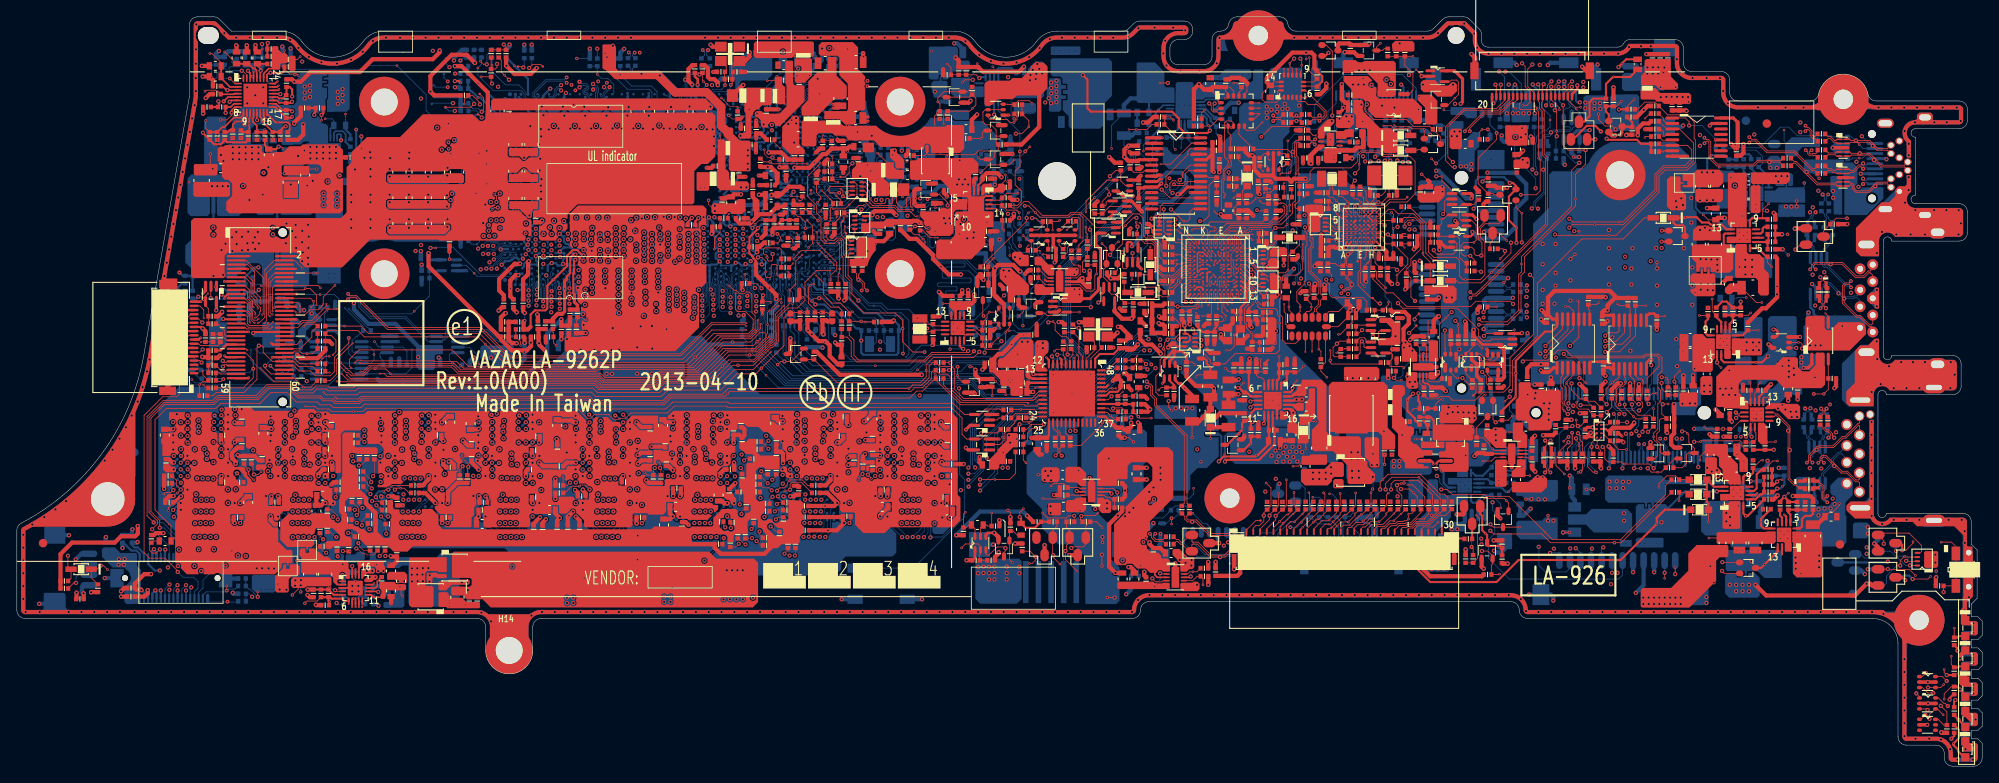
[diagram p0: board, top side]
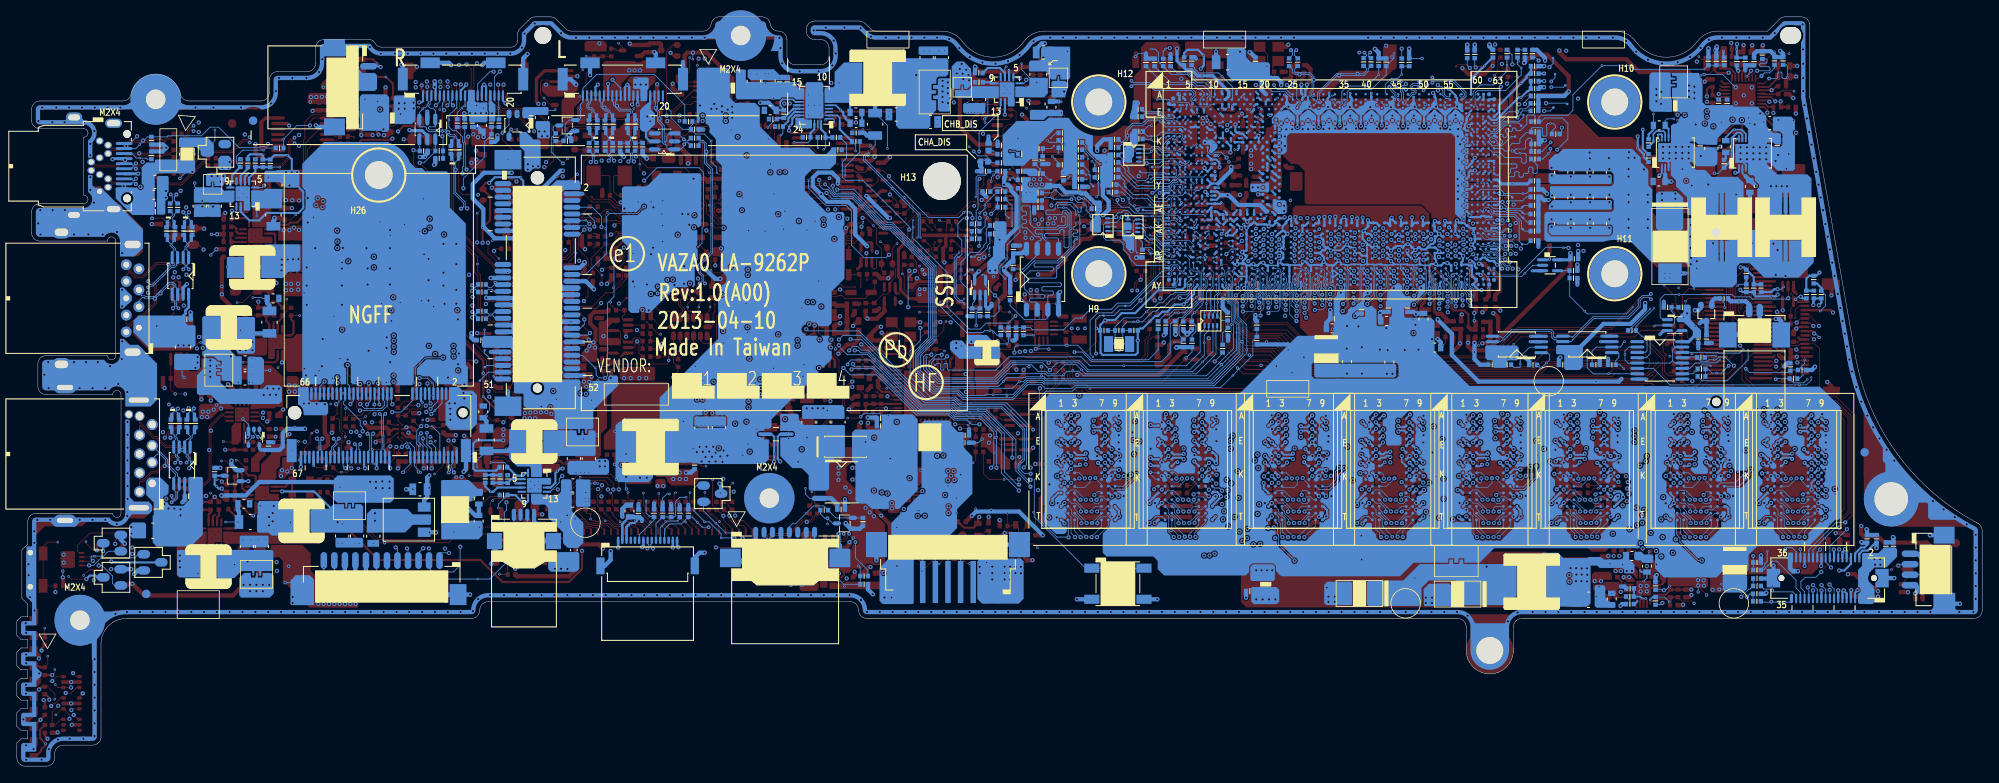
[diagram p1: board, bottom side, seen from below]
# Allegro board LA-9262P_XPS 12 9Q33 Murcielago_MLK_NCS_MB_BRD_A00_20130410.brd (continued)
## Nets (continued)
GND: C265.2 C276.2 C277.2 C278.2 C279.2 C280.1 C281.1 C283.2 C285.2 C293.2 C303.2 C352.2 C355.2 C612.2 C617.2 C655.2 C656.2 C712.2 C713.2 C715.2 C716.2 C719.2 C720.2 C721.2 C722.2 C962.2 C963.2 C965.2 C966.2 C968.2 C969.2 C970.2 C974.2 C976.2 C977.2 C978.2 C979.2 C1059.2 C1078.2 C1098.1 C1099.1 C1100.1 C1101.1 C1102.1 C1109.2 C1110.2 C1116.1 C1117.2 C1118.2 C1122.2 C1123.2 C1124.2 C1125.2 C1134.2 C1135.2 C1136.2 C1137.2 C1138.2 C1139.2 C1140.2 C1142.2 C1143.2 C1145.2 C1146.1 C1148.2 C1149.2 C1152.2 C1153.2 C1158.2 C1159.2 C1160.2 C1161.2 C1162.2 C1163.2 C1172.2 C1173.2 C1174.2 C1175.2 C1176.2 C1177.2 C1178.2 C1179.2 C1180.2 C1181.2 C1182.2 C1183.2 C1184.2 C1185.2 C1186.2 C1187.2 C1188.2 C1189.2 C1190.2 C1191.2 C1192.2 C1193.2 C1194.2 C1195.2 C1196.2 C1197.2 C1199.2 C1200.2 C1202.2 C1203.2 C1204.2 C1205.2 C1209.2 C1212.2 C1213.2 C1214.2 C1215.2 C1219.2 C1225.2 C1227.2 C1228.2 C1230.2 C1231.2 C1237.2 C1240.2 C1241.2 C1242.2 C1243.2 C1246.2 C1248.2 C1254.2 C1256.2 C1257.2 C1259.2 C1260.2 C1261.2 C1262.2 C1278.2 C1279.2 C1280.1 C1281.2 C1282.2 C1283.2 C1284.2 C1285.2 C1286.2 C1287.2 C1288.2 C1289.2 C1292.2 C1294.2 C1295.2 C1296.2 C1297.2 C1298.2 C1299.2 C1300.2 CA1.2 CA2.2 CA3.2 CA4.2 CA5.2 CA6.2 CA7.2 CA9.2 CA11.2 CA12.2 CA14.2 CA15.2 CA16.2 CA17.2 CA21.2 CA22.2 CC160.2 CC161.2 CC162.2 CC163.2 CC164.2 CC165.2 CC233.2 CC234.2 CC238.2 CC239.2 CC240.2 CD1.2 CD2.2 CD3.1 CD4.1 CD5.2 CD14.2 CD15.2 CD16.2 CD17.2 CD18.2 CD19.2 CD20.2 CD21.2 CD22.2 CD23.2 CD24.2 CD25.2 CD26.1 CD27.1 CD28.2 CD37.2 CD38.2 CD39.2 CD40.2 CD41.2 CD42.2 CD43.2 CD44.2 CD45.2 CD46.2 CD47.1 CD48.1 CD49.2 CD58.2 CD59.2 CD60.2 CD61.2 CD62.2 CD63.2 CD64.2 CD65.2 CD66.2 CD67.2 CD68.2 CD69.2 CD70.1 CD71.1 CD72.2 CD81.2 CD82.2 CD83.2 CD84.2 CD85.2 CD86.2 CD87.2 CD88.2 CD90.2 CD93.2 CD94.2 CD95.2 CD96.2 CD97.2 CD98.2 CD101.2 CD102.2 CD103.2 CD104.2 CD105.2 CD106.2 CD107.2 CD110.2 CD111.2 CD112.2 CD113.2 CD114.2 CD115.2 CD116.2 CD117.2 CD118.2 CD119.2 CD120.2 CD121.2 CD122.2 CD123.2 CD124.2 CD125.2 CD126.2 CH1.2 CH2.2 CH3.2 CH4.1 CH5.2 CH6.2 CH23.2 CH24.2 CH39.2 CH40.2 CH41.2 CH47.2 CH82.2 CH83.2 CH84.2 CH85.2 CH95.2 CH1202.2 CH1203.2 CH1204.2 CH1205.2 CH1206.2 CH1207.2 CH1208.2 CH1209.2 CH1210.2 CH1211.2 CH1212.2 CH1213.2 CH1214.2 CH1215.2 CH1216.2 CH1217.2 CH1218.2 CH1220.2 CH1222.2 CH1223.2 CH1224.2 CH1225.2 CH1226.2 CH1227.2 CH1228.2 CH1229.2 CH1230.2 CH1231.2 CH1232.2 CH1233.2 CH1234.2 CH1235.2 CH1236.2 CH1239.2 CH1240.2 CH1241.2 CLRP1.1 CLRP2.2 CLRP3.2 CV1.2 CV2.2 CV13.2 CV14.2 CV15.2 DE1.1 DE2.1 H1.1(TP-1) H3.1(TP-1) H5.1(TP-1) H6.1(TP-1) H8.1(TP-1) H9.1(TP-1) H10.1(TP-1) H11.1(TP-1) H12.1(TP-1) H14.1(TP-1) H26.1(TP-1) JAPS.5 JAPS.7 JAPS.9 JAPS.11 JAPS.19 JAPS.20 JBATT1.1 JBATT1.2 JBATT1.10 JBATT1.11 JBL1.5 JBL1.6 JBT1.2 JBT1.3 JBT1.4 JDCIN1.6 JDCIN1.7 JDEBUG.8 JDEBUG.10 JDEBUG.13 JDEBUG.14 JFAN1.1 JFAN1.5 JFAN1.6 JIOL1.9 JIOL1.10 JIOL1.11 JIOL1.12 JIOL1.13 JIOL1.16 JIOL1.21 JIOL1.22 JIOL1.30 JIOL1.36 JIOL1.37 JIOL1.38 JKB1.30 JKB1.31 JKB1.32 JLVDS1.4 JLVDS1.7 JLVDS1.11 JLVDS1.12 JLVDS1.21 JLVDS1.22 JLVDS1.23 JLVDS1.24 JLVDS2.1 JLVDS2.15 JLVDS2.16 JLVDS2.20 JLVDS2.21 JLVDS2.22 JLVDS2.23 JLVDS2.24 JMDP1.1 JMDP1.7 JMDP1.8 JMDP1.13 JMDP1.14 JMDP1.19 JMDP1.21 JMDP1.22 JMDP1.23 JMDP1.24 JNFC1.1 JNFC1.7 JNFC1.14 JNFC1.16 JNFC1.17 JNGFF1.1 JNGFF1.7 JNGFF1.18 JNGFF1.25 JNGFF1.31 JNGFF1.37 JNGFF1.43 JNGFF1.49 JNGFF1.55 JNGFF1.61 JNGFF1.67 JNGFF1.68 JNGFF1.69 JSATA1.4 JSATA1.9 JSATA1.15 JSATA1.18 JSATA1.21 JSATA1.26 JSATA1.27 JSATA1.29 JSATA1.34 JSATA1.35 JSATA1.37 JSATA1.40 JSATA1.43 JSATA1.50 JSATA1.53 JSATA1.54 JSNRDG.20 JSNRDG.21 JSNRDG.22 JTP1.4 JTP1.9 JTP1.10 JUSB1.4 JUSB1.7 JUSB1.11 JUSB1.12 JUSB1.13 JUSB1.14 JUSB2.4 JUSB2.7 JUSB2.10 JUSB2.11 JUSB2.12 JUSB2.13 JXDP.1 JXDP.2 JXDP.7 JXDP.8 JXDP.13 JXDP.14 JXDP.19 JXDP.20 JXDP.25 JXDP.26 JXDP.31 JXDP.32 JXDP.37 JXDP.38 JXDP.49 JXDP.50 JXDP.59 L44.1 LED1.1 LED2.1 LED3.1 LED4.1 LED5.1 MC94.2 MC102.1 MC103.2 MC118.1 MC284.2 MC654.2 MC1133.2 MC1141.2 MC1151.2 MC1210.2 MC1267.2 MC1268.2 MC1269.2 MC1270.2 MC1271.2 MC1272.2 MC1273.2 MC1274.2 MC1275.2 MC1276.2 MC1277.2 MC1297.2 MD1.3 MD2.3 MD50.2 MD74.7 MD82.7 MD90.2 PC101.2 PC102.2 PC103.2 PC104.2 PC105.2 PC106.2 PC107.2 PC108.2 PC109.2 PC112.2 PC113.2 PC116.2 PC202.2 PC203.2 PC204.2 PC205.2 PC206.2 PC210.1 PC212.2 PC213.2 PC214.2 PC216.2 PC217.2 PC219.2 PC220.1 PC221.2 PC223.2 PC224.2 PC225.2 PC228.2 PC302.2 PC303.2 PC305.2 PC306.2 PC307.2 PC308.2 PC310.2 PC311.2 PC313.2 PC314.2 PC315.2 PC316.2 PC318.2 PC319.2 PC321.2 PC322.2 PC323.2 PC324.2 PC326.2 PC327.2 PC329.2 PC330.2 PC331.2 PC332.2 PC334.2 PC335.2 PC337.2 PC338.2 PC339.2 PC340.2 PC341.2 PC342.2 PC403.2 PC405.2 PC407.2 PC408.2 PC410.2 PC411.2 PC413.2 PC414.2 PC415.2 PC416.2 PC501.2 PC502.2 PC504.2 PC505.2 PC506.2 PC507.2 PC508.2 PC509.2 PC510.2 PC511.2 PC512.2 PC513.2 PC602.2 PC603.2 PC604.2 PC606.2 PC607.2 PC608.2 PC609.2 PC610.2 PC611.2 PC612.2 PC613.2 PC615.2 PC616.2 PC701.2 PC702.2 PC703.2 PC704.2 PC705.2 PC707.1 PC709.2 PC710.2 PC712.2 PC713.2 PC715.1 PC717.1 PC718.2 PC720.1 PC721.2 PC722.2 PC723.2 PC801.2 PC802.2 PC803.2 PC804.2 PC805.2 PC806.2 PC807.2 PC808.2 PC809.2 PC810.2 PC811.2 PC812.2 PC813.2 PC814.2 PC815.2 PC816.2 PC817.2 PC818.2 PC819.2 PC820.2 PC821.2 PC822.2 PC823.2 PC824.2 PC825.2 PC826.2 PC827.2 PC828.2 PC829.2 PC830.2 PD103.1 PD104.1 PL104.1 PQ102.3 PQ103.1 PQ103.4 PQ104.3 PQ105.1 PQ105.4 PQ106.3 PQ202.3 PQ204.3 PQ205.1 PQ205.2 PQ205.3 PQ300.3 PQ602.1 PQ602.2 PQ602.3 PR106.1 PR108.2 PR115.2 PR118.1 PR121.1 PR124.2 PR125.1 PR213.2 PR225.1 PR226.2 PR301.2 PR307.2 PR317.2 PR327.2 PR337.2 PR408.2 PR420.2 PR508.1 PR610.2 PR709.1 PR710.1 PR711.1 PR712.1 PR713.1 PR714.1 PR721.2 PU201.14 PU201.21 PU301.6 PU301.15 PU301.16 PU301.17 PU302.6 PU302.15 PU302.16 PU302.17 PU303.6 PU303.15 PU303.16 PU303.17 PU304.6 PU304.15 PU304.16 PU304.17 PU305.6 PU305.15 PU305.16 PU305.17 PU306.1 PU307.3 PU401.6 PU401.15 PU401.16 PU401.17 PU402.6 PU402.15 PU402.16 PU402.17 PU501.10 PU501.11 PU501.12 PU501.13 PU501.14 PU501.19 PU501.23 PU501.24 PU501.25 PU501.29 PU601.1 PU601.3 PU601.14 PU601.21 PU701.22 PU701.29 PU701.33 PU702.3 PU702.9 PU703.3 PU703.9 Q4.3 Q5.3 Q34.3 Q39.3 Q71.3 Q305.3 Q311.3 Q349.1 Q349.4 Q361.1 Q362.3 R225.1 R537.2 R540.2 R545.2 R607.1 R608.1 R819.1 R924.1 R928.2 R929.1 R941.1 R945.1 R974.2 R1026.2 R1027.2 R1032.1 R1034.1 R1088.2 R1099.1 R1100.1 R1117.2 R1118.2 R1139.2 R1140.2 R1141.2 R1142.2 R1160.2 R1161.2 R1162.2 R1164.2 R1169.2 R1187.2 R1197.2 R1203.2 R1206.1 R1207.2 R1217.1 R1228.2 R1250.2 R1253.2 R1287.2 R1310.2 R1325.1 R1338.2 R1376.2 R1388.2 R1394.2 R1395.1 RA11.1 RA12.1 RA13.1 RC44.1 RC52.2 RC54.2 RC55.2 RC58.2 RC60.2 RC81.2 RC100.2 RC138.2 RC153.2 RC154.2 RC155.2 RC156.2 RC158.1 RC160.2 RC161.2 RD1.2 RD2.2 RD3.1 RD4.1 RD5.2 RD6.2 RD7.2 RD8.2 RD9.1 RD11.2 RD12.2 RD15.2 RD16.2 RD21.2 RD22.2 RD23.2 RD24.2 RD79.2 RD80.2 RD81.2 RD82.2 RD83.2 RD84.2 RD85.2 RD86.2 RH32.2 RH34.1 RH53.1 RH76.2 RH77.2 RH78.2 RH79.2 RH123.1 RH151.1 RH158.1 RH159.1 RH163.2 RH171.2 RH183.1 RH186.1 RH272.2 RH300.1 RH314.1 RH315.1 RH316.1 RH337.2 RH394.2 RH401.2 RH423.2 RH435.2 RH442.2 RH443.2 RP21.7 RP21.8 RP22.8 RV3.2 RV4.2 RV9.2 RV10.2 SW1.2 SW1.4 SW2.3 SW2.4 U34.G2 U34.J8 U34.J9 U34.J10 U34.N13 U48.4 U635.3 U636.A7 U636.B1 U636.E7 U636.F5 U636.H2 U636.H3 U637.7 U637.10 U637.11 U638.8 U638.9 U638.10 U638.11 U638.12 U638.13 U652.1 U652.2 U652.3 U652.4 U652.8 U652.9 U652.11 U652.18 U652.25 U653.5 U653.10 U653.12 U653.13 U653.16 U663.8 U664.11 U664.15 U671.7 U672.3 U673.3 U675.3 U676.3 U677.7 U679.B1 U682.3 U687.3 U688.2 U689.3 U690.3 U691.3 U697.3 U698.3 U699.3 U708.3 U709.3 U710.3 U712.3 U713.3 U714.3 U714.17 U716.11 U716.15 U717.11 U717.15 U718.11 U718.15 U719.11 U719.15 U721.2 U722.5 U722.9 UA1.44 UA1.49 UA2.3 UA3.3 UC1.3 UCPU1.A11 UCPU1.A14 UCPU1.A18 UCPU1.A24 UCPU1.A28 UCPU1.A32 UCPU1.A36 UCPU1.A40 UCPU1.A44 UCPU1.A48 UCPU1.A52 UCPU1.A56 UCPU1.AA1 UCPU1.AA58 UCPU1.AB7 UCPU1.AB10 UCPU1.AB20 UCPU1.AB22 UCPU1.AC61 UCPU1.AD3 UCPU1.AD21 UCPU1.AD63 UCPU1.AE5 UCPU1.AE10 UCPU1.AE58 UCPU1.AF11 UCPU1.AF12 UCPU1.AF14 UCPU1.AF15 UCPU1.AF17 UCPU1.AF18 UCPU1.AG1 UCPU1.AG11 UCPU1.AG21 UCPU1.AG23 UCPU1.AG60 UCPU1.AG61 UCPU1.AG62 UCPU1.AG63 UCPU1.AH16 UCPU1.AH17 UCPU1.AH19 UCPU1.AH20 UCPU1.AH22 UCPU1.AH24 UCPU1.AH28 UCPU1.AH30 UCPU1.AH32 UCPU1.AH34 UCPU1.AH36 UCPU1.AH38 UCPU1.AH40 UCPU1.AH42 UCPU1.AH44 UCPU1.AH46 UCPU1.AH49 UCPU1.AH51 UCPU1.AH53 UCPU1.AH55 UCPU1.AH57 UCPU1.AJ13 UCPU1.AJ14 UCPU1.AJ23 UCPU1.AJ25 UCPU1.AJ27 UCPU1.AJ29 UCPU1.AJ35 UCPU1.AJ39 UCPU1.AJ41 UCPU1.AJ43 UCPU1.AJ45 UCPU1.AJ47 UCPU1.AJ50 UCPU1.AJ52 UCPU1.AJ54 UCPU1.AJ56 UCPU1.AJ58 UCPU1.AJ60 UCPU1.AJ63 UCPU1.AK3 UCPU1.AK23 UCPU1.AK52 UCPU1.AL10 UCPU1.AL13 UCPU1.AL17 UCPU1.AL20 UCPU1.AL22 UCPU1.AL23 UCPU1.AL26 UCPU1.AL29 UCPU1.AL31 UCPU1.AL33 UCPU1.AL36 UCPU1.AL39 UCPU1.AL40 UCPU1.AL45 UCPU1.AL46 UCPU1.AL51 UCPU1.AL52 UCPU1.AL54 UCPU1.AL57 UCPU1.AL60 UCPU1.AL61 UCPU1.AM1 UCPU1.AM17 UCPU1.AM23 UCPU1.AM31 UCPU1.AM52 UCPU1.AN7 UCPU1.AN17 UCPU1.AN23 UCPU1.AN31 UCPU1.AN32 UCPU1.AN35 UCPU1.AN36 UCPU1.AN39 UCPU1.AN40 UCPU1.AN42 UCPU1.AN43 UCPU1.AN45 UCPU1.AN46 UCPU1.AN48 UCPU1.AN49 UCPU1.AN51 UCPU1.AN52 UCPU1.AN60 UCPU1.AN63 UCPU1.AP3 UCPU1.AP10 UCPU1.AP17 UCPU1.AP20 UCPU1.AP22 UCPU1.AP23 UCPU1.AP26 UCPU1.AP29 UCPU1.AP31 UCPU1.AP38 UCPU1.AP39 UCPU1.AP48 UCPU1.AP52 UCPU1.AP54 UCPU1.AP57 UCPU1.AR5 UCPU1.AR11 UCPU1.AR15 UCPU1.AR17 UCPU1.AR23 UCPU1.AR31 UCPU1.AR33 UCPU1.AR39 UCPU1.AR43 UCPU1.AR49 UCPU1.AR52 UCPU1.AT13 UCPU1.AT35 UCPU1.AT37 UCPU1.AT40 UCPU1.AT42 UCPU1.AT43 UCPU1.AT46 UCPU1.AT49 UCPU1.AT61 UCPU1.AT62 UCPU1.AT63 UCPU1.AU1 UCPU1.AU16 UCPU1.AU18 UCPU1.AU20 UCPU1.AU22 UCPU1.AU24 UCPU1.AU26 UCPU1.AU28 UCPU1.AU30 UCPU1.AU33 UCPU1.AU51 UCPU1.AU53 UCPU1.AU55 UCPU1.AU57 UCPU1.AU59 UCPU1.AV8 UCPU1.AV14 UCPU1.AV16 UCPU1.AV20 UCPU1.AV24 UCPU1.AV28 UCPU1.AV33 UCPU1.AV34 UCPU1.AV36 UCPU1.AV39 UCPU1.AV41 UCPU1.AV43 UCPU1.AV46 UCPU1.AV49 UCPU1.AV51 UCPU1.AV55 UCPU1.AV59 UCPU1.AW4 UCPU1.AW16 UCPU1.AW24 UCPU1.AW33 UCPU1.AW35 UCPU1.AW37 UCPU1.AW40 UCPU1.AW42 UCPU1.AW44 UCPU1.AW47 UCPU1.AW50 UCPU1.AW51 UCPU1.AW59 UCPU1.AW60 UCPU1.AY4 UCPU1.AY6 UCPU1.AY11 UCPU1.AY16 UCPU1.AY18 UCPU1.AY22 UCPU1.AY24 UCPU1.AY26 UCPU1.AY30 UCPU1.AY33 UCPU1.AY51 UCPU1.AY53 UCPU1.AY57 UCPU1.AY59 UCPU1.B4 UCPU1.B20 UCPU1.B24 UCPU1.B26 UCPU1.B28 UCPU1.B32 UCPU1.B36 UCPU1.B40 UCPU1.B44 UCPU1.B48 UCPU1.B52 UCPU1.B56 UCPU1.B60 UCPU1.C11 UCPU1.C14 UCPU1.C18 UCPU1.C20 UCPU1.C25 UCPU1.C27 UCPU1.C38 UCPU1.C39 UCPU1.C57 UCPU1.D2 UCPU1.D5 UCPU1.D8 UCPU1.D12 UCPU1.D14 UCPU1.D18 UCPU1.D21 UCPU1.D23 UCPU1.D25 UCPU1.D26 UCPU1.D27 UCPU1.D29 UCPU1.D30 UCPU1.D31 UCPU1.D33 UCPU1.D34 UCPU1.D35 UCPU1.D37 UCPU1.D38 UCPU1.D39 UCPU1.D41 UCPU1.D42 UCPU1.D43 UCPU1.D45 UCPU1.D46 UCPU1.D47 UCPU1.D49 UCPU1.D50 UCPU1.D51 UCPU1.D53 UCPU1.D54 UCPU1.D55 UCPU1.D57 UCPU1.D59 UCPU1.D62 UCPU1.D63 UCPU1.E11 UCPU1.E17 UCPU1.F20 UCPU1.F26 UCPU1.F30 UCPU1.F34 UCPU1.F38 UCPU1.F42 UCPU1.F46 UCPU1.F50 UCPU1.F54 UCPU1.F58 UCPU1.F61 UCPU1.G3 UCPU1.G5 UCPU1.G6 UCPU1.G8 UCPU1.G18 UCPU1.G22 UCPU1.H13 UCPU1.H17 UCPU1.H57 UCPU1.J10 UCPU1.J22 UCPU1.J59 UCPU1.J63 UCPU1.K1 UCPU1.K12 UCPU1.L7 UCPU1.L13 UCPU1.L15 UCPU1.L17 UCPU1.L18 UCPU1.L20 UCPU1.L58 UCPU1.L61 UCPU1.M22 UCPU1.N3 UCPU1.N10 UCPU1.N21 UCPU1.P22 UCPU1.P59 UCPU1.P62 UCPU1.P63 UCPU1.R8 UCPU1.R10 UCPU1.R22 UCPU1.T1 UCPU1.T58 UCPU1.U9 UCPU1.U20 UCPU1.U22 UCPU1.U61 UCPU1.V3 UCPU1.V7 UCPU1.V10 UCPU1.V23 UCPU1.V58 UCPU1.W20 UCPU1.W22 UCPU1.Y10 UCPU1.Y59 UCPU1.Y63 UD1.A9 UD1.B1 UD1.B3 UD1.B9 UD1.D1 UD1.D3 UD1.D8 UD1.E1 UD1.E2 UD1.E7 UD1.E8 UD1.F9 UD1.G1 UD1.G8 UD1.G9 UD1.J2 UD1.J8 UD1.M1 UD1.M9 UD1.P1 UD1.P9 UD1.T1 UD1.T9 UD2.A9 UD2.B1 UD2.B3 UD2.B9 UD2.D1 UD2.D3 UD2.D8 UD2.E1 UD2.E2 UD2.E7 UD2.E8 UD2.F9 UD2.G1 UD2.G8 UD2.G9 UD2.J2 UD2.J8 UD2.M1 UD2.M9 UD2.P1 UD2.P9 UD2.T1 UD2.T9 UD3.3 UD3.4 UD4.A9 UD4.B1 UD4.B3 UD4.B9 UD4.D1 UD4.D3 UD4.D8 UD4.E1 UD4.E2 UD4.E7 UD4.E8 UD4.F9 UD4.G1 UD4.G8 UD4.G9 UD4.J2 UD4.J8 UD4.M1 UD4.M9 UD4.P1 UD4.P9 UD4.T1 UD4.T9 UD5.A9 UD5.B1 UD5.B3 UD5.B9 UD5.D1 UD5.D3 UD5.D8 UD5.E1 UD5.E2 UD5.E7 UD5.E8 UD5.F9 UD5.G1 UD5.G8 UD5.G9 UD5.J2 UD5.J8 UD5.M1 UD5.M9 UD5.P1 UD5.P9 UD5.T1 UD5.T9 UD6.A9 UD6.B1 UD6.B3 UD6.B9 UD6.D1 UD6.D3 UD6.D8 UD6.E1 UD6.E2 UD6.E7 UD6.E8 UD6.F9 UD6.G1 UD6.G8 UD6.G9 UD6.J2 UD6.J8 UD6.M1 UD6.M9 UD6.P1 UD6.P9 UD6.T1 UD6.T9 UD7.A9 UD7.B1 UD7.B3 UD7.B9 UD7.D1 UD7.D3 UD7.D8 UD7.E1 UD7.E2 UD7.E7 UD7.E8 UD7.F9 UD7.G1 UD7.G8 UD7.G9 UD7.J2 UD7.J8 UD7.M1 UD7.M9 UD7.P1 UD7.P9 UD7.T1 UD7.T9 UD8.3 UD8.4 UD9.A9 UD9.B1 UD9.B3 UD9.B9 UD9.D1 UD9.D3 UD9.D8 UD9.E1 UD9.E2 UD9.E7 UD9.E8 UD9.F9 UD9.G1 UD9.G8 UD9.G9 UD9.J2 UD9.J8 UD9.M1 UD9.M9 UD9.P1 UD9.P9 UD9.T1 UD9.T9 UD10.A9 UD10.B1 UD10.B3 UD10.B9 UD10.D1 UD10.D3 UD10.D8 UD10.E1 UD10.E2 UD10.E7 UD10.E8 UD10.F9 UD10.G1 UD10.G8 UD10.G9 UD10.J2 UD10.J8 UD10.M1 UD10.M9 UD10.P1 UD10.P9 UD10.T1 UD10.T9 UH5.3 US1.14 US1.17 US2.1 UV1.8 UV1.15 YA1.2 YA1.4 YH2.2 YH2.4
VCC: PC214.1 PR210.2 PU201.20
VCCSENSE: PU701.24 RC98.1
VCCSENSE_R: RC97.2 RC98.2 UCPU1.E63
VCCSTPG_MCP: RC150.2 UCPU1.B59
VDD_+1.2V: PC612.1 PR604.1 PR606.2 PU601.11
VIN: PC103.1 PC104.1 PC208.1 PD201.2 PL101.2 PQ201.1 PR120.2 PR122.1 PR123.2 PR208.1 PR209.1
VSSSENSE: PU701.23 RC99.2
VSSSENSE_R: RC99.1 RC100.1 UCPU1.E62
1.2_PGND: CA8.2 CA10.2 CA18.2 CA19.2 CA20.2 RA11.2 RA12.2 RA13.2 UA1.12
+1.5VS_SS/TR: PC408.1 PU401.9
+1.8VS_SS/TR: PC415.1 PU402.9
+3.3VDX_SSD_SS/TR: PC332.1 PU304.9
+3VALW_DSW_SS/TR: PC340.1 PU305.9
+3VDX_SS/TR: PC324.1 PU303.9
+5VDX_SS/TR: PC316.1 PU302.9
+EC_VCCA: C282.1 L43.2 U34.B11
+EDP_COM: RC36.1 UCPU1.D20
+INV_PWR_SRC: C612.1 JLVDS1.15 JLVDS1.16 Q70.1 Q70.2 Q70.5 Q70.6 R531.2 R541.1
+LCDVDD: C1143.1 C1145.1 C1231.1 JLVDS2.12 JLVDS2.13 R1322.2 U708.5
+LCDVDD_R: D105.1 Q71.2 R1161.1 U708.2
+PCH_VCCDSW: RH346.1 UCPU1.AG19 UCPU1.AG20
+RTC_VCCSUS: CH1207.1 RH341.2 UCPU1.AH11
+RTCBATT: JBT1.1 RTCR1.2
+RTCVCC: CH82.1 CH83.1 CH84.1 CH95.1 CLRP3.1 JIOL1.8 R1348.2 RH11.1 RH23.1 RH25.1 RH31.1 RH147.1 RTCD1.1 UCPU1.AG10
+V5A_SS/TR: PC308.1 PU301.9
+VCHGR: PC223.1 PC224.1 PC225.1 PD204.1 PQ206.1 PQ206.2 PQ206.3 PR216.1
+VREFCA: CD1.1 CD2.1 CD24.1 CD25.1 CD45.1 CD46.1 CD68.1 CD69.1 CD90.1 RD13.2 RD14.2 RD15.1 UD1.M8 UD2.M8 UD4.M8 UD5.M8 UD6.M8 UD7.M8 UD9.M8 UD10.M8
+VREFDQ_A: CD3.2 CD4.2 CD26.2 CD27.2 RD17.2 RD19.2 RD21.1 UD1.H1 UD2.H1 UD4.H1 UD5.H1
+VREFDQ_B: CD47.2 CD48.2 CD70.2 CD71.2 RD18.2 RD20.2 RD22.1 UD6.H1 UD7.H1 UD9.H1 UD10.H1
+VS_LPSS_SDIO: CH1227.1 RH350.1 RH354.1 RH434.1 UCPU1.T9 UCPU1.U8
/BATDRV: PR230.1 PU201.11
AC_PRESENT: RH12.1 RH137.2 U34.E5
AC_PRESENT_R: RH137.1 UCPU1.AJ8
ACCEL_INT1: D94.2 R1207.1 U637.5
ACCEL_INT2: R1088.1 U636.E4 U637.4
ACDET: PC216.1 PR208.2 PR213.1 PU201.6
ACDRV: PR206.2 PU201.4
ACIN: C1116.2 PR119.1 PR223.2 PR226.1 PU201.5 R924.2 U34.F5 U689.1
ACOFF: PQ202.2 RP22.1 U34.A9
AD_BID0: C283.1 R219.1 R225.2 U34.A12
ADP_I: PC220.2 PR116.2 PU201.7 U34.B12
ADPIN: JDCIN1.2 JDCIN1.3 PC101.1 PC102.1 PC109.1 PL101.1
ALL_SYS_PCH_PWROK_EC: R1292.1 U691.4
ALS_INT#: JLVDS2.9 R1115.1 R1116.1
ALS_INT#_EC: R1115.2 RP22.2 U34.E7
ALS_INT#_HUB: R1116.2 R1143.1 U636.E6
ALS_SMBCLK: JLVDS2.7 R983.2 R985.1
ALS_SMBDATA: JLVDS2.8 R984.2 R986.1
AOAC_THERMAL: R927.2 R928.1 U34.D7
APWROK_R: RH131.1 RH438.1 UCPU1.AB5
AUD_MUTE#: JIOL1.17 U34.N12
AUDIO_IRQ#: RH396.2 UCPU1.L4
AUDIO_PWREN: PD305.2 R1140.1 R1182.1 T279.1(TP-1) U664.3 U664.5 U717.5 UCPU1.P1
AUDIO_XTAL24_IN: CA17.1 UA1.2 YA1.3
AUDIO_XTAL24_OUT: CA16.1 UA1.3 YA1.1
B+: C613.1 MC1273.1 MC1274.1 MC1275.1 PC217.1 PC219.1 PC342.1 PJP401.1 PJP403.1 PJP701.1 PL203.1 PL302.1 PL304.1 PL306.1 PL308.1 PL310.1 PL501.1 PL601.1 PL703.1 PR216.4 PU306.2 Q70.4 Q361.4 R531.1 R535.1 R1381.1
B-RAMP: PR704.1 PR711.2 PU701.11
BATBTN#: C1122.1 D84.1 RP16.3 SW1.1 SW1.3 U34.G4
BATMAN_CLK: Q359.6 R1347.1 R1350.1 U714.7
BATMAN_DATA: Q359.3 R1346.1 R1351.1 U714.6
BATMAN_X1: C1295.1 U714.14 Y3.1
BATMAN_X2: C1296.1 U714.15 Y3.2
BATT+: PC105.1 PC106.1 PD204.2 PL103.1 PQ206.5 PQ206.6 PQ206.7 PQ206.8
BATT++: JBATT1.8 JBATT1.9 PC107.1 PC108.1 PL103.2
BATT_LED#_LV1: Q316.1 U34.B10
BATT_LED#_LV1_Q: Q316.6 Q354.2 RP14.8
BATT_LED#_LV2: Q316.4 U34.B9
BATT_LED#_LV2_Q: Q316.3 Q355.2 RP14.7
BATT_LED#_LV3: Q318.1 U34.K2
BATT_LED#_LV3_Q: Q318.6 Q356.2 RP14.6
BATT_LED#_LV4: Q318.4 U34.J2
BATT_LED#_LV4_Q: Q318.3 Q357.2 RP14.5
BATT_LED#_LV5: Q320.1 U34.N8
BATT_LED_COLOR_W: JIOL1.25 U34.A4
BATT_LED_CTRL#: JIOL1.23 U34.A3
BATT_LED_LV1: Q354.1 R910.2
BATT_LED_LV2: Q355.1 R911.2
BATT_LED_LV3: Q356.1 R912.2
BATT_LED_LV4: Q357.1 R913.2
BATT_LED_LV5: Q358.1 R916.2
BATT_PRS: JBATT1.5 PD104.2 PR112.1
BEEP#: JIOL1.15 U34.M8
BKOFF#: D72.3 D73.2 U34.E1
BOOT0: R819.2 R1092.1 U636.A6
BOOT_+1.2V: PR601.2 PU601.18
BST_+1.05VS: PR506.1 PU501.5
BT_CS_NOTICE: R1208.2 R1209.2 UCPU1.AP1
BT_PCMCLK: JNGFF1.8 U677.2
BT_PCMFR1: JNGFF1.10 U677.3
BT_PCMIN: JNGFF1.12 U677.5
BT_PCMOUT: JNGFF1.14 U677.4
BT_RADIO_DIS#: JNGFF1.46 RH188.1 UCPU1.R7
BTST: PR211.1 PU201.17
CAB_DET_SINK: JMDP1.4 RV8.2 RV9.1
CAPS_LED: JKB1.27 R943.2
CAPS_LED#: Q326.3 R990.1 U34.B3
CFG0: JXDP.9 UCPU1.AC60
CFG1: JXDP.11 UCPU1.AC62
CFG2: JXDP.15 UCPU1.AC63
CFG3: JXDP.17 R1198.2 T293.1(TP-1) UCPU1.AA63
CFG4: JXDP.27 RC81.1 UCPU1.AA60
CFG5: JXDP.29 UCPU1.Y62
CFG6: JXDP.33 UCPU1.Y61
CFG7: JXDP.35 UCPU1.Y60
CFG8: JXDP.10 UCPU1.V62
CFG9: JXDP.12 UCPU1.V61
CFG10: JXDP.16 UCPU1.V60
CFG11: JXDP.18 UCPU1.U60
CFG12: JXDP.28 UCPU1.T63
CFG13: JXDP.30 UCPU1.T62
CFG14: JXDP.34 UCPU1.T61
CFG15: JXDP.36 UCPU1.T60
CFG16: JXDP.6 UCPU1.AA62
CFG17: JXDP.4 UCPU1.AA61
CFG18: JXDP.24 UCPU1.U63
CFG19: JXDP.22 UCPU1.U62
CFG_RCOMP: RC153.1 UCPU1.V63
CHG_LGATE: PQ205.4 PU201.15
CHG_LX: PC218.2 PL203.2 PQ203.1 PQ203.2 PQ203.3 PQ205.5 PR220.2 PU201.19
CHG_UGATE: PQ203.4 PU201.18
CL_CK: R1212.2 UCPU1.AF2
CL_DAT: R1210.2 UCPU1.AD2
CL_RST#: R1200.2 UCPU1.AF4
CLK_LPC_DEBUG: JDEBUG.7 RH386.2
CLK_PCI_LPC: MR226.1 RH360.2 U34.N5
CLK_PCI_TPM: MR976.1 RH428.2 U652.21
CLK_PCIE2: JNGFF1.39 UCPU1.B42
CLK_PCIE2#: JNGFF1.41 UCPU1.C41
CLK_REQ2#: JNGFF1.45 Q346.3 RH410.1
CLK_SMB: JBATT1.7 PD103.2 PR109.1
CLKOUT_LPC0: RH360.1 RH428.1 UCPU1.AN15
CLKOUT_LPC1: RH386.1 UCPU1.AP15
CMSRC: PR203.2 PU201.3
COMP: PC714.2 PC724.2 PR726.1 PR727.2 PU701.26
CONSOLE_RX: JSNRDG.14 T261.1(TP-1) U636.D3
CONSOLE_TX: JSNRDG.15 T260.1(TP-1) U636.D2
CPU_B+: PC701.1 PC702.1 PC703.1 PC704.1 PC705.1 PC710.1 PC718.1 PJP701.2 PL703.2 PR717.1 PU702.5 PU703.5
CPU_EDP_HPD#: QC5.3 RC148.2 RC160.1 UCPU1.D6
CPU_PATH_EN: R1324.2 R1325.2 U697.2
CPU_PATH_EN_G: U663.2 U663.5 U663.12 U663.15 U697.4
CPU_XDP_TCK: RC52.1 RH446.1 T265.1(TP-1) UCPU1.E60
CPU_XDP_TDI: RC46.1 T268.1(TP-1) U663.11 UCPU1.F63
CPU_XDP_TDO: RC48.1 T269.1(TP-1) U663.6 UCPU1.F62
CPU_XDP_TMS: RC45.1 T266.1(TP-1) U663.14 UCPU1.E61
CPU_XDP_TRST#: RC54.1 RH370.2 T267.1(TP-1) U663.3 UCPU1.E59
CS_+1.2V: PR604.2 PU601.13
CSN1: PC708.1 PL701.3 PR707.2 PR708.2 PU701.18
CSN2: PC716.1 PL702.3 PR728.2 PR729.2 PU701.19
CSP1: PC708.2 PH702.1 PR702.1 PR707.1 PU701.17
CSP2: PC716.2 PH703.1 PR724.1 PR728.1 PR746.2 PU701.20
CSSN_1: PC211.2 PC212.1 PR201.2 PU201.1
CSSP_1: PC210.2 PC211.1 PR201.3 PU201.2
DAT_SMB: JBATT1.6 PD103.3 PR111.1
DC_TEST_A3_B3: UCPU1.A3 UCPU1.B3
DC_TEST_A61_B61: UCPU1.A61 UCPU1.B61
DC_TEST_AY2_AW2: UCPU1.AW2 UCPU1.AY2
DC_TEST_AY3_AW3: UCPU1.AW3 UCPU1.AY3
DC_TEST_AY61_AW61: UCPU1.AW61 UCPU1.AY61
DC_TEST_AY62_AW62: UCPU1.AW62 UCPU1.AY62
DC_TEST_B62_B63: UCPU1.B62 UCPU1.B63
DC_TEST_C1_C2: UCPU1.C1 UCPU1.C2
DCIN_GND: JDCIN1.4 JDCIN1.5 PL104.2
DDR3_DRAMRST#: CD5.1 CD28.1 CD49.1 CD72.1 RC75.2 RC162.2 UD1.T2 UD2.T2 UD4.T2 UD5.T2 UD6.T2 UD7.T2 UD9.T2 UD10.T2
DDR_A_BS0: RD67.1 UCPU1.AU35 UD1.M2 UD2.M2 UD4.M2 UD5.M2
DDR_A_BS1: RD71.1 UCPU1.AV35 UD1.N8 UD2.N8 UD4.N8 UD5.N8
DDR_A_BS2: RD69.1 UCPU1.AY41 UD1.M3 UD2.M3 UD4.M3 UD5.M3
DDR_A_CAS#: RD63.1 UCPU1.AU34 UD1.K3 UD2.K3 UD4.K3 UD5.K3
DDR_A_CKE0: RD57.1 UCPU1.AU43 UD1.K9 UD2.K9 UD4.K9 UD5.K9
DDR_A_CKE1: RD87.1 UCPU1.AW43 UD1.J9 UD2.J9 UD4.J9 UD5.J9
DDR_A_CS0#: RD61.1 UCPU1.AP33 UD1.L2 UD2.L2 UD4.L2 UD5.L2
DDR_A_CS1#: RD88.1 UCPU1.AR32 UD1.L1 UD2.L1 UD4.L1 UD5.L1
DDR_A_D0: UCPU1.AH63 UD1.F7
DDR_A_D1: UCPU1.AH62 UD1.H7
DDR_A_D2: UCPU1.AK63 UD1.F2
DDR_A_D3: UCPU1.AK62 UD1.H3
DDR_A_D4: UCPU1.AH61 UD1.H8
DDR_A_D5: UCPU1.AH60 UD1.F8
DDR_A_D6: UCPU1.AK61 UD1.E3
DDR_A_D7: UCPU1.AK60 UD1.G2
DDR_A_D8: UCPU1.AM63 UD1.A7
DDR_A_D9: UCPU1.AM62 UD1.B8
DDR_A_D10: UCPU1.AP63 UD1.A3
DDR_A_D11: UCPU1.AP62 UD1.A2
DDR_A_D12: UCPU1.AM61 UD1.C8
DDR_A_D13: UCPU1.AM60 UD1.D7
DDR_A_D14: UCPU1.AP61 UD1.C2
DDR_A_D15: UCPU1.AP60 UD1.C3
DDR_A_D16: UCPU1.AP58 UD2.F7
DDR_A_D17: UCPU1.AR58 UD2.H7
DDR_A_D18: UCPU1.AM57 UD2.E3
DDR_A_D19: UCPU1.AK57 UD2.H3
DDR_A_D20: UCPU1.AL58 UD2.H8
DDR_A_D21: UCPU1.AK58 UD2.F8
DDR_A_D22: UCPU1.AR57 UD2.F2
DDR_A_D23: UCPU1.AN57 UD2.G2
DDR_A_D24: UCPU1.AP55 UD2.A7
DDR_A_D25: UCPU1.AR55 UD2.B8
DDR_A_D26: UCPU1.AM54 UD2.C2
DDR_A_D27: UCPU1.AK54 UD2.C3
DDR_A_D28: UCPU1.AL55 UD2.C8
DDR_A_D29: UCPU1.AK55 UD2.D7
DDR_A_D30: UCPU1.AR54 UD2.A3
DDR_A_D31: UCPU1.AN54 UD2.A2
DDR_A_D32: UCPU1.AY58 UD4.F8
DDR_A_D33: UCPU1.AW58 UD4.H8
DDR_A_D34: UCPU1.AY56 UD4.F2
DDR_A_D35: UCPU1.AW56 UD4.H3
DDR_A_D36: UCPU1.AV58 UD4.H7
DDR_A_D37: UCPU1.AU58 UD4.F7
DDR_A_D38: UCPU1.AV56 UD4.G2
DDR_A_D39: UCPU1.AU56 UD4.E3
DDR_A_D40: UCPU1.AY54 UD4.B8
DDR_A_D41: UCPU1.AW54 UD4.A7
DDR_A_D42: UCPU1.AY52 UD4.A2
DDR_A_D43: UCPU1.AW52 UD4.A3
DDR_A_D44: UCPU1.AV54 UD4.D7
DDR_A_D45: UCPU1.AU54 UD4.C8
DDR_A_D46: UCPU1.AV52 UD4.C2
DDR_A_D47: UCPU1.AU52 UD4.C3
DDR_A_D48: UCPU1.AK40 UD5.G2
DDR_A_D49: UCPU1.AK42 UD5.H3
DDR_A_D50: UCPU1.AM43 UD5.H7
DDR_A_D51: UCPU1.AM45 UD5.F8
DDR_A_D52: UCPU1.AK45 UD5.H8
DDR_A_D53: UCPU1.AK43 UD5.F7
DDR_A_D54: UCPU1.AM40 UD5.F2
DDR_A_D55: UCPU1.AM42 UD5.E3
DDR_A_D56: UCPU1.AM46 UD5.C2
DDR_A_D57: UCPU1.AK46 UD5.C3
DDR_A_D58: UCPU1.AM49 UD5.B8
DDR_A_D59: UCPU1.AK49 UD5.A7
DDR_A_D60: UCPU1.AM48 UD5.A3
DDR_A_D61: UCPU1.AK48 UD5.A2
DDR_A_D62: UCPU1.AM51 UD5.D7
DDR_A_D63: UCPU1.AK51 UD5.C8
DDR_A_DQS0: UCPU1.AJ62 UD1.F3
DDR_A_DQS1: UCPU1.AN61 UD1.C7
DDR_A_DQS2: UCPU1.AN58 UD2.F3
DDR_A_DQS3: UCPU1.AN55 UD2.C7
DDR_A_DQS4: UCPU1.AW57 UD4.F3
DDR_A_DQS5: UCPU1.AW53 UD4.C7
DDR_A_DQS6: UCPU1.AL42 UD5.F3
DDR_A_DQS7: UCPU1.AL49 UD5.C7
DDR_A_DQS#0: UCPU1.AJ61 UD1.G3
DDR_A_DQS#1: UCPU1.AN62 UD1.B7
DDR_A_DQS#2: UCPU1.AM58 UD2.G3
DDR_A_DQS#3: UCPU1.AM55 UD2.B7
DDR_A_DQS#4: UCPU1.AV57 UD4.G3
DDR_A_DQS#5: UCPU1.AV53 UD4.B7
DDR_A_DQS#6: UCPU1.AL43 UD5.G3
DDR_A_DQS#7: UCPU1.AL48 UD5.B7
DDR_A_MA0: RD29.1 UCPU1.AU36 UD1.N3 UD2.N3 UD4.N3 UD5.N3
DDR_A_MA1: RD37.1 UCPU1.AY37 UD1.P7 UD2.P7 UD4.P7 UD5.P7
DDR_A_MA2: RD35.1 UCPU1.AR38 UD1.P3 UD2.P3 UD4.P3 UD5.P3
DDR_A_MA3: RD41.1 UCPU1.AP36 UD1.N2 UD2.N2 UD4.N2 UD5.N2
DDR_A_MA4: RD33.1 UCPU1.AU39 UD1.P8 UD2.P8 UD4.P8 UD5.P8
DDR_A_MA5: RD47.1 UCPU1.AR36 UD1.P2 UD2.P2 UD4.P2 UD5.P2
DDR_A_MA6: RD39.1 UCPU1.AV40 UD1.R8 UD2.R8 UD4.R8 UD5.R8
DDR_A_MA7: RD51.1 UCPU1.AW39 UD1.R2 UD2.R2 UD4.R2 UD5.R2
DDR_A_MA8: RD53.1 UCPU1.AY39 UD1.T8 UD2.T8 UD4.T8 UD5.T8
DDR_A_MA9: RD43.1 UCPU1.AU40 UD1.R3 UD2.R3 UD4.R3 UD5.R3
DDR_A_MA10: RD31.1 UCPU1.AP35 UD1.L7 UD2.L7 UD4.L7 UD5.L7
DDR_A_MA11: RD45.1 UCPU1.AW41 UD1.R7 UD2.R7 UD4.R7 UD5.R7
DDR_A_MA12: RD25.1 UCPU1.AU41 UD1.N7 UD2.N7 UD4.N7 UD5.N7
DDR_A_MA13: RD55.1 UCPU1.AR35 UD1.T3 UD2.T3 UD4.T3 UD5.T3
DDR_A_MA14: RD49.1 UCPU1.AV42 UD1.T7 UD2.T7 UD4.T7 UD5.T7
DDR_A_MA15: RD27.1 UCPU1.AU42 UD1.M7 UD2.M7 UD4.M7 UD5.M7
DDR_A_RAS#: RD59.1 UCPU1.AY34 UD1.J3 UD2.J3 UD4.J3 UD5.J3
DDR_A_WE#: RD65.1 UCPU1.AW34 UD1.L3 UD2.L3 UD4.L3 UD5.L3
DDR_B_BS0: RD70.1 UCPU1.AL35 UD6.M2 UD7.M2 UD9.M2 UD10.M2
DDR_B_BS1: RD66.1 UCPU1.AM36 UD6.N8 UD7.N8 UD9.N8 UD10.N8
DDR_B_BS2: RD68.1 UCPU1.AU49 UD6.M3 UD7.M3 UD9.M3 UD10.M3
DDR_B_CAS#: RD62.1 UCPU1.AM33 UD6.K3 UD7.K3 UD9.K3 UD10.K3
DDR_B_CKE0: RD58.1 UCPU1.AY49 UD6.K9 UD7.K9 UD9.K9 UD10.K9
DDR_B_CKE1: RD89.1 UCPU1.AU50 UD6.J9 UD7.J9 UD9.J9 UD10.J9
DDR_B_CS0#: RD60.1 UCPU1.AM32 UD6.L2 UD7.L2 UD9.L2 UD10.L2
DDR_B_CS1#: RD90.1 UCPU1.AK32 UD6.L1 UD7.L1 UD9.L1 UD10.L1
DDR_B_D0: UCPU1.AY31 UD7.H7
DDR_B_D1: UCPU1.AW31 UD7.F7
DDR_B_D2: UCPU1.AY29 UD7.G2
DDR_B_D3: UCPU1.AW29 UD7.F2
DDR_B_D4: UCPU1.AV31 UD7.H8
DDR_B_D5: UCPU1.AU31 UD7.F8
DDR_B_D6: UCPU1.AV29 UD7.H3
DDR_B_D7: UCPU1.AU29 UD7.E3
DDR_B_D8: UCPU1.AY27 UD7.D7
DDR_B_D9: UCPU1.AW27 UD7.B8
DDR_B_D10: UCPU1.AY25 UD7.A2
DDR_B_D11: UCPU1.AW25 UD7.A3
DDR_B_D12: UCPU1.AV27 UD7.C3
DDR_B_D13: UCPU1.AU27 UD7.A7
DDR_B_D14: UCPU1.AV25 UD7.C2
DDR_B_D15: UCPU1.AU25 UD7.C8
DDR_B_D16: UCPU1.AM29 UD6.H8
DDR_B_D17: UCPU1.AK29 UD6.F8
DDR_B_D18: UCPU1.AL28 UD6.F2
DDR_B_D19: UCPU1.AK28 UD6.G2
DDR_B_D20: UCPU1.AR29 UD6.H7
DDR_B_D21: UCPU1.AN29 UD6.F7
DDR_B_D22: UCPU1.AR28 UD6.E3
DDR_B_D23: UCPU1.AP28 UD6.H3
DDR_B_D24: UCPU1.AN26 UD6.B8
DDR_B_D25: UCPU1.AR26 UD6.A7
DDR_B_D26: UCPU1.AR25 UD6.C3
DDR_B_D27: UCPU1.AP25 UD6.C2
DDR_B_D28: UCPU1.AK26 UD6.A2
DDR_B_D29: UCPU1.AM26 UD6.C8
DDR_B_D30: UCPU1.AK25 UD6.D7
DDR_B_D31: UCPU1.AL25 UD6.A3
DDR_B_D32: UCPU1.AY23 UD9.H8
DDR_B_D33: UCPU1.AW23 UD9.F7
DDR_B_D34: UCPU1.AY21 UD9.H3
DDR_B_D35: UCPU1.AW21 UD9.G2
DDR_B_D36: UCPU1.AV23 UD9.H7
DDR_B_D37: UCPU1.AU23 UD9.F8
DDR_B_D38: UCPU1.AV21 UD9.F2
DDR_B_D39: UCPU1.AU21 UD9.E3
DDR_B_D40: UCPU1.AY19 UD9.A7
DDR_B_D41: UCPU1.AW19 UD9.B8
DDR_B_D42: UCPU1.AY17 UD9.C2
DDR_B_D43: UCPU1.AW17 UD9.A3
DDR_B_D44: UCPU1.AV19 UD9.C8
DDR_B_D45: UCPU1.AU19 UD9.D7
DDR_B_D46: UCPU1.AV17 UD9.A2
DDR_B_D47: UCPU1.AU17 UD9.C3
DDR_B_D48: UCPU1.AR21 UD10.E3
DDR_B_D49: UCPU1.AR22 UD10.H7
DDR_B_D50: UCPU1.AL21 UD10.F2
DDR_B_D51: UCPU1.AM22 UD10.H8
DDR_B_D52: UCPU1.AN22 UD10.F7
DDR_B_D53: UCPU1.AP21 UD10.H3
DDR_B_D54: UCPU1.AK21 UD10.G2
DDR_B_D55: UCPU1.AK22 UD10.F8
DDR_B_D56: UCPU1.AN20 UD10.B8
DDR_B_D57: UCPU1.AR20 UD10.A7
DDR_B_D58: UCPU1.AK18 UD10.A2
DDR_B_D59: UCPU1.AL18 UD10.A3
DDR_B_D60: UCPU1.AK20 UD10.D7
DDR_B_D61: UCPU1.AM20 UD10.C8
DDR_B_D62: UCPU1.AR18 UD10.C3
DDR_B_D63: UCPU1.AP18 UD10.C2
DDR_B_DQS0: UCPU1.AV30 UD7.F3
DDR_B_DQS1: UCPU1.AW26 UD7.C7
DDR_B_DQS2: UCPU1.AM28 UD6.F3
DDR_B_DQS3: UCPU1.AM25 UD6.C7
DDR_B_DQS4: UCPU1.AV22 UD9.F3
DDR_B_DQS5: UCPU1.AW18 UD9.C7
DDR_B_DQS6: UCPU1.AM21 UD10.F3
DDR_B_DQS7: UCPU1.AM18 UD10.C7
DDR_B_DQS#0: UCPU1.AW30 UD7.G3
DDR_B_DQS#1: UCPU1.AV26 UD7.B7
DDR_B_DQS#2: UCPU1.AN28 UD6.G3
DDR_B_DQS#3: UCPU1.AN25 UD6.B7
DDR_B_DQS#4: UCPU1.AW22 UD9.G3
DDR_B_DQS#5: UCPU1.AV18 UD9.B7
DDR_B_DQS#6: UCPU1.AN21 UD10.G3
DDR_B_DQS#7: UCPU1.AN18 UD10.B7
DDR_B_MA0: RD30.1 UCPU1.AP40 UD6.N3 UD7.N3 UD9.N3 UD10.N3
DDR_B_MA1: RD44.1 UCPU1.AR40 UD6.P7 UD7.P7 UD9.P7 UD10.P7
DDR_B_MA2: RD40.1 UCPU1.AP42 UD6.P3 UD7.P3 UD9.P3 UD10.P3
DDR_B_MA3: RD50.1 UCPU1.AR42 UD6.N2 UD7.N2 UD9.N2 UD10.N2
DDR_B_MA4: RD38.1 UCPU1.AR45 UD6.P8 UD7.P8 UD9.P8 UD10.P8
DDR_B_MA5: RD56.1 UCPU1.AP45 UD6.P2 UD7.P2 UD9.P2 UD10.P2
DDR_B_MA6: RD36.1 UCPU1.AW46 UD6.R8 UD7.R8 UD9.R8 UD10.R8
DDR_B_MA7: RD48.1 UCPU1.AY46 UD6.R2 UD7.R2 UD9.R2 UD10.R2
DDR_B_MA8: RD42.1 UCPU1.AY47 UD6.T8 UD7.T8 UD9.T8 UD10.T8
DDR_B_MA9: RD52.1 UCPU1.AU46 UD6.R3 UD7.R3 UD9.R3 UD10.R3
DDR_B_MA10: RD32.1 UCPU1.AK36 UD6.L7 UD7.L7 UD9.L7 UD10.L7
DDR_B_MA11: RD54.1 UCPU1.AV47 UD6.R7 UD7.R7 UD9.R7 UD10.R7
DDR_B_MA12: RD26.1 UCPU1.AU47 UD6.N7 UD7.N7 UD9.N7 UD10.N7
DDR_B_MA13: RD46.1 UCPU1.AK33 UD6.T3 UD7.T3 UD9.T3 UD10.T3
DDR_B_MA14: RD34.1 UCPU1.AR46 UD6.T7 UD7.T7 UD9.T7 UD10.T7
DDR_B_MA15: RD28.1 UCPU1.AP46 UD6.M7 UD7.M7 UD9.M7 UD10.M7
DDR_B_RAS#: RD64.1 UCPU1.AM35 UD6.J3 UD7.J3 UD9.J3 UD10.J3
DDR_B_WE#: RD72.1 UCPU1.AK35 UD6.L3 UD7.L3 UD9.L3 UD10.L3
DDR_CHA_EN: RH440.1 RH442.1 UCPU1.J1
DDR_CHB_EN: RH441.1 RH443.1 UCPU1.K3
DDR_PG_CNTL: UC1.2 UCPU1.AV61
DDR_VREF: CA13.2 CA15.1 R1186.2 R1187.1 UA1.40
DELAY_VR_AND_ALL_SYS: R1290.1 R1295.1 U690.4 U691.1
DEVSLP0: JSATA1.44 R1366.2 UCPU1.P2
DH_+1.2V: PQ601.4 PU601.17
DISP_CEC: JMDP1.6 RV4.1
DISP_CLK_AUXP_CONN: JMDP1.16 RV3.1 UV1.4
DISP_DAT_AUXN_CONN: JMDP1.18 RV2.1 UV1.7
DISP_HPD_SINK: JMDP1.2 QV2.1 RV10.1
DISPOFF#: D72.1 JLVDS1.13 R540.1
DL_+1.2V: PQ602.4 PU601.15
DMIC_CLK: MD50.6 R1342.1 RA5.1 RA9.1
DMIC_CLK_CODEC: JIOL1.32 RA9.2
DMIC_CLK_DSP: RA5.2 UA1.47
DMIC_CLK_R: JLVDS2.6 MC1133.1 R1342.2
DMIC_DAT: JLVDS2.5 MC1210.1 MD50.4 RA6.1 RA10.1
DMIC_DAT_CODEC: JIOL1.34 RA10.2
DMIC_DAT_DSP: RA6.2 UA1.48
DP_CBL_DET: RV8.1 UV1.1
DROOP: PC714.1 PR727.1 PR744.1 PU701.25
DSP_PD#: R1262.1 U34.H5
DSP_PD#_R: R1261.2 R1262.2 UA1.17
DSWODVREN: RH147.2 RH151.2 UCPU1.AW7
EAPD#: JIOL1.19 R228.1
EAPD_R#: R228.2 R241.1 U34.D6
EC_BATT_PRS#: C286.2 PC114.1 PC229.2 PR112.2 PR113.1 U34.B1
EC_CRY2: MC654.1 R253.2 R607.2 U34.K1
EC_ENVDD: D93.3 D105.3 PD306.3 U34.A10
EC_ON: C1117.1 PR341.1 U34.G1
EC_ON_CTRL#: C1118.1 D84.2 D85.2 RP22.3 U34.G5
EC_PECI: R240.1 U34.H2
EC_RST#: C285.1 R221.1 U34.K13
EC_RUNTIME_SCI#: RH398.2 T283.1(TP-1) U34.N6 UCPU1.AM2
EC_RX: JDEBUG.12 U34.K9
EC_SHUTDOWN: R1286.1 U34.D5
EC_SLP_S0#: R1390.2 R1391.2 U34.M2
EC_SLP_S5#: D114.2 R250.2 R1386.1 U34.N9
EC_SMB_CK1: PR109.2 PU201.9 R229.1 U34.A8
EC_SMB_DA1: PR111.2 PU201.8 R230.1 U34.A7
EC_SMI#: RP19.4 T270.1(TP-1) U34.L13 UCPU1.V1
EC_TX: JDEBUG.11 U34.K10
EC_WAKE_SCI#: RH427.1 U34.N7
ECAGND: C282.2 C286.1 L44.2 PH101.2 U34.A11
EDP_AUXN: C1065.1 UCPU1.A45
EDP_AUXN_C: C1065.2 ML58.1 R1011.1 R1033.1
EDP_AUXN_CONN: JLVDS1.9 ML58.2 R1011.2
EDP_AUXP: C1064.1 UCPU1.B45
EDP_AUXP_C: C1064.2 ML58.4 R1010.1 R1034.2
EDP_AUXP_CONN: JLVDS1.8 ML58.3 R1010.2
EDP_BKLCTL: RC147.2 UCPU1.B8
EDP_DISP: RC146.1 RC158.2 UCPU1.A43
EDP_HPD: JLVDS1.10 QC5.1 RC138.1 RC148.1
EDP_TXN_P0: C1060.1 UCPU1.C45
EDP_TXN_P0_C: C1060.2 ML57.4 R1008.1
EDP_TXN_P0_CONN: JLVDS1.5 ML57.3 R1008.2
EDP_TXN_P1: C1061.1 UCPU1.A47
EDP_TXN_P1_C: C1061.2 ML56.4 R1006.1
EDP_TXN_P1_CONN: JLVDS1.2 ML56.3 R1006.2
EDP_TXP_P0: C1062.1 UCPU1.B46
EDP_TXP_P0_C: C1062.2 ML57.1 R1009.1
EDP_TXP_P0_CONN: JLVDS1.6 ML57.2 R1009.2
EDP_TXP_P1: C1063.1 UCPU1.B47
EDP_TXP_P1_C: C1063.2 ML56.1 R1007.1
EDP_TXP_P1_CONN: JLVDS1.3 ML56.2 R1007.2
EN_+1.05VS: PR501.2 PR503.2 PU501.28
EN_+3VALW: PD301.1 PD302.1 PD303.2 PU305.13
EN_+3VDX: PD305.1 PD306.1 PU303.13
EN_+5VDX: PU302.13 PU307.4
EN_+V5A: PD307.1 PU301.13
EN_CAM: R1162.1 U718.5 UCPU1.AM4
EN_WLANPWR: D115.3 U34.F4
ENBKL: D72.2 RH123.2 UCPU1.A9
ENVDD: D93.1 R1026.1 U721.3
F-IMAX: PR705.1 PR712.2 PU701.10
FB_+1.8VSP: PC412.2 PR419.2 PR420.1 PU402.5
FB_+3.3VDX_SSD: PC328.2 PR335.2 PR337.1 PU304.5
FB_+3VALW: PC336.2 PR345.2 PR347.1 PU305.5
FB_+3VDX: PC320.2 PR325.2 PR327.1 PU303.5
FB_+5VDX: PC312.2 PR315.2 PR317.1 PU302.5
FB_+V5A: PC304.2 PR305.2 PR307.1 PU301.5
FIVE_EN: JXDP.45 R1179.2 UCPU1.H59
FSW_+1.8VS: PR424.1 PU402.7
FSW_+3.3VDX_SSD: PR336.1 PU304.7
FSW_+3VALW: PR346.1 PU305.7
FSW_+3VDX: PR326.1 PU303.7
FSW_+5VDX: PR316.1 PU302.7
FSW_+V5A: PR306.1 PU301.7
GYRO_DRDY: U636.G5 U638.6
GYRO_I2C_ADD_SEL: R1205.1 R1206.2 U638.4
GYRO_INT#: R1176.2 U636.H8 U638.7
H_CATERR#: T2.1(TP-1) UCPU1.K61
H_CPU_SVIDALRT#: RC93.1 RC94.2 UCPU1.L62
H_CPU_SVIDCLK: RC92.2 UCPU1.N63
H_CPU_SVIDDAT: RC95.2 RC96.2 UCPU1.L63
H_CPUPWRGD_R: RC44.2 UCPU1.C61
H_DRAMRST#: RC162.1 UCPU1.AV15
H_PECI: R240.2 UCPU1.N62
H_PROCHOT#: C656.1 PQ104.1 PQ105.3 PQ106.1 R265.1 RC41.1 RC43.1 U635.4
H_PROCHOT#_R: RC41.2 UCPU1.K63
H_PROCHOT_EC: PR110.1 R608.2 U34.E2 U635.2
H_THERMTRIP#: RC49.2 RC149.1
H_THERMTRIP#_R: RC49.1 UCPU1.D60
HDA_BIT_CLK: RP3.8 UCPU1.AW8
HDA_BITCLK_AUDIO: RA16.2 RP3.1 UA1.6
HDA_BITCLK_AUDIO_C: JIOL1.14 MC1297.1 ML9.2
HDA_BITCLK_DSP: ML9.1 RA14.2 UA2.4
HDA_BITCLK_DSP_B: RA14.1 RA16.1 UA1.23 UA2.2
HDA_RST#: RP3.7 UCPU1.AU8
HDA_RST_AUDIO#: RA20.2 RP3.2 UA1.11
HDA_RST_DSP#: JIOL1.20 RA20.1 UA1.18
HDA_SDIN0: RA1.1 UCPU1.AY10
HDA_SDIN0_AUDIO: RA1.2 RA18.2 UA1.8
HDA_SDIN0_DSP: JIOL1.26 RA18.1 UA1.21
HDA_SDO: Q351.2 R1341.1 U34.C1
HDA_SDOUT: MC103.1 RH24.2 RH42.2 RP3.5 UCPU1.AU11
HDA_SDOUT_AUDIO: RA17.2 RP3.4 UA1.5
HDA_SDOUT_DSP: JIOL1.24 RA15.2 UA3.4
HDA_SDOUT_DSP_B: RA15.1 RA17.1 UA1.24 UA3.2
HDA_SPKR: JIOL1.28 RH37.2 UCPU1.V2
HDA_SYNC: RP3.6 UCPU1.AV11
HDA_SYNC_AUDIO: RA19.2 RP3.3 UA1.10
HDA_SYNC_DSP: JIOL1.18 RA19.1 UA1.19
HUB_OSC_IN: C1204.1 U636.D8 Y2.1
HUB_OSC_OUT: C1205.1 U636.D7 Y2.2
HWPG: D109.2 R930.2 R931.2 R934.2 R982.2 R1133.2 R1154.2 R1296.1 U34.F1 U690.2
I2C0_SCK: Q352.1 R1224.1 R1307.2 RA8.2 RH425.1 RH462.1 UCPU1.F3
I2C0_SCK_DSP: RA8.1 UA1.26
I2C0_SCK_SNR: JSNRDG.18 R1224.2 U636.G3
I2C0_SDA: Q352.4 R1225.1 R1308.2 RA7.2 RH424.1 RH461.1 UCPU1.F2
I2C0_SDA_DSP: RA7.1 UA1.27
I2C0_SDA_SNR: JSNRDG.19 R1225.2 U636.F3
I2C1_SCK: R1152.1 R1257.1 RH364.1 UCPU1.F1
I2C1_SCK_TP: DE1.2 JTP1.3 R1257.2 R1377.2
I2C1_SCK_TS: JLVDS1.18 MD90.1 R1152.2 R1218.2
I2C1_SDA: R1153.1 R1258.1 RH365.1 UCPU1.G4
I2C1_SDA_TP: DE1.3 JTP1.2 R1258.2 R1378.2
I2C1_SDA_TS: JLVDS1.19 MD90.3 R1153.2 R1219.2
I2S_BCLK_OUT: R1372.2 UA1.29
I2S_CLK: R1372.1 R1373.1 R1374.1 U677.13
I2S_CLK_IN: R1373.2 UA1.38
I2S_SDI_IN: U677.10 UA1.41
I2S_SDO_OUT: U677.11 UA1.31
I2S_SFRM_IN: R1374.2 UA1.39
I2S_SFRM_OUT: U677.12 UA1.30
IMON: PC707.2 PR703.2 PU701.13
IMVP_VR_PG: PR723.1 PU701.3 R1211.2 R1241.2 R1291.1 RC152.1
INV_PWM_R: D73.1 D92.1 JLVDS1.14 MC1151.1 R545.1
JNTRST: JSATA1.16 JSNRDG.4 RP12.8 U636.B4
JTCK: JSATA1.14 JSNRDG.5 R1099.2 U636.B2
JTDI: JSATA1.12 JSNRDG.6 RP12.5 U636.C3
JTDO: JSATA1.10 JSNRDG.7 RP12.7 U636.A4
JTMS: JSATA1.8 JSNRDG.3 RP12.6 U636.D4
KB_BL_DET: R944.1 R945.2 T284.1(TP-1) UCPU1.AU2
KB_DET#: JKB1.1 RH302.1 T282.1(TP-1) UCPU1.Y1
KB_LED_PWM: Q311.2 U34.M9
KB_LED_PWM#: JBL1.1 Q311.1
KB_RST#: RH196.1 U34.L2 UCPU1.V4
KSI0: C1190.1 JKB1.9 U34.D9
KSI1: C1192.1 JKB1.7 U34.E12
KSI2: C1186.1 JKB1.5 U34.E13
KSI3: C1191.1 JKB1.8 U34.D12
KSI4: C1187.1 JKB1.4 U34.D13
KSI5: C1193.1 JKB1.6 U34.C12
KSI6: C1188.1 JKB1.3 U34.C13
KSI7: C1189.1 JKB1.2 U34.D10
KSO0: C1078.1 JKB1.18 U34.J13
KSO1: C1195.1 JKB1.16 U34.J12
KSO2: C1194.1 JKB1.17 U34.H12
KSO3: C1196.1 JKB1.15 R1032.2 U34.H13
KSO4: C1184.1 JKB1.11 U34.H10
KSO5: C1185.1 JKB1.10 U34.H9
KSO6: C1182.1 JKB1.13 U34.G9
KSO7: C1183.1 JKB1.12 U34.G10
KSO8: C1197.1 JKB1.14 U34.G13
KSO9: C1180.1 JKB1.24 U34.G12
KSO10: C1178.1 JKB1.26 U34.F13
KSO11: C1179.1 JKB1.25 U34.F12
KSO12: C1177.1 JKB1.19 U34.F10
KSO13: C1174.1 JKB1.22 U34.F9
KSO14: C1181.1 JKB1.23 U34.E10
KSO15: C1175.1 JKB1.21 U34.E9
KSO16: C1176.1 JKB1.20 U34.E8
LCD_DBC: R1139.1 R1279.1 UCPU1.J2
LCD_TEST: JLVDS2.14 U34.A2
LID_SW_IN#: JIOL1.27 RP21.4 U34.F2
LP#: PR509.1 PU501.2
LPC_AD0: JDEBUG.5 U34.N4 U652.26 UCPU1.AU14
LPC_AD1: JDEBUG.4 U34.K5 U652.23 UCPU1.AW12
LPC_AD2: JDEBUG.3 U34.M4 U652.20 UCPU1.AY12
LPC_AD3: JDEBUG.2 U34.N3 U652.17 UCPU1.AW11
LPC_FRAME#: JDEBUG.1 U34.K4 U652.22 UCPU1.AV12
LPCPD#: R1238.2 R1239.2 U652.28
M_CLK_A_DDR0: RD75.1 UCPU1.AV37 UD1.J7 UD2.J7 UD4.J7 UD5.J7
M_CLK_A_DDR#0: RD77.1 UCPU1.AU37 UD1.K7 UD2.K7 UD4.K7 UD5.K7
M_CLK_B_DDR0: RD76.1 UCPU1.AN38 UD6.J7 UD7.J7 UD9.J7 UD10.J7
M_CLK_B_DDR#0: RD78.1 UCPU1.AM38 UD6.K7 UD7.K7 UD9.K7 UD10.K7
M_ODT0: RD73.1 UD1.J1 UD1.K1 UD2.J1 UD2.K1 UD4.J1 UD4.K1 UD5.J1 UD5.K1
M_ODT2: RD74.1 UD6.J1 UD6.K1 UD7.J1 UD7.K1 UD9.J1 UD9.K1 UD10.J1 UD10.K1
MAG_DRDY: U636.E5 U637.9
MEM_CONFIG0: RH303.1 RH316.2 T286.1(TP-1) UCPU1.AT5
MEM_CONFIG1: RH180.1 RH315.2 T287.1(TP-1) UCPU1.U4
MEM_CONFIG2: RH271.1 RH314.2 UCPU1.AB6
MPCIE_RST#: R1314.1 RH381.2 U675.1 UCPU1.U6
MPHY_PWREN: Q362.2 R1169.1 R1185.1 UCPU1.Y2
MPHY_PWREN#: Q39.2 Q361.2 Q361.5 Q362.1 R1381.2
MSATA_DET#: JSATA1.51 RH392.1 T274.1(TP-1) UCPU1.AC1
NFC_DET#: JNFC1.12 R1228.1 RH465.1 UCPU1.N5
NFC_IRQ: JNFC1.11 R1100.2 RH294.1 UCPU1.AN3
NFC_RST#: JNFC1.6 R1142.1 UCPU1.AD7
NFC_VDD_SIM: JNFC1.10 R973.2 R974.1
NGFF_PWREN: D115.2 R1163.1 R1215.1 UCPU1.R6
NGFF_RST#: JNGFF1.44 R1203.1 R1214.1 U675.4 U709.2
NGFF_WAKE#: R1199.1 R1216.1 RH397.2 UCPU1.L3
NGFF_WAKE#_R: Q347.1 R1216.2
O-USR: PR706.1 PR713.2 PU701.9
OCP-I: PR703.1 PR710.2 PU701.12
P1: PC206.1 PL201.1 PL202.1 PR201.1
PA11: R1221.2 U636.C1
PA12: R1222.2 R1223.1 R1251.1 U636.C2
PB5: R1223.2 U636.A5
PB13: R1367.1 U636.G1
PBTN_OUT#: RH293.2 U34.H4
PBTN_OUT#_R: R1312.1 RH293.1 RH439.1 RH444.1 UCPU1.AL7
PBTN_SW: Q349.2 R1283.1 U687.4
PBTN_SW#: D85.1 JAPS.8 JIOL1.29 RH21.1 RH439.2 RP16.4 SW2.1 SW2.2 U687.2
PC0: R1135.1 U636.E8
PC2: R1136.1 U636.D6
PCH_DP_AUXN: CV10.2 UCPU1.C5
PCH_DP_AUXN_C: CV10.1 UV1.5
PCH_DP_AUXP: CV8.2 UCPU1.B5
PCH_DP_AUXP_C: CV8.1 UV1.2
PCH_DP_CLK: RH281.2 UCPU1.B9 UV1.3
PCH_DP_DAT: RH282.2 UCPU1.C9 UV1.6
PCH_DP_HPD: QV2.3 RH300.2 UCPU1.C8
PCH_DP_N0: CV4.2 UCPU1.C54
PCH_DP_N0_C: CV4.1 JMDP1.5 MD1.2 MD1.8
PCH_DP_N1: CV7.2 UCPU1.B58
PCH_DP_N1_C: CV7.1 JMDP1.11 MD1.5 MD1.6
PCH_DP_N2: CV12.2 UCPU1.B55
PCH_DP_N2_C: CV12.1 JMDP1.17 MD2.5 MD2.6
PCH_DP_N3: CV9.2 UCPU1.A57
PCH_DP_N3_C: CV9.1 JMDP1.12 MD2.2 MD2.8
PCH_DP_P0: CV3.2 UCPU1.C55
PCH_DP_P0_C: CV3.1 JMDP1.3 MD1.1 MD1.9
PCH_DP_P1: CV5.2 UCPU1.C58
PCH_DP_P1_C: CV5.1 JMDP1.9 MD1.4 MD1.7
PCH_DP_P2: CV11.2 UCPU1.A55
PCH_DP_P2_C: CV11.1 JMDP1.15 MD2.4 MD2.7
PCH_DP_P3: CV6.2 UCPU1.B57
PCH_DP_P3_C: CV6.1 JMDP1.10 MD2.1 MD2.9
PCH_DPWROK: RH126.1 RH309.2 RH401.1 UCPU1.AV5
PCH_ENVDD: D93.2 D105.2 PD306.2 RH158.2 UCPU1.C6
PCH_GPIO15: RH270.1 UCPU1.AD6
PCH_GPIO17: RH395.2 T281.1(TP-1) UCPU1.T3
PCH_GPIO18: RH91.2 UCPU1.U2
PCH_GPIO19: RH95.2 UCPU1.Y5
PCH_GPIO20: Q346.1 RH100.2 RH410.2 UCPU1.AD1
PCH_GPIO21: RH103.2 UCPU1.N1
PCH_GPIO22: RH107.2 UCPU1.U5
PCH_GPIO23: RH110.2 UCPU1.T2
PCH_GPIO27: RH186.2 RH310.2 RH427.2 RP20.3 UCPU1.AN5
PCH_GPIO35: RH390.1 T271.1(TP-1) UCPU1.U1
PCH_GPIO36: RH391.1 T272.1(TP-1) UCPU1.V6
PCH_GPIO72: RP20.4 UCPU1.AN4
PCH_GPIO86: RH32.1 UCPU1.L8
PCH_GPIO88: R1390.1 UCPU1.L5
PCH_INTVRMEN: RH31.2 RH34.2 UCPU1.AV7
PCH_INV_PWM: D92.2 RC146.2 RC147.1
PCH_JTAG_JTAGX: RH374.1 RH375.2 RH412.1 T273.1(TP-1) UCPU1.AE63
PCH_JTAG_TCK: RH53.2 RH373.1 RH411.1 T277.1(TP-1) UCPU1.AE62
PCH_JTAG_TDI: RH40.2 RH371.1 T278.1(TP-1) UCPU1.AD61
PCH_JTAG_TDO: RH369.1 RH413.1 RH445.2 T275.1(TP-1) UCPU1.AE61
PCH_JTAG_TMS: RH39.2 RH372.1 T276.1(TP-1) UCPU1.AD62
PCH_JTAG_TRST#: RH370.1 UCPU1.AU62
PCH_OPIRCOMP: RC156.1 UCPU1.AW15
PCH_PLTRST#: RH168.2 RH183.2 UCPU1.AG7 UH5.1 UH5.2
PCH_PWR_EN: R1249.2 U34.N2
PCH_PWRBTN#_XDP: JXDP.41 RH21.2 RH444.2
PCH_PWROK: R1293.2 R1294.2 R1295.2 R1296.2 RH131.2 RH394.1 UCPU1.AY7
PCH_PWROK_EC: R1294.1 U34.E6 U691.2
PCH_RSMRST#: RH133.2 RH159.2 U34.D4
PCH_RSMRST#_R: RH126.2 RH133.1 UCPU1.AW6
PCH_RTCRST#: CH4.2 CLRP1.2 JAPS.10 RH25.2 UCPU1.AU7
PCH_RTCX1: CH2.1 RH2.1 UCPU1.AW5 YH1.1
PCH_RTCX2: CH3.1 RH2.2 UCPU1.AY5 YH1.2
PCH_SATALED#: RH35.2 UCPU1.U3
PCH_SMBCLK: JXDP.53 QH3.1 R1377.1 RH98.2 RH105.2 UD3.6 UD8.6
PCH_SMBDATA: JXDP.51 QH3.4 R1378.1 RH99.2 RH111.2 UD3.5 UD8.5
PCH_SMLCLK: Q352.6 Q359.1 QH4.1 R983.1 R1307.1 R1350.2 RH453.2 RP15.8 U34.B8
PCH_SMLDATA: Q352.3 Q359.4 QH4.4 R984.1 R1308.1 R1351.2 RH454.2 RP15.7 U34.A6
PCH_SPI_CLK: MC118.2 RH255.2 UCPU1.AA3
PCH_SPI_CS#: U48.1 UCPU1.Y7
PCH_SPI_IO2: RP4.7 UCPU1.Y6
PCH_SPI_IO3: RP4.5 UCPU1.AF1
PCH_SPI_SI: RP4.6 UCPU1.AA2
PCH_SPI_SO: RP4.8 UCPU1.AA4
PCH_SRTCRST#: CH5.1 CLRP2.1 RH23.2 UCPU1.AV6
PCH_SUSWARN#: RH297.2 U34.D8
PCI_PIRQC#: RP2.8 UCPU1.N4
PCI_PIRQD#: RP2.7 UCPU1.N2
PCIE_PRX_DTX_N4: JNGFF1.59 UCPU1.F13
PCIE_PRX_DTX_P4: JNGFF1.57 UCPU1.G13
PCIE_PRX_WLANTX_N3: JNGFF1.35 UCPU1.G11
PCIE_PRX_WLANTX_P3: JNGFF1.33 UCPU1.F11
PCIE_PTX_DRX_N4: CH1237.1 JNGFF1.53
PCIE_PTX_DRX_N4_C: CH1237.2 UCPU1.B29
PCIE_PTX_DRX_P4: CH1238.1 JNGFF1.51
PCIE_PTX_DRX_P4_C: CH1238.2 UCPU1.A29
PCIE_PTX_WLANRX_N3: CH11.1 JNGFF1.29
PCIE_PTX_WLANRX_N3_C: CH11.2 UCPU1.C29
PCIE_PTX_WLANRX_P3: CH16.1 JNGFF1.27
PCIE_PTX_WLANRX_P3_C: CH16.2 UCPU1.B30
PCIE_RCOMP: RH338.2 UCPU1.A27
PCIE_WAKE#: JNGFF1.47 Q347.3 R942.2 U676.4
PLT_RST#: JDEBUG.6 R929.2 R1313.1 RH168.1 RH171.1 RH363.2 U34.M5 U675.2 U698.1 UH5.4
PLTRST1#_XDP: JXDP.46 RH363.1
PM_CLKRUN#: RH248.2 U34.M6 U652.15 UCPU1.V5
PM_SLP_A#: JAPS.13 UCPU1.AL5
PM_SLP_S0#: JAPS.4 PQ300.2 PR509.2 R1391.1 RH463.2
PM_SLP_S3#: JAPS.17 PR503.1 PU401.13 PU402.13 R249.1 R1146.1 R1191.2 R1247.1 RH416.1 U710.2 UCPU1.AT4
PM_SLP_S4#: JAPS.14 PR613.1 RH415.1 U34.N1 UCPU1.AJ6
PM_SLP_S5#: D114.1 JAPS.15 R250.1 RH426.1 UCPU1.AP5
PM_SLP_SUS: Q5.2 U713.4
PM_SLP_SUS#: PD307.3 PR501.1 PU307.1 R1183.1 R1249.1 R1284.2 RH313.1 U713.2
PM_SLP_SUS#_R: C1300.1 R1183.2 U719.3
PM_SYS_RESET#: JAPS.6 RH450.2 RH451.2
PP: R975.1 U652.7
PRESSURE_INT1#: U636.H7 U653.9
PRESSURE_INT2#: U636.G4 U653.11
PROC_OPI_COMP: RC154.1 UCPU1.AY15
PS_ID: PR102.1 PR103.2 U34.K6
PSID: JDCIN1.1 PL102.2
PSID-1: PQ102.2 PR105.1 PR106.2
PSID-2: PQ101.2 PQ102.1 PR104.1 PR107.1
PSID-3: PQ101.3 PR103.1
PWM1: PU701.6 PU702.8
PWM2: PU701.5 PU703.8
PWR_SRC_ON: C613.2 Q70.3 R535.2 R536.1
REGN: PC213.1 PD202.2 PR223.1 PU201.16
RESET#: C1152.1 JSATA1.20 JSNRDG.2 R1003.1 R1090.1 R1141.1 U636.C7
ROTATION_LOCK_SW#: C1125.1 R957.2 R1354.1 U34.M7
ROTATION_LOCK_SW#_C: JIOL1.31 R957.1
RUN_ON#: Q4.2 Q34.2 U710.4
S3_+1.2V: PR615.2 PU601.7
S5_+1.2V: PC616.1 PR613.2 PU601.8
SATA_PRX_DTX_N0: CS53.1 UCPU1.J5
SATA_PRX_DTX_N0_C: CS53.2 JSATA1.25
SATA_PRX_DTX_P0: CS54.1 UCPU1.H5
SATA_PRX_DTX_P0_C: CS54.2 JSATA1.23
SATA_PTX_DRX_N0: CS43.1 UCPU1.B15
SATA_PTX_DRX_N0_C: CS43.2 JSATA1.31
SATA_PTX_DRX_P0: CS42.1 UCPU1.A15
SATA_PTX_DRX_P0_C: CS42.2 JSATA1.33
SATA_RCOMP: RH43.1 UCPU1.C12
SBD_WAKE#: T252.1(TP-1) U636.F8
SDIO_CLK: JNGFF1.9 R1360.2 R1395.2 UCPU1.E3
SDIO_CMD: JNGFF1.11 R1361.2 UCPU1.F4
SDIO_D0: JNGFF1.13 R1362.2 RH434.2 RH435.1 UCPU1.D3
SDIO_D1: JNGFF1.15 R1363.2 UCPU1.E4
SDIO_D2: JNGFF1.17 R1364.2 UCPU1.C3
SDIO_D3: JNGFF1.19 R1365.2 UCPU1.E2
SDIO_RST#: JNGFF1.23 R1328.2 U679.D1
SDIO_RST#_R: R1313.2 R1314.2 U679.A1
SDIO_WAKE#: R1199.2 U679.A2
SDIO_WAKE#_Q: JNGFF1.21 R1327.2 U679.D2
SENSOR_ALERT#: R1158.1 U636.H6
SENSOR_DFU_EN#: JSNRDG.17 R1220.1 U636.F2 UCPU1.AK4
SENSOR_EN: JSNRDG.16 R1250.1 U716.5 UCPU1.AG3
SENSOR_HUB_I2C_WAKE: R1252.1 T280.1(TP-1) UCPU1.Y3
SENSOR_HUB_I2C_WAKE_R: JSNRDG.13 R1252.2 R1253.1 U636.G2
SENSOR_HUB_WAKE#: RP16.2 U34.M10 U636.F1
SENSOR_I2C_SCL: JSNRDG.8 R854.1 R985.2 U636.B5 U637.2 U638.2 U653.4
SENSOR_I2C_SDA: JSNRDG.9 R855.1 R986.2 U636.C5 U637.3 U638.3 U653.6
SENSOR_INT#: R1135.2 R1367.2 RH295.1 T285.1(TP-1) UCPU1.AH4
SENSOR_RST#: R1090.2 RH452.2 UCPU1.R5
SENSOR_STANDBY#: D74.2 UCPU1.C4
SERIRQ: RH29.1 U34.M3 U652.27 UCPU1.T4
SHUTDWN#: U688.4 U689.2
SKIP#: PR718.1 PR733.1 PU701.7
SKIP#1: PR718.2 PR720.1 PU702.1
SKIP#2: PR733.2 PR738.1 PU703.1
SLATE_MODE: U636.D5 UCPU1.AL4
SLEW: PC502.1 PU501.21
SLEWA: PR701.1 PR714.2 PU701.15
SLP_S0#: RH463.1 UCPU1.AF3
SLP_WLAN#: RH402.1 UCPU1.AM5
SM_INTRUDER#: RH11.2 UCPU1.AU6
SM_PG_CTRL: PR615.1 RC159.2 RC161.1 UC1.4
SM_RCOMP0: RC55.1 UCPU1.AU60
SM_RCOMP1: RC58.1 UCPU1.AV60
SM_RCOMP2: RC60.1 UCPU1.AU61
SMBALERT#: R1136.2 RP19.2 UCPU1.AN2
SMBCLK: QH3.6 RH105.1 RP7.1 UCPU1.AP2
SMBDATA: QH3.3 RH111.1 RP7.2 UCPU1.AH1
SMC_SHDN: Q349.5 R1285.2 R1286.2 R1287.1
SML0ALERT#: RP19.3 UCPU1.AL2
SML0CLK: JNFC1.8 RH70.1 UCPU1.AN1
SML0DATA: JNFC1.9 RH72.1 UCPU1.AK1
SML1ALERT#: R1158.2 R1227.1 UCPU1.AU4
SML1CLK: QH4.6 RH453.1 RP7.3 UCPU1.AU3
SML1DATA: QH4.3 RH454.1 RP7.4 UCPU1.AH3
SNUB_1.5VSP: PC407.1 PR406.2
SNUB_1.8VSP: PC416.1 PR418.2
SNUB_+1.2V: PC613.1 PR605.2
SNUB_+1.05V: PC509.1 PR507.2
SNUB_+3.3VDX_SSD: PC331.1 PR334.2
SNUB_+3VDX: PC323.1 PR324.2
SNUB_+5VDX: PC315.1 PR314.2
SNUB_+V3.3A_DSW: PC339.1 PR344.2
SNUB_+V5A: PC307.1 PR304.2
SNUB_CHG: PC221.1 PR220.1
SNUB_PHASE1: PC712.1 PR719.2
SNUB_PHASE2: PC722.1 PR734.2
SOSCI: CH1202.1 U636.B8 Y1.2
SOSCO: CH1203.1 U636.B7 Y1.1
SPARE1: JSNRDG.10 U636.C4
SPARE2: JSNRDG.11 U636.A3
SPI_CLK_ROM: MR256.2 RH255.1 U48.6
SPI_IO2_ROM: RH54.2 RP4.2 U48.3
SPI_IO3_ROM: RH56.2 RP4.4 U48.7
SPI_SI_ROM: RP4.3 U48.5
SPI_SO_ROM: RP4.1 U48.2
SSD_PWREN: PU304.13 RH431.1 U682.4
SSD_PWREN#: RH423.1 RH431.2 U682.2 UCPU1.K2
STARTUP_LATCH_SET: R1283.2 T262.1(TP-1) U688.1
SUS_PWR_DN: RH154.1 RH297.1 RH429.2 UCPU1.AV4
SUS_STAT#: R1238.1 UCPU1.AG4
SUSACK#: RH430.2 U34.M13
SUSACK#_R: RH429.1 RH430.1 UCPU1.AK2
SUSCLK: MC102.2 RH132.2 UCPU1.AE6
SUSCLK_R: R253.1 R1255.2 RH132.1
SW_+1.2V: PC605.2 PL602.2 PQ601.1 PQ601.2 PQ601.3 PQ602.5 PR605.1 PU601.16
SW_+1.05VS: PC503.2 PL502.1 PR507.1 PU501.6 PU501.7 PU501.8 PU501.9
SW_PHASE_1: PL701.1 PR719.1 PU702.4
SW_PHASE_2: PL702.1 PR734.1 PU703.4
SW_USB20_N1: ML40.1 R222.1 US1.11
SW_USB20_P1: ML40.4 R262.1 US1.10
SYS_PRS: JBATT1.4 PR115.1
SYS_PWROK: R1290.2 R1292.2 R1293.1 R1309.1 RH272.1 UCPU1.AG2
SYS_PWROK_XDP: C1282.1 JXDP.47 R1309.2 R1311.1
SYS_RESET#: RH450.1 RP20.1 UCPU1.AC3
SYSTEM_FAN_FB: D81.2 R884.1 U34.M11
SYSTEM_FAN_PWM: JFAN1.3 R1103.1 U34.N10
TABLET_MODE: JLVDS2.18 R980.1 R1375.1 RP21.1 U34.B7
TABLET_MODE_R: R1375.2 UA1.7
TD_IREF: RC155.1 UCPU1.B12
TESTLOW1: RH76.1 UCPU1.C35
TESTLOW2: RH77.1 UCPU1.C34
TESTLOW3: RH78.1 UCPU1.AK8
TESTLOW4: RH79.1 UCPU1.AL8
TOUCH_EN: R1382.1 UCPU1.N7
TOUCH_EN_R: R1160.1 R1382.2 U719.5
TP_CLK: DE2.2 JTP1.8 RP15.6 U34.A5
TP_DATA: DE2.3 JTP1.7 RP15.5 U34.B5
TP_INT#: Q364.1 R1387.1 RH380.2 UCPU1.U7
TP_INT#_R: JTP1.5 Q364.3 R1299.2 R1387.2
TPM_DET: RH274.2 RH337.1 UCPU1.AG5
TPM_IRQ#: RP2.5 UCPU1.P4
TPM_PWREN: R1394.1 U722.3 UCPU1.L6
TPM_RESET#: R1310.1 U652.16 U698.4
TPM_RST#: U698.2 UCPU1.AG6
TRIP: PR505.2 PR508.2 PU501.20
TS_INT#: Q363.1 R1384.1 RH384.1 UCPU1.P3
TS_INT#_R: JLVDS1.1 Q363.3 R1384.2 R1385.2 R1389.2
TS_RST#: JLVDS1.20 R1376.1 R1389.1 UCPU1.L1
UART1_CTS#: RH460.1 U671.10 UCPU1.J4
UART1_CTS#_NGFF: JNGFF1.26 R1371.2 U671.5
UART1_RTS#: RH459.1 U671.11 UCPU1.J3
UART1_RTS#_NGFF: JNGFF1.28 R1370.2 U671.4
UART1_RXD: RH457.1 U671.12 UCPU1.K4
UART1_RXD_NGFF: JNGFF1.22 R1369.2 U671.3
UART1_TXD: RH458.1 U671.13 UCPU1.G2
UART1_TXD_NGFF: JNGFF1.24 R1368.2 U671.2
UART_WAKE#: JNGFF1.20 RH383.1 T288.1(TP-1) UCPU1.AM3
USB0_PWR_EN: R1217.2 RH400.1 UCPU1.AT3 US2.4
USB1_CTL1: R1166.2 U34.B4
USB1_DET#: D104.1 JUSB1.10
USB1_DET_EC#: D104.3 R1156.2 U34.D1
USB1_PWR_EN: RP11.4 T292.1(TP-1) U699.1 UCPU1.AV3
USB1_PWR_EN_EC: RP21.2 U34.M1 U699.2
USB3RN0: ML54.4 R893.1 UCPU1.G20
USB3RN0_RC_CON: JUSB2.5 MD82.1 ML54.3 R893.2
USB3RN1: ML46.4 R560.1 UCPU1.E18
USB3RN1_RC_CON: JUSB1.5 MD74.1 ML46.3 R560.2
USB3RP0: ML54.1 R892.1 UCPU1.H20
USB3RP0_RC_CON: JUSB2.6 MD82.2 ML54.2 R892.2
USB3RP1: ML46.1 R565.1 UCPU1.F18
USB3RP1_RC_CON: JUSB1.6 MD74.2 ML46.2 R565.2
USB3TN0: C1107.1 UCPU1.C33
USB3TN0_C: C1107.2 ML53.4 R890.1
USB3TN0_RC_CON: JUSB2.8 MD82.3 ML53.3 R890.2
USB3TN1: C621.1 UCPU1.B33
USB3TN1_C: C621.2 ML45.4 R555.1
USB3TN1_RC_CON: JUSB1.8 MD74.3 ML45.3 R555.2
USB3TP0: C1108.1 UCPU1.B34
USB3TP0_C: C1108.2 ML53.1 R891.1
USB3TP0_RC_CON: JUSB2.9 MD82.4 ML53.2 R891.2
USB3TP1: C623.1 UCPU1.A33
USB3TP1_C: C623.2 ML45.1 R556.1
USB3TP1_RC_CON: JUSB1.9 MD74.4 ML45.2 R556.2
USB20_N0: ML52.1 R888.1 UCPU1.AN8
USB20_N0_CONN: JUSB2.2 MD82.5 ML52.2 R888.2
USB20_N1: UCPU1.AR7 US1.2
USB20_N1_CONN: JUSB1.2 MD74.5 ML40.2 R222.2
USB20_N2: ML49.1 R742.1 UCPU1.AR8
USB20_N2_R: JNGFF1.5 ML49.2 R742.2
USB20_N3: R1218.1 UCPU1.AR10
USB20_N4: ML55.4 R1005.1 UCPU1.AM15
USB20_N4_CONN: JLVDS2.3 MD50.1 ML55.3 R1005.2
USB20_N5: R1221.1 UCPU1.AM13
USB20_P0: ML52.4 R889.1 UCPU1.AM8
USB20_P0_CONN: JUSB2.3 MD82.6 ML52.3 R889.2
USB20_P1: UCPU1.AT7 US1.3
USB20_P1_CONN: JUSB1.3 MD74.6 ML40.3 R262.2
USB20_P2: ML49.4 R741.1 UCPU1.AP8
USB20_P2_R: JNGFF1.3 ML49.3 R741.2
USB20_P3: R1219.1 UCPU1.AT10
USB20_P4: ML55.1 R1004.1 UCPU1.AL15
USB20_P4_CONN: JLVDS2.2 MD50.3 ML55.2 R1004.2
USB20_P5: R1222.1 UCPU1.AN13
USB_EN: PU307.2 U699.4 US1.5
USB_ILIM_SEL: R1164.1 R1167.1 U34.K8 US1.4
USB_OC0#: RP11.2 T289.1(TP-1) UCPU1.AL3 US2.5
USB_OC1#: RP11.3 T290.1(TP-1) UCPU1.AT1 US1.13
USB_OC2#: RP11.1 T291.1(TP-1) UCPU1.AH2
USB_PS_CTL1: R1166.1 R1213.1 US1.6
USBCHG_DET_D: PR342.1 U712.4
USBCHG_DET_PWR_EN#: D104.2 R939.2 R941.2 U712.2
USBRBIAS: RH163.1 UCPU1.AJ10 UCPU1.AJ11
V_DDR_REF_CA: CD89.1 RD14.1 UCPU1.AP49
V_DDR_REFA_R: CD91.1 RD19.1 UCPU1.AR51
V_DDR_REFB_R: CD92.1 RD20.1 UCPU1.AP51
VCIN0_PH: PH101.1 PR117.1 R925.1
VCIN0_PH_R: R925.2 U34.C2
VCIN1_PH: PC112.1 PR116.1 PR118.2 R926.1
VCIN1_PH_R: R926.2 U34.D2
VCOUT0_PH#: PD303.1 R922.1 U34.E4
VLDOIN_+1.2V: PJP604.1 PU601.19
VOLUME_DOWN_SW#: C1124.1 R955.2 RP21.3 U34.J1
VOLUME_DOWN_SW#_C: JIOL1.33 R955.1 R1263.1
VOLUME_DOWN_SW#_DSP: R1263.2 R1265.2 UA1.4
VOLUME_UP_SW#: C1123.1 R953.2 RP22.4 U34.N11
VOLUME_UP_SW#_C: JIOL1.35 R953.1 R1264.1
VOLUME_UP_SW#_DSP: R1264.2 R1266.2 UA1.20
VR_A_ENABLE: R1284.1 U689.4
VR_HOT#: PU701.30 R265.2
VR_ON: PU701.8 R1154.1 R1241.1 RC151.1
VR_ON_MCP: RC151.2 UCPU1.F60
VR_SVID_ALRT#: PR736.2 PU701.32 RC94.1
VR_SVID_CLK: PR735.2 PU701.31 RC92.1
VR_SVID_DAT: PR737.2 PU701.1 RC96.1
VREF: PC717.2 PH701.1 PR701.2 PR704.2 PR705.2 PR706.2 PR726.2 PU701.27
VRPG_MCP: RC152.2 UCPU1.C59
VTTREF_+1.2V: PC609.1 PU601.4
WAKE#: RH128.2 RH146.1 U676.2 UCPU1.AJ5
WAKE_PCH#: R604.2 RH128.1 RH310.1 U34.L12
WIN8_BTN_SW#: C1142.1 R977.1 R978.2 RP16.1 U34.H1
WIN8_BTN_SW#_C: JLVDS2.19 R978.1
WL_OFF#: Q344.3 UCPU1.L2
WL_OFF#_R: JNGFF1.48 Q344.1 R1137.2
WLAN_EN: D115.1 R1388.1 U718.3
XCLK_BIASREF: RH113.1 UCPU1.C26
XDP_BPM0#: JXDP.21 UCPU1.J60
XDP_BPM1#: JXDP.23 UCPU1.H60
XDP_DBRESET#: C1237.1 JXDP.48 RH367.1 RH451.1
XDP_PIN60: JXDP.60 R1198.1
XDP_PRDY#: JXDP.5 T263.1(TP-1) UCPU1.J62
XDP_PREQ#: JXDP.3 T264.1(TP-1) UCPU1.K62
XDP_PWRGD: JXDP.39 R1180.2
XDP_TCK0: JXDP.57 RH374.2 RH411.2 RH446.2
XDP_TCK1: JXDP.55 RH373.2
XDP_TDI: JXDP.56 RH371.2 RH414.1
XDP_TDI_SWITCH: RH413.2 RH414.2 U663.10
XDP_TDO: JXDP.52 RH38.2 RH369.2 RH412.2 U663.7
XDP_TMS: JXDP.58 RH372.2 U663.13
XDP_TRST#: JXDP.54 U663.4
XTAL24_IN: CH23.1 RH117.2 UCPU1.A25 YH2.3
XTAL24_OUT: CH24.1 RH117.1 UCPU1.B25 YH2.1
N13303482: PC115.2 PQ105.5 PR124.1
N13303498: PC115.1 PQ105.6 PR126.2
N13303522: PC114.2 PQ104.2 PR108.1
N13303550: PQ105.2 PR123.1 PR125.2
N13303632: PC116.1 PQ106.2 PR110.2
N13305100: PL102.1 PQ101.1 PR105.2
N13305156: PQ103.5 PQ103.6 PR120.1 PR121.2
N13305200: PC113.1 PQ103.2 PR119.2
N13305312: PQ103.3 PR122.2
N13308162: PC208.2 PC209.1 PR202.2 PR206.1
N13308186: PC209.2 PQ201.4 PR203.1
N13308194: PQ201.3 PR201.4
N13308216: PC218.1 PD202.1 PR211.2
N13308220: PC202.1 PC203.1 PC204.1 PC205.1 PL201.2 PL202.2 PQ203.5
N13308316: PQ201.2 PR202.1
N13308376: PQ204.1 PR224.1 PU201.10
N13308392: PD201.1 PR210.1
N13308446: PC227.1 PR216.3 PU201.13
N13308458: PC227.2 PC228.1 PR216.2 PU201.12
N13308964: PC229.1 PQ204.2 PR225.2
N13309974: PQ206.4 PR230.2
N13310108: PQ202.1 PR209.2
N13312034: PR308.2 PU301.4
N13312134: PR318.2 PU302.4
N13315263: PR338.2 PU304.4
N13316609: PR328.2 PU303.4
N13318174: PD302.2 PR341.2
N13324169: PC605.1 PR601.1
N13350623: PC724.1 PR744.2
N13350707: PC719.1 PR730.2
N13350735: PR730.1 PU703.6
N13350791: PC719.2 PU703.7
N13350855: PR717.2 PU701.16
N13350881: PC720.2 PR731.1 PU701.28
N13350885: PC709.1 PH701.2 PR709.2 PU701.14
N13351105: PR721.1 PU701.4
N13351187: PH702.2 PR708.1
N13351357: PL701.2 PR702.2
N13351493: PC715.2 PR725.2 PU701.2
N13353049: PC711.1 PR715.2
N13353061: PR715.1 PU702.6
N13353141: PC711.2 PU702.7
N13353255: PH703.2 PR729.1
N13353293: PL702.2 PR724.2
N13374846: PC503.1 PR506.2
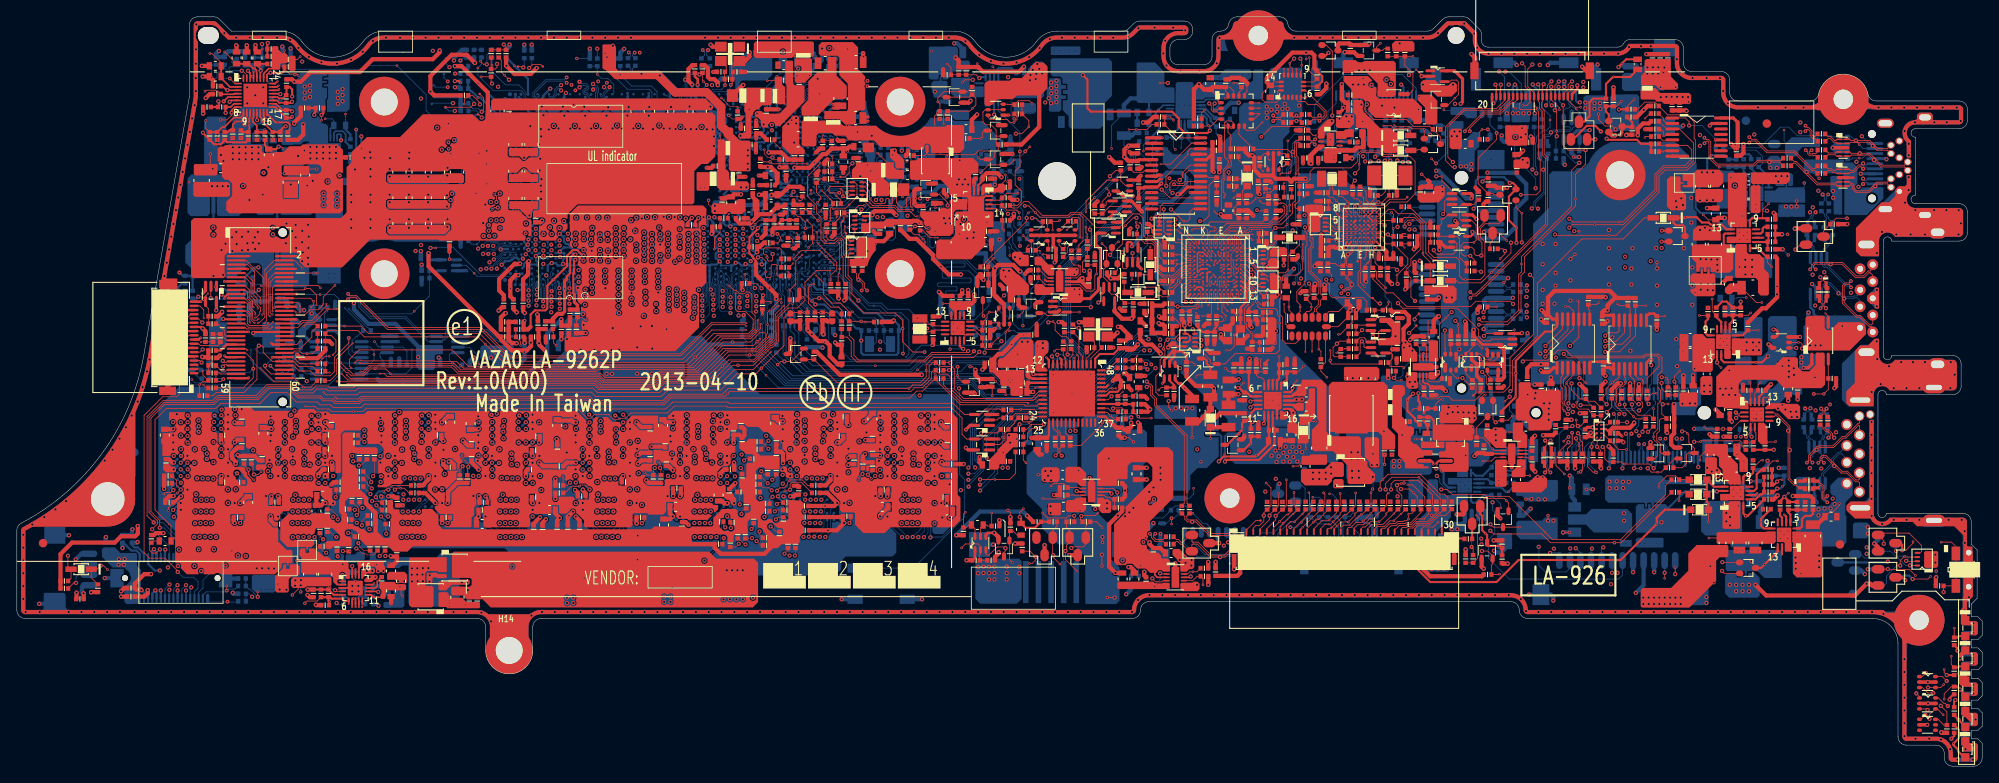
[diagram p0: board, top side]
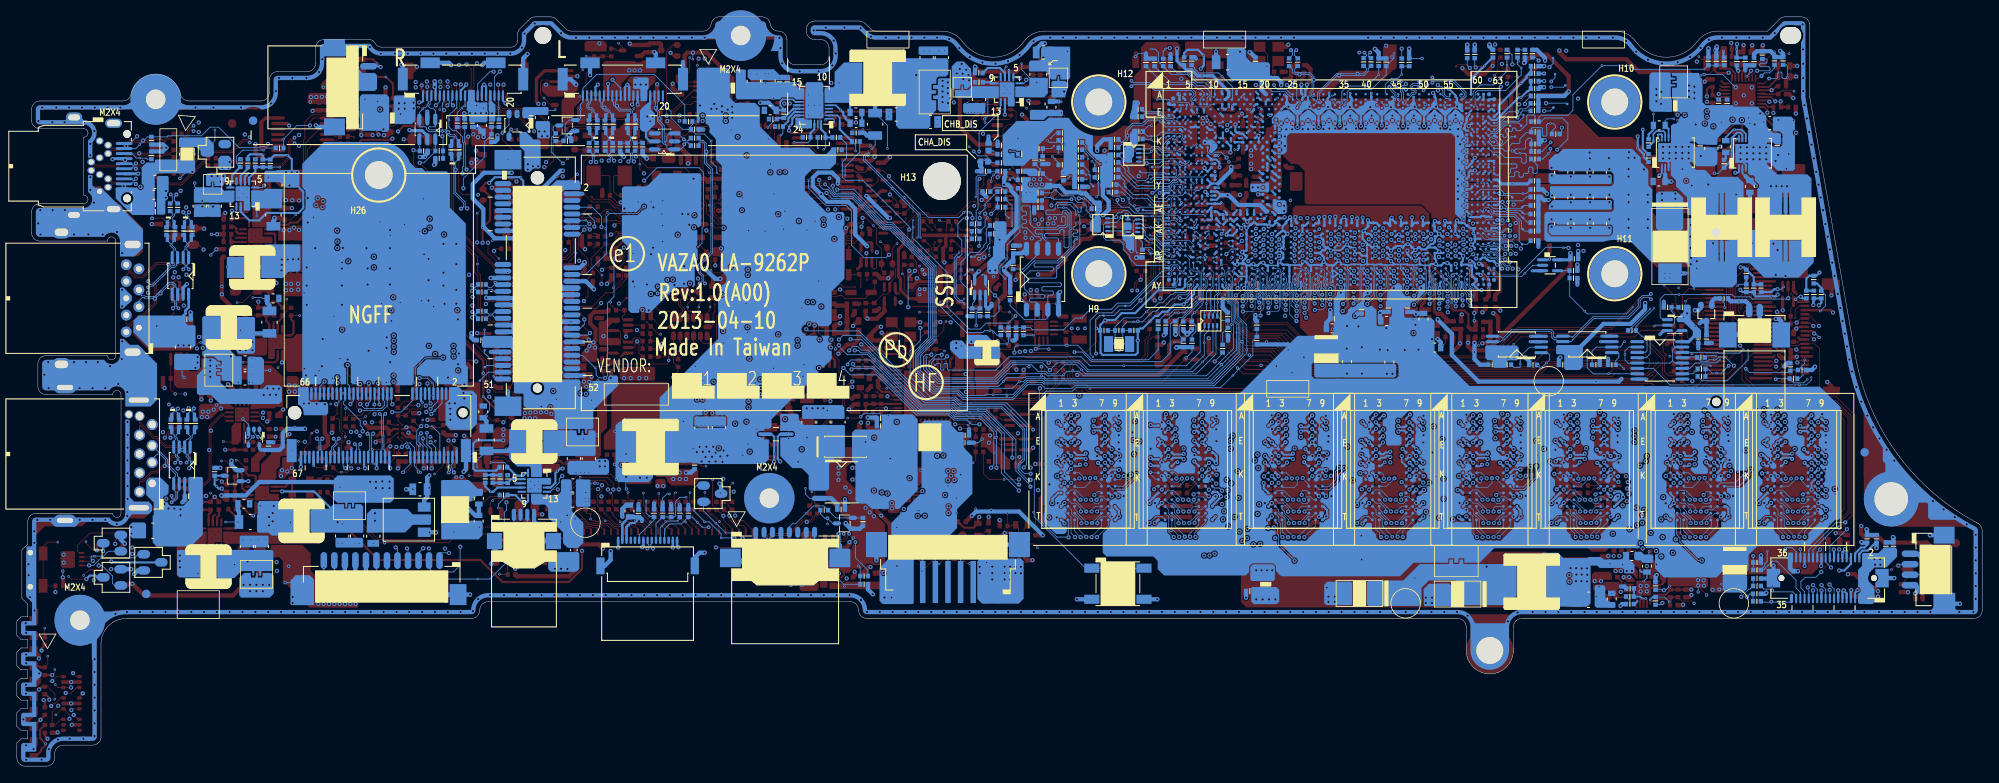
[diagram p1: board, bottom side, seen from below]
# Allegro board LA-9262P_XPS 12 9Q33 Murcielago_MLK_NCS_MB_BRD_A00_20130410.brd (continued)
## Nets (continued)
N13384798: PD301.2 PR342.2
N16935361: JSATA1.45 T244.1(TP-1)
N16935447: JSATA1.47 T245.1(TP-1)
N16940180: JSATA1.38 T243.1(TP-1)
N16940198: JSATA1.36 T242.1(TP-1)
N17638789: Q329.1 R943.1
N17654244: C1160.1 Q326.1 Q329.2 R989.1
N18675747: MC284.1 MR226.2
N18675796: R249.2 U34.J5
N28729492: R1091.2 U638.5
N34287396: MC94.1 MR256.1
N34514472: RH313.2 UCPU1.AP4
N34536136: T123.1(TP-1) UCPU1.AD4
N35032609: CH1206.1 UCPU1.AE7
N36180324: CH1218.1 RH346.2
N39696490: R1118.1 US1.15
N39697285: R1117.1 US1.16
N39815594: T226.1(TP-1) UCPU1.H61
N39815596: T227.1(TP-1) UCPU1.H62
N39815598: T228.1(TP-1) UCPU1.K59
N39815600: T229.1(TP-1) UCPU1.H63
N39815609: T231.1(TP-1) UCPU1.J61
N39815611: T230.1(TP-1) UCPU1.K60
N39955939: R1125.1 U664.8 U664.9
N39956017: C1212.1 U664.12
N39956029: R1318.1 U664.13 U664.14
N39956087: C1214.1 U664.10
N40621945: Q71.1 R536.2
N41042732: R1165.1 US1.7 US1.8
N41155497: R1175.2 U653.8
N41482702: R1188.1 U671.8
N41500627: C1242.1 U673.1
N41500629: R1190.1 U673.15
N41505847: R1191.1 U673.16
N41574995: R1204.1 U677.8
N41624107: R1202.1 R1214.2 R1215.2 R1338.1 U676.1 U709.4
N41625248: C1246.1 Q347.2 R1202.2
N41869823: C1244.1 U673.17
N42153648: R1247.2 U716.3
N42233415: JNGFF1.42 R1255.1
N42542298: R921.1 R1297.1 U34.J6
N42546805: JLVDS2.11 R1279.2
N42775202: Q351.3 RH24.1
N42993790: R1131.1 U679.C2
N43042471: D81.1 JFAN1.2 R886.1
N43454026: R1326.1 U719.13 U719.14
N43467905: Q320.6 Q358.2 R920.1
N43742420: C964.2 U637.13
N43742429: C964.1 U637.12
N44370994: C1257.1 U716.12
N44372336: R1319.1 U716.8 U716.9
N44373242: C1248.1 U716.10
N44377351: C1163.1 U717.12
N44380707: C1202.1 U718.12
N44531503: C355.1 U719.12
N44535135: C1278.1 U719.10
N44536141: R1320.1 U719.8 U719.9
N44948988: RD7.1 UD6.L8
N44951196: RD8.1 UD7.L8
N44953884: RD11.1 UD9.L8
N44956010: RD12.1 UD10.L8
N44984260: RD1.1 UD1.L8
N44985933: RD2.1 UD2.L8
N44994261: RD5.1 UD4.L8
N44996448: RD6.1 UD5.L8
N45067794: CD91.2 RD23.1
N45067802: CD92.2 RD24.1
N45067875: CD89.2 RD16.1
N45134129: RD79.1 UD1.L9
N45134345: RD80.1 UD2.L9
N45134724: RD81.1 UD4.L9
N45134937: RD82.1 UD5.L9
N45136338: RD83.1 UD6.L9
N45136742: RD84.1 UD7.L9
N45137119: RD85.1 UD9.L9
N45137332: RD86.1 UD10.L9
N45346908: C1280.2 R1305.2 R1306.2 U717.6 U717.7
N45346942: C1281.1 U717.10
N45347302: R1128.1 U718.8 U718.9
N45347364: C1292.1 U718.10
N45348400: R1226.1 U718.13 U718.14
N45359755: MC1141.1 MR976.2
N45360524: JSATA1.49 T246.1(TP-1)
N45904951: PC410.1 PC411.1 PJP403.2 PU402.10 PU402.11 PU402.12
N46001630: Q349.3 R1282.2 U688.6
N46001695: Q349.6 R1281.2
N46002340: R1289.2 R1291.2 U690.1
N46318274: D113.1 DPF1.1 RV1.2
N46339533: C1227.1 Q360.4 R1379.2 R1380.2
N46339563: Q361.3 R1379.1
N46339565: Q361.6 R1380.1
N46463118: D74.1 D94.1 R537.1 U636.F6
N47139833: JNGFF1.30 R1200.1 R1208.1
N47140041: PQ300.1 PR301.1 PR347.2
N47180160: JNGFF1.58 R1209.1
N47181052: JNGFF1.32 R1210.1
N47181069: JNGFF1.34 R1212.1
N47519532: R1322.1 U721.1
N47519599: C1230.1 U721.4
N47890214: C1297.1 U722.6
N47890230: R1392.1 U722.7 U722.8
N76702116: C968.1 U637.6
N76768428: C974.1 U638.14
N86178716: LED1.2 R910.1
N86209671: LED2.2 R911.1
N86209740: LED3.2 R912.1
N86209815: LED4.2 R913.1
N86209896: LED5.2 R916.1
N88620271: RTCD1.2 RTCR1.1
N89386241: RD3.2 UD3.1
N89389377: RD4.2 UD3.2
N89456409: RD9.2 UD8.1
N89456446: RD10.2 UD8.2
N90173610: CV1.1 CV2.1 CV14.1 CV15.1 DPF1.2 JMDP1.20 RV1.1
N93297419: Q305.2 U708.4
N93297423: Q305.1 R541.2
N96981838: JBL1.3 R944.2

Pads without a net: D113 3; FD1 1; FD2 1; FD3 1; FD4 1; FD5 1; FD6 1; JAPS 1 2 3; JBATT1 3; JBL1 2; JKB1 28 29; JNFC1 4 5 13; JNGFF1 6 16 36 38 40 50 52 54 56 60 62 63 65; JSATA1 1 3 5 6 7 11 13 17 19 28 30 32 42 46 48; JSNRDG 12; JTP1 6; JXDP 40 42; MD90 4 6; PD104 3; PU301 8; PU302 8; PU303 8; PU304 8; PU305 8; PU401 8; PU402 8; PU501 3 4 27; Q320 3 4 5; RP2 6; RP19 1 8; RP20 2 7; U34 A13 B6 B13; U635 1; U636 A2 B3 B6 C8 D1 E1 E2 E3 F4 G7 H4 H5; U637 8; U652 6 12 13 14; U653 2 3; U663 1 9; U671 6 9; U672 1; U677 6 9; U682 1; U687 1; U708 1; U709 1; U710 1; U712 1; U713 1; U714 1 2 4 5 8 9 10 12 13 16; UA1 22 28 32 33 34 35 36 45 46; UA2 1; UA3 1; UC1 1; UCPU1 A4 A5 A6 A8 A17 A21 A23 A31 A35 A37 A39 A41 A49 A51 A53 A60 A62 AA23 AA59 AB21 AB23 AC2 AC4 AC20 AC58 AC59 AD5 AD23 AD59 AD60 AE59 AE60 AF20 AG58 AJ7 AK38 AL1 AL11 AL32 AL38 AM7 AM10 AM11 AN10 AN11 AP7 AP11 AP13 AP32 AR13 AT2 AU10 AU12 AU15 AU44 AU63 AV1 AV2 AV10 AV44 AV50 AV62 AV63 AW1 AW10 AW14 AW36 AW49 AW63 AY8 AY14 AY36 AY42 AY43 AY60 B2 B6 B14 B17 B21 B22 B23 B31 B35 B37 B38 B39 B41 B43 B49 B50 B51 B53 B54 C15 C17 C21 C22 C23 C30 C31 C37 C42 C43 C46 C47 C49 C50 C51 C53 C62 C63 D1 D9 D11 D15 D17 D58 D61 E1 E5 E6 E8 E10 E13 E15 F5 F6 F8 F10 F15 F17 F22 G1 G10 G15 G17 H6 H8 H10 H18 H22 J6 J8 J20 J21 J58 K10 K18 K21 L11 L59 L60 M20 M21 N6 N23 N58 N59 N60 N61 P20 P60 P61 R20 R23 T23 T59 U10 U59 V21 V59 W23 Y4 Y20 Y22; US1 9; UV1 9 10 11 12 13 14

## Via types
v1: diameter 0.508, hole 0.254, TOP to BOTTOM, 3042 vias
v2: diameter 0.305, hole 0.152, TOP to BOTTOM, 593 vias
v3: diameter 0.457, hole 0.203, TOP to BOTTOM, 156 vias
v4: diameter 0.457, hole 0.203, GND1 to GND5, 890 vias
v5: diameter 0.254, hole 0.102, GND5 to BOTTOM, 551 vias
v6: diameter 0.254, hole 0.102, TOP to GND1, 721 vias
v7: diameter 0.406, hole 0.203, TOP to BOTTOM, 124 vias
v8: diameter 0.508, hole 0.203, TOP to BOTTOM, 240 vias
v9: diameter 0.305, hole 0.102, TOP to GND1, 30 vias
v10: diameter 0.305, hole 0.102, GND5 to BOTTOM, 18 vias

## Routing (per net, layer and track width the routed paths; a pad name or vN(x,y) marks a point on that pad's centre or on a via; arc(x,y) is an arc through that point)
1.2V_DDR_PWROK: length 219.9
  TOP w0.102: v6(84.64,57.11) 85.2,56.55 85.45,56.55 85.86,56.15 86.44,56.15 86.65,56.35 87,56.35 87.33,56.02 87.33,53.91 87.71,53.53 87.71,51.92 87.01,51.22 83.2,51.22 v7(80.58,48.6) 79.75,47.76 68.71,47.76 68.46,47.51 53.66,47.51 51.71,49.47 40.65,49.47 39.53,48.35 39.53,47.54 v6(39.73,47.33) ; R1133.1 144.91,68.71 v6(144.55,68.34) ; PU601.10 v6(41.04,18.91)
  GND1 w0.076: v4(84.22,57.19) 84.3,57.11 v6(84.64,57.11) ; v4(41.33,19.29) 41.04,19 v6(41.04,18.91) ; v6(144.55,68.34) 144.55,68.28 v4(144.84,67.98) ; v6(39.73,47.33) 39.73,47.28 v4(40.04,46.98)
  IN1 w0.076: v4(41.33,19.29) 41.33,19.33 40.81,19.85 31.63,19.85 30.92,19.14 19.17,19.14 17.65,20.66 17.65,21.98 13.3,26.33 13.3,28.35 14.66,29.71 14.66,36.25 16.1,37.68 16.1,42.3 18.38,44.59 25.2,44.59 25.58,44.97 34.04,44.97 35.57,43.44 36.28,43.44 37,44.16 39.06,44.16 39.19,44.29 39.73,44.83 39.73,44.83 40.06,45.16 40.06,46.98 40.04,47 40.01,46.98 v4(40.04,46.98) ; v4(84.22,57.19) 84.27,57.24 84.27,57.85 84.88,58.46 84.88,63.39 84.35,63.92 84.35,64.4 84.6,64.66 84.86,64.66 86.33,66.13 90.19,66.13 90.41,65.91 94.65,65.91 95.41,65.15 95.77,65.15 95.93,65.32 95.93,65.72 95.79,65.86 95.13,65.86 94.76,66.23 94.76,66.88 95.18,67.3 98.92,67.3 99.4,67.78 101.45,67.78 101.56,67.89 102.97,67.89 103.33,67.53 103.33,67.21 104.71,65.84 106.34,65.84 106.7,65.48 107.86,65.48 109.93,63.41 112.68,63.41 113.6,64.33 115.7,64.33 116.05,63.98 119.77,63.98 120.43,63.32 120.43,63.3 120.95,62.78 121.41,62.78 122.61,63.98 124.41,63.98 124.77,64.34 124.97,64.54 128.11,64.54 129.33,65.76 133.12,65.76 134.66,67.3 136.11,67.3 136.28,67.13 138.76,67.13 139.58,67.96 144.81,67.96 v4(144.84,67.98)
1.05V_VREF: length 4.1
  BOTTOM w0.102: PC501.1 139.21,74.41 139.49,74.13 v2(141.14,74.13)
  BOTTOM w0.254: PU501.26 138.75,76.3 138.75,75.69 139.21,75.23 PC501.1
1.05VA_PG: length 36.5
  TOP w0.102: R931.1 150.06,67.32 v6(150.06,67.31)
  GND1 w0.076: v6(150.06,67.31) 149.76,67.02 v4(149.7,67.02)
  IN3 w0.076: v4(136.95,76.54) 136.07,75.67 136.07,70.35 135.39,69.66 135.39,68.16 136.42,67.13 137.55,67.13 140.68,64 142.36,64 144.16,65.8 144.16,66.1 143.25,67.02 143.25,67.44 143.49,67.68 144.11,67.68 144.27,67.53 145.19,67.53 145.96,68.29 146.79,68.29 147.28,68.77 149.27,68.77 149.8,69.3 150.3,69.3 150.39,69.39 150.83,69.39 151.11,69.11 151.11,68.55 149.7,67.14 v4(149.7,67.02)
  GND5 w0.076: v5(136.41,76.54) v4(136.95,76.54)
  BOTTOM w0.102: v5(136.41,76.54) 136.41,76.81 136.53,76.94 PU501.1
1.05VS_PG: length 176
  TOP w0.102: R1353.2 145.13,72.08 D109.1 146.17,69.67 v6(146.13,69.63) ; v1(23.04,55.61) 23.04,57 U672.2 ; RH438.2 97.89,67.27 v6(97.35,67.81)
  GND1 w0.076: v4(97.02,68.11) 97.33,67.81 v6(97.35,67.81) ; v4(146.55,69.52) 146.25,69.52 v6(146.13,69.63)
  IN1 w0.076: v1(23.04,55.61) 23.45,55.21 26.27,55.21 26.86,55.79 29.48,55.79 30.04,56.35 30.63,56.35 32.96,56.35 40.34,63.73 40.34,65.27 41.29,66.22 41.29,68.49 43.63,70.83 43.63,72.15 44.74,73.25 45.24,73.25 51.73,79.74 57.32,79.74 59.4,77.66 60.4,77.66 61.21,76.85 85.15,76.85 86.96,75.04 86.96,74 88.45,72.52 88.93,72.52 89.55,71.89 91,71.89 92.5,70.4 92.5,69.01 92.89,68.62 92.89,67.61 93.21,67.3 94.14,67.3 94.34,67.5 95.96,67.5 96.57,68.11 v4(97.02,68.11)
  IN4 w0.076: v4(97.02,68.11) 97.45,68.54 99.29,68.54 99.9,69.15 101.99,69.15 102.15,68.99 105.82,68.99 106.84,70 109.1,70 109.59,70.5 114.44,70.5 114.92,70.98 118.55,70.98 122.56,66.97 124.68,66.97 126.84,69.13 132.7,69.13 134.37,70.79 135.11,70.79 135.61,71.29 135.61,71.29 135.65,71.32 139.29,71.32 141.41,69.2 144.21,69.2 144.75,69.74 146.34,69.74 v4(146.55,69.52)
  BOTTOM w0.102: U697.1 37.94,53.06 38.26,53.38 38.26,55.52 37.74,56.05 v2(36.04,56.05) 29.7,56.05 29.43,55.78 27.57,55.78 27.3,55.51 23.14,55.51 v1(23.04,55.61)
1.05VS_PG_EC: length 11.9
  TOP w0.102: v6(143.43,67.6) 143.53,67.7 v2(143.53,68.01) 143.33,68.21 143.33,69.49 143.53,69.7 143.53,70.75 143.99,71.21 144.14,71.21 144.29,71.36 144.29,71.83 144.22,71.91 R1353.1 ; U34.A1 145.42,62.61 v6(145.48,62.67)
  GND1 w0.076: v4(145.09,63.14) 145.48,62.75 v6(145.48,62.67) ; v6(143.43,67.6) 143.68,67.35 v4(143.68,67.27)
  IN3 w0.076: v4(145.09,63.14) 145.09,65.6 143.68,67.01 v4(143.68,67.27)
1.5VS_PWROK: length 62.6
  TOP w0.102: v2(112.33,81.25) 112.64,81.57 v1(113.58,81.57) ; R982.1 148.03,66.85 v6(147.67,67.21)
  GND1 w0.076: v6(147.67,67.21) 147.52,67.21 v4(147.21,67.51)
  IN1 w0.076: v4(147.21,67.51) 146.95,67.51 145.61,66.18 144.52,66.18 143.85,66.84 142.69,66.84 141.7,65.85 138.17,65.85 137.24,66.78 135.44,66.78 v4(135.38,66.71)
  IN3 w0.076: v1(113.58,81.57) 114.61,80.53 120.66,80.53 122.61,82.49 122.61,82.85 125.36,85.6 135.19,85.6 135.53,85.26 135.53,83.27 136.16,82.64 136.16,81.55 135.68,81.06 135.68,77.05 134.22,75.59 134.22,67.87 v4(135.38,66.71)
  BOTTOM w0.102: v1(113.58,81.57) 113.58,81.41 113.84,81.15 PU401.4
1.05VS_VCCST_PG: length 54.8
  TOP w0.102: v2(55.09,83.77) 55.46,83.4 v1(55.82,83.4) ; v6(22.71,56.17) 22.41,55.87 U672.4 22.41,54.73 22.75,54.39 R1132.2 R1180.1
  GND1 w0.076: v6(22.71,56.17) v4(23.43,56.17)
  IN1 w0.076: v1(55.82,83.4) 52.6,80.18 51.86,80.18 45.12,73.43 44.66,73.43 43.45,72.22 43.45,70.9 41.12,68.56 41.12,66.29 40.15,65.32 40.15,63.79 32.89,56.53 30.71,56.53 29.97,56.53 29.41,55.97 26.78,55.97 26.68,55.87 26.68,55.86 26.22,55.41 24.19,55.41 v4(23.43,56.17)
  BOTTOM w0.102: v1(55.82,83.4) 55.85,83.43 55.85,84.52 RC150.1
1.5VSP_FB: length 5.8
  TOP w0.102: v1(114.36,81.78) 113.96,82.17 PC404.2 PR407.2 110.99,82.17 PR408.1 110.98,82.99 v2(110.54,83.44)
  BOTTOM w0.254: v1(114.36,81.78) 114.47,81.89 PU401.5
1.8VS_PWROK: length 62.9
  TOP w0.102: v2(157.02,51.32) 157.25,51.32 R934.1 158.19,52.29 v6(158.67,52.77)
  GND1 w0.076: v4(158.67,53.25) v6(158.67,52.77)
  IN2 w0.076: v4(171.83,62.47) 172.1,62.75 185.15,62.75 185.49,63.09 193.39,63.09 196.2,65.9 201,65.9 204.1,69 v1(204.11,69)
  IN3 w0.076: v4(158.67,53.25) 158.81,53.11 161.16,53.11 161.75,53.71 167.48,53.71 168.41,52.78 169.67,52.78 169.96,52.49 171.08,52.49 171.83,53.24 171.83,56.97 171.18,57.62 171.18,61.82 v4(171.83,62.47)
  BOTTOM w0.102: PU402.4 204.34,68.77 v1(204.11,69)
3VALW_PG: length 4.3
  TOP w0.254: PU305.4 205.13,30.03 v3(205.4,29.76) 205.66,29.76 PR348.2
5VA_EN: length 223.7
  TOP w0.076: v6(144.2,61.3) 144.52,61.3 144.82,61.6 U34.B2
  TOP w0.102: RH309.1 98.9,51.2 99.46,50.63 99.46,48.82 100.03,48.25 107.78,48.25 108.69,49.16 112.85,49.16 v1(113.02,49.34) ; v2(176.8,43.36) 177.35,43.9 v1(177.36,43.9) ; v1(202.64,24.24) 202.67,24.21 PD307.2
  GND1 w0.076: v4(144.43,61.81) 144.22,61.6 144.22,61.32 v6(144.2,61.3)
  IN1 w0.076: v1(113.02,49.34) 113.02,43.84 111.89,42.71 111.89,37.71 112.77,36.83 113.74,36.83 118.71,31.85 118.71,28.33 126.14,20.9 188.68,20.9 v1(189.4,21.63) ; v1(177.36,43.9) 176.93,44.34 176.93,47.4 171.92,52.41 170.81,52.41 170.05,53.17 170.05,54.27 169.4,54.91 169.4,56.38 168.55,57.23 168.55,59.8 165.14,63.21 164.25,63.21 163.35,62.31 163.34,62.32 157.7,62.32 157.42,62.04 154.43,62.04 153.84,62.62 153.23,62.62 152.24,63.61 152.24,63.9 151.82,64.33 151.4,64.33 150.06,62.99 147.91,62.99 147.52,63.39 146.81,63.39 145.89,62.47 145.26,62.47 144.6,61.81 v4(144.43,61.81)
  IN2 w0.076: v1(202.64,24.24) 202.64,30.68 196.88,36.44 180.82,36.44 180.12,37.13 179.62,37.13 178.73,38.02 178.73,42.53 v1(177.36,43.9)
  IN3 w0.076: v1(189.4,21.63) 189.86,22.09 198.44,22.09 200.6,24.24 v1(202.64,24.24)
5VS_EN: length 6.6
  TOP w0.102: U717.3 135.92,22.84 v1(135.83,22.92)
  BOTTOM w0.102: v1(135.83,22.92) 135.83,22.2 135.25,21.62 R1027.1 R1146.2 133.29,23.58 v2(133.52,23.81)
+0.6VSP:
  vias: v7(38.72,23.99)
+0.675VS: length 16.7
  TOP w0.508: 80.07,26.38 RD40.2 82.91,25.95 83.62,25.23 88.83,25.23 89.54,25.95 RD42.2 ; 42.63,27.34 RD29.2 42.63,29.25 42.59,29.29 RD37.2 42.59,30.11 41.9,30.8 41.89,30.8 41.49,31.2 41.49,31.81 41.03,32.27 RD71.2
  vias: v7(73.77,27.39)
+1.2V_B+: length 11
  IN1 w1.016: v1(53.58,20.92) 51.63,20.92 49.98,19.27 44.01,19.27
  BOTTOM w0.508: v1(42.97,19.06) 42.77,19.27 PR611.1
  vias: v1(84.35,23.28) v1(84.98,23.28) v1(85.62,23.28) v1(86.25,23.28) v7(73.73,24.55)
+1.2V_FB: length 6.7
  TOP w0.102: v7(34.22,19.35) 34.49,19.62 35.68,19.62 PR608.1
  TOP w0.203: 38.84,19.7 38.92,19.62 PU601.6
  TOP w0.254: 38.84,19.7 38.64,19.9 37.42,19.9 37.24,20.08 PC614.1 ; PR610.1 37.09,19.56 37.03,19.62 PC614.1 ; PC614.1 PR608.1
+1.2V_TON: length 2.1
  TOP w0.203: v6(40.64,18.94) PU601.9
  GND1 w0.203: v6(40.64,18.94) 40.64,19.25 40.62,19.27 v4(40.62,19.39)
  GND5 w0.203: v4(40.62,19.39) 40.82,19.6 v5(40.95,19.6)
  BOTTOM w0.203: PR611.2 41.28,19.27 v5(40.95,19.6)
+1.2VP: length 25.7
  TOP w0.203: PU601.5 38.09,20.37
  TOP w0.254: PC615.1 PR608.2 PC614.2 37.03,20.99 37.64,20.37 38.09,20.37
  TOP w0.508: v1(34.55,20.99) PC615.1
  IN1 w0.508: 37.28,22.35 35.92,20.99 v1(34.55,20.99) ; 41.57,24.32 45.65,24.32 46.18,24.85 57.73,24.85 v1(58.87,23.71)
  vias: v2(67.41,22.36)
+1.2VS_DVDD: length 15.7
  TOP w0.254: 129.84,41.02 129.32,41.54 UA1.37 ; UA1.25 122.61,39.28 CA5.1 ; UA1.1 128.11,48.43 128.67,48.98 130.31,48.98 CA4.1
  TOP w0.508: v1(132.38,40.81) 132.39,40.79 132.39,40.35 CA1.1 131.59,39.97 131.34,40.22 CA6.1 130.64,40.22 129.84,41.02 ; v6(120.52,39.01) CA3.1 121.23,39.03 CA5.1 ; CA4.1 132.02,49.67 CA2.1 132.65,49.56 133.17,50.07 133.17,50.12 v1(133.18,50.12)
  GND1 w0.508: v6(120.52,39.01) 120.52,38.49 v4(120.47,38.44)
  vias: v1(119.44,50.43) v1(120.1,50.43) v2(118.9,48.96)
+1.05VA: length 96.5
  IN2 w0.508: v1(51.53,67.27) 51.43,67.17 50.74,67.17 50.21,67.7 50.21,71.11 49.7,71.61 49.7,73.63 51.98,75.92 55.12,75.92 57.37,78.17 57.37,78.88 58.03,79.54 62.99,79.54 63.44,79.08 75.38,79.08 75.81,78.65 75.81,78.09 76.4,77.51 82.62,77.51 83.97,76.16 83.97,75.4 85.47,73.9 v4(85.99,73.9)
  IN3 w0.508: v4(85.99,73.9) 86.32,74.23 88.08,74.23 88.77,73.54 90.6,73.54 91.02,73.95 91.02,74.65 91.92,75.56 92.62,75.56 93.56,76.49 94.88,76.49 95.41,77.03 96.77,77.03 97.15,77.41 97.15,81.29 98.29,82.44 106.46,82.44 108.33,80.57 108.33,78.68 111.98,75.03 111.98,72.6 v4(113.18,71.4)
  BOTTOM w0.508: RH445.1 RH375.1 RH39.1 RH40.1 RH38.1 52.45,67.65 52.06,67.27 v1(51.53,67.27)
  vias: v1(111.72,69.13) v1(111.68,64.96) v1(111.92,69.74) v1(112.11,64.43) v1(112.36,69.13) v1(112.66,69.74) v1(112.91,62.73) v1(113.02,69.13) v1(113.65,62.8) v1(113.7,63.44) v1(122.61,79.38) v1(122.88,81.25) v1(122.88,80.59) v1(122.88,79.96) v1(122.87,78.79) v1(123.51,81.46) v1(123.51,80.81) v1(123.51,80.18) v1(123.51,79.54) v1(123.51,78.91) v7(112.03,72)
+1.05VDX_MODPHY:
  vias: v7(99.89,75.37)
+1.05VDX_MODPHY_D: length 2.9
  TOP w0.102: R300.2 v2(114.56,74.6) 114.71,74.75 114.71,75.35 114.89,75.53 Q39.1
+1.5VS: length 110.2
  TOP w0.102: v1(113.89,47.1) 113.51,47.49 v7(113.25,47.49)
  TOP w0.508: v1(113.89,47.1) 113.89,46.49 114.37,46.01 R296.1 ; v1(132.07,23.66) 132.34,23.66 132.77,23.23 R1305.1
  IN1 w0.508: v1(113.89,47.1) 113.89,46.51 115.91,44.49 115.91,38.3 118.42,35.79 118.42,34.1 121.51,31.01 121.51,29.3 123.92,26.89 125.64,26.89 128.86,23.66 v1(132.07,23.66)
  IN3 w0.508: v1(113.89,47.1) 113.89,47.4 114.55,48.06 116.42,48.06 118.28,49.92 118.28,50.85 119.04,51.61 119.04,57.26 121.5,59.72 121.5,61.44 121.14,61.8 120.1,61.8 119.45,62.45 118.65,62.45 114.88,66.22 114.88,70.57 112.64,72.81 112.64,75.31 109.07,78.88 v1(109.07,80.16) 109.07,80.68 106.56,83.2 97.58,83.2 93.91,79.53 93.91,78.17 93.43,77.69 91.93,77.69 90.94,76.7 90.94,75.76 90.13,74.94 89.12,74.94 v4(88.67,74.49)
  GND5 w0.254: v5(87.93,74.63) 88.52,74.63 v4(88.67,74.49)
  BOTTOM w0.254: UCPU1.J15 v5(87.93,74.63)
+1.05VS: length 134.9
  TOP w0.508: CH39.1 v3(90.61,71.16) ; CH1233.1 85.45,64.94 85.88,64.5 87.12,64.5 v1(87.31,64.69) 87.82,65.2 ; 87.82,65.2 88.21,65.6 89.42,65.6 CH1223.1 91.09,66.51 CH1222.1 ; 87.82,65.2 RH340.1 87.82,67.27 87.43,67.65 CH1215.1 ; v1(118.87,67.3) 118.24,67.3 C1244.2 ; R1190.2 118.45,65.32 v1(118.45,65.65) ; v1(22.03,48.65) 22.08,48.6 22.67,48.6 22.75,48.53 CH1.1 22.75,48.52 22.75,49.4 RH51.1
  TOP w1.016: 70.24,83.17 71.27,82.14 76.14,82.14 78.21,80.07 81.96,80.07 83.69,78.35 83.69,76.11 84.47,75.32
  IN1 w0.508: v1(47.37,61.23) 46.81,61.79 42.49,61.79 40.06,59.36 v4(40.06,56.5)
  IN2 w0.508: v1(110.99,64.48) 111.78,63.69 112.78,63.69 113.44,64.35 117.36,64.35 118.45,65.44 v1(118.45,65.65) ; v1(47.37,61.23) 46.87,61.72 46.87,63.28 47.37,63.78 47.37,74.66 51.14,78.44 51.14,79.22 51.79,79.87 52.85,79.87 55.55,82.57 58.41,82.57 59.75,83.91 69.11,83.91 v1(70.81,85.61)
  IN3 w0.508: v1(118.87,67.3) 118.45,66.88 v1(118.45,65.65)
  IN4 w0.508: v4(40.06,56.5) 39.83,56.73 35.63,56.73 33.04,54.14 32.66,54.14 31.97,53.45 31.97,52.34 31.16,51.52 29.33,51.52 28.49,50.69 26.59,50.69 24.8,48.89 22.27,48.89 v1(22.03,48.65)
  GND5 w0.254: v4(85.11,66) 84.93,65.82 v5(84.37,65.82) ; v4(91.66,65.42) 91.54,65.3 v5(91.54,65.01) ; v5(88.93,64.72) 88.8,64.72 88.51,64.44 v4(88.51,64.44) ; v5(84.94,71.21) v4(85.74,71.21)
  GND5 w0.305: v5(90.61,74.66) 90.46,74.51 v4(90.46,74.26)
  BOTTOM w0.254: UCPU1.AG17 86.99,65.06 87.31,64.74 v1(87.31,64.69) 87.68,65.06 UCPU1.AG16 ; v3(90.61,71.16) 90.62,71.17 90.62,71.72 90.99,72.09 UCPU1.P9 91.59,72.12 UCPU1.N8 ; UCPU1.H11 UCPU1.J11 90.58,74.63 v5(90.61,74.66) ; UCPU1.AG14 88.59,65.06 v5(88.93,64.72) 89.27,65.06 UCPU1.AG13 ; UCPU1.AE8 92.04,65.93 UCPU1.AE9 UCPU1.AF9 91.54,65.36 v5(91.54,65.01) 91.64,64.91 92,64.91 UCPU1.AG8 ; v1(88.73,76.26) 88.73,75.45 88.56,75.28 UCPU1.H15 88.19,75.17 87.88,75.17 87.35,74.65 UCPU1.J17 ; UCPU1.T21 v5(84.94,71.21) UCPU1.R21 ; v5(84.37,65.82) 84.27,65.82 84.04,65.6 84.04,65.55 UCPU1.AF22
  vias: v1(86.85,71.6) v1(86.85,70.95) v1(86.85,73.19) v1(86.85,72.55) v1(110.15,65.13) v1(110.33,64.5) v1(110.8,65.1) v3(87.94,77.56) v7(70.11,84.26)
+1.5VS_3.3VS_AUDIO: length 226.2
  TOP w0.254: UA1.9 124.11,48.32 v6(123.95,48.49) ; v1(88.04,63.94) 88.04,63.85 87.04,62.85 87.04,61.75 CH85.1 87.03,60.95 87.46,60.52 87.46,60.41 87.81,60.06 87.81,59.8
  TOP w0.381: UA3.5 113.03,37.58 v1(112.76,37.85) ; v3(112.76,39.99) 113.26,40.5 UA2.5
  TOP w0.508: 87.81,59.8 87.81,58.43 v7(89.42,56.82) 90.23,56.01 90.23,55.54 v1(90.24,55.54) ; CA22.1 v1(134.23,35.46) ; Q351.1 91.9,49.29 v1(91.9,50.85)
  GND1 w0.254: v6(123.95,48.49) 123.92,48.46 v4(123.92,47.87)
  IN1 w0.508: v1(112.76,37.85) v3(112.76,39.99)
  IN2 w0.508: 82.11,65.87 81.22,66.76 60.14,66.76 59.89,66.51 59.86,66.51 v4(59.05,65.7) ; v1(134.23,35.46) 133.98,35.71 119.32,35.71 114.75,40.28 113.21,40.28 112.92,39.99 v3(112.76,39.99) 111.45,41.3 111.44,41.3 107.46,45.28 95.66,45.28 91.9,49.04 v1(91.9,50.85) 91.94,50.89 91.94,55.74 91.38,56.3 90.98,56.3 90.24,55.56 v1(90.24,55.54)
  IN3 w0.508: v4(123.92,47.87) 123.92,47.73 124.33,47.32 127.46,47.32 128.47,46.32 128.47,43.19 134.23,37.43 v1(134.23,35.46) ; v1(12.55,25.92) 13.97,27.34 14.4,27.34 15.03,27.98 15.03,29.45 16.56,30.98 16.56,41.24 21.41,46.09 22.04,46.09 23.49,47.54 23.49,48.2 24.53,49.24 25.12,49.24 26.61,50.74 28.85,50.74 29.28,51.17 30.54,51.17 31.14,51.77 32.35,51.77 33.35,52.77 34.98,52.77 37.01,54.79 37.5,54.79 37.92,55.21 37.92,55.77 39.31,57.16 40.28,57.16 42.21,55.23 45.44,55.23 54.68,64.48 54.68,64.73 55.49,65.54 58.9,65.54 v4(59.05,65.7)
  IN4 w0.508: v1(134.23,35.46) 133.55,34.77 133.55,32.25 135.52,30.28 138.74,30.28 140.92,28.1 144.92,28.1 146.29,26.73 146.29,23.18 145.38,22.28 140.95,22.28 v1(140.23,21.55)
  BOTTOM w0.254: C1279.1 12.67,26.56 13.61,25.62 14.21,25.62 14.6,25.23 JIOL1.4 ; UCPU1.AH14 88.48,64.38 v1(88.04,63.94)
  BOTTOM w0.508: RH42.1 90.24,54.48 v1(90.24,55.54) ; v1(12.55,25.92) 12.55,25.92 12.55,26.55 C1279.1
+1.05VS_B+:
  vias: v2(143.59,79.36)
+1.5VS_D: length 2.3
  TOP w0.102: v2(115.88,44.03) R296.2
  TOP w0.508: Q34.1 115.2,45.05 115.25,45.1 R296.2
+1.5VS_FSW: length 4.4
  BOTTOM w0.102: v2(115.95,83.12) 116.11,82.96 116.11,82.37
  BOTTOM w0.254: PR411.1 118.16,82.97 116.7,82.97 116.11,82.37 PU401.7
+1.05VS_VCCST: length 152.9
  TOP w0.076: 82.61,66.33 82.19,66.75 v7(82.19,67.25)
  TOP w0.508: v1(24.38,53.99) 24.38,53.95 23.9,53.47 R1132.1 ; R1179.1 49.59,79.72 v1(49.13,80.18) 49.13,82 51.67,84.54 53.45,84.54 v1(54.41,83.58) ; R1211.1 58.13,83.25 v1(58.16,83.22) 59.13,82.26 61.06,82.26 v1(61.75,82.96)
  IN1 w0.508: v1(31.54,85.51) 31.34,85.71 30.61,85.71 29.9,84.99 v1(24,84.99)
  IN3 w0.508: v4(19.43,53.1) 21,53.1 21.77,53.87 22.9,53.87 23.26,53.51 23.98,53.51 24.38,53.91 v1(24.38,53.99) ; v1(54.41,83.58) 54.41,84.28 53.59,85.1 51.25,85.1 49.32,83.17 40.18,83.17 39.47,82.46 34.08,82.46 32.02,84.52 32.02,84.84 31.54,85.32 v1(31.54,85.51)
  IN4 w0.508: 49.4,79.57 52.13,76.83 52.13,74.55 v1(51.96,74.38) ; v4(19.43,53.1) 18.59,53.94 18.59,59.98 19.43,60.82 19.43,64.5 20.57,65.65 20.57,71.49 21.38,72.3 21.38,75.76 23.18,77.56 23.18,84.18 v1(24,84.99) ; v1(82.93,65.96) v1(82.93,66.6) 84.39,68.05 84.39,77.44 82.67,79.16 79.28,79.16 77.86,80.58 73.07,80.58 71.12,82.54 62.17,82.54 v1(61.75,82.96)
  BOTTOM w0.508: RC95.1 52.67,75.37 52.67,73.95 ; RC93.2 52.67,73.95 ; 52.67,73.95 52.23,74.38 v1(51.96,74.38) ; v1(49.13,80.18) 49.67,79.64 RC45.2 52.73,79.61 RC46.2 RC48.2 ; v1(54.41,83.58) 54.32,83.67 RC149.2 ; RC43.2 31.59,85.27 31.54,85.32 v1(31.54,85.51) ; PC721.1 27.1,84.63 26.77,84.96 PR735.1 25.14,84.96 24.67,84.49 PR736.1 PR737.1 23.65,84.64 v1(24,84.99)
+1.05VS_XDP: length 13.5
  TOP w0.102: JXDP.44 33.26,50.11 v2(33.74,50.58)
  TOP w0.279: RH51.2 24.2,49.4 v6(24.49,49.7) 24.9,50.11 JXDP.43 ; v6(30.23,50.28) 30.41,50.11 JXDP.44
  GND1 w0.254: v6(24.49,49.7) 24.52,49.7 24.94,50.11 v4(24.94,50.18) ; v4(29.55,50.18) 29.57,50.2 30.16,50.2 v6(30.23,50.28)
  IN2 w0.508: v4(24.94,50.18) 25.8,49.31 29.13,49.31 29.55,49.73 v4(29.55,50.18)
+1.5VSP: length 23.1
  TOP w0.508: v1(119.65,83.12) 119.07,82.54 114.76,82.54 114.22,83.08 PC404.1 PR407.1 111.89,83.86 v1(111.54,84.21)
  IN3 w0.508: v1(116.11,77.43) 115.44,78.1 112.76,78.1 110.94,79.92 110.94,81.4 110.57,81.77 110.57,83.82 110.97,84.21 v1(111.54,84.21)
  BOTTOM w0.254: v1(116.11,77.43) 116.11,78.12 116.1,78.13 116.1,78.9 PU401.14
  BOTTOM w0.508: PR411.2 119.67,82.99 119.65,83.01 v1(119.65,83.12)
  vias: v2(108.68,84.95)
+1.05VSP: length 23.3
  TOP w0.254: v1(141.75,75.54) 141.46,75.25 138.77,75.25 138.08,75.93 138.08,76.95 137.24,77.79 127.6,77.79 127.2,78.19 127.2,81.58 v1(126.65,82.13)
  BOTTOM w0.254: v1(141.75,75.54) 141.75,75.98 v2(141.57,76.16) 141.37,76.37 141.37,76.96 141,77.34 PU501.22
+1.5VSP_LX: length 3.3
  BOTTOM w0.102: PL401.1 112.68,81.34 114.12,82.78 v2(114.12,83.48)
+1.5VSP_VIN: length 2.8
  BOTTOM w0.102: v7(118.5,76.92) 118.13,77.29 118.13,79.62
+1.8VP: length 20.3
  BOTTOM w0.254: 200.25,69.05 199.46,68.26 199.46,66.33 200.04,65.75 203.82,65.75 204.71,64.86 205.86,64.86 206.9,65.9 PU402.14 ; PR424.2 206.05,72.47 205.81,72.71 204.44,72.71 204.27,72.54 PR419.1 PC412.1 202.88,72.61 v2(201.31,72.61) 200.83,72.12 v1(200.83,70.57)
  vias: v1(200.2,70.57) v1(201.11,69) v1(201.52,70.57)
+1.8VS: length 182.7
  TOP w0.102: R1364.1 186.01,35.19 v7(185.8,34.98)
  TOP w0.254: U679.C1 187.67,39.56 187.21,39.1 186.49,39.1
  TOP w0.381: U671.1 189.43,47.21 189.26,47.38 188.77,47.38 C1286.1 ; v1(190.88,38.49) 190.7,38.67 R1131.2 ; U677.1 182.98,47.35 182.56,47.35 182.06,46.85 C1288.1
  TOP w0.508: R1368.1 188.23,45.19 v1(188.74,45.69) ; v1(188.22,35.39) 188.16,35.46 R1327.1 R1328.1 ; v1(190.57,45.49) 190.2,45.49 189.49,44.78 R1369.1 ; R1371.1 192.72,44.63 v1(192.72,45.4) ; v1(185.69,41.95) R1365.1 ; v1(185.15,35.39) 185.12,35.42 R1363.1 R1364.1 ; v1(181.07,47.03) 181.25,46.85 C1288.1 ; C1286.1 188.49,46.66 v1(188.74,46.41) ; R1360.1 v1(184.7,41.16) ; v1(194.85,51.88) 194.84,51.89 R1188.2 ; v1(184.22,35.39) R1362.1 R1361.1 ; RH350.2 v6(98.19,70.51) ; C1284.1 186.49,39.1 186.98,39.59 v1(186.98,39.64) ; R1204.2 188.72,55.77 v1(188.77,55.71) ; v1(191.68,45.48) 191.66,45.47 R1370.1
  GND1 w0.508: v6(98.19,70.51) v4(98.19,71.01)
  IN1 w0.508: v4(113.44,39.54) 113.44,39.37 115.92,36.89 115.92,35.27 120.9,30.29 120.9,28.71 123.87,25.74 123.87,24.35 126.64,21.58 136.72,21.58 138.32,23.18 141.33,23.18 143.21,21.3 184.98,21.3 v4(185.01,21.32)
  IN3 w0.508: v4(98.19,71.01) 98.19,71.5 98.97,72.28 99.56,72.28 100.62,71.22 100.62,70.86 101.14,70.34 101.14,69.59 102,68.73 103.54,68.73 103.86,69.05 103.86,70.37 103.74,70.48 103.74,71.22 104.39,71.88 104.39,72 104.87,72.48 107.78,72.48 109.39,70.87 109.39,67.27 108.27,66.15 108.27,56.44 105.89,54.05 105.89,50.03 110,45.91 111.86,45.91 113.44,44.32 v4(113.44,39.54)
  IN4 w0.508: v4(186.23,34.18) 187.12,34.18 189.02,32.27 191.18,32.27 192.02,31.43 192.02,26.81 186.53,21.32 v4(185.01,21.32)
  vias: v1(197.11,67.14) v1(197.19,66.43) v1(197.75,67.48) v1(197.95,66.69)
+1.8VSP_LX: length 1.2
  BOTTOM w0.102: v2(205,65.38) 205,66.54
+1.35V_DDR: length 60.4
  TOP w0.508: CD85.1 110.47,38.9 ; v1(48.91,60.97) 48.91,59.41 57.31,51.02 RD13.1 57.51,50.71 58.81,49.42 60.59,49.42 61.09,49.92 61.09,50.3 v1(61.07,50.33) RD18.1 ; v1(65.36,50.75) 65.59,50.99 RD17.1
  IN1 w0.457: v1(102.43,36.28) 102.43,36.19 103.44,35.19 v1(103.44,34.46)
  IN1 w0.508: v1(44.12,29.67) 44.12,31.05 43.29,31.88 v1(43.29,32.04) ; v1(61.07,50.33) 61.07,44.12 63.44,41.74 63.44,38.52 64.69,37.27 v1(65.34,37.27)
  IN2 w0.508: v1(84.38,34.47) 84.38,36.05 v1(84.39,36.06) ; v1(97.47,34.46) 97.63,34.46 98.11,34.95 98.11,35.71 97.74,36.08 v1(97.47,36.08)
  BOTTOM w0.178: UCPU1.AN33 76.52,62.01 76.46,62.01 v1(76.43,61.99)
  BOTTOM w0.203: UD1.K8 20.28,33.67 20.28,32.87 v1(20.27,32.86)
  BOTTOM w0.254: v1(84.38,34.47) 84.36,34.47 83.99,34.1 UD7.K2 ; UCPU1.AR48 68.3,60.86 v1(68.3,61.25) ; UCPU1.AH26 81.59,64.75 v1(81.59,65.24) ; UCPU1.AJ33 v1(76.85,65.29) ; UCPU1.AJ37 v1(74.25,65.09) ; v1(70.24,60.65) 70.26,60.67 70.41,60.67 UCPU1.AP43 ; UD6.G7 68.42,36.47 v1(68.02,36.87) ; UCPU1.AJ31 v1(78.15,65.26) ; UD2.K2 36.24,34.07 v1(36.64,34.47)
  BOTTOM w0.381: CC240.1 49.03,60.17 UC1.5
  BOTTOM w0.508: 81.88,49.49 82.51,50.11 RC75.1 ; CC240.1 v1(48.91,60.97)
  vias: v1(18.57,39.32) v1(18.57,38.47) v1(18.58,37.63) v1(18.64,35.27) v1(19,41.83) v1(19.47,31.27) v1(19.49,30.46) v1(20.26,36.87) v1(25.08,41.77) v1(25.08,40.86) v1(25.09,40.07) v1(25.09,37.66) v1(25.09,36.06) v1(25.09,34.47) v1(25.89,31.27) v1(26.72,42.43) v1(28.51,23.51) v1(29.14,23.51) v1(29.6,32.11) v1(29.9,23.51) v1(30.02,36.39) v1(30.14,41.57) v1(30.13,38.65) v1(30.18,39.33) v1(30.55,23.48) v1(31.05,34.48) v1(31.03,29.66) v1(32.79,36.79) v1(35.84,40.86) v1(36.63,41.85) v1(36.65,40.07) v1(36.63,36.06) v1(37.45,36.87) v1(37.59,31.23) v1(43.18,41.4) v1(43.2,36.08) v1(43.31,39.28) v1(43.31,38.49) v1(44.13,34.46) v1(44.92,36.88) v1(49.71,41.77) v1(49.71,40.86) v1(49.73,40.07) v1(49.73,36.07) v1(49.71,34.46) v1(50.53,31.27) v1(50.7,37.6) v1(54.25,32.12) v1(54.81,41.57) v1(54.82,39.33) v1(54.85,38.47) v1(54.78,37.78) v1(54.76,36.28) v1(55.67,34.48) v1(55.68,29.68) v1(56.46,36.87) v1(61.27,41.77) v1(61.27,40.86) v1(61.28,40.07) v1(61.27,36.06) v1(61.28,34.46) v1(61.28,30.47) v1(62.08,36.87) v1(62.08,31.27) v1(66.38,41.64) v1(66.38,39.33) v1(66.4,38.47) v1(66.39,35.27) v1(66.65,56.84) v1(66.97,49.5) v1(67.24,34.48) v1(67.24,31.28) v1(67.24,30.47) v1(67.34,52.44) v1(68.61,49.46) v1(69.92,56.8) v1(70.64,49.44) v1(70.8,52.06) v1(71.56,49.49) v1(72.83,40.86) v1(72.84,40.07) v1(72.84,36.07) v1(72.83,34.47) v1(73.03,56.22) v1(73.63,31.27) v1(73.7,49.77) v1(73.69,37.71) v1(74.11,52.26) v1(75.46,52.31) v1(75.5,49.62) v1(76.2,56.28) v1(77.32,32.09) v1(77.64,39.23) v1(77.69,38.57) v1(77.84,36.51) v1(77.97,41.63) v1(78.79,34.46) v1(78.79,29.66) v1(79.57,36.87) v1(83.6,40.87) v1(84.41,41.7) v1(84.37,40.07) v1(84.38,36.87) v1(85.22,31.26) v1(90.96,41.62) v1(91,40.03) v1(90.98,38.62) v1(90.98,35.27) v1(91.08,32.06) v1(91.88,34.46) v1(93.59,36.97) v1(97.47,40.86) v1(97.48,40.07) v1(98.28,31.27) v1(98.8,37.73) v1(100.95,39.66) v1(101.99,32.1) v1(102.53,37.67) v1(102.57,41.64) v1(102.57,39.33) v1(102.6,38.47) v1(103.43,29.66) v1(105.16,36.85) v1(109.02,41.77) v1(109.02,40.86) v1(109.04,40.07) v1(109.03,36.08) v1(109.02,34.46) v1(109.84,31.27) v1(109.85,36.88) v1(109.95,29.55) v1(110.81,33.49) v7(77.2,51.93)
+3.3VDX_SSD: length 2
  TOP w0.508: R1366.1 162.92,46.15 v1(162.94,46.14)
  BOTTOM w0.102: C722.1 v2(177.92,51.85)
  vias: v1(169.84,55.68) v1(170.5,55.69) v1(171.37,49.54) v1(171.61,48.68) v3(169.36,68.86) v3(169.4,68.28)
+3.3VDX_SSD_LX: length 6.5
  BOTTOM w0.102: PR334.1 178.84,36.33 v2(178.84,35.55)
  BOTTOM w0.508: PL307.1 175.17,37.46 PR334.1
+3.3VDX_SSD_VIN:
  vias: v7(168.1,29.79)
+3.3VDX_SSDP: length 17.5
  IN4 w0.254: v4(175.61,34.96) 175.61,34.94 174.96,35.59 168.87,35.59 v1(168.65,35.37) 168.63,35.39 168.07,35.39 167.38,36.08 167.38,36.61 168.32,37.55 v4(168.65,37.55)
  GND5 w0.254: v4(175.61,34.96) 175.7,34.96 v5(176.08,34.58) ; v5(168.4,38.01) 168.4,37.81 v4(168.65,37.55)
  BOTTOM w0.254: PU304.14 170.07,33.11 169.51,33.67 169.51,34.81 v2(169.27,35.06) 168.96,35.37 v1(168.65,35.37) ; PR336.2 PC328.1 176.94,34.58 v5(176.08,34.58)
+3V_BATMAN: length 10
  TOP w0.102: C1294.1 v2(110.03,54.97)
  TOP w0.508: R1346.2 R1347.2 116,51.79 v6(116.19,51.98) ; R1348.1 113.43,54.97 113.75,55.28 v1(113.75,56.07)
  GND1 w0.508: v6(116.19,51.98) 116.14,51.93 v4(115.36,51.93)
  IN2 w0.508: v4(115.36,51.93) 115.46,52.03 115.46,54.36 v1(113.75,56.07)
+3V_D: length 2.5
  TOP w0.102: Q5.1 119.59,54.04 v2(119.06,53.51)
  TOP w0.508: R298.2 119.01,54.8 119.31,54.5 Q5.1
+3V_NFC: length 23
  IN2 w0.508: v4(157.17,30.72) 157.96,29.93 159.05,29.93 v4(159.68,29.3) 159.68,28.5 157.98,26.8 155.21,26.8 154.9,26.48 v1(154.9,26.02)
  GND5 w0.508: v4(159.68,29.3) 159.53,29.15 v5(159.23,29.15) ; v5(156.78,31.29) 156.78,31.11 v4(157.17,30.72)
  BOTTOM w0.102: v5(156.78,31.29) 156.78,31.84 156.26,32.36 v2(155.96,32.36)
  BOTTOM w0.254: C1134.1 159.79,29.45 159.79,29.22 160.12,28.89 160.6,28.89 160.81,28.68 ; 161.31,29.03 R1242.2
  BOTTOM w0.305: JNFC1.15 155.06,26.19 v1(154.9,26.02) ; JNFC1.3 161.06,28.43 160.81,28.68 ; JNFC1.2 161.56,28.78 161.31,29.03
  BOTTOM w0.508: v5(159.23,29.15) 159.23,29.32 159.49,29.59 C1134.1 160.15,29.59 160.19,29.63 R1242.2 ; R973.1 v5(156.78,31.29)
+3V_PCH: length 348.6
  TOP w0.254: JAPS.12 21.89,52.2 v1(22.08,52.01)
  TOP w0.305: v6(21.88,55.2) JAPS.18
  TOP w0.381: U672.5 23.71,54.19 v1(23.69,54.17)
  TOP w0.508: R1285.1 172.16,52.74 v1(172.05,52.84) ; v6(92.97,56.63) 92.97,55.64 RH426.2 ; v1(89.64,67.85) 89.7,67.91 CH1220.1 90.76,67.91 v6(91.5,68.64) 91.71,68.86 93.08,68.86 RH270.2 ; R1239.1 135.06,77.15 134.4,76.49 v1(133.8,76.49) ; RH351.1 103.69,63.08 103,62.4 101.96,62.4 ; RH341.1 88.96,63.28 v6(88.45,62.78) ; v1(134.16,52.31) 133.55,52.92 R811.1 ; R1312.2 22.41,51.68 v1(22.08,52.01) ; v1(97.66,55.59) 97.58,55.66 RH398.1 RH295.2
  GND1 w0.254: v6(21.88,55.2) v4(21.88,54.75)
  GND1 w0.508: v6(92.97,56.63) 93.52,56.63 v4(93.59,56.71) ; v4(88.54,63.37) 88.6,63.31 88.6,62.93 v6(88.45,62.78)
  IN1 w0.508: v1(35.05,53.81) 34.77,54.09 34.77,54.95 42.23,62.42 47.54,62.42 v1(48.02,61.94) ; v4(115.62,50.22) 116.03,49.8 117.32,49.8 119.59,52.07 124.04,52.07 125.85,53.89 133.27,53.89 134.08,53.07 134.08,52.39 v1(134.16,52.31) 134.16,52.24 135.1,51.3 135.1,49.87 135.25,49.72 135.25,48.55 135.95,47.85 135.95,47.17 141.51,41.61 141.51,36.37 142.72,35.17 144.47,35.17 145.28,34.35 146.6,34.35 148.33,32.63 v1(148.33,32.62) ; v4(88.54,63.37) 88.87,63.04 88.87,60.67 89.58,59.96 89.58,55.33 90.57,54.34 92.32,54.34 93.59,55.61 v4(93.59,56.71)
  IN2 w0.508: v4(93.59,56.71) 93.92,56.38 96.87,56.38 v1(97.66,55.59) ; v1(23.69,54.17) 23.69,52.77 25.83,50.63 28.9,50.63 29.89,51.63 32.05,51.63 33.22,52.79 34.03,52.79 v1(35.05,53.81) ; v1(48.02,61.94) 47.84,61.94 47.52,62.26 47.52,62.92 48.02,63.42 48.02,72.89 51.7,76.57 51.94,76.57 53.3,77.93 53.3,79.07 54.63,80.4 56.85,80.4 v1(57.18,80.73)
  IN3 w0.508: 153.8,31.86 159.89,31.86 162.28,34.25 164.15,34.25 165.18,35.28 165.18,45.05 164.45,45.78 164.45,47.82 163.8,48.46 v1(163.8,51.09) ; 153.8,31.86 149.09,31.86 v1(148.33,32.62) ; 153.8,31.86 157.13,28.54 160.98,28.54 v4(161.39,28.94) ; v1(97.66,55.59) 97.66,56.86 99.87,59.07 99.87,59.79 v1(100.5,60.43) ; v1(101.06,61.2) 103.61,63.75 103.61,66.02 103.78,66.19 ; v1(57.18,80.73) 60.78,80.73 63,82.96 69.49,82.96 70.72,81.72 77.57,81.72 80.31,78.98 83.7,78.98 84.59,78.09 84.59,71.34 85.71,70.22 86.14,70.22 87.24,69.12 88.37,69.12 v1(89.64,67.85) 89.92,67.58 92.54,67.58 92.92,67.2 95.12,67.2 95.33,67.41 97.23,67.41 97.72,66.92 98.47,66.92 99.05,66.33 99.05,65.23 99.45,64.83 99.99,64.83 101.42,66.26 102.18,66.26 ; v1(134.16,52.31) 134.25,52.4 134.25,59.35 133.51,60.08 133.51,62.28 131.64,64.15 131.64,65.47 130.83,66.28 130.49,66.28 129.09,67.68 129.09,68.41 128.76,68.75 128.76,73.85 131.4,76.49 v1(133.8,76.49) ; v4(115.62,50.22) 116.02,49.81 117.19,49.81 117.66,50.28 117.66,54.32 117.95,54.61 117.95,58.8 v1(117.89,58.86)
  IN4 w0.508: v1(163.8,51.09) 164.97,52.26 167.71,52.26 168.9,51.07 171.19,51.07 171.63,51.51 171.63,52.43 v1(172.05,52.84)
  GND5 w0.254: v5(113.11,68.19) v4(113.11,67.58) ; v5(113.58,68.16) 113.67,68.07 v4(113.67,67.56)
  GND5 w0.508: v4(161.39,28.94) 161.56,29.12 v5(161.56,29.63) ; v4(115.62,50.22) 115.62,50.19 v5(115.22,50.58) ; v5(104.9,66.26) 104.9,66.66 v4(105.15,66.92)
  BOTTOM w0.254: UCPU1.AA9 90.85,68.28 90.42,67.85 90.94,67.33 UCPU1.AC9
  BOTTOM w0.381: CH1236.1 34.09,51.22 34.87,50.44 U663.16
  BOTTOM w0.508: RH154.2 114.79,50.79 114.99,50.58 v5(115.22,50.58) ; 105.02,66.88 105.35,66.88 106.37,67.89 106.37,67.91 106.52,68.06 107.07,68.06 107.2,68.19 108.87,68.19 109.65,68.96 111.09,68.96 ; RH274.1 116.07,70.05 116.2,69.93 116.2,69.1 ; v1(116.76,62.57) 116.1,62.57 114.73,63.94 114.73,67.75 115.36,68.39 115.36,68.71 115.75,69.1 116.2,69.1 ; 116.2,69.1 v1(116.21,69.1) ; RH400.2 100.46,60.46 v1(100.5,60.43) ; v5(161.56,29.63) 161.56,30.57 161.11,31.03 R1242.1 ; 90.42,67.85 v1(89.64,67.85) 89.5,67.85 88.34,66.69 85.77,66.69 85.44,66.36 UCPU1.AE20 85.04,65.93 UCPU1.AE21
  vias: v1(117.24,58.92) v7(117.46,58.18)
+3V_PCH_DSW: length 21.5
  TOP w0.127: RH146.2 108.01,63.89 v2(108.29,63.89)
  TOP w0.508: RH12.2 97.14,63.2 v6(96.86,62.92) ; RH146.2 107.21,64.58 106.98,64.81 106.46,64.81 106.33,64.68 RH402.2
  GND1 w0.254: v4(100.93,63.98) 100.93,64.11 v6(101.28,64.45) ; v6(96.86,62.92) v4(96.55,62.61)
  IN3 w0.508: v4(91.38,63.99) 90.95,64.41 90.95,65.52 91.43,66 94.16,66 96.03,64.13 96.03,63.13 v4(96.55,62.61) 96.95,62.22 100.69,62.22 101.35,62.88 101.35,63.31 100.93,63.73 v4(100.93,63.98)
  GND5 w0.254: v4(91.38,63.99) 91.24,64.12 v5(90.67,64.12)
  BOTTOM w0.254: v5(90.67,64.12) 90.92,64.38 UCPU1.AH10
+3VALW: length 518.5
  TOP w0.254: U636.C6 159.05,64.82 v6(158.82,64.6)
  TOP w0.305: U687.5 174.11,50.11 173.13,51.09 R1282.1 ; JAPS.16 18.01,54.2 v1(17.72,53.91)
  TOP w0.356: 128.76,61.42 128.76,58.2 128.51,57.95 128.51,56.57 127.5,55.56 126.58,55.56 ; U710.5 128.34,63.35 128.19,63.2 128.19,62.69 128.18,62.67
  TOP w0.381: C1259.1 175.97,46.43 176.01,46.47 U689.5 ; 128.76,61.42 128.18,62 128.18,62.67
  TOP w0.406: C1260.1 173.46,46.36 U688.3 173.46,47.71 173.4,47.77 ; 173.31,47.85 172.84,48.32 172.84,48.97 U688.5
  TOP w0.432: Q316.2 v1(227.06,7.45) Q316.5 ; 226.06,4.91 v1(226.97,4.91) ; Q318.2 v1(227.05,9.99) Q318.5
  TOP w0.457: 176.7,47.33 176.7,46.23 176.36,45.89 ; 176.7,47.33 176.7,49.58 176.51,49.77 176.36,49.77 U687.5 ; 176.7,47.33 176.27,47.77 173.4,47.77 173.31,47.85
  TOP w0.508: RH348.1 106.06,62.67 106.89,62.67 108.86,60.71 108.86,60.29 108.88,60.27 108.88,60.26 109.1,60.04 109.11,60.04 v7(109.8,59.35) 110.71,58.43 v1(112.16,58.43) ; PR107.2 192.45,77.14 v1(193.3,77.99) 193.77,78.46 PR102.2 ; R1281.1 173.55,54.33 v1(173.55,53.89) ; PR348.1 208.72,31.7 v1(209.19,32.17) ; v1(120.03,29.76) 120.05,29.76 PR113.2 ; v1(142.23,41.24) 142.95,41.95 PR224.2 ; C1100.2 15.17,20.15 15.55,20.54 v1(15.55,20.92) ; v1(208.12,50.13) 208.54,49.71 PU307.5 ; R216.1 133.47,50.72 134.09,50.1 134.86,50.1 135.82,49.14 135.82,49.09 v1(135.9,49.01) ; C1259.1 176.36,45.89 ; PR328.1 209.14,60.32 v7(209.14,57.02) v1(209.14,56.07) 209.14,55.73 207.81,54.41 207.35,54.41 PR318.1 ; PR126.1 v1(111.61,27.44) ; v1(211,32.11) 213.08,32.11 213.41,31.78 PR308.1 ; v1(173.08,51.85) 173.04,51.81 R1282.1
  GND1 w0.127: v6(176,34.38) v4(175.6,34.38) ; v4(175.61,33.36) 175.95,33.36 v6(176.02,33.43) ; v6(176.02,33.95) 175.97,33.9 v4(175.6,33.9)
  GND1 w0.254: v4(159.1,64.86) 159.13,64.88 159.13,64.9 v6(158.83,64.6)
  IN1 w0.508: v1(17.72,53.91) 18.43,54.62 18.43,55.28 20.17,57.02 20.17,63.93 20.96,64.72 20.96,71.86 21.46,72.35 21.46,75.9 23.18,77.62 23.18,83.07 23.85,83.73 v1(33.9,83.73) ; v1(142.23,41.24) 142.23,41.92 136.94,47.22 136.94,47.97 v1(135.9,49.01) ; 124.45,58.1 123.63,57.28 118.76,57.28 118.07,57.96 116.28,57.96 115.5,58.74 112.47,58.74 v1(112.16,58.43) ; v4(43.87,84.91) 44.41,84.38 50.76,84.38 51.48,85.1 57.47,85.1 57.95,84.63 71.98,84.63 72.44,84.18 81.35,84.18 82.71,82.82 86.77,82.82 88.22,84.27 96.41,84.27 97.49,85.34 108.97,85.34 v4(109.96,84.35)
  IN2 w0.508: v1(208.12,50.13) 208.34,50.34 212.14,50.34 212.54,50.75 212.54,52.65 212.1,53.1 212.1,55.49 211.51,56.07 v1(209.14,56.07) 206.28,56.07 206.13,55.92 197.78,55.92 196.13,57.57 196.13,59.32 195.45,60.01 v1(194.13,60.01) 193.59,60.54 v1(191.08,60.54) ; v4(43.87,84.91) 41.55,82.59 35.05,82.59 v1(33.9,83.73) ; v1(156.23,76.67) 156.59,76.67 157.06,77.15 157.06,77.32 157.73,77.99 168.43,77.99 169.16,78.71 v1(170.87,78.71) 170.87,78.33 171.62,77.58 v1(177.03,77.58)
  IN3 w0.508: 117.88,71.49 117.62,71.74 115.45,71.74 113.98,73.22 113.98,76.02 110.33,79.67 110.33,81.15 109.96,81.52 v4(109.96,84.35) ; v1(209.19,32.17) 209.24,32.17 209.72,32.65 210.46,32.65 v1(211,32.11) ; v1(170.87,78.71) 170.56,78.71 167.02,75.18 167.02,68.55 165.9,67.42 160.98,67.42 159.86,66.31 159.86,65.67 159.1,64.91 v4(159.1,64.86) ; v1(173.08,51.85) 172.77,51.53 172.77,48.72 170.87,46.82 v1(168.85,46.82) 167.71,45.68 v1(166.12,45.68)
  IN4 w0.508: 225.32,10.38 225.32,11.4 229.13,15.21 229.13,19.29 227.39,21.03 223.95,21.03 222.79,19.88 202.18,19.88 193.54,28.51 193.54,32.04 191.79,33.79 v1(191.52,33.79) ; v1(193.3,77.99) 194.13,77.17 v1(194.13,60.01) ; v1(17.72,53.91) 17.72,47.92 16.76,46.95 16.76,43.03 15.53,41.8 15.53,30.19 15.06,29.72 15.06,22.17 15.55,21.68 v1(15.55,20.92) ; v1(120.03,29.76) 120.8,28.99 127.35,28.99 128.12,29.77 v1(128.12,30.57) 128.12,34.54 132.89,39.31 140.3,39.31 v1(142.23,41.24)
  BOTTOM w0.254: PR338.1 176.56,35.12 179.03,35.12 179.27,35.36 179.27,38.34 178.89,38.72 v1(175.71,38.72) ; JIOL1.7 15.6,20.87 v1(15.55,20.92)
  BOTTOM w0.381: 204.08,37.58 204.48,37.58 204.68,37.78 U699.5
  BOTTOM w0.508: v1(199.27,40.09) 201.39,40.09 201.9,39.59 201.9,37.97 202.29,37.58 C1289.1 204.08,37.58 ; v1(120.03,29.76) 119.53,30.26 114.43,30.26 v1(111.61,27.44) ; v1(173.08,51.85) 173.07,51.86 173.07,53.58 173.37,53.89 v1(173.55,53.89) ; 195.04,33.77 204.71,33.77 206.31,32.17 v1(209.19,32.17)
  vias: v1(126.56,57.98) v1(165.22,46.29) v1(165.49,45.66) v1(165.84,45.1) v1(175.7,40.02) v1(175.71,39.36) v1(178.91,72.08) v1(179.5,71.72) v1(189.21,33.82) v1(189.24,33.03) v1(190.04,33.03) v1(190.08,33.85) v1(190.82,33.79) v1(190.84,33.06) v1(191.08,59.27) v3(125.65,56.68) v3(125.65,58.46) v3(125.91,59) v3(126.24,56.68) v7(126.25,56.05)
+3VALW_EC: length 98.2
  TOP w0.178: U34.J4 141.38,60.6 140.93,61.06 140.42,61.06 140.26,60.91 140.26,58.83 140.35,58.74
  TOP w0.203: U34.J7 U34.K7 140.71,59.1 v6(140.34,58.74) 140.35,58.74 ; v6(140.72,56.93) 140.25,56.93 139.92,56.6 U34.M12 ; RP22.5 139.1,51.38 139.38,51.1 139.38,50.63 139.13,50.38 RP22.7
  TOP w0.254: U34.K12 140.92,56.74 v6(140.72,56.93) ; v1(135.83,65.25) 135.75,65.17 RP21.5 RP21.6 ; v1(138.72,52.36) 138.8,52.28 RP22.5
  TOP w0.508: R1354.2 v6(135.87,57.67) ; R990.2 174.07,22.57 167.92,22.57 167.11,23.38 167.11,25.92 166.68,26.35 164.36,26.35 v1(163.88,25.87) ; R1156.1 129.52,58.41 v1(129.95,57.98) 130.86,57.98 131.36,58.48 R1386.2 ; R980.2 136.38,62.4 136.35,62.42 136.35,62.64 v1(136.37,62.65) ; L43.1 143.39,50.57 143.05,50.91 v1(143.05,51.32) ; v1(138.72,52.36) 138.67,52.41 138.67,52.79 138.44,53.02 R221.2 ; v1(135.67,52.64) 135.82,52.49 136.18,52.49 C277.1 C276.1 136.3,51.47 135.05,51.47 R216.2 R811.2 134.88,52.93 C280.2 C281.2 135.1,54.74 136.15,54.74 R604.1 ; PR117.2 148.47,62 v6(148.3,61.83) ; v1(146.69,52.16) 146.52,52.33 146.52,52.89 R927.1 ; v1(147.64,67.98) 147.49,68.14 R1297.2 ; v1(149.75,56.02) 149.52,55.79 R230.2 149.14,55.75 149.14,54.94 R229.2
  GND1 w0.254: v4(140.81,58.79) 140.83,58.81 140.84,58.81 140.76,58.74 v6(140.34,58.74) ; v4(140.65,56.51) 140.72,56.59 v6(140.72,56.93)
  GND1 w0.508: v6(148.3,61.83) 148.3,62.02 148.66,62.38 v4(148.66,62.42) ; v6(135.87,57.67) v4(135.36,58.18)
  IN1 w0.508: 147.78,67.2 148.66,66.32 v4(148.66,65.06)
  IN2 w0.508: v1(163.88,25.87) 163.88,29.63 161.72,31.79 153,31.79 150.57,34.23 149.65,34.23 v1(149.58,34.15) ; v4(135.36,58.18) 134.59,58.95 130.93,58.95 v1(129.95,57.98)
  IN3 w0.508: v1(149.58,34.15) 147.05,34.15 143.77,37.43 143.77,46.88 146.87,49.97 147.86,49.97 v1(149.59,51.7)
  vias: v1(149.83,61.53) v2(149.51,50.3)
+3VALW_LX:
  vias: v1(202.98,30.92) v1(203.11,30.09) v1(203.11,29.1) v1(203.54,29.6) v1(203.54,28.61) v2(204.57,30.92)
+3VALW_VIN: length 1.5
  TOP w0.102: v2(199.98,36.36) 199.98,36.8 200.57,37.39 200.82,37.39 200.82,37.39
+3VALWP: length 28.3
  TOP w0.102: v2(209.72,34.05) 209.37,34.05 209.15,33.83 v1(209.15,33.82)
  TOP w0.254: v1(201.98,32.65) 202.03,32.71 PU305.14 ; PR346.2 PR345.1 PC336.1 208.82,33.48 209.15,33.81 v1(209.15,33.82)
  IN3 w0.254: v1(209.15,33.82) 208.41,34.56 204.01,34.56 202.72,33.27 198.27,33.27 195.4,30.4 v1(195.4,28.99)
  BOTTOM w0.254: v1(201.98,32.65) 198.19,32.65 195.98,30.44
+3VDX: length 43
  IN3 w1.016: 169.35,27.51 167.01,27.51 163.93,24.42 148.26,24.42 144.85,27.83 137.42,27.83 135.15,30.1 134.8,30.1 133.19,31.71 131.8,31.71 131.01,30.92
  vias: v1(129.53,31.25) v1(129.52,30.62) v1(171.56,71.29) v1(172.19,71.29) v1(172.79,71.54) v1(172.79,70.89) v1(200.1,57.32) v1(200.07,56.63) v1(200.91,57.32) v1(200.88,56.58) v1(201.54,57.32) v1(201.52,56.55) v2(199.37,56.26)
+3VDX_LX:
  vias: v1(205.34,59.32) v1(205.35,60.19) v1(205.37,58.43) v1(206.17,60.19) v1(206.15,59.32) v1(206.18,58.43) v7(204.65,59.32)
+3VDX_VIN:
  vias: v2(203.63,69.96)
+3VDXP: length 18.3
  TOP w0.254: 202.8,61.68 202.8,63.16 202.94,63.29 PU303.14 ; PR326.2 PC320.1 PR325.1
  TOP w0.508: PC320.1 v1(209.71,63.21)
  IN3 w0.508: v1(209.71,63.21) 209.71,63.55 207.97,65.29 203.93,65.29 202.61,63.97 202.61,60.79 v1(202.03,60.21)
  BOTTOM w0.102: v7(210.38,63.21) v1(209.71,63.21)
  vias: v1(200.04,60.26) v1(200.68,60.24) v1(201.31,60.21) v1(202.03,59.58) v1(202.05,58.92)
+3VLP: length 295.1
  TOP w0.102: v1(184.5,34.53) v7(184.5,33.07)
  TOP w0.254: v1(138.11,50.71) 138.11,50.72 138.27,50.88 RP22.6
  TOP w0.356: U712.5 130.44,54.24 130.41,54.22
  TOP w0.508: v6(149.07,69.35) 148.86,69.56 R921.2 ; R1349.2 112.31,56.13 v1(112.31,56.55) ; 130.41,54.22 130.41,54.06 131.3,53.17 132.43,53.17 v1(132.44,53.19) 132.65,53.39 R939.1
  GND1 w0.508: v6(149.07,69.35) 149.26,69.16 149.27,69.16 149.55,68.88 149.99,68.88 150.02,68.91 v4(150.02,68.9)
  IN1 w0.508: v1(148.66,59.35) 149.47,59.35 150.77,58.05 150.77,57.19 151.45,56.5 155.87,56.5 157.12,57.75 158.08,57.75 161.69,54.14 164.09,54.14 171.23,47 v4(172.69,47)
  IN2 w0.508: v1(112.31,56.55) 111.53,55.77 111.53,49.58 113.25,47.85 113.25,46.82 114.02,46.06 115.67,46.06 117.9,43.83 127.88,43.83 128.65,44.59 130.98,44.59 131.54,44.03 134.59,44.03 135.07,44.51 135.07,45.78 134.44,46.42 133.7,46.42 131.95,48.17 131.95,52.74 132.44,53.24 v1(132.44,53.19) 132.96,52.67 132.96,52.45 134.04,51.37 137.45,51.37 v1(138.11,50.71) ; v1(122.18,78.88) 120.76,78.88 v1(117.76,81.88) ; v1(34.13,54.18) 34.13,54.53 35.72,56.12 36.55,56.12 38.5,58.08 38.5,60.34 41.5,63.33 42.31,63.33 42.87,63.89 42.87,73.51 47.28,77.91 47.28,82.89 49.4,85.01 v1(49.42,85.01) ; v4(179.88,36.74) 180.72,35.9 182.75,35.9 184.12,34.53 v1(184.5,34.53)
  IN3 w0.508: v1(132.44,53.19) 132.44,54.55 130.97,56.02 130.97,59.04 130.65,59.36 130.65,63.11 130.42,63.33 130.42,65.48 128.48,67.43 128.48,68.16 128.06,68.58 128.06,72.61 122.18,78.49 v1(122.18,78.88) ; v1(49.42,85.01) 49.42,85.27 49.87,85.71 53.98,85.71 55.07,84.62 71.03,84.62 71.91,83.73 80.5,83.73 81.97,82.26 89.36,82.26 91.75,84.65 108.35,84.65 108.67,84.96 112.55,84.96 115.11,82.41 117.23,82.41 v1(117.76,81.88) ; v4(150.02,68.9) 150.02,68.2 148.31,66.48 148.31,65.93 147.81,65.43 147.81,62.83 148.05,62.59 148.05,61.62 148.72,60.95 148.72,59.41 v1(148.66,59.35) 148.66,59 147.53,57.87 147.53,57.06 148.22,56.38 148.22,55.12 148.8,54.53 148.8,52.83 147.14,51.17 146.25,51.17 145.08,50 142.67,50 141.6,48.93 139.69,48.93 138.11,50.52 v1(138.11,50.71)
  IN4 w0.508: v4(179.88,36.74) 179.6,36.74 178.96,37.38 178.96,40.16 178.04,41.08 178.04,42.34 177.11,43.27 177.1,43.27 176.73,43.64 176.73,43.65 174.56,45.82 174.33,45.59 173.82,45.59 173.46,45.95 173.46,46.34 173.35,46.34 v4(172.69,47)
  BOTTOM w0.508: v1(184.5,34.53) 184.75,34.28 PC341.1 184.75,31.97 185.1,31.62 PU306.3 ; RTCD1.3 33.42,54.47 33.71,54.18 v1(34.13,54.18)
+3VNS_PWR: length 148.2
  TOP w0.102: U653.7 154.43,80.81 C1149.1 ; C1148.1 147.96,79.95 147.96,79.24 148.29,78.91 149.65,78.91 150.23,79.48 U653.1 ; C1148.1 149.33,81.31 U653.14 ; C1148.1 149,80.81 U653.15 ; U638.1 142.9,78.84 142.81,78.93 142.81,78.94 142.73,79.02 142.73,79.48 C969.1 ; U638.16 143.9,79.93 143.62,80.22 C970.1 144.11,80.7 144.55,80.26 U638.15 ; U637.14 156.98,52.23 158.03,53.28 C966.1 ; C965.1 157.04,54.03 155.89,54.03 155.49,53.63 U637.1
  TOP w0.178: U636.G8 160.55,65.32 U636.F7 U636.G6
  TOP w0.203: 162.29,61.57 161.55,62.31 U636.H1 ; v1(157.91,61.61) 157.91,62.18 U636.A1
  TOP w0.229: U636.A8 158.05,65.82 157.87,66 v1(157.87,66.42)
  TOP w0.254: v1(161.32,66.26) 161.05,65.98 U636.G8 ; R1175.1 155.1,81.99 155.1,81.38 C1149.1
  TOP w0.305: v1(185.4,80.91) 185.39,80.9 185.39,80.47 184.78,79.86 JSNRDG.1
  TOP w0.381: 149.21,70.17 149.21,70.18 149.3,70.27 Q352.5 Q352.2
  TOP w0.508: C970.1 142.07,80.7 C969.1 141.07,80.42 v1(140.44,81.04) 139.85,80.44 R1205.2 ; v1(157.91,61.61) 156.67,61.61 156.57,61.71 155.99,61.71 C976.1 C978.1 ; C1148.1 148.51,81.31 148.51,81.76 151.54,84.8 v1(153.18,84.8) 153.83,84.8 154.16,84.47 154.16,82.96 154.48,82.64 R1175.1 ; R1227.2 165.08,56.81 v1(164.95,56.68) ; R1251.2 154.52,59.73 v1(154.21,59.42) ; C966.1 158.19,53.92 v1(158.43,54.17) 158.43,54.7 C965.1 ; v1(155.37,57.19) 155.37,57.14 155.38,57.12 R854.2 ; v1(168.94,53.45) 168.84,53.45 168.33,52.95 R1319.2 ; R855.2 154.11,56.97 154.24,57.1 v1(154.24,57.32) ; 162.29,61.57 162.72,61.14 C977.1 162.74,60.3 C979.1 v6(163.55,61.01) ; R1091.1 R1176.1 145.99,72.99 146.4,72.58 v1(146.79,72.58) 147.01,72.36 147.01,70.9 147.72,70.19 149.18,70.19 149.56,69.81 151.07,69.81 R1143.2 151.73,69.81 v1(153.11,69.81) ; RH461.2 RH462.2 166.38,61.82 v1(165.98,61.43) ; R1220.2 160.2,57.68 v1(160.29,57.59)
  GND1 w0.508: v6(163.55,61.01) 163.55,60.41 v4(163.98,59.98)
  IN2 w0.508: v1(164.95,56.68) 166.02,56.68 168.94,53.76 v1(168.94,53.45) ; v1(185.4,80.91) 185.41,80.92 185.41,81.69 184.95,82.15 179.06,82.15 178.71,81.8 172.64,81.8 170.3,84.14 154.96,84.14 154.3,84.8 v1(153.18,84.8) 151.57,84.8 150.2,83.43 144.22,83.43 143.78,82.99 v4(143.78,82.51)
  IN3 w0.508: 141.04,78.17 141.04,77.48 145.94,72.58 v1(146.79,72.58) ; v1(160.29,57.59) 161.59,57.59 v4(163.98,59.98) 164.55,59.98 165.56,60.99 165.56,61 v1(165.98,61.43)
  BOTTOM w0.102: v1(153.18,84.8) v2(153.18,84.02)
  BOTTOM w0.508: v1(164.95,56.68) 165.9,57.62 JSATA1.22
  vias: v1(153.6,64.34) v1(153.74,65.6) v1(154.43,65.62)
+3VS: length 600.8
  TOP w0.203: PU701.21 31.25,79.92 v1(31.3,79.87)
  TOP w0.254: R1163.2 176.45,42.24 178.09,43.88 v7(178.09,46.7) 178.09,48.17 181.57,51.65 182.37,51.65 182.98,52.27 U677.14 ; RV2.2 194.18,73.05 RH282.1 192.97,73.96 192.5,74.43 189.02,74.43 v1(188.88,74.57) ; v1(101.65,65.49) 101.59,65.44 101.59,65.37 101.58,65.35 100.71,65.35 RP20.8 ; C1283.1 188.8,40.06 U679.B2
  TOP w0.305: U682.5 130.21,65.58 129.79,65.16 v1(129.79,65.14)
  TOP w0.381: v1(132.56,67.75) 132.53,67.78 131.39,67.78 130.82,68.35 U635.5 ; v1(172.82,67.48) 172.9,67.56 172.9,67.91 172.76,68.05 U675.5 ; v1(170.9,64.81) 171.1,64.61 171.1,64.39 170.92,64.21 U709.5 ; U677.14 182.48,53.12 182.04,53.55 181.81,53.55 C1287.1 ; U671.14 189.71,53.42 189.55,53.58 188.46,53.58 C1285.1
  TOP w0.432: 123.12,63.08 120.52,63.08 ; 123.12,63.08 125.72,63.08 ; 123.12,63.08 123.13,63.07 123.13,61.82 123.45,61.51 RH98.1 RH99.1 123.45,60.02 v1(123.3,59.87)
  TOP w0.508: 190.1,55.64 RH459.2 RH460.2 ; 190.1,55.64 189.87,55.64 189,54.76 v1(189,54.17) 188.61,54.17 188.36,53.91 C1285.1 ; 190.1,55.64 189.26,56.48 182.68,56.48 181.92,55.71 181.92,53.77 C1287.1 181.17,54.19 v1(181.16,54.19) ; 116.49,55.64 116.11,56.02 116.11,59.08 v1(116.2,59.17) 116.61,59.58 118.38,59.58 119.15,58.81 v1(119.21,58.81) ; v1(192.58,74.98) 192.58,75.76 193.2,76.38 193.9,76.38 RH281.1 ; RH395.1 98.47,55.51 v1(98.31,55.35) ; CH47.1 90.34,69.32 CH1225.1 90.34,70.45 89.58,71.21 v1(89.21,71.21) 88.41,71.21 RH452.1 ; v6(87.85,74.59) CH1226.1 88.36,75.2 RH465.2 ; v1(174.28,23.47) 174.03,23.71 Q326.2 ; C1283.1 189.3,39.89 189.63,40.22 191.65,40.22 192.15,40.72 v1(192.15,40.82) ; v1(22.09,81.95) PR725.1 23.31,81.52 PR723.2 ; Q344.2 v1(194.09,38.49) ; v1(104.49,65.48) 104.02,65.95 101.91,65.95 101.65,65.68 v1(101.65,65.49) ; R930.1 v6(146.62,67.82) ; v1(50.24,85.05) 50.24,84.84 49.41,84.01 42.27,84.01 40.75,82.49 34.88,82.49 33.74,81.34 v1(32.96,81.34) 32.68,81.62 PR746.1 ; v6(33.28,48.91) 33.71,48.48 35.72,48.48 36.65,49.41 RH367.2 ; R1306.1 131.35,22.97 v1(130.51,22.97) 129.78,23.71 129.78,28.75 v1(130.8,29.78) 131.33,30.3 R1182.2 ; R1393.1 158.55,72.31 v1(158.66,72.21) ; R1289.1 163.42,53.99 164.88,53.99 165.37,53.49 165.37,52.59 164.75,51.97 164.75,50.6 v1(164.99,50.36) 164.98,50.36 ; v1(14.37,28.54) 14.37,27.64 14.05,27.32 12.38,27.32 11.63,26.57 6.56,26.57 5.19,25.2 R884.2 R1103.2 ; v1(185.67,45.42) 186.42,44.67 RH381.1 ; C655.1 v1(142.87,70.59)
  GND1 w0.254: v6(101.54,73.44) 101.54,73.08 v4(101.68,72.94)
  GND1 w0.508: v4(32.66,49.36) 33.12,48.91 v6(33.28,48.91) ; v4(88.06,73.47) 87.85,73.68 v6(87.85,74.59) ; v6(146.62,67.82) 146.58,67.86 v4(146.1,67.86)
  IN1 w0.508: v1(98.31,55.35) 98.31,55.33 98.94,54.7 100.91,54.7 101.7,55.49 101.7,60.13 103.21,61.65 106.36,61.65 108.53,59.47 115.89,59.47 v1(116.2,59.17) ; v1(131.33,61.06) 130.22,59.96 123.39,59.96 v1(123.3,59.87) 122.24,58.81 v1(119.21,58.81) ; v1(130.8,29.78) 132.46,31.43 134.32,31.43 134.8,30.95 138.91,30.95 140.24,32.28 v1(140.24,37.66) ; 55.4,47.94 55.18,47.71 48.71,47.71 47.82,48.6 v1(47.68,48.6) ; v1(48.1,59.6) 48.1,58.07 45.13,55.11 42.13,55.11 41.55,55.69 40.51,55.69 40.05,55.23 v1(40.05,55.03)
  IN2 w0.508: v1(50.24,85.05) 50.24,78.47 45.82,74.05 45.82,61.8 48.01,59.6 v1(48.1,59.6) ; v1(14.37,28.54) 14.37,41.19 17.18,43.99 17.18,46.66 17.98,47.46 v1(19.86,47.46) 21.03,47.46 21.89,46.6 30.12,46.6 30.89,47.37 30.89,47.97 32.29,49.36 v4(32.66,49.36) ; v1(185.67,45.42) 186.9,45.42 187.93,46.44 187.93,53.1 v1(189,54.17) 198.84,54.17 205.07,47.93 205.07,43.56 204.35,42.84 203.56,42.84 200.25,39.52 200.25,38.46 199.5,37.71 194.88,37.71 v1(194.09,38.49) 194.09,38.57 194.48,38.96 194.48,39.98 193.64,40.82 v1(192.15,40.82)
  IN3 w0.508: 31.03,81.72 31.01,81.75 27.16,81.75 26.42,81.01 23.03,81.01 v1(22.09,81.95) ; v1(170.9,64.81) 170.9,65.56 v1(172.82,67.48) ; 195.24,71.36 195.24,70.52 193.24,68.52 193.24,59.4 191.99,58.15 186.79,58.15 185.06,56.43 182.82,56.43 181.96,55.56 181.96,54.57 181.58,54.19 v1(181.16,54.19) ; v1(131.33,61.06) 131.33,60.64 131.99,59.98 131.99,59.39 131.6,59 131.6,56.26 133.08,54.79 133.08,52.92 132.11,51.96 132.11,44.03 138.49,37.66 v1(140.24,37.66) ; v1(104.49,65.48) 104.49,63.63 101.14,60.27 101.14,59.94 100.73,59.54 100.73,58.65 98.31,56.22 v1(98.31,55.35) ; v1(192.35,20.59) 181.53,20.59 179.5,22.62 176.17,22.62 175.32,23.47 v1(174.28,23.47) 173.48,23.47 172.57,22.57 142.31,22.57 140.91,23.96 140.91,24.95 140.41,25.46 135.23,25.46 132.67,22.9 130.59,22.9 v1(130.51,22.97)
  IN4 w0.508: v1(40.05,55.03) 40.05,54.44 39.11,53.51 37.01,53.51 32.87,49.36 v4(32.66,49.36) ; v1(50.24,85.05) 50.29,85.05 50.79,84.54 52.92,84.54 53.4,84.06 53.4,83.35 54.73,82.02 57.96,82.02 60.1,84.16 70.35,84.16 73.33,81.19 78.24,81.19 79.46,79.97 82.95,79.97 86.19,76.73 86.19,75.86 88.06,73.99 v4(88.06,73.47)
  GND5 w0.254: v4(108.58,70.82) 108.87,70.52 v5(109.16,70.52) ; v5(100.69,78.79) v4(100.69,79.24) ; v4(103.37,71.98) 103.57,71.79 v5(104.07,71.79) ; v4(101.68,72.94) 101.92,73.18 v5(101.92,73.32) ; v5(88.31,74.15) 88.06,73.9 v4(88.06,73.47) ; v4(100.15,79.24) 100.15,78.93 v5(100.29,78.79)
  BOTTOM w0.254: RP19.5 101.48,65.33 v1(101.65,65.49) ; UCPU1.V8 92.04,69.67 UCPU1.W9 ; UCPU1.K14 v5(88.31,74.15) UCPU1.K16 ; JLVDS2.10 180.74,80.3 180.11,80.94 v1(180.11,81.01) ; UCPU1.W9 92.04,68.79 UCPU1.Y8 ; UCPU1.W9 90.78,69.23
  BOTTOM w0.381: v1(119.21,58.81) 119.71,58.32 UH5.5 ; MD50.5 184.73,74.91 185.35,75.53 186.8,75.53 v1(186.86,75.59)
  BOTTOM w0.508: R1311.2 20.24,47.08 v1(19.86,47.46) ; RC159.1 v1(48.1,59.6) ; v1(89.21,71.21) 89.21,70.8 90.78,69.23 ; v1(192.35,20.59) 193.28,21.51 JDEBUG.9 ; v1(104.49,65.48) 104.44,65.48 103.78,66.14 103.78,67.12 104.46,67.81 104.46,69.02 ; v1(168.64,70.75) 168.93,70.75 172.21,67.48 v1(172.82,67.48) ; v1(40.05,55.03) 40.05,54.28 41.77,52.57 44.99,52.57 47.89,49.67 ; v1(129.79,65.14) 129.94,65.14 v1(132.56,67.75) ; RH54.1 115.49,58.17 116.2,58.88 v1(116.2,59.17) 115.39,59.98 RH56.1 115.13,60.91 CH6.1 114.08,60.95 U48.8 ; v1(151.73,59.12) 150.53,57.91 v1(149.93,57.91) ; R1033.2 159.15,72.71 v1(158.66,72.21)
  vias: v1(55.6,48.58) v1(56.33,48.55) v1(164.79,49.75) v1(165.48,49.92) v1(165.81,49.38) v1(186.11,81.31) v1(186.11,80.67) v1(208.34,71.11) v1(209.1,71.11)
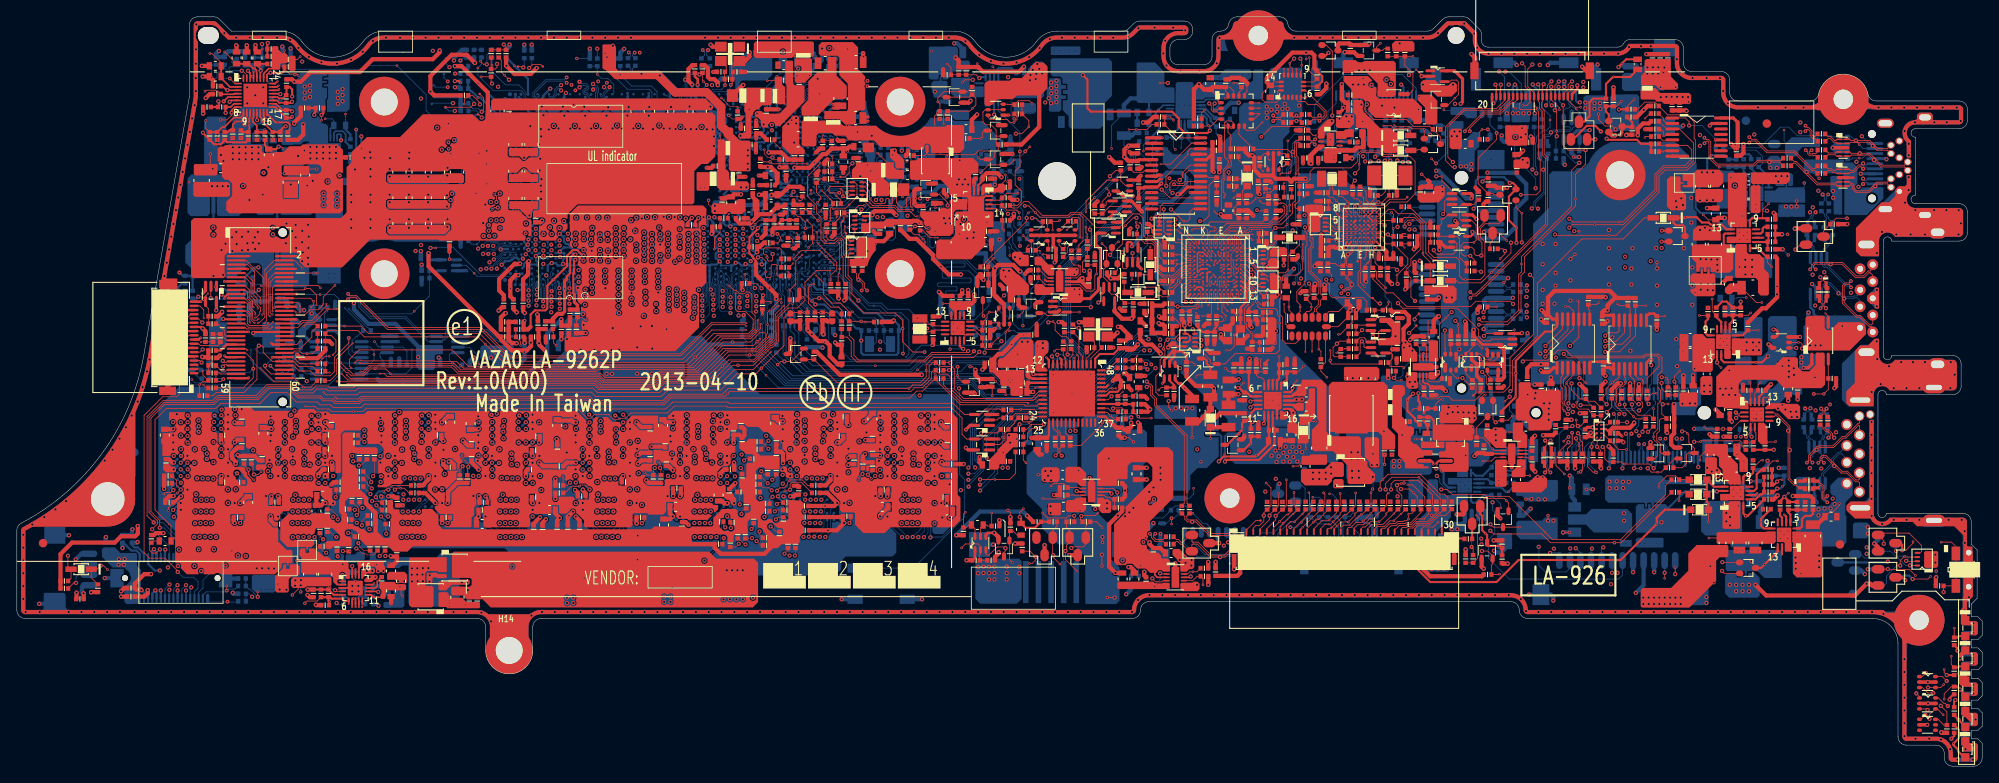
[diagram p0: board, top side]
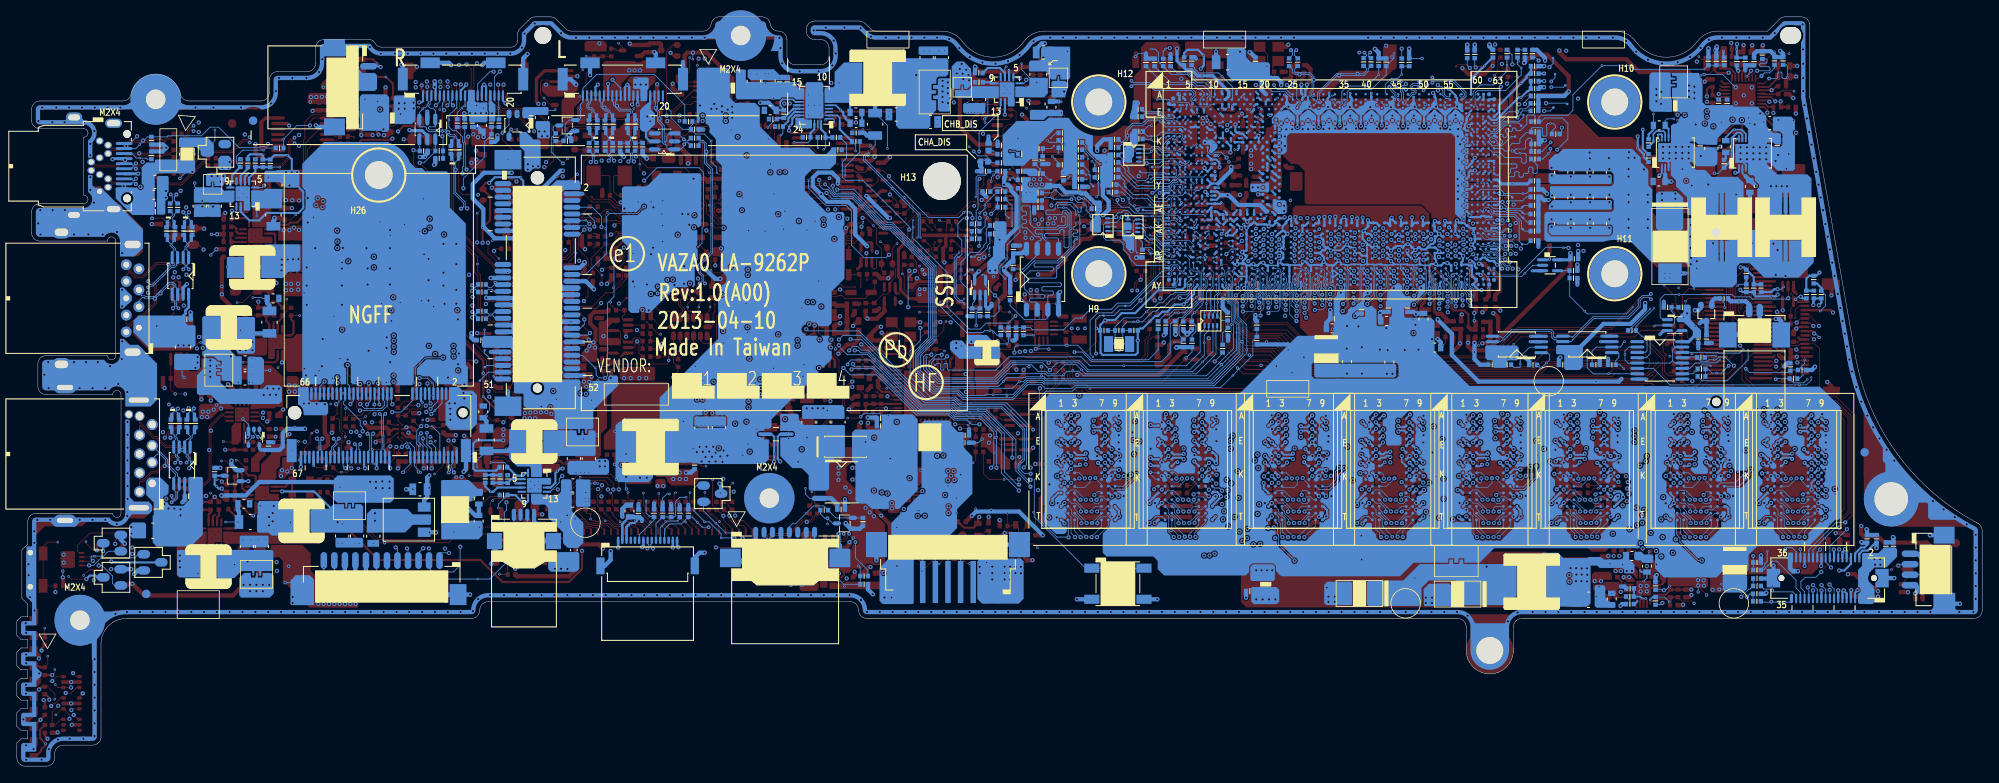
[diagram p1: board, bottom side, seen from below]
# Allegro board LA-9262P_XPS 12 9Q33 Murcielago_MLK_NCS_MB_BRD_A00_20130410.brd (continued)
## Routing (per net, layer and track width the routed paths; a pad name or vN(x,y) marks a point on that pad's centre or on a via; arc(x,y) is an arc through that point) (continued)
+3VS_AUDIO: length 189.7
  TOP w0.102: v1(118.02,38.44) 117.22,37.64 v2(117.22,37.25)
  TOP w0.254: CA10.1 120.16,45.54 UA1.16 ; CA11.1 131.12,44.86 130.75,44.49 129.86,44.49 129.42,44.04 UA1.42 ; UA1.14 120.84,46.54 v1(120.78,46.6)
  TOP w0.508: v1(123.78,52.78) 124.18,52.78 R1265.1 ; CA11.1 131.2,45.19 131.2,45.81 CA7.1 130.61,46.19 v6(130.21,45.78) ; v1(120.73,44.48) CA8.1 120.01,45.42 CA10.1
  GND1 w0.508: v4(130.22,45.28) 130.22,45.43 130.21,45.44 v6(130.21,45.78)
  IN1 w0.508: v1(120.73,44.48) 120.73,46.55 v1(120.78,46.6)
  IN2 w0.508: v1(117.88,39.31) 117.44,39.31 114.1,42.65 111.92,42.65 v4(110.23,44.34) ; v1(14.35,26.63) 15.03,27.32 15.03,40.83 18.97,44.77 29.64,44.77 33.57,48.7 33.57,50.25 37.89,54.57 37.89,54.98 38.4,55.49 38.4,56.15 39.97,57.72 39.97,59.69 42.18,61.9 44.79,61.9 47.81,58.88 49,58.88 52.55,62.42 57.2,62.42 58.67,63.89 60.78,63.89 61.09,64.19 61.09,64.44 62.72,66.08 79.01,66.08 79.55,65.54 79.55,65.15 v1(79.47,65.07)
  IN3 w0.508: v4(88.44,65.01) 88.58,65.15 89.3,65.15 90.39,64.06 90.39,64.05 92.17,62.27 93.42,62.27 94.28,61.4 94.28,59.68 94.74,59.22 95.52,59.22 95.96,58.77 95.96,57.63 96.67,56.92 96.67,54.81 99.51,51.97 99.51,48.83 100.5,47.84 104.44,47.84 107.94,44.34 v4(110.23,44.34) ; v1(123.78,52.78) 124.7,52.78 125.39,52.08 125.39,51.04 130.22,46.22 v4(130.22,45.28)
  IN4 w0.508: v4(88.44,65.01) 86.81,66.64 84.83,66.64 84.23,66.04 84.23,65.58 83.23,64.58 81.38,64.58 81.1,64.3 80.01,64.3 79.47,64.84 v1(79.47,65.07) ; 121.61,46.32 122.88,45.05 129.99,45.05 v4(130.22,45.28)
  BOTTOM w0.254: C1101.2 13.68,26.28 13.96,26 14.37,26 15.1,25.27 JIOL1.6
  BOTTOM w0.508: C1101.2 14.27,26.56 v1(14.35,26.63)
  vias: v1(122.8,30.89) v1(122.82,30.09)
+3VS_CAM: length 44.7
  IN3 w1.016: 180.72,79.38 177.34,79.38 175.84,77.88 174.54,77.88 173.91,77.24 173.91,73.18 176.85,70.23 177.74,70.23 178.29,69.68 178.29,68.96 177.96,68.63 177.96,68.38 175.69,66.1 175.69,58.03 176.6,57.11 176.6,49.14 178.84,46.9 179.7,46.9
  BOTTOM w0.254: JLVDS2.4 183.74,80.6 v1(183.85,80.71)
  vias: v1(178.71,74.74) v1(179.27,75.1) v1(180.68,34.38) v1(183.87,81.37) v3(181.3,34.35) v7(178.84,75.82)
+3VS_NGFF: length 7.1
  TOP w0.508: v1(196.9,43.01) 196.91,43 R1137.1 R1197.1 196.91,39.55 196.55,39.19 196.55,38.23 196.92,37.86 Q346.2 ; v1(189.12,38.01) 189.67,37.46 R942.1
  vias: v1(180.35,43.7) v1(180.44,44.36) v1(181.45,43.12) v1(182.01,42.48) v1(182.01,41.83) v1(182,41.16) v1(182.11,43.12) v1(197.89,43.07) v1(198.77,43.12) v1(199.41,43.09) v7(179.5,44.16)
+3VS_TOUCH: length 118.2
  TOP w0.508: v1(145.49,25.67) 145.35,25.53 145.35,22.95 145.02,22.62 C1225.1
  IN2 w0.508: v1(167.93,75.01) 165.72,77.22 v1(158.6,77.22) ; v1(145.49,25.67) 145.68,25.86 145.68,26.72 143.77,28.63 136.02,28.63 135.76,28.89 v1(135.02,28.89) 134.22,28.89 133.69,28.36 123.3,28.36 118.5,33.16 118.5,35.65 114.59,39.56 v1(114.56,39.56)
  IN3 w0.508: 113.24,64.36 113.24,64.24 110.23,61.23 110.23,50.18 113.2,47.21 113.2,46.24 114.56,44.88 v1(114.56,39.56) ; 113.24,64.36 113.24,65.58 112.8,66.01 112.22,66.01 110.64,67.6 110.64,70.5 108,73.14 v1(105.14,73.14) ; 113.24,64.36 115.87,64.36 118.38,61.85 118.38,60.68 v1(118.57,60.49)
  BOTTOM w0.254: MD90.5 158.27,74.26 158.76,74.74 158.76,75.63 ; JLVDS1.17 158.25,78.83
  BOTTOM w0.508: RH365.2 RH364.2 104.38,74.48 105.14,73.72 v1(105.14,73.14) ; v1(135.02,28.89) 135.02,28.8 134.42,28.2 Q364.2 133.36,28.2 R1299.1 ; JTP1.1 145.72,25.9 v1(145.49,25.67) ; R1385.1 167.63,74.59 167.93,74.88 v1(167.93,75.01) 167.45,75.49 Q363.2
  vias: v1(119.18,60.31) v1(157.97,77.22) v4(139.43,66.97) v4(139.73,66.46) v4(140.06,66.99) v4(140.34,66.36) v4(140.65,66.94) v4(141.23,66.94) v7(158.25,76.63)
+3VS_TPM: length 82.8
  TOP w0.254: U698.5 131.91,62.19 131.99,62.27 132.37,62.27 132.48,62.15 v3(132.48,61.79)
  TOP w0.356: v1(137.93,67.97) 138.23,67.97 139.09,68.82 U652.19 ; U652.10 135.53,68.82 135.95,69.24 v3(135.97,69.24)
  TOP w0.381: C1139.1 v6(133.28,68.12) C1135.1 133.88,68.72 133.98,68.82 U652.10 ; C1138.1 142.06,72.8 141.33,72.07 U652.24 ; C1136.1 133.31,72.07 U652.5
  TOP w0.508: v3(142.21,70.61) 142.06,70.76 142.06,72.8 ; C1138.1 C1137.1 ; C1136.1 R975.2 132.07,71.92 v1(131.59,72.4) 131.59,73.25 v2(132.07,73.74) C1140.1
  GND1 w0.254: v6(156.5,72.5) v6(156.5,72.12) 157.09,72.12 v4(157.13,72.16)
  GND1 w0.508: v6(133.28,68.12) 133.28,68.2 v4(133.59,68.5)
  IN3 w0.508: v1(137.93,67.97) 138.81,68.85 138.81,69.94 139.5,70.64 142.21,70.64 ; 142.21,70.64 v3(142.21,70.61) ; 142.21,70.64 142.21,70.93 142.64,71.36 147.26,71.36 148.48,72.58 148.48,76.16 147.81,76.83 147.81,78.66 148.5,79.35 158.12,79.35 160.28,77.19 160.28,74.87 157.58,72.16 v4(157.13,72.16) ; v4(133.59,68.5) 133.59,70.41 v1(131.59,72.4)
  BOTTOM w0.508: v3(132.48,61.79) 133.9,63.21 133.9,66.24 134.73,67.07 137.21,67.07 137.93,67.79 v1(137.93,67.97) 137.95,67.97 138.93,68.95 138.93,69.91 138.31,70.54 136.65,70.54 135.94,69.82 135.94,69.28 v3(135.97,69.24)
+5V_USB_P0: length 3.2
  BOTTOM w0.305: C1110.1 213.75,53.49 213.47,53.77 213.47,54.14 213.09,54.52 MD82.8
  vias: v1(213.05,50) v1(213.68,50) v1(214.32,50) v7(216.89,52.3)
+5V_USB_P1:
  vias: v1(209.24,42.51) v1(210.12,42.38) v1(210.75,42.13) v1(210.88,41.49) v1(211.4,42.13) v1(211.51,41.49) v1(214.07,30.52) v1(214.05,29.81) v1(214.78,30.62) v1(215.49,30.63) v1(215.97,31.15) v7(209.76,42.93)
+5VA: length 418.7
  TOP w0.203: U664.4 129.85,32.6 v1(130.06,32.4) ; U718.4 175.3,37.12 ; U717.4 135.49,22.44 135.21,22.72 135.21,22.97 ; PU601.12 42.89,20.77 v1(42.95,20.71) ; U716.4 167.08,45.68 167.28,45.48 167.6,45.48 C1254.1
  TOP w0.254: U676.5 172.74,62.97 172.94,63.17 v1(172.94,63.49) ; U673.2 114.23,69.05 114.76,69.58 C1241.1
  TOP w0.508: v1(206.56,21.55) 207.83,20.28 218.37,20.28 v1(219.77,21.68) 220.23,21.68 220.43,21.48 Q358.3 ; v1(26.05,85.66) 26.11,85.61 PR731.2 ; v1(220.68,26.45) 221.14,26 Q357.3 ; R1341.2 95.04,49.25 97.77,46.52 107.49,46.52 v1(107.51,46.49) ; v1(191.22,74.99) 191.27,75.04 PR104.2 ; v1(173.18,36.86) 173.55,37.22 C1203.1 174.42,37.12 175.3,37.12 ; v1(14.8,20.92) 14.73,20.99 14.2,20.99 C1098.2 14.02,21.7 15.15,22.82 v1(15.95,22.82) ; v1(169.77,44.58) 169.76,44.58 169.34,45 C1254.1 ; v1(116.97,69.99) 116.49,70.47 115.22,70.47 114.76,70.02 C1241.1 ; R920.2 228.73,3.97 228.67,4.03 v1(228.65,4.03)
  IN1 w0.508: v4(109.76,27.23) 111.49,28.96 111.49,34.31 110.88,34.92 110.88,44.59 108.97,46.49 v1(107.51,46.49)
  IN2 w0.508: v1(191.22,74.99) 191.22,74.78 190.29,73.85 178.05,73.85 v1(174.72,70.52) ; v4(111.68,77.46) 112.29,78.07 136.88,78.07 139.02,80.21 143.8,80.21 v1(145.17,78.84)
  IN3 w0.508: 172.99,43.6 170.75,43.6 v1(169.77,44.58) ; 172.99,43.6 173.44,43.15 174.47,43.15 174.92,42.7 174.92,40.68 174.59,40.35 174.59,37.91 173.54,36.86 v1(173.18,36.86) 172.14,35.81 171.01,35.81 168.96,33.76 168.47,33.76 166.78,32.07 v1(164.04,32.07) ; 172.99,43.6 173.4,44.01 173.4,47.1 175.14,48.84 175.14,56.03 173.32,57.85 173.32,63.11 v1(172.94,63.49) ; v1(135.87,35.47) 135.87,39.24 131.38,43.74 131.38,49.2 131.46,49.29 131.46,54.58 130.06,55.99 124.77,55.99 124.09,56.68 124.09,63.44 123.74,63.78 122.6,63.78 121.58,62.76 120.86,62.76 120.3,63.32 120.3,63.54 119.76,64.08 118.14,64.08 116.24,65.99 116.24,68.2 116.97,68.94 v1(116.97,69.99) 116.97,70.69 116.56,71.11 115.21,71.11 113.32,73 113.32,75.82 v4(111.68,77.46) 109.72,79.41 109.72,80.9 106.58,84.04 92.08,84.04 89.64,81.6 81.72,81.6 80.19,83.12 71.23,83.12 70.54,83.81 59.86,83.81 58.47,82.41 54.43,82.41 53.65,83.19 53.65,83.99 53.14,84.49 51.61,84.49 49.68,82.56 40.43,82.56 39.72,81.85 33.83,81.85 31.41,84.26 31.41,84.57 30.74,85.24 29.98,85.24 29.56,84.82 26.89,84.82 v1(26.05,85.66) ; v1(145.17,78.84) 146.31,79.98 159.99,79.98 161.07,78.91 161.07,74.54 159.32,72.78 159.32,71.79 158.53,71.01 154.36,71.01 v1(153.74,71.63) ; v1(219.77,21.68) 220.5,20.94 227.2,20.94 229.32,18.82 229.32,15.29 228.44,14.41 228.44,8.32 227.93,7.81 227.93,6.64 228.62,5.96 228.62,4.05 v1(228.65,4.03)
  BOTTOM w0.203: PU501.18 141,78.94 141.29,79.24 142.53,79.24 142.79,78.97 142.79,78.54 142.37,78.12 PR505.1
  BOTTOM w0.254: v1(14.8,20.92) 15.1,20.62 JIOL1.5 ; PR505.1 142.39,77.94 PC504.1
  BOTTOM w0.508: Q356.3 v1(219.91,23.41) ; Q354.3 219.13,23.25 v1(219.56,22.82) ; Q355.3 221.15,26.92 v1(220.68,26.45) ; v1(174.72,70.52) 177.98,70.52 179.33,69.18 179.33,67.46 178.07,66.21 178.07,64.11 176.69,62.73 173.71,62.73 v1(172.94,63.49) ; v1(145.17,78.84) 144.19,78.84 PC504.1
  vias: v1(45.28,21.98) v1(46.04,21.98) v1(131.67,29.71) v1(132.18,30.16) v1(132.66,30.7) v1(134.54,32.6) v1(135.05,33.11) v1(135.87,34.77) v1(135.88,34.04) v1(203.51,21.55) v1(204.27,21.55) v1(204.27,20.79) v1(205.04,21.55) v1(205.04,20.79) v1(205.8,21.55) v1(205.8,20.79) v1(219.78,26) v1(219.78,25.23) v1(227.93,25.13) v1(227.93,24.19) v7(129.74,36.55)
+5VDX_LX: length 3.1
  BOTTOM w0.508: PR314.1 205.57,51.43 PL303.1
  vias: v1(205.52,50.38) v1(205.51,49.42) v1(206.27,50.36) v1(206.29,49.44) v1(207,50.36) v1(206.98,49.44) v2(206.65,49.89)
+5VDX_VIN:
  vias: v7(199.33,47.24)
+5VDX_WALKPORT: length 15.3
  TOP w0.254: v1(208.74,37.6) R1165.2 R1213.2
  TOP w0.508: v3(202.76,39.15) R1167.2
  IN3 w0.254: v1(208.74,37.6) 204.31,37.6 v3(202.76,39.15) 202.76,39.37 203.25,39.85 203.25,43.18 v1(204.17,44.11)
  vias: v1(202.37,44.87) v1(202.7,44.13) v1(203.03,44.87) v1(203.44,44.13) v1(203.73,44.89) v1(210.52,48.22) v1(210.52,47.59) v1(210.55,46.9) v1(210.52,46.27) v1(211.12,47.28) v1(211.14,46.49) v7(209.77,47.55)
+5VDXP: length 31
  TOP w0.254: v1(208.06,48.7) 207.35,47.99 v2(206.65,47.99) 202.83,47.99 202.5,48.32 PU302.14 ; v1(204.81,55.21) PC312.1 PR315.1 203.16,55.21 202.62,55.21 PR316.2
  IN4 w0.254: v1(208.06,48.7) 208.06,47.9 207.51,47.36 201.47,47.36 200.4,48.43 200.4,54.8 200.88,55.28 204.73,55.28 v1(204.81,55.21)
+5VS: length 295.8
  TOP w0.102: v1(179.94,31.74) v7(179.28,31.74)
  TOP w0.381: UV1.16 203.94,77.03 204.45,76.52
  TOP w0.508: v1(203.66,73.94) 204.13,73.47 CV13.1 204.45,73.62 204.45,76.52 ; v1(22.13,77.56) 22.14,77.57 PR738.2 ; Q329.3 171.94,30.06 171.8,29.92 v1(171.08,29.92) ; QV2.2 211.28,63.91 v1(211.25,63.87) ; v1(113.3,79.07) 113.09,78.85 QC5.2 ; v1(175.46,26.84) R989.2 ; v1(8.82,20.66) 8.85,20.69 R886.2 ; C1102.2 7.93,19.9 v1(7.93,20.54) ; PR720.2 33.73,77.25 32.95,76.47 v1(32.95,76.37)
  IN1 w0.508: v4(195.59,42.01) 196.82,40.78 196.82,39.45 196.51,39.14 196.51,37.59 195.25,36.33 193.65,36.33 192.89,35.57 192.89,35.01 192.36,34.48 187.55,34.48 186.48,33.41 183.26,33.41 v1(181.55,31.71) ; v1(180.94,83.34) 180.3,82.69 177.79,82.69 176.98,83.5 172.74,83.5 171.61,84.63 158.86,84.63 157.48,83.25 148.05,83.25 146.48,81.67 137.16,81.67 135.55,83.28 135.55,83.99 135,84.54 125.56,84.54 v4(124.67,83.65)
  IN3 w0.508: v1(22.13,77.56) 22.13,77.08 21.83,76.77 21.83,75.88 21.41,75.46 21.41,70.6 21.69,70.32 ; v4(124.67,83.65) 124.37,83.65 120.68,79.97 113.66,79.97 113.3,79.62 v1(113.3,79.07) ; 21.69,70.32 21.69,67.45 20.58,66.34 20.58,57.14 18.69,55.24 18.69,48.53 17.77,47.61 17.77,43.32 15.95,41.49 15.95,31.27 13,28.32 13,27.91 8.82,23.74 v1(8.82,20.66) ; 21.69,70.32 25.12,70.32 26.49,68.95 v1(26.89,68.95) 29.66,68.95 30.5,68.11 35.55,68.11 v1(36.93,69.48) 37.38,69.94 37.38,70.28 39.36,72.26 39.36,74.65 38.39,75.63 33.69,75.63 v1(32.95,76.37) ; v1(211.25,63.87) 212.22,64.85 212.22,71.96 208.41,75.77 205.49,75.77 v1(203.66,73.94)
  IN4 w0.508: v4(195.59,42.01) 196.21,42.63 196.21,51.7 196.13,51.78 196.13,68.11 201.52,73.49 203.22,73.49 v1(203.66,73.94) 203.66,74.74 199.84,78.56 193.96,78.56 190.17,82.35 181.91,82.35 180.94,83.32 v1(180.94,83.34)
  BOTTOM w0.203: 37.66,70.3 PU702.2 ; 28.12,70.12 28.49,70.48 PU703.2
  BOTTOM w0.508: JFAN1.4 7.98,21.5 7.73,21.25 7.73,20.74 v1(7.93,20.54) ; v1(26.89,68.95) 27.54,69.6 PC723.1 28.12,70.12 ; v1(36.93,69.48) PC713.1 37.66,69.51 37.66,70.3
  vias: v1(138.17,24.5) v1(138.78,24.8) v1(138.86,24.17) v1(139.54,23.84) v1(139.57,24.5) v1(173.98,27.04) v1(174.01,26.35) v1(180.79,31.71)
+5VS_AUDIO: length 0.6
  TOP w0.102: 121.91,34.63 v7(121.36,34.63)
  vias: v1(12.12,24.6) v1(12.08,23.94) v1(12.72,23.94) v1(12.81,24.63) v1(122.1,34.01) v1(122.2,35.07) v1(122.52,34.51) v1(122.86,35.07) v1(122.88,33.97)
+5VS_KBL: length 2.7
  TOP w0.102: v1(181.92,29.17) v7(181.92,29.78)
  BOTTOM w0.508: JBL1.4 172.05,29.07 v1(171.14,28.16)
  vias: v1(170.49,28.16) v1(182.56,29.17)
+V1.05A_AOSCSUS: length 9.3
  IN3 w0.508: v1(100.21,70.1) 100.11,70 98.9,70 98.64,69.74 95.33,69.74 94.65,69.05 94.37,69.05 93.66,68.34 92.36,68.34 v1(92.29,68.26)
  BOTTOM w0.305: v1(92.29,68.26) 92.04,68.01 UCPU1.AB8
  vias: v2(101.06,71.44)
+V1.05A_AOSCSUS_L: length 2.6
  TOP w0.102: L63.2 103.74,71.37 v2(102.27,72.85)
+V1.05A_DCPSUS: length 33.1
  IN3 w0.508: v4(89.9,69.56) 91.93,69.56 93.33,70.95 93.63,70.95 94.5,71.82 97.44,71.82 98.53,72.91 99.96,72.91 100.95,71.92 102.39,71.92 103.61,73.14 v1(104.27,73.14)
  IN4 w0.508: v4(89.22,64.39) 89.07,64.54 89.07,66.06 89.49,66.48 90.64,66.48 v4(90.75,66.59) 90.75,68.26 89.86,69.15 89.86,69.52 v4(89.9,69.56) 89.86,69.6 89.86,71.44 90.39,71.97 90.39,72.8 89.89,73.3 v4(89.89,74.1)
  GND5 w0.254: v4(89.89,74.1) 89.76,74.23 89.28,74.23 v5(89.26,74.25) ; v5(90.39,66.99) 90.75,66.64 v4(90.75,66.59) ; v5(88.89,64.02) 89.22,64.35 v4(89.22,64.39)
  BOTTOM w0.254: v5(90.39,66.99) 90.39,66.98 90.52,66.85 UCPU1.AD10 UCPU1.AD8 ; v5(88.89,64.02) 89.25,64.38 UCPU1.AH13 ; UCPU1.J13 v5(89.26,74.25)
  vias: v2(104.02,72.64)
+V1.05S_APLLOPI: length 0.6
  TOP w0.076: v2(83.56,75.07) 83.56,74.46
  vias: v1(86.04,68.78) v1(86.68,68.78)
+V1.05S_ASATA3PLL: length 10.4
  BOTTOM w0.381: v1(95.66,85.28) 95.66,83.83 95.16,83.32 RH43.2 94.81,83.03 94.52,82.74 93.92,82.74 93.23,82.04 v2(92.68,82.04) 91.4,82.04 89.51,80.15 UCPU1.A12 89.51,79.65 89.92,79.24 89.92,79.22 UCPU1.B11
+V1.05S_AUSB3PLL: length 24.8
  TOP w0.508: RH338.1 80.27,83.31 79.8,82.84 79.8,81.43 v1(80.23,81)
  IN3 w0.508: v1(80.23,81) 80.23,80.59 81.06,79.77 85.73,79.77 86.15,79.35 v4(86.15,78.75) 86.18,78.73 86.93,78.73 87.51,78.14 89.75,78.14 90.18,78.57 90.18,79.4 92.46,81.69 v1(95.14,81.69)
  GND5 w0.254: v4(86.15,78.75) 86.14,78.75 86.14,79.43 v5(86.15,79.43)
  BOTTOM w0.254: v1(80.23,81) 80.23,80.54 80.41,80.37 80.41,79.72 80.64,79.49 80.66,79.49 80.78,79.37 UCPU1.B27 ; v5(86.15,79.43) 85.95,79.43 85.75,79.23 UCPU1.B18
  vias: v2(95.37,79.9)
+V1.05S_AXCK_DCB: length 1.4
  BOTTOM w0.254: 85.99,74.92 85.95,74.88 85.95,74.18 UCPU1.K19 ; 85.99,74.92 v1(85.97,74.92) ; 85.99,74.92 86.02,74.95 86.02,74.96 86.35,74.63 UCPU1.J18
  vias: v2(87.03,78.02)
+V1.05S_AXCK_DCB_L: length 1.1
  TOP w0.102: 90.23,81.5 89.2,81.5 v2(89.16,81.46)
+V1.05S_AXCK_LCPLL: length 8.1
  TOP w0.508: v1(83.28,80.94) 83.28,81.22 82.85,81.65 82.37,81.65 82.11,81.9 82.11,82.92 81.72,83.31 RH113.2
  BOTTOM w0.508: 85.9,81.62 85.62,81.34 85.62,80.37 UCPU1.A20 ; v1(83.28,80.94) 83.28,81.28 83.76,81.76 83.85,81.76 83.87,81.78 84.46,81.78 84.47,81.8 85.14,81.8
  vias: v1(88.17,84.9) v2(85,83.17)
+V1.05S_AXCK_LCPLL_L:
  vias: v2(94.18,82.08)
+V1.05VS_VCCHSIO: length 2.1
  GND5 w0.254: v5(91.22,73.98) 91.73,73.98 v4(91.75,74) ; v5(91.57,73.57) 91.75,73.75 v4(91.75,74) ; v1(92.35,74.1) 92.24,74 v4(91.75,74) ; v4(91.75,74) 91.75,74.08 v5(91.48,74.35)
  vias: v1(91.65,76.31) v1(92.6,77.02) v1(92.59,76.38) v7(92.04,76.76)
+V5A_LX:
  vias: v1(211.32,24.8) v1(211.35,24.14) v1(211.35,23.46) v1(214.14,25.03) v1(214.14,24.37) v1(214.12,23.63) v2(211.97,22.9)
+V5A_VIN: length 1
  TOP w0.102: v2(201.04,27.12) 202,27.12 202.01,27.13
+V5AP: length 14.5
  TOP w0.102: v2(210.48,32.45) 210.45,32.45 210,32
  TOP w0.254: PR306.2 209.49,31.51 v1(209.99,32) 210,32 210.48,31.52 PC304.1 PR305.1 ; PU301.14 v6(209.71,25.18)
  GND1 w0.254: v4(209.29,25.6) 209.71,25.18 v6(209.71,25.18)
  IN3 w0.254: v1(206.09,24.35) 206.09,24.73 208.16,26.8 208.16,30.18 v1(209.99,32)
  GND5 w0.254: v4(209.29,25.6) 209,25.6 v5(208.87,25.48)
+V18R: length 7
  TOP w0.102: v2(142.26,65.95) 142.62,65.6 v1(143.05,65.6)
  TOP w0.203: U34.L1 v6(140.42,62.42)
  TOP w0.508: v1(143.05,65.6) 143.34,65.3 C293.1
  GND1 w0.203: v4(140.79,63.06) 140.43,62.7 140.43,62.43 v6(140.42,62.42)
  IN4 w0.508: v1(143.05,65.6) 143.05,64.81 142.72,64.48 142.69,64.48 142.03,63.82 141.21,63.82 140.79,63.4 v4(140.79,63.06)
+VCC_CORE: length 70.4
  TOP w0.508: v1(52.05,83.19) 52.83,83.19 55.96,80.06 55.96,77.38
  BOTTOM w0.102: UCPU1.AB57 61.34,67.65 ; UCPU1.AB57 61.79,68.09 61.79,68.2 ; UCPU1.AB57 61.38,68.06 61.38,68.22 ; UCPU1.AB57 61.75,67.69 61.75,67.56 ; UCPU1.G27 80.95,76.57 80.95,76.74 ; UCPU1.G27 80.52,76.14 ; UCPU1.G27 80.91,76.28 80.91,76.05 ; UCPU1.G27 80.54,76.65 ; UCPU1.G25 82.19,76.12 ; UCPU1.G25 81.71,76.61 81.71,76.75 ; UCPU1.G25 82.2,76.7 ; UCPU1.G25 81.81,76.3 81.81,76.03 ; 65.94,76.76 65.94,76.6 UCPU1.G51 ; 76.71,76.76 76.71,76.59 UCPU1.G33 ; 80.36,76.99 UCPU1.F28 ; UCPU1.F28 79.86,76.96 79.76,76.96 ; UCPU1.F28 79.84,76.47 ; UCPU1.F28 80.3,76.53 80.3,76.42 ; 82.86,76.99 UCPU1.F24 ; UCPU1.F24 82.31,76.44 ; UCPU1.F24 82.33,77 ; UCPU1.F24 82.85,76.48 ; UCPU1.G33 77.06,76.57 77.06,76.73 ; UCPU1.G33 77.15,76.15 ; UCPU1.G33 76.85,76.35 76.85,76.06 ; UCPU1.M23 83.64,73.11 83.64,72.88 ; UCPU1.M23 83.23,72.96 ; UCPU1.M23 83.71,73.45 83.71,73.55 ; UCPU1.M23 83.28,73.47 83.28,73.57 ; 74.17,76.79 74.17,76.62 UCPU1.G37 ; 78.44,76.75 78.44,76.57 UCPU1.G31 ; 83.7,73.7 83.7,73.87 UCPU1.K23 ; UCPU1.F48 67.77,76.52 67.77,76.4 ; UCPU1.F48 67.31,76.48 ; UCPU1.F48 67.81,76.99 ; UCPU1.F48 67.32,76.96 67.32,77.01 ; 61.72,65.66 61.72,65.43 UCPU1.AG57 ; UCPU1.G31 78.08,76.21 77.92,76.21 ; UCPU1.G31 78.07,76.61 78.07,76.73 ; UCPU1.G31 78.36,76.32 78.36,76.05 ; UCPU1.W57 61.79,69.39 61.79,69.47 ; UCPU1.W57 61.79,68.96 61.79,68.87 ; UCPU1.W57 61.37,69.37 61.37,69.51 ; UCPU1.W57 61.32,68.92 ; 61.71,70.83 61.71,70.62 UCPU1.U57 ; UCPU1.G35 75.47,76.1 ; UCPU1.G35 75.89,76.28 75.89,76.06 ; UCPU1.G35 75.94,76.58 75.94,76.76 ; UCPU1.G35 75.6,76.57 75.6,76.74 ; 70.54,76.74 70.54,76.62 UCPU1.G43 ; UCPU1.U57 61.84,70.2 ; UCPU1.U57 61.46,70.59 61.46,70.82 ; UCPU1.U57 61.41,70.31 61.41,70.14 ; UCPU1.G37 74.57,76.58 74.57,76.74 ; UCPU1.G37 74.59,76.2 74.59,76.07 ; UCPU1.G37 74.29,76.31 74.29,76.05 ; UCPU1.M57 61.35,73.29 61.35,73.36 ; UCPU1.M57 61.79,73.3 61.79,73.34 ; UCPU1.M57 61.79,72.86 61.79,72.77 ; UCPU1.M57 61.37,72.88 61.37,72.76 ; 70.31,76.98 UCPU1.F44 ; UCPU1.F44 69.79,77.01 ; UCPU1.F44 69.8,76.46 ; UCPU1.F44 70.25,76.54 70.25,76.37 ; UCPU1.G43 70.9,76.26 70.9,76.05 ; UCPU1.G43 70.45,76.1 ; UCPU1.G43 70.94,76.59 70.94,76.75 ; UCPU1.G51 65.85,76.29 65.85,76.07 ; UCPU1.G51 65.52,76.62 65.52,76.72 ; UCPU1.G51 65.43,76.1 ; UCPU1.G41 72.17,76.11 ; UCPU1.G41 71.67,76.61 71.67,76.75 ; UCPU1.G41 72.05,76.57 72.05,76.74 ; UCPU1.G41 71.87,76.4 71.87,76.06 ; 61.8,71.54 UCPU1.P57 ; UCPU1.P57 61.39,71.95 61.39,72.11 ; UCPU1.P57 61.33,71.54 ; UCPU1.P57 61.75,71.96 61.75,72.1 ; 61.43,64.92 61.43,65.14 UCPU1.AG57 ; 66.8,76.06 66.8,76.34 UCPU1.G49 ; UCPU1.K23 83.63,74.18 83.63,74.5 ; UCPU1.K23 83.23,74.33 ; UCPU1.K23 83.27,73.82 ; UCPU1.G23 83.07,76.62 83.07,76.72 ; UCPU1.G23 83.01,76.12 ; UCPU1.G23 83.48,76.59 83.48,76.75 ; UCPU1.G23 83.47,76.22 83.47,76.07 ; UCPU1.AD57 61.76,66.38 61.76,66.26 ; UCPU1.AD57 61.82,66.83 ; UCPU1.AD57 61.3,66.31 ; UCPU1.AD57 61.37,66.77 61.37,66.88 ; 79.21,76.76 79.21,76.6 UCPU1.G29 ; 64.76,76.96 64.81,76.96 UCPU1.F52 ; UCPU1.G47 67.98,76.14 ; UCPU1.G47 68.39,76.26 68.39,76.06 ; UCPU1.G47 68.44,76.6 68.44,76.77 ; UCPU1.G47 68,76.64 ; UCPU1.F40 72.78,76.52 72.78,76.41 ; UCPU1.F40 72.31,76.99 ; UCPU1.F40 72.82,76.98 ; UCPU1.F40 72.3,76.46 ; 73.4,76.06 73.4,76.26 UCPU1.G39 ; UCPU1.G53 64.24,76.28 64.24,76.05 ; UCPU1.G53 64.57,76.61 64.57,76.75 ; UCPU1.G53 64.59,76.17 ; UCPU1.G53 64.15,76.61 64.15,76.8 ; UCPU1.G39 73.06,76.6 73.06,76.72 ; UCPU1.G39 73.44,76.58 73.44,76.75 ; UCPU1.G39 73,76.14 ; 61.72,74.08 61.72,74.22 UCPU1.K57 ; UCPU1.G57 61.85,76.4 61.85,76 ; UCPU1.G57 61.96,76.52 61.96,76.78 ; UCPU1.G57 62.07,76.19 62.14,76.19 ; UCPU1.G57 61.63,76.62 61.63,76.77 ; UCPU1.G29 79.61,76.61 79.61,76.68 ; UCPU1.G29 79.24,76.24 79.24,76.05 ; UCPU1.G29 79.64,76.16 ; 83.62,76.02 83.62,75.79 UCPU1.H23 ; UCPU1.H23 83.21,75.38 ; UCPU1.H23 83.62,75.57 83.62,75.35 ; UCPU1.H23 83.28,75.91 ; 63.04,76.76 63.04,76.59 UCPU1.G55 ; 66.68,76.75 66.68,76.59 UCPU1.G49 ; UCPU1.G45 69.22,76.56 69.22,76.75 ; UCPU1.G45 69.62,76.15 ; UCPU1.G45 69.57,76.6 69.57,76.73 ; UCPU1.G45 69.34,76.37 69.34,76.05 ; UCPU1.J23 83.25,75.12 ; UCPU1.J23 83.23,74.59 ; UCPU1.J23 83.63,74.74 83.63,74.5 ; UCPU1.J23 83.62,74.98 83.62,75.21 ; 65.31,76.99 UCPU1.F52 ; UCPU1.F52 64.77,76.45 ; UCPU1.F52 65.23,76.55 65.23,76.38 ; UCPU1.AG57 61.56,65.27 61.35,65.48 61.35,65.61 ; UCPU1.AG57 61.8,65.04 ; 63.45,76.75 63.45,76.62 UCPU1.G55 ; UCPU1.F36 75.33,76.48 ; UCPU1.F36 75.37,77.02 ; UCPU1.F36 74.83,76.98 ; UCPU1.F36 74.81,76.46 ; UCPU1.G49 67.04,76.58 67.04,76.73 ; UCPU1.G49 67.14,76.12 ; UCPU1.K57 61.38,74.56 61.38,74.69 ; UCPU1.K57 61.32,74.13 ; UCPU1.G55 63.34,76.3 63.34,76.05 ; UCPU1.G55 62.95,76.13 ; UCPU1.F32 77.33,76.47 ; UCPU1.F32 77.8,76.94 77.89,76.94 ; UCPU1.F32 77.38,76.93 77.28,76.93 ; UCPU1.F32 77.76,76.55 77.76,76.4 ; UCPU1.F56 62.76,76.95 62.84,76.95 ; UCPU1.F56 62.82,76.45 ; UCPU1.F56 62.27,77 ; UCPU1.F56 62.27,76.46
  BOTTOM w0.254: UCPU1.F59 60.71,76.38 61.01,76.09 v1(61.01,76.06)
  BOTTOM w0.508: RC97.1 v1(52.05,83.19)
  vias: v1(23.36,58.25) v1(24.31,61.34) v1(24.52,58.38) v1(24.8,62.09) v1(25.56,62.85) v1(25.61,61.2) v1(26.07,63.49) v1(26.12,62.04) v1(26.75,62.9) v1(26.75,61.3) v1(27.39,62.14) v1(27.49,63.51) v1(27.46,61.35) v1(28.05,62.22) v1(28.28,62.85) v1(28.3,61.46) v1(28.63,63.49) v1(28.76,62.12) v1(32.04,64.48) v1(31.96,62.14) v1(32.71,63.59) v1(33.13,64.33) v1(33.13,62.85) v1(33.18,61.58) v1(33.92,63.61) v1(33.89,62.27) v1(33.9,60.01) v1(33.98,61.05) v1(34.6,64.33) v1(34.64,61.58) v1(34.59,60.41) v1(34.61,59.65) v1(34.68,62.93) v1(39.73,67.91) v1(39.73,67.02) v1(39.73,64.99) v1(39.73,63.97) v1(40.18,70.9) v1(41.29,72.3) v1(41.96,72.96) v1(42.03,72.3) v1(42.01,70.95) v1(42.01,70.07) v1(42.01,67.91) v1(42.01,67.02) v1(42.01,64.99) v1(42.01,63.97) v1(44.35,72.26) v1(44.3,70.95) v1(44.3,67.91) v1(44.3,64.99) v1(46.63,72.91) v1(46.6,72.22) v1(46.63,70.93) v1(46.58,67.91) v1(46.58,64.99) v1(48.87,67.91) v1(48.87,64.99) v1(51.1,67.83) v1(51.18,71.11) v1(51.16,64.99) v1(55.4,64.54) v1(55.67,66.74) v1(62.03,73.91) v1(62.12,70.79) v1(62.19,72.19) v1(62.26,75.72) v1(62.3,74.84) v1(62.33,69.76) v1(62.26,68.99) v1(62.29,68.29) v1(62.29,67.4) v1(62.57,77.36) v1(63.21,75.65) v1(64.35,75.78) v1(65.05,77.3) v1(65.74,75.77) v1(66.87,75.77) v1(67.53,77.3) v1(68.24,75.78) v1(69.37,75.78) v1(70.07,77.3) v1(70.78,75.78) v1(71.91,75.78) v1(72.54,77.3) v1(73.26,75.78) v1(74.38,75.78) v1(75.08,77.3) v1(75.58,75.7) v1(76.86,75.78) v1(77.57,75.78) v1(78.27,75.72) v1(79.42,75.7) v1(80.08,75.7) v1(80.74,75.7) v1(81.99,75.68) v1(82.67,75.68) v1(82.83,74.83) v1(82.83,73.7) v4(56.33,71.06) v4(57.2,74.49) v4(60.68,67.78) v7(55.82,73.13)
+VCCIO_OUT: length 5.5
  BOTTOM w0.254: UCPU1.A59 60.72,81.68 59.46,82.94 59.41,82.94 v2(59.13,83.22) 59.13,83.25 58.16,84.21 CH1241.1
+VCCIOA_OUT: length 3.3
  TOP w0.076: v7(84.58,77.33) 85,76.91 RC36.2
  TOP w0.457: v6(86.14,77.1) 85.95,76.91 RC36.2
  GND1 w0.254: v6(86.14,77.1) 86.14,77.33 v4(86.34,77.53)
  GND5 w0.254: v5(85.82,77.51) 86.32,77.51 v4(86.34,77.53)
  BOTTOM w0.254: v5(85.82,77.51) 85.74,77.51 85.47,77.24 UCPU1.E20
+VCCP_D: length 3.2
  TOP w0.508: R297.2 106.89,66.59 v2(106.71,66.76) 106.64,66.84 106.64,68.39 106.84,68.59 Q4.1
DVDD-12-SWR:
  vias: v1(121.89,50.3) v1(121.9,49.67) v2(121.28,49.92)
DVDD_25: length 6.7
  TOP w0.102: UA1.43 129.47,44.54 129.83,44.89 v2(130.16,44.89) v6(130.6,44.89) ; 130.86,43.98 R1186.1 132.62,43.98 CA14.1 133.29,44.63 CA21.1 ; 130.86,43.98 v6(131.39,44.51) ; 130.86,43.98 CA13.1
  GND1 w0.076: v6(131.39,44.51) 131.31,44.51 131.29,44.54 130.96,44.54 v6(130.6,44.89)
GND: length 2959.5
  TOP w0.076: v6(142.63,62.83) 142.63,62.69 142.7,62.62 142.7,62.29 142.67,62.26 142.67,61.85 U34.G2 142.17,61.85 142.17,62.32 v6(142.3,62.45)
  TOP w0.102: v1(192.13,35.39) v7(192.93,35.39) ; 33.42,21.27 33.42,21.03 v7(32.74,20.35) ; v1(184.59,60.29) v7(185.12,60.82) ; v7(194.86,59.87) 194.88,59.86 v1(194.88,59.14) ; U653.12 v6(151.04,82.85) ; U637.7 151.07,52.23 150.77,52.53 150.77,53.8 150.57,54 v6(150.57,54.9) ; v6(146.14,81.01) 146.14,80.16 145.85,79.87 U638.13 ; v7(184.97,72.39) v1(185.62,72.39) ; v1(118.04,29.63) 118.04,30.11 v7(117.75,30.4) ; v7(166.91,70.33) 166.94,70.33 v6(167.66,69.61) ; v1(177.18,58) v7(176.68,57.49) ; U653.13 v6(150.54,82.85) ; U638.8 145.85,75.81 146.1,75.56 147.02,75.56 v6(147.99,76.53) ; U637.10 v6(153.09,49.25) ; v7(211.46,67.16) v1(211.46,66.51) ; v1(131.63,39.04) 132.16,39.04 v7(132.67,38.53) ; v1(183.7,27.77) v7(184.47,27.77) ; U638.12 v6(147.62,78.84) ; U638.11 v6(147.63,78.19) ; U653.10 v6(152.04,82.86) ; U638.10 147.63,77.54 v6(147.63,77.53) 146.99,76.89 U638.9 ; U637.11 v6(153.89,49.28) ; v7(186.46,32.91) v1(187.24,32.91) ; v6(162.49,37.02) v7(162.49,35.86) ; v6(51.4,61.12) v7(51.4,60.25)
  TOP w0.127: U653.16 149.9,80.31 149.79,80.2 149.79,79.84 v6(149.87,79.77) ; U653.5 v6(153.22,79.48) ; v6(146.14,81.01) 146.16,81.03
  TOP w0.203: v6(160.27,65.54) 160.05,65.32 U636.E7 ; U636.H2 161.89,62.82 v6(161.98,62.73) ; U636.B1 158.33,62.1 v6(158.33,61.95) ; v9(167.12,49.06) 167.08,49.01 U716.11 ; v6(157.54,65.37) 157.59,65.32 U636.A7 ; U717.11 139.36,22.44 v1(139.47,22.54) ; v1(38.68,22.72) 38.69,22.71 PU601.1 ; U34.J10 U34.J9 U34.J8 141.53,58.71 v6(141.79,58.71) ; v9(31.15,80.43) 31.04,80.32 PU701.22 ; U719.11 122.36,57.62 v9(122.17,57.81) ; PU701.29 v6(28.12,82.52) ; v9(24.65,55.59) 24.7,55.64 24.7,55.76 24.78,55.85 24.78,55.85 25.04,56.11 JXDP.19 ; U664.11 126.04,32.6 125.91,32.73 v1(125.91,32.7) ; v6(162.08,63.32) U636.H3 ; v6(42.45,21.74) 42.28,21.57 PU601.14 ; U718.11 v6(179.43,37.12)
  TOP w0.229: JKB1.30 v6(169.3,28.52)
  TOP w0.254: v6(209.99,29.88) 210.21,29.66 PU301.6 ; PU305.6 206.53,32.21 v6(206.74,32.42) ; R1118.2 206.99,43.88 US1.14 ; U679.B1 187.43,40.06 v1(187.22,40.27) ; v6(139.2,55.73) 139.2,55.88 U34.N13 ; PU303.6 v6(207.49,62.79) ; RP22.8 137.8,49.89 PR121.1 ; v1(24.52,53.15) 24.56,53.11 JXDP.31 ; JXDP.8 v6(33.15,59.11) ; U714.3 112.03,49.92 112.35,49.59 v1(112.44,49.59) ; JXDP.38 28.22,51.61 v1(28.09,51.47) ; v6(129.67,45.33) 129.39,45.04 UA1.44 ; v1(19.96,51.42) 19.96,51.47 20.19,51.7 JAPS.11 ; v1(134.98,63.94) 135.21,63.72 RP21.7 ; U636.F5 v6(160.77,64.1) ; PU302.6 v6(203,52.76) ; U673.3 v9(113.73,69.13)
  TOP w0.279: JXDP.37 v9(27.55,51.61) ; v6(33.2,54.61) JXDP.26 ; JXDP.50 30.39,48.61 v9(30.36,48.58) ; v6(24.67,48.78) 24.85,48.61 JXDP.49 ; JXDP.20 v9(33.25,56.11) ; JXDP.13 v9(24.65,57.61) ; JXDP.32 v9(33.2,53.11) ; JXDP.25 v9(24.62,54.61) ; JXDP.1 v6(27.62,60.61) ; v6(27.41,59.07) 27.39,59.07 27.39,59.08 27.36,59.11 JXDP.7 ; JXDP.14 v6(33.29,57.61) ; JXDP.2 v9(33.18,60.61)
  TOP w0.305: PQ103.1 136.31,45.68 v6(136.11,45.48) ; v6(128.76,56.2) 128.98,56.2 129.14,56.36 U712.3 ; C1286.2 188.44,48.07 187.09,48.07 186.88,47.86 U677.7 ; v1(134.98,63.94) 134.93,63.89 134.93,63.46 135.17,63.22 RP21.8 ; PQ105.1 113.83,24.79 PR125.1 ; C1260.2 173.93,44.6 v6(173.74,44.41) ; PQ105.4 115.13,27.5 115.36,27.72 v1(116.12,27.72) ; v1(138.2,47.31) 138.06,47.31 PQ103.4 ; JAPS.7 v6(20.23,49.7) ; v6(21.83,50.91) 21.61,50.7 JAPS.9 ; v1(194.19,48.31) 193.97,48.31 193.61,47.95 U671.7 ; U691.3 161.31,49.1 v6(161.7,48.7) ; JXDP.59 27.48,46.11 v9(27.54,46.16) ; JSNRDG.20 175.27,79.58 175.27,78.93 v1(175.42,78.77) ; JAPS.5 v6(20.21,48.7) ; v6(135.99,69.77) 135.78,69.77 135.48,69.47 U652.9 ; MD2.3 v6(218.22,69.94) ; RC154.2 v6(88.58,53.68)
  TOP w0.33: C1283.2 190.35,39.56 v6(190.72,39.19)
  TOP w0.356: U710.3 131.15,64.65 v6(131.34,64.83)
  TOP w0.381: U709.3 172.94,65.51 v1(173.44,65.01) ; v6(101.14,77.15) 100.63,77.15 CH1210.2 100.5,76.92 100.77,76.65 v6(101.12,76.65) ; Q361.1 v6(117.86,77.37) ; U687.3 178.76,51.41 v1(178.82,51.47) ; v1(201.14,76.12) 201.39,76.38 UV1.15 ; C1200.2 157.21,77.7 157.49,77.98 v6(157.49,78.19) ; U635.3 133.27,69.65 C1135.2 ; v6(22.08,56.17) 22.41,56.51 U672.3 ; U676.3 169.73,61.67 169.15,62.26 ; v6(139.61,72.66) 139.67,72.72 U652.25 ; v6(174.63,49.57) 174.71,49.49 U689.3 ; v6(133.62,59.08) 133.21,59.5 U698.3 ; RC156.2 86.14,56.68 v1(86.24,56.57) ; v6(198.5,72.49) 196.7,72.49 UV1.8 ; v6(96.96,78.2) 97.59,78.2 CH1208.2 97.67,78.66 v6(96.95,78.66) ; U652.1 v6(136.08,74.67) ; UA2.3 v6(116.57,41.8) ; UA3.3 v6(116.7,38.88) ; U713.3 123.65,53.96 123.82,54.13 123.82,54.14 v6(123.9,54.22) ; U652.18 v6(139.39,68.17) ; v1(212.29,47.33) 212.82,47.33 213.27,47.78 US2.1 ; U690.3 161.12,51.52 v1(161.12,51.04) ; v1(187.22,40.27) 186.58,40.27 C1284.2 ; C1139.2 133.03,66.56 132.42,67.17 U682.3 ; U652.4 v6(136.11,72.72) ; U652.8 135.46,70.12 135.58,70.24 v6(135.97,70.24) ; U652.2 v6(136.04,74.02) ; U652.3 v6(136.06,73.37)
  TOP w0.406: 216.97,73.49 v1(215.74,73.49) ; U688.2 v6(172.81,47.61) ; Q349.4 v6(171,48.29)
  TOP w0.457: Q349.1 v6(169.7,47.72) ; v9(113.73,69.13) 113.73,69.66 C1228.2 ; PU307.3 v1(211.85,51.01)
  TOP w0.508: v1(102.62,32.09) 102.63,32.09 102.63,32.83 CD69.2 ; v6(86.88,65.14) 86.85,65.11 CH1233.2 ; Q311.3 175.93,29.77 v6(176.27,29.43) ; CH1215.2 v6(87.43,69.71) ; v1(67.57,51.47) 67.55,51.47 67.54,51.49 66.52,51.49 RD23.2 ; CD125.2 29.36,40.17 30.16,40.17 v1(30.23,40.09) ; CD49.2 73.62,29.53 73.62,28.85 v1(73.63,28.84) ; v1(133.2,40.83) 133.41,40.63 CA1.2 ; RV3.2 v6(193.44,75.7) ; PR121.1 137.23,50.2 v1(136.79,49.76) ; v6(146.92,65.42) 146.31,66.03 MC654.2 145.19,66.03 R607.1 ; v6(110.52,67.75) 110.15,68.12 C1243.2 ; CH24.2 v6(86.63,82.51) ; YA1.4 v1(126.17,52.76) ; v1(102.53,36.91) 102.47,36.97 CD83.2 ; CD117.2 77.08,40.86 v1(77.96,40.86) ; CH1203.2 v6(154.31,68.16) ; CD48.1 84.04,35.27 83.6,34.83 v1(83.6,34.46) ; CH23.2 v6(82.72,82.51) ; CD44.2 63.98,30.04 v1(64.51,29.5) 64.19,29.18 CD103.2 ; v6(174.23,66.76) 174.58,67.12 R1026.2 ; v1(112.83,24.47) PR125.1 ; v1(202.66,57.42) 203.21,57.96 PC323.2 ; v1(172.83,84.63) 173.18,84.28 JSNRDG.22 ; CD94.2 v7(96.36,28.03) 97.43,28.03 v1(98.29,28.89) 98.15,29.03 CD72.2 98.08,29.6 MC1268.2 ; v1(85.18,38.46) 85.15,38.49 CD62.2 85.81,39.38 CD98.2 86.44,39.31 86.44,40.04 86.21,40.27 CD61.2 ; v1(168.97,55.69) 168.74,55.46 C721.2 ; v1(133.95,23.1) 133.95,22.66 C1280.1 ; CA7.2 132.21,46.22 131.76,46.67 v6(131.55,46.67) ; C1098.1 12.76,21.17 v1(12.38,20.79) ; PC113.2 v6(137.48,43.48) ; v6(141.38,49.52) 141.8,49.1 PQ202.3 ; R1250.2 v6(170.26,45.4) ; C1199.2 127.46,58.04 v1(127.46,58.88) ; CH1228.2 85.03,79.7 86.28,80.95 v1(86.3,80.95) ; CD88.2 111.18,29.88 110.85,29.55 v1(110.84,29.55) ; v6(94.93,72.92) 95.41,73.41 RH435.2 ; CH1214.2 v6(116.5,63.56) ; v6(133.69,65.89) 133.28,66.29 C1139.2 ; CD24.2 v6(45.85,31) ; C1213.2 131.67,33.27 v1(131.67,32.75) 131.67,32.05 R1140.2 ; v6(97.48,74.43) 97.59,74.32 CH1227.2 ; v1(177.12,24.07) 176.54,24.07 C1160.2 ; v1(179.88,74.82) 180.09,74.6 C1158.2 ; C715.2 v1(180.33,45.35) ; PQ106.3 114.12,58.07 PC116.2 114.68,58.27 114.68,57.96 v1(114.84,57.8) ; v1(181.1,53.1) 181.5,52.69 C1287.2 ; C1102.1 7.09,19.93 v1(7.09,20.61) ; C1162.2 136.46,25.34 135.87,25.92 C1161.2 134.58,26.38 v1(134.58,26.61) ; v6(142.97,74.83) C1137.2 C1138.2 ; CD120.2 53.58,38.11 53.01,38.68 v1(52.99,38.68) ; v1(155.58,81.1) 155.58,80.58 154.85,79.84 C1149.2 ; R1197.2 195.99,39.7 v1(196.07,39.62) ; C1256.2 v6(163.94,47.89) ; C970.2 144.09,81.61 144.28,81.8 145.31,81.8 C974.2 145.77,81.61 146.16,81.22 146.16,81.03 ; v6(149.21,49.72) 148.98,49.49 C283.2 ; CD95.2 v7(96.03,30.92) 97.11,30.92 v1(97.47,31.28) 96.28,32.47 RD11.2 ; RH423.2 128.06,66.78 v6(128.42,67.13) ; CD64.2 83.75,31.52 84.04,31.23 84.39,31.23 84.41,31.25 84.41,31.27 84.42,31.27 v1(84.4,31.27) ; v1(129.78,72.38) 130.44,71.72 R608.1 ; C1292.2 180.02,35.38 v1(180.4,35) ; v1(24.3,34.47) 24.24,34.41 CD16.2 ; v6(121.01,54.56) 121.01,54.91 121.24,55.15 Q5.3 ; v1(59.38,53.94) 59.01,54.31 RC58.2 ; RD5.2 47.78,32.46 48.54,32.46 v1(49.72,31.28) ; C712.2 v1(182.26,46.19) ; v1(66.09,30.24) 66.07,30.24 v7(65.6,29.77) 65.46,29.63 CD106.2 ; v1(86.03,67.96) 85.18,67.96 84.88,67.65 84.39,67.65 84.21,67.48 CH1205.2 ; v1(135.69,53.45) 135.85,53.3 136.23,53.3 R924.1 C1116.1 ; C1159.2 178.49,72.67 v1(178.96,73.14) ; CH1239.2 v6(115.78,61.39) ; v1(208.4,45.38) 208.39,45.38 207.78,44.77 R1118.2 ; v1(62.07,38.46) 62.11,38.51 CD41.2 ; CD19.2 37.22,40.4 36.76,40.86 v1(36.64,40.86) ; C1215.2 179.45,47.26 179.95,47.76 v1(181.07,47.76) C1288.2 ; PR106.1 v1(189.69,80.67) ; MC94.2 95.96,71.77 v6(96.31,72.12) ; CH1211.2 100.55,84.72 v6(100.53,84.75) ; v1(114.08,77.43) 113.46,76.81 C1209.2 ; v1(35.53,19.19) 35.58,19.14 PR610.2 ; U719.15 v6(123.88,59.32) ; RD22.2 61.91,53.61 v1(61.83,53.68) ; RD85.2 96.07,33.36 96.67,33.97 v1(96.67,34.47) ; YH2.2 82.67,85.5 v1(82.43,85.74) ; CA3.2 121.22,37.27 121.44,37.05 v6(121.79,37.05) ; C1259.2 176.47,44.97 v6(176.68,45.17) ; v1(17.51,32.96) RD79.2 RD1.2 ; CA16.2 v6(127.11,49.19) ; v1(66.32,32.82) 66.66,32.49 CD46.2 ; C1281.2 141.56,21.82 141.55,21.81 v1(141.55,21.55) ; LED2.1 230.88,13.13 v1(230.88,12.8) ; R537.2 166.06,58.78 v1(166.06,59.91) ; U716.15 v6(168.69,47.45) ; PR408.2 v6(110.07,82.83) ; v6(113.83,44.27) 113.71,44.4 Q34.3 ; RD81.2 48.22,33.36 48.92,34.07 v1(48.92,34.46) ; R1141.2 v6(153.88,68.92) ; v6(134.2,53.56) 133.97,53.78 C280.1 ; v6(146.26,51.17) 145.56,50.47 L44.1 ; C1254.2 v6(168.67,44.08) ; v1(130.83,52.21) 131.15,52.21 132.14,51.22 CA2.2 131.77,50.58 CA4.2 ; R941.1 131.33,54.11 v6(131.02,54.42) ; C1295.2 v6(109.62,53.44) ; v1(60.48,34.46) 60.48,34.46 60.48,35.06 CD37.2 ; v1(91.02,36.01) 91.02,37.14 90.79,37.38 CD97.2 90.23,38.21 CD115.2 ; v1(157.42,81.04) 157.42,79.25 157.84,78.83 MC1151.2 R545.2 ; v1(18.41,45.66) 18.41,45.64 17.91,45.14 JAPS.19 ; RD86.2 100.77,36.11 RD12.2 100.51,36.82 v1(100.77,37.07) ; v1(18.6,32.09) 18.09,32.09 17.63,31.64 CD1.2 ; v1(97.48,38.47) 97.75,38.47 98.18,38.9 CD81.2 ; v1(66.42,36.08) 65.34,36.08 CD27.1 ; v6(132.33,63.92) 132.15,63.74 R1310.2 ; v1(189.88,74.97) 189.53,74.97 PQ102.3 ; v6(37.35,33.46) 37.62,33.74 CD102.2 ; v1(24.3,38.47) 24.24,38.52 CD15.2 ; v6(133.52,70.17) 133.28,69.93 C1135.2 ; v1(134.98,63.94) 134.5,64.43 MC284.2 ; R819.1 v6(154.34,67.14) ; CD124.2 18.04,36.49 18.45,36.08 v1(18.66,36.08) ; v1(203.75,40.96) 203.51,41.2 C963.2 ; v6(137.85,52.29) C277.2 C276.2 ; CD3.1 26.2,38.77 v1(25.91,38.48) ; CA22.2 v1(134.23,34.06) ; v1(98.8,36.64) 98.98,36.82 CD70.1 ; CH1218.2 82.63,63.37 v1(82.54,63.28) ; v1(74.78,33.97) 74.78,33.98 75.09,33.67 RD8.2 RD84.2 ; C1296.2 v6(108.86,50.06) ; C968.2 v6(150.81,57.92) ; v3(189,52.92) 188.64,52.57 C1285.2 ; C1117.2 150.18,66.01 v6(150.21,66.04) ; v1(181.35,39.33) 182.52,39.33 R1395.1 ; CD107.2 61.4,28.82 v1(62.16,29.58) ; CD90.2 RD15.2 57.51,53.34 58.01,53.84 v1(58.08,53.84) ; CLRP2.2 96.32,52.85 96.17,53.01 CH5.2 95.72,51.43 v1(95.83,51.32) ; v1(98.8,40.55) 98.62,40.73 CD82.2 ; v1(154.99,63.16) 154.96,63.13 154.96,63.11 154.93,63.08 R1099.1 154.93,61.57 C976.2 C978.2 ; v1(198.01,46.42) 198,46.41 C713.2 ; PR118.1 142.27,50.66 v6(142.27,50.13) ; v6(81.96,71.11) 82.53,71.11 CH1213.2 ; v1(54.88,32.07) 54.97,31.98 CD25.2 ; MC1269.2 61.64,64.63 62.21,64.63 v1(62.41,64.83) ; CH1223.2 CH1220.2 v1(88.16,67.91) ; CD118.2 64.29,41.08 65.92,41.08 66.15,40.86 v1(66.4,40.86) ; v1(18.57,40.08) 18.53,40.03 CD126.2 ; v1(104.19,52.97) 104.01,52.79 RH401.2 ; v6(145.83,39.28) 145.83,39.1 145.56,38.84 PQ204.3 ; v1(54.87,40.09) 54.81,40.03 CD122.2 ; R928.2 147.25,53.07 147.38,52.94 v6(147.38,52.51) ; CD17.2 36.56,38.56 v1(36.65,38.47) ; CH1229.2 v6(86.01,76.33) ; v6(167.66,69.61) 167.81,69.46 C719.2 166.91,68.87 C720.2 ; C962.2 202.37,41.86 v1(201.85,42.38) ; Q4.3 v6(108.24,69.24) ; C1172.2 v1(210.46,43.45) ; PR226.2 v6(147.26,48.37) ; v1(73.76,37) 73.9,37 74.15,37.25 CD47.1 ; R1338.2 v6(167.94,64.72) ; CH1235.2 v6(86.58,70.04) ; v1(114.73,47.13) 114.99,47.4 RA12.1 ; PD103.1 v1(125.03,25.08) ; PC324.2 208.91,64.99 208.91,65.57 v1(208.73,65.75) ; C279.2 C278.2 147.94,51.14 v6(147.2,51.14) ; R1217.1 216.14,45.12 v1(215.95,44.93) ; C1163.2 v1(141.55,24.27) ; v6(93.05,51.92) CH4.1 92.9,52.85 CLRP1.1 ; v1(87.92,61.09) 87.96,61.13 87.96,61.72 CH85.2 88.28,61.73 88.74,62.19 RH163.2 ; v3(201.1,39.46) 201.39,39.17 R1164.2 ; v1(60.34,53.86) 60.15,54.06 RC55.2 ; v1(60.32,50.3) 60.32,50.9 RD16.2 ; v1(22.45,79.4) 22.92,79.87 PR721.2 ; CD111.2 71.86,34.26 72.03,34.43 72.03,34.45 v1(72.03,34.46) ; C1118.2 151.94,60.23 152.2,60.49 v6(152.2,60.72) ; v6(152.48,56.2) 152.74,56.45 R1088.2 ; PC717.1 28.35,85.11 v1(28.35,85.69) ; CD110.2 77.6,29.36 v1(77.92,29.68) 77.59,30.01 CD65.2 ; CD93.2 79.48,28.99 v6(79.81,28.66) ; MC1297.2 16.29,27.47 16.52,27.7 v1(17.41,27.7) ; PC112.2 v6(141.41,50.15) ; C1205.2 v6(160.78,68.59) ; v1(130.75,51.51) 130.74,51.51 130.28,51.06 YA1.2 ; v1(61.27,36.87) 61.2,36.94 CD40.2 ; v1(205.14,73.93) 205.14,72.89 204.81,72.56 CV13.2 ; CD116.2 64.21,38.8 v1(64.13,38.87) ; R225.1 146.65,49.62 v6(146.13,49.62) ; C355.2 v6(120.44,57.52) ; PC216.2 PR213.2 v6(145.49,48.48) ; PC608.2 44.67,23.88 45.14,24.35 CD105.2 44.5,24.9 v1(44.42,24.98) ; CD39.2 v1(54.85,29.68) 54.6,29.44 CD43.2 ; RV10.2 v1(217.47,64.41) ; v6(92.29,33.34) 92.77,33.34 92.89,33.21 CD68.2 ; v6(109.82,66.9) 109.81,66.89 C1240.2 ; v1(109.82,40.86) 109.82,40.7 110.24,40.27 CD84.2 ; v1(109.82,38.46) 110.29,37.99 CD85.2 ; PC213.2 150.15,38.7 PC228.2 v1(150.11,37.78) ; v1(73.62,40.86) 74.19,40.3 CD60.2 ; CD59.2 77.41,35.7 77.95,35.16 77.95,35.18 v1(77.93,35.18) ; MC1271.2 38.55,72.35 ; C1262.2 v6(164.68,53.25) ; CD113.2 101.66,41.87 100.77,40.98 v1(100.64,40.98) ; CD112.2 v1(100.82,38.75) ; CH1226.2 87.84,76.12 v6(87.84,76.75) ; PC715.1 v1(21.98,83.22) ; v1(54.86,35.24) 54.86,35.28 54.03,36.11 CD38.2 ; CH1202.2 v6(158,68.16) ; C1294.2 110.03,55.88 v1(109.56,56.35) ; U718.15 v6(177.61,35.52) ; v1(110.48,31.27) 110.5,31.28 CD86.2 ; PR225.1 v6(147.5,40.87) ; C1140.2 132.37,72.82 v6(132.2,72.99) ; v1(102.57,29.68) 102.57,29.8 103.5,30.73 CD87.2 ; v1(34.54,20.35) 34.81,20.08 PC615.2 ; U717.15 v1(137.64,24.09) ; v1(26.25,37) 26.37,36.87 RD80.2 RD2.2 28.25,36.87 28.79,36.33 CD123.2 ; PR124.2 v1(116.73,29.24) ; C966.2 159.1,54.14 v1(159.18,54.22) 159.47,54.51 C965.2 ; v6(173.29,68.77) 173.68,68.38 R1203.2 ; CD21.2 35.59,32.08 CD101.2 36.16,31.01 36.42,31.27 v1(36.65,31.27) ; C1152.2 v6(151.54,64.4) ; v1(85.36,33.64) 84.65,32.93 CD63.2 ; RH272.2 v6(96.1,65.12) ; C281.1 v6(133.38,54.95) ; PC210.1 v6(150.88,48.43) ; Q39.3 v6(116.54,76.18) ; v6(134.3,43.65) 133.98,43.97 CA14.2 ; PR115.2 v1(118.6,26.45) ; v6(141,52.29) 141.31,52.59 R1032.1 ; CH1240.2 v6(104.2,68.52) ; CD28.2 v1(50.54,28.89) ; PC104.2 PC103.2 198.3,77.93 v1(198.37,77.86) ; C1278.2 120.24,58.95 v6(119.79,58.51) ; v6(92.23,61.53) 92.44,61.53 RH78.2 ; PC212.2 v6(151.82,48.45) ; YH2.4 86.52,83.8 87.04,84.32 v1(87.04,84.84) ; v1(211.58,43.59) C1173.2 ; R1117.2 v6(205.09,45.34) ; R1287.2 v6(170.38,51.78) ; C977.2 v6(161.81,60.95) ; PC612.2 v6(44.46,19.37) ; RH79.2 v6(91.07,61.86) ; v1(189.15,48.02) C1286.2 ; CD104.2 30.59,28.77 30.16,29.2 v1(30.16,29.68) ; v1(165.55,50.69) 165.96,51.09 C1257.2 167.14,51.09 C1248.2 ; v6(135.8,59.37) 136.15,59.02 R929.1 ; v1(51.18,31.27) 51.24,31.33 51.24,32.6 52.31,33.67 RD6.2 RD82.2 ; C1299.2 v6(152.81,71.64) ; JAPS.20 v1(17.91,55.95) ; CA21.2 v6(134.08,46.38) ; v1(77.97,32.11) 77.96,32.11 CD45.2 ; v1(57.25,54.14) 57.67,54.56 RC60.2 ; CH82.2 CH84.2 CH83.2 90.86,63.97 CH1207.2 89.95,63.97 89.78,63.8 v3(89.78,63.16) ; v1(169.02,61.38) 169.02,62.13 169.15,62.26 C1246.2 ; CH1216.2 v6(90.48,78.05) ; v6(101.76,63.59) 102.09,63.26 CH1224.2 ; MC102.1 CH1206.2 v6(92.29,67.23) ; C1300.2 v6(128.07,61.02) ; C979.2 v6(164.46,59.59) ; v3(114.38,36.74) 114.38,36.13 CA9.2 ; C1261.2 163.43,49.54 v6(163.41,49.57) ; MC118.1 95.02,70.5 v6(95.27,70.75) ; v1(50.67,36.25) 50.67,35.83 50.98,35.52 CD26.1 ; CH1225.2 v6(88.15,70.19) ; v1(97.23,50.34) 97.49,50.08 RH159.1 97.97,50.05 CLRP3.2 ; CD71.1 v1(112.49,35.9) ; v1(193.61,84.62) PC109.2 PC101.2 PC102.2 ; v1(144.61,23.41) 144.62,23.42 JKB1.31 ; C1204.2 v6(163.95,68.51) ; U664.15 127.69,33.97 v1(127.44,34.23) ; JSNRDG.21 186.45,82.64 v1(185.97,83.12) ; C1227.2 105.87,72.78 v6(105.87,73.18) ; CD20.2 27.3,32.03 v1(26.54,31.27) ; v1(62.85,29.33) 62.47,28.94 MC1267.2 ; C1100.1 v1(12.38,20.15) ; CA6.2 131.19,39.04 v1(131.63,39.04) ; v6(90.63,65.54) 91.03,65.54 CH1222.2 ; Q362.3 v6(118.31,72.76) ; CD42.2 61.2,31.36 v1(61.28,31.27) ; v1(139.36,52.51) 139.32,52.55 C285.2 ; RA11.1 v6(116.69,44.59) ; CA15.2 134.03,43.01 v1(134.64,42.41) 134.36,42.13 R1187.2 ; CH47.2 v6(88.18,69.05) ; CD119.2 50.43,38.91 v1(50.68,38.65) ; C352.2 117.2,56.86 v6(116.8,57.26) ; RD24.2 v6(62.85,50.33) ; RD7.2 v1(63.99,31.76) ; v6(132.44,44.67) 132.04,45.07 CA11.2 ; v1(180.36,39.25) 180.03,38.92 C1202.2 ; PC214.2 145.1,45.9 v1(145.17,45.97) ; v1(89.32,72.94) 90.82,72.94 91.51,72.25 RH32.2 91.54,72.09 CH41.2 CH40.2 ; CD114.2 90.1,41.36 90.49,40.98 v1(90.99,40.98) ; CD96.2 66.86,29.2 v1(66.4,29.65) ; v6(37.47,50.15) 37.1,50.52 C1237.2 ; CD58.2 76.92,37.97 v1(75.41,37.97) ; v1(123.22,32.22) C1212.2 C1214.2 ; CA5.2 v6(122.36,37.43) ; RD83.2 v1(63.99,34.15) ; PC220.1 v6(145.22,43.48) ; CD4.1 36.38,35.27 35.83,34.72 v1(35.83,34.47) ; RD21.2 v1(64.7,50.76) ; CH39.2 v6(91.4,69.53) ; JKB1.32 170.77,25.62 v1(171.08,25.92) ; MC1272.2 v6(51.4,61.12) ; PR327.2 v1(209.79,61.43) ; C1225.2 v1(142.42,24.28) ; PQ104.3 116.63,27.22 v1(116.12,27.72) ; MC1141.2 v6(142.55,66.67) ; v1(36.63,36.88) 36.56,36.95 CD18.2 ; v1(228.04,22.44) 228,22.4 C1122.2 ; C1136.2 133.46,71.01 v6(133.66,71.21) ; R1253.2 162.87,57.81 163.37,57.32 v1(163.38,57.32) ; v1(25.87,40.86) 25.95,40.78 CD14.2 ; CD121.2 51.2,41.55 v1(50.51,40.86) ; v6(24.14,48.81) 24.14,48.79 23.86,48.51 CH1.2 ; CD5.2 25.76,29.02 v1(25.89,28.89) ; CH1234.2 v6(87.81,72.94) ; PC416.2 v1(200.81,66.32) ; PR108.2 v1(118.04,29.63) ; Q71.3 159.31,84.4 158.86,84.85 R1161.2 157.78,84.85 v1(157.77,84.86) ; CH1232.2 v6(99.36,72.28) ; v1(199.16,46.44) C716.2 ; R1394.2 v6(151.96,75.55) ; v1(30.24,32.06) 30.24,31.36 CD2.2 ; PD104.1 v1(122.1,26.26) ; v1(177.06,68.75) 175.83,68.75 175.6,68.97 R1162.2 ; RA13.1 v6(121.17,52.58) ; C1241.2 v6(116.24,69.81) ; CA17.2 v6(130.28,49.75) ; DE1.1 v1(142.83,26.5) ; PC720.1 v1(27.32,85.67) ; C1242.2 v6(117.99,69.53) ; R945.1 v1(172.13,25.76) ; C1298.2 v6(154.62,71.64)
  GND1 w0.203: 142.93,33.02 H8.1 ; H8.1 142.93,30.68 ; H8.1 145.69,31.85 ; H8.1 144.1,33.44 ; H8.1 145.27,30.68 ; H8.1 144.1,30.26 ; H8.1 145.27,33.02 ; H8.1 142.51,31.85 ; 145.91,86.83 H6.1 ; H6.1 148.67,88 ; H6.1 146.33,85.66 ; H6.1 147.5,85.24 ; H6.1 148.67,85.66 ; H6.1 146.33,88 ; H6.1 147.5,88.42 ; H6.1 149.09,86.83 ; 218.92,36.26 JUSB1.7 ; JUSB1.7 219.56,37.74 ; JUSB1.7 219.76,37.1 ; JUSB1.7 218.28,36.46 ; JUSB1.7 218.28,37.74 ; JUSB1.7 218.08,37.1 ; JUSB1.7 219.56,36.46 ; JUSB1.7 218.92,37.94 ; JUSB1.14 229.28,29.2 ; JUSB1.14 229.28,28.34 ; JUSB1.14 226.26,28.34 ; JUSB1.14 227.77,28.34 ; JUSB1.14 226.26,29.2 ; JUSB2.7 221.07,56.17 ; JUSB2.7 221.07,55.03 ; JUSB2.7 219.93,56.17 ; JUSB2.7 220.5,56.34 ; JUSB2.7 219.93,55.03 ; JUSB2.7 219.76,55.6 ; JUSB2.7 220.5,54.86 ; JMDP1.24 227.78,65.5 ; JMDP1.24 226.7,66.22 ; JMDP1.24 227.78,66.22 ; JMDP1.24 225.62,64.78 ; JMDP1.24 226.7,64.78 ; JMDP1.24 225.62,66.22 ; JMDP1.24 227.78,64.78 ; JMDP1.24 225.62,65.5 ; 218.33,49.2 JUSB2.13 ; JUSB2.13 221.17,48.27 ; JUSB2.13 218.33,50.13 ; JUSB2.13 219.75,48.27 ; JUSB2.13 219.75,50.13 ; JUSB2.13 218.33,48.27 ; H1.1 218.59,79.25 ; H1.1 218.17,80.42 ; H1.1 215.83,78.08 ; H1.1 215.41,79.25 ; H1.1 217,77.66 ; H1.1 215.83,80.42 ; H1.1 217,80.84 ; H1.1 218.17,78.08 ; 8.37,31.75 H3.1 ; H3.1 12.57,29.98 ; H3.1 12.57,33.52 ; H3.1 10.8,34.18 ; H3.1 10.8,29.32 ; H3.1 13.23,31.75 ; H3.1 9.03,33.52 ; H3.1 9.03,29.98 ; JUSB2.12 229.48,47.75 ; JUSB2.12 226.92,46.82 ; JUSB2.12 226.92,47.75 ; JUSB2.12 228.2,46.82 ; JUSB2.12 229.48,46.82 ; 218.33,62 JUSB2.10 ; JUSB2.10 218.33,62.93 ; JUSB2.10 221.17,62.93 ; JUSB2.10 218.33,61.07 ; JUSB2.10 219.75,61.07 ; JUSB2.10 219.75,62.93 ; 218.43,58.53 JUSB2.4 ; JUSB2.4 218.43,59.67 ; JUSB2.4 219.57,58.53 ; JUSB2.4 219.57,59.67 ; JUSB2.4 219.74,59.1 ; JUSB2.4 218.26,59.1 ; JUSB2.4 219,59.84 ; JUSB2.4 219,58.36 ; JMDP1.1 224.3,74.3 ; JMDP1.1 223.66,73.72 ; JMDP1.1 223.66,74.88 ; JMDP1.1 224.3,74.88 ; JMDP1.1 223.02,74.88 ; JMDP1.1 224.3,73.72 ; JMDP1.19 223.66,68.88 ; JMDP1.19 223.02,67.72 ; JMDP1.19 224.3,67.72 ; JMDP1.19 224.3,68.3 ; JMDP1.19 223.66,67.72 ; JMDP1.19 224.3,68.88 ; 188.42,70.25 H26.1 ; H26.1 188.98,71.77 ; H26.1 188.98,68.73 ; H26.1 192.02,71.77 ; H26.1 190.5,68.17 ; H26.1 190.5,72.33 ; H26.1 192.58,70.25 ; H26.1 192.02,68.73 ; 102.92,78.93 H12.1 ; H12.1 104.95,76.9 ; H12.1 106.99,78.93 ; H12.1 103.47,77.44 ; H12.1 106.44,77.44 ; H12.1 106.44,80.42 ; H12.1 103.47,80.42 ; H12.1 104.95,80.96 ; 220.82,66.2 JMDP1.23 ; JMDP1.23 222,65.48 ; JMDP1.23 223.18,66.2 ; JMDP1.23 223.18,66.92 ; JMDP1.23 222,66.92 ; JMDP1.23 223.18,65.48 ; JMDP1.23 220.82,65.48 ; JUSB2.11 229.48,64.38 ; JUSB2.11 226.92,63.45 ; JUSB2.11 229.48,63.45 ; JUSB2.11 228.2,64.38 ; JUSB2.11 226.92,64.38 ; JMDP1.21 222,77.12 ; JMDP1.21 222,75.68 ; JMDP1.21 220.82,77.12 ; JMDP1.21 223.18,75.68 ; JMDP1.21 220.82,76.4 ; JMDP1.21 223.18,76.4 ; JMDP1.21 223.18,77.12 ; 225.62,77.1 JMDP1.22 ; JMDP1.22 227.78,76.38 ; JMDP1.22 227.78,77.1 ; JMDP1.22 226.7,76.38 ; JMDP1.22 227.78,77.82 ; JMDP1.22 226.7,77.82 ; JMDP1.22 225.62,77.82 ; JMDP1.22 225.62,76.38 ; 216.78,41.24 JUSB1.4 ; JUSB1.4 218.06,39.96 ; JUSB1.4 218.06,41.24 ; JUSB1.4 218.26,40.6 ; JUSB1.4 217.42,41.44 ; JUSB1.4 216.58,40.6 ; JUSB1.4 217.42,39.76 ; JUSB1.4 216.78,39.96 ; 223.02,71.72 JMDP1.7 ; JMDP1.7 223.66,72.88 ; JMDP1.7 224.3,72.88 ; JMDP1.7 223.66,71.72 ; H10.1 45.14,80.42 ; H10.1 43.65,76.9 ; H10.1 41.62,78.93 ; H10.1 42.17,77.44 ; H10.1 45.69,78.93 ; H10.1 43.65,80.96 ; H10.1 42.17,80.42 ; H10.1 45.14,77.44 ; 231.35,20.78 SW1.4 ; SW1.4 231.2,21.33 ; SW1.4 231.35,21.87 ; SW1.4 231.9,20.63 ; SW1.4 231.9,22.03 ; JMDP1.13 224.3,69.72 ; JMDP1.13 223.02,70.88 ; JMDP1.13 223.66,69.72 ; JMDP1.13 223.66,70.88 ; 224.41,17.35 H5.1 ; H5.1 227.59,17.35 ; H5.1 226,18.94 ; H5.1 224.83,16.18 ; H5.1 226,15.76 ; H5.1 224.83,18.52 ; H5.1 227.17,16.18 ; H5.1 227.17,18.52 ; JUSB1.13 229.28,45.86 ; JUSB1.13 226.26,45.86 ; JUSB1.13 226.26,45 ; JUSB1.13 229.28,45 ; JUSB1.13 227.77,45.86 ; 102.92,58.52 H9.1 ; H9.1 103.47,57.04 ; H9.1 104.95,60.56 ; H9.1 106.44,60.01 ; H9.1 106.99,58.52 ; H9.1 103.47,60.01 ; H9.1 106.44,57.04 ; H9.1 104.95,56.49 ; 217.26,30.7 JUSB1.12 ; JUSB1.12 219.01,31.56 ; JUSB1.12 217.26,31.56 ; JUSB1.12 217.26,29.84 ; JUSB1.12 219.01,29.84 ; 42.16,60.01 H11.1 ; H11.1 41.62,58.52 ; H11.1 42.16,57.03 ; H11.1 45.14,57.03 ; H11.1 45.14,60.01 ; H11.1 43.65,56.49 ; H11.1 43.65,60.55 ; H11.1 45.68,58.52 ; 56.47,13.75 H14.1 ; H14.1 57.01,12.26 ; H14.1 59.99,15.24 ; H14.1 58.5,15.78 ; H14.1 58.5,11.72 ; H14.1 57.01,15.24 ; H14.1 60.53,13.75 ; H14.1 59.99,12.26 ; 217.26,44.36 JUSB1.11 ; JUSB1.11 217.26,43.5 ; JUSB1.11 217.26,42.64 ; JUSB1.11 219.01,42.64 ; JUSB1.11 219.01,44.36 ; 231.35,24.83 SW1.2 ; SW1.2 231.35,25.92 ; SW1.2 231.2,25.38 ; SW1.2 231.9,24.68
  GND2 w0.203: 188.98,68.73 H26.1 ; H26.1 192.02,68.73 ; H26.1 188.42,70.25 ; H26.1 190.5,68.17 ; H26.1 192.58,70.25 ; H26.1 190.5,72.33 ; H26.1 188.98,71.77 ; H26.1 192.02,71.77 ; JUSB2.11 229.48,63.45 ; JUSB2.11 229.48,64.38 ; JUSB2.11 226.92,64.38 ; JUSB2.11 228.2,64.38 ; JUSB2.11 226.92,63.45 ; 42.17,77.44 H10.1 ; H10.1 45.69,78.93 ; H10.1 45.14,77.44 ; H10.1 45.14,80.42 ; H10.1 41.62,78.93 ; H10.1 42.17,80.42 ; H10.1 43.65,80.96 ; H10.1 43.65,76.9 ; H5.1 226,18.94 ; H5.1 224.41,17.35 ; H5.1 224.83,16.18 ; H5.1 227.17,18.52 ; H5.1 226,15.76 ; H5.1 224.83,18.52 ; H5.1 227.59,17.35 ; H5.1 227.17,16.18 ; JMDP1.13 224.3,69.72 ; JMDP1.13 223.02,70.88 ; JMDP1.13 223.66,70.88 ; JMDP1.13 223.66,69.72 ; H1.1 218.17,80.42 ; H1.1 217,80.84 ; H1.1 218.17,78.08 ; H1.1 215.41,79.25 ; H1.1 218.59,79.25 ; H1.1 215.83,78.08 ; H1.1 217,77.66 ; H1.1 215.83,80.42 ; JMDP1.1 224.3,73.72 ; JMDP1.1 224.3,74.3 ; JMDP1.1 224.3,74.88 ; JMDP1.1 223.66,73.72 ; JMDP1.1 223.02,74.88 ; JMDP1.1 223.66,74.88 ; JUSB2.12 229.48,46.82 ; JUSB2.12 226.92,46.82 ; JUSB2.12 229.48,47.75 ; JUSB2.12 226.92,47.75 ; JUSB2.12 228.2,46.82 ; 218.28,36.46 JUSB1.7 ; JUSB1.7 218.28,37.74 ; JUSB1.7 219.76,37.1 ; JUSB1.7 218.08,37.1 ; JUSB1.7 218.92,37.94 ; JUSB1.7 218.92,36.26 ; JUSB1.7 219.56,37.74 ; JUSB1.7 219.56,36.46 ; 142.51,31.85 H8.1 ; H8.1 145.69,31.85 ; H8.1 144.1,33.44 ; H8.1 144.1,30.26 ; H8.1 145.27,30.68 ; H8.1 142.93,30.68 ; H8.1 142.93,33.02 ; H8.1 145.27,33.02 ; JMDP1.23 223.18,66.2 ; JMDP1.23 223.18,66.92 ; JMDP1.23 220.82,65.48 ; JMDP1.23 220.82,66.2 ; JMDP1.23 223.18,65.48 ; JMDP1.23 222,66.92 ; JMDP1.23 222,65.48 ; 102.92,58.52 H9.1 ; H9.1 104.95,56.49 ; H9.1 106.44,57.04 ; H9.1 104.95,60.56 ; H9.1 106.44,60.01 ; H9.1 106.99,58.52 ; H9.1 103.47,57.04 ; H9.1 103.47,60.01 ; 57.01,15.24 H14.1 ; H14.1 60.53,13.75 ; H14.1 56.47,13.75 ; H14.1 59.99,12.26 ; H14.1 58.5,11.72 ; H14.1 58.5,15.78 ; H14.1 57.01,12.26 ; H14.1 59.99,15.24 ; JUSB2.10 221.17,62.93 ; JUSB2.10 218.33,62.93 ; JUSB2.10 218.33,62 ; JUSB2.10 218.33,61.07 ; JUSB2.10 219.75,62.93 ; JUSB2.10 219.75,61.07 ; 219,58.36 JUSB2.4 ; JUSB2.4 219.57,59.67 ; JUSB2.4 219,59.84 ; JUSB2.4 219.57,58.53 ; JUSB2.4 219.74,59.1 ; JUSB2.4 218.43,58.53 ; JUSB2.4 218.43,59.67 ; JUSB2.4 218.26,59.1 ; JUSB1.4 218.26,40.6 ; JUSB1.4 216.78,41.24 ; JUSB1.4 217.42,39.76 ; JUSB1.4 216.78,39.96 ; JUSB1.4 217.42,41.44 ; JUSB1.4 218.06,41.24 ; JUSB1.4 216.58,40.6 ; JUSB1.4 218.06,39.96 ; H3.1 12.57,29.98 ; H3.1 12.57,33.52 ; H3.1 9.03,29.98 ; H3.1 8.37,31.75 ; H3.1 13.23,31.75 ; H3.1 10.8,34.18 ; H3.1 9.03,33.52 ; H3.1 10.8,29.32 ; 217.26,29.84 JUSB1.12 ; JUSB1.12 219.01,29.84 ; JUSB1.12 217.26,30.7 ; JUSB1.12 217.26,31.56 ; JUSB1.12 219.01,31.56 ; 231.2,25.38 SW1.2 ; SW1.2 231.9,24.68 ; SW1.2 231.35,25.92 ; SW1.2 231.35,24.83 ; 220.82,77.12 JMDP1.21 ; JMDP1.21 222,75.68 ; JMDP1.21 223.18,76.4 ; JMDP1.21 222,77.12 ; JMDP1.21 223.18,75.68 ; JMDP1.21 223.18,77.12 ; JMDP1.21 220.82,76.4 ; 218.33,48.27 JUSB2.13 ; JUSB2.13 218.33,49.2 ; JUSB2.13 218.33,50.13 ; JUSB2.13 221.17,48.27 ; JUSB2.13 219.75,50.13 ; JUSB2.13 219.75,48.27 ; 41.62,58.52 H11.1 ; H11.1 45.14,60.01 ; H11.1 42.16,57.03 ; H11.1 45.68,58.52 ; H11.1 43.65,56.49 ; H11.1 43.65,60.55 ; H11.1 42.16,60.01 ; H11.1 45.14,57.03 ; 219.93,56.17 JUSB2.7 ; JUSB2.7 221.07,55.03 ; JUSB2.7 219.93,55.03 ; JUSB2.7 220.5,54.86 ; JUSB2.7 219.76,55.6 ; JUSB2.7 221.07,56.17 ; JUSB2.7 220.5,56.34 ; SW1.4 231.9,22.03 ; SW1.4 231.2,21.33 ; SW1.4 231.35,21.87 ; SW1.4 231.35,20.78 ; SW1.4 231.9,20.63 ; 225.62,64.78 JMDP1.24 ; JMDP1.24 225.62,66.22 ; JMDP1.24 227.78,66.22 ; JMDP1.24 226.7,66.22 ; JMDP1.24 226.7,64.78 ; JMDP1.24 227.78,65.5 ; JMDP1.24 225.62,65.5 ; JMDP1.24 227.78,64.78 ; JUSB1.14 229.28,29.2 ; JUSB1.14 227.77,28.34 ; JUSB1.14 226.26,28.34 ; JUSB1.14 229.28,28.34 ; JUSB1.14 226.26,29.2 ; 223.02,71.72 JMDP1.7 ; JMDP1.7 223.66,72.88 ; JMDP1.7 223.66,71.72 ; JMDP1.7 224.3,72.88 ; 146.33,85.66 H6.1 ; H6.1 147.5,88.42 ; H6.1 146.33,88 ; H6.1 147.5,85.24 ; H6.1 148.67,88 ; H6.1 145.91,86.83 ; H6.1 148.67,85.66 ; H6.1 149.09,86.83 ; H12.1 104.95,80.96 ; H12.1 102.92,78.93 ; H12.1 103.47,80.42 ; H12.1 104.95,76.9 ; H12.1 106.99,78.93 ; H12.1 106.44,77.44 ; H12.1 103.47,77.44 ; H12.1 106.44,80.42 ; JMDP1.22 227.78,77.1 ; JMDP1.22 225.62,76.38 ; JMDP1.22 225.62,77.1 ; JMDP1.22 225.62,77.82 ; JMDP1.22 227.78,76.38 ; JMDP1.22 226.7,77.82 ; JMDP1.22 226.7,76.38 ; JMDP1.22 227.78,77.82 ; 223.66,67.72 JMDP1.19 ; JMDP1.19 223.02,67.72 ; JMDP1.19 224.3,67.72 ; JMDP1.19 223.66,68.88 ; JMDP1.19 224.3,68.88 ; JMDP1.19 224.3,68.3 ; 217.26,43.5 JUSB1.11 ; JUSB1.11 219.01,42.64 ; JUSB1.11 217.26,42.64 ; JUSB1.11 217.26,44.36 ; JUSB1.11 219.01,44.36 ; JUSB1.13 229.28,45.86 ; JUSB1.13 226.26,45.86 ; JUSB1.13 229.28,45 ; JUSB1.13 227.77,45.86 ; JUSB1.13 226.26,45
  GND3 w0.203: 223.02,74.88 JMDP1.1 ; JMDP1.1 223.66,74.88 ; JMDP1.1 224.3,73.72 ; JMDP1.1 224.3,74.88 ; JMDP1.1 224.3,74.3 ; JMDP1.1 223.66,73.72 ; JUSB1.7 219.56,37.74 ; JUSB1.7 218.92,36.26 ; JUSB1.7 218.92,37.94 ; JUSB1.7 218.28,37.74 ; JUSB1.7 219.56,36.46 ; JUSB1.7 219.76,37.1 ; JUSB1.7 218.08,37.1 ; JUSB1.7 218.28,36.46 ; 145.91,86.83 H6.1 ; H6.1 149.09,86.83 ; H6.1 148.67,88 ; H6.1 147.5,88.42 ; H6.1 146.33,85.66 ; H6.1 147.5,85.24 ; H6.1 148.67,85.66 ; H6.1 146.33,88 ; H8.1 145.69,31.85 ; H8.1 145.27,33.02 ; H8.1 144.1,33.44 ; H8.1 144.1,30.26 ; H8.1 142.51,31.85 ; H8.1 142.93,30.68 ; H8.1 145.27,30.68 ; H8.1 142.93,33.02 ; H5.1 227.17,18.52 ; H5.1 227.59,17.35 ; H5.1 224.41,17.35 ; H5.1 227.17,16.18 ; H5.1 224.83,16.18 ; H5.1 224.83,18.52 ; H5.1 226,18.94 ; H5.1 226,15.76 ; 219.75,48.27 JUSB2.13 ; JUSB2.13 221.17,48.27 ; JUSB2.13 218.33,49.2 ; JUSB2.13 219.75,50.13 ; JUSB2.13 218.33,48.27 ; JUSB2.13 218.33,50.13 ; SW1.4 231.9,22.03 ; SW1.4 231.35,20.78 ; SW1.4 231.9,20.63 ; SW1.4 231.35,21.87 ; SW1.4 231.2,21.33 ; JUSB1.4 218.26,40.6 ; JUSB1.4 217.42,39.76 ; JUSB1.4 218.06,39.96 ; JUSB1.4 216.78,41.24 ; JUSB1.4 216.58,40.6 ; JUSB1.4 217.42,41.44 ; JUSB1.4 216.78,39.96 ; JUSB1.4 218.06,41.24 ; H11.1 43.65,60.55 ; H11.1 42.16,57.03 ; H11.1 41.62,58.52 ; H11.1 42.16,60.01 ; H11.1 45.14,57.03 ; H11.1 45.68,58.52 ; H11.1 43.65,56.49 ; H11.1 45.14,60.01 ; 218.33,62 JUSB2.10 ; JUSB2.10 218.33,61.07 ; JUSB2.10 221.17,62.93 ; JUSB2.10 218.33,62.93 ; JUSB2.10 219.75,62.93 ; JUSB2.10 219.75,61.07 ; JUSB1.13 229.28,45 ; JUSB1.13 227.77,45.86 ; JUSB1.13 226.26,45 ; JUSB1.13 226.26,45.86 ; JUSB1.13 229.28,45.86 ; H14.1 58.5,15.78 ; H14.1 59.99,15.24 ; H14.1 60.53,13.75 ; H14.1 57.01,12.26 ; H14.1 57.01,15.24 ; H14.1 56.47,13.75 ; H14.1 59.99,12.26 ; H14.1 58.5,11.72 ; JMDP1.21 222,77.12 ; JMDP1.21 220.82,77.12 ; JMDP1.21 223.18,77.12 ; JMDP1.21 220.82,76.4 ; JMDP1.21 223.18,75.68 ; JMDP1.21 222,75.68 ; JMDP1.21 223.18,76.4 ; H26.1 192.02,68.73 ; H26.1 192.58,70.25 ; H26.1 192.02,71.77 ; H26.1 190.5,72.33 ; H26.1 188.98,71.77 ; H26.1 190.5,68.17 ; H26.1 188.98,68.73 ; H26.1 188.42,70.25 ; JMDP1.24 227.78,66.22 ; JMDP1.24 227.78,64.78 ; JMDP1.24 226.7,64.78 ; JMDP1.24 226.7,66.22 ; JMDP1.24 225.62,66.22 ; JMDP1.24 225.62,65.5 ; JMDP1.24 227.78,65.5 ; JMDP1.24 225.62,64.78 ; 215.41,79.25 H1.1 ; H1.1 218.17,78.08 ; H1.1 217,80.84 ; H1.1 218.59,79.25 ; H1.1 217,77.66 ; H1.1 215.83,78.08 ; H1.1 215.83,80.42 ; H1.1 218.17,80.42 ; JMDP1.22 227.78,77.1 ; JMDP1.22 225.62,77.1 ; JMDP1.22 227.78,76.38 ; JMDP1.22 225.62,77.82 ; JMDP1.22 226.7,77.82 ; JMDP1.22 227.78,77.82 ; JMDP1.22 226.7,76.38 ; JMDP1.22 225.62,76.38 ; JUSB2.4 219,59.84 ; JUSB2.4 218.26,59.1 ; JUSB2.4 219,58.36 ; JUSB2.4 218.43,59.67 ; JUSB2.4 219.57,58.53 ; JUSB2.4 218.43,58.53 ; JUSB2.4 219.74,59.1 ; JUSB2.4 219.57,59.67 ; JUSB1.14 229.28,29.2 ; JUSB1.14 226.26,29.2 ; JUSB1.14 226.26,28.34 ; JUSB1.14 227.77,28.34 ; JUSB1.14 229.28,28.34 ; 219.01,29.84 JUSB1.12 ; JUSB1.12 217.26,29.84 ; JUSB1.12 219.01,31.56 ; JUSB1.12 217.26,30.7 ; JUSB1.12 217.26,31.56 ; 223.66,71.72 JMDP1.7 ; JMDP1.7 223.02,71.72 ; JMDP1.7 223.66,72.88 ; JMDP1.7 224.3,72.88 ; H12.1 106.44,77.44 ; H12.1 103.47,80.42 ; H12.1 106.99,78.93 ; H12.1 104.95,76.9 ; H12.1 103.47,77.44 ; H12.1 106.44,80.42 ; H12.1 104.95,80.96 ; H12.1 102.92,78.93 ; JUSB2.7 220.5,56.34 ; JUSB2.7 219.93,56.17 ; JUSB2.7 221.07,56.17 ; JUSB2.7 220.5,54.86 ; JUSB2.7 221.07,55.03 ; JUSB2.7 219.76,55.6 ; JUSB2.7 219.93,55.03 ; JMDP1.19 224.3,68.88 ; JMDP1.19 224.3,67.72 ; JMDP1.19 224.3,68.3 ; JMDP1.19 223.66,67.72 ; JMDP1.19 223.66,68.88 ; JMDP1.19 223.02,67.72 ; JMDP1.23 223.18,66.92 ; JMDP1.23 223.18,66.2 ; JMDP1.23 220.82,65.48 ; JMDP1.23 220.82,66.2 ; JMDP1.23 222,65.48 ; JMDP1.23 223.18,65.48 ; JMDP1.23 222,66.92 ; H3.1 10.8,34.18 ; H3.1 10.8,29.32 ; H3.1 9.03,29.98 ; H3.1 12.57,29.98 ; H3.1 9.03,33.52 ; H3.1 12.57,33.52 ; H3.1 13.23,31.75 ; H3.1 8.37,31.75 ; 41.62,78.93 H10.1 ; H10.1 43.65,76.9 ; H10.1 42.17,77.44 ; H10.1 42.17,80.42 ; H10.1 45.69,78.93 ; H10.1 43.65,80.96 ; H10.1 45.14,80.42 ; H10.1 45.14,77.44 ; H9.1 106.44,60.01 ; H9.1 106.44,57.04 ; H9.1 104.95,60.56 ; H9.1 104.95,56.49 ; H9.1 103.47,57.04 ; H9.1 103.47,60.01 ; H9.1 106.99,58.52 ; H9.1 102.92,58.52 ; 231.35,24.83 SW1.2 ; SW1.2 231.35,25.92 ; SW1.2 231.9,24.68 ; SW1.2 231.2,25.38 ; 226.92,64.38 JUSB2.11 ; JUSB2.11 226.92,63.45 ; JUSB2.11 228.2,64.38 ; JUSB2.11 229.48,63.45 ; JUSB2.11 229.48,64.38 ; JUSB2.12 229.48,46.82 ; JUSB2.12 229.48,47.75 ; JUSB2.12 226.92,46.82 ; JUSB2.12 226.92,47.75 ; JUSB2.12 228.2,46.82 ; 217.26,42.64 JUSB1.11 ; JUSB1.11 219.01,42.64 ; JUSB1.11 217.26,44.36 ; JUSB1.11 219.01,44.36 ; JUSB1.11 217.26,43.5 ; 223.66,69.72 JMDP1.13 ; JMDP1.13 223.02,70.88 ; JMDP1.13 223.66,70.88 ; JMDP1.13 224.3,69.72
  VCC w0.203: H5.1 226,18.94 ; H5.1 227.17,18.52 ; H5.1 224.41,17.35 ; H5.1 224.83,18.52 ; H5.1 227.17,16.18 ; H5.1 227.59,17.35 ; H5.1 226,15.76 ; H5.1 224.83,16.18 ; JUSB2.11 229.48,64.38 ; JUSB2.11 229.48,63.45 ; JUSB2.11 228.2,64.38 ; JUSB2.11 226.92,64.38 ; JUSB2.11 226.92,63.45 ; JUSB2.13 219.75,50.13 ; JUSB2.13 218.33,50.13 ; JUSB2.13 221.17,48.27 ; JUSB2.13 219.75,48.27 ; JUSB2.13 218.33,49.2 ; H14.1 60.53,13.75 ; H14.1 59.99,15.24 ; H14.1 59.99,12.26 ; H14.1 58.5,11.72 ; H14.1 58.5,15.78 ; H14.1 57.01,15.24 ; H14.1 57.01,12.26 ; H14.1 56.47,13.75 ; 231.35,25.92 SW1.2 ; SW1.2 231.2,25.38 ; SW1.2 231.35,24.83 ; SW1.2 231.9,24.68 ; 220.5,54.86 JUSB2.7 ; JUSB2.7 221.07,55.03 ; JUSB2.7 219.93,56.17 ; JUSB2.7 221.07,56.17 ; JUSB2.7 219.93,55.03 ; JUSB2.7 219.76,55.6 ; JUSB2.7 220.5,56.34 ; 226.7,64.78 JMDP1.24 ; JMDP1.24 226.7,66.22 ; JMDP1.24 225.62,64.78 ; JMDP1.24 225.62,65.5 ; JMDP1.24 227.78,66.22 ; JMDP1.24 227.78,65.5 ; JMDP1.24 225.62,66.22 ; JMDP1.24 227.78,64.78 ; JUSB1.13 229.28,45 ; JUSB1.13 226.26,45.86 ; JUSB1.13 229.28,45.86 ; JUSB1.13 226.26,45 ; JUSB1.13 227.77,45.86 ; JUSB2.4 219.57,59.67 ; JUSB2.4 219.57,58.53 ; JUSB2.4 219,58.36 ; JUSB2.4 219,59.84 ; JUSB2.4 218.43,58.53 ; JUSB2.4 218.26,59.1 ; JUSB2.4 218.43,59.67 ; JUSB2.4 219.74,59.1 ; 222,65.48 JMDP1.23 ; JMDP1.23 223.18,66.92 ; JMDP1.23 223.18,66.2 ; JMDP1.23 222,66.92 ; JMDP1.23 220.82,66.2 ; JMDP1.23 223.18,65.48 ; JMDP1.23 220.82,65.48 ; JMDP1.21 223.18,75.68 ; JMDP1.21 220.82,76.4 ; JMDP1.21 220.82,77.12 ; JMDP1.21 223.18,76.4 ; JMDP1.21 222,75.68 ; JMDP1.21 223.18,77.12 ; JMDP1.21 222,77.12 ; 223.66,67.72 JMDP1.19 ; JMDP1.19 224.3,67.72 ; JMDP1.19 223.66,68.88 ; JMDP1.19 223.02,67.72 ; JMDP1.19 224.3,68.3 ; JMDP1.19 224.3,68.88 ; 225.62,77.1 JMDP1.22 ; JMDP1.22 227.78,77.1 ; JMDP1.22 225.62,76.38 ; JMDP1.22 226.7,77.82 ; JMDP1.22 227.78,77.82 ; JMDP1.22 225.62,77.82 ; JMDP1.22 227.78,76.38 ; JMDP1.22 226.7,76.38 ; JUSB2.10 221.17,62.93 ; JUSB2.10 218.33,62.93 ; JUSB2.10 218.33,62 ; JUSB2.10 219.75,62.93 ; JUSB2.10 218.33,61.07 ; JUSB2.10 219.75,61.07 ; JUSB2.12 229.48,46.82 ; JUSB2.12 229.48,47.75 ; JUSB2.12 228.2,46.82 ; JUSB2.12 226.92,46.82 ; JUSB2.12 226.92,47.75 ; 231.35,21.87 SW1.4 ; SW1.4 231.35,20.78 ; SW1.4 231.9,20.63 ; SW1.4 231.2,21.33 ; SW1.4 231.9,22.03 ; JMDP1.7 223.66,72.88 ; JMDP1.7 223.02,71.72 ; JMDP1.7 223.66,71.72 ; JMDP1.7 224.3,72.88 ; 10.8,29.32 H3.1 ; H3.1 8.37,31.75 ; H3.1 12.57,33.52 ; H3.1 10.8,34.18 ; H3.1 12.57,29.98 ; H3.1 9.03,33.52 ; H3.1 9.03,29.98 ; H3.1 13.23,31.75 ; 226.26,29.2 JUSB1.14 ; JUSB1.14 229.28,28.34 ; JUSB1.14 227.77,28.34 ; JUSB1.14 226.26,28.34 ; JUSB1.14 229.28,29.2 ; 223.02,70.88 JMDP1.13 ; JMDP1.13 224.3,69.72 ; JMDP1.13 223.66,69.72 ; JMDP1.13 223.66,70.88 ; 215.83,78.08 H1.1 ; H1.1 217,80.84 ; H1.1 215.41,79.25 ; H1.1 217,77.66 ; H1.1 218.59,79.25 ; H1.1 218.17,78.08 ; H1.1 218.17,80.42 ; H1.1 215.83,80.42 ; 223.66,73.72 JMDP1.1 ; JMDP1.1 224.3,74.3 ; JMDP1.1 224.3,73.72 ; JMDP1.1 223.02,74.88 ; JMDP1.1 223.66,74.88 ; JMDP1.1 224.3,74.88
  GND4 w0.203: 226.92,63.45 JUSB2.11 ; JUSB2.11 226.92,64.38 ; JUSB2.11 228.2,64.38 ; JUSB2.11 229.48,64.38 ; JUSB2.11 229.48,63.45 ; JUSB2.12 229.48,47.75 ; JUSB2.12 228.2,46.82 ; JUSB2.12 226.92,46.82 ; JUSB2.12 229.48,46.82 ; JUSB2.12 226.92,47.75 ; JUSB2.4 219,59.84 ; JUSB2.4 219.57,58.53 ; JUSB2.4 218.43,59.67 ; JUSB2.4 219.57,59.67 ; JUSB2.4 218.43,58.53 ; JUSB2.4 219,58.36 ; JUSB2.4 219.74,59.1 ; JUSB2.4 218.26,59.1 ; 219.75,61.07 JUSB2.10 ; JUSB2.10 221.17,62.93 ; JUSB2.10 218.33,61.07 ; JUSB2.10 219.75,62.93 ; JUSB2.10 218.33,62 ; JUSB2.10 218.33,62.93 ; 231.35,25.92 SW1.2 ; SW1.2 231.35,24.83 ; SW1.2 231.9,24.68 ; SW1.2 231.2,25.38 ; JMDP1.7 223.66,72.88 ; JMDP1.7 223.66,71.72 ; JMDP1.7 223.02,71.72 ; JMDP1.7 224.3,72.88 ; 224.83,18.52 H5.1 ; H5.1 226,15.76 ; H5.1 227.59,17.35 ; H5.1 224.41,17.35 ; H5.1 227.17,16.18 ; H5.1 227.17,18.52 ; H5.1 226,18.94 ; H5.1 224.83,16.18 ; H26.1 192.02,71.77 ; H26.1 188.98,68.73 ; H26.1 190.5,72.33 ; H26.1 192.58,70.25 ; H26.1 192.02,68.73 ; H26.1 188.98,71.77 ; H26.1 190.5,68.17 ; H26.1 188.42,70.25 ; JMDP1.23 223.18,66.92 ; JMDP1.23 222,65.48 ; JMDP1.23 220.82,66.2 ; JMDP1.23 223.18,65.48 ; JMDP1.23 222,66.92 ; JMDP1.23 220.82,65.48 ; JMDP1.23 223.18,66.2 ; JUSB1.4 218.26,40.6 ; JUSB1.4 216.58,40.6 ; JUSB1.4 217.42,41.44 ; JUSB1.4 218.06,39.96 ; JUSB1.4 217.42,39.76 ; JUSB1.4 218.06,41.24 ; JUSB1.4 216.78,39.96 ; JUSB1.4 216.78,41.24 ; H1.1 218.17,80.42 ; H1.1 218.59,79.25 ; H1.1 215.41,79.25 ; H1.1 215.83,80.42 ; H1.1 215.83,78.08 ; H1.1 218.17,78.08 ; H1.1 217,77.66 ; H1.1 217,80.84 ; H12.1 106.44,80.42 ; H12.1 102.92,78.93 ; H12.1 104.95,80.96 ; H12.1 103.47,77.44 ; H12.1 104.95,76.9 ; H12.1 103.47,80.42 ; H12.1 106.99,78.93 ; H12.1 106.44,77.44 ; SW1.4 231.9,22.03 ; SW1.4 231.35,21.87 ; SW1.4 231.35,20.78 ; SW1.4 231.2,21.33 ; SW1.4 231.9,20.63 ; H11.1 45.14,60.01 ; H11.1 42.16,60.01 ; H11.1 43.65,60.55 ; H11.1 41.62,58.52 ; H11.1 45.14,57.03 ; H11.1 45.68,58.52 ; H11.1 42.16,57.03 ; H11.1 43.65,56.49 ; 223.02,74.88 JMDP1.1 ; JMDP1.1 223.66,73.72 ; JMDP1.1 224.3,73.72 ; JMDP1.1 223.66,74.88 ; JMDP1.1 224.3,74.88 ; JMDP1.1 224.3,74.3 ; JMDP1.22 227.78,77.1 ; JMDP1.22 225.62,76.38 ; JMDP1.22 227.78,77.82 ; JMDP1.22 225.62,77.1 ; JMDP1.22 227.78,76.38 ; JMDP1.22 225.62,77.82 ; JMDP1.22 226.7,77.82 ; JMDP1.22 226.7,76.38 ; H9.1 104.95,60.56 ; H9.1 106.44,57.04 ; H9.1 104.95,56.49 ; H9.1 106.44,60.01 ; H9.1 102.92,58.52 ; H9.1 103.47,57.04 ; H9.1 106.99,58.52 ; H9.1 103.47,60.01 ; JUSB1.7 219.56,36.46 ; JUSB1.7 218.08,37.1 ; JUSB1.7 218.28,36.46 ; JUSB1.7 218.92,36.26 ; JUSB1.7 218.92,37.94 ; JUSB1.7 219.76,37.1 ; JUSB1.7 218.28,37.74 ; JUSB1.7 219.56,37.74 ; 42.17,80.42 H10.1 ; H10.1 42.17,77.44 ; H10.1 43.65,76.9 ; H10.1 45.14,77.44 ; H10.1 43.65,80.96 ; H10.1 45.69,78.93 ; H10.1 41.62,78.93 ; H10.1 45.14,80.42 ; 217.26,30.7 JUSB1.12 ; JUSB1.12 219.01,31.56 ; JUSB1.12 217.26,31.56 ; JUSB1.12 217.26,29.84 ; JUSB1.12 219.01,29.84 ; 223.66,69.72 JMDP1.13 ; JMDP1.13 223.66,70.88 ; JMDP1.13 224.3,69.72 ; JMDP1.13 223.02,70.88 ; 226.7,64.78 JMDP1.24 ; JMDP1.24 227.78,66.22 ; JMDP1.24 226.7,66.22 ; JMDP1.24 225.62,65.5 ; JMDP1.24 227.78,65.5 ; JMDP1.24 225.62,64.78 ; JMDP1.24 225.62,66.22 ; JMDP1.24 227.78,64.78 ; JMDP1.21 223.18,77.12 ; JMDP1.21 220.82,77.12 ; JMDP1.21 223.18,76.4 ; JMDP1.21 223.18,75.68 ; JMDP1.21 220.82,76.4 ; JMDP1.21 222,75.68 ; JMDP1.21 222,77.12 ; 219.93,56.17 JUSB2.7 ; JUSB2.7 221.07,56.17 ; JUSB2.7 220.5,56.34 ; JUSB2.7 219.76,55.6 ; JUSB2.7 221.07,55.03 ; JUSB2.7 219.93,55.03 ; JUSB2.7 220.5,54.86 ; 142.51,31.85 H8.1 ; H8.1 142.93,33.02 ; H8.1 144.1,30.26 ; H8.1 145.27,33.02 ; H8.1 145.27,30.68 ; H8.1 144.1,33.44 ; H8.1 145.69,31.85 ; H8.1 142.93,30.68 ; 218.33,48.27 JUSB2.13 ; JUSB2.13 219.75,48.27 ; JUSB2.13 218.33,49.2 ; JUSB2.13 219.75,50.13 ; JUSB2.13 221.17,48.27 ; JUSB2.13 218.33,50.13 ; H3.1 12.57,29.98 ; H3.1 10.8,34.18 ; H3.1 13.23,31.75 ; H3.1 8.37,31.75 ; H3.1 12.57,33.52 ; H3.1 10.8,29.32 ; H3.1 9.03,33.52 ; H3.1 9.03,29.98 ; 146.33,88 H6.1 ; H6.1 148.67,85.66 ; H6.1 145.91,86.83 ; H6.1 147.5,88.42 ; H6.1 149.09,86.83 ; H6.1 147.5,85.24 ; H6.1 148.67,88 ; H6.1 146.33,85.66 ; H14.1 59.99,12.26 ; H14.1 57.01,15.24 ; H14.1 56.47,13.75 ; H14.1 58.5,15.78 ; H14.1 60.53,13.75 ; H14.1 57.01,12.26 ; H14.1 58.5,11.72 ; H14.1 59.99,15.24 ; JUSB1.13 229.28,45.86 ; JUSB1.13 229.28,45 ; JUSB1.13 226.26,45.86 ; JUSB1.13 227.77,45.86 ; JUSB1.13 226.26,45 ; 227.77,28.34 JUSB1.14 ; JUSB1.14 229.28,28.34 ; JUSB1.14 226.26,29.2 ; JUSB1.14 226.26,28.34 ; JUSB1.14 229.28,29.2 ; 217.26,43.5 JUSB1.11 ; JUSB1.11 219.01,42.64 ; JUSB1.11 217.26,42.64 ; JUSB1.11 219.01,44.36 ; JUSB1.11 217.26,44.36 ; JMDP1.19 224.3,68.88 ; JMDP1.19 223.66,67.72 ; JMDP1.19 223.66,68.88 ; JMDP1.19 223.02,67.72 ; JMDP1.19 224.3,67.72 ; JMDP1.19 224.3,68.3
  GND5 w0.076: v4(115.49,70.27) 115.49,70.85 v5(115.54,70.9)
  GND5 w0.203: 216.78,39.96 JUSB1.4 ; JUSB1.4 217.42,39.76 ; JUSB1.4 218.26,40.6 ; JUSB1.4 217.42,41.44 ; JUSB1.4 218.06,39.96 ; JUSB1.4 216.58,40.6 ; JUSB1.4 216.78,41.24 ; JUSB1.4 218.06,41.24 ; 142.93,30.68 H8.1 ; H8.1 145.27,33.02 ; H8.1 142.93,33.02 ; H8.1 142.51,31.85 ; H8.1 145.69,31.85 ; H8.1 145.27,30.68 ; H8.1 144.1,33.44 ; H8.1 144.1,30.26 ; 219.75,48.27 JUSB2.13 ; JUSB2.13 221.17,48.27 ; JUSB2.13 218.33,49.2 ; JUSB2.13 218.33,50.13 ; JUSB2.13 219.75,50.13 ; JUSB2.13 218.33,48.27 ; 188.42,70.25 H26.1 ; H26.1 192.58,70.25 ; H26.1 192.02,71.77 ; H26.1 192.02,68.73 ; H26.1 190.5,68.17 ; H26.1 190.5,72.33 ; H26.1 188.98,71.77 ; H26.1 188.98,68.73 ; 58.5,11.72 H14.1 ; H14.1 60.53,13.75 ; H14.1 59.99,12.26 ; H14.1 58.5,15.78 ; H14.1 56.47,13.75 ; H14.1 59.99,15.24 ; H14.1 57.01,15.24 ; H14.1 57.01,12.26 ; 219.93,55.03 JUSB2.7 ; JUSB2.7 221.07,56.17 ; JUSB2.7 221.07,55.03 ; JUSB2.7 220.5,56.34 ; JUSB2.7 220.5,54.86 ; JUSB2.7 219.76,55.6 ; JUSB2.7 219.93,56.17 ; JMDP1.19 223.66,68.88 ; JMDP1.19 224.3,67.72 ; JMDP1.19 223.02,67.72 ; JMDP1.19 224.3,68.88 ; JMDP1.19 223.66,67.72 ; JMDP1.19 224.3,68.3 ; JUSB2.4 219.57,59.67 ; JUSB2.4 218.26,59.1 ; JUSB2.4 219.74,59.1 ; JUSB2.4 219,58.36 ; JUSB2.4 219,59.84 ; JUSB2.4 218.43,59.67 ; JUSB2.4 219.57,58.53 ; JUSB2.4 218.43,58.53 ; H9.1 106.99,58.52 ; H9.1 104.95,56.49 ; H9.1 103.47,60.01 ; H9.1 106.44,57.04 ; H9.1 103.47,57.04 ; H9.1 104.95,60.56 ; H9.1 102.92,58.52 ; H9.1 106.44,60.01 ; JMDP1.21 222,77.12 ; JMDP1.21 220.82,77.12 ; JMDP1.21 223.18,77.12 ; JMDP1.21 223.18,76.4 ; JMDP1.21 222,75.68 ; JMDP1.21 223.18,75.68 ; JMDP1.21 220.82,76.4 ; 223.66,69.72 JMDP1.13 ; JMDP1.13 224.3,69.72 ; JMDP1.13 223.66,70.88 ; JMDP1.13 223.02,70.88 ; 226.7,76.38 JMDP1.22 ; JMDP1.22 225.62,77.82 ; JMDP1.22 225.62,76.38 ; JMDP1.22 227.78,77.1 ; JMDP1.22 227.78,76.38 ; JMDP1.22 226.7,77.82 ; JMDP1.22 227.78,77.82 ; JMDP1.22 225.62,77.1 ; JMDP1.23 223.18,65.48 ; JMDP1.23 220.82,65.48 ; JMDP1.23 223.18,66.92 ; JMDP1.23 220.82,66.2 ; JMDP1.23 222,65.48 ; JMDP1.23 223.18,66.2 ; JMDP1.23 222,66.92 ; H3.1 12.57,29.98 ; H3.1 13.23,31.75 ; H3.1 9.03,29.98 ; H3.1 10.8,29.32 ; H3.1 10.8,34.18 ; H3.1 12.57,33.52 ; H3.1 8.37,31.75 ; H3.1 9.03,33.52 ; 146.33,85.66 H6.1 ; H6.1 147.5,85.24 ; H6.1 149.09,86.83 ; H6.1 148.67,85.66 ; H6.1 147.5,88.42 ; H6.1 148.67,88 ; H6.1 145.91,86.83 ; H6.1 146.33,88 ; 218.28,36.46 JUSB1.7 ; JUSB1.7 219.56,37.74 ; JUSB1.7 218.92,37.94 ; JUSB1.7 219.56,36.46 ; JUSB1.7 218.08,37.1 ; JUSB1.7 219.76,37.1 ; JUSB1.7 218.92,36.26 ; JUSB1.7 218.28,37.74 ; 104.95,76.9 H12.1 ; H12.1 103.47,77.44 ; H12.1 106.99,78.93 ; H12.1 104.95,80.96 ; H12.1 106.44,80.42 ; H12.1 103.47,80.42 ; H12.1 106.44,77.44 ; H12.1 102.92,78.93 ; JUSB1.14 229.28,28.34 ; JUSB1.14 227.77,28.34 ; JUSB1.14 226.26,28.34 ; JUSB1.14 229.28,29.2 ; JUSB1.14 226.26,29.2 ; 218.33,61.07 JUSB2.10 ; JUSB2.10 218.33,62 ; JUSB2.10 219.75,61.07 ; JUSB2.10 219.75,62.93 ; JUSB2.10 221.17,62.93 ; JUSB2.10 218.33,62.93 ; H10.1 45.14,80.42 ; H10.1 43.65,76.9 ; H10.1 42.17,77.44 ; H10.1 43.65,80.96 ; H10.1 41.62,78.93 ; H10.1 42.17,80.42 ; H10.1 45.69,78.93 ; H10.1 45.14,77.44 ; H5.1 227.17,18.52 ; H5.1 224.41,17.35 ; H5.1 226,15.76 ; H5.1 224.83,16.18 ; H5.1 226,18.94 ; H5.1 224.83,18.52 ; H5.1 227.17,16.18 ; H5.1 227.59,17.35 ; JMDP1.24 226.7,66.22 ; JMDP1.24 225.62,65.5 ; JMDP1.24 225.62,66.22 ; JMDP1.24 227.78,64.78 ; JMDP1.24 227.78,66.22 ; JMDP1.24 225.62,64.78 ; JMDP1.24 226.7,64.78 ; JMDP1.24 227.78,65.5 ; H1.1 218.59,79.25 ; H1.1 218.17,78.08 ; H1.1 217,77.66 ; H1.1 215.41,79.25 ; H1.1 217,80.84 ; H1.1 215.83,78.08 ; H1.1 218.17,80.42 ; H1.1 215.83,80.42 ; H11.1 45.68,58.52 ; H11.1 45.14,60.01 ; H11.1 42.16,60.01 ; H11.1 41.62,58.52 ; H11.1 43.65,56.49 ; H11.1 42.16,57.03 ; H11.1 45.14,57.03 ; H11.1 43.65,60.55 ; JUSB2.12 229.48,47.75 ; JUSB2.12 226.92,46.82 ; JUSB2.12 226.92,47.75 ; JUSB2.12 229.48,46.82 ; JUSB2.12 228.2,46.82 ; JUSB1.11 219.01,44.36 ; JUSB1.11 217.26,42.64 ; JUSB1.11 219.01,42.64 ; JUSB1.11 217.26,44.36 ; JUSB1.11 217.26,43.5 ; JUSB1.13 227.77,45.86 ; JUSB1.13 226.26,45.86 ; JUSB1.13 229.28,45.86 ; JUSB1.13 226.26,45 ; JUSB1.13 229.28,45 ; JMDP1.1 224.3,74.88 ; JMDP1.1 223.02,74.88 ; JMDP1.1 224.3,73.72 ; JMDP1.1 223.66,74.88 ; JMDP1.1 223.66,73.72 ; JMDP1.1 224.3,74.3 ; 231.35,20.78 SW1.4 ; SW1.4 231.9,20.63 ; SW1.4 231.35,21.87 ; SW1.4 231.2,21.33 ; SW1.4 231.9,22.03 ; 226.92,64.38 JUSB2.11 ; JUSB2.11 226.92,63.45 ; JUSB2.11 229.48,64.38 ; JUSB2.11 229.48,63.45 ; JUSB2.11 228.2,64.38 ; 217.26,30.7 JUSB1.12 ; JUSB1.12 217.26,29.84 ; JUSB1.12 217.26,31.56 ; JUSB1.12 219.01,31.56 ; JUSB1.12 219.01,29.84 ; JMDP1.7 224.3,72.88 ; JMDP1.7 223.66,72.88 ; JMDP1.7 223.02,71.72 ; JMDP1.7 223.66,71.72 ; 231.2,25.38 SW1.2 ; SW1.2 231.9,24.68 ; SW1.2 231.35,25.92 ; SW1.2 231.35,24.83
  BOTTOM w0.102: v1(60.34,53.86) v7(60.34,52.95) ; 213.88,47.22 213.88,46.44 v7(213.63,46.2) ; v7(100.59,84.33) 100.22,84.7 v5(99.35,84.7) ; v7(33.04,82.19) 30.8,82.19 v1(29.28,80.67) ; 200.68,21.81 v7(201.63,21.81) ; v1(33.74,21.48) v7(33.74,20.7) ; v7(19.37,50.95) 19.84,51.42 v1(19.96,51.42) ; RC158.1 v7(66.53,84.1) ; U699.3 205.98,40.61 v7(206.64,41.26) ; v1(112.44,49.59) 110.92,49.59 v7(110.88,49.56) ; v1(228.04,22.44) v7(228.04,23.19) ; v7(164.8,33.64) 165.69,33.64 ; v1(134.58,26.61) 134.13,27.05 v7(134.13,27.13) ; 204.26,47.04 v7(203.45,47.04) ; v7(94.58,48.51) 93.88,49.22 RH34.1 ; v5(119.76,38.44) 119.25,38.44 v7(118.82,38.87) ; v1(209.79,61.43) v7(210.46,60.76)
  BOTTOM w0.127: UCPU1.AV46 68.77,58.57 68.77,58.72 69.09,59.04 69.09,59.31 69.08,59.32 69.08,59.63 ; UCPU1.AV49 67.15,58.68 67.52,59.04 67.52,59.41 67.68,59.57 ; UCPU1.AV36 75.03,58.68 75.39,59.04 75.39,59.45 75.51,59.57 ; 73.82,59.6 73.82,59.08 73.45,58.71 UCPU1.AV39 ; 72.29,59.57 72.24,59.52 72.24,59.04 71.88,58.68 UCPU1.AV41 ; 70.91,59.57 70.67,59.32 70.67,59.04 70.3,58.68 UCPU1.AV43 ; UCPU1.AY22 83.66,57.55 83.66,56.68 v1(83.86,56.48)
  BOTTOM w0.152: UCPU1.AY30 78.52,56.78 78.39,56.64 v1(78.39,56.63)
  BOTTOM w0.178: UCPU1.AW33 UCPU1.AY33 ; UCPU1.AW33 76.93,58.2 UCPU1.AV34 ; UCPU1.AW33 77.17,58.8 UCPU1.AV33 ; UCPU1.AV33 76.93,58.85 UCPU1.AV34 ; UCPU1.AV33 77.22,59.5 UCPU1.AU33 ; UCPU1.AR33 76.72,60.34 v1(76.46,60.08) 76.19,59.81 UCPU1.AT35 75.76,59.63 75.69,59.57 75.05,59.57 74.98,59.63 UCPU1.AT37 73.85,59.63 73.78,59.57 73.41,59.57 73.35,59.63 UCPU1.AT40 72.35,59.63 72.29,59.57 71.92,59.57 71.85,59.63 UCPU1.AT42 71.39,59.63 71.32,59.57 69.96,59.57 UCPU1.AT43 UCPU1.AT46 68.25,59.57 67.19,59.57 67.15,59.61 UCPU1.AT49 ; v1(77.36,61.28) 77.34,61.3 77.03,61.3 77.03,61.3 76.77,61.3 76.77,61.3 76.23,61.3 UCPU1.AN35 ; UCPU1.AW37 74.28,57.88 v1(74.62,58.22) 74.93,58.53 UCPU1.AV36 ; UCPU1.AN36 74.72,61.64 v1(74.55,61.46) ; UCPU1.AW42 71.14,57.88 v1(71.48,58.21) 71.79,58.53 UCPU1.AV41 ; UCPU1.AV39 73.35,58.53 v1(73.05,58.22) 72.7,57.88 UCPU1.AW40 ; UCPU1.AU20 UCPU1.AU22 ; UCPU1.AW44 69.55,57.88 v1(69.88,58.21) 70.2,58.53 UCPU1.AV43 ; UCPU1.AV34 76.5,58.53 v1(76.19,58.21) 75.85,57.88 UCPU1.AW35 ; UCPU1.AT49 66.63,59.53 65.67,59.53 UCPU1.AU51 UCPU1.AV51 UCPU1.AW51 UCPU1.AY51 65.73,57.47 65.73,56.86 v1(65.65,56.78) ; UCPU1.AT49 66.85,59.74 66.85,60.32 UCPU1.AR49 67.01,60.34 67.27,60.08 v1(67.33,60.08) ; UCPU1.AL33 76.86,62.94 76.52,62.6 v1(76.45,62.6) ; UCPU1.AL36 74.72,62.94 v1(74.55,62.76) ; UCPU1.AV46 68.73,58.48 68.45,58.2 v1(68.33,58.2) 68,57.88 UCPU1.AW47 ; UCPU1.AW16 88.36,58.2 v5(88.38,58.22)
  BOTTOM w0.203: UD5.J8 56.07,34.87 55.66,35.28 54.89,35.28 v1(54.86,35.24) ; UCPU1.AY16 87.53,57.47 87.53,56.93 87.66,56.8 87.68,56.81 v1(87.69,56.81) ; UCPU1.AT40 73.08,59.68 UCPU1.AR39 UCPU1.AP39 UCPU1.AN39 ; UCPU1.AY24 82.31,56.79 v1(82.45,56.64) ; UCPU1.AY18 86.06,57.52 86.06,56.74 86.24,56.56 v1(86.24,56.57) ; v1(185.69,78.88) 185.39,78.88 185.24,79.02 JLVDS2.1 ; PU702.3 37.26,71.68 37.52,71.95 ; v1(74.54,60.82) 74.37,60.99 UCPU1.AP38 ; UCPU1.AR43 70.56,60.34 v1(70.24,60.01) 69.89,59.66 UCPU1.AT43 ; PU703.3 28.09,71.49 28.44,71.84 ; v10(61.13,77.16) 61.13,77.24 60.92,77.44 60.92,77.7 UCPU1.D59 ; UCPU1.AU26 81,59.55 82.26,59.55 UCPU1.AU24 ; v1(81.03,56.6) 80.94,56.7 80.94,57.54 UCPU1.AY26 ; UD2.M1 37.04,32.38 36.64,31.98 36.64,31.27 v1(36.65,31.27)
  BOTTOM w0.254: JLVDS1.4 164.75,80.71 v1(164.47,80.99) ; UCPU1.AY53 64.43,57.42 64.43,56.83 v1(64.45,56.81) ; UCPU1.B40 UCPU1.A40 v10(72.57,80.01) ; v1(80.74,61.28) 80.88,61.28 UCPU1.AP26 ; v1(35.83,34.47) 36.23,34.87 UD2.J2 ; UD4.A9 43.72,41.23 43.3,40.8 43.29,40.81 43.27,40.79 43.27,40.77 v1(43.26,40.77) ; v5(88.38,58.22) 88.68,58.53 UCPU1.AV14 ; UCPU1.Y10 v5(90.67,68.75) ; v1(102.6,40.86) 103.01,41.27 UD10.A9 ; v1(61.81,56.65) 61.81,56.7 61.88,56.77 61.88,56.77 61.85,56.8 61.85,57.54 UCPU1.AY57 ; UCPU1.AK23 83.11,63.61 83.11,64.16 UCPU1.AH24 82.7,64.68 82.23,65.16 82.23,65.22 ; UCPU1.AK23 83.23,63.59 83.47,63.35 83.52,63.35 83.67,63.2 83.67,63.18 UCPU1.AL22 ; UCPU1.AK23 82.92,63.59 82.55,63.22 82.55,63.28 ; v5(60.75,75.25) 60.75,75.04 UCPU1.J59 ; v1(98.93,31.3) 98.93,31.27 98.91,31.25 98.9,31.27 98.9,31.48 97.92,32.47 UD9.M1 ; UD1.G1 25.44,36.47 25.45,36.46 25.5,36.46 25.99,36.94 26.19,36.94 v1(26.25,37) ; UCPU1.AB7 v5(92.69,67.45) ; UCPU1.AF17 v5(87.31,66.15) ; v1(66.4,40.86) 66.81,41.27 UD6.A9 ; v5(95.63,78.09) 95.94,77.78 UCPU1.D2 ; v5(141.19,78.54) PU501.19 ; UCPU1.D12 90.12,78.07 v5(90.29,78.24) 90.29,78.64 UCPU1.C11 ; v1(79.6,38.46) 79.21,38.07 UD7.E8 ; v1(79.6,38.46) UD7.D8 ; v1(79.6,38.46) 79.61,38.46 79.61,38.45 UD7.E7 ; UCPU1.D21 v5(84.85,77.43) ; UD9.J2 97.04,34.87 96.64,34.47 v1(96.67,34.47) ; UCPU1.AC61 59.26,67.39 v5(58.97,67.68) ; UD1.B1 25.48,40.47 v1(25.87,40.86) ; UCPU1.A18 86.02,79.85 86.28,80.11 v5(86.28,80.18) ; UCPU1.N10 v5(90.71,72.56) ; v5(88.46,73.27) 88.46,73.27 88.31,73.42 UCPU1.L15 ; 82.23,65.22 82.08,65.07 82.08,64.27 UCPU1.AJ25 ; 82.23,65.22 v1(82.23,65.23) ; UCPU1.AA58 61.2,68.57 v5(60.83,68.57) 60.6,68.8 UCPU1.Y59 ; UCPU1.AN51 65.86,61.68 65.48,62.06 65.26,62.06 UCPU1.AM52 65,62.33 65,62.89 UCPU1.AL52 64.86,62.94 64.53,63.26 v1(64.51,63.26) ; UCPU1.AN51 66.07,61.43 66.66,61.43 UCPU1.AN49 67.01,61.64 v1(67.33,61.32) ; UCPU1.AN51 UCPU1.AN52 64.99,61.64 v1(64.51,61.16) ; UCPU1.AJ23 83.92,64.71 UCPU1.AH22 ; JNGFF1.7 v5(182.75,37.8) ; UCPU1.AH22 84.02,64.47 84.25,64.24 84.67,64.24 ; UCPU1.AH22 83.61,65.11 UCPU1.AG23 83,65.11 v1(82.87,65.23) ; v5(60.8,73.85) 60.93,73.73 UCPU1.L58 ; UCPU1.AN43 70.61,61.64 v1(70.23,61.26) 70.23,61.28 69.87,61.64 UCPU1.AN45 69.58,61.81 69.03,61.81 68.86,61.64 UCPU1.AN46 68.82,61.69 68.44,62.07 68.35,62.07 68.25,61.97 68.25,61.99 ; v1(57.61,59.59) 58,59.97 UCPU1.AT63 58.02,60.03 58.57,60.03 58.7,60.16 UCPU1.AT62 58.81,60.18 59.06,60.43 59.41,60.43 UCPU1.AT61 ; v1(62.07,38.46) 62.05,38.44 62.05,38.43 61.68,38.07 UD5.E1 ; v1(51.18,31.27) 51.16,31.25 51.15,31.27 51.15,31.48 50.17,32.47 UD4.M1 ; v1(18.65,29.65) 19.04,29.27 UD1.T9 ; v1(26.54,31.27) 26.52,31.25 26.51,31.27 26.51,31.48 25.53,32.47 UD1.M1 ; UCPU1.D8 v5(92.47,77.69) ; UD10.P9 103.03,30.81 102.57,30.35 v1(102.57,29.68) 102.56,29.67 102.6,29.67 103,29.27 UD10.T9 ; UCPU1.L7 v5(92.94,73.77) ; v5(84.45,69.94) 84.09,69.58 UCPU1.W22 ; v5(84.4,72.38) 84.04,72.02 UCPU1.P22 ; v1(89.32,72.94) 89.26,73 UCPU1.L13 89.33,73.71 89.74,74.12 UCPU1.K12 ; UD2.B3 35.43,40.47 35.12,40.78 v1(34.97,40.78) ; UCPU1.AN35 75.58,61.95 75.5,62.03 v1(75.46,61.99) 75.11,61.64 UCPU1.AN36 ; UD9.A9 91.47,41.25 91.2,40.98 v1(90.99,40.98) 90.99,40.93 91.45,40.47 UD9.B9 ; v1(77.95,40.14) 77.95,40.13 77.96,40.13 77.97,40.14 77.92,40.19 77.92,40.03 78.36,40.47 UD7.B9 ; UD6.D8 67.63,38.85 v1(68.03,38.45) 68.42,38.07 UD6.E7 ; v1(50.51,40.86) 50.5,40.86 50.12,40.47 UD4.B1 ; UCPU1.AP10 91.08,61.02 91.08,60.96 v5(91.21,60.83) ; UD4.T1 50.16,29.27 v1(50.54,28.89) ; v1(68.81,76.09) UCPU1.F46 UCPU1.D46 ; v5(90.01,65.98) 89.75,65.72 UCPU1.AF12 ; 83.16,60.99 v1(83.49,61.32) ; 83.16,60.99 83.03,60.85 83.03,60.41 UCPU1.AR23 83.15,60.34 v1(83.51,59.99) ; 83.16,60.99 UCPU1.AP23 ; v1(83.49,61.32) 83.18,61.64 UCPU1.AN23 83,61.73 83,62.19 UCPU1.AM23 83,62.38 83,62.84 UCPU1.AL23 82.9,62.94 82.55,63.29 82.55,63.28 ; v1(83.49,61.32) 83.48,61.32 83.48,61.35 83.85,60.99 UCPU1.AP22 ; v5(91.08,29.68) 91.47,29.29 UD9.T9 ; UD6.F9 66.84,37.29 v1(67.23,37.68) 67.23,37.68 67.24,37.68 67.63,38.07 UD6.E8 ; v5(92.35,71.82) 92.25,71.82 92.04,71.61 UCPU1.R8 ; UCPU1.AN32 77.72,61.64 v1(77.36,61.28) ; UCPU1.AN32 78.04,61.64 UCPU1.AN31 78.27,62.06 78.27,62.52 UCPU1.AM31 78.36,62.63 78.67,62.94 v1(78.75,62.94) ; UCPU1.AN32 78.13,61.31 UCPU1.AP31 78.69,60.99 ; UCPU1.AU16 UCPU1.AV16 UCPU1.AW16 87.4,57.59 UCPU1.AY16 ; UCPU1.AU16 87.63,59.73 87.83,59.73 ; UCPU1.AU16 86.99,59.5 86.87,59.63 86.63,59.63 v1(86.58,59.68) 86.41,59.5 UCPU1.AU18 85.76,59.83 v1(85.41,59.83) 85.09,59.5 UCPU1.AU20 UCPU1.AV20 ; UD5.A9 55.26,41.27 v1(54.85,40.86) ; UD5.E8 56.07,38.07 55.68,37.68 55.67,37.68 v1(55.67,37.68) ; 78.69,60.99 UCPU1.AR31 78.2,60.5 78.2,59.96 ; 78.69,60.99 UCPU1.AP29 ; v1(103.44,36.07) 103.83,36.46 UD10.G8 ; UCPU1.AL46 69.02,62.94 v1(69.27,63.19) 69.49,63.19 UCPU1.AL45 ; UCPU1.H17 87.31,75.28 v5(87.07,75.53) ; UD4.P1 50.12,30.87 50.1,30.87 49.73,31.24 49.73,31.28 v1(49.72,31.28) ; UD2.G1 37,36.47 36.63,36.83 v1(36.63,36.88) ; UCPU1.B28 UCPU1.A28 ; v1(19.5,37.67) 19.5,37.67 19.51,37.67 19.88,38.04 UD1.E8 ; UD10.B1 109.43,40.47 v1(109.82,40.86) ; v1(73.48,63.62) 73.12,63.26 UCPU1.AL39 72.74,63.26 72.49,63.01 UCPU1.AL40 ; v1(73.48,63.62) 72.95,64.15 UCPU1.AJ39 72.99,64.28 v1(72.99,64.87) 72.69,64.57 UCPU1.AH40 71.97,64.57 71.65,64.24 UCPU1.AJ41 ; v1(73.48,63.62) 73.61,63.49 73.61,62.66 73.08,62.13 UCPU1.AN39 72.82,61.96 UCPU1.AN40 72.41,61.64 v1(72.08,61.96) 71.75,61.64 UCPU1.AN42 ; UCPU1.AW4 94.7,57.84 UCPU1.AY4 94.7,57 95.04,56.65 95.68,56.65 95.78,56.55 97.91,56.55 100.63,53.84 102.23,53.84 103.04,53.02 104.13,53.02 v1(104.19,52.97) 104.19,53.01 104.79,52.4 CH2.2 104.74,51.73 104.74,49.11 104.51,48.88 100.58,48.88 100.32,49.13 v1(100.32,50.58) CH3.2 100.08,52.02 99.74,52.02 98.25,53.51 97.91,53.51 97.4,54.01 96.79,54.01 95.94,54.87 v1(94.87,54.87) 93.62,56.12 93.62,56.7 93.25,57.07 UCPU1.AY6 ; v1(67.23,35.26) 67.29,35.26 67.63,34.92 67.63,34.86 UD6.J8 ; 87.42,60.67 87.52,60.67 87.92,61.07 v1(87.92,61.09) 87.92,61.1 87.78,61.24 87.49,61.24 UCPU1.AP17 UCPU1.AN17 UCPU1.AM17 UCPU1.AL17 87.4,63.96 v1(87.4,63.97) ; 87.42,60.67 87.42,60.46 87.59,60.3 87.59,60.27 87.83,60.03 87.83,59.73 ; 87.42,60.67 UCPU1.AR17 ; UCPU1.AR5 93.97,60.48 v5(94.16,60.67) ; UCPU1.T1 v5(97.12,71.13) ; v5(58,71.56) UCPU1.P63 UCPU1.P62 ; UD9.J8 92.27,34.86 92.27,34.87 v1(91.88,35.26) ; UCPU1.AE58 60.94,65.61 60.94,65.47 60.91,65.45 v1(60.91,65.45) 60.91,65.38 60.78,65.25 UCPU1.AG60 UCPU1.AG61 59.48,65.39 59.11,65.39 UCPU1.AG62 58.91,65.31 58.54,65.31 58.48,65.25 UCPU1.AG63 ; v5(85.92,70.73) 85.59,70.4 UCPU1.U20 ; v1(82.54,63.28) 82.55,63.28 ; UD2.T9 30.57,29.27 v1(30.16,29.68) 30.16,30.61 30.42,30.87 UD2.P9 ; UD5.G1 61.66,36.47 61.27,36.86 v1(61.27,36.87) ; UD10.T1 109.39,29.27 109.02,28.91 v1(109.02,28.84) ; v1(74.88,65.26) 74.88,65.26 74.9,65.24 UCPU1.AH36 ; UD10.D1 109.43,38.86 v1(109.04,38.47) 109.02,38.47 108.63,38.07 UD10.E2 ; 85.11,79.01 84.91,79.21 UCPU1.B20 ; 85.11,79.01 v5(85.11,79.06) ; 85.11,79.01 UCPU1.C20 ; UD9.E7 93.07,38.13 v1(93.6,38.66) ; v1(84.38,40.86) 84.77,40.47 UD7.B1 ; v1(64.51,61.16) 64.34,60.99 UCPU1.AP54 ; v1(64.51,61.16) 64.67,60.99 UCPU1.AP52 UCPU1.AR52 64.88,60.18 64.88,59.7 v1(64.9,59.68) ; UCPU1.AB10 v5(91.58,67.8) ; v5(86.84,76.11) 86.66,75.93 UCPU1.G18 ; UCPU1.AV8 91.86,58.46 91.97,58.46 92.12,58.31 v5(92.12,58.28) ; UD2.A9 30.62,41.27 v1(30.21,40.86) ; UCPU1.AN7 92.89,61.85 93.14,62.1 v5(93.14,62.13) ; v1(87.4,63.97) 87.32,63.97 86.91,64.38 UCPU1.AH17 86.81,64.38 v5(86.5,64.69) 86.19,64.38 UCPU1.AH19 UCPU1.AH20 85.02,64.38 v1(84.77,64.13) 84.67,64.24 ; v1(87.4,63.97) 87.72,64.29 UCPU1.AH16 ; v10(57.67,74.74) 57.85,74.92 UCPU1.J63 ; UD9.B1 98.72,40.47 v1(98.8,40.55) ; UCPU1.G6 93.32,75.93 v5(93.49,76.11) 93.67,75.93 UCPU1.G5 ; UD7.F9 77.96,37.27 v1(77.84,37.15) ; UD1.D1 25.53,38.87 25.91,38.49 v1(25.91,38.48) 25.91,38.42 25.55,38.07 UD1.E1 ; v5(93.71,66.18) 93.71,66.18 UCPU1.AE5 ; v5(87.5,73.24) 87.35,73.38 UCPU1.L17 ; v1(88.51,59.63) 88.51,60.12 UCPU1.AR15 ; v1(88.51,59.63) 88.85,59.63 UCPU1.AT13 ; v1(88.51,59.63) 88.41,59.73 87.83,59.73 ; UD5.D1 61.68,38.86 v1(61.28,38.47) 61.27,38.47 60.88,38.07 UD5.E2 ; 78.2,59.96 77.76,59.52 UCPU1.AU33 77.01,59.52 v1(76.46,60.08) ; 78.2,59.96 v1(78.23,59.93) 78.46,59.7 78.46,59.57 UCPU1.AU30 78.6,59.58 79.67,59.58 UCPU1.AU28 ; v1(69.08,65.2) 69.05,65.17 UCPU1.AJ45 68.72,64.57 UCPU1.AH46 ; UD4.J2 49.28,34.87 48.92,34.51 v1(48.92,34.46) ; v1(44.93,38.46) 44.54,38.07 UD4.E8 ; v1(44.93,38.46) 44.94,38.46 44.94,38.45 45.32,38.07 UD4.E7 ; v1(44.93,38.46) 44.93,38.49 44.55,38.87 UD4.D8 ; v5(185.29,43.22) 185.49,43.43 JNGFF1.18 ; UCPU1.AK3 95.32,63.66 95.6,63.39 v5(95.6,63.36) ; UCPU1.AR39 73.66,60.66 UCPU1.AP38 ; v1(103.42,37.68) 103.42,37.68 103.44,37.68 103.82,38.07 UD10.E8 ; v1(66.32,32.82) 66.37,32.82 66.73,32.47 UD6.M9 ; UCPU1.AJ13 89.35,63.73 89.78,63.3 v3(89.78,63.16) 89.7,63.08 UCPU1.AL13 88.67,63.45 88.67,63.45 88.53,63.59 UCPU1.AJ14 ; UD10.G1 109.41,36.47 109.03,36.85 v1(109.03,36.88) ; UD4.D1 50.12,38.86 v1(49.73,38.47) 49.71,38.47 49.32,38.07 UD4.E2 ; UD5.E7 56.5,38.45 56.5,38.46 v1(56.49,38.46) UD5.D8 ; v1(24.3,34.47) 24.3,34.52 24.64,34.87 UD1.J2 ; v1(78.75,62.94) 78.43,63.26 UCPU1.AL31 ; v1(78.75,62.94) UCPU1.AL29 ; JIOL1.10 16.1,25.6 v1(16.29,25.79) 16.29,25.74 16.6,25.42 JIOL1.12 ; UD10.M9 103,32.47 v1(102.62,32.09) ; UCPU1.AL60 60.27,62.32 60.6,61.99 60.65,61.99 ; UCPU1.AL60 60.29,62.7 60.29,63.11 60.45,63.27 v3(60.45,63.33) 60.43,63.35 60.43,63.74 UCPU1.AJ60 60.3,63.93 60.78,63.93 61.09,64.24 UCPU1.AJ58 61.57,64.57 UCPU1.AH57 62.14,64.57 v1(62.41,64.83) 62.55,64.69 62.55,64.25 UCPU1.AJ56 62.59,64.2 v1(62.59,63.27) 62.26,62.94 UCPU1.AL57 ; UCPU1.AL60 UCPU1.AL61 ; UD4.F9 43.63,37.27 v1(43.2,36.84) 43.57,36.47 UD4.G9 43.83,36.36 44.41,36.36 UD4.G8 ; v5(91.01,74.93) 91.02,74.93 91.02,74.78 UCPU1.J10 ; v1(67.33,61.32) 67.64,61.64 UCPU1.AN48 67.77,61.74 68.08,62.05 68.19,62.05 68.25,61.99 ; v1(67.33,61.32) 67.43,61.32 UCPU1.AP48 ; v5(85.72,76.85) 85.46,76.59 UCPU1.F20 ; v1(84.4,29.68) 84.4,29.6 84.73,29.27 UD7.T1 ; UCPU1.AF15 88.13,66 88.18,66.05 v5(88.18,66.05) ; v5(85.85,69.94) 85.49,69.58 UCPU1.W20 ; v5(87.7,77.15) 87.44,77.15 UCPU1.E17 ; UD5.P9 55.28,30.81 54.85,30.38 v1(54.85,29.68) 54.83,29.67 55.23,29.27 UD5.T9 ; v10(75.08,79.97) UCPU1.A36 74.92,79.37 74.92,79.04 UCPU1.B36 ; UD7.P1 84.79,30.87 84.79,30.89 v1(84.4,31.27) ; PU402.6 206.4,70.06 v5(205.99,70.47) ; v1(82.7,39.33) 83.17,38.87 UD7.D3 ; UD7.E1 84.8,38.07 85.16,38.43 85.16,38.44 v1(85.18,38.46) ; UD6.J2 72.41,34.87 72.03,34.49 v1(72.03,34.46) ; UD2.P1 37.04,30.87 v1(36.65,31.27) ; v1(66.4,31.25) 66.45,31.25 66.84,30.87 UD6.P9 ; UCPU1.B32 77.77,79.06 77.77,79.35 UCPU1.A32 v10(77.59,80) ; UD6.P1 73.23,30.87 73.21,30.87 72.84,31.24 72.84,31.28 v1(72.83,31.28) ; v1(73.76,38.66) 73.74,38.64 73.74,38.63 73.23,38.12 UD6.E1 ; UCPU1.AJ35 75.55,64.98 v1(75.83,65.26) 76.2,64.88 UCPU1.AH34 ; UD1.P9 18.99,30.87 v1(18.57,30.45) ; UD5.J2 60.86,34.87 60.48,34.48 v1(60.48,34.46) ; v5(86.25,73.32) 86.4,73.47 UCPU1.L18 ; v1(76.33,76.14) UCPU1.F34 UCPU1.D34 ; UD1.F9 19.04,37.27 v1(18.64,36.87) ; v5(88.51,66.08) 88.94,65.65 UCPU1.AF14 ; v1(19.47,35.27) 19.51,35.27 19.88,34.9 19.88,34.86 UD1.J8 ; v1(74.27,31.05) 74.27,31.14 74.24,31.11 74.23,31.12 74.23,31.46 73.23,32.46 UD6.M1 ; v5(84.55,71.95) 84.94,72.33 UCPU1.N21 ; v10(90.35,80.24) 90.35,79.95 UCPU1.A11 ; UCPU1.AU28 UCPU1.AV28 ; UCPU1.AU28 79.91,59.5 80.37,59.96 80.72,59.96 ; 68.25,61.99 v1(68.25,62.02) ; v1(17.63,25.74) 17.6,25.71 JIOL1.16 ; UD2.B9 30.61,40.47 v1(30.23,40.09) ; v5(85.69,73.29) 85.44,73.54 UCPU1.L20 ; v1(55.67,36.06) 56.08,36.46 UD5.G8 ; UD9.D8 92.27,38.85 v1(92.65,38.47) 92.27,38.09 UD9.E8 ; JIOL1.11 16.6,20.75 v1(16.45,20.89) 16.1,20.54 JIOL1.9 ; UD6.E2 72.43,38.07 v1(72.83,38.47) 72.84,38.47 73.23,38.86 UD6.D1 ; UCPU1.AD63 57.6,66.68 v5(57.53,66.75) ; UD2.D3 35.45,38.87 v1(35.85,38.47) 36.24,38.07 UD2.E2 ; UCPU1.D30 UCPU1.F30 v1(78.84,75.97) ; UD7.P9 78.26,30.87 77.82,30.42 77.82,29.78 v1(77.92,29.68) 78.33,29.27 UD7.T9 ; v1(54.88,32.07) 55.28,32.46 UD5.M9 ; UD9.F9 91.37,37.27 90.93,36.82 90.93,36.18 91.02,36.09 v1(91.02,36.01) 91.27,36.26 91.27,36.27 91.47,36.47 UD9.G9 91.61,36.61 92.13,36.61 UD9.G8 ; UCPU1.D26 UCPU1.F26 81.35,75.96 v1(81.35,75.96) ; UCPU1.AP3 95.32,60.71 95.63,61.02 v5(95.63,61.07) ; UCPU1.G3 95.25,75.67 v5(95.03,75.45) ; UCPU1.F61 59.28,76.37 58.99,76.67 v10(58.97,76.67) ; UD10.E1 109.44,38.07 109.8,38.43 109.8,38.44 v1(109.82,38.46) ; v1(66.3,76.09) UCPU1.F50 UCPU1.D50 ; v1(60.47,40.88) 60.47,40.87 60.08,40.47 UD5.B3 ; UD9.D1 97.87,38.86 v1(97.48,38.47) ; UCPU1.B52 64.94,78.99 64.94,79.42 UCPU1.A52 65.05,79.82 v1(65.24,80.01) ; UCPU1.AH51 66.12,64.57 UCPU1.AJ50 66.45,65.07 66.48,65.11 66.48,65.11 66.46,65.13 v1(66.46,65.19) ; v1(73.82,76.09) UCPU1.F38 UCPU1.D38 ; UCPU1.D14 89.1,78.07 89.1,78.45 v5(89.05,78.5) 88.89,78.66 UCPU1.C14 ; JLVDS2.15 178.24,80.73 v1(177.98,80.99) 177.74,80.75 JLVDS2.16 ; UD6.B9 66.8,40.47 v1(66.43,40.09) ; v5(95.02,69.43) 95.1,69.43 95.32,69.65 UCPU1.V3 ; UCPU1.AM1 97,62.14 v5(97.05,62.19) ; UD2.F9 30.65,37.27 v1(31.05,37.67) 31.44,38.06 UD2.E8 ; UD10.B3 107.83,40.47 108.22,40.87 v1(108.22,40.88) ; 80.72,59.96 80.72,59.91 80.77,59.86 80.77,59.69 UCPU1.AU26 ; 80.72,59.96 v1(80.73,59.96) ; v1(18.6,32.09) 18.86,32.35 18.97,32.35 UD1.M9 ; UD2.J8 31.43,34.87 31.03,35.27 31.03,36.04 v1(31.05,36.06) ; v1(64.51,63.26) 64.18,62.94 UCPU1.AL54 ; v1(64.51,63.26) 64.83,63.59 UCPU1.AK52 65.04,64.13 UCPU1.AJ52 65.15,64.65 v1(65.02,64.78) 64.87,64.63 64.55,64.63 64.5,64.58 UCPU1.AH53 ; UCPU1.D54 UCPU1.F54 v1(63.79,76.09) ; v10(82.89,79.78) 82.64,79.53 UCPU1.A24 UCPU1.B24 ; v5(91.56,71.61) UCPU1.R10 ; v1(98.8,36.64) 98.63,36.47 UD9.G1 ; UD1.G9 19.05,36.47 v1(18.66,36.08) ; v1(66.74,58.17) 66.6,58.17 66.33,57.9 UCPU1.AW50 ; v1(64.9,59.68) 65.46,59.68 UCPU1.AU51 ; v1(64.9,59.68) 64.72,59.5 UCPU1.AU53 64,59.79 v1(63.55,59.79) 63.41,59.79 63.12,59.5 UCPU1.AU55 UCPU1.AV55 ; v1(73.63,28.84) 73.23,29.24 UD6.T1 ; UCPU1.U61 59.05,70.63 59.05,70.7 v10(59.07,70.73) ; UCPU1.AU22 83.66,59.83 v1(83.51,59.99) ; UD7.B3 83.19,40.51 v1(82.69,41.01) ; UD4.P9 43.65,30.87 42.65,31.87 v1(42.65,31.97) 42.65,31.99 42.72,32.06 42.72,32.35 43.02,32.65 43.54,32.65 UD4.M9 ; UD7.J8 79.19,34.87 78.8,35.27 78.03,35.27 v1(77.93,35.18) ; UD9.P9 91.47,30.93 90.6,31.81 90.6,31.83 90.43,32 v1(90.43,32.06) 90.43,32.1 90.58,32.25 90.58,32.28 90.87,32.57 90.9,32.57 90.91,32.58 91.36,32.58 UD9.M9 ; UD6.G8 67.63,36.46 v1(67.23,36.06) ; v1(62.07,40.86) 62.06,40.86 61.68,40.47 UD5.B1 ; v1(54.87,40.09) 55.24,40.47 UD5.B9 ; UCPU1.U9 v5(91.04,70.18) 91.15,70.07 UCPU1.V10 ; UD1.B9 18.97,40.47 v1(18.57,40.08) ; UCPU1.AJ29 79.19,64.5 78.87,64.5 UCPU1.AH30 v1(78.8,65.23) ; v1(110.48,31.27) 110.47,31.25 110.46,31.27 110.46,31.79 109.78,32.47 UD10.M1 ; UD1.P1 25.48,30.87 25.46,30.87 25.09,31.24 25.09,31.28 v1(25.08,31.28) ; v5(174.26,33.67) 174.21,33.61 PU304.6 ; UCPU1.AP20 85.76,60.99 85.44,61.3 v1(85.36,61.3) ; v1(85.18,36.87) 85.18,36.84 85.16,36.82 85.14,36.82 84.79,36.47 UD7.G1 ; v1(77.96,40.86) 78.37,41.27 UD7.A9 ; JNGFF1.49 v5(195.24,37.78) ; v1(60.48,38.47) 60.08,38.87 UD5.D3 ; UCPU1.AY11 90.25,56.97 90.01,56.73 v5(89.99,56.73) ; JLVDS1.7 v1(163.25,81.08) ; v1(67.75,65.21) UCPU1.AJ47 67.42,64.57 UCPU1.AH49 ; JLVDS2.20 175.74,79.09 v1(175.42,78.77) ; v5(86.48,78.47) 86.3,78.66 UCPU1.C18 ; UCPU1.N3 95.46,72.67 v5(95.65,72.86) ; v1(83.6,34.46) 83.6,34.49 83.98,34.87 UD7.J2 ; UD6.B1 73.23,40.47 v1(73.62,40.86) ; JNGFF1.31 190.75,35.41 v1(190.76,35.39) ; JLVDS1.12 160.75,80.78 v1(160.95,80.99) 161.25,80.69 JLVDS1.11 ; UCPU1.D23 82.91,78.41 82.44,78.41 v1(82.41,78.38) ; v1(72.05,40.86) 71.65,40.47 UD6.B3 ; JNGFF1.37 192.24,35.51 v1(192.13,35.39) ; 84.67,64.24 UCPU1.AG21 ; v1(85.36,33.64) 85.36,33.04 UD7.M1 ; v1(62.31,32.81) 62.02,32.81 UD5.M1 ; UD2.G8 31.44,36.45 v1(31.05,36.06) ; v5(84.37,73.16) 84.04,72.84 UCPU1.M22 ; UCPU1.AH32 v1(77.5,65.27) ; v5(97.37,67.79) 97.02,68.14 UCPU1.AA1 ; UD4.D3 48.13,39.26 v1(48.13,39.27) ; v5(84.4,71.46) 84.15,71.21 UCPU1.R22 ; v10(61.06,75.51) 61.33,75.51 UCPU1.H57 61.56,75.75 61.46,75.85 61.46,76.29 61.25,76.5 UCPU1.F58 61.25,77.04 v10(61.13,77.16) ; UD7.E2 83.99,38.07 84.39,38.47 v1(84.4,38.47) 84.79,38.86 UD7.D1 ; v1(83.51,59.99) 83.12,59.6 82.49,59.6 82.39,59.5 UCPU1.AU24 UCPU1.AV24 UCPU1.AW24 UCPU1.AY24 ; UD4.J8 44.51,34.87 v1(44.13,35.26) ; v5(88.92,74.97) 89.24,75.28 UCPU1.H13 ; UCPU1.AB20 v1(86.03,67.96) ; PU401.6 v5(115.61,82.74) ; JIOL1.22 19.1,24.77 19.1,23.82 v1(19.13,23.79) ; UCPU1.AU1 v5(97.09,59.2) ; UD9.E1 97.87,38.08 v1(97.48,38.47) ; UD1.B3 23.88,40.47 24.28,40.87 v1(24.28,40.88) ; v1(102.55,35.2) 102.59,35.24 103.46,35.24 UD10.J8 ; UCPU1.G22 v5(84.02,75.7) ; UD1.E2 24.68,38.08 v1(24.3,38.47) 23.9,38.87 UD1.D3 ; UD5.G9 55.28,36.54 54.9,36.92 v1(54.83,36.92) 55.18,37.27 UD5.F9 ; UD10.B9 103,40.47 v1(102.62,40.09) ; v5(91.4,75.63) 91.81,75.63 UCPU1.G8 ; v1(31.05,36.06) 30.84,36.27 30.84,36.32 30.7,36.47 UD2.G9 ; UD6.G9 66.8,36.47 v1(66.42,36.08) ; UCPU1.AR11 v10(90.4,59.6) ; UD5.P1 61.67,30.87 61.67,30.88 v1(61.28,31.27) ; JNGFF1.1 v5(181.25,37.8) ; v1(97.48,38.47) 97.47,38.47 97.07,38.07 UD9.E2 ; UCPU1.D62 58.61,77.82 v5(58.34,78.09) 58.21,78.09 UCPU1.D63 ; UCPU1.AH42 70.67,64.57 UCPU1.AJ43 70.35,65 70.16,65.18 v1(70.16,65.18) 70.16,65.02 70.03,64.89 70.03,64.89 UCPU1.AH44 ; 60.65,61.99 v1(60.72,61.99) ; 60.65,61.99 60.27,61.61 UCPU1.AN60 ; v5(93.7,77.66) 93.95,77.91 UCPU1.D5 ; UCPU1.B60 59.95,79.19 v5(59.63,79.51) ; v1(108.24,35.31) 108.67,34.88 108.67,34.86 108.66,34.86 108.64,34.86 UD10.J2 ; v1(30.24,32.06) 30.25,32.07 30.25,32.14 30.58,32.47 UD2.M9 ; v1(37.59,29.65) 37.51,29.65 37.12,29.27 UD2.T1 ; UCPU1.V7 v5(92.69,69.31) ; UD10.P1 109.42,30.87 109.41,30.87 109.02,31.25 109.04,31.25 v1(109.04,31.27) ; v5(84.37,74.26) 84.17,74.46 UCPU1.J22 ; UCPU1.K1 96.64,74.11 96.66,74.11 v5(96.88,73.89) ; UD9.T1 97.92,29.27 v1(98.29,28.89) ; UCPU1.AH55 63.53,64.57 63.82,64.86 v1(63.82,64.81) 63.85,64.81 UCPU1.AJ54 ; UD9.D3 96.27,38.87 v1(95.85,39.29) ; UD9.B3 96.27,40.49 v1(96.67,40.88) ; v1(60.28,72.3) 60.28,72.21 60.6,71.89 UCPU1.P59 60.6,71.73 61.19,71.13 61.24,71.13 UCPU1.T58 ; UCPU1.AE10 90.89,65.9 UCPU1.AF11 v10(90.16,65.57) UCPU1.AG11 ; UD2.E1 37.04,38.08 v1(36.65,38.47) 37.04,38.86 UD2.D1 ; v1(59.48,56.58) 59.82,56.58 60.47,57.23 UCPU1.AY59 60.06,57.7 UCPU1.AW60 60.21,57.88 60.53,58.2 UCPU1.AW59 UCPU1.AV59 UCPU1.AU59 60.96,59.5 61.07,59.61 61.75,59.61 UCPU1.AU57 61.9,59.54 61.9,59.87 61.7,60.07 61.7,60.6 v1(61.67,60.63) 62,60.97 62.09,60.97 UCPU1.AP57 ; v5(84.55,66.51) 84.78,66.74 UCPU1.AD21 ; UCPU1.AJ63 58.26,63.96 57.43,63.96 v3(57.41,63.94) ; v1(18.56,40.88) 18.66,40.88 19.05,41.27 UD1.A9 ; UCPU1.AN63 57.59,61.47 57.48,61.36 v1(57.48,61.41) ; v5(94.94,79.49) 94.94,79.44 UCPU1.B4 ; UD2.D8 31.45,38.87 v1(31.85,38.47) 31.86,38.47 31.86,38.46 32.24,38.08 UD2.E7 ; UD10.D3 107.84,38.87 v1(108.24,38.47) ; UCPU1.AG1 v5(97,65.14) ; UCPU1.AD3 95.07,66.93 v5(95.07,66.97) ; v1(73.76,37) 73.76,37.06 73.72,37.02 73.72,36.89 73.3,36.47 UD6.G1 ; UD4.T9 43.68,29.27 v1(43.26,29.68) ; v1(25.89,28.89) 25.89,28.88 25.5,29.27 UD1.T1 ; v1(36.64,40.86) 36.99,40.5 37.07,40.5 37.04,40.47 UD2.B1 ; v1(74.54,60.82) 74.54,61.45 v1(74.55,61.46) ; UD7.G9 78.39,36.48 v1(78.79,36.88) 79.19,36.48 UD7.G8 ; 70.1,78.88 UCPU1.B44 70.06,78.97 v5(69.79,79.24) 69.82,79.26 69.82,79.28 UCPU1.A44 ; v1(66.4,29.65) 66.79,29.27 UD6.T9 ; UCPU1.B56 62.4,79.02 62.4,79.38 UCPU1.A56 62.54,79.68 v1(63.38,80.52) ; UCPU1.AL51 65.89,62.94 66.18,62.64 v1(66.36,62.64) ; UCPU1.AL20 86.14,62.62 v1(86.26,62.62) ; UD7.M9 78.35,32.47 77.99,32.11 v1(77.97,32.11) ; v1(71.18,39.18) 71.22,39.18 71.22,39.29 UD6.D3 ; UCPU1.AH28 80.43,64.24 UCPU1.AJ27 80.75,63.3 v1(80.74,63.28) 80.74,63.31 81.11,62.94 UCPU1.AL26 ; v1(71.32,76.14) UCPU1.F42 UCPU1.D42 ; v5(90.52,77.56) 90.21,77.25 UCPU1.E11 ; v5(59.61,73.11) 59.34,73.38 UCPU1.L61 ; v1(50.67,36.25) 50.44,36.48 50.13,36.48 UD4.G1 ; UCPU1.AF18 v5(86.5,66.1) ; UD10.G9 102.98,36.47 v1(102.53,36.91) 102.88,37.27 UD10.F9 ; v5(91.26,63.32) 91.01,63.08 UCPU1.AL10 ; UD10.D8 v1(104.24,38.46) 104.25,38.46 104.25,38.45 UD10.E7 ; UD4.B3 48.52,40.47 48.91,40.87 v1(48.92,40.88) ; v1(43.29,40.07) 43.69,40.47 UD4.B9 ; UD4.E1 50.12,38.08 50.66,38.62 50.66,38.64 v1(50.68,38.65) ; v5(84.4,68.36) 84.02,67.98 UCPU1.AB22 ; UCPU1.AH38 v1(73.6,65.19) ; UD1.G8 19.88,36.46 v1(19.48,36.06) ; UCPU1.V23 83.61,69.99 UCPU1.U22 84.07,70.4 v5(84.4,70.73) ; v1(97.47,31.28) 97.48,31.28 97.48,31.24 97.85,30.87 97.87,30.87 UD9.P1 ; UD1.E7 20.68,38.07 20.3,38.45 20.3,38.46 v1(20.29,38.46) UD1.D8 ; UCPU1.Y63 v10(57.59,68.93) ; v1(21.1,23.79) JIOL1.30 ; v1(60.28,70.79) 60.78,70.79 61,70.57 61,70.07 UCPU1.V58 ; UCPU1.B48 UCPU1.A48 ; JIOL1.21 v1(19.1,20.88) ; UCPU1.D18 86.52,78 v5(86.81,77.71) ; JNGFF1.43 v5(193.75,37.76) ; JIOL1.13 v1(17.1,20.89) ; UCPU1.A14 v5(88.59,80.3)
  BOTTOM w0.305: JNFC1.14 v1(155.56,25.98) ; v1(199.77,35.55) 199.75,35.57 JNGFF1.67 ; v1(159.2,26.03) 159.06,26.18 JNFC1.7 ; UD5.T1 61.85,29.27 v1(62.16,29.58) ; v1(189.15,35.39) 189.24,35.49 JNGFF1.25 ; C265.2 213.56,32.11 MD74.7 ; JNGFF1.55 v5(196.75,35.7) ; JNFC1.1 v1(162.06,25.98) ; JNGFF1.61 v5(198.24,35.7)
  BOTTOM w0.356: v1(222.13,72.12) 222.05,72.2 JMDP1.8 ; JMDP1.14 v1(219.08,70.4)
  BOTTOM w0.381: UC1.3 v5(53.46,58.87) ; UD3.3 v5(45.34,50.45) ; v5(38.3,51.3) 37.83,51.76 U697.3 ; RH171.2 118.41,54.63 UH5.3 ; UD8.3 v5(53.7,50.44) ; UD3.4 v5(45.2,51.1) ; U663.8 v5(39.9,46) ; UD8.4 v5(53.67,51.09) ; MD82.7 213.74,56.87 213.32,57.29 v1(213.29,57.29)
  BOTTOM w0.406: U699.3 205.98,39.29 v1(206.12,39.15)
  BOTTOM w0.508: v1(179.85,30.61) 179.05,29.81 C1059.2 178.61,29.83 C1153.2 ; C656.2 v1(32.53,85.3) ; v1(151.78,25.37) 152.37,25.37 152.96,24.78 JNFC1.17 ; v1(64.7,50.76) 64.33,50.39 CC160.2 ; v1(28.09,51.47) 28.31,51.25 JBT1.3 ; C265.2 213.54,31.65 v5(213.85,31.34) ; CC233.2 74.21,53.78 v1(74.49,53.51) ; v5(106.24,68.81) 106.29,68.86 MC1276.2 ; v1(162.95,25.54) 162.95,24.51 163.66,23.8 JNFC1.16 ; v5(118.31,67.65) 118.76,68.11 RH186.1 ; v1(91.02,84.91) CH1230.2 ; R1228.2 v5(153.73,31.06) ; v1(179.48,51.45) 179.48,50.94 179.18,50.63 C722.2 ; v1(147.01,23.96) 147.79,24.75 JTP1.9 ; RH123.1 v5(96.43,84.62) ; v1(25.65,20.61) 25.78,20.49 C1123.2 ; RV4.2 216.19,73.05 v1(215.74,73.49) 216.12,73.88 RV9.2 ; CC234.2 67.56,53.99 v1(67.28,53.71) 67.18,53.81 CC161.2 ; v1(208.01,36.3) 208.01,35.79 207.39,35.17 PQ300.3 ; C1279.2 C1101.1 13.68,28.09 v1(13.74,28.15) ; C1125.2 26.29,25.01 26.26,25.03 v1(26.26,25.03) ; RH76.2 RH77.2 71.7,84.79 v1(72.16,85.24) ; R1034.1 161.82,72.86 v1(161.38,72.43) ; CD23.2 50.29,48.39 v1(50.12,48.55) ; v1(2.65,19.3) JFAN1.6 ; v10(37.09,58.56) v5(35.28,58.56) ; R974.2 v5(155.76,31.19) ; C1145.2 178.73,75.96 C1143.2 178.23,75.46 178.05,75.29 v1(178.05,74.76) ; PR301.2 v1(209.33,35.45) ; v1(185.62,72.39) 185.16,72.39 184.7,72.85 MC1210.2 ; RC44.1 52.9,85.13 51.94,84.16 v1(51.94,83.86) ; CH95.2 v5(32.11,50.29) ; v1(179.66,20.39) JDEBUG.13 182.22,20.39 182.54,20.07 v1(182.54,19.67) ; C1142.2 176.71,74.18 176.41,74.49 v1(176.41,74.96) ; JSATA1.29 174.57,54.82 174.33,55.07 174.33,55.37 174.58,55.62 JSATA1.27 177.7,55.62 v1(177.74,55.66) ; R1027.2 132.38,21.01 v1(131.81,20.43) ; v5(119.45,70.7) RH337.2 118.89,71.17 119.04,71.32 RH442.2 ; JDEBUG.10 v1(194.53,23.05) ; R1376.2 v5(151.95,75.68) ; JLVDS2.24 177.94,83.59 v1(178.2,83.32) ; JBATT1.10 v1(131.37,24.45) ; v1(7,24.57) 7.68,25.25 JFAN1.1 ; JDEBUG.8 v1(192.03,23.05) ; CH1236.2 v5(33.73,49.64) ; JSATA1.37 174.71,51.62 174.39,51.94 v1(174.26,51.94) 174.75,52.42 JSATA1.35 ; JBL1.5 176.75,25.78 176.37,25.4 175.69,25.4 v1(175.5,25.59) ; v1(142.83,26.5) 142.69,26.64 142.69,27.14 142.72,27.17 JTP1.4 ; v1(68.07,85.27) RC158.1 ; MC1273.2 v1(87.46,20.03) ; v1(212.86,53.91) 212.83,53.89 C1110.2 ; SW2.3 v1(107.56,19.83) ; JSATA1.18 166.61,59.22 166.06,59.78 v1(166.06,59.91) ; JSATA1.43 v5(177.17,49.22) ; JLVDS2.23 182.17,83.59 v1(181.9,83.31) ; JSATA1.15 174.45,63.62 v1(174.31,63.49) ; PC609.2 38.81,22.59 v1(38.68,22.72) ; JBT1.4 23.87,52.88 24.14,53.15 v1(24.52,53.15) ; MD50.2 v5(184.73,77.79) ; JLVDS1.24 157.6,84.69 v1(157.77,84.86) ; RH53.1 v5(52.73,61.72) ; JBL1.6 170.79,26.75 171.08,26.47 v1(171.08,25.92) ; C1134.2 v5(159.65,31.15) ; JSATA1.34 168.76,52.82 v5(168.92,52.67) ; PC405.2 112.39,85.24 111.73,85.9 v1(111.37,85.9) ; v1(167.05,81) 167.06,81 167.7,81.64 JLVDS1.21 ; C1099.1 C1146.1 10.54,27.17 v1(10.6,27.23) ; CD67.2 59.66,47.71 60.32,48.37 v7(60.32,49.21) v1(60.32,50.3) ; CC163.2 71.55,53.02 v1(71.55,53.86) 71.42,53.99 CC238.2 ; v1(77.46,54.2) 77.44,54.18 CC239.2 77.92,52.69 CC164.2 ; JLVDS1.22 v5(154.35,83.69) ; RH394.2 95.86,51.3 95.83,51.27 v1(95.83,51.32) ; PU306.1 183.73,27.8 v1(183.7,27.77) ; JSATA1.54 v5(175.15,44.54) ; R1100.1 v5(154.74,31.06) ; MC103.2 v5(89.59,50.55) ; JSATA1.50 v5(166.07,46.42) ; RC100.2 52.71,80.53 52.55,80.68 v1(52.05,80.68) ; R1139.2 180.35,76.95 v1(180.35,77.58) ; JIOL1.38 v1(10.45,22.35) ; PC107.2 v5(120.38,40.04) ; v1(180.4,35) 180.14,35.25 JNGFF1.68 ; JFAN1.5 4.52,27.44 v1(6.2,27.44) ; RC52.2 v1(60.29,85.74) ; v1(116,26.33) 116.03,26.33 116.03,26.33 115.98,26.33 115.98,26.33 JBATT1.11 ; RD9.1 53.82,48.12 v1(54.27,48.58) ; JSATA1.40 v5(166.19,50.42) ; v1(172.83,84.63) 173.34,84.11 JLVDS2.22 ; v1(61.17,85.74) 61.18,85.74 RC54.2 ; JBT1.2 v5(26.42,52.91) ; R1142.2 v5(157.79,31.24) ; v5(117.7,54.95) 117.7,54.72 118.03,54.39 RH171.2 ; JSATA1.4 v5(166.33,68.03) ; RC153.2 RC81.2 52.22,68.54 v1(51.71,68.03) ; DE2.1 149.83,33.39 v1(150.01,33.57) ; PC616.2 42.51,21.35 v5(42.92,21.35) ; JSATA1.26 168.63,56.02 v1(168.97,55.69) ; v1(183.92,71.46) 183.78,71.6 MC1133.2 ; SW2.4 v1(98,19.83) ; v5(99.35,84.7) RH158.1 RH300.1 ; C1289.2 v5(203,38.49) ; RH183.1 v5(120.58,53.48) ; U48.4 109.74,56.17 v1(109.56,56.35) ; v1(95.72,49.74) 95.71,49.74 95.71,49.74 95.65,49.8 RH151.1 RH34.1 ; CH6.2 v5(114.29,61.86) ; v5(28.14,82.69) PR714.1 PC721.2 ; PC407.2 v5(109.72,78.99) ; R1325.1 v5(37.83,55.19) ; MC1277.2 v5(116.97,74.24) ; v7(186.46,32.91) v1(187.24,32.91) ; RH314.1 v5(112.63,65.72) ; v1(187.8,83.38) 187.64,83.22 JLVDS2.21 ; JSATA1.9 v5(173.81,66.03) ; PC106.2 131.33,41.35 PC105.2 131.41,41.44 v1(132.4,41.44) ; PC723.2 27.6,67.31 v1(27.63,67.28) ; RC155.2 93.57,84.24 v5(93.42,84.09) ; JDCIN1.6 197.81,75.97 v1(197.97,76.14) ; v1(153.99,34.89) 153.41,34.89 MC1275.2 ; R1169.2 v5(110.92,71.56) ; CH1231.2 86.96,84.84 v1(87.04,84.84) ; RD3.1 v5(44.44,48.43) ; v1(58.54,85.76) 58.54,85.54 CH1241.2 ; RH443.2 v5(118.05,74.84) ; v3(135.87,27.62) 135.87,26.38 135.72,26.23 JTP1.10 ; PC108.2 v5(119.76,38.44) ; C1124.2 24.85,22.3 JIOL1.37 24.8,22.35 v1(24.8,23.84) ; C1282.2 23.08,47.92 v5(23.51,47.49) ; v1(177.18,58) 177.18,58.03 JSATA1.21 ; CC240.2 v1(48,61.21) ; RC161.2 v5(48.1,57.22) ; v1(165.4,82.13) JLVDS1.23 ; RD4.1 v5(45.44,48.45)
  vias: v1(0.77,27.5) v1(0.77,25.97) v1(0.77,24.45) v1(0.77,22.92) v1(0.77,21.4) v1(0.77,19.88) v1(1.05,18.33) v1(1.84,28.73) v1(2.72,18.33) v1(3.26,29.6) v1(4.58,30.52) v1(5.85,31.51) v1(6.15,18.33) v1(7.68,18.33) v1(9.2,18.33) v1(10.45,36.31) v1(10.73,18.33) v1(11.36,37.6) v1(12.2,38.93) v1(12.25,18.33) v1(12.96,40.27) v1(13.65,41.67) v1(13.99,18.33) v1(14.36,43.32) v1(14.94,45.05) v1(15.3,18.33) v1(15.46,46.9) v1(15.78,48.32) v1(16.06,49.87) v1(16.31,51.4) v1(16.59,52.9) v1(16.85,54.44) v1(16.82,18.33) v1(17.15,56.12) v1(17.53,58.25) v1(17.81,59.83) v1(18.09,61.4) v1(18.35,62.93) v1(18.35,18.33) v1(18.63,64.43) v1(18.9,66.08) v1(19.18,67.58) v1(19.44,69.1) v1(19.49,40.87) v1(19.48,39.28) v1(19.72,70.62) v1(19.87,18.33) v1(20,72.22) v1(20.28,73.85) v1(20.56,75.37) v1(20.84,76.97) v1(21.11,78.55) v1(21.32,88.15) v1(21.29,85.18) v1(21.27,83.48) v1(21.27,81.78) v1(21.27,80.23) v1(21.39,18.33) v1(21.58,41.08) v1(21.9,23.19) v1(22.27,37.71) v1(22.92,18.33) v1(23.43,40.91) v1(24.25,72.63) v1(24.33,42.38) v1(24.44,18.33) v1(24.54,71.92) v1(24.65,87.11) v1(25.66,73.55) v1(25.66,72.83) v1(25.66,72.12) v1(25.9,42.43) v1(25.98,41.69) v1(25.97,18.33) v1(26.07,86.58) v1(26.42,73.55) v1(26.42,72.83) v1(26.42,72.12) v1(27.19,73.55) v1(27.19,72.83) v1(27.19,72.12) v1(27.37,80.67) v1(27.38,78.77) v1(27.49,18.33) v1(27.67,86.58) v1(27.95,73.55) v1(27.95,72.83) v1(27.95,72.12) v1(28.07,37.53) v1(28.32,79.72) v1(28.71,73.55) v1(28.71,72.83) v1(28.71,72.12) v1(29.01,18.33) v1(29.19,86.58) v1(29.28,78.77) v1(29.89,71.17) v1(30.02,35.7) v1(30.54,18.33) v1(30.92,86.58) v1(32.06,18.33) v1(32.47,86.31) v1(32.82,39.16) v1(32.99,42.25) v1(33.09,22.09) v1(33.05,21.45) v1(33.17,41.03) v1(33.42,72.5) v1(33.46,85.36) v1(33.59,18.33) v1(33.75,22.11) v1(34.16,35.88) v1(34.44,45.76) v1(34.49,39.72) v1(34.7,84.29) v1(34.87,73.6) v1(34.87,72.89) v1(34.87,72.21) v1(35.11,18.33) v1(35.16,69.56) v1(35.63,73.6) v1(35.63,72.89) v1(35.63,72.21) v1(36.18,83.65) v1(36.39,73.6) v1(36.39,72.9) v1(36.39,72.21) v1(36.63,18.33) v1(37.15,73.6) v1(37.15,72.89) v1(37.15,72.21) v1(37.92,73.6) v1(37.92,72.89) v1(37.92,72.21) v1(38.04,83.5) v1(38.16,18.33) v1(39.71,83.96) v1(39.68,18.33) v1(39.84,36.87) v1(39.85,20.76) v1(39.86,21.42) v1(40.57,21.42) v1(40.58,20.76) v1(41.1,84.9) v1(41.21,18.33) v1(41.29,39.89) v1(42.31,86.18) v1(42.73,18.33) v1(43.78,24.98) v1(43.87,86.58) v1(44.3,70.07) v1(44.3,67.02) v1(44.3,63.97) v1(44.25,18.33) v1(45.45,42.08) v1(45.52,86.58) v1(45.78,18.33) v1(46.23,41.03) v1(46.21,39.03) v1(46.58,70.07) v1(46.58,67.02) v1(46.58,63.97) v1(47.05,86.58) v1(47.05,37.78) v1(47.24,18.33) v1(48.09,40.84) v1(48.57,86.58) v1(48.83,18.33) v1(48.87,70.07) v1(48.87,67.02) v1(48.87,63.97) v1(50.1,86.58) v1(50.35,18.33) v1(51.13,70.19) v1(51.12,66.51) v1(51.15,64.09) v1(51.62,86.58) v1(51.87,18.33) v1(52.07,37.7) v1(53.14,86.58) v1(53.4,18.33) v1(54.67,86.58) v1(54.81,61.51) v1(55.11,59.04) v1(55.2,18.25) v1(56.19,86.58) v1(56.15,59.88) v1(56.34,17.21) v1(57.02,41.9) v1(57.72,86.58) v1(57.83,38.96) v1(57.89,41.02) v1(58.8,35.88) v1(59.24,86.58) v1(59.61,40.92) v1(60.76,86.58) v1(61.14,17.89) v1(61.73,54.76) v1(62.29,86.58) v1(62.38,78.4) v1(62.39,18.33) v1(63.49,53.95) v1(63.81,86.58) v1(63.91,18.33) v1(64.51,54.36) v1(64.87,78.38) v1(65.34,86.58) v1(65.35,20.03) v1(65.37,19.39) v1(65.44,18.33) v1(66.11,20.03) v1(66.11,19.39) v1(66.86,86.58) v1(66.96,18.33) v1(67.41,78.36) v1(68.38,86.58) v1(68.49,18.33) v1(69.36,41.03) v1(69.91,86.58) v1(70.01,18.33) v1(70.06,46.62) v1(70.26,78.31) v1(70.33,36.11) v1(70.72,46.62) v1(71.43,86.58) v1(71.47,54.65) v1(71.53,18.33) v1(72.7,78.32) v1(72.96,86.58) v1(73.06,18.33) v1(73.69,46.65) v1(74.58,18.33) v1(74.67,56.38) v1(75.13,78.33) v1(75.46,46.65) v1(76.11,18.33) v1(76.91,20.15) v1(76.91,19.52) v1(77.63,18.33) v1(77.73,78.33) v1(77.67,20.15) v1(77.67,19.52) v1(78.4,54.8) v1(79.15,18.33) v1(79.92,78.38) v1(80.31,53.29) v1(80.54,36.77) v1(80.68,18.33) v1(80.94,39.13) v1(81.68,37.76) v1(81.77,86.58) v1(82.2,18.33) v1(82.6,80.94) v1(82.82,53.52) v1(83.29,86.58) v1(83.73,18.33) v1(83.87,54.57) v1(84.82,86.58) v1(85.25,18.33) v1(86.11,37.03) v1(86.34,86.58) v1(86.79,54.67) v1(86.77,18.33) v1(87.87,86.58) v1(88.3,18.33) v1(89.04,39.27) v1(89.39,86.58) v1(89.82,18.33) v1(90.91,86.58) v1(91.35,18.33) v1(91.8,25.02) v1(92.44,86.58) v1(92.87,18.33) v1(93.62,41.08) v1(93.96,86.58) v1(94.39,18.33) v1(94.87,37.76) v1(95.49,86.58) v1(95.92,18.33) v1(97.01,86.58) v1(97.44,18.33) v1(98.53,86.58) v1(98.97,18.33) v1(100.06,86.58) v1(100.11,38.6) v1(100.49,18.33) v1(101.58,86.58) v1(102.01,18.33) v1(102.55,49.49) v1(102.57,50.46) v1(103.11,86.58) v1(103.54,18.33) v1(104.23,36.86) v1(104.63,86.58) v1(105.06,18.33) v1(105.56,41.06) v1(106.15,86.58) v1(106.51,35.86) v1(106.59,18.33) v1(107.68,86.58) v1(108.11,18.33) v1(109.2,86.58) v1(109.63,18.33) v1(110.73,86.58) v1(111.16,18.33) v1(112.52,64.96) v1(112.69,86.14) v1(112.68,18.33) v1(114.21,23.69) v1(114.21,22.92) v1(114.21,18.33) v1(114.36,84.52) v1(114.85,23.71) v1(114.85,22.95) v1(115.49,23.71) v1(115.5,22.95) v1(115.5,22.19) v1(115.73,83.78) v1(115.73,18.33) v1(116.15,23.71) v1(116.15,22.95) v1(116.15,22.19) v1(117.23,83.48) v1(117.25,18.33) v1(117.61,23.71) v1(117.61,22.95) v1(117.61,22.19) v1(118.78,83.63) v1(118.78,18.33) v1(119.11,23.69) v1(119.11,22.92) v1(120.28,84.26) v1(120.3,18.33) v1(121.52,85.33) v1(121.83,18.33) v1(122.73,86.41) v1(123.35,18.33) v1(124.16,86.58) v1(124.87,18.33) v1(125.69,86.58) v1(126.4,18.33) v1(127.21,86.58) v1(127.92,18.33) v1(128.73,86.58) v1(129.45,18.33) v1(130.26,86.58) v1(130.97,18.33) v1(132.02,86.7) v1(132.49,18.33) v1(133.24,87.69) v1(133.2,19.75) v1(134.58,20.33) v1(135.17,87.77) v1(136.1,20.33) v1(136.21,84.7) v1(136.44,86.22) v1(136.6,83.27) v1(137.38,87.77) v1(137.62,20.33) v1(137.69,42.53) v1(138.25,82.56) v1(138.34,42.53) v1(138.82,87.44) v1(138.98,42.53) v1(139.15,20.33) v1(139.66,42.53) v1(140.51,82.56) v1(140.67,20.33) v1(142.2,20.33) v1(142.56,83.53) v1(142.78,85.33) v1(142.89,86.55) v1(143.4,26.2) v1(143.72,20.33) v1(145.03,26.2) v1(145.24,20.33) v1(146.77,20.33) v1(148.29,20.33) v1(149.82,20.33) v1(151.34,20.33) v1(151.77,86.58) v1(152.57,57.95) v1(152.86,20.33) v1(153.3,86.58) v1(153.99,34.12) v1(154.39,20.33) v1(154.74,34.89) v1(154.74,34.12) v1(154.82,86.58) v1(155.51,34.89) v1(155.51,34.12) v1(155.91,20.33) v1(156.14,35.52) v1(156.15,34.76) v1(156.34,86.58) v1(157.44,20.33) v1(157.87,86.58) v1(158.16,56.11) v1(158.73,46.11) v1(158.96,20.33) v1(159.39,86.58) v1(159.54,46.11) v1(159.95,72.47) v1(160.48,20.33) v1(160.57,46.11) v1(160.92,86.58) v1(161.35,46.11) v1(161.81,71.92) v1(162.01,20.33) v1(162.44,86.58) v1(163.53,20.33) v1(163.61,36.26) v1(163.61,35.62) v1(163.96,86.58) v1(164.01,71.97) v1(164.24,35.62) v1(164.27,36.26) v1(165.06,20.33) v1(165.49,86.58) v1(166.58,20.33) v1(167.06,86.58) v1(168.1,20.33) v1(168.84,87.11) v1(169.63,20.33) v1(170.63,80.99) v1(171.15,20.33) v1(171.97,88.25) v1(172.55,20.33) v1(173.18,87.06) v1(173.49,85.38) v1(174.1,20.33) v1(174.86,84.67) v1(175.62,20.33) v1(176.38,84.67) v1(177.25,20.33) v1(177.91,84.67) v1(178.7,19.85) v1(179.31,18.43) v1(179.43,84.67) v1(179.36,55.77) v1(179.38,54.75) v1(180.78,18.33) v1(180.96,84.67) v1(180.98,49.03) v1(181.29,62.06) v1(181.29,59.65) v1(181.29,56.6) v1(181.29,54.95) v1(182.3,18.33) v1(182.48,84.67) v1(182.62,25.84) v1(182.68,54.95) v1(182.81,62.06) v1(182.81,58.64) v1(182.81,57.11) v1(183.83,18.33) v1(184,84.67) v1(184.59,57.75) v1(184.59,55.33) v1(184.55,25.87) v1(184.92,42.84) v1(184.86,42.1) v1(185.35,18.33) v1(185.53,84.67) v1(186.35,78.85) v1(186.35,78.18) v1(186.87,18.33) v1(187.05,84.67) v1(187.43,78.78) v1(187.42,78.12) v1(188.09,78.78) v1(188.13,78.12) v1(188.4,18.33) v1(188.58,84.67) v1(189.16,63.72) v1(189.16,61.56) v1(189.16,59.14) v1(189.16,57.24) v1(189.55,50.97) v1(189.57,49.7) v1(189.92,18.33) v1(190.18,22.97) v1(190.25,84.67) v1(191.45,18.33) v1(191.55,85.46) v1(191.7,49.36) v1(191.83,59.14) v1(191.83,57.24) v1(191.95,61.56) v1(192.97,85.56) v1(192.97,18.33) v1(194.14,85.56) v1(194.49,18.33) v1(194.76,61.58) v1(194.88,57.11) v1(194.88,54.83) v1(196.02,18.33) v1(197.21,84.01) v1(197.16,50.76) v1(197.25,47.54) v1(197.54,18.33) v1(197.59,82.49) v1(198.05,61.56) v1(198.94,67.53) v1(198.94,64.6) v1(199.09,81.78) v1(199.07,59.27) v1(199.07,57.11) v1(199.07,54.83) v1(199.07,18.33) v1(199.97,75.01) v1(199.97,73.72) v1(199.97,67.22) v1(199.98,63.72) v1(200.57,64) v1(200.59,18.33) v1(200.73,20.1) v1(200.73,19.39) v1(200.77,81.78) v1(200.78,67.25) v1(201.12,63.69) v1(201.53,67.27) v1(201.78,63.69) v1(202.11,18.33) v1(202.34,81.78) v1(202.72,80.23) v1(203.28,78.75) v1(203.64,18.33) v1(205.16,18.33) v1(206.42,75.07) v1(206.69,18.33) v1(206.86,78.28) v1(208.21,18.33) v1(209.73,18.33) v1(210.14,78.27) v1(210.19,66.51) v1(210.83,66.48) v1(211.26,18.33) v1(211.89,76.49) v1(211.88,75.35) v1(212.02,48.6) v1(212.02,47.97) v1(212.27,78.27) v1(212.78,18.33) v1(213.02,35.42) v1(213.38,66.41) v1(213.35,58.41) v1(213.67,54.74) v1(213.71,42.28) v1(214.04,68.38) v1(214.31,18.33) v1(214.38,35.37) v1(214.74,58.71) v1(215.74,31.79) v1(215.78,68.35) v1(215.79,67.55) v1(215.83,18.33) v1(216.14,39.69) v1(217.35,18.33) v1(217.91,56.26) v1(218.56,71.82) v1(218.8,68.85) v1(218.88,18.33) v1(219.91,28.41) v1(219.91,27.65) v1(220.38,44.46) v1(220.35,40.91) v1(220.35,39.38) v1(220.35,37.86) v1(220.35,36.33) v1(220.35,34.81) v1(220.35,33.29) v1(220.35,31.76) v1(220.38,29.73) v1(220.42,18.31) v1(220.99,60.97) v1(220.99,56.6) v1(220.99,54.65) v1(220.97,50.48) v1(221.04,48.37) v1(221.19,78.27) v1(221.44,45.4) v1(221.6,63.49) v1(221.62,28.77) v1(221.77,18.1) v1(222.43,47.54) v1(222.71,78.27) v1(222.99,44.92) v1(222.99,29.27) v1(223.3,63.18) v1(223.88,48.02) v1(224.24,78.27) v1(224.29,75.48) v1(224.34,66.97) v1(224.26,12.71) v1(224.26,11.19) v1(224.26,9.66) v1(224.26,8.14) v1(224.26,6.62) v1(224.26,5.09) v1(224.26,3.57) v1(224.52,44.92) v1(224.52,29.27) v1(224.77,73.95) v1(224.77,72.61) v1(224.77,69.99) v1(224.77,68.47) v1(225,63.18) v1(225.28,48.02) v1(225.51,76.52) v1(225.56,66.08) v1(225.58,3.26) v1(225.76,78.27) v1(226.04,44.92) v1(226.04,29.27) v1(226.7,63.18) v1(226.7,48.02) v1(227.21,3.26) v1(227.29,78.27) v1(227.82,76.52) v1(227.79,66.08) v1(228.61,3.16) v1(228.81,78.27) v1(229.24,66.08) v1(229.29,76.52) v1(229.52,29.27) v1(229.72,44.92) v1(229.7,2.02) v1(229.78,48.02) v1(230.23,46.52) v1(230.49,78.27) v1(230.56,0.77) v1(230.72,66.08) v1(230.69,63.18) v1(230.84,11.01) v1(230.94,76.67) v1(230.97,64.5) v1(231.07,29.27) v1(231.43,27.93) v1(231.43,26.53) v1(231.4,18.5) v1(231.52,2.02) v1(231.93,20.08) v1(232.13,24) v1(232.1,22.69) v1(232.44,16.98) v1(232.39,15.84) v1(232.39,13.27) v1(232.39,12.23) v1(232.42,9.66) v1(232.42,8.62) v1(232.39,2.48) v1(232.39,0.77) v1(232.72,5.55) v3(65.91,80.96) v3(66.36,80.31) v3(69.06,81.38) v3(70.1,81.22) v3(74.01,84.8) v3(106.6,52.03) v3(107.44,52.01) v3(108.17,52.03) v3(192.74,39.28) v3(215.42,42.99) v4(15.72,28.69) v4(22.23,26.02) v4(37.03,27.15) v4(37.38,25.21) v4(39.55,27.11) v4(40.69,55) v4(41.07,29.67) v4(41.25,26.27) v4(43.29,27.95) v4(51.84,19.77) v4(51.81,19.19) v4(52.32,19.19) v4(52.37,19.77) v4(52.83,19.19) v4(52.88,19.75) v4(53.84,19.19) v4(54.68,19.19) v4(64.95,26.66) v4(72.59,25.39) v4(76.18,79.69) v4(88.86,79.01) v4(93.2,75.3) v4(95.19,57.8) v4(98.46,59.3) v4(116.15,70.24) v4(116.59,35.8) v4(116.69,36.59) v4(123.13,45.94) v4(123.13,43.01) v4(123.26,48.09) v4(123.52,49.73) v4(125.29,43.01) v4(125.42,45.94) v4(126.04,49.49) v4(126.51,48.76) v4(134.53,48.3) v4(134.87,46.85) v4(139.14,59.93) v4(141.48,59.15) v4(158.87,61.56) v4(169.4,52.34) v4(170.25,46.01) v4(173.68,51.4) v4(183.4,77.94) v4(183.6,74.87) v4(184.03,77.91) v4(186.84,72.76) v4(211.98,73.6) v4(213.86,73.32) v5(29.04,20.97) v5(29.39,20.97) v5(29.73,20.97) v5(30.08,20.97) v5(30.3,79.22) v5(30.44,20.97) v5(31.31,79.22) v5(44.01,20.55) v5(113.23,70.27) v5(115.48,80.84) v5(115.48,79.95) v5(115.86,80.4) v5(116.24,80.84) v5(116.24,79.95) v5(118.94,77.69) v5(119.32,77.69) v5(119.64,81.31) v5(119.7,77.69) v5(120.09,77.69) v5(120.47,77.69) v5(120.78,77.71) v5(123.26,85) v5(123.93,85) v5(124.1,76.85) v5(124.1,76.23) v5(125.09,85) v5(125.72,85) v5(129.89,77.84) v5(129.92,77.2) v5(134.25,75.26) v5(135.5,73.24) v5(138.04,79.77) v5(138.07,78.55) v5(138.07,77.36) v5(138.74,78.54) v5(139.44,78.55) v5(139.47,79.77) v5(139.47,77.36) v5(139.87,76.24) v5(140.13,74.74) v5(140.51,76.62) v5(141.97,81.78) v5(142.86,81.78) v5(143.42,76.01) v5(144.14,76.9) v5(144.23,82.28) v5(144.61,82.28) v5(144.69,77.94) v5(145.57,82.26) v5(146.31,82.26) v5(149.8,40.47) v5(150.31,40.47) v5(150.82,40.47) v5(151.2,40.47) v5(151.71,40.47) v5(152.22,40.47) v5(152.72,40.47) v5(155.36,74.26) v5(165.54,34.9) v5(165.59,31.85) v5(165.58,31.45) v5(165.98,31.85) v5(165.97,31.45) v5(166.06,34.89) v5(166.57,34.89) v5(167.08,34.89) v5(171.56,33.82) v5(171.56,32.93) v5(172.02,33.36) v5(172.45,33.82) v5(172.45,32.93) v5(174.07,77.51) v5(175.15,72.07) v5(175.19,34.58) v5(176.13,32.22) v5(178.09,42.8) v5(191.15,26.48) v5(192.84,26.49) v5(193.34,26.5) v5(194.85,26.49) v5(195.35,26.5) v5(200.84,37.5) v5(202.37,55.59) v5(203.92,26.95) v5(204.81,26.97) v5(205.16,72.12) v5(205.53,48.48) v5(205.53,47.51) v5(205.51,46.6) v5(205.51,45.63) v5(205.68,26.91) v5(205.84,31.18) v5(206.15,68.48) v5(206.16,67.57) v5(206.65,26.91) v5(206.65,68.02) v5(206.94,72.12) v5(207.13,67.53) v5(207.16,68.48) v6(51.37,20.03) v6(51.37,19.67) v6(51.37,19.32) v6(51.37,18.96) v6(53.27,19.16) v6(81.26,68.71) v6(81.74,68.71) v6(90.43,83.31) v6(95.19,83.54) v6(109.63,76.92) v6(110.6,76.92) v6(118.02,36.22) v6(125.29,61.28) v6(139.85,76.07) v6(141.79,81.83) v6(142.87,72.14) v6(143.95,66.7) v6(148.55,44.13) v6(148.54,31.41) v6(148.62,42.89) v6(148.91,79.5) v6(149.21,43.45) v6(149.46,31.41) v6(149.94,44.18) v6(149.94,42.89) v6(150.37,31.41) v6(151.29,31.41) v6(152.2,31.41) v6(153.12,31.43) v6(154.03,31.43) v6(154.94,31.43) v6(155.86,31.43) v6(156.06,74.49) v6(156.77,31.43) v6(157.16,73.74) v6(157.69,31.43) v6(157.82,46.34) v6(157.84,45.96) v6(158.16,79.77) v6(158.6,31.43) v6(159.3,74.18) v6(159.52,31.43) v6(160.43,31.43) v6(161.35,31.43) v6(162.26,31.43) v6(163.17,31.43) v6(163.38,37.02) v6(164.09,31.43) v6(164.5,66.48) v6(165,31.43) v6(165.49,40.94) v6(165.92,31.43) v6(166.83,31.43) v6(167.75,31.43) v6(168.66,31.43) v6(169.15,75.68) v6(169.57,31.46) v6(170.51,66.75) v6(170.49,31.46) v6(172.77,73.96) v6(173.44,38.15) v6(174.31,38.14) v6(174.72,74.49) v6(174.7,40.5) v6(178.21,70.55) v6(197.95,51.04) v6(197.95,50.38) v6(197.95,49.29) v6(197.95,48.53) v6(200.92,54.47) v6(202.38,50.82) v6(202.35,50.02) v6(202.75,50.44) v6(202.93,54.5) v6(203.15,50.82) v6(203.16,50.03) v6(203.92,32.91) v6(203.92,32.02) v6(204.27,25.68) v6(204.36,38.09) v6(204.36,37.02) v6(204.38,32.46) v6(204.69,63.46) v6(204.69,62.57) v6(204.81,32.91) v6(204.81,32.02) v6(205.04,25.67) v6(205.15,63.04) v6(205.19,36.26) v6(205.19,35.19) v6(205.58,63.46) v6(205.58,62.57) v6(206.18,25.64) v6(206.31,42.27) v6(206.31,41.34) v6(206.28,36.35) v6(206.61,68.54) v6(206.61,68.03) v6(206.61,66.78) v6(206.61,66.21) v6(206.71,41.85) v6(206.94,25.64) v6(207.25,42.27) v6(207.24,41.32) v6(207.46,30.54) v6(209.52,27.93) v6(209.52,27.04) v6(209.96,27.5) v6(210.41,27.93) v6(210.41,27.04) v6(212.47,31.39) v6(216.24,29.65) v7(23.27,70.99) v7(29.23,67.92) v7(34.17,73.15) v7(66.15,78.63) v7(77.86,21.22) v9(23.81,74.43) v9(25.66,74.65) v9(26.63,74.65) v9(28.51,74.43) v9(30.41,74.43) v9(31.3,74.43) v9(111.29,52.55) v9(111.3,51.61) v9(111.78,52.07) v9(112.22,52.55) v9(112.22,51.59) v9(123.13,46.53) v9(123.16,42.02) v9(125.36,44.29) v9(127.52,42.18) v9(127.57,46.53) v9(134.83,68.17) v10(37.08,58.03) v10(37.69,58.53) v10(37.71,58) v10(39.09,69.48)
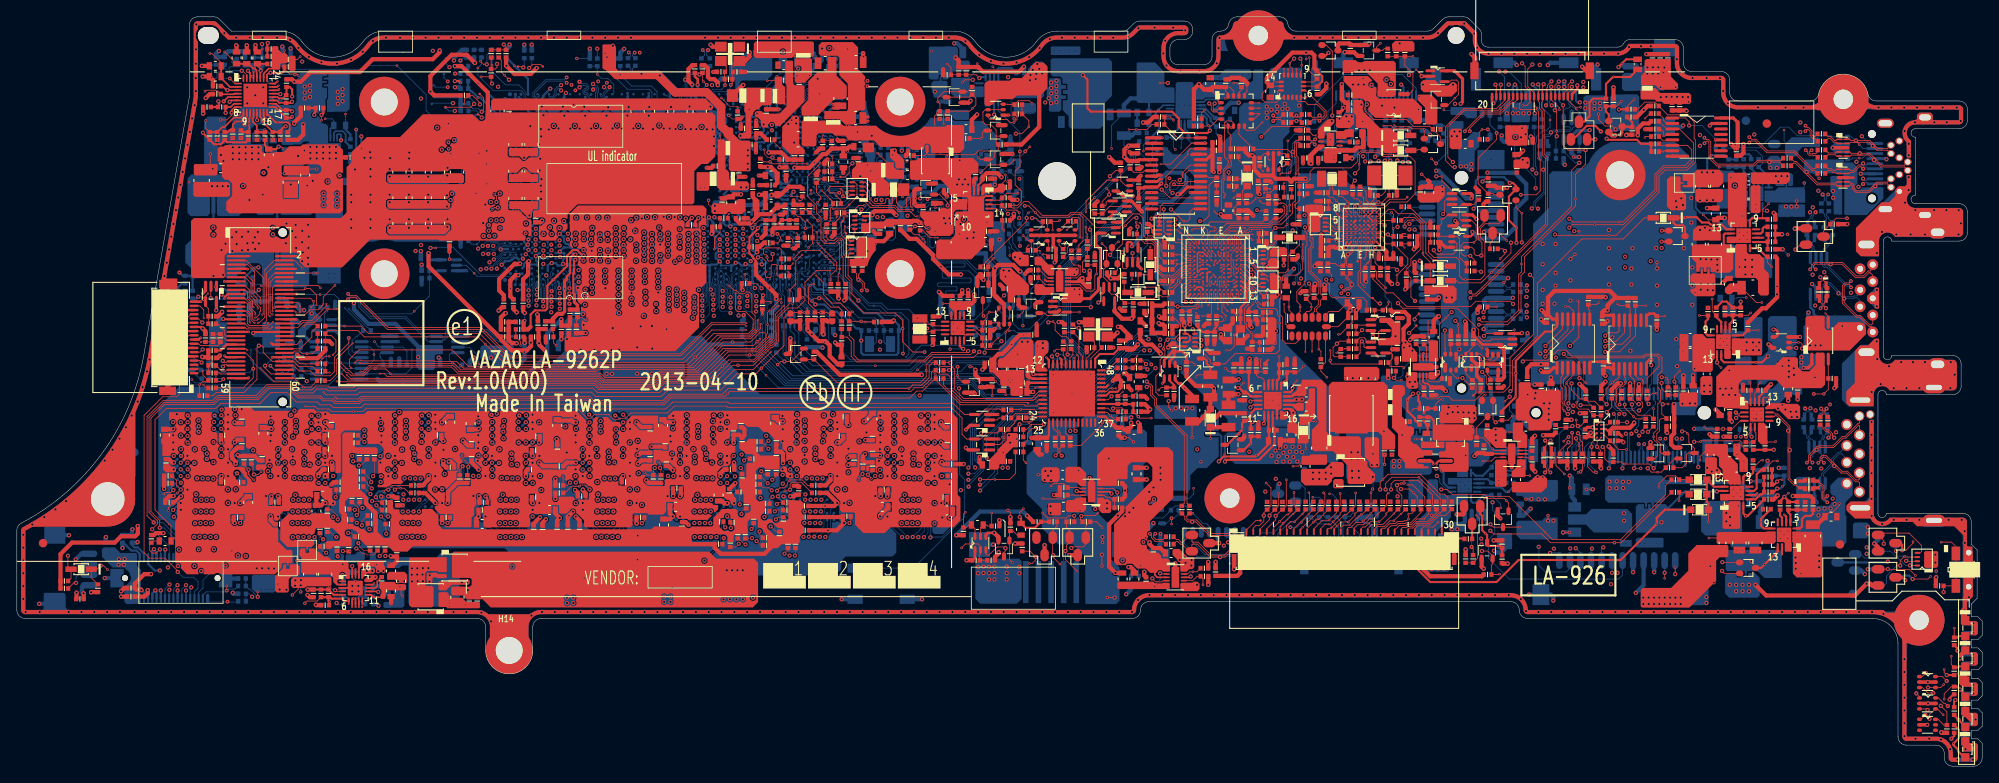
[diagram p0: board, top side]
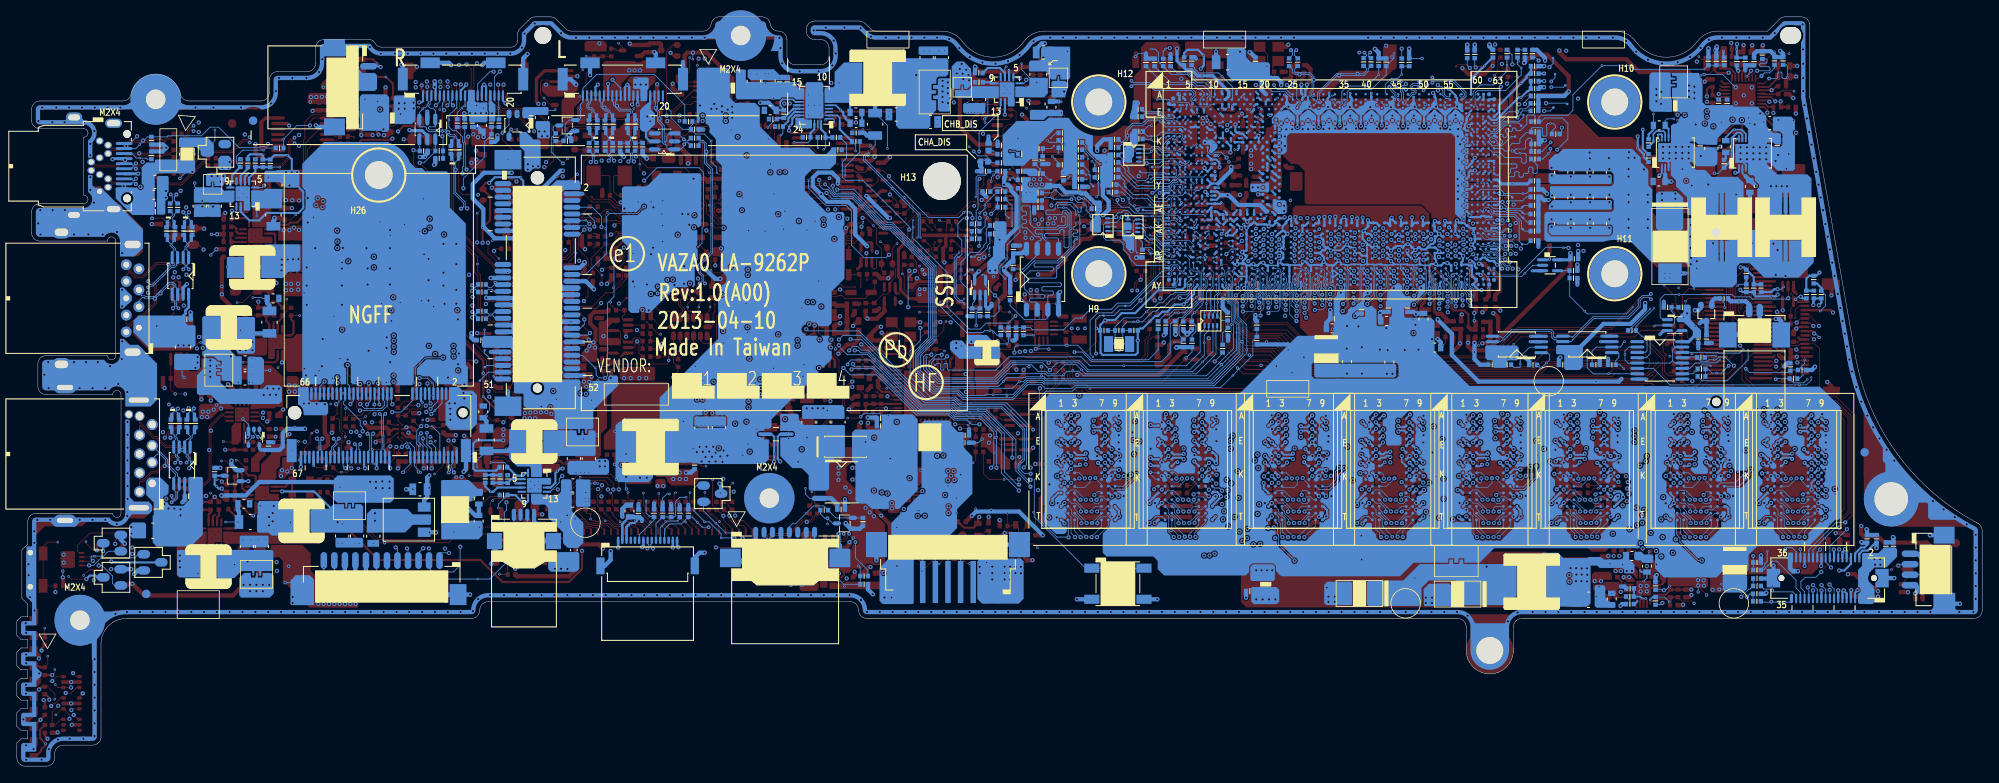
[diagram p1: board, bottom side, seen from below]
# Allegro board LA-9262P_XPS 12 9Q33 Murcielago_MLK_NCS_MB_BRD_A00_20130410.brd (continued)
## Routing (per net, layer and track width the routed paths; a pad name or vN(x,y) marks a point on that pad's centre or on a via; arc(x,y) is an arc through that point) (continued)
VCC: length 11.2
  TOP w0.102: v2(152.1,45.82) 151.56,45.28 v1(151.56,44.95)
  TOP w0.254: v1(151.56,44.95) 151.56,44.7 151.3,44.45 PU201.20
  TOP w0.508: v1(145.13,44.2) PC214.1 PR210.2
  IN4 w0.254: v1(145.13,44.2) 145.88,44.95 v1(151.56,44.95)
VCCSENSE: length 24.2
  TOP w0.203: PU701.24 30.69,81.12 30.94,81.37 v6(30.98,81.37)
  GND1 w0.254: v6(30.98,81.37) 30.73,81.37 v4(30.5,81.14)
  IN1 w0.254: v8(52.07,82.3) 52.01,82.36 45.52,82.36 45.33,82.55 42.09,82.55 41.9,82.36 31.72,82.36 v4(30.5,81.14)
  BOTTOM w0.254: v8(52.07,82.3) RC98.1
VCCSENSE_R: length 8
  BOTTOM w0.254: UCPU1.E63 57.94,77.21 57.41,77.74 57.41,78.52 v2(54.81,81.13) 54.13,81.8 54.13,82.03 53.86,82.3 RC98.2 RC97.2
VCCSTPG_MCP: length 7.7
  BOTTOM w0.076: 60.08,80.51 60.4,80.2 60.4,79.55 60.72,79.22 UCPU1.B59
  BOTTOM w0.102: RC150.2 v2(56.46,83.3) 56.46,82.56 58.06,80.96 59.63,80.96 60.08,80.51
VDD_+1.2V: length 3.1
  TOP w0.102: v2(45.85,20.18) 45.66,20.38 PR606.2
  TOP w0.203: 43.61,20.08 42.36,20.08 42.07,20.37 PU601.11
VIN: length 84.9
  TOP w0.102: v7(139.63,39.05) PR122.1
  TOP w0.508: PR122.1 140.46,40.97 141.8,42.32 PD201.2 PR209.1 142.22,44.26 v1(142.22,44.89) 141.93,45.19 140.06,45.19 138.97,46.28 PR120.2 ; PR208.1 146.45,47.87 146.45,48.41 v1(146.46,48.43) ; v1(116.64,25.43) 116.64,25.29 116.21,24.85 PR123.2
  IN2 w0.762: 169.74,43.27 168.46,44.55 168.46,45.97 166.23,48.2 153.6,48.2 153.45,48.35 149.41,48.35 148.37,47.31 146.79,47.31
  IN4 w0.508: v1(142.22,44.89) 142.22,43.74 140.08,41.59 133.78,41.59 133.24,42.13 131.74,42.13 131.39,41.77 128.9,41.77 128.37,42.3 122.7,42.3 121.53,41.14 119.93,41.14 119.79,41.27 118.41,41.27 115.92,38.79 115.92,33.97 117.37,32.52 117.37,27.39 116.78,26.81 116.78,25.57 v1(116.64,25.43)
  vias: v1(169.98,41.87) v1(170.11,42.63) v1(170.59,42.08) v1(171.23,42.05) v1(171.86,42.05) v1(171.91,41.34) v1(172.5,42.02) v1(172.55,41.34) v1(173.13,41.97) v1(173.18,41.34) v1(195.32,79.5) v1(195.98,79.54) v1(196.62,79.54) v1(197.25,79.54) v1(197.92,79.53) v1(198.56,79.51) v7(171.18,42.74) v7(198.64,78.93)
VSSSENSE: length 23.9
  TOP w0.203: PU701.23 30.89,80.72 31.05,80.87 v6(31.1,80.87)
  TOP w0.254: v1(52.05,81.42) 52.49,81.42 v2(52.71,81.19)
  GND1 w0.254: v6(31.1,80.87) 31.45,80.87 v4(31.47,80.89)
  IN1 w0.254: v4(31.47,80.89) 32.43,81.85 42.15,81.85 42.34,82.04 45.09,82.04 45.28,81.85 51.61,81.85 v1(52.05,81.42)
  BOTTOM w0.254: v1(52.05,81.42) RC99.2
VSSSENSE_R: length 7.6
  BOTTOM w0.254: UCPU1.E62 58.27,76.8 57.73,76.8 55.06,79.46 v2(54.79,79.46) 54.05,80.21 53.93,80.21 RC100.1 RC99.1
1.2_PGND: length 7.6
  TOP w0.254: v6(122.31,48.58) 122.61,48.27 UA1.12
  TOP w0.508: RA12.2 115.91,48.26 116.63,48.98 117.08,48.98 v2(118.19,50.1) 118.19,50.28 119.15,51.23 v6(119.6,51.23) 119.62,51.24 RA13.2
  GND1 w0.254: v4(121.88,49.03) 122.31,48.6 v6(122.31,48.58)
  vias: v6(115.87,47.16) v6(117.83,45.9) v6(118.05,45.61) v6(118.28,45.9)
+1.5VS_SS/TR: length 1.4
  BOTTOM w0.254: PU401.9 117.85,81.15 117.98,81.28 PC408.1
+1.8VS_SS/TR: length 7.9
  BOTTOM w0.102: v2(204.17,73.2) 206.66,73.2 207.42,72.44 207.42,71.67 206.97,71.21 PC415.1
  BOTTOM w0.254: PU402.9 208.14,69.19 207.92,69.41 207.92,70.23 PC415.1
+3.3VDX_SSD_SS/TR: length 5.3
  BOTTOM w0.102: PC332.1 176.3,31.14 v2(176.3,30.7)
  BOTTOM w0.254: PC332.1 174.28,32.22 173.36,31.31 172.97,31.31 172.77,31.51 PU304.9
+3VALW_DSW_SS/TR: length 3.9
  TOP w0.102: v2(207.44,36.36) 207.21,36.36 PC340.1
  TOP w0.254: PU305.9 205.13,34.41 205.26,34.54 205.96,34.54 206.28,34.86 PC340.1
+3VDX_SS/TR: length 4.6
  TOP w0.102: 207.42,65.11 207.42,66.13 v2(208.13,66.84)
  TOP w0.254: PU303.9 205.9,64.86 206.15,65.11 207.88,65.11 PC324.1
+5VDX_SS/TR: length 4
  TOP w0.102: v2(199.91,53.56) PC316.1
  TOP w0.254: PU302.9 200.89,51.19 200.63,51.46 200.63,52.83 200.92,53.12 PC316.1
+EC_VCCA: length 11.4
  TOP w0.203: v6(144.58,56.96) 144.78,56.96 U34.B11
  TOP w0.508: C282.1 144.46,52.68 L43.2 143.76,51.98 v6(142.98,51.98)
  GND1 w0.203: v4(144.27,57.62) 144.27,57.23 144.53,56.96 v6(144.58,56.96)
  GND1 w0.508: v4(143.66,52.29) 143.29,52.29 v6(142.98,51.98)
  IN3 w0.508: v4(143.66,52.29) 143.03,52.29 142.76,52.57 142.76,53.21 143.63,54.09 143.63,54.91 144.83,56.11 144.83,57.06 v4(144.27,57.62)
+EDP_COM: length 4.3
  TOP w0.076: v2(83.7,79.41) 84.69,78.42 85.52,78.42 v6(85.64,78.3)
  TOP w0.102: RC36.1 v6(85.64,78.3)
  GND1 w0.076: v6(85.64,78.3) 85.64,78.66 v4(85.59,78.7)
  GND5 w0.076: v5(85.99,78.26) 85.59,78.65 v4(85.59,78.7)
  BOTTOM w0.102: v5(85.99,78.26) 85.8,78.26 UCPU1.D20
+INV_PWR_SRC: length 2.7
  BOTTOM w0.254: v1(159.39,81) 159.25,80.86 159.25,80.62 ; v1(158.75,81) JLVDS1.16 ; 159.25,80.59 JLVDS1.15
  vias: v1(160.03,81) v2(159.94,81.72)
+LCDVDD: length 5.6
  TOP w0.381: v1(171.54,78.72) 171.76,78.94 171.76,81.69 170.81,82.64 U708.5
  vias: v1(170.47,74.87) v1(170.8,75.43) v1(171.1,74.87) v1(171.43,75.43) v1(177.73,77.6) v1(178.37,77.6) v1(179.02,77.59) v1(179.66,77.6) v2(178.05,78.19)
+LCDVDD_R: length 14.5
  TOP w0.102: v1(166.9,81.99) 166.9,82.12 v2(166.25,82.77)
  TOP w0.381: U708.2 v1(166.9,81.99)
  TOP w0.508: D105.1 156.96,85.76 157.09,85.89 158.3,85.89 R1161.1 158.49,85.7 Q71.2 160.52,85.7 v1(160.69,85.86)
  IN3 w0.508: v1(160.69,85.86) 161.32,85.23 163.66,85.23 v1(166.9,81.99)
+PCH_VCCDSW: length 2.8
  TOP w0.102: RH346.1 84.46,65.47 v6(84.61,65.62)
  GND1 w0.102: v4(84.73,65.09) 84.73,65.51 v6(84.61,65.62)
  GND5 w0.076: v4(84.73,65.09) v5(85.03,65.39)
  BOTTOM w0.102: v5(85.03,65.39) 85.03,65.3 85.27,65.06 UCPU1.AG20 UCPU1.AG19
+RTC_VCCSUS: length 5.2
  TOP w0.076: v2(87.71,64.38) 88.22,64.88 RH341.2
  TOP w0.381: v6(90.08,65.44) 89.97,65.34 CH1207.1 RH341.2
  GND1 w0.381: v6(90.08,65.44) 89.94,65.44 v4(89.63,65.75)
  GND5 w0.254: v4(89.63,65.75) 89.76,65.62 v5(89.76,64.94)
  BOTTOM w0.254: v5(89.76,64.94) 89.76,64.78 90.16,64.38 UCPU1.AH11
+RTCBATT: length 3.5
  BOTTOM w0.508: RTCR1.2 29.88,55.24 v2(28.9,55.24) 28.07,55.24 27.67,54.85 JBT1.1
+RTCVCC: length 200.4
  TOP w0.254: CH82.1 CH84.1 CH83.1 90.87,64.87 v6(90.43,64.43)
  TOP w0.508: R1348.2 v1(113.02,56.59) ; CLRP3.1 97.57,47.74 96.58,48.73 96.58,50 96.07,50.51 95.27,50.51 v1(94.46,51.32) v7(94,51.78) 93.94,51.83 RH25.1 RH23.1
  GND1 w0.254: v6(90.43,64.43) 90.43,64.88 90.38,64.94 v4(90.37,64.94)
  IN1 w0.508: v1(113.02,56.59) 113.02,56.15 112.44,55.56 108.5,55.56 107.08,54.14 104.12,54.14 101.99,52.01 98.01,52.01 v1(97.23,51.22)
  IN2 w0.254: 90.33,59.02 90.48,59.17 90.48,62.45 90.95,62.92 90.95,63.35 90.58,63.72 90.58,64.72 v4(90.37,64.94) 90,64.94 89.82,64.76 89.82,64.07 89.16,63.41 89.16,60.19 90.33,59.02 ; 90.33,59.02 90.48,58.86
  IN2 w0.508: 90.48,58.86 93.21,56.13 93.21,52.57 v1(94.46,51.32) 95.14,52.01 96.44,52.01 v1(97.23,51.22) ; v4(33.67,52.03) 34.49,52.03 37.28,54.83 37.28,55.23 37.79,55.74 37.79,56.4 39.29,57.9 39.29,60.13 41.83,62.67 42.84,62.67 43.56,63.39 43.56,73.09 48.01,77.55 v1(48.01,79.34)
  IN3 w0.508: v4(90.37,64.94) 90.29,65.02 90.29,66.11 89.86,66.54 86.27,66.54 83.98,68.82 83.98,76.67 83.22,77.43 79.76,77.43 78,79.2 78,79.55 76.54,81.01 72.82,81.01 70.99,79.18 63.28,79.18 62.85,79.62 59.35,79.62 59.18,79.44 48.11,79.44 v1(48.01,79.34)
  IN4 w0.508: v1(16.99,23.25) 16.99,23.63 18.61,25.26 18.61,28.23 16.56,30.29 16.56,41.57 17.77,42.79 17.77,46.34 19.55,48.12 20.64,48.12 21.91,46.85 25.55,46.85 27.45,48.76 29.86,48.76 30.93,49.82 31.47,49.82 v4(33.67,52.03)
  GND5 w0.254: v5(90.53,64.54) 90.53,64.77 v4(90.37,64.94)
  GND5 w0.508: v5(33.56,52.63) 33.67,52.51 v4(33.67,52.03)
  BOTTOM w0.254: v1(16.99,23.25) 16.38,23.25 15.6,24.03 JIOL1.8 ; UCPU1.AG10 90.97,64.98 v5(90.53,64.54)
  BOTTOM w0.508: CH95.1 32.76,52.85 RTCD1.1 33.33,52.86 v5(33.56,52.63) ; v1(97.23,51.22) 97,51.44 RH11.1 ; RH147.1 94.92,51.76 94.9,51.76 v1(94.46,51.32) 94.42,51.32 93.9,51.84 RH31.1
+V5A_SS/TR: length 3.8
  TOP w0.254: PU301.9 207.56,28.25 207.22,28.59 v2(207.22,29.02) 207.22,29.39 PC308.1
+VCHGR:
  vias: v7(140.67,36.17)
+VREFCA: length 35.9
  TOP w0.102: CD1.1 18.55,31.25 18.02,30.72 v2(18.02,30.39)
  TOP w0.254: CD25.1 55.89,31.85 v1(55.67,32.07)
  TOP w0.381: CD1.1 18.68,31.33 19.42,32.07 v1(19.49,32.07)
  TOP w0.508: v1(78.79,32.08) 78.87,32.16 CD45.1 ; CD24.1 44.89,31.92 44.73,32.07 v1(44.13,32.07) ; CD68.1 92.53,32.27 92.32,32.07 v1(91.89,32.07) ; RD14.2 RD15.1 CD90.1 RD13.2 58.43,50.66 58.83,50.25 v1(59.38,50.25) ; v1(103.42,32.06) 103.42,32.76 CD69.1 ; CD2.1 31.12,31.98 v1(31.03,32.07) ; CD46.1 67.57,32.44 67.24,32.77 v1(67.24,32.86)
  IN1 w0.508: 64.82,34.38 64.43,34.76 64.43,36.66 62.83,38.27 62.83,41.49 59.38,44.95 v1(59.38,50.25)
  BOTTOM w0.254: v1(91.89,32.07) 92.27,32.45 UD9.M8 ; v1(55.67,32.07) 56.07,32.47 UD5.M8 ; v1(44.13,32.07) 44.52,32.46 UD4.M8 ; v1(103.42,32.06) 103.42,32.13 103.76,32.47 UD10.M8 ; UD1.M8 19.8,32.47 19.49,32.16 v1(19.49,32.07) ; UD6.M8 67.63,32.47 67.24,32.87 v1(67.24,32.86) ; v1(31.03,32.07) 30.98,32.07 30.98,32.02 31.43,32.47 UD2.M8 ; UD7.M8 79.18,32.47 v1(78.79,32.08)
+VREFDQ_A: length 48.5
  TOP w0.508: RD19.2 65.72,52.49 RD17.2 RD21.1 64.7,53.07 v1(64.68,53.1) ; CD26.2 51.95,35.83 51.56,36.22 v1(51.31,36.22) ; v1(62.08,36.08) 62.52,35.65 CD27.2 ; v1(26,35.95) 26,36.17 25.56,36.62 25.56,37.22 26.19,37.86 CD3.2 ; CD4.2 37.47,36.02 v1(37.44,36.06)
  IN1 w0.508: v4(42.08,46.65) 42.08,40.32 42.44,39.97 42.44,38.87
  GND5 w0.508: v5(42.84,46.04) 42.45,46.04 42.08,46.41 v4(42.08,46.65)
  BOTTOM w0.254: v1(62.08,36.08) 61.68,35.67 UD5.H1 ; v1(37.44,36.06) 37.05,35.67 UD2.H1 ; v1(26,35.95) 26,35.98 25.7,35.67 UD1.H1 ; UD4.H1 50.14,35.64 50.16,35.64 50.25,35.73 50.95,35.73 51.28,36.05 51.28,36.18 v1(51.31,36.22)
  BOTTOM w0.508: v5(42.84,46.04) 43.17,45.71 v2(45.87,45.71) 59.84,45.71 63.01,48.88 63.01,51.4 64.68,53.06 v1(64.68,53.1)
+VREFDQ_B: length 21.9
  TOP w0.508: v1(73.81,35.96) 74.18,36.33 CD47.2 ; v2(62.75,49.39) 62.05,50.09 v1(62.05,50.25) 61.98,50.32 RD18.2 61.98,51.88 RD22.1 RD20.2 ; CD70.2 98.9,35.9 v1(98.8,35.8) ; v1(109.89,36.12) 109.89,36.08 110.06,35.9 CD71.2 ; CD48.2 85.22,36.07 v1(85.21,36.08)
  IN1 w0.508: v1(65.17,40.37) 64.59,40.96 64.59,41.67 62.05,44.21 v1(62.05,50.25)
  BOTTOM w0.254: v1(109.89,36.12) 109.89,36.14 109.43,35.68 UD10.H1 ; v1(85.21,36.08) 84.8,35.67 UD7.H1 ; UD6.H1 73.25,35.67 73.54,35.96 73.71,35.96 73.74,35.99 73.78,35.95 73.78,35.95 73.81,35.98 v1(73.81,35.96) ; UD9.H1 97.89,35.67 97.92,35.7 98.7,35.7 v1(98.8,35.8)
+VS_LPSS_SDIO: length 10.2
  TOP w0.508: RH354.1 98.93,73.62 98.71,73.41 CH1227.1 ; v1(92.4,71.11) 92.41,71.12 94.16,71.12 v2(94.76,71.71) 95.78,72.73 96.15,72.73 RH434.1 CH1227.1 ; CH1227.1 RH350.1
  BOTTOM w0.254: v1(92.4,71.11) 92.36,71.06 92.36,70.97 92.04,70.66 UCPU1.U8 91.59,71.1 UCPU1.T9
/BATDRV: length 19.9
  TOP w0.102: v1(135.11,31.71) v2(134.68,31.28)
  TOP w0.254: PU201.11 148.21,40.91 148.1,40.81 148.15,40.75 v1(148.15,40.7)
  IN4 w0.508: v1(148.15,40.7) 148.15,40.25 145,37.1 142.41,37.1 141.53,36.22 139.61,36.22 v1(135.11,31.71)
  BOTTOM w0.508: PR230.1 v1(135.11,31.71)
AC_PRESENT: length 56.5
  TOP w0.076: U34.E5 143.17,60.35 143.17,60.86 v6(143.06,60.97)
  TOP w0.102: v2(100.71,66.64) 100.03,66.64 99.17,65.77 v6(98.85,65.77) 98.83,65.75 RH137.2 97.14,64.58 RH12.1
  GND1 w0.076: v4(98.39,65.7) 98.78,65.7 v6(98.85,65.77) ; v6(143.06,60.97) 142.96,60.87 142.44,60.87 v4(142.36,60.95)
  IN1 w0.076: v4(98.39,65.7) 98.56,65.86 99.98,65.86 100.11,65.74 100.74,65.74 100.92,65.91 102.89,65.91 103.33,65.47 103.33,65.1 103.91,64.53 106.02,64.53 106.21,64.73 106.97,64.73 109.81,61.89 114.86,61.89 116.14,63.17 118.91,63.17 119.9,62.18 123.42,62.18 124.21,62.97 127.79,62.97 128.33,63.51 129.78,63.51 130.26,64 132.65,64 132.96,63.68 133.42,63.68 133.83,64.08 134.21,64.08 134.96,63.33 138.31,63.33 138.46,63.49 138.92,63.49 140.52,61.89 140.81,61.89 141.75,60.95 v4(142.36,60.95)
AC_PRESENT_R: length 8.4
  TOP w0.102: RH137.1 v6(97.39,65.27)
  GND1 w0.076: v6(97.39,65.27) 97.39,65.33 v4(97.81,65.75)
  IN1 w0.076: v4(97.81,65.75) 97.37,65.75 96.31,64.69 95.22,64.69 94.75,65.16 94.29,65.16 94.05,64.92 93.67,64.92 93.12,64.38 92.45,64.38 v4(92.35,64.27)
  GND5 w0.076: v5(91.89,64.3) 92.32,64.3 v4(92.35,64.27)
  BOTTOM w0.102: UCPU1.AJ8 92.04,64.15 v5(91.89,64.3)
ACCEL_INT1: length 38.6
  TOP w0.102: D94.2 169.4,59.42 168.6,60.22 168.17,60.22 167.39,61 v6(167.39,64.48) 167.39,64.55 165.46,66.48 R1207.1 ; v1(153.04,64.03) 153.04,63.55 153.27,63.32 153.27,61.87 153.12,61.72 153.12,57.72 152.95,57.56 152.95,57.29 152.08,56.41 152.08,55.23 152.47,54.84 v2(152.47,54.57) 152.47,54.02 152.29,53.84 U637.5
  GND1 w0.076: v6(167.39,64.48) 167.37,64.48 167.3,64.41 v4(167.3,63.98)
  IN4 w0.076: v1(153.04,64.03) 153.16,63.92 153.8,63.92 153.91,64.02 154.34,64.02 155.43,65.11 156.3,65.11 156.57,64.83 158.16,64.83 159.75,63.24 161.24,63.24 161.8,63.81 162.73,63.81 163.6,64.68 165.08,64.68 165.27,64.87 166.42,64.87 v4(167.3,63.98)
ACCEL_INT2: length 18.2
  TOP w0.102: U637.4 153.09,53.87 153.25,54.03 153.58,54.03 153.79,54.24 v2(153.79,54.56) 153.79,54.93 R1088.1 153.65,56.01 153.65,57.22 v1(153.52,57.35) ; U636.E4 v6(159.82,63.6)
  GND1 w0.076: v6(159.82,63.6) 160.2,63.6 v4(160.34,63.74)
  IN3 w0.076: v1(153.52,57.35) 153.52,56.95 154.12,56.35 155.95,56.35 158.48,58.88 158.48,61.87 v4(160.34,63.74)
ACDET: length 6.2
  TOP w0.102: PC216.1 144,46.88 v2(143.59,47.28)
  TOP w0.254: PC216.1 PR213.1 PR208.2 146.37,44.92 146.85,44.45 PU201.6
ACDRV: length 26.2
  TOP w0.102: v2(165.77,42.28) 166,42.51 PR206.2
  TOP w0.254: PU201.4 148.71,45.79 v6(148.8,45.89) ; PR206.2 166.68,43.22 166.52,43.38 v1(166.52,44.31)
  GND1 w0.254: v6(148.8,45.89) 148.72,45.81 148.72,45.38 148.69,45.34 v4(148.69,45.43)
  IN2 w0.254: v4(148.69,45.43) 148.79,45.53 148.79,46.19 149.78,47.18 165.85,47.18 167.09,45.94 167.09,44.88 v1(166.52,44.31)
ACIN: length 77.7
  TOP w0.102: U34.F5 142.92,60.08 v6(142.63,59.79) ; v6(147.77,48.35) 147.77,47.43 PR223.2 147.86,46.85 147.84,46.88 PR226.1 147.26,46.49 147.57,46.19 147.87,46.19 148.21,45.86 PU201.5 ; v1(173.81,48.43) 174.08,48.15 175.53,48.15 176.01,48.62 U689.1 ; PR119.1 135.67,44.08 135.33,44.42 135.33,46.35 135.83,46.86 135.83,48.29 136.41,48.86 136.41,49.4 v7(136.23,49.58) 136.23,49.83 136.35,49.96 136.35,50.32 v1(136.72,50.69) 136.82,50.79 137.52,50.79 138.26,51.52 138.26,52.51 137.6,53.17 R924.2 C1116.2
  GND1 w0.076: v6(142.63,59.79) 142.63,59.82 v4(143.02,60.21) ; v6(147.77,48.35) 147.77,48.76 v4(147.85,48.83)
  IN3 w0.076: v4(143.02,60.21) 142.86,60.21 142.21,59.56 141.41,59.56 141.06,59.21 139.93,59.21 139.2,58.48 139.2,57.2 140.05,56.35 140.05,55.75 140.14,55.66 140.14,54.83 139.99,54.67 139.99,53.86 140.19,53.66 140.19,51.66 140.01,51.49 137.52,51.49 v1(136.72,50.69)
  IN4 w0.076: v1(173.81,48.43) 173.55,48.17 171.28,48.17 170.5,48.95 147.92,48.95 147.85,48.87 147.85,48.84 ; 147.85,48.84 147.63,49.06 145.56,49.06 145.07,48.56 138.34,48.56 137.31,49.59 137.31,50.08 136.72,50.66 v1(136.72,50.69) ; 147.85,48.84 v4(147.85,48.83)
ACOFF: length 23.4
  TOP w0.102: RP22.1 140.19,49.89 141.79,48.29 141.79,48.01 142,47.8 PQ202.2 143.53,47.8 144.76,49.03 149.61,49.03 150.02,49.44 v2(150.02,52.65) 150.02,53.4 149.78,53.64 149.78,54.09 149.47,54.39 147.71,54.39 147.44,54.66 147.44,54.88 147.16,55.16 147.16,56.15 146.13,57.18 146.13,57.39 U34.A9
AD_BID0: length 8.9
  TOP w0.102: C283.1 R219.1 146.81,50.38 R225.2 146.78,51.41 v2(146.65,51.54) 146.11,52.08 146.11,52.48 145.87,52.72 145.87,54.41 v6(146.29,54.83) ; U34.A12 145.42,56.6 145.78,56.25 v6(145.78,55.36)
  GND1 w0.076: v6(146.29,54.83) 146.29,54.85 v6(145.78,55.36)
ADP_I: length 18.8
  TOP w0.076: v6(145.4,55.4) 145.17,55.62 145.17,56.35 U34.B12
  TOP w0.102: v6(143.17,53.39) 143.05,53.51 PR116.2 ; 145.14,44.95 v2(145.75,45.55)
  TOP w0.254: v1(145.09,44.95) 145.27,44.95 145.82,44.4 PC220.2 146.13,44.4 146.59,43.95 PU201.7
  GND1 w0.076: v4(143.36,52.9) 143.36,53.2 v6(143.17,53.39) ; v6(145.4,55.4) v4(145.4,54.83)
  IN1 w0.076: v4(143.36,52.9) 143.2,52.74 143.2,52.08 143.61,51.68 143.61,50.13 144.08,49.66 144.08,46.95 144.71,46.32 144.71,45.29 145.06,44.95 v1(145.09,44.95)
  IN3 w0.076: v4(145.4,54.83) 145.4,54.41 144.36,53.37 143.83,53.37 v4(143.36,52.9)
ADPIN:
  vias: v1(193.72,83.03) v1(193.72,82.3) v1(194.38,83.05) v1(194.37,82.31) v1(195.02,83.05) v1(195,82.31) v1(195.74,83.02) v7(195.28,80.68) v7(195.64,82.42) v7(197.09,80.68)
ALL_SYS_PCH_PWROK_EC: length 4.3
  TOP w0.102: v2(164.8,47.33) 164.65,47.49 163.23,47.49 162.96,47.75 R1292.1 163.44,48.45 163.44,48.92 163.27,49.1 U691.4
ALS_INT#: length 46.9
  TOP w0.102: v6(150.59,69.3) 150.46,69.18 R1115.1 150.57,68.67 R1116.1
  GND1 w0.076: v4(150.72,68.92) 150.59,69.05 v6(150.59,69.3)
  IN4 w0.076: v4(150.72,68.92) 152.57,68.92 153.52,67.97 158.49,67.97 158.82,68.3 166.26,68.3 166.67,68.71 166.67,70.26 167.62,71.21 168.9,71.21 170.5,72.81 175.34,72.81 176.86,71.29 178.81,71.29 179.65,70.45 v1(180.52,70.45)
  BOTTOM w0.102: JLVDS2.9 181.24,78.25 182.16,77.33 v2(182.16,76.8) 182.16,75.97 181.72,75.53 181.29,75.53 180.54,74.78 180.54,74.17 180.42,74.05 180.42,71.31 180.52,71.21 v1(180.52,70.45)
ALS_INT#_EC: length 26.6
  TOP w0.102: v1(140.74,49.97) 140.33,50.38 RP22.2 ; R1115.2 148.99,68.21 148.27,68.21 v6(148.17,68.11) ; v6(143.11,58.79) 143.42,59.1 U34.E7
  GND1 w0.076: v4(142.79,58.18) 143.11,58.5 v6(143.11,58.79) ; v6(148.17,68.11) 148.23,68.05 v4(148.23,67.73)
  IN3 w0.076: v4(148.23,67.73) 148.23,67.23 147.89,66.89 146.88,66.89 146.43,66.43 146.43,62.81 146.17,62.56 146.17,61.54 144.86,60.24 143.54,60.24 142.98,59.68 142.98,58.37 v4(142.79,58.18) 142.79,57.99 141.61,56.81 141.61,56.16 141.42,55.97 141.42,55.37 141.61,55.18 141.61,50.85 v1(140.74,49.97)
ALS_INT#_HUB: length 13.4
  TOP w0.102: R1143.1 151.48,68.49 R1116.2 151.23,67.37 v2(151.23,66.66) 151.23,65.99 v6(151.24,65.98) ; U636.E6 160.05,64.82 v6(160.27,64.6)
  GND1 w0.076: v6(160.27,64.6) 160.27,64.98 v4(160.37,65.09) ; v4(151.78,65.82) 151.62,65.98 v6(151.24,65.98)
  IN1 w0.076: v4(151.78,65.82) 152.2,66.24 154.88,66.24 155.49,65.64 159.82,65.64 v4(160.37,65.09)
ALS_SMBCLK: length 35.4
  TOP w0.102: R985.1 152.66,77.34 152.46,77.14 152.2,77.14 v8(152.03,77.32) 151.85,77.14 151.7,77.14 R983.2
  IN2 w0.076: v1(182.35,78.52) 182.11,78.77 182.11,78.99 181.69,79.4 172.82,79.4 172.24,79.97 155.46,79.97 152.61,77.13 152.22,77.13 v8(152.03,77.32)
  BOTTOM w0.102: JLVDS2.7 182.24,79.16 182.11,79.03 182.11,78.77 v1(182.35,78.52)
ALS_SMBDATA: length 34.9
  TOP w0.102: R986.1 152.67,76.54 152.46,76.76 152.1,76.76 v1(152.03,76.68) 151.95,76.76 151.66,76.76 R984.2
  IN2 w0.076: v1(152.03,76.68) 152.03,76.71 152.24,76.92 152.7,76.92 155.54,79.77 172.16,79.77 172.73,79.2 181.61,79.2 181.9,78.9 181.9,78.76 v8(181.68,78.54)
  BOTTOM w0.102: JLVDS2.8 181.74,79.17 181.88,79.04 181.88,78.74 v8(181.68,78.54)
AOAC_THERMAL: length 10.5
  TOP w0.102: v6(146.44,54.44) 146.44,54.46 146.86,54.88 v2(146.86,54.99)
  TOP w0.203: U34.D7 144.14,59.1 v6(144.23,59.02)
  TOP w0.254: R928.1 R927.2 146.34,54.34 v6(146.44,54.44)
  GND1 w0.254: v6(146.44,54.44) 146.87,54.44 v4(147,54.57) ; v4(144,59.55) 144.23,59.32 v6(144.23,59.02)
  IN3 w0.254: v4(147,54.57) 146.45,55.12 146.45,57.36 145.69,58.12 145.69,58.9 145.05,59.55 v4(144,59.55)
APWROK_R: length 9.3
  TOP w0.102: v2(96.13,62.41) 95.79,62.75 95.79,63.97 RH131.1 96.65,64.83 96.65,66.29 96.97,66.61 RH438.1 96.97,67.06 95.62,68.41 v6(95.62,68.41)
  GND1 w0.076: v6(95.62,68.41) 95.46,68.57 94.72,68.57 94.56,68.41 v4(94.56,68.39)
  GND5 w0.076: v4(94.56,68.39) 94.27,68.1 v5(94.27,68.02)
  BOTTOM w0.102: v5(94.27,68.02) 94.05,67.8 UCPU1.AB5
AUD_MUTE#: length 148.8
  TOP w0.102: v1(138.91,55.14) 138.79,55.26 138.79,55.98 U34.N12
  IN1 w0.076: v4(64.27,26.71) 64.27,26.7 62.94,28.03 55.47,28.03 55.04,28.46 53.35,28.46 53.11,28.7 52.71,28.7 51.91,29.5 50.03,29.5 48.61,28.08 45.66,28.08 44.42,26.84 42.46,26.84 42.26,27.04 41.63,27.04 41.27,27.39 40.38,27.39 39.62,28.16 38.6,28.16 38.35,27.9 32.56,27.9 31.81,27.15 31.81,26.72 30.07,24.98 28.14,24.98 26.54,23.38 23.21,23.38 22.52,22.69 19.65,22.69 18.61,21.65 18.61,21.2 18.37,20.95 v1(18.12,20.95) ; v1(138.91,55.14) 138.91,54.71 136.3,52.11 136.3,50.5 v1(135.83,50.03)
  IN2 w0.076: v4(64.27,26.71) 65.26,27.7 74.21,27.7 74.49,27.42 74.85,27.42 75.08,27.19 79.7,27.19 80.23,27.72 83.48,27.72 83.61,27.6 86.08,27.6 87.12,28.64 88.08,28.64 89.2,27.52 92.83,27.52 93.01,27.7 98.86,27.7 99.17,27.39 100.33,27.39 100.71,27.01 103.33,27.01 104.55,28.23 110.56,28.23 114.88,32.55 114.88,32.98 v8(114.42,33.44)
  BOTTOM w0.102: v1(18.12,20.95) 18.1,20.93 JIOL1.17 ; v8(114.42,33.44) 114.62,33.44 116.17,34.99 116.17,39.48 118.64,41.95 121.86,41.95 122.47,42.56 126.07,42.56 132.42,48.91 134.84,48.91 135.83,49.9 v1(135.83,50.03)
AUDIO_IRQ#: length 19.3
  IN4 w0.076: v4(94.15,73.19) 94.91,73.19 95.39,72.71 98.68,72.71 99.7,73.74 108.67,73.74 108.87,73.53 v4(108.87,73.52)
  GND5 w0.076: v5(94.56,73.68) 94.15,73.28 v4(94.15,73.19) ; v4(108.87,73.52) 108.87,73.57 109.25,73.95 v5(109.29,73.95)
  BOTTOM w0.102: v5(94.56,73.68) 94.67,73.57 UCPU1.L4 ; v5(109.29,73.95) 109.72,74.38 RH396.2 109.99,74.13 110.83,74.13 v2(111.07,74.37)
AUDIO_PWREN: length 187.4
  TOP w0.102: U664.5 130.26,33 v1(130.74,32.52) 130.74,32.04 R1140.1 ; U664.3 129.19,32.2 129.43,31.97 129.9,31.97 130.16,31.71 R1140.1 ; U717.5 136.2,22.04 136.06,21.91 135.31,21.91 v1(134.91,22.31) ; PD305.2 193.38,65.16 190.86,62.65 185.94,62.65 180.65,57.37 180.65,51.14 177.71,48.2 177.71,44.82 v1(177.45,44.56) ; R1140.1 R1182.1 ; v1(99.28,71.64) 98.89,71.25 98.89,70.5 98.42,70.03 T279.1
  IN3 w0.076: v1(130.74,32.52) 130.31,32.96 127.5,32.96 124.4,36.06 119.56,36.06 118.29,34.79 115.31,34.79 113.6,36.5 112.92,36.5 111.98,37.44 111.98,43.4 110.15,45.22 109.7,45.22 105.15,49.77 105.15,53.92 101.82,57.25 101.82,59.87 105.75,63.8 105.75,64.47 106.28,65 106.28,65.68 105.94,66.03 105.94,67.67 105.33,68.28 101.9,68.28 100.74,69.43 100.74,70.18 v1(99.28,71.64)
  IN4 w0.076: v1(130.74,32.52) 131.02,32.25 132.86,32.25 133.18,31.93 133.18,25.2 134.91,23.47 v1(134.91,22.31) 136.2,21.02 154.99,21.02 161.64,27.67 167.95,27.67 168.89,28.61 174.33,28.61 179.83,34.11 179.83,36.06 180.27,36.5 180.27,37.7 179.36,38.62 179.36,40.32 178.43,41.25 178.43,43.54 177.97,44 177.97,44.04 v1(177.45,44.56)
  BOTTOM w0.076: UCPU1.P1 97.37,71.88
  BOTTOM w0.102: 97.37,71.88 97.5,71.88 97.75,71.64 v1(99.28,71.64)
AUDIO_XTAL24_IN: length 6
  TOP w0.102: YA1.3 128.62,51.82 128.62,50.01 CA17.1 127.61,48.47 UA1.2
AUDIO_XTAL24_OUT: length 3.9
  TOP w0.102: UA1.3 127.11,48.51 128.02,49.42 CA16.1 128.02,50.39 YA1.1
B+: length 9
  TOP w0.508: 121.47,80.19 121.47,75.98 119.36,73.88 R1381.1
  vias: v1(38.13,80.14) v1(38.15,79.4) v1(38.15,78.71) v1(38.7,80.45) v1(38.7,79.76) v1(38.7,79.02) v1(83.97,19.82) v1(84.73,19.82) v1(85.49,19.82) v1(86.25,19.82) v1(120.43,82.14) v1(120.37,81.51) v1(120.7,82.75) v1(121.13,82.28) v1(121.05,81.65) v1(121.24,83.45) v1(121.47,82.85) v1(121.83,82.32) v1(148.51,78.37) v1(148.5,77.69) v1(148.51,77.05) v1(149.04,78.02) v1(149.08,36.89) v1(149.54,37.5) v1(149.73,78.42) v1(149.73,77.76) v1(149.66,36.16) v1(149.92,36.82) v1(150.36,78.12) v1(150.48,37.25) v1(150.48,36.21) v1(150.64,78.7) v1(150.76,37.96) v1(150.91,36.77) v1(151,78.12) v1(151.24,37.38) v1(151.24,36.18) v1(151.57,37.96) v1(151.67,36.73) v1(152,37.35) v1(152.14,36.21) v1(152.34,78.51) v1(152.38,37.93) v1(152.71,37.33) v1(159.47,82.69) v1(160.1,82.69) v1(160.74,82.69) v1(164.29,85.89) v1(168.09,23.43) v1(168.85,23.46) v1(169.56,23.46) v1(190.95,30.06) v1(190.95,29.17) v1(193.24,20.03) v1(193.24,19.27) v1(193.87,20.03) v1(193.87,19.27) v1(194.51,20.03) v1(194.51,19.27) v1(195.14,20.03) v1(195.14,19.27) v1(195.78,20.03) v1(195.78,19.27) v1(196.41,20.03) v1(196.41,19.27) v1(197.05,20.03) v1(197.05,19.27) v1(197.68,20.03) v1(197.68,19.27) v1(200.46,45.22) v1(200.48,44.51) v1(200.83,35.45) v1(201.15,45.25) v1(201.16,44.51) v1(201.37,35.01) v1(202,35.17) v1(202.11,34.48) v1(208.99,70.12) v1(209.28,69.46) v1(209.66,70.12) v1(210.34,70.12) v7(201.2,23.76)
B-RAMP: length 3.4
  TOP w0.203: PU701.11 27.72,77.1 27.6,76.98 v2(27.6,76.39) 27.6,75.45 PR704.1
  TOP w0.254: PR704.1 26.84,75.35 PR711.2
BATBTN#: length 133.9
  TOP w0.102: RP16.3 148.46,60.24 148.64,60.41 148.64,61.3 149.44,62.1 149.44,62.25 D84.1 150.74,62.83 v1(151.58,63.67) ; v6(141.97,61.23) 142.42,60.77 U34.G4 ; v2(228.63,26.62) 229.86,26.62 230.38,26.11 SW1.1 SW1.3 228.91,21.43 C1122.1 v1(228.91,20.69)
  GND1 w0.076: v6(141.97,61.23) 141.97,61.76 v4(142.23,62.03)
  IN1 w0.076: v4(142.23,62.03) 142.61,62.4 143.47,62.4 144.01,61.86 144.01,61.59 144.14,61.47 146.43,61.47 146.44,61.46 147.17,61.46 147.72,62 149.77,62 151.43,63.67 v1(151.58,63.67)
  IN2 w0.076: v1(151.58,63.67) 151.58,63.23 153.23,61.58 154.76,61.58 157.12,59.22 160.62,59.22 163.68,56.16 164.43,56.16 169.47,51.12 172.23,51.12 175.13,48.22 175.13,44.03 177.52,41.64 177.52,27.72 180.63,24.6 198.29,24.6 202.97,19.93 221.38,19.93 222.42,20.97 228.63,20.97 v1(228.91,20.69)
BATMAN_CLK: length 5.6
  TOP w0.102: Q359.6 116.65,54.21 116.4,53.96 v2(115.55,53.96) 115.27,53.68 115.27,53.28 114.71,52.72 R1350.1 R1347.1 114.33,51.79 113.8,52.32 U714.7
BATMAN_DATA: length 8.4
  TOP w0.102: U714.6 113.78,51.82 R1346.1 R1351.1 115.17,49.54 116.72,49.54 117.48,50.3 v2(117.48,51.55) 117.48,51.68 117.95,52.15 Q359.3
BATMAN_X1: length 3.4
  TOP w0.102: U714.14 109.05,52.32 C1295.1 107.96,52.53 Y3.1
BATMAN_X2: length 3.5
  TOP w0.102: Y3.2 108.2,51.63 C1296.1 109.05,51.82 U714.15
BATT+: length 3.2
  BOTTOM w0.102: v7(133.24,41.53) 132.89,41.88 130.94,41.88 PC105.1
BATT++: length 2.8
  TOP w0.102: v1(128.99,27.24) v7(128.99,26.59) ; v1(130.42,20.04) v7(129.56,20.04) ; v1(128.92,25.13) v7(128.92,23.8)
BATT_LED#_LV1: length 130.8
  TOP w0.102: v6(144.6,57.36) 144.68,57.36 U34.B10 ; v8(225.67,8.65) 226.06,8.27 Q316.1
  GND1 w0.076: v6(144.6,57.36) 145.11,57.36 v4(145.41,57.06)
  IN2 w0.076: v4(145.41,57.06) 145.46,57.11 145.46,59.22 146.5,60.26 151.53,60.26 152.33,59.46 152.98,59.46 154.83,57.61 154.83,56.59 155.38,56.05 156.61,56.05 157.73,54.93 157.73,50.9 158.57,50.05 160.8,50.05 163.01,52.26 166.76,52.26 173.1,45.93 173.1,44.8 176.58,41.32 176.58,27.4 180.26,23.71 197.92,23.71 202.6,19.04 221.75,19.04 222.71,20 227.39,20 228.68,18.71 228.68,16.24 225.67,13.23 v8(225.67,8.65)
BATT_LED#_LV1_Q: length 31.6
  TOP w0.102: Q316.6 228.3,8.1 228.92,7.48 229.09,7.48 v8(229.42,7.15) ; RP14.8 224.94,23.85 v1(224.92,23.86)
  IN2 w0.076: v8(229.42,7.15) 229.22,7.35 229.22,8.41 230.04,9.23 230.04,14.59 230.73,15.28 230.73,21.42 228.41,23.74 225.05,23.74 v1(224.92,23.86)
  BOTTOM w0.102: Q354.2 219.07,25.18 219.5,24.75 223.49,24.75 224.38,23.86 v1(224.92,23.86)
BATT_LED#_LV2: length 135.7
  TOP w0.076: 144.25,60.82 144.79,61.35 145.07,61.35 145.17,61.46 145.17,62.78 145.22,62.83
  TOP w0.102: 145.22,62.83 145.34,62.94 146.39,62.94 v6(146.81,62.52) ; U34.B9 144.58,58.44 144.58,59.08 144.25,59.41 144.25,60.82 ; v2(228.86,6.11) 228.16,6.8 Q316.4 227.93,6.8 227.25,6.12 v1(227.25,5.63)
  GND1 w0.076: v6(146.81,62.52) 147.14,62.19 v4(147.14,62.09)
  IN2 w0.076: v4(147.14,62.09) 147.23,62 150.78,62 152.32,60.46 154.77,60.46 156.73,58.51 159.99,58.51 165.86,52.64 166.89,52.64 171.6,47.93 172.33,47.93 173.32,46.94 173.32,44.82 176.78,41.37 176.78,27.45 180.34,23.89 198,23.89 202.67,19.22 221.68,19.22 222.64,20.18 227.46,20.18 228.86,18.78 228.86,16.17 226.11,13.41 226.11,5.96 226.44,5.63 v1(227.25,5.63)
BATT_LED#_LV2_Q: length 31.4
  TOP w0.102: v1(227.02,6.67) 226.88,6.8 Q316.3 ; v1(224.47,24.4) 224.51,24.35 RP14.7
  IN2 w0.076: v1(227.02,6.67) 228.7,6.67 229,6.97 229,8.5 229.74,9.23 229.74,14.64 230.37,15.28 230.37,21.49 228.43,23.43 224.73,23.43 224.47,23.7 v1(224.47,24.4)
  BOTTOM w0.102: v1(224.47,24.4) 224.68,24.61 224.68,24.85 224.58,24.96 v2(224.28,24.96) 223.21,24.96 222.63,25.54 Q355.2
BATT_LED#_LV3: length 130.6
  TOP w0.102: U34.K2 140.92,61.54 v6(141.17,61.29) ; Q318.1 226.4,10.64 v8(226.82,11.06)
  GND1 w0.076: v4(140.7,61.48) 140.89,61.29 v6(141.17,61.29)
  IN2 w0.076: v8(226.82,11.06) 226.82,13.8 229.09,16.07 229.09,18.88 227.61,20.36 222.57,20.36 221.6,19.39 202.74,19.39 198.07,24.07 180.41,24.07 176.96,27.52 176.96,41.44 173.5,44.9 173.5,47.99 172.92,48.58 172.92,49.06 171.46,50.52 169.31,50.52 164.21,55.62 163.46,55.62 160.4,58.69 156.86,58.69 154.73,60.82 152.29,60.82 150.11,63 148.22,63 146.95,64.27 145.18,64.27 144.85,63.94 144.46,63.94 144.1,63.59 144.1,63.15 143.37,62.42 141.17,62.42 140.7,61.95 v4(140.7,61.48)
BATT_LED#_LV3_Q: length 28
  TOP w0.102: Q318.6 228.77,10.64 v8(229.29,10.12) ; RP14.6 224.18,24.85 223.77,24.43 v1(223.77,23.84)
  IN2 w0.076: v8(229.29,10.12) 229.29,10.12 228.75,10.67 228.75,14.01 230.17,15.43 230.17,21.39 228.3,23.25 224.35,23.25 v1(223.77,23.84)
  BOTTOM w0.102: Q356.2 221.88,21.48 222.14,21.74 222.14,22.62 223.36,23.84 v1(223.77,23.84)
BATT_LED#_LV4: length 133.8
  TOP w0.076: v6(141.17,62.53) 141.17,62.53 141.17,61.85 U34.J2
  TOP w0.102: v1(227.06,9.34) Q318.4 228.58,9.34 v2(228.94,9.7)
  GND1 w0.076: v6(141.17,62.53) 141.17,62.78 v4(141.42,63.03)
  IN2 w0.076: v4(141.42,63.03) 141.44,63.03 142.01,63.6 142.53,63.6 143.53,64.6 144.64,64.6 144.85,64.81 147.52,64.81 148.08,64.25 148.94,64.25 149.17,64.48 150.06,64.48 153.13,61.4 154.64,61.4 157.01,59.04 160.54,59.04 163.61,55.98 164.35,55.98 169.39,50.94 172.15,50.94 174.95,48.14 174.95,43.95 177.34,41.56 177.34,27.64 180.56,24.42 198.22,24.42 202.89,19.75 221.45,19.75 222.42,20.71 227.82,20.71 229.57,18.96 229.57,15.7 227.78,13.91 227.78,10.07 v1(227.06,9.34)
BATT_LED#_LV4_Q: length 36
  TOP w0.102: Q318.3 226.4,9.34 227.05,8.7 v8(227.69,8.7) ; RP14.5 226.13,25.35 226.28,25.5 226.28,26.24 224.82,27.7 221.37,27.7 Q357.2 221.81,26.8 v1(221.81,26.43)
  IN2 w0.076: v8(227.69,8.7) 228.01,9.02 228.01,13.86 229.79,15.63 229.79,20.52 228.92,21.39 222.66,21.39 221.67,22.38 221.67,26.28 v1(221.81,26.43)
BATT_LED#_LV5: length 146.8
  TOP w0.081: U34.N8 138.81,58.6 138.61,58.41
  TOP w0.102: Q320.1 226.22,5.56 v8(226.74,6.08) ; v6(136.96,56.86) 137.27,56.86 137.88,57.47 137.88,57.77 138.51,58.41 138.61,58.41
  GND1 w0.076: v6(136.96,56.86) 136.96,57.28 v4(136.57,57.67)
  IN2 w0.076: v4(136.57,57.67) 136.57,57.68 138.25,59.36 139.05,59.36 139.58,59.89 140.04,59.89 140.52,60.37 140.52,60.99 140.27,61.24 140.27,62.04 140.85,62.62 143.32,62.62 143.92,63.22 143.92,63.66 144.38,64.12 144.78,64.12 145.11,64.45 147.31,64.45 147.92,63.84 148.85,63.84 149.23,63.46 150.82,63.46 153.06,61.23 154.57,61.23 156.93,58.86 160.47,58.86 163.54,55.8 164.28,55.8 169.34,50.74 172.1,50.74 174.77,48.07 174.77,43.88 177.16,41.49 177.16,27.57 180.48,24.24 198.14,24.24 202.82,19.57 221.53,19.57 222.49,20.54 227.75,20.54 229.32,18.96 229.32,15.98 227.49,14.14 227.49,11.05 226.54,10.1 226.54,6.29 v8(226.74,6.08)
BATT_LED_COLOR_W: length 158.6
  TOP w0.102: U34.A4 146.5,60.6 v6(147.49,59.61)
  GND1 w0.076: v4(147.49,59.09) v6(147.49,59.61)
  IN1 w0.076: v1(20.1,20.88) 20.19,20.79 23.9,20.79 25.62,22.52 26.74,22.52 28.42,24.19 30.42,24.19 32.27,26.05 38.04,26.05 38.17,26.17 39.03,26.17 40,25.21 40.66,25.21 40.96,25.51 41.55,25.51 42.16,26.12 48.56,26.12 50.29,27.85 51.15,27.85 51.52,27.48 51.82,27.48 51.86,27.44 51.86,27.44 52.09,27.22 52.88,27.22 53.03,27.06 55.72,27.06 56.23,26.56 61.32,26.56 v4(61.5,26.73)
  IN2 w0.076: v8(113.08,33.21) 113.08,32.35 111.25,30.52 109.01,30.52 108.33,29.83 104.57,29.83 103.32,28.59 101.21,28.59 101.01,28.79 100.53,28.79 99.61,29.71 97.73,29.71 96.46,28.44 92.83,28.44 92.78,28.49 90.42,28.49 89.81,29.1 88.69,29.1 88.39,29.4 86.74,29.4 86.51,29.17 83.51,29.17 82.77,28.44 78.25,28.44 78,28.69 75.99,28.69 75.1,29.58 73.45,29.58 72.29,28.41 63.16,28.41 61.5,26.75 v4(61.5,26.73) ; v1(134.61,49.42) 134.64,49.44 136.27,49.44 136.72,48.98 140.62,48.98 142.42,50.79 143.3,50.79 143.81,51.3 144.71,51.3 146.5,53.09 146.5,55.03 147.14,55.66 147.14,57.1 147.82,57.79 147.82,58.72 147.49,59.05 v4(147.49,59.09)
  BOTTOM w0.102: v8(113.08,33.21) 113.08,33.36 114.8,35.09 114.8,38.82 118.33,42.35 121.66,42.35 122.3,43 125.92,43 132.37,49.44 133.17,49.44 133.6,49.87 134.16,49.87 v1(134.61,49.42) ; JIOL1.25 v1(20.1,20.88)
BATT_LED_CTRL#: length 164.7
  TOP w0.102: v6(146.5,61.54) 146.07,61.54 145.63,61.1 U34.A3
  GND1 w0.076: v6(146.5,61.54) 146.5,62.04 v4(146.54,62.08)
  IN1 w0.076: v1(20.1,21.51) 20.28,21.69 24.16,21.69 25.45,22.97 26.66,22.97 28.24,24.55 30.22,24.55 32.2,26.53 39.97,26.53 40.38,26.94 41.12,26.94 41.42,26.63 42.13,26.63 42.28,26.48 48.28,26.48 50.03,28.23 51.27,28.23 51.65,27.85 52.17,27.85 52.42,28.11 52.42,28.21 52.56,28.35 52.96,28.35 53.21,28.11 54.89,28.11 55.33,27.67 61.88,27.67 62.85,26.71 v4(62.92,26.71)
  IN2 w0.076: v4(62.92,26.71) 62.94,26.71 64.28,28.05 74.42,28.05 74.65,27.83 75.36,27.83 75.51,27.98 75.51,28.11 75.74,28.33 77.85,28.33 78.1,28.08 83.02,28.08 83.76,28.82 86.76,28.82 86.94,28.99 88.26,28.99 89.38,27.88 92.19,27.88 92.4,28.08 99.26,28.08 99.49,27.85 99.99,27.85 100.15,28 100.15,28.11 100.45,28.41 100.76,28.41 101.06,28.11 103.34,28.11 104.67,29.43 108.66,29.43 109.39,30.16 111.39,30.16 113.76,32.53 113.76,34.05 v8(113.05,34.76)
  IN3 w0.076: v4(146.54,62.08) 146.54,61.59 144.99,60.05 143.59,60.05 143.16,59.61 143.16,57.23 142.41,56.48 142.41,55.71 143.16,54.97 143.16,54.23 142.12,53.19 142.12,50.6 140.99,49.47 139.97,49.47 138.22,51.22 137.71,51.22 137.36,50.86 137.36,50.66 136.95,50.25 136.28,50.25 v1(135.83,50.7)
  BOTTOM w0.102: v1(20.1,21.51) 19.6,21.01 JIOL1.23 ; v8(113.05,34.76) 113.79,34.76 114.32,35.29 114.32,35.83 113.76,36.39 113.76,40.06 116.46,42.76 121.44,42.76 122.12,43.44 125.49,43.44 133.25,51.19 135.34,51.19 v1(135.83,50.7)
BATT_LED_LV1: length 22
  TOP w0.254: v8(230.56,13.74) 230.56,14 R910.2
  IN1 w0.254: v1(222.28,24.32) 223.81,22.8 225.9,22.8 230.56,18.14 v8(230.56,13.74)
  BOTTOM w0.254: v1(222.28,24.32) 222.18,24.22 Q354.1
BATT_LED_LV2: length 22.5
  TOP w0.102: v1(229.3,10.83) 228.99,11.14 v2(228.99,11.48)
  TOP w0.254: R911.2 v1(229.3,10.83)
  IN3 w0.254: v1(223.26,25.57) 223.26,25.55 222.98,25.27 222.98,22.75 224.31,21.42 227.4,21.42 229.8,19.02 229.8,15.09 229.23,14.52 229.23,10.89 v1(229.3,10.83)
  BOTTOM w0.254: v1(223.26,25.57) 223.26,25.51 223.24,25.54 Q355.1
BATT_LED_LV3: length 24
  TOP w0.102: v2(227.36,22.54) 227.06,22.24 v1(225.24,22.24)
  TOP w0.254: R912.2 230.09,8.54 229.64,8.09 v1(229.64,7.9)
  IN3 w0.254: v1(229.64,7.9) 229.81,8.07 229.81,11.81 229.64,11.98 229.64,14.39 230.19,14.95 230.19,20.31 228.57,21.93 225.55,21.93 v1(225.24,22.24)
  BOTTOM w0.254: Q356.1 223.96,22.44 224.16,22.64 224.84,22.64 v1(225.24,22.24)
BATT_LED_LV4: length 26.2
  TOP w0.102: v1(224,25.67) 224.45,25.67 225.29,26.5 v2(225.29,26.68)
  TOP w0.254: R913.2 230.17,7.01 230.17,7.72 v1(230.31,7.86) ; v1(224,25.67) 224,26.3 223.79,26.5 Q357.1
  IN3 w0.254: v1(224,25.67) 224.43,25.67 226.64,23.46 228.14,23.46 230.55,21.04 230.55,14.74 230.02,14.21 230.02,12.14 230.31,11.85 v1(230.31,7.86)
BATT_LED_LV5: length 24.5
  TOP w0.254: R916.2 230.18,3.59 v8(229.85,3.26) ; Q358.1 224.01,22.44 v1(224.35,22.1)
  IN1 w0.254: v1(224.35,22.1) 224.77,21.68 225.81,21.68 228.78,18.71 228.78,8.99 228.02,8.23 228.02,6.46 229.85,4.64 v8(229.85,3.26)
BATT_PRS: length 8.9
  TOP w0.102: PR112.1 123.58,28.54 123.07,28.03 PD104.2 123.07,25.12 v1(123.12,25.06) 123.12,24.83 v2(123.93,24.02)
  BOTTOM w0.102: v1(123.12,25.06) 122.87,24.82 JBATT1.5
BEEP#: length 165.1
  TOP w0.076: U34.M8 139.67,58.35 v6(139.02,58.35)
  TOP w0.102: v6(40.82,46.9) 41.14,46.9 41.88,47.64 51.81,47.64 52.55,46.9 68.79,46.9 69.04,47.16 80.63,47.16 83.88,50.41 v7(85.02,50.41) 87.15,50.41 88.27,51.52 v6(88.73,51.52)
  GND1 w0.076: v6(139.02,58.35) 138.79,58.35 v4(138.61,58.18) ; v4(88.92,51.14) 88.73,51.33 v6(88.73,51.52) ; v6(40.82,46.9) 40.55,46.63 v4(40.51,46.63)
  IN1 w0.076: v4(40.51,46.63) 40.66,46.48 40.66,44.88 38.25,42.47 35.51,42.47 33.67,44.31 25.85,44.31 25.47,43.93 18.75,43.93 16.85,42.03 16.85,37.4 15.32,35.88 15.32,25.98 16.91,24.4 17.9,24.4 18.51,23.79 18.51,21.96 v1(18.14,21.59) ; v4(88.92,51.14) 88.95,51.12 89.33,51.12 89.48,51.27 93.21,51.27 93.69,50.79 95.85,50.79 96.77,49.87 97.99,49.87 100.4,47.46 109.29,47.46 110.92,49.09 110.92,50.63 114.71,54.42 123.76,54.42 124.68,55.35 126.61,55.35 127.46,56.2 129.8,56.2 130.99,57.39 133.17,57.39 134.61,55.94 138.16,55.94 138.37,56.16 138.37,57.94 v4(138.61,58.18)
  BOTTOM w0.102: v1(18.14,21.59) 17.6,21.05 JIOL1.15
BKOFF#: length 32.2
  TOP w0.102: D72.3 166.44,73.28 166.34,73.18 D73.2 164.7,73.18 164.19,72.67 162.44,72.67 162,73.11 159.68,73.11 159.32,72.75 159.32,71.88 158.54,71.11 154.11,71.11 153.65,70.65 153.65,69.74 153.3,69.38 152.05,69.38 151.91,69.24 151.91,67.23 151.57,66.89 151.57,65.72 150.26,64.41 149.28,64.41 148.91,64.04 146.49,64.04 146.04,63.59 v2(144.61,63.59) 144.19,63.59 143.33,62.73 143.33,62.43 143.42,62.33 U34.E1
BOOT0: length 4.5
  TOP w0.102: R1092.1 R819.2 156.06,67.14 156.7,66.51 156.7,65.79 v2(156.87,65.61) 157.45,65.04 157.83,65.04 U636.A6
BOOT_+1.2V: length 4
  TOP w0.203: PU601.18 v6(40.24,23.41)
  GND1 w0.254: v6(40.24,23.41) 40.24,23.13 v4(40.55,22.82)
  GND5 w0.254: v4(40.55,22.82) 40.62,22.9 v5(40.62,23.25)
  BOTTOM w0.102: v2(40.22,21.98) 39.82,22.38 PR601.2
  BOTTOM w0.203: v5(40.62,23.25) 40.44,23.08 PR601.2
BST_+1.05VS: length 3.6
  BOTTOM w0.203: v2(135.64,77.99) 136.19,78.54 PU501.5
  BOTTOM w0.254: v2(135.64,77.99) 135.31,77.66 135.31,77.38 135.06,77.13 135.06,76.97 PR506.1
BT_CS_NOTICE: length 145.3
  TOP w0.102: R1209.2 R1208.2 195.41,44.88 v1(195.41,45.54)
  IN1 w0.076: v1(195.41,45.54) 195.41,44.07 194.86,43.52 194.86,41.61 194.62,41.36 194.62,39.06 194.87,38.81 194.87,37.98 193.73,36.84 181.35,36.84 179.39,34.89 v4(179.39,34.77)
  IN3 w0.076: v4(150.35,27.91) 149.3,28.97 142.82,28.97 140.66,31.13 140.66,37.87 139.74,38.8 138.86,38.8 132.51,45.15 132.51,51.79 133.48,52.77 133.48,54.94 132.16,56.26 132.16,57.58 132.62,58.04 132.62,59.9 131.95,60.58 v4(131.95,60.99)
  IN4 w0.076: v4(131.95,60.99) 131.95,61.07 131.54,61.48 129.52,61.48 129.19,61.15 123.62,61.15 122.21,59.74 119.74,59.74 119.53,59.54 118.17,59.54 117.88,59.83 110.38,59.83 107.35,62.86 103.18,62.86 101.94,61.62 99.13,61.62 98.33,60.82 97.8,60.82 v4(97.59,60.62) ; v4(179.39,34.77) 179.39,34.63 174.2,29.44 168.53,29.44 167.66,28.57 162.64,28.57 161.78,29.44 160.76,29.44 159.24,27.91 v4(150.35,27.91)
  GND5 w0.076: v5(97.07,60.87) 97.34,60.87 v4(97.59,60.62)
  BOTTOM w0.076: v5(97.07,60.87) 96.85,60.64 UCPU1.AP1
BT_PCMCLK: length 8.9
  TOP w0.102: v1(184.27,41.85) 184.23,41.85 v2(183.83,42.25) 183.69,42.39 183.69,44.87 183.45,45.11 183.45,46.22 183.63,46.4 U677.2
  BOTTOM w0.102: JNGFF1.8 183,43.12 v1(184.27,41.85)
BT_PCMFR1: length 7.6
  TOP w0.102: v1(184.35,42.48) 183.9,42.93 183.9,43.37 184.07,43.54 v2(184.07,44.06) 184.07,44.93 183.75,45.25 183.75,45.94 183.95,46.14 183.96,46.14 184.28,46.46 U677.3
  BOTTOM w0.102: v1(184.35,42.48) 183.49,43.33 JNGFF1.10
BT_PCMIN: length 5.3
  TOP w0.102: U677.5 185.58,46.19 v1(185.66,46.11) 185.83,46.11 v2(186.41,45.54)
  BOTTOM w0.102: JNGFF1.12 184,45.38 184.73,46.11 v1(185.66,46.11)
BT_PCMOUT: length 5.9
  TOP w0.102: v1(184.35,43.12) 184.42,43.19 184.42,45.11 184.13,45.4 v2(184.13,45.55) 184.13,45.71 184.93,46.51 U677.4
  BOTTOM w0.102: JNGFF1.14 184.49,43.26 v1(184.35,43.12)
BT_RADIO_DIS#: length 137.4
  IN1 w0.076: v4(178.94,44.67) 178.45,45.15 178.45,48.75 175.17,52.04 175.17,54.43 169.64,59.95 169.64,61.71 168.16,63.2 168.16,63.72 165.97,65.91 163.75,65.91 163.46,66.21 162.64,66.21 162.14,66.71 159.65,66.71 159.16,67.2 153.48,67.2 152.52,68.16 149.7,68.16 149.1,68.76 139.03,68.76 138.83,68.55 137.08,68.55 136.38,67.86 134.43,67.86 132.87,66.29 126.75,66.29 125.8,65.34 124.93,65.34 124.11,64.52 116.44,64.52 115.36,65.6 114.37,65.6 112.54,63.77 110.41,63.77 109.54,64.63 109.54,65.19 107.32,67.41 v1(107.32,67.48)
  IN2 w0.076: v4(92.78,71.56) 93.31,71.03 93.76,71.03 94.37,71.64 98.13,71.64 98.94,70.83 100.35,70.83 102.43,68.75 105.81,68.75 107.08,67.48 v1(107.32,67.48) ; v1(192.41,39.81) 192.3,39.71 192.3,38.77 190.91,37.39 181.57,37.39 179.65,39.31 179.65,43.95 v4(178.94,44.67)
  GND5 w0.076: v5(92.76,72) 92.76,71.59 v4(92.78,71.56)
  BOTTOM w0.102: 194.49,44.27 194.49,43.5 194.69,43.31 194.69,43.05 192.7,41.07 192.7,40.5 192.41,40.2 v1(192.41,39.81) ; v1(107.32,67.48) 107.32,67.47 v2(106.76,67.47) 106.59,67.47 105.81,66.69 RH188.1 ; UCPU1.R7 92.69,71.93 v5(92.76,72)
CAB_DET_SINK: length 20.2
  BOTTOM w0.102: JMDP1.4 219.36,73.4 v2(218.89,73.87) 217.97,74.79 RV9.1 215.65,74.79 215.53,74.92 211.55,74.92 210.54,75.93 209.52,75.93 207.08,73.49 204.67,73.49 204.54,73.62 204.07,73.62 203.91,73.46 RV8.2
CAPS_LED: length 8.4
  TOP w0.102: v2(168.88,29.02) 168.28,28.42 167.11,28.42 166.9,28.21 JKB1.27
  TOP w0.229: 167.11,27.06 166.9,27.28 JKB1.27
  TOP w0.254: 167.11,27.06 171.94,27.06 R943.2
CAPS_LED#: length 68.6
  TOP w0.076: U34.B3 145.03,61.1 145.28,61.35 145.53,61.35 145.78,61.6 v6(145.78,61.63)
  TOP w0.102: v1(174.07,25.57) 174.76,25.57 175.33,24.99 Q326.3 175.33,24.04 175.19,23.9 R990.1 176.11,22.77 v2(176.16,22.82)
  GND1 w0.076: v6(145.78,61.63) 145.78,61.91 v4(145.63,62.06)
  IN1 w0.076: v4(145.63,62.06) 145.79,62.06 146.93,63.21 147.44,63.21 147.84,62.81 150.14,62.81 151.45,64.12 151.77,64.12 152.06,63.83 152.06,63.54 153.16,62.45 153.77,62.45 154.4,61.81 157.5,61.81 157.75,62.06 160.19,62.06 167.99,54.27 167.99,52.82 169.49,51.32 171.64,51.32 175.28,47.68 175.28,43.24 174.91,42.88 174.91,30.78 173.12,28.99 173.12,26.5 174.06,25.57 v1(174.07,25.57)
CFG0: length 56.9
  TOP w0.102: v6(28.33,53.3) 28.43,53.3 28.86,53.73 28.86,53.99 28.96,54.09 28.96,54.5 28.53,54.92 28.53,55.59 28.05,56.08 28.05,57.65 27.09,58.61 JXDP.9
  GND1 w0.076: v4(28.02,53.01) 28.03,53.01 v6(28.33,53.3)
  IN1 w0.076: v4(59.59,67.09) 58.95,67.73 58.16,67.73 57.74,68.15 57.74,68.28 57.5,68.52 56.03,68.52 54.12,66.61 54.12,62.6 53.47,61.95 53.47,57.01 47.81,51.35 38.53,51.35 37.7,50.52 30.53,50.52 29.93,51.12 29.14,51.12 29.06,51.04 27.75,51.04 27.27,51.52 27.27,52.49 27.72,52.94 27.95,52.94 v4(28.02,53.01)
  GND5 w0.076: v4(59.59,67.09) 59.68,67.19 v5(59.68,67.63)
  BOTTOM w0.102: UCPU1.AC60 59.92,67.39 v5(59.68,67.63)
CFG1: length 57.4
  TOP w0.102: v6(28.63,54.39) 28.63,54.54 28.3,54.87 28.3,55.39 27.82,55.88 27.82,57.4 27.12,58.11 JXDP.11
  GND1 w0.076: v4(28.26,54.1) 28.56,54.39 v6(28.63,54.39)
  IN1 w0.076: v4(58.72,67.27) 58.72,67.04 58.39,66.71 57.94,66.71 57.14,67.52 55.82,67.52 54.66,66.36 54.66,62.38 54.04,61.77 54.04,56.58 48.1,50.63 46.4,50.63 45.75,49.99 30.31,49.99 29.71,50.58 29.36,50.58 29.28,50.51 27.53,50.51 26.74,51.3 26.74,53.86 27.43,54.55 27.96,54.55 28.24,54.27 28.24,54.19 28.3,54.13 28.28,54.12 28.28,54.11 28.29,54.1 28.27,54.1 28.27,54.1 v4(28.26,54.1)
  GND5 w0.076: v5(58.34,67.62) 58.36,67.62 58.72,67.27 v4(58.72,67.27)
  BOTTOM w0.076: UCPU1.AC62 58.53,67.43 58.36,67.6
  BOTTOM w0.102: 58.36,67.6 v5(58.34,67.62)
CFG2: length 53.4
  TOP w0.102: v6(28.12,54.55) 28,54.67 28,55.27 27.6,55.66 27.6,56.62 27.12,57.11 JXDP.15
  GND1 w0.076: v4(27.68,54.14) 28.09,54.55 v6(28.12,54.55)
  IN1 w0.076: v4(58.13,67.06) 57.87,67.06 57.18,67.74 55.77,67.74 54.48,66.45 54.48,62.46 53.87,61.84 53.87,56.71 47.96,50.81 46.25,50.81 45.6,50.16 30.38,50.16 29.79,50.76 29.28,50.76 29.21,50.69 27.6,50.69 26.92,51.37 26.92,53.37 v4(27.68,54.14)
  GND5 w0.076: v5(57.66,67.43) 57.76,67.43 v4(58.13,67.06)
  BOTTOM w0.102: UCPU1.AC63 v5(57.66,67.43)
CFG3: length 60.2
  TOP w0.102: R1198.2 37.22,45.81 38.01,46.6 38.01,48.37 39.89,50.25 v6(39.91,50.25) ; JXDP.17 27.11,56.61 27.4,56.31 27.4,55.58 27.79,55.18 27.79,54.44 28.33,53.91 v6(28.33,53.68)
  GND1 w0.076: v4(40.04,50.84) 40.04,50.38 v6(39.91,50.25) ; v4(27.87,53.57) 27.98,53.68 v6(28.33,53.68)
  IN1 w0.076: v4(27.87,53.57) 27.85,53.57 27.1,52.82 27.1,51.44 27.68,50.86 29.13,50.86 29.21,50.94 29.86,50.94 30.46,50.34 39.54,50.34 v4(40.04,50.84) 40.24,51.04 47.88,51.04 53.69,56.85 53.69,61.92 54.3,62.53 54.3,66.53 55.86,68.08 57.35,68.08 v1(57.37,68.06)
  BOTTOM w0.102: UCPU1.AA63 57.93,68.11 57.47,68.11 57.37,68.01 ; 57.37,68.01 57.17,67.81 56.05,67.81 T293.1 ; 57.37,68.01 v1(57.37,68.06)
CFG4: length 57.4
  TOP w0.102: JXDP.27 27.18,54.11 27.62,53.67 27.62,52.82 v6(27.72,52.72)
  GND1 w0.076: v4(27.82,52.31) 27.72,52.41 v6(27.72,52.72)
  IN1 w0.076: v4(60.1,67.42) 59.57,67.96 58.21,67.96 57.97,68.2 57.97,68.38 57.65,68.69 55.92,68.69 53.94,66.72 53.94,62.68 53.29,62.02 53.29,57.15 47.67,51.52 38.32,51.52 37.5,50.7 30.6,50.7 29.93,51.37 28.8,51.37 28.26,51.9 27.99,51.9 27.82,52.07 v4(27.82,52.31)
  GND5 w0.076: v5(60.22,67.91) 60.22,67.91 60.28,67.86 60.28,67.6 v4(60.1,67.42)
  BOTTOM w0.102: v5(60.22,67.91) 59.95,68.18 UCPU1.AA60 59.61,68.55 57.25,68.55 56.75,68.06 v2(54.55,68.06) 54.13,68.06 RC81.1
CFG5: length 48.9
  TOP w0.102: v6(29.85,52.67) 29.85,52.57 29.65,52.36 27.62,52.36 27.39,52.59 27.39,53.4 27.19,53.61 JXDP.29
  GND1 w0.076: v6(29.85,52.67) 29.85,52.26 v4(29.88,52.24)
  IN1 w0.076: v4(58.9,68.61) 58.81,68.69 58.24,68.69 57.88,69.05 55.7,69.05 53.59,66.94 53.59,62.87 52.94,62.21 52.94,57.42 47.4,51.88 37.82,51.88 36.99,51.05 31.06,51.05 v4(29.88,52.24)
  GND5 w0.076: v5(58.8,69.3) 58.8,69.28 58.87,69.2 58.87,68.64 v4(58.9,68.61)
  BOTTOM w0.102: v5(58.8,69.3) 58.65,69.15 UCPU1.Y62
CFG6: length 47.6
  TOP w0.102: JXDP.33 27.07,52.61 27.52,52.16 29.8,52.16 v6(30.41,52.77)
  GND1 w0.076: v6(30.41,52.77) 30.41,53.1 v4(30.51,53.2)
  IN1 w0.076: v4(30.51,53.2) 30.51,53.16 30.7,52.97 32.3,52.97 32.84,52.44 37.05,52.44 37.21,52.59 46.84,52.59 52.22,57.98 52.22,62.55 52.88,63.2 52.88,67.25 55.44,69.81 57.68,69.81 58.06,70.19 58.45,70.19 v4(58.78,69.86)
  GND5 w0.076: v4(58.78,69.86) 58.78,69.72 59.15,69.35 v5(59.15,69.3)
  BOTTOM w0.102: UCPU1.Y61 59.15,69.03 v5(59.15,69.3)
CFG7: length 48.6
  TOP w0.102: v6(30.33,52.18) 30.11,51.96 27.31,51.96 27.16,52.11 JXDP.35
  GND1 w0.076: v4(30.88,52.34) 30.73,52.18 v6(30.33,52.18)
  IN1 w0.076: v4(30.88,52.34) 31.81,51.41 36.61,51.41 37.43,52.24 47.11,52.24 52.58,57.7 52.58,62.36 53.23,63.01 53.23,67.09 55.6,69.46 58.06,69.46 58.36,69.15 59.75,69.15 v4(60.27,68.63)
  GND5 w0.076: v5(60.27,69.1) v4(60.27,68.63)
  BOTTOM w0.102: UCPU1.Y60 60.06,68.89 v5(60.27,69.1)
CFG8: length 53.4
  TOP w0.102: v6(30.06,53.48) 29.88,53.66 29.88,57.85 30.63,58.61 JXDP.10 35.68,58.61 v2(35.7,58.59)
  GND1 w0.076: v4(29.93,53.1) 30.06,53.23 v6(30.06,53.48)
  IN1 w0.076: v4(58.22,69.85) 58,69.63 55.52,69.63 53.06,67.17 53.06,63.12 52.4,62.47 52.4,57.84 46.97,52.41 37.36,52.41 36.57,51.63 33.34,51.63 32.23,52.74 30.32,52.74 29.97,53.1 v4(29.93,53.1)
  GND5 w0.076: v4(58.22,69.85) 58.32,69.75 v5(58.32,69.43)
  BOTTOM w0.102: UCPU1.V62 58.57,69.68 v5(58.32,69.43)
CFG9: length 49
  TOP w0.102: JXDP.12 30.67,58.11 30.08,57.52 30.08,53.89 30.28,53.68 v6(30.39,53.68)
  GND1 w0.076: v4(31,53.53) 30.84,53.68 v6(30.39,53.68)
  IN1 w0.076: v4(31,53.53) 31.05,53.48 32.1,53.48 32.96,52.62 36.9,52.62 37.08,52.79 46.73,52.79 52.05,58.11 52.05,62.69 52.7,63.35 52.7,67.32 55.37,69.99 57.63,69.99 58.01,70.37 58.85,70.37 v4(59.35,69.86)
  GND5 w0.076: v5(59.51,69.33) 59.35,69.48 v4(59.35,69.86)
  BOTTOM w0.102: v5(59.51,69.33) 59.3,69.54 UCPU1.V61
CFG10: length 52.3
  TOP w0.102: v6(30.39,54.06) 30.38,54.07 30.38,56.85 30.63,57.11 JXDP.16 35.81,57.11 v2(36.08,56.85)
  GND1 w0.076: v6(30.39,54.06) 30.86,54.06 v4(30.91,54.11)
  IN1 w0.076: v4(59.94,69.86) 59.89,69.86 59.21,70.54 57.94,70.54 57.58,70.17 55.26,70.17 52.52,67.42 52.52,63.47 51.87,62.81 51.87,58.25 46.59,52.97 37,52.97 36.83,52.79 33.07,52.79 31.74,54.11 v4(30.91,54.11)
  GND5 w0.076: v5(59.95,69.35) 59.97,69.38 59.97,69.83 v4(59.94,69.86)
  BOTTOM w0.102: UCPU1.V60 v5(59.95,69.35)
CFG11: length 44.1
  TOP w0.102: JXDP.18 34.11,56.61 v2(34.26,56.76) 34.84,56.76 35.59,56.01 v6(35.59,54.8)
  GND1 w0.076: v4(35.95,54.62) 35.77,54.8 v6(35.59,54.8)
  IN1 w0.076: v4(35.95,54.62) 35.95,54.46 36.72,53.68 46,53.68 50.67,58.35 50.67,67.99 51.14,68.47 52.55,68.47 55.75,71.67 58.86,71.67 v4(59.49,71.03)
  GND5 w0.076: v4(59.49,71.03) 59.68,70.84 v5(59.68,70.62)
  BOTTOM w0.102: UCPU1.U60 59.92,70.39 v5(59.68,70.62)
CFG12: length 40
  TOP w0.102: v6(33.2,53.91) 33.01,54.11 JXDP.28
  GND1 w0.076: v6(33.2,53.91) 32.91,53.62 v4(32.91,53.53)
  IN1 w0.076: v4(32.91,53.53) 33.47,52.97 36.75,52.97 36.93,53.15 46.41,53.15 51.69,58.43 51.69,62.89 52.34,63.54 52.34,67.5 55.19,70.35 57.13,70.35 v4(57.54,70.75)
  GND5 w0.076: v5(58,70.83) 57.61,70.83 v4(57.54,70.75)
  BOTTOM w0.102: UCPU1.T63 v5(58,70.83)
CFG13: length 45.9
  TOP w0.102: JXDP.30 34.18,53.61 34.82,54.24 35.77,54.24 v6(36.41,54.88) 36.41,55.75 v2(37.79,57.14)
  GND1 w0.076: v6(36.41,54.88) 36.41,55.04 v4(36.1,55.35)
  IN1 w0.076: v4(58.51,72.01) 58.47,72.05 55.88,72.05 52.47,68.64 51.02,68.64 50.49,68.11 50.49,58.42 45.93,53.86 37.31,53.86 36.1,55.07 v4(36.1,55.35)
  GND5 w0.076: v5(58.62,71.54) 58.62,71.9 v4(58.51,72.01)
  BOTTOM w0.102: UCPU1.T62 58.65,71.51 v5(58.62,71.54)
CFG14: length 43.8
  TOP w0.102: v6(36.79,54.93) 36.79,54.69 v2(35.47,53.37) 35.06,52.96 33.87,52.96 33.51,52.61 JXDP.34
  GND1 w0.076: v6(36.79,54.93) 36.79,55.26 v4(36.68,55.36)
  IN1 w0.076: v4(59.07,72.01) 59.06,72.01 58.71,72.35 55.93,72.35 52.4,68.82 50.95,68.82 50.31,68.19 50.31,58.49 45.86,54.04 38.42,54.04 37.1,55.36 v4(36.68,55.36)
  GND5 w0.076: v4(59.07,72.01) 59.02,71.96 v5(59.02,71.58)
  BOTTOM w0.102: v5(59.02,71.58) 59.3,71.3 UCPU1.T61
CFG15: length 43.5
  TOP w0.102: JXDP.36 33.37,52.11 34.02,52.76 35.36,52.76 v2(36.93,54.32) v6(38.08,54.32)
  GND1 w0.076: v6(38.08,54.32) 38.36,54.6 v4(38.51,54.6)
  IN1 w0.076: v4(38.51,54.6) 38.89,54.22 45.78,54.22 50.13,58.57 50.13,68.26 50.87,69 52.33,69 55.86,72.53 59.17,72.53 v4(59.67,72.03)
  GND5 w0.076: v5(59.64,71.62) 59.64,72 v4(59.67,72.03)
  BOTTOM w0.102: UCPU1.T60 59.95,71.31 v5(59.64,71.62)
CFG16: length 52.5
  TOP w0.102: JXDP.6 30.71,59.61 29.67,58.57 29.67,52.92 29.45,52.69 v6(29.45,52.67)
  GND1 w0.076: v6(29.45,52.67) 29.45,52.4 v4(29.28,52.24)
  IN1 w0.076: v4(29.28,52.24) 29.32,52.24 30.68,50.88 37.27,50.88 38.09,51.7 47.53,51.7 53.11,57.28 53.11,62.1 53.77,62.75 53.77,66.81 55.82,68.87 57.84,68.87 v4(58.4,68.31)
  GND5 w0.076: v4(58.4,68.31) 58.4,68.08 v5(58.65,67.83)
  BOTTOM w0.102: UCPU1.AA62 v5(58.65,67.83)
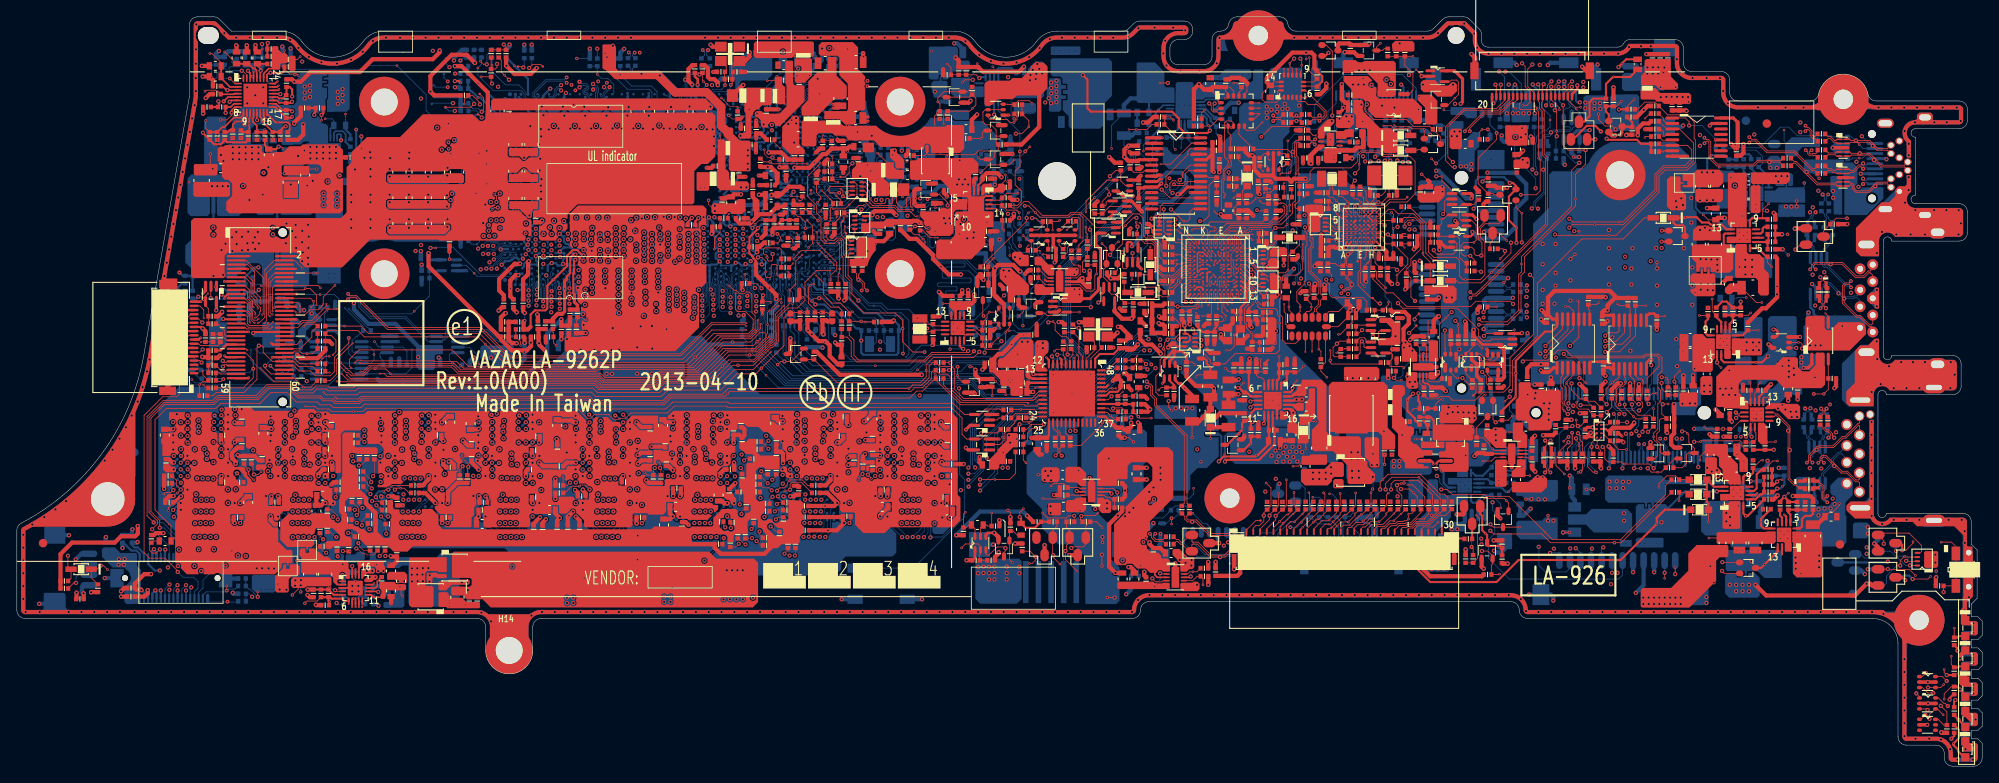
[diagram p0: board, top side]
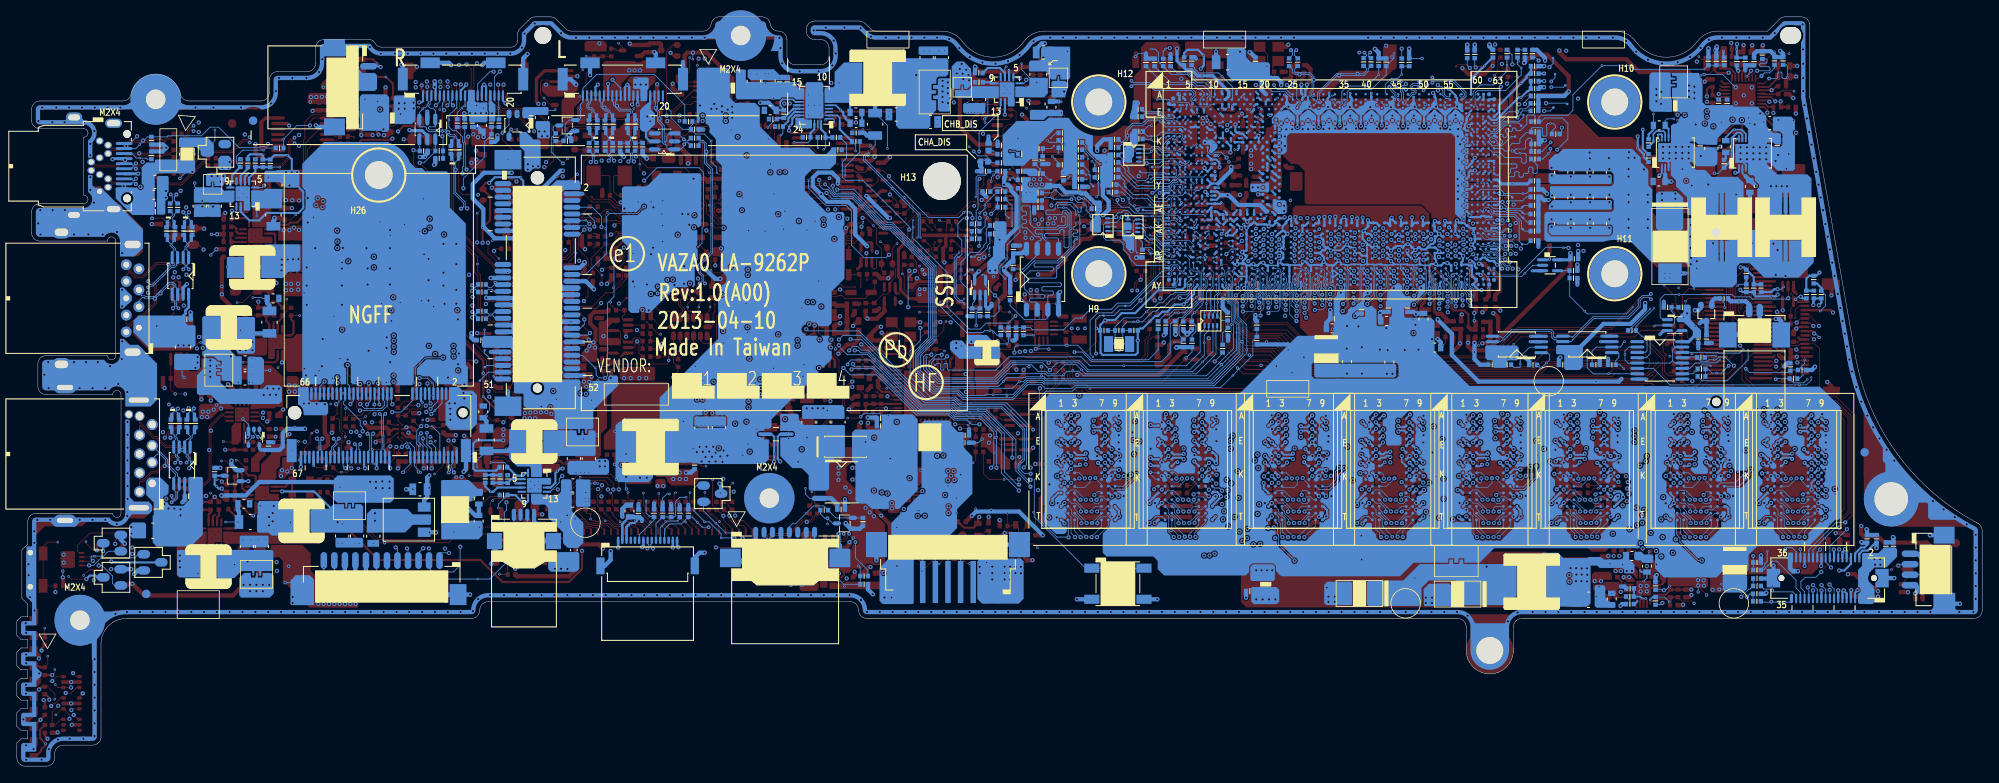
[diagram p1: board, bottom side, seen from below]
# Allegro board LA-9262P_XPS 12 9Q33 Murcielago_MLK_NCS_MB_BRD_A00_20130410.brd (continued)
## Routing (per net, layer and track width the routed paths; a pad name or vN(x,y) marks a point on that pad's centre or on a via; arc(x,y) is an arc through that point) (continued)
CFG17: length 57.7
  TOP w0.102: v2(33.93,59.17) 32.99,60.11 JXDP.4 30.6,60.11 29.47,58.98 29.47,53.35 28.81,52.69 v6(28.63,52.69)
  GND1 w0.076: v6(28.63,52.69) 28.94,52.69 v4(29.01,52.77)
  IN1 w0.076: v4(59.51,68.44) 59.51,68.54 59.07,68.97 58.24,68.97 57.96,69.25 55.65,69.25 53.41,67.02 53.41,62.94 52.76,62.29 52.76,57.56 47.26,52.06 37.66,52.06 36.84,51.23 31.43,51.23 30.45,52.21 30.45,52.31 30.12,52.64 29.14,52.64 v4(29.01,52.77)
  GND5 w0.076: v5(59.3,67.86) 59.3,68.23 v4(59.51,68.44)
  BOTTOM w0.102: UCPU1.AA61 v5(59.3,67.86)
CFG18: length 40.2
  TOP w0.102: v6(33.59,53.91) 33.64,53.96 v2(33.64,54.52) 33.64,54.78 33.31,55.11 JXDP.24
  GND1 w0.076: v4(33.57,53.51) 33.57,53.9 v6(33.59,53.91)
  IN1 w0.076: v4(56.97,70.75) 56.85,70.63 55.23,70.63 52.17,67.57 52.17,63.61 51.51,62.96 51.51,58.56 46.28,53.33 33.75,53.33 v4(33.57,53.51)
  GND5 w0.076: v4(56.97,70.75) 57.45,70.27 v5(57.56,70.27)
  BOTTOM w0.102: UCPU1.U63 57.97,70.43 57.79,70.24 57.59,70.24 v5(57.56,70.27)
CFG19: length 41.5
  TOP w0.102: JXDP.22 34.89,55.61 v2(35.25,55.24) 35.25,54.84 v6(34.96,54.55)
  GND1 w0.076: v4(35.38,54.37) 35.14,54.37 v6(34.96,54.55)
  IN1 w0.076: v4(58.34,71.11) 57.98,71.46 55.8,71.46 51.99,67.65 51.99,63.69 51.34,63.04 51.34,58.69 50.54,57.89 50.53,57.89 46.14,53.51 36.47,53.51 35.68,54.29 35.45,54.29 v4(35.38,54.37)
  GND5 w0.076: v4(58.34,71.11) 58.39,71.06 v5(58.39,70.68)
  BOTTOM w0.102: UCPU1.U62 58.64,70.43 v5(58.39,70.68)
CFG_RCOMP: length 4.7
  BOTTOM w0.305: UCPU1.V63 57.58,69.68
  BOTTOM w0.381: 57.58,69.68 57.11,69.2 v2(55.85,69.2) 54,69.2 RC153.1
CHG_LGATE: length 11.6
  IN2 w1.016: 154.68,33.11 153.49,33.11 152.85,33.74 152.85,35.27 153.66,36.08 153.66,39.48 152.17,40.98 150.82,40.98
  vias: v1(150.87,41.94) v1(156.69,33.29) v8(157.37,33.29)
CHG_LX: length 1
  BOTTOM w0.102: v7(161.07,32.93) 161.14,33.01 161.14,33.87
  vias: v1(158.55,37.3) v1(158.57,36.54) v1(158.63,35.09) v1(158.66,34.28) v1(159.33,37.3) v1(159.33,36.54) v1(159.43,35.09) v1(159.46,34.28) v1(161.11,34.38)
CHG_UGATE: length 11.5
  IN2 w1.016: 161.36,36.89 161.36,38.95 157.3,43.01 153.61,43.01
  vias: v1(152.04,43.57) v1(152.67,43.57) v1(160.98,35.78) v1(161.63,35.8) v7(161.12,37.11)
CL_CK: length 149
  TOP w0.102: v1(193.8,39.73) 194.43,40.36 R1212.2
  IN3 w0.076: v4(170.16,67.88) 170.53,68.25 173.44,68.25 174.78,66.9 174.78,57.57 175.74,56.62 175.74,48.79 178.59,45.94 179.22,45.94 179.51,45.65 179.51,44.34 178.48,43.31 178.48,39.44 180.27,37.65 180.27,36.58 180.04,36.35 178.81,36.35 178.3,35.84 178.3,34.01 178.79,33.53 188.18,33.53 192.54,37.88 194.46,37.88 194.85,38.28 194.85,38.94 194.06,39.73 v1(193.8,39.73)
  IN4 w0.076: v4(95.59,66.79) 95.94,66.43 97.18,66.43 97.24,66.5 99.33,66.5 100.08,67.25 101.19,67.25 101.86,67.91 106.28,67.91 106.68,68.31 109.1,68.31 109.68,67.73 111.82,67.73 112.2,68.11 117.77,68.11 117.96,67.92 119.34,67.92 120.73,66.52 121.34,66.52 121.94,65.93 126.26,65.93 126.65,66.32 129.4,66.32 129.68,66.6 132.76,66.6 134.27,68.11 134.27,69.58 134.74,70.05 135.42,70.05 135.98,70.61 138.57,70.61 139.12,70.05 139.12,69.49 140.12,68.49 145.92,68.49 145.97,68.44 148.89,68.44 149.54,67.79 152.2,67.79 152.95,67.04 158.83,67.04 159.19,67.41 161.69,67.41 163.18,65.93 164.57,65.93 164.76,66.12 166.51,66.12 167.5,67.11 169.39,67.11 v4(170.16,67.88)
  GND5 w0.076: v5(95.8,66.24) 95.59,66.46 v4(95.59,66.79)
  BOTTOM w0.076: v5(95.8,66.24) 95.97,66.07 UCPU1.AF2
CL_DAT: length 145.5
  TOP w0.102: R1210.2 193.15,39.98 v1(193.15,39.74)
  IN3 w0.076: v1(193.15,39.74) 193.15,39.12 192.88,38.85 192.51,38.85 191.67,38 191.67,37.27 188.11,33.71 178.87,33.71 178.49,34.09 178.49,35.78 178.87,36.16 180.11,36.16 180.45,36.5 180.45,37.72 178.67,39.5 178.67,43.25 179.69,44.26 179.69,45.72 179.25,46.15 178.66,46.15 175.91,48.89 175.91,56.69 174.96,57.65 174.96,66.98 173.51,68.43 170.02,68.43 v4(169.97,68.48)
  IN4 w0.076: v4(96.31,66.8) 96.53,66.59 97.06,66.59 97.16,66.69 99.27,66.69 100.01,67.42 101.12,67.42 101.78,68.08 106.2,68.08 106.61,68.49 109.17,68.49 109.75,67.91 111.74,67.91 112.13,68.29 117.85,68.29 118.04,68.1 119.41,68.1 120.81,66.7 121.42,66.7 122.01,66.1 126.18,66.1 126.58,66.5 129.32,66.5 129.6,66.78 132.68,66.78 133.99,68.08 133.99,69.58 134.64,70.23 135.33,70.23 135.88,70.79 138.64,70.79 139.3,70.13 139.3,69.56 140.19,68.67 145.99,68.67 146.04,68.62 148.96,68.62 149.61,67.97 152.28,67.97 153.03,67.22 158.75,67.22 159.12,67.59 161.76,67.59 163.25,66.1 164.49,66.1 164.68,66.29 166.43,66.29 167.42,67.28 168.98,67.28 169.97,68.28 v4(169.97,68.48)
  GND5 w0.076: v4(96.31,66.8) 96.15,66.8 v5(95.97,66.98)
  BOTTOM w0.076: v5(95.97,66.98) 95.97,66.64 UCPU1.AD2
CL_RST#: length 154.3
  TOP w0.102: v1(191,41.82) 189.97,42.85 189.97,43.19 190.08,43.29 190.08,44.03 R1200.2 ; v2(183.79,38.62) 184.3,39.13 v3(184.36,39.13)
  IN1 w0.076: v1(191,41.82) 193.86,41.82 194.27,41.41 194.27,38.91 194.51,38.67 194.51,38.13 193.65,37.26 186.23,37.26 v3(184.36,39.13)
  IN4 w0.076: v3(184.36,39.13) 183.99,39.5 183.99,39.81 183.85,39.95 183.85,47.61 184.49,48.25 184.49,49.35 183.83,50.01 183.83,63.47 182.28,65.02 182.28,68.24 180.89,69.63 179.95,69.63 178.67,70.92 175.96,70.92 174.43,72.44 170.64,72.44 169.82,71.62 169.82,70.25 169.24,69.67 168.45,69.67 167.84,69.06 167.84,68.35 165.96,66.47 164.61,66.47 164.42,66.28 163.32,66.28 161.84,67.77 159.05,67.77 158.68,67.4 153.1,67.4 152.35,68.15 149.68,68.15 149.04,68.8 146.12,68.8 146.06,68.85 140.27,68.85 139.48,69.63 139.48,70.2 138.71,70.97 135.8,70.97 135.25,70.42 134.54,70.42 132.58,68.46 131.96,68.46 130.45,66.95 129.53,66.95 129.25,66.67 126.5,66.67 126.11,66.28 122.09,66.28 121.49,66.88 120.88,66.88 119.48,68.28 118.11,68.28 117.92,68.47 112.05,68.47 111.67,68.08 109.83,68.08 109.24,68.67 106.54,68.67 106.13,68.26 101.71,68.26 101.05,67.6 99.93,67.6 99.21,66.88 97.04,66.88 96.72,67.2 94.77,67.2 94.23,66.65 v4(94.23,66.6)
  GND5 w0.076: v5(94.41,66.13) 94.41,66.42 v4(94.23,66.6)
  BOTTOM w0.076: v5(94.41,66.13) 94.67,65.86 UCPU1.AF4
CLK_LPC_DEBUG: length 136.9
  TOP w0.102: v6(91.65,58.73) 91.73,58.65 RH386.2
  GND1 w0.076: v6(91.65,58.73) 91.65,58.88 v4(92.04,59.27)
  IN2 w0.076: v1(175.33,31.36) 175.2,31.48 175.2,41.36 172.54,44.03 171.18,44.03 169.48,45.73 169.48,46.8 168.48,47.79 v4(167.95,47.79)
  IN4 w0.076: v4(167.95,47.79) 167.95,47.65 149.83,47.65 149.05,46.88 147.24,46.88 147.05,47.07 141.83,47.07 140.34,45.58 135.74,45.58 134.82,44.65 134.07,44.65 129.1,49.63 126.55,49.63 123.87,52.31 116.47,52.31 115.12,50.97 112.12,50.97 109.18,48.02 106.8,48.02 106.39,48.43 105.07,48.43 104.87,48.22 100.96,48.22 99.02,50.16 99.02,53.53 95.36,57.19 95.02,57.19 93.89,58.32 93.4,58.32 93.09,58.64 92.68,58.64 v4(92.04,59.27)
  BOTTOM w0.102: v1(175.33,31.36) 175.33,30.42 175.58,30.16 175.58,27.65 174.84,26.9 174.84,24.71 177.31,22.24 v2(178.73,22.24) 190.29,22.24 190.78,22.72 JDEBUG.7
CLK_PCI_LPC: length 57.4
  TOP w0.102: U34.N5 138.99,60.1 138.31,60.78 v6(137.8,60.78) 137.31,60.78 MR226.1 ; v6(97.11,59.6) v2(96.18,60.53) 95.43,61.28 93.2,61.28 92.21,60.29 RH360.2
  GND1 w0.076: v6(137.8,60.78) 137.41,60.39 v4(137.28,60.39) ; v4(97.86,59.58) 97.84,59.6 v6(97.11,59.6)
  IN1 w0.076: v4(137.28,60.39) 134.06,60.39 133.07,61.38 132.07,61.38 131.74,61.71 129.59,61.71 128.72,60.83 123.12,60.83 122.94,60.66 121.8,60.66 120.95,59.8 117.25,59.8 116.54,60.52 108.87,60.52 106.76,62.63 101.74,62.63 101.2,62.09 98.78,62.09 98.55,61.86 98.55,61.32 98.28,61.05 98.28,60.39 98.41,60.26 99.63,60.26 99.75,60.13 99.75,59.8 99.65,59.7 97.99,59.7 v4(97.86,59.58)
CLK_PCI_TPM: length 73.9
  TOP w0.102: RH428.2 91.75,59.27 v6(92.23,59.75) ; U652.21 141.43,70.12 141.61,69.94 MR976.1 141.65,69.04 141.65,65.42 141.02,64.78 v8(140.58,64.78)
  GND1 w0.076: v6(92.23,59.75) 92.54,59.45 v4(92.58,59.45)
  IN2 w0.076: v4(92.58,59.45) 92.4,59.63 91.71,59.63 91.16,60.19 91.16,62.17 91.9,62.92 91.9,64.35 91.21,65.05 91.21,65.57 91.52,65.89 94.3,65.89 96.51,63.68 97.82,63.68 98.98,62.52 100.75,62.52 101.06,62.84 105.78,62.84 106.09,62.52 106.92,62.52 109.38,60.06 116.39,60.06 116.73,59.72 116.73,58.83 117.17,58.39 120.47,58.39 120.59,58.52 124.77,58.52 125.65,59.4 128.85,59.4 129.41,59.96 129.41,61.24 131.45,63.28 136.47,63.28 137.07,63.88 137.98,63.88 138.16,64.06 139.62,64.06 140.34,64.78 v8(140.58,64.78)
CLK_PCIE2: length 160.2
  IN1 w0.076: v4(71.32,78.37) 71.38,78.31 71.38,77.75 71.63,77.5 72.18,77.5 72.35,77.67 75.5,77.67 75.62,77.56 85.09,77.56 87.41,75.24 88.46,75.24 88.89,74.82 92.84,74.82 93.27,74.38 94.13,74.38 94.59,74.84 96.18,74.84 96.29,74.94 100.6,74.94 102.72,72.82 103.57,72.82 103.83,72.56 108.07,72.56 109.78,70.85 120.16,70.85 121.63,72.33 126.35,72.33 129.19,69.48 132.15,69.48 132.71,70.04 133.65,70.04 134.45,70.84 135.35,70.84 135.89,71.38 150.66,71.38 150.84,71.56 151.39,72.11 155.91,72.11 156.81,73.01 165.02,73.01 166.28,71.74 166.28,68.8 169.01,66.08 170.26,66.08 172.33,64.01 172.33,63.23 174.47,61.09 174.47,59.59 178.47,55.59 178.47,52.96 179.07,52.36 188.81,52.36 189.99,51.17 189.99,46.32 188.13,44.45 188.13,40.26 190.53,37.85 191.13,37.85 192,38.72 192.89,38.72 192.94,38.67 192.94,38.53 v3(192.69,38.28)
  GND5 w0.076: v4(71.32,78.37) v5(71.32,78.88)
  BOTTOM w0.102: v3(192.69,38.28) 192.87,38.1 192.87,37.69 192.75,37.57 JNGFF1.39
CLK_PCIE2#: length 160.1
  IN1 w0.076: v3(193.35,38.28) 193.1,38.53 193.1,38.73 192.95,38.88 191.93,38.88 191.07,38.01 190.6,38.01 188.28,40.32 188.28,44.39 190.15,46.25 190.15,51.24 188.87,52.52 179.13,52.52 178.62,53.03 178.62,55.66 174.63,59.65 174.63,61.15 172.49,63.3 172.49,64.07 170.32,66.24 169.07,66.24 166.44,68.87 166.44,71.81 165.08,73.16 156.74,73.16 155.85,72.27 151.33,72.27 150.73,71.67 150.6,71.54 135.82,71.54 135.28,71 134.39,71 133.58,70.19 132.64,70.19 132.09,69.64 129.26,69.64 126.41,72.48 121.57,72.48 120.09,71.01 109.85,71.01 108.13,72.72 103.89,72.72 103.64,72.97 102.79,72.97 100.67,75.1 96.22,75.1 96.12,74.99 94.53,74.99 94.07,74.54 93.34,74.54 92.9,74.97 88.95,74.97 88.53,75.4 87.47,75.4 85.16,77.72 75.68,77.72 75.57,77.83 72.28,77.83 72.11,77.66 71.69,77.66 71.54,77.81 71.54,78 71.65,78.1 v4(71.88,78.1)
  GND5 w0.076: v4(71.88,78.1) v5(71.88,78.55)
  BOTTOM w0.102: v3(193.35,38.28) 193.12,38.05 193.12,37.6 193.24,37.48 JNGFF1.41
CLK_REQ2#: length 6.1
  TOP w0.102: v1(193.76,35.39) 194.22,34.94 v2(194.94,34.94) 195.37,34.94 RH410.1 196.99,36.56 Q346.3
  BOTTOM w0.102: JNGFF1.45 194.24,35.88 v1(193.76,35.39)
CLK_SMB: length 10.8
  TOP w0.102: v2(128.95,28.36) 128.26,29.04 PR109.1 127.01,28.52 PD103.2 127.01,26.38 126.7,26.07 125.42,26.07 v1(125.28,25.93)
  BOTTOM w0.102: v1(125.28,25.93) 125.87,25.34 JBATT1.7
CLKOUT_LPC0: length 8.9
  TOP w0.102: v1(89.79,60.86) 89.79,60.16 89.67,60.03 89.3,60.03 89.17,60.16 v2(89.17,60.44) 89.17,60.64 89.05,60.77 88.84,60.77 88.72,60.9 88.72,61.47 88.84,61.59 90.61,61.59 90.82,61.38 RH360.1 RH428.1
  BOTTOM w0.102: UCPU1.AN15 89.2,61.45 v1(89.79,60.86)
CLKOUT_LPC1: length 8.1
  TOP w0.102: v1(88.06,60.46) 88.51,60.46 88.95,60.03 v2(88.95,58.72) 88.95,58.18 89.07,58.05 89.5,58.05 89.62,58.18 89.62,59.5 89.75,59.63 90.19,59.63 90.32,59.5 90.32,58.38 90.45,58.25 RH386.1
  BOTTOM w0.102: v1(88.06,60.46) 88.4,60.8 UCPU1.AP15
CMSRC: length 26.6
  TOP w0.254: v6(149.28,45.91) 149.21,45.83 PU201.3 ; PR203.2 166.11,41.12 166.11,41.33 165.21,42.23 v2(165.21,43.5) 165.21,43.59 v1(165.88,44.26)
  GND1 w0.254: v6(149.28,45.91) v4(149.28,45.45)
  IN2 w0.254: v4(149.28,45.45) 149.17,45.57 149.17,46.07 149.93,46.82 165.7,46.82 166.71,45.82 166.71,45.22 165.88,44.4 v1(165.88,44.26)
COMP: length 2.5
  TOP w0.102: v2(31.8,85.04) 31.8,84.51
  TOP w0.203: PU701.26 29.32,82.3 29.92,82.89 30.49,82.89
CONSOLE_RX: length 49
  TOP w0.076: U636.D3 159.8,63.07 159.8,62.19 159.66,62.05 159.66,61.68
  TOP w0.102: 159.66,61.68 159.66,59.02 159.35,58.71 159.35,57.16 160.89,55.63 T261.1 161.74,54.98 v1(161.96,54.98) ; v3(172.63,75.46) 172.63,75.81 174.31,77.5 176.26,77.5 177.67,78.9 177.96,78.9 178.28,79.23 JSNRDG.14
  IN3 w0.076: v1(161.96,54.98) 162.44,54.5 166.22,54.5 166.55,54.83 166.55,57.65 165.64,58.56 165.64,60.13 167.74,62.23 167.74,67.14 168.49,67.89 168.49,69.08 170.02,70.61 170.02,72.17 170.16,72.31 170.16,73.9 169.78,74.28 169.78,75.34 170.5,76.06 172.03,76.06 v3(172.63,75.46)
CONSOLE_TX: length 38.5
  TOP w0.076: 159.45,61.68 159.45,61.71 159.29,61.86 159.29,62.57 U636.D2
  TOP w0.102: v3(172.04,75.45) 172.04,75.51 174.26,77.74 176.21,77.74 177.78,79.31 JSNRDG.15 ; 159.45,61.68 159.45,61.43 v6(159.29,61.27) 159.29,60.04 T260.1
  GND1 w0.076: v6(159.29,61.27) 159.39,61.27 v4(159.64,61.52)
  IN3 w0.076: v3(172.04,75.45) 171.62,75.87 170.63,75.87 169.96,75.2 169.96,74.41 170.34,74.03 170.34,72.24 170.2,72.1 170.2,70.54 168.66,69 168.66,67.81 167.91,67.06 167.91,62.16 166.68,60.92 v1(166.68,60.06)
  IN4 w0.076: v4(159.64,61.52) 159.64,60.96 159.94,60.66 161.11,60.66 161.39,60.38 166.36,60.38 v1(166.68,60.06)
CPU_B+: length 3.3
  TOP w0.508: PR717.1 33.41,74.43 34.03,75.06 v1(34.03,76.26)
  vias: v1(26.36,77.56) v1(27.03,76.26) v1(34.2,80.76) v1(34.2,80.05) v1(34.2,79.36) v1(34.82,80.9) v1(34.83,80.25) v1(34.83,79.54) v1(36.44,68.06) v1(36.44,67.42) v1(36.44,66.66) v1(38.04,68.03) v1(38.04,67.27) v1(38.03,66.61) v2(27.73,77.05)
CPU_EDP_HPD#: length 27.6
  TOP w0.102: RC148.2 112.93,80.15 QC5.3 110.17,80.15 109.42,79.4 v2(109.42,78.94) 109.67,78.69 109.67,77.88 RC160.1 109.04,77.24 v6(109.04,76.28)
  GND1 w0.076: v4(108.59,76.28) v6(109.04,76.28)
  IN1 w0.076: v4(93.12,78.24) 94.15,79.27 96.39,79.27 97.95,77.71 100.95,77.71 103.42,75.23 107.55,75.23 v4(108.59,76.28)
  GND5 w0.076: v5(93.23,77.67) 93.23,78.14 v4(93.12,78.24)
  BOTTOM w0.102: UCPU1.D6 93.25,77.7 v5(93.23,77.67)
CPU_PATH_EN: length 5.4
  BOTTOM w0.102: v2(38.96,52.3) 38.84,52.41 U697.2 36.76,52.41 36.55,52.63 36.55,53.71 36.91,54.08 R1325.2 R1324.2
CPU_PATH_EN_G: length 15.3
  BOTTOM w0.102: U663.15 36.43,49.81 ; 36.43,49.81 36.48,49.81 36.77,49.52 36.77,48.2 ; 36.43,49.81 36.67,50.05 36.67,51.3 36.2,51.76 U697.4 ; 36.77,48.2 36.48,47.9 U663.12 ; 36.77,48.2 37.07,47.9 U663.5 40.99,47.89 42.06,47.89 42.44,48.27 v2(42.44,48.93) 42.44,49.34 41.97,49.81 U663.2
CPU_XDP_TCK: length 75.4
  TOP w0.102: v1(60.17,83.03) 60.06,83.15 T265.1
  IN1 w0.076: v4(59.89,77.05) 59.46,77.05 59.15,76.75 58.29,76.75 55.67,79.36 53.43,79.36 52.44,78.37 50.89,78.37 45.05,72.53 45.05,69.79 42.84,67.58 42.84,67.22 40.7,65.07 40.7,63.55 33.14,55.99 30.48,55.99 30.19,55.99 29.63,55.44 27.03,55.44 26.93,55.33 26.4,54.8 22.98,54.8 21.86,53.68 19.12,53.68 18.16,52.72 18.16,47.84 19.76,46.24 20.64,46.24 v4(20.85,46.44)
  IN4 w0.076: v4(59.89,77.05) 60.47,77.64 60.47,82.73 v1(60.17,83.03)
  GND5 w0.076: v5(21.33,46.44) v4(20.85,46.44) ; v5(59.96,77.58) 59.96,77.13 v4(59.89,77.05)
  BOTTOM w0.102: RH446.1 21.71,46.06 v5(21.33,46.44) ; RC52.1 60.29,83.15 v1(60.17,83.03) ; v5(59.96,77.58) 59.96,77.22 UCPU1.E60
CPU_XDP_TDI: length 65.7
  TOP w0.102: v1(55.23,77.77) 55.47,78.01 55.47,79.4 T268.1
  IN1 w0.076: v4(30.77,48.7) 30.44,49.03 26.94,49.03 26.18,49.8 26.18,54.08 27.18,55.08 29.78,55.08 30.34,55.64 33.29,55.64 41.08,63.42 41.08,64.95 42.56,66.43 44.32,66.43 45.41,67.53 45.41,70.37 47.44,72.4 52.09,72.4 55.68,76 55.68,77.32 v1(55.23,77.77)
  GND5 w0.076: v5(31.13,48.32) 31.13,48.34 v4(30.77,48.7)
  BOTTOM w0.102: v5(31.13,48.32) 31.54,47.92 34.08,47.92 34.73,47.27 U663.11 ; UCPU1.F63 57.66,76.42 56.31,77.77 v1(55.23,77.77) 54.89,78.12 54.2,78.12 53.65,78.67 RC46.1
CPU_XDP_TDO: length 85.9
  TOP w0.102: v1(55.23,77.08) 54.87,77.44 T269.1
  IN1 w0.076: v4(20.29,46.65) 19.83,46.65 18.33,48.15 18.33,52.64 19.2,53.51 21.94,53.51 23.06,54.62 26.47,54.62 27.1,55.26 29.7,55.26 30.26,55.82 30.41,55.82 30.41,55.82 33.22,55.82 40.88,63.47 40.88,65 43.02,67.15 43.02,67.5 45.23,69.71 45.23,72.46 49.86,77.08 v1(55.23,77.08)
  GND5 w0.076: v5(20.31,46.22) 20.29,46.24 v4(20.29,46.65)
  BOTTOM w0.102: UCPU1.F62 58.32,76.1 57.65,76.1 56.67,77.08 v1(55.23,77.08) 54.81,77.51 54.81,77.69 54.62,77.88 RC48.1 ; v5(20.31,46.22) 20.31,45.87 20.87,45.31 37.09,45.31 39.05,47.27 U663.6
CPU_XDP_TMS: length 69.1
  TOP w0.102: v1(54.33,78.7) 53.93,78.31 T266.1
  IN1 w0.076: v4(28.14,49.97) 27.78,50.33 27.35,50.33 26.54,51.14 26.54,53.94 27.32,54.72 29.93,54.72 30.48,55.28 33.5,55.28 41.46,63.24 41.46,64.2 41.83,64.57 42.95,64.57 45.84,67.45 45.84,68.47 49.22,71.84 52.47,71.84 56.27,75.64 56.27,78.28 55.44,79.11 54.73,79.11 v1(54.33,78.7)
  IN4 w0.076: v1(54.33,78.7) 54.71,79.08 56.91,79.08 58.76,77.23 v4(58.97,77.23)
  GND5 w0.076: v4(28.14,49.97) 28.37,49.75 v5(28.37,49.54) ; v4(58.97,77.23) 59.33,76.87 v5(59.33,76.85)
  BOTTOM w0.102: RC45.1 54.33,78.93 v1(54.33,78.7) ; v5(59.33,76.85) 59.3,76.88 UCPU1.E61 ; U663.14 31.41,49.17 31.33,49.09 28.82,49.09 v5(28.37,49.54)
CPU_XDP_TRST#: length 57.6
  TOP w0.102: v1(60.87,82.97) 61.28,83.39 62.25,83.39 T267.1
  IN1 w0.076: v4(60.38,76.75) 60.37,76.75 60.04,76.42 60.04,73.55 59.58,73.09 59.35,73.09 59.05,72.78 55.86,72.78 52.25,69.18 50.8,69.18 49.96,68.34 49.96,58.64 45.71,54.39 39.29,54.39 38.88,54.8 v4(38.88,55.05)
  IN4 w0.076: v1(60.87,82.97) 60.7,82.8 60.7,77.06 v4(60.38,76.75)
  GND5 w0.076: v4(38.88,55.05) 38.98,54.95 v5(38.98,54.44) ; v4(60.38,76.75) 60.48,76.85 v5(60.83,76.85)
  BOTTOM w0.102: v1(60.87,82.97) 61.18,83.28 RC54.1 ; UCPU1.E59 60.6,77.05 60.8,76.85 v5(60.83,76.85) ; U663.3 40.01,49.17 39.82,49.36 39.82,50.56 40.37,51.1 40.47,51.1 RH370.2 41.14,52.24 38.98,54.39 v5(38.98,54.44)
CS_+1.2V: length 2.4
  TOP w0.203: PR604.2 42.82,21.93 42.82,21.4 42.59,21.17 PU601.13
CSN1: length 55.2
  TOP w0.203: PC708.1 31.55,77.97 30.8,78.72 PU701.18
  TOP w0.254: PC708.1 32.56,77.97 v1(32.71,77.81)
  IN2 w0.254: v1(24.3,56.05) 24.38,56.12 25.75,56.12 26.69,57.06 26.69,58.25 29.79,61.35 29.79,63.28 29.92,63.41 30.22,63.41 v1(30.42,63.21) ; v1(32.71,77.81) 32.84,77.69 34.08,77.69 34.97,76.8 37.33,76.8 39.52,74.62 39.52,68.85 38.98,68.31 38.98,64.94 36.21,62.17 36.21,58.74 35.52,58.05 29.36,58.05 28.75,57.44 v1(28.75,56.6)
  BOTTOM w0.254: v1(30.42,63.21) 30.94,62.69 PL701.3 ; v1(24.3,56.05) 24.51,55.84 v2(25.04,55.84) 26.92,55.84 27.13,56.06 PR707.2 PR708.2 28.49,56.35 v1(28.75,56.6)
CSN2: length 65.6
  TOP w0.203: PC716.1 31.17,78.83 30.88,79.12 PU701.19
  TOP w0.254: PC716.1 32.57,78.83 v1(32.7,78.96)
  IN2 w0.254: v8(23.35,63.17) 23.24,63.28 22.85,63.28 22.58,63 22.58,55.99 21.84,55.26 20.52,55.26 v1(20.06,54.8) ; v1(32.7,78.96) 32.82,79.08 33.2,79.08 33.8,78.49 36.29,78.49 39.94,74.84 39.94,72.03 40.86,71.11 40.86,64.38 37.36,60.87 37.36,58.38 36.21,57.24 31.97,57.24 30.63,55.89 27.46,55.89 26.81,55.24 23.41,55.24 22.17,54.01 19.95,54.01 19.4,54.56 v1(19.4,54.78)
  BOTTOM w0.254: PL702.3 23.35,63.17 v8(23.35,63.17) ; v1(20.06,54.8) 20.06,55.18 20,55.24 PR728.2 PR729.2 19.11,55.07 v1(19.4,54.78)
CSP1: length 39.3
  TOP w0.203: PU701.17 30.72,78.32 31.99,77.05
  TOP w0.254: 31.99,77.05 PC708.2 32.57,77.05 v3(32.7,77.18)
  IN2 w0.254: v3(32.7,77.18) 32.82,77.3 33.96,77.3 34.85,76.42 37.21,76.42 39.14,74.49 39.14,69.02 38.6,68.49 38.6,65.09 35.86,62.35 35.86,58.89 35.4,58.43 28.98,58.43 28.7,58.71 v1(28.7,59.27)
  BOTTOM w0.254: PR702.1 PR707.1 27.13,58.13 PH702.1 28.28,59.27 v1(28.7,59.27)
CSP2: length 62.2
  TOP w0.203: PU701.20 30.97,79.52 31.12,79.36 31.61,79.36 PC716.2
  TOP w0.254: v1(32.71,79.59) 32.71,80.42 32.42,80.71 PR746.2 32.04,79.79 PC716.2
  IN2 w0.254: v1(32.71,79.59) 32.84,79.46 33.36,79.46 33.99,78.84 36.43,78.84 40.33,74.95 40.33,72.18 41.24,71.27 41.24,64.17 37.74,60.66 37.74,58.23 36.39,56.88 32.12,56.88 30.77,55.54 27.6,55.54 26.96,54.89 23.55,54.89 22.32,53.66 19.65,53.66 18.87,54.44 18.87,55 19.32,55.46 v8(19.32,58.66)
  BOTTOM w0.254: v8(19.32,58.66) 19.7,58.28 PH703.1 20.54,58.28 20.89,57.94 PR724.1 PR728.1
CSSN_1: length 30.7
  TOP w0.102: v2(152.88,47.52) 152.17,46.81 PC212.1
  TOP w0.254: PC212.1 151.75,46.89 150.88,46.89 PC211.2 150.88,45.85 v1(150.72,45.68) 150.62,45.59 150.31,45.59 150.21,45.49 PU201.1 ; PR201.2 168.05,36.28 168.29,36.05 v6(168.29,35.85)
  GND1 w0.254: v4(168.16,36.36) 168.29,36.23 v6(168.29,35.85)
  IN2 w0.254: v1(150.72,45.68) 152.12,45.68 152.57,45.22 164.26,45.22 164.79,44.69 164.79,40.18 168.29,36.68 168.29,36.5 v4(168.16,36.36)
CSSP_1: length 32.5
  TOP w0.102: v2(149.97,48.76) PC210.2
  TOP w0.254: PR201.3 168.93,36.28 168.68,36.03 v6(168.68,35.88) ; PC210.2 PC211.1 149.97,46.09 v6(149.82,45.94) 149.79,45.91 149.78,45.91 149.71,45.83 PU201.2
  GND1 w0.254: v6(168.68,35.88) 168.68,36.28 v4(168.79,36.39) ; v6(149.82,45.94) 149.82,45.58 v4(149.94,45.45)
  IN2 w0.254: v4(149.94,45.45) 149.94,45.77 150.39,46.22 152.12,46.22 152.76,45.58 164.43,45.58 165.26,44.75 165.26,40.22 168.71,36.77 168.71,36.46 v4(168.79,36.39)
DAT_SMB: length 10.6
  TOP w0.102: PR111.1 124.71,28.38 125.08,28.02 PD103.3 125.08,26.62 124.7,26.24 124.7,25.68 v1(124.58,25.57) 124.58,24.56 v2(125.97,23.18)
  BOTTOM w0.102: v1(124.58,25.57) 124.37,25.36 JBATT1.6
DC_TEST_A3_B3: length 0.7
  BOTTOM w0.254: UCPU1.A3 95.37,79.73 UCPU1.B3
DC_TEST_A61_B61: length 0.7
  BOTTOM w0.254: UCPU1.B61 59.24,79.26 UCPU1.A61
DC_TEST_AY2_AW2: length 0.7
  BOTTOM w0.254: UCPU1.AY2 95.96,57.34 UCPU1.AW2
DC_TEST_AY3_AW3: length 0.7
  BOTTOM w0.254: UCPU1.AW3 95.3,57.28 UCPU1.AY3
DC_TEST_AY61_AW61: length 0.7
  BOTTOM w0.076: UCPU1.AY61 59.3,57.31 UCPU1.AW61
DC_TEST_AY62_AW62: length 0.7
  BOTTOM w0.076: UCPU1.AW62 58.56,57.79 UCPU1.AY62
DC_TEST_B62_B63: length 0.7
  BOTTOM w0.254: UCPU1.B62 58.51,79.26 UCPU1.B63
DC_TEST_C1_C2: length 0.7
  BOTTOM w0.254: UCPU1.C2 96.5,78.6 UCPU1.C1
DCIN_GND: length 3.1
  TOP w0.102: v7(187.92,77.5) 187.92,76.87 188.72,76.07 189.55,76.07 v1(189.95,75.68)
DDR3_DRAMRST#: length 179.9
  TOP w0.102: CD28.1 51.45,29.17 v1(51.18,28.89) ; v1(98.93,28.89) 99.07,29.03 CD72.1 ; CD5.1 26.68,29.03 v1(26.54,28.89) ; CD49.1 74.56,29.16 v1(74.26,28.87)
  IN1 w0.076: 100.9,27.11 101.89,27.11 102.27,26.73 108.08,26.73 v1(108.54,27.19) ; 100.9,27.11 100.77,26.99 100.77,26.35 99.83,25.41 94.94,25.41 93.07,23.55 90.53,23.55 89.65,24.42 v1(81.69,24.42) 80.32,24.42 77.63,27.11 75.47,27.11 74.26,28.32 v1(74.26,28.87) 73.58,28.18 67.69,28.18 67.1,28.77 62.2,28.77 v1(61.28,29.68) ; 100.9,27.11 100.9,27.24 100.59,27.55 99.8,27.55 99.32,28.03 99.32,28.31 98.93,28.7 v1(98.93,28.89)
  IN2 w0.076: v1(51.18,28.89) 51.56,29.27 52.18,29.27 52.53,28.92 52.53,28.61 ; 52.53,28.61 52.39,28.47 52.39,27.44 52.5,27.34 53,27.34 53.44,26.91 53.44,26.17 53.16,25.9 49.9,25.9 48.91,24.91 46.72,24.91 45.93,24.12 41.9,24.12 41.57,24.45 v1(33.32,24.45) 32.94,24.45 29.01,28.37 28.43,28.37 27.5,29.3 26.94,29.3 v1(26.54,28.89) ; 52.53,28.61 53.14,28.61 53.39,28.37 54.86,28.37 56.62,26.61 60.05,26.61 61.37,27.93 61.37,29.59 v1(61.28,29.68)
  BOTTOM w0.076: v1(61.28,29.68) 60.88,29.27 UD5.T2
  BOTTOM w0.102: v1(33.32,24.45) 33.75,24.45 35.91,26.61 35.91,27.11 36.33,27.53 36.33,29.18 UD2.T2 ; UD9.T2 97.07,29.32 97.4,29.65 98.17,29.65 v1(98.93,28.89) ; 108.58,27.23 109.94,27.23 111.69,28.98 111.69,44.09 111.22,44.56 108.08,44.56 107.63,45.02 90.44,45.02 v2(89.01,46.46) 86.65,48.81 86.65,50.55 RC75.2 RC162.2 ; 108.58,27.23 v1(108.54,27.19) ; 108.58,27.23 108.58,29.22 UD10.T2 ; UD7.T2 83.99,29.04 83.74,28.79 83.74,27.6 83.59,27.44 83.59,26.34 82.01,24.77 82.01,24.77 81.69,24.45 v1(81.69,24.42) ; UD4.T2 49.32,29.37 49.58,29.63 50.44,29.63 v1(51.18,28.89) ; v1(74.26,28.87) 73.48,29.65 72.87,29.65 72.48,29.27 UD6.T2 ; UD1.T2 24.68,29.27 25.09,29.68 25.75,29.68 v1(26.54,28.89)
DDR_A_BS0: length 147.8
  TOP w0.076: RD67.1 39.86,31.38 40.6,30.65 40.6,30.05 v1(40.38,29.83)
  IN2 w0.157: v1(75.97,54.08) 76.04,54.01 76.04,52.64 76.25,52.44 76.25,52.13 74.16,50.05 74.16,49.54 73.93,49.31 73.37,49.31 71.2,47.14 71.2,46.29 71.07,46.16 63.45,46.16 63.28,46.33 63.28,46.63 62.56,47.35 59.89,47.35 59.56,47.02 59.56,46.44 59.4,46.28 59.07,46.28 58.94,46.41 58.94,47.18 58.81,47.31 57.73,47.31 57.6,47.18 57.6,46.44 57.44,46.28 57.17,46.28 57.01,46.44 57.01,47.92 56.84,48.09 55.85,48.09 55.67,47.92 55.67,46.44 55.51,46.28 55.16,46.28 55.03,46.41 55.03,47.92 54.86,48.09 53.97,48.09 53.71,47.83 53.71,46.59 53.04,45.92 46.95,45.92 46.82,45.79 46.82,44.74 46.95,44.62 50.72,44.62 50.9,44.44 50.9,44.19 50.72,44.02 45.83,44.02 45.41,43.6 44.69,43.6 44.18,43.1 42.75,43.1 41.28,41.64 41.28,40.59 41.76,40.11 41.76,38.03 41.27,37.54 41.27,35.56 40.5,34.79 40.5,30.78 40.56,30.72 40.56,30.71 40.61,30.66 40.61,30.41 40.84,30.19 41.23,30.19 41.53,29.88 41.53,29.33 41.35,29.15 40.91,29.15 40.38,29.68 v1(40.38,29.83)
  IN3 w0.076: v4(28.04,30.64) 28.87,30.64 28.94,30.71 31.32,30.71 31.6,30.43 31.99,30.43 32.57,29.84 34.91,29.84 35.3,30.24 38.16,30.24 38.58,29.81 39.32,29.81 39.49,29.98 39.49,30.08 39.6,30.19 39.76,30.19 39.87,30.08 39.87,29.86 40,29.73 40.28,29.73 v1(40.38,29.83) 40.63,30.09 41.52,30.09 41.8,29.81 42.49,29.81 43.05,29.25 44.58,29.25 44.68,29.35 48.2,29.35 49.7,30.85 51.65,30.85 51.86,30.64 v4(52.67,30.64)
  IN4 w0.076: v1(58.74,31.66) 58.74,31.61 58.07,30.94 56.88,30.94 56.64,30.69 52.72,30.69 v4(52.67,30.64) 52.65,30.66 51.91,30.66 51.61,30.97 51.61,31.43 51.33,31.71 48.6,31.71 48.39,31.93 48.24,31.93 48.08,32.09 47.62,32.09 v1(47.19,31.66) ; v1(22.55,31.66) 22.98,32.09 23.59,32.09 23.97,31.71 26.69,31.71 26.97,31.43 26.97,30.97 27.27,30.66 28.01,30.66 v4(28.04,30.64) 28.11,30.71 32.02,30.71 32.34,31.03 33.67,31.03 34.11,31.47 v8(34.11,31.66)
  BOTTOM w0.076: UCPU1.AU35 75.58,59.03 75.58,58.97 75.32,58.7 75.32,56.98 75.34,56.96 75.34,54.71 v1(75.97,54.08) ; UD2.M2 35.93,32.78 35.22,32.78 v8(34.11,31.66) ; UD1.M2 24.33,32.82 23.71,32.82 v1(22.55,31.66) ; v1(47.19,31.66) 48.35,32.82 48.97,32.82 UD4.M2 ; UD5.M2 60.52,32.83 59.91,32.83 v1(58.74,31.66)
DDR_A_BS1: length 144.4
  TOP w0.076: v1(41.07,30.71) 40.99,30.71 40.72,30.98 RD71.1
  IN2 w0.076: 76.46,52.91 76.39,52.98 76.39,54.15 76.37,54.17 76.37,54.5 v8(75.95,54.92)
  IN2 w0.157: v1(41.07,30.71) 40.85,30.93 40.85,34.64 41.62,35.42 41.62,37.4 42.11,37.89 42.11,40.25 41.63,40.73 41.63,41.49 42.89,42.75 44.33,42.75 44.83,43.25 45.55,43.25 45.97,43.67 51.17,43.67 52.01,44.51 52.01,44.84 51.89,44.96 47.3,44.96 47.17,45.09 47.17,45.45 47.3,45.57 53.18,45.57 54.05,46.44 54.05,47.55 54.21,47.71 54.52,47.71 54.68,47.55 54.68,46.09 54.84,45.93 55.86,45.93 56.02,46.09 56.02,47.61 56.15,47.75 56.5,47.75 56.66,47.59 56.66,46.09 56.82,45.93 57.84,45.93 57.95,46.04 57.95,46.82 58.08,46.95 58.47,46.95 58.59,46.82 58.59,46.09 58.75,45.93 59.77,45.93 59.91,46.06 59.91,46.88 60.03,47 60.4,47 60.52,46.88 60.52,45.97 60.68,45.81 61.04,45.81 61.16,45.94 61.16,46.88 61.28,47 61.64,47 61.77,46.88 61.77,45.97 61.92,45.81 62.23,45.81 62.38,45.96 62.38,46.51 62.51,46.65 62.72,46.65 62.93,46.44 62.93,45.95 63.06,45.81 71.4,45.81 71.55,45.96 71.55,47 72.41,47.86 72.97,47.86 73.32,48.21 73.32,48.77 73.52,48.96 74.08,48.96 74.57,49.46 74.57,49.96 76.59,51.99 76.59,52.78 76.46,52.91
  IN3 w0.076: v4(27.23,32.1) 27.23,32.01 27.68,31.56 28.04,31.56 28.35,31.24 31.54,31.24 31.83,30.95 35.96,30.95 36.11,30.8 37.87,30.8 38.04,30.98 40.8,30.98 v1(41.07,30.71) 41.61,30.71 41.98,30.34 43.02,30.34 43.05,30.37 44.29,30.37 44.37,30.44 44.37,30.49 44.42,30.54 44.62,30.54 44.72,30.44 44.72,30.01 44.83,29.91 44.98,29.91 45.08,30.01 45.08,30.42 45.21,30.54 45.31,30.54 45.41,30.44 45.41,29.98 45.59,29.81 48,29.81 48.34,30.15 48.34,30.45 49.07,31.17 49.07,31.53 49.44,31.9 51.67,31.9 v4(51.87,32.1)
  IN4 w0.076: v1(45.91,31.66) 46.75,32.5 48.57,32.5 48.87,32.2 51.77,32.2 v4(51.87,32.1) 51.87,32.03 52.6,31.3 52.91,31.3 53.04,31.16 56.36,31.16 56.83,31.64 57.44,31.64 v1(57.47,31.66) ; v1(21.27,31.66) 22.19,32.58 23.86,32.58 24.19,32.25 27.09,32.25 v4(27.23,32.1) 27.23,32.03 27.96,31.3 28.29,31.3 28.42,31.16 31.72,31.16 32.19,31.64 32.81,31.64 v1(32.83,31.66)
  BOTTOM w0.076: UD2.N8 31.7,31.67 32.15,32.12 32.37,32.12 v1(32.83,31.66) ; v1(21.27,31.66) 20.93,32 20.22,32 UD1.N8 ; v1(45.91,31.66) 45.56,32.02 44.98,32.02 44.63,31.67 UD4.N8 ; UCPU1.AV35 75.48,58.23 75.48,57.05 75.52,57.02 75.52,55.35 v8(75.95,54.92) ; UD5.N8 56.34,31.67 56.69,32.02 57.11,32.02 v1(57.47,31.66)
DDR_A_BS2: length 144.7
  TOP w0.076: v1(38.13,29.32) 38.13,29.71 37.32,30.52 RD69.1
  IN2 w0.157: v1(38.13,29.32) 38.28,29.47 38.28,30.92 38.07,31.13 38.07,31.37 38.41,31.71 38.41,32.63 38.2,32.84 38.2,33.04 38.41,33.25 38.41,34.52 37.54,35.38 35.62,35.38 35.29,35.71 35.29,37.2 35.44,37.35 36.99,37.35 37.15,37.51 37.15,37.85 37,38.01 34.79,38.01 34.51,38.29 34.51,39.12 34.67,39.28 36.74,39.28 37.13,39.67 37.13,42.33 36.98,42.48 35.91,42.48 35.71,42.68 35.71,43.42 36.55,44.26 36.55,45.78 38.42,47.66 38.42,47.93 38.7,48.21 38.7,48.24 38.71,48.25 38.71,48.37 40.89,50.55 40.89,50.8 41.21,51.12 42.79,51.12 44.59,52.92 45.67,52.92 47.19,54.44 49.55,54.44 49.7,54.6 49.7,55.11 49.85,55.26 50.08,55.26 50.24,55.11 50.24,54.6 50.39,54.44 52.06,54.44 52.22,54.6 52.22,55.11 52.37,55.26 53.26,55.26 53.46,55.05 53.46,54.6 53.61,54.44 53.88,54.44 54.03,54.6 54.03,55.11 54.17,55.26 55.14,55.26 55.26,55.14 55.26,54.61 55.43,54.44 55.66,54.44 55.83,54.61 55.83,55.11 55.98,55.26 56.79,55.26 57.17,54.88 57.37,54.88 57.75,55.26 58.87,55.26 59,55.13 59,54.34 58.92,54.27 58.92,53.64 59.08,53.48 59.38,53.48 60.08,52.78 60.78,52.78 60.98,52.97 61.21,52.97 61.4,52.78 64.3,52.78 64.46,52.62 65.02,52.62 65.2,52.79 65.2,52.99 65.36,53.15 65.72,53.15 65.88,52.99 65.88,52.78 66.04,52.62 66.41,52.62 67.1,51.93 67.53,51.93 67.81,52.21 67.81,52.39 68.7,53.28 68.7,53.58 70.03,54.91 70.95,54.91 71.44,55.41 v1(71.5,55.41)
  IN3 w0.076: v4(29.1,30.31) 29.29,30.51 29.71,30.51 29.79,30.43 29.79,30.21 29.89,30.11 30.12,30.11 30.22,30.21 30.22,30.44 30.27,30.49 30.53,30.49 30.58,30.44 30.58,30.13 30.67,30.04 30.81,30.04 30.91,30.13 30.91,30.4 31.01,30.51 31.14,30.51 31.43,30.22 31.88,30.22 31.97,30.13 31.97,30 31.88,29.91 31.56,29.91 31.47,29.81 31.47,29.68 31.56,29.58 35.21,29.58 35.28,29.65 35.28,29.92 35.39,30.04 35.54,30.04 35.66,29.92 35.66,29.15 35.73,29.07 35.96,29.07 36.04,29.15 36.04,29.93 36.14,30.04 36.29,30.04 36.39,29.93 36.39,29.17 36.47,29.1 36.67,29.1 36.75,29.17 36.75,29.92 36.86,30.04 37.02,30.04 37.13,29.92 37.13,29.15 37.21,29.07 37.43,29.07 37.59,29.22 37.92,29.22 38.02,29.32 v1(38.13,29.32) 38.21,29.4 40.74,29.4 40.89,29.25 42.72,29.25 42.92,29.04 45.08,29.04 45.66,28.46 47.9,28.46 48.42,28.99 48.42,29.28 49.76,30.62 51.51,30.62 51.89,30.24 53.82,30.24 v4(53.87,30.29)
  IN4 w0.076: v8(23.18,31.66) 23.64,31.66 24.45,30.85 26.64,30.85 27.09,30.4 27.64,30.4 27.79,30.25 29.04,30.25 v4(29.1,30.31) 29.15,30.36 32.05,30.36 32.43,30.75 34.44,30.75 34.74,31.05 v1(34.74,31.66) ; v1(47.82,31.66) 48.28,31.66 49.08,30.86 49.85,30.86 50.02,30.7 51.43,30.7 51.73,30.4 52.28,30.4 52.43,30.25 53.83,30.25 v4(53.87,30.29) 53.94,30.36 56.69,30.36 57.05,30.73 59.24,30.73 59.51,31 59.51,31.53 v1(59.38,31.66)
  BOTTOM w0.076: v1(47.82,31.66) 48.52,32.36 UD4.M3 ; UD5.M3 60.08,32.36 v1(59.38,31.66) ; UCPU1.AY41 71.95,57.15 71.95,55.87 v1(71.5,55.41) ; v1(34.74,31.66) 35.44,32.36 UD2.M3 ; UD1.M3 23.88,32.36 v8(23.18,31.66)
DDR_A_CAS#: length 144.3
  TOP w0.076: RD63.1 41.16,33.19 v1(42.01,32.34)
  IN2 w0.157: v1(42.01,32.34) 42.17,32.5 43.12,32.5 44.19,33.57 44.87,33.57 45.4,33.04 45.4,32.67 44.1,31.37 44.1,31.2 44.25,31.05 44.72,31.05 45.08,31.41 45.33,31.41 45.51,31.23 45.51,30.9 45.66,30.75 46.04,30.75 46.17,30.87 46.17,31.02 46.33,31.18 46.62,31.18 46.78,31.02 46.78,30.9 46.93,30.75 47.11,30.75 47.42,31.05 47.72,31.05 48.03,30.75 48.2,30.75 48.33,30.88 48.33,31.94 48.63,32.23 48.63,33.32 49.01,33.7 49.01,33.85 48.86,34 48.71,34 48.46,34.25 48.46,34.52 48.3,34.68 45.9,34.68 45.74,34.84 45.74,35.06 45.9,35.22 46.38,35.22 46.54,35.38 46.54,35.92 46.7,36.08 47,36.08 47.16,35.92 47.16,35.43 47.37,35.22 48.26,35.22 48.46,35.42 48.46,36 48.69,36.23 49.17,36.23 49.6,36.66 50.29,36.66 50.41,36.79 50.41,37.23 50.27,37.38 49.58,37.38 49.42,37.54 49.42,37.83 49.58,37.99 50.08,37.99 50.22,38.12 50.22,38.51 50.18,38.54 50.18,39.35 50.58,39.75 50.58,39.84 50.73,39.99 50.95,39.99 51.1,39.84 51.1,39.48 50.92,39.3 50.92,39.09 51.31,38.7 51.52,38.7 52.37,39.55 52.37,39.76 52.19,39.94 51.71,39.94 51.51,40.14 51.51,40.4 51.66,40.55 52.6,40.55 52.77,40.73 52.77,42.32 53.94,43.48 54.05,43.48 54.41,43.84 59.17,43.84 59.28,43.73 75.38,43.73 79.49,47.84 79.49,52.24 79.14,52.59 79.14,53.77 78.86,54.05 78.86,57.21 77.24,58.83 76.24,58.83 v8(76.2,58.88)
  IN3 w0.076: v4(28.7,32.73) 28.9,32.73 29.07,32.9 32.47,32.9 32.65,33.08 33.63,33.08 34.19,32.52 37.15,32.52 37.74,33.11 40.96,33.11 41.7,32.37 41.98,32.37 v1(42.01,32.34) 42.14,32.47 43.46,32.47 43.71,32.21 43.71,31.78 43.89,31.6 45.25,31.6 45.51,31.86 45.51,32.46 45.81,32.75 46.37,32.75 46.5,32.63 46.5,32.32 46.72,32.11 47.9,32.11 48.03,32.23 48.03,32.65 48.15,32.78 48.64,32.78 49.38,33.53 50.84,33.53 51.16,33.21 52.55,33.21 53,32.75 53.31,32.75 v4(53.33,32.73)
  IN4 w0.076: v3(22.7,34.18) 23.31,33.57 26.41,33.57 26.64,33.34 27.78,33.34 28.32,32.8 28.62,32.8 v4(28.7,32.73) 28.75,32.78 32.27,32.78 32.74,33.25 33.92,33.25 v1(34.87,34.2) ; v1(47.34,34.18) 47.34,33.9 47.71,33.53 52.28,33.53 53,32.8 53.26,32.8 v4(53.33,32.73) 53.36,32.75 56.66,32.75 57.2,33.29 58.59,33.29 v1(59.51,34.2)
  BOTTOM w0.076: v8(76.2,58.88) 76.35,58.88 UCPU1.AU34 ; UD1.K3 23.88,34.04 23.56,33.72 23.16,33.72 v3(22.7,34.18) ; v1(59.51,34.2) 59.46,34.15 59.46,33.82 59.61,33.67 59.76,33.67 60.08,33.98 UD5.K3 ; v1(34.87,34.2) 34.84,34.18 34.84,33.82 34.97,33.69 35.22,33.69 35.44,33.91 UD2.K3 ; UD4.K3 48.52,34.04 48.2,33.72 47.8,33.72 v1(47.34,34.18)
DDR_A_CKE0: length 138.9
  TOP w0.076: RD57.1 40.85,35.73 v1(40.64,35.73)
  IN2 w0.076: 74.06,52.87 74.06,53.61 74.22,53.77 74.22,58.9 73.6,59.53 73.3,59.53 73.23,59.6 72.72,59.6 72.54,59.42 71,59.42 70.46,58.88 v1(69.9,58.88)
  IN2 w0.157: 74.06,52.87 73.63,52.44 73.63,51.68 71.94,49.99 71.28,49.99 71.1,49.81 71.1,49.31 71.1,49.3 71.1,49.18 69.98,48.06 68.88,48.06 68.55,47.73 64.42,47.73 63.3,48.85 58.2,48.85 57.08,49.96 52.75,49.96 52.59,50.13 52.59,51.63 52.44,51.78 50.76,51.78 50.26,51.27 49.94,51.27 49.42,51.79 48.29,51.79 47.71,51.21 47.71,50.67 47.55,50.51 47.14,50.51 46.98,50.36 46.98,50.04 47.14,49.88 47.55,49.88 47.71,49.73 47.71,49.31 47.04,48.64 46.03,48.64 44.84,47.45 44.84,47.29 44.83,47.29 44.38,46.84 44.38,46.62 45.2,45.79 45.2,45.61 44.94,45.35 44.76,45.35 43.93,46.17 43.71,46.17 43.49,45.95 43.49,45.73 43.97,45.24 43.97,45.02 43.75,44.8 43.53,44.8 43.04,45.28 42.82,45.28 39.81,42.27 39.81,38.64 40.69,37.75 40.69,36.47 40.46,36.23 40.46,35.91 v1(40.64,35.73)
  IN3 w0.076: v4(50.28,35.35) 50.28,35.35 50.25,35.32 48.38,35.32 48.2,35.14 45.99,35.14 45.87,35.27 45.87,35.45 45.99,35.57 46.69,35.57 46.82,35.7 46.82,35.99 46.65,36.16 46.19,36.16 46.1,36.25 46.1,36.39 46.19,36.49 46.27,36.49 46.4,36.61 46.4,36.84 46.27,36.97 45.49,36.97 45.03,37.43 42.59,37.43 42.46,37.3 42.46,37.1 42.54,37.02 42.64,37.02 42.77,36.89 42.77,36.69 42.66,36.59 41.71,36.59 41.6,36.48 41.6,36.32 41.71,36.21 42.64,36.21 42.77,36.08 42.77,35.85 42.64,35.73 v1(40.64,35.73) 40.26,35.73 39.96,35.42 35.5,35.42 35.13,35.05 33.69,35.05 33.32,35.42 32.91,35.42 32.5,35.01 32.5,34.19 32.09,33.78 29.4,33.78 28.83,34.35 28.83,34.8 28.52,35.11 28.01,35.11 27.69,34.8 27.36,34.8 27.34,34.82 27.03,34.82 26.62,35.24 25.72,35.24 v4(25.6,35.12)
  IN4 w0.076: v8(19.49,33.68) 19.86,33.31 20.77,33.31 20.96,33.5 20.96,34.33 21.64,35.02 23.89,35.02 24.02,35.14 25.58,35.14 v4(25.6,35.12) 25.8,35.32 26.27,35.32 26.61,35.66 26.72,35.66 26.79,35.59 26.79,35.19 26.87,35.12 27.02,35.12 27.1,35.19 27.1,35.48 27.27,35.66 27.86,35.66 28.2,35.32 29.13,35.32 29.2,35.24 29.2,35.12 28.93,34.84 28.93,34.74 29.02,34.65 29.12,34.65 29.34,34.87 29.44,34.87 29.57,34.74 29.57,34.64 29.46,34.53 29.46,34.43 29.53,34.35 29.99,34.35 v1(30.12,34.48) ; v1(54.22,34.51) 54.2,34.48 53.94,34.48 53.84,34.58 53.84,34.86 53.75,34.95 53.63,34.95 53.49,34.81 53.36,34.81 53.16,35.01 53,35.01 52.8,34.81 52.5,34.81 52.24,35.06 52.24,35.45 52.15,35.55 52.01,35.55 51.91,35.45 51.91,35.1 51.84,35.03 51.68,35.03 51.61,35.1 51.61,35.47 51.53,35.55 51.4,35.55 51.33,35.47 51.33,35.09 51.26,35.03 51.14,35.03 51.02,35.14 51.02,35.49 50.95,35.57 50.77,35.57 50.55,35.35 v4(50.28,35.35) 49.89,35.35 49.65,35.12 48.52,35.12 48.44,35.03 46.3,35.03 45.56,34.3 45.56,34.18 45.2,33.82 43.26,33.82 v1(43.22,33.78)
  BOTTOM w0.076: UD1.K9 19.1,34.07 v8(19.49,33.68) ; UD5.K9 54.66,34.07 v1(54.22,34.51) ; v1(30.12,34.48) 30.12,34.43 30.48,34.07 UD2.K9 ; UD4.K9 43.72,34.04 43.47,33.78 v1(43.22,33.78) ; UCPU1.AU43 70.05,58.88 v1(69.9,58.88)
DDR_A_CKE1: length 135.5
  TOP w0.076: RD87.1 40.47,36.23 v1(39.96,36.23)
  IN2 w0.076: 73.72,53.04 73.72,53.06 73.88,53.23 73.88,53.68 74.06,53.86 74.06,58.82 73.5,59.38 73.24,59.38 73.16,59.45 72.79,59.45 72.6,59.26 71.26,59.26 70.94,58.94 70.94,58.06 70.43,57.56 v1(69.9,57.56)
  IN2 w0.157: 73.72,53.04 73.28,52.6 73.28,51.82 71.8,50.34 71.14,50.34 70.75,49.95 70.43,49.95 70.1,49.62 70.1,48.67 69.84,48.41 68.73,48.41 68.41,48.08 64.56,48.08 63.44,49.2 58.34,49.2 57.22,50.31 53.06,50.31 52.94,50.43 52.94,51.81 52.62,52.13 50.62,52.13 50.36,51.87 49.84,51.87 49.56,52.14 48.15,52.14 46.02,50.01 46.02,49.7 46.22,49.49 46.22,49.33 45.93,49.03 45.71,49.03 45.47,49.27 45.25,49.27 45.03,49.05 45.03,48.82 45.26,48.59 45.26,48.37 45.04,48.14 44.82,48.14 44.58,48.38 44.36,48.38 44.14,48.15 44.14,47.93 44.37,47.7 44.37,47.47 44.15,47.25 43.93,47.25 43.69,47.49 43.47,47.49 43.25,47.26 43.25,47.04 43.48,46.81 43.48,46.58 42.95,46.05 42.76,46.05 42.55,46.25 42.37,46.25 42.11,45.99 42.11,45.81 42.37,45.55 42.37,45.33 42.15,45.1 41.92,45.1 41.5,45.53 41.32,45.53 41.05,45.26 41.05,45.08 41.48,44.66 41.48,44.44 39.46,42.42 39.46,38.49 40.3,37.65 40.3,36.58 v1(39.96,36.23)
  IN3 w0.076: v4(24.65,35.55) 24.67,35.52 26.63,35.52 26.82,35.71 27.89,35.71 28.08,35.52 28.54,35.52 29.1,34.96 29.1,34.37 29.45,34.02 32,34.02 32.29,34.31 32.29,35.14 32.83,35.68 33.44,35.68 33.74,35.38 35.14,35.38 35.38,35.63 39.35,35.63 v1(39.96,36.23) 40.34,36.23 40.51,36.4 40.51,37.63 40.66,37.78 40.87,37.78 41.02,37.63 41.02,36.24 41.13,36.13 41.28,36.13 41.4,36.24 41.4,37.91 41.52,38.04 41.7,38.04 41.83,37.91 41.83,37.15 41.96,37.02 42.08,37.02 42.21,37.15 42.21,37.48 42.36,37.63 45.13,37.63 45.58,37.18 46.13,37.18 46.22,37.27 46.22,37.85 46.33,37.96 46.49,37.96 46.6,37.85 46.6,36.51 47.14,35.98 47.14,35.76 47.28,35.62 48.83,35.62 v4(48.92,35.72)
  IN4 w0.076: v1(19.47,34.47) 19.47,34.18 19.55,34.1 19.66,34.1 19.89,33.87 20.04,33.87 20.19,34.02 20.31,34.02 20.39,33.95 20.39,33.72 20.5,33.62 20.65,33.62 20.75,33.72 20.75,34.46 21.53,35.24 23.81,35.24 24.22,35.65 24.54,35.65 v4(24.65,35.55) 24.67,35.52 25.23,35.52 25.31,35.6 25.31,35.66 25.38,35.74 25.61,35.74 25.69,35.66 25.69,35.6 25.76,35.52 26.18,35.52 26.52,35.86 27.95,35.86 28.29,35.52 28.98,35.52 29.31,35.85 29.46,35.85 29.59,35.73 29.59,35.55 29.45,35.41 29.45,35.23 29.64,35.04 29.82,35.04 v1(29.84,35.06) ; v8(43.28,34.45) 43.39,34.45 43.81,34.02 45.12,34.02 45.35,34.25 45.35,34.38 46.21,35.25 48.18,35.25 48.37,35.45 48.65,35.45 v4(48.92,35.72) 49.02,35.62 49.95,35.62 50.1,35.77 52.25,35.77 52.79,35.23 53.39,35.23 53.47,35.15 54.21,35.15 54.53,34.84 54.73,34.84 54.87,34.7 v1(54.87,34.49)
  BOTTOM w0.076: v8(43.28,34.45) 43.55,34.45 43.72,34.62 UD4.J9 ; UD2.J9 30.52,34.99 29.92,34.99 v1(29.84,35.06) ; v1(54.87,34.49) 55.14,34.49 55.28,34.63 UD5.J9 ; UCPU1.AW43 70.22,57.88 v1(69.9,57.56) ; v1(19.47,34.47) 19.44,34.47 19.08,34.83 UD1.J9
DDR_A_CS0#: length 137.5
  TOP w0.076: RD61.1 43.29,31.46 42.26,31.46 v1(42.21,31.5)
  IN2 w0.157: v1(42.21,31.5) 42.87,31.5 43.89,30.49 45.09,30.49 45.33,30.24 45.33,29.92 45.47,29.78 48.23,29.78 48.9,30.45 48.9,31.7 49.19,32 49.19,33.08 49.58,33.47 49.58,33.85 49.7,33.97 49.98,33.97 50.36,34.35 50.36,34.73 50.17,34.92 49.41,34.92 49.22,35.11 49.22,35.38 49.41,35.57 49.88,35.57 50.11,35.8 50.47,35.8 50.56,35.71 51.48,35.71 51.91,36.14 51.91,36.59 51.56,36.94 51.56,37.93 53.34,39.72 53.34,42.09 54.17,42.92 54.28,42.92 54.64,43.28 58.94,43.28 59.05,43.16 75.61,43.16 76.13,43.69 76.31,43.69 76.83,43.16 77.36,43.16 77.48,43.27 77.48,43.5 76.85,44.12 76.85,44.41 77.56,45.11 77.74,45.11 78.78,44.07 79,44.07 79.25,44.32 79.25,44.53 78.3,45.48 78.3,45.85 78.94,46.49 79.2,46.49 79.76,45.94 79.91,45.94 80.06,46.09 80.06,46.54 79.62,46.98 79.62,47.17 80.06,47.61 80.06,52.47 79.73,52.8 79.56,52.8 79.56,52.8 79.56,53.68 79.73,53.85 79.73,56.96 76.96,59.73 76.96,60.23 v1(76.46,60.73)
  IN3 w0.076: v4(28.98,32.14) 29,32.14 29.45,32.59 32.48,32.59 32.75,32.86 33.45,32.86 34,32.31 37.28,32.31 37.75,32.78 40.94,32.78 v1(42.21,31.5) 42.26,31.46 43.17,31.46 43.27,31.36 44.57,31.36 44.72,31.2 48,31.2 48.25,31.46 48.25,32.49 48.34,32.58 48.47,32.58 48.56,32.49 48.56,32.19 48.66,32.1 48.73,32.1 48.89,32.25 48.89,32.67 49.54,33.32 50.76,33.32 51.07,33.01 52.45,33.01 53.31,32.14 v4(53.61,32.14)
  IN4 w0.076: v1(25.08,32.88) 25.05,32.85 24.23,32.85 24.05,33.03 23.92,33.03 23.82,33.13 23.82,33.27 23.92,33.36 26.21,33.36 26.46,33.11 27.71,33.11 28.58,32.23 28.89,32.23 v4(28.98,32.14) 29.03,32.14 29.46,32.58 32.4,32.58 32.76,32.93 35.16,32.93 35.85,33.62 v8(35.85,33.68) ; v1(49.71,32.88) 49.64,32.8 49.02,32.8 48.79,33.03 48.79,33.24 48.88,33.32 50.88,33.32 50.95,33.26 50.95,33.16 51.02,33.08 51.2,33.08 51.28,33.16 51.28,33.26 51.34,33.32 51.52,33.32 51.61,33.24 51.61,33.13 51.66,33.08 51.86,33.08 51.94,33.16 51.94,33.26 52,33.32 52.15,33.32 53.33,32.14 v4(53.61,32.14) 53.66,32.14 54.07,32.55 56.78,32.55 57.3,33.06 59.88,33.06 v1(60.48,33.66)
  BOTTOM w0.076: v8(35.85,33.68) 35.85,33.68 36.24,33.29 UD2.L2 ; v1(25.08,32.88) 25.06,32.89 25.06,32.92 24.72,33.27 UD1.L2 ; UCPU1.AP33 76.72,60.99 v1(76.46,60.73) ; v1(60.48,33.66) 60.48,33.64 60.85,33.27 UD5.L2 ; v1(49.71,32.88) 49.33,33.27 UD4.L2
DDR_A_CS1#: length 135.5
  TOP w0.076: v1(42.72,31) 43.28,30.44 RD88.1
  IN2 w0.157: v1(77.34,60.67) 77.36,60.64 77.36,59.93 80.02,57.27 80.02,53.72 79.85,53.55 79.85,53.1 80.41,52.54 80.41,45.22 80.28,45.1 80.11,45.1 79.17,46.03 78.97,46.03 78.71,45.77 78.71,45.57 79.75,44.52 79.75,44.32 79,43.57 78.79,43.57 77.78,44.58 77.56,44.58 77.33,44.35 77.33,44.14 78.25,43.21 78.25,43.04 78.03,42.81 58.91,42.81 58.79,42.93 54.78,42.93 54.43,42.57 54.32,42.57 53.68,41.94 53.68,37.12 52.5,35.93 52.5,35.06 52.34,34.91 51.66,34.91 51.07,34.33 51.07,32.76 50.82,32.51 50.82,31.92 50.68,31.79 49.47,31.79 49.25,31.56 49.25,29.65 48,28.41 45.66,28.41 45.3,28.78 45.3,29.24 44.39,30.14 43.58,30.14 v1(42.72,31)
  IN3 w0.076: v4(56.31,32.12) 56.08,31.89 56.08,31.84 55.83,31.6 55.79,31.6 55.77,31.58 53.49,31.58 52.27,32.8 51.61,32.8 51.11,32.31 49.23,32.31 48.61,31.69 48.61,31.36 48.2,30.95 44.53,30.95 44.35,31.13 42.84,31.13 v1(42.72,31) 42.62,30.9 42.11,30.9 41.43,31.58 41.43,31.95 40.85,32.52 40.66,32.52 40.53,32.4 40.53,32.22 40.43,32.12 40.28,32.12 40.18,32.22 40.18,32.4 40.05,32.52 39.82,32.52 39.69,32.4 39.69,32.02 39.59,31.92 39.44,31.92 39.34,32.02 39.34,32.37 39.21,32.5 39.03,32.5 38.91,32.37 38.91,31.87 38.8,31.76 38.66,31.76 38.55,31.87 38.55,32.37 38.41,32.51 37.8,32.51 37.38,32.09 33.84,32.09 33.27,32.66 32.92,32.66 32.59,32.32 31.77,32.32 31.64,32.19 31.63,32.19 v4(31.63,32.18)
  IN4 w0.076: v1(61.28,33.67) 60.45,32.83 58.97,32.83 58.85,32.7 58.85,32.4 58.72,32.27 58.57,32.27 58.47,32.37 58.47,32.68 58.31,32.83 57.37,32.83 56.69,32.14 56.33,32.14 v4(56.31,32.12) 56.31,32.09 55.8,31.58 53.51,31.58 52.22,32.88 50.57,32.88 v8(50.54,32.91) ; v1(26,32.91) 26.03,32.88 27.63,32.88 28.87,31.64 31.26,31.64 31.49,31.86 31.49,32.04 v4(31.63,32.18) 31.63,32.19 31.64,32.19 31.69,32.25 32.4,32.25 32.84,32.68 36.85,32.68 37.03,32.85 37.03,33.29 v1(36.65,33.67)
  BOTTOM w0.076: UCPU1.AR32 77.67,60.34 v1(77.34,60.67) ; v1(26,32.91) 26,33.03 25.77,33.27 UD1.L1 ; v1(61.28,33.67) 61.68,33.27 UD5.L1 ; UD2.L1 37.04,33.27 v1(36.65,33.67) ; UD4.L1 50.18,33.27 v8(50.54,32.91)
DDR_A_D0: length 52.6
  IN4 w0.076: v1(56.99,64.87) 56.99,64.92 56.67,65.24 55.16,65.24 54.93,65.02 54.79,65.02
  IN4 w0.132: v8(21.15,37.66) 21.13,37.67 21.13,41.82 23.44,44.12 27.39,44.12 28.4,45.13 29.07,45.13 30.4,46.46 32.09,46.46 37.45,51.82 39.81,51.82 40.77,52.78 41.45,52.78 43.38,54.7 45.1,54.7 50.44,60.03 50.44,61.53 53.93,65.02 54.79,65.02
  BOTTOM w0.076: UCPU1.AH63 57.92,64.5 57.36,64.5 v1(56.99,64.87)
  BOTTOM w0.183: v8(21.15,37.66) 20.77,37.27 UD1.F7
DDR_A_D1: length 54.3
  IN4 w0.132: v8(21.09,36.04) 21.13,36.04 21.81,36.72 21.81,39.17 22.16,39.51 22.16,42.16 23.77,43.78 27.5,43.78 28.52,44.79 29.19,44.79 30.52,46.13 32.22,46.13 37.59,51.5 39.95,51.5 40.9,52.45 41.71,52.45 43.58,54.32 45.23,54.32 50.79,59.88 50.79,61.37 54.11,64.68 54.97,64.68 55.23,64.95 56.24,64.95 v1(56.32,64.86)
  BOTTOM w0.076: UCPU1.AH62 58.61,64.58 58.33,64.29 57.78,64.29 57.73,64.34 56.98,64.34 56.45,64.86 v1(56.32,64.86)
  BOTTOM w0.183: v8(21.09,36.04) 20.72,35.67 UD1.H7
DDR_A_D2: length 52.3
  IN4 w0.132: v1(24.29,37.68) 24.81,38.2 25.44,38.2 25.63,38 26.65,38 27.01,37.64 27.01,37.38 27.13,37.27 27.49,37.27 27.6,37.38 27.6,37.86 27.76,38.01 28.01,38.01 28.22,38.22 28.22,38.64 29.27,39.69 29.27,40.01 29.11,40.17 28.58,40.17 28.42,40.33 28.42,41.38 28.58,41.54 29.11,41.54 29.27,41.7 29.27,41.81 30.24,42.79 30.24,43.14 31.24,44.14 31.92,44.14 32.34,43.71 33.01,43.71 33.42,44.12 34.48,44.12 34.8,44.44 34.8,44.73 35.32,45.25 35.32,46.44 36.27,47.38 36.52,47.38 36.62,47.28 36.62,46.64 36.8,46.47 37.25,46.47 37.88,47.09 37.92,47.09 39.4,48.58 41.4,48.58 45.08,52.26 45.89,52.26 52.76,59.13 52.76,60.54 54.49,62.27 55.98,62.27 v3(56.75,63.04)
  BOTTOM w0.076: UCPU1.AK63 56.93,63.22 v3(56.75,63.04)
  BOTTOM w0.183: UD1.F2 24.68,37.28 24.32,37.65 24.32,37.65 v1(24.29,37.68)
DDR_A_D3: length 53.5
  IN4 w0.132: v1(23.35,36.14) 23.35,36.29 23.84,36.77 23.84,38.73 24.33,39.22 26.39,39.22 26.49,39.12 26.49,38.47 26.61,38.34 27.1,38.34 27.2,38.44 27.2,39.05 27.42,39.28 27.75,39.28 28.09,39.62 28.09,41.95 28.51,42.37 29.24,42.37 29.92,43.05 29.92,43.27 31.17,44.52 31.99,44.52 32.43,44.08 32.92,44.08 33.86,45.02 34.33,45.02 34.89,45.58 34.89,46.5 37.31,48.92 41.28,48.92 44.98,52.62 45.77,52.62 52.43,59.27 52.43,60.66 54.45,62.68 55.12,62.68 55.24,62.56 55.66,62.56 v8(56.11,63.01)
  BOTTOM w0.076: UCPU1.AK62 58.45,63.22 58.15,62.93 57.15,62.93 56.9,62.67 56.44,62.67 56.11,63 v8(56.11,63.01)
  BOTTOM w0.183: v1(23.35,36.14) 23.83,35.67 UD1.H3
DDR_A_D4: length 56.3
  IN4 w0.132: v1(20.27,36.06) 20.72,36.51 20.72,37.19 20.55,37.36 20.55,37.98 20.8,38.23 20.8,41.94 23.36,44.5 27.28,44.5 28.25,45.46 28.95,45.46 30.29,46.81 31.91,46.81 37.24,52.14 39.54,52.14 40.51,53.11 41.2,53.11 43.17,55.08 44.93,55.08 50.06,60.21 50.06,61.63 53.9,65.47 56.79,65.47 56.97,65.29 57.22,65.29 v8(57.6,64.9)
  BOTTOM w0.076: UCPU1.AH61 58.91,64.96 57.66,64.96 v8(57.6,64.9)
  BOTTOM w0.183: v1(20.27,36.06) 19.88,35.67 UD1.H8
DDR_A_D5: length 58.8
  IN4 w0.132: v1(60.49,64.49) 60,64.99 58.12,64.99 57.62,65.49 57.32,65.49 56.99,65.82 53.76,65.82 49.65,61.71 49.65,60.34 44.74,55.42 43.06,55.42 41.08,53.44 40.39,53.44 39.41,52.47 37.11,52.47 31.8,47.16 30.18,47.16 28.83,45.8 28.1,45.8 27.2,44.9 22.51,44.9 19.88,42.26 19.88,42.06 19.04,41.22 19.04,37.33 v8(19.5,36.87)
  BOTTOM w0.076: UCPU1.AH60 60.41,64.58 v1(60.49,64.49)
  BOTTOM w0.183: UD1.F8 19.88,37.25 v8(19.5,36.87)
DDR_A_D6: length 54.2
  IN4 w0.132: v3(23.37,38.53) 23.37,38.74 24.23,39.6 26.29,39.6 26.41,39.72 26.41,41.34 26.64,41.57 26.94,41.57 27.07,41.44 27.07,39.67 27.15,39.6 27.62,39.6 27.77,39.75 27.77,42.09 28.38,42.69 29.11,42.69 29.6,43.18 29.6,43.4 31.03,44.84 32.13,44.84 32.56,44.4 32.79,44.4 33.47,45.08 33.47,45.62 37.1,49.25 40.93,49.25 44.72,53.05 45.73,53.05 52.09,59.41 52.09,60.78 54.32,63 v8(55.47,63)
  BOTTOM w0.076: UCPU1.AK61 59.22,63.33 58.63,62.74 57.18,62.74 56.96,62.52 55.82,62.52 55.5,62.84 55.5,63.02 55.47,62.99 v8(55.47,63)
  BOTTOM w0.183: v3(23.37,38.53) 23.4,38.5 23.4,38.5 23.83,38.07 UD1.E3
DDR_A_D7: length 54
  IN4 w0.132: v8(24.3,36.87) 24.53,37.1 25.62,37.1 25.75,37.22 25.75,37.48 25.9,37.63 26.56,37.63 26.69,37.5 26.69,37.15 26.89,36.94 28.16,36.94 28.54,37.32 28.54,38.51 29.59,39.56 29.59,40.37 29.43,40.53 28.9,40.53 28.74,40.69 28.74,41.05 28.9,41.21 29.43,41.21 29.59,41.37 29.59,41.68 30.38,42.46 31.93,42.46 32.83,43.37 33.12,43.37 33.5,43.74 34.65,43.74 35.18,44.27 35.18,44.49 35.73,45.04 35.73,45.89 35.88,46.04 36.34,46.04 36.49,45.89 36.49,45.61 36.62,45.48 37.49,45.48 38.41,46.4 38.41,47.13 39.54,48.25 41.63,48.25 45.28,51.9 46.01,51.9 53.1,58.99 53.1,60.4 54.62,61.92 55.26,61.92 v1(55.35,61.83)
  BOTTOM w0.076: v1(55.35,61.83) 55.39,61.87 55.39,61.95 55.81,62.36 57.03,62.36 57.24,62.58 59,62.58 59.76,63.33 UCPU1.AK60
  BOTTOM w0.183: v8(24.3,36.87) 24.68,36.48 UD1.G2
DDR_A_D8: length 47.3
  IN3 w0.076: 52.86,61.02 54.99,61.02 55.23,61.26 56.03,61.26 v1(56.59,61.82)
  IN3 w0.132: v8(20.29,41.69) 20.29,42.56 24.3,46.57 26.26,46.57 28.61,48.92 29.79,48.92 31.63,50.76 34.39,50.76 37.44,53.81 45.65,53.81 52.86,61.02
  BOTTOM w0.076: v1(56.59,61.82) 56.83,62.06 57.15,62.06 57.25,62.16 57.98,62.16 UCPU1.AM63
  BOTTOM w0.183: v8(20.29,41.69) 20.29,41.68 20.68,41.29 UD1.A7
DDR_A_D9: length 50
  IN3 w0.132: v8(55.97,61.82) 55.55,62.24 53.41,62.24 45.34,54.17 37.27,54.17 34.24,51.14 31.4,51.14 29.73,49.47 27.71,49.47 25.24,47 24.28,47 19.83,42.56 19.83,41.34 v1(20.29,40.88)
  BOTTOM w0.076: UCPU1.AM62 58.55,62.15 58.27,62.42 57.3,62.42 57.09,62.21 56.36,62.21 v8(55.97,61.82)
  BOTTOM w0.183: v1(20.29,40.88) 19.88,40.48 UD1.B8
DDR_A_D10: length 46.2
  IN3 w0.132: v1(55.78,59.13) 55.78,59.07 55.32,58.61 53.33,58.61 46.48,51.75 41.7,51.75 39.94,49.99 38.93,49.99 38.75,50.16 38.75,51.42 38.58,51.6 38.2,51.6 38.02,51.42 38.02,50.16 37.84,49.99 36.93,49.99 35.65,48.71 34.23,48.71 31.56,46.03 31.05,46.03 29.42,44.4 28.43,44.4 27.35,43.32 24.57,43.32 23.49,42.24 v8(23.49,41.67)
  BOTTOM w0.076: UCPU1.AP63 57.84,60.79 56.54,59.5 56.11,59.5 55.78,59.16 v1(55.78,59.13)
  BOTTOM w0.183: v8(23.49,41.67) 23.88,41.28 UD1.A3
DDR_A_D11: length 47.7
  IN3 w0.132: v1(24.3,41.69) 25.52,42.91 26.94,42.91 27.2,42.66 27.2,41.95 27.05,41.8 26.64,41.8 26.56,41.72 26.56,41.26 26.66,41.16 27.05,41.16 27.43,40.78 27.68,40.78 27.86,40.96 27.86,42.76 29,43.9 29.43,43.9 31.21,45.68 31.67,45.68 34.32,48.34 35.82,48.34 37.13,49.65 40.15,49.65 41.92,51.42 46.76,51.42 53.56,58.23 55.6,58.23 56.39,59.02 v1(56.39,59.12)
  BOTTOM w0.076: UCPU1.AP62 58.6,60.79 58.27,60.46 57.73,60.46 56.93,59.67 56.93,59.66 56.39,59.12 v1(56.39,59.12)
  BOTTOM w0.183: v1(24.3,41.69) 24.68,41.31 UD1.A2
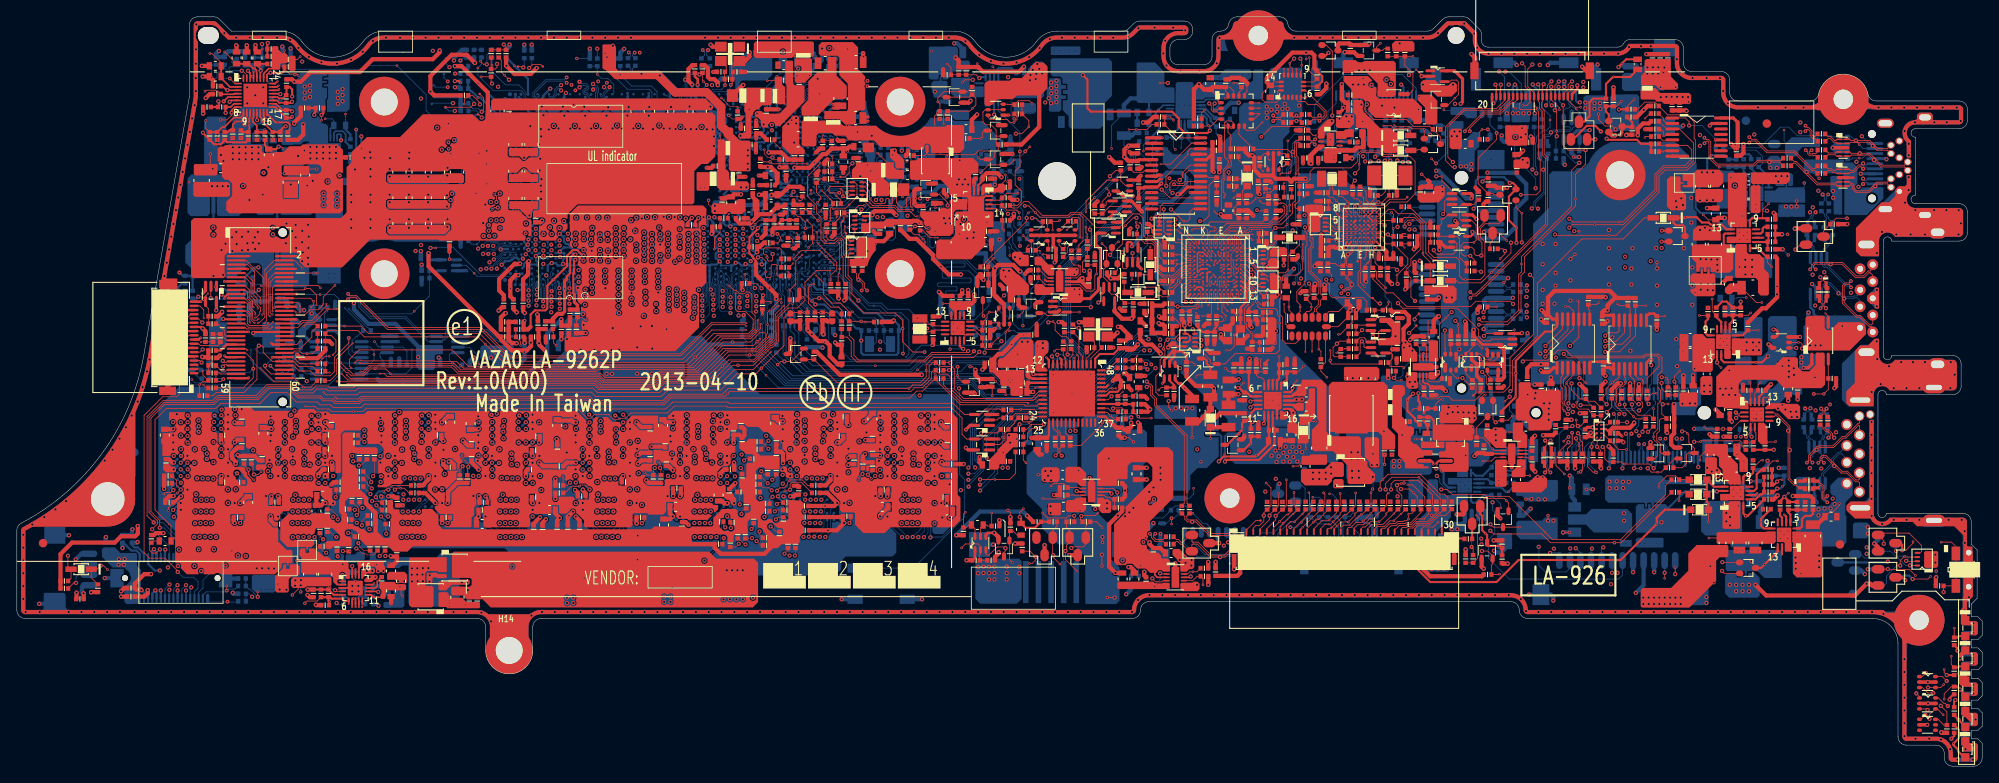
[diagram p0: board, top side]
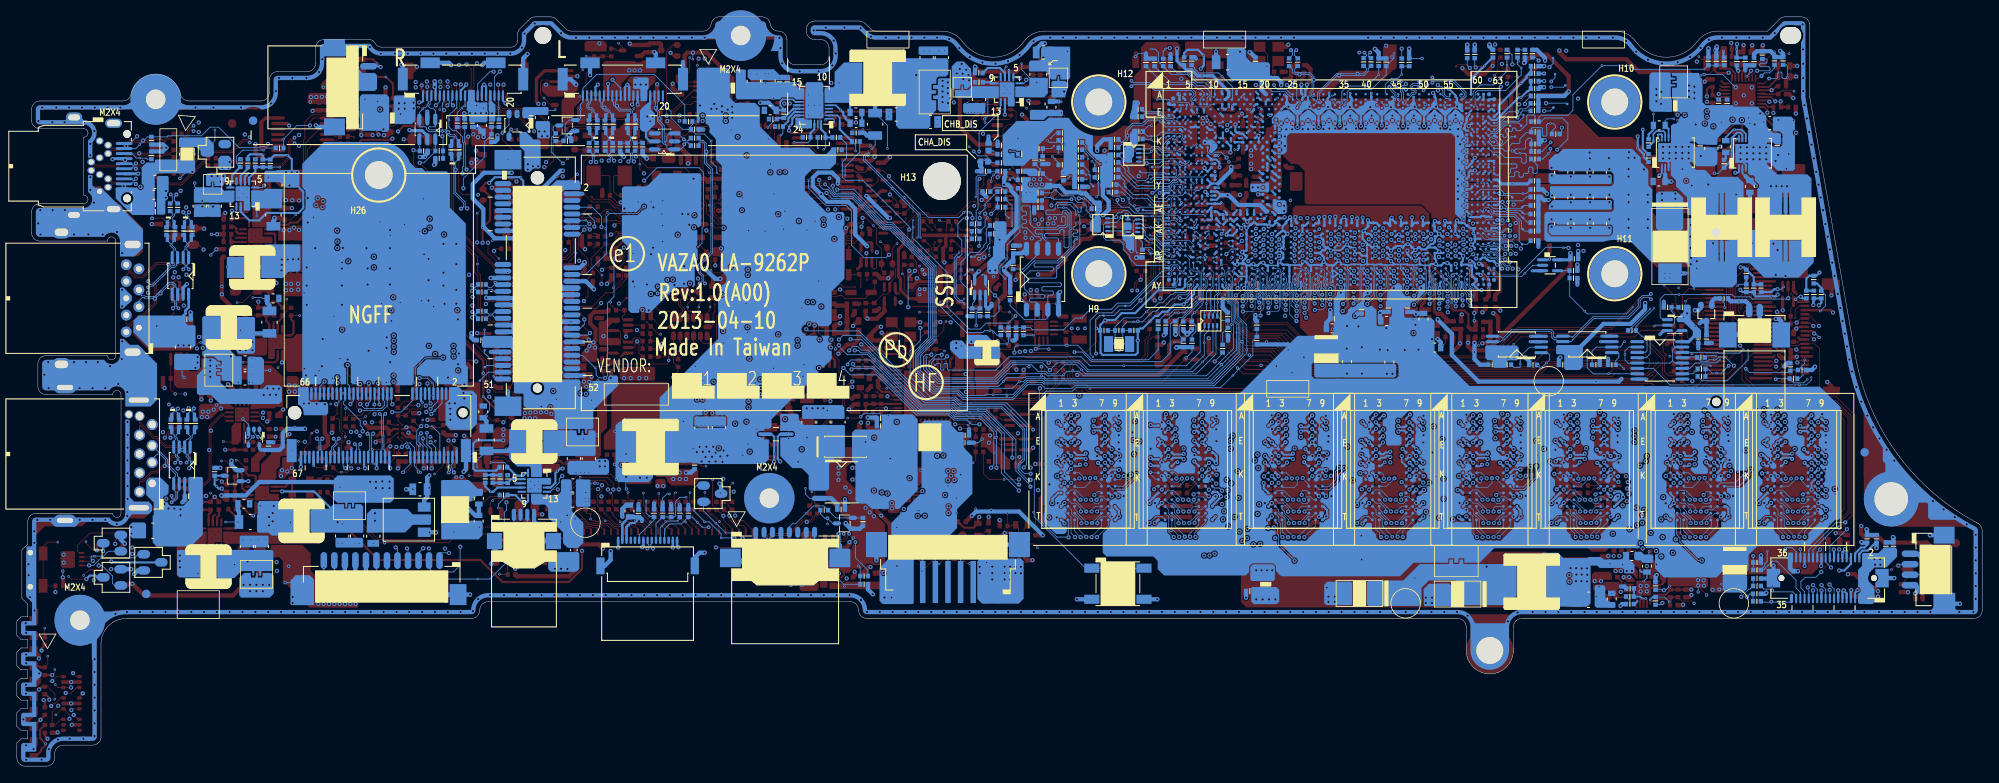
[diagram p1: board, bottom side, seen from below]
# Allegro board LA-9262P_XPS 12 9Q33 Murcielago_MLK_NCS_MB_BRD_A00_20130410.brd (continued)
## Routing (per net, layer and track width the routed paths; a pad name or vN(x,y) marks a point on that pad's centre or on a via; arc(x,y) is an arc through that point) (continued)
DDR_A_D12: length 49.6
  IN3 w0.132: v1(55.4,60.89) 55.16,60.65 53.06,60.65 45.82,53.4 37.57,53.4 34.57,50.41 31.82,50.41 29.94,48.53 28.72,48.53 25.12,44.92 23.7,44.92 20.8,42.02 20.8,40.6 v8(20.28,40.08)
  BOTTOM w0.076: v1(55.4,60.89) 55.95,61.44 56.75,61.44 57.25,61.95 57.82,61.95 57.89,61.87 58.11,61.87 58.18,61.94 58.47,61.94 58.55,61.86 58.75,61.86 58.93,62.04 UCPU1.AM61
  BOTTOM w0.183: v8(20.28,40.08) 20.26,40.07 19.88,39.69 UD1.C8
DDR_A_D13: length 51.1
  IN3 w0.132: v1(20.28,39.26) 21.13,40.11 21.13,41.82 23.86,44.55 25.28,44.55 27.45,46.72 29.86,46.72 31.21,48.07 31.21,48.53 32.73,50.05 34.72,50.05 37.72,53.05 45.99,53.05 53.23,60.29 55.41,60.29 56,60.87 v8(56.01,60.87)
  BOTTOM w0.076: UCPU1.AM60 59.85,62.04 59.57,61.76 58.89,61.76 58.83,61.7 58.5,61.7 58.41,61.79 58.26,61.79 58.19,61.72 57.83,61.72 57.76,61.79 57.33,61.79 56.78,61.24 56.38,61.24 v8(56.01,60.87)
  BOTTOM w0.183: UD1.D7 20.68,38.87 20.29,39.26 v1(20.28,39.26)
DDR_A_D14: length 47.1
  IN3 w0.132: v1(24.28,40.09) 24.81,39.56 25.6,39.56 25.8,39.76 25.8,40.17 25.95,40.32 26.54,40.32 26.65,40.21 26.65,39.64 26.76,39.53 27.24,39.53 28.21,40.5 28.21,42.23 31.35,45.36 31.8,45.36 34.32,47.88 35.82,47.88 37.27,49.32 40.28,49.32 41.95,50.99 46.96,50.99 53.79,57.82 55.75,57.82 57.04,59.11 v8(57.04,59.13)
  BOTTOM w0.076: UCPU1.AP61 59.04,60.79 58.71,60.47 58.49,60.47 58.34,60.31 57.8,60.31 57.1,59.61 57.1,59.2 57.03,59.13 v8(57.04,59.13)
  BOTTOM w0.183: v1(24.28,40.09) 24.68,39.69 UD1.C2
DDR_A_D15: length 48
  IN3 w0.132: v1(23.41,40.09) 24.3,39.2 27.38,39.2 28.57,40.4 28.57,42.13 31.48,45.04 31.93,45.04 34.38,47.48 35.88,47.48 37.37,48.97 40.39,48.97 42.05,50.63 47.11,50.63 53.97,57.49 55.98,57.49 57.17,58.69 57.47,58.69 59.1,60.31 v8(60.12,60.31)
  BOTTOM w0.076: v8(60.12,60.31) 59.95,60.49 UCPU1.AP60
  BOTTOM w0.183: UD1.C3 23.84,39.67 v1(23.41,40.09)
DDR_A_D16: length 42.9
  IN4 w0.076: v1(60.79,61.36) 60.89,61.26 60.89,60.59 60.46,60.16 60.46,59.75 60.38,59.67
  IN4 w0.132: 60.38,59.67 60.01,59.3 59.01,59.3 57.3,57.59 54.1,57.59 46.69,50.19 45.88,50.19 45.15,49.46 45.15,48.66 45.15,48.66 45.15,46.84 43.69,45.37 41.86,45.37 38.79,42.3 35.81,42.3 35.71,42.2 34.92,42.2 34.03,41.31 34.03,39.26 32.71,37.94 v8(32.71,37.66)
  BOTTOM w0.076: UCPU1.AP58 61.16,60.99 v1(60.79,61.36)
  BOTTOM w0.183: v8(32.71,37.66) 32.32,37.27 UD2.F7
DDR_A_D17: length 44.3
  IN4 w0.132: v1(60.47,60.84) 59.95,60.84 57.12,58 53.92,58 46.5,50.58 45.71,50.58 44.82,49.69 44.82,47.03 43.57,45.78 41.81,45.78 38.69,42.66 35.71,42.66 35.57,42.52 34.71,42.52 33.68,41.5 33.68,39.39 32.2,37.91 32.2,36.69 v8(32.79,36.11)
  BOTTOM w0.076: v1(60.47,60.84) 60.61,60.84 61.11,60.34 UCPU1.AR58
  BOTTOM w0.183: UD2.H7 32.35,35.67 v8(32.79,36.11)
DDR_A_D18: length 43.3
  IN4 w0.076: 61.28,59.2 61.6,59.52 61.6,59.99 62.04,60.42 62.04,62.19 v1(61.63,62.59)
  IN4 w0.132: v8(35,38.47) 35,38.17 35.15,38.02 36.88,38.02 37.1,38.24 37.1,38.6 37.32,38.81 37.53,38.81 37.69,38.65 37.69,38.19 37.84,38.04 38.1,38.04 38.25,38.19 38.25,39.84 42.54,44.13 44.35,44.13 48.25,48.04 48.25,49.29 55.26,56.3 57.35,56.3 58.82,57.77 59.85,57.77 61.28,59.2
  BOTTOM w0.076: v1(61.63,62.59) 61.94,62.29 UCPU1.AM57
  BOTTOM w0.183: UD2.E3 35.4,38.07 v8(35,38.47)
DDR_A_D19: length 45
  IN4 w0.076: 61.6,59.05 61.77,59.22 61.77,59.9 62.19,60.32 62.19,62.72 61.65,63.26 v1(61.64,63.26)
  IN4 w0.132: v8(34.79,35.83) 34.93,35.97 34.93,37.31 35.31,37.69 38.35,37.69 38.57,37.9 38.57,39.68 42.61,43.72 44.4,43.72 48.64,47.96 48.64,49.21 55.34,55.92 57.55,55.92 59.02,57.39 59.94,57.39 61.6,59.05
  BOTTOM w0.076: v1(61.64,63.26) 61.97,63.59 UCPU1.AK57
  BOTTOM w0.183: UD2.H3 34.95,35.67 v8(34.79,35.83)
DDR_A_D20: length 47
  IN4 w0.132: v8(60.78,62.6) 60.68,62.5 60.29,62.5 58.39,60.59 58.39,59.8 57.02,58.43 53.77,58.43 46.35,51.02 45.64,51.02 44.42,49.8 44.42,47.22 43.38,46.18 41.66,46.18 38.48,42.99 35.55,42.99 35.41,42.85 34.57,42.85 33.37,41.64 33.09,41.64 32.71,41.26 32.21,41.26 32.14,41.34 31.48,41.34 31.1,40.96 31.1,38.58 31.87,37.81 31.87,36.11 v1(31.84,36.07)
  BOTTOM w0.076: UCPU1.AL58 61.12,62.94 v8(60.78,62.6)
  BOTTOM w0.183: UD2.H8 31.44,35.67 v1(31.84,36.07)
DDR_A_D21: length 48.1
  IN4 w0.076: v1(61.66,63.87) 61.49,63.87 60.5,62.88 60.37,62.88
  IN4 w0.132: v8(31.06,36.87) 31.06,37 30.59,37.47 30.59,37.87 30.78,38.06 30.78,41.2 31.52,41.95 32.03,41.95 33.02,42.93 33.3,42.93 33.68,43.3 34.89,43.3 35.49,43.9 36.65,43.9 36.9,44.16 38.83,44.16 41.83,47.16 43.86,47.16 44.1,47.39 44.1,50.06 45.44,51.4 46.15,51.4 53.79,59.04 53.79,59.88 55.29,61.38 56.81,61.38 58.31,62.88 60.37,62.88
  BOTTOM w0.076: UCPU1.AK58 61.38,63.59 v1(61.66,63.87)
  BOTTOM w0.183: UD2.F8 31.44,37.25 v8(31.06,36.87)
DDR_A_D22: length 41.8
  IN4 w0.076: v8(62.56,60.66) 62.56,60.47 61.97,59.88 61.97,58.94 61.81,58.78
  IN4 w0.132: v1(35.83,36.87) 36.32,37.36 38.14,37.36 38.27,37.22 38.27,36.64 38.42,36.49 38.7,36.49 38.89,36.68 38.89,39.5 42.72,43.33 44.46,43.33 49.07,47.94 49.07,49.14 55.49,55.56 57.75,55.56 59.28,57.09 60.12,57.09 61.81,58.78
  BOTTOM w0.076: v8(62.56,60.66) 62.25,60.34 UCPU1.AR57
  BOTTOM w0.183: UD2.F2 36.23,37.27 v1(35.83,36.87)
DDR_A_D23: length 42.9
  IN4 w0.076: v1(62.56,61.27) 62.74,61.27 62.96,61.06 62.96,60.53 62.58,60.15 62.49,60.15 62.15,59.81 62.15,58.53
  IN4 w0.132: v1(35.83,36.06) 36.29,35.6 38.45,35.6 39.26,36.41 39.26,39.38 42.88,43 44.59,43 49.42,47.84 49.42,48.88 50.13,49.59 51.02,49.59 56.51,55.08 57.88,55.08 58.9,56.1 59.71,56.1 62.15,58.53
  BOTTOM w0.076: v1(62.56,61.27) 62.2,61.64 UCPU1.AN57
  BOTTOM w0.183: v1(35.83,36.06) 36.24,36.46 UD2.G2
DDR_A_D24: length 45
  IN3 w0.076: v1(63.53,61.32) 63.41,61.32 63.09,61 63.09,60.47 62.83,60.21 62.61,60.21
  IN3 w0.132: v8(32.56,41.75) 32.43,41.88 32.43,42.45 32.85,42.87 32.85,43.06 34.86,45.06 37.27,45.06 37.84,44.5 39.34,44.5 39.47,44.62 39.47,46.04 39.59,46.16 40.61,46.16 40.74,46.04 40.74,44.62 40.86,44.5 40.99,44.5 42.71,46.22 43.25,46.22 45.89,48.86 47.09,48.86 54.58,56.35 56.64,56.35 57.41,57.12 57.56,57.12 59.19,58.76 60.18,58.76 60.27,58.84 61.43,58.84 62.01,59.42 62.01,59.72 62.5,60.21 62.61,60.21
  BOTTOM w0.076: v1(63.53,61.32) 63.2,60.99 UCPU1.AP55
  BOTTOM w0.183: UD2.A7 32.25,41.27 32.56,41.59 v8(32.56,41.75)
DDR_A_D25: length 45.3
  IN3 w0.132: v1(31.85,40.88) 32.34,40.88 33.52,42.06 33.52,42.38 33.34,42.56 33.34,42.96 34.28,43.9 36.39,43.9 36.62,44.14 39.67,44.14 39.8,44.27 39.8,45.48 39.92,45.61 40.2,45.61 40.33,45.48 40.33,44.39 40.54,44.17 41.12,44.17 42.81,45.86 43.47,45.86 45.68,48.07 47.92,48.07 48.15,48.3 48.15,49.36 54.81,56.02 56.84,56.02 57.16,56.34 57.39,56.34 58.97,57.92 59.74,57.92 60.24,58.43 61.61,58.43 62.4,59.22 62.76,59.22 63.06,59.52 63.06,59.96 63.47,60.36 v1(63.47,60.67)
  BOTTOM w0.076: UCPU1.AR55 63.13,60.34 v1(63.47,60.67)
  BOTTOM w0.183: v1(31.85,40.88) 31.44,40.48 UD2.B8
DDR_A_D26: length 46.5
  IN3 w0.076: 65.27,59.45 65.27,61.28 64.92,61.63 64.92,62.05 v1(64.49,62.48)
  IN3 w0.132: 65.27,59.45 65.27,59.27 63.06,57.06 61.64,57.06 61.26,56.68 61.26,54.57 60.84,54.15 60.84,53.52 60.34,53.02 55.37,53.02 51.51,49.16 51.51,48.83 48.79,46.11 46.67,46.11 44.5,43.94 43.99,43.94 41.9,41.85 41.9,41.11 41.77,40.98 41.42,40.98 41.29,41.11 41.29,41.72 41.17,41.85 40.81,41.85 40.69,41.72 40.69,40.63 40.19,40.13 37.86,40.13 37.35,39.61 36.04,39.61 35.84,39.81 v1(35.84,40.07)
  BOTTOM w0.076: UCPU1.AM54 64.29,62.29 v1(64.49,62.48)
  BOTTOM w0.183: UD2.C2 v1(35.84,40.07)
DDR_A_D27: length 47.8
  IN3 w0.076: 65.53,59.12 65.53,61.35 65.2,61.68 65.2,62.17 64.98,62.38 64.98,63.45 64.5,63.94 v1(64.48,63.94)
  IN3 w0.132: v8(35.03,40.06) 35.03,39.32 35.28,39.08 37.47,39.08 38.06,39.67 40.21,39.67 41.11,40.58 42.08,40.58 42.28,40.78 42.28,41.75 44.15,43.61 44.66,43.61 46.8,45.76 48.9,45.76 51.83,48.68 51.83,49.03 55.48,52.68 60.51,52.68 61.23,53.4 61.23,53.89 61.59,54.24 61.86,54.24 62.14,54.52 62.14,55.42 62.15,55.42 62.15,55.64 65.53,59.02 65.53,59.12
  BOTTOM w0.076: v1(64.48,63.94) 64.13,63.59 UCPU1.AK54
  BOTTOM w0.183: UD2.C3 35.42,39.67 v8(35.03,40.06)
DDR_A_D28: length 48.2
  IN3 w0.132: v1(63.55,63.24) 63.4,63.24 62.82,63.82 62.3,63.82 62.15,63.67 62.15,60.41 61.64,59.91 61.64,59.7 61.21,59.27 60.29,59.27 60.04,59.01 58.97,59.01 57.64,57.68 57.36,57.68 56.36,56.68 54.33,56.68 46.83,49.19 45.1,49.19 44.56,49.73 42.32,49.73 40.74,48.15 39.41,48.15 38.29,47.03 37.79,47.03 37.35,46.58 34.55,46.58 32.53,44.56 32.53,43.01 31.65,42.13 31.65,42.13 31.25,41.73 31.25,40.66 v8(31.83,40.08)
  BOTTOM w0.076: v1(63.55,63.24) 63.24,62.94 UCPU1.AL55
  BOTTOM w0.183: v8(31.83,40.08) 31.82,40.08 31.82,40.05 UD2.C8
DDR_A_D29: length 50.3
  IN3 w0.132: v8(63.34,64.03) 63.02,64.35 61.36,64.35 61.18,64.17 61.18,60.36 61.26,60.29 61.26,59.86 60.99,59.59 60.22,59.59 59.91,59.28 58.59,59.28 57.59,58.28 57.45,58.28 56.18,57.01 54.1,57.01 47.27,50.18 42.26,50.18 40.56,48.48 39.29,48.48 38.17,47.36 37.77,47.36 37.48,47.65 36.96,47.65 36.3,46.99 34.5,46.99 32.11,44.6 31.66,44.6 30.55,43.49 30.55,42.08 30.78,41.84 30.78,40.33 v1(31.85,39.27)
  BOTTOM w0.076: UCPU1.AK55 63.06,63.76 v8(63.34,64.03)
  BOTTOM w0.183: v1(31.85,39.27) 32.24,38.88 UD2.D7
DDR_A_D30: length 45.1
  IN3 w0.076: 60.17,56.91 60.85,57.59 62.76,57.59 64.35,59.19 64.35,60.33 64.54,60.52 v1(64.55,60.52)
  IN3 w0.132: 60.17,56.91 59.89,56.63 59.89,56.35 59.57,56.03 58.96,56.03 57.63,54.7 55.43,54.7 49.58,48.85 49.58,47.82 48.53,46.78 46.28,46.78 44.1,44.59 43.59,44.59 41.49,42.49 40.23,42.49 40.01,42.27 40.01,41.47 39.88,41.34 39.48,41.34 39.36,41.47 39.36,42.37 39.24,42.49 38.22,42.49 38.09,42.36 38.09,40.9 37.97,40.77 37.56,40.77 37.43,40.9 37.43,42.36 37.31,42.49 36.51,42.49 36.17,42.15 35.53,42.15 35.02,41.64 v8(35.02,41.63)
  BOTTOM w0.076: v1(64.55,60.52) 64.36,60.34 UCPU1.AR54
  BOTTOM w0.183: v8(35.02,41.63) 35.08,41.63 UD2.A3
DDR_A_D31: length 46.8
  IN3 w0.076: v1(64.48,61.87) 64.48,61.76 64.92,61.33 64.92,60.35 64.52,59.95 64.52,59 62.86,57.34 60.98,57.34 60.4,56.76 60.4,56.4
  IN3 w0.132: v1(35.83,41.66) 36.11,41.38 36.98,41.38 37.1,41.25 37.1,40.58 37.23,40.45 38.3,40.45 38.42,40.58 38.42,42.02 38.55,42.15 38.91,42.15 39.03,42.02 39.03,40.78 39.16,40.65 40.2,40.65 40.33,40.78 40.33,42.04 40.46,42.17 41.71,42.17 43.81,44.27 44.31,44.27 46.49,46.44 48.66,46.44 51.14,48.93 51.14,49.26 55.32,53.43 59.56,53.43 59.86,53.73 59.86,54.62 60.4,55.16 60.4,56.4
  BOTTOM w0.076: v1(64.48,61.87) 64.25,61.64 UCPU1.AN54
  BOTTOM w0.183: UD2.A2 36.22,41.27 v1(35.83,41.66)
DDR_A_D32: length 29.6
  IN4 w0.132: v8(44.14,36.87) 44.03,36.98 44.03,42.03 44.57,42.57 44.77,42.57 50.08,47.88 50.4,47.88 51.03,48.5 51.03,48.89 56.73,54.6 58.06,54.6 59.07,55.61 59.86,55.61 v1(60.8,56.56)
  BOTTOM w0.076: UCPU1.AY58 61.19,57.11 60.8,56.72 v1(60.8,56.56)
  BOTTOM w0.183: UD4.F8 44.52,37.25 v8(44.14,36.87)
DDR_A_D33: length 32.5
  IN4 w0.132: v1(44.92,36.09) 44.94,36.07 44.94,36.07 45.44,36.57 45.44,37.07 44.35,38.16 44.35,41.89 44.71,42.25 44.91,42.25 50.17,47.51 50.49,47.51 51.55,48.57 51.55,48.96 55.87,53.28 58.16,53.28 58.54,53.66 58.54,54.44 58.95,54.85 59.71,54.85 v1(60.8,55.94)
  BOTTOM w0.076: UCPU1.AW58 61.19,57.6 61.3,57.49 61.45,57.34 61.45,57.07 61.27,56.9 61.27,56.41 v1(60.8,55.94)
  BOTTOM w0.183: UD4.H8 44.54,35.67 44.93,36.06 44.9,36.08 44.9,36.09 44.95,36.04 44.95,36.06 v1(44.92,36.09)
DDR_A_D34: length 31.4
  IN4 w0.076: 62.86,53.73 62.86,54.37 62.94,54.44 62.94,54.9 62.58,55.25 v8(62.54,55.25)
  IN4 w0.132: v1(48.93,37.67) 49.09,37.83 49.09,38.53 49.66,39.11 50.32,39.11 52.03,40.82 52.03,43.8 52.18,43.95 52.75,43.95 52.85,43.85 52.85,42.48 53.11,42.23 53.39,42.23 53.64,42.48 53.64,43.73 53.84,43.93 54.17,43.93 58.85,48.62 59.24,48.62 60.29,49.67 61.18,49.67 61.58,50.06 61.58,50.56 62.76,51.75 62.76,53.29 62.77,53.29 62.77,53.31 62.86,53.4 62.86,53.73
  BOTTOM w0.076: v8(62.54,55.25) UCPU1.AY56
  BOTTOM w0.183: UD4.F2 49.32,37.28 v1(48.93,37.67)
DDR_A_D35: length 31.3
  IN4 w0.132: v1(47.82,36.1) 47.85,36.1 48.47,36.73 48.47,37.96 48.66,38.15 48.66,38.6 49.58,39.52 49.94,39.52 50.44,40.02 50.77,40.02 51.58,40.83 51.58,44.21 51.85,44.47 54.25,44.47 58.72,48.94 59.11,48.94 59.84,49.67 59.84,50.6 62.36,53.12 62.36,53.29 62.6,53.52 62.6,54.6 v1(62.55,54.64)
  BOTTOM w0.076: UCPU1.AW56 62.56,57.88 62.81,57.63 62.81,56.96 62.7,56.85 62.7,55.64 62.92,55.42 62.92,55.02 62.55,54.64 v1(62.55,54.64)
  BOTTOM w0.183: v1(47.82,36.1) 47.82,36.09 48.24,35.67 UD4.H3
DDR_A_D36: length 32.2
  IN4 w0.132: v8(45.73,36.04) 46.25,36.57 46.25,38 45.73,38.52 45.73,41.19 46.29,41.75 46.29,42.71 47.59,44.01 48.45,44.01 52.93,48.5 52.93,49.09 56.19,52.34 58.54,52.34 59.86,53.66 59.86,53.96 60.62,54.72 v1(60.8,54.72)
  BOTTOM w0.076: UCPU1.AV58 61.19,58.39 61.46,58.11 61.46,57.55 61.61,57.41 61.61,57 61.43,56.83 61.43,56.22 61.27,56.07 61.27,55.19 v1(60.8,54.72)
  BOTTOM w0.183: v8(45.73,36.04) 45.35,35.67 UD4.H7
DDR_A_D37: length 31.9
  IN4 w0.132: v8(45.78,37.62) 45.4,38 45.4,41.35 45.96,41.91 45.96,42.85 47.55,44.43 48.42,44.43 48.91,44.93 48.91,45.37 49.35,45.81 49.79,45.81 50.2,46.22 50.2,46.66 52.07,48.53 52.07,49.03 55.92,52.87 58.39,52.87 58.87,53.35 58.87,54.14 59.2,54.47 59.94,54.47 v1(60.79,55.33)
  BOTTOM w0.076: UCPU1.AU58 60.89,58.88 60.89,57.08 60.74,56.93 60.63,56.93 60.39,56.69 60.39,55.74 v1(60.79,55.33)
  BOTTOM w0.183: v8(45.78,37.62) 45.42,37.27 UD4.F7
DDR_A_D38: length 33.3
  IN4 w0.076: v1(62.9,58.33) 63.04,58.19 63.04,55.08 63.14,54.97 63.14,54.42 63.09,54.37 63.09,54.22
  IN4 w0.132: v8(48.93,36.87) 49.29,37.22 49.32,37.22 50.2,38.1 50.82,38.1 52.78,40.05 52.78,41.24 52.9,41.36 53.28,41.36 53.41,41.24 53.41,40.42 53.61,40.22 53.92,40.22 54.12,40.42 54.12,43.43 58.99,48.29 59.37,48.29 60.02,48.94 62.12,48.94 63.36,50.18 63.36,51.26 63.09,51.53 63.09,54.22
  BOTTOM w0.076: UCPU1.AV56 62.44,58.54 62.69,58.54 v1(62.9,58.33)
  BOTTOM w0.183: UD4.G2 49.32,36.48 v8(48.93,36.87)
DDR_A_D39: length 33.1
  IN4 w0.076: v1(62.55,59.68) 62.47,59.6 62.47,55.81 62.15,55.49 62.15,54.27 62.29,54.12 62.29,53.52 62.05,53.28 62.04,53.28 61.94,53.17
  IN4 w0.132: 61.94,53.17 61.29,52.53 61.29,52.51 59.74,50.96 58.94,50.96 58.49,50.51 58.49,49.17 54.12,44.8 51.51,44.8 50.71,43.99 50.71,42.6 50.44,42.33 49.73,42.33 49.63,42.43 49.63,42.81 49.45,42.99 49.18,42.99 48.37,42.18 47.86,42.18 47.6,41.92 47.6,39.02 48.1,38.51 48.1,38.52 48.08,38.54 48.08,38.54 v8(48.07,38.54)
  BOTTOM w0.076: UCPU1.AU56 62.43,59.56 v1(62.55,59.68)
  BOTTOM w0.183: UD4.E3 48.52,38.1 48.1,38.51 48.1,38.52 48.08,38.54 48.08,38.54 v8(48.07,38.54)
DDR_A_D40: length 30.5
  IN3 w0.076: v8(63.54,56.45) 64.13,55.86 64.13,53.84 63.62,53.33 63.52,53.33 63.42,53.23
  IN3 w0.132: 63.42,53.23 61.2,51.01 55.86,51.01 53.28,48.42 53.28,46.98 52.82,46.52 51.66,46.52 49.38,44.24 47.68,44.24 47.28,43.85 47.28,43.66 47.57,43.37 47.57,43.14 45.31,40.88 v1(44.93,40.88)
  BOTTOM w0.076: v8(63.54,56.45) 63.62,56.53 UCPU1.AY54
  BOTTOM w0.183: UD4.B8 44.52,40.48 v1(44.93,40.88)
DDR_A_D41: length 31.1
  IN3 w0.076: 63.34,53.51 63.57,53.51 63.95,53.88 63.95,55.41 v1(63.51,55.84)
  IN3 w0.132: 63.34,53.51 63.24,53.51 61.15,51.42 55.82,51.42 52.95,48.55 52.95,47.18 52.62,46.85 51.52,46.85 49.24,44.56 47.54,44.56 46.78,43.8 46.78,43.52 47.04,43.27 47.04,43.07 46.5,42.53 45.23,42.53 44.93,42.23 v8(44.93,41.69)
  BOTTOM w0.076: v1(63.51,55.84) 63.17,56.18 63.17,56.63 63.35,56.8 63.35,57.44 63.62,57.7 UCPU1.AW54
  BOTTOM w0.183: v8(44.93,41.69) 45.32,41.3 UD4.A7
DDR_A_D42: length 32.6
  IN3 w0.132: v1(48.94,41.69) 49.52,42.28 50.49,42.28 50.64,42.13 50.64,41.41 50.82,41.24 51.12,41.24 51.3,41.41 51.3,42.18 51.4,42.28 53.11,42.28 53.28,42.46 53.28,43.4 53.11,43.57 52.17,43.57 52.09,43.65 52.09,43.95 52.28,44.14 54.02,44.14 56.64,46.76 57.49,46.76 59.05,48.32 62.94,48.32 64.24,49.62 64.24,51.38 65.59,52.74 65.59,54.89 v8(65.65,54.95)
  BOTTOM w0.076: v8(65.65,54.95) 65.65,54.89 64.97,55.57 UCPU1.AY52
  BOTTOM w0.183: UD4.A2 49.32,41.31 v1(48.94,41.69)
DDR_A_D43: length 32.6
  IN3 w0.076: 65.27,53.86 65.27,55.54 64.6,56.21 64.52,56.21 v1(64.51,56.2)
  IN3 w0.132: v8(48.13,41.67) 49.07,42.61 52.72,42.61 52.9,42.79 52.9,43.04 52.72,43.22 51.35,43.22 51.23,43.35 51.23,43.54 52.31,44.62 53.71,44.62 56.16,47.08 57.15,47.08 58.77,48.7 62.84,48.7 63.91,49.78 63.91,51.51 65.27,52.87 65.27,53.86
  BOTTOM w0.076: v1(64.51,56.2) 64.51,56.24 64.82,56.54 64.82,56.98 64.7,57.1 64.7,57.34 64.97,57.6 UCPU1.AW52
  BOTTOM w0.183: v8(48.13,41.67) 48.52,41.28 UD4.A3
DDR_A_D44: length 33.5
  IN3 w0.076: v8(63.51,55.21) 63.16,54.87 63.16,54.67 62.81,54.32
  IN3 w0.132: 62.81,54.32 62.33,53.84 62.33,53.51 61.06,52.24 55.66,52.24 52.27,48.85 52.27,48.5 49.07,45.3 47.11,45.3 44.99,43.18 44.58,43.18 43.83,42.43 43.83,40.34 v1(44.91,39.26)
  BOTTOM w0.076: v8(63.51,55.21) 63.51,55.32 63.01,55.81 63.01,56.7 63.2,56.89 63.2,57.86 63.72,58.38 UCPU1.AV54
  BOTTOM w0.183: UD4.D7 45.3,38.87 v1(44.91,39.26)
DDR_A_D45: length 33.1
  IN3 w0.132: v8(44.92,40.08) 44.24,40.75 44.24,42.38 44.72,42.85 45.22,42.85 47.26,44.89 49.12,44.89 52.59,48.37 52.59,48.69 55.78,51.88 61.16,51.88 62.63,53.35 62.63,53.7 v1(63.53,54.6)
  BOTTOM w0.076: UCPU1.AU54 63.72,58.99 63.4,58.67 63.4,58.3 63.04,57.94 63.04,56.95 62.86,56.76 62.86,55.73 63.11,55.48 63.11,55.03 v1(63.53,54.6)
  BOTTOM w0.183: v8(44.92,40.08) 44.9,40.08 44.9,40.05 UD4.C8
DDR_A_D46: length 32
  IN3 w0.076: v8(65.65,55.56) 66.09,55.13 66.09,54.75 65.93,54.6 65.93,54.24
  IN3 w0.132: 65.93,54.24 65.93,50.65 63.18,47.89 59.2,47.89 57.75,46.44 56.89,46.44 53.72,43.27 53.72,41.62 51.58,39.48 49.52,39.48 v1(48.92,40.09)
  BOTTOM w0.076: UCPU1.AV52 65.04,58.53 65.22,58.34 65.22,58.03 65.27,57.98 65.27,57.77 65.22,57.72 65.22,57.38 65.24,57.37 65.24,57.12 65.12,57 65.12,56.1 v8(65.65,55.56)
  BOTTOM w0.183: UD4.C2 49.32,39.69 v1(48.92,40.09)
DDR_A_D47: length 34.3
  IN3 w0.076: v1(65.65,56.17) 66.26,55.57 66.26,54.09
  IN3 w0.132: v8(48.07,40.09) 48.05,40.09 49.02,39.13 51.68,39.13 54.05,41.49 54.05,43.04 57.04,46.04 57.86,46.04 59.25,47.43 63.19,47.43 66.26,50.5 66.26,54.09
  BOTTOM w0.076: v1(65.65,56.17) 65.27,56.55 65.27,56.94 65.39,57.05 65.39,57.43 65.38,57.44 65.38,57.66 65.42,57.71 65.42,58.04 65.38,58.09 65.38,58.68 64.97,59.09 UCPU1.AU52
  BOTTOM w0.183: v8(48.07,40.09) 48.05,40.09 48.48,39.67 UD4.C3
DDR_A_D48: length 38.9
  IN4 w0.076: 72.05,58.76 72.05,59.02 73.12,60.08 73.12,62.14 73.3,62.32 73.3,63 72.36,63.94 v8(72.13,63.94)
  IN4 w0.132: 72.05,58.76 71.95,58.66 71.95,53.56 71.77,53.38 71.77,50.46 71.1,49.78 71.1,49.18 64.61,42.69 64.61,42.24 64.48,42.1 64.21,42.1 64.08,41.97 64.08,41.71 64.21,41.57 64.48,41.57 64.61,41.44 64.61,41.18 64.48,41.05 64.21,41.05 64.08,40.91 64.08,40.65 64.21,40.52 64.48,40.52 64.61,40.39 64.61,40.12 64.48,39.99 64.21,39.99 64.08,39.86 64.08,39.59 64.21,39.46 64.48,39.46 64.61,39.33 64.61,37.92 62.3,35.61 60.92,35.61 v1(60.47,36.06)
  BOTTOM w0.076: v8(72.13,63.94) 72.48,63.59 UCPU1.AK40
  BOTTOM w0.183: UD5.G2 60.88,36.46 v1(60.47,36.06)
DDR_A_D49: length 39.6
  IN4 w0.076: v1(72.09,63.27) 72.48,62.89 72.48,62.46 72.71,62.22 72.71,60.31 71.94,59.54 71.33,59.54 70.71,58.92 70.71,58.76
  IN4 w0.132: v8(59.43,35.83) 60.02,36.42 60.02,37.09 60.76,37.83 62.25,37.83 62.73,38.32 62.73,39.66 63.43,40.36 63.43,43.46 66.45,46.48 66.64,46.48 66.91,46.21 67.09,46.21 67.28,46.39 67.28,46.58 67.01,46.85 67.01,47.04 67.2,47.22 67.38,47.22 67.65,46.95 67.84,46.95 68.03,47.14 68.03,47.33 67.76,47.6 67.76,47.78 67.94,47.97 68.13,47.97 68.4,47.7 68.59,47.7 68.77,47.89 68.77,48.07 68.5,48.34 68.5,48.53 68.69,48.72 68.88,48.72 69.15,48.45 69.33,48.45 69.52,48.63 69.52,48.82 69.25,49.09 69.25,49.28 69.59,49.62 69.59,55.08 70.71,56.2 70.71,58.76
  BOTTOM w0.076: UCPU1.AK42 71.79,63.59 72.09,63.28 v1(72.09,63.27)
  BOTTOM w0.183: v8(59.43,35.83) 59.59,35.67 UD5.H3
DDR_A_D50: length 36.1
  IN4 w0.076: 68.17,59.37 68.35,59.55 69.54,59.55 69.84,59.86 69.84,61.46 70.12,61.73 70.9,61.73 v1(71.16,61.99)
  IN4 w0.132: 68.17,59.37 67.46,58.66 67.46,57.29 67.08,56.91 67.08,55.28 66.34,54.55 66.34,54.18 66.47,54.05 66.72,54.05 66.85,53.92 66.85,53.65 66.72,53.52 66.47,53.52 66.34,53.39 66.34,53.12 66.47,52.99 66.72,52.99 66.85,52.86 66.85,52.6 66.72,52.46 66.47,52.46 66.34,52.33 66.34,52.07 66.47,51.94 66.72,51.94 66.85,51.8 66.85,51.54 66.72,51.41 66.47,51.41 66.34,51.28 66.34,50.63 58.35,42.64 58.35,37.79 57.73,37.17 57.73,36.49 v8(57.28,36.04)
  BOTTOM w0.076: UCPU1.AM43 70.86,62.29 v1(71.16,61.99)
  BOTTOM w0.183: v8(57.28,36.04) 56.91,35.67 UD5.H7
DDR_A_D51: length 37
  IN4 w0.076: v1(70.2,62.55) 69.97,62.55 69.44,62.01 69.08,62.01 68.68,61.61 68.68,60.97 68.5,60.79 68.09,60.79 67.79,61.1
  IN4 w0.132: 67.79,61.1 67.79,61.61 67.53,61.86 66.87,61.86 66.44,61.43 66.09,61.43 65.7,61.05 65.7,59.83 63.95,58.08 63.95,53.07 63.8,52.92 63.8,49.96 62.34,48.5 61.34,48.5 55.72,42.88 55.72,38.37 56.13,37.96 56.13,37.3 v8(55.7,36.87)
  BOTTOM w0.076: UCPU1.AM45 69.94,62.29 v1(70.2,62.55)
  BOTTOM w0.183: v8(55.7,36.87) 56.08,37.25 UD5.F8
DDR_A_D52: length 36.1
  IN4 w0.076: 67.69,59.65 67.77,59.74 67.77,60.3 68.04,60.57 68.55,60.57 68.9,60.92 68.9,61.56 69.08,61.73 69.44,61.73 69.84,62.14 70.35,62.14 70.59,62.38 70.59,62.83 v8(70.17,63.25)
  IN4 w0.132: v1(56.47,36.06) 56.94,36.54 56.94,37.12 56.81,37.25 56.81,37.93 56.99,38.11 56.99,41.24 57.6,41.84 57.6,43.26 64.2,49.87 64.2,51.9 65.15,52.84 65.15,58.48 66.31,59.65 67.69,59.65
  BOTTOM w0.076: v8(70.17,63.25) 70.17,63.27 69.86,63.59 UCPU1.AK45
  BOTTOM w0.183: UD5.H8 56.08,35.67 v1(56.47,36.06)
DDR_A_D53: length 37.3
  IN4 w0.076: v1(71.16,63.94) 70.74,63.52 70.74,62.26 70.44,61.96 69.97,61.96 69.67,61.66 69.67,59.93 69.44,59.7 68.14,59.7 67.79,59.35
  IN4 w0.132: v8(57.35,37.66) 57.35,41.14 57.92,41.71 57.92,42.67 66,50.75 66,51.75 65.86,51.89 65.2,51.89 65.04,52.04 65.04,52.26 65.2,52.41 65.86,52.41 66,52.55 66,52.86 65.88,52.97 65.63,52.97 65.48,53.12 65.48,53.45 65.63,53.61 65.88,53.61 66,53.72 66,54.69 66.19,54.88 66.19,58.99 66.54,59.35 67.79,59.35
  BOTTOM w0.076: UCPU1.AK43 70.81,63.59 v1(71.16,63.94)
  BOTTOM w0.183: UD5.F7 56.96,37.27 v8(57.35,37.66)
DDR_A_D54: length 37.5
  IN4 w0.076: v8(72.89,62.62) 72.92,62.59 72.92,60.21 71.98,59.27 71.34,59.27 71.04,58.97 71.04,58.36
  IN4 w0.132: 71.04,58.36 71.04,55.99 69.95,54.9 69.95,48.53 67.05,45.63 66.86,45.63 66.56,45.92 66.38,45.92 66.19,45.74 66.19,45.55 66.49,45.25 66.49,45.07 66.3,44.88 66.11,44.88 65.82,45.18 65.63,45.18 65.44,44.99 65.44,44.8 65.74,44.51 65.74,44.32 65.55,44.13 65.37,44.13 65.07,44.43 64.88,44.43 64.7,44.24 64.7,44.06 64.99,43.76 64.99,43.57 63.75,42.33 63.75,40.07 63.11,39.43 63.11,38.55 63.27,38.39 63.49,38.39 63.65,38.23 63.65,37.66 63.49,37.5 61.1,37.5 v1(60.47,36.87)
  BOTTOM w0.076: UCPU1.AM40 72.56,62.29 v8(72.89,62.62)
  BOTTOM w0.183: v1(60.47,36.87) 60.87,37.27 UD5.F2
DDR_A_D55: length 36.7
  IN4 w0.076: 70.38,58.86 71.27,59.75 71.75,59.75 72.49,60.49 72.49,62.09 72.09,62.48 v1(72.09,62.62)
  IN4 w0.132: v8(59.63,38.47) 59.63,39 59.89,39.26 61.64,39.26 62.99,40.6 62.99,41.26 62.88,41.37 61.9,41.37 61.77,41.5 61.77,41.77 61.9,41.9 62.81,41.9 62.96,42.05 62.96,42.27 62.81,42.43 61.61,42.43 61.46,42.58 61.46,42.8 61.61,42.96 62.47,42.96 62.61,43.09 62.61,43.73 67.94,49.06 67.94,49.86 69.25,51.17 69.25,55.19 70.38,56.32 70.38,58.86
  BOTTOM w0.076: v1(72.09,62.62) 72.06,62.59 72.06,62.57 71.78,62.29 UCPU1.AM42
  BOTTOM w0.183: v8(59.63,38.47) 60.03,38.07 UD5.E3
DDR_A_D56: length 34
  IN3 w0.076: v1(69.31,62.55) 69.69,62.17 70.23,62.17 70.78,61.61 70.78,60.44 71.04,60.19
  IN3 w0.132: v1(60.48,40.09) 60.98,39.59 62,39.59 63.21,40.8 63.21,41.14 63.04,41.31 61.92,41.31 61.79,41.44 61.79,41.77 61.95,41.92 64.03,41.92 71.1,48.99 71.1,51.61 71.32,51.83 71.32,52.54 70.91,52.95 70.91,55.46 71.06,55.61 71.06,60.16 71.04,60.19
  BOTTOM w0.076: UCPU1.AM46 69.05,62.29 v1(69.31,62.55)
  BOTTOM w0.183: v1(60.48,40.09) 60.88,39.69 UD5.C2
DDR_A_D57: length 36.9
  IN3 w0.132: v8(59.61,40.09) 60.45,39.26 62.22,39.26 63.62,40.65 63.62,41.06 70.41,47.84 70.64,47.84 72.01,49.21 72.01,60.08 71.65,60.44 71.65,64.05 71.34,64.35 68.75,64.35 v1(68.37,63.97)
  BOTTOM w0.076: UCPU1.AK46 68.83,63.59 68.5,63.92 68.42,63.92 v1(68.37,63.97)
  BOTTOM w0.183: UD5.C3 60.03,39.67 v8(59.61,40.09)
DDR_A_D58: length 32.7
  IN3 w0.076: v1(66.35,62) 66.95,61.4 66.95,59.91 67.2,59.65 67.48,59.65
  IN3 w0.132: 67.48,59.65 68.52,59.65 68.75,59.42 68.75,55.97 68.62,55.83 68.62,50.39 67.89,49.66 67.89,48.68 67.05,47.85 66.3,47.85 64,45.55 60.4,45.55 57.62,42.78 57.62,42.46 57.75,42.33 58.01,42.33 58.11,42.23 58.11,41.77 57.98,41.64 57.7,41.64 56.94,40.88 v1(56.48,40.88)
  BOTTOM w0.076: v1(66.35,62) 66.64,62.29 UCPU1.AM49
  BOTTOM w0.183: v1(56.48,40.88) 56.08,40.48 UD5.B8
DDR_A_D59: length 31.7
  IN3 w0.076: v1(66.4,63.28) 65.99,62.88 65.99,62.22 65.93,62.16 65.93,61.88 66.24,61.57 66.25,61.57 66.75,61.07 66.75,59.8 67.2,59.35 67.41,59.35 67.79,58.97 67.79,57.04 67.94,56.88 67.94,56.48 67.91,56.45
  IN3 w0.132: v8(56.39,41.75) 56.39,42.07 60.21,45.89 63.88,45.89 66.16,48.17 66.92,48.17 67.56,48.82 67.56,49.81 68.29,50.54 68.29,55.64 67.91,56.02 67.91,56.45
  BOTTOM w0.076: UCPU1.AK49 66.7,63.59 v1(66.4,63.28)
  BOTTOM w0.183: v8(56.39,41.75) 56.87,41.27 UD5.A7
DDR_A_D60: length 33.9
  IN3 w0.076: 69.67,61.53 69.49,61.71 69.15,61.71 68.23,62.63 v1(68.23,62.64)
  IN3 w0.132: v8(59.68,41.67) 59.68,41.91 60.41,42.63 62.39,42.63 62.55,42.79 62.55,43.13 62.39,43.29 61.32,43.29 61.16,43.45 61.16,43.77 61.32,43.93 63.82,43.93 63.95,43.8 63.95,43.4 64.08,43.27 64.46,43.27 64.61,43.42 64.61,43.98 65.99,45.35 66.49,45.35 69.87,48.72 69.87,55.51 70.33,55.97 70.33,59.14 69.74,59.73 69.74,61.46 69.67,61.53
  BOTTOM w0.076: v1(68.23,62.64) 67.87,62.29 UCPU1.AM48
  BOTTOM w0.183: v8(59.68,41.67) 60.08,41.28 UD5.A3
DDR_A_D61: length 32.4
  IN3 w0.076: 70.67,60 70.61,60.07 70.61,61.4 70.07,61.94 69.34,61.94 68.83,62.45 68.83,62.75 v8(68.3,63.28)
  IN3 w0.132: v1(60.5,41.69) 61.06,42.25 62.78,42.25 62.94,42.41 62.94,43.45 63.1,43.61 63.41,43.61 63.57,43.45 63.57,42.44 63.73,42.28 63.93,42.28 70.19,48.54 70.19,55.32 70.67,55.81 70.67,60
  BOTTOM w0.076: UCPU1.AK48 67.97,63.59 68.3,63.26 v8(68.3,63.28)
  BOTTOM w0.183: UD5.A2 60.88,41.31 v1(60.5,41.69)
DDR_A_D62: length 32
  IN3 w0.076: 65.91,59.52 65.76,59.68 65.76,61.48 65.47,61.76 v8(65.47,62.61)
  IN3 w0.132: v1(56.47,39.26) 55.44,40.28 55.44,42.41 59.76,46.72 63.1,46.72 66.69,50.32 66.69,55.84 66.09,56.45 66.09,59.35 65.91,59.52
  BOTTOM w0.076: v8(65.47,62.61) 65.8,62.29 UCPU1.AM51
  BOTTOM w0.183: UD5.D7 56.86,38.87 v1(56.47,39.26)
DDR_A_D63: length 33.2
  IN3 w0.076: v1(65.47,63.27) 65.84,62.9 65.84,62.38 65.71,62.25 65.71,61.8 65.98,61.53 65.98,59.93 66.39,59.52 66.72,59.52 67.24,59
  IN3 w0.132: 67.24,59 67.36,58.89 67.36,57.24 67.05,56.93 67.05,54.44 67.3,54.19 67.61,54.19 67.79,54.01 67.79,52.21 67.56,51.98 67.23,51.98 67.01,51.77 67.01,50.18 63.12,46.29 59.99,46.29 55.85,42.15 55.85,40.7 v8(56.47,40.08)
  BOTTOM w0.076: UCPU1.AK51 65.79,63.59 v1(65.47,63.27)
  BOTTOM w0.183: v8(56.47,40.08) 56.46,40.08 56.46,40.05 UD5.C8
DDR_A_DQS0: length 55
  IN4 w0.165: v8(56.07,64.3) 55.71,63.94 54.05,63.94 51.26,61.16 51.26,59.68 45.43,53.85 43.79,53.85 41.83,51.89 41.1,51.89 40.72,51.51 40.72,50.9 40.03,50.2 39.45,50.2 39.09,50.56 37.83,50.56 37.48,50.2 36.94,50.2 32.4,45.66 30.75,45.66 29.09,44 28.52,44 27.81,43.29 23.98,43.29 22.61,41.91 22.61,39.77 22.82,39.57 22.82,39.28 22.59,39.04 22.59,38.13 23.04,37.67 23.04,37.09 22.9,36.94 22.78,36.94 v1(22.58,37.15)
  BOTTOM w0.076: UCPU1.AJ62 58.97,63.78 58.87,63.69 58.49,63.69 58.43,63.63 58.21,63.63 58.16,63.69 57.7,63.69 57.6,63.59 56.97,63.59 56.66,63.89 56.36,63.89 56.07,64.18 v8(56.07,64.3)
  BOTTOM w0.216: v1(22.58,37.15) 22.66,37.06 23.67,37.06 UD1.F3
DDR_A_DQS1: length 49.4
  IN3 w0.076: 54.79,59.51 54.82,59.51 54.9,59.59 55.32,59.59 56.04,60.31 56.58,60.31 v1(56.67,60.22)
  IN3 w0.165: v8(21.61,39.74) 21.64,39.71 22.31,39.71 22.7,40.11 22.7,42.14 24.34,43.78 26.95,43.78 28.15,44.98 29.28,44.98 31.14,46.84 31.73,46.84 34.09,49.2 34.97,49.2 38,52.24 46.31,52.24 53.59,59.51 54.79,59.51
  BOTTOM w0.076: v1(56.67,60.22) 56.79,60.35 57.16,60.35 57.88,61.07 58.1,61.07 58.17,61 58.47,61 58.54,61.06 59.18,61.06 59.59,61.47 UCPU1.AN61
  BOTTOM w0.216: UD1.C7 20.85,39.84 21.51,39.84 v8(21.61,39.74)
DDR_A_DQS2: length 44
  IN4 w0.076: v1(61.62,61.31) 61.57,61.35 61.5,61.35 61.27,61.13 61.27,60.31 61.37,60.21 61.37,59.7 60.52,58.85 59.46,58.85 57.5,56.89 57.34,56.89 57.26,56.81 57.24,56.81
  IN4 w0.165: v8(34.16,37.33) 34.16,37.11 34.07,37.02 33.99,37.02 33.83,36.86 33.67,36.86 33.59,36.94 33.59,37.47 34.23,38.11 34.23,38.37 34.84,38.98 36.7,38.98 42.32,44.6 44.06,44.6 46.17,46.71 46.17,48.27 46.92,49.01 47.14,49.01 54.93,56.81 57.24,56.81
  BOTTOM w0.076: UCPU1.AN58 61.26,61.68 61.41,61.68 61.62,61.47 v1(61.62,61.31)
  BOTTOM w0.216: v8(34.16,37.33) 34.16,37.22 34.52,36.86 35.24,36.86 35.3,36.92 35.3,37.17 35.4,37.27 UD2.F3
DDR_A_DQS3: length 47.2
  IN3 w0.076: v1(62.61,61.96) 62.86,62.21 62.86,62.4 63.11,62.65 63.83,62.65 64.03,62.45 64.03,61.66 64.13,61.56 64.13,59.37 64.07,59.31 63.52,58.76 62.68,58.76 61.84,57.92 60.55,57.92 60.22,57.6 60.22,57.48 60.21,57.47
  IN3 w0.165: 60.21,57.47 59.98,57.24 59.45,57.24 57.42,55.21 55.21,55.21 48.98,48.98 48.98,48.02 48.24,47.28 46.05,47.28 43.82,45.06 43.32,45.06 41.21,42.95 35.93,42.95 35.69,42.72 35.43,42.72 34.23,41.52 34.23,40.26 33.82,39.84 33.26,39.84 v8(33.17,39.74)
  BOTTOM w0.076: UCPU1.AN55 62.93,61.64 v1(62.61,61.96)
  BOTTOM w0.216: UD2.C7 32.49,39.92 32.99,39.92 v8(33.17,39.74)
DDR_A_DQS4: length 33
  IN4 w0.076: v1(61.76,56.03) 61.76,55.99 61.34,55.57 61.34,55.27 61.18,55.11 61.18,54.31 61.11,54.24 61.11,54.22
  IN4 w0.165: v8(47.21,37.15) 47.43,36.93 47.6,36.93 47.7,37.03 47.7,37.81 46.79,38.71 46.79,42.22 48.03,43.46 48.54,43.46 53.39,48.31 53.39,48.9 56.37,51.88 58.98,51.88 61.11,54.02 61.11,54.22
  BOTTOM w0.076: v1(61.76,56.03) 61.76,55.87 61.93,55.7 62.1,55.7 62.2,55.81 62.2,56.81 62.09,56.93 62.09,57.4 62.13,57.44 62.13,57.67 62.1,57.71 62.1,58.2 62.05,58.25 61.92,58.25 UCPU1.AW57
  BOTTOM w0.216: v8(47.21,37.15) 47.24,37.15 47.38,37.01 48.37,37.01 48.52,37.16 UD4.F3
DDR_A_DQS5: length 33.5
  IN3 w0.076: v1(64.51,55.59) 64.74,55.36 64.92,55.36 65.07,55.21 65.07,54.14 64.51,53.58 64.35,53.58 64.12,53.36 64.12,53.28 64.21,53.2 64.21,53.17
  IN3 w0.165: 64.21,53.17 64.21,52.63 63.38,51.8 63.38,49.91 62.65,49.18 58.45,49.18 56.91,47.64 55.77,47.64 53.31,45.17 52.13,45.17 50.09,43.14 48.9,43.14 47.4,41.65 47.4,40.39 46.98,39.97 46.43,39.97 v8(46.23,39.76)
  BOTTOM w0.076: v1(64.51,55.59) 64.34,55.41 64.15,55.41 64.1,55.46 64.1,56.62 64.03,56.69 64.03,56.95 64.08,57 64.08,57.38 63.99,57.47 63.99,57.63 64.06,57.71 64.06,57.97 UCPU1.AW53
  BOTTOM w0.216: UD4.C7 45.32,39.75 45.46,39.89 46.1,39.89 v8(46.23,39.76)
DDR_A_DQS6: length 38.6
  IN4 w0.076: v1(71.16,62.6) 71.13,62.63 71.13,62.78 71.24,62.88 71.3,62.88 71.36,62.94 71.44,62.94 71.54,62.84 71.54,60.49 71.29,60.24 71.04,60.24 70.3,59.5 69.76,59.5 69.49,59.22 69.37,59.22 69.09,58.94 69.09,58.79 69.01,58.71 69.01,58.69
  IN4 w0.165: v8(58.77,37.15) 58.96,36.96 59.06,36.96 59.25,37.15 59.25,37.52 58.81,37.97 58.81,42.45 60.18,43.82 60.68,43.82 60.89,43.61 61.12,43.61 61.36,43.84 61.36,44.08 61.14,44.29 61.14,44.79 61.56,45.21 62.06,45.21 62.27,44.99 62.51,44.99 62.74,45.23 62.74,45.46 62.53,45.67 62.53,46.17 62.95,46.59 63.44,46.59 63.66,46.38 63.89,46.38 64.13,46.61 64.13,46.84 63.91,47.06 63.91,47.55 66.66,50.3 67.18,50.3 68.16,51.28 68.16,55.42 69.01,56.27 69.01,58.69
  BOTTOM w0.076: v1(71.16,62.6) 71.16,62.75 71.35,62.94 UCPU1.AL42
  BOTTOM w0.216: UD5.F3 59.84,37.03 58.88,37.03 v8(58.77,37.15)
DDR_A_DQS7: length 33.6
  IN3 w0.076: 69.4,58.74 69.4,58.76 69.31,58.84 69.31,59.5 68.9,59.91 68.9,60.36 68.52,60.74 68.28,60.74 67.91,61.11 67.91,61.49 67.55,61.86 67.42,61.86 66.95,62.33 66.95,62.6 67.03,62.67 67.3,62.67 v1(67.36,62.61)
  IN3 w0.165: v1(57.81,39.75) 57.87,39.81 58.5,39.81 59,40.31 59,42.32 61.07,44.39 64.34,44.39 66.35,46.4 66.86,46.4 69.4,48.93 69.4,58.74
  BOTTOM w0.076: v1(67.36,62.61) 67.04,62.94 UCPU1.AL49
  BOTTOM w0.216: UD5.C7 57,39.79 57.75,39.79 57.81,39.73 v1(57.81,39.75)
DDR_A_DQS#0: length 55.3
  IN4 w0.165: v8(22.58,36.51) 22.69,36.63 23.03,36.63 23.36,36.96 23.36,37.8 22.9,38.26 22.9,38.91 23.13,39.14 23.13,39.7 22.93,39.9 22.93,41.78 24.12,42.97 27.94,42.97 28.65,43.68 29.22,43.68 30.88,45.34 32.53,45.34 37.08,49.89 37.61,49.89 37.97,50.24 38.96,50.24 39.32,49.89 40.16,49.89 41.04,50.76 41.04,51.38 41.24,51.57 41.97,51.57 43.92,53.53 45.56,53.53 51.58,59.55 51.58,61.03 54.18,63.62 56.05,63.62 v1(56.07,63.64)
  BOTTOM w0.076: UCPU1.AJ61 59.43,63.9 59.06,63.53 58.55,63.53 58.5,63.47 58.15,63.47 58.09,63.53 57.76,63.53 57.67,63.43 56.9,63.43 56.6,63.74 56.17,63.74 v1(56.07,63.64)
  BOTTOM w0.216: v8(22.58,36.51) 22.73,36.66 23.69,36.66 UD1.G3
DDR_A_DQS#1: length 49.5
  IN3 w0.076: v1(56.67,60.87) 56.67,60.71 56.59,60.62 56.48,60.62 56.33,60.47 55.97,60.47 55.26,59.75 54.9,59.75 54.82,59.83 54.79,59.83
  IN3 w0.165: v1(21.61,40.4) 21.62,40.4 21.99,40.03 22.17,40.03 22.38,40.24 22.38,42.27 24.21,44.09 26.82,44.09 28.02,45.3 29.15,45.3 31.01,47.16 31.59,47.16 33.96,49.52 34.84,49.52 37.87,52.55 46.18,52.55 53.46,59.83 54.79,59.83
  BOTTOM w0.076: v1(56.67,60.87) 56.67,60.76 56.91,60.52 57.11,60.52 57.81,61.23 58.17,61.23 58.23,61.17 58.41,61.17 58.47,61.23 58.95,61.23 59.05,61.33 59.05,61.42 59,61.47 UCPU1.AN62
  BOTTOM w0.216: v1(21.61,40.4) 21.44,40.23 20.84,40.23 20.68,40.39 UD1.B7
DDR_A_DQS#2: length 44.4
  IN4 w0.076: 57.24,57.12 57.26,57.12 57.34,57.04 57.44,57.04 58.29,57.9 59.4,59 60.45,59 61.22,59.77 61.22,60.15 61.12,60.25 61.12,61.19 61.25,61.32 61.25,61.51 61.63,61.89 v1(61.63,61.98)
  IN4 w0.165: v1(34.16,36.51) 34.13,36.54 33.54,36.54 33.27,36.8 33.27,37.6 33.92,38.24 33.92,38.5 34.71,39.29 36.57,39.29 42.19,44.91 43.93,44.91 45.85,46.84 45.85,48.4 46.78,49.33 47.01,49.33 54.8,57.12 57.24,57.12
  BOTTOM w0.076: UCPU1.AM58 61.22,62.29 61.52,61.98 v1(61.63,61.98)
  BOTTOM w0.216: UD2.G3 34.2,36.47 v1(34.16,36.51)
DDR_A_DQS#3: length 47.4
  IN3 w0.076: 59.98,57.69 60,57.71 60.11,57.71 60.48,58.08 61.78,58.08 62.62,58.92 63.46,58.92 63.92,59.38 63.97,59.43 63.97,61.5 63.88,61.6 63.88,62.38 63.76,62.5 63.18,62.5 63.01,62.33 63.01,61.71 63.11,61.61 63.29,61.61 63.5,61.81 v8(63.5,61.97)
  IN3 w0.165: 59.98,57.69 59.84,57.56 59.32,57.56 57.28,55.52 55.07,55.52 48.66,49.11 48.66,48.15 48.11,47.6 45.92,47.6 43.69,45.38 43.19,45.38 41.08,43.27 35.8,43.27 35.56,43.04 35.3,43.04 33.92,41.65 33.92,40.39 33.69,40.16 33.38,40.16 33.17,40.37 v1(33.17,40.4)
  BOTTOM w0.076: v8(63.5,61.97) 63.44,61.91 63.17,61.91 63.06,62.02 UCPU1.AM55
  BOTTOM w0.216: UD2.B7 32.4,40.31 33.08,40.31 v1(33.17,40.4)
DDR_A_DQS#4: length 33.3
  IN4 w0.076: v8(61.73,55.38) 61.67,55.38 61.34,55.04 61.34,54.31 61.4,54.24 61.4,54.22
  IN4 w0.165: v1(47.21,36.51) 47.31,36.61 47.73,36.61 48.02,36.9 48.02,37.94 47.11,38.84 47.11,42.09 48.16,43.14 48.67,43.14 53.71,48.18 53.71,48.77 56.5,51.57 59.11,51.57 61.4,53.86 61.4,54.22
  BOTTOM w0.076: v8(61.73,55.38) 61.9,55.55 62.16,55.55 62.36,55.75 62.36,56.88 62.24,56.99 62.24,57.33 62.29,57.38 62.29,57.74 62.26,57.77 62.26,58.26 61.86,58.66 UCPU1.AV57
  BOTTOM w0.216: UD4.G3 48.37,36.61 47.31,36.61 v1(47.21,36.51)
DDR_A_DQS#5: length 33.7
  IN3 w0.076: v8(64.51,54.98) 64.51,54.98 64.74,55.2 64.85,55.2 64.91,55.14 64.91,54.2 64.45,53.74 64.28,53.74 63.97,53.42 63.97,53.28 63.89,53.2 63.89,53.17
  IN3 w0.165: 63.89,53.17 63.89,52.76 63.06,51.93 63.06,50.04 62.52,49.5 58.32,49.5 56.78,47.96 55.64,47.96 53.18,45.49 51.99,45.49 49.96,43.46 48.77,43.46 47.09,41.78 47.09,40.53 46.84,40.28 46.36,40.28 46.25,40.4 v1(46.23,40.4)
  BOTTOM w0.076: UCPU1.AV53 64.29,58.6 64,58.31 64,58.13 63.91,58.04 63.91,57.77 63.83,57.7 63.83,57.4 63.92,57.31 63.92,57.06 63.87,57.01 63.87,56.63 63.95,56.55 63.95,55.4 64.09,55.26 64.28,55.26 64.51,55.02 v8(64.51,54.98)
  BOTTOM w0.216: UD4.B7 45.5,40.28 46.13,40.28 46.25,40.4 v1(46.23,40.4)
DDR_A_DQS#6: length 39
  IN4 w0.076: v1(71.16,63.26) 71.32,63.11 71.5,63.11 71.7,62.9 71.7,60.43 71.35,60.08 71.1,60.08 70.37,59.34 69.83,59.34 69.55,59.07 69.44,59.07 69.24,58.87 69.24,58.79 69.32,58.71 69.32,58.69
  IN4 w0.165: 69.32,58.69 69.32,56.14 68.47,55.29 68.47,51.15 67.31,49.99 66.79,49.99 64.23,47.42 64.23,47.19 64.44,46.98 64.44,46.48 64.02,46.06 63.53,46.06 63.31,46.27 63.08,46.27 62.85,46.04 62.85,45.81 63.06,45.59 63.06,45.09 62.64,44.67 62.14,44.67 61.93,44.89 61.7,44.89 61.46,44.65 61.46,44.42 61.68,44.21 61.68,43.71 61.25,43.29 60.76,43.29 60.54,43.5 60.31,43.5 59.13,42.32 59.13,38.1 59.57,37.65 59.57,37.02 59.19,36.64 58.9,36.64 v1(58.77,36.51)
  BOTTOM w0.076: UCPU1.AL43 70.84,62.94 v1(71.16,63.26)
  BOTTOM w0.216: v1(58.77,36.51) 58.9,36.64 59.91,36.64 UD5.G3
DDR_A_DQS#7: length 33.9
  IN3 w0.076: v1(67.35,63.26) 67.38,63.24 67.38,63.06 67.3,62.98 67.2,62.98 67.05,62.83 66.96,62.83 66.79,62.66 66.79,62.27 67.35,61.71 67.48,61.71 67.76,61.43 67.76,61.05 68.22,60.59 68.46,60.59 68.75,60.3 68.75,59.84 69.16,59.43 69.16,58.84 69.08,58.76 69.08,58.74
  IN3 w0.165: v8(57.81,40.39) 57.83,40.39 58.08,40.13 58.37,40.13 58.68,40.44 58.68,42.45 60.93,44.7 64.21,44.7 66.22,46.71 66.73,46.71 69.08,49.06 69.08,58.74
  BOTTOM w0.076: v1(67.35,63.26) 67.35,63.06 67.43,62.98 67.73,62.98 UCPU1.AL48
  BOTTOM w0.216: UD5.B7 56.88,40.4 57.09,40.18 57.54,40.18 57.74,40.39 v8(57.81,40.39)
DDR_A_MA0: length 142.6
  TOP w0.076: v1(41.89,28.16) 41.71,28.33 RD29.1
  IN2 w0.076: 77.25,53.21 76.73,53.73 76.73,54.9 76.13,55.5 75.92,55.5 75.33,56.1 75.33,58.51 74.96,58.88 v1(74.63,58.88)
  IN2 w0.157: v1(41.89,28.16) 41.89,27.97 43.35,26.5 45.17,26.5 45.33,26.66 45.33,26.97 45.17,27.13 43.44,27.13 42.56,28 42.56,28.23 42.79,28.46 43.71,28.46 44.35,27.82 44.76,27.82 44.93,28 44.93,28.31 44.72,28.51 44.72,28.96 44.49,29.19 44.09,29.19 43.94,29.04 43.17,29.04 42.79,29.43 42.79,30.13 42.63,30.29 42.11,30.29 41.88,30.52 41.88,31.04 41.55,31.37 41.55,34.36 42.32,35.13 42.32,37.11 43.05,37.84 43.05,38.09 42.83,38.3 42.83,40.51 42.34,41.01 42.34,41.21 43.18,42.05 43.35,42.05 43.5,41.9 43.71,41.9 43.87,42.05 44.62,42.05 45.12,42.56 45.84,42.56 46.26,42.97 51.46,42.97 53.36,44.88 53.47,44.88 53.83,45.23 59.74,45.23 59.86,45.12 72.05,45.12 72.24,45.31 72.24,46.71 72.69,47.16 73.46,47.16 73.61,47.31 73.61,47.51 75.13,49.03 75.83,49.03 75.96,49.16 75.96,50.35 76.94,51.33 77.08,51.33 77.31,51.56 77.31,53.15 77.25,53.21
  IN3 w0.076: v4(28.42,29.29) 28.56,29.29 28.66,29.39 29.23,29.39 29.82,28.79 31.88,28.79 32.48,28.19 35.06,28.19 35.25,28.38 39.75,28.38 40.01,28.12 41.85,28.12 v1(41.89,28.16) 42.12,28.38 42.36,28.38 42.49,28.26 42.49,27.95 42.59,27.85 42.72,27.85 42.82,27.95 42.82,28.26 42.95,28.38 43.99,28.38 44.58,27.8 48.24,27.8 49.19,28.75 49.19,29.19 49.84,29.83 49.98,29.83 50.06,29.76 50.06,29.65 50.16,29.55 51.87,29.55 52.48,28.94 52.88,28.94 53.06,29.12 v4(53.06,29.29)
  IN4 w0.076: v1(34.06,30.26) 34.06,29.91 33.67,29.53 31.9,29.53 31.35,28.98 29.66,28.98 29.25,29.39 28.52,29.39 v4(28.42,29.29) 28.29,29.16 27.75,29.16 27.25,29.66 25.28,29.66 24.88,30.06 24.11,30.06 23.8,30.37 23.64,30.37 23.32,30.68 22.92,30.68 v1(22.5,30.26) ; v8(47.14,30.26) 47.57,30.7 47.95,30.7 48.28,30.37 48.44,30.37 48.75,30.06 49.52,30.06 50.02,29.56 51.99,29.56 52.37,29.17 52.94,29.17 v4(53.06,29.29) 53.22,29.45 53.83,29.45 54.36,28.92 55.93,28.92 56.6,29.59 57.92,29.59 57.97,29.64 57.97,29.77 58.02,29.82 58.21,29.82 58.29,29.75 58.29,29.64 58.34,29.59 58.48,29.59 58.69,29.81 v1(58.69,30.26)
  BOTTOM w0.076: UCPU1.AU36 74.78,58.88 v1(74.63,58.88) ; v8(47.14,30.26) 47.14,30.36 48.45,31.67 UD4.N3 ; UD1.N3 23.79,31.67 22.5,30.38 v1(22.5,30.26) ; v1(58.69,30.26) 58.69,30.32 60.04,31.67 UD5.N3 ; UD2.N3 35.4,31.67 34.81,31.08 34.44,31.08 34.06,30.7 v1(34.06,30.26)
DDR_A_MA1: length 143
  TOP w0.076: RD37.1 41,29.11 v1(41,28.63)
  IN2 w0.076: v1(74.62,57.55) 75.15,57.02 75.15,56.03 75.88,55.31 76.09,55.31 76.55,54.85 76.55,53.4 76.68,53.28
  IN2 w0.157: v1(41,28.63) 40.81,28.44 40.81,27.86 43.23,25.44 47.66,25.44 47.85,25.63 47.85,25.89 47.66,26.07 43.29,26.07 41.32,28.04 41.32,28.28 41.75,28.71 42.01,28.71 42.17,28.55 42.39,28.55 42.61,28.77 42.61,29 41.88,29.73 41.88,30.03 41.53,30.38 41.53,30.9 41.19,31.24 41.19,34.5 41.97,35.27 41.97,37.26 42.49,37.77 42.49,40.37 41.99,40.87 41.99,41.36 43.04,42.4 44.47,42.4 44.98,42.91 45.7,42.91 46.11,43.32 51.31,43.32 53.22,45.22 53.33,45.22 54.06,45.96 54.32,45.96 54.7,45.58 56.01,45.58 56.22,45.8 56.47,45.8 56.68,45.58 57.99,45.58 58.15,45.74 58.44,45.74 58.61,45.58 59.89,45.58 60.01,45.47 71.66,45.47 71.9,45.7 71.9,46.85 72.56,47.51 73.11,47.51 74.92,49.31 74.92,49.82 76.94,51.84 76.94,53.01 76.68,53.28
  IN3 w0.076: v4(27.92,29.59) 28.01,29.68 28.58,29.68 28.61,29.65 29.26,29.65 29.92,28.99 32.02,28.99 32.56,28.46 35,28.46 35.17,28.64 39.82,28.64 39.96,28.5 40.88,28.5 v1(41,28.63) 41.04,28.59 44.07,28.59 44.66,28 48.16,28 48.99,28.83 48.99,29.27 49.93,30.21 50.11,30.21 50.24,30.09 50.24,29.88 50.33,29.78 50.47,29.78 50.57,29.88 50.57,30.1 50.65,30.19 50.78,30.19 50.87,30.1 50.87,29.93 51,29.81 52.34,29.81 v4(52.55,29.59)
  IN4 w0.076: v1(46.5,30.26) 47.2,30.96 48.06,30.96 48.39,30.63 48.55,30.63 48.86,30.33 49.63,30.33 50.15,29.8 52.12,29.8 52.33,29.59 v4(52.55,29.59) 52.72,29.76 53.14,29.76 53.24,29.65 54.3,29.65 54.4,29.55 54.4,29.22 54.5,29.12 55.72,29.12 56.44,29.83 57.68,29.83 58.06,30.21 v1(58.06,30.26) ; v1(21.86,30.26) 22.49,30.89 23.5,30.89 23.75,30.63 23.91,30.63 24.22,30.33 24.99,30.33 25.46,29.86 27.42,29.86 27.7,29.59 v4(27.92,29.59) 28.01,29.68 29.34,29.68 29.78,29.24 31.2,29.24 31.7,29.73 33.47,29.73 33.57,29.83 33.57,30.11 v8(33.42,30.26)
  BOTTOM w0.076: v1(74.62,57.55) 74.3,57.23 UCPU1.AY37 ; UD4.P7 45.9,30.87 v1(46.5,30.26) ; v8(33.42,30.26) 33.42,30.57 33.12,30.87 UD2.P7 ; v1(21.86,30.26) 21.26,30.87 UD1.P7 ; v1(58.06,30.26) 58.06,30.67 57.86,30.87 UD5.P7
DDR_A_MA2: length 149.5
  TOP w0.076: RD35.1 36,27.36 v8(36.39,26.96)
  IN2 w0.076: v1(73.56,60.05) 72.4,60.05 72.28,59.93 70.96,59.93 70.51,59.48 66.14,59.48 66.05,59.39
  IN2 w0.157: 66.05,59.39 65.42,58.76 58.77,58.76 57.45,57.44 47.24,57.44 44.8,55.01 43.73,55.01 41.92,53.21 40.32,53.21 39.89,52.78 38.73,52.78 35.26,49.3 35.26,48.32 32.64,45.7 32.64,45.48 33.13,44.99 33.13,44.39 32.88,44.13 32.5,44.13 32.34,44.28 32.34,44.88 32.19,45.04 31.97,45.04 29.21,42.28 29.21,35.59 29.01,35.39 29.01,34.44 30.2,33.25 31.79,33.25 32.46,32.58 32.46,31.94 32.37,31.85 32.37,30.88 32.51,30.75 32.81,30.75 33.19,31.13 33.47,31.13 33.8,30.8 34.01,30.8 34.39,31.18 34.93,31.18 35.13,30.98 35.13,30.51 35.68,29.96 35.68,28.78 36.39,28.07 v8(36.39,26.96)
  IN3 w0.076: v8(36.39,26.96) 36.39,26.94 ; 36.39,26.94 36.62,26.71 38.86,26.71 39.11,26.45 39.92,26.45 40.48,27.01 42.21,27.01 42.46,26.76 44.72,26.76 45.31,26.17 48.88,26.17 50.54,27.84 52.69,27.84 v4(52.8,27.95) ; 36.39,26.94 36.37,26.96 36.16,26.96 35.66,26.45 32.07,26.45 32,26.53 32,27.32 31.92,27.39 31.77,27.39 31.69,27.32 31.69,27.22 31.57,27.09 30.93,27.09 30.78,27.24 30.78,27.81 30.7,27.89 29.27,27.89 29.09,28.07 28.79,28.07 28.54,27.83 28.54,27.75 28.34,27.55 26.54,27.55 26.46,27.62 26.46,28 26.39,28.08 25.5,28.08 25.42,28.16 25.42,28.33 25.5,28.41 26.72,28.41 26.79,28.33 26.79,27.93 26.87,27.85 28.06,27.85 v4(28.16,27.95)
  IN4 w0.076: v1(34.01,28.89) 34.01,28.51 33.48,27.98 29.17,27.98 29.09,28.07 28.71,28.07 28.57,27.93 28.19,27.93 v4(28.16,27.95) 28.06,27.85 25.58,27.85 24.44,28.99 23.59,28.99 23.29,29.3 22.85,29.3 v1(22.45,28.89) ; v1(47.09,28.89) 47.49,29.3 47.92,29.3 48.23,28.99 49.08,28.99 50.22,27.85 52.7,27.85 v4(52.8,27.95) 52.83,27.93 53.21,27.93 53.35,28.07 53.68,28.07 53.83,27.91 57.67,27.91 v1(58.64,28.89)
  BOTTOM w0.076: UCPU1.AR38 73.77,60.34 73.56,60.13 v1(73.56,60.05) ; v1(58.64,28.89) 58.64,28.99 59.77,30.12 59.77,30.28 60.08,30.58 UD5.P3 ; v1(34.01,28.89) 34.01,28.99 35.1,30.09 35.1,30.24 35.44,30.58 UD2.P3 ; UD1.P3 23.55,30.54 23.55,30.1 22.45,28.99 v1(22.45,28.89) ; UD4.P3 48.52,30.58 48.2,30.26 48.2,30.11 47.09,28.99 v1(47.09,28.89)
DDR_A_MA3: length 147.8
  TOP w0.076: v1(43.89,27.62) 43.89,28.08 43.8,28.17 RD41.1
  IN2 w0.076: v1(75.47,61.28) 76.63,61.28 77,61.66 77.75,61.66 77.97,61.43
  IN2 w0.157: v1(43.89,27.62) 44.03,27.48 44.9,27.48 45.27,27.85 47.92,27.85 48.39,27.85 48.56,27.67 51.22,27.67 51.38,27.83 51.38,28.17 51.22,28.33 50.26,28.33 50.06,28.54 50.06,29.2 50.26,29.4 50.62,29.4 50.77,29.55 50.77,30.62 50.92,30.77 51.53,30.77 51.66,30.9 51.66,31.66 51.4,31.92 51.4,32.3 51.64,32.53 51.71,32.6 52.69,32.6 52.85,32.76 52.85,33.08 52.42,33.51 52.42,34.18 52.61,34.37 53.25,34.37 54.25,35.37 54.25,36.88 54.25,36.88 54.25,37.35 54.25,37.35 54.25,41.71 54.55,42.01 54.66,42.01 54.86,42.2 55.18,42.2 55.33,42.05 55.33,40.58 55.48,40.42 55.77,40.42 55.93,40.58 55.93,42.21 56.08,42.37 58.12,42.37 58.24,42.25 78.48,42.25 80.97,44.74 80.97,55.87 80.51,56.32 80.51,57.39 79.19,58.71 79.19,60.77 78.81,61.15 78.25,61.15 77.97,61.43
  IN3 w0.076: v4(28.98,28.99) 29.24,28.99 29.67,28.56 31.8,28.56 32.43,27.93 35.12,27.93 35.35,28.16 39.67,28.16 40.18,27.65 42.54,27.65 42.67,27.52 43.78,27.52 v1(43.89,27.62) 43.99,27.52 44.83,27.52 45.54,26.81 48.48,26.81 48.76,27.09 48.76,27.42 48.86,27.52 49.19,27.52 49.4,27.72 49.4,27.8 49.32,27.88 48.93,27.88 48.84,27.97 48.84,28.09 48.93,28.18 49.85,28.18 49.93,28.26 49.93,28.38 49.88,28.44 49.45,28.44 49.37,28.51 49.37,28.61 49.45,28.69 49.94,28.69 50.03,28.78 50.03,28.9 49.94,28.99 49.78,28.99 49.65,29.12 49.65,29.3 49.78,29.43 49.88,29.43 49.98,29.32 51.81,29.32 52.7,28.44 53.59,28.44 53.77,28.61 53.77,28.84 v4(53.61,28.99)
  IN4 w0.076: v1(47.77,30.26) 47.94,30.1 48.29,30.1 48.6,29.79 49.41,29.79 49.87,29.33 51.84,29.33 52.27,28.89 53.51,28.89 v4(53.61,28.99) 53.72,28.89 54.01,28.89 54.19,28.71 56.1,28.71 56.71,29.32 58.52,29.32 59.33,30.14 v1(59.33,30.26) ; v8(23.13,30.26) 23.3,30.1 23.65,30.1 23.96,29.79 24.77,29.79 25.23,29.33 27.2,29.33 27.69,28.84 28.82,28.84 v4(28.98,28.99) 29.08,28.89 29.37,28.89 29.55,28.71 31.52,28.71 32.13,29.32 33.88,29.32 34.69,30.14 v1(34.69,30.26)
  BOTTOM w0.076: UCPU1.AP36 75.18,60.99 v1(75.47,61.28) ; v8(23.13,30.26) 23.13,30.62 23.77,31.25 24,31.25 24.41,31.67 UD1.N2 ; UD5.N2 60.46,31.25 59.96,31.25 59.33,30.62 v1(59.33,30.26) ; v1(47.77,30.26) 47.77,30.6 48.42,31.25 48.53,31.25 48.95,31.67 UD4.N2 ; UD2.N2 35.83,31.25 35.33,31.25 34.69,30.62 v1(34.69,30.26)
DDR_A_MA4: length 142.3
  TOP w0.076: RD33.1 40.01,29.3 v1(40.39,28.92)
  IN2 w0.076: v1(73.05,58.88) 73.26,58.88 73.72,58.42 73.72,54.36 73.4,54.04
  IN2 w0.157: v1(40.39,28.92) 40.21,28.92 39.67,29.46 39.67,29.65 39.83,29.82 39.83,30.04 39.67,30.2 39.67,30.72 39.8,30.85 39.8,35.11 39.01,35.91 39.01,37.22 39.1,37.32 39.1,37.56 38.55,38.11 38.55,42.79 39.12,43.37 39.12,43.59 38.73,43.98 38.73,44.23 41.29,46.79 41.29,47.69 40.86,48.12 40.86,48.55 42.03,49.73 43.37,49.73 45.17,51.53 46.25,51.53 47.77,53.05 56.18,53.05 56.71,52.52 56.71,51.95 56.55,51.79 54.03,51.79 53.87,51.62 53.87,51.39 54.03,51.22 56.79,51.22 57.27,51.7 57.27,52.51 57.43,52.67 57.61,52.67 57.93,52.34 57.93,51.83 58.08,51.68 58.31,51.68 58.59,51.96 58.9,51.96 59.35,51.51 59.35,50.97 59.55,50.76 60.37,50.76 60.64,51.03 60.64,51.22 60.8,51.38 61.08,51.38 61.23,51.23 61.23,50.97 61.36,50.84 62.26,50.84 62.81,51.38 63.06,51.38 63.25,51.2 63.25,50.8 63.64,50.41 64.23,50.41 64.33,50.31 64.33,49.6 64.59,49.34 64.84,49.34 64.94,49.44 64.94,50.12 65.1,50.28 65.37,50.28 65.53,50.12 65.53,49.32 65.86,48.99 68.03,48.99 68.16,49.12 68.16,49.31 68.03,49.44 67.62,49.44 67.46,49.6 67.46,49.8 67.62,49.96 69.15,49.96 70.05,50.86 70.37,50.86 70.76,51.25 71.39,51.25 72.35,52.2 72.35,52.98 73.4,54.04
  IN3 w0.076: v4(51.25,30.21) 51.05,30.42 49.85,30.42 48.79,29.36 48.79,28.92 48.07,28.2 44.75,28.2 44.65,28.3 44.65,28.44 44.75,28.54 45.02,28.54 45.08,28.6 45.08,28.73 44.99,28.82 42.72,28.82 42.64,28.89 42.64,28.97 42.56,29.04 42.44,29.04 42.36,28.97 42.36,28.87 42.29,28.79 42.13,28.79 42.06,28.87 42.06,28.97 41.98,29.04 41.8,29.04 41.73,28.97 41.73,28.87 41.65,28.79 41.47,28.79 41.4,28.87 41.4,28.99 41.35,29.04 40.51,29.04 v1(40.39,28.92) 40.33,28.87 35.54,28.87 35.1,29.31 31.86,29.31 31.74,29.2 30,29.2 29.28,29.92 28.72,29.92 28.42,30.21 26.63,30.21 v4(26.59,30.26)
  IN4 w0.076: v1(32.76,30.27) 32.61,30.11 29.66,30.11 29.47,29.92 28.72,29.92 28.66,29.98 27.68,29.98 27.53,30.13 26.72,30.13 v4(26.59,30.26) 26.46,30.13 25.57,30.13 25.1,30.59 24.33,30.59 24.03,30.9 23.86,30.9 23.53,31.23 22.19,31.23 v1(21.22,30.26) ; v8(57.4,30.26) 57.26,30.13 54.41,30.13 54.16,29.89 53.39,29.89 53.29,29.98 52.32,29.98 52.17,30.13 51.35,30.13 51.25,30.23 v4(51.25,30.21) 51.2,30.26 50.85,30.26 50.71,30.13 50.2,30.13 49.74,30.59 48.97,30.59 48.66,30.9 48.5,30.9 48.17,31.23 46.79,31.23 45.85,30.28 v1(45.85,30.26)
  BOTTOM w0.076: UD1.P8 20.02,30.87 20.42,30.47 21.01,30.47 v1(21.22,30.26) ; UCPU1.AU39 73.2,58.88 v1(73.05,58.88) ; UD5.P8 56.21,30.87 56.61,30.47 57.19,30.47 v8(57.4,30.26) ; v1(32.76,30.27) 32.56,30.47 31.97,30.47 31.57,30.87 UD2.P8 ; v1(45.85,30.26) 45.64,30.47 45.05,30.47 44.65,30.87 UD4.P8
DDR_A_MA5: length 156.7
  TOP w0.076: v1(36.75,25.36) 36.63,25.36 36.25,25.74 36.25,25.92 RD47.1
  IN2 w0.076: 65.86,59.64 70.39,59.64 70.85,60.09 72.19,60.09 72.54,60.44 73.78,60.44 74.06,60.16 v1(74.55,60.16)
  IN2 w0.157: v1(36.75,25.36) 35.88,26.23 35.88,27.44 35.12,28.21 35.12,29.07 34.51,29.68 32.66,29.68 32.02,30.32 32.02,32 32.1,32.08 32.1,32.1 32.11,32.1 32.11,32.44 31.64,32.9 30.05,32.9 28.63,34.33 28.63,35.5 28.86,35.73 28.86,42.42 34.91,48.47 34.91,49.45 38.59,53.12 39.75,53.12 40.17,53.55 41.78,53.55 43.58,55.36 44.66,55.36 47.12,57.82 57.32,57.82 58.64,59.14 65.04,59.14 65.54,59.64 65.86,59.64
  IN3 w0.076: v4(27.96,26.63) 27.96,26.58 27.88,26.5 25.72,26.5 25.65,26.58 25.65,26.94 25.55,27.04 25.34,27.04 25.22,26.91 25.22,26.28 25.29,26.2 28.16,26.2 28.34,26.38 28.34,26.53 28.56,26.75 29.14,26.75 29.3,26.58 29.69,26.58 30.87,25.4 35.67,25.4 35.68,25.39 36.77,25.39 v1(36.75,25.36) 36.75,25.37 37.01,25.64 37.71,25.64 37.94,25.41 38.3,25.41 38.75,24.96 41.85,24.96 42.56,25.67 44.67,25.67 45,25.34 49.27,25.34 50.39,26.45 52.14,26.45 v4(52.32,26.63)
  IN4 w0.076: v1(58.69,27.24) 58.03,26.58 56.63,26.58 56.45,26.76 52.45,26.76 v4(52.32,26.63) 52.18,26.49 50.85,26.49 50.61,26.73 50.48,26.73 50.24,26.49 50.07,26.49 48.69,27.88 47.14,27.88 46.91,27.64 46.91,27.34 v8(46.98,27.27) ; v3(22.35,27.27) 22.35,27.37 22.91,27.93 24,27.93 25.43,26.49 27.82,26.49 v4(27.96,26.63) 28.07,26.75 31.63,26.75 31.91,26.46 33.27,26.46 v1(34.06,27.24)
  BOTTOM w0.076: UD2.P2 35.81,30.44 35.81,30.02 35.49,29.7 35.42,29.7 35.07,29.35 35.07,28.26 v1(34.06,27.24) ; v1(58.69,27.24) 59.71,28.26 59.71,29.32 60.12,29.73 60.17,29.73 60.45,30.02 60.45,30.44 UD5.P2 ; v3(22.35,27.27) 22.35,27.37 23.51,28.54 23.51,29.37 23.78,29.64 23.96,29.64 24.26,29.93 24.26,30.44 UD1.P2 ; UD4.P2 48.89,30.44 48.89,29.99 48.64,29.73 48.48,29.73 48.15,29.4 48.15,28.54 46.98,27.37 v8(46.98,27.27) ; v1(74.55,60.16) 74.72,60.34 UCPU1.AR36
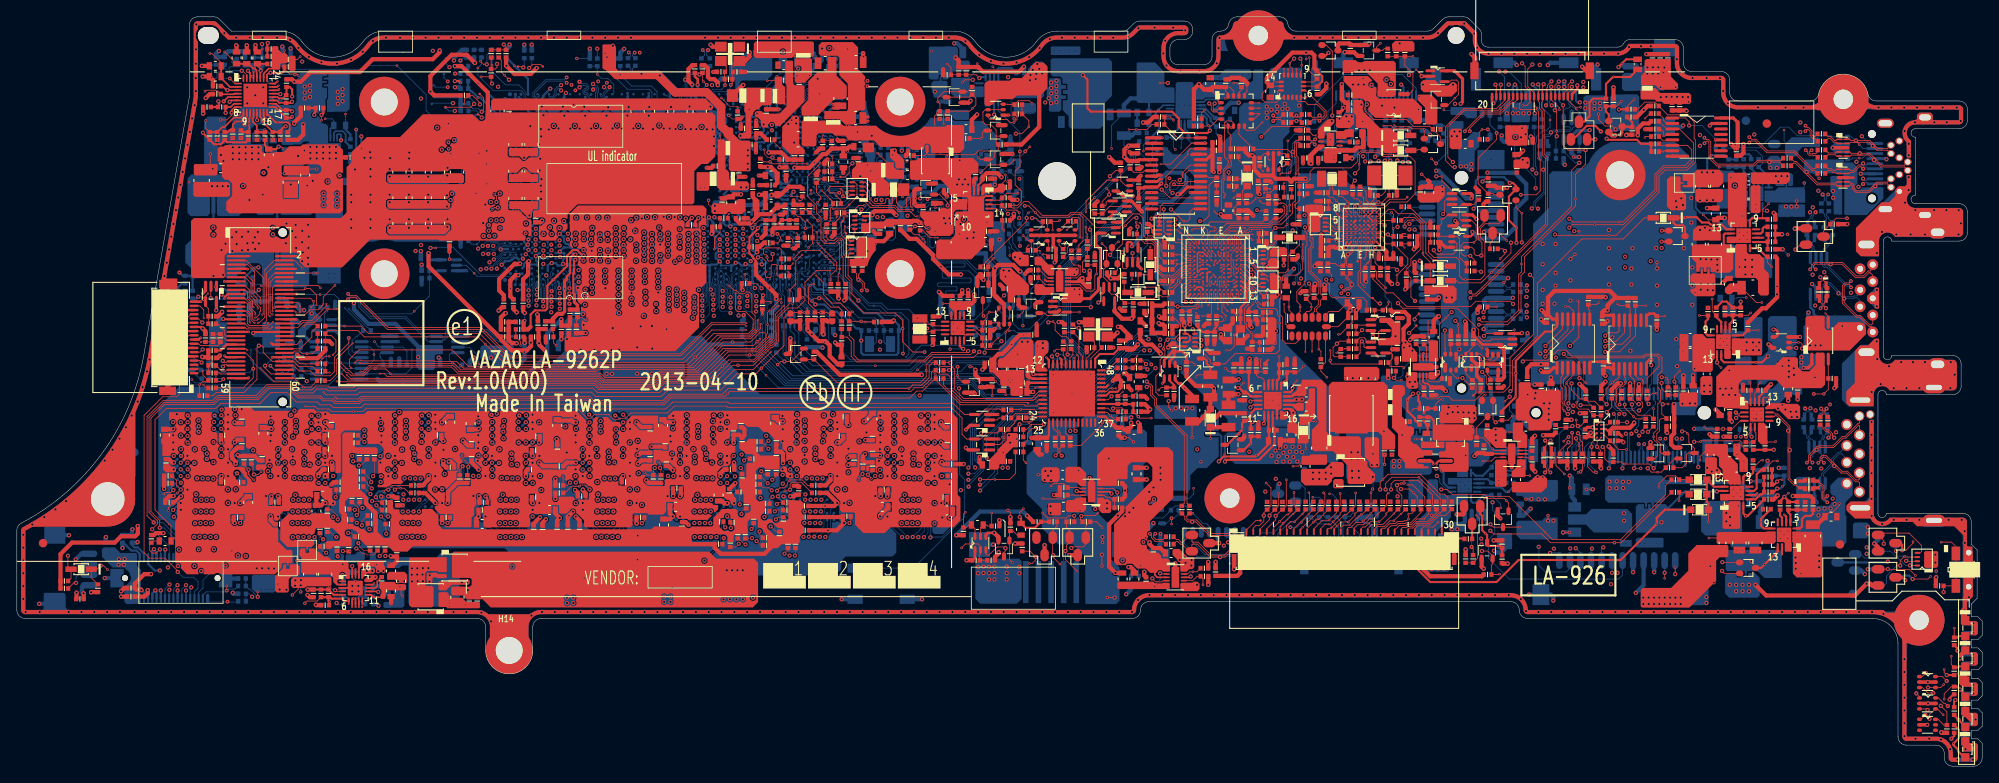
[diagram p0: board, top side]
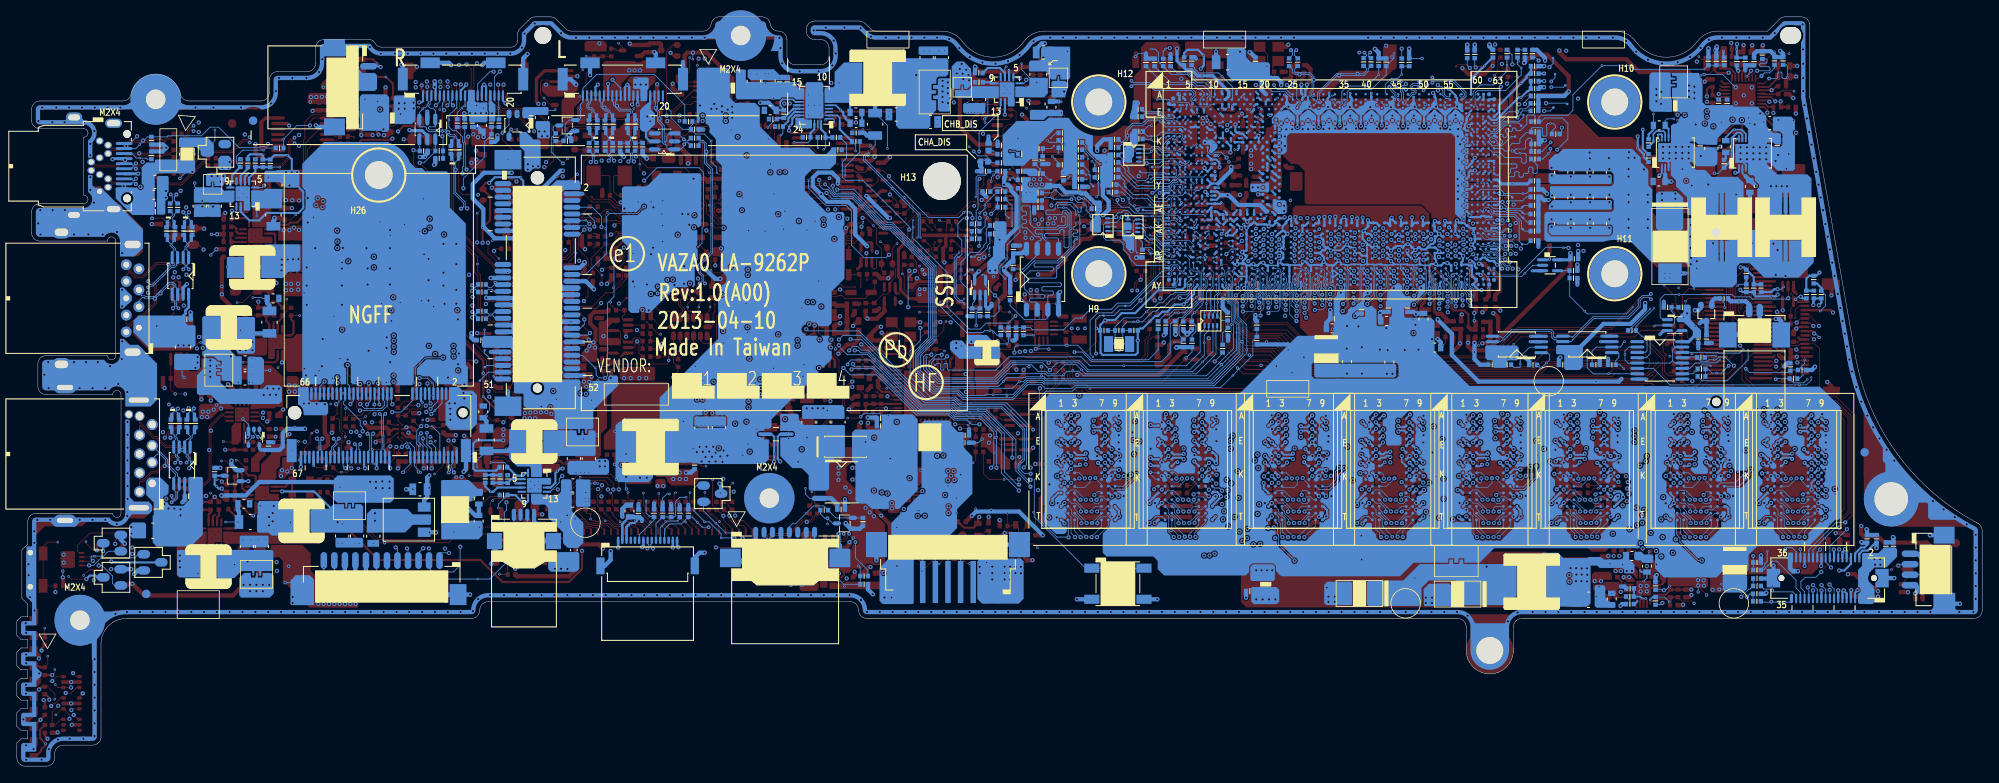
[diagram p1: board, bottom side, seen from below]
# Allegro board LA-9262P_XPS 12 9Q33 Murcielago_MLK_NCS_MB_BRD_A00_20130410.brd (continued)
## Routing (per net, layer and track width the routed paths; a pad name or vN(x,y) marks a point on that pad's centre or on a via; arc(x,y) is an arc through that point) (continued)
DDR_A_MA6: length 145.3
  TOP w0.076: RD39.1 39.69,27.72 v1(39.38,27.72)
  IN2 w0.076: v1(73.03,55.57) 73.03,55.63 72.87,55.79 72.06,55.79 71.9,55.63 71.9,54.78 72.21,54.47 72.21,54.29 72.08,54.17 71.82,54.17 71.74,54.24 71.22,54.24
  IN2 w0.157: 71.22,54.24 71.19,54.24 70.89,54.55 70.23,54.55 69.23,53.56 69.23,53.17 69.99,52.42 69.99,52.05 69.84,51.9 69.69,51.9 68.87,52.72 68.63,52.72 68.19,52.27 68.19,52.06 68.07,51.94 68.07,51.51 68.07,51.19 67.88,51 67.32,51 67.1,51.22 67.1,51.44 66.27,52.27 65.83,52.27 65.61,52.49 65.4,52.49 65.18,52.27 64.32,52.27 64.16,52.43 59.94,52.43 59.25,53.12 58.67,53.12 58.41,53.38 58.41,53.51 58.54,53.63 58.54,54.37 58.64,54.47 58.64,54.75 58.49,54.9 57.88,54.9 57.73,54.75 57.73,54.06 57.68,54 57.68,53.96 57.44,53.73 56.98,53.73 56.79,53.92 56.79,54.72 56.61,54.9 56.36,54.9 56.18,54.72 56.18,54.3 55.98,54.09 55.06,54.09 54.91,54.25 54.91,54.75 54.75,54.9 54.53,54.9 54.38,54.75 54.38,54.3 54.17,54.09 53.26,54.09 53.11,54.25 53.11,54.76 52.95,54.91 52.72,54.91 52.57,54.76 52.57,54.25 52.42,54.09 47.33,54.09 45.82,52.58 44.74,52.58 42.93,50.77 41.6,50.77 39.05,48.22 39.05,48.06 38.77,47.78 38.77,46.77 38.15,46.14 37.46,46.14 36.89,45.57 36.89,45.03 37.23,44.69 37.23,44.41 36.7,43.88 36.7,43.55 36.55,43.4 36.27,43.4 36.09,43.22 36.09,42.98 36.23,42.84 36.67,42.84 37.05,43.22 37.36,43.22 37.5,43.07 37.5,39.01 37.22,38.73 37.22,38.44 37.5,38.16 37.5,37.47 37.91,37.06 37.91,35.53 38.76,34.68 38.76,31.56 38.63,31.43 38.63,29.03 39.61,28.04 39.61,27.82 39.52,27.72 v1(39.38,27.72)
  IN3 w0.076: v4(27.15,28.79) 27.17,28.77 27.53,28.77 27.6,28.84 27.6,29.09 27.71,29.2 27.86,29.2 27.96,29.09 27.96,28.66 28.06,28.56 28.19,28.56 28.29,28.66 28.29,28.8 28.38,28.89 28.51,28.89 28.59,28.8 28.59,28.69 28.68,28.6 29.26,28.6 29.5,28.36 31.69,28.36 32.39,27.66 35.21,27.66 35.5,27.95 39.15,27.95 v1(39.38,27.72) 39.8,27.72 40.1,27.42 42.44,27.42 42.67,27.19 44.87,27.19 45.45,26.61 48.6,26.61 50.37,28.37 51.36,28.37 v4(51.78,28.79)
  IN4 w0.076: v1(57.37,28.88) 57.37,28.6 57.22,28.45 57.06,28.45 56.94,28.56 56.94,28.89 56.84,28.99 56.74,28.99 56.61,28.87 56.61,28.54 56.52,28.45 54.05,28.45 53.9,28.6 52.19,28.6 52,28.79 v4(51.78,28.79) 51.44,28.45 50.38,28.45 49.3,29.53 48.48,29.53 48.23,29.78 46.68,29.78 v1(45.82,28.92) ; v8(21.18,28.88) 22.01,29.71 23.67,29.71 23.85,29.53 24.66,29.53 25.74,28.45 26.8,28.45 v4(27.15,28.79) 27.36,28.79 27.56,28.59 29.27,28.59 29.38,28.48 32.32,28.48 32.38,28.54 32.38,28.66 32.3,28.74 32.07,28.74 32.02,28.79 32.02,28.92 32.23,29.12 32.66,29.12 32.74,29.04 v1(32.74,28.89)
  BOTTOM w0.076: UD2.R8 31.76,30.07 32.21,29.62 32.38,29.62 32.74,29.27 v1(32.74,28.89) ; v8(21.18,28.88) 21.18,29.27 20.82,29.63 20.26,29.63 19.88,30.01 UD1.R8 ; UD4.R8 44.62,30.07 45.06,29.63 45.42,29.63 45.82,29.23 v1(45.82,28.92) ; UCPU1.AV40 72.33,58.23 72.33,56.06 72.82,55.57 v1(73.03,55.57) ; UD5.R8 56.11,30.07 56.54,29.63 57,29.63 57.37,29.26 v1(57.37,28.88)
DDR_A_MA7: length 147.1
  TOP w0.076: RD51.1 v1(43.11,24.98)
  IN2 w0.157: v1(43.11,24.98) 42.86,24.73 42.31,24.73 42.16,24.88 42.16,25.16 42.31,25.31 42.44,25.31 42.55,25.42 42.55,25.63 42.3,25.88 41.89,25.88 41.73,26.04 41.73,26.45 41.28,26.9 40.86,26.9 40.6,27.16 40.6,27.58 40.46,27.72 40.46,28.17 39.32,29.32 39.32,30.87 39.45,31.01 39.45,34.97 38.66,35.77 38.66,37.3 38.2,37.76 38.2,42.94 38.59,43.34 38.59,43.56 38.2,43.95 38.2,44.23 39.86,45.89 39.86,46.4 39.54,46.73 39.54,47.56 39.75,47.78 39.75,47.93 41.89,50.07 43.22,50.07 45.03,51.88 46.1,51.88 47.62,53.4 56.33,53.4 56.71,53.01 57.75,53.01 58.36,52.41 58.93,52.41 59.69,51.65 59.69,51.31 59.81,51.19 60.13,51.19 60.29,51.35 60.29,51.57 60.45,51.73 61.48,51.73 61.58,51.63 61.58,51.35 61.74,51.19 62.12,51.19 62.28,51.35 62.28,51.58 62.43,51.73 63.44,51.73 63.6,51.57 63.6,50.95 63.78,50.76 64.05,50.76 64.23,50.95 64.23,51.45 64.36,51.57 64.79,51.57 64.89,51.47 64.89,51.38 65.05,51.22 65.32,51.22 65.48,51.38 65.48,51.42 65.63,51.57 65.98,51.57 66.41,51.15 66.41,50.93 65.88,50.41 65.88,49.47 66.01,49.34 66.36,49.34 66.49,49.47 66.49,50.14 66.65,50.3 66.81,50.3 66.99,50.13 67.24,50.13 67.42,50.3 69,50.3 69.16,50.46 69.16,50.63 68.76,51.03 68.76,51.26 68.94,51.44 69.17,51.44 69.49,51.12 69.81,51.12 69.91,51.21 70.23,51.21 70.61,51.6 71.25,51.6 72,52.34 72,53.13 73.47,54.6 73.47,57.53 73.38,57.62 73.12,57.62 v1(73.05,57.55)
  IN3 w0.076: v4(54.12,25.95) 54.05,26.02 54.05,27.12 53.9,27.27 53.69,27.27 53.54,27.12 53.54,26 53.31,25.77 50.34,25.77 49.47,24.9 45.21,24.9 44.85,24.55 43.54,24.55 v1(43.11,24.98) 43.1,24.97 42.78,24.97 42.3,24.49 35.74,24.49 35.36,24.87 30.82,24.87 29.74,25.95 v4(29.48,25.95)
  IN4 w0.076: v8(23.67,27.24) 23.67,27.17 24.89,25.95 v4(29.48,25.95) 34.11,25.95 v1(35.38,27.22) ; v1(48.31,27.24) 49.6,25.95 v4(54.12,25.95) 58.74,25.95 v1(60.01,27.22)
  BOTTOM w0.076: v8(23.67,27.24) 23.67,27.55 24.29,28.17 24.29,29.57 24.68,29.96 UD1.R2 ; UD2.R2 36.24,29.83 35.85,29.44 35.85,27.69 v1(35.38,27.22) ; v1(73.05,57.55) 73.38,57.88 UCPU1.AW39 ; v1(48.31,27.24) 48.46,27.39 48.46,27.7 48.93,28.17 48.93,29.67 UD4.R2 ; v1(60.01,27.22) 60.48,27.69 60.48,29.67 UD5.R2
DDR_A_MA8: length 147.3
  TOP w0.076: v1(40.33,25.87) 40.44,25.87 41.08,25.23 41.46,25.23 41.59,25.11 42.35,25.11 RD53.1
  IN2 w0.076: v1(73.05,56.88) 72.33,56.88 71.9,56.45 71.11,56.45 70.91,56.25
  IN2 w0.157: 70.91,56.25 70.4,55.74 69.84,55.74 67.91,53.81 67.91,53.63 67.56,53.28 66.87,53.28 66.66,53.49 66.66,53.97 66.47,54.17 66.24,54.17 65.98,53.91 64.13,53.91 63.75,53.53 62.78,53.53 62.07,54.24 60.5,54.24 60.34,54.4 60.34,55.83 60.18,55.99 51.66,55.99 51.51,55.84 51.51,55.29 51.35,55.14 51.1,55.14 50.95,55.29 50.95,55.84 50.79,55.99 47.76,55.99 45.38,53.62 44.31,53.62 42.5,51.81 40.9,51.81 40.47,51.38 39.31,51.38 36.65,48.73 36.65,47.66 36.44,47.44 36.44,46.82 36.1,46.48 35.57,46.48 35.33,46.24 35.33,45.47 34.65,44.79 34.65,42.42 34.11,41.89 34.11,40.59 33.66,40.14 33.66,39.27 33.8,39.13 33.8,38.87 33.63,38.7 32.87,38.7 32.71,38.54 32.71,38.25 32.87,38.09 33.26,38.09 33.42,37.93 33.42,37.76 33.29,37.62 33.29,35.26 33.42,35.12 33.42,35.11 33.59,34.94 34.96,34.94 35.35,34.55 35.35,33.52 35.66,33.21 36.16,33.21 36.3,33.08 36.3,32.57 36.63,32.25 37.18,32.25 37.36,32.07 37.36,31.74 37.11,31.49 37.11,30.95 37.29,30.77 37.78,30.77 37.93,30.62 37.93,30.26 37.78,30.11 37.28,30.11 37.11,29.94 37.11,29.32 37.59,28.84 38.25,28.84 38.83,28.26 38.83,26.13 39.53,25.43 39.89,25.43 v1(40.33,25.87)
  IN3 w0.076: v4(51.02,27.17) 50.46,27.17 49.04,25.74 45.17,25.74 44.71,26.2 42.31,26.2 42.01,26.5 41.75,26.5 41.68,26.43 41.68,26.09 41.82,25.94 41.82,25.57 41.62,25.36 41.32,25.36 41.22,25.46 41.22,25.74 41.07,25.9 40.91,25.9 40.84,25.82 40.84,25.44 40.76,25.36 40.38,25.36 40.3,25.44 40.3,25.84 v1(40.33,25.87) 40.15,26.05 38.83,26.05 38.68,26.2 36.19,26.2 35.97,25.98 31.17,25.98 30.53,26.63 30.22,26.63 29.61,27.24 27.5,27.24 27.43,27.32 26.99,27.32 26.84,27.17 v4(26.39,27.17)
  IN4 w0.076: v1(57.42,27.22) 57.36,27.28 52.99,27.28 52.95,27.32 51.18,27.32 v4(51.02,27.17) 51,27.14 50.18,27.14 48.86,28.46 46.83,28.46 45.71,27.34 v1(45.71,27.24) ; v1(32.79,27.22) 32.76,27.24 27.44,27.24 27.36,27.32 26.54,27.32 v4(26.39,27.17) 26.25,27.03 25.65,27.03 24.22,28.46 22.11,28.46 21.08,27.43 v8(21.08,27.24)
  BOTTOM w0.076: v1(57.42,27.22) 57.4,27.22 56.08,28.54 UD5.T8 ; UD1.T8 19.88,29.08 21.11,27.85 21.11,27.28 v8(21.08,27.24) ; UD4.T8 44.52,28.99 45.87,27.65 45.87,27.39 v1(45.71,27.24) ; v1(73.05,56.88) 73.4,57.23 UCPU1.AY39 ; v1(32.79,27.22) 32.76,27.22 31.44,28.54 UD2.T8
DDR_A_MA9: length 143.6
  TOP w0.076: v8(40.57,26.5) 40.7,26.38 40.7,26.12 41.21,25.62 RD43.1
  IN2 w0.157: v8(40.57,26.5) 40.3,26.5 39.72,25.92 39.53,25.92 39.18,26.27 39.18,26.5 39.31,26.63 39.75,26.63 40.25,27.14 40.25,27.44 40.12,27.57 40.12,28.03 38.97,29.17 38.97,31.24 39.11,31.38 39.11,34.83 38.26,35.67 38.26,37.21 37.85,37.61 37.85,43.1 38.1,43.35 38.1,43.56 37.98,43.68 37.76,43.68 37.59,43.85 37.59,44.11 38.02,44.54 38.02,44.77 37.84,44.95 37.54,44.95 37.42,45.06 37.42,45.57 37.64,45.79 38.29,45.79 38.39,45.89 38.59,45.89 38.86,45.63 39.11,45.63 39.52,46.04 39.52,46.24 39.12,46.64 39.12,47.64 39.4,47.92 39.4,48.08 41.75,50.42 43.08,50.42 44.88,52.23 45.96,52.23 47.48,53.75 56.47,53.75 56.84,53.38 57.92,53.38 58.53,52.77 59.1,52.77 59.79,52.08 63.58,52.08 63.74,51.92 66.12,51.92 66.75,51.29 66.75,50.81 66.91,50.66 68.21,50.66 68.41,50.86 68.41,51.66 68.53,51.78 68.53,52.12 68.67,52.26 68.84,52.26 69.54,51.56 70.08,51.56 70.34,51.81 70.34,52.28 70.34,52.45 70.53,52.64 70.53,53.06 70.39,53.2 70.25,53.2 70.08,53.03 69.87,53.03 69.65,53.25 69.65,53.47 70.35,54.17 70.68,54.17 71.04,53.81 71.04,52.49 71.17,52.36 71.52,52.36 71.65,52.49 71.65,53.27 72.59,54.21 72.59,54.52 72.18,54.93 72.18,55.33 72.31,55.46 72.53,55.46 72.69,55.3 72.69,55.06 72.85,54.9 73.02,54.9 v1(73.05,54.94)
  IN3 w0.076: v4(53.51,27.67) 53.39,27.55 51.79,27.55 51.76,27.57 50.57,27.57 48.97,25.97 45.22,25.97 44.64,26.56 42.36,26.56 42.21,26.71 40.77,26.71 v8(40.57,26.5) 40.33,26.5 40.08,26.25 38.93,26.25 38.73,26.45 36.06,26.45 35.86,26.25 31.21,26.25 31.13,26.33 31.13,26.48 31.21,26.56 31.54,26.56 31.62,26.63 31.62,26.81 31.54,26.89 30.29,26.89 30.12,27.05 30.12,27.22 30.2,27.29 30.42,27.29 30.5,27.37 30.5,27.6 30.42,27.67 28.95,27.67 v4(28.93,27.65)
  IN4 w0.076: v1(47.72,28.88) 47.87,28.73 48.97,28.73 50.11,27.58 52.15,27.58 52.18,27.56 53.4,27.56 v4(53.51,27.67) 58.26,27.67 59.28,28.69 v1(59.28,28.88) ; v1(23.08,28.88) 23.24,28.73 24.33,28.73 25.47,27.58 27.51,27.58 27.54,27.56 28.84,27.56 v4(28.93,27.65) 28.95,27.67 33.65,27.67 34.64,28.66 v1(34.64,28.88)
  BOTTOM w0.076: v1(73.05,54.94) 72.17,55.82 72.17,58.7 72.43,58.97 72.43,59.03 UCPU1.AU40 ; v1(59.28,28.88) 59.28,29.27 UD5.R3 ; v1(23.08,28.88) 23.08,29.27 UD1.R3 ; v1(47.72,28.88) 47.72,29.27 UD4.R3 ; UD2.R3 34.64,29.27 v1(34.64,28.88)
DDR_A_MA10: length 146.6
  TOP w0.076: RD31.1 42.48,34.61 v1(42.33,34.46)
  IN2 w0.076: v1(75.48,60.64) 75.59,60.64 75.86,60.36 75.86,59.78 75.55,59.46 75.55,56.12 76,55.67 76.18,55.67 76.91,54.95 76.91,53.84 77.29,53.45 77.57,53.45
  IN2 w0.157: 77.57,53.45 77.87,53.45 78.05,53.28 78.05,53.07 77.69,52.72 77.69,52.57 78.05,52.21 78.05,51.99 77.73,51.67 77.73,51.18 77.53,50.98 77.1,50.98 76.3,50.18 76.3,49.41 76.42,49.29 76.63,49.29 77.01,49.67 78.32,49.67 78.45,49.54 78.45,49.16 78.32,49.03 77.17,49.03 77.01,48.87 77.01,48.68 77.01,48 77.41,47.6 77.41,47.24 76.69,46.52 76.53,46.52 76.37,46.68 76.37,48.49 76.21,48.65 75.24,48.65 73.96,47.37 73.96,47.1 74.52,46.55 74.52,44.93 74.36,44.77 74.06,44.77 73.9,44.93 73.9,46.03 73.77,46.16 73.4,46.16 73.22,46.34 73.22,46.65 73.06,46.81 72.84,46.81 72.59,46.56 72.59,44.89 72.47,44.77 59.72,44.77 59.6,44.89 53.97,44.89 53.62,44.53 53.51,44.53 51.6,42.63 46.53,42.63 46.34,42.44 46.34,41.87 45.61,41.14 45.61,38.88 45.82,38.67 45.82,38.34 45.39,37.92 44.58,37.92 44.42,38.08 44.42,41.53 44.26,41.69 44.02,41.69 43.86,41.53 43.86,37.87 43.65,37.66 43.36,37.66 42.69,37 42.69,35.01 42.4,34.72 42.4,34.54 v1(42.33,34.46)
  IN3 w0.076: v4(51.81,34.43) 51.91,34.53 52.98,34.53 53.11,34.66 53.11,34.84 52.98,34.96 51.45,34.96 51.33,34.84 51.33,34.3 51.2,34.18 50.34,34.18 50.21,34.3 50.21,34.56 49.89,34.88 48.58,34.88 48.46,34.76 48.46,33.74 48.18,33.47 47.59,33.47 47.54,33.52 47.54,33.62 47.42,33.74 47.24,33.74 47.11,33.62 47.11,33.57 47.01,33.47 46.68,33.47 46.58,33.57 46.58,33.72 46.47,33.82 46.33,33.82 46.22,33.72 46.22,33.54 46.15,33.47 45.86,33.47 45.51,33.82 43.92,33.82 43.46,33.36 42.92,33.36 42.56,33.72 42.56,34.22 v1(42.33,34.46) 42.31,34.47 38.34,34.47 37.87,34 37.59,34 36.83,33.24 34.67,33.24 34.18,33.73 32.38,33.73 32.2,33.55 29.34,33.55 28.67,34.23 27.38,34.23 v4(27.17,34.43)
  IN4 w0.076: v1(46.07,34.2) 46.68,34.82 48.57,34.82 48.66,34.9 49.89,34.9 50.49,34.3 51.34,34.3 51.47,34.43 v4(51.81,34.43) 51.91,34.33 53.26,34.33 53.84,33.74 56.69,33.74 57.03,34.09 57.44,34.09 v1(57.6,34.25) ; v1(32.96,34.25) 32.63,34.25 31.86,33.48 29.57,33.48 28.83,34.22 27.97,34.22 27.93,34.25 27.35,34.25 v4(27.17,34.43) 27.1,34.35 25.81,34.35 25.23,34.94 24.14,34.94 24,34.8 21.75,34.8 21.43,34.48 v8(21.43,34.2)
  BOTTOM w0.076: v1(46.07,34.2) 46.07,34 45.34,33.27 UD4.L7 ; UD5.L7 56.88,33.3 57.6,34.02 v1(57.6,34.25) ; UD2.L7 32.24,33.31 32.96,34.04 v1(32.96,34.25) ; UD1.L7 20.8,33.27 21.43,33.9 v8(21.43,34.2) ; UCPU1.AP35 75.83,60.99 v1(75.48,60.64)
DDR_A_MA11: length 144
  TOP w0.076: v8(37.97,27.22) 37.83,27.22 37.22,27.83 RD45.1
  IN2 w0.076: 71.43,57.51 71.33,57.51 70.25,56.43 69.21,56.43 68.63,55.84 68.09,55.84 67.93,56 67.93,56.92 67.89,56.96
  IN2 w0.157: 67.89,56.96 67.76,57.09 67.3,57.09 67.08,56.86 67.08,56.38 66.87,56.17 66.62,56.17 66.16,56.63 66.16,57.49 65.7,57.95 63.72,57.95 63.27,57.49 59,57.49 58.21,56.71 47.48,56.71 45.09,54.32 44.02,54.32 42.21,52.51 40.61,52.51 40.18,52.08 39.02,52.08 35.95,49.01 35.95,47.99 33.83,45.87 33.83,44.04 32.91,43.12 32.91,42.91 32,42 30.8,42 30.65,41.85 30.65,41.59 30.83,41.41 31.21,41.41 31.36,41.26 31.36,40.94 31.2,40.78 30.81,40.78 30.65,40.62 30.65,40.3 30.81,40.14 31.21,40.14 31.36,39.99 31.36,39.67 31.2,39.51 30.8,39.51 30.64,39.35 30.64,38.96 30.78,38.82 31.23,38.82 31.39,38.66 31.39,38.32 31.23,38.16 30.07,38.16 29.91,38 29.91,37 30.03,36.87 30.42,36.87 30.59,36.71 30.59,35.75 30.74,35.6 31.2,35.6 31.36,35.44 31.36,35.12 31.2,34.96 30.75,34.96 30.59,34.8 30.59,34.17 30.8,33.95 32.07,33.95 32.7,33.32 34.51,33.32 35.83,31.99 35.83,30.79 36.37,30.25 36.37,29.07 37.3,28.15 37.96,28.15 38.13,27.98 38.13,27.33 38.01,27.22 v8(37.97,27.22) ; 71.43,57.51 v1(71.47,57.56)
  IN3 w0.076: v4(27.35,28.24) 27.46,28.36 28.42,28.36 28.51,28.27 28.76,28.27 28.82,28.33 29.15,28.33 29.33,28.16 31.03,28.16 31.11,28.08 31.11,27.39 31.19,27.32 31.36,27.32 31.44,27.39 31.44,28.08 31.49,28.13 31.62,28.13 32.33,27.42 32.33,26.76 32.43,26.66 35.43,26.66 35.81,27.04 35.81,27.67 35.88,27.75 36.39,27.75 36.47,27.67 36.47,27.47 36.52,27.42 36.7,27.42 36.75,27.47 36.75,27.7 36.8,27.75 37.15,27.75 37.28,27.62 37.28,27.5 37.36,27.42 37.48,27.42 37.56,27.5 37.56,27.62 37.66,27.72 37.87,27.72 37.97,27.62 v8(37.97,27.22) 38.07,27.11 38.88,27.11 39.34,26.66 39.8,26.66 40.36,27.22 42.31,27.22 42.54,26.99 44.78,26.99 45.39,26.38 48.66,26.38 50.39,28.11 51.85,28.11 v4(51.99,28.24)
  IN4 w0.076: v1(21.81,28.89) 22.42,29.5 23.46,29.5 23.7,29.26 24.55,29.26 25.63,28.18 27.29,28.18 v4(27.35,28.24) 27.45,28.35 29.14,28.35 29.24,28.24 32.74,28.24 33.37,28.87 v1(33.37,28.89) ; v1(46.45,28.89) 47.12,29.57 48.03,29.57 48.34,29.26 49.19,29.26 50.27,28.18 51.92,28.18 v4(51.99,28.24) 52.09,28.35 53.77,28.35 53.94,28.18 57.3,28.18 v1(58.01,28.89)
  BOTTOM w0.076: UD1.R7 20.81,30.07 21.81,29.06 v1(21.81,28.89) ; v1(71.47,57.56) 71.59,57.56 71.88,57.85 UCPU1.AW41 ; UD2.R7 32.41,29.9 32.5,29.9 33.37,29.03 v1(33.37,28.89) ; v1(58.01,28.89) 58.01,29.02 56.96,30.07 UD5.R7 ; v1(46.45,28.89) 46.45,28.96 45.34,30.07 UD4.R7
DDR_A_MA12: length 142.1
  TOP w0.076: v1(40.15,30.47) 40.08,30.54 RD25.1
  IN2 w0.076: 73.63,53.75 73.91,54.02 73.91,58.66 73.35,59.23 73.18,59.23 73.12,59.28 72.9,59.28 72.49,58.88 v1(71.48,58.88)
  IN2 w0.157: 73.63,53.75 72.69,52.81 72.69,52.06 71.54,50.9 70.9,50.9 70.52,50.51 70.19,50.51 69.53,49.85 69.53,49.12 69.39,48.97 68.5,48.97 68.17,48.64 64.79,48.64 63.98,49.45 63.98,49.91 63.82,50.07 63.64,50.07 63.41,49.84 63.2,49.84 63.11,49.93 63.11,50.45 62.9,50.66 62.71,50.66 62.53,50.48 62.53,50.05 62.24,49.76 61.88,49.76 61.67,49.97 61.45,49.97 61.23,49.76 60.96,49.76 60.8,49.92 60.63,49.92 60.47,49.76 60.15,49.76 59.96,49.95 59.75,49.95 59.56,49.76 58.59,49.76 58.34,50.01 58.34,50.2 58.5,50.36 58.8,50.36 59,50.56 59,51.03 58.7,51.33 58.44,51.33 58.31,51.2 58.31,50.84 58.19,50.71 58.07,50.71 58.07,50.71 57.9,50.71 57.78,50.84 57.78,51.19 57.64,51.33 57.39,51.33 57.26,51.2 57.26,50.99 57.14,50.88 53.72,50.88 53.51,51.08 53.51,51.93 53.72,52.13 56.15,52.13 56.31,52.29 56.31,52.43 56.04,52.7 50.39,52.7 50.2,52.5 50,52.5 49.8,52.7 47.91,52.7 46.39,51.18 45.32,51.18 43.51,49.38 42.18,49.38 41.21,48.41 41.21,48.26 41.64,47.84 41.64,46.65 40.2,45.22 40.2,44.95 40.61,44.54 40.61,44.36 40.33,44.09 40.11,44.09 39.73,44.47 39.5,44.47 39.28,44.25 39.28,44.03 39.66,43.64 39.66,43.42 38.89,42.65 38.89,38.26 39.61,37.54 39.61,37.32 39.37,37.07 39.37,36.04 40.15,35.26 40.15,30.47 v1(40.15,30.47)
  IN3 w0.076: v4(27.6,31.1) 28.16,31.1 28.29,30.98 31.43,30.98 31.71,30.69 34.91,30.69 35.16,30.44 38.25,30.44 38.37,30.57 38.37,30.65 38.5,30.77 38.68,30.77 38.81,30.65 38.81,30.32 38.92,30.21 39.08,30.21 39.19,30.32 39.19,30.65 39.31,30.77 39.47,30.77 39.59,30.65 39.59,30.57 39.72,30.44 40.13,30.44 v1(40.15,30.47) 40.33,30.29 41.74,30.29 41.9,30.13 41.91,30.13 41.97,30.07 43.11,30.07 43.17,30.14 44.27,30.14 44.83,29.58 48.1,29.58 49.27,30.75 49.27,31.43 49.54,31.7 51.65,31.7 v4(52.24,31.1)
  IN4 w0.076: v1(21.91,31.66) 22.61,32.36 23.7,32.36 24.08,31.98 26.8,31.98 27.24,31.54 27.24,31.37 27.5,31.1 v4(27.6,31.1) 27.67,31.04 28.2,31.04 28.31,30.93 31.86,30.93 32.17,31.24 33.31,31.24 33.47,31.4 v1(33.47,31.66) ; v1(46.55,31.66) 47.18,32.3 48.4,32.3 48.72,31.98 51.44,31.98 51.87,31.54 51.87,31.37 52.14,31.1 v4(52.24,31.1) 52.31,31.04 52.84,31.04 52.98,30.9 56.47,30.9 56.77,31.2 57.86,31.2 58.1,31.45 v8(58.1,31.66)
  BOTTOM w0.076: v8(58.1,31.66) 57.67,31.23 57.25,31.23 56.88,31.6 UD5.N7 ; v1(33.47,31.66) 33.03,31.23 32.4,31.23 32.24,31.39 UD2.N7 ; UD4.N7 45.32,31.57 45.66,31.24 46.12,31.24 v1(46.55,31.66) ; v1(71.48,58.88) 71.63,58.88 UCPU1.AU41 ; UD1.N7 20.68,31.57 21.05,31.2 21.45,31.2 v1(21.91,31.66)
DDR_A_MA13: length 147.9
  TOP w0.076: RD55.1 38.04,25.01 v8(38.12,24.93)
  IN2 w0.076: v1(75.47,60.03) 75.47,59.95 75.2,59.68 73.36,59.68 73.29,59.76 72.66,59.76 72.47,59.57 70.86,59.57 70.62,59.33 66.5,59.33 66.43,59.26
  IN2 w0.157: v8(38.12,24.93) 38.12,25.44 37.89,25.67 37.58,25.67 37.57,25.67 37.24,25.67 37.08,25.83 37.08,26.14 37.24,26.3 37.79,26.3 37.92,26.43 37.92,26.61 37.48,27.04 37.48,27.47 36.03,28.92 36.03,30.1 35.48,30.65 35.48,31.75 34.26,32.97 32.56,32.97 31.93,33.6 30.34,33.6 29.36,34.58 29.36,35.24 29.56,35.45 29.56,41.92 30.02,42.38 31.89,42.38 32.56,43.05 32.56,43.32 33.48,44.24 33.48,46.01 35.61,48.14 35.61,49.16 38.88,52.43 40.03,52.43 40.46,52.86 42.07,52.86 43.87,54.66 44.95,54.66 47.34,57.05 57.9,57.05 58.73,57.89 63.13,57.89 63.6,58.36 65.53,58.36 66.43,59.26
  IN3 w0.076: v4(53,26.35) 52.8,26.15 50.41,26.15 49.37,25.11 44.94,25.11 44.65,25.4 42.69,25.4 42.37,25.08 ; v8(38.12,24.93) 37.97,24.78 35.83,24.78 35.48,25.13 30.85,25.13 29.61,26.38 29.33,26.38 29.05,26.1 29.05,25.82 28.87,25.64 26.77,25.64 26.66,25.75 26.66,25.89 26.77,26 28.39,26 v4(28.75,26.35)
  IN3 w0.081: v8(38.12,24.93) 38.49,24.93 38.67,24.75 42.04,24.75 42.37,25.08
  IN4 w0.076: v3(34.72,27.22) 33.72,26.22 31.47,26.22 31.16,26.52 28.92,26.52 v4(28.75,26.35) 28.62,26.23 25.32,26.23 23.89,27.66 23.43,27.66 v1(23.01,27.24) ; v1(59.35,27.22) 59.35,26.94 58.66,26.24 56.59,26.24 56.48,26.35 v4(53,26.35) 52.88,26.23 49.96,26.23 48.51,27.67 47.58,27.67 47.45,27.55 47.45,27.44 v1(47.64,27.24)
  BOTTOM w0.076: UD5.T3 60.08,28.17 59.35,27.44 v1(59.35,27.22) ; UD4.T3 48.52,28.22 47.64,27.34 v1(47.64,27.24) ; v1(75.47,60.03) 75.78,60.34 UCPU1.AR35 ; v1(23.01,27.24) 23.01,27.34 23.88,28.22 UD1.T3 ; UD2.T3 35.52,29.19 35.52,28.02 v3(34.72,27.22)
DDR_A_MA14: length 145.8
  TOP w0.076: v1(38.74,25.57) 38.79,25.51 RD49.1
  IN2 w0.076: v1(71.5,56.83) 71.39,56.93 70.99,56.93 70.17,56.12 69.95,56.12
  IN2 w0.157: 69.95,56.12 69.69,56.12 69.07,55.5 68.1,55.5 67.96,55.37 67.96,54.39 67.79,54.22 67.25,54.22 66.94,54.53 66.94,55.53 66.78,55.69 66.32,55.69 66.16,55.53 66.16,54.69 65.79,54.32 65.27,54.32 65.09,54.5 65.09,57.32 64.89,57.52 63.9,57.52 63.49,57.11 63.16,57.11 63.01,56.96 63.01,55.95 62.85,55.79 62.49,55.79 62.33,55.95 62.33,56.91 62.12,57.11 59.2,57.11 58.43,56.34 47.61,56.34 45.24,53.97 44.16,53.97 42.36,52.16 40.75,52.16 40.32,51.73 39.16,51.73 36.3,48.87 36.3,47.8 34.98,46.48 34.98,45.61 34.18,44.82 34.18,43.83 33.29,42.94 33.29,42.6 33.77,42.13 33.77,41.72 33.61,41.57 33.04,41.57 32.36,40.88 32.36,38.19 32.23,38.06 32.23,37.38 32.05,37.2 31.7,37.2 31.54,37.04 31.54,36.7 31.7,36.54 32.16,36.54 32.32,36.38 32.32,34.22 32.87,33.67 34.65,33.67 36.18,32.14 36.18,30.93 36.72,30.39 36.72,29.21 37.44,28.49 38.1,28.49 38.48,28.12 38.48,25.83 v1(38.74,25.57)
  IN3 w0.076: v4(27.22,26.91) 27.35,27.04 29.52,27.04 30.13,26.43 30.44,26.43 31.15,25.72 36.11,25.72 36.39,26 37.84,26 37.94,25.9 37.94,25.72 38.05,25.62 38.19,25.62 38.3,25.72 38.3,25.92 38.37,26 38.55,26 38.74,25.81 v1(38.74,25.57) 39.15,25.16 41.7,25.16 42.48,25.93 44.69,25.93 45.08,25.54 49.14,25.54 50.34,26.73 51.4,26.73 v4(51.58,26.91)
  IN4 w0.076: v1(21.71,27.27) 21.71,27.37 22.54,28.19 24.11,28.19 25.54,26.76 27.07,26.76 v4(27.22,26.91) 27.66,26.91 27.77,27.03 28.23,27.03 28.24,27.01 31.93,27.01 32.21,26.74 32.95,26.74 v8(33.42,27.22) ; v1(58.06,27.22) 57.63,26.78 56.8,26.78 56.57,27.01 52.88,27.01 52.87,27.03 51.7,27.03 v4(51.58,26.91) 51.43,26.76 50.87,26.76 50.69,26.94 50,26.94 48.81,28.13 47.11,28.13 46.35,27.37 v1(46.35,27.27)
  BOTTOM w0.076: UD1.T7 20.68,28.74 21.86,27.56 21.86,27.42 v1(21.71,27.27) ; UD5.T7 56.88,28.42 58.06,27.24 v1(58.06,27.22) ; v8(33.42,27.22) 33.42,27.24 32.16,28.5 32.16,29.19 UD2.T7 ; v1(46.35,27.27) 46.5,27.42 46.5,27.52 45.32,28.7 UD4.T7 ; v1(71.5,56.83) 71.5,56.81 71.44,56.76 70.99,56.76 70.76,56.99 70.76,58.23 UCPU1.AV42
DDR_A_MA15: length 144.1
  TOP w0.076: RD27.1 37.95,32.03 v1(37.89,31.97)
  IN2 w0.157: v1(37.89,31.97) 38.06,32.14 38.06,32.47 37.9,32.63 36.81,32.63 36.65,32.79 36.65,33.08 36.81,33.24 37.9,33.24 38.06,33.4 38.06,33.86 37.9,34.02 37.28,34.02 37.12,34.18 37.12,34.66 36.77,35.01 35.48,35.01 35.2,35.29 33.8,35.29 33.65,35.44 33.65,37.5 34.17,38.01 34.17,39.27 34.01,39.43 34.01,39.99 34.46,40.45 34.46,41.74 34.87,42.15 35.22,42.15 35.36,42.29 35.36,42.61 35.2,42.77 35.15,42.77 35,42.92 35,43.52 35.15,43.67 35.46,43.67 35.65,43.86 35.65,44.06 35.5,44.21 35.15,44.21 35,44.36 35,44.65 35.19,44.84 36.04,44.84 36.19,45 36.19,45.38 36.04,45.53 35.83,45.53 35.67,45.69 35.67,45.95 35.82,46.09 36.32,46.09 36.85,46.62 36.85,47.37 37.21,47.72 37.21,47.94 37,48.15 37,48.58 37.68,49.26 38.02,49.26 38.42,48.86 38.63,48.86 38.86,49.09 38.86,49.31 38.42,49.75 38.42,50.01 38.8,50.39 39.03,50.39 39.47,49.95 39.8,49.95 40.55,50.7 40.55,50.94 41.07,51.47 42.64,51.47 44.45,53.27 45.53,53.27 47.9,55.65 48.58,55.65 48.74,55.49 48.74,54.93 48.87,54.79 49.17,54.79 49.32,54.94 49.32,55.46 49.47,55.61 50.44,55.61 50.59,55.46 50.59,54.95 50.74,54.79 51.71,54.79 51.86,54.95 51.86,55.46 52.01,55.61 59.83,55.61 59.99,55.45 59.99,55.14 59.83,54.98 59.54,54.98 59.38,54.82 59.38,54.53 59.54,54.37 59.63,54.37 59.81,54.19 59.81,53.54 60.23,53.12 60.62,53.12 60.78,53.28 60.78,53.73 60.94,53.89 61.25,53.89 61.41,53.73 61.41,53.28 61.56,53.12 63.9,53.12 64.31,53.53 66.14,53.53 66.71,52.96 67.81,52.96 68.32,53.47 68.32,53.71 69.92,55.31 70.53,55.31 71.28,56.06 71.44,56.06 v1(71.48,56.02)
  IN3 w0.076: v4(27.83,31.99) 27.91,32.07 27.91,32.47 27.78,32.6 27.4,32.6 27.3,32.71 27.3,32.96 27.43,33.08 28.16,33.08 28.29,32.96 28.29,31.64 28.42,31.51 31.85,31.51 31.95,31.61 31.95,31.78 32.06,31.89 32.22,31.89 32.33,31.78 32.33,31.31 32.42,31.22 35.25,31.22 35.38,31.34 35.38,31.76 35.5,31.89 35.68,31.89 35.81,31.76 35.81,31.36 35.93,31.23 36.09,31.23 36.21,31.36 36.21,31.76 36.34,31.89 36.82,31.89 36.95,31.76 36.95,31.58 37.05,31.48 37.18,31.48 37.28,31.58 37.28,31.71 37.41,31.84 37.76,31.84 v1(37.89,31.97) 38.15,31.97 38.56,31.55 41.13,31.55 42.09,30.58 42.91,30.58 43.08,30.75 48.36,30.75 48.81,31.2 48.81,31.58 49.33,32.11 51.32,32.11 51.73,32.52 52.04,32.52 52.47,32.09 v4(52.47,31.99)
  IN4 w0.076: v8(21.31,32.3) 21.79,32.78 23.97,32.78 24.3,32.45 26.72,32.45 26.78,32.51 27.43,32.51 27.83,32.1 v4(27.83,31.99) 27.83,31.74 27.93,31.64 28.04,31.64 28.26,31.86 28.34,31.86 28.47,31.74 28.47,31.66 28.39,31.58 28.39,31.51 28.52,31.38 31.56,31.38 32.08,31.9 32.39,31.9 32.81,32.32 33.01,32.32 v1(33.1,32.24) ; v1(57.74,32.24) 57.74,32.47 57.6,32.6 57.45,32.6 56.23,31.38 53.11,31.38 53,31.49 53,31.58 53.06,31.64 53.06,31.75 52.97,31.84 52.88,31.84 52.75,31.71 52.57,31.71 52.47,31.82 v4(52.47,31.99) 52.47,32.1 52.04,32.53 51.15,32.53 51.07,32.45 49,32.45 48.72,32.73 46.37,32.73 v1(45.94,32.3)
  BOTTOM w0.076: v1(57.74,32.24) 57.51,32.47 UD5.M7 ; v1(33.1,32.24) 32.68,32.65 32.42,32.65 UD2.M7 ; UD4.M7 45.77,32.47 v1(45.94,32.3) ; UCPU1.AU42 70.86,59.03 70.86,58.97 70.59,58.7 70.59,56.69 71.27,56.02 v1(71.48,56.02) ; UD1.M7 21.13,32.47 v8(21.31,32.3)
DDR_A_RAS#: length 141.2
  TOP w0.076: RD59.1 41.21,34.12 41.67,33.67 41.67,33.5 v1(42.16,33)
  IN2 w0.157: v1(76.2,56.91) 76.2,56.87 76.73,56.35 76.88,56.35 77.01,56.48 77.01,57.34 76.59,57.75 76.59,58.3 76.73,58.43 77.06,58.43 77.95,57.54 77.95,54.39 78.76,53.58 78.76,52.44 79.15,52.05 79.15,47.99 75.98,44.83 75.64,44.83 75.48,44.67 75.48,44.32 75.23,44.07 59.43,44.07 59.31,44.19 54.26,44.19 53.9,43.83 53.79,43.83 52.43,42.46 52.43,41.21 52.27,41.06 51.94,41.06 51.79,41.21 51.79,41.77 51.63,41.92 51.3,41.92 51.15,41.77 51.15,40.53 51,40.37 50.39,40.37 50.24,40.22 50.24,39.89 49.84,39.49 49.84,39.13 49.68,38.98 49.35,38.98 49.19,39.13 49.19,39.43 49.04,39.59 48.77,39.59 48.61,39.43 48.61,38.85 48.94,38.52 48.94,38.35 48.78,38.19 48.39,38.19 48.23,38.03 48.23,37.76 48.46,37.53 48.46,36.75 48.3,36.59 47.88,36.59 47.72,36.75 47.72,37.3 47.61,37.41 47.61,41.76 47.45,41.92 47.2,41.92 47.04,41.76 47.04,38.52 46.59,38.07 46.59,36.47 46.19,36.06 46.19,35.77 45.99,35.57 45.54,35.57 45.38,35.41 45.38,34.21 46.24,33.36 47.26,33.36 47.39,33.23 47.39,32.46 47.26,32.33 46.78,32.33 46.77,32.34 46.59,32.34 45.01,33.92 44.05,33.92 42.98,32.85 42.32,32.85 v1(42.16,33)
  IN3 w0.076: v4(53.31,33.34) 53.24,33.27 52.78,33.27 52.31,33.73 49.21,33.73 48.46,32.98 47.95,32.98 47.82,32.85 47.82,32.45 47.75,32.37 47.59,32.37 47.49,32.47 47.49,32.86 47.4,32.96 47.26,32.96 47.16,32.86 47.16,32.43 47.05,32.32 46.89,32.32 46.78,32.43 46.78,32.85 46.65,32.98 45.73,32.98 45.3,33.41 44.09,33.41 43.61,32.93 42.24,32.93 v1(42.16,33) 41.8,33.37 37.68,33.37 37.04,32.74 34.35,32.74 33.78,33.3 32.55,33.3 32.39,33.15 28.86,33.15 v4(28.67,33.34)
  IN4 w0.076: v8(34.23,34.2) 33.55,33.52 32.54,33.52 32.01,32.98 29.37,32.98 29.32,33.03 29.23,33.03 28.95,33.31 28.7,33.31 v4(28.67,33.34) 28.57,33.34 28.44,33.21 28.21,33.21 28.06,33.36 28.06,33.44 27.78,33.72 27.68,33.72 27.63,33.67 27.63,33.61 27.56,33.54 27.47,33.54 27.4,33.61 27.4,33.7 27.3,33.79 27.17,33.79 27.07,33.7 27.07,33.63 26.98,33.54 26.86,33.54 26.77,33.63 26.77,33.72 26.7,33.78 23.73,33.78 v1(23.34,34.17) ; v1(47.98,34.18) 47.87,34.08 47.87,33.87 48,33.74 52.39,33.74 52.78,33.36 53.28,33.36 v4(53.31,33.34) 53.33,33.31 56.89,33.31 57.09,33.52 58.19,33.52 v1(58.87,34.2)
  BOTTOM w0.076: v8(34.23,34.2) 34.9,34.87 UD2.J3 ; v1(47.98,34.18) 47.98,34.63 48.21,34.87 UD4.J3 ; UD5.J3 59.54,34.87 v1(58.87,34.2) ; v1(23.34,34.17) 23.34,34.61 23.6,34.87 UD1.J3 ; UCPU1.AY34 76.52,57.23 v1(76.2,56.91)
DDR_A_WE#: length 147.7
  TOP w0.076: v1(42.1,33.76) 42.1,33.99 41.16,34.94 RD65.1
  IN2 w0.076: 77.57,53.78 77.21,53.78 77.08,53.91 77.08,55.03 76.23,55.88 76.07,55.88 75.74,56.21 75.74,57.47 75.83,57.56 v1(76.19,57.56)
  IN2 w0.157: 77.57,53.78 78.1,53.78 78.4,53.48 78.4,51.85 78.08,51.53 78.08,51.37 78.23,51.22 78.68,51.22 78.8,51.1 78.8,50.79 78.64,50.63 77.25,50.63 77.03,50.42 77.03,50.18 77.19,50.02 78.64,50.02 78.8,49.86 78.8,48.84 78.64,48.68 77.5,48.68 77.36,48.54 77.36,48.19 77.5,48.04 78.35,48.04 78.46,47.94 78.46,47.79 78.07,47.41 77.92,47.41 77.76,47.25 77.76,47.09 75.84,45.17 75.59,45.17 75.43,45.33 75.43,46 75.59,46.16 75.86,46.16 76.02,46.32 76.02,48.15 75.86,48.31 75.47,48.31 75.31,48.15 75.31,47.99 75.58,47.71 75.58,47.48 75.39,47.29 75.17,47.29 74.87,47.59 74.67,47.59 74.42,47.34 74.42,47.14 74.87,46.69 74.87,45.16 75.13,44.89 75.13,44.59 74.96,44.42 73.7,44.42 73.55,44.57 73.55,45.7 73.44,45.81 73.05,45.81 72.94,45.7 72.94,44.54 72.82,44.42 59.57,44.42 59.46,44.54 54.12,44.54 53.76,44.18 53.65,44.18 51.75,42.28 50.92,42.28 50.77,42.13 50.77,41.62 50.62,41.47 50.34,41.47 50.18,41.62 50.18,42.13 50.03,42.28 46.81,42.28 46.69,42.15 46.69,38.66 46.24,38.22 46.24,36.67 46.08,36.51 45.65,36.51 45.49,36.67 45.49,37.25 45.16,37.57 44.91,37.57 44.72,37.38 44.55,37.38 44.36,37.57 44.05,37.57 43.67,37.19 43.67,36.53 43.81,36.39 44.28,36.39 44.44,36.23 44.44,35.89 44.29,35.73 43.62,35.73 43.45,35.57 43.45,35.12 43.29,34.96 43.14,34.96 42.82,34.64 42.82,34.03 42.76,33.97 42.76,33.53 42.62,33.39 42.43,33.39 42.35,33.46 42.34,33.46 42.1,33.7 v1(42.1,33.76)
  IN3 w0.076: v4(28.24,33.82) 28.75,33.82 29.22,33.35 32.3,33.35 32.47,33.52 34.1,33.52 34.6,33.01 36.95,33.01 37.65,33.72 38.14,33.72 38.4,33.97 41.89,33.97 v1(42.1,33.76) 42.73,33.13 43.52,33.13 44,33.62 45.38,33.62 45.79,33.21 48.36,33.21 49.08,33.93 52.04,33.93 52.33,34.23 53.56,34.23 54.16,33.63 54.16,33.5 54.06,33.4 53.93,33.4 53.56,33.77 52.93,33.77 v4(52.88,33.82)
  IN4 w0.076: v8(58.24,34.23) 58.24,34 58.03,33.79 57.04,33.79 56.79,33.54 53.74,33.54 53.54,33.74 52.95,33.74 v4(52.88,33.82) 52.71,33.99 48.76,33.99 48.15,34.6 47.11,34.6 v1(46.71,34.2) ; v1(33.6,34.23) 33.6,33.97 33.42,33.79 32.53,33.79 31.92,33.19 29.46,33.19 28.9,33.74 28.32,33.74 v4(28.24,33.82) 28.06,33.82 27.86,34.01 24.12,34.01 23.54,34.59 22.46,34.59 v1(22.07,34.2)
  BOTTOM w0.076: UCPU1.AW34 76.51,57.88 v1(76.19,57.56) ; v1(46.71,34.2) 47.64,33.27 UD4.L3 ; UD2.L3 35.28,33.11 34.41,33.11 33.6,33.92 v1(33.6,34.23) ; UD5.L3 59.92,33.11 58.77,33.11 58.24,33.64 v8(58.24,34.23) ; v1(22.07,34.2) 23,33.27 UD1.L3
DDR_B_BS0: length 140.6
  TOP w0.076: RD70.1 90.44,29.58 v1(90.19,29.32)
  IN1 w0.076: v1(76.45,63.21) 76.91,63.67 77.54,63.67 78.12,63.09 78.12,61.51 79.12,60.52 79.12,59.55 79.38,59.28
  IN1 w0.16: v1(90.19,29.32) 90.19,29.29 91.22,28.26 91.75,28.26 93.24,26.76 97.63,26.76 97.94,27.06 97.94,28.03 97.43,28.53 97.43,29.22 97.55,29.34 97.55,30.64 97.71,30.8 99.33,30.8 99.49,30.96 99.49,31.6 99.33,31.76 97.72,31.76 97.56,31.92 97.56,32.26 97.72,32.42 98.67,32.42 99.67,33.42 99.67,34.44 99.64,34.47 99.64,35.26 101.52,37.14 101.52,44.54 98.18,47.88 97.54,48.53 95.14,48.53 94.97,48.7 94.97,49.1 94.81,49.25 94.44,49.25 94.28,49.09 94.28,48.71 94.12,48.55 93.8,48.55 93.64,48.71 93.64,49.09 93.48,49.25 93.16,49.25 93,49.09 93,48.71 92.84,48.55 92.52,48.55 92.36,48.71 92.36,49.09 92.2,49.25 90.7,49.25 90.31,48.86 87.81,48.86 87.08,49.6 87.08,49.85 83.91,53.02 82.49,53.02 81.99,53.53 81.99,57.01 80.03,58.97 79.7,58.97 79.38,59.28
  IN3 w0.076: 90.22,29.32 90.34,29.2 92.04,29.2 92.5,29.65 92.5,29.88 92.43,29.96 92.25,29.96 92.17,30.04 92.17,30.24 92.25,30.31 92.86,30.31 92.93,30.24 92.93,29.66 93.01,29.59 95.84,29.59 96.15,29.9 96.15,30.11 96.26,30.23 96.7,30.23 96.77,30.29 96.77,30.42 96.66,30.53 96.66,30.87 96.73,30.95 96.9,30.95 96.97,30.87 96.97,30.67 97.05,30.59 97.2,30.59 97.28,30.67 97.28,30.77 97.37,30.86 97.52,30.86 97.58,30.8 97.58,30.7 97.68,30.59 97.81,30.59 97.89,30.67 97.89,30.8 97.96,30.87 98.11,30.87 98.19,30.8 98.19,30.67 98.27,30.59 98.42,30.59 98.7,30.88 99.43,30.88 99.59,30.72 99.59,30.57 99.71,30.44 100.23,30.44 v4(100.43,30.64) ; 90.22,29.32 v1(90.19,29.32) ; 90.22,29.32 89.99,29.55 89.84,29.55 89.11,30.27 86.43,30.27 86,30.7 85.64,30.7 85.54,30.8 83.61,30.8 83.59,30.82 79.18,30.82 79.17,30.84 76.06,30.84 v4(75.89,30.67)
  IN4 w0.076: v1(94.94,31.66) 95.37,32.09 95.98,32.09 96.35,31.72 99.12,31.72 99.36,31.48 99.36,30.97 99.66,30.66 100.4,30.66 v4(100.43,30.64) 100.45,30.67 104.59,30.67 104.88,30.96 105.8,30.96 v1(106.5,31.66) ; v8(70.3,31.66) 70.73,32.09 71.34,32.09 71.72,31.71 74.44,31.71 74.72,31.43 74.72,30.97 75.05,30.65 75.87,30.65 v4(75.89,30.67) 75.94,30.72 79.78,30.72 80.03,30.97 81.17,30.97 v1(81.86,31.66)
  BOTTOM w0.076: v1(94.94,31.66) 96.06,32.78 96.76,32.78 UD9.M2 ; UD10.M2 108.28,32.82 107.66,32.82 v1(106.5,31.66) ; UCPU1.AL35 76.18,62.94 v1(76.45,63.21) ; v8(70.3,31.66) 71.47,32.83 72.07,32.83 UD6.M2 ; UD7.M2 83.68,32.78 82.98,32.78 v1(81.86,31.66)
DDR_B_BS1: length 138.8
  TOP w0.076: v1(90.05,30.28) 90.21,30.44 RD66.1
  IN1 w0.076: 75.04,59.82 75.04,61.63 v1(74.55,62.11)
  IN1 w0.16: 75.04,59.82 75.04,59.8 75.68,59.16 75.68,55.6 75.84,55.44 76.28,55.44 76.44,55.28 76.44,53.53 77.93,52.04 78.08,52.04 78.34,51.78 78.68,51.78 79.24,51.22 79.24,50.63 79.44,50.43 80.7,50.43 81.95,49.18 84.16,49.18 84.46,48.88 84.46,48.64 84.35,48.53 84.04,48.53 83.89,48.37 83.89,48.1 84.08,47.91 85.18,47.91 86.76,46.33 89.92,46.33 90.26,45.99 94.75,45.99 94.93,45.81 94.93,43.21 94.75,43.03 93,43.03 92.26,42.29 92.26,42.01 91.82,41.56 91.82,38.32 91.65,38.16 90.37,38.16 90.21,38 90.21,37.48 89.63,36.91 89.63,36.91 88.91,36.19 88.91,34.85 88.69,34.62 88.69,33.41 89.08,33.02 89.08,32.74 89.22,32.6 89.22,31.78 89.73,31.26 89.73,30.72 89.51,30.49 89.51,30.06 89.76,29.81 90.36,29.81 90.65,29.52 90.65,29.32 91.36,28.61 92.1,28.61 92.93,27.77 96.46,27.77 96.62,27.62 96.62,27.37 96.77,27.22 97.12,27.22 97.28,27.37 97.28,28.13 97.02,28.38 93.14,28.38 92.32,29.2 91.57,29.2 91.41,29.36 91.41,30.15 90.94,30.61 90.56,30.61 90.53,30.58 90.26,30.58 90.05,30.37 v1(90.05,30.28)
  IN3 w0.076: v4(99.62,32.1) 99.62,32.01 99.93,31.7 99.93,31.59 99.79,31.45 99.68,31.45 99.18,31.95 99.18,32.25 99.13,32.3 99.02,32.3 98.83,32.1 98.83,31.99 98.76,31.93 98.4,31.93 98.27,32.05 98,32.05 97.87,31.93 97.65,31.93 97.52,32.05 96.83,32.05 96.77,31.99 96.77,31.92 96.93,31.75 96.93,31.65 96.83,31.55 96.73,31.55 96.62,31.66 96.48,31.66 96.41,31.58 96.41,31.28 96.2,31.06 96.2,30.74 96.02,30.56 95.84,30.56 95.75,30.65 95.75,30.7 95.71,30.74 93.37,30.74 93.29,30.82 93.11,30.82 93.03,30.74 92.83,30.74 92.76,30.82 92.76,30.92 92.68,31 92.5,31 92.43,30.92 92.43,30.82 92.35,30.74 92.17,30.74 92.09,30.82 92.09,30.92 92.02,31 91.79,31 91.71,30.92 91.71,30.39 91.64,30.32 91.43,30.32 91.36,30.39 91.36,30.87 91.26,30.98 91.05,30.98 90.95,30.87 90.95,30.57 90.55,30.16 90.17,30.16 v1(90.05,30.28) 89.89,30.28 89.01,31.16 88.3,31.16 87.47,31.99 83.26,31.99 82.93,31.66 82.93,31.46 82.71,31.24 76.27,31.24 75.92,31.6 75.4,31.6 75.01,31.98 v4(75.01,32.14)
  IN4 w0.076: v8(105.22,31.66) 105.2,31.64 104.82,31.64 104.35,31.16 100.84,31.16 100.75,31.25 100.4,31.25 99.62,32.03 v4(99.62,32.1) 99.48,32.25 96.58,32.25 96.3,32.52 94.53,32.52 v1(93.66,31.66) ; v1(80.58,31.66) 80.4,31.48 79.79,31.48 79.43,31.13 76.37,31.13 76.09,31.41 75.56,31.41 75.02,31.95 75.02,32.13 v4(75.01,32.14) 74.91,32.25 71.85,32.25 71.52,32.58 69.94,32.58 v1(69.03,31.66)
  BOTTOM w0.076: v1(69.03,31.66) 68.64,32.04 68.16,32.04 67.78,31.67 UD6.N8 ; UD9.N8 92.27,31.71 92.55,31.99 93.33,31.99 v1(93.66,31.66) ; v1(74.55,62.11) 74.72,62.29 UCPU1.AM36 ; v8(105.22,31.66) 104.79,32.09 104.52,32.09 104.09,31.67 UD10.N8 ; UD7.N8 79.45,31.67 79.8,32.02 80.23,32.02 v1(80.58,31.66)
DDR_B_BS2: length 134.2
  TOP w0.076: RD68.1 86.47,30.62 86.09,30.24 v1(86.09,29.97)
  IN1 w0.076: 65.35,54.6 65.25,54.7 65.25,57.14 65.32,57.21 65.78,57.21 65.88,57.32 65.88,57.46 65.78,57.57 65.32,57.57 65.25,57.65 65.25,57.75 66.45,58.95 v1(66.73,58.95)
  IN1 w0.16: v1(86.09,29.97) 86.38,29.68 86.38,29.46 86.24,29.32 86.1,29.32 85.9,29.12 85.7,29.12 85.35,29.47 85.08,29.47 84.88,29.67 84.88,29.98 84.7,30.16 83.58,30.16 83.33,30.41 83.33,30.58 82.94,30.96 82.94,31.24 83.08,31.38 83.08,31.81 82.77,32.12 81.68,32.12 81,32.8 80.77,32.8 80.51,32.55 80.29,32.55 80.13,32.71 80.13,33.08 79.96,33.25 79.78,33.25 79.45,32.93 77.44,32.93 77.23,33.13 77.23,33.46 77.05,33.65 76.49,34.2 76.49,34.79 76.35,34.93 75.16,34.93 75.03,35.06 74.8,35.06 74.64,35.22 74.64,36.35 74.24,36.75 74.24,37.06 74.4,37.22 74.44,37.22 74.6,37.38 74.6,37.67 74.08,38.19 73.46,38.19 73.3,38.35 73.3,38.92 73.14,39.08 72.79,39.08 72.38,38.67 71.86,38.67 71.7,38.83 71.7,39.31 71.98,39.59 73.15,39.59 73.3,39.74 73.3,40.26 73.44,40.4 73.81,40.4 73.84,40.42 75.55,40.42 75.71,40.58 75.71,40.85 75.55,41.01 74.14,41.01 73.35,41.8 73.35,42.55 73.24,42.65 72.71,42.65 72.61,42.55 72.61,42.35 72.5,42.24 71.75,42.24 71.57,42.06 71.57,40.73 71.37,40.53 70.73,40.53 70.55,40.71 70.55,42 70.39,42.16 69.97,42.16 68.91,43.23 68.91,43.8 68.65,44.06 68.45,44.06 68.34,43.95 68.12,43.95 67.96,44.11 67.96,44.33 68.05,44.43 68.05,44.65 67.89,44.82 67.66,44.82 67.56,44.72 67.33,44.72 67.14,44.91 67.14,45.11 67.3,45.28 67.3,45.4 67,45.71 66.85,45.71 66.71,45.57 66.48,45.57 66.29,45.76 66.29,45.99 66.56,46.25 66.56,46.47 66.35,46.67 66.14,46.67 65.86,46.39 65.66,46.39 65.46,46.59 65.46,46.79 65.74,47.07 65.74,47.28 65.54,47.49 65.32,47.49 65.02,47.18 64.87,47.18 64.72,47.32 64.72,49.71 64.93,49.91 65.36,49.91 65.47,49.79 66.08,49.79 66.21,49.92 66.21,51.26 65.85,51.62 64.87,51.62 64.72,51.77 64.72,52.06 64.87,52.21 65.33,52.21 65.51,52.39 65.51,54.44 65.35,54.6
  IN3 w0.076: v4(76.85,30.31) 76.85,30.54 76.93,30.62 77.31,30.62 77.39,30.54 77.39,30.39 77.46,30.31 77.69,30.31 77.77,30.39 77.77,30.56 77.85,30.63 78,30.63 78.07,30.56 78.07,30.39 78.15,30.31 78.33,30.31 78.4,30.39 78.4,30.56 78.48,30.63 78.63,30.63 78.71,30.56 78.71,30.39 78.79,30.31 78.96,30.31 79.04,30.39 79.04,30.54 79.12,30.62 79.3,30.62 79.38,30.54 79.38,29.97 79.51,29.84 79.65,29.84 79.73,29.92 79.73,30.54 79.8,30.62 80,30.62 80.08,30.54 80.08,29.83 80.16,29.76 82.75,29.76 82.9,29.91 82.9,30.52 82.98,30.59 83.2,30.59 83.28,30.52 83.28,30.39 83.36,30.31 83.56,30.31 83.64,30.39 83.64,30.52 83.71,30.59 83.87,30.59 83.94,30.52 83.94,30.39 84.02,30.31 84.25,30.31 84.32,30.39 84.32,30.52 84.37,30.57 84.63,30.57 84.7,30.49 84.7,30.31 84.78,30.24 84.93,30.24 85.01,30.31 85.01,30.49 85.08,30.57 85.24,30.57 85.31,30.49 85.31,29.55 85.39,29.48 85.54,29.48 85.62,29.55 85.62,30.37 85.69,30.44 85.9,30.44 86.09,30.25 v1(86.09,29.97) 86.3,29.76 88.11,29.76 88.39,30.04 89.02,30.04 89.25,29.81 89.25,29.6 89.75,29.11 89.81,29.11 90.03,28.89 90.77,28.89 90.88,28.99 92.2,28.99 92.55,29.35 95.96,29.35 96.59,29.98 96.9,29.98 97.3,30.39 98.52,30.39 98.78,30.65 99.18,30.65 99.59,30.24 101.56,30.24 v4(101.59,30.27)
  IN4 w0.076: v1(70.94,31.66) 71.39,31.66 72.19,30.86 72.96,30.86 73.2,30.62 74.62,30.62 74.84,30.4 75.39,30.4 75.53,30.26 76.8,30.26 v4(76.85,30.31) 76.9,30.36 79.8,30.36 80.16,30.73 81.97,30.73 82.49,31.25 v1(82.49,31.66) ; 101.59,30.26 101.58,30.25 100.18,30.25 100.03,30.4 99.48,30.4 99.18,30.7 97.77,30.7 97.6,30.86 96.83,30.86 96.03,31.66 v1(95.57,31.66) ; 101.59,30.26 v4(101.59,30.27) ; 101.59,30.26 101.69,30.36 104.64,30.36 104.99,30.71 106.94,30.71 107.23,31 107.23,31.56 v8(107.13,31.66)
  BOTTOM w0.076: UCPU1.AU49 66.91,59.18 66.76,59.03 66.76,58.97 v1(66.73,58.95) ; UD9.M3 96.27,32.36 v1(95.57,31.66) ; v8(107.13,31.66) 107.83,32.36 UD10.M3 ; v1(82.49,31.66) 83.19,32.36 UD7.M3 ; v1(70.94,31.66) 71.63,32.36 UD6.M3
DDR_B_CAS#: length 137.8
  TOP w0.076: v1(89.67,32.78) 89.36,33.08 88.68,33.08 RD62.1
  IN1 w0.16: v1(77.36,62.65) 77.16,62.65 76.91,62.4 76.91,60.16 77.5,59.56 77.5,59 77.59,58.92 77.95,58.92 78.82,58.04 78.82,57.75 78.98,57.59 79.29,57.59 79.45,57.43 79.45,57.04 79.29,56.88 78.98,56.88 78.82,56.72 78.82,53.97 79.17,53.63 79.17,52.78 80.46,51.49 81.13,51.49 82.39,50.23 84.6,50.23 85.59,49.24 85.59,48.98 87.2,47.38 90.36,47.38 90.69,47.05 96.42,47.05 97.05,46.42 97.05,42.58 97.68,41.95 97.68,41.64 97.38,41.34 96.77,41.34 96.72,41.39 96.41,41.39 96.18,41.16 96.18,40.75 96.03,40.6 95.7,40.6 95.35,40.25 95.35,38.98 95.19,38.82 94.95,38.82 94.79,38.66 94.79,38.4 94.95,38.24 95.19,38.24 95.42,38.01 95.42,36.77 95.58,36.61 96,36.61 96.16,36.77 96.16,37.93 96.36,38.14 96.36,39.45 96.52,39.61 97.26,39.61 97.42,39.45 97.42,39.1 96.97,38.65 96.97,38.29 97.42,37.84 97.42,37.62 97.17,37.38 97.17,37.14 97.42,36.89 97.42,36.69 97.04,36.31 96.84,36.31 96.01,35.47 94.97,35.47 94.81,35.32 94.81,34.91 94.97,34.76 96.01,34.76 96.21,34.56 96.21,33.97 96.05,33.82 96.05,30.88 95.9,30.73 95.59,30.73 95.43,30.89 95.43,31.02 95.27,31.18 94.95,31.18 94.79,31.02 94.79,30.89 94.63,30.73 94.31,30.73 94.15,30.89 94.15,31.02 93.99,31.18 93.67,31.18 93.51,31.02 93.51,30.89 93.35,30.73 92.93,30.73 92.25,31.41 92.25,31.76 92.41,31.92 93.05,31.92 93.21,32.08 93.21,32.8 93.07,32.94 92.82,32.94 92.63,33.13 92.63,33.39 92.53,33.49 91.79,33.49 91.26,32.96 90.85,32.96 90.32,33.49 89.74,33.49 89.45,33.2 89.45,32.94 89.61,32.78 v1(89.67,32.78)
  IN3 w0.076: v4(76.45,32.73) 76.65,32.73 77.14,33.21 80.11,33.21 80.25,33.35 82.52,33.35 83.06,32.81 86.01,32.81 86.16,32.95 89.5,32.95 v1(89.67,32.78) 90.07,33.18 90.48,33.18 90.85,32.8 91.18,32.8 91.66,33.29 92.3,33.29 92.4,33.19 92.4,32.63 92.55,32.47 92.78,32.47 92.91,32.6 92.91,32.83 93.01,32.93 94.06,32.93 94.39,32.6 94.58,32.6 94.86,32.88 95.22,32.88 95.5,32.6 96.03,32.6 96.97,33.54 99.97,33.54 100.53,32.98 100.83,32.98 v4(101.09,32.73)
  IN4 w0.076: v1(95.09,34.18) 95.66,33.61 99.95,33.61 100.76,32.8 101.01,32.8 v4(101.09,32.73) 101.25,32.89 104.74,32.89 105.09,33.25 106.97,33.25 107.39,33.67 107.39,34.07 v1(107.26,34.2) ; v8(82.65,34.2) 82.98,33.87 82.98,33.41 82.81,33.25 80.49,33.25 80.07,32.82 77.05,32.82 76.94,32.71 76.47,32.71 v4(76.45,32.73) 76.37,32.8 75.92,32.8 75.58,33.14 74.35,33.14 73.93,33.57 70.78,33.57 70.45,33.9 v1(70.45,34.18)
  BOTTOM w0.076: UCPU1.AM33 77,62.29 v1(77.36,62.65) ; UD9.K3 95.95,33.74 95.52,33.74 v1(95.09,34.18) ; v8(82.65,34.2) 82.78,34.07 UD7.K3 ; v1(107.26,34.2) 107.39,34.07 UD10.K3 ; UD6.K3 71.63,34.04 71.32,33.72 70.91,33.72 v1(70.45,34.18)
DDR_B_CKE0: length 121.6
  TOP w0.076: v1(86.01,35.44) 86.16,35.28 RD58.1
  IN1 w0.076: v8(67.48,55.92) 67.08,55.52 67.08,54.53 67.34,54.27 67.86,54.27 68.73,53.4 68.83,53.4
  IN1 w0.16: 68.83,53.4 68.97,53.26 69.16,53.26 69.31,53.42 69.31,53.8 69.46,53.95 70.63,53.95 70.78,53.8 70.78,53.14 71.16,52.76 71.77,52.76 71.88,52.65 71.88,52.41 71.98,52.31 72.22,52.31 72.39,52.14 72.39,51.96 72.23,51.8 71.89,51.8 71.58,51.49 70.51,51.49 70.33,51.68 70.33,53.33 70.17,53.48 69.92,53.48 69.77,53.33 69.77,50.41 69.93,50.25 70.91,50.25 71.1,50.06 71.1,49.22 71.35,48.97 71.8,48.97 72.28,48.49 72.28,46.9 75.85,43.33 80.08,43.33 80.47,42.94 81.15,42.94 81.58,43.38 82.62,43.38 82.92,43.08 83.51,43.08 83.81,43.38 84.62,43.38 85.82,42.18 85.82,41.38 85.69,41.25 85.38,41.25 85.26,41.38 85.26,42 84.73,42.53 82.72,42.53 82.54,42.71 81.94,42.71 81.35,42.11 81.35,41.77 81.02,41.45 81.02,41.03 81.43,40.63 81.43,38.67 82.42,37.68 82.42,36.72 82.58,36.56 82.94,36.56 83.1,36.72 83.1,37.61 83.45,37.96 83.7,37.96 83.89,37.77 83.89,37.5 84.04,37.35 85.47,37.35 85.65,37.17 85.65,36.66 85.89,36.41 85.89,35.97 86.01,35.85 v1(86.01,35.44)
  IN3 w0.076: 88.13,36.18 88.39,36.18 88.46,36.26 88.46,36.69 88.54,36.77 88.79,36.77 88.87,36.69 88.87,36.26 88.95,36.18 89.15,36.18 89.22,36.26 89.22,36.69 89.3,36.77 89.55,36.77 89.63,36.69 89.63,36.26 89.71,36.18 89.9,36.18 89.98,36.26 89.98,36.81 90.06,36.89 92.52,36.89 92.93,36.47 92.93,35.89 93.55,35.27 95.93,35.27 96.23,35.57 96.69,35.57 v4(96.75,35.5) ; v4(71.95,35.27) 71.96,35.27 71.96,35.27 74.27,35.27 74.95,35.95 76.75,35.95 76.88,35.82 76.88,35.19 77.01,35.06 77.29,35.06 77.41,35.19 77.41,35.59 77.54,35.72 78.17,35.72 78.47,35.43 79.15,35.43 79.44,35.72 79.82,35.72 80.07,35.47 81.27,35.47 81.31,35.42 85.99,35.42 v1(86.01,35.44)
  IN3 w0.081: 88.13,36.18 87.39,35.44 v1(86.01,35.44)
  IN4 w0.076: v1(101.98,34.49) 101.86,34.61 101.86,34.87 101.29,35.45 99.79,35.45 99.61,35.62 99.61,35.74 99.5,35.85 99.34,35.85 99.23,35.74 99.23,35.45 99.13,35.34 98.55,35.34 98.28,35.08 97.18,35.08 96.84,35.43 96.83,35.43 v4(96.75,35.5) ; v1(66.41,33.7) 66.41,33.42 66.49,33.34 68.27,33.34 68.42,33.48 68.42,33.8 68.73,34.11 68.73,34.34 69.45,35.06 71.56,35.06 71.7,35.21 71.89,35.21 v4(71.95,35.27) 71.95,35.27 74.82,35.27 74.95,35.39 74.95,35.71 75.07,35.83 75.24,35.83 75.36,35.71 75.36,35.2 75.54,35.02 76.84,35.02 v1(77.36,34.5)
  IN4 w0.081: v1(91,33.58) 91.24,33.82 93.01,33.82 93.37,34.18 93.37,34.38 94.05,35.06 96.21,35.06 96.43,35.28 96.53,35.28 v4(96.75,35.5)
  BOTTOM w0.076: UD6.K9 66.77,34.07 v1(66.41,33.7) ; v1(77.36,34.5) 77.82,34.04 78.37,34.04 UD7.K9 ; v1(91,33.58) 91.47,34.05 UD9.K9 ; UCPU1.AY49 67.15,56.27 67.48,55.95 v8(67.48,55.92) ; v1(101.98,34.49) 102.4,34.07 UD10.K9
DDR_B_CKE1: length 124.2
  TOP w0.076: v1(86.41,36.33) 86.61,36.54 RD89.1
  IN1 w0.16: v1(86.41,36.33) 86.57,36.5 86.57,37.22 85.86,37.93 84.28,37.93 83.92,38.29 83.92,39.43 83.76,39.59 83.44,39.59 83.28,39.43 83.28,38.29 82.93,37.93 82.66,37.93 82.29,38.3 82.29,38.6 82.17,38.72 81.92,38.72 81.78,38.85 81.78,39.04 81.92,39.18 82.08,39.18 82.24,39.34 82.24,39.58 82.08,39.74 81.94,39.74 81.78,39.9 81.78,40.16 81.94,40.32 82.09,40.32 82.21,40.45 82.21,42.05 82.34,42.18 84.58,42.18 84.91,41.85 84.91,39.54 85.06,39.38 86.01,39.38 86.17,39.54 86.17,42.32 84.76,43.73 83.66,43.73 83.37,43.43 83.06,43.43 82.76,43.73 81.44,43.73 81,43.29 80.61,43.29 80.23,43.68 75.99,43.68 72.63,47.04 72.63,50.47 72.5,50.6 70.28,50.6 70.12,50.75 70.12,50.99 70.28,51.14 72.47,51.14 72.74,51.41 72.74,52.29 71.65,53.38 71.24,53.38 71.09,53.53 71.09,54.22 70.94,54.37 68.93,54.37 68.47,54.83 v1(67.51,54.83)
  IN3 w0.076: v4(72.36,35.68) 72.38,35.68 72.52,35.54 74.19,35.54 74.8,36.15 77.3,36.15 77.53,35.92 78.26,35.92 78.54,35.64 79.06,35.64 79.35,35.92 79.92,35.92 80.18,35.67 82.04,35.67 82.08,35.62 85.39,35.62 85.64,35.88 85.95,35.88 v1(86.41,36.33) 86.76,36.69 86.76,37.15 86.84,37.22 87.17,37.22 87.24,37.15 87.24,36.16 87.32,36.08 87.62,36.08 87.7,36.16 87.7,37.12 87.78,37.2 92.65,37.2 93.16,36.69 93.16,35.94 93.46,35.65 95.93,35.65 96.2,35.92 96.98,35.92 97.43,35.47 v4(97.48,35.47)
  IN4 w0.076: v1(102.62,34.49) 102.63,34.49 102.63,34.47 102.66,34.5 101.38,35.78 100.83,35.78 100.73,35.88 100.73,36.44 100.6,36.56 100.4,36.56 100.27,36.44 100.27,36.18 100.15,36.06 99.97,36.06 99.84,36.18 99.84,36.31 99.61,36.54 99.33,36.54 99.02,36.22 98.25,36.22 97.51,35.47 v4(97.48,35.47) 97.4,35.47 97.02,35.85 96.97,35.85 96.92,35.91 96.6,35.91 95.97,35.28 93.96,35.28 93.13,34.45 93.13,34.23 92.93,34.02 91.69,34.02 91.09,34.62 v1(90.98,34.62) ; v1(78.01,34.47) 78,34.48 77.99,34.48 76.73,35.74 76.73,36.18 76.6,36.31 74.8,36.31 74.67,36.18 74.67,35.65 74.54,35.52 72.52,35.52 v4(72.36,35.68) 72.38,35.68 72.35,35.71 71.82,35.71 71.38,35.27 69.34,35.27 68.52,34.44 68.52,34.35 67.8,33.63 66.91,33.63 66.82,33.72 66.82,34.22 66.59,34.46 v8(66.37,34.46)
  BOTTOM w0.076: v1(78.01,34.47) 78.01,34.47 78.39,34.85 UD7.J9 ; v1(67.51,54.83) 67.48,54.83 66.03,56.27 66.03,58.99 66.22,59.18 UCPU1.AU50 ; UD6.J9 66.78,34.87 v8(66.37,34.46) ; UD9.J9 91.23,34.62 v1(90.98,34.62) ; UD10.J9 102.99,34.87 v1(102.62,34.49)
DDR_B_CS0#: length 128.2
  TOP w0.076: RD60.1 89.43,31.66 v1(89.78,32.01)
  IN1 w0.076: 78.21,59.18 77.64,59.75 77.64,60.29 77.74,60.39 77.74,61.63 v1(77.35,62.03)
  IN1 w0.16: v1(89.78,32.01) 89.82,32.01 90.23,31.6 91.25,31.6 93.08,29.78 95.75,29.78 96.62,30.65 96.62,33.57 96.85,33.8 97.69,33.8 97.99,34.1 97.99,41.15 98.25,41.41 98.25,41.59 98.45,41.79 100.48,41.79 100.61,41.92 100.61,42.26 100.48,42.39 98.05,42.39 97.61,42.83 97.61,43.61 97.8,43.8 100.38,43.8 100.53,43.95 100.53,44.24 100.33,44.44 97.77,44.44 97.61,44.59 97.61,46.65 96.66,47.61 90.93,47.61 90.59,47.95 87.43,47.95 86.16,49.22 86.16,49.47 83.58,52.05 80.69,52.05 80.4,52.35 80.09,52.35 79.52,52.92 79.52,53.78 79.75,54.01 79.75,57.65 78.21,59.18
  IN3 w0.076: v4(101.37,32.14) 101.03,32.14 99.84,33.33 97.12,33.33 95.98,32.19 94.51,32.19 93.98,32.72 93.53,32.72 93.19,32.38 93.19,31.81 92.98,31.61 90.18,31.61 v1(89.78,32.01) 89.05,32.75 86.24,32.75 86.1,32.61 82.92,32.61 82.38,33.15 80.37,33.15 80.23,33.01 77.53,33.01 v4(76.67,32.15)
  IN4 w0.076: 76.72,32.15 v4(76.67,32.15) ; 76.72,32.15 76.77,32.15 77.18,32.55 80.16,32.55 80.55,32.94 82.88,32.94 v1(83.6,33.66) ; 76.72,32.15 76.7,32.12 76.32,32.12 75.5,32.94 74.27,32.94 73.84,33.36 71.6,33.36 71.52,33.29 71.52,33.13 71.67,32.98 71.8,32.98 72,32.78 72.73,32.78 v1(72.83,32.88) ; v8(97.47,32.88) 97.39,32.8 96.87,32.8 96.69,32.98 96.29,32.98 96.18,33.09 96.18,33.24 96.29,33.35 99.88,33.35 101.11,32.12 101.39,32.12 101.42,32.14 v4(101.37,32.14) ; 105.17,32.94 107.49,32.94 108.23,33.69 v1(108.23,33.67)
  IN4 w0.081: 101.42,32.14 101.85,32.58 104.8,32.58 105.17,32.94
  BOTTOM w0.076: UD9.L2 97.11,33.27 97.45,32.92 97.45,32.89 v8(97.47,32.88) ; UCPU1.AM32 77.6,62.29 v1(77.35,62.03) ; v1(72.83,32.88) 72.82,32.89 72.82,32.92 72.47,33.27 UD6.L2 ; UD10.L2 108.58,33.27 108.23,33.62 108.23,33.67 v1(108.23,33.67) ; v1(83.6,33.66) 83.6,33.66 83.6,33.61 83.94,33.27 UD7.L2
DDR_B_CS1#: length 127.9
  TOP w0.076: RD90.1 90.48,31.33 v1(90.29,31.14)
  IN1 w0.076: 78.66,59.32 78.52,59.46 78.16,59.46 77.82,59.79 77.82,60.19 77.95,60.31 77.95,62.78 77.44,63.28 v1(77.37,63.28)
  IN1 w0.16: 78.66,59.32 80.03,57.95 80.03,53.68 79.9,53.55 79.9,53.05 80.25,52.7 80.54,52.7 80.83,52.42 83.71,52.42 86.51,49.62 86.51,49.36 87.58,48.3 90.55,48.3 90.93,48.69 91.46,48.69 92.18,47.96 96.9,47.96 97.99,46.87 97.99,44.94 98.14,44.79 100.48,44.79 100.93,44.33 100.93,43.6 100.78,43.45 98.91,43.45 98.72,43.25 98.72,42.92 98.89,42.74 100.81,42.74 100.96,42.59 100.96,41.67 100.73,41.44 98.89,41.44 98.34,40.89 98.34,33.82 97.97,33.45 97.14,33.45 96.97,33.29 96.97,30.37 96.03,29.43 92.93,29.43 91.18,31.18 90.33,31.18 v1(90.29,31.14)
  IN3 w0.076: v4(104.06,32.12) 104.06,32.05 103.66,31.64 101.18,31.64 99.94,32.88 99,32.88 98.58,32.46 96.65,32.46 96,31.81 96,31.49 95.72,31.2 93.52,31.2 93.31,31.41 90.56,31.41 v1(90.29,31.14) 89.92,31.14 88.51,32.55 86.32,32.55 86.18,32.4 82.62,32.4 82.07,32.94 80.47,32.94 80.28,32.75 80.28,32.58 80.2,32.5 79.9,32.5 79.83,32.58 79.83,32.73 79.75,32.8 78.23,32.8 78.15,32.73 78.15,32.58 78.23,32.5 79.34,32.5 79.42,32.42 v4(79.42,32.12)
  IN4 w0.076: v1(84.39,33.67) 83.46,32.74 82.14,32.74 82.04,32.64 82.04,32.22 81.93,32.12 81.63,32.12 81.5,32.25 81.5,32.63 81.39,32.74 80.64,32.74 80.25,32.35 79.65,32.35 v4(79.42,32.12) 79.42,32.05 79,31.63 76.51,31.63 75.4,32.74 73.88,32.74 v1(73.71,32.9) ; v1(98.39,32.91) 98.42,32.88 99.92,32.88 101.18,31.62 103.6,31.62 104.06,32.07 v4(104.06,32.12) 104.22,32.28 104.83,32.28 105.23,32.68 109.06,32.68 109.34,32.96 109.34,33.36 v8(109.04,33.67)
  BOTTOM w0.076: v1(73.71,32.9) 73.71,33.03 73.47,33.27 UD6.L1 ; v1(98.39,32.91) 98.39,33.03 98.16,33.27 UD9.L1 ; UCPU1.AK32 77.67,63.59 v1(77.37,63.28) ; UD7.L1 84.79,33.27 v1(84.39,33.67) ; v8(109.04,33.67) 109.43,33.27 UD10.L1
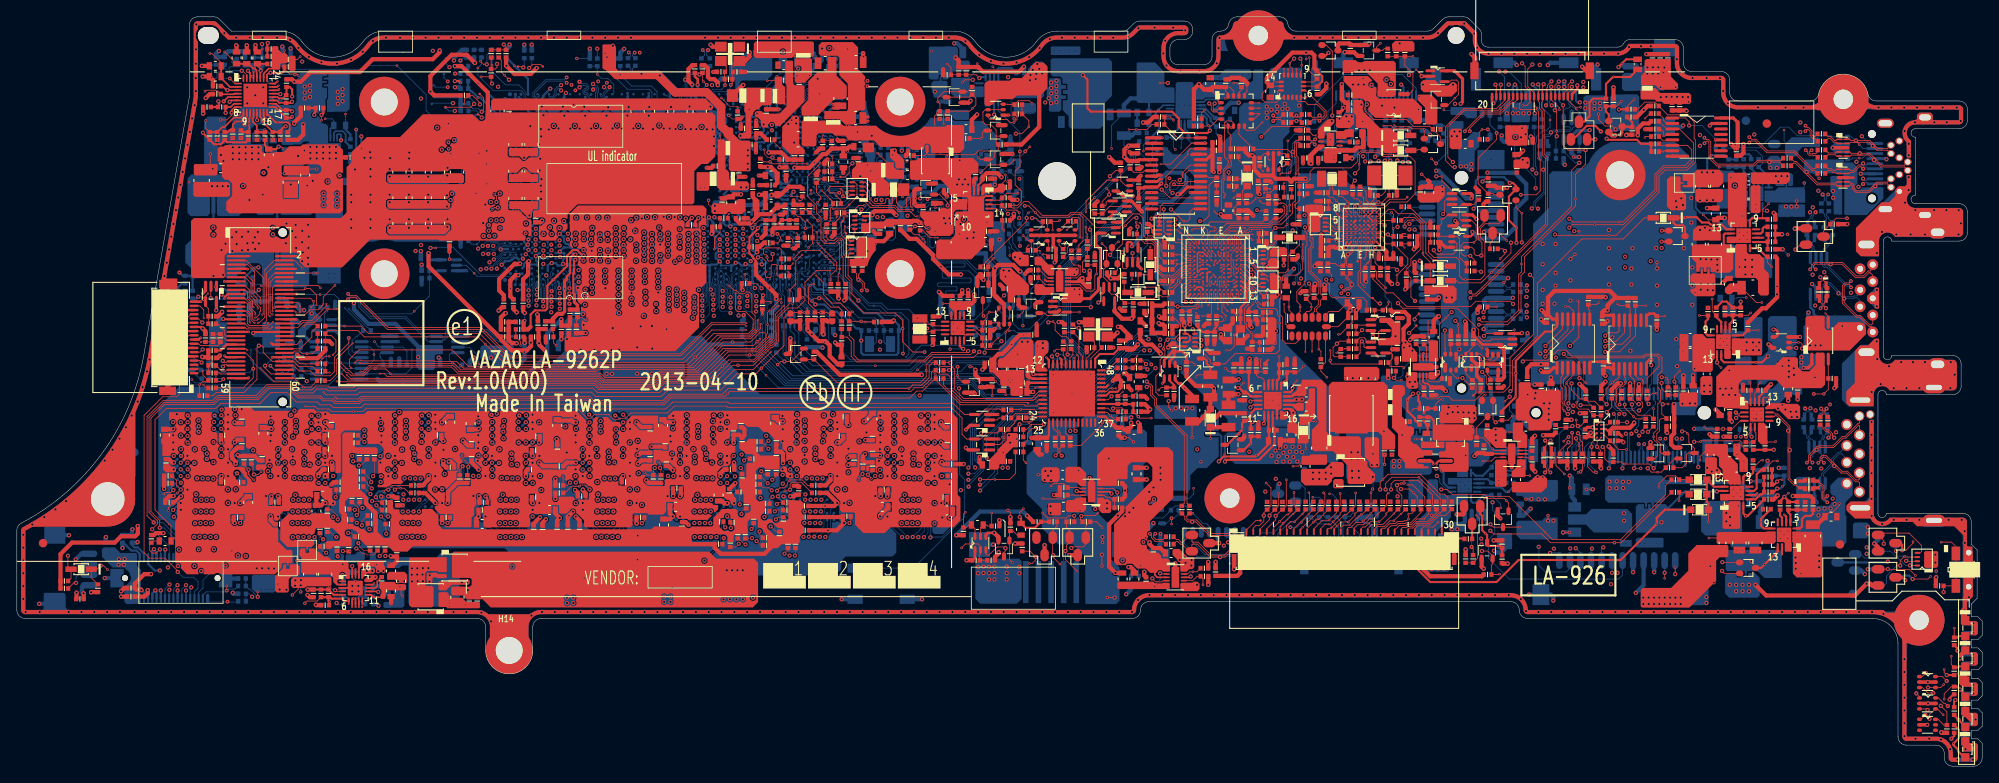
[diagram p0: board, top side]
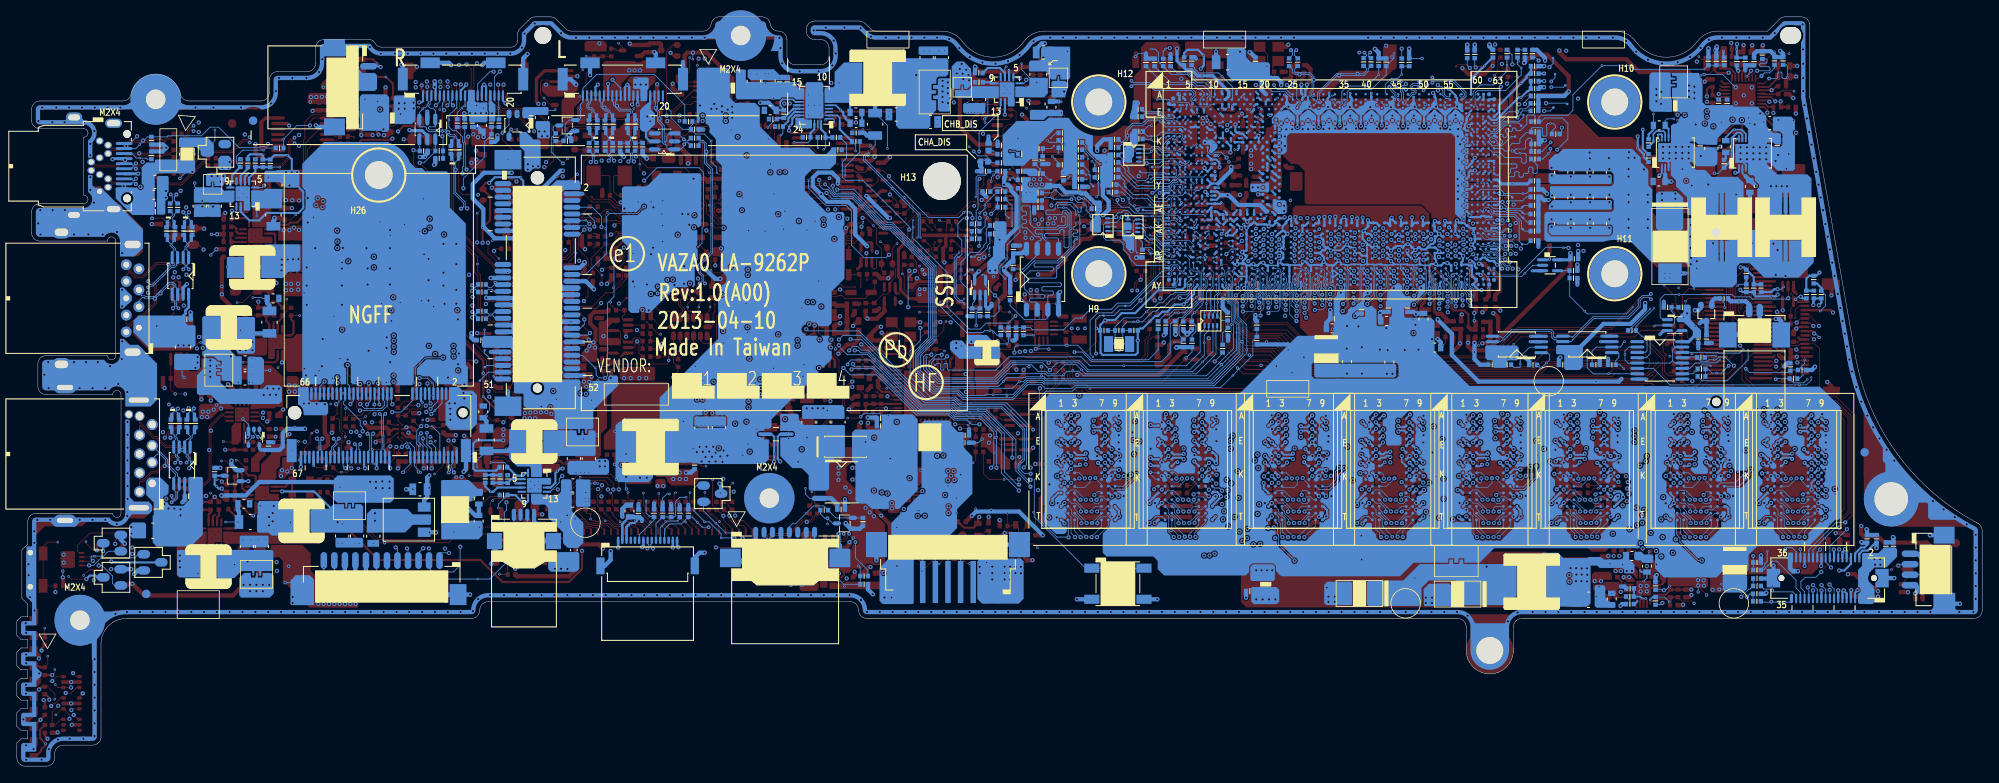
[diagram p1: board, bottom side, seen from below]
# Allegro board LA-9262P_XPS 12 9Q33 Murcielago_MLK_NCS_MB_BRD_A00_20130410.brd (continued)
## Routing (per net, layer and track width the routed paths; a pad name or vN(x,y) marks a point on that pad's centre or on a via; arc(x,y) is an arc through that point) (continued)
DDR_B_D0: length 27.4
  IN4 w0.076: 78.35,53.1 78.35,54.32 78.02,54.65 78.02,56.15 v1(77.46,56.71)
  IN4 w0.132: 78.35,53.1 78.35,47.8 78.49,47.67 78.83,47.67 78.96,47.54 78.96,47.28 78.83,47.14 78.49,47.14 78.35,47.01 78.35,46.52 80.74,44.13 80.74,43.32 80.85,43.22 81.25,43.22 81.4,43.07 81.4,42.72 81.27,42.59 80.9,42.59 80.77,42.46 80.77,42.2 80.9,42.06 81.27,42.06 81.4,41.93 81.4,41.67 81.27,41.53 80.9,41.53 80.77,41.4 80.77,41.14 80.9,41.01 81.27,41.01 81.4,40.87 81.4,38.11 81.16,37.87 81.16,36.28 80.89,36.01 80.66,36.01 v8(80.54,36.12)
  BOTTOM w0.076: v1(77.46,56.71) 77.46,56.84 UCPU1.AY31
  BOTTOM w0.183: UD7.H7 80.09,35.67 v8(80.54,36.12)
DDR_B_D1: length 29.9
  IN4 w0.076: 78.02,53.48 78.02,54.42 77.85,54.6 77.85,55.92 77.67,56.1 v1(77.46,56.1)
  IN4 w0.132: v8(80.39,37.67) 80.39,37.84 80.58,38.02 80.86,38.02 81.07,38.24 81.07,38.47 80.89,38.65 80.6,38.65 80.42,38.82 80.42,42.06 79.9,42.58 79.9,42.89 80.42,43.41 80.42,43.65 80.29,43.78 80.11,43.78 79.52,43.2 79.32,43.2 79.17,43.34 79.17,43.55 79.88,44.26 79.88,44.54 79.77,44.65 79.58,44.65 78.82,43.88 78.6,43.88 78.44,44.04 78.44,44.26 79.21,45.02 79.21,45.21 79.02,45.4 78.83,45.4 78.4,44.96 78.21,44.96 78.03,45.15 78.03,45.33 78.46,45.77 78.46,45.96 78.02,46.39 78.02,53.48
  BOTTOM w0.076: v1(77.46,56.1) 77.01,56.55 77.01,56.92 77.17,57.09 77.33,57.09 77.74,57.49 77.74,57.49 77.85,57.6 UCPU1.AW31
  BOTTOM w0.183: v8(80.39,37.67) 79.99,37.27 UD7.F7
DDR_B_D2: length 28
  IN4 w0.132: v1(79.29,56.25) 80.54,56.25 80.97,55.82 80.97,49.77 86.05,44.69 86.05,37.88 85.64,37.48 85.64,36.28 85.66,36.26 85.66,35.89 85.37,35.61 84.06,35.61 v1(83.59,36.08)
  BOTTOM w0.076: UCPU1.AY29 79.2,56.34 v1(79.29,56.25)
  BOTTOM w0.183: v1(83.59,36.08) 83.98,36.47 UD7.G2
DDR_B_D3: length 28.4
  IN4 w0.076: v1(79.29,55.64) 79.62,55.64 79.9,55.36 79.9,53.17 80.19,52.88
  IN4 w0.132: v8(83.58,36.88) 84.72,38.01 85.36,38.01 85.67,38.32 85.67,44.49 85.3,44.86 85.11,44.86 84.91,44.65 84.72,44.65 84.53,44.84 84.53,45.02 84.74,45.23 84.74,45.42 84.55,45.6 84.37,45.6 84.16,45.4 83.97,45.4 83.79,45.58 83.79,45.77 83.99,45.98 83.99,46.16 83.81,46.35 83.62,46.35 83.41,46.14 83.23,46.14 83.04,46.33 83.04,46.52 83.25,46.72 83.25,46.91 80.34,49.81 80.34,52.73 80.19,52.88
  BOTTOM w0.076: UCPU1.AW29 79.2,57.61 79.47,57.34 79.47,56.6 79.67,56.4 79.67,56.02 v1(79.29,55.64)
  BOTTOM w0.183: v8(83.58,36.88) 83.97,37.27 UD7.F2
DDR_B_D4: length 29
  IN4 w0.076: 77.78,53.75 77.86,53.82 77.86,54.33 77.46,54.72 v8(77.46,54.88)
  IN4 w0.132: v1(78.8,36.07) 79.12,35.75 79.91,35.75 80.06,35.9 80.06,37.07 79.88,37.25 79.88,37.83 80.06,38.01 80.06,41.97 79.37,42.66 79.19,42.66 78.83,42.3 78.64,42.3 78.45,42.48 78.45,42.67 78.81,43.03 78.81,43.22 78.62,43.4 78.44,43.4 78.08,43.04 77.89,43.04 77.71,43.23 77.71,43.42 78.06,43.78 78.06,43.96 77.7,44.33 77.7,53.67 77.78,53.75
  BOTTOM w0.076: UCPU1.AV31 77.85,58.28 78.12,58 78.12,57.77 78.05,57.7 78.05,57.42 78.12,57.34 78.12,57.12 77.85,56.84 77.85,55.18 77.54,54.88 v8(77.46,54.88)
  BOTTOM w0.183: UD7.H8 79.19,35.68 v1(78.8,36.07)
DDR_B_D5: length 29.5
  IN4 w0.076: v1(77.46,55.49) 77.08,55.11 77.08,53.96 77.38,53.67 77.38,53.03
  IN4 w0.132: v8(78.8,37.66) 79.12,37.98 79.12,38.1 78.98,38.23 78.3,38.23 78.15,38.38 78.15,38.6 78.3,38.76 78.98,38.76 79.12,38.89 79.12,39.15 78.98,39.28 78.28,39.28 78.12,39.44 78.12,39.66 78.28,39.81 78.98,39.81 79.12,39.95 79.12,40.21 78.98,40.34 78.54,40.34 78.4,40.47 78.4,40.74 78.54,40.87 78.96,40.87 79.12,41.02 79.12,41.74 78.96,41.9 78.56,41.9 78.18,42.27 78,42.27 77.73,42 77.54,42 77.35,42.19 77.35,42.37 77.62,42.64 77.62,42.83 77.38,43.08 77.38,53.03
  BOTTOM w0.076: v1(77.46,55.49) 76.83,56.12 76.83,56.96 77.12,57.25 77.27,57.25 77.46,57.44 77.46,58.64 77.85,59.02 UCPU1.AU31
  BOTTOM w0.183: v8(78.8,37.66) 79.19,37.27 UD7.F8
DDR_B_D6: length 29.9
  IN4 w0.076: v8(79.3,54.99) 79.56,54.99 79.75,54.8 79.75,53 80.02,52.73 80.02,52.56
  IN4 w0.132: v1(82.6,36.08) 83.13,36.62 83.13,37.08 83.63,37.57 83.63,38.49 84.14,39 84.9,39 85.15,39.25 85.16,39.25 85.29,39.38 85.29,43.62 82.37,46.54 82.37,46.73 82.52,46.89 82.52,47.07 82.34,47.26 82.15,47.26 81.99,47.11 81.81,47.11 81.62,47.29 81.62,47.48 81.78,47.64 81.78,47.82 81.59,48.01 81.4,48.01 81.25,47.85 81.06,47.85 80.87,48.04 80.87,48.23 81.03,48.38 81.03,48.57 80.84,48.76 80.65,48.76 80.5,48.6 80.31,48.6 80.02,48.89 80.02,52.56
  BOTTOM w0.076: UCPU1.AV29 79.62,58 79.62,56.67 79.83,56.46 79.83,55.51 v8(79.3,54.99)
  BOTTOM w0.183: UD7.H3 83.01,35.67 v1(82.6,36.08)
DDR_B_D7: length 30.2
  IN4 w0.132: v8(82.77,38.49) 83.81,39.54 84.63,39.54 84.88,39.79 84.88,42.46 84.75,42.59 83.24,42.59 83.1,42.73 83.1,42.99 83.24,43.12 84.75,43.12 84.88,43.25 84.88,43.57 79.7,48.76 79.7,52.67 79.39,52.97 79.39,54.1 v1(79.29,54.21)
  BOTTOM w0.076: v1(79.29,54.21) 79.26,54.24 78.38,54.24 78,54.63 78,56.78 78.28,57.06 78.28,57.4 78.2,57.48 78.2,57.63 78.28,57.71 78.28,58.06 78.18,58.17 78.18,58.92 78.44,59.18 UCPU1.AU29
  BOTTOM w0.183: UD7.E3 83.19,38.07 v8(82.77,38.49)
DDR_B_D8: length 29
  IN3 w0.076: 79.27,53.61 79.75,54.09 79.75,54.95 80.5,55.7 v3(80.5,55.71)
  IN3 w0.132: v1(79.59,39.26) 78.38,39.26 77.96,39.67 76.25,39.67 76.09,39.83 76.09,40.14 76.25,40.3 77.26,40.3 77.41,40.45 77.41,40.86 77.03,41.24 77.03,45.66 77.19,45.81 78.41,45.81 78.56,45.96 78.56,46.17 78.41,46.32 77.54,46.32 77.41,46.44 77.41,48.7 77.57,48.86 78.46,48.86 78.61,49.01 78.61,49.19 78.46,49.35 77.58,49.35 77.41,49.52 77.41,52.21 78.65,53.44 79.1,53.44 79.27,53.61
  BOTTOM w0.076: v3(80.5,55.71) 80.28,55.93 80.28,57.22 UCPU1.AY27
  BOTTOM w0.183: v1(79.59,39.26) 79.97,38.87 UD7.D7
DDR_B_D9: length 29.5
  IN3 w0.076: 79.5,52.87 79.69,53.06 79.69,53.52 80.08,53.91 80.08,54.19 80.38,54.49 v8(80.5,54.49)
  IN3 w0.132: 79.5,52.87 79.12,52.49 78.73,52.49 78.18,51.93 78.18,50.15 78.33,50 79.13,50 79.28,49.85 79.28,48.35 79.12,48.19 78.23,48.19 78.07,48.04 78.07,47.13 78.23,46.98 79.13,46.98 79.28,46.82 79.28,45.17 79.15,45.05 77.85,45.05 77.69,44.89 77.69,43.98 77.85,43.83 79.37,43.83 79.52,43.68 79.52,43.47 79.37,43.32 77.85,43.32 77.69,43.17 77.69,42.99 77.85,42.84 78.61,42.84 78.76,42.68 78.76,40.5 78.91,40.35 79.22,40.35 79.6,40.72 v1(79.6,40.88)
  BOTTOM w0.076: UCPU1.AW27 80.28,57.62 80.57,57.34 80.57,57.04 80.44,56.91 80.44,56.43 80.89,55.97 80.89,54.89 v8(80.5,54.49)
  BOTTOM w0.183: v1(79.6,40.88) 79.19,40.48 UD7.B8
DDR_B_D10: length 27.9
  IN3 w0.132: v1(83.61,41.69) 84.11,42.19 87.09,42.19 87.24,42.34 87.24,42.56 87.09,42.71 84.83,42.71 84.68,42.86 84.68,43.09 84.83,43.24 85.69,43.24 85.85,43.4 85.85,43.88 84.75,44.98 84.75,51.17 84.62,51.3 83.87,51.3 83.74,51.43 83.74,51.7 83.87,51.83 84.62,51.83 84.75,51.96 84.75,52.84 84.6,53 82.51,53 82.36,53.15 82.36,53.8 v8(81.44,54.72)
  BOTTOM w0.076: v8(81.44,54.72) 81.96,55.25 81.96,56.16 81.77,56.35 81.77,56.88 81.63,57.02 UCPU1.AY25
  BOTTOM w0.183: v1(83.61,41.69) 83.99,41.31 UD7.A2
DDR_B_D11: length 28.9
  IN3 w0.132: v8(82.8,41.67) 84.43,43.3 84.43,49.64 84.27,49.8 81.88,49.8 81.73,49.95 81.73,50.21 81.86,50.35 84.29,50.35 84.42,50.48 84.42,50.74 84.29,50.87 81.86,50.87 81.73,51.01 81.73,51.27 81.86,51.4 83.26,51.4 83.41,51.56 83.41,51.78 83.26,51.93 81.86,51.93 81.73,52.06 81.73,52.29 81.99,52.54 81.99,53.57 v1(81.44,54.11)
  BOTTOM w0.076: UCPU1.AW25 81.63,57.62 81.9,57.35 81.9,57.12 81.9,57.11 81.92,57.09 81.92,56.41 82.11,56.22 82.11,54.78 v1(81.44,54.11)
  BOTTOM w0.183: UD7.A3 83.19,41.28 v8(82.8,41.67)
DDR_B_D12: length 29
  IN3 w0.076: 80.97,52.62 80.97,52.93 81.46,53.42 v1(81.46,53.51)
  IN3 w0.132: v8(82.72,40.09) 82.44,40.09 81.92,40.62 81.92,42.01 83.78,43.87 83.78,46.85 83.63,47 81.12,47 80.97,47.16 80.97,47.37 81.12,47.52 83.61,47.52 83.76,47.67 83.76,47.89 83.61,48.05 81.12,48.05 80.97,48.2 80.97,52.62
  BOTTOM w0.076: UCPU1.AV27 80.39,58.15 80.61,57.92 80.61,57.51 80.73,57.39 80.73,56.98 80.59,56.85 80.59,56.49 81.05,56.03 81.05,53.92 v1(81.46,53.51)
  BOTTOM w0.183: UD7.C3 83.15,39.67 v8(82.72,40.09)
DDR_B_D13: length 29.8
  IN3 w0.076: 79.7,52.64 79.89,52.83 79.89,53.47 80.3,53.88 v1(80.5,53.88)
  IN3 w0.132: 79.7,52.64 79.6,52.54 79.6,51.93 79.5,51.83 78.65,51.83 78.51,51.69 78.51,51.49 78.65,51.35 79.46,51.35 79.6,51.2 79.6,51 79.46,50.86 78.66,50.86 78.51,50.71 78.51,50.48 78.66,50.33 79.45,50.33 79.6,50.18 79.6,48.04 79.42,47.87 78.56,47.87 78.4,47.71 78.4,47.49 78.56,47.33 79.42,47.33 79.6,47.15 79.6,44.84 79.45,44.69 78.18,44.69 78.02,44.54 78.02,44.31 78.18,44.16 79.7,44.16 80.13,43.73 80.13,43.6 79.42,42.89 79.24,42.89 79.09,42.74 79.09,42.56 79.32,42.33 79.32,42.18 79.09,41.95 79.09,41.49 79.24,41.34 79.45,41.34 79.6,41.49 v8(79.6,41.69)
  BOTTOM w0.076: UCPU1.AU27 80.34,59.18 80.01,58.84 80.01,58.74 79.8,58.54 79.8,56.7 79.98,56.53 79.98,54.4 v1(80.5,53.88)
  BOTTOM w0.183: v8(79.6,41.69) 79.99,41.3 UD7.A7
DDR_B_D14: length 29.2
  IN3 w0.132: v8(81.46,52.9) 81.35,52.78 81.35,49.59 81.48,49.46 83.94,49.46 84.09,49.31 84.09,49.08 83.94,48.93 81.48,48.93 81.35,48.8 81.35,48.53 81.5,48.37 83.95,48.37 84.1,48.22 84.1,43.74 82.24,41.87 82.24,40.75 82.44,40.55 83.23,40.55 83.59,40.19 v1(83.59,40.09)
  BOTTOM w0.076: UCPU1.AV25 81.63,58.46 81.91,58.18 81.91,57.56 82.05,57.42 82.05,57.17 82.07,57.15 82.07,56.48 82.27,56.29 82.27,53.7 v8(81.46,52.9)
  BOTTOM w0.183: UD7.C2 83.99,39.69 v1(83.59,40.09)
DDR_B_D15: length 30.4
  IN3 w0.076: 79.32,53.15 79.48,53.32 79.48,53.54 79.9,53.96 79.9,54.58 80.43,55.11 v1(80.5,55.11)
  IN3 w0.132: 79.32,53.15 79.1,52.93 78.67,52.93 77.79,52.06 77.79,49.9 78.02,49.67 78.79,49.67 78.94,49.52 78.94,48.66 78.79,48.51 77.9,48.51 77.74,48.36 77.74,46.8 77.9,46.65 78.79,46.65 78.94,46.49 78.94,45.58 78.79,45.43 77.52,45.43 77.36,45.28 77.36,42.2 77.52,42.05 77.77,42.05 77.87,42.15 77.87,42.35 78.02,42.51 78.28,42.51 78.43,42.35 78.43,39.71 78.56,39.58 79.18,39.58 79.59,39.98 v8(79.59,40.08)
  BOTTOM w0.076: UCPU1.AU25 81.57,59.12 80.82,59.12 80.56,58.86 80.35,58.86 79.95,58.47 79.95,56.77 80.13,56.59 80.13,55.47 v1(80.5,55.11)
  BOTTOM w0.183: v8(79.59,40.08) 79.19,39.69 UD7.C8
DDR_B_D16: length 37
  IN4 w0.076: 75.81,64.07 76.14,64.4 76.5,64.4 77.01,63.89 77.54,63.89 78.23,63.21 78.23,62.82 v1(78.75,62.29)
  IN4 w0.132: v8(68.02,36.06) 68.47,36.51 68.47,37.15 68.4,37.22 68.4,38.09 68.52,38.21 68.52,43.14 72.6,47.21 72.6,52.98 72.99,53.37 72.99,54.06 73.48,54.55 73.48,58.86 74.31,59.7 74.77,59.7 74.95,59.88 74.95,63.46 75.56,64.07 75.81,64.07
  BOTTOM w0.076: UCPU1.AM29 v1(78.75,62.29)
  BOTTOM w0.183: v8(68.02,36.06) 67.63,35.67 UD6.H8
DDR_B_D17: length 37
  IN4 w0.076: 75.76,64.45 75.92,64.6 76.6,64.6 76.7,64.51 76.8,64.51 77.21,64.1 78.48,64.1 v3(78.75,63.82)
  IN4 w0.132: v1(67.25,36.87) 67.69,37.3 67.69,38.01 67.3,38.39 67.3,42.43 72.27,47.4 72.27,53.14 72.49,53.35 72.49,58.94 73.12,59.58 73.68,59.58 74.06,59.96 74.06,63.79 74.72,64.45 75.76,64.45
  BOTTOM w0.076: v3(78.75,63.82) 78.98,63.59 UCPU1.AK29
  BOTTOM w0.183: v1(67.25,36.87) 67.63,37.25 UD6.F8
DDR_B_D18: length 33.3
  IN4 w0.076: v8(79.8,62.6) 80,62.6 80.21,62.4 80.21,59.59 78.9,58.28 77.57,58.28 76.91,57.62 76.91,55.61 76.75,55.46 76.75,53.68 76.59,53.52 76.59,53.35
  IN4 w0.132: v1(72.03,37.66) 72.02,37.66 72.02,38.39 72.57,38.93 73.34,38.93 75.9,41.49 76.35,41.49 76.52,41.67 76.52,41.95 76.35,42.13 75.94,42.13 75.76,42.3 75.76,42.58 75.94,42.76 76.35,42.76 76.52,42.94 76.52,43.22 76.35,43.4 75.89,43.4 75.76,43.52 75.76,45.43 76.59,46.25 76.59,53.35
  BOTTOM w0.076: v8(79.8,62.6) 79.8,62.55 80.19,62.94 UCPU1.AL28
  BOTTOM w0.183: v1(72.03,37.66) 72.42,37.27 UD6.F2
DDR_B_D19: length 33.3
  IN4 w0.076: 76.91,53.4 76.91,53.56 76.93,53.58 76.93,55.33 77.08,55.49 77.08,57.21 77.87,58 78.91,58 80.36,59.45 80.36,62.69 v1(79.8,63.25)
  IN4 w0.132: v1(72.03,36.87) 73.37,38.21 74,38.21 76.91,41.11 76.91,43.65 76.78,43.78 76.32,43.78 76.14,43.95 76.14,44.23 76.32,44.41 76.78,44.41 76.91,44.54 76.91,53.4
  BOTTOM w0.076: v1(79.8,63.25) 79.81,63.25 79.83,63.23 79.85,63.23 80.21,63.59 UCPU1.AK28
  BOTTOM w0.183: UD6.G2 72.43,36.47 v1(72.03,36.87)
DDR_B_D20: length 31.6
  IN4 w0.076: 74.14,58.36 74.14,58.91 74.55,59.32 74.96,59.32 75.14,59.5 75.72,59.5 75.88,59.65 77.19,59.65 78.07,60.54 78.51,60.54 v1(78.73,60.31)
  IN4 w0.132: v1(68.96,36.84) 69.82,37.7 69.82,42.19 73.24,45.61 73.24,52.66 73.79,53.21 73.79,53.66 74.14,54.01 74.14,58.36
  BOTTOM w0.076: v1(78.73,60.31) 78.73,60.26 78.81,60.34 UCPU1.AR29
  BOTTOM w0.183: UD6.H7 68.44,35.67 68.96,36.19 v1(68.96,36.84)
DDR_B_D21: length 33.4
  IN4 w0.076: v3(78.75,61.64) 78.75,61.65 77.17,61.65 76.93,61.4 76.27,61.4 75.86,61 75.86,59.86 75.66,59.65 75.08,59.65 74.9,59.47 74.47,59.47 73.81,58.81
  IN4 w0.132: v1(68.86,37.7) 68.86,38.39 69.04,38.57 69.29,38.57 69.41,38.7 69.41,39.03 69.23,39.2 69.04,39.2 68.86,39.38 68.86,42.08 69.03,42.25 69.41,42.25 69.6,42.44 69.6,42.57 69.16,43.02 69.16,43.27 69.35,43.46 69.6,43.46 69.92,43.14 70.3,43.14 72.92,45.76 72.92,52.84 73.37,53.3 73.37,53.8 73.81,54.24 73.81,58.81
  BOTTOM w0.076: UCPU1.AN29 v3(78.75,61.64)
  BOTTOM w0.183: UD6.F7 68.43,37.28 v1(68.86,37.7)
DDR_B_D22: length 31
  IN4 w0.076: v8(79.67,60.03) 79.67,59.88 78.68,58.89 77.46,58.89 76.58,58 76.58,55.97 76.37,55.77 76.37,53.94 75.94,53.51
  IN4 w0.132: v1(71.19,38.47) 72.33,39.61 73.07,39.61 74.11,40.65 74.11,41.11 74.37,41.36 74.82,41.36 75,41.54 75,41.82 74.82,42 73.35,42 73.22,42.13 73.22,42.51 73.35,42.63 74.75,42.63 75,42.89 75,50.13 75.94,51.07 75.94,53.51
  BOTTOM w0.076: UCPU1.AR28 80.05,60.34 79.67,59.96 v8(79.67,60.03)
  BOTTOM w0.183: UD6.E3 71.59,38.07 v1(71.19,38.47)
DDR_B_D23: length 31.4
  IN4 w0.076: 76.26,53.24 76.26,53.57 76.55,53.86 76.55,55.56 76.73,55.74 76.73,57.8 77.46,58.53 78.89,58.53 80.06,59.7 80.06,60.45 79.79,60.72 v1(79.78,60.72)
  IN4 w0.132: 76.26,53.24 76.26,46.44 75.38,45.55 75.38,41.44 74.91,40.97 74.56,40.97 74.43,40.85 74.43,40.49 73.2,39.26 72.43,39.26 71.7,38.52 71.7,38.21 71.57,38.09 71.57,36.69 v3(70.99,36.11)
  BOTTOM w0.076: UCPU1.AP28 80.04,60.99 v1(79.78,60.72)
  BOTTOM w0.183: UD6.H3 71.43,35.67 v3(70.99,36.11)
DDR_B_D24: length 35.5
  IN3 w0.076: 75.13,63.61 75.16,63.64 77.01,63.64 77.03,63.67 78,63.67 78.33,63.33 79.12,63.33 79.47,63.69 80,63.69 80.21,63.49 80.21,62.42 80.66,61.96 v1(80.75,61.96)
  IN3 w0.132: v1(68.04,40.86) 68.04,40.88 67.54,41.38 67.54,42.47 69.97,44.89 71.06,44.89 71.9,45.73 71.9,47.57 73.09,48.76 73.09,53.86 73.81,54.57 73.81,59.14 74.37,59.7 74.75,59.7 75,59.96 75,63.48 75.13,63.61
  BOTTOM w0.076: v1(80.75,61.96) 80.75,62.03 81.14,61.64 UCPU1.AN26
  BOTTOM w0.183: UD6.B8 67.63,40.48 68.04,40.88 v1(68.04,40.86)
DDR_B_D25: length 32.8
  IN3 w0.076: 75.66,59.65 75.71,59.7 77.18,59.7 77.34,59.55 79.98,59.55 80.26,59.83 80.26,60.16 v1(80.74,60.64)
  IN3 w0.132: v8(67.99,41.79) 67.99,41.99 70.58,44.57 71.2,44.57 71.42,44.79 73.6,44.79 73.72,44.91 73.72,45.31 73.6,45.43 72.4,45.43 72.22,45.6 72.22,47.2 74.15,49.12 74.15,50.16 73.45,50.86 73.45,53.63 74.19,54.37 74.19,59.04 74.49,59.35 75.36,59.35 75.66,59.65 75.66,59.65
  BOTTOM w0.076: v1(80.74,60.64) 81.05,60.34 UCPU1.AR26
  BOTTOM w0.183: UD6.A7 68.43,41.35 v8(67.99,41.79)
DDR_B_D26: length 30.9
  IN3 w0.076: v1(81.67,59.98) 81.67,59.66 80.22,58.22
  IN3 w0.132: v1(71.17,40.02) 71.09,40.09 70.73,40.09 70.2,40.63 70.2,42.38 70.96,43.14 71.98,43.14 72.23,43.4 74.75,43.4 75,43.65 75,48.09 75.97,49.06 75.97,51.05 75.83,51.18 75.54,51.18 75.41,51.32 75.41,51.58 75.54,51.71 75.83,51.71 75.97,51.85 75.97,52.87 76.65,53.56 76.65,57.16 77.64,58.15 80.16,58.15 80.22,58.22
  BOTTOM w0.076: UCPU1.AR25 82.06,60.34 81.71,59.98 v1(81.67,59.98)
  BOTTOM w0.183: UD6.C3 71.63,39.68 71.29,40.02 v1(71.17,40.02)
DDR_B_D27: length 32.2
  IN3 w0.076: v8(81.71,60.67) 81.71,60.54 82.04,60.21 82.04,59.7 80.06,57.72 79.88,57.72
  IN3 w0.132: 79.88,57.72 77.79,57.72 76.98,56.91 76.98,53.43 76.29,52.74 76.29,48.87 75.91,48.5 75.91,48.01 75.78,47.88 75.49,47.88 75.36,47.75 75.36,47.49 75.49,47.35 75.78,47.35 75.91,47.22 75.91,43.24 75.69,43.01 72.33,43.01 72.11,42.79 71.29,42.79 70.58,42.08 70.58,40.86 70.89,40.55 71.57,40.55 v1(72.03,40.09)
  BOTTOM w0.076: v8(81.71,60.67) 82.03,60.99 UCPU1.AP25
  BOTTOM w0.183: v1(72.03,40.09) 72.43,39.69 UD6.C2
DDR_B_D28: length 34.3
  IN3 w0.076: 82.07,58.67 82.34,58.94 82.34,60.35 82.24,60.45 82.24,62.67 v3(81.63,63.28)
  IN3 w0.132: 82.07,58.67 80.41,57.01 79.19,57.01 78.81,56.63 78.81,54.29 76.96,52.44 76.96,48.57 76.56,48.16 76.56,41.16 76.4,41.01 74.42,41.01 74.26,41.16 74.26,42.17 74.13,42.3 73.93,42.3 73.78,42.15 73.78,41.52 73.63,41.36 73.45,41.36 73.3,41.52 73.3,42.16 73.15,42.31 72.67,42.31 72.13,41.77 v1(72.04,41.77)
  BOTTOM w0.076: UCPU1.AK26 81.28,63.59 81.63,63.23 v3(81.63,63.28)
  BOTTOM w0.183: v1(72.04,41.77) 72.43,41.38 UD6.A2
DDR_B_D29: length 36.9
  IN3 w0.076: v1(80.74,62.6) 80.36,62.98 80.36,63.74 79.8,64.3 76.58,64.3 76.47,64.4 76.09,64.4 75.89,64.2
  IN3 w0.132: v1(68.03,40.08) 67.77,40.08 67.22,40.63 67.22,42.6 70.05,45.43 71.09,45.43 71.51,45.85 71.51,47.64 72.77,48.9 72.77,53.99 73.5,54.72 73.5,59.32 74.11,59.93 74.11,63.65 74.43,63.97 75.66,63.97 75.89,64.2
  BOTTOM w0.076: v1(80.74,62.6) 80.74,62.65 81.1,62.29 UCPU1.AM26
  BOTTOM w0.183: UD6.C8 67.63,39.69 v1(68.03,40.08)
DDR_B_D30: length 38.8
  IN3 w0.076: v1(81.58,63.94) 81.02,64.5 76.63,64.5 76.55,64.58 75.56,64.58
  IN3 w0.132: v1(68.03,39.26) 67.96,39.26 66.9,40.32 66.9,42.74 69.95,45.78 70.66,45.78 71.19,46.32 71.19,47.77 72.45,49.03 72.45,60.31 72.56,60.43 72.56,61.63 73.32,62.4 73.32,62.95 72.99,63.28 72.99,63.94 73.17,64.12 74.24,64.12 74.7,64.58 75.56,64.58
  BOTTOM w0.076: UCPU1.AK25 81.94,63.59 v1(81.58,63.94)
  BOTTOM w0.183: UD6.D7 68.42,38.87 v1(68.03,39.26)
DDR_B_D31: length 34.9
  IN3 w0.076: 80.21,57.37 80.31,57.37 82.19,59.25 82.19,60.29 82.09,60.39 82.09,62.22 v1(81.63,62.67)
  IN3 w0.132: v8(71.09,41.67) 71.24,41.83 71.24,42.18 71.5,42.43 72.26,42.43 72.46,42.63 74.5,42.63 74.63,42.5 74.63,41.67 74.78,41.52 75.01,41.52 75.16,41.67 75.16,42.5 75.29,42.63 75.58,42.63 75.74,42.48 75.74,41.61 75.88,41.47 76.09,41.47 76.23,41.61 76.23,48.3 76.63,48.69 76.63,52.62 77.97,53.96 77.97,57.01 78.33,57.37 80.21,57.37
  BOTTOM w0.076: v1(81.63,62.67) 81.89,62.94 UCPU1.AL25
  BOTTOM w0.183: UD6.A3 71.23,41.67 v8(71.09,41.67)
DDR_B_D32: length 29.2
  IN4 w0.132: v1(91.87,36.06) 92.6,36.06 92.78,36.23 92.78,36.87 92.6,37.05 90.22,37.05 90.05,37.22 90.05,41.41 81.88,49.57 81.88,53.96 v8(82.75,54.83)
  BOTTOM w0.076: UCPU1.AY23 83.18,57.03 83.18,55.05 82.96,54.83 v8(82.75,54.83)
  BOTTOM w0.183: v1(91.87,36.06) 91.87,36.05 92.26,35.67 UD9.H8
DDR_B_D33: length 30.5
  IN4 w0.076: v1(82.75,55.44) 83.2,54.99 83.2,53.28 83.06,53.13 83.06,53.09
  IN4 w0.132: v8(93.6,37.6) 92.73,37.6 92.15,38.19 92.15,40.09 92.02,40.22 91.56,40.22 91.38,40.4 91.38,40.68 91.56,40.86 92.02,40.86 92.15,40.98 92.15,41.36 92.02,41.49 91.69,41.49 91.51,41.67 91.51,41.95 91.69,42.13 92.02,42.13 92.15,42.25 92.15,42.63 91.99,42.79 89.58,42.79 82.52,49.84 82.52,52.56 83.06,53.09
  BOTTOM w0.076: UCPU1.AW23 82.98,57.63 82.72,57.36 82.72,57.12 83.03,56.8 83.03,55.64 82.83,55.44 v1(82.75,55.44)
  BOTTOM w0.183: UD9.F7 93.13,37.27 93.49,37.63 93.56,37.63 93.6,37.58 v8(93.6,37.6)
DDR_B_D34: length 31.8
  IN4 w0.076: v8(84.81,54.48) 84.82,54.47 84.93,54.47 85.19,54.22 85.19,53.69 84.95,53.46 84.95,53.08
  IN4 w0.132: v3(95.61,36.14) 96.22,36.75 96.22,37.92 96.49,38.19 96.49,39.18 96.92,39.61 97.68,39.61 97.93,39.85 97.93,41.96 95.14,44.75 91.6,44.75 86.38,49.97 85.87,49.97 84.95,50.9 84.95,53.08
  BOTTOM w0.076: UCPU1.AY21 84.4,57.16 84.4,56.99 84.62,56.76 84.62,56.15 84.41,55.94 84.41,54.88 v8(84.81,54.48)
  BOTTOM w0.183: UD9.H3 95.81,36.13 95.61,36.13 v3(95.61,36.14)
DDR_B_D35: length 32
  IN4 w0.076: 86.54,53.19 86.54,53.21 86.77,53.44 86.77,53.72 86.4,54.1 85.71,54.1 85.49,54.32 85.49,55.08 84.88,55.69 84.82,55.69 84.8,55.71 v1(84.8,55.73)
  IN4 w0.132: v1(96.68,36.88) 96.69,36.88 96.69,36.89 96.65,36.89 96.67,36.87 96.67,36.85 97.25,37.42 97.25,37.6 99.28,39.64 99.28,41.55 95.39,45.44 91.9,45.44 86.3,51.04 86.3,52.95 86.54,53.19
  BOTTOM w0.076: UCPU1.AW21 84.33,57.81 84.6,57.54 84.6,57 84.83,56.77 84.83,55.72 84.8,55.69 v1(84.8,55.73)
  BOTTOM w0.183: UD9.G2 97.07,36.49 96.69,36.87 96.69,36.88 v1(96.68,36.88)
DDR_B_D36: length 30.9
  IN4 w0.076: v1(82.66,56.05) 82.77,56.05 83.49,55.33 83.49,53.23 83.41,53.14 83.41,53.05
  IN4 w0.132: 83.41,53.05 82.85,52.49 82.85,50.02 89.72,43.14 92.76,43.14 94.11,41.78 94.11,36.72 93.6,36.21 v8(93.6,36.21)
  BOTTOM w0.076: UCPU1.AV23 82.98,58.31 82.65,57.98 82.65,57.51 82.54,57.4 82.54,57.07 82.87,56.74 82.87,56.2 82.72,56.05 82.67,56.05 v1(82.66,56.05)
  BOTTOM w0.183: v8(93.6,36.21) 93.59,36.21 93.59,36.19 UD9.H7
DDR_B_D37: length 31.7
  IN4 w0.132: v8(91.88,37.67) 91.88,37.6 91.7,37.43 90.55,37.43 90.37,37.6 90.37,38 90.55,38.17 91.59,38.17 91.76,38.35 91.76,39.46 91.64,39.59 91.13,39.59 91,39.46 91,39.26 90.82,39.08 90.55,39.08 90.37,39.26 90.37,42.25 90.24,42.38 89.53,42.38 82.2,49.71 82.2,53.68 v1(82.74,54.22)
  BOTTOM w0.076: UCPU1.AU23 82.98,58.93 83.27,58.65 83.27,58.43 83.22,58.39 83.22,58.01 83.26,57.98 83.26,57.77 83.21,57.73 83.21,57.38 83.25,57.34 83.25,57.25 83.33,57.16 83.33,54.62 82.93,54.22 v1(82.74,54.22)
  BOTTOM w0.183: UD9.F8 92.27,37.28 v8(91.88,37.67)
DDR_B_D38: length 30.7
  IN4 w0.076: v1(84.81,55.1) 84.82,55.09 84.82,55.02 85.34,54.5 85.34,53.25 85.44,53.15 85.44,52.16
  IN4 w0.132: 85.44,52.16 85.44,51.45 91.8,45.08 95.29,45.08 98.25,42.13 98.25,39.71 97.81,39.27 97.1,39.27 96.95,39.11 96.95,37.92 96.69,37.66 v8(96.69,37.67)
  BOTTOM w0.076: v1(84.81,55.1) 84.81,55.08 85.17,55.45 85.17,55.89 85.01,56.06 85.01,56.81 84.75,57.06 84.75,57.61 84.68,57.68 84.68,58.07 UCPU1.AV21
  BOTTOM w0.183: UD9.F2 97.07,37.28 96.69,37.66 v8(96.69,37.67)
DDR_B_D39: length 32.2
  IN4 w0.132: v1(95.78,38.62) 95.38,39.02 95.38,41.98 95.65,42.25 96.16,42.25 96.34,42.43 96.34,42.71 96.16,42.89 95.5,42.89 95.38,43.01 95.38,44.06 95.02,44.41 90.25,44.41 85.72,48.94 85.72,49.67 84.63,50.76 84.63,53.37 84.65,53.39 84.65,53.65 84.79,53.79 v8(84.79,53.85)
  BOTTOM w0.076: v8(84.79,53.85) 84.79,53.88 84.61,54.06 83.66,54.06 83.48,54.24 83.48,57.23 83.4,57.31 83.4,57.4 83.36,57.44 83.36,57.66 83.41,57.71 83.41,58.04 83.37,58.08 83.37,58.33 83.42,58.37 83.42,58.73 83.38,58.77 83.38,58.99 83.57,59.18 UCPU1.AU21
  BOTTOM w0.183: UD9.E3 95.78,38.56 v1(95.78,38.62)
DDR_B_D40: length 28.1
  IN3 w0.076: v1(85.85,55.71) 86.02,55.71 86.42,55.32 86.42,54.51 87.1,53.82 87.1,53.77 87.24,53.63 87.24,53.41 87.52,53.12 87.52,52.16
  IN3 w0.132: 87.52,52.16 87.52,51.22 87.39,51.09 86.41,51.09 86.25,50.94 86.25,50.71 86.41,50.56 87.39,50.56 87.52,50.43 87.52,50.17 87.39,50.03 86.41,50.03 86.25,49.88 86.25,49.66 86.41,49.5 87.39,49.5 87.52,49.37 87.52,49.11 87.39,48.98 86.43,48.98 86.28,48.82 86.28,48.6 86.43,48.45 87.39,48.45 87.52,48.32 87.52,48.05 87.39,47.92 86.43,47.92 86.28,47.77 86.28,47.54 86.43,47.39 87.39,47.39 87.52,47.26 87.52,46.71 92.41,41.82 v8(92.7,41.82)
  BOTTOM w0.076: v1(85.85,55.71) 85.78,55.79 85.78,56.01 85.52,56.26 85.52,57.12 UCPU1.AY19
  BOTTOM w0.183: UD9.A7 92.7,41.64 v8(92.7,41.82)
DDR_B_D41: length 28.9
  IN3 w0.076: 86.05,52.16 86.43,52.54 86.43,52.87 86.93,53.37 86.93,53.78 86.27,54.45 86.27,54.81 85.97,55.11 v8(85.87,55.11)
  IN3 w0.132: 86.05,52.16 85.93,52.04 85.93,47.28 86.2,47 86.77,47 88.22,45.55 88.22,45.37 87.7,44.85 87.7,44.66 87.89,44.48 88.08,44.48 88.59,44.99 88.78,44.99 88.97,44.8 88.97,44.62 88.45,44.1 88.45,43.92 88.64,43.73 88.83,43.73 89.34,44.24 89.53,44.24 89.71,44.06 89.71,43.87 89.2,43.35 89.2,43.17 89.39,42.98 89.57,42.98 90.09,43.5 90.28,43.5 90.46,43.31 90.46,43.12 89.95,42.61 89.95,42.42 90.13,42.23 90.32,42.23 90.84,42.75 91.02,42.75 92.21,41.57 92.21,41.32 92.65,40.88 v1(92.68,40.88)
  BOTTOM w0.076: UCPU1.AW19 85.41,57.62 85.69,57.34 85.69,56.3 85.91,56.09 86,56.09 86.23,55.86 86.23,55.46 v8(85.87,55.11)
  BOTTOM w0.183: v1(92.68,40.88) 92.68,40.88 92.27,40.48 UD9.B8
DDR_B_D42: length 27.5
  IN3 w0.132: v8(87.85,54.65) 89.63,52.87 89.63,52.16 90.74,51.05 90.74,50.37 91.61,49.49 91.61,49.24 91.49,49.11 89.96,49.11 89.81,48.96 89.81,48.73 89.96,48.58 92.2,48.58 92.34,48.44 92.34,48.22 92.21,48.08 91.79,48.08 91.64,47.93 91.64,47.71 91.79,47.55 92.21,47.55 92.34,47.42 92.34,47.16 92.21,47.03 91.89,47.03 91.74,46.87 91.74,46.65 91.89,46.5 92.21,46.5 92.34,46.37 92.34,45.92 95.35,42.9 95.35,41.41 v1(96.67,40.09)
  BOTTOM w0.076: v8(87.85,54.65) 87.33,55.17 87.33,56.15 86.99,56.49 86.99,56.84 86.76,57.07 UCPU1.AY17
  BOTTOM w0.183: UD9.C2 97.07,39.69 v1(96.67,40.09)
DDR_B_D43: length 27.8
  IN3 w0.132: v1(87.85,55.26) 88.31,54.8 88.31,54.7 89.96,53.05 89.96,52.28 91.06,51.18 91.06,50.5 92.66,48.9 92.66,46.08 95.9,42.84 99.46,42.84 99.61,42.69 99.61,42.43 99.46,42.28 96.08,42.28 95.88,42.08 v8(95.88,41.67)
  BOTTOM w0.076: UCPU1.AW17 86.76,57.64 87.04,57.37 87.04,57.04 87.14,56.93 87.14,56.55 87.48,56.22 87.48,55.5 87.73,55.26 v1(87.85,55.26)
  BOTTOM w0.183: UD9.A3 96.27,41.28 v8(95.88,41.67)
DDR_B_D44: length 29.2
  IN3 w0.076: v1(85.87,54.5) 86,54.5 86.78,53.72 86.78,53.44 86.08,52.74 86.08,52.67
  IN3 w0.132: 86.08,52.67 85.61,52.2 85.61,46.23 85.91,45.92 86.1,45.92 86.63,46.46 86.82,46.46 87.01,46.27 87.01,46.09 86.47,45.55 86.47,45.36 86.66,45.18 86.84,45.18 87.38,45.71 87.57,45.71 87.75,45.53 87.75,45.41 87.22,44.87 87.22,44.62 90.01,41.82 90.47,41.82 90.8,42.16 91.16,42.16 91.65,41.66 91.65,39.92 91.89,39.69 92.4,39.69 92.67,39.95 v1(92.67,40.08)
  BOTTOM w0.076: v1(85.87,54.5) 85.9,54.5 85.48,54.91 85.48,56.06 85.34,56.21 85.34,56.91 85.06,57.19 85.06,58.18 85.41,58.53 UCPU1.AV19
  BOTTOM w0.183: UD9.C8 92.27,39.69 v1(92.67,40.08)
DDR_B_D45: length 30.1
  IN3 w0.132: v8(92.67,39.26) 91.13,39.26 89.99,40.4 89.99,41.39 89.09,42.29 88.9,42.29 88.65,42.03 88.46,42.03 88.27,42.22 88.27,42.4 88.53,42.66 88.53,42.85 88.34,43.03 88.16,43.03 87.9,42.78 87.71,42.78 87.52,42.96 87.52,43.15 87.78,43.41 87.78,43.59 87.6,43.78 87.41,43.78 87.15,43.52 86.96,43.52 86.78,43.71 86.78,43.9 87.03,44.15 87.03,44.34 86.85,44.53 86.66,44.53 86.4,44.27 86.22,44.27 86.03,44.46 86.03,44.64 86.29,44.9 86.29,45.09 86.1,45.28 85.91,45.28 85.66,45.02 85.47,45.02 85.28,45.2 85.28,45.39 85.54,45.65 85.54,45.84 85.19,46.19 85.19,52.34 85.76,52.91 85.76,53.54 v1(85.74,53.56)
  BOTTOM w0.076: v1(85.74,53.56) 85.74,54.08 85.33,54.49 85.33,55.99 85.16,56.16 85.16,56.87 84.91,57.12 84.91,58.38 85.52,58.99 UCPU1.AU19
  BOTTOM w0.183: v8(92.67,39.26) 93.05,38.87 UD9.D7
DDR_B_D46: length 28.7
  IN3 w0.132: v1(96.97,41.82) 97.31,41.49 100.02,41.49 100.17,41.64 100.17,43.01 100.02,43.17 96.11,43.17 92.98,46.29 92.98,49.03 91.38,50.63 91.38,51.45 90.29,52.54 90.29,53.2 88.64,54.85 88.64,55.08 v1(87.85,55.87)
  BOTTOM w0.076: v1(87.85,55.87) 87.63,56.09 87.63,56.28 87.29,56.62 87.29,57 87.19,57.1 87.19,57.43 87.09,57.53 87.09,58.15 86.76,58.48 UCPU1.AV17
  BOTTOM w0.183: UD9.A2 97.07,41.72 v1(96.97,41.82)
DDR_B_D47: length 29.5
  IN3 w0.132: v8(95.85,40.09) 95.83,40.09 95.02,40.9 95.02,42.78 91.19,46.6 91.19,46.79 91.49,47.09 91.49,47.28 91.31,47.46 91.12,47.46 90.82,47.16 90.63,47.16 90.45,47.35 90.45,47.54 90.74,47.84 90.74,48.02 90.56,48.21 90.37,48.21 90.07,47.91 89.89,47.91 89.15,48.65 89.15,49.01 89.25,49.11 89.46,49.11 89.61,49.25 89.61,49.45 89.46,49.59 88.89,49.59 88.76,49.72 88.76,49.97 88.92,50.13 89.38,50.13 89.53,50.28 89.53,51.8 89.3,52.03 89.3,52.79 88.06,54.04 v1(87.83,54.04)
  BOTTOM w0.076: UCPU1.AU17 86.6,59.02 86.3,59.02 86.2,59.12 85.97,59.12 85.8,58.94 85.8,57.45 85.85,57.4 85.85,56.37 85.97,56.24 86.06,56.24 86.38,55.92 86.38,54.39 86.74,54.04 v1(87.83,54.04)
  BOTTOM w0.183: v8(95.85,40.09) 96.27,39.67 UD9.C3
DDR_B_D48: length 41.8
  IN3 w0.076: 89,59.27 88.82,59.09 88.13,59.09 88.06,59.17 87.35,59.17 87.26,59.08 85.3,59.08 84.46,59.92 v1(84.46,59.93)
  IN3 w0.132: v8(107.39,38.47) 108.17,39.26 109.11,39.26 110.28,40.42 110.28,41.16 109.06,42.38 106.9,42.38 103.36,45.93 99.88,45.93 96.31,49.49 96.31,51.73 93.4,54.64 93.4,56.26 91.97,57.7 91.54,57.7 89.91,59.32 89.05,59.32 89,59.27
  BOTTOM w0.076: v1(84.46,59.93) 84.87,60.34 UCPU1.AR21
  BOTTOM w0.183: v8(107.39,38.47) 107.79,38.07 UD10.E3
DDR_B_D49: length 42.8
  IN3 w0.076: v1(83.52,60.65) 83.52,60.65 83.13,60.26 83.13,59.83 83.38,59.58 83.61,59.58 83.7,59.49
  IN3 w0.132: 83.7,59.49 85.24,57.95 88.77,57.95 89.02,57.7 89.68,57.7 90.85,56.53 91.41,56.53 92.07,55.87 92.07,52.79 94.43,50.43 94.43,47.64 95.75,46.32 95.94,46.32 96.19,46.58 96.38,46.58 96.57,46.39 96.57,46.2 96.31,45.95 96.31,45.76 97.45,44.62 102.92,44.62 106.01,41.52 106.01,39.28 105.67,38.93 105.67,36.66 105.04,36.04 v8(105.04,36.04)
  BOTTOM w0.076: v1(83.52,60.65) 83.84,60.34 UCPU1.AR22
  BOTTOM w0.183: v8(105.04,36.04) 104.66,35.67 UD10.H7
DDR_B_D50: length 46.8
  IN3 w0.076: 88.75,60.02 88.37,60.02 88.25,59.9 87.85,59.9 87.3,60.44 86.87,60.44 86.48,60.06 85.72,60.06 85.52,60.26 85.21,60.26 84.86,60.62 84.86,62.12 84.4,62.57 v1(84.4,62.6)
  IN3 w0.132: 88.75,60.02 90.18,60.02 91.74,58.46 92.21,58.46 93.3,57.37 93.95,57.37 94.33,56.98 94.33,56.02 95.32,55.03 95.32,54.11 97.78,51.65 97.78,48.93 100.15,46.57 103.63,46.57 107.15,43.05 109.3,43.05 110.93,41.42 110.93,38.46 110.07,37.6 108.96,37.6 v8(108.22,36.87)
  BOTTOM w0.076: UCPU1.AL21 84.74,62.94 v1(84.4,62.6)
  BOTTOM w0.183: UD10.F2 108.62,37.27 v8(108.22,36.87)
DDR_B_D51: length 44.6
  IN3 w0.076: v8(83.52,62.6) 82.72,61.8 82.72,59.65 82.86,59.51
  IN3 w0.132: 82.86,59.51 85.09,57.28 88.59,57.28 89.43,56.45 89.43,55.69 91.07,54.05 91.07,52.88 93.76,50.18 93.76,46.6 95.77,44.59 96.02,44.59 96.18,44.76 96.37,44.76 96.55,44.58 96.55,44.4 96.36,44.21 96.36,44.08 96.47,43.97 102.61,43.97 103.71,42.87 103.71,42.68 103.52,42.5 103.52,42.31 103.71,42.12 103.89,42.12 104.08,42.31 104.27,42.31 104.76,41.82 104.76,38.2 104.63,38.08 104.63,37.18 104.68,37.13 104.68,36.53 v1(104.22,36.06)
  BOTTOM w0.076: v8(83.52,62.6) 83.54,62.6 83.54,62.58 83.5,62.58 83.49,62.57 83.5,62.57 83.51,62.58 83.81,62.29 UCPU1.AM22
  BOTTOM w0.183: UD10.H8 103.83,35.67 v1(104.22,36.06)
DDR_B_D52: length 43.5
  IN3 w0.076: 83.4,59.33 82.9,59.83 82.9,60.36 82.98,60.44 82.98,61.43 v1(83.51,61.96)
  IN3 w0.132: 83.4,59.33 85.11,57.62 88.72,57.62 89.76,56.58 89.76,56.4 90.01,56.15 91.33,56.15 91.76,55.71 91.76,54.83 91.39,54.45 91.39,53.01 94.09,50.32 94.09,47.5 94.32,47.27 94.32,47.08 94.13,46.9 94.13,46.72 94.32,46.53 94.51,46.53 94.69,46.71 94.88,46.71 95.06,46.52 95.06,46.34 94.88,46.15 94.88,45.97 95.07,45.78 95.26,45.78 95.44,45.96 95.62,45.96 95.81,45.78 95.81,45.59 95.63,45.41 95.63,45.22 95.82,45.03 96,45.03 96.18,45.22 96.37,45.22 97.29,44.29 102.77,44.29 105.08,41.98 105.08,37.68 v8(105.1,37.66)
  BOTTOM w0.076: UCPU1.AN22 83.84,61.64 v1(83.51,61.96)
  BOTTOM w0.183: v8(105.1,37.66) 104.71,37.27 UD10.F7
DDR_B_D53: length 46.4
  IN3 w0.076: 88.97,59.55 88.67,59.25 88.31,59.25 88.18,59.37 87.34,59.37 87.22,59.25 85.44,59.25 84.96,59.73 84.96,59.98 84.46,60.48 v1(84.46,60.67)
  IN3 w0.132: v8(107.18,35.83) 107.77,36.41 107.77,37.05 108.66,37.93 109.95,37.93 110.61,38.6 110.61,41.29 109.2,42.7 107.04,42.7 103.49,46.25 100.01,46.25 96.63,49.63 96.63,51.86 94.41,54.09 94.41,55.36 93.97,55.79 93.97,56.86 93.75,57.09 93.1,57.09 92.11,58.08 91.64,58.08 90.06,59.65 89.07,59.65 88.97,59.55
  BOTTOM w0.076: UCPU1.AP21 84.78,60.99 v1(84.46,60.67)
  BOTTOM w0.183: v8(107.18,35.83) 107.34,35.67 UD10.H3
DDR_B_D54: length 49.3
  IN3 w0.076: v1(85.34,63.16) 85.8,62.7 85.8,60.52 86.06,60.25 86.46,60.25 86.8,60.6 87.38,60.6 87.92,60.05 88.19,60.05 88.41,60.27 88.42,60.27
  IN3 w0.132: 88.42,60.27 88.54,60.39 90.27,60.39 91.79,58.86 92.49,58.86 93.06,58.29 93.83,58.29 95.8,56.32 95.8,54.09 98.19,51.7 98.19,48.98 100.28,46.89 103.76,46.89 107.28,43.37 109.44,43.37 111.26,41.55 111.26,36.85 109.98,35.57 108.74,35.57 v1(108.24,36.07)
  BOTTOM w0.076: v1(85.34,63.16) 85.24,63.16 84.87,63.52 UCPU1.AK21
  BOTTOM w0.183: v1(108.24,36.07) 108.63,36.46 UD10.G2
DDR_B_D55: length 45.2
  IN3 w0.076: 82.61,59.44 82.53,59.51 82.53,62.41 83.13,63 83.13,63.33 83.38,63.59 84.02,63.59 v1(84.37,63.23)
  IN3 w0.132: v8(103.45,36.87) 103.45,36.97 103.92,37.44 103.92,38.03 103.76,38.19 103.25,38.19 103.07,38.37 103.07,38.65 103.25,38.82 103.6,38.82 103.75,38.98 103.75,39.31 103.6,39.46 103.37,39.46 103.19,39.64 103.19,42.93 102.47,43.65 96.26,43.65 93.44,46.47 93.44,50.05 90.75,52.75 90.75,53.93 89.1,55.58 89.1,56.17 88.89,56.38 87.07,56.38 86.43,57.01 84.93,57.01 82.61,59.33 82.61,59.44
  BOTTOM w0.076: UCPU1.AK22 84.02,63.59 v1(84.37,63.23)
  BOTTOM w0.183: UD10.F8 103.83,37.25 v8(103.45,36.87)
DDR_B_D56: length 35.8
  IN4 w0.076: 85.16,59.37 84.98,59.55 84.98,61.58 85.34,61.94 v8(85.39,61.94)
  IN4 w0.132: 85.16,59.37 85.16,58.86 87.07,56.96 87.07,56.76 87.45,56.38 88.01,56.38 88.26,56.12 88.26,55.77 88.77,55.26 88.77,54.57 89.53,53.81 89.53,50.41 89.78,50.15 90.22,50.15 90.49,49.87 90.82,49.87 91,49.7 91,49.42 90.82,49.24 90.55,49.24 90.37,49.06 90.37,48.78 90.55,48.6 91.41,48.6 93.41,46.61 96.02,46.61 96.7,45.93 97.23,45.93 99.89,43.27 102.54,43.27 103.74,42.07 103.74,41.38 v1(104.24,40.88)
  BOTTOM w0.076: v8(85.39,61.94) 85.39,61.96 85.72,61.64 UCPU1.AN20
  BOTTOM w0.183: v1(104.24,40.88) 103.83,40.48 UD10.B8
DDR_B_D57: length 34.5
  IN4 w0.076: v1(85.35,60.67) 85.35,60.45 85.82,59.98 85.82,58.84 87.45,57.21 88.67,57.21 88.79,57.09
  IN4 w0.132: 88.79,57.09 89.58,56.3 89.58,55.26 90.75,54.09 90.75,52.96 90.92,52.79 91.33,52.79 91.51,52.62 91.51,52.34 91.33,52.16 90.93,52.16 90.75,51.98 90.75,51.7 90.93,51.52 91.33,51.52 91.51,51.35 91.51,51.07 91.33,50.89 90.88,50.89 90.75,50.76 90.75,50.38 90.88,50.25 91.13,50.25 91.33,50.05 91.33,49.14 93.53,46.94 96.25,46.94 96.94,46.25 97.36,46.25 99.99,43.62 102.66,43.62 104.24,42.04 v8(104.24,41.67)
  BOTTOM w0.076: UCPU1.AR20 85.72,60.34 85.39,60.67 v1(85.35,60.67)
  BOTTOM w0.183: UD10.A7 104.61,41.27 104.24,41.64 v8(104.24,41.67)
DDR_B_D58: length 36.1
  IN4 w0.132: v3(86.28,63.89) 86.3,63.89 87.17,63.03 87.17,61.78 87.44,61.5 88.08,61.5 89.64,59.94 90.2,59.94 93.05,57.1 93.81,57.1 94.18,56.73 94.18,55.51 94.38,55.31 94.38,52.08 95.81,50.65 95.96,50.65 96.59,50.02 96.59,49.36 96.7,49.26 97.8,49.26 101.01,46.04 103.37,46.04 107.25,42.17 107.78,42.17 v1(108.25,41.69)
  BOTTOM w0.076: v3(86.28,63.89) 86.58,63.59 UCPU1.AK18
  BOTTOM w0.183: UD10.A2 108.63,41.31 v1(108.25,41.69)
DDR_B_D59: length 35.7
  IN4 w0.076: 87.88,60.09 86.83,61.15 86.83,62.91 86.48,63.26 v1(86.29,63.26)
  IN4 w0.132: v8(107.44,41.67) 107.29,41.67 103.24,45.72 100.88,45.72 97.66,48.93 96.39,48.93 96.21,49.11 96.21,49.95 95.83,50.33 94.23,50.33 93.92,50.63 93.92,53.81 93.37,54.36 93.37,56.19 90.05,59.51 89.29,59.51 88.74,60.06 87.92,60.06 87.88,60.09
  BOTTOM w0.076: v1(86.29,63.26) 86.61,62.94 UCPU1.AL18
  BOTTOM w0.183: UD10.A3 107.83,41.28 v8(107.44,41.67)
DDR_B_D60: length 39.3
  IN4 w0.132: v1(104.22,39.26) 103.07,40.41 103.07,41.79 102.3,42.56 98.89,42.56 95.55,45.9 92.08,45.9 89.1,48.89 89.09,48.89 87.66,50.32 87.66,52.95 87.12,53.49 87.12,53.86 86.76,54.22 86.66,54.22 86.28,54.6 86.28,55.92 85.82,56.38 85.82,57.06 83.97,58.92 83.97,63.41 84.25,63.69 85.2,63.69 v8(85.35,63.84)
  BOTTOM w0.076: UCPU1.AK20 85.61,63.59 v8(85.35,63.84)
  BOTTOM w0.183: v1(104.22,39.26) 104.61,38.87 UD10.D7
DDR_B_D61: length 36.3
  IN4 w0.076: 84.83,59.27 84.83,62.04 85.34,62.55 v1(85.39,62.55)
  IN4 w0.132: 84.83,59.27 84.83,58.64 86.71,56.76 86.71,56.6 87.42,55.89 87.42,53.81 88.01,53.23 88.01,50.44 92.17,46.27 95.83,46.27 96.6,45.5 97.15,45.5 98.65,44.01 98.65,43.42 99.16,42.91 102.42,42.91 103.4,41.93 103.4,40.9 v8(104.22,40.08)
  BOTTOM w0.076: v1(85.39,62.55) 85.65,62.29 UCPU1.AM20
  BOTTOM w0.183: v8(104.22,40.08) 104.21,40.08 104.21,40.05 UD10.C8
DDR_B_D62: length 33
  IN4 w0.076: 88.21,58.92 88.06,59.07 87.98,59.07 87.19,59.85 v8(87.19,60.02)
  IN4 w0.132: 88.21,58.92 88.49,58.64 89.94,58.64 92.69,55.88 92.69,54.13 93.28,53.54 93.28,50.28 95.33,48.23 97.45,48.23 100.61,45.08 102.97,45.08 106.01,42.03 106.01,41.44 v1(107.36,40.09)
  BOTTOM w0.076: v8(87.19,60.02) 87.18,60.03 87.18,60.07 86.91,60.34 UCPU1.AR18
  BOTTOM w0.183: UD10.C3 107.79,39.67 v1(107.36,40.09)
DDR_B_D63: length 35
  IN4 w0.076: v1(86.34,60.69) 86.37,60.67 87.08,60.67 87.58,60.18 87.58,59.77 88.1,59.25 88.39,59.25 88.49,59.14
  IN4 w0.132: v8(108.23,40.09) 108.12,40.09 106.34,41.87 106.34,42.16 103.1,45.4 100.74,45.4 97.58,48.56 95.45,48.56 93.6,50.41 93.6,53.68 93.03,54.24 93.03,56.07 90.06,59.04 88.59,59.04 88.49,59.14
  BOTTOM w0.076: v1(86.34,60.69) 86.64,60.99 UCPU1.AP18
  BOTTOM w0.183: UD10.C2 108.63,39.69 v8(108.23,40.09)
DDR_B_DQS0: length 30.4
  IN4 w0.076: v1(78.4,55.42) 78.74,55.42 78.79,55.36 78.79,55.21 78.77,55.19 78.77,54.6 78.71,54.55 78.71,53.59 78.96,53.35 78.96,52.26 78.87,52.18 78.87,52.16
  IN4 w0.165: 78.87,52.16 78.87,48.29 79.73,47.43 79.73,47.2 79.28,46.75 79.28,46.25 79.7,45.83 80.2,45.83 80.65,46.28 80.89,46.28 81.12,46.05 81.12,45.81 80.67,45.36 80.67,44.87 81.09,44.45 81.58,44.45 82.04,44.9 82.27,44.9 82.73,44.43 82.73,44.14 81.88,43.29 81.88,38.27 82.36,37.79 82.36,37.17 82.2,37.01 82.02,37.01 v8(81.88,37.15)
  BOTTOM w0.076: v1(78.4,55.42) 78.4,55.47 78.92,55.99 78.92,56.41 79.01,56.5 79.01,56.91 78.91,57.01 78.91,57.32 78.96,57.37 78.96,57.75 78.91,57.8 78.91,57.98 78.96,58.03 78.96,58.25 78.82,58.39 78.52,58.69 UCPU1.AV30
  BOTTOM w0.216: UD7.F3 82.94,37.01 82.02,37.01 v8(81.88,37.15)
DDR_B_DQS1: length 30.6
  IN3 w0.076: 80.09,52.16 80.09,52.18 80.17,52.26 80.17,52.59 80.89,53.3 80.89,55.55 81.08,55.74 81.25,55.74 81.43,55.92 v1(81.43,55.94)
  IN3 w0.165: 80.09,52.16 80.09,46.57 80.44,46.21 82.85,46.21 83,46.06 83,45.71 82.85,45.55 80.44,45.55 80.09,45.2 80.09,44.47 80.44,44.12 82.04,44.12 82.19,43.97 82.19,43.46 82.04,43.31 80.59,43.31 80.14,42.86 80.14,40.13 80.41,39.87 80.84,39.87 v1(80.94,39.76)
  BOTTOM w0.076: UCPU1.AW26 80.84,58.31 80.84,58.46 80.92,58.53 81,58.53 81.27,58.26 81.27,58.12 81.2,58.04 81.2,57.71 81.27,57.63 81.27,57.46 81.19,57.38 81.19,57.03 81.46,56.76 81.46,55.97 v1(81.43,55.94)
  BOTTOM w0.216: v1(80.94,39.76) 80.83,39.88 80.2,39.88 UD7.C7
DDR_B_DQS2: length 34.3
  IN4 w0.076: v1(79.78,61.94) 79.78,61.9 79.55,61.67 79.32,61.67 79.14,61.49 79.14,60.1 78.49,59.45 76.03,59.45 75.8,59.22 75.44,59.22 75.18,58.96 75.18,58.73 75.11,58.66 75.11,58.64
  IN4 w0.165: v1(70.33,37.38) 70.52,37.19 70.72,37.19 70.79,37.26 70.79,37.69 70.29,38.19 70.29,41.99 72.01,43.71 73.68,43.71 74.2,44.24 74.2,51.7 74.58,52.08 74.58,52.69 74.99,53.09 74.99,54.55 75.11,54.67 75.11,58.64
  BOTTOM w0.076: UCPU1.AM28 80.13,62.29 v1(79.78,61.94)
  BOTTOM w0.216: UD6.F3 71.63,37.24 71.46,37.06 71.12,37.06 70.89,37.29 70.42,37.29 v1(70.33,37.38)
DDR_B_DQS3: length 34.9
  IN3 w0.076: 75.13,58.1 75.13,58.12 75.21,58.21 75.21,58.63 76,59.43 76.64,59.43 76.97,59.1 80.5,59.1 81.14,59.74 81.14,61.78 81.27,61.91 81.58,61.91 v8(81.68,62.01)
  IN3 w0.165: 75.13,58.1 75.13,53.29 74.62,52.79 74.62,48.89 74.18,48.45 74.18,44.54 73.94,44.3 72,44.3 71.67,43.97 70.63,43.97 68.54,41.88 68.54,40.18 68.87,39.85 69.26,39.85 69.27,39.86 v1(69.36,39.76)
  BOTTOM w0.076: v8(81.68,62.01) 81.85,62.01 UCPU1.AM25
  BOTTOM w0.216: UD6.C7 68.66,39.89 69.23,39.89 v1(69.36,39.76)
DDR_B_DQS4: length 32.3
  IN4 w0.076: v1(83.87,55.18) 83.96,55.28 84.15,55.28 84.24,55.18 84.24,54.36 83.68,53.8 83.68,53.34 83.95,53.08 83.95,53.01 83.88,52.94 83.88,52.92
  IN4 w0.165: v8(94.87,37.12) 94.96,37.03 95.19,37.03 95.38,37.22 95.38,37.91 94.59,38.7 94.59,42.11 93.09,43.61 89.96,43.61 83.31,50.27 83.31,52.18 83.88,52.75 83.88,52.92
  BOTTOM w0.076: UCPU1.AV22 83.96,58.55 83.96,58.42 84.09,58.28 84.09,58 84.04,57.95 84.04,57.79 84.11,57.72 84.11,57.39 84.04,57.32 84.04,57.08 84.42,56.7 84.42,56.23 84.25,56.06 84.25,55.59 83.87,55.21 v1(83.87,55.18)
  BOTTOM w0.216: UD9.F3 96.05,37.05 94.95,37.05 v8(94.87,37.12)
DDR_B_DQS5: length 30.2
  IN3 w0.076: v8(86.79,55.89) 86.79,55.74 86.89,55.64 86.96,55.64 87.07,55.54 87.24,55.54 87.45,55.33 87.45,53.87 88.03,53.29 88.03,52.82 88.23,52.62 88.23,52.26 88.31,52.18 88.31,52.16
  IN3 w0.165: 88.31,52.16 88.31,48.83 88.79,48.35 88.79,47.85 88.37,47.42 88.37,47.19 88.6,46.96 88.83,46.96 89.26,47.38 89.76,47.38 90.18,46.96 90.18,46.47 89.75,46.04 89.75,45.81 89.99,45.57 90.22,45.57 90.65,46 91.14,46 91.56,45.58 91.56,45.08 91.14,44.66 91.14,44.42 91.37,44.19 91.6,44.19 92.03,44.62 92.53,44.62 92.95,44.2 92.95,43.7 92.52,43.27 92.52,43.04 92.75,42.8 92.99,42.8 93.41,43.23 93.91,43.23 94.48,42.66 94.48,40.24 94.21,39.97 93.77,39.97 93.63,39.82 v1(93.63,39.72)
  BOTTOM w0.076: UCPU1.AW18 86.22,58.07 86.22,57.82 86.38,57.66 86.38,57.45 86.31,57.38 86.31,57.08 86.68,56.7 86.68,56.36 86.89,56.16 86.89,55.99 v8(86.79,55.89)
  BOTTOM w0.216: v1(93.63,39.72) 93.57,39.72 93.6,39.74 93.62,39.74 93.48,39.88 93.29,39.88 UD9.C7
DDR_B_DQS6: length 45.2
  IN3 w0.076: 89.21,58.41 89.19,58.41 89.11,58.49 88.24,58.49 88.03,58.28 85.34,58.28 83.89,59.73 83.89,61.45 84.05,61.61 84.2,61.61 84.4,61.81 v1(84.4,61.99)
  IN3 w0.165: v8(106.52,37.15) 106.71,36.96 106.85,36.96 106.99,37.1 106.99,37.52 106.5,38.01 106.5,41.69 104.94,43.24 103.83,44.35 103.1,45.08 98.03,45.08 97.25,45.86 97.25,46.5 97.44,46.69 97.44,47.21 96.98,47.68 96.58,47.68 96.1,47.19 95.56,47.19 94.94,47.81 94.94,51.8 92.55,54.19 92.55,56.05 91.59,57.01 91.1,57.01 89.7,58.41 89.21,58.41
  BOTTOM w0.076: UCPU1.AM21 84.77,62.29 84.47,61.99 v1(84.4,61.99)
  BOTTOM w0.216: v8(106.52,37.15) 106.69,36.98 107.54,36.98 UD10.F3
DDR_B_DQS7: length 36.6
  IN4 w0.076: v1(86.35,62.01) 86.23,61.89 86.18,61.84 85.97,61.84 85.77,61.63 85.77,60.41 86.02,60.16 86.02,59.17 87.32,57.87 88.59,57.87 88.95,57.52 89.79,57.52 89.86,57.45
  IN4 w0.165: 89.86,57.45 90.02,57.45 91.78,55.69 91.78,53.64 92.49,52.93 92.49,49.94 94.97,47.45 96.79,47.45 97.36,46.89 97.48,46.89 100.16,44.21 102.73,44.21 104.76,42.18 104.76,40.18 105.07,39.87 105.46,39.87 v1(105.56,39.76)
  BOTTOM w0.076: v1(86.35,62.01) 86.63,62.29 UCPU1.AM18
  BOTTOM w0.216: v1(105.56,39.76) 105.42,39.9 104.86,39.9 UD10.C7
DDR_B_DQS#0: length 30.4
  IN4 w0.076: 79.19,52.16 79.19,52.18 79.11,52.26 79.11,53.41 78.86,53.66 78.86,54.48 78.92,54.54 78.92,55.12 78.95,55.15 78.95,55.43 78.4,55.97 v8(78.4,56.02)
  IN4 w0.165: 79.19,52.16 79.19,48.43 80.05,47.56 80.05,47.07 79.6,46.62 79.6,46.38 79.84,46.15 80.07,46.15 80.52,46.6 81.02,46.6 81.44,46.18 81.44,45.68 80.98,45.23 80.98,45 81.22,44.76 81.45,44.76 81.9,45.22 82.4,45.22 83.05,44.56 83.05,44.01 82.2,43.15 82.2,38.4 82.68,37.92 82.68,37.04 82.33,36.69 82.06,36.69 v1(81.88,36.51)
  BOTTOM w0.076: v8(78.4,56.02) 78.46,55.97 78.68,55.97 78.77,56.06 78.77,56.48 78.86,56.57 78.86,56.84 78.76,56.95 78.76,57.38 78.81,57.43 78.81,57.68 78.8,57.69 78.76,57.73 78.76,58.04 78.81,58.09 78.81,58.19 78.69,58.31 78.63,58.31 UCPU1.AW30
  BOTTOM w0.216: UD7.G3 83.04,36.62 81.99,36.62 v1(81.88,36.51)
DDR_B_DQS#1: length 30.8
  IN3 w0.076: v1(81.44,55.33) 81.44,55.45 81.3,55.59 81.15,55.59 81.05,55.49 81.05,53.24 80.33,52.52 80.33,52.26 80.41,52.18 80.41,52.16
  IN3 w0.165: v8(80.94,40.4) 80.73,40.18 80.54,40.18 80.46,40.26 80.46,42.73 80.73,42.99 82.17,42.99 82.51,43.33 82.51,44.1 82.17,44.44 80.57,44.44 80.41,44.6 80.41,45.07 80.58,45.24 82.98,45.24 83.32,45.57 83.32,46.19 82.98,46.53 80.58,46.53 80.41,46.7 80.41,52.16
  BOTTOM w0.076: UCPU1.AV26 80.9,58.85 81.08,58.67 81.43,58.33 81.43,58.05 81.35,57.98 81.35,57.77 81.42,57.7 81.42,57.4 81.35,57.32 81.35,57.09 81.61,56.83 81.61,56.29 81.81,56.1 81.81,55.7 v1(81.44,55.33)
  BOTTOM w0.216: UD7.B7 80.19,40.27 80.81,40.27 v8(80.94,40.4)
DDR_B_DQS#2: length 34.5
  IN4 w0.076: v1(79.78,61.33) 79.59,61.52 79.38,61.52 79.29,61.43 79.29,60.03 78.56,59.3 76.09,59.3 75.86,59.07 75.51,59.07 75.34,58.9 75.34,58.73 75.41,58.66 75.41,58.64
  IN4 w0.165: 75.41,58.64 75.43,58.61 75.43,54.54 75.31,54.41 75.31,52.96 74.9,52.55 74.9,51.95 74.52,51.56 74.52,44.11 73.81,43.4 72.14,43.4 70.61,41.86 70.61,38.33 71.11,37.82 71.11,37.13 70.85,36.87 70.45,36.87 v1(70.33,36.74)
  BOTTOM w0.076: UCPU1.AN28 80.08,61.64 v1(79.78,61.33)
  BOTTOM w0.216: v1(70.33,36.74) 70.48,36.89 70.73,36.89 70.96,36.67 71.41,36.67 71.6,36.47 UD6.G3
DDR_B_DQS#3: length 35
  IN3 w0.076: 75.45,58.1 75.45,58.12 75.36,58.21 75.36,58.57 76.07,59.27 76.58,59.27 76.91,58.94 80.56,58.94 81.3,59.68 81.3,61.72 81.34,61.76 81.42,61.76 81.53,61.65 81.67,61.65 81.81,61.51 81.81,61.43 v1(81.68,61.3)
  IN3 w0.165: 75.45,58.1 75.45,53.16 74.94,52.65 74.94,48.76 74.5,48.32 74.5,44.41 74.07,43.98 72.13,43.98 71.8,43.65 70.76,43.65 68.85,41.74 68.85,40.31 69,40.17 69.13,40.17 69.14,40.17 v1(69.36,40.4)
  BOTTOM w0.076: v1(81.68,61.3) 81.6,61.38 81.6,61.56 81.69,61.65 81.83,61.65 81.9,61.71 82.05,61.71 UCPU1.AN25
  BOTTOM w0.216: UD6.B7 68.62,40.28 69.25,40.28 v1(69.36,40.4)
DDR_B_DQS#4: length 32.4
  IN4 w0.076: v8(83.87,55.79) 83.87,55.64 83.95,55.55 84.02,55.55 84.13,55.44 84.21,55.44 84.4,55.25 84.4,54.29 83.84,53.73 83.84,53.41 84.1,53.15 84.1,53.01 84.17,52.94 84.17,52.92
  IN4 w0.165: 84.17,52.92 84.17,52.6 83.62,52.05 83.62,50.4 90.09,43.93 93.22,43.93 94.91,42.24 94.91,38.83 95.7,38.05 95.7,37.09 95.32,36.72 95.12,36.72 94.89,36.49 v1(94.87,36.49)
  BOTTOM w0.076: UCPU1.AW22 83.66,58.25 83.74,58.33 83.83,58.33 83.94,58.22 83.94,58.07 83.89,58.01 83.89,57.72 83.95,57.66 83.95,57.46 83.88,57.39 83.88,57.01 84.23,56.67 84.26,56.63 84.26,56.29 84.09,56.12 84.09,55.84 84.04,55.79 v8(83.87,55.79)
  BOTTOM w0.216: UD9.G3 96.27,36.53 96.14,36.65 95.1,36.65 95.08,36.63 95.02,36.63 v1(94.87,36.49)
DDR_B_DQS#5: length 30.6
  IN3 w0.076: v1(86.79,55.28) 86.89,55.38 87.18,55.38 87.29,55.27 87.29,53.81 87.88,53.23 87.88,52.75 88.07,52.56 88.07,52.26 87.99,52.18 87.99,52.16
  IN3 w0.165: 87.99,52.16 87.99,48.7 88.48,48.22 88.48,47.98 88.05,47.56 88.05,47.06 88.47,46.64 88.97,46.64 89.39,47.07 89.63,47.07 89.86,46.83 89.86,46.6 89.43,46.17 89.43,45.68 89.85,45.26 90.35,45.26 90.78,45.68 91.01,45.68 91.24,45.45 91.24,45.21 90.82,44.79 90.82,44.29 91.24,43.87 91.73,43.87 92.16,44.3 92.39,44.3 92.63,44.06 92.63,43.83 92.2,43.4 92.2,42.91 92.62,42.49 93.12,42.49 93.54,42.91 93.78,42.91 94.16,42.53 94.16,40.37 94.08,40.28 93.76,40.28 v8(93.63,40.42)
  BOTTOM w0.076: v1(86.79,55.28) 86.79,55.31 87.17,55.7 87.17,56.09 86.84,56.43 86.84,56.76 86.46,57.14 86.46,57.32 86.53,57.39 86.53,57.73 86.37,57.89 86.37,58.44 86.09,58.72 UCPU1.AV18
  BOTTOM w0.216: v8(93.63,40.42) 93.62,40.42 93.62,40.4 93.64,40.37 93.55,40.27 93.27,40.27 UD9.B7
DDR_B_DQS#6: length 45.4
  IN3 w0.076: 89.21,58.72 89.19,58.72 89.11,58.64 88.17,58.64 87.97,58.44 85.4,58.44 84.05,59.79 84.05,61.38 84.12,61.46 84.31,61.46 v1(84.44,61.33)
  IN3 w0.165: v1(106.52,36.51) 106.65,36.64 106.98,36.64 107.31,36.97 107.31,37.65 106.81,38.14 106.81,41.82 103.23,45.4 98.16,45.4 97.57,45.99 97.57,46.37 97.76,46.56 97.76,47.34 97.11,47.99 96.45,47.99 95.97,47.51 95.69,47.51 95.26,47.94 95.26,51.93 92.87,54.32 92.87,56.18 91.72,57.33 91.23,57.33 89.83,58.72 89.21,58.72
  BOTTOM w0.076: UCPU1.AN21 84.75,61.64 v1(84.44,61.33)
  BOTTOM w0.216: v1(106.52,36.51) 106.6,36.59 107.71,36.59 UD10.G3
DDR_B_DQS#7: length 36.6
  IN4 w0.076: 89.86,57.74 89.79,57.67 89.01,57.67 88.65,58.03 87.38,58.03 86.18,59.23 86.18,60.22 85.93,60.48 85.93,61.57 86.04,61.68 86.16,61.68 86.2,61.64 86.32,61.64 86.48,61.48 86.48,61.4 86.38,61.3 v1(86.35,61.3)
  IN4 w0.165: v8(105.56,40.4) 105.34,40.18 105.21,40.18 105.07,40.31 105.07,42.31 102.87,44.52 100.29,44.52 97.61,47.21 97.49,47.21 96.93,47.77 95.1,47.77 92.81,50.07 92.81,53.06 92.09,53.77 92.09,55.79 90.76,57.12 90.45,57.43 90.38,57.5 90.14,57.74 89.86,57.74
  BOTTOM w0.076: v1(86.35,61.3) 86.7,61.3 86.78,61.38 UCPU1.AN18
  BOTTOM w0.216: v8(105.56,40.4) 105.45,40.29 104.81,40.29 UD10.B7
DDR_B_MA0: length 126.1
  TOP w0.076: RD30.1 83.95,28.59 v1(84.16,28.38)
  IN1 w0.076: 65.93,59.42 66.16,59.65 67,59.65 67.18,59.47 67.58,59.47 67.91,59.8 67.91,60.39 68.24,60.72 68.65,60.72 68.9,60.97 68.9,61.48 69.12,61.7 70.32,61.7 70.61,61.41 70.61,60.6 70.94,60.27 71.32,60.27 71.6,60.54 71.6,60.81 v1(72.09,61.3)
  IN1 w0.16: v1(84.16,28.38) 83.8,28.38 82.8,29.38 79.76,29.38 78.92,30.22 77.66,30.22 76.98,30.9 76.3,30.9 75.69,31.51 75.03,31.51 74.39,32.14 72.89,32.14 71.57,33.46 71.57,34.36 71.23,34.7 70.91,34.7 69.69,35.92 69.69,36.41 69.86,36.58 69.86,37.14 69.69,37.32 69.69,38.05 68.87,38.87 68.87,41.69 63.67,46.89 63.67,53.47 64,53.8 64,57.49 65.93,59.42
  IN3 w0.076: v4(76.17,29.38) 76.3,29.5 77.11,29.5 77.24,29.38 77.24,28.97 77.35,28.85 77.9,28.85 77.97,28.93 77.97,28.99 78.01,29.03 78.19,29.03 78.27,28.96 78.27,28.68 78.41,28.54 78.53,28.54 78.61,28.61 78.61,28.94 78.68,29.02 78.86,29.02 78.94,28.94 78.94,28.13 78.99,28.08 79.17,28.08 79.25,28.16 79.25,28.94 79.32,29.02 79.48,29.02 79.55,28.94 79.55,28.16 79.63,28.08 79.78,28.08 79.86,28.16 79.86,28.33 79.93,28.41 80.08,28.41 80.16,28.33 80.16,28.16 80.24,28.08 80.49,28.08 80.56,28.16 80.56,28.33 80.64,28.41 80.79,28.41 80.87,28.33 80.87,28.16 80.94,28.08 81.1,28.08 81.17,28.16 81.17,28.33 81.25,28.41 81.4,28.41 81.48,28.33 81.48,28.16 81.55,28.08 81.71,28.08 81.78,28.16 81.78,28.33 81.86,28.41 82.01,28.41 82.09,28.33 82.09,28.16 82.16,28.08 82.32,28.08 82.39,28.16 82.39,28.33 82.47,28.41 82.62,28.41 82.7,28.33 82.7,28.16 82.77,28.08 82.9,28.08 83.03,28.21 83.03,29.04 83.38,29.39 83.49,29.39 83.62,29.26 83.62,29.16 83.36,28.9 83.36,28.79 83.46,28.69 83.56,28.69 83.84,28.97 84.09,28.97 84.16,28.89 v1(84.16,28.38) 84.29,28.38 84.73,28.81 88.62,28.81 89.38,28.05 96.51,28.05 97.97,29.51 99.75,29.51 100.07,29.19 100.72,29.19 v4(100.81,29.29)
  IN4 w0.076: v1(94.89,30.26) 95.32,30.7 95.7,30.7 96.03,30.37 96.19,30.37 96.5,30.06 97.27,30.06 97.73,29.6 99.7,29.6 100.14,29.16 100.68,29.16 v4(100.81,29.29) 100.91,29.39 101.64,29.39 102.05,28.98 103.84,28.98 104.39,29.53 106.17,29.53 106.28,29.64 106.28,29.74 106.17,29.86 106.17,29.98 v8(106.45,30.26) ; 76.17,29.29 76.4,29.51 77.1,29.51 77.63,28.98 79.05,28.98 79.66,29.59 81.54,29.59 81.81,29.86 v1(81.81,30.26) ; 76.17,29.29 v4(76.17,29.38) ; 76.17,29.29 76.04,29.16 75.5,29.16 75.06,29.6 73.1,29.6 72.63,30.06 71.86,30.06 71.56,30.37 71.39,30.37 71.06,30.7 70.67,30.7 v1(70.24,30.26)
  BOTTOM w0.076: v1(81.81,30.26) 81.81,30.32 83.15,31.67 UD7.N3 ; v1(72.09,61.3) 72.41,60.99 UCPU1.AP40 ; v1(70.24,30.26) 70.24,30.31 70.74,30.81 70.74,30.81 71.6,31.67 UD6.N3 ; UD10.N3 107.79,31.67 106.45,30.32 v8(106.45,30.26) ; UD9.N3 96.24,31.67 95.95,31.38 95.95,31.38 94.89,30.31 v1(94.89,30.26)
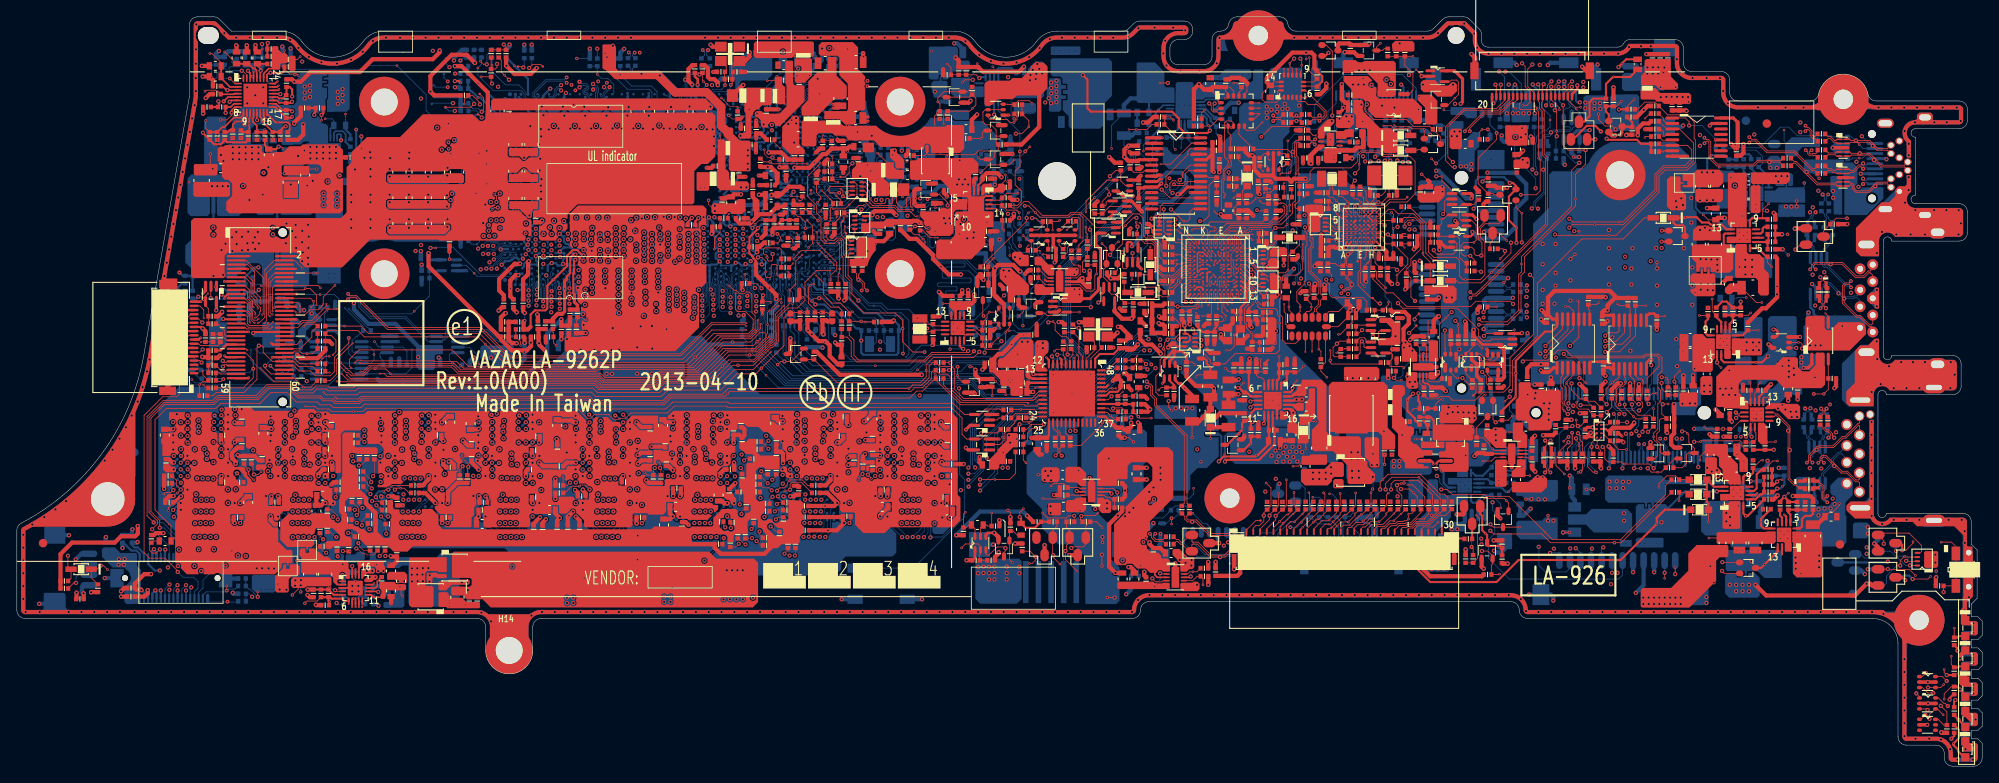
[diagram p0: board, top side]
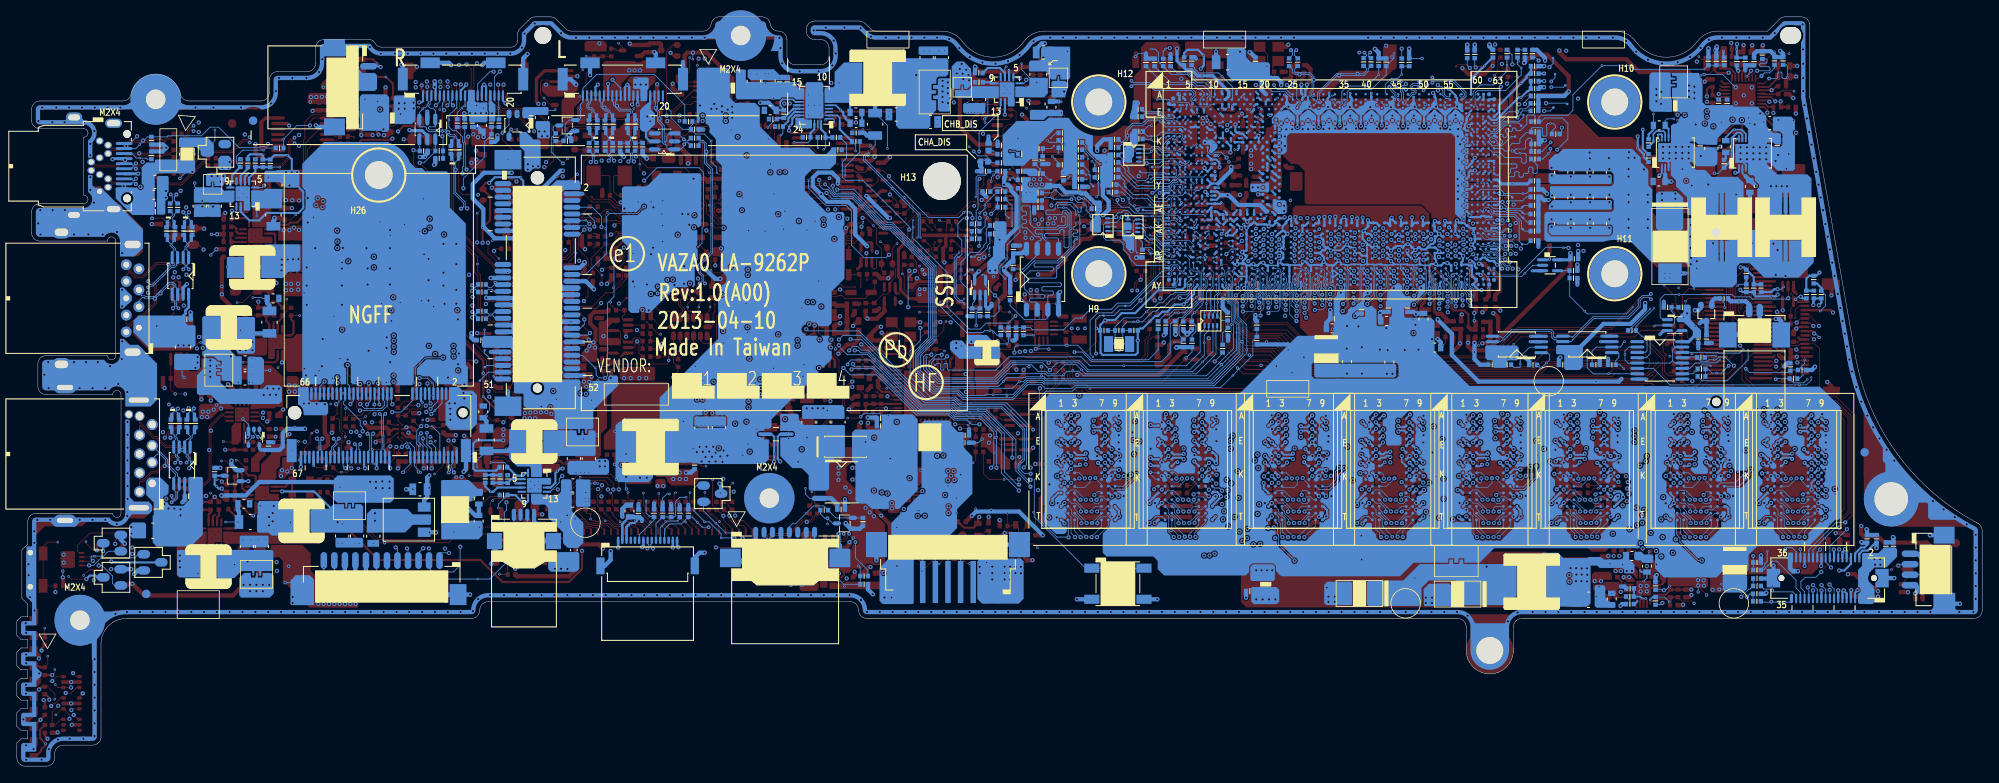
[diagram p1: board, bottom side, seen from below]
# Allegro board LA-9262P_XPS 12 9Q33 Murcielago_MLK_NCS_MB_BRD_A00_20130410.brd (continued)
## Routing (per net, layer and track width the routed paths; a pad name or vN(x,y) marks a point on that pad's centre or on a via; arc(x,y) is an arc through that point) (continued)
DDR_B_MA1: length 122.5
  TOP w0.076: v1(89.55,28.49) 89.58,28.49 90.22,27.85 RD44.1
  IN1 w0.076: v1(72.09,60.65) 72.47,60.27 72.47,59.92 73.15,59.25 73.32,59.25 73.45,59.12 73.45,54.55
  IN1 w0.16: v1(89.55,28.49) 89.66,28.38 89.94,28.38 90.47,27.85 90.47,27.02 90.63,26.86 90.92,26.86 91.08,27.02 91.08,27.06 91.23,27.22 91.56,27.22 92.2,26.58 92.2,26.33 91.81,25.94 91.81,25.72 92.06,25.47 92.28,25.47 93.05,26.24 93.05,26.46 91.6,27.91 91.07,27.91 90.11,28.87 89.96,28.87 89.77,29.06 89.49,29.06 89.3,29.25 89.3,29.77 88.91,30.17 88.91,30.52 89.04,30.65 89.16,30.65 89.38,30.88 89.38,31.05 89.2,31.23 89.05,31.23 88.87,31.41 88.87,32.46 88.73,32.6 88.73,32.78 88.34,33.17 88.34,34.25 87.95,34.63 87.95,35.42 88.19,35.65 88.19,36.62 88.69,37.12 88.69,37.39 87.78,38.3 87.78,42.99 84.4,46.38 81.1,46.38 80.01,45.3 79.07,45.3 78.28,46.08 78.28,46.98 78.12,47.15 77.61,47.15 76.55,48.21 76.55,48.58 76.99,49.02 76.99,49.28 76.91,49.36 76.46,49.36 75.64,50.19 75.64,51.07 76.03,51.46 76.03,51.64 75.82,51.85 75.25,51.85 75,52.11 75,52.74 74.65,53.1 74.27,53.1 73.45,53.91 73.45,54.55
  IN3 w0.076: v4(100.31,29.59) 100.42,29.71 101.19,29.71 101.26,29.78 101.26,29.96 101.19,30.04 99.82,30.04 99.5,29.72 97.87,29.72 96.41,28.26 92.78,28.26 92.68,28.36 92.68,28.51 92.6,28.59 92.32,28.59 92.2,28.46 92.2,28.33 92.12,28.26 91.84,28.26 91.76,28.33 91.76,28.51 91.69,28.59 91.49,28.59 91.38,28.49 91.38,28.38 91.26,28.26 90.62,28.26 90.39,28.49 90.19,28.49 89.96,28.26 89.81,28.26 89.58,28.49 v1(89.55,28.49) 89.33,28.49 88.8,29.02 84.45,29.02 83.87,29.6 83.31,29.6 83.05,29.35 79.56,29.35 79.45,29.24 77.7,29.24 77.24,29.71 76.52,29.71 76.4,29.83 75.81,29.83 v4(75.61,29.63)
  IN4 w0.076: v1(94.25,30.26) 94.89,30.9 95.88,30.9 96.14,30.63 96.3,30.63 96.61,30.33 97.38,30.33 97.85,29.86 99.81,29.86 100.09,29.59 v4(100.31,29.59) 100.4,29.68 101.04,29.68 101.1,29.61 101.79,29.61 102.18,29.23 103.71,29.23 104.21,29.73 105.68,29.73 105.81,29.86 v1(105.81,30.26) ; v8(81.17,30.26) 81.17,29.98 81.03,29.84 79.58,29.84 78.94,29.2 77.79,29.2 77.27,29.72 76.38,29.72 76.27,29.83 75.81,29.83 v4(75.61,29.63) 75.56,29.68 75.36,29.68 75.24,29.8 73.27,29.8 72.74,30.33 71.97,30.33 71.67,30.63 71.5,30.63 71.24,30.9 70.24,30.9 v1(69.6,30.26)
  BOTTOM w0.076: v1(105.81,30.26) 105.81,30.44 105.38,30.87 UD10.P7 ; v1(69.6,30.26) 69,30.87 UD6.P7 ; v1(94.25,30.26) 93.65,30.87 UD9.P7 ; v8(81.17,30.26) 81.17,30.59 80.9,30.87 UD7.P7 ; v1(72.09,60.65) 72.41,60.34 UCPU1.AR40
DDR_B_MA2: length 130.7
  TOP w0.076: RD40.1 83.99,26.54 v8(83.99,27.11)
  IN1 w0.076: 66.87,61.69 67.88,61.69 67.92,61.65 68.54,61.65 68.89,62 70.47,62 71.17,61.31 v1(71.17,61.28)
  IN1 w0.16: 66.87,61.69 66.61,61.43 66.11,61.43 64.76,60.08 64.54,60.08 63.62,59.17 62.94,59.17 61.26,57.49 61.26,53.24 62.97,51.52 62.97,45.9 67.1,41.77 67.1,38.54 68.5,37.15 68.5,33.49 68.76,33.22 69.32,33.22 70.35,32.19 71.27,32.19 74.06,29.4 74.91,29.4 76,28.31 76.68,28.31 77.29,27.7 83.33,27.7 83.92,27.11 v8(83.99,27.11)
  IN3 w0.076: v4(100.55,27.95) 100.44,27.84 98.39,27.84 96.78,26.24 92.98,26.24 92.2,27.01 88.96,27.01 88.52,27.45 87.89,27.45 87.8,27.53 87.05,27.53 86.87,27.72 85.49,27.72 84.81,27.04 84.07,27.04 v8(83.99,27.11) 83.9,27.11 83.3,26.5 80.35,26.5 79.67,27.18 78.61,27.18 77.97,27.83 77.11,27.83 76.89,28.04 76.49,28.04 76.3,27.85 76.3,27.65 76.09,27.44 75.14,27.44 75.06,27.52 74.47,27.52 74.34,27.65 73.43,27.65 73.35,27.57 73.35,26.78 73.27,26.71 72.99,26.71 72.92,26.78 72.92,28.03 72.99,28.11 74.39,28.11 74.65,27.85 75.81,27.85 75.89,27.93 v4(75.89,27.88)
  IN4 w0.076: v1(106.4,28.89) 105.42,27.91 101.58,27.91 101.43,28.07 101.1,28.07 100.96,27.93 100.58,27.93 v4(100.55,27.95) 100.45,27.85 97.97,27.85 96.83,28.99 95.98,28.99 95.68,29.3 95.24,29.3 v1(94.84,28.89) ; v1(70.2,28.89) 70.61,29.3 71.04,29.3 71.34,28.99 72.19,28.99 73.33,27.85 75.86,27.85 v4(75.89,27.88) 76.08,28.07 76.87,28.07 76.98,27.95 80.81,27.95 v1(81.76,28.89)
  BOTTOM w0.076: UD6.P3 71.63,30.55 71.3,30.21 71.3,30.07 70.2,28.97 v1(70.2,28.89) ; UCPU1.AP42 71.46,60.99 v1(71.17,61.28) ; UD10.P3 107.83,30.58 107.53,30.28 107.53,30.12 106.4,28.99 v1(106.4,28.89) ; UD7.P3 83.19,30.58 82.86,30.25 82.86,30.05 81.76,28.95 v1(81.76,28.89) ; v1(94.84,28.89) 94.84,28.99 95.94,30.1 95.94,30.54 UD9.P3
DDR_B_MA3: length 128.8
  TOP w0.076: v1(84.84,28.31) 84.77,28.38 RD50.1
  IN1 w0.076: 65.78,59.75 65.83,59.8 67.08,59.8 67.24,59.65 67.53,59.65 67.71,59.83 67.71,60.44 68.14,60.87 68.57,60.87 68.75,61.05 68.75,61.55 69.05,61.85 70.41,61.85 70.76,61.5 70.76,60.82 70.94,60.64 v1(71.16,60.64)
  IN1 w0.16: v1(84.84,28.31) 84.75,28.31 84.37,27.92 83.61,27.92 83.48,28.05 78.42,28.05 76.26,30.21 75.53,30.21 74.82,30.92 74.82,31.18 74.21,31.79 72.36,31.79 71.48,32.66 70.7,32.66 69.43,33.94 69.43,33.95 69.31,34.08 69.31,36.52 69.51,36.73 69.51,37 69.34,37.17 69.34,37.91 68.52,38.72 68.52,41.11 68.32,41.32 67.66,41.32 67.45,41.52 67.45,41.63 67.45,41.92 63.32,46.05 63.32,51.8 62.48,52.64 62.48,53.91 63.01,54.44 63.01,56.98 65.78,59.75
  IN3 w0.076: v4(101.37,28.99) 101.26,28.89 99.99,28.89 99.58,29.31 98.08,29.31 96.62,27.85 89.22,27.85 88.46,28.61 85.14,28.61 v1(84.84,28.31) 84.49,27.96 83.71,27.96 83.64,28.04 83.64,28.41 83.56,28.49 83.38,28.49 83.31,28.41 83.31,28.11 83.08,27.88 78.78,27.88 78.01,28.65 76.26,28.65 76.23,28.68 75.57,28.68 74.82,29.43 73.3,29.43 73.22,29.5 73.22,29.73 73.3,29.8 74.88,29.8 75.7,28.98 76.64,28.98 v4(76.75,29.1)
  IN4 w0.076: v1(95.52,30.26) 95.69,30.1 96.04,30.1 96.35,29.79 97.16,29.79 97.62,29.33 99.59,29.33 100.03,28.89 101.26,28.89 v4(101.37,28.99) 101.47,28.89 101.76,28.89 101.94,28.71 103.96,28.71 104.57,29.32 106.27,29.32 107.08,30.14 v1(107.08,30.26) ; v1(82.44,30.26) 82.44,30.14 81.63,29.32 79.7,29.32 79.09,28.71 77.3,28.71 76.97,29.04 76.8,29.04 v4(76.75,29.1) 76.75,29.07 76.58,28.89 75.39,28.89 74.95,29.33 72.99,29.33 72.52,29.79 71.71,29.79 71.41,30.09 71.04,30.09 v8(70.88,30.26)
  BOTTOM w0.076: v1(82.44,30.26) 82.44,30.62 83.08,31.25 83.58,31.25 UD7.N2 ; UD6.N2 72.02,31.25 71.52,31.25 70.88,30.61 v8(70.88,30.26) ; v1(71.16,60.64) 71.17,60.63 71.17,60.63 71.46,60.34 UCPU1.AR42 ; v1(107.08,30.26) 107.08,30.62 107.72,31.25 108.22,31.25 UD10.N2 ; UD9.N2 96.66,31.25 96.16,31.25 95.52,30.62 v1(95.52,30.26)
DDR_B_MA4: length 129.6
  TOP w0.076: v1(88.82,29.6) 89.42,30.2 RD38.1
  IN1 w0.16: v1(88.82,29.6) 88.56,29.87 88.56,30.66 88.67,30.77 88.67,31.11 88.44,31.34 88.18,31.34 87.85,31.67 87.85,32.1 88.03,32.27 88.03,32.49 87.67,32.84 87.48,32.84 87.29,32.66 87.14,32.66 86.53,33.27 86.53,33.74 86.8,34.02 86.8,34.14 86.53,34.41 86.53,34.56 87.17,35.21 87.17,35.63 87.49,35.94 87.49,36.91 87.75,37.17 87.75,37.34 86.67,38.42 86.67,38.74 87.08,39.16 87.08,42.7 85.14,44.64 82.6,44.64 82.45,44.79 82.45,45.5 82.3,45.66 81.99,45.66 81.83,45.5 81.83,44.82 81.68,44.67 81.4,44.67 81.25,44.82 81.25,45.12 81.12,45.25 80.96,45.25 80.3,44.59 78.78,44.59 78.56,44.81 78.39,44.81 78.17,44.59 76.37,44.59 76.15,44.82 76.15,45.44 76.56,45.85 77.45,45.85 77.58,45.98 77.58,46.32 77.45,46.45 76.43,46.45 75.76,45.78 75.18,45.78 74.52,46.44 74.52,47.01 73.55,47.98 73.55,48.23 74.68,49.36 74.68,49.94 74.68,49.95 74.68,49.96 74.94,50.21 74.94,50.88 74.77,51.04 74.63,51.04 74.41,51.27 74.41,51.69 74.31,51.79 73.92,51.79 73.65,52.06 73.65,52.67 72.64,53.68 72.64,54.22 72.26,54.6 72.26,59.19 71.83,59.63 71.01,59.63 70.71,59.32 70.71,55.33 70.56,55.18 69.55,55.18 69.4,55.33 69.4,55.83 68.93,56.3 68.93,59.05 68.69,59.3 68.69,59.49 v1(69.28,60.09)
  IN3 w0.076: v4(98.98,30.26) 98.65,29.93 98.44,29.93 98.39,29.98 98.39,30.11 98.32,30.19 98.11,30.19 98.04,30.11 98.04,30 97.96,29.92 97.75,29.92 97.68,29.98 97.68,30.11 97.61,30.19 97.41,30.19 97.34,30.11 97.34,29.49 97.12,29.26 97.03,29.26 96.95,29.35 96.95,29.65 96.87,29.73 96.69,29.73 96.59,29.63 96.59,28.72 96.45,28.58 96.31,28.58 96.24,28.66 96.24,29.07 96.16,29.15 95.98,29.15 95.9,29.07 95.9,28.61 95.75,28.46 93.16,28.46 93.09,28.54 93.09,29.07 93.01,29.15 92.7,29.15 92.63,29.07 92.63,28.87 92.55,28.79 91.16,28.79 91.05,28.69 91.05,28.54 90.98,28.46 90.77,28.46 90.7,28.54 90.7,28.64 90.65,28.69 89.94,28.69 89.73,28.91 89.21,28.91 88.82,29.3 v1(88.82,29.6) 88.43,29.22 85.26,29.22 84.91,29.58 84.91,29.78 84.58,30.11 83.51,30.11 82.95,29.55 79.5,29.55 78.94,30.11 77.72,30.11 77.53,29.92 76.66,29.92 76.32,30.26 74.36,30.26 74.35,30.25 v4(74.35,30.21)
  IN4 w0.076: v1(80.51,30.26) 80.5,30.27 80.5,30.28 80.39,30.16 79.98,30.16 79.93,30.11 77.42,30.11 77.23,29.92 76.47,29.92 76.33,30.06 75.35,30.06 75.28,30.13 74.43,30.13 v4(74.35,30.21) 74.06,30.21 73.98,30.13 73.32,30.13 72.85,30.59 72.08,30.59 71.78,30.9 71.61,30.9 71.34,31.18 69.87,31.18 v8(68.96,30.26) ; v1(93.59,30.27) 94.55,31.23 95.92,31.23 96.25,30.9 96.42,30.9 96.72,30.59 97.49,30.59 97.79,30.3 98.94,30.3 v4(98.98,30.26) 99.11,30.13 99.92,30.13 100.07,29.98 100.48,29.98 100.56,29.9 101.15,29.9 101.21,29.84 101.92,29.84 102.18,30.1 104.74,30.1 104.9,30.27 v1(105.15,30.27)
  BOTTOM w0.076: v1(93.59,30.27) 93.39,30.47 92.81,30.47 92.41,30.87 UD9.P8 ; v1(105.15,30.27) 104.96,30.47 104.36,30.47 103.96,30.87 UD10.P8 ; v1(80.51,30.26) 80.31,30.47 79.73,30.47 79.32,30.87 UD7.P8 ; UCPU1.AR45 69.53,60.34 v1(69.28,60.09) ; UD6.P8 67.77,30.87 68.17,30.47 68.76,30.47 v8(68.96,30.26)
DDR_B_MA5: length 136.9
  TOP w0.076: v1(86.58,26.35) 86.44,26.35 85.73,27.06 RD56.1
  IN1 w0.076: 65.16,53.17 65.16,54.28 65.07,54.37 65.07,57.82 66.56,59.32 66.9,59.32 67.05,59.17 67.94,59.17 68.8,60.03 68.8,60.23 v1(69.29,60.72)
  IN1 w0.16: 65.16,53.17 65.16,52.75 65.02,52.62 64.52,52.62 64.37,52.47 64.37,51.51 64.61,51.27 65.7,51.27 65.86,51.12 65.86,50.41 65.71,50.26 64.59,50.26 64.37,50.04 64.37,47.18 70.19,41.36 70.19,39.83 70.71,39.32 70.71,38.25 71,37.96 71.55,37.96 71.9,38.32 72.33,38.32 72.71,37.93 72.71,37.55 72.46,37.3 72.46,37.07 72.62,36.91 73.19,36.91 73.64,36.46 73.96,36.46 74.29,36.13 74.29,35.08 74.35,35.01 74.35,34.59 74.29,34.53 74.29,33.79 74.59,33.49 74.98,33.49 75.33,33.85 75.33,34.38 75.53,34.58 75.97,34.58 76.14,34.4 76.14,34.06 76.88,33.32 76.88,32.8 77.11,32.58 79.69,32.58 80.11,32.16 80.11,31.56 79.44,30.9 79.44,30.69 79.75,30.39 79.95,30.39 80.41,30.85 80.41,31.08 80.51,31.18 80.92,31.18 81.07,31.03 81.07,30.91 81.23,30.75 81.57,30.75 81.73,30.91 81.73,31 81.91,31.18 82.44,31.18 82.59,31.03 82.59,30.82 82.98,30.43 82.98,30.27 84.04,29.2 84.52,29.2 84.6,29.12 85.2,29.12 85.69,28.63 85.69,27.84 85.49,27.64 85.49,27.44 v1(86.58,26.35)
  IN3 w0.076: v4(100.38,26.63) 99.89,26.63 99.69,26.43 99.44,26.43 98.18,25.17 92.89,25.17 91.99,26.08 86.86,26.08 v1(86.58,26.35) 86.23,26 83.96,26 83.35,25.39 78.78,25.39 77.42,26.75 76.36,26.75 76.12,26.5 76.12,25.44 76.04,25.36 75.33,25.36 75.15,25.54 75.15,26.07 v4(75.69,26.61)
  IN4 w0.076: v1(106.45,27.24) 105.71,26.5 104.46,26.5 104.21,26.75 100.97,26.75 100.86,26.63 v4(100.38,26.63) 100.24,26.49 97.82,26.49 96.39,27.93 95.3,27.93 94.74,27.37 v8(94.74,27.27) ; v1(81.81,27.24) 81.07,26.5 79.8,26.5 79.56,26.75 75.83,26.75 v4(75.69,26.61) 75.71,26.61 75.6,26.49 73.18,26.49 71.8,27.88 70.61,27.88 70.1,27.37 v3(70.1,27.27)
  BOTTOM w0.076: v1(81.81,27.24) 82.82,28.26 82.82,29.4 83.15,29.73 83.31,29.73 83.57,29.99 83.57,30.44 UD7.P2 ; v1(69.29,60.72) 69.56,60.99 UCPU1.AP45 ; v8(94.74,27.27) 94.74,27.37 95.9,28.54 95.9,29.4 96.24,29.73 96.39,29.73 96.65,29.99 96.65,30.44 UD9.P2 ; v1(106.45,27.24) 107.46,28.26 107.46,29.4 107.79,29.73 107.94,29.73 108.2,29.99 108.2,30.44 UD10.P2 ; UD6.P2 72.01,30.44 72.01,29.94 71.8,29.73 71.62,29.73 71.5,29.6 71.3,29.41 71.3,29.41 71.27,29.38 71.27,28.54 70.1,27.37 v3(70.1,27.27)
DDR_B_MA6: length 133
  TOP w0.076: RD36.1 87.54,28.44 v1(87.29,28.19)
  IN1 w0.076: 66.46,54.06 66.46,56.1 67.03,56.66 67.03,56.93 67.38,57.29 67.38,57.82 67.56,58 68.01,58 68.18,57.84 68.18,57.84 68.33,57.69 v1(68.33,57.56)
  IN1 w0.16: v1(87.29,28.19) 87.04,27.94 87.04,27.47 86.88,27.31 86.62,27.31 86.46,27.47 86.46,28.43 86.62,28.59 86.92,28.59 87.08,28.75 87.08,30.33 86.36,31.04 86.36,31.44 85.33,32.47 85.06,32.47 84.7,32.11 84.47,32.11 84.29,32.29 84.29,32.52 84.68,32.91 84.68,33.04 84.54,33.19 84.07,33.19 83.71,32.83 83.55,32.83 83.21,33.17 82.11,33.17 81.88,33.4 81.88,33.56 82.04,33.72 82.98,33.72 83.13,33.87 83.13,34.72 82.98,34.87 82.76,34.87 82.54,34.66 82.32,34.66 82.1,34.87 81.88,34.87 81.67,34.66 81.16,34.66 81,34.82 81,35.06 81.22,35.29 81.22,35.5 81.02,35.7 80.81,35.7 80.72,35.61 80.4,35.61 80.06,35.96 80.06,37.2 79.85,37.4 79.45,37.4 79.26,37.59 79.26,38.08 79.14,38.21 79.14,38.27 79.14,38.27 79.14,38.65 79.14,38.82 78.98,38.98 78.66,38.98 78.5,38.82 78.5,38.02 78.3,37.81 78.3,36.16 78.17,36.02 77.67,36.02 77.34,36.36 77.34,36.74 77.19,36.89 76.81,36.89 76.37,37.33 76.37,37.62 76.6,37.85 76.6,37.88 76.76,38.05 76.76,38.7 76.64,38.82 75.06,38.82 74.94,38.94 74.94,39.25 75.06,39.37 76.59,39.37 76.76,39.55 76.76,41.87 76.58,42.06 74.57,42.06 74.4,42.23 74.4,42.98 73.68,43.71 71.78,43.71 71.15,44.34 70.81,44.34 70.05,45.1 70.05,45.75 68.71,47.09 67.42,47.09 66.6,47.91 66.6,48.13 66.76,48.28 67.12,48.28 67.71,47.69 68.69,47.69 69.06,48.06 69.06,48.83 68.93,48.96 68.29,48.96 68.14,49.11 68.14,49.64 68.45,49.95 68.45,52.11 67.64,52.92 67.16,52.92 66.94,52.69 66.74,52.69 66.56,52.87 66.56,53.29 66.46,53.38 66.46,54.06
  IN3 w0.076: v4(99.54,28.79) 99.15,28.41 97.86,28.41 96.16,26.71 93.08,26.71 92.27,27.52 89.22,27.52 88.43,28.31 87.41,28.31 v1(87.29,28.19) 87.26,28.16 85.29,28.16 84.87,27.74 83.52,27.74 83.44,27.66 80.33,27.66 80.26,27.59 78.78,27.59 77.93,28.45 76.13,28.45 76.11,28.47 75.44,28.47 75.25,28.65 75.04,28.65 v4(74.87,28.82)
  IN4 w0.076: v1(93.57,28.92) 93.62,28.92 93.94,29.24 93.94,29.25 94.42,29.73 96.03,29.73 96.24,29.53 97.05,29.53 98.12,28.46 99.2,28.46 v4(99.54,28.79) 99.76,28.79 99.96,28.6 101.65,28.6 101.84,28.41 104.69,28.41 104.78,28.5 104.78,28.63 104.57,28.84 104.57,29.02 104.67,29.12 104.88,29.12 v1(105.13,28.88) ; v1(80.49,28.89) 80.33,29.04 79.73,29.04 79.62,28.94 79.62,28.82 79.73,28.71 79.95,28.71 80.03,28.64 80.03,28.46 79.95,28.38 77.23,28.38 77.01,28.6 75.32,28.6 75.1,28.82 v4(74.87,28.82) 74.46,28.41 73.44,28.41 72.32,29.53 71.6,29.53 71.34,29.78 69.84,29.78 v8(68.93,28.88)
  BOTTOM w0.076: UD10.R8 103.83,29.88 104.08,29.63 104.72,29.63 105.13,29.22 v1(105.13,28.88) ; v1(80.49,28.89) 80.49,29.22 80.08,29.63 79.65,29.63 79.21,30.07 UD7.R8 ; UCPU1.AW46 68.63,57.88 68.33,57.58 68.35,57.58 68.35,57.56 v1(68.33,57.56) ; v8(68.93,28.88) 68.93,29.25 68.77,29.41 68.77,29.41 68.57,29.6 68.55,29.63 68.02,29.63 67.63,30.01 UD6.R8 ; UD9.R8 92.27,30.01 92.65,29.63 93.16,29.63 93.57,29.22 v1(93.57,28.92)
DDR_B_MA7: length 136
  TOP w0.076: v1(91.2,25.26) 91.62,25.68 RD48.1
  IN1 w0.16: v1(91.2,25.26) 91.13,25.33 91.13,25.82 91.68,26.37 91.68,26.59 91.52,26.75 91.3,26.75 91.06,26.51 90.71,26.51 90.57,26.37 90.57,25.16 91.11,24.62 91.11,24.4 90.89,24.19 90.68,24.19 90.01,24.85 90.01,27.77 89.81,27.98 89.34,27.98 88.94,28.37 88.94,28.98 88.79,29.13 88.58,29.13 88.21,29.5 88.21,30.82 87.5,31.52 87.5,32.15 87.35,32.3 86.99,32.3 86.18,33.12 86.18,34.71 86.82,35.35 86.82,35.77 87.14,36.09 87.14,37.46 86.13,38.47 86.13,38.69 86.73,39.3 86.73,42.56 85,44.29 81.2,44.29 80.93,44.02 80.68,44.02 80.46,44.24 76.23,44.24 75.8,44.68 75.8,45.29 75.66,45.43 75.04,45.43 74.17,46.3 74.17,46.86 73.2,47.84 73.2,48.38 74.32,49.5 74.32,50.09 74.59,50.35 74.59,50.59 73.3,51.87 73.3,52.52 72.24,53.58 72.24,54.1 71.91,54.44 71.91,59.03 71.65,59.29 71.31,59.29 71.06,59.04 71.06,55 70.91,54.85 69.18,54.85 69.03,55 69.03,55.55 v1(68.33,56.25)
  IN3 w0.076: v4(77.24,25.95) 78.29,24.89 83.43,24.89 84.13,25.59 90.87,25.59 v1(91.2,25.26) 91.28,25.18 91.28,24.88 91.57,24.59 102.48,24.59 102.56,24.67 102.56,24.98 102.48,25.06 101.29,25.06 101.21,25.13 101.21,25.41 101.29,25.49 101.75,25.49 101.87,25.62 v4(101.87,25.95)
  IN4 w0.076: v1(107.77,27.22) 106.52,25.97 101.9,25.97 v4(101.87,25.95) 97.35,25.95 v1(96.06,27.24) ; v1(83.13,27.22) 81.86,25.95 v4(77.24,25.95) 72.71,25.95 v8(71.42,27.24)
  BOTTOM w0.076: UD7.R2 83.6,29.67 83.6,29.08 83.38,28.87 83.38,27.47 v1(83.13,27.22) ; v1(96.06,27.24) 96.68,27.86 96.68,29.67 UD9.R2 ; v1(68.33,56.25) 68.73,56.65 UCPU1.AY46 ; v1(107.77,27.22) 108.25,27.7 108.25,29.6 108.63,29.98 UD10.R2 ; UD6.R2 72.43,29.78 72.04,29.39 72.04,28.17 71.57,27.7 71.57,27.39 v8(71.42,27.24)
DDR_B_MA8: length 133.5
  TOP w0.076: RD42.1 88.39,26.25 v1(87.89,26.75)
  IN1 w0.076: v1(68.32,56.88) 68.04,56.88 67.95,56.96 67.95,57.75 67.85,57.85 67.71,57.85 67.61,57.75 67.61,57.26 67.19,56.84 67.19,56.6 66.7,56.11 66.7,54.43 66.81,54.32 66.81,54.06
  IN1 w0.16: v1(87.89,26.75) 88.06,26.58 88.43,26.58 88.58,26.73 88.58,26.93 88.14,27.37 87.72,27.37 87.55,27.54 87.55,27.78 87.8,28.03 87.8,28.09 88.08,28.37 88.08,28.61 87.88,28.82 87.62,28.82 87.47,28.97 87.47,30.52 86.75,31.25 86.75,31.55 85.47,32.82 85.47,33 85.29,33.18 85.04,33.18 84.86,33.36 84.86,34.71 84.99,34.84 84.99,35.05 84.81,35.22 84.48,35.22 84.17,34.91 83.79,34.91 83.48,35.22 81.73,35.22 81.6,35.34 81.6,35.61 81.02,36.19 81.02,37.05 80.85,37.21 80.85,37.91 80.11,38.65 80.11,41.97 79.66,42.41 79.22,42.41 79.12,42.3 79.12,39.46 78.98,39.33 78.28,39.33 78.15,39.2 78.15,38.16 77.65,37.66 77.65,37.61 77.29,37.25 77.08,37.25 76.93,37.41 76.93,37.65 77.31,38.04 77.31,38.3 77.11,38.5 77.11,42.21 76.91,42.41 75.47,42.41 73.82,44.06 71.93,44.06 71.71,44.27 71.71,44.37 72.49,45.15 72.49,45.38 72.31,45.55 72.09,45.55 71.23,44.69 70.95,44.69 70.4,45.24 70.4,45.65 71.36,46.61 71.36,47.74 71.19,47.92 70.87,47.92 70.71,47.76 70.71,47.26 70.55,47.1 69.57,47.1 69.41,47.26 69.41,49.31 68.81,49.91 68.81,52.31 67.83,53.29 67.06,53.29 66.81,53.53 66.81,54.06
  IN3 w0.076: v4(98.78,27.17) 98.39,27.17 98.17,26.94 98.17,26.78 98.24,26.71 98.75,26.71 98.83,26.63 98.83,26.45 98.75,26.38 97.61,26.38 97.53,26.3 97.53,26.15 97.61,26.07 98.1,26.07 98.17,26 98.17,25.86 98.02,25.7 92.93,25.7 92.07,26.57 88.63,26.57 88.4,26.8 87.94,26.8 v1(87.89,26.75) 87.78,26.64 87.18,26.64 86.82,27 85.61,27 85.08,26.48 83.87,26.48 83.39,26 78.92,26 77.68,27.24 75.05,27.24 74.98,27.32 74.29,27.32 v4(74.14,27.17)
  IN4 w0.076: v8(68.83,27.24) 68.83,27.34 69.77,28.28 72.15,28.28 73.41,27.03 74,27.03 v4(74.14,27.17) 74.29,27.32 75.15,27.32 75.23,27.24 80.51,27.24 v1(80.54,27.22) ; v1(105.18,27.22) 105.13,27.26 100.76,27.26 100.71,27.32 98.93,27.32 v4(98.78,27.17) 98.64,27.03 98.04,27.03 96.61,28.46 94.58,28.46 93.47,27.34 v1(93.47,27.24)
  BOTTOM w0.076: UD10.T8 103.83,28.54 105.15,27.22 v1(105.18,27.22) ; v1(68.32,56.88) 67.97,57.23 UCPU1.AY47 ; UD7.T8 79.19,28.54 79.22,28.54 v1(80.54,27.22) ; v8(68.83,27.24) 68.83,27.93 67.63,29.13 UD6.T8 ; UD9.T8 92.27,28.99 93.62,27.65 93.62,27.39 v1(93.47,27.24)
DDR_B_MA9: length 132.5
  TOP w0.076: RD52.1 86.58,27.09 v1(87.35,27.09)
  IN1 w0.076: v1(68.33,58.88) 68.05,58.88 67.74,58.56 66.49,58.56 66.06,58.13 66.06,54.7 65.91,54.55
  IN1 w0.16: v1(87.35,27.09) 87.46,26.98 87.43,26.94 87.43,26.71 87.29,26.58 87.05,26.58 86.67,26.96 86.48,26.96 86.1,27.33 86.1,28.81 86.26,28.97 86.57,28.97 86.73,29.13 86.73,30.18 86.26,30.65 85.86,30.65 85.71,30.51 85.71,30.25 85.52,30.06 85.3,30.06 85.19,30.18 85.19,30.65 84.96,30.87 84.75,30.87 84.39,30.51 83.89,30.51 83.5,30.9 83.5,31.17 83.73,31.39 83.73,31.66 82.91,32.47 81.82,32.47 80.88,33.42 80.37,33.42 79.79,34 79.55,34 79.42,33.87 79.42,33.39 79.31,33.28 78.99,33.28 78.84,33.43 78.84,33.84 78.68,34 78.36,34 78.2,33.84 78.2,33.42 78.06,33.28 77.73,33.28 77.58,33.42 77.58,33.88 77.44,34.02 77.17,34.02 76.84,34.35 76.84,34.67 77.26,35.09 77.26,35.45 76.75,35.95 76.51,35.95 76.35,36.11 76.35,36.36 76.12,36.59 75.89,36.59 75.74,36.44 75.74,36.08 75.57,35.91 75.26,35.91 74.99,36.18 74.99,36.49 74.95,36.54 74.95,37.82 74.24,38.52 74.24,39 74.09,39.15 73.84,39.15 73.68,39.31 73.68,39.89 73.84,40.05 73.96,40.05 73.98,40.07 75.89,40.07 76.06,40.24 76.06,41.2 75.91,41.36 74.28,41.36 73.7,41.94 73.7,42.69 73.39,43 72.44,43 72.03,42.59 71.16,42.59 71.09,42.51 70.12,42.51 69.26,43.37 69.26,43.6 69.44,43.78 69.67,43.78 70.45,42.99 70.85,42.99 71.01,43.15 71.01,43.48 70.85,43.64 70.52,43.64 69.87,44.29 68.91,44.29 67.51,45.69 67.51,46.18 67.3,46.39 67.13,46.39 65.12,48.4 65.12,49.21 65.35,49.44 66.38,49.44 66.83,48.98 67.36,48.98 67.44,49.07 67.44,49.9 67.28,50.06 66.77,50.06 66.56,50.26 66.56,51.41 65.86,52.11 65.86,54.5 65.91,54.55
  IN3 w0.076: v4(101.26,27.67) 101.14,27.55 99.61,27.55 99.59,27.57 98.5,27.57 96.89,25.97 92.96,25.97 92.14,26.79 88.77,26.79 88.39,27.17 87.42,27.17 v1(87.35,27.09) 87.3,27.14 86.97,27.14 86.76,27.35 86.76,27.44 86.69,27.52 86.43,27.52 86.35,27.44 86.35,27.28 86.28,27.2 86.02,27.2 85.95,27.28 85.95,27.44 85.87,27.52 85.69,27.52 85.59,27.42 85.59,27.27 85,26.68 83.79,26.68 83.36,26.26 79.85,26.26 79.73,26.37 79.73,26.84 79.59,26.98 79.47,26.98 79.39,26.9 79.39,26.33 79.32,26.25 79.09,26.25 79.01,26.33 79.01,26.89 78.94,26.96 78.79,26.96 78.71,26.89 78.71,26.73 78.64,26.66 78.55,26.66 78.25,26.96 78.25,27.26 77.95,27.56 76.82,27.56 76.7,27.67 v4(76.7,27.65)
  IN4 w0.076: v1(107.03,28.88) 105.82,27.67 v4(101.26,27.67) 101.15,27.56 97.89,27.56 96.72,28.73 95.63,28.73 v1(95.47,28.88) ; v1(82.39,28.88) 82.39,28.36 81.71,27.67 76.73,27.67 v4(76.7,27.65) 76.7,27.67 76.5,27.47 75.38,27.47 75.26,27.58 73.22,27.58 72.08,28.73 70.99,28.73 v8(70.84,28.88)
  BOTTOM w0.076: v1(82.39,28.88) 82.39,29.27 UD7.R3 ; UD10.R3 107.03,29.27 v1(107.03,28.88) ; UD6.R3 70.84,29.27 v8(70.84,28.88) ; UCPU1.AU46 68.48,58.88 v1(68.33,58.88) ; v1(95.47,28.88) 95.47,29.27 UD9.R3
DDR_B_MA10: length 136.3
  TOP w0.076: RD32.1 88.81,34.68 v1(88.45,35.04)
  IN1 w0.16: v1(88.45,35.04) 88.54,35.13 88.54,36.47 89.19,37.12 89.35,37.12 89.49,37.26 89.49,37.26 89.76,37.53 89.76,37.53 89.86,37.63 89.86,38.6 89.96,38.7 90.39,38.7 90.88,39.18 91.33,39.18 91.46,39.31 91.46,40.22 91.46,40.23 91.46,41.7 91.91,42.15 91.91,42.43 92.85,43.38 94.43,43.38 94.58,43.53 94.58,45.49 94.43,45.64 91.14,45.64 91,45.5 91,44.97 90.76,44.73 90.55,44.73 90.36,44.92 90.36,45.4 89.78,45.98 86.62,45.98 85.03,47.56 81.12,47.56 80.94,47.74 80.94,47.97 81.17,48.19 83.38,48.19 83.54,48.35 83.54,48.68 83.38,48.83 81.5,48.83 81.38,48.96 81.38,49.26 80.56,50.08 79.74,50.08 79.54,49.88 79.25,49.88 79.1,50.03 79.1,50.25 78.89,50.47 78.89,51.08 78.54,51.42 78.07,51.42 77.76,51.11 77.47,51.11 77.34,51.24 77.34,51.54 77.46,51.66 77.46,51.94 75.53,53.86 75.53,54.58 75.36,54.76 75.36,56.47 75.2,56.63 75.01,56.63 74.85,56.79 74.85,57.11 75.01,57.27 75.11,57.27 75.27,57.43 75.27,59.1 74.88,59.5 74.52,59.5 74.09,59.93 74.09,62.34 73.93,62.5 73.93,64.07 73.76,64.25 72.71,64.25 72.53,64.43 70.71,64.43 70.58,64.3 70.58,63.79 70.45,63.67 69.69,63.67 69.51,63.84 69.51,65.69 69.65,65.82 75.2,65.82 75.36,65.66 75.36,63.87 75.05,63.56 74.68,63.56 v1(74.53,63.42)
  IN3 w0.076: v4(99.21,34.43) 99.16,34.38 98.17,34.38 97.68,34.86 97.66,34.86 97.65,34.88 97.31,34.88 97.3,34.88 96.33,34.88 96.17,34.72 93.28,34.72 93.14,34.58 93.14,34.13 93.03,34.02 91.59,34.02 91.41,34.2 90.77,34.2 90.52,34.46 90.52,35.34 90.36,35.5 89.5,35.5 89.38,35.37 89.38,34.63 89.25,34.51 89.07,34.51 88.95,34.63 88.95,35.34 88.82,35.47 88.59,35.47 88.45,35.33 v1(88.45,35.04) 87.94,34.53 85.93,34.53 85.44,35.01 81.38,35.01 81.03,34.66 80.44,34.66 79.65,33.87 77.11,33.87 76.02,34.96 75.17,34.96 v4(74.8,34.59)
  IN4 w0.076: 101.79,33.77 101.37,34.19 100.82,34.19 100.71,34.3 99.33,34.3 v4(99.21,34.43) 99.14,34.35 98.78,34.35 98.6,34.53 98.34,34.53 98.27,34.46 98.27,34.35 98.17,34.25 98.03,34.25 97.94,34.35 97.94,34.76 97.82,34.88 96.88,34.88 96.87,34.89 96.46,34.89 96.41,34.84 94.12,34.84 93.82,34.54 v1(93.82,34.2) ; v1(68.97,33.76) 68.98,33.76 68.98,33.77 68.96,33.77 69.03,33.85 69.03,34.3 69.55,34.82 71.73,34.82 71.78,34.87 72.52,34.87 72.64,34.99 72.97,34.99 73.63,34.33 74.26,34.33 74.54,34.6 74.79,34.6 v4(74.8,34.59) 74.96,34.59 75.2,34.36 75.2,34.12 75.3,34.02 75.44,34.02 75.53,34.12 75.53,34.3 75.66,34.43 76.37,34.43 77.03,33.77 79.9,33.77 80.37,34.24 v1(80.73,34.24) ; v8(105.35,34.25) 105.19,34.09
  IN4 w0.081: 101.79,33.77 104.52,33.77 104.84,34.09 105.19,34.09
  BOTTOM w0.076: UCPU1.AK36 74.7,63.59 v1(74.53,63.42) ; UD10.L7 104.63,33.48 105.35,34.2 v8(105.35,34.25) ; v1(80.73,34.24) 80.73,34.18 79.99,33.45 UD7.L7 ; UD6.L7 68.48,33.27 v1(68.97,33.76) ; v1(93.82,34.2) 93.82,34.02 UD9.L7
DDR_B_MA11: length 131.9
  TOP w0.076: RD54.1 88.24,27.53 v1(88.24,27.88)
  IN1 w0.076: v1(67.56,56.64) 67.52,56.64 66.92,56.04 66.92,54.48 67.3,54.09 67.64,54.09 67.84,53.89
  IN1 w0.16: v1(88.24,27.88) 88.36,27.88 88.49,27.75 88.49,27.52 88.87,27.14 89,27.14 89.15,26.99 89.15,26.39 88.99,26.23 87.12,26.23 86.96,26.07 86.96,25.79 87.12,25.63 89.49,25.63 89.66,25.8 89.66,27.39 89.42,27.63 89.19,27.63 88.59,28.23 88.59,28.62 87.83,29.38 87.83,30.68 87.11,31.39 87.11,31.69 85.82,32.98 85.82,34.6 85.44,34.99 85.44,35.42 85.29,35.57 83.43,35.57 83.26,35.75 82.95,35.75 82.77,35.57 82.14,35.57 81.37,36.34 81.37,36.9 81.37,37.19 81.2,37.36 81.2,38.05 80.46,38.8 80.46,41.69 80.61,41.85 80.61,41.96 79.81,42.76 78.13,42.76 77.97,42.6 77.97,42.24 78.13,42.08 78.63,42.08 78.76,41.94 78.76,41.5 78.66,41.39 78.59,41.39 78.43,41.23 78.43,40.89 78.59,40.73 78.64,40.73 78.76,40.6 78.76,39.82 78.63,39.68 77.73,39.68 77.46,39.94 77.46,42.35 77.06,42.76 75.61,42.76 73.65,44.72 73.43,44.72 73.12,44.41 72.69,44.41 72.57,44.53 72.57,44.74 72.99,45.16 72.99,45.38 72.34,46.04 72.08,46.04 71.21,45.17 70.99,45.17 70.82,45.34 70.82,45.57 71.71,46.46 71.71,46.75 71.71,48.23 71.55,48.4 71.12,48.4 70.76,48.76 70.53,48.76 70.36,48.58 70.36,47.59 70.22,47.45 69.9,47.45 69.76,47.59 69.76,48.92 70.12,49.29 70.12,49.52 69.96,49.68 69.53,49.68 69.16,50.05 69.16,52.57 67.84,53.89
  IN3 w0.076: v4(75.1,28.24) 75.13,28.27 76.02,28.27 76.04,28.24 76.99,28.24 77.14,28.09 77.99,28.09 78.7,27.39 79.76,27.39 80.41,26.73 83.24,26.73 83.56,27.06 83.56,27.42 83.67,27.53 84.99,27.53 85.38,27.92 86.96,27.92 87.12,27.77 87.6,27.77 87.74,27.91 88.21,27.91 v1(88.24,27.88) 88.34,27.77 88.57,27.77 89.07,27.28 92.22,27.28 93,26.5 96.67,26.5 96.96,26.79 96.96,26.9 96.87,27 96.87,27.11 96.97,27.22 97.08,27.22 97.18,27.12 97.29,27.12 97.4,27.23 97.4,27.33 97.3,27.43 97.3,27.54 97.4,27.65 97.51,27.65 97.61,27.55 97.72,27.55 97.83,27.66 97.83,27.77 97.73,27.86 97.73,27.97 97.84,28.08 97.94,28.08 98.04,27.98 98.15,27.98 98.27,28.11 99.6,28.11 v4(99.74,28.24)
  IN4 w0.076: v1(81.12,28.89) 80.41,28.18 77.05,28.18 76.89,28.35 75.2,28.35 v4(75.1,28.24) 75.04,28.18 73.38,28.18 72.3,29.26 71.45,29.26 71.15,29.57 70.24,29.57 v1(69.57,28.89) ; v1(94.2,28.89) 94.84,29.53 95.83,29.53 96.09,29.26 96.94,29.26 98.02,28.18 99.68,28.18 v4(99.74,28.24) 99.84,28.35 101.53,28.35 101.69,28.18 105.05,28.18 v8(105.76,28.89)
  BOTTOM w0.076: v1(67.56,56.64) 67.61,56.69 67.61,58.23 UCPU1.AV47 ; UD6.R7 68.44,30.07 69.57,28.94 v1(69.57,28.89) ; v1(94.2,28.89) 94.2,28.94 93.08,30.07 UD9.R7 ; UD7.R7 79.99,30.05 81.12,28.92 v1(81.12,28.89) ; v8(105.76,28.89) 105.76,28.92 104.63,30.05 UD10.R7
DDR_B_MA12: length 131
  TOP w0.076: v1(85.89,31.11) 85.89,32.29 RD26.1
  IN1 w0.076: 66.21,53.17 66.21,53.49 66.22,53.51 66.22,54.61 66.26,54.65 66.26,57.47 66.39,57.59 66.69,57.59 v8(66.75,57.54)
  IN1 w0.16: 66.21,53.17 66.21,52.25 66.81,51.66 67.06,51.66 67.38,51.98 67.96,51.98 68.1,51.85 68.1,51.17 67.91,50.99 67.11,50.99 66.95,50.83 66.95,50.57 67.11,50.41 68,50.41 68.1,50.3 68.1,50.09 67.79,49.79 67.79,48.97 68.15,48.61 68.54,48.61 68.7,48.45 68.7,48.2 68.54,48.04 67.86,48.04 67.27,48.63 66.69,48.63 66.23,49.09 65.66,49.09 65.48,48.91 65.48,48.54 67.27,46.74 68.57,46.74 69.7,45.61 69.7,45.36 69.54,45.2 69.31,45.2 68.27,46.24 68.04,46.24 67.86,46.06 67.86,45.84 69.06,44.64 70.01,44.64 70.66,43.99 71,43.99 71.37,43.62 71.37,43.12 71.55,42.94 71.8,42.94 71.98,43.12 71.98,43.2 72.14,43.36 73.53,43.36 74.05,42.84 74.05,42.09 74.43,41.71 76.26,41.71 76.41,41.56 76.41,39.87 76.26,39.72 74.58,39.72 74.41,39.55 74.41,39.33 74.59,39.15 74.59,38.67 74.79,38.47 76.09,38.47 76.25,38.31 76.25,37.99 76.09,37.83 75.97,37.83 75.84,37.71 75.84,37.36 77.53,35.67 78.23,35.67 78.4,35.5 78.4,35.07 78.55,34.92 78.99,34.92 79.14,35.07 79.14,35.76 79.3,35.92 79.59,35.92 80.07,35.44 80.07,34.21 80.51,33.77 81.02,33.77 81.97,32.82 83.06,32.82 84.15,31.74 84.82,31.74 85.07,31.99 85.31,31.99 85.89,31.41 v1(85.89,31.11)
  IN3 w0.076: v4(75.33,31.05) 75.33,31.29 75.43,31.39 75.83,31.39 76.19,31.04 83.13,31.04 83.26,31.17 83.26,31.69 83.33,31.76 83.54,31.76 83.61,31.69 83.61,31.08 83.69,31 83.87,31 83.94,31.08 83.94,31.51 84.22,31.79 87.24,31.79 87.32,31.71 87.32,31.51 87.24,31.43 85.97,31.43 85.89,31.36 v1(85.89,31.11) 86.12,30.89 86.65,30.89 86.78,30.75 88.95,30.75 89.84,29.86 90.27,29.86 90.37,29.96 90.65,29.96 90.8,30.11 91.74,30.11 92.15,30.52 92.95,30.52 93.14,30.34 93.14,30.11 93.46,29.79 95.71,29.79 95.94,30.02 95.94,30.2 96.4,30.66 96.4,30.94 96.65,31.19 96.78,31.19 97.31,31.72 99.12,31.72 99.74,31.1 v4(99.99,31.1)
  IN4 w0.076: v1(69.66,31.66) 70.36,32.36 71.42,32.36 71.81,31.98 74.55,31.98 74.99,31.54 74.99,31.37 75.25,31.1 75.28,31.1 v4(75.33,31.05) 75.43,31.15 76.02,31.15 76.25,30.92 79.61,30.92 79.89,31.2 81.07,31.2 81.22,31.35 v1(81.22,31.66) ; v1(105.86,31.66) 105.86,31.35 105.68,31.18 104.77,31.18 104.52,30.92 100.7,30.92 100.59,31.04 100.06,31.04 v4(99.99,31.1) 99.89,31.1 99.63,31.37 99.63,31.54 99.19,31.98 96.47,31.98 96.15,32.3 94.93,32.3 v1(94.3,31.66)
  BOTTOM w0.076: UCPU1.AU47 67.71,59.03 67.71,58.97 67.42,58.68 67.42,57.73 67.28,57.59 66.8,57.59 v8(66.75,57.54) ; v1(81.22,31.66) 80.79,31.23 80.21,31.23 79.99,31.44 UD7.N7 ; UD10.N7 104.63,31.6 105,31.23 105.42,31.23 v1(105.86,31.66) ; v1(69.66,31.66) 69.2,31.2 68.8,31.2 68.43,31.57 UD6.N7 ; v1(94.3,31.66) 93.92,31.28 93.36,31.28 93.07,31.57 UD9.N7
DDR_B_MA13: length 142
  TOP w0.076: RD46.1 92.51,25.11 v1(92.44,25.03)
  IN1 w0.076: 79.72,59.47 79.29,59.89 79.29,60.56 78.28,61.56 78.28,63.14 77.41,64.02 v1(76.32,64.02)
  IN1 w0.16: v1(92.44,25.03) 92.91,25.03 94.28,26.41 95.59,26.41 96,26 99.11,26 99.26,26.15 99.26,26.56 99.11,26.71 98.41,26.71 98.29,26.84 98.29,28.19 97.78,28.69 97.78,29.07 97.95,29.24 97.95,30.29 98.1,30.44 98.37,30.44 98.52,30.29 98.52,29.6 98.67,29.45 99.33,29.45 99.49,29.6 99.49,30.06 99.62,30.19 100.76,30.19 100.93,30.37 100.93,32.02 100.02,32.93 100.02,34.59 99.99,34.61 99.99,35.12 101.87,37 101.87,44.69 97.83,48.73 97.68,48.88 95.68,48.88 95.32,49.24 94.96,49.6 90.55,49.6 90.17,49.21 87.96,49.21 87.43,49.74 87.43,50 83.41,54.02 83.41,57.59 81.66,59.35 79.84,59.35 79.72,59.47
  IN3 w0.076: v4(101.16,26.35) 101.04,26.23 99.66,26.23 99.59,26.15 99.59,25.97 99.66,25.9 101.06,25.9 101.14,25.82 101.14,25.64 101.06,25.57 98.9,25.57 98.83,25.49 98.83,25.29 98.9,25.21 100.86,25.21 100.93,25.13 100.93,24.94 100.86,24.86 92.61,24.86 v1(92.44,25.03) 91.68,25.79 84.05,25.79 83.35,25.1 78.7,25.1 77.41,26.38 77.06,26.38 77.05,26.38 76.55,26.38 v4(76.52,26.35)
  IN4 w0.076: v1(107.11,27.22) 107.11,26.91 106.43,26.24 104.35,26.24 104.23,26.35 v4(101.16,26.35) 101.04,26.23 97.71,26.23 96.28,27.66 95.82,27.66 v1(95.4,27.24) ; v1(70.76,27.24) 71.18,27.66 71.64,27.66 73.1,26.2 76.37,26.2 v4(76.52,26.35) 76.63,26.45 77.03,26.45 77.13,26.35 79.59,26.35 79.71,26.24 81.59,26.24 82.47,27.11 v8(82.47,27.22)
  BOTTOM w0.076: v1(107.11,27.22) 107.83,27.94 UD10.T3 ; UD9.T3 96.27,28.22 95.4,27.34 v1(95.4,27.24) ; UCPU1.AK33 76.75,63.59 v1(76.32,64.02) ; v1(70.76,27.24) 70.76,27.34 71.63,28.22 UD6.T3 ; v8(82.47,27.22) 83.1,27.85 83.1,29.18 UD7.T3
DDR_B_MA14: length 137.3
  TOP w0.076: RD34.1 85.39,26.05 v1(85.77,26.43)
  IN1 w0.076: v1(68.35,60.15) 68.28,60.09 68.28,59.77 67.84,59.32 67.11,59.32 66.93,59.5 66.52,59.5 64.89,57.87 64.89,54.11 64.61,53.84
  IN1 w0.157: 64.02,53.25 64.61,53.84
  IN1 w0.16: 64.02,53.25 64.02,51.35 64.23,51.14 64.23,50.39 64.02,50.19 64.02,47.03 69.84,41.21 69.84,39.59 69.35,39.09 69.35,38.89 69.53,38.71 69.75,38.71 69.96,38.91 70.19,38.91 70.36,38.74 70.36,38.49 70.04,38.17 70.04,38.02 70.17,37.88 70.58,37.88 70.94,37.53 71.39,37.53 71.53,37.39 71.53,37.06 71.24,36.77 71.24,36.54 71.47,36.31 71.47,35.95 71.62,35.8 71.85,35.8 72.61,36.56 73.04,36.56 73.31,36.3 73.31,35.71 73.15,35.55 72.85,35.55 72.69,35.39 72.69,35.1 72.85,34.94 73.15,34.94 73.3,34.79 73.3,34.25 73.04,34 72.14,34 71.98,33.84 71.98,33.55 72.14,33.39 73.17,33.39 73.62,33.83 73.84,33.83 73.94,33.74 73.94,33.33 74.19,33.08 74.19,32.65 74.31,32.52 74.75,32.52 74.8,32.58 75.05,32.58 75.23,32.75 75.23,33.15 75.39,33.31 75.65,33.31 75.89,33.08 75.89,32.58 76.11,32.35 76.11,31.58 76.41,31.28 76.65,31.28 76.96,31.58 77.46,31.58 77.62,31.42 77.62,30.76 77.8,30.57 78.09,30.57 78.25,30.73 78.25,31.44 78.41,31.6 79.17,31.6 79.31,31.45 79.31,31.26 78.94,30.89 78.94,30.7 79.91,29.73 83,29.73 83.88,28.85 84.37,28.85 84.45,28.77 85.06,28.77 85.34,28.49 85.34,27.99 85.18,27.83 84.86,27.83 84.7,27.67 84.7,27.39 84.86,27.24 85.15,27.24 85.31,27.08 85.31,26.77 85.15,26.61 82.88,26.61 82.72,26.45 82.72,26.21 82.88,26.05 85.39,26.05 v1(85.77,26.43)
  IN3 w0.076: v4(99.61,26.91) 99.59,26.91 98.11,25.44 92.91,25.44 92.04,26.31 87.22,26.31 86.75,26.78 86.13,26.78 v1(85.77,26.43) 85.6,26.26 83.94,26.26 83.36,25.68 78.87,25.68 77.53,27.01 75.48,27.01 75.28,26.81 75.28,26.58 74.82,26.12 73.83,26.12 73.76,26.2 73.76,26.56 73.83,26.63 74.72,26.63 74.8,26.71 v4(74.8,26.89)
  IN4 w0.076: v8(81.17,27.22) 80.73,26.77 79.94,26.77 79.69,27.03 75.52,27.03 75.41,26.91 74.82,26.91 v4(74.8,26.89) 74.67,26.76 73.3,26.76 71.97,28.08 70.17,28.08 69.46,27.37 v1(69.46,27.27) ; v1(94.1,27.27) 94.1,27.37 94.93,28.19 96.5,28.19 97.93,26.76 99.46,26.76 v4(99.61,26.91) 100.05,26.91 100.16,27.03 104.31,27.03 104.57,26.77 105.37,26.77 v1(105.81,27.22)
  BOTTOM w0.076: UCPU1.AR46 68.53,60.34 v1(68.35,60.15) ; UD10.T7 104.63,28.42 105.81,27.24 v1(105.81,27.22) ; v1(94.1,27.27) 94.25,27.42 94.25,27.52 93.07,28.7 UD9.T7 ; UD7.T7 79.99,28.55 81.17,27.37 v8(81.17,27.22) ; UD6.T7 68.43,28.76 69.62,27.57 69.62,27.42 v1(69.46,27.27)
DDR_B_MA15: length 132.6
  TOP w0.076: RD28.1 88.28,31.88 v1(88.35,31.88)
  IN1 w0.16: v1(88.35,31.88) 88.52,32.05 88.52,32.31 88.38,32.45 88.38,32.63 87.81,33.19 87.1,33.19 86.89,33.4 86.89,33.61 87.05,33.77 87.8,33.77 87.99,33.95 87.99,34.11 87.77,34.32 87.22,34.32 87.09,34.46 87.09,34.63 87.52,35.06 87.52,35.48 87.84,35.8 87.84,36.76 88.23,37.16 88.23,37.35 87.14,38.44 87.14,38.72 87.43,39.01 87.43,42.85 84.99,45.3 84.68,45.3 84.38,44.99 84.14,44.99 83.99,45.15 83.99,45.89 83.84,46.03 83.51,46.03 83.36,45.89 83.36,45.12 83.23,44.99 82.93,44.99 82.8,45.12 82.8,45.89 82.65,46.03 81.87,46.03 81.52,45.68 81.35,45.68 81.21,45.82 81.04,45.82 80.16,44.95 78.93,44.95 78.6,45.28 78.35,45.28 78.02,44.95 76.71,44.95 76.55,45.11 76.55,45.34 76.71,45.5 77.81,45.5 77.93,45.63 77.93,46.67 77.81,46.8 77.45,46.8 77.25,47 77.03,47 76.83,46.8 76.52,46.8 76.37,46.96 76.37,47.02 76.37,47.02 76.37,47.12 76.64,47.4 76.64,47.56 76.3,47.9 76.15,47.9 75.65,47.4 75.65,47.22 75.94,46.93 75.94,46.47 75.61,46.13 75.33,46.13 74.87,46.59 74.87,47.4 76.2,48.72 76.31,48.83 76.31,49.01 76.07,49.24 75.9,49.24 74.45,47.8 74.23,47.8 74.03,47.99 74.03,48.22 75.03,49.21 75.03,49.8 75.03,49.81 75.03,49.81 75.29,50.06 75.29,51.31 74.65,51.95 74.65,52.49 74.39,52.74 74.11,52.74 73.03,53.82 73.03,54.33 72.61,54.75 72.61,59.37 72.16,59.83 72.16,60.06 72.03,60.19 71.7,60.19 71.5,59.98 70.84,59.98 70.33,59.48 70.33,55.76 70.18,55.61 69.97,55.61 69.82,55.76 69.82,56.14 69.66,56.3 69.5,56.3 69.34,56.46 69.34,59.02 69.79,59.47 69.79,61.24 69.63,61.4 69.36,61.4 v1(69.29,61.33)
  IN3 w0.076: v4(75.58,31.99) 75.92,31.99 76.4,31.51 79.52,31.51 80.75,32.74 81.99,32.74 82.54,32.19 88.04,32.19 v1(88.35,31.88) 88.39,31.84 88.84,31.84 89.96,30.72 90.49,30.72 90.98,31.2 93.21,31.2 93.47,30.94 95.78,30.94 96.2,31.37 96.2,31.72 96.74,32.26 98.69,32.26 99.11,32.68 99.77,32.68 100.22,32.22 v4(100.22,31.99)
  IN4 w0.076: v1(105.49,32.24) 105.19,32.24 104.95,31.99 104.49,31.99 104.29,31.79 104.29,31.69 104.38,31.59 104.38,31.48 104.28,31.38 100.98,31.38 100.9,31.46 100.55,31.46 100.48,31.53 100.48,31.64 100.6,31.76 100.6,31.89 100.5,31.99 v4(100.22,31.99) 100.22,32.07 99.79,32.5 98.97,32.5 98.93,32.46 96.74,32.46 96.47,32.73 94.13,32.73 v1(93.7,32.3) ; v1(80.85,32.24) 80.55,32.24 80.26,31.94 79.8,31.94 79.19,31.33 76.47,31.33 76.12,31.69 75.76,31.69 75.58,31.87 v4(75.58,31.99) 75.47,32.11 75.47,32.25 75.18,32.53 74.37,32.53 74.29,32.45 72,32.45 71.67,32.78 69.54,32.78 v8(69.06,32.3)
  BOTTOM w0.076: v1(80.85,32.24) 80.85,32.64 80.72,32.78 80.3,32.78 UD7.M7 ; v1(93.7,32.3) 93.52,32.47 UD9.M7 ; UD6.M7 68.89,32.47 v8(69.06,32.3) ; v1(105.49,32.24) 105.1,32.63 104.79,32.63 UD10.M7 ; v1(69.29,61.33) 69.26,61.33 68.92,60.99 UCPU1.AP46
DDR_B_RAS#: length 134
  TOP w0.076: v1(89.21,33.61) 88.45,34.38 RD64.1
  IN1 w0.076: v8(75.46,62.6) 75.46,62.7 75.63,62.87 75.81,62.87 75.9,62.78 75.9,59.79 76.75,58.94 76.75,58.94 76.75,58.77 76.76,58.76
  IN1 w0.16: 76.76,58.76 76.76,58.35 76.92,58.19 77.56,58.19 77.72,58.03 77.72,57.68 77.56,57.52 76.78,57.52 76.63,57.37 76.63,57.07 76.76,56.93 76.76,56.18 76.47,55.89 76.47,55.69 76.76,55.41 76.76,53.86 77.57,53.05 77.92,53.05 78.1,52.87 78.1,52.51 78.48,52.13 78.82,52.13 80.17,50.79 80.84,50.79 82.1,49.53 84.31,49.53 84.89,48.95 84.89,48.69 86.91,46.68 90.07,46.68 90.4,46.34 96.13,46.34 96.29,46.19 96.29,45.86 96.1,45.68 95.43,45.68 95.29,45.53 95.29,45.18 95.43,45.04 96.1,45.04 96.29,44.85 96.29,44.58 96.1,44.4 95.43,44.4 95.29,44.25 95.29,42.23 95.03,41.98 94.62,41.98 94.51,42.09 94.51,42.48 94.31,42.68 93.14,42.68 92.93,42.47 92.93,42.24 93.15,42.02 93.83,42.02 94.09,41.77 94.09,39.5 93.9,39.31 93.9,39.03 94.06,38.86 94.06,38.45 93.85,38.24 93.85,38.02 94.06,37.81 94.06,35.22 93.91,35.06 93.39,35.06 93.24,35.22 93.24,35.57 93.06,35.75 92.48,35.75 92.33,35.9 92.33,36.18 92.48,36.33 92.92,36.33 93.07,36.49 93.07,37.1 93.14,37.16 93.14,38.85 93.34,39.05 93.34,39.33 93.14,39.54 93.14,41.24 93.03,41.34 92.3,41.34 92.17,41.21 92.17,38.14 92.58,37.73 92.58,36.94 92.45,36.82 92.32,36.82 92.15,37 91.94,37 91.41,36.46 91.18,36.46 90.99,36.65 90.99,36.88 91.41,37.3 91.41,37.68 91.28,37.81 90.72,37.81 90.56,37.65 90.56,36.98 90.42,36.84 90.06,36.84 89.78,36.56 89.78,36.56 89.26,36.04 89.26,34.7 89.04,34.48 89.04,33.79 v1(89.21,33.61)
  IN3 w0.076: v4(101.06,33.34) 100.53,33.34 100.11,33.75 96.88,33.75 96.29,33.16 93.59,33.16 93.26,33.49 91.58,33.49 91.2,33.11 90.83,33.11 90.38,33.57 89.76,33.57 89.46,33.26 89.32,33.26 89.21,33.38 v1(89.21,33.61) 86.44,33.61 85.84,33.01 83.15,33.01 82.61,33.55 80.17,33.55 80.03,33.41 76.32,33.41 v4(76.25,33.34)
  IN4 w0.076: v1(71.09,34.19) 71.09,33.87 71.19,33.77 73.17,33.77 73.32,33.92 73.95,33.92 74.53,33.35 75.14,33.35 75.31,33.52 75.5,33.52 76.01,33.01 76.17,33.01 76.25,33.08 v4(76.25,33.34) 80.2,33.34 80.38,33.52 81.33,33.52 v1(82.01,34.2) ; v1(106.62,34.2) 105.94,33.52 105.02,33.52 104.84,33.34 v4(101.06,33.34) 100.93,33.21 100.68,33.21 100.07,33.82 95.83,33.82 95.73,33.92 v1(95.73,34.19)
  BOTTOM w0.076: UD7.J3 82.68,34.87 v1(82.01,34.2) ; v1(106.62,34.2) 107.29,34.87 UD10.J3 ; UD6.J3 71.32,34.87 71.09,34.64 v1(71.09,34.19) ; v8(75.46,62.6) 75.77,62.29 UCPU1.AM35 ; UD9.J3 95.91,34.87 95.65,34.61 95.65,34.27 v1(95.73,34.19)
DDR_B_WE#: length 139.3
  TOP w0.076: RD72.1 90.23,34.51 v1(89.76,34.04)
  IN1 w0.076: v1(75.46,63.23) 75.66,63.23 76.06,62.84 76.06,59.91 76.29,59.68 76.29,59.67 76.33,59.64
  IN1 w0.16: 76.33,59.64 76.44,59.52 76.78,59.52 77.03,59.27 77.03,58.72 77.19,58.56 77.86,58.56 78.02,58.4 78.02,57.98 78.12,57.87 78.35,57.87 78.51,57.71 78.51,57.35 78.35,57.19 77.19,57.19 77.03,57.03 77.03,54.05 77.64,53.44 77.87,53.44 77.95,53.52 77.95,54.19 78.09,54.34 78.32,54.34 78.46,54.2 78.46,53.66 78.76,53.35 78.76,53.15 78.43,52.82 78.43,52.65 78.61,52.47 78.98,52.47 80.31,51.14 80.99,51.14 82.24,49.88 84.45,49.88 85.24,49.09 85.24,48.84 87.05,47.03 90.21,47.03 90.55,46.7 96.28,46.7 96.64,46.34 96.64,44.16 96.48,44.01 95.8,44.01 95.65,43.86 95.65,43.52 95.8,43.37 96.51,43.37 96.67,43.22 96.67,42.35 96.51,42.2 95.75,42.2 95.64,42.09 95.18,41.63 94.62,41.63 94.46,41.47 94.46,41.19 94.61,41.03 95.04,41.03 95.19,40.88 95.19,40.63 95.04,40.47 94.58,40.47 94.44,40.33 94.44,39.47 94.62,39.29 94.62,38.99 94.41,38.79 94.41,34.87 94.23,34.68 93.29,34.68 93.14,34.54 93.14,34.22 93.72,33.64 95.52,33.64 95.68,33.49 95.68,33.13 95.52,32.98 93.67,32.98 92.68,33.97 91.41,33.97 91.28,34.1 90.77,34.1 90.65,33.97 90.47,33.97 90.19,34.25 90.19,34.46 90.57,34.84 90.57,35.04 90.14,35.47 90.14,35.62 90.56,36.04 90.56,36.35 90.42,36.49 90.21,36.49 89.93,36.21 89.92,36.21 89.61,35.9 89.61,35.29 89.81,35.09 89.81,34.75 89.42,34.36 89.42,34.11 89.49,34.04 v1(89.76,34.04)
  IN3 w0.076: v4(75.79,33.79) 75.64,33.95 75.64,34.33 75.71,34.4 76.11,34.4 76.87,33.64 79.88,33.64 80,33.76 82.76,33.76 83.3,33.22 85.6,33.22 86.42,34.04 v1(89.76,34.04) 89.81,34.09 89.81,35.14 89.94,35.27 90.16,35.27 90.29,35.14 90.29,34.28 90.57,34 91.32,34 91.5,33.82 93.42,33.82 93.54,33.69 93.88,33.69 93.96,33.62 93.96,33.44 94.03,33.36 94.19,33.36 94.26,33.44 94.26,33.62 94.34,33.69 94.49,33.69 94.57,33.62 94.57,33.44 94.64,33.36 94.8,33.36 94.87,33.44 94.87,33.62 94.95,33.69 95.1,33.69 95.18,33.62 95.18,33.44 95.25,33.36 95.41,33.36 95.48,33.44 95.48,33.62 95.56,33.69 95.71,33.69 95.79,33.62 95.79,33.44 95.86,33.36 96.01,33.36 96.09,33.44 96.09,33.62 96.17,33.69 96.51,33.69 96.79,33.97 100.48,33.97 v4(100.63,33.82)
  IN4 w0.076: v1(81.38,34.2) 81.38,33.92 81.25,33.79 80.28,33.79 80.03,33.54 76.85,33.54 76.65,33.75 75.83,33.75 v4(75.79,33.79) 75.25,33.79 75.01,33.55 74.61,33.55 74.03,34.12 73.17,34.12 73.07,34.02 71.85,34.02 71.27,34.61 70.23,34.61 v8(69.82,34.2) ; v1(105.99,34.23) 105.99,33.95 105.84,33.79 104.92,33.79 104.67,33.54 101.59,33.54 101.44,33.69 101.44,33.83 101.29,33.99 101.15,33.99 100.91,33.74 100.71,33.74 v4(100.63,33.82) 100.42,34.03 96.5,34.03 95.93,34.61 94.87,34.61 v1(94.46,34.2)
  BOTTOM w0.076: UD9.L3 95.39,33.27 v1(94.46,34.2) ; v1(105.99,34.23) 105.99,33.74 106.62,33.11 107.67,33.11 UD10.L3 ; v8(69.82,34.2) 70.75,33.27 UD6.L3 ; v1(81.38,34.2) 81.38,33.46 81.73,33.11 83.03,33.11 UD7.L3 ; v1(75.46,63.23) 75.81,63.59 UCPU1.AK35
DDR_CHA_EN: length 29.6
  TOP w0.102: v3(119.81,73.06) v2(120.35,73.61)
  IN4 w0.076: v3(119.81,73.06) 119.78,73.04 119.78,73.01 119.32,72.56 116.14,72.56 115.21,73.48 112.59,73.48 111.25,74.82 99.22,74.82 99.07,74.97 97.82,74.97 v4(97.1,74.24)
  GND5 w0.076: v4(97.1,74.24) 97.1,74.61 v5(97.02,74.69)
  BOTTOM w0.102: UCPU1.J1 96.83,74.88 v5(97.02,74.69) ; RH440.1 117.95,71.72 RH442.1 118.08,72.26 118.35,72.53 119.32,72.53 119.81,73.01 v3(119.81,73.06)
DDR_CHB_EN: length 25.5
  IN4 w0.076: v4(96.5,74.23) 97.44,75.17 99.27,75.17 99.45,74.99 111.33,74.99 112.61,73.71 116.34,73.71 v4(116.99,73.06)
  GND5 w0.076: v4(116.99,73.06) 117.04,73.11 v5(117.47,73.11) ; v5(96.15,74.51) 96.22,74.51 v4(96.5,74.23)
  BOTTOM w0.102: UCPU1.K3 95.49,74.17 95.83,74.51 v5(96.15,74.51) ; v5(117.47,73.11) 117.49,73.14 RH443.1 117.65,72.73 RH441.1
DDR_PG_CNTL: length 8
  BOTTOM w0.076: 54.79,58.2 58.85,58.2 59.32,58.68 UCPU1.AV61
  BOTTOM w0.102: UC1.2 53.39,59.52 v2(54.33,58.59) 54.71,58.2 54.79,58.2
DDR_VREF: length 7.2
  TOP w0.102: v2(134.79,41.36) 133.41,41.36 R1187.1
  TOP w0.254: R1187.1 CA15.1 131.74,43.01 R1186.2 CA13.2 130.78,43.04 UA1.40
DELAY_VR_AND_ALL_SYS: length 5.8
  TOP w0.102: R1290.1 R1295.1 159.56,50.91 160.1,50.91 160.28,50.74 160.28,50.51 160.39,50.4 U691.1 161.24,50.4 161.79,50.95 161.79,51.63 161.93,51.76 U690.4
DEVSLP0: length 103.4
  TOP w0.102: v2(164.5,45.86) 163.88,45.86 v1(163.6,46.14) 163.84,46.38 R1366.2
  IN2 w0.076: v1(161.37,61.63) 160.48,62.52 158.59,62.52 157.88,63.23 157.88,63.72 157.54,64.06 157.54,64.62 157.22,64.94 156.46,64.94 154.96,66.43 151.78,66.43 151.02,65.67 150.11,65.67 149.03,66.75 145.69,66.75 145.12,67.32 144.29,67.32 143.47,68.15 142.12,68.15 141.83,68.44 139,68.44 138.03,67.48 137.02,67.48 136.6,67.89 133.31,67.89 132.26,68.94 127.97,68.94 125.06,66.03 121.95,66.03 118.91,69.06 118.29,69.06 117.39,68.16 111.08,68.16 110.4,68.84 110.4,69.15 110.19,69.35 106.8,69.35 106.05,70.1 104.95,70.1 104.88,70.04 101.42,70.04 100.25,71.21 99.02,71.21 98.41,71.82 94.97,71.82 94.53,72.25 v4(94.53,72.38)
  GND5 w0.076: v5(94.28,71.88) 94.28,72.12 v4(94.53,72.38)
  BOTTOM w0.076: UCPU1.P2 95.82,71.88 95.5,71.56 95.32,71.56 95.17,71.41 94.81,71.41 94.67,71.55 94.55,71.55 94.28,71.82 v5(94.28,71.88)
  BOTTOM w0.102: JSATA1.44 166.28,48.82 164.68,47.22 164.68,46.48 164.33,46.14 v1(163.6,46.14) 163.32,46.42 163.32,55.03 162.55,55.79 162.55,60.46 161.39,61.63 v1(161.37,61.63)
DH_+1.2V: length 7.1
  IN1 w1.016: 49.73,21.17 49.35,20.79 44.77,20.79 44.01,21.55 44.01,22.44
  vias: v1(42.92,23.18) v1(43.56,23.18) v1(49.03,21.93) v1(49.05,22.69) v2(42.73,23.94)
DISP_CEC: length 3.5
  BOTTOM w0.102: JMDP1.6 219.83,72.8 219.29,72.26 v2(218.89,72.26) 218.13,72.26 218,72.14 RV4.1
DISP_CLK_AUXP_CONN: length 30.1
  TOP w0.102: UV1.4 196,75.08 195.8,74.88 v6(195.61,74.88) 195.61,75.43 195.33,75.7 RV3.1
  GND1 w0.076: v4(195.61,74.26) v6(195.61,74.88)
  IN1 w0.076: v4(195.61,74.26) 195.71,74.16 196.76,74.16 197.72,73.19 207.08,73.19 207.67,72.6 215.72,72.6 218.51,69.82 v1(219.35,69.82)
  BOTTOM w0.102: v1(219.35,69.82) 219.56,69.61 219.72,69.61 219.91,69.8 JMDP1.16
DISP_DAT_AUXN_CONN: length 29.7
  TOP w0.102: RV2.1 v6(195.6,73.04) 195.69,73.13 UV1.7
  GND1 w0.076: v4(195.61,73.65) 195.6,73.63 v6(195.6,73.04)
  IN1 w0.076: v8(219.35,69.18) 218.87,69.66 218.44,69.66 215.66,72.45 207.61,72.45 207.02,73.04 197.66,73.04 196.69,74 195.97,74 v4(195.61,73.65)
  BOTTOM w0.102: JMDP1.18 219.95,69.2 219.75,69.4 219.57,69.4 v8(219.35,69.18)
DISP_HPD_SINK: length 16.4
  TOP w0.102: v3(217.44,65.11) 216.16,65.11 RV10.1 214.66,63.61 QV2.1
  IN4 w0.076: v1(219.21,74.85) 217.44,73.09 v3(217.44,65.11)
  BOTTOM w0.102: v1(219.21,74.85) 220.06,74 JMDP1.2
DISPOFF#: length 13
  TOP w0.102: D72.1 169.12,74.79 R540.1 167.88,76.03 165.93,76.03 165.12,76.85 161.2,76.85 160.18,77.86 v2(160.18,78.14) 160.18,78.42 v1(160.4,78.64)
  BOTTOM w0.122: v1(160.4,78.64) 160.25,78.79 JLVDS1.13
DL_+1.2V: length 8.6
  IN4 w1.016: 43.67,22.16 43.67,21.51 44.65,20.54 49.35,20.54 50.67,21.86
  vias: v1(41.93,22.47) v1(52.88,21.86) v1(53.51,21.86) v8(42.59,22.47)
DMIC_CLK: length 80.7
  TOP w0.102: RA5.1 RA9.1 132.6,47.33 v6(133.03,47.76) ; v1(185.63,71.7) 184.73,70.8 184.73,66.52 178.76,60.55 v2(178.76,59.68) 178.76,58.74 178.43,58.41 178.43,54.18 177.06,52.81 174.04,52.81 v3(173.72,53.12)
  GND1 w0.076: v6(133.03,47.76) 133.28,47.76 v4(133.46,47.59)
  IN4 w0.076: v4(133.46,47.59) 133.46,47.72 133.99,48.25 133.99,48.4 134.3,48.7 134.81,48.7 135.3,48.21 145.84,48.21 146.04,48.01 147.44,48.01 147.63,47.82 148.49,47.82 149.27,48.59 170.35,48.59 171.13,47.82 174.44,47.82 174.92,48.3 174.92,52.39 174.49,52.82 173.93,52.82 173.72,53.04 v3(173.72,53.12)
  BOTTOM w0.102: MD50.6 183.78,73.12 R1342.1 183.78,73.05 185.12,71.7 v1(185.63,71.7)
DMIC_CLK_CODEC: length 136.7
  TOP w0.102: RA9.2 134.16,47.33 v1(134.34,47.16)
  IN1 w0.076: v4(72,25.46) 70.84,26.63 68.6,26.63 66.82,28.41 55.6,28.41 55.1,28.91 54.54,28.91 53.52,29.92 53.03,29.92 52.79,30.16 51.92,30.16 51.43,30.65 51.05,30.65 50.26,29.86 49.85,29.86 48.43,28.44 45.51,28.44 44.27,27.19 42.69,27.19 42.49,27.39 41.83,27.39 41.47,27.75 40.53,27.75 39.75,28.54 38.48,28.54 38.2,28.26 31.59,28.26 30.68,27.34 30.68,26.45 29.61,25.39 28.42,25.39 28.14,25.67 26.21,25.67 25.72,26.15 23.62,26.15 23.34,26.43 22.04,26.43 21.61,26 v3(21.61,25.77)
  IN2 w0.076: v4(72,25.46) 72.33,25.79 73.26,25.79 73.9,25.16 77.87,25.16 78.3,25.59 90.06,25.59 90.37,25.9 93.39,25.9 94.28,25.01 103.37,25.01 104.62,26.25 111.93,26.25 117.55,31.86 117.55,35.27 v1(117.75,35.47)
  BOTTOM w0.102: v3(21.61,25.77) 21.6,25.76 JIOL1.32 ; v1(117.75,35.47) 117.43,35.79 117.43,39.7 119.07,41.34 122.11,41.34 122.72,41.95 126.5,41.95 131.81,47.26 134.23,47.26 v1(134.34,47.16)
DMIC_CLK_DSP: length 2.3
  TOP w0.102: UA1.47 129.75,46.54 130.54,47.33 RA5.2
DMIC_CLK_R: length 7.7
  TOP w0.102: v1(182.73,77.95) 182.95,77.74 v2(182.95,75.45) v1(182.95,74.87)
  BOTTOM w0.102: MC1133.1 R1342.2 182.86,74.78 v1(182.95,74.87) ; v1(182.73,77.95) 182.91,78.13 182.91,78.84 182.74,79.01 JLVDS2.6
DMIC_DAT: length 89.5
  TOP w0.102: v6(133.1,48.73) 132.6,48.22 RA10.1 RA6.1 ; v1(183.71,78.54) 183.71,73.8 184.3,73.22 v1(186.38,73.22) 186.38,71.54 185.17,70.33 v2(185.17,67.41) 185.17,66.57 179.13,60.53 179.13,58.71 178.71,58.29 178.71,54.06 177.1,52.46 v3(173.71,52.46)
  GND1 w0.076: v6(133.1,48.73) 133.22,48.73 v4(133.55,48.4)
  IN4 w0.076: v4(133.55,48.4) 134.03,48.88 134.88,48.88 135.38,48.39 145.14,48.39 145.64,48.88 146.92,48.88 147.8,48.01 148.43,48.01 149.19,48.77 170.43,48.77 171.2,47.99 174.37,47.99 174.75,48.37 174.75,52.31 174.44,52.62 173.87,52.62 v3(173.71,52.46)
  BOTTOM w0.102: JLVDS2.5 183.24,79 v1(183.71,78.54) ; MD50.4 185.68,73.63 185.62,73.57 MC1210.1 186.28,73.11 v1(186.38,73.22)
DMIC_DAT_CODEC: length 135.5
  TOP w0.102: RA10.2 133.73,48.22 v1(134.16,47.79)
  IN1 w0.076: v4(71.33,25.48) 71.33,25.88 70.76,26.45 68.49,26.45 66.71,28.23 55.52,28.23 55.02,28.73 54.46,28.73 53.45,29.74 52.95,29.74 52.72,29.98 52.39,29.98 52.09,29.68 49.93,29.68 48.51,28.26 45.59,28.26 44.34,27.01 42.56,27.01 42.36,27.22 41.73,27.22 41.37,27.57 40.46,27.57 39.67,28.36 38.55,28.36 38.27,28.08 31.67,28.08 30.86,27.27 30.86,26.38 29.69,25.21 28.34,25.21 28.06,25.49 26.13,25.49 25.65,25.97 23.62,25.97 v1(23.41,25.77)
  IN2 w0.076: v1(117.11,35.47) 117.37,35.22 117.37,31.97 111.83,26.43 104.54,26.43 103.3,25.18 94.35,25.18 93.46,26.07 90.29,26.07 89.99,25.77 78.23,25.77 77.8,25.34 73.97,25.34 73.34,25.97 71.83,25.97 v4(71.33,25.48)
  BOTTOM w0.102: v1(134.16,47.79) 134.16,47.66 133.95,47.46 131.73,47.46 126.42,42.15 122.63,42.15 122.02,41.54 118.94,41.54 117.1,39.7 v2(117.1,39.09) 117.1,35.48 v1(117.11,35.47) ; JIOL1.34 22.1,25.47 22.63,26 23.18,26 v1(23.41,25.77)
DMIC_DAT_DSP: length 2.4
  TOP w0.102: UA1.48 129.61,47.04 RA6.2
DP_CBL_DET: length 7.5
  TOP w0.102: UV1.1 198.24,77.03 198.69,76.58 v1(198.69,76.14)
  BOTTOM w0.102: RV8.1 v2(201.82,74.52) 200.21,76.14 v1(198.69,76.14)
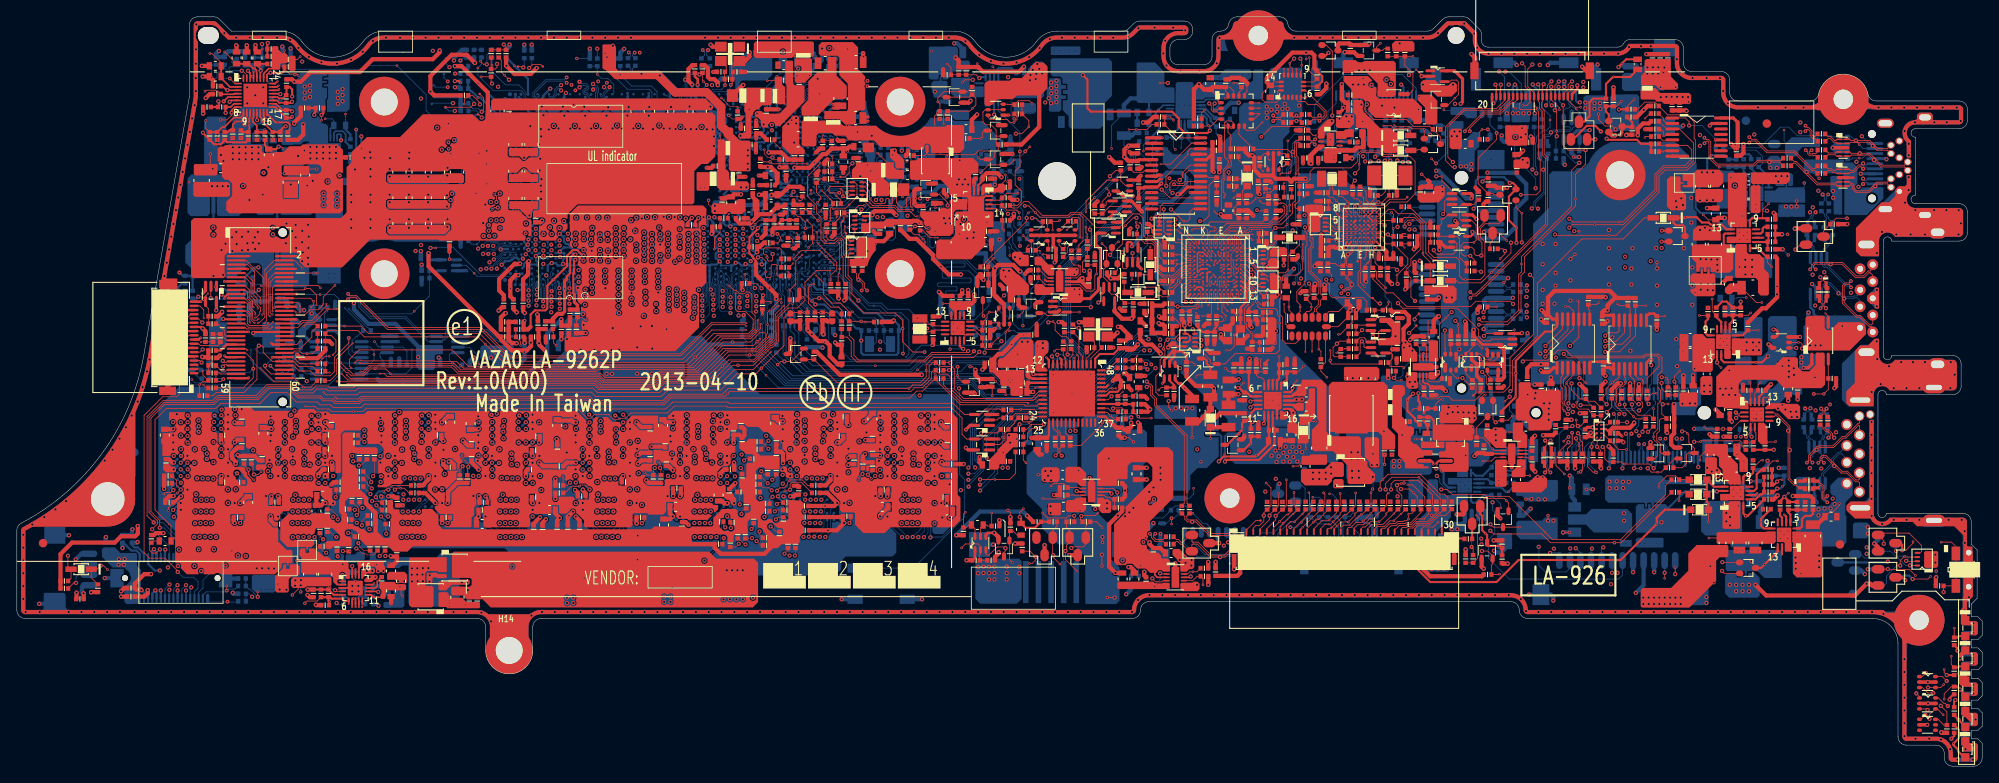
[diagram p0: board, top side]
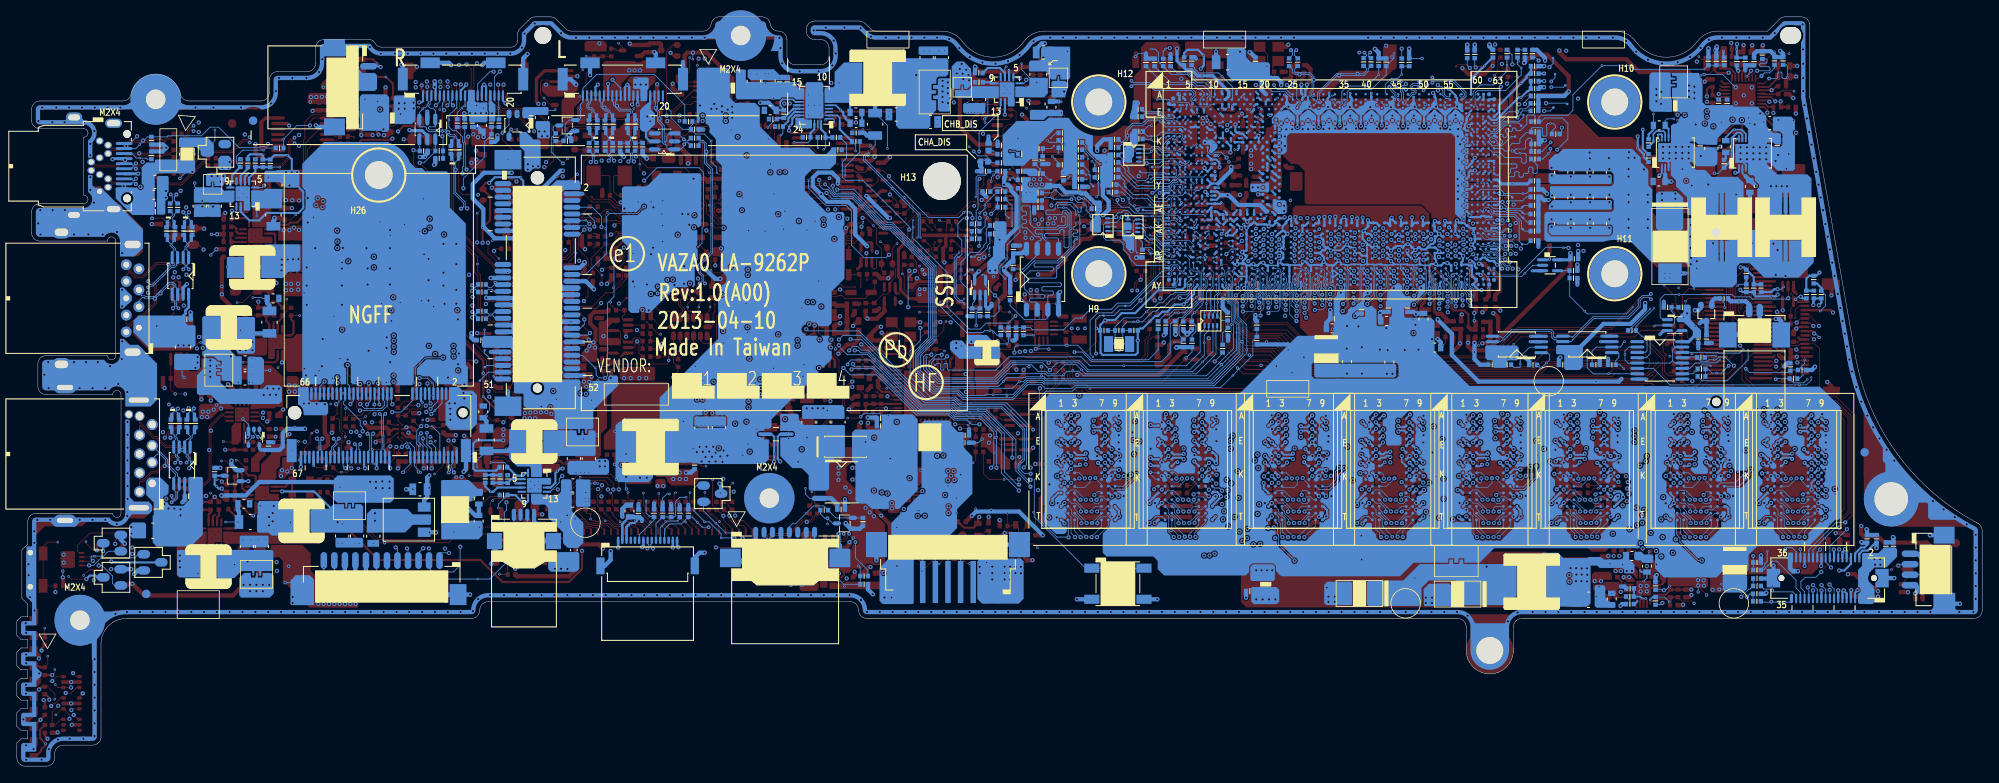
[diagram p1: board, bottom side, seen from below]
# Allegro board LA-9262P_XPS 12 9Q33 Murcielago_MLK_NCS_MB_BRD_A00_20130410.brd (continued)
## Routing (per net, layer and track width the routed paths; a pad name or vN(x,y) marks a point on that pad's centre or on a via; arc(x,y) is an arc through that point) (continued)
DROOP: length 10.4
  TOP w0.102: v2(33.43,82.08) 33.26,82.26 32.42,82.26 31.79,82.89
  TOP w0.203: PU701.25 29.72,82.15 29.98,82.41 v1(30.13,82.41)
  TOP w0.254: PR727.1 PC714.1 29.76,85.91 29.81,85.97 v1(29.81,85.94) ; v1(30.13,82.41) 30.18,82.36 31.45,82.36 31.79,82.7 PR744.1
  IN2 w0.254: v1(29.81,85.94) 30.11,85.65 30.11,82.44 v1(30.13,82.41)
DSP_PD#: length 38
  TOP w0.076: U34.H5 141.67,60.35 141.67,60.74 v6(141.45,60.96)
  TOP w0.102: v1(119.13,40.63) 118.66,40.16 R1262.1
  GND1 w0.076: v4(141.02,60.9) 141.08,60.96 v6(141.45,60.96)
  IN3 w0.076: v4(141.02,60.9) 140.74,60.62 140.74,60.52 139.15,58.93 138.39,58.93 138.04,58.59 138.04,57.66 138.4,57.3 138.4,56.21 138.28,56.1 138.28,54.89 138.39,54.79 138.39,53.99 135.29,50.89 v1(135.29,47.31)
  BOTTOM w0.102: v1(119.13,40.63) 120.06,40.63 v2(120.26,40.82) 120.57,41.14 122.19,41.14 122.8,41.74 126.63,41.74 131.39,46.5 134.48,46.5 v1(135.29,47.31)
DSP_PD#_R: length 10.2
  TOP w0.102: v1(122.02,40.63) 120.58,40.63 v2(120.47,40.51) 119.97,40.02 R1262.2 R1261.2 ; UA1.17 121.06,45.04 v6(120.99,44.97)
  GND1 w0.076: v6(120.99,44.97) 121.06,44.97 v4(121.37,45.28)
  IN3 w0.076: v1(122.02,40.63) 122.3,40.91 122.3,44.35 v4(121.37,45.28)
DSWODVREN: length 10
  BOTTOM w0.076: UCPU1.AW7 92.22,57.6 92.22,57.06 92.68,56.6 92.68,55.39 93.11,54.95
  BOTTOM w0.102: 93.11,54.95 94.92,53.14 RH147.2 95.4,52.37 95.4,51.21 RH151.2 95.21,50.39 v2(95.98,50.39)
EAPD#: length 155.4
  TOP w0.102: v6(148.52,53.51) 148.95,53.94 R228.1
  GND1 w0.076: v4(148.17,54.06) 148.52,53.71 v6(148.52,53.51)
  IN1 w0.076: v1(19.09,21.51) 19.91,22.34 22.73,22.34 23.59,23.2 26.61,23.2 28.21,24.8 30.17,24.8 31.99,26.62 31.99,27.08 32.63,27.72 38.45,27.72 38.68,27.5 38.68,26.91 38.88,26.71 39.82,26.71 40.28,27.17 41.17,27.17 41.52,26.81 42.21,26.81 42.36,26.66 44.52,26.66 45.77,27.9 48.74,27.9 50.16,29.32 51.84,29.32 52.64,28.52 53.04,28.52 53.28,28.28 54.97,28.28 55.4,27.85 62.45,27.85 v4(63.6,26.71)
  IN2 w0.076: v4(63.6,26.71) 63.6,26.76 64.71,27.88 74.29,27.88 74.57,27.6 74.92,27.6 75.15,27.37 76.09,27.37 76.3,27.57 76.3,27.85 76.5,28.05 77.31,28.05 77.46,27.9 83.74,27.9 83.87,27.77 85.97,27.77 87.01,28.82 88.18,28.82 89.3,27.7 92.76,27.7 92.94,27.88 98.93,27.88 99.25,27.56 100.49,27.56 100.86,27.19 103.26,27.19 104.47,28.41 110.31,28.41 114.45,32.55 v1(114.45,32.75) ; v4(148.17,54.06) 147.92,54.06 144.98,51.12 143.88,51.12 143.36,50.6 142.53,50.6 139.72,47.79 134.84,47.79 v3(134.79,47.74)
  BOTTOM w0.102: JIOL1.19 18.6,21.02 v1(19.09,21.51) ; v1(114.45,32.75) 116.53,34.84 116.53,39.51 118.76,41.74 121.94,41.74 122.55,42.35 126.22,42.35 132.14,48.27 134.39,48.27 134.79,47.87 v3(134.79,47.74)
EAPD_R#: length 11.6
  TOP w0.076: v6(143.05,59.21) 143.19,59.35 143.67,59.35 U34.D6
  TOP w0.102: 148.06,53.88 v6(147.67,53.49) ; 148.06,53.88 R228.2 ; 148.06,53.88 R241.1
  GND1 w0.076: v6(147.67,53.49) 147.67,53.49 147.31,53.85 v4(147.31,54.04) ; v4(143.51,59.27) 143.11,59.27 v6(143.05,59.21)
  IN3 w0.076: v4(143.51,59.27) 143.74,59.04 145.11,59.04 145.41,58.74 145.41,57.99 146.03,57.37 146.03,54.85 146.85,54.04 v4(147.31,54.04)
EC_BATT_PRS#: length 74
  TOP w0.102: U34.B1 144.92,62.87 145.23,63.18 v6(146.82,63.18) ; v1(119.16,29.6) 119.16,30.16 v2(119.59,30.59)
  TOP w0.254: v1(146.82,40.93) 146.62,40.73 PC229.2 ; v1(119.16,29.6) 119.31,29.45 PC114.1 119.83,28.33 120.96,28.33 PR113.1 PR112.2 ; v6(144.93,53.63) 144.5,54.06 C286.2
  GND1 w0.076: v4(147.14,62.76) 147.05,62.85 147.05,62.95 v6(146.82,63.18)
  GND1 w0.254: v6(144.93,53.63) 144.93,52.92 v4(144.77,52.76)
  IN1 w0.254: v1(146.82,40.93) 146.82,41.38 146.05,42.14 146.05,46.39 144.77,47.67 v4(144.77,52.76)
  IN3 w0.076: v4(144.77,52.76) 146.65,52.76 147.71,53.82 147.71,54.64 147.04,55.31 147.04,57.96 147.09,58.01 147.09,59.73 147.58,60.22 147.58,62.32 v4(147.14,62.76)
  IN4 w0.254: v1(119.16,29.6) 120.33,28.44 127.73,28.44 128.67,29.38 128.67,34.4 133.04,38.77 140.81,38.77 143.4,41.36 146.39,41.36 v1(146.82,40.93)
EC_CRY2: length 11.5
  TOP w0.102: U34.K1 140.77,62.25 140.77,62.83 140.95,63 140.95,63.72 v6(140.81,63.86) 139.78,63.86 v2(139.63,63.7) ; MC654.1 145.19,65.11 R607.2 145.18,65.14 144.61,65.71 v6(144.61,65.93) 144.61,66.33 R253.2
  GND1 w0.076: v4(144.47,65.24) 144.61,65.38 v6(144.61,65.93) ; v6(140.81,63.86) 140.81,64.06 v4(141.21,64.45)
  IN1 w0.076: v4(144.47,65.24) 143.86,64.63 141.38,64.63 v4(141.21,64.45)
EC_ENVDD: length 120.8
  TOP w0.203: v6(146.86,55.9) 146.46,56.29 146.46,56.49 145.89,57.06 145.89,57.28 145.57,57.6 U34.A10
  TOP w0.254: D105.3 155.47,84.4 v1(155.84,84.77) ; v1(178.16,62.2) v2(178.16,63.98) 177.27,64.87 177.27,67.7 178.11,68.54 D93.3 178.11,68.96 177.76,69.31 v1(177.38,69.31) ; v1(195.41,62.34) 195.41,62.34 PD306.3
  GND1 w0.254: v6(146.86,55.9) 147.49,55.9 147.52,55.87 147.52,55.84 v4(147.54,55.82)
  IN1 w0.254: v4(160.85,53.67) 159.16,55.36 151.23,55.36 149.26,57.34 149.26,57.52 148.6,58.18 147.94,58.18 147.53,57.77 147.53,55.82 147.54,55.81 v4(147.54,55.82)
  IN2 w0.254: v1(195.41,62.34) 186.41,62.34 185.29,61.23 178.95,61.23 178.16,62.01 v1(178.16,62.2)
  IN3 w0.254: v4(160.85,53.67) 161.2,54.01 169.35,54.01 170.03,53.33 170.58,53.33 171.29,54.04 171.29,57 170.78,57.51 170.78,63.67 173.08,65.96 v1(173.08,66.26) ; v1(177.38,69.31) 176.7,69.31 173.13,72.87 173.13,77.91 175.46,80.24 176.49,80.24 v1(177.25,81)
  IN4 w0.254: v1(155.84,84.77) 155.86,84.77 156.55,84.09 170.85,84.09 173.2,81.74 176.99,81.74 177.25,81.48 v1(177.25,81)
  BOTTOM w0.254: v1(177.38,69.31) 176.7,69.99 173.77,69.99 173.34,69.56 173.34,66.51 v1(173.08,66.26)
EC_ON: length 96.5
  TOP w0.076: U34.G1 142.42,62.23 142.55,62.35 142.55,62.55 142.33,62.77 142.33,62.83
  TOP w0.102: 142.33,62.83 142.33,63.08 142.85,63.6 142.85,63.6 143.72,64.47 148.69,64.47 149.32,65.1 C1117.1 150.03,65.1 150.63,65.7 150.63,66.38 v6(150.49,66.52) ; PR341.1 190.6,26.56 v7(189.81,26.56) 182.21,26.56 181.17,27.6 175.44,27.6 v1(175.06,27.98)
  GND1 w0.076: v6(150.49,66.52) 150.86,66.52 v4(150.95,66.43)
  IN1 w0.076: v1(175.06,27.98) 175.51,27.98 176.77,29.24 176.77,39.23 178.02,40.49 178.02,48.68 174.81,51.89 174.81,54.28 174.11,54.98 172.48,54.98 172.02,55.44 172.02,56.96 166.49,62.48 166.49,64.3 165.73,65.06 163.27,65.06 162.96,65.37 161.93,65.37 161.73,65.57 160.34,65.57 160.1,65.81 155.64,65.81 155.04,66.42 150.96,66.42 v4(150.95,66.43)
EC_ON_CTRL#: length 37.5
  TOP w0.102: D85.2 v6(134.67,61.73) ; RP22.3 140.5,50.88 140.69,50.7 140.69,50.69 v1(140.74,50.63) ; U34.G5 142.26,59.94 v6(142.26,59.52) ; v6(149.88,58.64) 150.73,58.64 v2(151.04,58.94) 151.04,60.61 C1118.1 152.41,61.98 D84.2
  GND1 w0.076: v6(142.26,59.52) 142.06,59.32 v4(142.06,59.09) ; v4(149.45,58.29) 149.54,58.29 v6(149.88,58.64) ; v4(134.74,61.11) 134.67,61.19 v6(134.67,61.73)
  IN1 w0.076: v4(134.74,61.11) 136.47,61.11 136.61,60.97 137.57,60.97 137.9,60.63 137.9,59.61 138.3,59.22 141.07,59.22 141.37,59.52 141.76,59.52 142.06,59.23 v4(142.06,59.09) 142.26,58.89 144.06,58.89 144.28,59.12 145.26,59.12 146.5,57.87 146.91,57.87 147.88,58.85 148.89,58.85 v4(149.45,58.29)
  IN3 w0.076: v1(140.74,50.63) 140.37,51 140.37,53.84 140.19,54.01 140.19,54.6 140.33,54.74 140.33,55.7 140.22,55.82 140.22,56.67 140.66,57.11 140.66,57.98 141.41,58.72 141.69,58.72 v4(142.06,59.09)
EC_PECI: length 11.2
  TOP w0.076: U34.H2 141.67,61.85 141.67,62.29 141.65,62.31 141.65,62.83
  TOP w0.102: 141.65,62.83 141.65,63.41 141.83,63.59 142.29,63.59 142.41,63.72 v2(142.41,63.82) 142.41,63.97 142.29,64.1 141.78,64.1 141.65,64.22 141.65,64.55 141.78,64.68 148.03,64.68 R240.1
EC_RST#: length 3.9
  TOP w0.102: R221.1 C285.1 139.61,54.36 140.15,54.36 v2(140.24,54.44) 140.44,54.65 140.44,55.26 140.92,55.74 140.92,56.1 U34.K13
EC_RUNTIME_SCI#: length 58
  TOP w0.102: U34.N6 139.34,59.52 138.76,59.52 138.49,59.25 138.32,59.25 137.41,58.34 136.21,58.34 135.39,59.17 135.39,61.9 134.84,62.45 v6(134.16,62.45) ; RH398.2 97.58,58.45 97.76,58.63 T283.1 97.76,62.09 v6(97.68,62.17)
  GND1 w0.076: v6(134.16,62.45) 134.36,62.65 v4(134.63,62.65) ; v6(97.68,62.17) 97.68,62.85 v4(97.77,62.94)
  IN4 w0.076: v4(134.63,62.65) 133.5,62.65 132.65,63.5 130.83,63.5 130.64,63.31 124.61,63.31 123.95,62.65 120.85,62.65 119.74,63.75 117.72,63.75 117.15,63.18 115.23,63.18 114.32,64.1 113,64.1 112.54,63.64 109.06,63.64 108.27,64.43 107.52,64.43 107.04,64.9 106.4,64.9 106.14,64.64 100.67,64.64 100.29,64.27 99.91,64.27 99.55,63.91 99.55,63.35 99.14,62.94 v4(97.77,62.94)
  GND5 w0.076: v5(97.3,62.7) 97.54,62.94 v4(97.77,62.94)
  BOTTOM w0.076: v5(97.3,62.7) 97.05,62.45 96.46,62.45 96.16,62.14 UCPU1.AM2
EC_RX: length 96.8
  TOP w0.076: v6(139,57.67) 139.18,57.85 140.67,57.85 U34.K9
  TOP w0.102: v1(197.03,22.82) v2(197.03,23.61)
  GND1 w0.076: v6(139,57.67) 139.54,57.67 v4(139.59,57.62)
  IN2 w0.076: v4(139.59,57.62) 139.59,56.79 140.43,55.96 141.6,55.96 141.82,56.17 142.08,56.17 142.62,55.64 144.19,55.64 144.79,56.24 145.52,56.24 146.04,56.76 146.04,59.3 146.65,59.91 148.99,59.91 150.51,58.39 150.52,58.39 150.85,58.39 150.85,58.39 152.8,58.39 153.07,58.12 153.07,57.2 154.68,55.59 156.53,55.59 157.27,54.85 157.27,50.74 158.31,49.7 160.95,49.7 163.16,51.9 166.61,51.9 172.69,45.83 172.69,44.7 176.22,41.17 176.22,27.25 181.26,22.21 196.42,22.21 v1(197.03,22.82)
  BOTTOM w0.102: JDEBUG.12 v1(197.03,22.82)
EC_SHUTDOWN: length 44.2
  TOP w0.076: v6(143.61,62.61) 143.67,62.55 143.67,60.35 U34.D5
  TOP w0.102: R1286.1 v2(171.27,52.26) 171.27,52.57 v1(170.91,52.92)
  GND1 w0.076: v4(142.97,63.16) 143.06,63.16 v6(143.61,62.61)
  IN1 w0.076: v4(142.97,63.16) 142.97,63.63 143.14,63.79 145.03,63.79 145.36,63.46 146.5,63.46 146.87,63.83 148.97,63.83 149.63,63.17 149.94,63.17 151.3,64.53 151.86,64.53 152.42,63.97 152.42,63.69 153.31,62.8 153.97,62.8 154.55,62.22 157.35,62.22 157.68,62.55 163.27,62.55 164.13,63.41 165.21,63.41 171.29,57.33 171.29,53.3 v1(170.91,52.92)
EC_SLP_S0#: length 24.7
  TOP w0.076: U34.M2 139.67,61.85 139.28,61.85 v6(138.98,62.15)
  GND1 w0.076: v6(138.98,62.15) 138.91,62.15 v4(138.55,62.51)
  IN4 w0.076: v4(138.55,62.51) 137.76,63.3 136.21,63.3 135.99,63.07 133.34,63.07 132.23,64.19 127.41,64.19 127.4,64.18 120.79,64.18 v4(120.73,64.12)
  GND5 w0.076: v4(120.73,64.12) 120.4,64.45 v5(120.05,64.45)
  BOTTOM w0.102: v2(118.16,65.19) 118.46,64.88 118.46,64.16 119.06,63.56 R1391.2 120.02,64.45 v5(120.05,64.45)
EC_SLP_S5#: length 10.6
  TOP w0.102: R1386.1 131.57,56.73 D114.2 132.71,55.59 135.12,55.59 135.48,55.94 135.91,55.94 136.07,55.78 136.75,55.78 R250.2 137.27,56.5 137.69,56.92 137.69,56.95 138.23,57.49 v2(138.23,57.65) 138.23,57.67 138.61,58.05 139.37,58.05 139.42,58.1 U34.N9
EC_SMB_CK1: length 61.3
  TOP w0.102: v1(146.57,42.63) 146.54,42.61 146.57,42.61 v1(146.57,42.63) ; v1(146.57,42.63) 146.88,42.95 PU201.9 ; v6(148.64,55.32) 148.22,54.9 R229.1 147.75,54.9 147.39,55.26 147.39,56.21 146.34,57.26 146.34,57.68 145.42,58.6 U34.A8 ; v2(128.45,30.1) 128.14,29.78 126.52,29.78 v1(126.47,29.73) 126.38,29.64 126.38,29.27 PR109.2
  GND1 w0.076: v4(148.91,55.61) 148.91,55.6 v6(148.64,55.32)
  IN2 w0.076: v4(148.91,55.61) 149.41,55.12 149.41,52.93 145.43,48.96 144.41,48.96 143.77,48.32 142.89,48.32 141.08,46.51 141.08,43.88 142.13,42.83 146.37,42.83 v1(146.57,42.63)
  IN4 w0.076: v1(126.47,29.73) 126.38,29.82 126.38,34.87 131.45,39.94 140.1,39.94 142.79,42.63 v1(146.57,42.63)
EC_SMB_DA1: length 63.9
  TOP w0.102: v2(121.88,30.09) 122.46,29.5 124.73,29.5 124.99,29.76 v1(125.62,29.76) PR111.2 ; PU201.8 146.67,43.45 v1(146.57,43.35) ; v6(148.46,56.39) 148.46,56.06 R230.1 147.83,56.15 147.78,56.15 146.54,57.4 146.54,57.87 145.42,58.99 U34.A7
  GND1 w0.076: v6(148.46,56.39) 148.61,56.24 v4(148.9,56.24)
  IN2 w0.076: v1(146.57,43.35) 146.32,43.1 142.1,43.1 141.26,43.95 141.26,46.43 142.97,48.15 143.84,48.15 144.48,48.78 145.61,48.78 149.64,52.81 149.64,55.5 v4(148.9,56.24)
  IN4 w0.076: v1(146.57,43.35) 146.21,42.99 142.74,42.99 139.9,40.14 131.33,40.14 125.48,34.3 125.48,29.9 v1(125.62,29.76)
EC_SMI#: length 60.1
  TOP w0.081: U34.L13 139.96,55.64 v6(139.95,55.64)
  GND1 w0.076: v6(139.95,55.64) 139.95,55.92 v4(139.64,56.22)
  IN1 w0.076: v4(99.91,60.72) 100.18,60.99 100.66,60.99 100.87,60.78 101.28,60.78 102.54,62.04 106.52,62.04 108.63,59.93 116.24,59.93 116.75,59.42 116.75,58.81 117.2,58.36 122.51,58.36 123.57,59.41 131.02,59.41 131.62,58.81 138.65,58.81 139.2,58.27 139.2,56.67 v4(139.64,56.22)
  IN3 w0.076: v4(99.74,65.47) 99.74,67.88 v4(98.5,69.13)
  GND5 w0.076: v4(98.5,69.13) 98.5,69.52 v5(98.36,69.66) ; v4(99.74,65.47) v5(99.74,64.96) ; v4(99.91,60.72) 100.21,61.02 v5(100.4,61.02)
  BOTTOM w0.102: T270.1 99.07,69.38 98.64,69.38 v5(98.36,69.66) 98.31,69.71 96.7,69.71 UCPU1.V1 ; v5(99.74,64.96) 99.75,64.97 RP19.4 100.59,64.97 100.86,64.71 100.86,63.26 100.55,62.95 100.55,61.18 v5(100.4,61.02)
EC_TX: length 92.1
  TOP w0.102: v6(140.99,57.23) 140.92,57.3 U34.K10 ; v1(195.78,22.99) v2(195.78,22.33)
  GND1 w0.076: v4(140.22,57.16) 140.28,57.23 v6(140.99,57.23)
  IN2 w0.076: v4(140.22,57.16) 140.48,56.9 141.37,56.9 141.92,56.35 142.21,56.35 142.72,55.84 144.06,55.84 144.66,56.44 145.4,56.44 145.84,56.88 145.84,59.35 146.58,60.08 151.38,60.08 152.18,59.28 152.9,59.28 154.66,57.53 154.66,56.51 155.3,55.87 156.53,55.87 157.5,54.9 157.5,50.84 158.47,49.87 160.88,49.87 163.09,52.08 166.69,52.08 172.87,45.9 172.87,44.78 176.4,41.25 176.4,27.33 181.33,22.39 195.18,22.39 v1(195.78,22.99)
  BOTTOM w0.102: v1(195.78,22.99) JDEBUG.11
EC_WAKE_SCI#: length 31.6
  TOP w0.102: U34.N7 139.06,59.1 138.97,59.02 138.41,59.02 137.52,58.13 136.14,58.13 135.19,59.08 135.19,61.79 134.84,62.13 134.02,62.13 133.64,62.51 133.64,64.35 v6(133.41,64.58)
  GND1 w0.076: v4(133.67,65.19) 133.69,65.18 133.69,64.86 v6(133.41,64.58)
  IN4 w0.076: v1(119.09,65.13) 119.5,64.72 121.41,64.72 121.59,64.53 127.26,64.53 127.27,64.54 133.03,64.54 v4(133.67,65.19)
  BOTTOM w0.102: v1(119.09,65.13) 119.09,65.67 118.49,66.28 v2(118.49,66.69) 118.49,66.79 RH427.1
ECAGND: length 109
  TOP w0.102: v6(144.63,51.27) 144.63,49.87 144.19,49.43 v2(143.71,49.43)
  TOP w0.203: 145.77,56.76 145.77,56.78 145.44,57.1 U34.A11
  TOP w0.254: 145.77,56.76 146.11,56.41 146.11,55.21 145.39,54.49 C286.1 145.37,54.05 C282.2 L44.2 145,51.59 145,51.45 144.81,51.27 v6(144.63,51.27) ; PH101.2 80.61,64.76 v1(80.97,65.11)
  GND1 w0.254: v6(144.63,51.27) 144.22,50.85 v4(144.22,50.61)
  IN1 w0.254: v1(146.43,37.38) 146.29,37.51 146.29,41.32 145.69,41.92 145.69,46.22 144.41,47.51 144.41,50.42 v4(144.22,50.61)
  IN2 w0.254: v1(80.97,65.11) 81.6,64.48 82.36,64.48 83.23,63.6 83.23,63.03 82.88,62.68 82.88,59.52 83.28,59.12 86.91,59.12 87.09,59.3 88.03,59.3 89.83,57.49 90.93,57.49 92.53,55.89 92.53,51.17 97.94,45.76 107.67,45.76 111.63,41.8 113.93,41.8 119.53,36.19 139.24,36.19 140.01,36.97 146.02,36.97 v1(146.43,37.38)
EDP_AUXN: length 103.3
  IN2 w0.076: v1(69.77,80.7) 70.09,80.38 70.09,80.21 70.4,79.9 74.06,79.9 74.48,80.31 79.19,80.31 79.43,80.07 86.98,80.07 87.48,80.58 93.44,80.58 95.02,82.16 106.27,82.16 108.64,79.78 108.64,77.14 109.02,76.76 109.02,76.02 109.81,75.23 117.99,75.23 118.74,75.98 131.68,75.98 132.37,75.3 139.26,75.3 140.33,74.23 152.99,74.23 153.91,73.32 155.96,73.32 156.17,73.52 159.57,73.52 160.43,72.66 160.43,72.11 v1(160.19,71.87)
  BOTTOM w0.076: UCPU1.A45 69.33,79.81 69.33,79.62 69.39,79.56 69.47,79.56 69.67,79.76 69.67,79.98
  BOTTOM w0.102: v1(160.19,71.87) 160.39,72.06 160.39,72.79 C1065.1 ; v1(69.77,80.7) 69.83,80.7 70.05,80.47 70.05,80.37 69.67,79.98
EDP_AUXN_C: length 3
  BOTTOM w0.102: R1011.1 160.07,75.72 ML58.1 160.07,75.04 160.36,74.76 160.36,74.37 C1065.2 R1033.1
EDP_AUXN_CONN: length 4.7
  BOTTOM w0.102: R1011.2 160.07,76.85 ML58.2 160.07,77.39 160.34,77.66 160.34,77.85 160.56,78.07 161.78,78.07 v1(162.2,78.49) 162.39,78.68 162.39,78.93 162.25,79.07 JLVDS1.9
EDP_AUXP: length 103.3
  IN2 w0.076: v1(160.83,71.85) 160.59,72.1 160.59,72.72 159.63,73.67 156.1,73.67 155.9,73.47 153.97,73.47 153.05,74.38 140.39,74.38 139.33,75.45 132.43,75.45 131.74,76.14 118.68,76.14 117.93,75.39 109.87,75.39 109.18,76.08 109.18,76.82 108.8,77.2 108.8,79.84 106.33,82.31 94.95,82.31 93.38,80.73 87.42,80.73 86.91,80.23 79.5,80.23 79.25,80.47 74.42,80.47 74,80.05 70.47,80.05 70.24,80.28 70.24,80.52 70.42,80.7 v8(70.43,80.7)
  BOTTOM w0.076: UCPU1.B45 69.37,79.31 69.44,79.38 69.54,79.38 69.83,79.66 69.83,79.86
  BOTTOM w0.102: v8(70.43,80.7) 70.26,80.53 70.26,80.28 69.83,79.86 ; v1(160.83,71.85) 160.6,72.08 160.6,72.81 C1064.1
EDP_AUXP_C: length 3
  BOTTOM w0.102: R1034.2 C1064.2 160.57,74.42 160.57,74.78 160.87,75.09 ML58.4 160.87,75.72 R1010.1
EDP_AUXP_CONN: length 4.8
  BOTTOM w0.102: JLVDS1.8 162.75,79.01 162.6,78.86 162.6,78.56 161.9,77.86 160.65,77.86 160.55,77.77 160.55,77.66 160.87,77.34 ML58.3 160.87,76.85 R1010.2
EDP_BKLCTL: length 11.1
  BOTTOM w0.102: v2(98.69,85.22) 98.27,85.22 97.87,84.82 97.87,83.73 RC147.2 96.34,82.19 94.22,82.19 93.24,81.22 92.3,81.22 91.55,80.47 91.55,79.64 91.73,79.46 UCPU1.B8
EDP_DISP: length 5.6
  BOTTOM w0.102: RC158.2 RC146.1 v2(68.96,82.21) 69.43,81.74 70.2,81.74 70.92,81.01 70.92,80.02 UCPU1.A43
EDP_HPD: length 73.5
  TOP w0.102: v6(110.12,76.26) 110.12,77.36 RC138.1 113.2,77.84 v2(113.55,78.19) 113.94,78.57 113.94,79.39 RC148.1 113.19,79.5 QC5.1
  GND1 w0.076: v6(110.12,76.26) v4(109.61,76.26)
  IN1 w0.076: v4(109.61,76.26) 109.91,76.26 111.87,74.31 119.07,74.31 119.81,75.05 128.49,75.05 129.22,74.32 145.6,74.32 145.79,74.51 147.58,74.51 147.7,74.4 148.02,74.4 148.04,74.41 148.46,74.83 152.77,74.83 153.99,76.05 162.31,76.05 v4(162.69,76.44)
  IN3 w0.076: v4(162.69,76.44) 162.73,76.48 v1(162.73,81.58)
  BOTTOM w0.122: JLVDS1.10 161.75,80.6 v1(162.73,81.58)
EDP_TXN_P0: length 112.8
  IN2 w0.076: v1(163.18,71.96) 162.93,72.21 162.93,73.21 161.86,74.28 155.39,74.28 154.64,75.03 153.83,75.03 153.79,74.99 148.46,74.99 148.11,75.34 142.87,75.34 142.09,76.11 140.99,76.11 140.95,76.07 132.89,76.07 132.21,76.75 118.38,76.75 117.71,76.07 111.2,76.07 109.84,77.43 109.84,80.33 107.17,82.99 94.46,82.99 93.01,81.55 81.78,81.55 80.87,82.46 74.02,82.46 73.73,82.17 73.73,81.5 73.6,81.37 73.04,81.37 72.92,81.5 72.92,82.19 72.65,82.46 72.09,82.46 71.85,82.22 71.85,81.36 71.75,81.25 71.11,81.25 71.01,81.36 71.01,82.17 70.72,82.46 69.77,82.46 69.49,82.18 69.49,81.24 69.21,80.96 68.57,80.96 v1(68.46,81.07)
  BOTTOM w0.102: v1(68.46,81.07) 68.46,81.06 68.67,80.86 68.9,80.86 69.12,80.64 69.12,80.14 68.97,79.99 68.97,79.21 69.36,78.82 69.36,78.56 UCPU1.C45 ; v1(163.18,71.96) 162.96,72.18 162.96,72.29 163.27,72.59 163.27,72.81 C1060.1
EDP_TXN_P0_C: length 2.1
  BOTTOM w0.102: C1060.2 163.23,74.42 163.23,74.75 163.53,75.05 ML57.4 163.53,75.72 R1008.1
EDP_TXN_P0_CONN: length 3.7
  BOTTOM w0.102: JLVDS1.5 164.25,79.02 164.1,78.88 164.1,78.37 163.6,77.86 163.32,77.86 163.24,77.79 163.24,77.65 163.53,77.36 ML57.3 163.53,76.85 R1008.2
EDP_TXN_P1: length 113
  IN2 w0.076: v1(165.31,71.79) 165.07,72.03 165.07,72.22 162.3,74.99 155.61,74.99 154.96,75.64 153.6,75.64 153.56,75.6 148.75,75.6 148.41,75.95 143.2,75.95 142.3,76.85 137.62,76.85 137.12,77.36 118.1,77.36 117.44,76.7 111.48,76.7 110.5,77.67 110.5,81.08 107.74,83.83 94.38,83.83 92.78,82.23 81.96,82.23 81.12,83.07 69.34,83.07 67.44,81.18 67.01,81.18 v8(66.85,81.33)
  BOTTOM w0.102: C1061.1 165.14,72.78 165.14,72.35 165.11,72.31 165.11,71.99 v1(165.31,71.79) ; v8(66.85,81.33) 67.08,81.11 67.67,81.11 67.96,80.82 67.96,80.54 67.77,80.35 67.59,80.35 67.47,80.24 67.47,80.1 67.54,80.03 67.76,80.03 68.07,79.72 68.21,79.72 68.25,79.76 UCPU1.A47
EDP_TXN_P1_C: length 2.1
  BOTTOM w0.102: C1061.2 165.16,74.4 165.16,74.8 165.43,75.08 ML56.4 165.43,75.72 R1006.1
EDP_TXN_P1_CONN: length 3.6
  BOTTOM w0.102: R1006.2 165.43,76.85 ML56.3 165.43,77.44 165.15,77.72 165.15,77.9 165.26,78.02 165.51,78.02 165.77,78.27 165.77,78.68 165.59,78.85 165.59,78.99 165.75,79.14 JLVDS1.2
EDP_TXP_P0: length 112.7
  IN2 w0.076: v1(162.54,71.96) 162.78,72.2 162.78,73.14 161.79,74.13 155.33,74.13 154.58,74.88 153.89,74.88 153.85,74.84 148.39,74.84 148.05,75.18 142.81,75.18 142.03,75.96 141.05,75.96 141.02,75.92 132.82,75.92 132.15,76.59 118.45,76.59 117.77,75.92 111.13,75.92 109.68,77.37 109.68,80.26 107.11,82.84 94.52,82.84 93.07,81.39 81.72,81.39 80.8,82.31 74.09,82.31 73.88,82.11 73.88,81.43 73.67,81.22 72.98,81.22 72.77,81.43 72.77,82.13 72.59,82.31 72.16,82.31 72,82.16 72,81.29 71.81,81.1 71.05,81.1 70.86,81.29 70.86,82.11 70.66,82.31 69.83,82.31 69.64,82.12 69.64,81.18 69.27,80.81 68.79,80.81 68.64,80.66 68.59,80.66 68.47,80.54 v8(68.47,80.42)
  BOTTOM w0.102: v1(162.54,71.96) 162.76,72.18 162.76,72.37 163.06,72.68 163.06,72.79 C1062.1 ; v8(68.47,80.42) 68.7,80.65 68.82,80.65 68.91,80.56 68.91,80.23 68.76,80.08 68.76,79.28 68.43,78.96 68.43,78.8 68.59,78.65 68.74,78.65 68.81,78.72 UCPU1.B46
EDP_TXP_P0_C: length 2.1
  BOTTOM w0.102: R1009.1 162.73,75.72 ML57.1 162.73,75.05 163.02,74.76 163.02,74.37 C1062.2
EDP_TXP_P0_CONN: length 3.7
  BOTTOM w0.102: JLVDS1.6 163.75,79.04 163.9,78.9 163.9,78.48 v1(163.68,78.27) 163.48,78.07 163.23,78.07 163.03,77.87 163.03,77.66 162.73,77.35 ML57.2 162.73,76.85 R1009.2
EDP_TXP_P1: length 112.9
  IN2 w0.076: v1(164.68,71.79) 164.92,72.03 164.92,72.16 162.23,74.84 155.55,74.84 154.9,75.49 153.66,75.49 153.63,75.45 148.69,75.45 148.34,75.79 143.14,75.79 142.23,76.7 137.56,76.7 137.05,77.2 118.17,77.2 117.51,76.54 111.41,76.54 110.34,77.61 110.34,81.01 107.68,83.68 94.44,83.68 92.84,82.08 81.9,82.08 81.06,82.92 69.4,82.92 67.51,81.03 67.15,81.03 67.05,80.92 66.97,80.92 66.85,80.8 v1(66.85,80.68)
  BOTTOM w0.102: v1(66.85,80.68) 67.08,80.9 67.58,80.9 67.75,80.73 67.75,80.62 67.69,80.56 67.5,80.56 67.26,80.32 67.26,80.01 67.45,79.82 67.67,79.82 68.25,79.25 UCPU1.B47 ; C1063.1 164.93,72.82 164.93,72.44 164.9,72.4 164.9,72.01 v1(164.68,71.79)
EDP_TXP_P1_C: length 2.1
  BOTTOM w0.102: R1007.1 164.63,75.72 ML56.1 164.63,75.11 164.95,74.8 164.95,74.39 C1063.2
EDP_TXP_P1_CONN: length 3.6
  BOTTOM w0.102: R1007.2 164.63,76.85 ML56.2 164.63,77.43 164.94,77.73 164.94,77.99 165.17,78.22 165.43,78.22 165.56,78.36 165.56,78.59 165.39,78.76 165.39,78.98 165.25,79.12 JLVDS1.3
EN_+1.05VS: length 4.2
  BOTTOM w0.102: PR503.2 137.43,73.49 v2(137.64,73.29)
  BOTTOM w0.254: PR501.2 PR503.2 137.43,75.17 137.94,75.68 PU501.28
EN_+3VALW: length 7.6
  TOP w0.102: PD303.2 v2(200.98,28.99)
  TOP w0.254: PD303.2 200.98,31.23 200.78,31.43 PD302.1 200.79,32.32 PD301.1 201.63,33.21 PU305.13
EN_+3VDX: length 10.7
  TOP w0.254: PU303.13 203.13,63.79 202.57,64.35 201.25,64.35 201,64.6 200.21,64.6 199.57,65.24 v2(198.25,65.24) 198.18,65.16 PD305.1 196.82,64.57 197.11,64.27 197.95,64.27 198.19,64.03 PD306.1
EN_+5VDX: length 15.8
  TOP w0.102: v2(202.47,47.36) 202,47.83 v1(202,47.98)
  TOP w0.254: PU302.13 v1(202,47.98) ; v1(208.71,51.89) 208.96,51.89 209.19,51.66 209.19,51.16 209.04,51.01 PU307.4
  IN3 w0.254: v1(208.71,51.89) 208.78,51.82 208.78,47.42 207.78,46.42 205.61,46.42 204.05,47.98 v1(202,47.98)
EN_+V5A: length 3.9
  TOP w0.254: PD307.1 207.23,23.56 v2(207.64,23.97) 209.21,25.54 PU301.13
EN_CAM: length 172.8
  TOP w0.102: R1162.1 174.54,69.89 v1(174.14,69.48) ; v6(174.17,36.26) 175.19,36.26 175.65,36.72 U718.5
  GND1 w0.076: v4(173.72,36.17) 173.81,36.26 v6(174.17,36.26)
  IN3 w0.076: v4(131.87,62.7) 132.23,62.7 133.12,61.81 133.12,59.86 133.84,59.13 133.84,52.62 132.75,51.52 132.75,45.16 138.93,38.98 139.81,38.98 140.84,37.95 140.84,31.2 142.89,29.15 149.7,29.15 151.02,27.83 163.16,27.83 168.68,33.34 169.09,33.34 171.14,35.38 172.28,35.38 173.07,36.17 v4(173.72,36.17)
  IN4 w0.076: v1(174.14,69.48) 174.14,69.41 166.92,62.19 165.97,62.19 165.18,61.4 162.51,61.4 161.83,62.08 157.63,62.08 157.13,61.58 153.06,61.58 152.62,62.03 151.06,62.03 150.25,62.84 148.13,62.84 147.72,63.25 146.93,63.25 146.13,62.45 145.35,62.45 145.22,62.32 145.22,59.89 144.01,58.69 141.35,58.69 140.98,58.32 139.34,58.32 139.08,58.57 137.44,58.57 136.57,59.44 136.57,60.16 134.98,61.75 133.6,61.75 132.65,62.7 v4(131.87,62.7) 131.48,62.31 129.31,62.31 128.93,61.93 120.45,61.93 119.93,61.4 117.81,61.4 v4(117.65,61.24) 110.27,61.24 107.94,63.57 102.88,63.57 101.64,62.33 98.63,62.33 98.45,62.15 96.39,62.15 96.03,62.51 95.41,62.51 v4(95.16,62.26)
  GND5 w0.076: v4(117.65,61.24) 117.88,61.47 v5(117.88,61.63) ; v4(95.16,62.26) 95.09,62.26 94.63,61.8 v5(94.63,61.79)
  BOTTOM w0.102: v2(117.98,60.69) 117.98,61.53 v5(117.88,61.63) ; v5(94.63,61.79) 94.63,62.14 UCPU1.AM4
EN_WLANPWR: length 44.6
  TOP w0.102: U34.F4 142.73,60.79 v6(142.73,61.13) ; D115.3 174.08,43.91 174.31,44.15 v6(174.51,44.15)
  GND1 w0.076: v4(174.34,44.62) 174.34,44.31 v6(174.51,44.15) ; v4(142.79,61.52) 142.73,61.46 v6(142.73,61.13)
  IN1 w0.076: v4(142.79,61.52) 143,61.31 146.17,61.31 146.31,61.17 147.28,61.17 147.86,61.75 148.94,61.75 149.74,60.95 150.73,60.95 151.16,60.52 159.93,60.52 160.5,59.94 160.5,58.47 162.29,56.68 164.1,56.68 167.33,53.45 167.33,52.68 170.89,49.12 172.42,49.12 174.63,46.91 174.63,44.91 v4(174.34,44.62)
ENBKL: length 90.3
  TOP w0.102: v6(163.66,76.19) 163.85,76 165.49,76 165.74,75.74 167.13,75.74 v2(167.22,75.65) D72.2
  GND1 w0.076: v6(163.66,76.19) 163.41,76.44 v4(163.29,76.44)
  IN1 w0.076: v4(163.29,76.44) 163.29,76.38 162.77,75.86 154.05,75.86 152.85,74.66 148.54,74.66 148.11,74.23 148.11,74.23 148.1,74.22 147.62,74.22 147.51,74.33 145.86,74.33 145.76,74.23 145.67,74.14 130.89,74.14 130.5,73.75 v4(130.14,73.75) 129.26,73.75 128.13,74.87 119.89,74.87 119.15,74.13 111.8,74.13 110.87,75.06 103.35,75.06 100.87,77.53 97.88,77.53 96.42,78.99 94.39,78.99 93.29,77.89 92.37,77.89 91.74,78.52 v4(91.74,79.21)
  GND5 w0.076: v5(91.32,79.51) 91.43,79.51 v4(91.74,79.21)
  BOTTOM w0.102: v5(91.32,79.51) 91.17,79.66 UCPU1.A9 91.17,80.62 92.17,81.62 93.35,81.62 94.13,82.4 95.65,82.4 RH123.2
ENVDD: length 12.7
  TOP w0.102: D93.1 175.52,67.91 175.39,68.03 R1026.1 173.62,69.23 v2(173.62,69.96) 173.62,72.26 175.81,74.46 v3(175.81,75.25)
  BOTTOM w0.102: U721.3 175.02,76.22 175.81,75.43 v3(175.81,75.25)
F-IMAX: length 4.2
  TOP w0.203: PU701.10 27.32,77.24 26.7,76.62 26.03,76.62 v2(25.95,76.54) 25.66,76.24 PR712.2
  TOP w0.254: PR712.2 25.25,75.56 25.04,75.35 PR705.1
FB_+1.8VSP: length 4.9
  BOTTOM w0.102: v2(202.25,71.18) PC412.2
  BOTTOM w0.254: PU402.5 205.9,69.93 205.16,70.66 PR420.1 205.14,71.18 PR419.2 PC412.2
FB_+3.3VDX_SSD: length 3.6
  BOTTOM w0.254: PU304.5 174.75,34.11 PR337.1 PR335.2 176.94,33.67 PC328.2
FB_+3VALW: length 3.9
  TOP w0.254: PU305.5 206.57,31.71 207.16,32.3 207.31,32.3 PR347.1 PC336.2 PR345.2
FB_+3VDX: length 3.2
  TOP w0.254: PU303.5 207.98,62.29 PR325.2 ; PR327.1 PR325.2 ; PR325.2 208.11,62.42 208.11,63.11 PC320.2
FB_+5VDX: length 5
  TOP w0.102: v2(205.98,53.86) 205.71,53.58 PC312.2
  TOP w0.254: PR315.2 203.87,52.91 203.5,52.54 PU302.5 ; PR315.2 PR317.1 ; PR315.2 PC312.2
FB_+V5A: length 3.6
  TOP w0.254: PR307.1 PR305.2 PC304.2 210.48,30.14 210.71,29.91 PU301.5
FIVE_EN: length 60.6
  TOP w0.102: v6(27.39,49.44) 27.22,49.61 JXDP.45 ; v2(53.17,78.68) 53.17,79.25 R1179.2 54.13,79.72 55.02,78.83 v1(55.02,78.65)
  GND1 w0.076: v4(26.85,49.95) 27.36,49.44 v6(27.39,49.44)
  IN1 w0.076: v4(26.85,49.95) 26.36,50.44 26.36,54.01 27.25,54.9 29.85,54.9 30.41,55.46 33.37,55.46 41.26,63.35 41.26,64.86 42.64,66.24 44.38,66.24 45.66,67.53 45.66,68.54 49.22,72.1 52.37,72.1 56.04,75.77 56.04,77.63 v1(55.02,78.65)
  IN4 w0.076: v1(55.02,78.65) 56.7,78.65 59.52,75.83 v4(60.45,75.83)
  GND5 w0.076: v5(60.4,75.35) 60.4,75.78 v4(60.45,75.83)
  BOTTOM w0.102: v5(60.4,75.35) 60.4,75.45 60.6,75.65 UCPU1.H59
FSW_+1.8VS: length 2.1
  BOTTOM w0.254: PU402.7 206.9,70.17 206.05,71.02 PR424.1
FSW_+3.3VDX_SSD: length 5.3
  BOTTOM w0.254: PU304.7 176.39,33.11 176.91,32.6 v2(177.21,32.6) 177.85,33.24 PR336.1
FSW_+3VALW: length 5.8
  TOP w0.102: PR346.1 208.62,36.27 v2(209.19,36.27)
  TOP w0.254: PR346.1 207.28,35.26 206.71,34.68 206.71,33.02 206.4,32.71 PU305.7
FSW_+3VDX: length 1.9
  TOP w0.254: PU303.7 207.21,63.29 207.42,63.51 207.42,63.89 207.63,64.1 PR326.1
FSW_+5VDX: length 4
  TOP w0.102: v2(201.43,55.51) 201.43,54.06 PR316.1
  TOP w0.254: PR316.1 201.91,53.38 202.5,52.79 PU302.7
FSW_+V5A: length 1.6
  TOP w0.254: PU301.7 209.71,29.55 209.49,29.77 PR306.1
GYRO_DRDY: length 35.7
  TOP w0.076: 161.88,64.5 161.71,64.5 161.65,64.57 161.43,64.57 161.18,64.32 U636.G5
  TOP w0.102: v1(162.5,64.26) 162.26,64.5 161.88,64.5 ; v6(143.31,66.08) 143.11,66.28 143.11,69.62 143.33,69.84 143.33,70.85 143.95,71.48 v2(143.95,71.55) 143.95,71.92 143.49,72.38 143.49,76.47 143.69,76.67 144.3,76.67 144.55,76.42 U638.6
  GND1 w0.076: v6(143.31,66.08) 143.53,66.08 v4(143.71,65.9)
  IN1 w0.076: v1(162.5,64.26) 161.61,64.26 161.22,63.87 160.79,63.87 160.51,64.15 160.12,64.15 159.89,63.92 159.24,63.92 158.06,65.1 155.36,65.1 155.05,64.8 152.43,64.8 152.22,65.01 149.73,65.01 148.95,64.23 147.17,64.23 145.75,65.65 143.96,65.65 v4(143.71,65.9)
GYRO_I2C_ADD_SEL: length 4.7
  TOP w0.102: v2(141.08,77.97) 140.76,77.65 R1205.1 R1206.2 141.89,76.07 142.71,76.89 U638.4
GYRO_INT#: length 36.2
  TOP w0.102: v6(151.47,72.45) 151.47,72.81 150.98,73.29 146.97,73.29 R1176.2 145.2,75.06 U638.7 ; v1(158.99,70.45) 159.48,70.94 v2(159.48,71.54) 159.52,71.58 159.52,72.66 159.77,72.91 161.86,72.91 162.31,72.45 165.53,72.45 166.12,71.86 166.12,68.01 165.16,67.04 163.16,67.04 162.47,66.34 162.07,66.34 U636.H8
  GND1 w0.076: v6(151.47,72.45) 151.47,71.87 v4(151.72,71.62)
  IN4 w0.076: v4(151.72,71.62) 152.2,71.13 152.9,71.13 153.11,70.92 158.66,70.92 158.99,70.59 v1(158.99,70.45)
H_CATERR#: length 12.7
  IN4 w0.076: v1(51.81,78.79) 52.57,78.03 52.57,77.66 56.15,74.08 58.39,74.08 v4(58.8,73.67)
  GND5 w0.076: v5(59.1,73.9) 59.02,73.9 v4(58.8,73.67)
  BOTTOM w0.102: v5(59.1,73.9) 59.3,74.1 UCPU1.K61 ; v1(51.81,78.79) 49.4,78.79 T2.1
H_CPU_SVIDALRT#: length 12.7
  BOTTOM w0.102: UCPU1.L62 58.2,72.97 57.32,72.97 56.67,72.33 54.83,72.33 54.71,72.2 54.71,71.78 54.58,71.65 54.31,71.65 54.19,71.78 54.19,72.71 54.31,72.83 v2(54.91,72.83) 55.4,72.83 55.53,72.96 55.53,73.22 55.4,73.34 54.39,73.34 54.26,73.47 54.26,74.27 53.9,74.63 53.65,74.63 53.5,74.49 53.5,74.36 53.58,74.28 RC93.1 RC94.2
H_CPU_SVIDCLK: length 13.4
  BOTTOM w0.102: UCPU1.N63 57.77,72.67 57.3,72.21 57.3,71.69 57.18,71.56 v2(55.8,71.56) 55.4,71.56 55.28,71.44 55.28,71.18 55.4,71.06 55.91,71.06 56.04,70.93 56.04,70.55 56.17,70.42 56.18,70.42 56.29,70.31 56.29,70.15 56.18,70.04 55.66,70.04 55.53,70.17 55.53,70.52 55.4,70.65 55.15,70.65 55.02,70.52 55.02,70.13 54.9,70 54.64,70 54.52,70.13 54.52,70.32 54.39,70.45 54.01,70.45 53.88,70.57 53.88,71.06 53.75,71.18 53.5,71.18 53.37,71.06 53.37,70.56 53.25,70.43 52.99,70.43 52.86,70.56 52.86,71.44 RC92.2
H_CPU_SVIDDAT: length 12.9
  BOTTOM w0.102: RC96.2 51.11,75.48 50.71,75.88 50.71,76.14 50.93,76.37 v2(51.28,76.37) 51.61,76.37 51.78,76.2 51.78,75.94 51.72,75.88 51.72,74.98 51.83,74.87 52.1,74.87 52.23,74.99 52.23,75.76 52.36,75.88 53.45,75.88 53.58,75.76 RC95.2 53.66,75.29 54.17,75.29 54.92,74.54 54.92,74.1 55.02,74 55.84,74 56.19,73.65 56.19,73.19 56.29,73.09 56.67,73.09 57.01,73.42 UCPU1.L63
H_CPUPWRGD_R: length 10.9
  IN4 w0.076: v4(58.8,78.78) 58.8,79.81 57.03,81.57 54.36,81.57 52.76,83.17 52.76,83.79 v8(52.7,83.86)
  GND5 w0.076: v5(59.24,78.62) 58.96,78.62 v4(58.8,78.78)
  BOTTOM w0.102: v8(52.7,83.86) 53.06,84.21 RC44.2 ; UCPU1.C61 v5(59.24,78.62)
H_DRAMRST#: length 10.5
  IN2 w0.508: v8(86.35,53.61) 87.14,53.61 87.5,53.25 87.87,53.25 88.59,53.96 88.59,54.65 89.4,55.46 89.4,57.06 88.26,58.2 88.26,58.25 v4(87.7,58.81)
  GND5 w0.254: v4(87.7,58.81) 87.73,58.84 v5(88.31,58.84)
  BOTTOM w0.254: UCPU1.AV15 88,58.53 v5(88.31,58.84)
  BOTTOM w0.508: v8(86.35,53.61) 86.35,53.05 RC162.1
H_PECI: length 106.9
  TOP w0.102: v3(147.34,66.08) 147.43,65.99 R240.2
  IN2 w0.076: v3(147.34,66.08) 147.19,65.93 145.37,65.93 144.95,66.34 142.92,66.34 141.54,67.73 139.31,67.73 138.32,66.74 136.75,66.74 136.3,67.18 132.49,67.18 131.46,68.21 130.65,68.21 129.95,67.51 127.97,67.51 125.77,65.32 121.22,65.32 120.96,65.57 119.4,65.57 118.76,66.21 109.85,66.21 109.13,65.48 106.47,65.48 105.98,65 104.35,65 104.01,65.34 104.01,65.49 102.78,66.72 101.49,66.72 101.01,67.2 97.97,67.2 97.63,67.54 95.36,67.54 95.24,67.42 93.09,67.42 92.87,67.64 92.87,69.37 92.34,69.9 92.34,70.42 92.01,70.75 92.01,73.14 91.46,73.69 88.96,73.69 87.46,72.18 86.32,72.18 83.56,74.94 83.56,75.39 82.31,76.64 60.98,76.64 60.6,76.26 60.04,76.26 59.2,75.43 59.2,73.04 v4(59.58,72.66)
  GND5 w0.076: v5(58.97,72.48) 59.41,72.48 v4(59.58,72.66)
  BOTTOM w0.102: v5(58.97,72.48) 58.78,72.67 UCPU1.N62
H_PROCHOT#: length 192.8
  TOP w0.102: v6(127.03,65.82) 127.03,67.17 129.51,69.65 U635.4 ; PQ104.1 117.28,25.41 117.46,25.59 v1(117.46,25.9) 117.3,26.05 116.47,26.05 115.51,25.1 115.26,25.1 115.13,25.22 PQ105.3 ; PQ106.1 114.77,53.59 v3(114.85,53.51)
  GND1 w0.076: v4(126.87,65.32) 127.03,65.48 v6(127.03,65.82)
  IN1 w0.076: v1(117.46,25.9) 117.46,27.3 117.24,27.52 117.24,32.72 113.57,36.39 112.59,36.39 111.51,37.46 111.51,43.06 112.57,44.11 112.57,47.99 111.98,48.58 111.98,50.46 114.85,53.33 v3(114.85,53.51)
  IN2 w0.076: v4(126.87,65.32) 126.83,65.32 125.84,64.33 121.53,64.33 120.9,63.69 120.14,63.69 120.09,63.74 117.25,63.74 115.39,61.87 109.95,61.87 107.26,64.57 106.31,64.57 106.21,64.47 104.1,64.47 103.45,65.11 103.45,65.3 102.79,65.95 101.47,65.95 100.76,66.66 97.7,66.66 97.01,67.35 95.46,67.35 95.3,67.18 93.11,67.18 92.72,67.58 92.72,69.3 92.18,69.84 92.18,70.36 91.85,70.69 91.85,73.08 91.4,73.53 89.02,73.53 87.52,72.03 86.26,72.03 83.28,75.01 83.28,75.02 83.05,75.25 61.82,75.25 61.01,74.43 61.01,72.17 60.4,71.56 52.19,71.56 v1(50.49,73.27)
  GND5 w0.076: v5(126.99,64.88) 126.99,65.19 v4(126.87,65.32)
  BOTTOM w0.102: v1(50.49,73.27) 49.22,74.54 49.22,76.38 49.87,77.03 51.96,77.03 52.38,76.61 RC41.1 52.67,77.1 52.41,77.35 49.19,77.35 48.62,77.92 48.62,79.79 v2(45.17,83.25) 41.83,83.25 41.4,82.82 33.02,82.82 C656.1 RC43.1 R265.1 ; v3(114.85,53.51) 115.7,52.65 118.33,52.65 119.04,51.94 120.34,51.94 122.98,54.58 122.98,58.69 127.05,62.75 127.05,64.83 v5(126.99,64.88)
H_PROCHOT#_R: length 12.8
  BOTTOM w0.102: RC41.2 53.25,76.61 53.12,76.73 53.12,77.25 53.25,77.38 53.98,77.38 54.1,77.27 54.1,76.3 54.87,75.53 55.33,75.53 55.4,75.6 55.4,75.73 55.51,75.83 55.73,75.83 55.81,75.76 55.81,75.55 55.94,75.43 56.12,75.43 56.24,75.55 56.24,75.68 56.32,75.75 56.5,75.75 56.66,75.59 56.66,75.41 56.41,75.16 56.41,74.94 56.64,74.71 56.82,74.71 56.93,74.83 56.93,75 57.03,75.1 57.18,75.1 57.31,74.97 57.31,74.61 57,74.31 57,74.08 57.16,73.93 57.51,73.93 57.61,74.03 57.61,74.28 57.95,74.62 58.1,74.62 58.25,74.76 58.38,74.76 58.55,74.59 58.55,74.51 58.22,74.17 UCPU1.K63
H_PROCHOT_EC: length 49.2
  TOP w0.102: U635.2 131.72,69 131.16,69.56 R608.2 130.56,70.8 v1(129.88,70.12) ; v1(119.97,65.14) 119.97,64.77 114.54,59.34 PR110.1 ; v6(143.16,61.33) 143.31,61.33 143.42,61.43 U34.E2
  GND1 w0.076: v4(143.11,62.01) 143.16,61.96 v6(143.16,61.33)
  IN3 w0.076: v4(143.11,62.01) 142.56,62.56 140.39,62.56 139.64,61.81 138.73,61.81 138.48,61.56 137.23,61.56 136.95,61.84 136.95,63.28 137.37,63.7 137.93,63.7 138.09,63.87 138.09,65.12 137.84,65.38 137.46,65.38 136.91,64.83 136.28,64.83 136.06,64.62 134.64,64.62 134.32,64.94 134.32,65.16 133.88,65.61 132.84,65.61 130.61,67.83 130.61,69.38 v1(129.88,70.12)
  BOTTOM w0.102: v1(119.97,65.14) 119.97,65.54 v2(120.18,65.75) 120.3,65.87 120.92,65.87 121.58,65.21 125.18,65.21 129.88,69.91 v1(129.88,70.12)
H_THERMTRIP#: length 0.9
  BOTTOM w0.102: RC149.1 RC49.2
H_THERMTRIP#_R: length 10.7
  BOTTOM w0.076: 60.12,80.12 60.24,80 60.24,78.61 59.95,78.32 UCPU1.D60
  BOTTOM w0.102: 60.12,80.12 59.96,80.28 56.62,80.28 54.77,82.13 v2(54.77,82.97) 55.21,83.41 RC49.1
HDA_BIT_CLK: length 5.5
  BOTTOM w0.076: UCPU1.AW8 91.75,58.06 91.67,58.14 91.54,58.14 91.46,58.06 91.46,56.98 91.71,56.73
  BOTTOM w0.102: RP3.8 92.39,54.03 92.17,54.24 v2(92.17,54.95) 92.17,56.28 91.71,56.73
HDA_BITCLK_AUDIO: length 52.7
  TOP w0.102: RA16.2 118.64,41.88 120.1,41.88 v6(120.28,42.06) ; UA1.6 v6(125.61,48.51)
  GND1 w0.076: v6(125.61,48.51) 125.56,48.51 v4(125.13,48.08) ; v6(120.28,42.06) 120.56,42.34 v4(120.77,42.34)
  IN1 w0.076: v4(125.13,48.08) 125.13,47.28 124.19,46.34 122.91,46.34 122.22,45.66 122.22,43.27 121.29,42.34 v4(120.77,42.34)
  GND5 w0.076: v5(124.43,47.65) 124.72,47.65 125.13,48.06 v4(125.13,48.08)
  BOTTOM w0.102: v5(124.43,47.65) 124.23,47.85 123.86,47.85 123.76,47.75 123.76,47.18 123.65,47.08 123.45,47.08 123.35,47.18 123.35,47.78 123.24,47.88 123.04,47.88 122.94,47.78 122.94,47.18 122.84,47.08 117.19,47.08 115.62,48.65 107.06,48.65 105.99,47.59 v2(102,47.59) 94.56,47.59 92.91,49.24 92.91,51.47 92.39,51.99 RP3.1
HDA_BITCLK_AUDIO_C: length 4.6
  TOP w0.102: v1(16.99,25.77) v2(16.53,25.31) 16.1,25.31 15.78,25.63 15.78,26.37 MC1297.1 16.17,26.76 ML9.2
  BOTTOM w0.102: JIOL1.14 17.1,25.66 v1(16.99,25.77)
HDA_BITCLK_DSP: length 119.7
  TOP w0.102: 18.09,28.78 18.32,28.55 ML9.1 ; 18.09,28.78 16.42,30.46 16.42,41.16 17.77,42.51 23.63,42.51 24.24,43.12 28.89,43.12 30.16,44.39 32.1,44.39 33.2,43.28 35.68,43.28 36.02,42.94 37.28,42.94 37.58,42.63 40.93,42.63 41.31,43.01 67.64,43.01 68.2,42.46 77.1,42.46 77.91,43.27 84.49,43.27 84.64,43.12 111.24,43.12 112.56,41.8 UA2.4 114.41,41.8 115.06,42.44 116.78,42.44 116.89,42.34 RA14.2 ; 18.09,28.78 v2(18.09,28.79)
HDA_BITCLK_DSP_B: length 7
  TOP w0.102: UA1.23 121.22,42.04 120.89,42.38 v2(119.27,42.38) 118.18,42.38 RA14.1 118.14,42.33 117.23,41.41 RA16.1 116.69,41.39 116.45,41.15 UA2.2
HDA_RST#: length 6.1
  BOTTOM w0.076: 91.51,56.55 91.29,56.78 91.29,58.68 UCPU1.AU8
  BOTTOM w0.102: RP3.7 91.89,53.81 91.64,54.06 91.64,56.43 91.51,56.55
HDA_RST_AUDIO#: length 43.4
  TOP w0.102: v1(110.9,47.94) 110.88,47.97 RA20.2 ; UA1.11 123.11,48.6 122.98,48.73 v1(122.98,48.7)
  BOTTOM w0.102: v1(122.98,48.7) 123.31,48.37 124.43,48.37 124.84,47.97 124.84,47.38 123.6,46.15 117.42,46.15 115.4,48.17 111.13,48.17 v1(110.9,47.94) 110.67,48.17 107.26,48.17 106.19,47.1 94.15,47.1 92.43,48.83 v2(92.43,50.33) 92.43,51.24 91.89,51.78 RP3.2
HDA_RST_DSP#: length 136.5
  TOP w0.102: v6(37.85,43.83) 38.03,43.65 40.62,43.65 40.92,43.95 68.03,43.95 68.54,43.45 76.76,43.45 77.52,44.21 83.84,44.21 84.5,44.87 v2(106,44.87) 106.43,45.3 107.51,45.3 108.39,46.18 108.39,47.56 108.8,47.97 RA20.1 109.65,47.51 111.08,47.51 111.39,47.21 111.39,44.81 112.49,43.7 120.61,43.7 121.45,44.54 UA1.18
  GND1 w0.076: v4(37.15,43.72) 37.26,43.83 v6(37.85,43.83)
  IN1 w0.076: v4(37.15,43.72) 37.15,43.4 36.76,43 35.53,43 33.9,44.64 25.72,44.64 25.33,44.26 18.61,44.26 16.52,42.16 16.52,37.54 14.99,36.02 14.99,25.76 16.81,23.94 17.62,23.94 v1(17.95,23.61)
  BOTTOM w0.102: v1(17.95,23.61) 18.6,24.26 JIOL1.20
HDA_SDIN0: length 53.3
  TOP w0.102: v1(124.85,48.91) 124.78,48.97 124.78,50 RA1.1
  GND5 w0.076: v5(89.99,56.05) 89.99,56.22 90.29,56.53 v4(90.32,56.53) 90.32,56.54 90.87,56.54 v5(91,56.4)
  BOTTOM w0.076: v5(89.99,56.05) 89.86,55.92 89.86,55.4 89.15,54.69 89.15,52.88 88.95,52.69 88.95,52.16 ; v5(91,56.4) UCPU1.AY10
  BOTTOM w0.102: 88.95,52.16 88.95,49.61 92.17,46.39 106.78,46.39 107.31,46.93 108.73,46.93 v2(109.13,46.53) 109.27,46.39 111.06,46.39 111.31,46.65 115.87,46.65 117.05,45.47 124.06,45.47 125.78,47.18 125.78,48.67 125.51,48.93 124.87,48.93 v1(124.85,48.91)
HDA_SDIN0_AUDIO: length 23.1
  TOP w0.102: v6(120.15,43.15) 120.07,43.23 112.17,43.23 110.09,45.31 RA18.2 ; v2(123.29,49.33) 123.5,49.54 RA1.2 124.33,48.82 124.52,48.63 v6(124.52,48.49) 124.61,48.39 UA1.8
  GND1 w0.076: v6(120.15,43.15) v4(120.59,43.15) ; v6(124.52,48.49) v4(124.52,48.08)
  IN1 w0.076: v4(124.52,48.08) 124.52,47.4 123.93,46.81 122.71,46.81 121.76,45.86 121.76,43.84 121.36,43.43 120.87,43.43 v4(120.59,43.15)
HDA_SDIN0_DSP: length 130
  TOP w0.102: UA1.21 121.42,43.04 121.2,42.82 119.79,42.82 119.67,42.95 112.12,42.95 109.18,45.9 RA18.1 109.1,46.06 107.61,44.58 106.92,44.58 106.09,43.75 77.71,43.75 76.9,42.94 68.4,42.94 67.84,43.5 41.11,43.5 40.73,43.12 37.78,43.12 37.48,43.42 36.35,43.42 36.01,43.76 33.41,43.76 32.3,44.87 29.96,44.87 28.69,43.6 24.04,43.6 23.43,42.99 17.57,42.99 15.93,41.36 15.93,30.26 16.97,29.22 v1(16.97,28.33)
  BOTTOM w0.102: v1(16.97,28.33) 17,28.31 17.51,28.31 v2(18.72,27.1) 20.1,25.72 JIOL1.26
HDA_SDO: length 65.7
  TOP w0.081: U34.C1 144.42,62.72 144.32,62.83
  TOP w0.102: Q351.2 R1341.1 97.46,45.58 107.35,45.58 108.05,46.28 v2(108.05,47.05) 108.05,47.71 108.88,48.55 113.66,48.55 v1(114.35,49.24) ; 144.32,62.83 144.32,62.86 v6(144.3,62.88)
  GND1 w0.076: v6(144.3,62.88) 144.3,63.11 144.55,63.36 v4(144.55,63.39)
  IN2 w0.076: v1(114.35,49.24) 114.35,49.54 116.22,51.42 116.22,53.05 119.63,56.45 123.97,56.45 124.47,55.96 126.61,55.96 127.03,56.38 129.85,56.38 130.54,57.06 133.47,57.06 134.65,55.88 136.02,55.88 137.73,57.58 137.73,57.95 138.45,58.67 139.35,58.67 139.92,59.25 141.09,59.25 141.37,59.52 142.29,59.52 142.53,59.77 142.53,60.27 143.49,61.24 143.73,61.24 144.01,61.52 144.01,62.55 144.55,63.08 v4(144.55,63.39)
HDA_SDOUT: length 11
  BOTTOM w0.076: 90.58,56.16 90.55,56.2 90.55,56.65 90.58,56.69 90.58,58.07 90.39,58.25 90.15,58.25 90.02,58.38 90.02,58.91 UCPU1.AU11
  BOTTOM w0.102: RH24.2 90.24,51.46 MC103.1 89.59,52.93 RH42.2 90.36,52.97 RP3.5 90.89,53.95 90.82,54.01 v2(90.82,55.11) 90.82,55.92 90.58,56.16
HDA_SDOUT_AUDIO: length 56
  TOP w0.102: v6(125.94,48.86) 126.11,48.68 UA1.5 ; v6(120.71,41.78) 120.33,41.4 RA17.2
  GND1 w0.076: v6(125.94,48.86) 125.74,49.06 v4(125.53,49.06) ; v4(121.13,41.85) 120.77,41.85 v6(120.71,41.78)
  IN1 w0.076: v4(125.53,49.06) 125.67,48.92 125.67,47.14 122.74,44.21 122.74,43.1 121.48,41.85 v4(121.13,41.85)
  GND5 w0.076: v5(125.42,48.58) 125.42,48.55 125.39,48.58 125.39,48.92 v4(125.53,49.06)
  BOTTOM w0.102: v5(125.42,48.58) 125.42,47.18 123.93,45.69 117.15,45.69 115.13,47.71 112.96,47.71 112.17,46.93 111.25,46.93 110.94,46.62 110.05,46.62 108.96,47.71 107.63,47.71 v2(107.02,47.1) 106.53,46.62 93.36,46.62 91.03,48.96 91.03,51.63 90.89,51.77 RP3.4
HDA_SDOUT_DSP: length 125.2
  TOP w0.102: v6(34.27,42.76) 35.4,42.76 35.71,42.46 37.08,42.46 37.38,42.15 v2(39.99,42.15) 41.13,42.15 41.51,42.53 66.61,42.53 67.8,41.34 68.16,41.34 68.61,41.8 70.31,41.8 70.89,41.22 71.44,41.22 71.56,41.34 72.32,41.34 72.96,41.97 77.3,41.97 78.11,42.79 84.29,42.79 84.44,42.64 111.04,42.64 112.3,41.38 112.3,39.42 112.84,38.88 UA3.4 114.51,38.88 115.25,39.61 116.48,39.61 RA15.2
  GND1 w0.076: v6(34.27,42.76) 34.25,42.74 v4(33.8,42.74)
  IN1 w0.076: v4(33.8,42.74) 33.67,42.86 32.4,42.86 32.01,42.47 29.32,42.47 28.39,43.4 18.93,43.4 17.36,41.82 17.36,37.19 15.91,35.75 15.91,30.48 19.26,27.13 v1(19.26,25.74)
  BOTTOM w0.102: JIOL1.24 19.6,25.4 v1(19.26,25.74)
HDA_SDOUT_DSP_B: length 8.7
  TOP w0.102: UA1.24 121.18,41.54 120.56,40.92 119.59,40.92 119.11,41.4 RA17.1 118.96,41.4 118.57,41.02 118.57,40.79 RA15.1 117.29,39.51 v2(117.29,39.03) 117.29,38.72 116.8,38.23 UA3.2
HDA_SPKR: length 141.2
  TOP w0.102: v6(89.62,49.26) 87.47,47.12 85.26,47.12 83.32,45.17 77.12,45.17 76.36,44.41 68.97,44.41 68.46,44.92 40.52,44.92 40.22,44.62 36.96,44.62 36.76,44.82 35.64,44.82 35.19,44.36 33.46,44.36 32.49,45.33 29.7,45.33 28.43,44.06 23.85,44.06 23.26,43.47 17.4,43.47 15.48,41.55 15.48,29.76 v8(16.26,28.97)
  GND1 w0.076: v4(89.96,49.7) 89.95,49.7 89.94,49.71 89.62,49.39 v6(89.62,49.26)
  IN1 w0.076: v4(89.96,49.7) 89.39,49.7 87.78,51.31 86.77,51.31 84.33,53.75 84.33,56.54 83.76,57.11 83.76,59.63 83.94,59.8 83.94,66 85.19,67.25 86.13,67.25 88.84,69.96 91.43,69.96 91.71,70.24 v4(91.71,70.32)
  GND5 w0.076: v5(92.25,70.27) 92.17,70.35 91.74,70.35 v4(91.71,70.32)
  BOTTOM w0.102: JIOL1.28 20.6,25.71 17.34,28.97 v8(16.26,28.97) ; RH37.2 101.83,70.97 101.83,70.48 100.38,69.02 98.41,69.02 98.18,69.25 96.54,69.25 96.16,69.64 UCPU1.V2 95.78,69.64 95.4,70.02 92.5,70.02 v5(92.25,70.27)
HDA_SYNC: length 5.6
  BOTTOM w0.076: UCPU1.AV11 90.43,58.53 90.73,58.22 90.73,56.29 90.98,56.05 91,56.05
  BOTTOM w0.102: 91,56.05 91.21,55.84 91.21,53.96 91.39,53.78 RP3.6
HDA_SYNC_AUDIO: length 44.8
  TOP w0.102: RA19.2 110.75,47.05 v1(110.76,47.07) ; UA1.10 v1(123.61,48.89)
  BOTTOM w0.102: RP3.3 91.39,49.28 v2(92.61,48.05) 93.79,46.88 106.31,46.88 107.37,47.94 109.89,47.94 v1(110.76,47.07) 111.64,47.94 115.29,47.94 117.3,45.92 123.81,45.92 125.11,47.23 125.11,48.02 124.21,48.92 123.64,48.92 v1(123.61,48.89)
HDA_SYNC_DSP: length 131.5
  TOP w0.102: v1(16.07,28.16) 16.69,28.78 16.69,29.17 15.7,30.16 15.7,41.45 17.47,43.22 23.33,43.22 23.94,43.83 28.59,43.83 29.86,45.1 32.4,45.1 33.5,43.99 36.11,43.99 36.45,43.65 37.57,43.65 37.88,43.35 40.64,43.35 41.02,43.73 67.94,43.73 68.5,43.17 76.8,43.17 77.62,43.98 84.17,43.98 v2(84.43,44.24) 84.7,44.51 106.2,44.51 106.66,44.96 107.58,44.96 108.67,46.05 108.67,46.77 108.95,47.05 RA19.1 109.65,46.58 110.52,46.58 111.01,46.1 111.01,44.81 112.34,43.47 120.78,43.47 121.36,44.04 UA1.19
  BOTTOM w0.102: JIOL1.18 18.1,26.13 v1(16.07,28.16)
HUB_OSC_IN: length 8.8
  TOP w0.076: 160.71,66.51 160.62,66.42 159.86,66.42 159.8,66.36 159.69,66.36 159.49,66.17 159.49,65.87 U636.D8
  TOP w0.102: 160.71,66.51 161.21,67.01 v1(161.75,67.01) 162.21,67.01 C1204.1 163.03,70.04 163.18,70.19 Y2.1
HUB_OSC_OUT: length 8.3
  TOP w0.076: U636.D7 159.3,65.57 159.3,66.18 159.6,66.49 159.6,66.51
  TOP w0.102: 159.6,66.51 159.68,66.59 160.48,66.59 161.24,67.34 161.24,67.37 C1205.1 162.15,67.83 162.59,68.28 162.59,70.05 162.45,70.19 Y2.2
HWPG: length 47.9
  TOP w0.076: U34.F1 142.92,62.83
  TOP w0.102: R1133.2 144.89,69.81 R1154.2 145.3,69.81 D109.2 145.64,68.41 145.64,67.36 R930.2 146.67,66.9 v2(147.3,67.53) 147.3,67.54 148.48,67.54 R982.2 149.61,66.87 R931.2 150.1,66.85 v6(150.15,66.9) 150.54,66.9 150.91,66.54 150.91,65.61 149.97,64.67 149.21,64.67 148.78,64.24 144.18,64.24 142.92,62.98 142.92,62.83 ; U690.2 159.25,52.41 R934.2 159.1,51.45 R1296.1 159.39,51.4 v1(159.82,51.83)
  GND1 w0.076: v4(150.59,67.37) 150.15,66.93 v6(150.15,66.9)
  IN3 w0.076: v1(159.82,51.83) 158.74,51.83 157.83,52.74 157.83,54.62 156.59,55.87 153.93,55.87 153.03,56.77 153.03,58.81 151.71,60.13 151.71,61.15 150.36,62.5 150.36,67.09 150.57,67.3 150.57,67.35 v4(150.59,67.37)
I2C0_SCK: length 196.3
  TOP w0.102: RH462.1 R1224.1 164.47,62.04 v6(164.88,61.63) ; RA8.2 123.71,37.78 123.71,37.21 v1(123.41,36.92) ; v6(150.06,70.32) 150.21,70.47 151.14,70.47 v2(151.19,70.52) 151.39,70.73 151.39,72 151.06,72.33 151.06,72.43 R1307.2 150.7,72.79 Q352.1
  GND1 w0.076: v6(164.88,61.63) 164.88,62.13 v4(164.87,62.14) ; v6(150.06,70.32) 149.98,70.24 v4(149.98,69.72)
  IN1 w0.076: v4(164.87,62.14) 164.66,62.34 164.42,62.34 164.29,62.22 164.29,61.7 164.85,61.14 164.85,60.04 168.42,56.47 168.42,55.31 169.72,54.01 169.72,52.95 170.61,52.06 171.66,52.06 175.86,47.85 175.86,44.34 176.33,43.87 176.33,30.84 174.64,29.15 174.64,27.67 174.87,27.44 174.87,25.44 174.31,24.88 152.93,24.88 151.38,26.43 146.93,26.43 144.66,28.7 142.22,28.7 140.76,30.16 133.64,30.16 132.54,29.07 129.33,29.07 128.8,29.6 127.98,29.6 124.45,33.13 124.45,35.44 123.74,36.15 123.74,36.59 v1(123.41,36.92)
  IN2 w0.076: v4(95.93,76.34) 96.14,76.13 96.14,75.77 97.57,74.34 97.57,73.55 98.32,72.8 99.91,72.8 101.32,71.39 104.63,71.39 104.82,71.2 107.73,71.2 107.96,70.97 107.96,70.48 108.22,70.22 113.96,70.22 114.4,70.66 120.73,70.66 122.39,72.32 126.1,72.32 127.77,70.65 132.35,70.65 132.71,70.29 135.44,70.29 136.12,70.98 138.45,70.98 138.87,70.56 140.95,70.56 141.5,70.02 142.53,70.02 142.6,69.94 145.92,69.94 146.1,70.12 147.16,70.12 147.55,69.73 148.32,69.73 148.54,69.51 149.77,69.51 v4(149.98,69.72) 150.22,69.72 150.61,69.33 150.89,69.33 151.37,68.85 152.99,68.85 154.01,67.83 157.2,67.83 158.31,66.71 158.31,66.32 158.89,65.75 160.22,65.75 160.96,65.01 160.97,65.01 161.5,64.48 161.5,64.24 162.13,63.61 163.08,63.61 164.25,62.45 164.56,62.45 v4(164.87,62.14)
  GND5 w0.076: v4(95.93,76.34) v5(95.65,76.62)
  BOTTOM w0.076: UCPU1.F3 95.6,76.62 v5(95.65,76.62) 95.73,76.7 95.93,76.7 96.22,76.99
  BOTTOM w0.102: 96.22,76.99 96.82,76.99 97.59,77.76 99.51,77.76 RH425.1
I2C0_SCK_DSP: length 2.2
  TOP w0.102: UA1.26 123.11,40.17 123.72,39.57 123.72,39.37 RA8.1
I2C0_SCK_SNR: length 40.5
  TOP w0.076: 162.24,62.9 162.2,62.94 162.17,62.94 162.03,63.07 161.3,63.07 U636.G3
  TOP w0.102: 162.24,62.9 162.34,62.8 162.34,62.43 162.71,62.06 R1224.2 165.26,60.36 165.26,59.64 v2(163.98,58.36) 163.98,57.39 v1(164.05,57.32) ; JSNRDG.18 176.28,80.96 v1(176.31,80.99)
  IN3 w0.076: v1(176.31,80.99) 175.89,80.57 175.33,80.57 171.89,77.13 171.04,77.13 169.6,75.69 169.6,74.17 169.95,73.83 169.95,72.35 169.81,72.21 169.81,70.65 168.31,69.15 168.31,67.96 166.89,66.54 166.89,61.68 165.13,59.93 165.13,58.48 164.05,57.4 v1(164.05,57.32)
I2C0_SDA: length 193
  TOP w0.102: RA7.2 123.93,37.78 123.93,37.11 v8(124.15,36.89) ; v6(148.08,70.7) 147.67,71.11 R1308.2 148.5,71.36 148.65,71.21 Q352.4 ; v6(164.95,63.26) 164.91,63.3 164.61,63.3 164.47,63.17 R1225.1 RH461.1
  GND1 w0.076: v4(164.87,62.75) 164.95,62.84 v6(164.95,63.26) ; v4(148.38,70.19) 148.08,70.5 v6(148.08,70.7)
  IN1 w0.076: v4(164.87,62.75) 164.66,62.55 164.34,62.55 164.09,62.3 164.09,61.61 164.65,61.05 164.65,59.96 168.22,56.39 168.22,55.22 169.51,53.93 169.51,52.86 170.52,51.85 171.58,51.85 175.66,47.77 175.66,44.25 176.13,43.78 176.13,30.92 174.44,29.23 174.44,27.59 174.67,27.36 174.67,25.52 174.23,25.08 153.02,25.08 151.46,26.64 147.01,26.64 144.75,28.9 142.31,28.9 140.85,30.37 133.55,30.37 132.46,29.27 129.42,29.27 128.88,29.81 128.06,29.81 124.66,33.21 124.66,35.52 123.95,36.23 123.95,36.69 v8(124.15,36.89)
  IN2 w0.076: v4(164.87,62.75) 164.76,62.65 164.33,62.65 163.16,63.82 162.21,63.82 161.7,64.33 161.7,64.56 161.05,65.21 161.04,65.21 160.31,65.95 158.97,65.95 158.52,66.41 158.52,66.8 157.28,68.03 154.09,68.03 153.08,69.05 151.45,69.05 150.97,69.53 150.73,69.53 150.15,70.12 149.82,70.12 149.41,69.71 148.62,69.71 148.38,69.95 v4(148.38,70.19) 148.12,69.93 147.63,69.93 147.25,70.32 146.01,70.32 145.83,70.14 142.69,70.14 142.61,70.22 141.58,70.22 141.04,70.76 138.95,70.76 138.53,71.18 136.04,71.18 135.35,70.5 132.79,70.5 132.44,70.85 127.86,70.85 126.19,72.52 122.31,72.52 120.65,70.87 114.32,70.87 113.88,70.42 108.31,70.42 108.16,70.57 108.16,71.06 107.82,71.4 104.9,71.4 104.71,71.59 101.4,71.59 99.99,73 98.4,73 97.77,73.63 97.77,74.42 96.34,75.85 96.34,76.16 v4(96.53,76.34)
  GND5 w0.076: v5(96.24,76.62) 96.51,76.34 v4(96.53,76.34)
  BOTTOM w0.076: 96.62,76.76 96.37,76.76 v5(96.24,76.62) 96,76.38 UCPU1.F2
  BOTTOM w0.102: RH424.1 99.46,77.53 97.69,77.53 96.91,76.76 96.62,76.76
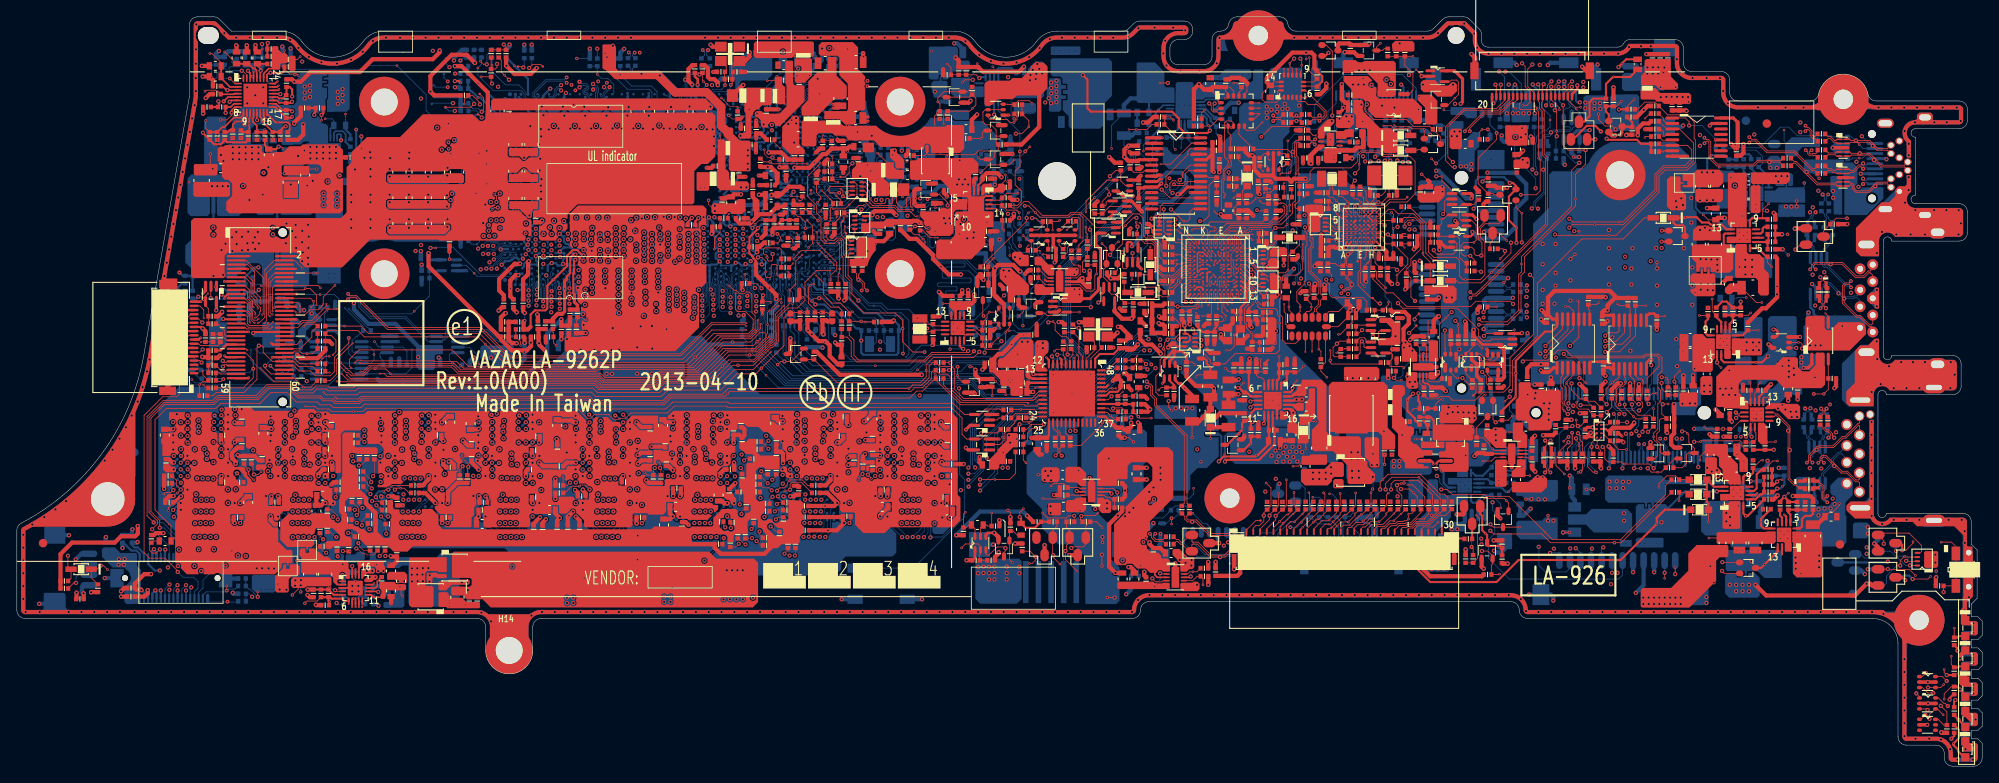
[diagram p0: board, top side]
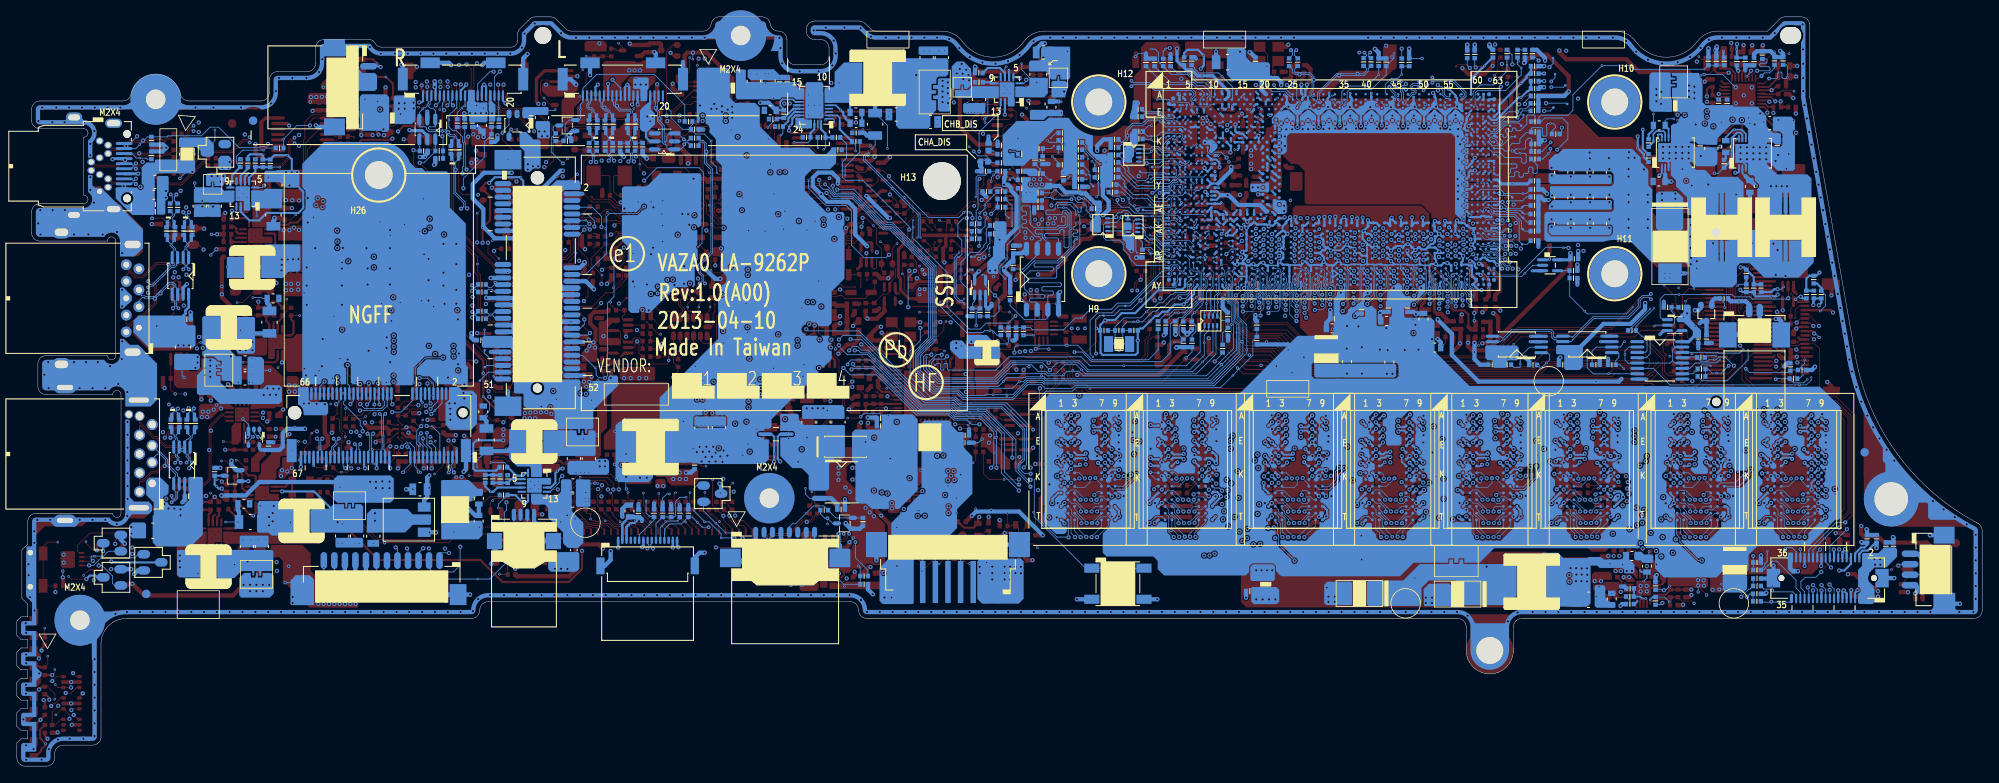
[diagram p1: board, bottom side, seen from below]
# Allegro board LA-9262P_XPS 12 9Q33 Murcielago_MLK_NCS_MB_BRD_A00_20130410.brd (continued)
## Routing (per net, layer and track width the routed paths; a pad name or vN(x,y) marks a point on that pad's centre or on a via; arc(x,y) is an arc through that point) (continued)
I2C0_SDA_DSP: length 2.1
  TOP w0.102: UA1.27 123.61,40 123.94,39.67 123.94,39.35 RA7.1
I2C0_SDA_SNR: length 31.4
  TOP w0.076: U636.F3 160.8,63.57 162.23,63.57 162.24,63.56
  TOP w0.102: v1(175.67,80.99) 175.78,80.88 JSNRDG.19 ; v2(163.53,63.91) 163.56,63.88 R1225.2 163.13,62.95 v1(162.9,63.18) 162.87,63.21 162.63,63.21 162.28,63.56 162.24,63.56
  IN3 w0.076: v1(162.9,63.18) 163.02,63.31 166.33,63.31 166.61,63.59 166.61,66.51 168.13,68.03 168.13,73.58 169.09,74.55 169.09,75.44 171,77.34 171.82,77.34 175.47,80.99 v1(175.67,80.99)
I2C1_SCK: length 185.6
  TOP w0.102: v6(152.32,70.35) 152.23,70.43 152.23,72.35 152.05,72.53 152.05,74.04 152.14,74.13 152.31,74.13 152.51,73.93 R1152.1 ; R1257.1 136.2,26.95 135.34,26.95 135.05,27.24 135.05,27.41 v3(135.25,27.62)
  GND1 w0.076: v4(152.48,69.79) 152.32,69.95 v6(152.32,70.35)
  IN1 w0.076: v3(135.25,27.62) 135.05,27.82 135.05,28.09 135.14,28.18 144.31,28.18 148.5,23.99 175.36,23.99 177.48,26.11 177.48,38.94 179.01,40.47 179.01,43.31 179.65,43.95 179.65,48.56 175.88,52.34 175.88,54.72 170.47,60.13 170.47,62.62 166.38,66.71 165.39,66.71 164.66,67.45 159.98,67.45 159.53,67.91 153.84,67.91 152.58,69.16 152.37,69.16 152.23,69.3 152.23,69.53 v4(152.48,69.79)
  IN2 w0.076: v4(97.11,76.16) 97.37,75.91 97.37,75.62 97.61,75.37 98.4,75.37 101.52,72.25 102.71,72.25 102.94,72.48 103.83,72.48 103.96,72.35 107.24,72.35 108.3,71.29 109.11,71.29 109.65,70.75 113.48,70.75 113.86,71.13 120.63,71.13 122.25,72.76 126.61,72.76 128.31,71.06 133.47,71.06 133.71,70.82 135.15,70.82 135.72,71.39 138.68,71.39 139.06,71.01 144.92,71.01 145.31,70.61 150.8,70.61 151.25,70.17 151.25,69.64 151.53,69.35 152.05,69.35 v4(152.48,69.79)
  GND5 w0.076: v4(97.11,76.16) 97.26,76.31 v5(97.26,76.59)
  BOTTOM w0.102: RH364.1 102.29,74.14 102.15,74.14 101.8,74.49 101.8,75.57 100.98,76.39 99.74,76.39 99.21,76.92 97.59,76.92 v5(97.26,76.59) 97.09,76.42 UCPU1.F1
I2C1_SCK_TP: length 19.2
  TOP w0.102: R1377.2 138.77,29.68 138.77,29.35 139.08,29.03 v1(139.64,29.03) 140.06,29.03 141.67,27.42 143.98,27.42 144.1,27.3 144.1,26.81 v1(143.9,26.61) 144.13,26.38 144.13,25.74 143.46,25.07 141.9,25.07 140.35,26.62 139.71,26.62 139.61,26.72 DE1.2 139.36,27.47 138.5,26.61 138.34,26.61 138.01,26.94 137.76,26.94 R1257.2
  BOTTOM w0.102: JTP1.3 143.72,27.41 144.11,27.01 144.11,26.82 v1(143.9,26.61)
I2C1_SCK_TS: length 11.4
  TOP w0.102: v3(154.21,73.9) 154.03,74.08 153.75,74.08 R1152.2
  BOTTOM w0.102: R1152.2 153.75,74.08 154.03,74.08 v3(154.21,73.9) 154.22,73.89 154.22,73.71 154.63,73.31 MD90.1 156.08,73.31 156.27,73.49 156.27,73.72 156.47,73.93 156.62,73.93 156.81,74.12 156.81,76.07 157.37,76.63 157.37,77.71 157.61,77.95 v1(157.61,78.24) 157.61,78.93 157.75,79.06 JLVDS1.18
I2C1_SDA: length 187.2
  TOP w0.102: v3(134.62,27.62) 134.82,27.42 134.82,27.15 135.25,26.72 136.18,26.72 R1258.1 ; R1153.1 152.24,74.37 152.05,74.37 151.82,74.14 151.82,72.43 151.98,72.28 151.98,70.38 v6(151.94,70.35)
  GND1 w0.076: v6(151.94,70.35) 151.94,69.82 v4(151.9,69.79)
  IN1 w0.076: v4(151.9,69.79) 152.03,69.66 152.03,69.22 152.28,68.96 152.5,68.96 153.76,67.7 159.44,67.7 159.9,67.25 164.57,67.25 165.31,66.51 166.29,66.51 170.26,62.54 170.26,60.05 175.67,54.64 175.67,52.25 179.45,48.48 179.45,44.03 178.81,43.4 178.81,40.56 177.27,39.02 177.27,26.2 175.27,24.19 148.58,24.19 144.4,28.38 135.06,28.38 134.85,28.17 134.85,27.85 v3(134.62,27.62)
  IN2 w0.076: v4(151.9,69.79) 151.67,69.56 151.62,69.56 151.45,69.72 151.45,70.25 150.88,70.82 145.4,70.82 145,71.21 139.14,71.21 138.76,71.59 135.63,71.59 135.06,71.02 133.8,71.02 133.56,71.26 128.39,71.26 126.69,72.96 122.17,72.96 120.54,71.34 113.77,71.34 113.39,70.95 109.73,70.95 109.2,71.49 108.39,71.49 107.32,72.56 104.04,72.56 103.91,72.68 102.86,72.68 102.63,72.45 101.61,72.45 98.48,75.58 97.7,75.58 97.57,75.7 97.57,76.03 v4(97.67,76.14)
  GND5 w0.076: v5(97.64,76.59) 97.64,76.16 v4(97.67,76.14)
  BOTTOM w0.102: UCPU1.G4 94.99,75.98 97.04,75.98 v5(97.64,76.59) 97.75,76.7 99.09,76.7 99.63,76.16 100.88,76.16 101.57,75.48 v1(101.57,74.92) 101.57,74.4 102.05,73.91 102.23,73.91 RH365.1
I2C1_SDA_TP: length 19.6
  TOP w0.102: R1258.2 137.77,26.71 137.91,26.71 138.25,26.38 138.42,26.38 139.26,25.54 DE1.3 139.61,26.29 139.71,26.39 140.25,26.39 141.8,24.84 v1(142.96,24.84) 143.56,24.84 144.36,25.64 144.36,26.43 v1(144.53,26.61) 144.33,26.81 144.33,27.39 144.08,27.65 141.76,27.65 140.15,29.26 139.18,29.26 139,29.44 139,29.71 R1378.2
  BOTTOM w0.102: JTP1.2 144.72,27.42 144.34,27.04 144.34,26.8 v1(144.53,26.61)
I2C1_SDA_TS: length 11.4
  TOP w0.102: v3(154.25,74.49) 154.07,74.31 153.75,74.31 R1153.2
  BOTTOM w0.102: R1153.2 153.75,74.31 154.07,74.31 v3(154.25,74.49) 154.25,74.51 154.94,75.21 MD90.3 155.94,75.21 156.27,74.88 156.27,74.31 156.42,74.16 156.53,74.16 156.59,74.21 156.59,76.17 157.14,76.73 v1(157.14,76.95) 157.14,77.81 157.39,78.05 157.39,78.93 157.31,79.01 157.25,79.07 JLVDS1.19
I2S_BCLK_OUT: length 2
  TOP w0.102: R1372.2 124.61,39.57 UA1.29
I2S_CLK: length 126.8
  TOP w0.102: v1(181.62,49.95) 183.63,51.96 U677.13 ; v1(130.25,42.51) 130.32,42.58 131.3,42.58 R1374.1 R1373.1 ; R1372.1 126.42,38.11 128.96,40.65 v8(128.96,40.91)
  IN1 w0.076: v1(181.62,49.95) 182.13,50.46 184.96,50.46 185.16,50.25 185.16,46.52 184.2,45.55 184.2,44.22 183.31,43.34 183.31,40.9 182.56,40.14 180.66,40.14 178.62,38.1 178.62,24.16 176.47,22.01 145.33,22.01 140.94,26.4 137.5,26.4 136.23,25.13 129.52,25.13 126.75,27.9 124.07,27.9 122.36,29.62 122.36,31.59 121.22,32.73 121.22,37.83 124.29,40.91 v8(128.96,40.91) 129.17,40.91 130.25,41.99 v1(130.25,42.51)
I2S_CLK_IN: length 2.3
  TOP w0.102: UA1.38 129.55,42.04 v2(129.95,41.64) 130.36,41.24 R1373.2
I2S_SDI_IN: length 122.6
  TOP w0.102: v2(185.44,55.32) 185.58,55.18 U677.10 185.58,50.98 184.55,49.95 v1(184.54,49.95) ; UA1.41 129.66,43.54 v1(130.07,43.95)
  IN1 w0.076: v1(130.07,43.95) 130.75,43.27 130.75,41.85 129.36,40.45 124.48,40.45 121.67,37.64 121.67,32.92 123.24,31.36 123.24,29.6 124.48,28.36 126.94,28.36 129.71,25.59 136.01,25.59 137.28,26.86 141.34,26.86 143.06,25.13 143.7,25.13 146.34,22.49 174.89,22.49 178.16,25.77 178.16,38.46 180.31,40.6 182.37,40.6 182.85,41.08 182.85,43.53 183.74,44.41 183.74,46.38 183.87,46.5 184.5,46.5 184.63,46.63 184.63,46.82 184.5,46.95 183.63,46.95 183.51,47.08 183.51,47.31 183.63,47.43 184.58,47.43 184.7,47.56 184.7,47.87 184.58,47.99 183.38,47.99 183.25,48.12 183.25,48.39 183.38,48.52 184.57,48.52 184.7,48.65 184.7,49.78 v1(184.54,49.95)
I2S_SDO_OUT: length 123.2
  TOP w0.102: v1(125.79,39.84) 125.61,40.01 UA1.31 ; v1(181.6,48.68) 181.62,48.68 184.93,51.99 U677.11 184.93,54.11 184.42,54.62 v2(183.98,54.62)
  IN1 w0.076: v1(125.79,39.84) 125.37,39.42 124.57,39.42 122.93,37.78 122.93,35.98 123.74,35.17 123.74,32.87 124.77,31.84 124.77,29.98 125.61,29.15 128.3,29.15 130.05,27.39 130.25,27.39 130.37,27.52 130.37,28.41 130.5,28.54 130.75,28.54 130.88,28.41 130.88,27.6 131.01,27.47 131.26,27.47 131.39,27.6 131.39,28.41 131.52,28.54 131.77,28.54 131.9,28.41 131.9,27.39 132.02,27.27 132.28,27.27 132.4,27.39 132.4,28.41 132.53,28.54 132.79,28.54 132.91,28.41 132.91,27.27 132.96,27.22 144.81,27.22 149.15,22.87 174.76,22.87 177.81,25.92 177.81,38.73 179.47,40.4 179.47,42.52 180.09,43.14 180.55,43.14 181.19,43.78 182.6,43.78 182.75,43.93 182.75,44.08 182.67,44.16 180.94,44.16 180.87,44.23 180.87,44.46 180.94,44.54 182.72,44.54 182.82,44.64 182.82,44.82 182.72,44.92 180.92,44.92 180.79,45.05 180.79,45.17 180.92,45.3 181.93,45.3 182.09,45.45 182.09,45.71 181.99,45.81 180.28,45.81 180.16,45.94 180.16,46.06 180.28,46.19 181.4,46.19 181.5,46.29 181.5,46.44 181.4,46.55 180.16,46.55 179.98,46.72 179.98,48.43 180.11,48.55 181.48,48.55 v1(181.6,48.68)
I2S_SFRM_IN: length 2.2
  TOP w0.102: UA1.39 129.64,42.54 130.06,42.13 R1374.2
I2S_SFRM_OUT: length 116.2
  TOP w0.102: UA1.30 125.11,39.88 v1(125.15,39.84) ; U677.12 184.28,51.84 181.76,49.31 v8(181.62,49.31)
  IN1 w0.076: v8(181.62,49.31) 182.06,48.87 182.06,48.15 182.16,48.04 183.08,48.04 183.2,47.92 183.2,47.69 183.08,47.56 181.58,47.56 181.45,47.43 181.45,47.21 181.58,47.08 183.26,47.08 183.38,46.95 183.38,46.77 183.26,46.65 182.8,46.65 182.67,46.52 182.67,46.29 182.8,46.16 183.41,46.16 183.53,46.04 183.53,45.81 183.41,45.68 182.39,45.68 182.26,45.55 182.26,45.33 182.39,45.2 183.26,45.2 183.38,45.07 183.38,44.31 182.61,43.54 181.21,43.54 180.64,42.96 180.16,42.96 179.65,42.45 179.65,40.32 177.98,38.66 177.98,25.84 174.84,22.69 146.39,22.69 143.77,25.31 143.14,25.31 141.41,27.04 133.07,27.04 132.91,26.89 132.91,26.23 132.79,26.1 132.68,26.1 132.56,26.23 132.56,26.89 132.43,27.01 132.3,27.01 132.18,26.89 132.18,26.23 132.05,26.1 131.87,26.1 131.74,26.23 131.74,26.92 131.63,27.04 131.46,27.04 131.34,26.92 131.34,26.21 131.23,26.1 131.07,26.1 130.96,26.21 130.96,27.08 130.85,27.19 130.69,27.19 130.58,27.08 130.58,26.61 130.45,26.48 130.35,26.48 130.12,26.71 130.12,27.08 128.22,28.97 125.53,28.97 124.59,29.91 124.59,31.77 123.57,32.79 123.57,35.09 122.75,35.91 122.75,37.86 124.74,39.84 v1(125.15,39.84)
IMON: length 8.5
  TOP w0.102: v1(31.1,73.62) 31.39,73.62 v2(31.62,73.39)
  TOP w0.203: v1(28.54,76.77) 28.52,76.79 PU701.13
  TOP w0.254: PR703.2 29.48,73.78 PC707.2 30.8,73.33 v1(31.1,73.62)
  IN2 w0.254: v1(31.1,73.62) 31.1,74.56 28.89,76.77 v1(28.54,76.77)
IMVP_VR_PG: length 199.8
  TOP w0.102: R1291.1 160.4,55.21 159.93,55.68 v2(156.83,55.68) 156.31,55.68 155.94,56.05 155.94,57.29 155.57,57.66 v1(155.57,57.82) ; v1(57.86,85.76) 58.13,85.49 R1211.2 RC152.1 R1241.2
  TOP w0.203: PR723.1 24.44,80.81 24.92,80.33 v1(25.03,80.33) 26.27,80.33 PU701.3
  IN1 w0.076: v1(25.03,80.33) 25.8,80.33 28.8,83.32 30.78,83.32 31.11,82.99 41.29,82.99 43.8,85.5 57.59,85.5 v1(57.86,85.76)
  IN2 w0.076: v1(57.86,85.76) 58.85,84.77 69.31,84.77 70.63,86.09 73.58,86.09 75.58,84.09 80.75,84.09 82.15,82.69 91.92,82.69 93.52,84.29 108.54,84.29 109.04,84.79 112.55,84.79 115.01,82.33 119.48,82.33 121.23,84.09 125.95,84.09 127.25,85.38 135.22,85.38 135.5,85.1 135.5,83.17 136.77,81.9 143.89,81.9 144.67,82.69 v4(144.67,82.82)
  IN3 w0.076: v1(155.57,57.82) 155.8,58.05 155.8,61.11 157.14,62.46 157.14,63.09 156.9,63.33 156.47,63.33 156.2,63.6 156.2,63.97 156.51,64.27 156.51,66.62 157.44,67.55 158.44,67.55 159.63,68.75 165.62,68.75 165.89,69.02 165.89,74.13 164.52,75.5 162.45,75.5 161.59,76.37 161.59,77.09 161.82,77.32 161.82,82.45 158.91,85.36 151.45,85.36 149.65,83.55 145.41,83.55 v4(144.67,82.82)
INV_PWM_R: length 1.1
  BOTTOM w0.254: v1(159.75,78.63) JLVDS1.14
  vias: v2(159.9,76.61)
JNTRST: length 50.2
  TOP w0.076: 157.41,64.07 157.73,64.07 157.73,64.07 158.3,64.07 U636.B4
  TOP w0.102: 157.41,64.07 156.95,64.07 v2(156.78,64.25) 156.78,64.58 v6(156.51,64.85) 156.25,65.1 RP12.8 ; JSNRDG.4 183.28,80.62 v1(183.18,80.72)
  GND1 w0.076: v4(156.12,64.71) 156.25,64.85 v6(156.51,64.85)
  IN1 w0.076: v1(166.07,63.77) 166.07,64.44 165.64,64.87 163.82,64.87 162.8,63.84 161.73,63.84 161.22,63.33 159.61,63.33 158.06,64.88 156.3,64.88 156.12,64.69 v4(156.12,64.71)
  IN3 w0.076: v1(183.18,80.72) 182.66,80.2 179.88,80.2 178.56,81.52 175.11,81.52 174.51,80.91 174.51,80.28 171.76,77.53 170.9,77.53 168.92,75.55 168.92,74.62 167.95,73.65 167.95,68.13 166.07,66.25 v1(166.07,63.77)
  BOTTOM w0.102: JSATA1.16 166.61,63.22 v1(166.07,63.77)
JTCK: length 51.1
  TOP w0.076: U636.B2 158.29,62.57 157.79,62.57 157.56,62.34 157.41,62.34
  TOP w0.102: v1(183.2,81.36) 182.73,80.9 182.73,80.48 182.78,80.43 JSNRDG.5 ; 157.41,62.34 v2(156.78,62.34) 156.52,62.6 v6(156.42,62.6) 156,62.6 R1099.2
  GND1 w0.076: v6(156.42,62.6) 156.13,62.89 v4(156.13,63.11)
  IN1 w0.076: v4(156.13,63.11) 156.13,62.86 156.54,62.45 157.27,62.45 157.58,62.75 163.19,62.75 164.08,63.64 165.3,63.64 v1(165.44,63.78)
  IN3 w0.076: v1(183.2,81.36) 182.51,82.05 174.89,82.05 173.97,81.14 173.97,80.53 171.52,78.08 170.68,78.08 168.38,75.78 168.38,74.84 167.42,73.88 167.42,68.39 164.46,65.43 164.46,63.88 164.78,63.56 165.22,63.56 v1(165.44,63.78)
  BOTTOM w0.102: JSATA1.14 166.79,64.03 166.61,64.21 165.88,64.21 165.45,63.78 v1(165.44,63.78)
JTDI: length 49.1
  TOP w0.076: U636.C3 158.8,63.07 157.93,63.07 157.55,62.69 157.41,62.69
  TOP w0.102: RP12.5 155.75,63.6 156.32,63.03 156.75,63.03 v6(157.11,62.67) 157.12,62.69 157.41,62.69 ; v2(183.27,78.03) 183.27,78.23 182.28,79.22 JSNRDG.6 182.28,80.71 v1(182.3,80.73)
  GND1 w0.076: v6(157.11,62.67) 156.97,62.67 v4(156.71,62.93)
  IN1 w0.076: v4(156.71,62.93) 156.81,63.03 161.3,63.03 161.9,63.63 162.92,63.63 163.96,64.68 165.23,64.68 v1(165.46,64.45)
  IN3 w0.076: v1(165.46,64.45) 165.46,65.89 167.77,68.2 167.77,73.73 168.74,74.69 168.74,75.64 170.83,77.72 171.67,77.72 174.33,80.38 174.33,80.99 175.04,81.7 181.35,81.7 182.3,80.75 v1(182.3,80.73)
  BOTTOM w0.102: v1(165.46,64.45) 165.84,64.82 JSATA1.12
JTDO: length 51.5
  TOP w0.076: 157.41,63.82 158.04,63.82 U636.A4
  TOP w0.102: 157.41,63.82 156.65,63.82 156.22,64.25 v6(156.17,64.25) 156.17,64.17 155.74,64.6 RP12.7 ; v1(164.88,64.13) 164.88,64.49 165.27,64.88 v2(165.89,64.88) ; v1(182.33,81.38) 181.87,80.92 181.87,80.68 181.78,80.59 JSNRDG.7
  GND1 w0.076: v4(155.59,64.43) 155.77,64.25 v6(156.17,64.25)
  IN3 w0.076: v1(164.88,64.13) 164.88,65.56 167.6,68.27 167.6,73.8 168.56,74.77 168.56,75.71 170.75,77.9 171.6,77.9 174.15,80.45 174.15,81.07 174.96,81.88 181.83,81.88 v1(182.33,81.38)
  IN4 w0.076: v1(164.88,64.13) 164.51,64.5 163.67,64.5 162.74,63.57 161.78,63.57 161.28,63.08 158.52,63.08 157.62,63.97 157.12,63.97 156.8,64.29 155.73,64.29 v4(155.59,64.43)
  BOTTOM w0.102: JSATA1.10 165.7,65.62 164.88,64.81 v1(164.88,64.13)
JTMS: length 64.4
  TOP w0.076: 157.41,63.54 157.44,63.57 159.3,63.57 U636.D4
  TOP w0.102: JSNRDG.3 183.78,79.95 184.31,80.48 184.31,80.99 184.69,81.37 v1(184.78,81.37) ; RP12.6 155.86,64.1 v6(156.19,63.77) 156.42,63.54 157.41,63.54
  GND1 w0.076: v6(156.19,63.77) 156.6,63.77 v4(156.63,63.73)
  IN3 w0.076: v1(184.78,81.37) 184.78,81.55 182.32,84 179.75,84 179.73,83.99 177.85,83.99 177.41,83.55 175.2,83.55 171.69,80.04 170.37,80.04 166.1,75.77 166.1,68.96 165.71,68.57 159.77,68.57 158.51,67.3 157.51,67.3 156.69,66.48 156.69,63.79 v4(156.63,63.73)
  IN4 w0.076: v1(164.04,64.08) 164.04,63.45 163.32,62.73 162.64,62.73 162.45,62.92 158.05,62.92 157.86,63.11 157.25,63.11 v4(156.63,63.73)
  BOTTOM w0.102: JSATA1.8 165.12,66.42 164.04,65.34 v1(164.04,64.08)
KB_BL_DET: length 117.6
  TOP w0.102: R945.2 R944.1 173.54,24.69 173.54,27.75 173.77,27.98 173.77,29.44 v6(173.39,29.82)
  GND1 w0.076: v4(173.17,30.26) 173.39,30.05 v6(173.39,29.82)
  IN4 w0.076: v4(173.17,30.26) 178.57,35.66 178.57,39.99 174.73,43.83 171.56,43.83 169.1,46.29 167.85,46.29 167.08,47.07 150.07,47.07 149.3,46.29 147,46.29 146.81,46.48 142.12,46.48 140.64,45 135.99,45 135.06,44.07 133.83,44.07 130.82,47.08 123.24,47.08 123.01,47.31 116.92,47.31 115.51,48.72 110.7,48.72 109.42,47.43 106.06,47.43 v4(105.61,47.89)
  GND5 w0.076: v4(105.61,47.89) 105.63,47.92 v5(105.63,48.63)
  BOTTOM w0.076: 97.37,58.18 97.32,58.23 96.41,58.23 96.29,58.36 96.29,58.79 95.97,59.11 UCPU1.AU2
  BOTTOM w0.102: v5(105.63,48.63) 105.99,48.98 105.99,52.96 105.07,53.87 103.41,53.87 102.59,54.7 T284.1 101.26,54.7 97.78,58.18 97.37,58.18
KB_DET#: length 169
  TOP w0.102: T282.1 147.2,29.18 146.1,28.08 JKB1.1 146.1,26.92 147.02,26 v1(150.44,26)
  IN1 w0.076: v4(95.83,69) 96.47,69.64 101.03,69.64 102.08,68.59 103.14,68.59 104.34,67.39 106.81,67.39 107.39,66.81 107.67,66.81 109.37,65.12 109.37,64.56 110.33,63.59 112.61,63.59 114.44,65.42 115.29,65.42 116.36,64.34 119.96,64.34 120.57,63.73 120.92,63.73 121.53,64.34 124.18,64.34 125.01,65.16 125.87,65.16 126.83,66.12 132.97,66.12 134.51,67.65 136.38,67.65 136.54,67.49 138.61,67.49 139.7,68.58 149.03,68.58 149.63,67.98 152.45,67.98 153.41,67.02 159.04,67.02 159.86,66.2 160.15,66.2 160.47,65.87 161.96,65.87 162.06,65.77 163.23,65.77 163.44,65.56 165.74,65.56 166.9,64.4 166.9,63.27 167.28,62.89 168.16,62.89 169.46,61.58 169.46,59.88 172.19,57.15 172.19,55.51 172.55,55.16 174.19,55.16 174.99,54.36 174.99,51.97 178.25,48.7 178.25,40.47 176.94,39.16 176.94,26.33 175.16,24.55 151.66,24.55 150.44,25.77 v1(150.44,26)
  GND5 w0.076: v5(95.61,69.38) 95.83,69.16 v4(95.83,69)
  BOTTOM w0.102: RH302.1 102.61,70.87 102.19,70.45 102.19,70.3 100.55,68.67 98.25,68.67 98.04,68.89 UCPU1.Y1 96.61,68.89 96.15,69.35 95.64,69.35 v5(95.61,69.38)
KB_LED_PWM: length 63.1
  TOP w0.102: U34.M9 140.11,58.1 140.24,58.23 v6(140.24,58.37) ; v6(174.3,31.81) 176.71,31.81 v2(176.97,31.56) 177.23,31.3 Q311.2
  GND1 w0.076: v6(174.3,31.81) 174.15,31.81 v4(173.79,31.46) ; v6(140.24,58.37) 139.95,58.66 v4(139.87,58.66)
  IN1 w0.076: v4(139.87,58.66) 140.09,58.44 140.98,58.44 141.25,58.71 144.18,58.71 144.43,58.97 145.08,58.97 146.35,57.7 147.05,57.7 147.8,58.45 148.71,58.45 149.56,57.59 149.56,57.41 151.28,55.69 159.48,55.69 161.44,53.73 163.94,53.73 169.29,48.39 169.29,43.44 167.66,41.82 167.66,36.22 168.22,35.67 168.22,32.96 169.72,31.46 v4(173.79,31.46)
KB_LED_PWM#: length 5.3
  TOP w0.102: v1(175.08,28.74) 175.41,28.41 Q311.1 v2(178.54,28.41)
  BOTTOM w0.102: v1(175.08,28.74) 174.64,28.74 174.45,28.93 JBL1.1
KB_RST#: length 59.6
  TOP w0.076: U34.L2 140.17,61.85 140.17,62.31 140.07,62.4
  TOP w0.084: 140.07,62.4 140.07,62.4 139.73,62.74
  TOP w0.102: v6(138.31,63.92) 138.55,63.92 139.73,62.74
  GND1 w0.076: v4(138.49,64.45) 138.31,64.27 v6(138.31,63.92)
  IN3 w0.076: v4(138.49,64.45) 138.49,64.98 137.91,65.56 137.36,65.56 136.86,65.06 136.24,65.06 136,64.82 135.67,64.82 134.69,65.8 132.9,65.8 130.79,67.91 130.79,70.15 v4(130.8,70.17)
  IN4 w0.076: v4(94.36,69.61) 94.5,69.75 96.83,69.75 97.06,69.98 97.68,69.98 97.96,70.26 98.5,70.26 98.91,70.66 99.66,70.66 100.02,71.03 103.67,71.03 104.12,70.57 104.55,70.57 104.97,70.99 107.35,70.99 v4(107.55,70.79) 108.43,71.67 110.03,71.67 110.66,71.03 112.24,71.03 113.01,71.81 114.43,71.81 114.7,71.54 120.01,71.54 121.15,72.68 126.18,72.68 129.17,69.68 130.32,69.68 v4(130.8,70.17)
  GND5 w0.076: v4(107.55,70.79) 107.68,70.79 v5(108.33,70.14) ; v4(94.36,69.61) 94.37,69.61 v5(94.67,69.3)
  BOTTOM w0.076: UCPU1.V4 94.67,69.3 v5(94.67,69.3)
  BOTTOM w0.102: RH196.1 108.86,69.61 v5(108.33,70.14)
KSI0: length 72.6
  TOP w0.102: v2(155.25,32.49) 155.4,32.34 155.4,30.98 C1190.1 154.08,29.65 154.03,29.65 v6(152.75,28.37) 152.5,28.12 JKB1.9 ; v6(144.28,58.29) 144.09,58.1 U34.D9
  GND1 w0.076: v6(144.28,58.29) 144.42,58.43 v4(144.75,58.43) ; v6(152.75,28.37) v4(152.75,28.8)
  IN1 w0.076: v4(144.75,58.43) 144.98,58.43 146.95,56.46 146.95,55.49 147.4,55.04 147.79,55.04 148.58,54.25 148.58,49.54 149.45,48.68 154.52,48.68 155.1,48.1 166.22,48.1 168.22,46.1 168.22,43.38 166.93,42.09 166.93,35.95 167.51,35.37 167.51,29.88 164.99,27.37 156.84,27.37 156.38,27.83 153.73,27.83 v4(152.75,28.8)
KSI1: length 62.9
  TOP w0.076: U34.E12 143.17,56.35 143.17,55.21
  TOP w0.102: 143.17,55.21 143.17,53.99 v6(143.69,53.47) ; C1192.1 153.12,30.34 v6(152.76,29.98) 152.75,29.98 v2(151.81,29.04) 151.34,29.04 150.86,28.56 150.86,27.89 JKB1.7
  GND1 w0.076: v6(143.69,53.47) 143.69,53.16 v4(143.95,52.9) ; v6(152.76,29.98) 152.76,30.38 v4(152.8,30.42)
  IN1 w0.076: v4(152.8,30.42) 152.8,30.66 152.86,30.72 154.3,30.72 154.5,30.52 156.38,30.52 156.89,30.01 164.03,30.01 164.43,30.41 164.43,30.68 165.09,31.34 165.09,33.35 164.7,33.74 164.7,44.74 164.45,45 155.01,45 153.46,46.55 146.47,46.55 145.17,47.85 145.17,52.95 144.97,53.15 144.21,53.15 v4(143.95,52.9)
KSI2: length 65
  TOP w0.102: JKB1.5 149.3,28.34 v2(150.03,29.07) 150.87,29.91 v6(151.04,29.91) 151.29,30.16 C1186.1 ; U34.E13 143.42,54.52 v6(143.85,54.09)
  GND1 w0.076: v4(150.65,30.09) 150.83,29.91 v6(151.04,29.91) ; v4(144.28,53.91) 144.1,54.09 v6(143.85,54.09)
  IN1 w0.076: v4(150.65,30.09) 151.59,30.09 151.69,29.98 153.16,29.98 153.72,30.54 154.22,30.54 154.43,30.34 156.28,30.34 156.79,29.83 164.99,29.83 165.88,30.73 165.88,34.73 165.23,35.38 165.23,45.02 164.7,45.55 155.29,45.55 153.77,47.08 146.92,47.08 145.73,48.27 145.73,53.21 145.2,53.73 144.46,53.73 v4(144.28,53.91)
KSI3: length 64.8
  TOP w0.076: U34.D12 143.67,56.35 143.67,55.21
  TOP w0.102: 143.67,55.21 143.67,55.08 v6(143.87,54.88) ; v2(153.51,32.5) 153.57,32.44 153.57,30.98 C1191.1 153.5,29.99 v6(153.5,29.98) 151.7,28.19 JKB1.8
  GND1 w0.076: v6(143.87,54.88) 143.89,54.88 v4(144.25,54.52) ; v6(153.5,29.98) 153.79,29.98 v4(153.94,30.14)
  IN1 w0.076: v4(144.25,54.52) 144.25,54.51 144.84,53.92 145.27,53.92 145.96,53.24 145.96,48.31 147.01,47.26 153.84,47.26 154.53,46.57 163.94,46.57 165.41,45.1 165.41,35.45 166.06,34.81 166.06,30.65 165.06,29.65 161.26,29.65 160.5,28.9 157.47,28.9 156.2,30.16 153.97,30.16 v4(153.94,30.14)
KSI4: length 71.9
  TOP w0.102: JKB1.4 148.5,28.2 149.56,29.25 v1(149.56,29.75) 149.58,29.75 150.32,30.49 C1187.1 150.83,30.95 v2(150.83,34.04) ; U34.D13 143.92,55.39 144.28,55.02 v6(144.38,55.02)
  GND1 w0.076: v6(144.38,55.02) 144.38,54.99 v4(144.86,54.51)
  IN1 w0.076: v4(144.86,54.51) 144.95,54.51 146.14,53.33 146.14,49.76 146.88,49.01 146.88,47.73 147.17,47.43 153.97,47.43 154.58,46.82 165.7,46.82 166.97,45.56 166.97,44.11 165.68,42.82 165.68,35.44 166.24,34.88 166.24,30.58 165.14,29.48 161.34,29.48 160.58,28.72 157.39,28.72 156.13,29.98 155.09,29.98 154.84,29.73 151.7,29.73 151.58,29.84 151.04,29.84 150.83,29.64 149.66,29.64 v1(149.56,29.75)
KSI5: length 70.9
  TOP w0.076: U34.C12 144.17,56.35 144.17,55.62
  TOP w0.102: 144.17,55.62 v6(144.38,55.41) ; v2(151.74,32.53) 151.74,30.95 C1193.1 151.67,29.96 v6(151.62,29.96) 150.1,28.44 JKB1.6
  GND1 w0.076: v4(144.87,55.11) 144.56,55.41 v6(144.38,55.41) ; v4(151.39,29.4) 151.39,29.73 v6(151.62,29.96)
  IN1 w0.076: v4(151.39,29.4) 151.54,29.55 154.91,29.55 155.17,29.81 156.03,29.81 157.35,28.49 164.4,28.49 166.42,30.5 166.42,34.95 165.86,35.51 165.86,42.75 167.15,44.04 167.15,45.64 165.78,47 154.68,47 154.07,47.61 147.25,47.61 147.06,47.8 147.06,51.74 147.15,51.83 147.15,52.58 145.85,53.88 145.85,55.02 145.56,55.31 145.08,55.31 144.87,55.1 v4(144.87,55.11)
KSI6: length 72.4
  TOP w0.102: U34.C13 144.42,55.92 144.6,55.74 v6(144.85,55.74) ; v2(149.92,32.46) 149.92,30.95 C1188.1 148.84,29.87 v1(148.84,29.77) 148.84,29.31 147.7,28.17 JKB1.3
  GND1 w0.076: v4(145.37,55.85) 145.26,55.74 v6(144.85,55.74)
  IN1 w0.076: v4(145.37,55.85) 146.03,55.2 146.03,53.96 147.33,52.66 147.33,51.76 147.24,51.67 147.24,47.87 147.32,47.79 154.15,47.79 154.76,47.18 165.86,47.18 167.33,45.71 167.33,43.75 166.04,42.46 166.04,35.58 166.59,35.03 166.59,30.4 164.5,28.31 157.16,28.31 155.84,29.63 155.24,29.63 154.99,29.38 152.09,29.38 151.71,28.99 149.61,28.99 v1(148.84,29.77)
KSI7: length 77.9
  TOP w0.102: v6(144.61,57.8) 144.41,57.6 U34.D10 ; JKB1.2 146.9,28.3 147.19,28.59 147.63,28.59 148.15,29.11 v1(148.15,29.78) 148.15,30.1 C1189.1 149,30.95 149,33.09 v2(148.43,33.65)
  GND1 w0.076: v4(145.03,57.9) 144.93,57.8 v6(144.61,57.8)
  IN1 w0.076: v1(148.15,29.78) 149.13,28.8 151.9,28.8 152.29,29.2 153,29.2 153.26,28.94 153.26,28.54 153.8,28 156.46,28 156.91,27.55 164.92,27.55 167.33,29.96 167.33,35.3 166.75,35.88 166.75,42.16 168.04,43.45 168.04,46.03 166.14,47.92 155.02,47.92 154.44,48.5 149.37,48.5 148.19,49.69 148.19,52.81 147.77,53.23 147.77,54.42 146.77,55.42 146.77,56.32 145.2,57.9 v4(145.03,57.9)
KSO0: length 47.1
  TOP w0.102: JKB1.18 159.7,28.21 159.91,28.42 160.19,28.42 160.82,29.05 v2(161.82,29.05) 161.9,29.05 162.69,29.84 v6(162.69,30.02) 162.69,30.04 C1078.1 ; v6(141.24,55.28) 141.42,55.46 U34.J13
  GND1 w0.076: v6(141.24,55.28) 141.14,55.18 v4(141.14,54.84) ; v4(162.22,30.42) 162.62,30.02 v6(162.69,30.02)
  IN1 w0.076: v4(141.14,54.84) 141.59,54.39 141.59,53.89 141.38,53.68 141.38,47.81 143.44,45.75 143.44,37.91 145.89,35.46 147.23,35.46 150.97,31.71 161.28,31.71 162.22,30.77 v4(162.22,30.42)
KSO1: length 46.5
  TOP w0.076: 141.17,55.65 141.17,56.35 U34.J12
  TOP w0.081: 140.77,55.21 140.77,55.26 141.17,55.65
  TOP w0.102: 140.77,55.21 140.77,54.65 v6(140.76,54.64) ; C1195.1 160.86,30.04 v6(160.84,30.04) 160.84,30 v2(159.99,29.15) 159.81,28.97 159.1,28.97 158.5,28.37 158.21,28.37 158.1,28.26 JKB1.16
  GND1 w0.076: v4(140.59,54.22) 140.59,54.46 v6(140.76,54.64) ; v4(160.4,30.42) 160.78,30.04 v6(160.84,30.04)
  IN1 w0.076: v4(160.4,30.42) 160.21,30.23 159.57,30.23 158.63,31.17 150.71,31.17 146.95,34.92 145.67,34.92 142.91,37.69 142.91,45.53 140.14,48.3 140.14,50.93 140.35,51.15 140.35,53.99 v4(140.59,54.22)
KSO2: length 49.2
  TOP w0.076: 141.67,55.25 141.67,55.25 141.67,56.35 U34.H12
  TOP w0.102: v6(141.55,54.78) 141.67,54.9 141.67,55.25 ; JKB1.17 158.9,28.3 159.29,28.69 160.01,28.69 160.73,29.4 161.17,29.4 v6(161.75,29.99) 161.75,30.01 C1194.1 162.72,30.98 162.72,32.23 v2(162.94,32.45)
  GND1 w0.076: v6(161.75,29.99) 161.75,30.35 v4(161.64,30.47) ; v4(141.19,54.21) 141.19,54.22 141.55,54.58 v6(141.55,54.78)
  IN1 w0.076: v4(141.19,54.21) 141.19,47.75 143.26,45.68 143.26,37.84 145.82,35.28 147.12,35.28 150.87,31.53 160.43,31.53 161.69,30.28 161.69,30.47 v4(161.64,30.47)
KSO3: length 47.8
  TOP w0.102: v2(160.89,32.51) 160.89,30.98 C1196.1 159.87,29.96 v6(159.75,29.96) 159.27,29.48 159.16,29.48 158.33,28.65 157.61,28.65 157.3,28.34 JKB1.15 ; v6(140.85,53.53) 140.88,53.51 R1032.2 141.92,53.79 U34.H13
  GND1 w0.076: v6(140.85,53.53) 140.77,53.45 v4(140.77,53.02) ; v4(159.86,30.67) 159.75,30.56 v6(159.75,29.96)
  IN1 w0.076: v4(159.86,30.67) 159.18,31.36 150.79,31.36 147.05,35.1 145.75,35.1 143.09,37.76 143.09,45.61 140.31,48.38 140.31,50.82 140.77,51.28 v4(140.77,53.02)
KSO4: length 72.1
  TOP w0.102: v2(157.23,32.41) 157.23,30.98 C1184.1 156.77,30.08 v6(155.94,29.25) 155.91,29.22 155.11,29.22 154.1,28.21 JKB1.11 ; U34.H10 141.92,57.27 v6(141.74,57.09)
  GND1 w0.076: v4(141.23,56.53) 141.23,56.54 141.74,57.05 v6(141.74,57.09) ; v6(155.94,29.25) 155.52,29.25 v4(155.49,29.22)
  IN1 w0.076: v4(155.49,29.22) 155.49,29.2 155.54,29.25 155.62,29.25 156.3,28.56 156.65,28.56 157.08,28.13 164.58,28.13 166.77,30.32 166.77,35.1 166.21,35.66 166.21,42.38 167.5,43.68 167.5,45.81 165.95,47.36 154.83,47.36 154.22,47.97 147.56,47.97 147.42,48.11 147.42,51.59 147.5,51.68 147.5,52.74 146.21,54.03 146.21,55.62 145.54,56.3 145.13,56.3 144.35,57.08 142.8,57.08 142.72,57.16 141.87,57.16 v4(141.23,56.53)
KSO5: length 70.4
  TOP w0.076: U34.H9 141.67,57.85 141.67,57.4 v6(141.36,57.09)
  TOP w0.102: JKB1.10 153.3,28.25 v2(154.06,29.01) 154.35,29.3 v6(154.36,29.3) 154.64,29.3 C1185.1
  GND1 w0.076: v6(141.36,57.09) 141.55,57.28 v4(141.55,57.54) ; v6(154.36,29.3) 154.35,29.29 v4(154.35,28.87)
  IN1 w0.076: v4(154.35,28.87) 154.58,29.1 155.06,29.1 155.34,28.82 155.8,28.82 156.23,28.38 156.58,28.38 157.01,27.95 164.68,27.95 166.95,30.22 166.95,35.17 166.39,35.73 166.39,42.31 167.68,43.6 167.68,45.88 166,47.57 154.88,47.57 154.3,48.15 149.22,48.15 147.78,49.58 147.78,52.71 146.39,54.1 146.39,55.7 145.61,56.48 145.17,56.48 144.4,57.25 142.99,57.25 142.89,57.34 141.75,57.34 v4(141.55,57.54)
KSO6: length 74.4
  TOP w0.102: v2(159.06,32.46) 159.06,31.75 159.06,31.74 159.06,30.98 C1182.1 158.02,29.93 157.79,29.93 v6(156.12,28.26) 155.79,28.26 155.7,28.17 JKB1.13 ; U34.G9 142.42,58.16 v6(142.16,58.42)
  GND1 w0.076: v6(142.16,58.42) 141.82,58.42 v4(141.56,58.17) ; v4(156.08,27.42) 156.08,28.22 v6(156.12,28.26)
  IN1 w0.076: v4(156.08,27.42) 156.31,27.19 165.15,27.19 167.69,29.73 167.69,35.45 167.13,36 167.13,42.04 168.39,43.31 168.39,46.17 166.29,48.28 155.17,48.28 154.59,48.86 149.55,48.86 148.77,49.64 148.77,54.31 147.77,55.31 147.42,55.31 147.13,55.6 147.13,56.66 145,58.79 144.5,58.79 144.32,58.61 144.32,58.37 143.72,57.77 142.63,57.77 142.24,58.17 v4(141.56,58.17)
KSO7: length 69
  TOP w0.102: v6(142.17,57.28) 142.17,57.28 142.42,57.53 U34.G10 ; JKB1.12 154.9,28.2 155.47,28.77 155.86,28.77 v6(155.89,28.74) 156.09,28.74 v2(156.39,29.04) 157.22,29.87 157.22,30.05 C1183.1
  GND1 w0.076: v6(155.89,28.74) 155.63,28.49 v4(155.63,28.41) ; v6(142.17,57.28) 142.17,57.28 142.08,57.37 v4(142.08,57.77)
  IN1 w0.076: v4(155.63,28.41) 155.84,28.21 156.5,28.21 156.94,27.77 164.76,27.77 167.13,30.14 167.13,35.25 166.57,35.8 166.57,42.24 167.86,43.53 167.86,45.95 166.07,47.74 154.95,47.74 154.37,48.32 149.3,48.32 148.01,49.61 148.01,52.74 146.6,54.15 146.6,55.77 145.71,56.65 145.25,56.65 144.84,57.06 144.84,57.54 144.42,57.96 144.12,57.96 143.76,57.59 142.26,57.59 v4(142.08,57.77)
KSO8: length 45.6
  TOP w0.102: JKB1.14 156.5,28.2 157.32,29.02 158.19,29.02 v2(158.2,29.03) 158.2,29.03 158.2,29.02 158.99,29.8 v6(158.99,30.02) 159.01,30.02 C1197.1 ; U34.G13 v6(142.42,55.77)
  GND1 w0.076: v6(158.99,30.02) 158.99,30.2 v4(158.64,30.54) ; v6(142.42,55.77) v4(141.93,55.77)
  IN1 w0.076: v4(158.64,30.54) 158.52,30.54 158.26,30.29 156.86,30.29 156.46,30.7 154.58,30.7 154.37,30.9 150.72,30.9 146.87,34.75 145.6,34.75 142.72,37.63 142.72,45.43 139.93,48.21 139.93,51 140.14,51.21 140.14,54.76 141.14,55.77 v4(141.93,55.77)
KSO9: length 56.7
  TOP w0.076: U34.G12 142.17,56.35 142.17,55.57 v6(142.33,55.41)
  TOP w0.102: JKB1.24 164.5,28.25 164.63,28.38 165.14,28.38 165.26,28.5 165.76,28.5 166.32,29.06 167.62,29.06 168.66,30.1 C1180.1 168.2,30.98 168.2,31.76 168.21,31.76 168.21,32.23 v2(167.66,32.78) 166.47,33.97 163.7,33.97 163.27,33.55 v1(163.27,32.88)
  GND1 w0.076: v6(142.33,55.41) 142.33,54.98 v4(142.15,54.81)
  IN1 w0.076: v1(163.27,32.88) 162.29,31.89 151.05,31.89 147.3,35.64 145.97,35.64 143.62,37.99 143.62,45.84 141.61,47.85 141.61,53.6 141.78,53.76 141.78,54.28 142.15,54.65 v4(142.15,54.81)
KSO10: length 57.7
  TOP w0.102: JKB1.26 166.1,28.23 166.5,28.64 167.81,28.64 168.98,29.81 169.75,29.81 C1178.1 170.03,31 170.03,31.9 169.62,32.32 169.12,32.32 166.76,34.68 162.91,34.68 v2(162.3,34.07) 161.98,33.76 v1(161.98,32.89) ; U34.F13 142.92,56.1 142.99,56.04 142.99,55.28 142.69,54.98 v6(142.69,54.34)
  GND1 w0.076: v6(142.69,54.34) 142.69,54.33 v4(142.35,54)
  IN1 w0.076: v4(142.35,54) 142.35,53.81 141.97,53.42 141.97,48.02 143.97,46.01 143.97,38.13 146.12,35.99 147.49,35.99 147.78,35.7 147.78,35.7 148.57,34.91 149.84,34.91 152.5,32.25 161.34,32.25 v1(161.98,32.89)
KSO11: length 57.3
  TOP w0.076: U34.F12 142.67,56.35 142.67,55.62 v6(142.73,55.56)
  TOP w0.102: v1(162.63,32.88) 162.63,33.6 163.35,34.33 v2(166.58,34.33) 169.12,31.79 169.12,31 C1179.1 169.12,30.09 168.96,30.09 167.72,28.85 166.4,28.85 165.84,28.3 165.41,28.3 165.3,28.18 JKB1.25
  GND1 w0.076: v4(142.76,54.8) 142.76,55.54 v6(142.73,55.56)
  IN1 w0.076: v1(162.63,32.88) 161.81,32.07 152.43,32.07 149.84,34.66 148.57,34.66 147.42,35.81 146.04,35.81 143.8,38.06 143.8,45.94 141.79,47.95 141.79,53.52 141.96,53.69 141.96,54.18 142.17,54.4 142.35,54.4 v4(142.76,54.8)
KSO12: length 52.2
  TOP w0.102: JKB1.19 160.5,28.22 160.98,28.7 162.29,28.7 v6(163.6,30.01) 163.6,30.03 C1177.1 164.55,30.98 164.55,32.18 163.98,32.75 v1(163.98,33.39) 164.17,33.58 v2(164.48,33.58) ; U34.F10 142.91,57.59 142.91,56.99 v6(142.91,56.98)
  GND1 w0.076: v4(142.79,56.27) 142.79,56.87 v6(142.91,56.98)
  IN1 w0.076: v4(142.79,56.27) 142.79,56.13 143.33,55.6 143.33,54.09 142.32,53.09 142.32,48.17 144.33,46.16 144.33,38.34 146.32,36.35 147.68,36.35 148.69,35.34 149.91,35.34 152.65,32.6 160.04,32.6 161.16,33.72 163.65,33.72 v1(163.98,33.39)
KSO13: length 54.9
  TOP w0.076: U34.F9 142.67,57.85 142.67,57.28 v6(142.55,57.16)
  TOP w0.102: v1(164.45,32.93) 165.49,32.93 v2(165.91,32.51) 166.37,32.04 166.37,30.98 C1174.1 166.83,30.15 165.59,28.91 165.02,28.91 164.94,28.83 164.1,28.83 163.86,28.59 163.29,28.59 162.9,28.2 JKB1.22
  GND1 w0.076: v4(142.06,56.76) 142.46,57.16 v6(142.55,57.16)
  IN1 w0.076: v1(164.45,32.93) 163.84,32.93 163.23,33.54 161.23,33.54 160.12,32.42 152.58,32.42 149.91,35.09 148.66,35.09 147.58,36.17 146.19,36.17 144.15,38.21 144.15,46.09 142.14,48.1 142.14,53.17 143.15,54.18 143.15,55.17 142.06,56.26 v4(142.06,56.76)
KSO14: length 53.4
  TOP w0.102: JKB1.23 163.7,28.06 164.24,28.6 165.06,28.6 165.16,28.7 165.67,28.7 166.36,29.39 v2(167.15,29.39) 167.75,29.98 C1181.1 167.29,30.98 167.29,31.98 165.84,33.43 v6(165.25,33.43) ; v6(143.65,56.91) 143.65,57.02 143.42,57.25 U34.E10
  GND1 w0.076: v4(143.83,56.2) 143.83,56.68 143.65,56.87 v6(143.65,56.91) ; v4(165.25,33.82) v6(165.25,33.43)
  IN1 w0.076: v4(165.25,33.82) 164.88,34.19 164.88,44.84 164.55,45.17 155.16,45.17 153.61,46.72 146.71,46.72 145.37,48.06 145.37,53.03 145.07,53.33 143.96,53.33 143.68,53.61 143.68,56.05 v4(143.83,56.2)
KSO15: length 54.1
  TOP w0.076: v6(143.96,57.15) 143.83,57.15 143.67,57.31 143.67,57.85 U34.E9
  TOP w0.102: C1175.1 165.92,30.22 165.69,30 165.39,30 v6(165.32,29.93) 165.32,29.4 v2(165.35,29.38) 165.15,29.17 164.85,29.17 164.75,29.07 164,29.07 163.76,28.83 163.11,28.83 162.56,28.28 162.23,28.28 162.1,28.15 JKB1.21
  GND1 w0.076: v4(164.9,30.57) 165.03,30.44 165.03,30.23 v6(165.32,29.93) ; v4(144.22,56.68) 144.22,56.69 143.96,56.95 v6(143.96,57.15)
  IN1 w0.076: v4(164.9,30.57) 165.69,31.36 165.69,34.67 165.06,35.31 165.06,44.92 164.62,45.35 155.24,45.35 153.69,46.9 146.81,46.9 145.55,48.16 145.55,53.13 145.17,53.51 144.06,53.51 143.86,53.71 143.86,55.61 144.22,55.97 v4(144.22,56.68)
KSO16: length 53.9
  TOP w0.076: U34.E8 143.17,58.35 143.17,57.1 v6(143.27,57)
  TOP w0.102: C1176.1 v6(164.44,29.96) 164.41,29.96 v2(163.61,29.16) 163.14,29.16 162.47,28.49 161.61,28.49 161.3,28.17 JKB1.20
  GND1 w0.076: v4(164.01,30.62) 164.19,30.44 164.19,30.21 v6(164.44,29.96) ; v4(143.35,56.55) 143.27,56.63 v6(143.27,57)
  IN1 w0.076: v4(143.35,56.55) 143.35,55.97 143.5,55.82 143.5,54.02 142.5,53.01 142.5,48.25 144.51,46.24 144.51,38.49 146.48,36.53 147.76,36.53 148.71,35.57 149.93,35.57 152.72,32.78 159.91,32.78 161.03,33.9 164.28,33.9 164.89,33.29 164.89,31.5 v4(164.01,30.62)
LCD_DBC: length 100.4
  IN4 w0.076: v8(180.07,70.9) 179.95,71.02 179.33,71.02 178.89,71.46 176.94,71.46 175.41,72.99 168.73,72.99 166.31,70.57 166.31,68.86 166.11,68.66 158.67,68.66 158.34,68.33 153.87,68.33 152.92,69.28 151.51,69.28 150.97,69.81 150.46,69.81 150.13,70.14 149.68,70.14 149.16,69.62 147.78,69.62 147.13,70.27 144.53,70.27 143.99,69.74 141.64,69.74 139.47,71.91 135.13,71.91 135.05,71.98 134.44,71.98 133.39,70.93 128.8,70.93 126.51,73.21 120.79,73.21 119.78,72.2 114.95,72.2 114.68,72.48 111.63,72.48 110.86,73.24 109.71,73.24 109.03,73.91 99.63,73.91 98.69,72.97 97.57,72.97 v4(97.44,73.11)
  GND5 w0.076: v5(97.34,73.52) 97.34,73.21 v4(97.44,73.11)
  BOTTOM w0.102: v8(180.07,70.9) 180.22,71.06 180.22,74.14 180.33,74.25 180.33,75.11 180.27,75.17 R1139.1 R1279.1 ; v5(97.34,73.52) 97.34,73.81 96.58,74.57 96.48,74.57 96.17,74.88 UCPU1.J2
LCD_TEST: length 75.9
  TOP w0.102: U34.A2 145.42,61.66 145.88,62.12 v6(145.88,62.6) ; v1(136.75,81.19) v2(135.82,81.19)
  GND1 w0.076: v6(145.88,62.6) 145.88,62.97 v4(145.8,63.05)
  IN1 w0.076: v1(176.85,82.54) 176.37,83.02 172.51,83.02 171.75,83.78 158.57,83.78 157.58,82.79 148.98,82.79 146.54,80.35 137.59,80.35 v1(136.75,81.19)
  IN3 w0.076: v4(145.8,63.05) 145.55,62.8 144.57,62.8 144.14,63.23 144.14,63.61 143.76,64 143.05,64 142.84,63.79 140.63,63.79 137.47,66.95 136.32,66.95 135.21,68.06 135.21,69.81 135.88,70.48 135.88,80.33 v1(136.75,81.19)
  BOTTOM w0.102: JLVDS2.14 178.74,81.08 177.28,82.54 v1(176.85,82.54)
LID_SW_IN#: length 168.9
  TOP w0.076: U34.F2 143.17,61.85 143.17,62.35 143.11,62.41 143.11,62.8 143.14,62.83
  TOP w0.102: RP21.4 137.42,64.72 v1(137.66,64.96) ; v6(145.91,63.91) 145.84,63.98 144.25,63.98 143.14,62.86 143.14,62.83
  GND1 w0.076: v4(145.51,63.87) 145.56,63.91 v6(145.91,63.91)
  IN1 w0.076: v4(145.51,63.87) 145.1,64.27 141.92,64.27 141.69,64.05 140.28,64.05 139.36,64.96 v1(137.66,64.96) ; v1(20.72,21.25) 23.97,21.25 25.42,22.69 26.64,22.69 28.31,24.37 30.3,24.37 32.15,26.23 37.96,26.23 38.09,26.35 39.11,26.35 40.02,25.44 40.56,25.44 40.86,25.74 41.5,25.74 42.06,26.3 48.48,26.3 50.21,28.03 51.22,28.03 51.59,27.66 51.89,27.66 51.93,27.62 51.93,27.62 52.16,27.39 53,27.39 53.16,27.24 55.8,27.24 56.3,26.73 60.64,26.73 61.07,27.17 61.74,27.17 v4(62.22,26.68)
  IN2 w0.076: v8(113.05,34.02) 113.53,33.54 113.53,32.55 111.32,30.34 109.32,30.34 108.58,29.6 104.59,29.6 103.35,28.36 101.06,28.36 100.83,28.59 100.48,28.59 99.56,29.5 97.78,29.5 96.54,28.26 92.32,28.26 92.2,28.13 90.52,28.13 89.74,28.92 88.62,28.92 88.31,29.22 86.81,29.22 86.58,28.99 83.69,28.99 82.95,28.26 78.18,28.26 77.92,28.51 75.92,28.51 75.03,29.4 73.53,29.4 72.36,28.23 63.77,28.23 v4(62.22,26.68)
  IN3 w0.076: v1(137.66,64.96) 137.24,64.54 136.25,64.54 135.45,63.74 135.45,59.6 135.97,59.08 135.97,57.31 136.43,56.85 136.43,52.72 v1(134.45,50.74)
  BOTTOM w0.102: JIOL1.27 20.6,21.13 v1(20.72,21.25) ; v8(113.05,34.02) 113.41,34.02 114.52,35.14 114.52,35.91 113.96,36.47 113.96,39.98 116.54,42.56 121.58,42.56 122.22,43.2 125.65,43.2 133.12,50.68 134.4,50.68 134.45,50.73 v1(134.45,50.74)
LP#: length 6.1
  BOTTOM w0.102: PR509.1 133.84,73.8 v2(133.84,73.1)
  BOTTOM w0.203: PU501.2 136.02,77.34 135.73,77.05 135.73,76.63
  BOTTOM w0.254: 135.73,76.63 135.73,75.69 PR509.1
LPC_AD0: length 187.4
  TOP w0.102: v1(136.56,68.97) 136.53,69 136.53,70.07 139.14,72.67 139.14,73.08 139.43,73.37 U652.26 ; v6(138.92,60.73) 139.29,60.73 U34.N4
  GND1 w0.076: v6(138.92,60.73) 138.74,60.73 v4(138.5,60.97)
  IN2 w0.076: v1(188.49,26) 187.9,25.41 186.42,25.41 185.12,26.71 179.55,26.71 178.23,28.03 178.23,42.2 176.75,43.67 176.75,45.28 177.49,46.02 177.49,53.6 171.47,59.63 167.77,59.63 166.85,60.55 165.5,60.55 164.79,61.26 163.12,61.26 161.07,63.31 160.1,63.31 158.69,64.71 158.69,64.89 157.89,65.69 156.71,65.69 155.25,67.14 153.72,67.14 152.73,68.14 149.7,68.14 149.06,68.77 145.61,68.77 145.3,69.09 142.45,69.09 142.21,69.33 138.44,69.33 138.34,69.23 138.01,69.23 137.68,69.56 137.29,69.56 136.71,68.97 v1(136.56,68.97)
  IN4 w0.076: v1(136.56,68.97) 136.63,68.9 136.63,67.64 139.51,64.77 139.51,63.82 139.83,63.49 139.83,61.84 138.97,60.97 v4(138.5,60.97)
  BOTTOM w0.076: 88.4,52.16 88.4,52.57 88.84,53.02 88.84,54.81 89.55,55.52 89.55,56.87 89.77,57.08 89.77,57.45 89.94,57.62 89.94,58.13 89.85,58.22 89.85,58.57 89.58,58.84 89.13,58.84 UCPU1.AU14
  BOTTOM w0.102: 88.4,52.16 88.4,49.15 91.71,45.83 111.3,45.83 111.51,46.05 113.54,46.05 113.9,45.69 v2(114.4,45.69) 115.18,44.91 124.37,44.91 126.33,46.88 126.33,48.9 124.52,50.72 124.52,59.36 129.51,64.35 130.28,64.35 134.01,68.08 136.23,68.08 136.46,68.31 136.46,68.52 136.56,68.62 v1(136.56,68.97) ; JDEBUG.5 188.28,25.79 v1(188.49,26)
LPC_AD1: length 182.5
  TOP w0.102: U34.K5 140.75,60.1 v6(140.57,60.29) ; v1(138.17,69.66) 138.49,69.98 138.49,70.52 139.39,71.42 U652.23
  GND1 w0.076: v6(140.57,60.29) 139.95,60.29 v4(139.9,60.24)
  IN2 w0.076: v1(187.14,25.87) 186.39,25.87 185.38,26.89 179.62,26.89 178.4,28.11 178.4,42.27 176.93,43.74 176.93,45.21 177.67,45.94 177.67,53.68 171.54,59.8 167.93,59.8 167,60.73 165.57,60.73 164.87,61.44 163.19,61.44 159.41,65.21 158.74,65.21 158.62,65.21 157.99,65.84 156.81,65.84 155.33,67.32 153.8,67.32 152.81,68.31 149.77,68.31 149.14,68.95 145.69,68.95 145.37,69.27 142.53,69.27 142.29,69.51 138.32,69.51 v1(138.17,69.66)
  IN4 w0.076: v4(139.9,60.24) 140.15,60.24 140.43,60.52 140.43,60.95 140.24,61.14 140.24,61.47 140.37,61.59 140.37,63.73 140.04,64.06 140.04,64.99 138.59,66.44 138.59,68.4 138.17,68.82 v1(138.17,69.66)
  BOTTOM w0.076: UCPU1.AW12 89.22,57.6 89.22,55.74 88.51,55.03 88.51,53.3 87.83,52.62 87.83,52.16
  BOTTOM w0.102: JDEBUG.4 187.03,25.75 v1(187.14,25.87) ; 87.83,52.16 v2(87.83,51.66) 87.83,48.98 91.38,45.43 111.5,45.43 111.68,45.61 113.41,45.61 115.21,43.8 121.02,43.8 121.71,44.49 124.61,44.49 126.74,46.62 126.74,49.09 124.96,50.86 124.96,59.23 129.68,63.94 130.45,63.94 134.18,67.68 136.4,67.68 136.88,68.16 136.88,68.3 137.13,68.55 137.73,68.55 138.17,69 v1(138.17,69.66)
LPC_AD2: length 178.5
  TOP w0.076: v6(139.09,60.4) 139.14,60.35 139.67,60.35 U34.M4
  TOP w0.102: U652.20 139.13,69.47 138.67,69.01 137.61,69.01 v3(137.47,69.15)
  GND1 w0.076: v6(139.09,60.4) 139.09,60.41 v4(139.47,60.78)
  IN2 w0.076: v1(185.22,25.9) 185.21,25.9 184.58,26.53 179.48,26.53 178.05,27.96 178.05,42.12 176.58,43.6 176.58,45.35 177.31,46.09 177.31,53.5 171.37,59.45 165.71,59.45 164.1,61.06 163.05,61.06 161.04,63.08 160.11,63.08 158.49,64.7 158.49,64.84 157.82,65.51 156.64,65.51 155.18,66.97 153.65,66.97 152.66,67.96 149.62,67.96 148.99,68.59 145.54,68.59 145.22,68.91 142.38,68.91 142.14,69.15 138.55,69.15 138.39,68.99 137.64,68.99 v3(137.47,69.15)
  IN4 w0.076: v4(139.47,60.78) 139.47,61.21 140.01,61.76 140.01,63.56 139.68,63.89 139.68,64.84 136.81,67.72 136.81,68.55 137.41,69.15 v3(137.47,69.15)
  BOTTOM w0.076: 88.19,52.16 88.19,52.7 88.69,53.2 88.69,54.93 89.38,55.62 89.38,57.11 UCPU1.AY12
  BOTTOM w0.102: v3(137.47,69.15) 137.41,69.15 136.66,68.4 136.66,68.23 136.31,67.88 134.1,67.88 130.36,64.15 129.59,64.15 124.73,59.29 124.73,50.79 126.54,48.98 126.54,46.77 124.47,44.7 121.6,44.7 120.94,44.04 118.54,44.04 118.43,44.15 v2(117.49,44.15) 115.16,44.15 113.48,45.82 111.6,45.82 111.41,45.63 91.54,45.63 88.19,48.97 88.19,52.16 ; v1(185.22,25.9) 185.78,25.34 JDEBUG.3
LPC_AD3: length 178
  TOP w0.102: v6(139.08,61.08) 139.08,61.07 139.11,61.1 U34.N3 ; v1(136.02,68.52) 137.02,67.52 U652.17
  GND1 w0.076: v4(138.93,61.47) 138.93,61.23 v6(139.08,61.08)
  IN2 w0.076: v1(136.02,68.52) 136.72,68.52 136.95,68.75 138.4,68.75 138.63,68.97 142.06,68.97 142.31,68.73 145.15,68.73 145.47,68.41 148.91,68.41 149.55,67.78 152.58,67.78 153.58,66.79 155.11,66.79 156.57,65.33 157.75,65.33 158.31,64.76 158.31,64.63 160.04,62.9 160.96,62.9 162.98,60.89 164.03,60.89 165.64,59.27 171.29,59.27 177.13,53.43 177.13,46.16 176.37,45.4 176.37,43.55 177.87,42.05 177.87,27.88 179.68,26.07 v1(180.82,26.07)
  IN4 w0.076: v1(136.02,68.52) 136.02,68 139.33,64.69 139.33,63.74 139.62,63.45 139.62,62.15 v4(138.93,61.47)
  BOTTOM w0.076: 88.6,52.16 88.6,52.55 88.77,52.72 89,52.95 89,54.75 89.71,55.46 89.71,56.81 89.92,57.02 89.92,57.35 90.25,57.68 UCPU1.AW11
  BOTTOM w0.102: JDEBUG.2 184.53,23.53 184.07,23.08 181.63,23.08 180.84,23.86 180.84,26.05 v1(180.82,26.07) ; 88.6,52.16 88.6,49.46 92.02,46.04 111.21,46.04 111.45,46.28 113.6,46.28 113.71,46.16 115.84,46.16 v2(116.29,45.72) 116.9,45.11 124.21,45.11 126.13,47.03 126.13,48.82 124.29,50.66 124.29,59.42 129.5,64.63 130.14,64.63 134.03,68.52 v1(136.02,68.52)
LPC_FRAME#: length 181
  TOP w0.102: U34.K4 140.66,60.6 v6(140.57,60.69) ; U652.22 139.19,70.77 138.86,70.43 138.86,69.56 138.53,69.23 137.98,69.23 137.64,69.57 137.29,69.57 136.99,69.27 136.99,68.44 v1(137.31,68.12)
  GND1 w0.076: v6(140.57,60.69) 140.17,60.69 v4(140.08,60.79)
  IN2 w0.076: v1(182.16,25.34) 181.66,24.83 180.67,24.83 177.69,27.81 177.69,41.91 176.14,43.46 176.14,45.49 176.94,46.29 176.94,53.37 171.22,59.09 165.56,59.09 163.95,60.71 162.89,60.71 160.9,62.7 158.67,62.7 158.03,63.33 158.03,63.81 157.69,64.16 157.69,64.71 157.28,65.11 156.53,65.11 155.03,66.61 151.71,66.61 150.95,65.85 150.18,65.85 149.09,66.94 145.82,66.94 145.26,67.5 145.26,68.12 145,68.38 142.16,68.38 141.92,68.62 138.78,68.62 138.55,68.39 137.58,68.39 v1(137.31,68.12)
  IN4 w0.076: v1(137.31,68.12) 137.31,67.47 139.86,64.92 139.86,63.98 140.19,63.65 140.19,61.66 140.08,61.54 v4(140.08,60.79)
  BOTTOM w0.076: UCPU1.AV12 89.07,58.13 89.07,55.8 88.36,55.09 88.36,53.43 87.37,52.44 87.37,52.16
  BOTTOM w0.102: JDEBUG.1 183.28,25.21 183.13,25.36 182.19,25.36 v1(182.16,25.34) ; v1(137.31,68.12) 137.31,68.11 136.67,67.48 134.27,67.48 130.53,63.74 129.76,63.74 125.19,59.17 125.19,50.94 126.94,49.19 126.94,46.49 124.72,44.27 121.77,44.27 121.08,43.57 115.15,43.57 113.39,45.34 111.77,45.34 111.31,44.88 108.15,44.88 107.8,45.22 91.23,45.22 87.37,49.09 v2(87.37,49.5) 87.37,52.16
LPCPD#: length 7.1
  TOP w0.102: U652.28 137.92,74.67 R1238.2 R1239.2 137.04,77.15 v2(137.42,76.77)
M_CLK_A_DDR0: length 145.2
  TOP w0.076: RD75.1 40.52,39.28 40.85,38.95 41.02,38.95 v1(41.29,39.23)
  IN2 w0.178: v1(41.29,39.23) 41.07,39 40.89,39 40.71,39.18 40.71,41.88 42.51,43.68 43.93,43.68 44.54,44.28 45.18,44.28 45.51,44.62 45.84,44.62 46.22,45 46.22,46.39 45.74,46.88 45.74,47.07 46.41,47.74 46.82,47.74 47.04,47.53 47.04,46.83 47.37,46.49 48.27,46.49 48.61,46.83 48.61,50.61 48.81,50.81 49.12,50.81 49.32,50.61 49.32,46.88 49.71,46.49 50.56,46.49 50.92,46.86 50.92,50.66 51.12,50.86 51.48,50.86 51.68,50.66 51.68,46.83 52.01,46.49 52.8,46.49 53.13,46.83 53.13,48.93 53.26,49.06 56.69,49.06 57.81,47.94 62.78,47.94 63.97,46.75 69.4,46.75 69.75,47.1 70.35,47.1 74.98,51.73 74.98,52.49 75.56,53.08 75.56,53.63 75.13,54.07 75.13,54.24 75.49,54.6 75.49,55.13 75.17,55.45 74.85,55.45 74.7,55.6 v8(74.7,55.7)
  IN3 w0.076: v4(52.41,37.16) 52.19,36.93 51.77,36.93 51.54,37.17 51.54,37.66 51.03,38.17 50.34,38.17 50.16,37.99 49.52,37.99 49.19,38.32 48.61,38.32 48.33,38.03 48.33,37.8 48.19,37.66 47.99,37.66 47.85,37.8 47.85,38.01 47.54,38.32 47.54,39.23 47.35,39.42 46.95,39.42 46.78,39.24 46.78,38.64 46.51,38.38 45.59,38.38 45.22,38.01 43.06,38.01 42.12,38.94 41.58,38.94 v1(41.29,39.23) 41.01,38.94 38.92,38.94 37.77,37.79 35,37.79 34.42,38.37 32.52,38.37 32.07,37.91 31.78,37.91 31.31,38.38 30.78,38.38 30.18,37.77 29.81,37.77 29.36,37.33 29.36,36.59 29.13,36.36 28.64,36.36 v4(28.42,36.58)
  IN4 w0.076: v1(31.85,35.27) 31.54,34.97 31.37,34.97 31.28,35.05 30.58,35.05 30.5,35.13 30.5,35.25 30.73,35.48 30.73,35.74 30.6,35.87 30.6,36.81 30.15,37.27 30.15,37.65 29.77,38.03 29.77,38.33 29.55,38.55 29.19,38.55 28.97,38.33 28.97,37.59 29.3,37.26 29.3,36.55 29.08,36.33 28.67,36.33 v4(28.42,36.58) 28.18,36.33 26.46,36.33 26.25,36.54 26.05,36.54 25.93,36.66 24.78,36.66 24.23,36.11 23.97,36.11 23.57,35.7 21.42,35.7 20.68,34.96 20.6,34.96 v1(20.29,35.27) ; v1(56.48,35.27) 56.48,35.11 56.32,34.95 56.08,34.95 55.22,35.82 54.44,35.82 54.32,35.93 54.32,38.56 54.1,38.78 53.8,38.78 53.58,38.56 53.58,37.01 53.47,36.9 52.67,36.9 v4(52.41,37.16) 52.37,37.16 52.12,36.91 51.67,36.91 51.45,37.13 51.11,37.13 50.91,36.92 50.51,36.92 50.3,37.13 49.96,37.13 49.12,36.28 48.68,36.28 48.02,35.63 47.51,35.63 47.16,35.98 46.43,35.98 45.36,34.91 45.26,34.91 44.92,35.25 v1(44.92,35.25)
  BOTTOM w0.076: UD5.J7 56.88,34.87 v1(56.48,35.27) ; UD4.J7 45.32,34.93 45.01,35.25 v1(44.92,35.25) ; v1(20.29,35.27) 20.68,34.88 UD1.J7 ; v1(31.85,35.27) 32.24,34.87 UD2.J7 ; UCPU1.AV37 74.2,58.64 74.09,58.75 74.02,58.75 73.91,58.65 73.91,55.58 74.16,55.33 74.54,55.33 74.7,55.49 v8(74.7,55.7)
M_CLK_A_DDR#0: length 145.4
  TOP w0.076: v1(41.29,38.52) 41.04,38.77 40.88,38.77 40.55,38.44 RD77.1
  IN2 w0.178: v1(41.29,38.52) 41.14,38.67 40.75,38.67 40.38,39.04 40.38,42.02 42.37,44.01 43.8,44.01 44.4,44.62 45.04,44.62 45.37,44.95 45.7,44.95 45.89,45.13 45.89,46.26 45.41,46.74 45.41,47.21 46.27,48.07 46.96,48.07 47.37,47.67 47.37,46.97 47.51,46.82 48.13,46.82 48.28,46.97 48.28,50.75 48.68,51.14 49.25,51.14 49.65,50.75 49.65,47.02 49.85,46.82 50.42,46.82 50.59,47 50.59,50.8 50.99,51.19 51.62,51.19 52.01,50.8 52.01,46.96 52.15,46.82 52.66,46.82 52.8,46.96 52.8,49.07 53.12,49.39 56.82,49.39 57.94,48.27 62.92,48.27 64.11,47.08 69.27,47.08 69.62,47.43 70.22,47.43 74.65,51.86 74.65,52.59 75.26,53.2 75.26,53.51 74.82,53.94 74.82,54.37 75.18,54.73 75.18,55 75.04,55.14 74.84,55.14 v8(74.69,54.99)
  IN3 w0.076: v4(52.41,36.52) 52.16,36.78 51.71,36.78 51.38,37.1 51.38,37.6 50.96,38.02 50.4,38.02 50.22,37.84 49.45,37.84 49.13,38.16 48.68,38.16 48.49,37.97 48.49,37.73 48.25,37.5 47.92,37.5 47.69,37.73 47.69,37.94 47.38,38.25 47.38,39.16 47.28,39.26 47.01,39.26 46.93,39.18 46.93,38.58 46.58,38.23 45.66,38.23 45.29,37.85 42.99,37.85 42.06,38.79 41.56,38.79 v1(41.29,38.52) 41.03,38.79 38.99,38.79 37.83,37.63 34.93,37.63 34.36,38.21 32.59,38.21 32.13,37.75 31.71,37.75 31.24,38.22 30.85,38.22 30.24,37.62 29.87,37.62 29.52,37.27 29.52,36.53 29.19,36.2 28.68,36.2 v4(28.43,35.95)
  IN4 w0.076: v1(56.48,34.48) 56.48,34.65 56.33,34.8 56.02,34.8 55.15,35.66 54.37,35.66 54.16,35.87 54.16,38.5 54.04,38.62 53.86,38.62 53.74,38.5 53.74,36.94 53.54,36.75 52.64,36.75 v4(52.41,36.52) 52.19,36.75 51.61,36.75 51.39,36.97 51.18,36.97 50.97,36.77 50.44,36.77 50.24,36.97 50.03,36.97 49.18,36.13 48.74,36.13 48.09,35.47 47.45,35.47 47.1,35.82 46.49,35.82 45.41,34.75 45.2,34.75 v1(44.91,34.46) ; v1(20.29,34.47) 20.6,34.78 20.62,34.8 20.74,34.8 21.49,35.54 23.63,35.54 24.04,35.95 24.29,35.95 24.85,36.51 25.86,36.51 25.99,36.39 26.19,36.39 26.4,36.18 28.19,36.18 v4(28.43,35.95) 28.66,36.17 29.15,36.17 29.46,36.49 29.46,37.33 29.13,37.66 29.13,38.27 29.26,38.39 29.48,38.39 29.61,38.27 29.61,37.96 29.99,37.58 29.99,37.2 30.45,36.74 30.45,35.8 30.58,35.67 30.58,35.55 30.35,35.32 30.35,35.06 30.51,34.9 31.22,34.9 31.31,34.81 31.51,34.81 v1(31.85,34.47)
  BOTTOM w0.076: v1(44.91,34.46) 45.31,34.07 UD4.K7 ; UD5.K7 56.88,34.09 v1(56.48,34.48) ; v1(20.29,34.47) 20.68,34.07 UD1.K7 ; v8(74.69,54.99) 74.69,55.04 74.54,55.18 74.1,55.18 73.98,55.3 73.76,55.52 73.76,58.71 74.15,59.1 UCPU1.AU37 ; v1(31.85,34.47) 32.24,34.08 UD2.K7
M_CLK_B_DDR0: length 139.1
  TOP w0.076: v1(89.3,38.67) 88.89,38.27 88.72,38.27 RD76.1
  IN1 w0.076: 74.14,58.74 74.07,58.8 74.07,59.46 73.91,59.63 73.4,59.63 73.03,59.99 73.03,60.12 73.46,60.55 73.46,60.79 73.27,60.97 72.76,60.97 72.66,61.07 72.66,61.51 72.74,61.58 73.39,61.58 73.6,61.37 v1(73.6,61.31)
  IN1 w0.178: 74.14,58.74 74.14,54.55 74.26,54.42 74.95,54.42 75.28,54.09 75.28,53.58 76.36,52.5 76.36,52.4 76.91,51.84 76.91,51.24 76.42,50.74 76.42,50.49 76.77,50.14 77.02,50.14 77.57,50.69 78.07,50.69 78.68,50.08 78.68,49.63 77.51,48.45 77.51,48.33 77.94,47.9 78.16,47.9 79.89,49.63 80.38,49.63 80.95,49.06 80.95,48.57 79.1,46.71 79.1,46.49 79.45,46.14 79.78,46.14 80.77,47.14 84.86,47.14 87,45 87.18,45 87.74,45.55 89.59,45.55 89.94,45.21 89.94,44.55 89.59,44.21 88.41,44.21 88.26,44.06 88.26,43.6 88.41,43.45 90.08,43.45 91.83,45.2 93.78,45.2 94.13,44.85 94.13,44.15 93.78,43.8 92.68,43.8 91.49,42.61 91.49,42.41 91.16,42.09 90.77,42.09 90.76,42.07 88.79,42.07 88.64,41.92 88.64,41.47 88.79,41.31 90.16,41.31 90.49,40.97 90.49,39.59 90.19,39.28 89.71,39.28 89.02,39.97 88.64,39.97 88.54,39.87 88.54,38.62 88.97,38.18 89.21,38.18 89.3,38.27 v1(89.3,38.67)
  IN3 w0.076: v4(75.41,37.35) 75.68,37.08 76.39,37.08 77.06,37.75 77.94,37.75 78.53,38.34 79.06,38.34 79.52,37.88 79.7,37.88 80.46,38.65 81.88,38.65 82.37,38.16 82.37,37.68 82.57,37.48 85.65,37.48 86.43,38.26 88.89,38.26 v1(89.3,38.67) 89.76,38.22 90.17,38.22 90.34,38.05 91.27,38.05 91.51,38.29 92.22,38.29 92.52,37.99 93,37.99 93.25,38.24 94.09,38.24 94.25,38.41 94.25,39.18 94.48,39.41 95.14,39.41 95.32,39.23 95.32,38.24 96.01,37.55 96.01,36.67 96.32,36.36 96.84,36.36 97.13,36.65 97.13,37.55 97.42,37.83 97.75,37.83 98.27,37.31 99.04,37.31 99.48,37.75 99.89,37.75 v4(100.1,37.96)
  IN4 w0.076: v3(104.24,35.27) 103.92,34.96 103.82,34.96 102.95,35.82 102.08,35.82 101.53,36.37 101.53,36.99 101.97,37.44 101.97,37.44 102.08,37.54 102.08,38.61 101.91,38.78 101.51,38.78 101.26,38.53 101.26,37.91 101.07,37.72 100.32,37.72 100.1,37.95 v4(100.1,37.96) 99.82,37.68 99.5,37.68 99.13,37.31 97.85,37.31 97.15,36.61 96.85,36.31 96.45,36.31 95.81,35.67 93.7,35.67 93,34.96 92.89,34.96 92.67,35.18 v1(92.67,35.26) ; v8(79.6,35.27) 79.25,34.92 79.16,34.92 78.71,35.37 78.69,35.37 78.17,35.89 77.4,35.89 77.17,36.12 77.17,38.57 76.94,38.79 76.46,38.79 76.22,38.56 76.22,37.38 75.95,37.11 75.64,37.11 v4(75.41,37.35) 75.15,37.09 74.76,37.09 74.21,36.54 73.58,36.54 73.14,36.98 72.91,36.98 72.21,36.27 71.88,36.27 71.26,35.66 69.22,35.66 68.53,34.97 68.32,34.97 v1(68.03,35.26)
  BOTTOM w0.076: v1(73.6,61.31) 73.92,61.64 UCPU1.AN38 ; UD6.J7 68.42,34.87 v1(68.03,35.26) ; v3(104.24,35.27) 104.63,34.87 UD10.J7 ; v8(79.6,35.27) 79.64,35.27 79.99,34.92 UD7.J7 ; v1(92.67,35.26) 92.7,35.26 93.07,34.89 UD9.J7
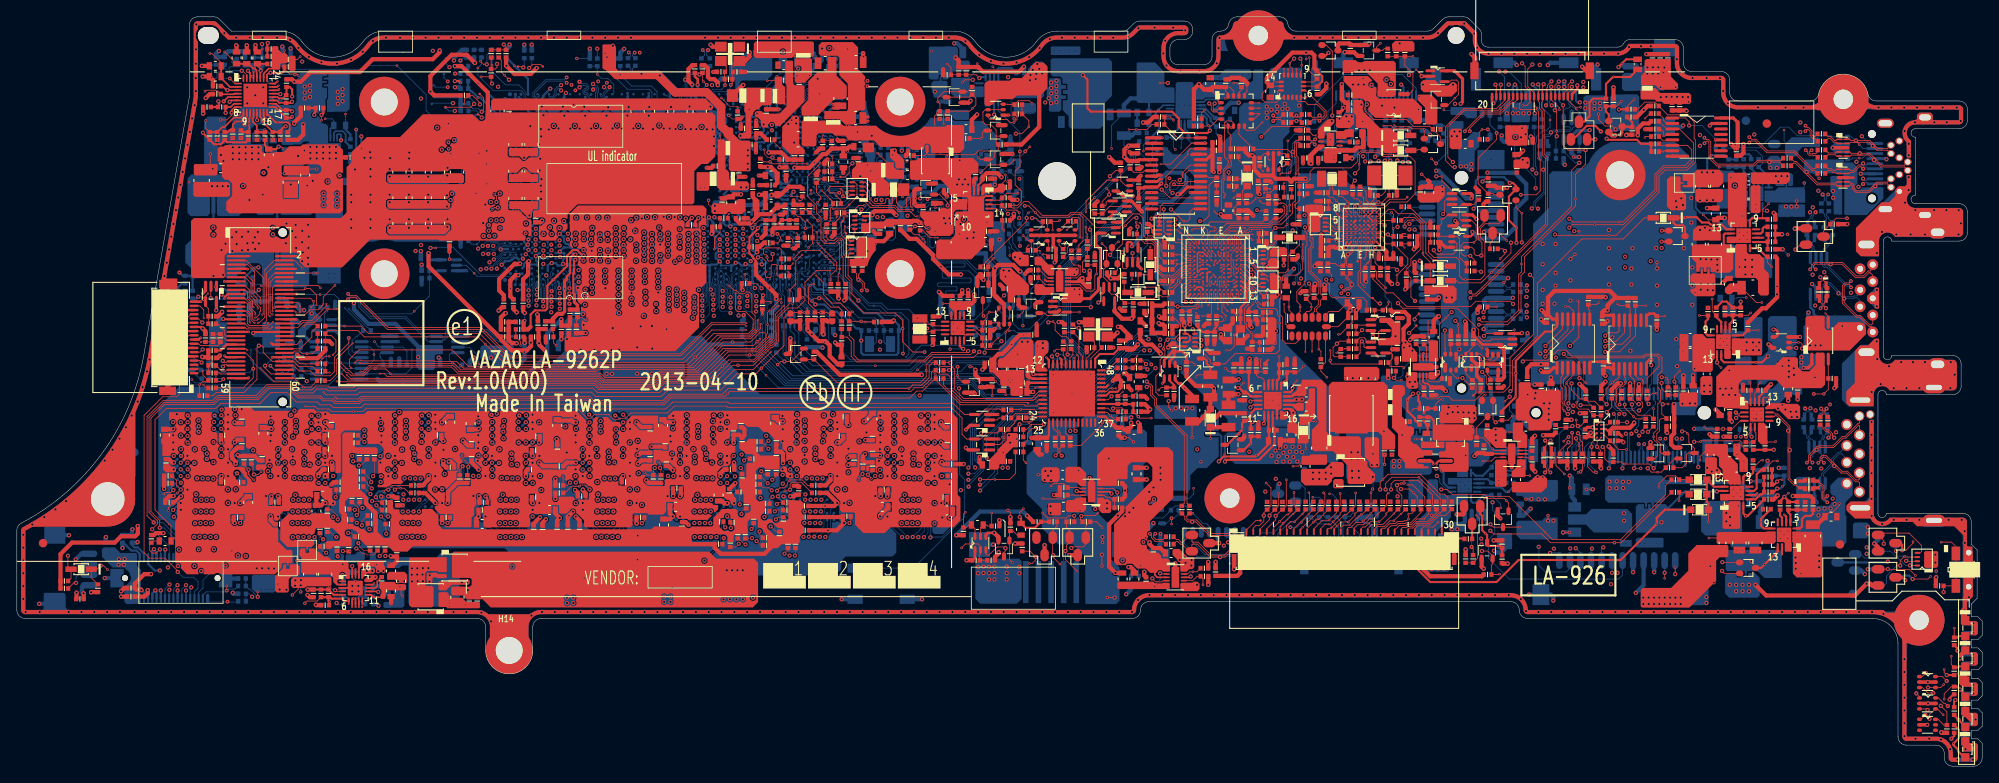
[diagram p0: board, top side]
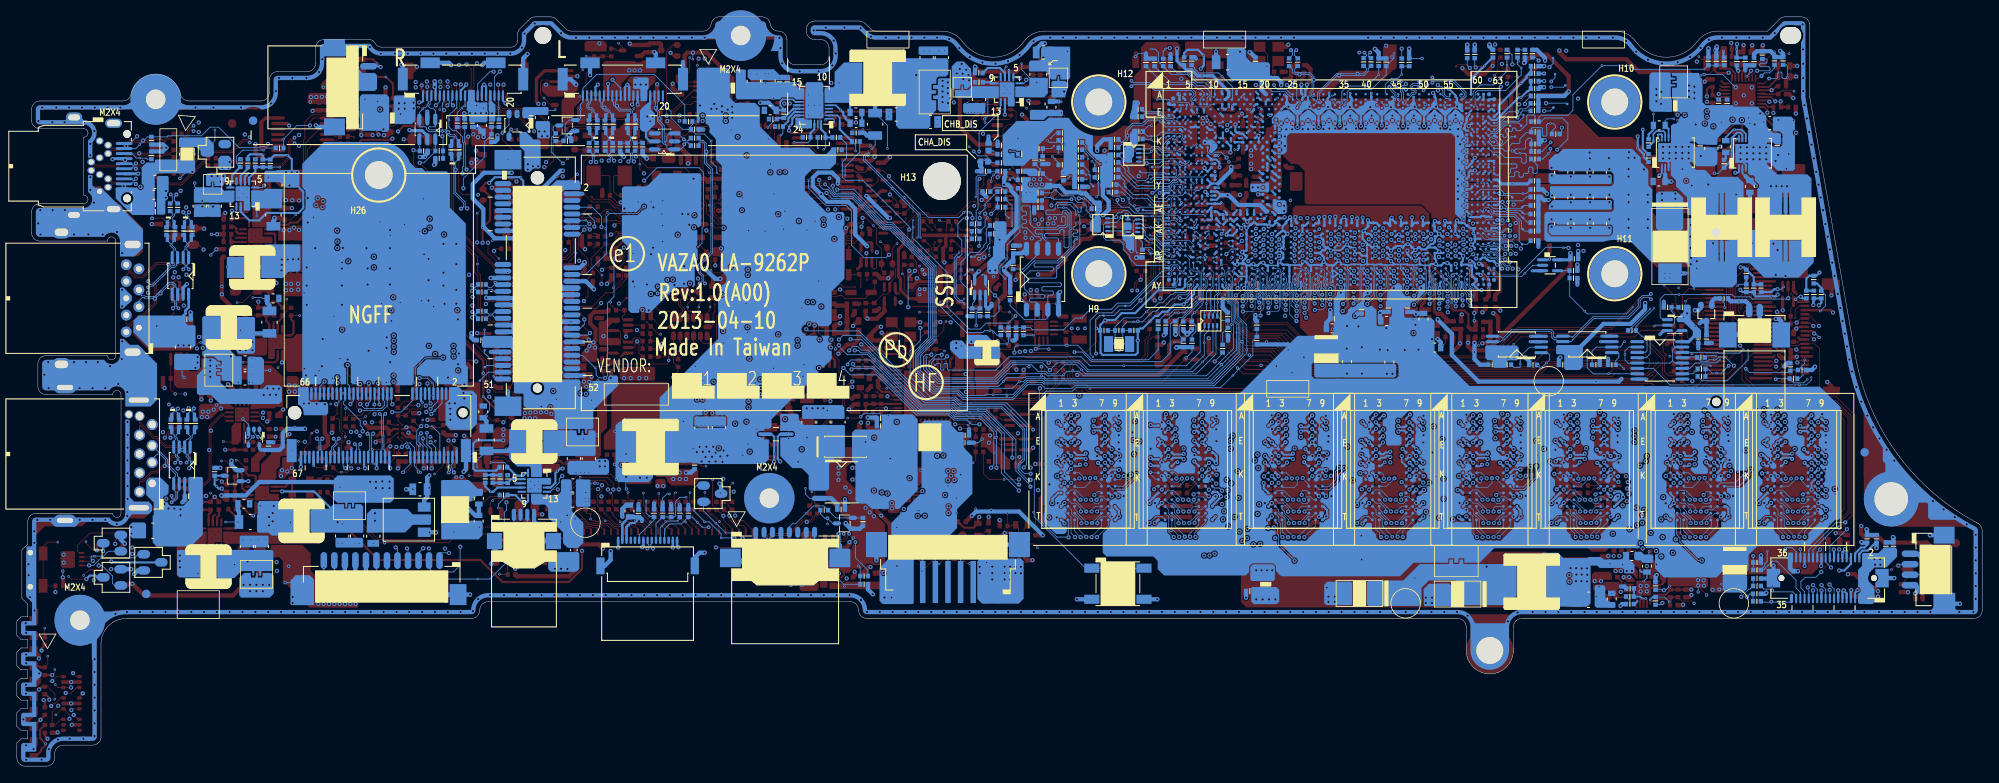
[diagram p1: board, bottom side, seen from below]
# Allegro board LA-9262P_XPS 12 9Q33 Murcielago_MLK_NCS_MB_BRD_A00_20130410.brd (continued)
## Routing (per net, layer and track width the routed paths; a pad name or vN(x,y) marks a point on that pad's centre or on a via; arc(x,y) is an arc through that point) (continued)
M_CLK_B_DDR#0: length 139.6
  TOP w0.076: RD78.1 88.79,38.06 88.96,38.06 v1(89.3,37.72)
  IN1 w0.076: v1(73.59,61.97) 73.59,61.91 73.44,61.76 72.67,61.76 72.49,61.58 72.49,61 72.69,60.79 73.2,60.79 73.28,60.72 73.28,60.62 72.85,60.2 72.85,59.92 73.33,59.45 73.83,59.45 73.9,59.39 73.9,58.8 73.83,58.74
  IN1 w0.178: 73.83,58.74 73.81,58.71 73.81,54.41 74.13,54.09 74.81,54.09 74.95,53.95 74.95,53.45 76.03,52.36 76.03,52.26 76.58,51.71 76.58,51.38 76.09,50.88 76.09,50.35 76.63,49.81 77.16,49.81 77.71,50.36 77.94,50.36 78.35,49.94 78.35,49.76 77.18,48.59 77.18,48.19 77.8,47.57 78.3,47.57 80.03,49.3 80.24,49.3 80.62,48.92 80.62,48.71 78.77,46.85 78.77,46.35 79.31,45.81 79.91,45.81 80.91,46.81 84.72,46.81 86.86,44.67 87.32,44.67 87.88,45.22 89.45,45.22 89.61,45.07 89.61,44.69 89.45,44.54 88.27,44.54 87.93,44.19 87.93,43.46 88.27,43.12 90.22,43.12 91.97,44.87 93.64,44.87 93.8,44.72 93.8,44.28 93.64,44.13 92.54,44.13 91.16,42.75 91.16,42.55 91.02,42.42 90.63,42.42 90.62,42.41 88.66,42.41 88.31,42.06 88.31,41.33 88.66,40.98 90.02,40.98 90.16,40.84 90.16,39.72 90.05,39.61 89.84,39.61 89.16,40.3 88.5,40.3 88.21,40 88.21,38.48 88.84,37.85 89.21,37.85 89.3,37.77 v1(89.3,37.72)
  IN3 w0.076: v4(75.38,36.72) 75.59,36.92 76.45,36.92 77.12,37.59 78,37.59 78.6,38.19 79,38.19 79.46,37.73 79.77,37.73 80.53,38.49 81.82,38.49 82.21,38.1 82.21,37.61 82.5,37.32 85.71,37.32 86.5,38.11 88.82,38.11 89.21,37.72 v1(89.3,37.72) 89.64,38.06 90.1,38.06 90.27,37.9 91.33,37.9 91.57,38.14 92.15,38.14 92.46,37.83 93.07,37.83 93.32,38.08 94.15,38.08 94.41,38.34 94.41,39.11 94.55,39.25 95.08,39.25 95.16,39.17 95.16,38.18 95.85,37.49 95.85,36.61 96.26,36.21 96.9,36.21 97.29,36.59 97.29,37.49 97.48,37.68 97.68,37.68 98.21,37.15 99.1,37.15 99.55,37.6 99.82,37.6 v4(100.1,37.32)
  IN4 w0.076: v1(79.58,34.47) 79.28,34.76 79.1,34.76 78.64,35.22 78.62,35.22 78.11,35.73 77.34,35.73 77.01,36.06 77.01,38.5 76.88,38.64 76.52,38.64 76.37,38.49 76.37,37.31 76.02,36.96 75.62,36.96 v4(75.38,36.72) 75.16,36.94 74.83,36.94 74.27,36.38 73.51,36.38 73.07,36.82 72.97,36.82 72.27,36.12 71.94,36.12 71.32,35.5 69.28,35.5 68.59,34.81 68.32,34.81 68.04,34.53 v8(68.04,34.47) ; v1(92.66,34.47) 92.66,34.58 92.89,34.81 93.06,34.81 93.77,35.51 95.87,35.51 96.52,36.16 96.92,36.16 97.22,36.46 97.22,36.46 97.91,37.15 99.2,37.15 99.57,37.52 99.9,37.52 v4(100.1,37.32) 100.13,37.32 100.38,37.57 101.14,37.57 101.41,37.84 101.41,38.46 101.58,38.63 101.84,38.63 101.92,38.55 101.92,37.6 101.91,37.59 101.91,37.59 101.37,37.06 101.37,36.31 102.01,35.67 102.88,35.67 103.75,34.8 103.92,34.8 104.24,34.48 v1(104.24,34.47)
  BOTTOM w0.076: v1(92.66,34.47) 93.06,34.07 UD9.K7 ; v8(68.04,34.47) 68.43,34.07 UD6.K7 ; v1(79.58,34.47) 79.98,34.07 UD7.K7 ; UD10.K7 104.63,34.08 v1(104.24,34.47) ; UCPU1.AM38 73.91,62.29 v1(73.59,61.97)
M_ODT0: length 65.7
  TOP w0.076: RD73.1 26.93,33.85 26.47,34.3 26.47,34.49 v8(26.16,34.81)
  IN3 w0.076: v4(32.99,34.91) 33.12,34.78 35.18,34.78 35.59,35.19 43.3,35.19 43.71,34.79 43.71,34.23 43.91,34.02 45.08,34.02 45.97,34.91 48.31,34.91 48.51,35.11 49.96,35.11 50.13,34.93 50.42,34.93 50.68,35.19 53.26,35.19 53.66,34.79 53.66,34.46 54.43,33.69 56.41,33.69 57.09,34.38 57.09,34.65 v4(57.11,34.66)
  IN4 w0.076: v1(50.84,34.74) 50.92,34.82 52.08,34.82 52.32,34.58 53.33,34.58 53.97,33.95 56.58,33.95 57.09,34.46 57.09,34.65 v4(57.11,34.66) 57.09,34.66 57.4,34.96 57.4,35.34 57.5,35.45 57.73,35.45 57.86,35.32 57.86,34.79 57.96,34.68 58.21,34.68 58.29,34.76 58.29,35.27 58.41,35.39 58.62,35.39 58.69,35.32 58.69,34.91 58.72,34.89 61.75,34.89 v1(62.16,34.48) ; v1(37.59,34.49) 37.59,35.17 37.46,35.29 37.21,35.29 37.08,35.17 37.08,35.01 37,34.94 36.77,34.94 36.67,35.04 36.67,35.09 36.55,35.22 35.3,35.22 35.2,35.12 35.2,34.8 35.08,34.68 34.91,34.68 34.79,34.8 34.79,35.14 34.67,35.27 34.44,35.27 34.31,35.14 34.31,34.76 34.18,34.63 33.9,34.63 33.78,34.76 33.78,35.45 33.65,35.57 33.29,35.57 33.17,35.45 33.17,35.12 32.99,34.94 v4(32.99,34.91) 32.89,34.91 32.34,34.36 32.34,34.34 31.97,33.98 29.4,33.98 28.63,34.75 28.63,35 28.53,35.11 28,35.11 27.67,34.78 27.42,34.78 27.36,34.84 26.18,34.84 v8(26.16,34.81)
  BOTTOM w0.076: UD1.K1 25.48,34.07 26.16,34.74 v8(26.16,34.81) 26.06,34.9 25.52,34.9 UD1.J1 ; UD5.K1 61.75,34.07 v1(62.16,34.48) 61.77,34.87 UD5.J1 ; UD2.J1 37.22,34.87 v1(37.59,34.49) 37.16,34.07 UD2.K1 ; UD4.K1 50.16,34.07 v1(50.84,34.74) 50.78,34.8 50.19,34.8 UD4.J1
M_ODT2: length 65.9
  TOP w0.076: v1(109.91,34.48) 109.94,34.51 RD74.1
  IN3 w0.076: v4(80.56,35.06) 80.56,35.06 81.04,35.06 81.2,35.22 85.57,35.22 85.84,34.95 87.61,34.95 88.46,35.8 90.04,35.8 90.85,36.61 92.35,36.61 92.7,36.26 92.7,35.83 93.61,34.92 96.04,34.92 96.21,35.09 97.39,35.09 97.39,35.08 98.06,35.08 98.35,35.37 99.31,35.37 100.03,34.65 100.03,34.56 100.37,34.23 101.54,34.23 101.85,33.92 104.4,33.92 104.81,34.34 104.81,34.54 104.87,34.6 v4(104.87,34.68)
  IN4 w0.076: v1(109.91,34.48) 109.51,34.89 106.9,34.89 106.83,34.96 106.83,35.32 106.72,35.42 106.58,35.42 106.47,35.32 106.47,34.8 106.35,34.68 106.18,34.68 106.06,34.8 106.06,35.6 105.94,35.73 105.76,35.73 105.63,35.6 105.63,35.04 105.48,34.89 105.07,34.89 v4(104.87,34.68) 104.87,34.6 104.81,34.54 104.81,34.43 104.38,34 101.85,34 101.52,34.32 101.52,34.86 101.21,35.17 100.27,35.17 99.94,34.84 98.89,34.84 v3(98.8,34.92) ; 84.75,35.04 83.03,35.04 82.95,34.96 82.95,34.84 82.9,34.79 82.6,34.79 82.53,34.85 82.53,35.42 82.4,35.55 82.21,35.55 82.09,35.42 82.09,34.84 81.96,34.71 81.76,34.71 81.63,34.84 81.63,35.52 81.5,35.65 81.25,35.65 81.12,35.52 81.12,35.14 81.02,35.04 80.57,35.04 80.55,35.06 v4(80.56,35.06) 80.56,35.07 80.55,35.06 80.51,35.06 80.09,34.64 80.09,34.37 79.71,34 77.21,34 76.46,34.75 75.41,34.75 75.16,35 74.06,35 v1(73.88,34.82)
  IN4 w0.081: 84.75,35.04 85.32,34.46 v1(85.32,34.44)
  BOTTOM w0.076: UD10.K1 109.5,34.07 v1(109.91,34.48) 109.53,34.87 UD10.J1 ; UD7.K1 84.95,34.07 v1(85.32,34.44) 84.89,34.87 UD7.J1 ; UD9.K1 98.18,34.07 98.8,34.68 v3(98.8,34.92) 98.74,34.87 UD9.J1 ; UD6.J1 73.24,34.88 73.82,34.88 v1(73.88,34.82) 73.23,34.18 UD6.K1
MAG_DRDY: length 27.9
  TOP w0.076: v6(159.98,61.79) 160.3,62.11 160.3,64.07 U636.E5
  TOP w0.102: U637.9 152.29,50.61 151.94,50.25 150.77,50.25 150.36,50.66 150.36,53.38 150.03,53.71 150.03,55.42 150.18,55.58 150.18,57.54 150.37,57.73 150.37,58.16 150.57,58.36 152.09,58.36 152.78,59.04 v2(152.78,60.45) 152.78,62 v6(152.76,62.01)
  GND1 w0.076: v4(160.22,61.3) 160.22,61.54 v6(159.98,61.79) ; v4(153.42,62) 152.78,62 v6(152.76,62.01)
  IN1 w0.076: v4(160.22,61.3) 160.22,61.31 159.6,60.69 154.73,60.69 153.44,61.99 153.43,61.99 v4(153.42,62)
MEM_CONFIG0: length 51.5
  IN1 w0.076: v4(93.72,58.7) 93.72,59.25 94.63,60.16 94.63,62.27 95.12,62.75 95.89,62.75 96.66,63.52 96.9,63.52 97.09,63.7 97.29,63.7 97.47,63.52 97.81,63.52 98.65,62.67 100.96,62.67 101.5,63.21 107.04,63.21 109.15,61.1 116.83,61.1 117.42,61.68 117.99,61.68 118.29,61.38 119.41,61.38 119.63,61.59 122.26,61.59 v4(122.73,61.13)
  IN3 w0.076: v4(122.73,61.13) 121.66,62.19 120.35,62.19 119.59,62.95 118.7,62.95 115.51,66.14 v4(115.51,69.68)
  GND5 w0.076: v5(115.13,69.94) 115.26,69.94 v4(115.51,69.68) ; v5(93.67,59.14) 93.67,58.75 v4(93.72,58.7)
  BOTTOM w0.102: v4(115.51,69.68) 115.26,69.94 v5(115.13,69.94) 114.88,69.68 RH303.1 RH316.2 ; UCPU1.AT5 93.7,59.8 93.7,59.17 v5(93.67,59.14)
MEM_CONFIG1: length 21.9
  IN4 w0.076: v4(95.52,70.37) 95.77,70.13 96.78,70.13 97,70.35 97.54,70.35 97.81,70.61 98.35,70.61 98.76,71.02 99.51,71.02 99.87,71.38 104.72,71.38 104.94,71.17 106.86,71.17 107.54,71.84 110.1,71.84 110.52,71.42 v4(111.89,71.42)
  GND5 w0.076: v5(95,70.6) 95.23,70.37 v4(95.52,70.37) ; v4(111.89,71.42) 111.89,70.99 v5(111.93,70.95)
  BOTTOM w0.102: v5(95,70.6) 94.93,70.6 UCPU1.U4 ; T287.1 110.84,69.66 RH315.2 111.93,70.75 v5(111.93,70.95) RH180.1
MEM_CONFIG2: length 23
  IN2 w0.076: v4(93.92,67.81) 93.92,68.4 95.03,69.51 96.83,69.51 97.9,70.57 100.35,70.57 102.36,68.57 105.63,68.57 107.16,67.04 107.87,67.04 v3(108.2,67.37)
  GND5 w0.076: v4(93.92,67.81) 93.92,67.7 v5(93.64,67.42)
  BOTTOM w0.102: RH314.2 RH271.1 111.4,67.56 v2(110.48,67.56) 110.29,67.37 v3(108.2,67.37) ; v5(93.64,67.42) 93.64,67.5 93.34,67.8 UCPU1.AB6
MPCIE_RST#: length 138.1
  TOP w0.102: R1314.1 187.45,43.37 186.68,43.37 RH381.2 185.76,43.64 184.72,44.68 v1(184.72,45.48) ; U675.1 170.51,68.37 169.31,69.57 v2(169.31,70.09) v1(168.65,70.09)
  IN4 w0.076: v1(184.72,45.48) 184.72,47.19 185.29,47.77 185.29,62.3 182.7,64.89 182.7,68.17 180.88,69.99 179.85,69.99 178.75,71.09 176.77,71.09 175.24,72.62 170.57,72.62 169.17,71.22 169.17,70.61 v1(168.65,70.09) 167.11,70.09 166.85,69.82 166.85,68.64 166.33,68.12 158.89,68.12 158.56,67.79 153.27,67.79 152.56,68.5 149.83,68.5 149.07,69.27 147.63,69.27 146.98,69.91 144.67,69.91 144.14,69.38 141.49,69.38 139.37,71.5 135.58,71.5 135.54,71.46 135.54,71.46 135.04,70.97 134.29,70.97 132.66,69.33 129.02,69.33 126.03,72.32 121.3,72.32 120.16,71.18 114.88,71.18 114.37,70.68 109.52,70.68 109.02,70.18 106.76,70.18 105.84,69.25 104.01,69.25 103.47,69.79 101.38,69.79 100.92,69.33 99.83,69.33 99.22,68.72 97.38,68.72 97.11,68.45 95.24,68.45 94.9,68.8 94.25,68.8 93.8,68.34 93.1,68.34 92.77,68.67 92.77,69.93 93.66,70.82 v4(94.29,70.82)
  GND5 w0.076: v4(94.29,70.82) 93.82,70.82 v5(93.68,70.95)
  BOTTOM w0.076: v5(93.68,70.95) 93.39,70.66 UCPU1.U6
MPHY_PWREN: length 37.4
  TOP w0.102: v2(118.51,72.06) 117.91,71.46 Q362.2 115.46,71.46 v6(114.48,70.48)
  GND1 w0.076: v6(114.48,70.48) 114.15,70.15 v4(114.15,69.72)
  IN2 w0.076: v4(112.24,66.89) 112.21,66.89 112.21,66.87 112.01,67.07 108.45,67.07 108.25,66.87 107.06,66.87 105.53,68.39 102.29,68.39 101.15,69.53 99.43,69.53 99.27,69.68 97.42,69.68 v4(96.73,69)
  IN3 w0.076: v4(110.4,74.19) 110.4,73.48 v4(114.15,69.72) 114.15,67.39 113.66,66.89 v4(112.24,66.89)
  GND5 w0.076: v4(96.73,69) 96.27,68.54 v5(95.98,68.54) ; v4(110.4,74.19) 110.4,74.18 110.27,74.05 110.27,73.71 v5(110.28,73.7)
  BOTTOM w0.102: v5(110.28,73.7) 110.59,73.39 R1185.1 111.63,73.37 R1169.1 ; UCPU1.Y2 95.98,68.88 v5(95.98,68.54)
MPHY_PWREN#: length 12.2
  TOP w0.102: v2(114.23,72.35) 114.47,72.11 Q362.1 115.87,72.11 116.14,72.38 116.14,72.81 116.61,73.28 R1381.2 116.35,74.13 116.35,74.88 116.35,74.88 ; Q361.2 Q361.5 115.07,78.02 114.78,77.72 114.78,76.58 115.13,76.23 115.74,76.23 116.35,75.62 116.35,74.88 ; Q39.2 116.35,74.88
MSATA_DET#: length 103.4
  IN2 w0.076: v4(102.36,69.38) 102.74,69 108.92,69 110.4,67.53 112.44,67.53 112.91,67.06 118.03,67.06 118.75,67.78 119.56,67.78 121.5,65.85 125.14,65.85 128.05,68.76 132.19,68.76 133.23,67.72 136.52,67.72 136.97,67.27 138.09,67.27 139.08,68.26 141.76,68.26 143.14,66.88 143.89,66.88 144.15,67.14 144.93,67.14 145.51,66.56 148.91,66.56 150.06,65.42 152.19,65.42 152.85,66.08 154.6,66.08 154.99,65.7 154.99,64.45 155.44,64 156.08,64 156.21,64.13 156.8,64.13 157.03,63.9 157.03,63.43 158.13,62.32 160.07,62.32 161.18,61.2 161.41,61.2 163.04,59.58 164.83,59.58 165.49,58.92 171.14,58.92 176.42,53.63 v4(176.42,46.44)
  GND5 w0.076: v4(102.36,69.38) 102.2,69.23 v5(101.9,69.23) ; v5(176.88,46.34) 176.78,46.44 v4(176.42,46.44)
  BOTTOM w0.102: RH392.1 102.37,70 101.92,69.56 101.92,69.25 v5(101.9,69.23) 101.9,68.95 T274.1 100.88,67.93 99.22,67.93 98.41,67.12 96.89,67.12 UCPU1.AC1 ; v5(176.88,46.34) 176.88,46.37 176.54,46.02 JSATA1.51
NFC_DET#: length 110.1
  TOP w0.076: v6(90.67,73.43) 90.01,74.09 RH465.1
  GND1 w0.076: v4(91.42,72.92) 91.42,72.9 90.89,73.43 v6(90.67,73.43)
  IN1 w0.076: v4(91.42,72.92) 91.69,73.19 v4(93.4,73.19)
  IN2 w0.076: v4(91.42,72.92) 91.28,72.78 91.28,68.33 89.99,67.03 89.99,65.48 89.58,65.07 89.58,64.17 88.92,63.51 88.92,59.91 92.82,56.01 92.82,51.25 98.05,46.02 107.78,46.02 111.74,42.06 114.04,42.06 117.22,38.87 118.19,38.87 118.57,38.49 118.57,37.52 119.64,36.46 139.13,36.46 139.9,37.24 144.08,37.24 144.67,37.83 146.6,37.83 147.24,37.2 147.24,34.42 151.78,29.87 151.78,28.88 v3(151.3,28.4)
  GND5 w0.076: v5(93.66,72.8) 93.66,72.94 v4(93.4,73.19)
  BOTTOM w0.076: UCPU1.N5 93.76,72.8 v5(93.66,72.8)
  BOTTOM w0.102: JNFC1.12 156.56,28.16 155.93,28.79 154.54,28.79 R1228.1 153.28,29.6 v2(152.65,28.97) 152.08,28.4 v3(151.3,28.4)
NFC_IRQ: length 121.5
  IN3 w0.076: v4(154.96,28.64) 154.96,28.97 154.38,29.55 152.76,29.55 151.71,30.61 149.44,30.61 144.73,35.31 142.66,35.31 141.97,36 141.97,39.69 143.16,40.88 143.16,46.9 146.64,50.38 147.5,50.38 149.55,52.43 149.55,54.41 150.76,55.62 150.76,58.41 149.87,59.3 149.87,60.79 v4(150.44,61.36)
  IN4 w0.076: v4(150.44,61.36) 150.15,61.07 149.55,61.07 148.85,61.77 147.74,61.77 147.48,61.51 146.28,61.51 145.89,61.12 145.89,60.13 144.4,58.64 144.4,58.41 143.53,57.54 142.76,57.54 142.37,57.16 141.93,57.16 141.76,57 140.55,57 140.34,56.79 139.45,56.79 138.64,57.61 137.83,57.61 135.78,59.66 134.14,59.66 133.33,60.46 133.33,61.49 132.65,62.18 132.15,62.18 131.83,61.86 129.4,61.86 129.1,61.56 122.19,61.56 121.03,60.39 v4(120.85,60.39) 120.63,60.17 119.67,60.17 119.39,59.89 118.55,59.89 118.1,60.34 110.45,60.34 107.57,63.21 103.03,63.21 101.79,61.98 98.87,61.98 98.08,61.19 97.06,61.19 96.67,61.57 v4(96.08,61.57)
  GND5 w0.076: v4(154.96,28.64) 154.96,29.07 v5(155.01,29.12) ; v4(96.08,61.57) 95.67,61.57 v5(95.63,61.61) ; v4(120.85,60.39) v5(120.5,60.73)
  BOTTOM w0.102: v5(120.5,60.73) 120.2,61.04 119.3,61.04 118.61,61.72 118.61,61.9 118.32,62.19 118.32,63.83 RH294.1 ; UCPU1.AN3 95.38,61.36 v5(95.63,61.61) ; JNFC1.11 157.06,28.33 v2(156.85,28.54) 156.27,29.12 v5(155.01,29.12) 154.74,29.39 R1100.2
NFC_RST#: length 103
  IN2 w0.076: v4(91.89,66.97) 90.88,65.95 90.88,63.94 91.32,63.5 91.32,62.76 90.85,62.29 90.85,59.39 93.07,57.16 93.95,57.16 94.15,56.96 101.19,56.96 103.88,54.27 108.71,54.27 108.99,53.99 108.99,47.99 110.92,46.06 111.82,46.06 113.68,44.21 114.95,44.21 117.57,41.59 118.99,41.59 120.89,39.7 121.72,39.7 123.62,41.59 130.02,41.59 132.91,38.7 146.96,38.7 148.1,37.56 148.1,34.78 151.7,31.18 156.13,31.18 158.01,29.3 v4(158.62,29.3)
  GND5 w0.076: v5(92.32,67.22) 92.07,66.97 v4(91.89,66.97) ; v5(158.34,29.68) 158.34,29.58 v4(158.62,29.3)
  BOTTOM w0.102: v2(158.74,31.52) 158.74,30.09 v5(158.34,29.68) 157.87,29.68 R1142.1 157.79,29.26 159.56,27.49 JNFC1.6 ; v5(92.32,67.22) 92.33,67.22 92.69,66.86 UCPU1.AD7
NFC_VDD_SIM: length 7.8
  BOTTOM w0.102: JNFC1.10 157.56,28.82 R973.2 R974.1 155.42,29.6 155.26,29.76 155.26,31.43 154.74,31.95 v2(153.98,31.95)
NGFF_PWREN: length 145.3
  TOP w0.102: R1215.1 173.87,58.85 v1(173.97,58.75) ; D115.2 175.38,41.18 v1(175.7,40.87) 175.85,40.87 176.09,41.11 R1163.1 177.17,41.11 v2(177.68,41.62)
  IN3 w0.076: v1(173.97,58.75) 173.97,57.94 175.53,56.38 175.53,48.73 178.51,45.76 179.12,45.76 179.33,45.54 179.33,44.5 v1(175.7,40.87)
  IN4 w0.076: v4(93.39,71.51) 93.39,71.44 91.21,69.25 91.21,65.02 90.66,64.47 89.99,64.47 89.17,63.65 88.79,63.65 88.7,63.73 88.36,63.73 88.16,63.54 87.74,63.54 87.42,63.22 87.42,62.12 87.8,61.73 88.39,61.73 89.02,61.1 89.02,61 89.83,60.19 90.24,60.19 91.31,59.12 91.46,59.12 93.21,57.37 94.41,57.37 94.8,56.97 94.8,55.55 95.35,55 96.46,55 98.25,53.21 98.25,49.87 101.05,47.08 109.37,47.08 110.65,48.36 115.51,48.36 116.78,47.09 122.72,47.09 123.16,46.65 130.65,46.65 133.6,43.69 135.18,43.69 136.13,44.64 140.82,44.64 141.55,45.37 145.96,45.37 146.53,45.94 149.5,45.94 150.27,46.71 166.84,46.71 169.76,43.79 171.09,43.79 171.41,43.47 173.1,43.47 v1(175.7,40.87)
  GND5 w0.076: v5(93.14,71.93) 93.14,71.76 v4(93.39,71.51)
  BOTTOM w0.102: UCPU1.R6 93.34,71.74 v5(93.14,71.93)
NGFF_RST#: length 45.6
  TOP w0.102: R1214.1 173.17,60.15 v1(172.68,60.64) 171.94,60.64 171.6,60.99 171.6,61.9 171.94,62.24 v2(173.12,62.24) 173.37,62.5 173.37,64.33 172.84,64.86 U709.2 171.61,64.86 171.38,65.09 171.38,66.51 171.62,66.75 U675.4 173.11,66.75 R1203.1
  IN1 w0.076: v1(194.19,47.66) 193.59,48.26 193.59,49.87 189.77,53.7 185.39,53.7 178.07,61.01 v4(177.74,61.01)
  IN2 w0.076: v1(172.68,60.64) 173.72,61.68 177.07,61.68 v4(177.74,61.01)
  BOTTOM w0.102: JNGFF1.44 194,45.22 194.19,45.42 v1(194.19,47.66)
NGFF_WAKE#: length 131.1
  TOP w0.102: R1216.1 176.55,61.48 v1(176.8,61.23) 176.8,60.88 v2(176.23,60.31) ; v1(191.31,40.87) 190.23,40.87 R1199.1
  IN1 w0.076: v1(191.31,40.87) 189.76,40.87 189.31,41.31 189.31,43.56 191.03,45.28 191.03,51.52 189.12,53.43 185.4,53.43 178.42,60.41 177.35,60.41 176.8,60.96 v1(176.8,61.23) 176.55,61.48 176.55,65.21 173.55,68.21 171.05,68.21 169.29,69.97 169.29,71.79 166.02,75.06 154,75.06 153.07,74.12 148.79,74.12 148.35,73.69 147.4,73.69 147.28,73.8 146.09,73.8 145.9,73.61 145.75,73.61 131.71,73.61 131.01,72.91 128.78,72.91 127.35,74.34 120.12,74.34 119.37,73.6 115.51,73.6 v4(115.01,73.09)
  IN4 w0.076: v4(115.01,73.09) 112.73,73.09 111.18,74.64 99.57,74.64 98.94,74 97.91,74 97.73,73.83 95.08,73.83 v4(94.95,73.95)
  GND5 w0.076: v4(115.01,73.09) 115.51,73.09 v5(115.5,73.08) ; v5(95.04,73.57) 95.04,73.88 94.97,73.95 v4(94.95,73.95)
  BOTTOM w0.102: v5(95.04,73.57) 95.27,73.34 UCPU1.L3 ; v5(115.5,73.08) 114.9,73.08 RH397.2
NGFF_WAKE#_R: length 4.1
  TOP w0.102: R1216.2 175.03,62.09 175.33,62.4 Q347.1 176.11,63.36 v2(177.01,62.46)
O-USR: length 6.7
  TOP w0.102: PR706.1 22.44,75.83 v2(22.44,76.73)
  TOP w0.203: PR713.2 24.4,75.93 24.65,75.93 25.78,77.06 26.61,77.06 26.92,77.37 PU701.9
  TOP w0.254: PR706.1 PR713.2
OCP-I: length 3.5
  TOP w0.203: PR710.2 28.51,76.12 28.06,76.57 28.06,76.99 28.12,77.05 PU701.12
  TOP w0.254: PR710.2 PR703.1
P1:
  vias: v7(164.59,39.34)
PA11: length 3.9
  TOP w0.076: 158.87,61.68 158.87,61.69 158.87,61.71 158.91,61.75 158.92,61.92 159.02,62.03 159.09,62.03 159.13,62.07 159.13,62.23 U636.C1
  TOP w0.102: R1221.2 158.3,59.35 158.12,59.35 158,59.47 158,60.39 158.09,60.48 158.12,60.48 158.51,60.87 158.51,60.9 158.74,61.13 158.74,61.56 158.87,61.68
PA12: length 7.1
  TOP w0.076: U636.C2 159.04,62.82 158.8,62.57 158.8,62.06 158.73,62 158.73,61.84 158.72,61.83
  TOP w0.102: R1251.1 154.88,58.85 R1223.1 156.66,59.73 156.92,59.47 R1222.2 157.8,59.74 157.8,60.49 v1(158.15,60.84) 158.53,61.21 158.53,61.64 158.72,61.83
PB5: length 9.4
  TOP w0.102: R1223.2 156.22,58.36 v3(156.22,57.8) ; U636.A5 157.71,64.32 v6(157.66,64.36)
  GND1 w0.076: v4(158.03,64.43) 157.97,64.36 v6(157.66,64.36)
  IN3 w0.076: v3(156.22,57.8) 156.22,60.83 157.92,62.54 157.92,64.31 v4(158.03,64.43)
PB13: length 6.4
  TOP w0.076: 160.71,61.68 160.71,61.79 161.05,62.12 U636.G1
  TOP w0.102: v2(162.63,56.85) 161.55,57.92 161.55,58.78 161.11,59.22 R1367.1 160.89,59.42 160.89,61.22 160.71,61.39 160.71,61.68
PBTN_OUT#: length 59.5
  TOP w0.102: v6(93.85,64.88) 94.53,64.21 RH293.2 94.53,62.11 v2(94.08,61.66) ; U34.H4 141.92,60.89 141.6,61.21 v6(141.6,61.29)
  GND1 w0.076: v4(93.9,65.32) 93.85,65.27 v6(93.85,64.88) ; v6(141.6,61.29) 141.6,61.84 v4(141.42,62.01)
  IN1 w0.076: v4(93.9,65.32) 94.81,65.32 95.28,64.85 96.25,64.85 97.12,65.72 97.12,65.78 97.91,66.57 102.48,66.57 103.51,65.54 103.51,65.17 103.98,64.71 105.94,64.71 106.14,64.9 107.04,64.9 109.85,62.09 114.6,62.09 114.75,62.09 116.01,63.35 118.99,63.35 119.98,62.36 123.34,62.36 124.13,63.14 127.71,63.14 128.26,63.69 129.62,63.69 130.5,64.57 135.48,64.57 135.85,64.2 136.58,64.2 137.24,63.54 138.09,63.54 138.22,63.67 139.01,63.67 140.49,62.18 141.02,62.18 141.18,62.01 v4(141.42,62.01)
PBTN_OUT#_R: length 143.1
  TOP w0.102: v6(132.47,57.8) 132.49,57.82 RH439.1 ; v6(28.94,47.31) 30.56,45.68 32.64,45.68 33.6,44.72 35.04,44.72 35.5,45.17 36.99,45.17 37.19,44.97 40,44.97 40.3,45.28 68.6,45.28 69.11,44.77 76.21,44.77 76.98,45.53 82.93,45.53 85.03,47.64 v7(85.67,47.64) 87.49,47.64 89.62,49.77 89.8,49.77 90.51,50.48 90.51,53.33 91.62,54.44 92.73,54.44 93.63,55.35 93.63,57.49 95.03,58.89 v6(96.6,58.89) ; v6(93.54,63.37) 93.61,63.3 RH293.1 ; RH444.1 R1312.1 21.91,50.43 v6(21.86,50.38)
  GND1 w0.076: v4(21.57,49.97) 21.57,50.09 v6(21.86,50.38) ; v4(93.57,63.94) 93.58,63.93 93.58,63.41 v6(93.54,63.37) ; v6(96.6,58.89) 96.6,58.67 v4(96.9,58.38) ; v6(28.94,47.31) 28.94,47.89 v4(28.96,47.92) ; v6(132.47,57.8) 132.46,57.8 132.21,58.04 v4(132.21,58.34)
  IN1 w0.076: v4(28.96,47.92) 28.96,47.88 28.62,48.22 25.62,48.22 24.76,49.09 21.86,49.09 21.57,49.38 v4(21.57,49.97) ; v4(96.9,58.38) 96.59,58.08 96.59,55.23 97.61,54.22 101.98,54.22 103.37,55.61 106.21,55.61 108.52,57.92 114.1,57.92 114.71,57.32 118.02,57.32 118.17,57.32 118.67,56.81 124.14,56.81 124.67,57.34 124.82,57.34 130.02,57.34 131.02,58.34 v4(132.21,58.34)
  IN3 w0.076: v4(96.9,58.38) 95.67,59.61 94.9,59.61 94.65,59.87 94.65,61.58 93.58,62.65 93.58,63.93 v4(93.57,63.94)
  GND5 w0.076: v4(93.57,63.94) 93.57,63.53 v5(93.55,63.51)
  BOTTOM w0.102: UCPU1.AL7 92.9,63.08 93.34,63.51 v5(93.55,63.51)
PBTN_SW: length 11.5
  TOP w0.102: Q349.2 170.35,46.79 171.01,46.13 v2(171.2,46.13) v1(171.76,46.13) R1283.1 ; U687.4 174.6,51.41 v1(174.3,51.12)
  IN3 w0.076: v1(174.3,51.12) 174.3,49.56 171.76,47.01 v1(171.76,46.13)
PBTN_SW#: length 260.9
  TOP w0.102: v6(148.2,58.99) 148.06,59.13 RP16.4 ; v6(88.3,50.76) 88.28,50.76 v7(87.95,50.43) 87.52,50 83.87,50 80.83,46.95 76.38,46.95 75.62,46.19 69.86,46.19 69.35,46.7 52.38,46.7 51.65,47.43 41.96,47.43 41.12,46.6 39.91,46.6 39.48,47.03 39.4,47.03 38.49,47.94 v6(38.49,47.99) ; v6(23.76,50.89) 24.19,50.46 RH21.1 24.19,50.25 23.93,50 21.79,50 21.59,50.2 JAPS.8 19.89,50.2 19.31,49.62 19.31,44.2 19.01,43.9 17.33,43.9 15.12,41.69 15.12,25.36 15.77,24.71 17.6,24.71 19.12,23.19 v1(19.12,23.08) ; D85.1 133.98,58.39 133.92,58.46 RH439.2 133.23,58.28 v6(133.23,56.98) ; v1(164.09,55.03) 164.09,54.97 164.64,54.42 171.14,54.42 173.68,51.88 173.68,51.09 174.23,50.54 175.04,50.54 175.27,50.76 U687.2
  GND1 w0.076: v4(89.08,50.56) 88.5,50.56 v6(88.3,50.76) ; v4(132.71,56.49) 133.2,56.98 v6(133.23,56.98) ; v4(23.21,50.76) 23.34,50.89 v6(23.76,50.89) ; v4(38.27,48.43) 38.49,48.21 v6(38.49,47.99) ; v6(148.2,58.99) 148.2,59.21 v4(147.99,59.42)
  IN1 w0.076: v4(132.71,56.49) 130.91,56.49 130.21,55.79 127.56,55.79 126.76,54.99 125.14,54.99 124.16,54.01 114.8,54.01 111.45,50.66 111.45,48.49 112.16,47.78 112.16,45.11 v1(111.94,44.89) 111.28,44.89 109.2,46.98 100.33,46.98 97.79,49.52 96.62,49.52 95.71,50.43 92.45,50.43 92.15,50.13 89.52,50.13 v4(89.08,50.56) ; v4(23.21,50.76) 24.91,50.76 26.82,48.86 30.02,48.86 31.21,47.66 33.09,47.66 34.36,48.93 37.87,48.93 38.27,48.53 v4(38.27,48.43) ; v4(147.99,59.42) 147.99,59.64 148.16,59.81 149.58,59.81 150.36,59.03 151.13,59.03 151.76,58.41 158.31,58.41 161.31,55.41 163.71,55.41 v1(164.09,55.03)
  IN2 w0.076: v4(147.99,59.42) 147.73,59.68 146.68,59.68 146.22,59.22 146.22,56.07 145.61,55.46 144.55,55.46 144.38,55.3 140.2,55.3 139.71,55.79 138.23,55.79 137.98,55.54 133.66,55.54 v4(132.71,56.49)
  BOTTOM w0.102: JIOL1.29 21.1,20.74 21.53,21.17 21.53,21.93 21.02,22.45 19.75,22.45 v1(19.12,23.08) ; v1(111.94,44.89) 112.02,44.82 112.02,34.65 112.62,34.05 112.62,29.62 106.53,23.53 SW2.1 SW2.2
PC0: length 2.5
  TOP w0.102: R1135.1 160,67.54 160,67.04 v6(160.13,66.92) ; U636.E8 160.05,66.02 v6(160.2,66.18)
  GND1 w0.076: v6(160.13,66.92) 160.2,66.84 v6(160.2,66.18)
PC2: length 4.2
  TOP w0.076: U636.D6 159.8,65.07 159.8,66.08 v6(159.77,66.1)
  TOP w0.102: R1136.1 158.69,67.69 158.96,67.42 159.29,67.42 v2(159.67,67.04) 159.67,66.92 159.49,66.74 v6(159.39,66.74)
  GND1 w0.076: v6(159.39,66.74) 159.77,66.36 v6(159.77,66.1)
PCH_DP_AUXN: length 112.4
  TOP w0.102: v6(193.42,74.7) 193.54,74.83 CV10.2
  GND1 w0.076: v6(193.42,74.7) v4(193.42,75.16)
  IN1 w0.076: v4(193.42,75.16) 193.58,75.32 193.58,75.56 193.43,75.72 191.32,75.72 190.9,76.14 176.51,76.14 175.32,77.33 159.24,77.33 158.71,77.86 154.62,77.86 153.92,77.16 153.92,76.89 152.5,75.47 148.47,75.47 148.24,75.69 142.82,75.69 142.08,74.96 132.57,74.96 131.83,75.69 118.18,75.69 117.43,74.94 112.13,74.94 109.82,77.25 107.91,77.25 106.52,75.87 103.69,75.87 101.77,77.78 101.77,80.73 101.47,81.04 101.3,81.04 v3(101.07,80.8)
  BOTTOM w0.102: v3(101.07,80.8) 100.85,81.02 99.02,81.02 98.31,80.3 93.97,80.3 93.67,80 93.67,79.77 93.99,79.45 93.99,79.09 93.76,78.85 93.76,78.73 93.83,78.66 UCPU1.C5
PCH_DP_AUXN_C: length 1.9
  TOP w0.102: UV1.5 195.97,74.43 195.85,74.31 195.59,74.31 195.09,74.8 CV10.1
PCH_DP_AUXP: length 112.4
  TOP w0.102: CV8.2 194.03,77.56 v6(193.44,76.97)
  GND1 w0.076: v6(193.44,76.97) v4(193.44,76.23)
  IN1 w0.076: v4(193.44,76.23) 193.09,75.87 191.38,75.87 190.96,76.29 176.58,76.29 175.38,77.48 159.3,77.48 158.77,78.02 154.56,78.02 153.77,77.22 153.77,76.95 152.44,75.62 148.53,75.62 148.31,75.84 142.76,75.84 142.02,75.11 132.63,75.11 131.89,75.84 118.12,75.84 117.37,75.1 112.2,75.1 109.88,77.41 107.84,77.41 106.46,76.02 103.75,76.02 101.92,77.85 101.92,80.8 101.53,81.19 101.31,81.19 v3(101.06,81.44)
  BOTTOM w0.102: v3(101.06,81.44) 100.85,81.23 98.94,81.23 98.22,80.51 93.89,80.51 93.46,80.08 93.46,79.68 93.78,79.36 93.78,79.17 93.69,79.08 93.61,79.08 93.49,79.2 UCPU1.B5
PCH_DP_AUXP_C: length 2.2
  TOP w0.102: CV8.1 195.63,77 195.63,76.78 196.03,76.38 UV1.2
PCH_DP_CLK: length 134.4
  TOP w0.102: RH281.2 196,75.73 UV1.3 197.53,75.73 199.22,74.04 199.22,71.97 198.37,71.12 195.73,71.12 194.85,70.24 194.85,68.34 190.86,64.35 v2(187.46,64.35) 184.8,64.35 v1(184.45,64)
  IN1 w0.076: v4(90.98,79.21) 91.66,79.9 97.09,79.9 98.18,78.8 98.84,78.8 v4(99.26,79.23)
  IN4 w0.076: v4(99.26,79.23) 99.26,78.95 102.49,75.73 111.6,75.73 112.89,74.43 117.72,74.43 118.05,74.1 126.92,74.1 129.2,71.82 132.99,71.82 134.05,72.87 135.42,72.87 135.5,72.8 139.84,72.8 139.89,72.75 141.17,71.46 145.8,71.46 146.2,71.06 150.13,71.06 151.16,72.09 152.31,72.09 153.25,71.15 155.56,71.15 157.66,73.25 166.25,73.25 166.53,73.53 175.62,73.53 176.45,72.71 179.38,72.71 183.27,68.82 183.27,66.84 184.88,65.22 184.88,64.43 v1(184.45,64)
  GND5 w0.076: v5(90.49,79.21) v4(90.98,79.21)
  BOTTOM w0.102: v5(90.49,79.21) 90.5,79.21 UCPU1.B9
PCH_DP_DAT: length 132.4
  TOP w0.102: v1(184.45,65.06) 184.83,64.68 v2(190.34,64.68) 190.81,64.68 194.62,68.49 194.62,70.35 195.63,71.35 198.18,71.35 198.99,72.17 198.99,73.27 198.48,73.78 UV1.6 195.28,73.78 RH282.2
  IN4 w0.076: v1(184.45,65.06) 183.09,66.42 183.09,68.74 179.33,72.5 176.4,72.5 175.55,73.36 167.9,73.36 167.62,73.08 159.76,73.08 159.48,72.8 159.48,69.5 159.1,69.11 158.63,69.11 158.19,68.68 154.01,68.68 153.91,68.79 153.91,69.87 152.9,70.88 146.13,70.88 145.72,71.29 141.1,71.29 139.82,72.57 139.77,72.62 135.43,72.62 135.35,72.69 134.12,72.69 133.07,71.64 129.13,71.64 126.85,73.92 117.98,73.92 117.64,74.26 112.82,74.26 111.52,75.55 102.41,75.55 99.62,78.35 99.46,78.35 v4(98.6,79.21)
  GND5 w0.076: v4(98.6,79.21) v5(98.04,79.21)
  BOTTOM w0.076: 96.53,79.13 96.43,79.13 96.24,78.93 95.63,78.93 95.57,78.88 94.33,78.88 94.19,78.74 94.19,78.61 93.92,78.35 91.94,78.35 91.63,78.66 UCPU1.C9
  BOTTOM w0.102: 96.53,79.13 96.61,79.21 v5(98.04,79.21)
PCH_DP_HPD: length 156.4
  TOP w0.102: v1(185.02,63.58) v2(185.63,63.58) ; QV2.3 211.89,61.98 v1(211.31,61.39)
  IN2 w0.076: v1(211.31,61.39) 210.57,62.13 210.57,64.69 208.96,66.31 208.96,68.77 207.04,70.69 202.92,70.69 202.25,70.03 199.37,70.03 193.58,64.24 185.68,64.24 v1(185.02,63.58)
  IN4 w0.076: v1(185.02,63.58) 184.26,63.58 182.89,64.96 182.89,68.7 180.25,71.34 179.72,71.34 179.67,71.29 179.32,71.29 178.96,71.64 177.01,71.64 175.49,73.16 168.65,73.16 166.14,70.65 166.14,68.94 166.03,68.83 158.6,68.83 158.27,68.5 153.94,68.5 153.73,68.72 153.73,69.8 152.83,70.7 146.06,70.7 145.65,71.11 141.03,71.11 139.74,72.39 139.69,72.44 135.35,72.44 135.28,72.52 134.22,72.52 133.17,71.46 129.05,71.46 126.77,73.74 117.9,73.74 117.58,74.07 112.76,74.07 111.45,75.37 99.75,75.37 99.52,75.6 96.83,75.6 96.3,75.07 95.28,75.07 93.59,76.76 93.59,77.22 v4(92.56,78.24)
  GND5 w0.076: v4(92.56,78.24) 92.45,78.36 v5(92.45,78.7)
  BOTTOM w0.102: RH300.2 96.4,81.24 93.62,81.24 93.25,80.87 92.49,80.87 91.74,80.12 91.74,79.77 92.09,79.42 UCPU1.C8 92.09,78.66 92.4,78.66 v5(92.45,78.7)
PCH_DP_N0: length 168.8
  TOP w0.102: v3(212.5,75.48) 212.7,75.67 212.81,75.67 213.06,75.43 213.06,74.93 213.39,74.6 213.62,74.6 CV4.2
  IN1 w0.076: v3(212.5,75.48) 212.5,75.56 212.29,75.78 210.55,75.78 210.18,76.15 202.57,76.15 201.55,77.17 196.3,77.17 193.39,80.07 180.22,80.07 179.88,80.42 147.91,80.42 145.65,78.16 113.26,78.16 110.71,80.71 110.71,80.85 107.85,83.71 107.85,83.73 99.03,83.73 98.08,82.78 93.98,82.78 93.48,82.28 88.81,82.28 88.02,81.5 72.1,81.5 70.59,83.01 64.24,83.01 60.85,79.62 60.85,78.26 61.23,77.88 62.03,77.88 62.12,77.97 62.63,77.97 63.09,78.42 63.55,78.42 63.74,78.23 63.74,78.12 63.94,77.91 v4(64.03,77.91)
  GND5 w0.076: v4(64.03,77.91) 63.86,78.08 63.86,78.43 v5(63.97,78.54)
  BOTTOM w0.102: UCPU1.C54 63.79,78.36 v5(63.97,78.54)
PCH_DP_N0_C: length 8.8
  TOP w0.102: JMDP1.5 222.26,73.2 221.01,73.2 v1(220.49,73.71) 220.06,74.14 218.8,74.14 218.78,74.12 218.22,74.12 218.2,74.14 217.89,74.14 217.74,73.99 MD1.8 MD1.2 216.29,73.99 216.14,74.15 215.88,74.15 215.43,74.61 215.22,74.61 CV4.1
PCH_DP_N1: length 166.8
  TOP w0.102: v3(212.54,73.21) 212.55,73.21 212.78,72.97 212.78,72.77 213.01,72.54 213.43,72.54 213.49,72.6 213.71,72.6 CV7.2
  IN1 w0.076: v3(212.54,73.21) 212.68,73.21 212.94,73.46 212.94,73.69 212.38,74.24 210.78,74.24 209.49,75.53 202.33,75.53 201.3,76.56 196.03,76.56 193.12,79.46 179.93,79.46 179.59,79.8 148.21,79.8 145.96,77.55 117.11,77.55 116.34,76.77 113.78,76.77 110.1,80.46 110.1,80.6 107.58,83.12 99.33,83.12 99.07,82.85 99.07,82.85 98.38,82.17 94.23,82.17 93.73,81.67 89.06,81.67 87.73,80.35 78.05,80.35 77.51,80.89 71.85,80.89 70.34,82.4 64.5,82.4 61.16,79.06 61.16,78.65 61.26,78.55 61.4,78.55 61.58,78.73 61.58,78.85 v4(61.51,78.92)
  GND5 w0.076: v5(60.93,78.88) 60.93,78.82 61.14,78.6 61.27,78.6 61.51,78.84 v4(61.51,78.92)
  BOTTOM w0.102: UCPU1.B58 60.93,78.88 v5(60.93,78.88)
PCH_DP_N1_C: length 10.8
  TOP w0.102: CV7.1 215.18,72.66 216.03,72.66 216.2,72.49 MD1.5 MD1.6 217.81,72.49 217.94,72.63 218.66,72.63 218.68,72.61 219.23,72.61 219.25,72.63 220.05,72.63 v1(220.64,72.03) 221.47,71.21 224.25,71.21 JMDP1.11
PCH_DP_N2: length 159.1
  TOP w0.102: v3(200.5,74.03) 200.75,74.28 200.89,74.28 201.04,74.12 201.04,72.25 201.96,71.34 206.43,71.34 206.89,71.79 v1(208.21,71.79) 209.43,71.79 CV12.2
  IN1 w0.076: v1(64.66,80.3) 64.92,80.56 65.26,80.56 67.04,78.78 77.44,78.78 77.78,79.12 88.23,79.12 89.56,80.45 98.44,80.45 99.89,81.9 106.46,81.9 112.81,75.55 117,75.55 117.75,76.3 132.16,76.3 132.62,75.84 140.63,75.84 141.09,76.3 148.71,76.3 148.9,76.11 152.28,76.11 153.16,76.99 153.16,77.56 154.07,78.47 159.06,78.47 159.52,78.02 175.53,78.02 176.8,76.75 193.86,76.75 195.87,74.74 196.95,74.74 197.33,74.36 200.29,74.36 200.5,74.14 v3(200.5,74.03)
  BOTTOM w0.102: UCPU1.B55 63.36,79.34 63.7,79.34 64.07,79.71 64.07,80.28 64.32,80.53 64.44,80.53 v1(64.66,80.3)
PCH_DP_N2_C: length 14.4
  TOP w0.102: JMDP1.17 222.26,69.2 221.07,69.2 v1(220.8,68.92) 220.04,68.16 218.52,68.16 218.07,68.62 218.07,68.97 217.96,69.08 217.84,69.08 217.7,68.94 MD2.6 MD2.5 216.28,68.94 216.14,69.08 213.88,69.08 212.8,70.17 212.77,70.17 212.28,70.65 212.28,70.68 211.3,71.66 211.08,71.66 CV12.1
PCH_DP_N3: length 164.3
  TOP w0.102: CV9.2 213.6,70.79 213.27,70.79 211.15,72.91 207.92,72.91 206.54,74.29 206.02,74.29 v3(205.84,74.11)
  IN1 w0.076: v3(205.84,74.11) 205.59,74.36 201.53,74.36 200.34,75.55 196.13,75.55 194.33,77.36 181.17,77.36 179.34,79.19 148.48,79.19 146.22,76.94 117.37,76.94 116.59,76.16 113.53,76.16 109.49,80.2 109.49,80.34 107.33,82.51 99.59,82.51 98.14,81.06 89.31,81.06 88.06,79.81 77.6,79.81 77.13,80.28 71.6,80.28 70.08,81.79 66.54,81.79 66.19,81.43 65.54,81.43 v3(65.32,81.21)
  BOTTOM w0.102: UCPU1.A57 61.97,79.85 62.06,79.77 62.06,79.64 61.93,79.51 61.67,79.51 61.53,79.66 61.53,79.98 62.96,81.41 65.12,81.41 v3(65.32,81.21)
PCH_DP_N3_C: length 6.8
  TOP w0.102: CV9.1 215.19,70.79 215.53,70.79 215.74,70.57 216.04,70.57 216.17,70.44 MD2.2 MD2.8 217.73,70.44 217.86,70.57 218.24,70.57 218.9,71.23 219.12,71.23 v8(219.36,70.99)
  BOTTOM w0.102: JMDP1.12 219.91,71 219.7,71.21 219.56,71.21 219.36,71.01 v8(219.36,70.99)
PCH_DP_P0: length 168.8
  TOP w0.102: CV3.2 213.6,74.81 213.48,74.81 213.27,75.02 213.27,75.51 212.9,75.88 212.73,75.88 v3(212.5,76.11)
  IN1 w0.076: v3(212.5,76.11) 212.33,75.93 210.61,75.93 210.24,76.3 202.63,76.3 201.61,77.32 196.36,77.32 193.45,80.23 180.28,80.23 179.94,80.57 147.85,80.57 145.59,78.31 113.32,78.31 110.86,80.77 110.86,80.92 108,83.78 108,83.79 107.91,83.88 107.5,83.88 98.96,83.88 98.01,82.93 93.91,82.93 93.42,82.44 88.74,82.44 87.95,81.65 72.16,81.65 70.65,83.16 64.18,83.16 60.7,79.68 60.7,78.19 61.17,77.72 62.1,77.72 62.19,77.81 62.69,77.81 63.15,78.27 63.48,78.27 63.58,78.17 63.58,78.05 v4(63.44,77.91)
  GND5 w0.076: v5(63.57,78.54) 63.71,78.41 63.71,78.12 63.5,77.91 v4(63.44,77.91)
  BOTTOM w0.102: UCPU1.C55 63.56,78.55 v5(63.57,78.54)
PCH_DP_P0_C: length 8.8
  TOP w0.102: CV3.1 215.18,74.82 215.51,74.82 215.97,74.36 216.13,74.36 216.27,74.49 MD1.1 MD1.9 217.78,74.49 217.93,74.35 v1(218.5,74.35) 220.15,74.35 220.43,74.07 220.46,74.07 220.85,73.68 220.85,73.65 221.09,73.41 222.27,73.41 JMDP1.3
PCH_DP_P1: length 166.8
  TOP w0.102: CV5.2 213.96,73 213.76,72.81 213.41,72.81 213.35,72.75 213.1,72.75 212.99,72.85 212.99,73.06 213.14,73.21 v3(213.24,73.21)
  IN1 w0.076: v4(61.5,78.22) 61.32,78.4 61.2,78.4 61.01,78.59 61.01,79.12 64.43,82.55 70.4,82.55 71.91,81.04 77.57,81.04 78.11,80.5 87.67,80.5 88.99,81.83 93.67,81.83 94.17,82.32 98.32,82.32 98.91,82.91 99.27,83.27 107.64,83.27 110.25,80.66 110.25,80.52 113.85,76.92 116.28,76.92 117.05,77.7 145.89,77.7 148.15,79.95 179.65,79.95 179.99,79.62 193.19,79.62 196.1,76.71 201.36,76.71 202.39,75.68 209.56,75.68 210.84,74.4 212.44,74.4 213.09,73.75 213.09,73.36 v3(213.24,73.21)
  GND5 w0.076: v5(60.93,78.23) 61.15,78.45 61.34,78.45 61.5,78.28 v4(61.5,78.22)
  BOTTOM w0.102: UCPU1.C58 v5(60.93,78.23)
PCH_DP_P1_C: length 10.8
  TOP w0.102: JMDP1.9 224.28,71.42 221.55,71.42 221,71.97 221,72 220.61,72.39 220.58,72.39 220.14,72.83 v1(218.96,72.83) 217.94,72.83 217.78,72.99 MD1.7 MD1.4 216.2,72.99 216.07,72.86 215.25,72.86 CV5.1
PCH_DP_P2: length 159.1
  TOP w0.102: CV11.2 209.61,72 208.51,72 208.49,72.02 207.9,72.02 207.88,72 206.8,72 206.34,71.54 202.05,71.54 201.25,72.34 201.25,74.21 200.97,74.49 200.71,74.49 v3(200.5,74.69)
  IN1 w0.076: v3(200.5,74.69) 200.32,74.51 197.39,74.51 197.01,74.89 195.93,74.89 193.92,76.9 176.87,76.9 175.6,78.17 159.58,78.17 159.13,78.63 154.01,78.63 153,77.62 153,77.05 152.22,76.26 148.97,76.26 148.77,76.45 141.03,76.45 140.57,76 132.68,76 132.23,76.45 117.69,76.45 116.94,75.7 112.87,75.7 106.53,82.05 99.83,82.05 98.38,80.61 89.5,80.61 88.17,79.27 77.72,79.27 77.38,78.93 67.1,78.93 65.92,80.11 65.32,80.71 64.89,80.71 v1(64.66,80.94)
  BOTTOM w0.102: v1(64.66,80.94) 64.46,80.73 64.21,80.73 63.86,80.39 63.86,79.79 63.61,79.55 63.32,79.55 63.23,79.64 UCPU1.A55
PCH_DP_P2_C: length 14.4
  TOP w0.102: JMDP1.15 222.26,69.4 220.99,69.4 220.86,69.28 220.83,69.28 220.44,68.89 220.44,68.86 219.95,68.37 218.61,68.37 218.27,68.7 218.27,69.06 218.05,69.28 217.86,69.28 217.7,69.44 MD2.7 MD2.4 216.28,69.44 216.14,69.29 213.96,69.29 v1(212.64,70.62) 211.38,71.87 211.15,71.87 CV11.1
PCH_DP_P3: length 164.5
  TOP w0.102: CV6.2 213.6,71 213.35,71 211.23,73.11 208.01,73.11 206.62,74.5 206.08,74.5 v3(205.84,74.75)
  IN1 w0.076: v3(205.84,74.75) 205.6,74.51 201.59,74.51 200.4,75.7 196.2,75.7 194.39,77.51 181.24,77.51 179.4,79.34 148.41,79.34 146.16,77.09 117.3,77.09 116.53,76.31 113.59,76.31 109.64,80.26 109.64,80.4 107.39,82.66 99.52,82.66 98.08,81.22 89.25,81.22 88,79.97 77.66,79.97 77.2,80.43 71.66,80.43 70.15,81.94 66.48,81.94 66.12,81.58 65.59,81.58 v3(65.32,81.85)
  BOTTOM w0.102: v3(65.32,81.85) 65.1,81.62 62.87,81.62 61.32,80.07 61.32,79.57 61.58,79.31 61.75,79.31 61.85,79.21 UCPU1.B57
PCH_DP_P3_C: length 6.8
  TOP w0.102: CV6.1 215.19,71 215.61,71 215.83,70.78 216.03,70.78 216.2,70.94 MD2.1 MD2.9 217.71,70.94 217.87,70.78 218.16,70.78 218.82,71.44 219.18,71.44 v1(219.36,71.63)
  BOTTOM w0.102: JMDP1.10 219.92,71.6 219.73,71.42 219.57,71.42 v1(219.36,71.63)
PCH_DPWROK: length 12.1
  TOP w0.102: v6(94.98,58.31) 95.83,57.45 95.83,56.04 96.84,55.03 97.85,55.03 98.91,53.96 RH126.1 98.9,53.74 RH309.2 v7(100.31,52.87) 100.39,52.79 RH401.1
  GND1 w0.076: v4(94.45,58.61) 94.67,58.61 v6(94.98,58.31)
  GND5 w0.076: v5(94.14,58.87) 94.2,58.87 v4(94.45,58.61)
  BOTTOM w0.102: v5(94.14,58.87) 94.14,58.71 UCPU1.AV5
PCH_ENVDD: length 143.2
  TOP w0.102: v1(156.29,77.3) 156.29,84.98 155.57,85.7 D105.2 ; v1(178.81,62.24) v2(178.81,65.71) 178.11,66.41 D93.2
  TOP w0.254: PD306.2 v1(195.45,63.64)
  IN1 w0.076: v4(92.48,79.21) 92.81,79.54 96.83,79.54 98.46,77.91 100.99,77.91 103.5,75.41 107.16,75.41 108.43,76.68 109.75,76.68 111.94,74.49 119,74.49 119.74,75.23 128.61,75.23 129.34,74.5 145.36,74.5 146.06,75.2 148.04,75.2 148.22,75.01 152.7,75.01 153.93,76.24 154.96,76.24 156.03,77.3 v1(156.29,77.3) 156.47,77.3 157,76.77 158.86,76.77 158.95,76.86 164.98,76.86 169.84,71.99 169.84,70.17 171.27,68.75 173.88,68.75 177.69,64.93 177.69,63.36 v1(178.81,62.24)
  IN2 w0.076: v1(178.81,62.24) 179.45,61.61 184.8,61.61 185.99,62.79 194.59,62.79 v1(195.45,63.64)
  GND5 w0.076: v5(92.45,79.72) 92.45,79.24 v4(92.48,79.21)
  BOTTOM w0.102: RH158.2 97.18,81.01 93.76,81.01 93.16,80.4 92.82,80.4 92.45,80.04 v5(92.45,79.72) 92.91,79.26 92.91,78.72 UCPU1.C6
PCH_GPIO15: length 3.9
  TOP w0.076: RH270.1 92.06,67.7 v2(91.96,67.81)
  TOP w0.102: v6(92.89,67.22) 93.19,67.22 93.32,67.35 RH270.1
  GND1 w0.076: v4(93.05,66.59) 93.05,67.07 v6(92.89,67.22)
  GND5 w0.076: v5(93.03,67.09) 93.05,67.08 v4(93.05,66.59)
  BOTTOM w0.102: v5(93.03,67.09) 93.28,66.85 UCPU1.AD6
PCH_GPIO17: length 23.5
  TOP w0.102: RH395.2 98.17,57.6 98.17,60.44 97.99,60.63 97.99,62.41 97.87,62.52 97.54,62.52 97.14,62.12 95.99,62.12 95.54,62.57 95.54,65.24 95.03,65.75 95.03,66.64 93.94,67.73 93.94,70.08 95.47,71.62 v6(95.47,71.67)
  GND1 w0.076: v6(95.47,71.67) 95.51,71.63 v4(95.51,71.21)
  GND5 w0.076: v5(95.32,70.81) 95.51,70.99 v4(95.51,71.21)
  BOTTOM w0.076: v5(95.32,70.81) UCPU1.T3 95.73,71.58 97.29,71.58 97.37,71.49
  BOTTOM w0.102: T281.1 97.67,71.2 97.37,71.49
PCH_GPIO18: length 12.3
  IN4 w0.076: v4(96.63,70.47) 96.63,70.78 97.44,71.59 98.62,71.59 99.12,72.09 102.81,72.09 103.17,72.44 103.63,72.44 104.15,71.92 105.13,71.92 v4(105.18,71.87)
  GND5 w0.076: v5(105.4,71.39) 105.4,71.64 v4(105.18,71.87) ; v5(96.24,70.6) 96.5,70.6 v4(96.63,70.47)
  BOTTOM w0.102: UCPU1.U2 96.02,70.39 v5(96.24,70.6) ; RH91.2 105.44,71.35 v5(105.4,71.39) 105.4,71.54 v2(105.76,71.89)
PCH_GPIO19: length 15.7
  IN4 w0.076: v4(93.4,68.9) 93.61,69.1 95.04,69.1 95.32,69.38 96.89,69.38 97.14,69.62 97.84,69.62 98.11,69.9 98.65,69.9 99.06,70.31 99.8,70.31 100.05,70.55 100.91,70.55 101.08,70.38 103.73,70.38 103.89,70.22 105.2,70.22 v4(105.72,69.7)
  GND5 w0.076: v4(93.4,68.9) 93.83,68.9 v5(94.04,69.1) ; v5(106.4,69.74) 106.36,69.7 v4(105.72,69.7)
  BOTTOM w0.102: RH95.2 v5(106.4,69.74) ; v5(94.04,69.1) 93.99,69.05 UCPU1.Y5
PCH_GPIO20: length 137.3
  TOP w0.102: RH410.2 197.86,35.47 198.37,35.98 198.37,37.01 198.57,37.21 Q346.1 199.32,37.77 198.65,38.44 198.65,39.37 v2(198.46,39.56) 198.23,39.79 v1(197.85,39.79)
  IN1 w0.076: v4(109.82,74.19) 110.27,73.74 111.3,73.74 111.34,73.77 119.3,73.77 120.04,74.52 127.43,74.52 128.86,73.09 130.85,73.09 131.55,73.79 145.82,73.79 145.91,73.87 146.01,73.98 147.35,73.98 147.47,73.86 148.28,73.86 148.72,74.3 152.99,74.3 153.93,75.23 166.1,75.23 169.46,71.87 169.46,70.05 171.12,68.39 173.64,68.39 176.75,65.27 176.75,61.91 177.21,61.46 177.98,61.46 181.91,57.53 183.08,57.53 185.8,54.82 189.33,54.82 196.43,47.73 196.43,41.99 197.85,40.56 v1(197.85,39.79)
  IN3 w0.076: v4(103.25,69.39) 103.32,69.47 103.32,71.37 103.92,71.97 103.92,72.08 104.72,72.88 104.72,74.01 105.15,74.45 106.28,74.45 106.28,74.45 109.56,74.45 v4(109.82,74.19)
  GND5 w0.076: v5(102.85,69.11) 102.97,69.11 v4(103.25,69.39)
  BOTTOM w0.102: v5(102.85,69.11) 102.57,69.11 100.95,67.49 99.21,67.49 98.36,66.64 UCPU1.AD1
PCH_GPIO21: length 17.4
  IN4 w0.076: v4(98.43,73.55) 98.71,73.83 99.01,73.83 99.46,74.27 109.18,74.27 109.74,73.71 110.56,73.71 v4(110.98,74.13)
  GND5 w0.076: v4(98.43,73.55) 98.2,73.32 v5(98.2,73.09) ; v4(110.98,74.13) 110.98,74.32 v5(110.67,74.63)
  BOTTOM w0.102: UCPU1.N1 97.75,72.63 v5(98.2,73.09) ; RH103.2 110.04,75.26 v5(110.67,74.63)
PCH_GPIO22: length 15.4
  IN4 w0.076: v4(105.78,71.86) 105.75,71.89 105.75,71.92 105.39,72.28 104.05,72.28 103.68,72.64 103.08,72.64 102.7,72.26 99.04,72.26 98.57,71.79 97,71.79 95.93,70.73 94.98,70.73 v4(94.6,70.35)
  GND5 w0.076: v4(94.6,70.35) 94.53,70.28 94.16,70.28 v5(94.14,70.31) ; v4(105.78,71.86) 106.04,72.12 v5(106.24,72.12)
  BOTTOM w0.102: RH107.2 106.24,72.56 v5(106.24,72.12) ; UCPU1.U5 93.99,70.46 v5(94.14,70.31)
PCH_GPIO23: length 10.3
  BOTTOM w0.076: UCPU1.T2 95.7,70.86 95.7,70.24 95.85,70.09 97.23,70.09 97.37,70.24
  BOTTOM w0.102: RH110.2 102.17,72.18 102.17,71.83 101.44,71.11 v2(101.44,70.73) 101.44,70.59 100.46,69.61 99.37,69.61 99.08,69.9 99.08,70.17 98.98,70.27 97.4,70.27 97.37,70.24
PCH_GPIO27: length 32.4
  TOP w0.102: v6(98.84,64.02) 98.86,64.02 99.2,64.35 RP20.3
  GND1 w0.076: v6(98.84,64.02) 98.56,63.74 v4(98.56,63.64)
  IN4 w0.076: v4(98.56,63.64) 98.84,63.92 98.99,63.92 99.57,64.5 100.27,64.5 100.59,64.82 106.06,64.82 106.32,65.08 107.11,65.08 107.58,64.62 108.33,64.62 109.13,63.82 112.39,63.82 112.85,64.27 114.75,64.27 v4(115.29,63.74)
  GND5 w0.076: v4(115.29,63.74) v5(115.29,64.22) ; v5(98.27,63.36) 98.55,63.64 v4(98.56,63.64)
  BOTTOM w0.076: UCPU1.AN5 93.72,61.99 94.2,62.47 96.21,62.47 96.36,62.62 96.82,62.62 97.15,62.95 97.37,62.95
  BOTTOM w0.102: v5(98.27,63.36) 97.86,62.95 97.37,62.95 ; v5(115.29,64.22) 115.26,64.25 v2(115.26,64.66) 115.26,66.59 116.06,67.39 RH310.2 116.07,67.41 RH427.2 116.56,68.77 117.37,68.77 RH186.2
PCH_GPIO35: length 14.7
  IN4 w0.076: v4(97.39,70.75) 97.39,70.84 97.96,71.41 98.92,71.41 99.12,71.21 99.45,71.21 99.82,71.58 104.8,71.58 104.99,71.4 105.95,71.4 106.42,71.87 v4(106.66,71.87)
  GND5 w0.076: v5(97,70.39) 97.02,70.39 v4(97.39,70.75) ; v5(106.92,72.31) 106.92,72.12 v4(106.66,71.87)
  BOTTOM w0.102: UCPU1.U1 v5(97,70.39) 97.12,70.51 99.92,70.51 T271.1
PCH_GPIO36: length 19.7
  IN4 w0.076: v4(93.16,69.68) 92.92,69.44 92.92,68.73 93.16,68.49 93.73,68.49 94.19,68.95 95.02,68.95 95.35,68.62 97.01,68.62 97.3,68.91 97.3,69.19 97.56,69.44 97.91,69.44 98.19,69.72 99.49,69.72 99.53,69.68 100.64,69.68 101.16,70.2 103.63,70.2 103.79,70.04 104.76,70.04 v4(105.1,69.7)
  GND5 w0.076: v4(105.1,69.7) 105.61,70.21 v5(105.99,70.21) ; v5(93.34,69.33) 93.34,69.51 v4(93.16,69.68)
  BOTTOM w0.102: T272.1 105.99,69.3 v5(105.99,70.21) 106.12,70.33 106.12,70.68 RH391.1 ; UCPU1.V6 v5(93.34,69.33)
PCH_GPIO72: length 6.3
  TOP w0.102: RP20.4 99.56,63.45 v6(99.58,63.44)
  GND1 w0.076: v4(99.16,63.51) 99.5,63.51 v6(99.58,63.44)
  GND5 w0.076: v5(98.9,63.13) 98.9,63.26 v4(99.16,63.51)
  BOTTOM w0.076: 97.37,62.06 97.32,62.06 97.12,61.86 95.43,61.86 94.93,61.36 UCPU1.AN4
  BOTTOM w0.102: 97.37,62.06 98.35,63.04 98.81,63.04 v5(98.9,63.13)
PCH_GPIO86: length 5.8
  TOP w0.076: v2(88.81,73.27) 88.81,72.76 89.24,72.33 v1(89.77,72.33) 89.99,72.11 RH32.1
  BOTTOM w0.102: v1(89.77,72.33) 90.41,72.97 91.2,72.97 91.45,72.72 91.73,72.72 92.04,73.03 UCPU1.L8
PCH_GPIO88: length 34.5
  IN2 w0.076: v4(94.14,73.99) 94.29,73.99 94.71,73.57 94.94,73.57 96.08,72.43 99.79,72.43 101.65,70.57 104.54,70.57 104.64,70.68 106.29,70.68 107.08,69.89 110.47,69.89 111.11,69.25 111.11,69.06 111.48,68.69 115.18,68.69 116.01,69.52 117.58,69.52 117.88,69.81 v3(119.12,69.81)
  GND5 w0.076: v4(94.14,73.99) 94.13,74 93.92,74 v5(93.68,73.76)
  BOTTOM w0.076: v5(93.68,73.76) 93.93,73.52 UCPU1.L5
  BOTTOM w0.102: R1390.1 119.53,64.85 119.53,66.01 119.3,66.24 119.3,69.63 v3(119.12,69.81)
PCH_INTVRMEN: length 9.2
  BOTTOM w0.076: UCPU1.AV7 92.46,58.22 92.07,57.82 92.07,57 92.53,56.54 92.53,55.11 92.68,54.95
  BOTTOM w0.102: RH34.2 93.88,51.17 93.42,51.63 93.42,52.39 93.87,52.84 RH31.2 93.9,53.57 v2(93.58,53.9) 92.68,54.8 92.68,54.95
PCH_INV_PWM: length 117.4
  TOP w0.102: D92.2 165.61,75.46 165.27,75.79 163.62,75.79 163.3,76.11 v6(162.35,76.11)
  GND1 w0.076: v6(162.35,76.11) 162.06,76.4 v4(162.06,76.45)
  IN3 w0.076: v4(162.06,76.45) 162.06,82.47 159,85.53 151.31,85.53 149.51,83.73 143.91,83.73 142.05,81.87 137.32,81.87 135.71,83.49 135.71,85.38 135.31,85.78 125.28,85.78 123.73,84.23 121.37,84.23 119.5,82.36 117.89,82.36 117.44,82.8 115.27,82.8 112.72,85.36 108.5,85.36 108.21,85.06 96.79,85.06 v1(96.53,85.33) 96.15,85.71 95.27,85.71 94.98,85.42 90.81,85.42 88.11,82.72 82.3,82.72 80.79,84.23 71.99,84.23 71.11,85.1 69.13,85.1 v1(68.96,85.27)
  BOTTOM w0.102: RC147.1 97.31,84.95 v2(97.06,85.2) 96.93,85.33 v1(96.53,85.33) ; v1(68.96,85.27) RC146.2
PCH_JTAG_JTAGX: length 59.8
  TOP w0.102: RH412.1 v2(21.7,45.33) 22.07,45.69 22.59,45.69 RH374.1 22.11,46.49 v6(22.11,47)
  GND1 w0.076: v6(22.11,47) 22.11,47.18 v4(22.38,47.46)
  IN1 w0.076: v4(58.08,66.15) 58.08,65.8 58.66,65.22 58.66,59.39 48.91,49.64 47.87,49.64 46.78,48.55 39.59,48.55 38.33,47.29 37.73,47.29 37.46,47.56 33.99,47.56 33.38,46.95 29.05,46.95 28.14,47.87 25.45,47.87 24.71,48.6 23.77,48.6 22.63,47.46 v4(22.38,47.46)
  GND5 w0.076: v4(58.08,66.15) 58.08,66.1 57.91,65.93 v5(57.63,65.93)
  BOTTOM w0.102: UCPU1.AE63 v5(57.63,65.93) 56.62,65.93 56.49,65.8 55.21,65.8 54.69,65.28 54.67,65.28 T273.1 53.99,64.6 RH375.2
PCH_JTAG_TCK: length 62.1
  TOP w0.102: 22.75,47.62 22.75,47.62 ; 22.75,47.62 v6(23.2,48.07) ; 22.75,47.62 RH373.1 22.75,47.62 ; 22.75,47.62 RH411.1
  GND1 w0.076: v4(22.61,48.12) 22.66,48.07 v6(23.2,48.07)
  IN1 w0.076: v4(59.07,66.53) 57.8,66.53 57.53,66.26 57.53,65.75 58.34,64.94 58.34,59.37 48.79,49.82 47.8,49.82 46.72,48.74 39.53,48.74 38.25,47.47 37.81,47.47 37.54,47.74 33.92,47.74 33.31,47.13 29.15,47.13 28.24,48.04 25.55,48.04 24.81,48.78 23.27,48.78 v4(22.61,48.12)
  GND5 w0.076: v4(59.07,66.53) 59.15,66.53 58.95,66.32 v5(58.95,66.1)
  BOTTOM w0.076: v5(58.95,66.1) 58.77,65.93 UCPU1.AE62 58.65,65.9 58.25,65.51 57.7,65.51 57.51,65.32 57.24,65.32
  BOTTOM w0.102: 57.24,65.32 55.59,65.32 55.01,64.74 55.01,62.38 T277.1 54.06,62.03 RH53.2
PCH_JTAG_TDI: length 58.4
  TOP w0.102: v2(56.79,67.94) 56.98,67.75 v1(56.98,67.05)
  IN1 w0.076: v4(27.54,49.92) 27.92,49.54 31.9,49.54 32.48,48.96 33.88,48.96 34.22,49.3 46.78,49.3 47.65,50.18 48.26,50.18 54.4,56.32 54.4,61.62 54.99,62.21 54.99,64.91 56.98,66.91 v1(56.98,67.05)
  GND5 w0.076: v4(27.54,49.92) 27.81,49.66 v5(27.81,49.49)
  BOTTOM w0.102: RH371.1 33.29,45.81 30.27,45.81 27.81,48.27 v5(27.81,49.49) ; RH40.2 54.43,66.64 T278.1 54.76,66.3 56.36,66.3 56.98,66.93 v1(56.98,67.05) 57.01,67.08 58.93,67.08 UCPU1.AD61
PCH_JTAG_TDO: length 44
  TOP w0.102: RH413.1 RH369.1 36.82,46.75 37.14,46.75 37.17,46.77 v6(37.17,46.78)
  GND1 w0.076: v4(37.31,47.16) 37.17,47.02 v6(37.17,46.78)
  IN1 w0.076: v4(37.31,47.16) 37.38,47.08 38.38,47.08 39.47,48.17 46.65,48.17 47.95,49.47 49.14,49.47 58.94,59.26 58.94,64.75 v4(59.76,65.57)
  GND5 w0.076: v4(59.76,65.57) 59.76,65.93 v5(59.61,66.08)
  BOTTOM w0.076: 57.24,65.6 57.51,65.6 57.58,65.66 58.11,65.66 58.33,65.89 58.33,66.12 58.61,66.4 59.04,66.4 59.3,66.14 UCPU1.AE61 59.42,65.89 v5(59.61,66.08)
  BOTTOM w0.102: 57.24,65.6 57.19,65.55 55.51,65.55 54.73,64.77 54.73,63.94 T275.1 54.38,63.59 RH445.2
PCH_JTAG_TMS: length 47
  TOP w0.102: v2(56.48,66.15) 56.71,66.38 v1(57.14,66.38)
  IN1 w0.076: v1(57.14,66.38) 57.14,65.9 58.01,65.04 58.01,59.42 48.58,50 47.73,50 46.85,49.12 34.3,49.12 33.9,48.73 31.58,48.73 v4(31.17,49.14)
  GND5 w0.076: v4(31.17,49.14) 31.53,48.78 v5(31.64,48.78)
  BOTTOM w0.102: UCPU1.AD62 58.46,66.68 58.08,66.29 57.23,66.29 v1(57.14,66.38) 57.06,66.29 56.65,66.29 56.41,66.05 54.86,66.05 T276.1 54.43,65.62 RH39.2 ; RH372.1 32.76,48.78 v5(31.64,48.78)
PCH_JTAG_TRST#: length 31.4
  TOP w0.102: v1(49.14,61.58) v2(49.77,61.58)
  IN1 w0.076: v1(49.14,61.58) 49.78,60.95 49.78,58.71 45.64,54.57 39.69,54.57 v4(39.44,54.83)
  GND5 w0.076: v5(39.44,54.37) v4(39.44,54.83)
  BOTTOM w0.076: UCPU1.AU62 58.65,59.12 58.39,58.86 57.83,58.86 57.33,58.37 55.13,58.37 54.79,58.7
  BOTTOM w0.102: RH370.1 41.71,52.12 41.64,52.12 39.44,54.32 v5(39.44,54.37) ; v1(49.14,61.58) 49.22,61.66 51.84,61.66 54.79,58.7
PCH_OPIRCOMP: length 4.2
  TOP w0.076: v1(88.47,56.79) 87.9,57.37 RC156.1 86.52,57.9 v2(86.52,58.46)
  BOTTOM w0.076: v1(88.47,56.79) 88.34,56.92 88.34,57.54 UCPU1.AW15
PCH_PLTRST#: length 51
  IN4 w0.076: v4(121.18,63.37) 120.67,63.37 119.9,64.15 117.67,64.15 116.26,65.56 109,65.56 108.29,66.27 106.74,66.27 106.42,65.95 103.98,65.95 103.63,66.31 101.14,66.31 99.9,65.07 99.35,65.07 99.17,64.9 98.52,64.9 98.33,64.71 96.58,64.71 96.03,64.16 96.03,63.74 95.73,63.44 94.58,63.44 94.33,63.69 94.33,64.05 94.81,64.53 94.81,64.99 94.67,65.13 94.23,65.13 93.97,64.87 93.71,64.87 93.52,64.68 92.96,64.68 v4(92.91,64.73)
  GND5 w0.076: v5(92.37,64.76) 92.88,64.76 v4(92.91,64.73) ; v5(120.82,63.04) 120.85,63.04 v4(121.18,63.37)
  BOTTOM w0.102: UH5.2 RH168.2 ; RH168.2 119.95,54.39 ; RH168.2 119.53,53.92 v7(119.53,52.35) ; UCPU1.AG7 92.56,64.94 v5(92.37,64.76) ; 119.95,54.39 RH183.2 120.31,54.39 120.49,54.57 120.49,56.69 121.33,57.53 121.33,59.87 120.82,60.38 v5(120.82,63.04) ; 119.95,54.39 119.95,55.03 119.71,55.27 UH5.1
PCH_PWR_EN: length 16.2
  TOP w0.076: U34.N2 138.99,61.6 138.61,61.98
  TOP w0.102: R1249.2 v6(127.18,62.9) 127.18,63.26 127.01,63.44 v2(127.01,64.05) ; 138.61,61.98 138.39,62.2 137.73,62.2 v6(137.26,62.67)
  GND1 w0.076: v6(127.18,62.9) 127.72,62.37 v4(127.78,62.37) ; v4(137.6,62.9) 137.37,62.67 v6(137.26,62.67)
  IN1 w0.076: v4(127.78,62.37) 128.57,63.16 129.99,63.16 130.47,63.64 132.42,63.64 132.76,63.3 133.93,63.3 134.07,63.16 136.46,63.16 136.71,62.9 v4(137.6,62.9)
PCH_PWRBTN#_XDP: length 3.1
  TOP w0.102: RH444.2 RH21.2 24.93,50.61 JXDP.41
PCH_PWROK: length 106.7
  TOP w0.102: R1296.2 R1295.2 157.14,50.51 v1(156.84,50.2) 156.38,49.75 156.38,48.81 156.53,48.65 R1293.2 R1294.2 ; RH131.2 96.22,62.8 96.53,62.5 97.14,62.5 97.39,62.75 97.96,62.75 98.23,62.48 98.23,60.78 98.44,60.57 98.44,58.23 98.98,57.7 98.98,55.54 100.65,53.86 104.35,53.86 105.24,52.97 v7(105.24,52.03) 105.24,50.43 106.46,49.21 v3(107.84,49.21)
  IN4 w0.076: v3(107.84,49.21) 107.87,49.19 108.86,49.19 111.93,52.26 114.45,52.26 115.82,53.63 125.5,53.63 127.58,55.71 129.17,55.71 133.53,51.35 136.92,51.35 137.69,50.58 137.69,50.48 139.24,48.93 141.43,48.93 142.09,49.59 156.23,49.59 v1(156.84,50.2)
  BOTTOM w0.076: 93.4,54.95 93.22,55.14 93.22,55.16 92.83,55.54 92.83,56.68 92.5,57.01 UCPU1.AY7
  BOTTOM w0.102: v3(107.84,49.21) 106.94,49.21 105.79,48.07 97.51,48.07 96.46,49.11 96.46,52.54 96.13,52.87 RH394.1 95.43,53.3 95.05,53.3 93.4,54.95
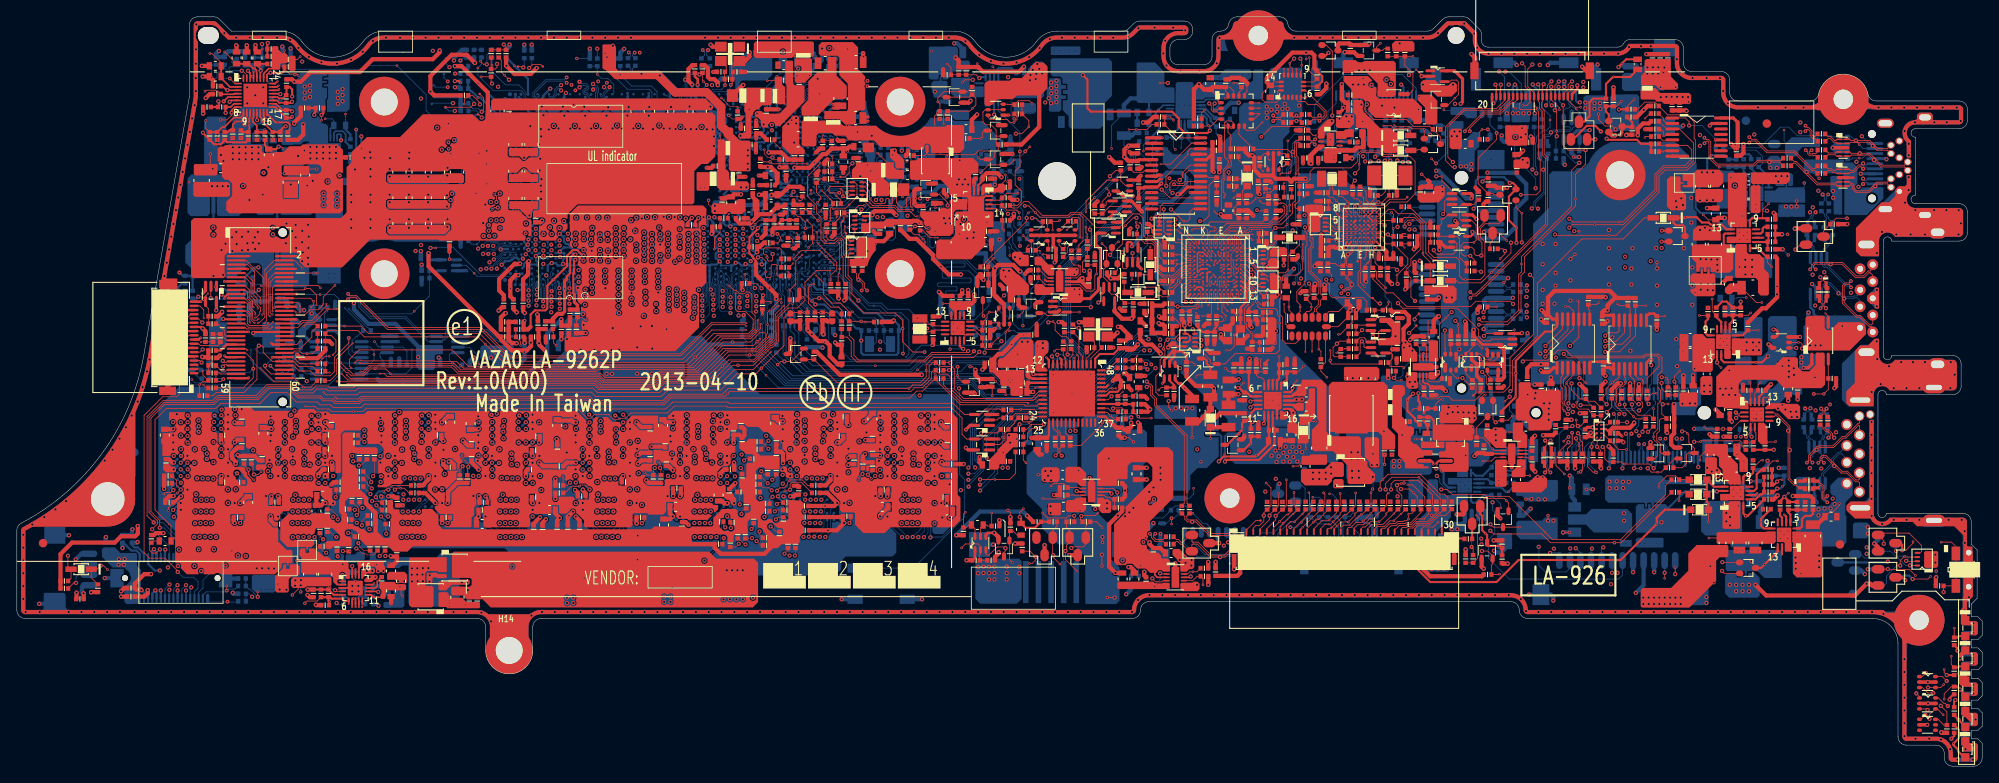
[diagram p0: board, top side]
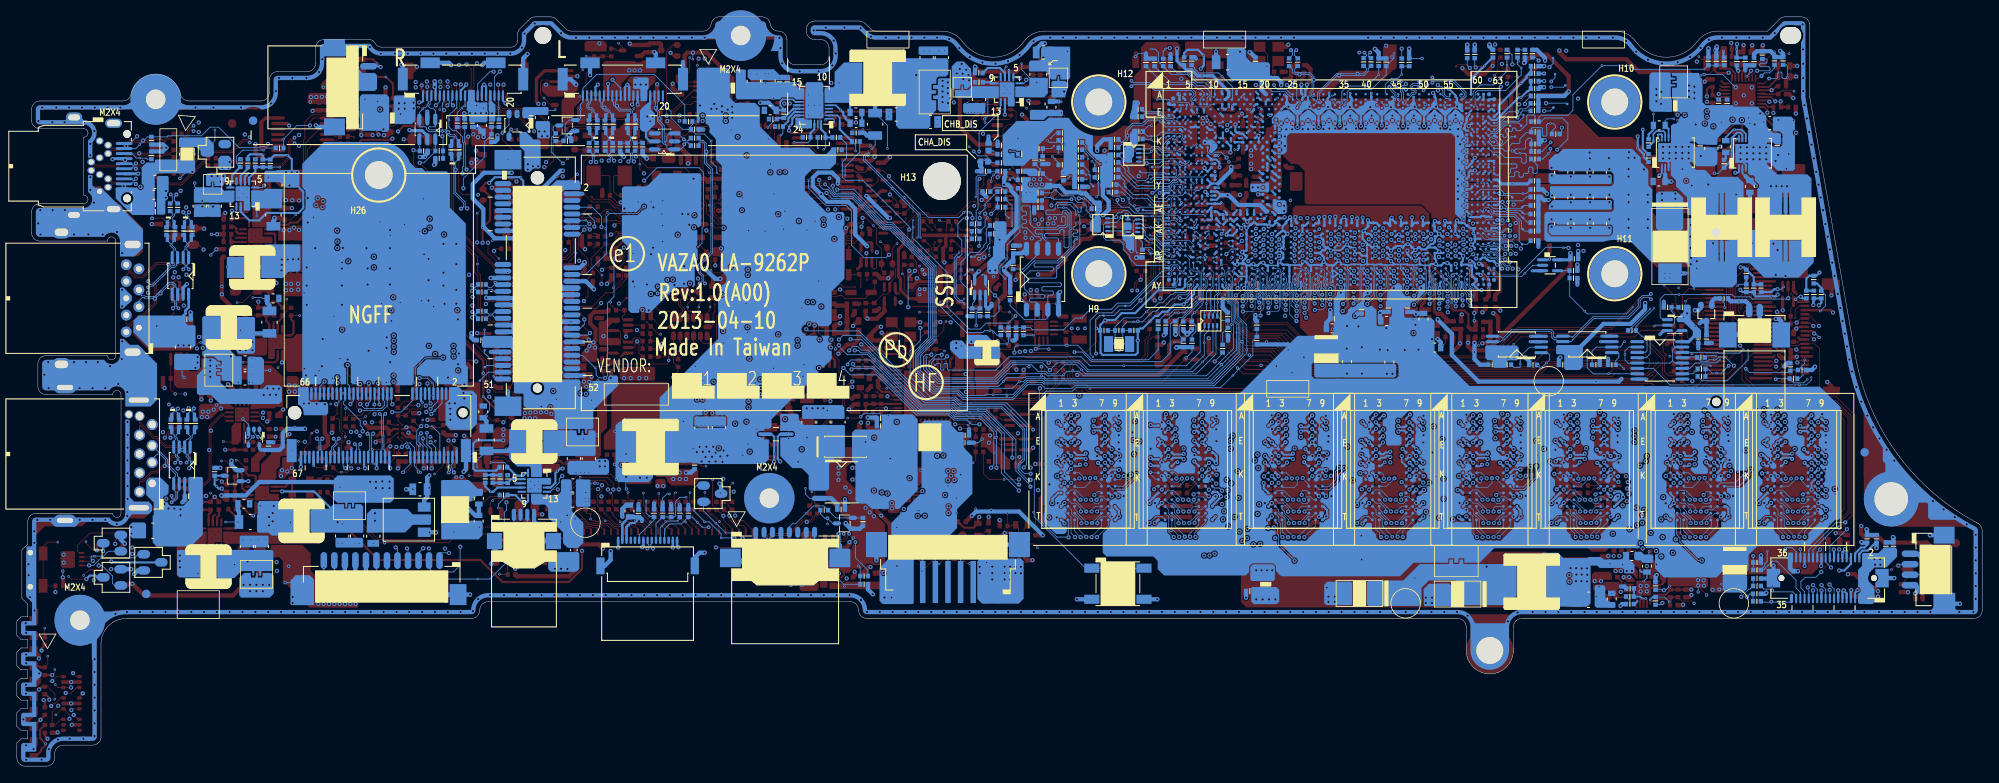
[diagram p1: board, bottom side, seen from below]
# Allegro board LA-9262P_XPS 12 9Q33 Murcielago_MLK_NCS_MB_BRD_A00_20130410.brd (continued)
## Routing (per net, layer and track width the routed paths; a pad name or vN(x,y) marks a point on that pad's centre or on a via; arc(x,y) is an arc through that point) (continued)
PCH_PWROK_EC: length 31.2
  TOP w0.102: R1294.1 159.6,49.1 159.6,50.28 v1(159.8,50.48) 160.05,50.23 160.05,49.85 160.15,49.75 U691.2 ; U34.E6 v6(143.07,59.6)
  GND1 w0.076: v4(142.62,59.27) 142.95,59.6 v6(143.07,59.6)
  IN2 w0.076: v4(142.62,59.27) 142.95,59.27 144.13,60.45 144.13,60.91 144.9,61.68 148.76,61.68 149.55,60.9 151.63,60.9 152.24,60.29 154.7,60.29 156.84,58.14 156.84,56.07 157.91,55 157.91,51.14 158.57,50.48 v1(159.8,50.48)
PCH_RSMRST#: length 58.3
  TOP w0.102: v8(113.71,49.31) 113.3,48.91 108.73,48.91 107.87,48.04 99.79,48.04 99.13,48.7 99.13,50.5 98.63,51 RH159.2 RH133.2 ; v6(143.92,61.04) U34.D4
  GND1 w0.076: v6(143.92,61.04) 143.92,61.37 v4(143.58,61.71)
  IN2 w0.076: v4(143.58,61.71) 143.58,61.68 142.41,60.52 141.24,60.52 140.3,59.58 139.75,59.58 139.17,59 138.31,59 137.32,58.01 137.32,57.65 135.9,56.22 134.97,56.22 133.8,57.39 130.26,57.39 129.6,56.73 126.85,56.73 126.41,56.29 124.6,56.29 124.11,56.78 119.43,56.78 115.87,53.23 115.87,51.68 113.71,49.52 v8(113.71,49.31)
PCH_RSMRST#_R: length 9.3
  TOP w0.076: v7(94.47,55.27) 94.81,55.61 v1(95.32,55.61)
  TOP w0.102: RH133.1 98.01,53.75 RH126.2 98,54.19 97.64,54.55 96.72,54.55 95.65,55.61 v1(95.32,55.61)
  BOTTOM w0.076: 93.95,56.51 93.95,56.86 93.67,57.14 93.67,57.62 93.41,57.88 UCPU1.AW6
  BOTTOM w0.102: v1(95.32,55.61) 95.3,55.59 94.61,55.59 93.95,56.25 93.95,56.51
PCH_RTCRST#: length 94
  TOP w0.102: JAPS.10 20.45,51.2 v1(19.98,50.74) ; v6(93.91,54.39) 93.94,54.36 RH25.2 CH4.2 92.01,53.92 CLRP1.2 91.66,53.82 91.14,53.3 91.14,49.97 v7(88.48,47.31) 87.79,46.62 85.54,46.62 83.61,44.69 77.32,44.69 76.56,43.93 68.76,43.93 68.26,44.44 40.72,44.44 40.42,44.13 36.74,44.13 v6(36.43,44.44)
  GND1 w0.076: v4(35.99,44.34) 36.09,44.44 v6(36.43,44.44) ; v4(93.83,54.88) 93.91,54.8 v6(93.91,54.39)
  IN1 w0.076: v4(93.83,54.88) 94.08,55.12 94.08,56.77 93.11,57.73 v4(93.11,59.14) ; v4(35.99,44.34) 35.99,45.45 35.26,46.18 34.26,46.18 33.87,45.78 25.24,45.78 25.01,45.55 22.31,45.55 20.31,47.55 20.31,50.41 v1(19.98,50.74)
  GND5 w0.076: v4(93.11,59.14) 92.84,58.88 v5(92.63,58.88)
  BOTTOM w0.102: UCPU1.AU7 92.46,59.06 92.63,58.89 v5(92.63,58.88)
PCH_RTCX1: length 15.5
  BOTTOM w0.076: UCPU1.AW5 94.39,57.48 94.39,56.81
  BOTTOM w0.102: RH2.1 103.02,50.39 103.25,50.16 YH1.1 ; RH2.1 103.02,52.21 101.95,53.28 100.01,53.28 v2(99.3,53.99) 98.74,54.55 98.34,54.55 97.78,55.11 97.33,55.11 96.37,56.06 96.15,56.06 95.92,56.29 94.61,56.29 94.39,56.51 94.39,56.81 ; RH2.1 CH2.1
PCH_RTCX2: length 14.2
  BOTTOM w0.102: YH1.2 101.87,50.16 102.1,50.39 RH2.2 ; RH2.2 102.1,52.29 101.59,52.79 v2(100.82,52.79) 99.77,52.79 98.5,54.06 98.14,54.06 97.61,54.6 97.15,54.6 96.21,55.54 95.96,55.54 95.47,56.02 94.48,56.02 94.2,56.3 94.2,57.06 UCPU1.AY5 ; RH2.2 CH3.1
PCH_SATALED#: length 13.4
  IN4 w0.076: v4(99.14,69.25) 99.4,69.51 100.82,69.51 101.28,69.96 103.6,69.96 103.7,69.86 104.3,69.86 v4(104.52,69.65)
  GND5 w0.076: v5(98.79,69.74) 99.14,69.38 v4(99.14,69.25) ; v4(104.52,69.65) 104.9,69.27 v5(105.01,69.27)
  BOTTOM w0.076: 97.37,69.94 95.78,69.94 95.37,70.35 UCPU1.U3
  BOTTOM w0.102: v2(105.23,67.65) 105.01,67.87 v5(105.01,69.27) 105.01,69.52 105.44,69.95 RH35.2 ; v5(98.79,69.74) 98.56,69.96 97.4,69.96 97.37,69.94
PCH_SMBCLK: length 182.9
  TOP w0.102: v1(24.48,47.49) 24.73,47.74 24.87,47.74 25.01,47.61 JXDP.53 ; v3(39.35,55.49) 39.53,55.66 40.27,55.66 44.03,51.9 55.08,51.9 58.46,48.53 67.8,48.53 68.05,48.78 78.91,48.78 82.59,52.46 86.49,52.46 v6(86.67,52.29) ; v1(134.25,45.07) 134.36,45.19 134.59,45.19 134.72,45.06 134.72,44.06 135.19,43.59 135.19,42.84 138.7,39.32 138.7,31.24 R1377.1 ; RH98.2 122.55,61.44 122.55,62.3 QH3.1 122.17,62.43 RH105.2 121.06,61.28 121.48,61.28 v6(121.54,61.22)
  GND1 w0.076: v6(86.67,52.29) 86.7,52.26 v4(87.07,52.26) ; v6(121.54,61.22) 121.48,61.28 120.97,61.28 v4(120.87,61.18)
  IN1 w0.076: v4(120.44,54.9) 120.24,55.11 119.68,55.11 119.1,55.69 118.17,55.69 117.44,56.41 114.14,56.41 113.55,57.01 108.94,57.01 106.63,54.7 103.72,54.7 101.79,52.77 89.84,52.77 89,51.93 88.54,51.93 88.03,52.44 87.24,52.44 v4(87.07,52.26)
  IN2 w0.076: v4(120.44,54.9) 120.67,55.13 121.08,55.13 121.27,54.95 121.27,48.56 123.13,46.7 131.01,46.7 132.4,45.3 134.07,45.3 134.25,45.12 v1(134.25,45.07)
  IN4 w0.076: v1(24.48,47.49) 24.71,47.71 25.38,47.71 26.98,49.31 29.61,49.31 30.93,50.63 31.47,50.63 33.42,52.59 34.85,52.59 37.24,54.98 37.92,54.98 38.65,55.71 39.19,55.71 39.35,55.55 v3(39.35,55.49)
  GND5 w0.076: v5(120.92,54.95) 120.87,54.9 v4(120.44,54.9) ; v5(121.53,61.02) 121.38,61.18 v4(120.87,61.18)
  BOTTOM w0.102: UD8.6 57.23,50.44 57.02,50.65 56.82,50.65 55.82,51.65 51.3,51.65 51.14,51.49 51.14,50.95 50.85,50.66 50.62,50.66 50.41,50.45 UD3.6 48.85,50.45 48.64,50.66 48.64,50.69 46.15,53.17 42.04,53.17 40.63,54.58 40.63,55.33 40.25,55.71 39.58,55.71 v3(39.35,55.49) ; v5(120.92,54.95) 121.11,55.14 121.52,55.14 122.13,55.75 122.13,60.43 121.82,60.74 121.81,60.74 v5(121.53,61.02)
PCH_SMBDATA: length 188.7
  TOP w0.102: v3(39.36,56.12) 39.59,55.89 40.37,55.89 44.13,52.13 55.18,52.13 58.55,48.76 67.7,48.76 67.96,49.01 78.81,49.01 82.49,52.69 86.65,52.69 v6(86.67,52.67) ; JXDP.51 25.01,48.11 24.87,47.97 24.67,47.97 v1(24.47,48.17) ; RH99.2 122.26,60.82 v6(121.93,60.82) ; v1(120.62,65.14) 121.09,65.14 121.5,64.73 RH111.2 121.91,64.72 121.91,64.34 121.31,63.73 QH3.4 ; v1(134.25,45.71) 134.53,45.42 134.67,45.42 134.94,45.15 134.94,44.15 135.41,43.68 135.41,42.93 139.03,39.31 v2(139.03,32.6) 139.03,31.24 R1378.1
  GND1 w0.076: v4(122.12,60.24) 122.12,60.63 v6(121.93,60.82) ; v6(86.67,52.67) 86.91,52.67 v4(87.07,52.82)
  IN1 w0.076: v4(120.42,55.51) 120.21,55.31 119.76,55.31 119.18,55.89 118.25,55.89 117.53,56.62 114.23,56.62 113.63,57.21 108.86,57.21 106.55,54.9 103.64,54.9 101.71,52.97 89.76,52.97 88.92,52.13 88.62,52.13 88.12,52.64 87.24,52.64 v4(87.07,52.82)
  IN2 w0.076: v1(134.25,45.71) 134.04,45.5 132.49,45.5 131.09,46.9 123.22,46.9 121.47,48.65 121.47,55.03 121.16,55.34 120.59,55.34 v4(120.42,55.51)
  IN4 w0.076: v3(39.36,56.12) 39.16,55.92 38.57,55.92 37.84,55.19 37.16,55.19 34.77,52.79 33.34,52.79 31.38,50.84 30.85,50.84 29.53,49.52 26.89,49.52 25.29,47.92 24.72,47.92 v1(24.47,48.17)
  GND5 w0.076: v4(122.12,60.24) 121.83,60.24 121.53,60.53 v5(121.53,60.52) ; v5(120.95,55.56) 120.9,55.51 v4(120.42,55.51)
  BOTTOM w0.102: v3(39.36,56.12) 39.54,55.94 40.35,55.94 40.86,55.43 40.86,54.67 42.13,53.4 46.25,53.4 48.64,51.01 48.7,50.95 48.85,51.1 UD3.5 50.4,51.1 50.61,50.89 50.76,50.89 50.91,51.04 50.91,51.58 51.21,51.88 55.92,51.88 56.92,50.88 57.02,50.88 57.23,51.09 UD8.5 ; v5(120.95,55.56) 121.14,55.37 121.43,55.37 121.9,55.85 121.9,60.34 121.72,60.52 v5(121.53,60.52) 121.23,60.82 121.23,62.51 121.7,62.98 121.7,64.44 121,65.14 v1(120.62,65.14)
PCH_SMLCLK: length 120.5
  TOP w0.076: U34.B8 145.17,58.85 145.17,59.29 145.24,59.35 145.68,59.35
  TOP w0.102: v6(150.21,71.63) 150.46,71.88 150.69,71.88 R1307.1 150.6,71.31 150.08,71.31 149.95,71.17 Q352.6 ; v6(116.87,52.03) 116.87,52.08 116.65,52.3 Q359.1 116.5,52.69 R1350.2 ; v8(149.27,77.32) 149.52,77.07 150.1,77.07 R983.1 ; RP15.8 147.82,56.92 147.71,57.04 147.4,57.04 146.9,57.54 146.9,58.14 v1(146.65,58.38) 145.68,59.35 ; RH453.2 124.8,61.01 124.8,61.62 v6(125.25,62.08) 125.61,62.43 QH4.1
  GND1 w0.076: v6(150.21,71.63) 150.21,71.75 v4(149.97,72) ; v4(125.67,62.4) 125.57,62.4 v6(125.25,62.08) ; v4(116.64,51.55) 116.87,51.78 v6(116.87,52.03)
  IN1 w0.076: v4(125.67,62.4) 126.11,62.4 126.21,62.29 126.21,62.01 126.45,61.76 128.35,61.76 129.21,62.62 131.14,62.62 131.61,63.09 132.19,63.09 132.56,62.73 133.67,62.73 134.49,61.91 136.4,61.91 136.96,61.34 138.26,61.34 138.86,61.94 139.43,61.94 140.43,60.94 140.43,60.59 140.69,60.34 142.07,60.34 142.76,59.65 143.27,59.65 143.56,59.94 144.1,59.94 144.66,59.37 146.01,59.37 146.22,59.16 146.22,58.82 v1(146.65,58.38)
  IN2 w0.076: v4(116.64,51.55) 116.64,51.63 116.83,51.82 116.83,52.18 118.1,53.45 118.1,54.19 120.03,56.12 121.51,56.12 123.57,54.06 133.29,54.06 135.17,52.18 138.2,52.18 139.06,51.32 141.45,51.32 142.13,52.01 143.28,52.01 143.43,51.85 144.5,51.85 145.96,53.31 145.96,55.26 146.6,55.9 146.6,57.32 147.29,58.01 147.29,58.37 147.1,58.56 146.83,58.56 v1(146.65,58.38)
  IN3 w0.076: v8(149.27,77.32) 149.5,77.09 149.91,77.09 150.24,76.76 150.24,75.2 149.78,74.74 149.78,72.17 149.96,72 v4(149.97,72)
  IN4 w0.076: v4(132.79,72.33) 132.96,72.5 133.15,72.5 134.03,73.38 135,73.38 135.23,73.61 139.5,73.61 141.31,71.79 145.93,71.79 146.33,71.4 149.54,71.4 149.75,71.61 149.75,71.77 v4(149.97,72)
  GND5 w0.076: v4(125.67,62.4) 126.13,62.4 126.21,62.47 126.21,62.7 v5(126.11,62.8) ; v4(132.79,72.33) 132.66,72.45 v5(132.3,72.45)
  BOTTOM w0.102: v5(126.11,62.8) 126.18,62.88 126.18,65.6 132.68,72.1 132.68,72.41 132.56,72.53 132.38,72.53 v5(132.3,72.45)
PCH_SMLDATA: length 124.2
  TOP w0.102: QH4.4 124.14,63.73 124.39,63.98 124.39,64.25 RH454.2 125,64.86 125.1,64.86 125.46,65.21 126.14,65.21 126.32,65.04 v6(126.32,62.83) ; Q359.4 117.95,53.25 117.9,53.2 v6(117.89,53.2) ; R984.1 150.46,76.49 150.12,76.84 149.43,76.84 v8(149.27,76.68) ; RP15.7 147.86,57.42 147.71,57.26 147.5,57.26 147.12,57.65 147.12,58.66 146.77,59.02 v1(146.65,59.02) 146.07,59.6 U34.A6 ; v6(148.83,72.03) 148.65,72.21 Q352.3 148.19,72.79 R1308.1 ; v6(116.62,50.89) 116.54,50.89 115.65,50 R1351.2
  GND1 w0.076: v6(148.83,72.03) 148.86,72 v4(149.37,72) ; v4(118.28,52.84) 117.93,53.2 v6(117.89,53.2) ; v4(126.94,62.37) 126.49,62.83 v6(126.32,62.83) ; v6(116.62,50.89) 116.85,51.12 v4(117.04,51.12)
  IN1 w0.076: v4(126.94,62.37) 126.49,62.37 126.41,62.29 126.41,62.09 126.54,61.96 128.26,61.96 129.13,62.83 131.06,62.83 131.53,63.3 132.28,63.3 132.65,62.93 133.75,62.93 134.57,62.11 136.48,62.11 137.05,61.54 138.18,61.54 138.77,62.14 139.52,62.14 140.63,61.02 140.63,60.68 140.77,60.54 142.15,60.54 142.84,59.86 143.19,59.86 143.47,60.14 144.18,60.14 144.75,59.57 146.1,59.57 v1(146.65,59.02)
  IN2 w0.076: v1(146.65,59.02) 146.91,58.76 147.19,58.76 147.49,58.46 147.49,57.92 146.81,57.24 146.81,55.82 146.16,55.17 146.16,53.22 144.59,51.64 143.35,51.64 143.19,51.8 142.22,51.8 141.53,51.12 138.98,51.12 138.11,51.98 135.09,51.98 133.21,53.86 123.48,53.86 121.44,55.91 120.1,55.91 118.3,54.11 118.3,53.18 118.31,53.17 118.31,52.87 v4(118.28,52.84) 118.08,53.05 117.99,53.05 117.04,52.1 v4(117.04,51.12)
  IN3 w0.076: v8(149.27,76.68) 149.45,76.86 149.85,76.86 150.03,76.67 150.03,75.28 149.58,74.82 149.58,72.19 149.38,72 v4(149.37,72)
  IN4 w0.076: v4(149.37,72) 149.54,71.82 149.54,71.69 149.45,71.6 146.41,71.6 146.02,72 141.4,72 139.58,73.81 135.15,73.81 134.92,73.58 133.94,73.58 133.07,72.71 133.01,72.71 v4(132.79,72.94)
  GND5 w0.076: v4(126.94,62.37) 126.51,62.37 126.41,62.47 126.41,62.7 v5(126.51,62.8) ; v4(132.79,72.94) 132.68,72.83 v5(132.3,72.83)
  BOTTOM w0.102: v5(132.3,72.83) 132.38,72.76 132.66,72.76 132.91,72.5 132.91,72.01 126.41,65.51 126.41,62.9 v5(126.51,62.8)
PCH_SPI_CLK: length 5.5
  TOP w0.076: v2(95.14,67.01) 95.49,67.35 v6(95.49,67.4)
  TOP w0.102: v6(95.49,67.4) 95.49,67.69 95.02,68.16 MC118.2 95.47,69.79 RH255.2
  GND1 w0.076: v6(95.49,67.4) 95.49,67.67 v4(95.8,67.98)
  GND5 w0.076: v4(95.8,67.98) 95.8,68.17 v5(95.49,68.49)
  BOTTOM w0.102: UCPU1.AA3 95.49,68.34 v5(95.49,68.49)
PCH_SPI_CS#: length 39.5
  IN1 w0.076: v4(107.5,65.87) 107.5,66.09 107.32,66.27 106.7,66.27 106.47,66.04 104.8,66.04 103.54,67.3 103.54,67.62 102.97,68.19 100.22,68.19 99.87,68.54 97.76,68.54 97.67,68.63 95.32,68.63 95.13,68.82 94.33,68.82 v4(93.29,67.78)
  GND5 w0.076: v5(107.69,65.54) 107.5,65.74 v4(107.5,65.87) ; v5(93.63,68.14) 93.63,68.12 v4(93.29,67.78)
  BOTTOM w0.102: v5(93.63,68.14) 93.36,68.4 93.04,68.4 UCPU1.Y7 ; v5(107.69,65.54) 107.69,66.04 108.36,66.71 109.75,66.71 109.87,66.59 109.87,66.47 109.76,66.36 v2(109.14,66.36) 108.73,66.36 108.25,65.87 108.25,61.68 109.89,60.03 112.62,60.03 114.27,58.38 114.27,55.69 113.55,54.97 U48.1
PCH_SPI_IO2: length 7.1
  TOP w0.102: RP4.7 98.86,68.39 v3(98.6,68.14)
  BOTTOM w0.076: UCPU1.Y6 93.63,68.47 94.67,68.47 94.98,68.77 94.98,68.95 95.16,69.13 95.74,69.13 95.79,69.18 96.07,69.18 96.35,68.9 96.35,68.77 96.5,68.62 96.81,68.62
  BOTTOM w0.102: v3(98.6,68.14) 98.43,68.14 97.95,68.62 96.81,68.62
PCH_SPI_IO3: length 7.1
  TOP w0.102: RP4.5 99.55,69.39 99.82,69.13 99.82,67.64 v2(98.88,66.7) 98.41,66.23 v6(96.97,66.23)
  GND1 w0.076: v6(96.97,66.23) 96.72,65.98 v4(96.72,65.82)
  GND5 w0.076: v4(96.72,65.82) 96.69,65.82 v5(96.29,66.22)
  BOTTOM w0.102: UCPU1.AF1 96.62,65.9 96.31,66.22 v5(96.29,66.22)
PCH_SPI_SI: length 6.6
  TOP w0.102: v3(97.72,68.14) 96.64,68.14 96.45,68.33 v2(96.45,68.48) 96.45,68.68 96.66,68.89 RP4.6
  BOTTOM w0.102: UCPU1.AA2 96.28,68.44 97.42,68.44 v3(97.72,68.14)
PCH_SPI_SO: length 6.1
  TOP w0.102: RP4.8 98.97,67.89 98.69,67.61 98.27,67.61 v3(98.15,67.73) 98.15,68.34 v2(97.91,68.58)
  BOTTOM w0.102: UCPU1.AA4 95,67.85 96.62,67.85 97.02,67.45 97.87,67.45 v3(98.15,67.73)
PCH_SRTCRST#: length 8.6
  TOP w0.102: v6(94.7,57.29) 94.42,57.29 v2(94.27,57.14) 94.06,56.93 94.06,55 94.83,54.24 RH23.2 CH5.1 96.25,53.92 96.35,53.82 CLRP2.1
  GND1 w0.076: v4(94.69,58.05) 94.7,58.04 v6(94.7,57.29)
  GND5 w0.076: v4(94.69,58.05) 94.58,58.15 v5(94.28,58.15)
  BOTTOM w0.102: v5(94.28,58.15) 94.25,58.19 93.63,58.19 UCPU1.AV6
PCH_SUSWARN#: length 37.7
  TOP w0.076: U34.D8 144.23,58.6 v6(144.28,58.66)
  GND1 w0.076: v6(144.28,58.66) 143.95,58.66 v4(143.59,58.31)
  IN1 w0.076: v4(143.59,58.31) 143.35,58.55 141.31,58.55 141.05,58.28 140.09,58.28 139.95,58.14 139.95,57.45 139.76,57.26 139.76,56.79 140.13,56.43 140.13,55.87 139.85,55.59 127.6,55.59 126.83,54.81 125.42,54.81 124.42,53.81 115.97,53.81 v4(113.53,51.37)
  GND5 w0.076: v5(113.89,51.17) 113.74,51.17 v4(113.53,51.37)
  BOTTOM w0.102: v2(112.69,51.22) RH297.2
PCI_PIRQC#: length 6
  BOTTOM w0.076: UCPU1.N4 95.07,73.06 95.45,73.06 95.5,73.11 97.37,73.11 97.37,73.12
  BOTTOM w0.102: 97.37,73.12 97.87,73.62 98.62,73.62 98.89,73.36 RP2.8
PCI_PIRQD#: length 4.8
  BOTTOM w0.076: 97.37,72.91 96.24,72.91 95.97,72.65 UCPU1.N2
  BOTTOM w0.102: RP2.7 98.91,72.86 v2(98.71,73.06) 98.37,73.39 97.93,73.39 97.45,72.91 97.37,72.91
PCIE_PRX_DTX_N4: length 154.9
  IN4 w0.076: v1(89.69,76.21) 89.69,76.02 89.62,75.95 89.57,75.95 89.53,75.91 89.48,75.91 89.29,76.1 89.29,77.41 90.33,78.45 90.33,79.34 94.22,83.22 97.62,83.22 98.59,84.2 107.71,84.2 112.43,79.49 113.48,79.49 114.51,78.46 119.67,78.46 121.14,76.99 137.36,76.99 137.68,76.67 141.37,76.67 142.86,75.18 148.08,75.18 148.38,74.88 152.94,74.88 154.12,76.06 158.6,76.06 159.91,77.37 165.67,77.37 165.83,77.53 176.25,77.53 176.78,77 180.54,77 182.28,75.25 182.28,74.59 184.96,71.92 184.96,71.08 186.07,69.96 186.07,68.05 188.12,66 188.12,41.99 189.86,40.25 193.9,40.25 194.67,39.47 194.67,38.71 195.07,38.32 197.42,38.32 197.57,38.47 197.57,38.66 v1(197.84,38.93)
  BOTTOM w0.076: v1(89.69,76.21) 89.32,76.59 UCPU1.F13
  BOTTOM w0.102: JNGFF1.59 197.75,37.41 197.6,37.55 197.6,38.69 v1(197.84,38.93)
PCIE_PRX_DTX_P4: length 155
  IN4 w0.076: v8(89.72,75.58) 89.54,75.76 89.42,75.76 89.14,76.03 89.14,77.47 90.18,78.51 90.18,79.4 94.15,83.38 97.55,83.38 98.53,84.35 107.78,84.35 112.49,79.64 113.54,79.64 114.57,78.61 119.73,78.61 121.2,77.14 137.42,77.14 137.74,76.82 141.44,76.82 142.92,75.34 148.14,75.34 148.44,75.03 152.88,75.03 154.06,76.21 158.54,76.21 159.85,77.52 165.6,77.52 165.77,77.69 176.31,77.69 176.84,77.15 180.6,77.15 182.44,75.32 182.44,74.66 185.11,71.98 185.11,71.15 186.23,70.03 186.23,68.11 188.27,66.07 188.27,42.05 189.92,40.4 193.96,40.4 194.83,39.53 194.83,38.77 195.13,38.47 197.35,38.47 197.42,38.53 197.42,38.71 v1(197.2,38.93)
  BOTTOM w0.076: UCPU1.G13 89.31,75.93 89.59,75.65 89.64,75.65 v8(89.72,75.58)
  BOTTOM w0.102: JNGFF1.57 197.24,37.43 197.39,37.58 197.39,38.73 v1(197.2,38.93)
PCIE_PRX_WLANTX_N3: length 146.7
  IN4 w0.076: v8(191.83,39.51) 191.57,39.26 191.57,39.09 191.41,38.93 190.39,38.93 190.27,39.05 190.16,39.05 187.51,41.71 187.51,65.68 185.45,67.74 185.45,69.72 184.35,70.83 184.35,71.64 181.53,74.46 181.53,75.08 180.22,76.39 176.5,76.39 175.97,76.92 166.24,76.92 164.75,75.44 154.39,75.44 153.22,74.27 148.44,74.27 148.33,74.16 147.61,74.16 147.49,74.27 142.21,74.27 140.49,76 134.21,76 134.19,75.97 134.16,75.97 134.04,75.86 128.49,75.86 128.07,76.28 120.98,76.28 119.41,77.85 113.2,77.85 107.46,83.59 98.95,83.59 97.94,82.59 96.87,82.59 92.91,78.63 92.17,78.63 90.93,77.38 90.93,76.39 90.7,76.16 90.5,76.16 v4(90.26,75.92)
  GND5 w0.076: v5(90.63,76.08) 90.51,76.21 90.45,76.21 90.26,76.02 v4(90.26,75.92)
  BOTTOM w0.102: v8(191.83,39.51) 191.58,39.26 191.58,37.58 191.75,37.41 JNGFF1.35 ; v5(90.63,76.08) 90.61,76.1 90.38,76.1 UCPU1.G11
PCIE_PRX_WLANTX_P3: length 146.6
  IN4 w0.076: v1(191.17,39.51) 191.42,39.26 191.42,39.15 191.35,39.08 190.46,39.08 190.4,39.13 190.33,39.2 190.23,39.2 187.66,41.77 187.66,65.75 185.6,67.81 185.6,69.79 184.5,70.89 184.5,71.7 181.68,74.52 181.68,75.15 180.28,76.54 176.56,76.54 176.03,77.08 166.17,77.08 164.69,75.59 154.33,75.59 153.16,74.42 148.38,74.42 148.26,74.31 147.67,74.31 147.56,74.42 142.28,74.42 140.55,76.15 134.15,76.15 134.13,76.12 134.09,76.12 133.98,76.01 128.56,76.01 128.13,76.44 121.04,76.44 119.48,78 113.26,78 107.52,83.74 98.88,83.74 97.88,82.74 96.81,82.74 92.84,78.78 92.11,78.78 90.77,77.44 90.77,76.45 90.63,76.31 90.32,76.31 90.26,76.38 v4(90.26,76.66)
  GND5 w0.076: v5(90.63,76.43) 90.56,76.36 90.42,76.36 90.26,76.53 v4(90.26,76.66)
  BOTTOM w0.102: v5(90.63,76.43) 90.36,76.43 UCPU1.F11 ; JNGFF1.33 191.24,37.45 191.37,37.58 191.37,39.31 v1(191.17,39.51)
PCIE_PTX_DRX_N4: length 158.5
  IN4 w0.076: v8(82.13,85.1) 81.88,84.86 81.88,83.2 82.42,82.66 90.42,82.66 92.35,84.59 96.96,84.59 97.94,85.57 111.08,85.57 111.17,85.48 112.36,85.48 115.16,82.69 117.76,82.69 118.71,81.73 118.71,81.42 121.77,78.36 138.35,78.36 138.67,78.04 141.94,78.04 143.43,76.56 148.66,76.56 148.97,76.25 152.24,76.25 152.9,76.91 152.9,77.27 155,79.36 180.26,79.36 183.13,76.49 184.02,76.49 187.52,72.99 187.52,68.61 193.38,62.75 193.38,41.94 195.6,39.71 195.6,39.2 v3(195.88,38.93)
  BOTTOM w0.102: CH1237.1 81.92,84.53 81.92,84.9 v8(82.13,85.1) ; v3(195.88,38.93) 195.68,38.72 195.68,38.34 196.07,37.94 196.07,37.63 196.24,37.46 JNGFF1.53
PCIE_PTX_DRX_N4_C: length 6.4
  BOTTOM w0.076: 79.61,80.51 79.61,80.35 79.87,80.09 79.87,79.68 79.83,79.64 79.83,79.62 79.41,79.2 UCPU1.B29
  BOTTOM w0.102: CH1237.2 81.93,82.78 81.93,82.48 81.64,82.19 v1(81.1,82.19) 79.95,82.19 79.63,81.87 79.63,81.29 79.61,81.27 79.61,80.51
PCIE_PTX_DRX_P4: length 158.5
  IN4 w0.076: v3(81.49,85.1) 81.73,84.86 81.73,83.13 82.35,82.51 90.48,82.51 92.41,84.44 97.02,84.44 98,85.42 111.02,85.42 111.11,85.33 112.3,85.33 115.09,82.54 117.69,82.54 118.56,81.67 118.56,81.36 121.71,78.21 138.28,78.21 138.6,77.89 141.88,77.89 143.36,76.4 148.6,76.4 148.9,76.1 152.31,76.1 153.05,76.85 153.05,77.2 155.06,79.21 180.19,79.21 183.07,76.34 183.95,76.34 187.37,72.92 187.37,68.54 193.22,62.69 193.22,41.87 195.45,39.65 195.45,39.13 v3(195.24,38.93)
  BOTTOM w0.102: v3(81.49,85.1) 81.72,84.87 81.72,84.5 CH1238.1 ; JNGFF1.51 195.75,37.46 195.87,37.58 195.87,37.86 195.47,38.25 195.47,38.7 v3(195.24,38.93)
PCIE_PTX_DRX_P4_C: length 6.4
  BOTTOM w0.076: UCPU1.A29 79.33,79.78 79.33,79.62 79.39,79.55 79.5,79.55 79.64,79.7 79.64,79.72 79.69,79.76 79.69,80.02 79.43,80.28 79.43,80.42 79.42,80.43 79.42,80.49 79.4,80.5 79.4,80.51
  BOTTOM w0.102: CH1238.2 81.72,82.8 81.72,82.56 81.55,82.4 81.39,82.4 81.37,82.42 80.82,82.42 80.8,82.4 79.86,82.4 79.4,81.94 v1(79.4,81.57) 79.4,80.51
PCIE_PTX_WLANRX_N3: length 162.7
  IN4 w0.076: v3(190.38,41.86) 190.14,42.1 190.14,42.48 189.9,42.72 189.9,46 190.14,46.24 190.14,65.11 186.86,68.39 186.86,71.97 185.27,73.56 185.27,74.14 183.53,75.88 182.86,75.88 180.45,78.3 165.34,78.3 165.18,78.14 154.72,78.14 153.56,76.99 153.56,76.7 152.51,75.64 148.7,75.64 148.39,75.95 143.18,75.95 141.69,77.43 138.13,77.43 137.81,77.75 121.48,77.75 118.23,81 118.04,81 116.97,82.08 114.91,82.08 112.11,84.87 110.83,84.87 110.74,84.96 98.28,84.96 97.3,83.99 92.87,83.99 90.91,82.03 81.4,82.03 81.17,82.26 75.24,82.26 73.13,84.37 73.13,84.65 73.28,84.8 v3(73.4,84.8)
  BOTTOM w0.102: JNGFF1.29 190.24,37.5 190.1,37.64 190.1,39.24 190.17,39.31 190.17,41.65 v3(190.38,41.86) ; v3(73.4,84.8) 73.14,84.54 73.14,84.42 73.42,84.15 CH11.1
PCIE_PTX_WLANRX_N3_C: length 9.3
  BOTTOM w0.102: UCPU1.C29 79.14,78.82 79.14,79.06 78.97,79.23 78.97,80.04 76.7,82.31 76.09,82.31 76.07,82.29 v1(74.21,82.29) 73.51,82.29 73.15,82.65 73.15,82.89 CH11.2
PCIE_PTX_WLANRX_P3: length 162.7
  IN4 w0.076: v3(189.73,41.86) 189.99,42.11 189.99,42.42 189.75,42.66 189.75,46.06 189.99,46.3 189.99,65.05 186.71,68.33 186.71,71.91 185.12,73.49 185.12,74.08 183.47,75.73 182.8,75.73 180.39,78.14 165.4,78.14 165.25,77.99 154.78,77.99 153.72,76.92 153.72,76.63 152.57,75.49 148.63,75.49 148.33,75.79 143.11,75.79 141.63,77.28 138.07,77.28 137.75,77.6 121.42,77.6 118.17,80.85 117.98,80.85 116.9,81.93 114.84,81.93 112.05,84.72 110.76,84.72 110.68,84.81 98.34,84.81 97.36,83.83 92.93,83.83 90.98,81.88 81.34,81.88 81.11,82.11 75.17,82.11 72.97,84.3 72.97,84.65 72.81,84.81 v3(72.7,84.81)
  BOTTOM w0.102: v3(72.7,84.81) 72.93,84.58 72.93,84.38 72.69,84.15 CH16.1 ; v3(189.73,41.86) 189.95,41.64 189.95,39.38 189.89,39.33 189.89,37.65 189.75,37.5 JNGFF1.27
PCIE_PTX_WLANRX_P3_C: length 9.3
  BOTTOM w0.102: CH16.2 72.94,82.9 72.94,82.56 73.43,82.08 73.88,82.08 73.9,82.06 74.54,82.06 74.56,82.08 v1(76.4,82.08) 76.64,82.08 78.76,79.96 78.76,79.22 78.53,78.99 78.53,78.85 78.62,78.76 78.72,78.76 UCPU1.B30
PCIE_RCOMP: length 2.8
  TOP w0.305: v1(80.88,80.98) 80.89,80.99 80.89,81.63 80.56,81.97 RH338.2
  BOTTOM w0.305: UCPU1.A27 80.91,79.98 80.91,80.81 80.93,80.84 80.93,80.92 v1(80.88,80.98)
PCIE_WAKE#: length 50.3
  TOP w0.102: v1(194.47,35.41) 193.97,35.9 v2(190.99,35.9) 190.89,35.9 190.63,36.16 R942.2 189.05,36.16 188.67,36.54 188.67,37.68 v1(188.41,37.93) ; Q347.3 174.37,64.67 173.63,63.93 173.63,62.66 174.07,62.22 174.07,60.77 v1(173.98,60.68) 173.36,60.68 173.15,60.9 173.15,61.38 172.86,61.67 U676.4
  IN4 w0.076: v1(173.98,60.68) 174.63,60.68 175.95,59.36 175.95,56.11 179.83,52.24 181.68,52.24 182.11,51.8 182.11,48.22 183.14,47.2 183.14,39.57 183.28,39.43 183.28,38.21 183.98,37.5 187.98,37.5 v1(188.41,37.93)
  BOTTOM w0.102: v1(194.47,35.41) 194.75,35.68 JNGFF1.47
PLT_RST#: length 244.6
  TOP w0.076: 138.96,59.8 139.01,59.85 139.67,59.85 U34.M5
  TOP w0.102: R1313.1 187.03,42.9 v1(185.79,42.9) ; RH363.2 40.89,52.3 41.76,51.42 54.99,51.42 58.29,48.12 68.21,48.12 68.46,48.37 79.12,48.37 82.57,51.83 86.6,51.83 v6(86.62,51.85) ; v1(169.45,65.62) 169.6,65.77 169.6,67.11 169.9,67.4 170.51,67.4 ; 138.96,59.8 138.46,59.8 138.34,59.68 v6(137.8,59.68) 137.8,59.54 137.29,59.03 R929.2 ; v6(131.36,60.21) 131.36,59.26 131.5,59.12 131.78,59.12 131.91,59.24 U698.1
  GND1 w0.076: v6(86.62,51.85) 86.77,51.7 v4(87.08,51.7) ; v6(131.36,60.21) v4(131.36,59.73) ; v4(137.31,59.55) 137.43,59.68 v6(137.8,59.68)
  IN1 w0.076: v1(169.45,65.62) 169.45,65.54 171.85,63.14 171.85,63 173.45,61.4 173.45,59.87 177.31,56.01 177.31,53.47 178.88,51.9 188.61,51.9 189.14,51.38 189.14,48.97 187.38,47.22 187.38,45.61 185.79,44.01 v1(185.79,42.9) 185.63,42.9 184.92,43.61 184.25,43.61 183.75,43.12 183.75,39.15 182.67,38.07 179.7,38.07 179,37.38 179,23.19 179.22,22.97 v1(189.53,22.97) ; v4(131.36,59.73) 131.69,59.4 137.15,59.4 v4(137.31,59.55) ; v4(87.08,51.7) 87.13,51.75 88.16,51.75 88.36,51.55 89.2,51.55 90.04,52.39 95.4,52.39 97.02,50.76 97.89,50.76 100.3,48.35 105.9,48.35 106.38,47.87 109.15,47.87 110.5,49.21 110.5,50.75 114.93,55.18 117.01,55.18 117.29,55.46 v1(117.29,55.94)
  IN4 w0.076: v4(137.31,59.55) 137.88,58.98 139.07,58.98 139.64,59.55 140.33,59.55 141.08,60.3 141.64,60.3 141.96,60.62 141.96,61.21 142.59,61.85 142.59,62.24 142.79,62.45 143.68,62.45 144.11,62.88 144.11,63.55 144.92,64.35 147.2,64.35 147.66,63.89 148.84,63.89 149.3,63.44 150.6,63.44 151.14,62.9 153.73,62.9 154.39,62.24 156.64,62.24 157,62.6 162.17,62.6 162.46,62.31 163.61,62.31 164.48,63.18 167.11,63.18 169.45,65.52 v1(169.45,65.62) ; v4(118.56,58.79) 118.96,58.39 119.39,58.39 120.16,59.17 123.21,59.17 124.63,60.59 129.23,60.59 129.99,59.83 131.26,59.83 v4(131.36,59.73)
  GND5 w0.076: v5(118.8,58.41) 118.8,58.55 v4(118.56,58.79)
  BOTTOM w0.102: v5(118.8,58.41) 118.57,58.41 118.41,58.24 UH5.4 118.41,57.06 v1(117.29,55.94) 116.81,55.46 v2(116.81,54.57) 116.81,54.05 117.38,53.48 RH171.1 RH168.1 ; JDEBUG.6 v1(189.53,22.97)
PLTRST1#_XDP: length 7.3
  TOP w0.102: v2(34.09,52.28) 34.34,52.53 35.51,52.53 RH363.1 35.05,51.61 35.05,50.99 33.66,49.61 JXDP.46
PM_CLKRUN#: length 69.2
  TOP w0.076: v6(138.87,59.27) 138.95,59.35 139.67,59.35 U34.M6
  TOP w0.102: U652.15 139.71,66.22 139.36,65.87 139.36,65.04 139.08,64.76 v2(138.67,64.76) 138.6,64.76 137.19,66.17 v1(137.12,66.17)
  GND1 w0.076: v6(138.87,59.27) 138.87,59.38 v4(138.49,59.76)
  IN3 w0.076: v4(131.62,70.17) 130.97,69.52 130.97,67.98 132.96,65.99 135.2,65.99 135.47,65.72 136.68,65.72 v1(137.12,66.17)
  IN4 w0.076: v1(137.12,66.17) 137.57,66.17 139.12,64.62 139.12,63.63 139.44,63.31 139.44,62.29 139.1,61.95 138.87,61.95 138.02,61.1 138.02,60.21 138.48,59.76 v4(138.49,59.76) ; v4(131.62,70.17) 130.96,69.51 129.1,69.51 126.11,72.5 121.22,72.5 120.09,71.36 114.8,71.36 114.29,70.85 109.44,70.85 108.99,70.4 107.16,70.4 v4(106.98,70.57) 106.75,70.8 105.04,70.8 104.63,70.4 104.03,70.4 103.58,70.85 100.09,70.85 99.73,70.48 98.98,70.48 98.58,70.08 98.03,70.08 97.75,69.8 97.1,69.8 96.87,69.57 95.2,69.57 94.88,69.25 94.18,69.25 93.8,69.63 v4(93.72,69.63)
  GND5 w0.076: v5(106.45,70.27) 106.67,70.27 v4(106.98,70.57) ; v5(93.68,69.23) 93.68,69.6 v4(93.72,69.63)
  BOTTOM w0.102: RH248.2 106.79,70.61 v5(106.45,70.27) ; UCPU1.V5 93.99,69.53 v5(93.68,69.23)
PM_SLP_A#: length 95.9
  TOP w0.102: v1(20.06,52.31) 20.45,52.7 JAPS.13 ; v6(91.12,54.71) 90.1,53.7 90.1,50.69 89.59,50.18 89.45,50.18 87.55,48.27 84.58,48.27 v7(83.85,47.54) 82.24,45.94 76.81,45.94 76.04,45.17 69.34,45.17 68.83,45.68 38.06,45.68 v6(38.01,45.73)
  GND1 w0.076: v6(38.01,45.73) v4(38.01,45.35) ; v4(91.37,55) 91.37,54.97 v6(91.12,54.71)
  IN1 w0.076: v4(93.09,63.14) 93.09,62.99 92.64,62.54 91.37,62.54 90.9,62.06 90.9,58.87 91.61,58.16 91.61,55.25 v4(91.37,55) ; v1(20.06,52.31) 20.44,52.31 20.97,51.78 20.97,47.79 22.07,46.7 25.09,46.7 25.37,46.42 33.61,46.42 34.09,46.9 36.39,46.9 37.79,45.5 37.88,45.5 38.03,45.35 v4(38.01,45.35)
  GND5 w0.076: v5(93.18,62.75) 93.18,63.06 v4(93.09,63.14)
  BOTTOM w0.102: v5(93.18,62.75) 93.18,62.77 93.49,63.08 UCPU1.AL5
PM_SLP_S0#: length 287.8
  TOP w0.102: v1(21.95,47.97) 21.72,48.2 JAPS.4 ; v6(90.53,54.7) 90.39,54.7 89.9,54.21 89.9,50.81 89.5,50.42 89.41,50.42 87.85,48.86 v7(87.07,48.86) 84.62,48.86 81.9,46.14 76.72,46.14 75.96,45.38 69.43,45.38 68.92,45.89 39.33,45.89 v6(38.59,46.62)
  GND1 w0.076: v4(37.98,46.6) 38.01,46.62 v6(38.59,46.62) ; v4(90.8,54.94) 90.56,54.7 v6(90.53,54.7)
  IN1 w0.076: v4(90.8,54.94) 90.8,58.02 90.45,58.37 90.45,62.52 90.8,62.86 90.8,63.97 91.6,64.77 v4(91.99,64.77) ; v4(37.98,46.6) 37.23,46.6 36.57,47.26 33.94,47.26 33.46,46.77 25.72,46.77 25.45,47.05 22.22,47.05 21.94,47.33 21.94,47.97 v1(21.95,47.97)
  IN2 w0.076: v4(179.83,37.53) 180.06,37.53 180.97,36.61 203.26,36.61 v1(206,33.87)
  IN3 w0.076: v4(179.83,37.53) 178.16,39.19 178.16,39.84 177.55,40.45 175.27,40.45 175.06,40.25 175.06,37.72 174.56,37.22 174.56,34.84 173.93,34.21 170.24,34.21 169.72,33.69 169.72,32.68 169.5,32.46 168.41,32.46 162.79,26.85 157.07,26.85 156.85,26.63 155.42,26.63 155.2,26.85 150.5,26.85 148.87,28.49 142.55,28.49 138.88,32.16 134,32.16 132.75,33.41 128.88,33.41 122.49,39.81 122.49,48.08 122.32,48.25 122.32,52.3 122.09,52.53 122.09,59.55 123.26,60.72 123.26,61.35 122.24,62.37 120.57,62.37 v4(119.59,63.35) ; v4(139.1,62.69) 139.22,62.81 139.22,64.95 137.4,66.77 136.23,66.77 134.75,68.25 134.75,69.47 v4(134.82,69.53)
  IN4 w0.076: v4(139.1,62.69) 139.1,62.51 138.08,61.49 136.21,61.49 135.48,62.23 133.65,62.23 132.58,63.31 130.96,63.31 130.78,63.13 124.69,63.13 124,62.45 120.49,62.45 v4(119.59,63.35) 119.25,63 115.16,63 114.25,63.92 113.15,63.92 112.69,63.46 108.88,63.46 108.1,64.25 107.44,64.25 106.97,64.73 106.48,64.73 106.22,64.47 100.79,64.47 100.26,63.93 100.26,62.94 100.02,62.7 98.27,62.7 98.11,62.55 97.39,62.55 96.8,63.13 94.47,63.13 94.28,62.94 94.28,62.85 94.08,62.65 93.76,62.65 93.66,62.75 92.99,62.75 92.39,63.35 92.18,63.35 91.99,63.54 v4(91.99,64.77)
  GND5 w0.076: v5(135.1,70.19) 134.82,69.91 v4(134.82,69.53) ; v4(119.59,63.35) 119.81,63.56 v5(120.05,63.56)
  BOTTOM w0.102: PR509.2 133.36,72.97 135.1,71.23 v5(135.1,70.19) ; v5(120.05,63.56) RH463.2
  BOTTOM w0.254: v1(206,33.87) PQ300.2
PM_SLP_S3#: length 384.1
  TOP w0.102: v6(38.31,47.61) 39.15,46.77 39.35,46.77 39.73,46.39 41.21,46.39 42.02,47.21 43.84,47.21 44.55,46.49 69.25,46.49 69.76,45.99 75.71,45.99 76.47,46.75 81.02,46.75 83.92,49.64 87.71,49.64 89.03,50.97 89.03,51.3 89.19,51.45 v2(89.19,52.49) 89.19,53.91 v6(89.44,54.17) ; JAPS.17 21.72,54.7 22.21,54.22 v6(22.21,53.25) ; v3(119.17,73.05) 119.17,71.29 118.61,70.73 118.61,69.09 v6(119.16,68.54) 119.36,68.34 119.36,67.13 118.87,66.64 R1191.2 118.29,66.33 118.89,66.33 119.65,67.09 120.2,67.09 121.84,65.46 124.89,65.46 125.2,65.77 126.45,65.77 128.23,64 U710.2 130.97,64 132.61,65.63 133.33,65.63 133.84,65.13 133.84,63.08 134.17,62.75 134.84,62.75 135.74,61.85 135.74,60.54 R249.1 ; R1247.1 167.62,43.65 168.84,43.65 169.11,43.92 170.14,43.92 170.56,43.5 173.27,43.5 174.23,44.45 176.65,44.45 177.4,45.2 177.4,48.53 180.19,51.32 180.19,57.98 v1(179.78,58.39)
  GND1 w0.076: v4(118.74,68.67) 118.87,68.54 v6(119.16,68.54) ; v4(37.94,47.89) 38.22,47.61 v6(38.31,47.61) ; v6(89.44,54.17) 89.44,54.48 v4(89.53,54.57) ; v6(22.21,53.25) 22.36,53.25 v4(22.59,53.02)
  IN1 w0.076: v4(37.94,47.89) 37.83,48 37.83,48.53 37.61,48.76 34.43,48.76 33.16,47.49 31.11,47.49 29.92,48.68 25.75,48.68 24.73,49.7 23.69,49.7 22.75,50.63 22.75,52.86 v4(22.59,53.02) ; v3(119.17,73.05) 120.28,74.16 127.28,74.16 129.57,71.87 132.89,71.87 134.23,73.22 v4(137.87,73.22) 145.75,73.22 145.89,73.35 145.97,73.43 145.97,73.43 146.16,73.62 147.21,73.62 147.32,73.51 148.43,73.51 148.86,73.94 153.14,73.94 154.07,74.88 165.95,74.88 169.11,71.72 169.11,69.9 170.97,68.03 173.48,68.03 176.33,65.18 176.33,60.72 177.21,59.84 178.33,59.84 v1(179.78,58.39) ; v4(89.53,54.57) 90.22,53.89 94.84,53.89 95.85,54.9 95.85,59.17 v4(95,60.03)
  IN2 w0.076: v4(89.53,54.57) 89.53,47.36 92.97,43.91 102.21,43.91 102.99,44.69 107.48,44.69 111.5,40.68 111.5,33.49 112.16,32.83 v1(112.16,32.8) ; v1(179.78,58.39) 180.84,58.39 183.24,60.79 189.43,60.79 190.67,62.04 194.96,62.04 v1(195.42,61.58) 196.36,61.58 197.71,62.93 202.51,62.93 205.58,66 v1(207.94,66) ; v4(118.74,68.67) 118.04,67.97 110.99,67.97 v4(110,68.96)
  IN3 w0.076: v4(95,60.03) 96.11,60.03 97.43,58.71 97.43,57.57 97.09,57.23 97.09,55.27 97.7,54.66 98.72,54.66 99.12,55.05 99.12,56.13 101.23,58.24 101.23,59.31 101.58,59.66 101.58,60.05 105.16,63.63 105.16,64.77 v1(105.81,65.42) ; v3(133.85,26.63) 130.95,26.63 126.65,30.93 126.65,33.55 124.33,35.88 119.64,35.88 115.85,32.09 113.1,32.09 112.39,32.8 v1(112.16,32.8)
  GND5 w0.076: v4(110,68.96) 110,68.48 v5(110.03,68.45) ; v4(95,60.03) 95,59.63 v5(94.99,59.62) ; v5(138.32,73.47) 138.12,73.47 v4(137.87,73.22)
  BOTTOM w0.102: UCPU1.AT4 94.76,59.86 v5(94.99,59.62) ; R1146.1 132.38,23.29 133.85,24.76 v3(133.85,26.63) ; v5(138.32,73.47) 138.35,73.49 PR503.1 ; v1(207.94,66) 207.84,65.9 207.56,65.9 207.4,66.06 PU402.13 ; v3(119.17,73.05) 119.17,75.34 116.61,77.9 PU401.13 ; v1(105.81,65.42) 106.45,66.05 106.45,66.58 106.84,66.97 107.43,66.97 107.77,67.31 107.77,67.56 107.98,67.78 109.35,67.78 v5(110.03,68.45) 110.23,68.45 110.55,68.14 RH416.1
PM_SLP_S4#: length 224.3
  TOP w0.102: v6(90.78,55.54) 90.78,55.53 89.69,54.44 89.69,50.94 89.44,50.69 89.39,50.69 87.94,49.24 84.48,49.24 v2(82.01,46.77) 81.59,46.34 76.64,46.34 75.88,45.58 69.55,45.58 69.04,46.09 39.61,46.09 v6(39.22,46.47) ; v1(22.04,52.72) 21.56,53.2 JAPS.14 ; v6(137.99,62.6) 138.93,62.6 U34.N1
  GND1 w0.076: v4(39,46.14) 39,46.24 v6(39.22,46.47) ; v4(137.5,62.08) 137.99,62.57 v6(137.99,62.6) ; v6(90.78,55.54) 90.85,55.61 v4(91.26,55.61)
  IN1 w0.076: v4(91.26,55.61) 91.18,55.69 91.18,58.08 90.7,58.56 90.7,62.38 91.68,63.36 92.57,63.36 93.01,63.8 v4(93.01,63.89) ; v4(39,46.14) 38.85,45.99 37.59,45.99 36.49,47.08 34.02,47.08 33.53,46.6 25.45,46.6 25.17,46.88 22.14,46.88 21.15,47.87 21.15,51.83 v1(22.04,52.72)
  IN2 w0.076: v4(137.5,62.08) 137.46,62.04 134.25,62.04 132.51,60.3 131.13,60.3 130.79,59.97 130.79,59.86 128.28,57.34 116.03,57.34 v4(115.53,57.85) 115.53,58.41 114.81,59.12 108.72,59.12 106.31,61.54 105.68,61.54 105.61,61.61 102.45,61.61 100.77,59.93 98.93,59.93 97.68,61.18 97.32,61.18 95.36,63.14 94.46,63.14 94.28,62.97 94.28,62.84 94.09,62.65 93.81,62.65 93.49,62.96 93.49,63.41 v4(93.01,63.89)
  IN4 w0.076: v1(22.04,52.72) 21.23,51.9 21.23,50.71 17.27,46.75 17.27,42.91 16.07,41.72 16.07,30.22 18.21,28.08 18.21,25.59 16.48,23.86 16.48,23.08 16.99,22.57 20.87,22.57 21.89,21.55 27.94,21.55 29.88,19.61 36.67,19.61 37.42,18.86 41.52,18.86 v4(41.93,19.27)
  GND5 w0.076: v5(41.87,19.72) 41.87,19.33 v4(41.93,19.27) ; v4(115.53,57.85) 115.6,57.92 v5(116.05,57.92) ; v4(93.01,63.89) 93.19,64.07 v5(93.19,64.3)
  BOTTOM w0.102: v5(41.87,19.72) 41.89,19.75 41.89,19.74 PR613.1 ; RH415.1 114.32,68.43 114.32,63.49 115.84,61.97 115.84,60.24 116.69,59.39 116.69,58.57 v5(116.05,57.92) ; v5(93.19,64.3) 93.34,64.15 UCPU1.AJ6
PM_SLP_S5#: length 147.7
  TOP w0.102: v6(93.3,60.77) 92.54,60.01 92.54,57.29 v2(91.84,56.59) RH426.1 91.84,54.99 90.3,53.45 90.3,50.58 89.69,49.97 89.54,49.97 87.63,48.07 84.93,48.07 82.6,45.73 76.89,45.73 76.13,44.97 69.2,44.97 68.69,45.48 39.25,45.48 v6(39.07,45.3) ; v1(19.39,52.31) 19.39,52.41 20.68,53.7 JAPS.15 ; D114.1 135.16,56.3 135.52,56.65 v1(135.68,56.65) 136,56.65 R250.1
  GND1 w0.076: v4(38.59,45.28) 39.05,45.28 v6(39.07,45.3) ; v4(93.32,61.35) 93.39,61.28 93.39,60.86 v6(93.3,60.77)
  IN1 w0.076: v4(93.32,61.35) 93.32,61.82 94.29,62.78 94.29,62.97 94.51,63.19 95.73,63.19 96.26,63.72 96.88,63.72 97.02,63.86 97.39,63.86 97.53,63.72 97.87,63.72 98.51,63.08 99.28,63.08 99.71,63.51 107.03,63.51 109.22,61.33 116.68,61.33 117.3,61.95 117.9,61.95 118.26,62.31 119.27,62.31 119.78,61.8 123.29,61.8 123.67,61.42 128.47,61.42 129.35,62.29 133.32,62.29 134.13,61.48 v4(134.13,61.11) ; v4(38.59,45.28) 38.23,44.92 37.66,44.92 35.86,46.72 34.16,46.72 33.68,46.24 25.29,46.24 25.01,46.52 21.99,46.52 20.8,47.71 20.8,51.65 20.57,51.88 19.82,51.88 v1(19.39,52.31)
  IN3 w0.076: v4(134.13,61.11) 134.13,60.31 134.73,59.72 134.73,57.61 v1(135.68,56.65)
  GND5 w0.076: v4(93.32,61.35) 93.85,61.35 v5(93.94,61.43)
  BOTTOM w0.102: v5(93.94,61.43) 93.94,61.34 UCPU1.AP5
PM_SLP_SUS: length 5.1
  TOP w0.102: v2(126.26,53.96) U713.4 124.19,53.96 123.78,53.56 122.4,53.56 122.11,53.85 Q5.2
PM_SLP_SUS#: length 203.2
  TOP w0.102: v1(126.8,58.86) 126.79,58.86 126.6,59.05 126.6,59.91 R1183.1 R1249.1 127.65,61.95 127.65,63.6 v1(127.49,63.77) ; R1284.2 174.58,45.47 174.58,46.35 v1(174.09,46.85) ; v1(202.6,23.2) 202.89,22.91 PD307.3 ; PU307.1 v1(211.41,49.71) ; v1(127.6,54.55) 127.54,54.61 U713.2
  IN1 w0.076: v1(114.98,49.15) 114.98,49.17 114.84,49.31 114.84,52.1 116.38,53.63 124.61,53.63 125.57,54.6 127.55,54.6 v1(127.6,54.55)
  IN2 w0.076: v1(211.41,49.71) 211.05,49.71 209.29,47.94 209.29,43.95 v4(208.58,43.24)
  IN4 w0.076: v4(208.58,43.24) 206.56,41.22 206.56,26.67 203.09,23.2 v1(202.6,23.2) 199.77,23.2 194.25,28.71 194.25,32.55 192.12,34.68 185.8,34.68 185.16,34.05 184.18,34.05 179.56,38.66 179.56,40.37 178.61,41.32 178.61,43.62 178.15,44.07 178.15,45.3 176.6,46.85 v1(174.09,46.85) 174.09,46.93 173.58,47.43 170.94,47.43 170.14,48.23 149.59,48.23 148.81,47.46 147.48,47.46 147.29,47.65 141.34,47.65 139.85,46.16 133.61,46.16 132.4,47.37 132.4,51.59 129.57,54.42 127.71,54.42 127.6,54.52 v1(127.6,54.55)
  BOTTOM w0.102: PR501.1 134.92,73.95 134.92,72.28 135.4,71.79 135.4,69.99 135.05,69.63 132.99,69.63 127.49,64.13 v1(127.49,63.77) ; RH313.1 97.89,49.45 99.05,48.3 105.73,48.3 107.46,50.03 v7(108.74,50.03) 114.71,50.03 114.98,49.76 v1(114.98,49.15) ; v1(127.6,54.55) 127.6,58.06 v1(126.8,58.86)
PM_SLP_SUS#_R: length 7.5
  TOP w0.102: U719.3 126.28,57.22 127.05,56.45 127.83,56.45 128.07,56.69 128.07,58.29 v2(128.29,58.51) 128.29,59.36 C1300.1 R1183.2
PM_SYS_RESET#: length 110.9
  TOP w0.102: JAPS.6 21.76,49.2 v1(22.08,49.52) ; v6(37.55,48.88) 37.92,49.25 37.92,50.62 37.35,51.19 36.87,51.19 RH451.2 37.01,51.77 40.53,51.77 41.28,51.02 54.79,51.02 v2(55.65,50.16) 58.1,47.71 68.37,47.71 68.63,47.97 79.34,47.97 82.8,51.42 86.93,51.42 87.48,51.98 87.48,53.1 86.54,54.04 85.59,54.04 85.38,54.25 85.38,56.2 v6(85.4,56.22)
  GND1 w0.076: 85.36,56.49 85.36,56.26 v6(85.4,56.22) ; v4(37.43,48.35) 37.43,48.77 v6(37.55,48.88)
  GND1 w0.102: 85.36,56.49 v4(85.36,56.63)
  IN1 w0.076: v4(37.43,48.35) 37,47.92 33.84,47.92 33.24,47.31 30.98,47.31 29.79,48.5 25.65,48.5 24.63,49.52 v1(22.08,49.52) ; v4(85.36,56.63) 85.36,56.49 85.34,56.51 85.34,57.67 86.13,58.45 86.13,59.88 86.81,60.57 86.81,63.92 86.82,63.93 86.82,64.81 87.41,65.39 90.28,65.39 90.65,65.76 94.58,65.76 95.35,65 96.01,65 96.36,65.35 96.36,66 96.53,66.17 97.26,66.17 98.03,66.94 99.39,66.94 99.73,67.28 v1(102.08,67.28)
  BOTTOM w0.102: RH450.2 103.3,67.74 102.53,67.74 v1(102.08,67.28)
PP: length 2.8
  TOP w0.102: U652.7 133.99,70.77 133.79,70.57 132.7,70.57 R975.1
PRESSURE_INT1#: length 67.4
  TOP w0.076: U636.H7 161.73,65.32 161.86,65.44 v6(161.86,65.57)
  TOP w0.102: v1(152.5,84.09) 152.65,83.93 v2(152.65,83.29) 152.65,82.7 152.54,82.6 U653.9
  GND1 w0.076: v4(161.65,65.14) 161.65,65.38 161.84,65.57 v6(161.86,65.57)
  IN1 w0.076: v4(161.65,65.14) 160.98,65.14 160.5,64.66 160.12,64.66 159.31,65.46 155.36,65.46 154.76,66.07 152.68,66.07 152,65.39 149.61,65.39 148.8,64.58 147.32,64.58 145.9,66 144.44,66 143.96,66.48 142.78,66.48 141.83,65.53 v4(141.83,65.14)
  IN3 w0.076: v4(141.83,65.14) 141.75,65.21 139.71,65.21 137.62,67.31 136.52,67.31 135.57,68.26 135.57,69.48 138.21,72.12 146.93,72.12 147.23,72.42 147.23,72.85 144.51,75.56 144.51,81.94 145.94,83.38 149.72,83.38 150.89,84.54 152.04,84.54 v1(152.5,84.09)
PRESSURE_INT2#: length 64.6
  TOP w0.102: v1(151.76,84.09) 151.24,83.57 v2(151.24,83.52) 151.24,83.17 151.54,82.87 U653.11 ; U636.G4 v6(161.27,64.04)
  GND1 w0.076: v6(161.27,64.04) 161.27,64.2 v4(160.99,64.48)
  IN1 w0.076: v4(142.41,65.14) 142.41,65.72 143,66.31 143.89,66.31 144.37,65.82 145.83,65.82 147.24,64.41 148.87,64.41 149.68,65.21 152.29,65.21 152.53,64.98 154.9,64.98 155.2,65.28 158.1,65.28 159.25,64.12 159.72,64.12 160.01,64.41 160.93,64.41 v4(160.99,64.48)
  IN3 w0.076: v4(142.41,65.14) 142.41,65.24 142.11,65.54 139.63,65.54 137.69,67.49 136.97,67.49 136.71,67.74 136.71,68.38 136.98,68.64 136.98,69.18 136.54,69.61 136.54,70.19 138.3,71.95 147,71.95 147.43,72.37 147.43,73 144.69,75.74 144.69,81.87 146.02,83.2 149.8,83.2 150.74,84.14 151.71,84.14 v1(151.76,84.09)
PROC_OPI_COMP: length 3.4
  TOP w0.076: v2(89.59,55.13) 89.52,55.21 RC154.1
  TOP w0.305: RC154.1 88.58,55.87 v1(88.67,55.96)
  BOTTOM w0.076: UCPU1.AY15 88,57.19 88.09,57.11 88.09,56.46 88.59,55.96 v1(88.67,55.96)
PS_ID: length 89.2
  TOP w0.102: PR103.2 192.58,78.07 193.43,78.92 194.61,78.92 PR102.1 196.12,77.41 198.44,77.41 199.28,76.57 199.28,74.56 199.45,74.4 199.45,71.82 198.47,70.84 195.83,70.84 195.1,70.12 195.1,68.19 190,63.08 v2(189.14,63.08) 182.85,63.08 v1(182.75,63.18) ; v6(140.56,59.44) 140.73,59.6 U34.K6
  GND1 w0.076: v4(140.96,59.6) 140.8,59.44 v6(140.56,59.44)
  IN4 w0.076: v4(140.96,59.6) 141,59.56 142.33,59.56 142.49,59.73 143.26,59.73 144.91,61.38 144.91,62.45 145.14,62.67 146.04,62.67 146.79,63.42 147.81,63.42 148.19,63.04 150.35,63.04 150.96,62.43 153.6,62.43 154.16,61.86 157.06,61.86 157.45,62.26 161.91,62.26 162.58,61.58 165.11,61.58 165.89,62.37 166.85,62.37 173.71,69.23 173.71,69.74 173.88,69.91 174.45,69.91 176.3,68.07 177.92,68.07 178.39,68.54 179.12,68.54 179.5,68.16 180.51,68.16 181.55,67.12 181.55,64.38 v1(182.75,63.18)
PSID: length 4.1
  TOP w0.254: PL102.2 191.2,84 v2(190.7,83.5) 190.29,83.1 v1(190.29,83.08)
  BOTTOM w0.254: JDCIN1.1 190.38,83.17 v1(190.29,83.08)
PSID-1: length 4
  TOP w0.102: v2(190.63,79.01) 190.05,78.42 PR106.2
  TOP w0.254: PR106.2 PR105.1 188.81,77.79 189.14,77.46 PQ102.2
PSID-2: length 11.7
  TOP w0.254: PR107.1 191.92,76.54 PR104.1 191.45,75.96 191.4,76.01 PQ102.1 190.74,75.27 v1(190.52,75.06) ; PQ101.2 184.91,74.49 186.52,76.1 187.54,76.1 v8(188.21,75.43)
  IN2 w0.254: v8(188.21,75.43) 188.97,76.19 190.16,76.19 190.52,75.83 v1(190.52,75.06)
PSID-3: length 8.4
  TOP w0.102: v2(192.15,79.24) 191.36,78.45 191.36,78.1 PR103.1
  TOP w0.254: v1(187.54,74.5) 187.52,74.49 PQ101.3 ; PR103.1 190.37,78.07 v1(190.34,78.04)
  IN2 w0.254: v1(187.54,74.5) 187.54,75.58 190,78.04 v1(190.34,78.04)
PWM1: length 20.5
  TOP w0.203: PU701.6 25.44,79.12 v1(25.28,78.96)
  IN3 w0.254: v1(25.28,78.96) 24.59,78.27 24.4,78.27 24.07,77.94 24.07,77.23 25.56,75.74 31.12,75.74 32.13,74.74 37.95,74.74 38.31,74.38 v8(38.51,74.38)
  BOTTOM w0.203: PU702.8 38.06,75.02 38.13,75.1 38.44,75.1 38.51,75.02 v8(38.51,74.38)
PWM2: length 15.3
  TOP w0.203: v8(24.58,79.01) 25.09,79.51 26.28,79.51 PU701.5
  IN3 w0.254: v4(28.93,74.69) 28.65,74.97 23.34,74.97 22.73,75.58 22.73,76.42 23.16,76.85 23.16,79.16 23.62,79.62 24.38,79.62 24.58,79.41 v8(24.58,79.01)
  GND5 w0.254: v4(28.93,74.69) 28.99,74.69 29.27,74.41 v5(29.27,74.37)
  BOTTOM w0.203: v5(29.27,74.37) 29.04,74.6 28.9,74.6 PU703.8
PWR_SRC_ON: length 8.7
  TOP w0.102: v2(165.86,84.36) R535.2 ; R535.2 C613.2 R536.1 ; R535.2 164.9,83.25 165.87,82.28 165.87,80.34 165.4,79.87 Q70.3
REGN: length 13.5
  TOP w0.102: PD202.2 153.14,38.59 v2(153.14,37.73)
  TOP w0.254: v6(148.66,48.27) 148.36,47.97 148.36,47.77 PR223.1
  GND1 w0.254: v4(148.24,48.4) 148.37,48.27 v6(148.66,48.27)
  IN3 w0.254: v4(148.24,48.4) 148.24,48.44 148.76,47.92 151.12,47.92 153.39,45.66 153.39,42.86 152.52,42 v1(151.66,42)
RESET#: length 70.9
  TOP w0.076: U636.C7 158.8,65.57 158.8,66
  TOP w0.102: R1141.1 R1090.1 152.39,67.23 v6(151.87,66.71) 151.87,66.42 152.04,66.26 R1003.1 152.39,65.77 152.33,65.71 C1152.1 ; 158.8,66 158.8,66.33 v3(158.97,66.51) ; v2(185.78,78.31) 185.16,78.31 184.28,79.19 JSNRDG.2 184.28,79.97 184.74,80.43 v1(184.74,80.73)
  GND1 w0.076: v6(151.87,66.71) 151.49,67.09 v4(151.43,67.09)
  IN1 w0.076: v3(158.97,66.51) 158.68,66.8 151.72,66.8 v4(151.43,67.09)
  IN3 w0.076: v3(158.97,66.51) 160.65,68.19 165.83,68.19 166.45,68.81 166.45,75.63 170.51,79.69 171.87,79.69 175.36,83.17 177.45,83.17 177.74,82.88 178.88,82.88 179.82,83.83 182.2,83.83 184.31,81.71 184.31,81.16 v1(184.74,80.73)
  BOTTOM w0.102: v3(158.97,66.51) 159.81,65.67 163.06,65.67 163.46,65.28 163.46,60.91 165.94,58.42 JSATA1.20
ROTATION_LOCK_SW#: length 167.8
  TOP w0.076: 139.21,58.86 139.21,58.85 139.67,58.85 U34.M7
  TOP w0.102: v6(133.95,56.93) 135.27,56.93 135.53,57.19 137.07,57.19 137.29,57.42 R1354.1 137.41,57.67 138.54,58.8 139.05,58.8 139.1,58.86 139.21,58.86 ; v6(43.11,46.65) 43.64,46.65 44,46.29 69.15,46.29 69.65,45.78 75.79,45.78 76.55,46.55 81.33,46.55 84.22,49.44 87.79,49.44 89.39,51.04 v6(89.39,51.07)
  GND1 w0.076: v4(133.37,56.5) 133.8,56.93 v6(133.95,56.93) ; v4(89.99,50.66) 89.99,50.67 89.59,51.07 v6(89.39,51.07) ; v4(42.69,46.67) 43.09,46.67 v6(43.11,46.65)
  IN1 w0.076: v8(27.2,24.97) 26.73,24.5 19.41,24.5 18.13,25.78 18.13,27.79 15.56,30.35 15.56,35.87 17.03,37.33 17.03,41.95 18.8,43.73 25.52,43.73 25.9,44.11 33.55,44.11 35.37,42.29 38.44,42.29 40.96,44.81 40.96,46.14 41.96,47.13 42.31,47.13 42.69,46.75 v4(42.69,46.67) ; v4(133.37,56.5) 132.73,57.14 131.13,57.14 130.02,56.02 127.53,56.02 126.68,55.17 124.91,55.17 123.96,54.22 114.75,54.22 111.11,50.57 111.11,48.92 109.39,47.21 100.35,47.21 97.86,49.7 96.69,49.7 95.78,50.61 92.35,50.61 92.12,50.38 90.27,50.38 v4(89.99,50.66)
  BOTTOM w0.102: R957.2 C1125.1 v8(27.2,24.97)
ROTATION_LOCK_SW#_C: length 10.5
  BOTTOM w0.102: JIOL1.31 21.6,20.66 22.12,21.18 22.12,22.1 24.39,24.37 24.89,24.37 25.38,23.88 25.43,23.88 25.79,23.52 25.79,23.47 25.94,23.32 R957.1 26.29,23.35 25.83,23.81 25.83,24.04 25.55,24.32 v2(25.55,25.57)
RUN_ON#: length 45.6
  TOP w0.102: U710.4 128.07,64.65 127.87,64.85 v6(127.87,65.11) ; Q4.2 109.62,67.94 110.59,66.98 v1(110.59,66.64) ; Q34.2 112.31,45.7 111.77,46.24 v2(111.77,46.43) v3(111.77,47.47)
  GND1 w0.076: v6(127.87,65.11) 127.53,65.46 v4(127.53,65.62)
  IN3 w0.076: v3(111.77,47.47) 111.77,47.79 109.1,50.46 109.1,64.29 109.47,64.66 109.47,65.52 v1(110.59,66.64)
  IN4 w0.076: v1(110.59,66.64) 110.8,66.42 118.85,66.42 119.26,66.01 121.09,66.01 121.99,65.11 126.07,65.11 126.73,65.77 127.38,65.77 v4(127.53,65.62)
S3_+1.2V: length 4.4
  TOP w0.203: v6(39.84,18.94) PU601.7
  GND1 w0.203: v4(39.43,19.32) 39.43,19.23 39.72,18.94 v6(39.84,18.94)
  GND5 w0.203: v4(39.43,19.32) 39.43,19.76 v5(39.44,19.77)
  BOTTOM w0.102: PR615.2 37.74,20.1 v2(37.17,19.53)
  BOTTOM w0.203: v5(39.44,19.77) 39.44,19.8 39.14,20.1 PR615.2
S5_+1.2V: length 4.4
  TOP w0.203: PU601.8 40.24,18.95 v6(40.25,18.94)
  GND1 w0.203: v4(40.01,19.37) 40.01,19.28 40.25,19.04 v6(40.25,18.94)
  GND5 w0.203: v4(40.01,19.37) 40.01,19.57 40.37,19.93 v5(40.41,19.93)
  BOTTOM w0.102: v2(40,19.93) v5(40.41,19.93)
  BOTTOM w0.203: PC616.1 41.37,20.65 41.4,20.62 PR613.2 40.63,20.15 v5(40.41,19.93)
SATA_PRX_DTX_N0: length 102.9
  IN1 w0.076: v1(179.41,56.5) 179.15,56.76 178.68,56.76 178.21,57.23 178.21,57.71 177.49,58.43 176.68,58.43 175.1,60.01 175.1,61.53 173.53,63.11 173.53,63.68 170.5,66.7 169.27,66.7 166.9,69.08 166.9,72.1 165.36,73.63 156.08,73.63 155.17,72.73 151.1,72.73 150.77,72.39 149.17,72.39 148.77,72 134.74,72 133.39,70.65 128.96,70.65 126.67,72.94 121.38,72.94 120.26,71.82 109.8,71.82 107.96,73.66 102.77,73.66 100.84,75.59 96.31,75.59 96.1,75.81 94.69,75.81 94.13,75.25 93.92,75.25 v4(93.67,74.99)
  GND5 w0.076: v5(94.28,74.94) 94.28,74.98 94.06,75.2 93.87,75.2 v4(93.67,74.99)
  BOTTOM w0.102: CS53.1 179.05,56.7 179.21,56.7 v1(179.41,56.5) ; v5(94.28,74.94) 94,74.66 UCPU1.J5
SATA_PRX_DTX_N0_C: length 2.3
  BOTTOM w0.102: CS53.2 177.45,56.68 177.05,56.68 176.79,56.42 JSATA1.25
SATA_PRX_DTX_P0: length 102.9
  IN1 w0.076: v4(93.66,75.64) 93.9,75.4 94.06,75.4 94.62,75.96 96.16,75.96 96.37,75.74 100.9,75.74 102.83,73.81 108.02,73.81 109.86,71.97 120.19,71.97 121.32,73.09 126.74,73.09 129.03,70.8 133.33,70.8 134.67,72.15 148.71,72.15 149.11,72.54 150.71,72.54 151.04,72.88 155.1,72.88 156.01,73.79 165.42,73.79 167.05,72.16 167.05,69.14 169.34,66.85 170.57,66.85 173.68,63.74 173.68,63.17 175.25,61.6 175.25,60.07 176.74,58.59 177.55,58.59 178.37,57.77 178.37,57.29 178.75,56.91 179.18,56.91 v8(179.41,57.14)
  GND5 w0.076: v4(93.66,75.64) 93.95,75.35 94.1,75.35 v5(94.28,75.53)
  BOTTOM w0.102: v8(179.41,57.14) 179.18,56.91 179.03,56.91 CS54.1 ; v5(94.28,75.53) 94.04,75.28 UCPU1.H5
SATA_PRX_DTX_P0_C: length 2.3
  BOTTOM w0.102: CS54.2 177.43,56.89 177.09,56.89 176.75,57.22 JSATA1.23
SATA_PTX_DRX_N0: length 116.9
  IN1 w0.076: v8(179.38,53.99) 179.38,53.94 179.61,53.71 179.79,53.71 179.97,53.89 179.97,57.23 178.1,59.09 176.98,59.09 175.72,60.35 175.72,64.57 173.48,66.81 171.33,66.81 170.84,67.31 169.53,67.31 167.61,69.23 167.61,72.25 165.59,74.27 155.61,74.27 154.67,73.33 149.25,73.33 148.67,72.76 147.21,72.76 146.97,73 146.96,73 146.95,73.01 146.41,73.01 146.01,72.61 134.48,72.61 133.14,71.26 129.32,71.26 127.03,73.55 121.13,73.55 120,72.43 111.6,72.43 110.87,73.16 109.95,73.16 108.85,74.27 103.02,74.27 100.61,76.68 95.33,76.68 95.23,76.58 93.89,76.58 93.1,75.79 91.22,75.79 90.8,76.21 90.8,76.7 90.19,77.3 88.76,77.3 88.03,78.04 88.03,78.63 87.89,78.76 v4(87.76,78.76)
  GND5 w0.076: v5(87.68,79.46) 87.79,79.35 87.79,79.26 87.97,79.08 87.97,78.96 87.77,78.76 v4(87.76,78.76)
  BOTTOM w0.102: CS43.1 178.7,53.96 178.92,53.74 179.13,53.74 v8(179.38,53.99) ; UCPU1.B15 87.6,79.21 87.68,79.29 v5(87.68,79.46)
SATA_PTX_DRX_N0_C: length 2.3
  BOTTOM w0.102: CS43.2 177.45,53.73 177,53.73 176.7,54.02 JSATA1.31
SATA_PTX_DRX_P0: length 117
  IN1 w0.076: v1(179.41,53.33) 179.64,53.56 179.85,53.56 180.12,53.82 180.12,57.29 178.16,59.25 177.05,59.25 175.88,60.41 175.88,64.63 173.54,66.97 171.39,66.97 170.9,67.46 169.59,67.46 167.76,69.29 167.76,72.31 165.65,74.42 155.54,74.42 154.61,73.49 149.19,73.49 148.61,72.91 147.27,72.91 147.03,73.15 147.02,73.15 147.01,73.16 146.35,73.16 145.94,72.76 134.42,72.76 133.08,71.41 129.38,71.41 127.09,73.7 121.06,73.7 119.94,72.58 111.67,72.58 110.93,73.32 110.01,73.32 108.91,74.42 103.09,74.42 100.67,76.83 95.27,76.83 95.17,76.73 93.82,76.73 93.03,75.95 91.28,75.95 90.95,76.28 90.95,76.76 90.25,77.46 88.82,77.46 88.18,78.1 88.18,78.6 v4(88.34,78.76)
  GND5 w0.076: v4(88.34,78.76) 88.12,78.99 88.12,79.15 87.94,79.32 87.94,79.38 v5(88.03,79.46)
  BOTTOM w0.102: v1(179.41,53.33) 179.2,53.53 178.95,53.53 178.7,53.28 CS42.1 ; v5(88.03,79.46) 88.03,79.52 87.7,79.85 UCPU1.A15
SATA_PTX_DRX_P0_C: length 2.3
  BOTTOM w0.102: CS42.2 177.44,53.52 176.93,53.52 176.64,53.22 JSATA1.33
SATA_RCOMP: length 11.6
  IN3 w0.254: v4(89.51,78.83) 89.51,80.15 92.25,82.89 v1(92.84,82.89)
  GND5 w0.254: v5(89.51,78.32) v4(89.51,78.83)
  BOTTOM w0.254: UCPU1.C12 v5(89.51,78.32) ; v1(92.84,82.89) 92.46,83.27 v2(92.46,84.43) 93.16,85.13 94.43,85.13 94.81,84.75 RH43.1
SBD_WAKE#: length 5.5
  TOP w0.076: U636.F8 160.55,66.04 160.99,66.48 160.99,66.48 161.02,66.51
  TOP w0.102: T252.1 164.94,67.37 163.08,67.37 162.35,66.65 161.16,66.65 161.02,66.51
SDIO_CLK: length 138.1
  TOP w0.102: v1(184.82,40.42) 184.64,40.25 R1360.2 183.13,40.25 R1395.2
  IN4 w0.076: v4(95.82,77.61) 95.87,77.61 96.25,77.23 96.79,77.23 97.61,78.04 97.61,80.23 98.24,80.86 98.9,80.86 99.91,81.86 106.13,81.86 107.81,80.18 107.81,79.83 111.38,76.26 111.73,76.26 112.28,75.72 118.9,75.72 120.07,74.56 127.15,74.56 128.81,72.9 131.78,72.9 133.01,74.13 134.79,74.13 134.93,74.27 139.77,74.27 141.59,72.45 146.3,72.45 146.69,72.06 148.67,72.06 149.16,72.54 152.5,72.54 152.94,72.1 154.17,72.1 154.53,71.74 155.46,71.74 157.42,73.71 165.89,73.71 166.17,73.99 175.81,73.99 176.23,73.57 179.16,73.57 183.73,69.01 183.73,67.03 185.75,65 185.75,47.58 185.22,47.05 185.22,45.12 185.34,45.01 185.34,42.21 185.27,42.15 185.27,40.88 v1(184.82,40.42)
  GND5 w0.076: v5(95.61,76.97) 95.82,77.18 v4(95.82,77.61)
  BOTTOM w0.076: 95.57,77.04 95.61,77 v5(95.61,76.97)
  BOTTOM w0.102: v1(184.82,40.42) 184.17,40.42 183.24,39.5 JNGFF1.9 ; 95.57,77.04 95.45,77.17 UCPU1.E3
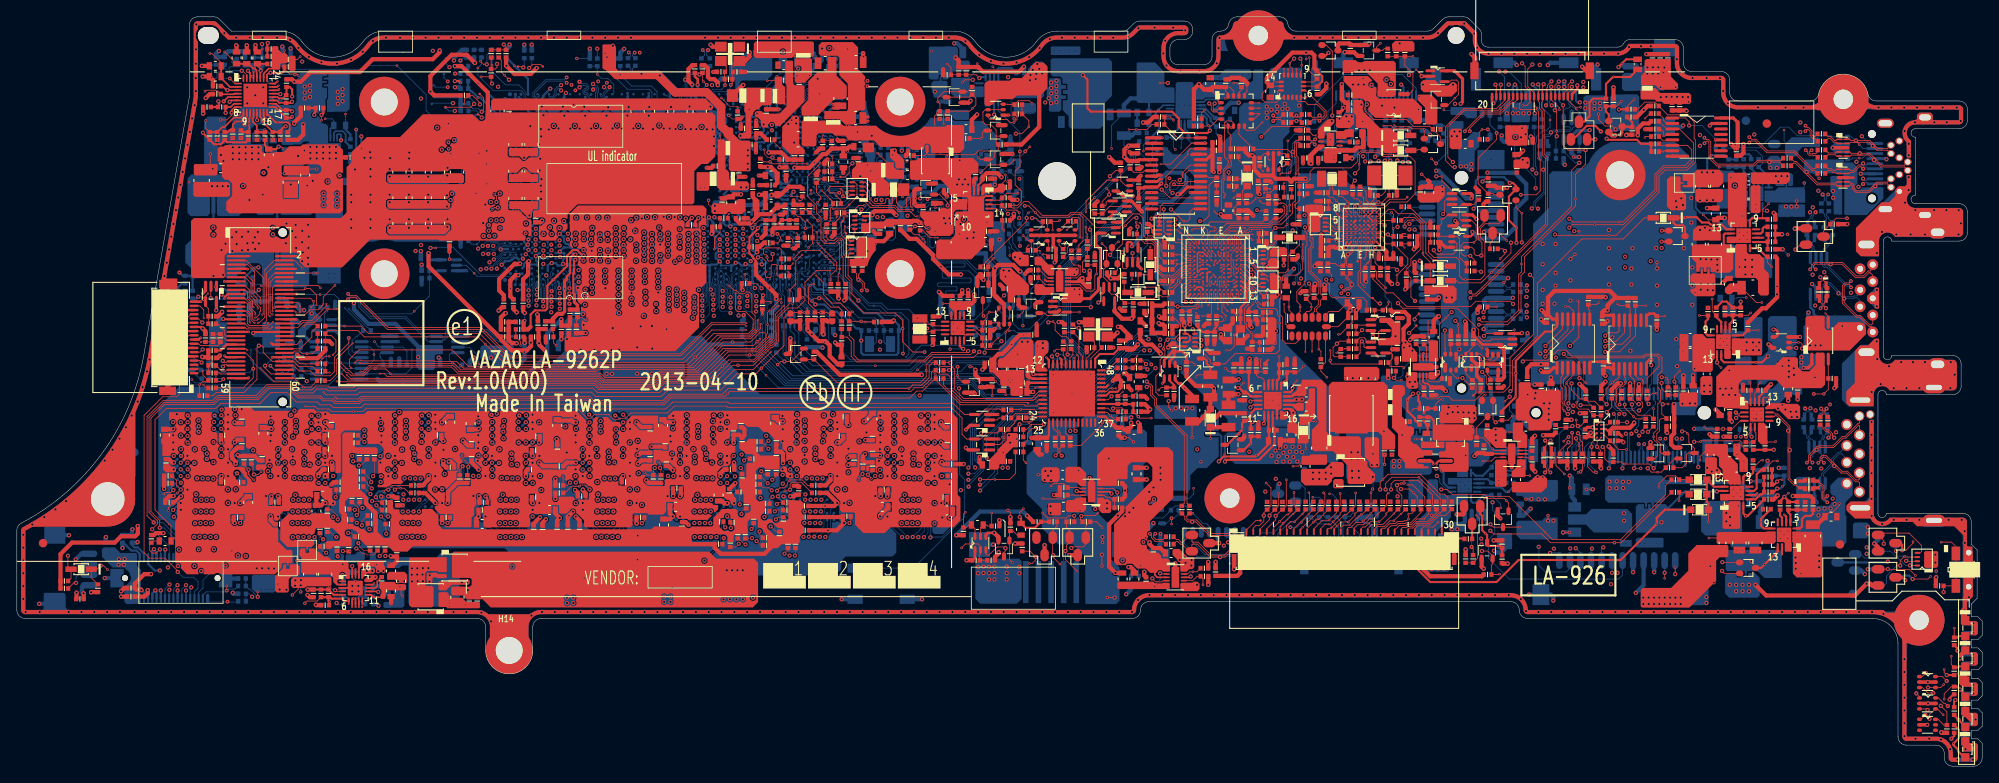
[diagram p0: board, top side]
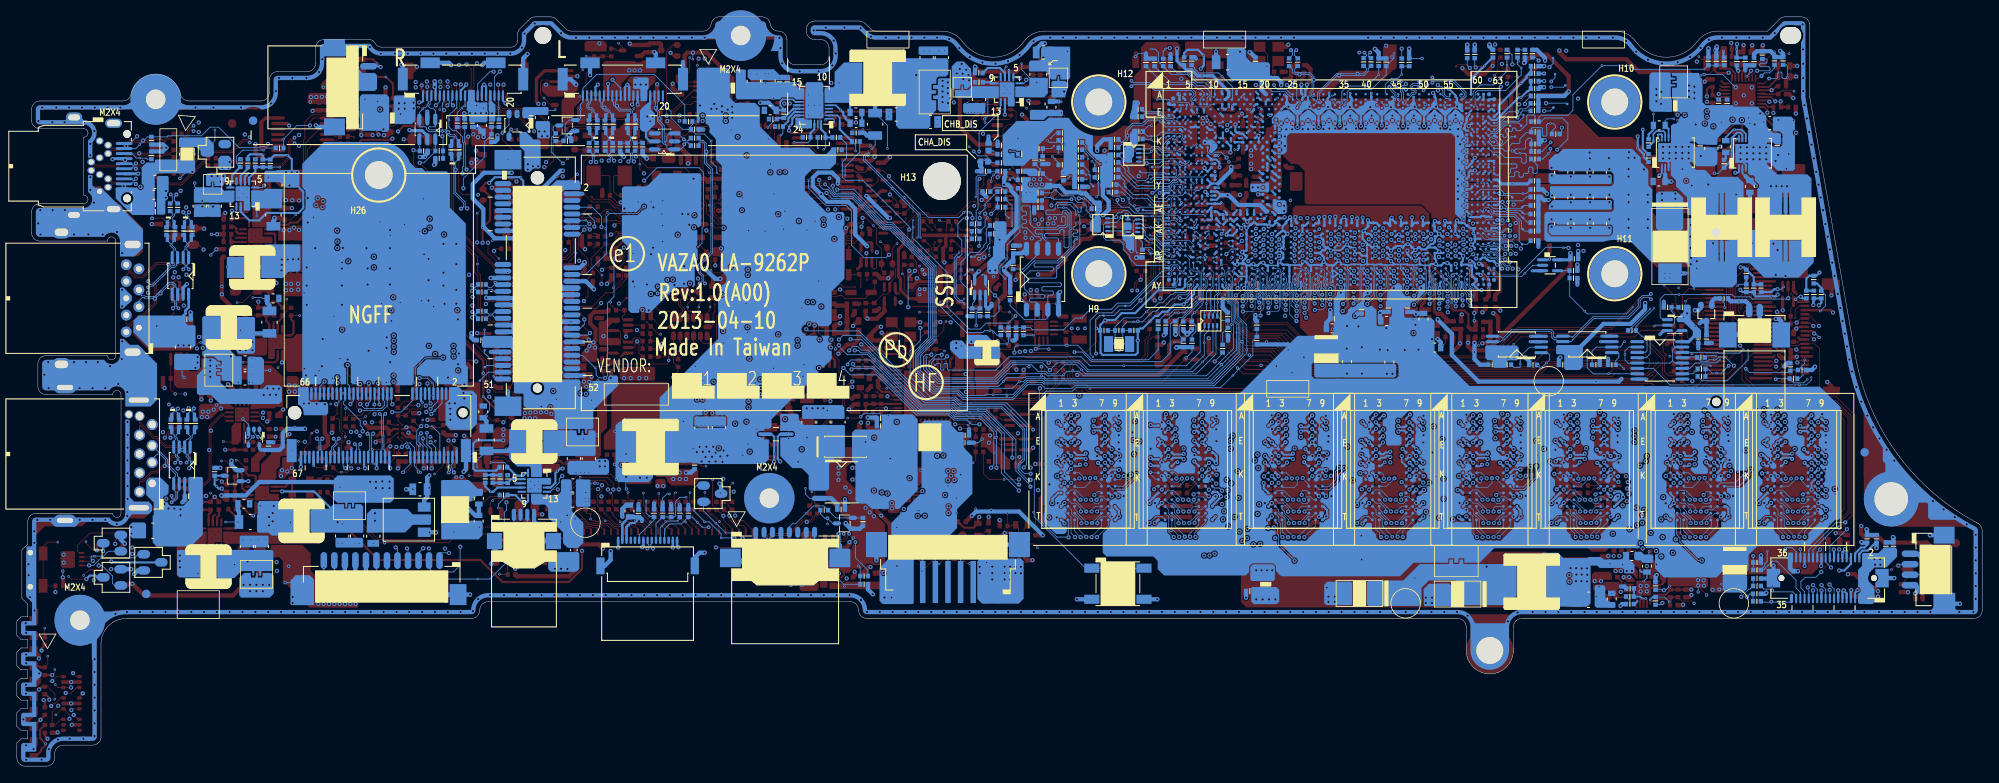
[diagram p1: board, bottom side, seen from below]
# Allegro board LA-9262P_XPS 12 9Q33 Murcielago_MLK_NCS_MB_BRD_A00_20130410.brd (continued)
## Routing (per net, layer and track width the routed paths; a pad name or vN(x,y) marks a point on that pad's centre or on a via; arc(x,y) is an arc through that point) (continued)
SDIO_CMD: length 145.8
  TOP w0.102: v1(184.35,38.49) 183.34,37.49 R1361.2 182.86,36.64 182.86,35.73 v2(183.87,34.72)
  IN4 w0.076: v1(184.35,38.49) 185.49,38.49 186.51,39.51 186.51,40.32 187.03,40.84 187.03,65.52 185,67.55 185,69.53 181.07,73.46 181.07,74.89 180.03,75.93 176.31,75.93 175.78,76.47 166.48,76.47 164.99,74.98 156.73,74.98 155.17,73.42 153.55,73.42 153.16,73.81 148.63,73.81 148.51,73.7 147.42,73.7 147.3,73.81 142.02,73.81 140.3,75.54 134.4,75.54 134.38,75.51 134.35,75.51 134.23,75.4 132.48,75.4 131.95,74.87 128.64,74.87 127.68,75.83 120.69,75.83 119.51,77 113.4,77 107.27,83.13 99.23,83.13 98.22,82.13 97.29,82.13 93.82,78.66 93.82,77.44 v4(94.06,77.2)
  GND5 w0.076: v5(94.32,76.85) 94.32,76.87 94.06,77.13 v4(94.06,77.2)
  BOTTOM w0.102: UCPU1.F4 94.67,76.49 v5(94.32,76.85) ; JNGFF1.11 183.75,37.89 v1(184.35,38.49)
SDIO_D0: length 145
  TOP w0.076: v6(95.75,74.99) RH435.1 RH434.2
  TOP w0.102: v3(184.78,39.61) 184.8,39.59 184.8,38.33 184.22,37.74 R1362.2
  GND1 w0.076: v4(95.59,75.45) 95.59,75.16 v6(95.75,74.99)
  IN4 w0.076: v4(95.59,75.45) 95.59,75.91 95.23,76.26 95.23,77.14 v4(94.69,77.69) 94.69,77.71 95.05,78.08 96.11,78.08 96.39,78.36 96.39,80.19 97.72,81.52 98.48,81.52 99.48,82.52 106.41,82.52 108.48,80.46 108.48,80.1 111.65,76.92 112,76.92 112.55,76.38 119.22,76.38 120.38,75.22 127.43,75.22 128.39,74.26 132.2,74.26 132.73,74.79 134.52,74.79 134.66,74.93 140.04,74.93 141.77,73.2 147.05,73.2 147.17,73.09 148.77,73.09 148.88,73.2 152.9,73.2 153.31,72.8 153.31,72.8 153.33,72.81 153.33,72.81 155.53,72.81 157.09,74.37 165.24,74.37 166.73,75.86 172.88,75.86 174.07,74.66 176.09,74.66 176.52,74.23 179.43,74.23 181.15,72.52 184.39,69.28 184.39,67.3 186.42,65.27 186.42,41.09 185.9,40.57 185.9,40.21 185.68,39.99 185.15,39.99 184.77,39.61 v3(184.78,39.61)
  GND5 w0.076: v5(95.18,78.17) 95.17,78.17 v4(94.69,77.69)
  BOTTOM w0.102: JNGFF1.13 184.24,37.72 184.78,38.25 v3(184.78,39.61) ; UCPU1.D3 95.18,77.96 v5(95.18,78.17)
SDIO_D1: length 141.6
  TOP w0.102: R1363.2 185.62,37.62 v2(185.62,38.1) 185.62,38.4 185.25,38.77 v1(185.25,38.95)
  IN4 w0.076: v1(185.25,38.95) 185.52,38.95 186.3,39.74 186.3,40.4 186.82,40.92 186.82,65.44 184.79,67.47 184.79,69.45 180.87,73.37 180.87,74.81 179.95,75.73 176.23,75.73 175.69,76.26 166.56,76.26 165.08,74.78 156.81,74.78 155.26,73.22 153.46,73.22 153.07,73.61 148.71,73.61 148.6,73.49 147.33,73.49 147.22,73.61 141.94,73.61 140.21,75.34 134.49,75.34 134.42,75.27 134.41,75.27 134.34,75.2 132.57,75.2 132.03,74.66 128.55,74.66 127.59,75.62 120.6,75.62 119.43,76.8 113.32,76.8 107.19,82.93 99.31,82.93 98.31,81.93 97.43,81.93 94.1,78.6 94.1,77.67 v4(94.65,77.13)
  GND5 w0.076: v5(94.95,76.75) 94.68,77.01 94.68,77.09 v4(94.65,77.13)
  BOTTOM w0.102: UCPU1.E4 94.67,77.02 v5(94.95,76.75) ; v1(185.25,38.95) 185.25,38.35 184.75,37.85 JNGFF1.15
SDIO_D2: length 141.7
  TOP w0.102: v7(187.59,34.94) 187.27,34.94 186.62,35.59 186.62,36.51 R1364.2 186.01,38.49 185.72,38.79 185.72,39.32 v1(185.48,39.56)
  IN4 w0.076: v1(185.48,39.56) 185.55,39.56 186.1,40.11 186.1,40.48 186.62,41 186.62,65.35 184.59,67.38 184.59,69.36 180.66,73.3 180.66,74.73 179.86,75.53 176.14,75.53 175.61,76.06 166.65,76.06 165.16,74.57 156.92,74.57 155.36,73.02 153.38,73.02 152.99,73.41 148.8,73.41 148.68,73.29 147.25,73.29 147.14,73.41 141.85,73.41 140.13,75.13 134.57,75.13 134.43,74.99 132.65,74.99 132.12,74.46 128.47,74.46 127.51,75.42 120.52,75.42 119.34,76.59 113.24,76.59 107.1,82.73 99.39,82.73 98.39,81.72 97.64,81.72 95.41,79.5 v4(95.41,78.6)
  GND5 w0.076: v4(95.41,78.6) 95.36,78.55 v5(94.98,78.55)
  BOTTOM w0.102: v1(185.48,39.56) 185.73,39.31 185.73,38.51 185.24,38.03 JNGFF1.17 ; UCPU1.C3 v5(94.98,78.55)
SDIO_D3: length 136.1
  TOP w0.102: R1365.2 185.77,40.42 v1(185.47,40.42) 185.27,40.61 v2(185.27,41.15)
  IN4 w0.076: v4(96.57,77.64) 96.55,77.65 96.55,79.92 97.95,81.32 98.56,81.32 99.56,82.32 106.32,82.32 108.27,80.37 108.27,80.02 111.57,76.72 111.92,76.72 112.46,76.17 119.14,76.17 120.3,75.01 127.34,75.01 129,73.36 131.59,73.36 132.82,74.59 134.6,74.59 134.74,74.73 139.96,74.73 141.69,73 146.97,73 147.11,72.86 148.83,72.86 148.97,73 152.82,73 153.22,72.59 155.66,72.59 157.23,74.17 165.68,74.17 165.96,74.45 176.02,74.45 176.44,74.03 179.35,74.03 181.06,72.31 184.18,69.2 184.18,67.22 186.21,65.18 186.21,41.17 v1(185.47,40.42)
  GND5 w0.076: v4(96.57,77.64) 96.31,77.38 v5(96.2,77.38)
  BOTTOM w0.102: JNGFF1.19 185.75,38.05 185.99,38.29 185.99,39.9 v1(185.47,40.42) ; UCPU1.E2 95.97,77.16 v5(96.2,77.38)
SDIO_RST#: length 5.9
  TOP w0.102: R1328.2 187.12,37.27 187.12,37.93 v1(187.09,37.96) 187.09,38.43 U679.D1
  BOTTOM w0.102: v1(187.09,37.96) 186.99,37.96 186.75,37.72 JNGFF1.23 186.75,35.89 v2(187.73,34.91)
SDIO_RST#_R: length 5.3
  TOP w0.102: v2(185.35,43.26) 185.35,42.65 185.56,42.44 186.68,42.44 186.86,42.25 186.86,42.15 R1313.2 R1314.2 188.22,41.06 U679.A1
SDIO_WAKE#: length 1.2
  TOP w0.102: U679.A2 188.98,40.56 R1199.2
SDIO_WAKE#_Q: length 7.5
  TOP w0.102: R1327.2 188.16,37.54 v1(187.75,37.95) 187.75,38.59 U679.D2
  BOTTOM w0.102: v1(187.75,37.95) 187.29,38.4 186.78,38.4 186.24,37.87 JNGFF1.21 186.24,35.64 v2(185.52,34.91)
SENSOR_ALERT#: length 3.2
  TOP w0.076: U636.H6 161.72,64.82 161.82,64.72 162.11,64.72 162.24,64.85
  TOP w0.102: 162.24,64.85 162.25,64.86 R1158.1 163.56,65.58 v2(163.33,65.81)
SENSOR_DFU_EN#: length 119.9
  TOP w0.076: U636.F2 160.8,62.57 160.8,62.1 160.48,61.79 160.48,61.68
  TOP w0.102: v2(160.13,56.98) 159.62,57.49 159.62,58.64 R1220.1 160.2,59.52 v6(160.51,59.83) 160.69,60.01 160.69,61.11 160.51,61.29 160.51,61.66 160.48,61.68 ; v1(170.83,71.18) 170.53,71.18 169.75,71.96 169.75,75.99 171.93,78.17 175.81,78.17 176.78,79.13 JSNRDG.17
  GND1 w0.076: v6(160.51,59.83) 160.88,59.83 v4(160.95,59.75)
  IN3 w0.076: v4(160.95,59.75) 160.95,63.04 162.01,64.1 162.01,66.1 v4(162.11,66.21)
  IN4 w0.076: v4(94.71,63.82) 96.11,65.21 96.91,65.21 97.23,65.53 97.23,65.98 97.39,66.14 99.48,66.14 100.2,66.87 104.05,66.87 104.4,66.51 105.69,66.51 106.41,67.23 106.93,67.23 107.18,66.98 109.3,66.98 110.12,66.17 113.94,66.17 114.02,66.24 118.77,66.24 119.18,65.84 120.99,65.84 121.94,64.89 127.11,64.89 127.12,64.9 128.58,64.9 129.8,66.12 132.78,66.12 135.4,68.74 135.4,69.53 136.13,70.26 138.42,70.26 138.77,69.91 138.77,69.34 139.97,68.14 143.78,68.14 144.58,67.34 145.37,67.34 145.83,66.88 147.81,66.88 149.34,65.34 151.99,65.34 153.13,66.48 155.19,66.48 155.49,66.19 156.92,66.19 157.25,65.87 159.45,65.87 160.4,66.82 161.58,66.82 162.11,66.29 v4(162.11,66.21) 162.74,65.57 164.71,65.57 164.9,65.76 166.65,65.76 167.64,66.75 169.86,66.75 170.82,67.72 170.82,68.87 170.56,69.14 170.56,70.9 v1(170.83,71.18)
  GND5 w0.076: v5(95.02,63.41) 95.02,63.51 v4(94.71,63.82)
  BOTTOM w0.102: UCPU1.AK4 94.75,63.68 v5(95.02,63.41)
SENSOR_EN: length 133.4
  TOP w0.102: v1(170.47,53.96) v2(169.78,53.28) 169.03,52.53 169.03,48.63 169.29,48.37 169.29,46.35 169.35,46.29 R1250.1 168.97,45.68 167.82,45.68 167.48,46.03 U716.5 ; v1(170.62,71.79) 170.02,72.4 170.02,75.97 172,77.95 176,77.95 177.28,79.23 JSNRDG.16
  IN3 w0.076: v1(170.47,53.96) 170.94,54.43 170.94,56.83 170.38,57.39 170.38,65.33 168.84,66.87 168.84,68.93 170.38,70.47 170.38,71.55 v1(170.62,71.79)
  IN4 w0.076: v1(102.74,67.28) 102.94,67.49 106.36,67.49 106.82,67.94 108.96,67.94 109.53,67.37 112.43,67.37 113.2,66.6 118.94,66.6 119.35,66.19 121.19,66.19 122.05,65.33 125.95,65.33 126.65,66.03 129.36,66.03 129.65,66.32 132.73,66.32 135.21,68.8 135.21,69.59 136.06,70.43 138.49,70.43 138.95,69.98 138.95,69.41 140.04,68.31 143.85,68.31 144.66,67.51 145.44,67.51 145.9,67.06 147.88,67.06 149.09,65.85 150.98,65.85 151.39,66.26 152.65,66.26 153.06,66.66 155.27,66.66 155.56,66.37 157.23,66.37 157.58,66.03 159.36,66.03 160.33,67 161.8,67 163.05,65.75 164.64,65.75 164.83,65.94 166.58,65.94 167.57,66.93 169.78,66.93 170.64,67.79 170.64,68.8 170.38,69.07 170.38,71.55 v1(170.62,71.79)
  BOTTOM w0.076: UCPU1.AG3 95.61,65.47 97,65.47 97.28,65.75 97.37,65.75
  BOTTOM w0.102: v1(102.74,67.28) 102.74,66.92 102.25,66.43 101.37,66.43 100.65,65.72 97.4,65.72 97.37,65.75
SENSOR_HUB_I2C_WAKE: length 88.5
  TOP w0.076: T280.1 94.34,68.1 v6(94.41,68.03)
  GND1 w0.076: v4(94.89,67.84) 94.6,67.84 v6(94.41,68.03) ; v6(162.01,58.31) 162.01,58.65 v4(161.88,58.78)
  IN3 w0.076: v4(161.88,58.78) 162.48,59.37 162.48,63.54 162.94,64 162.94,65.79 v4(163.96,66.81)
  IN4 w0.076: v4(163.96,66.81) 162.83,67.94 158.97,67.94 158.63,67.6 153.15,67.6 152.43,68.33 149.76,68.33 149.11,68.97 146.54,68.97 145.96,69.56 144.82,69.56 144.29,69.02 141.34,69.02 139.22,71.15 135.72,71.15 135.18,70.6 134.46,70.6 132.81,68.95 126.92,68.95 124.76,66.79 122.49,66.79 119.92,69.35 118.94,69.35 117.49,70.8 115,70.8 114.41,70.22 111.45,70.22 111.24,70 109.57,70 109.39,69.82 106.91,69.82 105.89,68.81 102.08,68.81 101.91,68.97 100.03,68.97 98.38,67.32 97.4,67.32 97.15,67.58 95.16,67.58 v4(94.89,67.84)
  GND5 w0.076: v4(94.89,67.84) 95.04,68 v5(95.04,68.49)
  BOTTOM w0.076: v5(95.04,68.49) 95.32,68.77 UCPU1.Y3
SENSOR_HUB_I2C_WAKE_R: length 41.1
  TOP w0.076: U636.G2 161.3,62.57 161.3,62.14 160.94,61.79 160.94,61.68
  TOP w0.102: JSNRDG.13 178.78,78.96 178.52,78.7 178.52,78.17 178.65,78.04 180.51,78.04 180.8,77.75 v2(180.8,72.25) 180.99,72.06 180.99,68.38 180.52,67.91 v3(178.7,67.91) ; 160.94,61.68 160.94,61.45 161.37,61.02 161.37,59.83 161.98,59.22 R1252.2 R1253.1 163.74,59.22 v1(163.98,58.98)
  IN4 w0.076: v3(178.7,67.91) 174.9,64.11 174.17,64.11 173.03,62.96 171.32,62.96 170.78,62.42 170.78,61.76 168,58.97 163.98,58.97 v1(163.98,58.98)
SENSOR_HUB_WAKE#: length 27.3
  TOP w0.076: U636.F1 160.55,62.1 160.28,61.84 160.28,61.68 ; v6(140.48,57.49) 140.37,57.6 U34.M10
  TOP w0.102: v6(147.5,60.64) 147.6,60.74 RP16.2 ; v6(160.08,60.31) 160.29,60.53 v2(160.29,60.95) 160.29,61.57 160.28,61.58 160.28,61.68
  GND1 w0.076: v6(160.08,60.31) 160.08,60.07 v4(159.89,59.88) ; v4(140.32,57.9) 140.48,57.73 v6(140.48,57.49) ; v4(148.08,60.72) 148,60.64 v6(147.5,60.64)
  IN1 w0.076: v4(159.89,59.88) 159.48,60.29 151.05,60.29 150.62,60.72 v4(148.08,60.72)
  IN2 w0.076: v4(140.32,57.9) 140.32,57.89 141.02,57.19 143,57.19 144.19,58.38 144.19,58.88 146.46,61.15 147.64,61.15 v4(148.08,60.72)
SENSOR_I2C_SCL: length 138.4
  TOP w0.076: U636.B5 158.29,64.57 157.86,64.57
  TOP w0.102: U653.4 152.04,79.23 152.3,78.98 153.06,78.98 153.39,78.65 154.46,78.65 155.33,77.78 155.33,77.27 155.18,77.13 154.98,77.13 v1(154.77,77.33) 154.56,77.11 153.91,77.11 R985.2 ; U638.2 142.8,78.19 142.59,77.98 142.23,77.98 142.15,78.06 142.15,78.59 v1(142.31,78.75) ; v6(153.93,62.75) 154.01,62.67 154.01,61.66 153.75,61.4 153.75,58.83 154.12,58.47 154.92,57.66 154.92,56.1 R854.1 155.18,55.64 154.9,55.36 154.9,54.79 154.4,54.29 154.4,54.05 154.69,53.76 U637.2 ; v3(172.69,55.64) 172.93,55.88 173.41,55.88 173.78,56.25 174.22,56.69 174.28,56.75 180.32,62.79 181.87,64.34 181.87,72.32 181.46,72.73 181.46,77.93 181.14,78.25 181.14,78.86 181.28,79 JSNRDG.8 181.28,80.18 181.25,80.22 181.25,80.84 181.38,80.98 181.38,81.01 v1(181.4,81.04) ; 157.86,64.57 v6(157.68,64.74)
  GND1 w0.076: v4(157.18,64.47) 157.18,64.4 157.52,64.74 v6(157.68,64.74) ; v6(153.93,62.75) 153.89,62.75 153.6,63.04 v4(153.6,63.53)
  IN1 w0.076: v4(157.18,64.47) 157.18,64.4 157.17,64.39 156.36,64.39 155.94,63.97 153.99,63.97 153.6,63.58 v4(153.6,63.53)
  IN2 w0.076: v1(154.77,77.33) 154.56,77.11 153.8,77.11 152.95,76.26 149.09,76.26 148.73,76.63 143.57,76.63 142.11,78.09 142.11,78.55 v1(142.31,78.75) 142.12,78.94 142.12,79.1 142.2,79.18 142.84,79.18 143.97,78.05 146.05,78.05 147.2,79.2 152.86,79.2 156.92,83.25 169.97,83.25 173.35,79.87 180.47,79.87 181.15,80.55 181.15,80.81 181.38,81.04 v1(181.4,81.04) ; v4(153.6,63.53) 153.77,63.35 153.77,62.69 154.32,62.14 154.88,62.14 156.72,60.29 161.02,60.29 163.13,58.18 170.75,58.18 171.77,57.15 171.77,56.14 172.05,55.87 172.46,55.87 v3(172.69,55.64)
SENSOR_I2C_SDA: length 138.5
  TOP w0.102: v1(141.68,78.75) 141.92,78.51 141.92,77.97 142.13,77.75 142.62,77.75 142.83,77.54 U638.3 ; U636.C5 v6(158.82,64.1) ; v1(180.75,81.01) 180.92,80.85 180.92,80.32 180.78,80.18 JSNRDG.9 180.78,79 180.92,78.86 180.92,78.16 181.24,77.84 181.24,72.63 181.64,72.22 181.64,64.44 180.55,63.34 178.65,61.45 175,57.79 174.11,56.91 174.06,56.85 173.61,56.41 173.32,56.11 172.92,56.11 v3(172.68,56.35) ; U653.6 153.12,80.31 155.56,77.88 155.56,77.18 155.28,76.9 154.98,76.9 v3(154.77,76.7) 154.58,76.89 153.99,76.89 R986.2 ; U637.3 153.89,53.77 154.17,54.05 154.17,54.39 154.67,54.88 154.67,55.36 154.39,55.64 R855.1 154.69,56.22 154.69,57.57 153.5,58.76 153.5,61.47 153.78,61.75 153.78,62.33 153.63,62.48 153.63,62.93 153.83,63.13 v6(153.93,63.13)
  GND1 w0.076: v4(154.2,63.54) 154.2,63.4 v6(153.93,63.13) ; v4(158.36,63.93) 158.66,63.93 v6(158.82,64.1)
  IN1 w0.076: v4(154.2,63.54) 154.22,63.56 154.22,63.58 154.36,63.72 155.97,63.72 156.44,64.19 156.79,64.19 157.05,63.93 v4(158.36,63.93)
  IN2 w0.076: v1(180.75,81.01) 180.94,80.82 180.94,80.63 180.39,80.08 173.43,80.08 170.06,83.45 156.83,83.45 152.78,79.4 147.11,79.4 145.97,78.26 144.05,78.26 142.92,79.39 142.12,79.39 141.92,79.18 141.92,78.99 v1(141.68,78.75) 141.9,78.52 141.9,78.01 143.49,76.42 148.65,76.42 149.01,76.06 153.04,76.06 153.89,76.91 154.56,76.91 v3(154.77,76.7) ; v3(172.68,56.35) 172.4,56.07 172.13,56.07 171.98,56.22 171.98,57.24 170.83,58.38 163.21,58.38 161.1,60.5 156.81,60.5 154.96,62.34 154.41,62.34 153.98,62.78 153.98,63.32 v4(154.2,63.54)
SENSOR_INT#: length 128.7
  TOP w0.076: RH295.1 96.7,58.33 96.93,58.55
  TOP w0.102: v1(177.77,54.93) 177.45,55.24 173.34,55.24 172.71,54.62 165.13,54.62 163.51,56.25 162.74,56.25 161.09,57.9 R1367.2 ; R1135.2 159.7,68.87 160.31,68.26 160.31,67.25 v6(160.51,67.04) ; 96.93,58.55 97.42,59.04 97.42,59.87 95.08,62.2 v6(95.08,63.49)
  GND1 w0.076: v6(160.51,67.04) 160.7,66.85 v4(160.7,66.28) ; v6(95.08,63.49) v4(95.41,63.82)
  IN2 w0.076: v1(152.99,65.47) 152.76,65.24 149.98,65.24 149.5,65.72 148.13,65.72 147.8,65.39 145.15,65.39 144.73,65.81 144.23,65.81 143.61,65.19 143.34,65.19 142.37,64.22 141.57,64.22 141.31,63.97 140.35,63.97 139.86,63.47 138.44,63.47 138.26,63.3 137.41,63.3 136.9,62.79 136.9,62.45 136.67,62.22 131.24,62.22 130.31,61.29 130.31,60.03 128.7,58.42 126.28,58.42 125.8,57.94 v4(120.97,57.94) 120.85,57.81 116.93,57.81 115.26,59.47 109.14,59.47 106.72,61.89 105.83,61.89 105.75,61.97 101.02,61.97 100.99,61.94 98.7,61.94 98.11,62.52 97.42,62.52 96.13,63.82 v4(95.41,63.82) ; v4(160.7,66.28) 160.7,66.27 161.37,65.6 162.28,65.6 163.52,64.35 163.52,64 164.23,63.28 169.64,63.28 170.31,62.61 170.31,61.79 177.17,54.93 v1(177.77,54.93)
  IN4 w0.076: v1(152.99,65.47) 152.99,65.71 153.41,66.13 155.05,66.13 155.34,65.83 156.69,65.83 156.99,65.53 160,65.53 160.7,66.23 v4(160.7,66.28)
  GND5 w0.076: v5(95.02,64.07) 95.15,64.07 95.41,63.81 v4(95.41,63.82) ; v4(120.97,57.94) 120.97,57.95 121,57.98 121,58.25 v5(120.9,58.36)
  BOTTOM w0.102: v5(95.02,64.07) 94.73,64.35 UCPU1.AH4 ; v5(120.9,58.36) 120.26,58.99 T285.1
SENSOR_RST#: length 75.2
  TOP w0.102: v6(93.89,71.6) 93.87,71.59 89.72,71.59 v7(89.49,71.82) 88.72,71.82 RH452.2 ; v6(152.86,67.6) 153.3,68.03 R1090.2
  GND1 w0.076: v6(152.86,67.6) 152.47,67.6 v4(152.07,67.2) ; v4(93.91,72.2) 93.89,72.18 v6(93.89,71.6)
  IN2 w0.076: v4(93.91,72.2) 93.91,72.34 94.33,72.76 95.27,72.76 95.96,72.07 99.64,72.07 101.49,70.22 104.76,70.22 104.83,70.29 106.15,70.29 106.92,69.53 110.27,69.53 110.61,69.19 110.61,68.91 111.18,68.34 117.32,68.34 118.22,69.24 118.99,69.24 122.02,66.21 124.96,66.21 127.87,69.11 134.72,69.11 135.74,68.09 136.56,68.09 137.04,68.57 138.48,68.57 138.7,68.8 141.99,68.8 142.23,68.55 145.07,68.55 145.43,68.19 145.43,67.57 145.89,67.12 149.17,67.12 149.55,67.5 149.83,67.5 150.36,66.97 150.74,66.97 151.26,67.49 151.77,67.49 v4(152.07,67.2)
  GND5 w0.076: v5(94.23,71.36) 93.91,71.68 v4(93.91,72.2)
  BOTTOM w0.102: UCPU1.R5 93.99,71.6 v5(94.23,71.36)
SENSOR_STANDBY#: length 105.8
  TOP w0.102: D74.2 171.06,57.68 171.3,57.44 173.96,57.44 v2(175.18,58.66) 177.52,61 v1(177.52,62.21)
  IN1 w0.076: v1(177.52,62.21) 177.21,62.52 177.21,65.16 173.81,68.57 171.19,68.57 169.67,70.1 169.67,71.92 166.16,75.43 153.87,75.43 152.92,74.48 148.61,74.48 148.19,74.05 148.18,74.05 148.17,74.04 147.54,74.04 147.43,74.16 145.94,74.16 145.75,73.96 131.48,73.96 131.37,73.86 131.37,73.86 130.83,73.32 129.18,73.32 127.8,74.69 119.97,74.69 119.23,73.95 111.72,73.95 110.79,74.88 103.27,74.88 100.82,77.33 97.4,77.33 96.5,78.23 94.84,78.23 v4(94.53,78.54)
  GND5 w0.076: v5(94.58,78.12) 94.58,78.5 94.53,78.55 v4(94.53,78.54)
  BOTTOM w0.102: v5(94.58,78.12) 94.51,78.2 UCPU1.C4
SERIRQ: length 67.6
  TOP w0.076: U34.M3 139.67,61.35 139.24,61.35
  TOP w0.102: v6(135.9,71.54) 137.07,71.54 139.55,74.02 U652.27 ; 139.24,61.35 139.23,61.35 138.8,61.35 v6(138.56,61.58)
  GND1 w0.076: v4(134.82,71.41) 134.94,71.54 v6(135.9,71.54) ; v4(138.11,62.09) 138.56,61.63 v6(138.56,61.58)
  IN3 w0.076: v4(134.82,71.41) 134.4,70.99 134.4,68.29 136.09,66.6 137.33,66.6 138.93,64.99 138.93,64.12 138.11,63.3 v4(138.11,62.09)
  IN4 w0.076: v4(94.84,71.26) 95.94,72.36 98.89,72.36 98.97,72.44 102.57,72.44 102.95,72.82 103.78,72.82 104.13,72.47 106.78,72.47 107.23,72.02 110.23,72.02 v4(110.67,72.47) 111.09,72.47 111.58,71.98 114.56,71.98 114.83,71.72 119.83,71.72 120.97,72.85 126.31,72.85 128.59,70.57 133.56,70.57 134.4,71.41 v4(134.82,71.41)
  GND5 w0.076: v5(110.14,72.12) 110.48,72.47 v4(110.67,72.47) ; v5(94.74,70.84) 94.84,70.94 v4(94.84,71.26)
  BOTTOM w0.076: 94.75,70.85 94.75,71.1 UCPU1.T4
  BOTTOM w0.102: v2(110.48,72.48) 110.14,72.14 v5(110.14,72.12) 109.75,71.73 RH29.1 ; 94.75,70.85 v5(94.74,70.84)
SHUTDWN#: length 2.5
  TOP w0.102: U689.2 175.36,48.63 175.08,48.35 174.51,48.35 173.85,49 U688.4
SKIP#: length 16.7
  TOP w0.102: v2(36.2,76.76) v1(36.2,77.4)
  TOP w0.203: PU701.7 25.79,78.72 25.41,78.33 PR733.1
  TOP w0.254: v1(24.8,77.64) 24.78,77.64 24.78,78.33 PR733.1 ; PR718.1 36.42,77.63 v1(36.2,77.4)
  IN3 w0.254: v1(24.8,77.64) 25.39,77.05 26.68,77.05 27.79,78.17 29.97,78.17 30.17,78.37 35.56,78.37 36.2,77.73 v1(36.2,77.4)
SKIP#1: length 14.6
  TOP w0.254: PR720.1 PR718.2 35.51,77.79 35.34,77.62 v1(35.34,77.39)
  IN3 w0.254: v1(35.34,77.39) 36.06,76.67 38.62,76.67 40.28,75.01 40.28,71.74 38.73,70.19 v8(38.35,70.19)
  BOTTOM w0.203: PU702.1 38.06,70.49 v8(38.35,70.19)
SKIP#2: length 15.7
  TOP w0.254: v1(23.93,79.01) 24.04,78.91 24.04,78.48 PR733.2 PR738.1
  IN2 w0.254: v8(29.33,70.52) 29.33,70.52 29.33,71.41 29.73,71.81 29.73,74.63 28.65,75.7 25.13,75.7 23.89,76.94 23.89,78.96 v1(23.93,79.01)
  BOTTOM w0.203: v8(29.33,70.52) 29.03,70.52 28.89,70.66 PU703.1
SLATE_MODE: length 79.4
  TOP w0.076: U636.D5 v6(159.77,64.1)
  GND1 w0.076: v4(159.56,64.53) 159.77,64.32 v6(159.77,64.1)
  IN2 w0.076: v4(157.23,61.2) 155.57,62.86 155.57,63.28 154.02,64.83 149.02,64.83 148.79,64.6 148.25,64.6 147.87,64.99 144.77,64.99 144.57,64.78 143.43,64.78 142.52,63.87 141.72,63.87 141.46,63.61 140.62,63.61 139.16,62.15 139.01,62.15 137.81,60.96 137.24,60.96 136.02,59.74 132.54,59.74 132.16,60.12 131.2,60.12 130.97,59.89 130.97,59.75 128.38,57.16 114.84,57.16 114.38,57.62 114.38,58.72 114.17,58.94 108.65,58.94 106.23,61.36 105.61,61.36 105.53,61.43 102.57,61.43 100.86,59.72 98.53,59.72 98.27,59.98 96.92,59.98 94.66,62.24 v4(94.66,62.79)
  IN3 w0.076: v4(157.23,61.2) 157.23,61.6 157.9,62.27 158.66,62.27 159.56,63.17 v4(159.56,64.53)
  GND5 w0.076: v5(94.67,63.24) 94.81,63.1 94.81,62.94 v4(94.66,62.79)
  BOTTOM w0.102: UCPU1.AL4 v5(94.67,63.24)
SLEW: length 4
  BOTTOM w0.102: PC502.1 142.49,75.22 v2(142.72,74.99)
  BOTTOM w0.254: PC502.1 141.84,76.66 141.84,77 141.1,77.74 PU501.21
SLEWA: length 13
  TOP w0.203: v1(29.66,76.82) 29.62,76.86 29.62,76.92 29.32,77.23 PU701.15
  IN2 w0.254: v1(29.66,76.82) 29.81,76.97 29.81,81.29 29.51,81.6 29.51,85.43 v1(29.13,85.81)
  BOTTOM w0.254: PR714.2 PR701.1 v2(29.16,85.2) 29.16,85.78 v1(29.13,85.81)
SLP_S0#: length 38.3
  IN4 w0.076: v3(119.18,61.82) 118.79,62.22 117.8,62.22 117,61.42 110.34,61.42 108.01,63.75 102.81,63.75 101.58,62.52 98.34,62.52 98.19,62.37 97.31,62.37 96.7,62.98 95.36,62.98 94.69,62.31 93.86,62.31 93.65,62.51 92.03,62.51 91.76,62.78 91.76,64.21 91.62,64.35 91.62,64.9 92.11,65.38 v4(92.83,65.38)
  GND5 w0.076: v5(92.32,65.38) v4(92.83,65.38)
  BOTTOM w0.102: v5(92.32,65.38) 92.49,65.54 95.02,65.54 UCPU1.AF3 ; RH463.1 119.13,61.87 v3(119.18,61.82)
SLP_WLAN#: length 17.8
  TOP w0.102: v3(106.72,64.15) 106.33,63.77 RH402.1 106.1,63.67 106.61,63.16 107.18,63.16 v2(107.7,62.64)
  IN1 w0.076: v3(106.72,64.15) 106.49,63.93 103.44,63.93 102.99,64.38 102.74,64.63 99.24,64.63 98.97,64.91 98.56,64.91 98.24,64.59 96.72,64.59 95.54,63.41 94.41,63.41 94,63 v4(93.94,63)
  GND5 w0.076: v4(93.94,63) 93.85,63 v5(93.57,62.73)
  BOTTOM w0.102: UCPU1.AM5 93.72,62.57 v5(93.57,62.73)
SM_INTRUDER#: length 9
  BOTTOM w0.076: 93.69,54.95 93.43,55.22 93.43,55.22 92.98,55.66 92.98,56.74 92.77,56.96 92.77,58.61 93.29,59.13 UCPU1.AU6
  BOTTOM w0.102: RH11.2 96.37,53.51 96.31,53.51 95.93,53.89 v2(95.47,53.89) 94.76,53.89 93.69,54.95
SM_PG_CTRL: length 82.4
  IN4 w0.076: v4(41.31,55.03) 41.29,55.02 41.29,54.87 40.31,53.89 40.25,53.89 39.24,52.88 36.94,52.88 32.99,48.93 32.43,48.93 32.4,48.96 32.1,48.96 31.36,48.22 29.59,48.22 29.45,48.36 27.62,48.36 24.77,45.52 23.76,45.52 23.13,46.14 21.71,46.14 16.95,41.38 16.95,30.45 19.12,28.28 19.12,27.5 23.29,23.33 26.59,23.33 30.07,19.85 37.23,19.85 37.69,19.39 v1(37.99,19.39)
  GND5 w0.076: v4(41.31,55.03) 41.31,54.81 v5(41.52,54.6)
  BOTTOM w0.102: v1(37.99,19.39) 38.2,19.19 PR615.1 ; UC1.4 50.42,58.89 RC159.2 RC161.1 49.01,55.86 v2(47.21,54.06) 46.91,53.76 42.28,53.76 41.52,54.52 v5(41.52,54.6)
SM_RCOMP0: length 6.1
  TOP w0.508: RC55.1 60.15,57.87 60.75,58.47 v2(60.75,59.07) 60.75,59.92 v1(60.83,60)
  BOTTOM w0.254: UCPU1.AU60 60.27,59.38 60.27,59.7 60.57,60 v1(60.83,60)
SM_RCOMP1: length 4.2
  TOP w0.508: RC58.1 58.99,55.47 58.63,55.83 v2(58.63,56.78) 58.63,57.72 59.26,58.35 v1(59.57,58.35)
  BOTTOM w0.254: v1(59.57,58.35) 59.75,58.53 UCPU1.AV60
SM_RCOMP2: length 6.5
  TOP w0.508: RC60.1 57.86,55.97 57.31,56.52 57.31,57.87 v2(58.53,59.09) 59.14,59.7 59.77,59.7 v1(59.79,59.72)
  BOTTOM w0.254: v1(59.79,59.72) 59.55,59.72 59.35,59.52 UCPU1.AU61
SMBALERT#: length 92.1
  TOP w0.102: v1(158.97,69.58) 158.69,69.3 R1136.2
  IN4 w0.076: v4(152.5,61.23) 152.17,60.9 149.47,60.9 148.81,61.56 147.78,61.56 147.56,61.33 146.35,61.33 146.06,61.03 146.06,59.94 145.45,59.34 145.45,57.84 145.17,57.56 145.13,57.56 144.81,57.24 143.76,57.24 143.58,57.06 142.88,57.06 142.14,56.32 141.59,56.32 141.35,56.08 140.08,56.08 139.85,55.85 137.8,55.85 137.26,56.4 137.26,57.84 135.77,59.32 134.22,59.32 133.15,60.39 133.15,61.1 132.87,61.38 132.01,61.38 131.71,61.68 129.48,61.68 129.12,61.33 123.54,61.33 122.88,60.67 121.83,60.67 121.09,59.93 119.68,59.93 119.46,59.72 118.32,59.72 117.98,60.06 110.47,60.06 107.5,63.04 103.11,63.04 101.87,61.8 98.94,61.8 98.15,61.01 96.75,61.01 v4(96.54,61.21)
  GND5 w0.076: v4(152.5,61.23) 152.55,61.28 v5(152.55,61.71) ; v4(96.54,61.21) 96.38,61.05 v5(96,61.05)
  BOTTOM w0.076: 97.37,61.84 97.33,61.84 97.2,61.71 96.29,61.71 95.97,61.4 UCPU1.AN2 95.97,61.08 v5(96,61.05)
  BOTTOM w0.102: v1(158.97,69.58) 157.44,71.12 152.46,71.12 151.91,70.57 151.91,64.12 152.09,63.94 152.09,62.17 v5(152.55,61.71) ; 97.37,61.84 97.46,61.84 98.25,62.62 v2(98.67,62.62) 98.93,62.62 99.44,63.13 99.44,63.56 99.85,63.97 RP19.2
SMBCLK: length 34.8
  TOP w0.102: v6(120.2,61.89) 119.95,61.63 119.95,61.48 RH105.1 120.52,61.7 QH3.6 120.19,62.43 v2(119.55,63.07)
  GND1 w0.076: v6(120.2,61.89) 120.19,61.87 120.19,61.04 v4(120.2,61.02)
  IN2 w0.076: v4(99.87,63.11) 99.87,63.7 100.58,64.41 101.19,64.41 v4(101.61,64) 102.18,63.42 102.47,63.42 102.53,63.47 105.97,63.47 106.3,63.14 107.15,63.14 109.62,60.67 117.71,60.67 118.4,61.35 119.88,61.35 120.2,61.04 v4(120.2,61.02)
  GND5 w0.076: v4(99.87,63.11) 99.87,63.03 99.48,62.64 v5(99.45,62.64) ; v4(101.61,64) 101.73,64 102.17,63.56 v5(102.36,63.56)
  BOTTOM w0.076: UCPU1.AP2 96.19,60.64 96.57,61.02 96.69,61.02 96.82,61.15 97.33,61.15 97.37,61.2
  BOTTOM w0.102: v5(102.36,63.56) 102.39,63.6 RP7.1 ; 97.37,61.2 98.37,62.19 99,62.19 v5(99.45,62.64)
SMBDATA: length 36
  TOP w0.102: RH111.1 123.76,64.73 v2(123.9,64.87) ; RH111.1 123.07,64.48 v6(123.07,63.68) ; RH111.1 122.42,64.34 QH3.3
  GND1 w0.076: v6(123.07,63.68) 123.07,63.36 v4(122.84,63.13)
  IN2 w0.076: v4(96.72,64.1) 97.29,64.67 98,64.67 98.62,64.05 99.79,64.05 100.36,64.62 101.67,64.62 v4(102.23,64.06) 102.61,63.68 106.05,63.68 106.39,63.34 107.23,63.34 109.71,60.87 116.46,60.87 117.88,62.29 121.71,62.29 122.55,63.13 v4(122.84,63.13)
  GND5 w0.076: v5(102.97,64.1) 102.93,64.06 v4(102.23,64.06) ; v5(96.99,64.44) 96.99,64.37 v4(96.72,64.1)
  BOTTOM w0.102: RP7.2 103.63,64.1 103.63,64.1 v5(102.97,64.1) ; UCPU1.AH1 96.94,64.39 v5(96.99,64.44)
SMC_SHDN: length 3
  TOP w0.102: Q349.5 170.35,50.15 R1287.1 R1286.2 R1285.2
SML0ALERT#: length 5
  BOTTOM w0.076: 97.22,63.21 96.24,63.21 95.98,62.95 95.98,62.9
  BOTTOM w0.102: 97.22,63.21 97.68,63.21 98.5,64.02 v2(98.8,64.02) 99.46,64.02 99.91,64.47 RP19.3 ; UCPU1.AL2 95.98,62.9
SML0CLK: length 91.9
  TOP w0.102: RH70.1 99.75,58.55 99.75,58.05 v1(99.98,57.81) 100.51,57.28 100.51,56.67 v3(100.38,56.53)
  IN1 w0.076: v4(97.51,61.58) 97.51,61.84 97.25,62.09 97.17,62.09 97.1,62.01 97.1,59.12 100.17,56.05 100.39,56.05 100.53,56.18 100.53,56.38 v3(100.38,56.53)
  IN2 w0.076: v1(158.58,25.88) 158.36,25.67 158.36,25.38 158.1,25.12 153.57,25.12 152.12,26.57 152.12,30.01 147.57,34.56 147.57,37.34 146.74,38.16 130.44,38.16 127.55,41.06 123.94,41.06 122.05,39.17 119.05,39.17 114.57,43.65 112.18,43.65 108.65,47.18 107.76,47.18 105.15,49.79 105.15,51.09 100.55,55.69 100.55,56.35 v3(100.38,56.53)
  GND5 w0.076: v5(97.03,61.39) 97.39,61.39 97.51,61.51 v4(97.51,61.58)
  BOTTOM w0.102: v1(158.58,25.88) 158.41,26.05 158.41,26.3 158.56,26.45 JNFC1.8 ; UCPU1.AN1 v5(97.03,61.39)
SML0DATA: length 92.7
  TOP w0.102: v3(101.01,56.53) 100.73,56.81 100.73,57.39 100.01,58.12 100.01,58.43 RH72.1
  IN1 w0.076: v3(101.01,56.53) 101.01,56.5 100.73,56.22 100.73,56.1 100.48,55.84 100.09,55.84 96.9,59.03 96.9,62.1 97.09,62.29 97.22,62.29 97.38,62.45 97.38,63.03 97.25,63.16 v4(97.25,63.23)
  IN2 w0.076: v1(157.92,25.88) 158.16,25.64 158.16,25.46 158.02,25.32 153.65,25.32 152.32,26.66 152.32,30.09 147.77,34.64 147.77,37.42 146.83,38.37 130.53,38.37 127.63,41.26 123.86,41.26 121.97,39.37 119.13,39.37 114.65,43.85 112.26,43.85 108.73,47.38 107.84,47.38 105.35,49.87 105.35,51.18 100.76,55.77 100.76,56.27 v3(101.01,56.53)
  GND5 w0.076: v4(97.25,63.23) 97.25,63.36 v5(96.97,63.64)
  BOTTOM w0.102: UCPU1.AK1 v5(96.97,63.64) ; JNFC1.9 158.06,26.48 158.17,26.37 158.17,26.14 v1(157.92,25.88)
SML1ALERT#: length 99.7
  TOP w0.102: v8(166.12,55.28) 165.63,55.78 165.63,58.03 R1227.1 165.08,59.03 165.63,59.58 165.63,60.29 166.81,61.47 166.81,64.47 166.06,65.21 164.83,65.21 R1158.2
  IN4 w0.076: v4(95.36,58.56) 95.57,58.35 95.57,57.8 97.2,56.17 98.27,56.17 98.8,55.64 98.8,54.78 101.35,52.22 104.48,52.22 104.96,51.74 104.96,50.1 105.7,49.36 106.84,49.36 107.42,48.78 108.81,48.78 112.11,52.08 114.53,52.08 115.9,53.45 125.57,53.45 127.65,55.54 129.09,55.54 133.46,51.17 136.85,51.17 137.51,50.51 137.51,49.67 138.44,48.74 144.81,48.74 145.31,49.24 156.32,49.24 156.38,49.17 160.08,49.17 166.12,55.22 v8(166.12,55.28)
  GND5 w0.076: v4(95.36,58.56) 95.06,58.86 v5(94.86,58.86)
  BOTTOM w0.076: UCPU1.AU4 94.65,59.12 94.86,58.9 v5(94.86,58.86)
SML1CLK: length 44.1
  TOP w0.102: QH4.6 123.82,61.94 RH453.1 124.53,61.66 124.53,62.15 v6(124.44,62.24)
  GND1 w0.076: v4(124.94,62.4) 124.59,62.4 v6(124.44,62.24)
  IN2 w0.076: v4(124.94,62.4) 124.94,62.85 124.78,63 124.18,63 123.64,63.54 122.47,63.54 121.46,62.52 117.77,62.52 116.5,61.25 109.74,61.25 107.44,63.54 106.47,63.54 106.13,63.88 103.68,63.88 102.69,64.88 102.63,64.88 102.25,65.25 v1(102.24,65.25)
  BOTTOM w0.076: UCPU1.AU3 95.31,59.31 95.63,59.63 96.31,59.63 96.44,59.5 96.75,59.5 96.75,59.5 96.97,59.5 96.98,59.49 97.37,59.49
  BOTTOM w0.102: v1(102.24,65.25) 102.24,65.24 102.88,64.6 RP7.3 104.14,64.6 104.4,64.34 104.4,62.83 104.08,62.51 102.47,62.51 v2(102.05,62.09) 102.05,61.43 101.26,60.64 101.26,60.32 100.43,59.49 97.37,59.49
SML1DATA: length 38.7
  TOP w0.102: QH4.3 125.89,63.73 126.04,63.88 126.04,64.53 RH454.1 125.28,64.22 125.25,64.22 v6(124.75,63.72)
  GND1 w0.076: v6(124.75,63.72) 125.2,63.72 125.22,63.73 125.22,63.73 v4(125.22,63.73)
  IN2 w0.076: v4(125.22,63.73) 125.22,63.73 125.22,63.6 124.82,63.21 124.26,63.21 123.73,63.74 122.39,63.74 121.37,62.73 117.69,62.73 116.42,61.46 109.82,61.46 107.53,63.75 106.56,63.75 106.22,64.08 103.77,64.08 102.89,64.96 v1(102.89,65.25)
  BOTTOM w0.076: 97.37,65.21 97.37,65.11 97.12,64.86 95.88,64.86 95.37,64.35 UCPU1.AH3
  BOTTOM w0.102: RP7.4 103.04,65.1 v1(102.89,65.25) 102.86,65.28 102.86,65.56 102.66,65.76 102.29,65.76 102.03,66.03 101.52,66.03 100.86,65.37 v2(98.6,65.37) 97.53,65.37 97.37,65.21
SNUB_1.5VSP:
  vias: v2(109.39,77.64)
SNUB_1.8VSP: length 3.9
  TOP w0.102: PC416.1 200.96,64.92 v2(200.36,65.52)
  TOP w0.508: v1(202.9,65.16) 202.1,65.16 PC416.1
  BOTTOM w0.508: v1(202.9,65.16) 202.9,64.91 203.02,64.8 PR418.2
SNUB_+1.2V:
  vias: v2(45.51,21.32)
SNUB_+1.05V: length 3.7
  BOTTOM w0.102: PR507.2 131.53,73.76 v2(131.92,73.37)
  BOTTOM w0.508: PC509.1 132.81,75.26 132.49,74.94 PR507.2
SNUB_+3.3VDX_SSD: length 4.6
  BOTTOM w0.102: v2(178.1,43.95) 177.34,43.19 177.34,42.28 178.09,41.53 PC331.1
  BOTTOM w0.508: PC331.1 177.71,41.02 PR334.2
SNUB_+3VDX: length 4.8
  TOP w0.102: v2(207.32,55.09) 206.67,55.09 PR324.2
  TOP w1.016: PR324.2 203.72,56.86 PC323.1
SNUB_+5VDX: length 3.3
  BOTTOM w0.102: PC315.1 204.31,55.59 204.41,55.69 v2(205.47,55.69)
  BOTTOM w0.508: PC315.1 203.77,55.05 203.49,54.78 PR314.2
SNUB_+V3.3A_DSW: length 3.8
  BOTTOM w0.102: PR344.2 v2(208.71,29.02)
  BOTTOM w0.508: PR344.2 207.11,30.29 207.23,30.42 PC339.1
SNUB_+V5A: length 4.3
  TOP w0.102: v2(216.54,31.22) 216.54,31 215.68,30.14 215.32,30.14 PC307.1
  TOP w0.508: PC307.1 213.89,28.7 PR304.2
SNUB_CHG: length 1.8
  TOP w0.102: PC221.1 152.94,36.35 152.24,35.65 v2(151.62,35.65)
SNUB_PHASE1: length 1.4
  TOP w0.102: PC712.1 v7(35.63,70.95)
SNUB_PHASE2: length 1.4
  TOP w0.102: 22.99,71.37 v7(22.99,72.75)
SOSCI: length 6.2
  TOP w0.076: 158.25,66.51 158.25,66.12 U636.B8
  TOP w0.102: 158.25,66.51 158.25,66.94 v2(158.13,67.06) 157.5,67.69 157.08,67.69 CH1202.1 156.33,68.44 156.33,69.56 156.59,69.81 Y1.2
SOSCO: length 7
  TOP w0.076: U636.B7 158.29,65.57 157.87,65.57 157.73,65.71
  TOP w0.102: Y1.1 155.76,69.81 156.01,69.56 156.01,68.4 CH1203.1 155.77,67.82 155.98,67.61 156.33,67.61 v2(156.75,67.2) 157.17,66.78 157.17,66.27 157.73,65.71
SPARE1: length 41.9
  TOP w0.102: v1(180.06,83.39) 179.51,82.84 179.51,80.76 180.28,79.99 JSNRDG.10 v2(180.28,78.45) ; U636.C4 v6(159.27,64.04)
  GND1 w0.076: v4(158.92,63.44) 158.92,63.69 v6(159.27,64.04)
  IN3 w0.076: v4(158.92,63.44) 159,63.52 159,64.35 158.72,64.63 158.72,65.32 159.28,65.87 159.28,66.28 160.9,67.91 165.8,67.91 166.63,68.74 166.63,75.55 170.59,79.51 171.95,79.51 175.42,82.98 177.34,82.98 177.62,82.7 179.37,82.7 v1(180.06,83.39)
SPARE2: length 42.5
  TOP w0.076: U636.A3 157.75,63.32 v6(157.46,63.03)
  TOP w0.102: v1(178.84,83.53) 179.2,83.17 179.2,80.76 179.78,80.18 JSNRDG.11 179.78,78.9 179.41,78.52 v2(178.9,78.52)
  GND1 w0.076: v4(157.47,63.56) 157.46,63.55 v6(157.46,63.03)
  IN3 w0.076: v1(178.84,83.53) 178.56,83.81 177.96,83.81 177.52,83.36 175.27,83.36 171.77,79.86 170.44,79.86 166.28,75.7 166.28,68.88 165.78,68.39 159.95,68.39 158.34,66.78 158.34,65.46 157.68,64.8 157.68,63.76 v4(157.47,63.56)
SPI_CLK_ROM: length 35.2
  TOP w0.102: MR256.2 96.87,69.8 RH255.1 97.25,69.42 v6(97.58,69.42)
  GND1 w0.076: v6(97.58,69.42) v4(97.92,69.08)
  IN2 w0.076: v4(97.92,69.08) 97.49,69.08 97.37,68.95 97.37,68.72 97.49,68.59 98.99,68.59 99.12,68.47 99.12,68.05 99.24,67.92 99.42,67.92 99.54,68.05 99.54,68.91 99.66,69.02 99.81,69.02 99.93,68.91 99.93,68.03 100.03,67.93 105.34,67.93 105.47,67.81 105.47,67.53 105.34,67.4 103.39,67.4 103.26,67.27 103.26,66.99 103.39,66.87 104.66,66.87 104.79,66.74 104.79,66.56 104.66,66.43 104.25,66.43 104.13,66.31 104.13,66.13 104.25,66 105.3,66 105.4,66.1 105.4,66.59 105.53,66.71 105.84,66.71 105.96,66.59 105.96,66.1 106.06,66 106.23,66 106.5,66.27 109.13,66.27 v4(109.19,66.21)
  GND5 w0.076: v4(109.19,66.21) 108.94,65.95 v5(108.94,65.72)
  BOTTOM w0.102: U48.6 111.01,62.18 111.63,62.8 111.63,63.18 111.7,63.26 v2(112.01,63.26) 112.39,63.26 112.52,63.39 112.52,63.64 112.39,63.77 109.85,63.77 109.62,64 108.91,64 108.71,64.2 108.71,65.49 v5(108.94,65.72)
SPI_IO2_ROM: length 38.8
  TOP w0.102: RP4.2 100.68,68.39 100.95,68.12 100.95,67.35 101.68,66.61 104.35,66.61 104.83,66.13 106.41,66.13 v6(106.46,66.08)
  GND1 w0.076: v4(106.9,65.87) 106.9,65.85 106.67,66.08 v6(106.46,66.08)
  GND5 w0.076: v4(106.9,65.87) 106.93,65.85 106.93,65.84 107.28,65.48 v5(107.28,65.47)
  BOTTOM w0.102: RH54.2 115.49,54.75 113.8,53.06 111.31,53.06 111.01,53.37 U48.3 111.01,55.84 110.88,55.97 110.48,55.97 110.36,56.1 110.36,56.35 110.48,56.48 111.58,56.48 111.7,56.6 111.7,56.86 111.58,56.98 109.52,56.98 109.39,57.11 109.39,57.32 109.52,57.44 113.25,57.44 113.38,57.57 113.38,57.87 113.25,58 110.08,58 109.96,58.13 109.96,59.32 107.21,62.06 v2(107.21,64.54) 107.21,65.39 v5(107.28,65.47)
SPI_IO3_ROM: length 36.8
  TOP w0.102: v6(101.16,69.02) 100.79,69.39 RP4.4
  GND1 w0.076: v6(101.16,69.02) 101.16,68.78 v4(100.96,68.58)
  IN1 w0.076: v4(100.96,68.58) 101.15,68.39 103.05,68.39 103.74,67.7 103.74,67.38 104.88,66.24 105.43,66.24 105.56,66.37 105.56,67.01 105.62,67.07 105.86,67.07 105.95,66.98 105.95,66.29 106,66.24 106.19,66.24 106.26,66.31 106.26,66.97 106.36,67.07 106.84,67.07 107.04,66.87 107.04,66.6 107.15,66.49 107.71,66.49 108.48,65.72 108.48,65.16 108.63,65.01 v4(108.88,65.01)
  GND5 w0.076: v4(108.88,65.01) 109.06,65.01 v5(109.37,64.71)
  BOTTOM w0.102: v5(109.37,64.71) 109.37,65.24 109.24,65.37 109.06,65.37 108.94,65.24 108.94,64.38 109.09,64.22 109.8,64.22 110.03,64 112.67,64 113.1,64.43 v2(113.1,64.71) 113.1,66.46 113.23,66.59 113.96,66.59 114.09,66.46 114.09,66.08 113.96,65.95 113.66,65.95 113.53,65.82 113.53,65.54 113.66,65.42 113.94,65.42 114.07,65.29 114.07,65.09 113.94,64.96 113.66,64.96 113.53,64.83 113.53,64.6 113.66,64.48 113.96,64.48 114.09,64.35 114.09,64.1 113.96,63.97 113.51,63.97 112.47,62.93 112.08,62.93 111.81,62.65 111.81,62.55 111.93,62.42 112.15,62.42 112.28,62.29 U48.7 112.28,60.76 113.96,59.07 RH56.2
SPI_SI_ROM: length 34.8
  TOP w0.102: RP4.3 100.73,68.89 101.32,68.31 101.32,67.42 101.89,66.85 103.05,66.85 103.23,67.03 103.23,67.35 103.33,67.45 103.54,67.45 103.64,67.35 103.64,66.94 103.74,66.84 103.92,66.84 104.02,66.94 104.02,67.58 104.15,67.7 104.38,67.7 104.5,67.58 104.5,66.97 105.04,66.43 105.57,66.43 105.7,66.56 105.7,67.45 105.82,67.58 106.05,67.58 106.18,67.45 106.18,66.56 v6(106.31,66.43)
  GND1 w0.076: v6(106.31,66.43) 106.42,66.43 v4(106.65,66.66)
  GND5 w0.076: v4(106.65,66.66) 106.75,66.66 v5(107.06,66.36)
  BOTTOM w0.102: v5(107.06,66.36) 107.06,65.94 107.17,65.82 107.32,65.82 107.44,65.94 107.44,66.32 108.08,66.97 109.9,66.97 110.13,66.74 110.13,66.23 110.28,66.08 111.12,66.08 111.25,65.95 111.25,65.7 111.12,65.57 109.37,65.57 109.24,65.7 109.24,65.9 109.11,66.03 108.81,66.03 108.48,65.7 108.48,61.77 108.64,61.61 108.96,61.61 109.09,61.73 v2(109.09,63.59) 109.09,63.64 109.21,63.77 109.44,63.77 109.57,63.64 109.57,63.44 109.7,63.31 111.27,63.31 111.4,63.18 111.4,62.9 111.27,62.78 109.86,62.78 109.74,62.65 U48.5
SPI_SO_ROM: length 34.5
  TOP w0.102: v6(106.98,65.33) 106.74,65.33 106.17,65.9 104.73,65.9 104.25,66.38 101.44,66.38 100.42,67.41 RP4.1
  GND1 w0.076: v6(106.98,65.33) 107.42,65.33 v4(107.67,65.09)
  GND5 w0.076: v4(107.67,65.09) 107.69,65.06 v5(107.69,64.6)
  BOTTOM w0.102: v5(107.69,64.6) 107.69,64.25 107.79,64.15 107.92,64.15 108.02,64.05 108.02,63.84 107.92,63.74 107.58,63.74 107.46,63.62 107.46,63.45 107.58,63.33 107.92,63.33 108.02,63.23 108.02,63.03 107.92,62.93 107.56,62.93 107.44,62.81 107.44,62.64 107.56,62.52 107.84,62.52 107.89,62.47 v2(107.89,62.26) 107.89,61.71 109.8,59.8 112.52,59.8 112.64,59.68 112.64,59.45 112.52,59.32 110.43,59.32 110.31,59.19 110.31,58.99 110.43,58.86 113.1,58.86 113.78,58.19 113.78,56.72 113.1,56.05 111.5,56.05 111.37,55.92 111.37,55.74 111.5,55.61 113.05,55.61 113.18,55.49 113.18,55.28 113.05,55.16 112.4,55.16 112.28,55.03 U48.2
SSD_PWREN: length 84.7
  TOP w0.102: v2(129.48,68.66) 129.78,68.36 v1(129.78,67.93) 128.95,67.11 RH431.1 129.31,66.59 129.42,66.7 129.42,67.02 129.57,67.17 U682.4
  IN3 w0.076: v1(168.71,34.49) 168.57,34.49 166.57,32.49 163.85,32.49 163.39,32.03 163.39,30.8 161.88,29.29 161.88,28.54 161.35,28 151.1,28 149.78,29.32 142.97,29.32 141.05,31.24 141.05,38.07 139.94,39.19 139,39.19 133.07,45.12 133.07,49.17 133.6,49.71 133.6,51 134.65,52.06 134.65,53.56 136.14,55.04 136.14,56.86 135.76,57.24 135.76,58.97 135.27,59.45 135.27,61.63 134.72,62.19 134.18,62.19 132.04,64.33 132.04,65.66 129.78,67.92 v1(129.78,67.93)
  BOTTOM w0.102: 170.14,32.61 169.06,33.69 169.06,34.15 v1(168.71,34.49)
  BOTTOM w0.127: PU304.13 170.14,32.61
SSD_PWREN#: length 53.5
  TOP w0.102: v2(128.05,67.58) 127.44,66.97 v6(127.44,66.87) 127.44,66.29 RH423.1 RH431.2 129.8,66.52 U682.2
  GND1 w0.076: v6(127.44,66.87) 127.11,67.2 127.1,67.2 v4(127.07,67.17)
  IN4 w0.076: v4(127.07,67.17) 126.75,67.17 126.16,66.59 122.37,66.59 119.86,69.1 116.87,69.1 116.42,68.64 111.79,68.64 111.68,68.53 109.63,68.53 109.24,68.92 106.26,68.92 105.97,68.63 101.82,68.63 101.04,67.84 99.23,67.84 98.46,67.07 97.16,67.07 96.88,67.35 94.7,67.35 94.39,67.65 94.39,67.91 94.14,68.16 93.06,68.16 92.58,68.64 92.58,69.95 93.8,71.17 93.8,71.63 93.54,71.88 93.54,72.57 93.81,72.83 93.81,73.46 93.96,73.61 95.47,73.61 v4(95.77,73.32)
  GND5 w0.076: v5(95.66,73.76) 95.66,73.42 v4(95.77,73.32)
  BOTTOM w0.102: UCPU1.K2 95.97,74.07 v5(95.66,73.76)
STARTUP_LATCH_SET: length 3.7
  TOP w0.102: U688.1 172.16,46.65 R1283.2 173.37,45.43 173.37,44.39 T262.1
SUS_PWR_DN: length 24.9
  BOTTOM w0.076: 97.37,58.82 97.33,58.86 96.49,58.86 96.29,59.07 96.29,59.32 96.13,59.47 95.78,59.47 95.65,59.35 95.65,59.17 95.32,58.84 95.19,58.84 94.9,58.55 UCPU1.AV4
  BOTTOM w0.102: RH429.2 RH154.1 RH297.1 113.09,52.13 112.81,51.85 109.15,51.85 107.75,53.26 v2(107,53.26) 105.96,54.29 103.47,54.29 102.74,55.03 101.24,55.03 97.68,58.59 97.66,58.59 97.43,58.82 97.37,58.82
SUS_STAT#: length 64
  TOP w0.102: R1238.1 134.87,76.26 134.26,75.65 v2(133,75.65) v6(132.11,75.65)
  GND1 w0.076: v4(131.67,75.3) 131.76,75.3 v6(132.11,75.65)
  IN1 w0.076: v4(134.04,63.68) 133.87,63.5 132.87,63.5 132.56,63.82 130.37,63.82 129.89,63.33 128.44,63.33 127.9,62.79 124.39,62.79 123.6,62 119.83,62 118.84,62.99 116.21,62.99 114.9,61.68 109.76,61.68 106.89,64.55 106.29,64.55 106.09,64.35 103.45,64.35 102.97,64.83 99.29,64.83 99.04,65.09 98.49,65.09 98.17,64.77 96.6,64.77 96.37,64.54 94.59,64.54 v4(94.39,64.74)
  IN3 w0.076: v4(131.67,75.3) 131.02,75.3 129.17,73.44 129.17,69.75 130.26,68.66 130.26,67.69 132.44,65.5 132.44,64.97 132.81,64.6 133.52,64.6 134.04,64.08 v4(134.04,63.68)
  GND5 w0.076: v5(94.34,65.29) 94.34,64.79 v4(94.39,64.74)
  BOTTOM w0.102: UCPU1.AG4 94.45,65.18 v5(94.34,65.29)
SUSACK#: length 27.2
  TOP w0.081: 139.54,55.22 139.54,55.73 U34.M13
  TOP w0.102: 139.54,55.22 v1(139.54,55.16)
  IN2 w0.076: v4(124.16,55.64) 124.34,55.46 127.07,55.46 127.39,55.78 132.9,55.78 133.47,55.21 138.07,55.21 138.44,55.58 139.12,55.58 v1(139.54,55.16)
  GND5 w0.076: v4(124.16,55.64) 123.82,55.3 v5(123.82,55.21)
  BOTTOM w0.102: RH430.2 117.04,51.22 117.57,51.75 v2(117.9,51.75) 118.52,51.75 118.74,51.54 120.67,51.54 123.82,54.69 v5(123.82,55.21)
SUSACK#_R: length 38.1
  IN1 w0.076: v4(116.4,62.01) 115.89,61.51 109.29,61.51 107.05,63.75 103.37,63.75 102.66,64.45 99.6,64.45 99.22,64.07 97.82,64.07 v4(97.77,64.12)
  IN3 w0.076: v1(116.97,50.51) 116.09,51.4 116.09,56.69 116.69,57.3 116.69,61.72 v4(116.4,62.01)
  GND5 w0.076: v5(97.2,63.97) 97.62,63.97 v4(97.77,64.12)
  BOTTOM w0.102: RH430.1 RH429.1 115.68,50.36 v2(115.86,50.18) 116.64,50.18 v1(116.97,50.51) ; v5(97.2,63.97) 96.44,63.97 96.12,63.64 UCPU1.AK2
SUSCLK: length 4.2
  TOP w0.102: v7(95.19,64.83) 95.17,64.83 RH132.2 93.75,66.24 v6(93.75,66.24) 93.73,66.24 93.31,65.82 MC102.2
  GND1 w0.076: v6(93.75,66.24) 93.75,66.5 v4(93.63,66.61)
  GND5 w0.076: v5(93.06,66.1) 93.12,66.1 v4(93.63,66.61)
  BOTTOM w0.102: v5(93.06,66.1) 93.14,66.1 93.34,65.9 UCPU1.AE6
SUSCLK_R: length 139.1
  TOP w0.102: R1255.2 193.69,46.09 195.12,47.51 v2(195.12,48.44) 195.12,48.5 194.86,48.76 193.53,48.76 193.3,48.53 184.23,48.53 183.79,48.97 v1(183.79,48.98) ; RH132.1 94.48,66.71 94.72,66.48 v6(94.72,66.23) ; R253.1 144.88,67.82 v6(144.56,67.5)
  GND1 w0.076: v4(95.26,66.26) 95.23,66.23 v6(94.72,66.23) ; v4(144.53,66.74) 144.53,67.48 v6(144.56,67.5)
  IN1 w0.076: v4(144.53,66.74) 144.53,67.03 143.89,67.68 139.55,67.68 138.83,66.95 136.17,66.95 136.02,67.11 134.72,67.11 133.2,65.58 129.43,65.58 128.21,64.36 125.04,64.36 124.95,64.27 124.69,64.01 124.49,63.8 122.7,63.8 121.48,62.59 120.89,62.59 120.2,63.27 120.2,63.3 119.69,63.8 115.97,63.8 115.63,64.15 113.67,64.15 112.76,63.23 108.96,63.23 107.11,65.08 106.07,65.08 105.87,64.88 104.05,64.88 103.69,65.25 103.69,65.62 103.16,66.15 103.16,67.46 102.91,67.7 101.62,67.7 101.52,67.6 99.47,67.6 98.99,67.12 97.96,67.12 97.16,66.32 95.32,66.32 v4(95.26,66.26)
  IN4 w0.076: v1(183.79,48.98) 183.59,48.98 183.47,49.1 183.47,63.32 181.92,64.87 181.92,68.1 180.74,69.28 179.8,69.28 178.53,70.55 175.79,70.55 175.2,71.13 174.1,71.13 173.09,70.12 173.09,69.47 170.01,66.4 167.79,66.4 166.8,65.41 165.05,65.41 164.86,65.21 162.2,65.21 161.93,65.48 160.17,65.48 160.06,65.38 156.85,65.38 156.57,65.66 155.19,65.66 154.66,65.13 153.28,65.13 153.13,64.99 149.55,64.99 149.01,64.45 147.9,64.45 147.39,64.95 147.06,64.95 145.27,66.74 v4(144.53,66.74)
SW_+1.2V: length 4.1
  BOTTOM w1.016: 46.63,24.35 45.51,24.35 45.23,24.07 v2(44.22,24.07) 42.64,24.07
  vias: v1(41.6,23.2) v1(42.23,23.2) v1(46.95,23.51) v1(46.92,22.75) v1(46.95,21.96) v1(47.58,23.51) v1(47.57,22.77) v1(47.62,21.98) v1(48.24,23.53) v1(48.2,22.77) v1(48.25,21.98) v1(48.9,23.53)
SW_+1.05VS: length 9.8
  BOTTOM w0.102: PR507.1 130.07,76.15 v2(130.07,73.41)
  BOTTOM w0.254: PC503.2 134.5,79.32
  BOTTOM w0.508: PR507.1 131.53,78.57 132.32,79.36 133.56,79.36
SW_PHASE_1:
  vias: v1(32.54,69.13) v7(34.5,69)
SW_PHASE_2:
  vias: v1(23.18,68.92) v1(23.82,68.92) v1(24.45,68.92) v1(25.09,68.92) v2(20.47,69.41)
SW_USB20_N1: length 11.1
  TOP w0.102: US1.11 208.72,42.04 208.92,41.85 209.2,41.85 210.65,40.4 210.65,40.16 210.67,40.14 210.67,39.59 210.65,39.57 v1(210.65,37.57) 210.65,34.18 211.23,33.59 211.36,33.59 211.65,33.88 ML40.1
SW_USB20_P1: length 11.1
  TOP w0.102: US1.10 208.8,41.55 208.89,41.64 209.12,41.64 210.44,40.31 v1(210.44,39.87) 210.44,37.86 210.42,37.84 210.42,37.29 210.44,37.27 210.44,34.09 211.15,33.38 211.4,33.38 211.7,33.08 ML40.4
SYS_PRS: length 6.3
  TOP w0.102: PR115.1 120.39,25.54 v1(121.05,24.88) 121.05,24.51 120.63,24.09 v2(120.3,24.09)
  BOTTOM w0.102: JBATT1.4 121.37,24.56 v1(121.05,24.88)
SYS_PWROK: length 216.8
  TOP w0.102: v6(22.16,45.33) 22.52,44.96 R1309.1 ; R1292.2 161.87,47.79 156.22,47.79 156.05,47.96 v7(156.05,48.23) v6(156.05,49.42) ; v6(156.79,49.11) 157.25,49.57 R1293.1 157.73,49.57 157.78,49.62 R1290.2 ; v6(95.57,65.93) 95.57,66.19 RH272.1
  GND1 w0.076: v4(95.56,65.49) 95.56,65.91 v6(95.57,65.93) ; v6(156.79,49.11) 156.85,49.17 v4(156.85,49.57) 156.2,49.57 v6(156.05,49.42) ; v4(21.61,45.43) 22.05,45.43 v6(22.16,45.33)
  IN1 w0.076: v4(95.56,65.49) 95.28,65.49 94.61,66.17 94.61,66.95 94.42,67.14 93.15,67.14 92.74,67.55 92.74,68.55 92.18,69.11 92.18,70.43 91,71.62 89.43,71.62 88.87,72.17 88.49,72.17 86.74,73.93 86.74,75.02 85.13,76.62 61.16,76.62 60.29,77.48 59.33,77.48 57.25,79.57 51.84,79.57 44.88,72.61 44.88,72.15 44.17,71.44 44.01,71.44 43.83,71.26 43.83,70.78 41.47,68.41 41.47,66.15 40.52,65.19 40.52,63.63 33.07,56.17 30.56,56.17 30.12,56.17 29.56,55.61 26.96,55.61 26.75,55.41 26.32,54.98 22.91,54.98 21.79,53.86 18.97,53.86 17.95,52.84 17.95,47.69 20.21,45.43 v4(21.61,45.43)
  IN2 w0.076: v4(95.56,65.49) 95.05,65.49 94.48,66.07 91.35,66.07 91.05,65.77 91.05,64.99 91.75,64.29 91.75,62.98 91,62.23 91,59.5 93.14,57.37 94.11,57.37 94.29,57.19 101.21,57.19 103.95,54.44 108.78,54.44 109.16,54.06 109.16,48.07 110.92,46.32 111.82,46.32 113.7,44.44 115.01,44.44 117.57,41.87 119.12,41.87 120.16,40.83 121.6,40.83 122.64,41.87 136.29,41.87 138.23,43.81 138.23,44.55 142.88,49.2 v4(143.54,49.2)
  IN4 w0.076: v4(156.85,49.57) 156.7,49.42 143.76,49.42 v4(143.54,49.2)
  GND5 w0.076: v5(95.64,64.96) 95.56,65.03 v4(95.56,65.49)
  BOTTOM w0.102: UCPU1.AG2 95.82,65.14 v5(95.64,64.96)
SYS_PWROK_XDP: length 17.4
  TOP w0.102: JXDP.47 27.19,49.11 28.09,48.21 v3(28.09,47.23) 28.09,46.15 26.89,44.96 R1309.2
  BOTTOM w0.102: v3(28.09,47.23) 27.64,46.79 23.02,46.79 C1282.1 22.73,47.08 R1311.1 21.09,47.85 v2(21.09,48.3)
SYS_RESET#: length 11.2
  TOP w0.102: v1(100.34,66.15) 100.34,66.01 99.68,65.35 RP20.1
  BOTTOM w0.076: UCPU1.AC3 95.65,67.68 96.11,67.68 96.36,67.43 96.36,66.53 96.51,66.37 97.31,66.37 97.37,66.43
  BOTTOM w0.102: 97.37,66.43 100.06,66.43 v1(100.34,66.15) 100.53,66.15 101.37,66.99 101.37,67.4 v2(101.39,67.42) 102.19,68.22 RH450.1
SYSTEM_FAN_FB: length 163.5
  TOP w0.076: 138.61,56.35 138.73,56.35 139.23,56.85 139.67,56.85 U34.M11
  TOP w0.102: v6(40.72,47.94) 40.82,47.84 51.99,47.84 52.72,47.1 68.63,47.1 68.88,47.36 80.37,47.36 v2(82.46,49.45) 83.81,50.8 87.17,50.8 88.37,52.01 v6(88.37,52.54) ; 138.61,56.35 v6(138.4,56.35) ; R884.1 6.44,22.35 D81.2 6.07,23.78 v1(6.07,25.01)
  GND1 w0.076: v4(40.72,47.56) v6(40.72,47.94) ; v4(88.75,52.51) 88.4,52.51 v6(88.37,52.54) ; v6(138.4,56.35) v4(137.94,56.35)
  IN1 w0.076: v4(40.72,47.56) 40.29,47.99 39.75,47.99 39.42,47.66 39.42,45.2 38.73,44.51 36.85,44.51 36.27,43.93 35.67,43.93 34.28,45.33 25.43,45.33 25.05,44.95 18.08,44.95 15.67,42.53 15.67,37.91 14.28,36.53 14.28,30.05 9.24,25.01 v1(6.07,25.01) ; v4(137.94,56.35) 137.81,56.22 135.3,56.22 133.84,57.68 131.03,57.68 130.08,56.73 126.94,56.73 126.39,56.18 121.22,56.18 120.95,56.45 118.47,56.45 117.96,56.96 114.56,56.96 113.98,57.54 108.67,57.54 106.38,55.26 103.52,55.26 101.69,53.43 89.58,53.43 88.75,52.6 v4(88.75,52.51)
SYSTEM_FAN_PWM: length 163.4
  TOP w0.102: v1(7.03,21.78) 6.76,21.78 R1103.1 ; v6(138.35,56.98) 138.73,57.37 139.18,57.37 U34.N10 ; v6(88.04,53) 88.04,51.96 87.09,51.02 83.55,51.02 80.09,47.56 68.8,47.56 68.54,47.31 53.04,47.31 v2(52.74,47.61) 52.25,48.09 49.69,48.09 49.61,48.17 40.93,48.17 40.85,48.25 40.44,48.25 v6(40.14,47.94)
  GND1 w0.076: v6(138.35,56.98) 138.34,57 v4(137.94,57) ; v4(40.14,47.56) v6(40.14,47.94) ; v4(88.46,53) v6(88.04,53)
  IN1 w0.076: v4(40.14,47.56) 40.06,47.49 39.94,47.49 39.64,47.19 39.64,45.18 38.8,44.34 36.92,44.34 36.29,43.7 35.56,43.7 34.11,45.15 25.51,45.15 25.12,44.77 18.23,44.77 15.87,42.41 15.87,37.75 14.47,36.35 14.47,29.86 7.03,22.42 v1(7.03,21.78) ; v4(137.94,57) 137.78,57.16 135.06,57.16 134.3,57.92 130.97,57.92 130.21,57.16 124.75,57.16 124.21,56.63 118.6,56.63 118.5,56.73 118.09,57.14 114.63,57.14 114.03,57.75 108.59,57.75 106.28,55.43 103.44,55.43 101.67,53.66 89.12,53.66 v4(88.46,53)
  BOTTOM w0.102: v1(7.03,21.78) 7.03,22.47 7.31,22.75 JFAN1.3
TABLET_MODE: length 112
  TOP w0.102: R1375.1 124.7,51.04 124.12,51.04 123.36,51.8 123.36,52.59 v2(123.11,52.84) 123.1,52.85 122.66,52.85 v1(122.55,52.74) ; v6(144.53,60.13) 144.53,59.49 U34.B7 ; R980.1 136.9,62.07 RP21.1 136.58,63.22 136.27,63.54 v1(136.27,66.18)
  GND1 w0.076: v4(144.7,60.6) 144.53,60.44 v6(144.53,60.13)
  IN1 w0.076: v4(144.7,60.6) 144.29,61.01 142.79,61.01 142.46,61.34 142.18,61.34 141.85,61.67 141.85,62.26 141.69,62.42 140.52,62.42 139.1,63.84 138.15,63.84 138.02,63.72 137.33,63.72 136.47,64.58 136.47,65.97 v1(136.27,66.18) 135.81,66.18 135.59,65.96 135.03,65.96 133.81,64.74 130.42,64.74 129.55,63.87 128.18,63.87 127.65,63.33 123.65,63.33 v4(123.45,63.13) ; v1(176.11,82.56) 176.06,82.61 172.56,82.61 171.6,83.58 158.8,83.58 157.73,82.51 148.95,82.51 146.61,80.18 137,80.18 135.76,81.42 v4(135.76,81.72)
  IN3 w0.076: v4(135.76,81.72) 135.48,81.45 135.48,77.18 134.04,75.74 134.04,67.4 135.26,66.18 v1(136.27,66.18) ; v4(123.45,63.13) 123.44,63.12 123.44,60.64 122.27,59.47 122.27,53.02 v1(122.55,52.74)
  BOTTOM w0.102: JLVDS2.18 176.74,81.93 v1(176.11,82.56)
TABLET_MODE_R: length 2
  TOP w0.102: UA1.7 125.11,48.54 125.47,48.89 125.47,49.35 R1375.2
TD_IREF: length 7.6
  BOTTOM w0.102: UCPU1.B12 89.05,79.31 89.05,80.72 v2(90.3,81.97) 90.72,82.38 93.08,82.38 93.61,82.91 93.61,83.01 RC155.1
TESTLOW1: length 10.1
  BOTTOM w0.102: v2(69.88,84.71) 69.88,84.12 RH76.1 70.81,82.17 72.55,80.43 75.13,80.43 75.45,80.11 75.45,79.08 75.77,78.76 UCPU1.C35
TESTLOW2: length 8.3
  BOTTOM w0.102: RH77.1 v2(71.7,82.17) 73.04,80.82 75.41,80.82 76.07,80.16 76.07,79.05 76.03,79.01 76.03,78.75 76.33,78.45 UCPU1.C34
TESTLOW3: length 2.1
  TOP w0.102: v6(92.65,63.33) 92.77,63.21 RH78.1
  GND1 w0.076: v6(92.65,63.33) 92.65,63.46 v4(92.4,63.72)
  GND5 w0.076: v5(91.92,63.56) 92.07,63.72 v4(92.4,63.72)
  BOTTOM w0.102: v5(91.92,63.56) 92.16,63.56 UCPU1.AK8
TESTLOW4: length 2.8
  TOP w0.102: v6(92.18,62.29) 92.18,62.57 91.98,62.78 RH79.1
  GND1 w0.076: v6(92.18,62.29) 92.18,62.82 v4(92.3,62.93)
  GND5 w0.076: v4(92.3,62.93) 92.03,63.21 v5(91.89,63.21)
  BOTTOM w0.102: v5(91.89,63.21) 92.32,62.78 UCPU1.AL8
TOUCH_EN: length 42.9
  TOP w0.102: R1382.1 126.18,61.95 126.68,62.45 126.68,65.2 126.31,65.57 125.29,65.57 124.97,65.25 121.54,65.25 v2(121.02,65.78) 120.21,66.59 v3(119.76,66.59)
  IN1 w0.076: v4(92.81,72.48) 93.07,72.48 93.8,71.75 95.89,71.75 96.43,72.29 97.53,72.29 99.14,70.68 100.25,70.68 102.16,68.77 103.21,68.77 104.42,67.56 106.82,67.56 107.15,67.89 108.44,67.89 v4(108.78,67.55)
  IN2 w0.076: v3(119.76,66.59) 119.17,66.59 118.88,66.88 112.82,66.88 112.38,67.32 109.01,67.32 v4(108.78,67.55)
  GND5 w0.076: v5(92.69,72.94) 92.81,72.82 v4(92.81,72.48)
  BOTTOM w0.076: UCPU1.N7 v5(92.69,72.94)
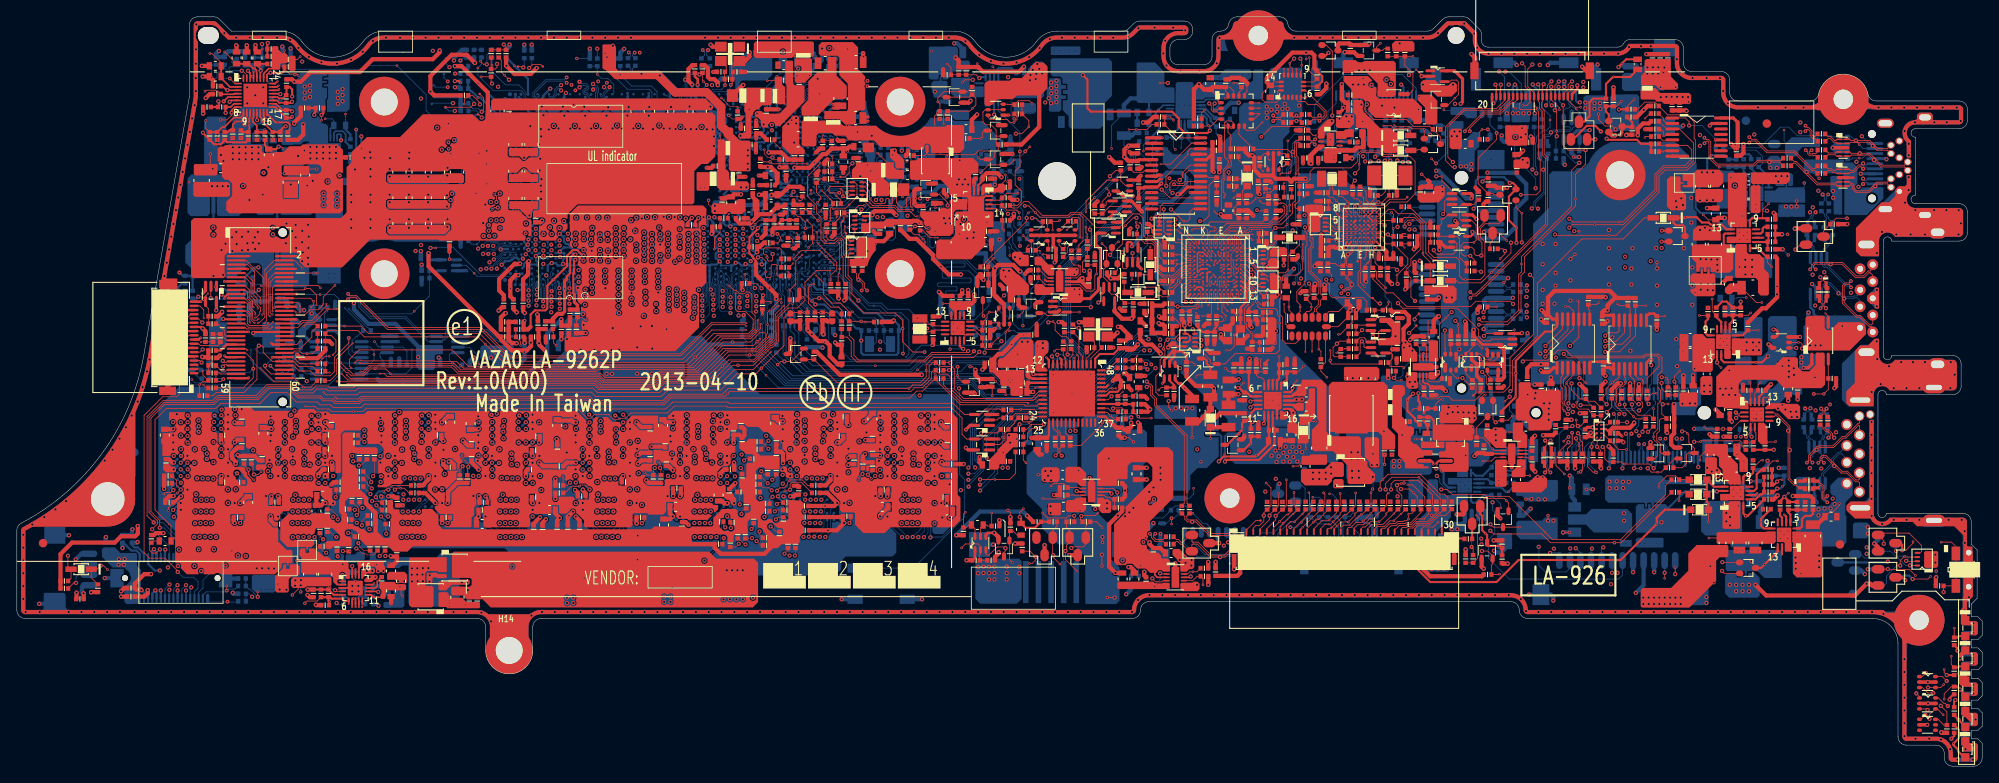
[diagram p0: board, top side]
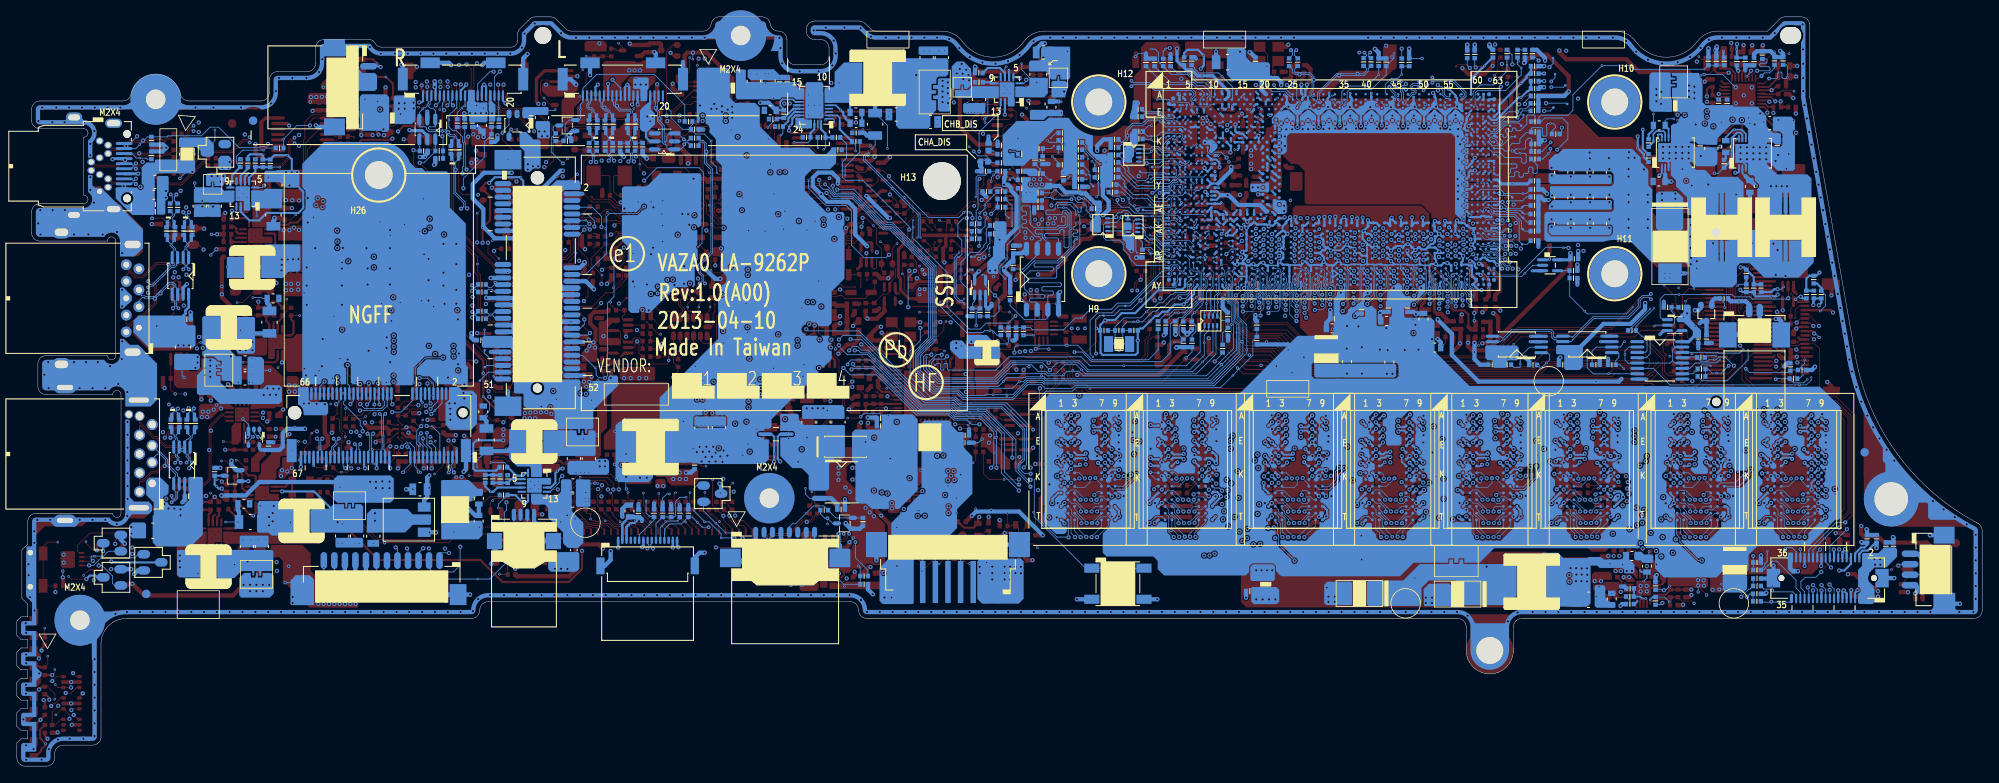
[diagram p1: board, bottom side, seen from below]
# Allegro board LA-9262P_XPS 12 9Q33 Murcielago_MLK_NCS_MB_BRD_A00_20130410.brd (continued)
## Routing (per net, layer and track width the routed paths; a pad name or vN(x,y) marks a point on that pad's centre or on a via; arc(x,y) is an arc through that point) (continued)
TOUCH_EN_R: length 5.1
  TOP w0.102: U719.5 125.91,58.02 126.33,58.44 126.33,59.33 v2(126.25,59.42) 126.12,59.55 125.62,59.55 125.29,59.88 R1160.1 R1382.2
TP_CLK: length 95.6
  TOP w0.102: v6(148.65,57.72) 148.45,57.92 RP15.6 147.71,57.92 147.53,58.1 147.53,58.79 146.22,60.1 U34.A5
  GND1 w0.076: v6(148.65,57.72) 148.77,57.59 v4(148.77,57.32)
  IN1 w0.076: v4(148.77,57.32) 148.28,56.82 148.28,55.31 149.15,54.43 149.15,49.79 149.73,49.21 154.83,49.21 155.41,48.63 166.44,48.63 168.84,46.23 168.84,43.25 167.48,41.89 167.48,36.15 168.04,35.59 168.04,29.47 165.41,26.84 153.82,26.84 153.59,27.06 v1(148.25,27.06)
  BOTTOM w0.102: DE2.2 152.71,33.35 153.05,33.01 153.05,30.35 151.72,29.02 151.21,29.02 149.83,27.64 v2(149.83,27.13) 148.32,27.13 v1(148.25,27.06) 146.15,24.96 140.2,24.96 138.72,26.44 JTP1.8
TP_DATA: length 91.9
  TOP w0.076: U34.B5 145.17,60.35 146.17,60.35 146.2,60.32 146.23,60.32
  TOP w0.102: v6(148.57,58.2) 148.36,58.42 RP15.5 148.06,58.55 147.74,58.87 147.73,58.87 146.28,60.32 146.23,60.32
  GND1 w0.076: v4(148.2,57.65) 148.2,57.84 v6(148.57,58.2)
  IN1 w0.076: v1(147.26,27.06) 147.7,27.5 153.44,27.5 153.92,27.01 165.33,27.01 167.86,29.54 167.86,35.52 167.31,36.08 167.31,41.97 168.57,43.23 168.57,46.25 166.36,48.46 155.31,48.46 154.73,49.03 149.65,49.03 148.95,49.73 148.95,54.38 148.1,55.23 148.1,57.54 v4(148.2,57.65)
  BOTTOM w0.102: JTP1.7 139.72,26.58 141.14,25.16 145.97,25.16 147.26,26.45 v1(147.26,27.06) 147.92,27.72 149.28,27.72 v2(150.44,28.88) 151.91,30.35 DE2.3
TP_INT#: length 91
  TOP w0.102: v3(137.19,29.46) v2(137.19,28.78)
  IN3 w0.076: v3(137.19,29.46) 135.79,30.86 135.05,30.86 132.71,33.2 127.56,33.2 124.52,36.23 119.41,36.23 118.17,34.99 115.41,34.99 113.65,36.75 112.97,36.75 112.16,37.57 112.16,43.47 110.23,45.4 109.77,45.4 105.35,49.82 105.35,53.97 102,57.33 102,59.79 105.95,63.74 105.95,64.38 106.46,64.88 106.46,65.87 106.19,66.14 106.19,70.12 105.33,70.98 v4(104.36,70.98)
  IN4 w0.076: v4(93.64,70.19) 93.89,69.95 96.82,69.95 97.03,70.17 97.62,70.17 97.88,70.43 98.43,70.43 98.83,70.84 99.58,70.84 99.95,71.2 104.14,71.2 v4(104.36,70.98)
  GND5 w0.076: v5(93.06,70.27) 93.57,70.27 v4(93.64,70.19) ; v4(104.36,70.98) 104.79,71.41 v5(104.79,71.56)
  BOTTOM w0.102: RH380.2 106.93,74.1 106.48,73.66 106.48,73.1 104.95,71.56 v5(104.79,71.56) ; R1387.1 138.03,30 137.5,29.46 v3(137.19,29.46) 136.58,28.85 Q364.1 ; UCPU1.U7 92.69,70.64 v5(93.06,70.27)
TP_INT#_R: length 11
  BOTTOM w0.102: R1299.2 132.98,29.5 Q364.3 136.19,29.5 R1387.2 137.61,30.92 138.86,30.92 v2(139.72,30.06) 140.96,28.82 141.35,28.82 141.72,28.44 JTP1.5
TPM_DET: length 36.5
  IN4 w0.076: v4(119.49,67.18) 119.08,66.78 113.28,66.78 112.5,67.55 109.61,67.55 109.03,68.12 106.75,68.12 106.35,67.73 101.93,67.73 101.27,67.07 100.16,67.07 99.41,66.32 97.32,66.32 97.23,66.24 96.62,66.24 96.35,65.96 95.51,65.96 95.22,65.67 93.59,65.67 93.34,65.42 v4(93.34,65.09)
  GND5 w0.076: v5(93.63,64.69) 93.34,64.99 v4(93.34,65.09) ; v4(119.49,67.18) 119.6,67.3 v5(119.6,67.61)
  BOTTOM w0.102: v5(93.63,64.69) 93.74,64.69 UCPU1.AG5 ; v2(117.72,69.48) 117.72,69.96 RH274.2 RH337.1 118.45,70.23 119.29,70.23 119.53,69.99 119.53,67.69 v5(119.6,67.61)
TPM_IRQ#: length 5.8
  BOTTOM w0.076: UCPU1.P4 95,72.17 97.32,72.17 97.37,72.12
  BOTTOM w0.102: 97.37,72.12 97.68,72.12 97.73,72.07 99.54,72.07 99.75,71.86 RP2.5
TPM_PWREN: length 73.1
  TOP w0.102: v6(154.36,74.96) 154.02,74.96 R1394.1 153.42,75.56 152.98,76.01 149.08,76.01 v2(148.65,75.58) v3(147.86,74.79)
  GND1 w0.076: v6(154.36,74.96) 154.96,74.35 v6(154.96,74.24)
  IN2 w0.076: v4(93.02,74.14) 93.56,73.61 94.41,73.61 94.73,73.29 95,73.29 96.03,72.25 99.71,72.25 101.57,70.4 104.67,70.4 104.76,70.48 106.23,70.48 107,69.71 110.34,69.71 110.83,69.23 110.83,69.08 111.39,68.52 117.09,68.52 117.99,69.42 119.08,69.42 121.86,66.64 125.05,66.64 127.79,69.38 131.96,69.38 132.52,69.94 136.86,69.94 v3(136.94,69.86)
  IN3 w0.076: v3(147.86,74.79) 147.86,72.55 147.06,71.75 138.37,71.75 136.94,70.32 v3(136.94,69.86)
  GND5 w0.076: v5(93.34,73.89) 93.28,73.89 v4(93.02,74.14)
  BOTTOM w0.076: v5(93.34,73.89) UCPU1.L6
TPM_RESET#: length 12.1
  TOP w0.102: U652.16 136.22,66.87 135.83,66.48 135.83,65.87 135.33,65.37 135.12,65.37 v1(134.82,65.06) ; U698.4 133.21,62.57 133.07,62.71 R1310.1 133.07,63.61 133.15,63.7 v1(133.15,64.11) 132.99,64.27 v2(132.99,64.63)
  IN4 w0.076: v1(134.82,65.06) 134.49,65.06 133.54,64.11 v1(133.15,64.11)
TPM_RST#: length 45.3
  TOP w0.102: U698.2 v1(132.56,60.96)
  IN2 w0.076: v1(132.56,60.96) 132.07,60.48 131.05,60.48 130.61,60.04 130.61,59.93 128.2,57.52 116.66,57.52 114.89,59.3 108.8,59.3 106.38,61.71 105.75,61.71 105.68,61.79 101.09,61.79 101.06,61.76 98.55,61.76 97.97,62.33 97.37,62.33 96.3,63.4 94.58,63.4 94.37,63.61 94.37,63.96 v4(93.96,64.36)
  GND5 w0.076: v4(93.96,64.36) 93.94,64.34 v5(93.57,64.34)
  BOTTOM w0.076: UCPU1.AG6 93.34,64.57 v5(93.57,64.34)
TRIP: length 4.8
  BOTTOM w0.102: PR508.2 143.31,76.9 144.27,75.95 v2(144.27,75.88)
  BOTTOM w0.254: PU501.20 141.22,78.14 142.32,77.04 PR505.2 143.09,77.04 PR508.2
TS_INT#: length 90.5
  TOP w0.102: v3(168.63,71.63) v2(168.08,72.17)
  IN4 w0.076: v4(95.12,72.38) 95.27,72.53 98.75,72.53 99.78,73.56 105.98,73.56 107.33,72.2 109.66,72.2 v4(109.93,72.47) 110.33,72.87 110.98,72.87 111.65,72.2 114.65,72.2 114.87,71.98 119.84,71.98 120.89,73.03 126.44,73.03 128.72,70.75 133.46,70.75 134.51,71.81 134.98,71.81 135.06,71.73 139.4,71.73 141.57,69.56 144.07,69.56 144.6,70.09 147.06,70.09 147.71,69.44 149.6,69.44 149.75,69.29 150.4,69.29 150.54,69.43 150.95,69.43 151.28,69.1 152.65,69.1 153.6,68.15 158.42,68.15 158.75,68.48 166.18,68.48 166.49,68.79 166.49,70.33 167.79,71.63 v3(168.63,71.63)
  GND5 w0.076: v4(95.12,72.38) 95.02,72.28 v5(95.02,71.67) ; v4(109.93,72.47) 109.75,72.64 v5(109.75,72.87)
  BOTTOM w0.102: UCPU1.P3 95.2,71.85 v5(95.02,71.67) ; Q363.1 169.59,76.14 169.79,75.93 169.79,75.51 R1384.1 169.95,74.73 169.95,72.95 v3(168.63,71.63) ; v5(109.75,72.87) 109.74,72.89 RH384.1
TS_INT#_R: length 25.1
  BOTTOM w0.102: R1389.2 154.15,78.6 157.75,82.21 164.6,82.21 166.25,80.56 JLVDS1.1 166.25,78.93 166.53,78.65 v2(166.53,78.05) 166.53,76.95 166.69,76.79 Q363.3 167.86,76.79 168.36,76.29 168.36,74.5 R1385.2 168.57,74.28 R1384.2
TS_RST#: length 74
  IN4 w0.076: v4(150.62,70.22) 150.51,70.32 149.52,70.32 149,69.8 147.85,69.8 147.21,70.45 144.45,70.45 143.92,69.91 141.72,69.91 139.65,71.98 139.55,72.09 135.2,72.09 135.13,72.16 134.37,72.16 133.31,71.11 128.87,71.11 126.59,73.39 120.69,73.39 119.68,72.38 115.03,72.38 114.75,72.66 111.86,72.66 111.08,73.43 109.77,73.43 109.11,74.09 99.55,74.09 98.61,73.15 98.03,73.15 97.66,73.52 97.31,73.52 v4(96.88,73.09)
  GND5 w0.076: v5(96.98,73.52) 96.98,73.19 v4(96.88,73.09) ; v4(150.62,70.22) v5(150.31,70.52)
  BOTTOM w0.102: v5(150.31,70.52) 150.35,70.56 150.35,71.17 151,71.82 v2(151,74.3) 151.82,75.12 152.86,75.12 R1376.1 ; UCPU1.L1 96.85,73.38 v5(96.98,73.52) ; JLVDS1.20 156.75,78.79 155.77,77.81 155.77,77.05 154.4,75.68 R1376.1 ; R1376.1 153.42,76.05 153.23,76.24 R1389.1
UART1_CTS#: length 124.1
  TOP w0.102: v2(193.58,54.72) RH460.1 192.3,54.35 192.31,54.33 U671.10 192.31,51.16 190.39,49.24 v1(188.72,49.24)
  IN1 w0.076: v4(95.26,74.42) 95.26,74.16 95.64,73.79 95.94,73.79 96.1,73.63 97.48,73.63 98.43,72.68 99.61,72.68 102.24,70.05 103.28,70.05 103.72,69.62 103.72,69.28 104.8,68.2 106.55,68.2 106.88,68.53 109.01,68.53 110.19,67.35 110.65,67.35 111.01,66.99 111.01,66.69 111.81,65.89 112.97,65.89 113.34,66.26 118.58,66.26 119.26,65.57 124.25,65.57 124.68,66 125.24,66 126.84,67.6 128.82,67.6 129.13,67.3 132.95,67.3 134.17,68.52 134.68,68.52 135.8,69.63 136.29,69.63 136.49,69.43 137.09,69.43 137.22,69.56 137.66,69.56 138.01,69.22 138.4,69.22 138.69,69.51 145.64,69.51 146.15,70.02 146.78,70.02 147.4,69.39 149.44,69.39 149.54,69.29 150.58,69.29 151.52,70.23 153.28,70.23 153.52,69.99 153.52,68.88 154.17,68.24 159.66,68.24 160.12,67.78 164.79,67.78 165.53,67.04 166.51,67.04 170.8,62.76 170.8,60.36 176.31,54.85 176.31,52.51 178.43,50.39 179.98,50.39 180.5,50.91 187.04,50.91 v1(188.72,49.24)
  GND5 w0.076: v4(95.26,74.42) 95.17,74.51 v5(94.85,74.51)
  BOTTOM w0.102: v5(94.85,74.51) 94.67,74.69 UCPU1.J4
UART1_CTS#_NGFF: length 11
  TOP w0.102: v1(192.73,42.27) 193.14,42.67 193.14,43.22 R1371.2 193.19,44.18 v2(193.19,45.63) 193.19,45.9 193.05,46.04 192.68,46.04 192.31,46.4 U671.5
  BOTTOM w0.102: v1(192.73,42.27) 192.72,42.28 190.05,42.28 189.49,42.83 JNGFF1.26
UART1_RTS#: length 122.4
  TOP w0.102: v2(190.16,54.95) 190.39,54.72 RH459.1 191.66,54.47 U671.11 191.66,51.09 190.72,50.15 189,50.15 v1(188.72,49.87)
  IN1 w0.076: v1(188.72,49.87) 187.47,51.12 180.41,51.12 179.89,50.6 178.51,50.6 176.51,52.6 176.51,54.94 171,60.45 171,62.84 166.6,67.25 165.62,67.25 164.88,67.98 160.21,67.98 159.75,68.44 154.26,68.44 153.73,68.97 153.73,70.08 153.37,70.43 151.41,70.43 150.79,69.81 150.46,69.81 150.16,70.12 149.71,70.12 149.19,69.6 147.49,69.6 146.87,70.22 146.06,70.22 145.58,69.74 140.79,69.74 140.08,70.45 136.93,70.45 136.34,69.86 135.7,69.86 134.79,68.95 133.31,68.95 132.82,68.47 127.41,68.47 125.15,66.21 124.6,66.21 124.17,65.77 119.35,65.77 118.66,66.46 113.26,66.46 112.89,66.09 111.89,66.09 111.21,66.77 111.21,67.08 110.73,67.55 110.27,67.55 109.06,68.77 106.52,68.77 106.31,68.55 104.73,68.55 103.92,69.37 103.92,69.73 103.36,70.29 102.29,70.29 99.45,73.13 98.28,73.13 97.56,73.85 96.15,73.85 v4(95.79,74.21)
  GND5 w0.076: v4(95.79,74.21) 95.64,74.36 v5(95.64,74.7)
  BOTTOM w0.102: v5(95.64,74.7) 95.5,74.84 UCPU1.J3
UART1_RTS#_NGFF: length 10
  TOP w0.102: v1(192.7,43.03) 192.49,43.03 192.03,43.48 191.85,43.48 R1370.2 192.17,44.18 192.17,45.87 191.66,46.38 U671.4
  BOTTOM w0.102: v1(192.7,43.03) 192.18,42.51 190.15,42.51 189.81,42.85 189.81,43.33 190,43.52 JNGFF1.28
UART1_RXD: length 121.4
  TOP w0.102: v1(188.72,50.53) 188.77,50.48 189.99,50.48 191.01,51.51 U671.12
  IN1 w0.076: v4(98.2,74.54) 98.2,74.33 98.53,74 98.87,74 102.36,70.51 103.43,70.51 104.12,69.82 104.12,69.47 104.74,68.85 106.22,68.85 106.45,69.08 109.04,69.08 110.36,67.75 110.82,67.75 111.41,67.16 111.41,66.86 111.98,66.29 112.8,66.29 113.17,66.66 118.74,66.66 119.43,65.98 124.08,65.98 124.51,66.41 125.07,66.41 127.35,68.69 132.45,68.69 133.13,69.37 133.91,69.37 134.73,70.18 135.87,70.18 136.39,70.7 140.22,70.7 140.98,69.94 145.49,69.94 145.98,70.42 146.95,70.42 147.57,69.8 148.95,69.8 149.8,70.65 153.44,70.65 153.93,70.16 153.93,69.05 154.34,68.64 159.83,68.64 160.29,68.19 164.96,68.19 165.7,67.45 166.68,67.45 171.2,62.93 171.2,60.53 176.71,55.02 176.71,52.68 178.6,50.8 179.81,50.8 180.33,51.32 187.93,51.32 v1(188.72,50.53)
  GND5 w0.076: v4(98.2,74.54) 97.97,74.31 v5(97.97,74.23)
  BOTTOM w0.076: 97.14,75.07 97.01,75.2 95.26,75.2 95.03,74.97 95.03,74.69 95.13,74.59 95.13,74.43 94.87,74.17 UCPU1.K4
  BOTTOM w0.102: RH457.1 99.31,74.54 99.23,74.46 v2(98.72,74.46) 98.5,74.23 v5(97.97,74.23) 97.14,75.07
UART1_RXD_NGFF: length 10.1
  TOP w0.102: U671.3 191.01,46.24 191.1,46.15 v2(191.1,45.66) 191.1,45.42 190.79,45.1 190.38,45.1 190.05,44.77 190.05,44.26 189.49,43.7 R1369.2 189.49,42.67 v1(188.89,42.08)
  BOTTOM w0.102: JNGFF1.22 186.49,43.43 187.85,42.08 v1(188.89,42.08)
UART1_TXD: length 118.1
  TOP w0.102: v1(188.72,51.17) 189.05,51.5 190.16,51.5 190.36,51.7 U671.13
  IN1 w0.076: v1(188.72,51.17) 188.36,51.52 180.25,51.52 179.72,51 178.68,51 176.92,52.77 176.92,55.11 171.41,60.62 171.41,63.01 166.77,67.65 165.78,67.65 165.05,68.39 160.37,68.39 159.62,69.14 159.62,70.68 159.27,71.03 154.97,71.03 154.79,70.85 146.12,70.85 145.41,70.14 141.14,70.14 140.38,70.9 136.29,70.9 135.77,70.38 134.64,70.38 133.83,69.58 133.03,69.58 132.35,68.89 127.27,68.89 124.98,66.61 124.43,66.61 124,66.18 119.51,66.18 118.83,66.87 113.09,66.87 112.72,66.5 112.06,66.5 111.61,66.94 111.61,67.25 110.9,67.96 110.45,67.96 109.13,69.28 107,69.28 106.15,70.13 104.1,70.13 103.51,70.71 102.44,70.71 98.79,74.37 v4(98.79,74.41)
  GND5 w0.076: v5(98.71,74.87) 98.79,74.79 v4(98.79,74.41)
  BOTTOM w0.076: 97.37,75.35 96.26,75.35 UCPU1.G2
  BOTTOM w0.102: 97.37,75.35 97.54,75.35 98.03,74.87 v5(98.71,74.87) 99.18,74.87 RH458.1 99.04,76.12 v2(98.7,76.12)
UART1_TXD_NGFF: length 6.8
  TOP w0.076: v2(189.59,45.59) 189.54,45.54
  TOP w0.102: v2(189.59,45.59) 189.96,45.96 190.09,45.96 190.36,46.24 U671.2 ; v1(188.88,43) 188.23,43.65 R1368.2 188.81,44.25 188.81,44.82 189.53,45.54 189.54,45.54
  BOTTOM w0.102: v1(188.88,43) 189,43.12 JNGFF1.24
UART_WAKE#: length 131.7
  IN4 w0.076: v1(182.86,48.55) 182.86,53.73 181.88,54.71 181.88,62.43 181.37,62.94 181.37,67.04 180.44,67.98 179.39,67.98 179.01,68.36 178.54,68.36 175.98,65.8 171.22,65.8 166.19,60.77 161.33,60.77 160.19,61.91 158.6,61.91 158.39,61.7 158.39,61.23 157.97,60.81 153.59,60.81 152.61,61.79 150.82,61.79 150.59,62.01 147.72,62.01 147.4,61.69 146.16,61.69 145.71,61.24 145.71,60.17 144.24,58.7 144.24,58.47 143.47,57.7 142.69,57.7 142.31,57.32 141.85,57.32 141.69,57.15 141.03,57.15 140.63,57.54 140.18,57.54 139.72,58 139.22,58 139.01,57.78 137.9,57.78 135.85,59.83 134.22,59.83 133.71,60.34 133.71,61.37 132.71,62.37 132.09,62.37 131.83,62.12 129.37,62.12 128.99,61.73 122.12,61.73 121.17,60.78 120.58,60.78 120.37,60.57 119.68,60.57 v4(119.3,60.95) 118.32,60.95 118.04,60.67 110.51,60.67 107.79,63.39 102.95,63.39 101.72,62.15 98.71,62.15 98.53,61.98 95.92,61.98 v4(95.75,62.14)
  GND5 w0.076: v4(95.75,62.14) 95.42,61.81 v5(94.99,61.81) ; v5(119.68,60.55) 119.68,60.64 119.37,60.95 v4(119.3,60.95)
  BOTTOM w0.102: UCPU1.AM3 95.32,62.14 v5(94.99,61.81) ; T288.1 119.7,60.53 v5(119.68,60.55) 119.44,60.79 118.98,60.79 118.18,61.59 118.18,61.86 117.89,62.15 RH383.1 ; JNGFF1.20 186,45.03 186.16,45.2 186.16,47.31 184.94,48.53 183.01,48.53 182.99,48.55 v1(182.86,48.55)
USB0_PWR_EN: length 172.4
  TOP w0.102: v3(213.49,44.23) v7(214.69,44.23) 215.22,44.77 R1217.2 215.22,46.08 US2.4
  IN4 w0.076: v4(100.67,63.12) 101.92,63.12 103.09,64.29 106.29,64.29 106.56,64.55 106.89,64.55 107.37,64.07 107.98,64.07 110.45,61.61 116.59,61.61 117.51,62.52 119.1,62.52 119.37,62.24 124.05,62.24 124.76,62.95 130.97,62.95 131.13,63.12 132.51,63.12 133.6,62.03 135.06,62.03 137.1,59.98 137.57,59.98 138.19,59.36 139.1,59.36 139.57,59.83 140.25,59.83 140.94,60.52 141.43,60.52 141.59,60.67 141.59,61.48 141.85,61.75 141.85,62.34 142.49,62.98 142.49,63.41 143.2,64.12 143.64,64.12 144.24,64.73 147.36,64.73 147.82,64.27 149.16,64.27 149.63,64.73 153.13,64.73 153.35,64.95 154.76,64.95 155.29,65.48 156.5,65.48 156.81,65.16 158.26,65.16 159.31,64.11 161.45,64.11 162.38,65.04 164.93,65.04 165.12,65.23 166.87,65.23 167.87,66.22 170.09,66.22 173.35,69.48 173.35,70.05 174.25,70.95 175.11,70.95 175.72,70.35 177.21,70.35 177.81,69.75 177.81,69.15 178.05,68.91 180,68.91 180.19,69.1 180.66,69.1 181.73,68.03 181.73,64.81 183.29,63.25 183.29,47.66 183.5,47.46 183.5,39.77 183.64,39.63 183.64,38.35 184.13,37.86 185.77,37.86 186.73,38.82 189.45,38.82 190.6,37.68 197.75,37.68 203.23,43.17 204.29,43.17 206.06,44.95 212.78,44.95 v3(213.49,44.23)
  GND5 w0.076: v5(100.22,62.73) 100.61,63.12 v4(100.67,63.12)
  BOTTOM w0.076: UCPU1.AT3 95.35,59.86 95.68,60.19 97.02,60.19 97.33,60.49 97.37,60.49
  BOTTOM w0.102: v5(100.22,62.73) 99.77,62.27 RH400.1 99.66,61.38 99.41,61.63 98.78,61.63 97.63,60.49 97.37,60.49
USB1_CTL1: length 95.6
  TOP w0.076: U34.B4 145.17,60.85 146.23,60.85
  TOP w0.102: v6(146.61,60.9) 146.57,60.85 146.23,60.85 ; R1166.2 204.96,38.06 204.96,38.44 204.73,38.67 200.13,38.67 v2(200.04,38.58) 200.01,38.54 v1(199.28,38.54)
  GND1 w0.076: v6(146.61,60.9) 146.78,60.9 v4(147.02,60.66)
  IN4 w0.076: v4(147.02,60.66) 147.33,60.96 147.75,60.96 147.96,61.18 148.58,61.18 149.22,60.54 152.46,60.54 152.55,60.45 159.33,60.45 159.48,60.3 160.97,60.3 162.91,58.36 168.09,58.36 171.8,62.06 173.58,62.06 179.01,67.5 180.5,67.5 181.2,66.8 181.2,62.87 181.71,62.36 181.71,54.48 182.37,53.82 182.37,48.22 183.32,47.27 183.32,39.66 183.46,39.52 183.46,38.28 184.06,37.68 185.84,37.68 186.81,38.65 189.38,38.65 190.52,37.5 198.24,37.5 v1(199.28,38.54)
USB1_DET#: length 125
  TOP w0.102: v2(130.89,62.32) 130.81,62.32 D104.1 130.11,60.99 v1(129.89,60.77)
  IN2 w0.076: v4(139.87,69.91) 140.1,69.68 142.36,69.68 142.6,69.44 145.44,69.44 145.76,69.13 149.21,69.13 149.84,68.49 152.88,68.49 153.87,67.5 155.4,67.5 156.88,66.02 158.03,66.02 158.68,65.37 159.53,65.37 163.28,61.62 164.94,61.62 165.65,60.91 167.07,60.91 168,59.98 171.61,59.98 177.88,53.71 177.88,44.18 178.94,43.13 178.94,39 181.13,36.8 200.29,36.8 201.57,38.09 216.01,38.09 216.59,38.67 216.59,40.96 218.07,42.43 219.56,42.43 JUSB1.10
  GND5 w0.076: v4(139.87,69.91) 139.64,69.68 139.45,69.68 v5(139.44,69.7)
  BOTTOM w0.102: v1(129.89,60.77) 130.23,60.43 132.85,60.43 134.32,61.9 134.32,65.95 135.01,66.64 137.4,66.64 139.44,68.68 v5(139.44,69.7)
USB1_DET_EC#: length 23.5
  TOP w0.081: v6(143.92,62.45) 143.92,62.11 U34.D1
  TOP w0.102: v1(133.01,65.16) 132.65,65.16 131.73,64.25 v2(131.73,64.24) 131.38,63.88 131.38,62.08 130.76,61.46 D104.3 130.76,58.96 R1156.2
  GND1 w0.076: v6(143.92,62.45) v4(144.43,62.45)
  IN1 w0.076: v4(144.43,62.45) 144.27,62.61 140.6,62.61 139.17,64.03 138.06,64.03 137.93,63.91 137.42,63.91 136.7,64.63 136.7,66.34 136.44,66.6 135.85,66.6 135.44,66.19 134.12,66.19 133.09,65.16 v1(133.01,65.16)
USB1_PWR_EN: length 143.6
  TOP w0.102: v1(99.99,55.33) 99.21,56.12 99.21,57.84 98.76,58.28 98.76,60.69 99,60.93 RP11.4
  IN4 w0.076: v3(105.28,49.03) 106.76,49.03 107.2,48.6 108.94,48.6 112.24,51.9 114.6,51.9 115.95,53.25 125.62,53.25 127.34,54.98 127.88,54.98 128.19,54.67 129.7,54.67 132.63,51.74 132.63,47.59 133.83,46.39 139.75,46.39 141.18,47.83 147.37,47.83 147.56,47.64 148.74,47.64 149.51,48.41 170.21,48.41 171.01,47.61 176.09,47.61 178.33,45.37 178.33,44.15 178.79,43.69 178.79,41.39 179.76,40.42 179.76,38.71 183.51,34.96 198.37,34.96 199.5,36.09 201.18,36.09 v3(204.22,39.14)
  BOTTOM w0.076: 97.37,56.86 95.91,56.86 95.68,57.09 95.68,57.52 95.63,57.57 95.63,58.22 UCPU1.AV3
  BOTTOM w0.102: v3(204.22,39.14) 204.68,39.6 U699.1 ; 97.37,56.86 98.47,56.86 v1(99.99,55.33) 101.09,54.24 102.45,54.24 103.14,53.54 T292.1 104.86,53.54 105.35,53.05 105.35,49.11 v3(105.28,49.03)
USB1_PWR_EN_EC: length 94.2
  TOP w0.102: U34.M1 139.92,62.11 138.97,63.06 138.63,63.06 138.32,63.36 v6(138.23,63.36) 137.87,63.72 RP21.2
  GND1 w0.076: v4(138.68,63.08) 138.4,63.36 v6(138.23,63.36)
  IN2 w0.076: v4(138.68,63.08) 139.79,63.08 140.5,63.79 141.39,63.79 141.64,64.05 142.45,64.05 143.41,65.01 143.68,65.01 144.31,65.63 144.66,65.63 145.08,65.21 147.87,65.21 148.2,65.54 149.22,65.54 149.75,65.01 154.17,65.01 155.37,63.82 155.98,63.82 156.47,63.33 156.87,63.33 158.06,62.14 159.95,62.14 161.08,61.01 161.35,61.01 162.96,59.4 164.7,59.4 165.36,58.74 171.07,58.74 174.98,54.83 174.98,54.01 v3(174.28,53.31)
  IN4 w0.076: v3(204.83,39.14) 204.44,39.54 204.03,39.54 200.77,36.27 199.43,36.27 198.98,35.83 182.9,35.83 179.94,38.79 179.94,40.49 178.96,41.47 178.96,43.76 178.51,44.22 178.51,45.45 178.49,45.46 178.49,45.48 175.23,48.74 175.23,52.74 174.66,53.31 v3(174.28,53.31)
  BOTTOM w0.102: v3(204.83,39.14) 205.33,39.64 U699.2
USB3RN0: length 148.5
  IN2 w0.076: v1(213.05,65.82) 213.12,65.82 213.36,65.59 213.36,65.48 213.2,65.32 212.72,65.32 212.06,65.99 212.06,69.76 211.13,70.69 208.12,70.69 207.37,71.44 199.71,71.44 193.26,64.99 185.29,64.99 184.88,64.58 176.09,64.58 175.81,64.3 168,64.3 166.96,65.34 163.79,65.34 162.34,66.79 159.47,66.79 157.61,68.64 154.35,68.64 153.72,69.28 153.72,70.15 153.37,70.5 152.27,70.5 151.34,71.42 145.65,71.42 145.23,71.84 139.39,71.84 139.03,72.2 133.79,72.2 133.51,71.92 128.76,71.92 127.11,73.57 121.9,73.57 120.3,71.97 111.36,71.97 111.03,71.64 109.96,71.64 109.46,72.15 108.74,72.15 107.17,73.72 101.3,73.72 98.33,76.7 97.12,76.7 96.92,76.9 95.54,76.9 95.16,76.52 93.53,76.52 93.02,76 91.89,76 91.03,75.15 88.55,75.15 88.07,75.63 85.31,75.63 85.2,75.74 v4(85.2,75.95)
  GND5 w0.076: v5(85.85,75.93) 85.64,75.73 85.42,75.73 v4(85.2,75.95)
  BOTTOM w0.102: R893.1 212.78,64.15 ML54.4 212.78,64.79 213.07,65.08 213.07,65.28 213.28,65.48 213.28,65.6 v1(213.05,65.82) ; UCPU1.G20 v5(85.85,75.93)
USB3RN0_RC_CON: length 14.1
  TOP w0.102: v3(213.06,59.04) 213.25,59.23 213.25,59.55 213.56,59.86 215.2,59.86 215.22,59.88 215.78,59.88 215.8,59.86 216.93,59.86 218.53,58.27 219.38,58.27 219.97,58.85 220.18,58.85 220.5,59.16 JUSB2.5
  BOTTOM w0.102: R893.2 212.78,63.02 ML54.3 212.78,62.46 213.07,62.17 213.07,61.89 213.31,61.65 213.31,61.39 213.09,61.17 MD82.1 213.09,59.75 213.3,59.54 213.3,59.28 v3(213.06,59.04)
USB3RN1: length 173.5
  IN2 w0.076: v4(86.82,77.2) 86.67,77.06 86.37,77.06 86.21,76.9 86.21,76.39 86.56,76.04 87.42,76.04 88.82,77.44 93.66,77.44 94.27,78.04 97.21,78.04 98.1,77.15 98.64,77.15 101.61,74.18 107.37,74.18 108.67,72.89 110.9,72.89 111.31,72.48 120.09,72.48 121.75,74.14 127.72,74.14 128.67,73.19 130.96,73.19 131.1,73.33 133.61,73.33 134.28,72.66 139.24,72.66 139.59,72.3 145.51,72.3 145.93,71.88 148.66,71.88 149.18,72.4 152.01,72.4 153.46,70.95 158.2,70.95 158.34,70.82 158.34,68.7 159.79,67.25 166.25,67.25 167.46,66.04 170.19,66.04 170.73,65.49 193.07,65.49 199.5,71.92 210.95,71.92 213.33,69.55 213.33,67.62 215.36,65.58 215.36,44.75 213.81,43.2 212.91,43.2 212.68,42.97 212.68,42.72 v8(212.47,42.51)
  GND5 w0.076: v5(86.05,77.1) 86.24,76.91 86.54,76.91 86.82,77.19 v4(86.82,77.2)
  BOTTOM w0.102: ML46.4 212.4,41.88 212.69,42.17 212.69,42.28 v8(212.47,42.51) ; UCPU1.E18 86.27,77.1 v5(86.05,77.1)
USB3RN1_RC_CON: length 14.2
  TOP w0.102: v3(212.68,36.08) 212.88,36.28 212.88,36.95 213.47,37.54 213.47,37.57 213.86,37.96 213.89,37.96 213.99,38.07 215.76,38.07 216.88,39.18 217.2,39.18 218.7,40.68 218.8,40.68 218.92,40.81 JUSB1.5
  BOTTOM w0.102: R560.2 212.4,40.16 ML46.3 212.4,39.58 212.67,39.31 212.67,39.04 212.91,38.8 MD74.1 212.91,37.29 213.17,37.02 213.17,36.88 212.92,36.63 212.92,36.32 v3(212.68,36.08)
USB3RP0: length 148.6
  IN2 w0.076: v8(213.72,65.83) 213.51,65.62 213.51,65.42 213.26,65.17 212.66,65.17 211.91,65.93 211.91,69.7 211.07,70.54 208.06,70.54 207.31,71.29 199.78,71.29 193.33,64.83 185.35,64.83 184.94,64.43 176.16,64.43 175.88,64.15 167.94,64.15 166.9,65.19 163.72,65.19 162.28,66.64 159.4,66.64 157.55,68.49 154.29,68.49 153.56,69.22 153.56,70.09 153.31,70.35 152.2,70.35 151.28,71.27 145.59,71.27 145.17,71.69 139.33,71.69 138.97,72.05 133.85,72.05 133.57,71.77 128.7,71.77 127.05,73.42 121.97,73.42 120.37,71.82 111.42,71.82 111.09,71.49 109.9,71.49 109.39,72 108.68,72 107.11,73.57 101.24,73.57 98.27,76.54 97.06,76.54 96.86,76.75 95.6,76.75 95.22,76.37 93.59,76.37 93.08,75.85 91.95,75.85 91.09,74.99 88.49,74.99 88.01,75.48 85.37,75.48 v4(85.19,75.3)
  GND5 w0.076: v4(85.19,75.3) 85.47,75.58 85.67,75.58 v5(85.85,75.4)
  BOTTOM w0.102: v5(85.85,75.4) 85.73,75.28 UCPU1.H20 ; R892.1 213.58,64.15 ML54.1 213.58,64.79 213.28,65.09 213.28,65.19 213.49,65.4 213.49,65.6 v8(213.72,65.83)
USB3RP0_RC_CON: length 14.1
  TOP w0.102: v3(213.72,59.04) 213.46,59.31 213.46,59.47 213.64,59.65 v1(215.5,59.65) 216.85,59.65 218.44,58.06 219.47,58.06 220.05,58.64 220.2,58.64 220.5,58.34 JUSB2.6
  BOTTOM w0.102: R892.2 213.58,63.02 ML54.2 213.58,62.44 213.28,62.14 213.28,61.98 213.52,61.74 213.52,61.39 213.74,61.17 MD82.2 213.74,59.77 213.51,59.54 213.51,59.26 213.72,59.04 v3(213.72,59.04)
USB3RP1: length 173.4
  IN2 w0.076: v4(86.82,76.62) 86.82,76.73 86.64,76.91 86.44,76.91 86.37,76.83 86.37,76.45 86.62,76.19 87.36,76.19 88.75,77.59 93.6,77.59 94.2,78.19 97.28,78.19 98.17,77.3 98.7,77.3 101.67,74.33 107.44,74.33 108.73,73.04 110.97,73.04 111.37,72.63 120.02,72.63 121.69,74.29 127.78,74.29 128.73,73.34 130.89,73.34 131.03,73.48 133.67,73.48 134.35,72.81 139.3,72.81 139.66,72.45 145.57,72.45 145.99,72.03 148.6,72.03 149.12,72.56 152.08,72.56 153.52,71.11 158.26,71.11 158.49,70.88 158.49,68.76 159.85,67.4 166.31,67.4 167.52,66.19 170.25,66.19 170.8,65.65 193.01,65.65 199.44,72.07 211.02,72.07 213.48,69.61 213.48,67.68 215.51,65.65 215.51,44.69 213.87,43.05 212.97,43.05 212.83,42.9 212.83,42.72 213.02,42.53 v1(213.1,42.53)
  GND5 w0.076: v4(86.82,76.62) 86.68,76.76 86.27,76.76 86.02,76.52 v5(86.02,76.49)
  BOTTOM w0.102: UCPU1.F18 86.12,76.59 v5(86.02,76.49) ; v1(213.1,42.53) 212.9,42.33 212.9,42.17 213.2,41.88 ML46.1
USB3RP1_RC_CON: length 14.3
  TOP w0.102: JUSB1.6 218.92,40.42 218.87,40.47 218.78,40.47 217.29,38.98 216.96,38.98 215.85,37.86 214.08,37.86 v1(213.83,37.6) 213.09,36.87 213.09,36.33 v3(213.34,36.08)
  BOTTOM w0.102: R565.2 213.2,40.16 ML46.2 213.2,39.53 212.88,39.21 212.88,39.12 213.15,38.85 213.28,38.85 213.56,38.57 MD74.2 213.56,37.25 213.38,37.07 213.38,36.79 213.13,36.54 213.13,36.29 v3(213.34,36.08)
USB3TN0: length 154.8
  IN2 w0.076: v4(77.13,78.37) 77.07,78.3 76.92,78.3 76.79,78.43 76.79,78.65 77,78.85 83.77,78.85 84.43,78.19 91.73,78.19 92.18,78.65 93.71,78.65 94.19,79.13 96.98,79.13 98.36,77.76 99.07,77.76 102.04,74.79 108.3,74.79 109.56,73.53 118.8,73.53 120.02,74.75 130.25,74.75 130.92,74.08 138.69,74.08 139.76,73.01 152.28,73.01 153.23,72.06 155.56,72.06 156.04,71.58 158.47,71.58 159.4,70.65 159.4,68.58 160.12,67.86 166.76,67.86 167.9,66.71 179.67,66.71 179.83,66.87 181.88,66.87 182.44,66.31 193.01,66.31 194.33,67.63 199.23,72.53 211.25,72.53 214.93,68.85 214.93,68.26 214.61,67.93 v8(214.55,67.93)
  GND5 w0.076: v5(77.1,78.88) 77.03,78.88 76.91,78.77 76.91,78.59 v4(77.13,78.37)
  BOTTOM w0.102: v8(214.55,67.93) 214.76,67.72 214.76,67.24 C1107.1 ; UCPU1.C33 76.9,78.68 v5(77.1,78.88)
USB3TN0_C: length 1.9
  BOTTOM w0.102: ML53.4 214.81,64.81 215.03,65.04 215.03,65.14 214.76,65.41 214.76,65.59 C1107.2
USB3TN0_RC_CON: length 17.2
  TOP w0.102: v3(217.91,56.9) 217.91,57.02 217.71,57.22 217.28,57.22 217.1,57.05 v1(217.1,55.56) 217.1,55.09 218.64,53.56 219.05,53.56 220.15,52.45 220.35,52.45 220.5,52.6 JUSB2.8
  BOTTOM w0.102: R890.2 214.81,63.02 ML53.3 214.81,62.39 215.07,62.12 215.07,61.96 214.63,61.51 214.63,61.31 214.39,61.07 MD82.3 214.39,59.85 214.54,59.7 214.54,59.47 214.77,59.24 215.12,59.24 217.32,57.05 217.76,57.05 v3(217.91,56.9)
USB3TN1: length 185.9
  TOP w0.102: v8(215.24,39.03) 215.5,39.3 215.5,39.43 215.18,39.76 214.94,39.76 214.6,40.11 214.6,40.25 C621.1
  IN2 w0.076: v8(215.24,39.03) 215.34,39.03 215.54,39.24 215.54,41.55 216.38,42.38 216.38,68.35 211.59,73.14 198.88,73.14 192.83,67.09 182.67,67.09 181.78,67.98 180.18,67.98 179.8,68.36 178.16,68.36 177.71,67.91 171.04,67.91 170.45,67.32 168.54,67.32 167.39,68.47 160.4,68.47 160.01,68.85 160.01,70.99 159.44,71.56 159.44,72.11 158.86,72.69 153.49,72.69 152.56,73.62 140.02,73.62 138.96,74.69 131.25,74.69 130.56,75.37 119.74,75.37 118.96,74.59 109.53,74.59 108.69,75.43 103.11,75.43 100.1,78.44 98.56,78.44 97.35,79.64 77.35,79.64 77.32,79.61 76.82,79.61 76.7,79.49 v4(76.7,79.34)
  GND5 w0.076: v4(76.7,79.34) 76.84,79.2 v5(77.26,79.2)
  BOTTOM w0.102: v5(77.26,79.2) 77.2,79.26 76.95,79.26 UCPU1.B33
USB3TN1_C: length 2.8
  TOP w0.102: C621.2 214.6,41.84 214.6,42.26 v1(214.37,42.48)
  BOTTOM w0.102: R555.1 214.18,41.22 214.29,41.32 ML45.4 214.29,41.87 214.59,42.17 214.59,42.26 v1(214.37,42.48)
USB3TN1_RC_CON: length 12.3
  TOP w0.102: JUSB1.8 218.92,34.1 218.84,34.02 218.53,34.02 217.5,35.04 216.84,35.04 216.31,35.58 216.31,35.61 215.87,36.04 215.84,36.04 214.96,36.92 214.49,36.92 214.25,36.68 214.25,36.28 v3(214.03,36.06)
  BOTTOM w0.102: R555.2 214.29,40.16 ML45.3 214.29,39.62 214.59,39.32 214.59,39.14 214.45,38.99 214.45,38.77 214.21,38.54 MD74.3 214.21,37.32 214.46,37.07 214.46,36.91 214.25,36.71 214.25,36.28 v3(214.03,36.06)
USB3TP0: length 154.9
  IN2 w0.076: v4(76.46,78.36) 76.64,78.55 76.64,78.71 76.93,79.01 83.83,79.01 84.49,78.35 91.66,78.35 92.12,78.8 93.64,78.8 94.13,79.29 97.05,79.29 98.42,77.91 99.13,77.91 102.1,74.94 108.36,74.94 109.62,73.69 118.74,73.69 119.96,74.9 130.31,74.9 130.98,74.23 138.75,74.23 139.82,73.16 152.34,73.16 153.3,72.21 155.62,72.21 156.1,71.73 158.54,71.73 159.56,70.71 159.56,68.64 160.19,68.01 166.82,68.01 167.96,66.87 179.61,66.87 179.76,67.02 181.95,67.02 182.51,66.46 192.95,66.46 194.18,67.69 194.18,67.69 199.17,72.68 211.31,72.68 215.09,68.91 215.09,68.06 v3(215.21,67.94)
  GND5 w0.076: v5(76.67,78.87) 76.76,78.78 76.76,78.58 76.54,78.36 76.46,78.36 v4(76.46,78.36)
  BOTTOM w0.102: UCPU1.B34 76.43,78.97 76.57,78.97 v5(76.67,78.87) ; C1108.1 214.97,67.19 214.97,67.7 v3(215.21,67.94)
USB3TP0_C: length 1.9
  BOTTOM w0.102: C1108.2 215.28,65.95 214.97,65.63 214.97,65.49 215.24,65.22 215.24,65.08 215.61,64.71 ML53.1
USB3TP0_RC_CON: length 17.1
  TOP w0.102: v3(217.9,57.65) 217.69,57.43 217.19,57.43 216.89,57.13 216.89,55.86 216.87,55.84 216.87,55.29 216.89,55.27 216.89,55.01 218.55,53.35 218.96,53.35 220.07,52.24 220.31,52.24 220.5,52.05 JUSB2.9
  BOTTOM w0.102: v3(217.9,57.65) 217.9,57.5 217.66,57.26 217.4,57.26 215.21,59.45 214.86,59.45 214.75,59.56 214.75,59.65 215.04,59.94 MD82.4 215.04,61.12 214.84,61.32 214.84,61.42 215.28,61.87 215.28,62.11 215.61,62.43 ML53.2 215.61,63.02 R891.2
USB3TP1: length 185.9
  TOP w0.102: C623.1 214.8,40.25 214.8,40.19 215.03,39.97 215.26,39.97 215.71,39.52 215.71,39.24 v1(215.91,39.04)
  IN2 w0.076: v1(215.91,39.04) 215.7,39.26 215.7,41.48 216.53,42.32 216.53,68.41 211.65,73.29 198.81,73.29 192.77,67.25 182.73,67.25 181.85,68.14 180.25,68.14 179.86,68.52 178.1,68.52 177.64,68.06 170.97,68.06 170.39,67.48 168.6,67.48 167.46,68.62 160.46,68.62 160.17,68.91 160.17,71.05 159.6,71.62 159.6,72.17 158.92,72.85 153.55,72.85 152.62,73.77 140.09,73.77 139.02,74.84 131.31,74.84 130.63,75.53 119.68,75.53 118.89,74.74 109.6,74.74 108.76,75.58 103.17,75.58 100.16,78.59 98.62,78.59 97.42,79.79 77.29,79.79 77.26,79.76 76.87,79.76 v4(76.7,79.93)
  GND5 w0.076: v5(77.24,79.69) 76.99,79.93 v4(76.7,79.93)
  BOTTOM w0.102: v5(77.24,79.69) 77.06,79.69 UCPU1.A33
USB3TP1_C: length 2.3
  TOP w0.102: C623.2 214.8,41.84 214.8,42.28 v8(215.01,42.48)
  BOTTOM w0.102: v8(215.01,42.48) 214.8,42.28 214.8,42.15 215.09,41.87 ML45.1
USB3TP1_RC_CON: length 12.3
  TOP w0.102: JUSB1.9 218.92,33.67 218.78,33.81 218.44,33.81 217.42,34.84 216.75,34.84 v1(215.93,35.66) 214.87,36.72 214.58,36.72 214.46,36.6 214.46,36.3 v3(214.7,36.06)
  BOTTOM w0.102: R556.2 215.09,40.16 ML45.2 215.09,39.62 214.8,39.34 214.8,39.05 214.65,38.91 214.65,38.81 214.86,38.6 MD74.4 214.86,37.27 214.66,37.07 214.66,36.82 214.46,36.62 214.46,36.29 v3(214.7,36.06)
USB20_N0: length 171.3
  TOP w0.102: R888.1 214.96,56.92 ML52.1 214.96,57.41 214.68,57.69 214.68,57.85 v1(214.92,58.09)
  IN4 w0.076: v4(91.56,61.43) 91.7,61.57 92.01,61.57 92.31,61.87 93.37,61.87 93.64,61.6 94.34,60.9 95.16,60.9 96.77,59.3 97.35,59.3 97.91,58.74 101.04,58.74 103.73,61.43 106.43,61.43 110.73,57.14 121.05,57.14 121.93,58.01 123.78,58.01 125.18,59.41 128.48,59.41 129.46,58.43 131.19,58.43 132.61,57.01 133.9,57.01 134.97,55.94 135.73,55.94 137.71,53.96 139.94,53.96 140.35,53.54 141.41,53.54 141.65,53.3 144.83,53.3 145.99,54.47 145.99,55.75 146.91,56.67 146.91,57.48 148.12,58.69 149.97,58.69 150.17,58.48 154.53,58.48 154.96,58.92 159.01,58.92 159.27,58.66 159.87,58.66 161.86,56.68 164.29,56.68 164.71,57.1 173.62,57.1 176.94,53.77 176.94,50.76 180.12,47.59 180.12,47.03 182.53,44.62 182.53,39.22 182.67,39.08 182.67,37.9 183.67,36.89 198.5,36.89 200.46,38.86 200.46,39.54 203.49,42.56 204.87,42.56 206.65,44.34 211.75,44.34 212.47,43.62 213.98,43.62 215.7,45.35 215.7,56.4 214.72,57.38 214.72,57.89 v1(214.92,58.09)
  GND5 w0.076: v4(91.56,61.43) 91.74,61.61 v5(91.94,61.61)
  BOTTOM w0.102: v5(91.94,61.61) 92.22,61.61 92.32,61.51 UCPU1.AN8
USB20_N0_CONN: length 10.6
  TOP w0.102: v1(214.93,54.42) 214.69,54.66 214.69,54.96 214.96,55.22 ML52.2 214.96,55.78 R888.2
  BOTTOM w0.102: JUSB2.2 219,55.28 218.59,55.69 218.38,55.69 218.3,55.61 217,55.61 v1(216.43,56.19) 215.33,57.29 215,57.29 214.82,57.11 214.82,56.94 215.04,56.72 MD82.5 215.04,55.54 214.79,55.29 214.79,55.08 214.72,55.01 214.72,54.63 v1(214.93,54.42)
USB20_N1: length 139.4
  TOP w0.102: v8(204.24,42.02) 204.41,41.85 204.63,41.85 204.83,42.04 US1.2
  IN4 w0.076: v4(93.7,60.47) 93.94,60.24 94.05,60.24 94.82,59.47 95.7,59.47 96.46,58.71 96.46,58.2 97.23,57.44 98.75,57.44 101.42,54.78 109.68,54.78 109.91,55 119.03,55 120.1,56.07 121.93,56.07 122.1,56.24 126.38,56.24 127.07,56.93 130.63,56.93 133.05,54.51 135.64,54.51 138.25,51.9 138.96,51.9 139.47,51.39 140.84,51.39 141.37,50.86 143.39,50.86 143.7,51.17 144.67,51.17 146.81,53.3 148.56,53.3 149.02,53.76 149.02,54.61 150.35,55.94 155.3,55.94 157.05,57.69 158.67,57.69 160.74,55.61 165.55,55.61 165.83,55.89 168.08,55.89 169.37,54.6 174.44,54.6 175.84,53.2 175.84,49.3 179.57,45.57 179.57,41.72 180.93,40.36 180.93,38.66 183.15,36.44 198.69,36.44 201.86,39.61 201.86,40.28 203.35,41.77 203.98,41.77 v8(204.24,42.02)
  GND5 w0.076: v5(93.25,60.34) 93.34,60.25 93.48,60.25 93.7,60.47 v4(93.7,60.47)
  BOTTOM w0.102: v5(93.25,60.34) 93.11,60.48 UCPU1.AR7
USB20_N1_CONN: length 11.7
  TOP w0.102: v3(215.11,32.12) 214.86,31.87 214.77,31.87 214.7,31.94 214.7,33.3 214.43,33.57 214.3,33.57 213.99,33.88 ML40.2
  BOTTOM w0.102: v3(215.11,32.12) 215.11,31.84 215.03,31.76 214.93,31.76 214.89,31.72 214.79,31.72 214.6,31.92 214.6,32.58 214.86,32.84 MD74.5 214.86,34.27 214.63,34.5 214.63,34.69 215.82,35.88 215.82,36.41 216.5,37.09 216.81,37.09 217.42,36.49 JUSB1.2
USB20_N2: length 116.7
  TOP w0.102: R742.1 182.31,37.19 ML49.1 182.31,37.92 182.01,38.21 182.01,38.5 v1(182.21,38.7)
  IN4 w0.076: v4(92.76,61.03) 92.62,60.9 92.62,60.71 92.72,60.62 92.87,60.62 93.12,60.87 93.33,60.87 93.45,61 93.89,61 94.24,60.64 95.13,60.64 96.85,58.93 97.06,58.93 97.71,58.28 100.15,58.28 103,55.42 109.11,55.42 109.33,55.64 114.78,55.64 115.82,56.68 121.24,56.68 122.11,57.54 130.94,57.54 133.33,55.16 135.87,55.16 137.88,53.15 139.68,53.15 140.23,52.6 142.78,52.6 143.61,51.78 144.41,51.78 146.45,53.82 146.45,55.56 146.96,56.07 147.13,56.24 147.68,56.78 154.4,56.78 154.71,57.09 154.71,57.8 155.33,58.42 158.82,58.42 161.02,56.22 165.3,56.22 165.58,56.5 170.97,56.5 172.27,55.21 174.71,55.21 176.46,53.45 176.46,49.82 179.56,46.72 179.78,46.72 181.01,45.49 181.01,42.89 181.55,42.35 181.55,40.83 181.92,40.46 181.92,38.94 182.16,38.7 v1(182.21,38.7)
  GND5 w0.076: v5(92.5,60.45) 92.5,60.46 92.5,60.78 92.75,61.03 v4(92.76,61.03)
  BOTTOM w0.102: UCPU1.AR8 92.32,60.27 v5(92.5,60.45)
USB20_N2_R: length 3.5
  TOP w0.102: v3(182.2,34.91) 182,35.11 182,35.29 182.31,35.6 ML49.2 182.31,36.09 R742.2
  BOTTOM w0.102: JNGFF1.5 182.25,35.93 182.1,35.79 182.1,35.44 181.97,35.31 181.97,35.15 v3(182.2,34.91)
USB20_N3: length 102.3
  IN2 w0.076: v3(152.38,57.36) 152.15,57.59 152.15,57.76 151.99,57.92 151.28,57.92 150.37,57.01 149.42,57.01 149.22,56.81 148.4,56.81 147.95,56.36 147.95,55.19 148.72,54.43 148.72,53.22 145.64,50.14 142.72,50.14 135.85,43.27 129.88,43.27 129.12,42.51 122.36,42.51 121.31,41.45 120.57,41.45 119.51,42.51 118.07,42.51 115.45,45.12 113.95,45.12 112.55,46.52 112.55,47.6 110.43,49.72 110.43,54.19 109.29,55.33 103.93,55.33 100.38,58.89 96.92,58.89 94.81,61 93.44,61 93.09,60.64 91.82,60.64 v4(91.66,60.79)
  GND5 w0.076: v4(91.66,60.79) 91.36,60.49 v5(91.36,60.41)
  BOTTOM w0.102: v5(91.36,60.41) 91.3,60.48 UCPU1.AR10 ; R1218.1 152.51,74.05 152.38,74.18 152.05,74.18 151.8,73.93 151.8,73.31 151.82,73.29 151.82,72.73 151.8,72.71 151.8,71.64 151.04,70.88 151.04,61.1 152.52,59.62 152.52,58.64 152.1,58.22 152.1,57.57 152.31,57.36 v3(152.38,57.36)
USB20_N4: length 118.1
  IN4 w0.076: v1(87.95,62.42) 87.95,62.62 88.13,62.8 88.92,62.8 89.81,63.69 90.42,63.69 91.9,62.21 93.53,62.21 94.4,61.33 95.18,61.33 96.54,59.97 98.34,59.97 98.51,59.8 101.24,59.8 103.5,62.06 106.86,62.06 109.89,59.04 115.39,59.04 116.58,57.85 119.68,57.85 120.47,58.64 123.44,58.64 124.85,60.04 128.99,60.04 129.86,59.17 132.73,59.17 134.3,57.61 135.48,57.61 136.34,56.74 136.34,56.2 137.5,55.04 138.11,55.04 138.58,54.57 139.77,54.57 140.58,55.38 141.45,55.38 141.63,55.21 143.64,55.21 144.91,56.48 145.78,56.48 146.2,56.9 146.2,59.19 146.93,59.93 151.53,59.93 152.19,59.27 153.11,59.27 153.68,59.84 159.06,59.84 159.61,59.3 160.18,59.3 161.73,57.75 168.41,57.75 171.86,61.2 173.62,61.2 179.26,66.85 180.1,66.85 180.25,66.7 180.25,66.54 v1(179.99,66.28)
  BOTTOM w0.102: v1(87.95,62.42) 88.27,62.1 UCPU1.AM15 ; R1005.1 181.03,72.68 ML55.4 181.03,72.14 181.36,71.81 v1(181.36,70.88) 181.36,68.17 180.24,67.05 180.24,66.43 180.09,66.28 v1(179.99,66.28)
USB20_N4_CONN: length 9.8
  BOTTOM w0.102: ML55.3 181.03,74.36 181.32,74.66 181.32,74.87 181.5,75.04 181.98,75.04 v1(182.26,75.32) 182.55,75.61 184.44,75.61 184.61,75.77 184.61,75.88 184.5,75.98 183.84,75.98 183.78,76.04 MD50.1 183.78,77.91 184.06,78.19 184.36,78.19 184.55,78.37 184.55,78.52 184.4,78.67 184.4,79 184.24,79.15 JLVDS2.3
USB20_N5: length 86.3
  TOP w0.102: R1221.1 158.13,58.27 158.13,58.02 158.64,57.51 v1(158.64,57.24) 158.64,56.94 158.32,56.62 158.02,56.62 157.78,56.38 157.55,56.38 v3(157.36,56.19)
  IN4 w0.076: v4(89.97,62.59) 89.8,62.41 89.56,62.41 89.22,62.07 89.22,61.62 89.59,61.25 90.27,61.25 90.8,60.72 90.8,60.06 91.28,59.59 91.75,59.59 91.8,59.64 91.98,59.64 92.19,59.85 92.9,59.85 93.4,59.35 94.1,59.35 94.44,59 95.45,59 95.83,58.62 95.83,57.96 97.14,56.65 98.43,56.65 99.41,55.68 99.41,54.98 100.38,54.01 110.15,54.01 110.38,54.24 125.46,54.24 127.39,56.17 130.23,56.17 132.67,53.73 133.38,53.73 135.19,51.93 137.03,51.93 137.81,51.14 138.45,51.14 140.2,49.39 141,49.39 141.66,50.05 146.81,50.05 149.97,53.21 149.97,54.43 150.62,55.08 155.56,55.08 156.9,56.42 157.14,56.42 v3(157.36,56.19)
  GND5 w0.076: v5(89.5,62.36) 89.6,62.26 89.74,62.26 89.97,62.5 v4(89.97,62.59)
  BOTTOM w0.102: UCPU1.AM13 89.08,62.46 89.4,62.46 v5(89.5,62.36)
USB20_P0: length 171.2
  TOP w0.102: R889.1 214.16,56.92 ML52.4 214.16,57.37 214.47,57.67 214.47,57.92 v1(214.28,58.1)
  IN4 w0.076: v1(214.28,58.1) 214.32,58.1 214.57,57.86 214.57,57.32 215.55,56.33 215.55,45.42 213.91,43.78 212.53,43.78 211.82,44.49 206.59,44.49 204.81,42.71 203.42,42.71 200.31,39.6 200.31,38.93 198.43,37.05 183.74,37.05 182.82,37.96 182.82,39.14 182.68,39.28 182.68,44.68 180.27,47.09 180.27,47.65 177.1,50.83 177.1,53.84 173.68,57.25 164.65,57.25 164.23,56.83 161.92,56.83 159.94,58.81 159.33,58.81 159.08,59.07 154.9,59.07 154.46,58.64 150.23,58.64 150.03,58.84 148.05,58.84 146.76,57.54 146.76,56.73 145.84,55.82 145.84,54.53 144.76,53.46 141.71,53.46 141.47,53.7 140.42,53.7 140,54.11 137.78,54.11 135.8,56.1 135.03,56.1 133.97,57.16 132.67,57.16 131.25,58.59 129.52,58.59 128.54,59.57 125.12,59.57 123.72,58.17 121.86,58.17 120.99,57.29 110.79,57.29 106.49,61.58 103.67,61.58 100.97,58.89 97.97,58.89 97.42,59.45 96.83,59.45 95.23,61.06 94.4,61.06 93.8,61.66 93.8,61.66 93.43,62.03 92.25,62.03 92.11,61.89 91.95,61.72 91.76,61.72 91.57,61.92 v4(91.57,62.03)
  GND5 w0.076: v5(91.94,61.96) 91.89,61.92 91.69,61.92 v4(91.57,62.03)
  BOTTOM w0.102: UCPU1.AM8 92.15,61.93 91.98,61.93 v5(91.94,61.96)
USB20_P0_CONN: length 10.6
  TOP w0.102: R889.2 214.16,55.78 ML52.3 214.16,55.26 214.48,54.93 214.48,54.6 v3(214.3,54.42)
  BOTTOM w0.102: v3(214.3,54.42) 214.52,54.64 214.52,55.09 214.59,55.16 214.59,55.29 214.39,55.49 MD82.6 214.39,56.7 214.61,56.92 214.61,57.2 214.91,57.5 215.41,57.5 216.37,56.54 216.4,56.54 216.79,56.15 216.79,56.12 217.09,55.82 218.22,55.82 218.29,55.9 218.67,55.9 219,56.23 JUSB2.3
USB20_P1: length 139.4
  TOP w0.102: v1(204.26,41.39) 204.51,41.64 204.64,41.64 204.74,41.55 US1.3
  IN4 w0.076: v4(93.71,59.88) 93.91,60.08 93.99,60.08 94.75,59.32 95.64,59.32 96.31,58.65 96.31,58.14 97.16,57.29 98.69,57.29 101.35,54.62 109.75,54.62 109.98,54.85 119.1,54.85 120.16,55.92 121.99,55.92 122.16,56.09 126.44,56.09 127.13,56.78 130.56,56.78 132.99,54.36 135.58,54.36 138.18,51.75 138.89,51.75 139.41,51.24 140.78,51.24 141.31,50.71 143.45,50.71 143.76,51.02 144.74,51.02 146.87,53.15 148.62,53.15 149.17,53.7 149.17,54.55 150.41,55.79 155.37,55.79 157.11,57.53 158.6,57.53 160.67,55.46 165.62,55.46 165.89,55.74 168.02,55.74 169.31,54.44 174.38,54.44 175.69,53.14 175.69,49.24 179.42,45.5 179.42,41.66 180.78,40.3 180.78,38.6 183.09,36.28 198.75,36.28 202.01,39.55 202.01,40.22 203.41,41.62 204.03,41.62 v1(204.26,41.39)
  GND5 w0.076: v5(93.25,59.97) 93.37,60.09 93.49,60.09 v4(93.71,59.88)
  BOTTOM w0.102: UCPU1.AT7 93.03,59.97 v5(93.25,59.97)
USB20_P1_CONN: length 11.8
  TOP w0.102: v3(215.1,31.36) 214.8,31.66 214.69,31.66 214.49,31.86 214.49,33.21 214.35,33.36 214.23,33.36 213.94,33.08 ML40.3
  BOTTOM w0.102: JUSB1.3 216.62,37.3 216.41,37.3 215.61,36.5 215.61,35.96 214.42,34.78 214.42,34.51 214.21,34.29 MD74.6 214.21,32.79 214.39,32.61 214.39,31.83 214.71,31.51 214.95,31.51 v3(215.1,31.36)
USB20_P2: length 116.8
  TOP w0.102: R741.1 181.51,37.22 ML49.4 181.51,37.92 181.81,38.21 181.81,38.47 v8(181.58,38.7)
  IN4 w0.076: v8(181.58,38.7) 181.77,38.89 181.77,40.4 181.4,40.77 181.4,42.29 180.86,42.83 180.86,45.42 179.71,46.57 179.5,46.57 176.31,49.76 176.31,53.39 174.64,55.05 172.21,55.05 170.91,56.35 165.64,56.35 165.36,56.07 160.95,56.07 158.75,58.27 155.39,58.27 154.86,57.73 154.86,57.02 154.46,56.63 147.74,56.63 146.6,55.49 146.6,53.76 144.47,51.63 143.54,51.63 142.72,52.45 140.16,52.45 139.62,53 137.81,53 135.81,55 133.27,55 130.88,57.39 122.17,57.39 121.3,56.53 115.88,56.53 114.84,55.49 109.39,55.49 109.18,55.27 102.94,55.27 100.08,58.13 97.64,58.13 97,58.78 96.79,58.78 95.07,60.49 94.18,60.49 93.82,60.85 93.52,60.85 93.39,60.72 93.19,60.72 92.93,60.46 92.66,60.46 92.47,60.65 92.47,60.83 92.28,61.03 v4(92.18,61.03)
  GND5 w0.076: v5(92.12,60.49) 92.35,60.71 92.35,60.86 v4(92.18,61.03)
  BOTTOM w0.102: UCPU1.AP8 92.32,60.69 v5(92.12,60.49)
USB20_P2_R: length 3.5
  TOP w0.102: v8(181.57,34.91) 181.79,35.14 181.79,35.29 181.51,35.58 ML49.3 181.51,36.06 R741.2
  BOTTOM w0.102: v8(181.57,34.91) 181.76,35.1 181.76,35.39 181.89,35.53 181.89,35.78 181.75,35.93 JNGFF1.3
USB20_P3: length 102.2
  IN2 w0.076: v4(91.7,60.13) 91.7,60.37 91.83,60.49 93.15,60.49 93.5,60.85 94.74,60.85 96.85,58.74 100.31,58.74 103.87,55.18 109.23,55.18 110.28,54.13 110.28,49.66 112.4,47.54 112.4,46.46 113.89,44.97 115.39,44.97 118,42.35 119.45,42.35 120.5,41.3 121.37,41.3 122.42,42.35 129.18,42.35 129.94,43.12 135.91,43.12 142.79,49.99 145.7,49.99 148.87,53.15 148.87,54.5 148.11,55.26 148.11,56.3 148.46,56.65 149.28,56.65 149.49,56.86 150.43,56.86 151.35,57.77 151.92,57.77 152,57.7 152,57.48 151.88,57.36 v3(151.74,57.36)
  GND5 w0.076: v5(91.29,59.98) 91.44,60.13 v4(91.7,60.13)
  BOTTOM w0.102: R1219.1 152.26,74.39 151.97,74.39 151.59,74.01 v1(151.59,73.01) 151.59,71.73 150.83,70.97 150.83,61.01 152.31,59.53 152.31,58.72 151.89,58.3 151.89,57.51 v3(151.74,57.36) ; v5(91.29,59.98) 91.14,59.83 UCPU1.AT10
USB20_P4: length 118.3
  IN4 w0.076: v8(180.73,66.26) 180.4,66.59 180.4,66.76 180.16,67 179.2,67 173.55,61.35 171.8,61.35 168.35,57.9 161.79,57.9 160.24,59.45 159.67,59.45 159.12,59.99 153.61,59.99 153.04,59.42 152.25,59.42 151.59,60.08 146.87,60.08 146.04,59.26 146.04,56.96 145.71,56.63 144.85,56.63 143.58,55.36 141.69,55.36 141.51,55.54 140.52,55.54 139.71,54.72 138.64,54.72 138.17,55.19 137.56,55.19 136.49,56.26 136.49,56.81 135.54,57.76 134.36,57.76 132.8,59.32 129.93,59.32 129.05,60.2 124.78,60.2 123.38,58.79 120.4,58.79 119.62,58 116.64,58 115.45,59.19 109.95,59.19 106.93,62.22 103.44,62.22 101.18,59.96 98.57,59.96 98.41,60.12 96.61,60.12 95.24,61.48 94.47,61.48 93.59,62.36 91.97,62.36 90.48,63.84 89.75,63.84 88.85,62.95 88.17,62.95 v1(87.98,63.14)
  BOTTOM w0.102: UCPU1.AL15 88.36,62.75 v1(87.98,63.14) ; R1004.1 181.83,72.68 ML55.1 181.83,72.1 181.57,71.84 181.57,71.18 181.59,71.16 181.59,70.6 181.57,70.58 181.57,68.08 180.45,66.97 180.45,66.44 180.63,66.26 v8(180.73,66.26)
USB20_P4_CONN: length 9.8
  BOTTOM w0.102: ML55.2 181.83,74.38 181.53,74.67 181.53,74.78 181.59,74.84 182.07,74.84 182.2,74.97 182.23,74.97 182.66,75.4 184.53,75.4 184.83,75.71 184.83,75.86 184.96,75.98 185.57,75.98 185.68,76.1 MD50.3 185.68,77.69 v2(185.27,78.1) 185.13,78.24 184.94,78.24 184.76,78.42 184.76,78.6 184.6,78.76 184.6,78.98 184.74,79.12 JLVDS2.2
USB20_P5: length 86.2
  TOP w0.102: v3(157.37,57.01) 157.37,56.74 157.52,56.59 157.69,56.59 157.93,56.83 158.24,56.83 158.4,57 158.4,57.45 157.93,57.93 157.93,58.27 157.63,58.56 R1222.1
  IN4 w0.076: v4(89.97,61.89) 89.97,62.15 89.86,62.26 89.62,62.26 89.37,62.01 89.37,61.68 89.65,61.4 90.34,61.4 90.95,60.79 90.95,60.13 91.34,59.74 91.68,59.74 91.73,59.79 91.91,59.79 92.13,60 92.96,60 93.47,59.5 94.16,59.5 94.51,59.16 95.51,59.16 95.98,58.69 95.98,58.03 97.2,56.81 98.5,56.81 99.56,55.74 99.56,55.04 100.44,54.17 110.09,54.17 110.32,54.39 125.39,54.39 127.32,56.32 130.3,56.32 132.73,53.89 133.45,53.89 135.25,52.08 137.09,52.08 137.88,51.3 138.51,51.3 140.27,49.54 140.94,49.54 141.6,50.2 146.74,50.2 149.82,53.28 149.82,54.5 150.55,55.23 155.5,55.23 156.84,56.57 157.18,56.57 157.38,56.77 157.38,56.99 v3(157.37,57.01)
  GND5 w0.076: v4(89.97,61.89) 89.76,62.11 89.6,62.11 89.5,62.01 v5(89.5,61.93)
  BOTTOM w0.102: v5(89.5,61.93) 89.36,61.78 UCPU1.AN13
USB_EN: length 19.6
  TOP w0.102: v1(212.11,49.64) 212.11,50.16 211.92,50.36 v2(211.67,50.36) PU307.2 ; US1.5 205.99,39.7 v3(205.43,39.14)
  IN2 w0.076: v1(212.11,49.64) 212.26,49.64 212.85,49.06 212.85,46.82 208.26,42.24 208.26,40.45 207.46,39.65 205.94,39.65 v3(205.43,39.14)
  BOTTOM w0.102: v3(205.43,39.14) 205.98,38.59 U699.4
USB_ILIM_SEL: length 86
  TOP w0.102: U34.K8 140.72,58.6 140.6,58.48 v6(140.6,58.37) ; v2(200.51,40.31) 200.74,40.08 R1164.1 202.04,40.07 v1(202.72,40.07) R1167.1 203.78,40.07 204.75,41.04 US1.4
  GND1 w0.076: v6(140.6,58.37) 141.02,57.95 v4(141.02,57.8)
  IN1 w0.076: v4(174.07,46.2) 173.65,46.62 173.65,47.33 172.85,48.13 171.56,48.13 167.02,52.67 167.02,53.38 164,56.4 162.08,56.4 158.6,59.88 v4(152.52,59.88)
  IN2 w0.076: v4(178.92,45.35) 178.37,44.79 178.37,44.32 179.29,43.4 179.29,39.15 181.27,37.17 199.89,37.17 202.72,40 v1(202.72,40.07) ; v4(152.52,59.88) 152.34,59.88 151.6,60.62 149.35,60.62 148.55,61.42 146.45,61.42 143.85,58.81 142.46,58.81 142.29,58.64 141.24,58.64 141.02,58.41 v4(141.02,57.8)
  IN3 w0.076: v4(178.92,45.35) 174.92,45.35 v4(174.07,46.2)
USB_OC0#: length 183.3
  TOP w0.102: v6(214.88,53.81) 215.22,53.47 US2.5 ; v6(98.27,65.2) 98.27,64.91 T289.1 97.95,64.59 97.95,63.16 98.57,62.53 98.57,62.14 98.78,61.93 RP11.2
  GND1 w0.076: v4(97.82,65.16) 98.23,65.16 v6(98.27,65.2) ; v6(214.88,53.81) 214.88,53.37 v4(214.87,53.35)
  IN4 w0.076: v4(214.87,53.35) 215.08,53.14 215.08,49.59 214.55,49.06 210.48,49.06 208.52,47.09 202.39,47.09 201.75,46.44 201.75,43.57 201.35,43.18 200.12,43.18 198.47,41.53 198.47,38.72 197.61,37.86 190.7,37.86 189.55,39 186.66,39 185.69,38.04 184.21,38.04 183.81,38.43 183.81,39.74 183.67,39.88 183.67,47.69 184.27,48.29 184.27,49.23 183.65,49.85 183.65,63.39 182.1,64.94 182.1,68.17 180.81,69.46 179.88,69.46 178.59,70.74 175.88,70.74 175.31,71.31 174.02,71.31 172.88,70.17 172.88,69.51 169.94,66.57 167.72,66.57 166.73,65.58 164.98,65.58 164.79,65.39 162.38,65.39 161.74,66.03 161.74,66.41 161.51,66.64 160.5,66.64 159.57,65.71 157.1,65.71 156.8,66.01 155.41,66.01 155.12,66.31 153.21,66.31 152.06,65.16 149.27,65.16 147.73,66.7 145.75,66.7 145.3,67.16 144.51,67.16 143.71,67.96 139.9,67.96 138.59,69.27 138.59,69.83 138.34,70.08 137.84,70.08 137.22,69.46 136.44,69.46 136.24,69.66 135.83,69.66 135.58,69.41 135.58,68.67 132.85,65.94 129.88,65.94 128.66,64.72 127.19,64.72 127.18,64.71 121.83,64.71 120.89,65.66 119.11,65.66 118.7,66.07 114.21,66.07 114.08,65.94 110.05,65.94 109.19,66.8 107.09,66.8 106.84,67.06 106.49,67.06 105.76,66.33 104.33,66.33 103.97,66.69 100.28,66.69 98.87,65.28 97.94,65.28 v4(97.82,65.16)
  GND5 w0.076: v5(97.86,64.71) 97.82,64.74 v4(97.82,65.16)
  BOTTOM w0.076: UCPU1.AL3 95.5,62.85 96.01,63.36 97.1,63.36 97.37,63.63
  BOTTOM w0.102: 97.37,63.63 97.86,64.12 97.86,64.68 97.89,64.71 v5(97.86,64.71)
USB_OC1#: length 151.7
  TOP w0.102: RP11.3 98.92,61.43 98.53,61.05 v6(98.53,60.92) ; US1.13 207.49,43.74 207.6,43.85 208,43.85 208.13,43.71 v6(208.13,43.4)
  GND1 w0.076: v4(98.89,60.69) 98.66,60.92 v6(98.53,60.92) ; v6(208.13,43.4) 208.13,43.38 207.89,43.14 v4(207.73,43.14)
  IN2 w0.076: v4(207.73,43.14) 207.91,42.96 207.91,40.59 207.28,39.97 205.71,39.97 205.33,39.59 202.56,39.59 199.97,37 181.19,37 179.12,39.07 179.12,43.21 178.06,44.26 178.06,53.79 169.84,62 v4(169.84,62.32)
  IN4 w0.076: v4(169.84,62.32) 169.84,61.43 167.9,59.49 165.72,59.49 165.62,59.59 161.93,59.59 161.04,60.48 159.55,60.48 159.4,60.63 152.62,60.63 152.53,60.72 149.37,60.72 148.74,61.35 147.86,61.35 147.66,61.15 146.43,61.15 146.23,60.96 146.23,59.84 145.61,59.21 145.61,57.78 145.23,57.4 145.19,57.4 144.88,57.09 143.82,57.09 143.64,56.91 143.52,56.91 142.94,56.91 142.15,56.11 141.59,56.11 141.37,55.89 140.13,55.89 139.9,55.66 137.74,55.66 137.01,56.39 137.01,57.8 135.92,58.89 134.12,58.89 132.75,60.26 131.36,60.26 130.42,61.2 129.5,61.2 129.27,60.97 123.69,60.97 122.27,59.55 119.8,59.55 119.61,59.36 118.07,59.36 117.77,59.65 110.27,59.65 107.25,62.67 103.25,62.67 101.33,60.76 100.87,60.76 100.45,61.18 99.37,61.18 v4(98.89,60.69)
  GND5 w0.076: v4(98.89,60.69) 99.03,60.83 v5(99.03,61.3)
  BOTTOM w0.102: UCPU1.AT1 96.7,59.93 97.05,59.93 97.4,60.29 97.76,60.29 98.39,60.92 T290.1 99.03,61.17 v5(99.03,61.3)
USB_OC2#: length 6.1
  TOP w0.102: v6(98.38,64.17) 98.38,63.49 T291.1 98.51,63.06 98.79,62.78 98.79,62.55 98.9,62.43 RP11.1
  GND1 w0.076: v6(98.38,64.17) 98.43,64.17 v4(98.76,64.5)
  GND5 w0.076: v4(98.76,64.5) 98.61,64.66 v5(98.33,64.66)
  BOTTOM w0.076: UCPU1.AH2 96.2,64.39 96.51,64.71 97.37,64.71
  BOTTOM w0.102: 97.37,64.71 97.38,64.71 97.68,65.01 98.09,65.01 98.33,64.77 v5(98.33,64.66)
USB_PS_CTL1: length 2.9
  TOP w0.102: R1166.1 R1213.1 206.61,38.82 206.61,39.61 206.49,39.73 US1.6
USBCHG_DET_D: length 108.3
  TOP w0.102: v1(128.49,55.11) 128.65,55.26 U712.4 ; v1(169.23,32.88) 169.95,32.88 170.56,32.27 174.35,32.27 174.56,32.07 177.31,32.07 v2(181.57,27.81) 182.43,26.95 190.57,26.95 195.89,32.27 195.89,33.35 PR342.1
  IN3 w0.076: v1(169.23,32.88) 168.57,32.88 162.72,27.03 156.99,27.03 156.78,26.81 155.49,26.81 155.27,27.03 150.58,27.03 148.94,28.66 142.63,28.66 137.71,33.59 128.96,33.59 122.66,39.88 122.66,48.21 122.5,48.38 122.5,50.24 123.21,50.95 123.21,53.17 125.14,55.11 v1(128.49,55.11)
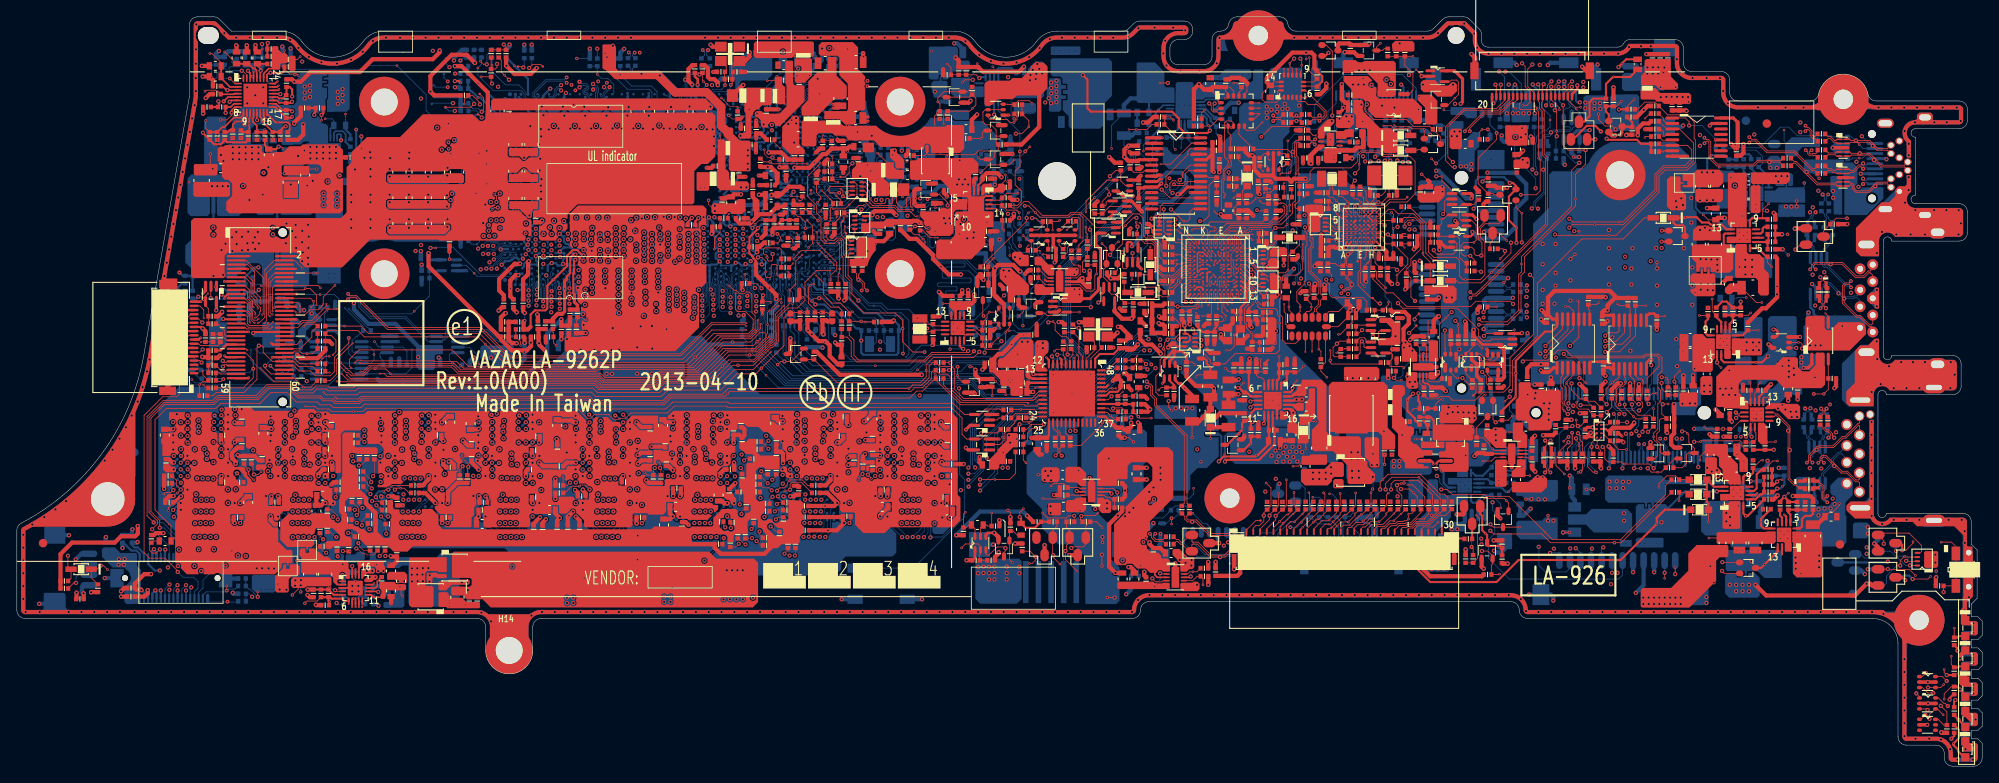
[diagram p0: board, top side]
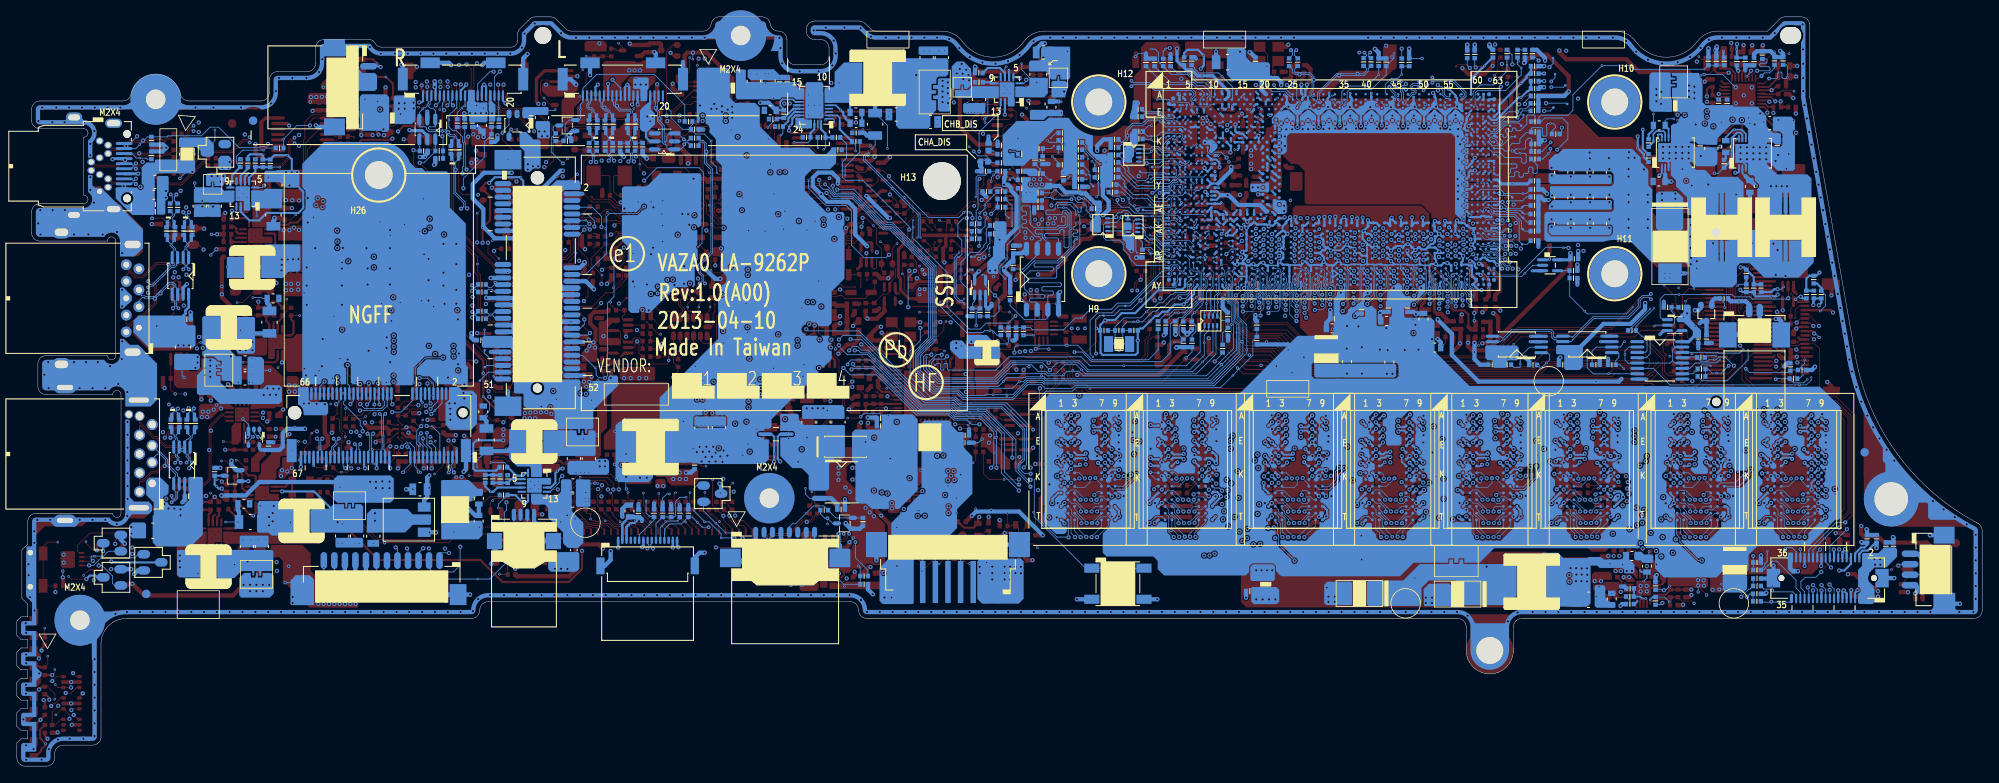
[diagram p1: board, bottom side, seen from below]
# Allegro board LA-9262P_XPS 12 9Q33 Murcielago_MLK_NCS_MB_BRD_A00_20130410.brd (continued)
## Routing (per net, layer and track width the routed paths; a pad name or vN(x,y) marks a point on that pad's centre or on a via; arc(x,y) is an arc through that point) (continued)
USBCHG_DET_PWR_EN#: length 9.8
  TOP w0.102: v2(128.92,62.1) 128.94,62.1 129.46,61.58 D104.2 129.46,59.38 129.09,59.02 129.09,58.13 129.79,57.43 U712.2 129.79,56.35 130.04,56.1 130.6,56.1 131.63,55.07 R941.2 R939.2
USBRBIAS: length 3.3
  TOP w0.102: v3(90.36,63.25) 90.73,62.89 v2(90.73,62.52) 90.4,62.19 RH163.1
  BOTTOM w0.102: v3(90.36,63.25) 90.16,63.46 UCPU1.AJ11 UCPU1.AJ10
V_DDR_REF_CA: length 15.9
  TOP w0.254: 61.04,52.22 61.04,53.66 61.55,54.17 62.8,54.17 63.02,54.39 63.02,57.09 v2(63.81,57.87) 65.36,59.42 65.36,60.64 66.05,61.33 66.58,61.33 67.21,60.7 v1(67.34,60.7)
  TOP w0.508: 61.04,52.22 60.73,51.9 CD89.1 RD14.1
  BOTTOM w0.254: v1(67.34,60.7) 67.31,60.72 67.19,60.72 66.92,60.99 UCPU1.AP49
V_DDR_REFA_R: length 7.7
  TOP w0.254: v1(66.36,60.19) 66.2,60.02 v2(66.2,59.32) 66.2,58.65 66.11,58.56 66.11,56.21 66.24,56.08
  TOP w0.381: CD91.1 66.61,54.79 66.24,55.16 66.24,56.08
  TOP w0.508: CD91.1 RD19.1
  BOTTOM w0.254: UCPU1.AR51 65.99,60.21 66.3,60.21 66.34,60.17 66.35,60.19 v1(66.36,60.19)
V_DDR_REFB_R: length 11
  TOP w0.254: v1(66.37,60.81) 66.11,60.81 65.76,60.45 65.76,58.6 65.34,58.18 65.34,57.87
  TOP w0.381: 65.34,57.87 65.08,57.62 v2(65.08,56.73) 65.08,54.04 64.8,53.76
  TOP w0.508: 64.8,53.76 64.27,53.76 63.68,53.17 CD92.1 RD20.1
  BOTTOM w0.254: v1(66.37,60.81) 66.35,60.78 66.31,60.78 66.11,60.99 UCPU1.AP51
VCIN0_PH: length 108.6
  TOP w0.102: v1(136.85,43.38) 136.85,42.62 v2(137.21,42.27)
  TOP w0.203: v6(148.02,62.83) 147.56,63.29
  TOP w0.254: PR117.1 R925.1 ; PH101.1 79.7,64.63 80.18,65.12 v1(80.18,65.14)
  GND1 w0.254: v6(148.02,62.83) 148.02,62.79 148.32,63.09 148.32,63.09 v4(148.66,63.44)
  IN2 w0.254: v1(80.18,65.14) 80.18,65.03 80.26,64.96 80.26,59.56 81.86,57.96 81.86,56.33 82.08,56.11 82.08,51.13 90.15,43.06 106.28,43.06 v1(107.26,44.04)
  IN3 w0.254: v1(136.85,43.38) 136.85,43.93 138.07,45.15 138.5,45.15 141.76,48.41 144.18,48.41 146.43,50.66 147.38,50.66 149.28,52.57 149.28,54.52 150.48,55.72 150.48,58.25 149.41,59.32 149.41,61.19 149.21,61.39 149.21,62.89 v4(148.66,63.44)
  IN4 w0.254: v1(136.85,43.38) 136.58,43.12 131.69,43.12 130.3,44.51 121.43,44.51 120.39,45.55 108.76,45.55 107.26,44.06 v1(107.26,44.04)
VCIN0_PH_R: length 5.9
  TOP w0.076: 144.67,62.83 144.67,62.82 144.67,61.85 U34.C2
  TOP w0.102: R925.2 147.97,63.8 146.73,63.8 v2(146.58,63.65) 146.31,63.39 145.03,63.39 144.66,63.02 144.67,63.01 144.67,62.83
VCIN1_PH: length 4.8
  TOP w0.102: PR116.1 142.76,52.82 143.19,52.82 v2(143.48,53.11)
  TOP w0.254: PR116.1 142.53,52.24 142.3,52.01 PR118.2 PC112.1 140.88,51.6 140.27,52.21 R926.1
VCIN1_PH_R: length 16.9
  TOP w0.076: U34.D2 144.17,61.85 144.17,62.57 v6(143.93,62.8)
  TOP w0.102: R926.2 140.27,53.69 v6(140.12,53.84)
  GND1 w0.076: v6(143.93,62.8) 143.53,63.21 v4(143.53,63.39) ; v6(140.12,53.84) 139.94,53.84 139.67,53.57 v4(139.66,53.57)
  IN3 w0.076: v4(139.66,53.57) 139.66,54.66 139.96,54.97 139.96,55.35 139.2,56.11 139.2,56.86 139.01,57.05 139.01,58.52 140.82,60.34 142.27,60.34 143.27,61.34 143.7,61.34 143.97,61.61 143.97,62.95 v4(143.53,63.39)
VCOUT0_PH#: length 104.7
  TOP w0.203: v6(143.42,61.02) U34.E4
  TOP w0.254: R922.1 150.55,59.55 v1(150.51,59.51) ; v1(166.35,25.59) 166.35,23.46 167.93,21.88 175.8,21.88 178.42,24.5 190.55,24.5 v2(194.83,28.78) 194.83,29.51 195.8,30.48 PD303.1
  GND1 w0.254: v4(143.63,60.62) 143.63,60.83 143.44,61.02 v6(143.42,61.02)
  IN1 w0.254: v1(166.35,25.59) 170.03,25.59 172.73,28.29 172.73,28.98 174.64,30.9 174.64,42.29 173.22,43.71 173.22,47.24 172.71,47.75 171.43,47.75 166.67,52.51 166.67,53.24 164.18,55.73 161.4,55.73 158.43,58.7 152.93,58.7 151.9,59.73 150.73,59.73 v1(150.51,59.51) 149.95,60.08 146.11,60.08 145.92,59.88 144.79,59.88 144.05,60.62 v4(143.63,60.62)
VLDOIN_+1.2V: length 8.2
  TOP w0.203: PU601.19 v1(39.84,23.77)
  IN4 w1.016: 31.66,21.78 31.66,22.03 33.05,23.43 38.01,23.43
  vias: v1(31.22,20.99) v1(32.04,20.97) v2(31.01,21.64)
VOLUME_DOWN_SW#: length 153.2
  TOP w0.102: RP21.3 137.53,64.22 v1(137.64,64.33) 139.19,64.33 139.35,64.16 141,64.16 141.45,63.72 141.45,62.13 141.42,62.1 U34.J1 ; v1(28.62,20.13) v2(28.62,20.7)
  IN1 w0.076: v4(70.66,25.46) 70.1,24.9 66.31,24.9 65.81,25.41 42.67,25.41 42.06,24.8 41.27,24.8 40.84,24.37 38.72,24.37 37.91,23.56 32.66,23.56 29.97,20.87 29.36,20.87 v1(28.62,20.13)
  IN2 w0.076: v4(70.66,25.46) 71.34,26.15 73.49,26.15 74.12,25.51 77.72,25.51 78.16,25.95 84.37,25.95 85.29,26.86 86.71,26.86 87.62,25.95 89.92,25.95 90.22,26.25 93.54,26.25 94.43,25.36 102.99,25.36 104.34,26.71 111.58,26.71 115.72,30.85 115.72,36.18 v1(115.23,36.66)
  IN3 w0.076: v1(137.64,64.33) 136.3,64.33 135.64,63.67 135.64,59.7 136.18,59.17 136.18,57.4 136.62,56.96 136.62,52.57 134.93,50.88 134.93,50.41 v1(133.94,49.42)
  BOTTOM w0.102: C1124.1 R955.2 27.59,21.03 27.72,21.03 v1(28.62,20.13) ; v1(115.23,36.66) 115.23,38.95 118.43,42.15 121.75,42.15 122.39,42.79 126.01,42.79 132.32,49.11 133.23,49.11 133.53,49.42 v1(133.94,49.42)
VOLUME_DOWN_SW#_C: length 138.6
  TOP w0.102: R1263.1 125.89,52.08 v1(126.16,52.08) ; v3(24.94,20.87) v2(24.94,21.41)
  IN1 w0.076: v3(24.94,20.87) 24.94,20.94 25.93,21.93 30.2,21.93 34.13,25.87 38.2,25.87 38.32,26 38.96,26 39.97,24.98 40.69,24.98 41.04,25.34 41.63,25.34 42.23,25.95 48.66,25.95 50.37,27.65 51.09,27.65 51.44,27.3 51.75,27.3 51.78,27.27 51.79,27.27 52.01,27.04 52.78,27.04 52.93,26.89 55.61,26.89 56.3,26.2 68.73,26.2 v4(69.34,25.59)
  IN2 w0.076: v4(69.34,25.59) 70.38,26.63 73.59,26.63 74.07,26.15 76.04,26.15 76.12,26.23 76.12,26.53 76.35,26.76 77.79,26.76 78.05,26.5 84.27,26.5 85.01,27.24 86.28,27.24 86.58,27.55 87.7,27.55 88.62,26.63 93.66,26.63 94.4,25.9 101.26,25.9 101.9,26.53 103.35,26.53 104.7,27.88 110.74,27.88 115.23,32.37 115.23,32.37 115.23,33.97 114.32,34.89 113.63,34.89 v1(113.05,35.47)
  BOTTOM w0.102: JIOL1.33 22.1,20.32 22.49,20.71 24.78,20.71 v3(24.94,20.87) 25.12,21.04 25.92,21.04 R955.1 ; v1(126.16,52.08) 126.16,50.58 127.38,49.36 127.38,46.29 124.93,43.85 121.95,43.85 121.27,43.17 115.91,43.17 113.29,40.55 113.29,35.71 v1(113.05,35.47)
VOLUME_DOWN_SW#_DSP: length 5.3
  TOP w0.102: R1265.2 R1263.2 126.18,50.88 v2(126.18,49.77) 126.18,49.15 126.61,48.72 UA1.4
VOLUME_UP_SW#: length 144.4
  TOP w0.076: U34.N11 139.11,57.1 v6(138.84,56.83)
  TOP w0.102: v1(139.71,51.93) 139.95,51.69 RP22.4
  GND1 w0.076: v6(138.84,56.83) v4(138.84,56.38)
  IN1 w0.076: v1(27.96,20.13) 28.87,21.04 29.89,21.04 32.58,23.74 37.84,23.74 38.68,24.57 40.79,24.57 41.19,24.98 41.88,24.98 42.49,25.59 53.21,25.59 53.97,26.35 54.6,26.35 55.29,25.67 66.19,25.67 66.75,25.11 69.59,25.11 v4(70.02,25.54)
  IN2 w0.076: v1(113.86,35.5) 114.12,35.5 115.41,34.2 115.41,32.3 115.31,32.19 115.31,32.19 110.81,27.7 104.77,27.7 102.61,25.54 94.5,25.54 93.59,26.45 90.04,26.45 89.71,26.12 87.7,26.12 86.79,27.04 85.21,27.04 84.5,26.33 77.97,26.33 77.92,26.38 77.11,26.38 76.42,25.69 74.23,25.69 73.46,26.45 70.94,26.45 v4(70.02,25.54)
  IN3 w0.076: v4(138.84,56.38) 138.49,56.02 138.49,54.95 138.58,54.86 138.58,53.94 139.8,52.72 139.8,52.02 v1(139.71,51.93)
  BOTTOM w0.102: R953.2 C1123.1 27.6,20.49 v1(27.96,20.13) ; v1(139.71,51.93) 139.5,51.73 133.45,51.73 125.36,43.64 122.04,43.64 121.36,42.96 116.18,42.96 v2(115.4,42.18) 113.53,40.31 113.53,35.83 v1(113.86,35.5)
VOLUME_UP_SW#_C: length 111.4
  TOP w0.102: R1264.1 118.66,34.79 117.95,34.07 v2(116.21,34.07) v1(114.45,34.07)
  IN1 w0.076: v4(68.66,25.59) 68.33,25.92 56.05,25.92 55.26,26.71 54.02,26.71 53.08,25.77 42.34,25.77 41.73,25.16 41.12,25.16 40.76,24.8 38.65,24.8 38.2,24.35 34.31,24.35 33.93,23.96 32.53,23.96 29.86,21.3 27.2,21.3 25.45,19.55 v3(25.04,19.55)
  IN2 w0.076: v4(68.66,25.59) 69.88,26.81 73.74,26.81 74.1,26.45 74.95,26.45 75.51,27.01 75.84,27.01 75.92,26.94 78.25,26.94 78.51,26.68 84.17,26.68 84.91,27.42 86.2,27.42 86.51,27.72 87.78,27.72 88.69,26.81 93.73,26.81 94.37,26.17 100.68,26.17 100.76,26.25 100.76,26.5 101.01,26.76 103.33,26.76 104.62,28.05 110.66,28.05 115.06,32.45 115.06,33.46 v1(114.45,34.07)
  BOTTOM w0.102: R953.1 26.2,19.49 25.09,19.49 v3(25.04,19.55) 24.99,19.49 22.73,19.49 22.6,19.62 JIOL1.35
VOLUME_UP_SW#_DSP: length 10.2
  TOP w0.102: v2(119.9,36.06) 119.58,36.37 R1264.2 R1266.2 120.07,38.73 120.07,39.59 120.61,40.12 v1(121.43,40.12) ; v6(121.14,43.32) 121.36,43.54 UA1.20
  GND1 w0.076: v4(121.38,42.99) 121.38,43.08 v6(121.14,43.32)
  IN3 w0.076: v1(121.43,40.12) 121.43,40.75 122.12,41.44 122.12,42.25 v4(121.38,42.99)
VR_A_ENABLE: length 1.3
  TOP w0.102: R1284.1 175.08,46.22 174.71,46.59 U689.4
VR_HOT#: length 13.6
  TOP w0.203: v1(27.46,82.64) 27.72,82.38 PU701.30
  IN3 w0.254: v1(27.46,82.64) 27.46,83.02 27.26,83.22 24.73,83.22 24.53,83.43 24.53,83.91 24.73,84.11 30.26,84.11 v4(30.61,84.47)
  GND5 w0.254: v4(30.61,84.47) 30.74,84.59 v5(30.74,85.03)
  BOTTOM w0.102: v2(27.96,81.98) 27.46,82.47 v1(27.46,82.64)
  BOTTOM w0.254: v5(30.74,85.03) 30.74,84.32 R265.2
VR_ON: length 139.9
  TOP w0.102: v1(143.97,70.57) 144,70.55 R1154.1 ; v1(25.52,77.66) 25.52,77.37 24.95,76.8 v7(24.21,76.8) ; v1(57.06,83.45) 57.06,83.06 56.84,82.84 RC151.1 R1241.1
  TOP w0.203: v1(25.52,77.66) 25.52,77.94 25.9,78.32 PU701.8
  IN1 w0.076: v1(25.52,77.66) 25.52,78.32 25.85,78.65 25.85,80.13 28.87,83.15 30.71,83.15 31.04,82.82 41.42,82.82 42.31,83.71 51.15,83.71 51.76,84.32 56.09,84.32 56.95,83.45 v1(57.06,83.45)
  IN4 w0.076: v1(143.97,70.57) 143.52,70.12 141.77,70.12 139.67,72.21 139.62,72.26 135.28,72.26 135.2,72.34 134.29,72.34 133.24,71.29 128.94,71.29 126.66,73.57 117.83,73.57 117.5,73.89 112.69,73.89 111.38,75.2 99.54,75.2 99.33,75.4 97.09,75.4 96.48,74.79 94.27,74.79 92.92,73.44 91.05,73.44 90.91,73.59 90.91,74.8 90.56,75.15 88.48,75.15 87.17,76.45 87.17,77.34 86.54,77.97 85.52,77.97 82.98,80.51 79.67,80.51 78.58,81.6 73.48,81.6 70.43,84.64 58.16,84.64 57.06,83.54 v1(57.06,83.45)
VR_ON_MCP: length 8.8
  TOP w0.102: v1(56.46,81.11) 56.35,81.22 RC151.2 v2(55.18,81.93)
  IN4 w0.076: v1(56.46,81.11) 56.46,80.35 58.97,77.83 58.98,77.83 59.51,77.3 59.51,76.67 v4(59.66,76.52)
  GND5 w0.076: v5(59.66,76.09) v4(59.66,76.52)
  BOTTOM w0.102: UCPU1.F60 59.95,76.37 v5(59.66,76.09)
VR_SVID_ALRT#: length 37.6
  TOP w0.102: v8(26.22,82.03) 26.49,81.76 PU701.32
  IN4 w0.076: v8(26.22,82.03) 26.22,83.22 27.06,84.06 31.83,84.06 33.94,81.95 38.83,81.95 40.11,80.68 40.11,77.46 42.53,75.04 50.36,75.04 v3(51.28,74.13)
  BOTTOM w0.102: v8(26.22,82.03) 25.86,82.38 25.25,82.38 24.67,82.97 PR736.2 ; v3(51.28,74.13) 51.28,74.05 52.28,73.05 RC94.1
VR_SVID_CLK: length 39.3
  TOP w0.102: PU701.31 27.32,82.13 26.82,82.64 v1(26.73,82.64)
  IN4 w0.076: v3(51.3,73.37) 51.06,73.37 50.2,74.23 42.44,74.23 39.43,77.24 39.43,80.46 38.57,81.32 33.67,81.32 31.57,83.43 27.52,83.43 v1(26.73,82.64)
  BOTTOM w0.102: RC92.1 52.18,72.16 v2(51.56,72.78) 51.3,73.04 v3(51.3,73.37) ; v1(26.73,82.64) 25.33,82.64 25.2,82.77 25.2,82.99 25.33,83.12 26.31,83.12 26.44,83.25 26.44,83.4 26.31,83.53 25.69,83.53 25.56,83.65 25.56,83.92 25.69,84.05 PR735.2
VR_SVID_DAT: length 40.1
  TOP w0.102: v3(25.31,81.72) 25.91,81.12 PU701.1
  IN4 w0.076: v1(49.94,75.88) 49.74,75.68 42.79,75.68 40.75,77.73 40.75,80.94 39.07,82.61 34.18,82.61 31.92,84.87 26.88,84.87 25.38,83.38 25.38,81.8 v3(25.31,81.72)
  BOTTOM w0.102: v1(49.94,75.88) 49.94,75.37 RC96.1 ; v3(25.31,81.72) 24.42,81.72 24.29,81.85 24.29,82.36 24.16,82.49 23.91,82.49 23.78,82.36 23.78,81.85 23.65,81.72 23.27,81.72 v2(23.15,81.85) 23.15,83.22 23.27,83.35 PR737.2
VREF: length 46.8
  TOP w0.203: PU701.27 28.92,82.59 v1(28.97,82.64) 28.97,82.86 28.59,83.24 PC717.2
  TOP w0.254: PC717.2 29.73,83.48 PR726.2 ; PR704.2 27.21,74.14 24.99,74.14 PR705.2 24.7,74.36 24.24,73.9 23.45,73.9 PR706.2 22.12,75.23 v1(22.12,75.27)
  IN2 w0.254: v1(22.12,75.27) 22.12,75.76 23.03,76.67 23.03,82.03 24.45,83.45 28.16,83.45 v1(28.97,82.64)
  IN4 w0.254: v1(40.93,74.84) 39.42,74.84 39.11,75.15 31.8,75.15 31.67,75.27 v1(22.12,75.27)
  BOTTOM w0.254: v1(40.93,74.84) v2(40.93,73.44) 40.2,72.72 40.2,72.38 PH701.1 ; v1(28.97,82.64) 29.16,82.83 PR701.2
VRPG_MCP: length 8.2
  TOP w0.102: RC152.2 57.55,83.9 57.55,82.5 v2(57.94,82.11) v1(58.48,81.57)
  IN4 w0.076: v4(60.03,78.09) 60.03,80.02 v1(58.48,81.57)
  GND5 w0.076: v5(60.37,78.35) 60.12,78.09 v4(60.03,78.09)
  BOTTOM w0.102: UCPU1.C59 60.58,78.55 v5(60.37,78.35)
VTTREF_+1.2V: length 2.8
  TOP w0.102: v1(37.82,20.92) 37.96,20.77 PU601.4
  BOTTOM w0.102: PC609.1 37.87,20.97 v1(37.82,20.92) 37.6,20.92 v2(37.14,21.37)
WAKE#: length 103.5
  TOP w0.102: v1(168.35,61.33) 168.35,61.19 168.69,60.85 v2(169.2,60.85) 170.63,60.85 171.1,61.32 171.1,62.09 170.87,62.32 U676.2 ; RH146.1 107.64,63.67 108.5,62.8 v6(109.42,62.8)
  GND1 w0.076: v4(109.85,62.8) v6(109.42,62.8)
  IN1 w0.076: v1(168.35,61.33) 166.69,62.98 166.69,64.35 165.67,65.38 163.34,65.38 163.16,65.56 162,65.56 161.83,65.72 160.41,65.72 160.14,65.99 155.78,65.99 155.16,66.61 151.35,66.61 151.02,66.94 151.02,67.51 150.76,67.78 149.55,67.78 148.93,68.4 139.78,68.4 138.68,67.31 136.47,67.31 136.31,67.48 134.58,67.48 133.05,65.94 129.26,65.94 128.04,64.72 124.82,64.72 124.26,64.16 122.52,64.16 121.34,62.98 121,62.98 120.61,63.37 120.61,63.4 119.84,64.16 116.15,64.16 115.32,64.99 v4(115.11,64.99)
  IN2 w0.076: v4(115.11,64.99) 114.47,65.62 110.04,65.62 109.74,65.32 109.74,62.92 v4(109.85,62.8)
  IN4 w0.076: v4(115.11,64.99) 113.3,64.99 112.31,64 109.34,64 107.86,65.48 106.47,65.48 105.98,65 104.1,65 103.17,65.93 101.37,65.93 100.12,64.68 99.5,64.68 98.93,64.11 98.43,64.11 98.03,63.7 96.25,63.7 95.83,63.28 94.27,63.28 v4(93.99,63.56)
  GND5 w0.076: v5(94.33,64.07) 94.33,63.91 v4(93.99,63.56) ; v4(115.11,64.99) 115.29,65.16 v5(115.59,65.16)
  BOTTOM w0.102: RH128.2 116.06,65.53 116.06,65.53 115.69,65.16 v5(115.59,65.16) ; UCPU1.AJ5 94.25,63.99 v5(94.33,64.07)
WAKE_PCH#: length 37.2
  TOP w0.076: U34.L12 140.67,56.35 140.67,55.81
  TOP w0.102: 140.67,55.81 140.23,55.37 140.23,54.91 139.94,54.62 v1(137.92,54.62) 137.61,54.62 R604.2
  IN3 w0.076: v1(137.92,54.62) 137.01,55.52 137.01,57.96 136.51,58.47 136.51,59.3 135.94,59.87 135.94,63.4 v4(136.33,63.79)
  IN4 w0.076: v1(117.75,65.65) 118.87,64.53 121.35,64.53 121.52,64.35 127.33,64.35 127.34,64.36 132.3,64.36 133.41,63.26 135.8,63.26 v4(136.33,63.79)
  BOTTOM w0.102: RH310.1 RH128.1 116.98,66.42 v1(117.75,65.65)
WIN8_BTN_SW#: length 60.3
  TOP w0.102: U34.H1 v6(141.92,62.42) ; v2(150.93,64.39) 150.51,63.97 v1(149.54,63.97) 149.11,63.54 149.11,62.06 148.29,61.24 RP16.1
  GND1 w0.076: v6(141.92,62.42) 141.92,62.96 v4(142.02,63.06)
  IN2 w0.076: v4(142.02,63.06) 142.26,63.06 143.63,64.43 144.72,64.43 144.93,64.63 147.42,64.63 148.01,64.03 149.47,64.03 v1(149.54,63.97)
  IN4 w0.076: v1(149.54,63.97) 150.04,64.48 153.15,64.48 153.19,64.51 153.19,64.51 153.43,64.76 153.43,64.76 153.45,64.78 154.84,64.78 155.36,65.29 156.37,65.29 156.65,65.01 158.2,65.01 159.81,63.4 160.99,63.4 162.45,64.86 165.01,64.86 165.2,65.05 166.95,65.05 167.94,66.04 170.19,66.04 173.53,69.38 173.53,69.81 173.81,70.09 174.53,70.09 176.37,68.25 177.85,68.25 178.33,68.73 180.4,68.73 v1(180.45,68.68)
  BOTTOM w0.102: v1(180.45,68.68) 180.45,69.85 177.96,72.34 177.96,74.17 177.11,75.02 C1142.1 R977.1 R978.2
WIN8_BTN_SW#_C: length 2.8
  BOTTOM w0.102: R978.1 176.24,76.9 v2(176.24,78.17) JLVDS2.19
WL_OFF#: length 132.5
  TOP w0.102: v1(178.92,48.09) 179.08,48.25 181.92,48.25 183.12,49.44 184.03,49.44 184.74,48.73 193.22,48.73 193.45,48.96 195.08,48.96 195.46,48.58 195.46,46.93 194.96,46.43 194.96,45 195.28,44.68 195.28,43.38 194.96,43.07 194.96,40.08 194.47,39.59 v2(194.47,39.14) 194.47,38.83 194.93,38.37 194.93,36.87 194.58,36.52 Q344.3
  IN1 w0.076: v4(96.31,73.1) 96.82,72.59 97.61,72.59 99.32,70.88 100.3,70.88 102.23,68.95 103.28,68.95 104.49,67.74 106.74,67.74 107.07,68.07 108.82,68.07 109.49,67.4 109.49,67.04 111.11,65.43 113.95,65.43 114.29,65.77 115.43,65.77 116.51,64.69 124.04,64.69 124.86,65.52 125.73,65.52 126.68,66.47 132.79,66.47 134.38,68.06 136.33,68.06 137.01,68.75 138.77,68.75 138.96,68.94 149.18,68.94 149.77,68.34 152.59,68.34 153.56,67.37 159.24,67.37 159.72,66.89 162.21,66.89 162.72,66.38 163.56,66.38 163.85,66.09 166.04,66.09 168.33,63.8 168.33,63.27 169.82,61.79 169.82,60.03 175.34,54.5 175.34,52.12 178.92,48.53 v1(178.92,48.09)
  GND5 w0.076: v5(96.27,73.68) 96.27,73.14 v4(96.31,73.1)
  BOTTOM w0.076: UCPU1.L2 v5(96.27,73.68)
WL_OFF#_R: length 9.9
  TOP w0.102: v2(196.2,43.04) 195.59,43.04 v1(195.55,43) 195.43,42.89 195.43,41.87 R1137.2 195.37,41.31 195.17,41.11 195.17,39.84 194.84,39.51 194.84,38.75 195.26,38.33 195.26,37.33 195.41,37.17 Q344.1
  BOTTOM w0.102: JNGFF1.48 195,43.56 v1(195.55,43)
WLAN_EN: length 6.9
  TOP w0.102: D115.1 173.44,40.26 R1388.1 173.48,39.03 174.23,39.03 175.01,38.24 175.01,38.05 v2(175.35,37.71) 175.55,37.52 U718.3
XCLK_BIASREF: length 4.9
  TOP w0.102: v3(81.97,80.97) v2(81.59,81.34) 81.45,81.49 RH113.1
  BOTTOM w0.102: v3(81.97,80.97) 81.43,80.42 81.43,79.36 81.04,78.98 81.04,78.75 81.35,78.45 UCPU1.C26
XDP_BPM0#: length 46.5
  TOP w0.102: JXDP.21 27.07,55.61 27.59,55.08 27.59,54.34 28.02,53.91 28.02,53.13 28.16,53 28.56,53 v6(28.71,53.15)
  GND1 w0.076: v4(29.36,53.25) 28.81,53.25 v6(28.71,53.15)
  IN1 w0.076: v4(29.36,53.25) 29.46,53.25 30.78,54.57 33.8,54.57 42.17,62.94 44.66,62.94 45.26,63.54 46.81,63.54 49.78,66.51 49.78,68.41 50.72,69.35 52.17,69.35 55.8,72.99 58.64,72.99 59.23,73.57 59.23,73.92 59.59,74.28 v4(59.63,74.28)
  GND5 w0.076: v4(59.63,74.28) 59.63,74.64 v5(59.66,74.66)
  BOTTOM w0.102: v5(59.66,74.66) 59.88,74.88 UCPU1.J60
XDP_BPM1#: length 47.9
  TOP w0.102: v6(28.25,52.69) 28.18,52.69 27.82,53.05 27.82,53.75 27.39,54.18 27.39,54.94 27.22,55.11 JXDP.23
  GND1 w0.076: v4(28.49,52.24) 28.25,52.48 v6(28.25,52.69)
  IN1 w0.076: v4(59.61,75.27) 59.61,75.27 59.16,74.82 58.47,74.82 58.26,74.61 58.26,73.52 57.96,73.22 55.78,73.22 52.09,69.53 49.73,69.53 47.47,67.27 47.47,66.92 45.49,64.94 45.49,64.12 44.48,63.12 42.09,63.12 33.73,54.75 30.71,54.75 29.61,53.66 29.2,53.66 28.95,53.4 28.95,53.28 28.62,52.95 28.62,52.36 v4(28.49,52.24)
  GND5 w0.076: v4(59.61,75.27) 59.66,75.32 v5(60.04,75.32)
  BOTTOM w0.102: v5(60.04,75.32) 60.04,75.62 UCPU1.H60
XDP_DBRESET#: length 6.2
  TOP w0.102: RH451.1 C1237.1 RH367.1 35.12,49.01 v2(34.49,49.01) 33.92,49.01 33.59,49.34 33,49.34 32.77,49.11 JXDP.48
XDP_PIN60: length 4.6
  TOP w0.102: JXDP.60 32.97,46.11 v2(34.03,45.05) 34.91,45.05 R1198.1
XDP_PRDY#: length 50.1
  TOP w0.102: v6(28.96,54.95) 28.96,55.64 28.25,56.35 28.25,58.76 27.41,59.61 JXDP.5
  GND1 w0.076: v4(29.45,54.32) 29.45,54.46 v6(28.96,54.95)
  IN1 w0.076: v4(58.5,75.2) 58.48,75.17 57.23,75.17 53.73,71.67 49.29,71.67 46.02,68.39 46.02,67.38 43.28,64.64 43.28,64.2 42.55,63.47 41.94,63.47 33.57,55.11 30.56,55.11 29.82,54.37 29.51,54.37 v4(29.45,54.32)
  GND5 w0.076: v4(58.5,75.2) 58.55,75.25 v5(58.94,75.25)
  BOTTOM w0.102: v5(58.94,75.25) 58.94,75.21 UCPU1.J62 58.35,75.21 57.62,75.21 56.65,76.19 56.18,76.19 T263.1
XDP_PREQ#: length 51.3
  TOP w0.102: JXDP.3 27.24,60.11 29.27,58.08 29.27,53.76 v6(29.17,53.66)
  GND1 w0.076: v4(28.79,53.84) 28.99,53.84 v6(29.17,53.66)
  IN1 w0.076: v4(57.91,73.7) 56.01,73.7 52.02,69.71 49.65,69.71 47.21,67.27 47.21,66.92 45.31,65.01 45.31,64.2 44.41,63.3 42.02,63.3 33.65,54.93 30.63,54.93 29.54,53.84 v4(28.79,53.84)
  GND5 w0.076: v5(58.36,73.9) 58.11,73.9 v4(57.91,73.7)
  BOTTOM w0.102: T264.1 55.96,74.82 57.06,73.72 58.19,73.72 v5(58.36,73.9) 58.63,74.17 UCPU1.K62
XDP_PWRGD: length 3.3
  TOP w0.102: JXDP.39 24.86,51.11 24.7,51.27 24.7,51.73 23.85,52.58 R1180.2
XDP_TCK0: length 8.6
  TOP w0.102: JXDP.57 24.18,46.61 24.05,46.74 RH411.2 RH374.2 23.66,45.72 24.26,45.72 v3(24.53,45.99)
  BOTTOM w0.102: v2(20.78,45.95) 21.18,45.55 22.37,45.55 RH446.2 24.45,46.06 v3(24.53,45.99)
XDP_TCK1: length 2.8
  TOP w0.102: RH373.2 24.36,46.93 24.77,46.93 24.95,47.11 JXDP.55
XDP_TDI: length 6.1
  TOP w0.102: v3(30.12,47.59) 30.6,47.11 JXDP.56
  BOTTOM w0.102: RH371.2 RH414.1 32.6,47.21 32.11,46.72 v2(31.54,46.72) 30.98,46.72 v3(30.12,47.59)
XDP_TDI_SWITCH: length 10.5
  TOP w0.102: v2(37.12,48.72) 36.63,48.72 RH413.2 33.64,47.82 v6(33.09,48.36)
  GND1 w0.076: v4(31.95,48.13) 32.86,48.13 v6(33.09,48.36)
  GND5 w0.076: v5(32.24,47.57) 32.24,47.8 31.91,48.13 v4(31.95,48.13)
  BOTTOM w0.102: U663.10 34.37,46.63 RH414.2 33.32,47.69 32.35,47.69 v5(32.24,47.57)
XDP_TDO: length 71
  TOP w0.102: RH412.2 23.32,44.03 23.7,44.41 26.98,44.41 28.53,45.96 28.53,49.75 v1(28.76,49.97) 29.1,49.97 29.27,49.81 29.27,49.19 30.35,48.11 JXDP.52 32.86,48.11 33.46,47.51 35.14,47.51 RH369.2
  IN1 w0.076: 46.62,49.77 v4(46.62,49.76) ; 46.62,49.77 46.81,49.77 47.44,50.41 48.19,50.41 54.22,56.44 54.22,61.7 54.83,62.31 54.83,65.06 56.33,66.56 v1(56.33,67.03) ; 46.62,49.77 28.96,49.77 v1(28.76,49.97)
  GND5 w0.076: v4(46.62,49.76) 46.85,49.52 v5(46.93,49.52)
  BOTTOM w0.102: v1(56.33,67.03) 56.18,67.18 54.62,67.18 54.15,67.65 RH38.2 ; v5(46.93,49.52) 46.93,47.36 46.21,46.63 v2(44.37,46.63) U663.7
XDP_TMS: length 9.9
  TOP w0.102: v1(29.5,47.59) 29.5,47.32 30.21,46.61 JXDP.58
  BOTTOM w0.102: U663.13 34.76,48.54 34.67,48.64 33.94,48.64 RH372.2 33.42,48.12 32.63,48.12 32.44,48.31 v2(31.83,48.31) 31.6,48.31 31.29,48.63 30.54,48.63 v1(29.5,47.59)
XDP_TRST#: length 15
  TOP w0.102: JXDP.54 32.89,47.61 33.54,46.96 v2(34.01,46.96) 34.89,46.96 35.47,46.39 37.24,46.39 37.73,46.88 37.73,48.58 39.44,50.29 v3(39.44,50.89)
  BOTTOM w0.102: U663.4 39.91,48.54 39.44,49.01 v3(39.44,50.89)
XTAL24_IN: length 6
  TOP w0.102: YH2.3 84.28,83.15 84.28,82.68 CH23.1 84.09,82.49 RH117.2 84.16,81.55 84.16,80.98 v3(84.13,80.94)
  BOTTOM w0.102: v3(84.13,80.94) 84.13,80.82 83.74,80.43 82.69,80.43 82.08,79.82 81.94,79.82 UCPU1.A25
XTAL24_OUT: length 9.2
  TOP w0.102: v3(84.83,80.96) 84.83,80.93 85,81.1 RH117.1 85,82.41 CH24.1 84.89,82.72 84.89,84.55 YH2.1
  BOTTOM w0.102: UCPU1.B25 81.91,79.48 81.98,79.55 82.19,79.55 82.8,80.16 84.34,80.16 84.78,80.61 84.78,80.91 v3(84.83,80.96)
N13303482: length 4.1
  TOP w0.102: PQ105.5 114.48,28.33 PC115.2 115.22,28.66 115.35,28.54 PR124.1 v2(115.82,30.07)
N13303498: length 4.5
  TOP w0.102: PQ105.6 113.83,28.25 PC115.1 113.14,28.66 112.83,28.36 PR126.2 112.47,29.95 v2(112.69,30.18)
N13303522: length 5.4
  TOP w0.102: v2(118.28,24.21) 117.93,24.56 PQ104.2 117.93,27.84 PR108.1 118.36,27.95 118.85,27.46 PC114.2
N13303550: length 5.1
  TOP w0.102: PR123.1 PR125.2 114.38,24.52 114.38,25.11 114.48,25.21 PQ105.2 114.48,26.15 114.23,26.4 112.69,26.4 v2(112.24,25.95)
N13303632: length 3.4
  TOP w0.102: v2(116.06,60.36) 115.4,59.71 PR110.2 115.4,58.46 PC116.1 115.42,58.44 PQ106.2
N13305100: length 11.6
  TOP w0.254: PQ101.1 186.18,76.57 186.86,77.25 186.86,78.93 187.27,79.34 188.81,79.34 188.81,81.08 189.63,81.9 v2(189.67,81.9) 191.67,81.9 PL102.1
N13305156: length 7.5
  TOP w0.102: PR120.1 139.66,48.02 v2(139.96,47.71)
  TOP w0.305: PR121.2 137.51,49.26 137.51,48.68 136.96,48.13 PQ103.5 ; PR121.2 137.34,49.29 136.31,48.26 PQ103.6 ; PR121.2 138.5,49.29 138.97,48.82 PR120.1
N13305200: length 3.3
  TOP w0.102: v2(135.66,44.69) 135.96,45 PR119.2
  TOP w0.254: PQ103.2 136.96,45.81 137.48,45.29 PC113.1 PR119.2
N13305312: length 3.5
  TOP w0.305: 138.27,45.4 138.22,45.45 138.04,45.45 137.61,45.88 PQ103.3
  TOP w0.508: PR122.2 139.63,44.04 v2(138.76,44.91) 138.27,45.4
N13308162: length 6
  TOP w0.102: PC208.2 168.56,43 169.15,43.59 v2(169.4,43.59)
  TOP w0.254: PR202.2 167.62,39.7 PC209.1 167.58,40.55 167.14,41 v6(167.14,41.06) ; PC208.2 PR206.1 167.59,42.51 167.16,42.09 v6(167.16,41.92)
  GND1 w0.254: v6(167.14,41.06) 167.14,41.9 v6(167.16,41.92)
N13308186: length 2.5
  TOP w0.254: PR203.1 166.68,41.47 PC209.2 167.98,41.47 168.33,41.11 168.33,40.47
  vias: v2(172.98,40.27)
N13308194:
  vias: v7(172.13,36.93)
N13308216: length 0.8
  TOP w0.102: v2(154.31,40.97) 153.77,40.97 153.6,41.14
N13308220:
  vias: v7(162.43,39.8)
N13308316: length 1.6
  TOP w0.102: v2(166.17,38.87) 166.75,38.87 PR202.1
N13308376: length 6.4
  TOP w0.254: PQ204.1 143.81,38.19 145.57,39.95 v2(145.57,40.07) 145.57,40.75 PR224.1 146.13,41.03 146.67,41.57 146.67,42 147.11,42.45 PU201.10
N13308392: length 3.5
  TOP w0.102: v2(141.8,38.94) PD201.1
  TOP w0.508: PD201.1 141.81,40.28 PR210.1
N13308446: length 14.7
  TOP w0.254: PU201.13 149.21,40.4 PC227.1 149.41,39.66 149.41,38.23 147.59,36.41 143.75,36.41 v1(143.53,36.19)
  BOTTOM w0.254: PR216.3 143.83,39.46 143.52,39.14 v2(143.52,37.12) 143.52,36.21 v1(143.53,36.19)
N13308458: length 14.6
  TOP w0.254: PU201.12 148.71,39.98 PC227.2 148.76,38.71 PC228.1 148.71,38.24 147.42,36.94 v2(147.25,36.94) 147.11,36.8 143.39,36.8 v1(142.81,36.22)
  BOTTOM w0.254: v1(142.81,36.22) 143.1,36.51 143.1,39.18 142.82,39.46 PR216.2
N13308964: length 3.3
  TOP w0.254: PQ204.2 145.74,37.54 146.49,38.29 v2(146.62,38.29) PC229.1 PR225.2
N13309974: length 5.6
  BOTTOM w0.102: v2(139.81,33.02) 139.81,32.33 139.3,31.83 PQ206.4
  BOTTOM w0.508: PQ206.4 136.72,31.83 136.02,31.13 PR230.2
N13310108: length 4.5
  TOP w0.102: PR209.2 140.33,46.51 v2(140.11,46.29)
  TOP w0.254: PR209.2 141.8,47.41 141.37,47.84 141.37,48.21 141.13,48.45 PQ202.1
N13312034: length 3.7
  TOP w0.254: PR308.2 213.41,30.02 213.13,29.74 212.47,29.74 212.08,29.36 212.08,28.49 211.84,28.25 PU301.4
N13312134: length 2.9
  TOP w0.102: v2(206.92,51.8) PR318.2
  TOP w0.254: PR318.2 205.05,51.19 PU302.4
N13315263: length 5.3
  BOTTOM w0.102: v2(177.17,36.09) 175.57,36.09 175.24,35.76 PR338.2
  BOTTOM w0.254: PU304.4 172.98,34.85 173.31,34.52 174.16,34.52 175.17,35.52 PR338.2
N13316609: length 3.9
  TOP w0.102: v2(208.5,59.35) 208.01,59.84 PR328.2
  TOP w0.254: PU303.4 206.84,61.56 207.86,60.54 PR328.2
N13318174: length 2.3
  TOP w0.102: PD302.2 198.44,32.55 PR341.2 v2(197.5,31.55)
N13324169: length 0.5
  BOTTOM w0.102: 39.59,25.01 v2(39.59,25.51)
N13350623: length 1.1
  TOP w0.102: v2(33.66,84.32) 33.33,83.99 PC724.1
N13350707: length 1
  BOTTOM w0.254: PC719.1 30.46,72.25 PR730.2
N13350735: length 3.9
  BOTTOM w0.203: PR730.1 30.46,74.73 29.55,75.64 v2(29.45,75.64) 28.58,75.64 28.09,75.15 PU703.6
N13350791: length 7.4
  BOTTOM w0.102: v7(31.8,70.45) 31.35,70.45 PC719.2
  BOTTOM w0.203: 29.1,75.27 28.72,75.27 28.49,75.04 PU703.7
  BOTTOM w0.254: PC719.2 29.76,72.03 29.76,74.61 29.1,75.27
N13350855: length 4.4
  TOP w0.203: PU701.16 29.72,77.54 30.74,76.52 v2(31,76.52) 32.19,76.52 32.42,76.29 32.42,75.58 PR717.2
N13350881: length 5.6
  TOP w0.102: PR731.1 v2(24.7,84.89)
  TOP w0.203: PC720.2 27.5,83.48 28.06,82.92 28.25,82.92 28.48,82.69 28.48,82.35 28.52,82.31 PU701.28
  TOP w0.254: PC720.2 PR731.1
N13350885: length 16.6
  TOP w0.203: PU701.14 28.92,77.14 29.09,76.97 29.09,76.7 30.35,75.44 30.35,75.41 PC709.1
  TOP w0.254: v1(31.93,76.03) 31.81,76.03 31.3,75.53 PR709.2 PC709.1
  IN4 w0.254: v1(31.93,76.03) 32.21,75.76 39.77,75.76 39.87,75.65 v3(40.32,75.65)
  BOTTOM w0.254: PH701.2 39.67,72.73 40.32,73.38 v3(40.32,75.65)
N13351105: length 4.2
  TOP w0.102: v2(22.36,80.2) 22.49,80.33 23.63,80.33 23.73,80.23 23.86,80.23 PR721.1
  TOP w0.203: PU701.4 25.84,79.92 25.76,79.84 24.25,79.84 PR721.1
N13351187: length 1.9
  BOTTOM w0.102: v2(29.05,57.1) 28.89,57.26 PR708.1
  BOTTOM w0.254: PR708.1 PH702.2
N13351357: length 17.1
  IN2 w0.254: v1(30.42,63.97) 30.25,63.79 29.76,63.79 29.41,63.44 29.41,61.51 26.33,58.43 26.33,57.21 25.75,56.63 24.36,56.63 v1(24.3,56.68)
  BOTTOM w0.102: v1(24.3,56.68) 23.86,56.68 v2(23.58,56.96)
  BOTTOM w0.254: v1(24.3,56.68) 24.71,56.68 25.04,56.35 PR702.2 ; PL701.2 30.94,64.49 v1(30.42,63.97)
N13351493: length 6.1
  TOP w0.102: PC715.2 24.27,83.6 23.18,84.68 v2(22.93,84.68)
  TOP w0.203: PR725.2 24.27,81.77 25.32,80.72 PU701.2
  TOP w0.254: PC715.2 PR725.2
N13353049: length 3.2
  BOTTOM w0.102: 39.06,75.64 PR715.2 39.05,76.16 v2(39.05,77.5)
  BOTTOM w0.254: PC711.1 39.63,75.07 39.06,75.64
N13353061: length 3.3
  BOTTOM w0.102: PR715.1 37.66,76.7 37.42,76.94 v2(36.63,76.94)
  BOTTOM w0.203: PR715.1 37.26,75.74 PU702.6
N13353141: length 4
  BOTTOM w0.203: PU702.7 37.66,75.25 37.87,75.46 38.72,75.46 39.06,75.12 39.06,74.41
  BOTTOM w0.254: PC711.2 39.06,74.18 39.06,74.41
N13353255: length 4.3
  BOTTOM w0.102: PR729.1 18.63,56.02 18.63,54.7 v2(19.23,54.09)
  BOTTOM w0.254: PR729.1 19.11,56.85 19.63,57.37 PH703.2
N13353293: length 13.5
  IN2 w0.254: v1(23.35,64.01) 23.06,63.72 22.73,63.72 22.19,63.18 22.19,56.43 v1(21.56,55.79)
  BOTTOM w0.102: v7(22.17,55.49) 21.86,55.79 v1(21.56,55.79)
  BOTTOM w0.254: PR724.2 21.36,55.59 v1(21.56,55.79) ; PL702.2 23.35,66.85 v1(23.35,64.01)
N13374846: length 1.3
  BOTTOM w0.254: PC503.1 PR506.2
N13384798: length 4.6
  TOP w0.102: v2(195.09,33.15) 195.09,33.57 196.03,34.51 197.05,34.51 PR342.2 PD301.2
N16935361: length 2.8
  BOTTOM w0.102: T244.1 177.92,49.07 177.27,48.42 JSATA1.45
N16935447: length 2.2
  BOTTOM w0.102: JSATA1.47 177.68,47.62 T245.1
N16940180: length 3.5
  TOP w0.102: v1(165.41,51.47) 166.28,52.34 T243.1
  BOTTOM w0.102: v1(165.41,51.47) 165.66,51.22 JSATA1.38
N16940198: length 3.2
  TOP w0.102: T242.1 166.07,53.28 v1(166.07,53.1)
  BOTTOM w0.102: JSATA1.36 166.56,52.02 166.07,52.51 v1(166.07,53.1)
N17638789: length 1.8
  TOP w0.254: R943.1 Q329.1
N17654244: length 7.7
  TOP w0.254: C1160.1 R989.1 176.21,26.17 174.89,26.17 174.68,26.38 Q326.1 174.68,27.46 v2(174.52,27.62) 174.1,28.04 174.1,29.76 173.87,29.98 Q329.2
N18675747: length 3.8
  TOP w0.102: MR226.2 135.95,61.23 135.95,61.99 134.92,63.02 134.47,63.02 134.31,63.18 MC284.1
N18675796: length 6.5
  TOP w0.076: v6(140.57,59.87) 140.59,59.85 141.17,59.85 U34.J5
  TOP w0.102: R249.2 137.51,60.12 v6(137.83,60.12)
  GND1 w0.076: v6(140.57,59.87) 140.65,59.95 v4(141.43,59.95) ; v6(137.83,60.12) 138.25,60.12 v4(138.49,60.36)
  IN1 w0.076: v4(138.49,60.36) 139.22,60.36 139.78,59.8 140.47,59.8 140.65,59.98 141.4,59.98 v4(141.43,59.95)
N28729492: length 2.8
  TOP w0.102: R1091.2 v2(144.22,74.54) 144.22,74.99 143.9,75.31 U638.5
N34287396: length 2.2
  TOP w0.076: v2(96.88,72.49) 96.88,71.58 MC94.1 95.98,70.68 MR256.1
N34514472: length 12
  BOTTOM w0.076: 94.08,54.95 94.08,55 v2(93.36,55.71) 93.14,55.94 93.14,56.81 92.92,57.02 92.92,58.54 93.21,58.83 93.75,58.83 94.2,59.28 94.2,60.27 94.61,60.68 UCPU1.AP4
  BOTTOM w0.102: 94.08,54.95 94.74,54.29 95.96,54.29 96.54,53.71 97.05,53.71 RH313.2
N34536136: length 5.7
  BOTTOM w0.076: UCPU1.AD4 95.23,66.12 95.43,66.12 95.65,65.9 95.65,65.82 95.83,65.65 95.84,65.65 95.86,65.62 96.71,65.62 96.71,65.62 96.82,65.62 97.23,66.03 97.37,66.03
  BOTTOM w0.102: 97.37,66.03 99.65,66.03 T123.1
N35032609: length 4.7
  TOP w0.102: v6(92.76,66.23) 92.74,66.23 92.31,65.8 CH1206.1 92.79,65.3 93.05,65.3 93.68,64.67 v7(93.68,63.92)
  GND1 w0.076: v6(92.76,66.23) v4(92.4,66.59)
  GND5 w0.076: v4(92.4,66.59) 92.4,66.1 v5(92.37,66.08)
  BOTTOM w0.102: UCPU1.AE7 92.56,65.9 v5(92.37,66.08)
N36180324: length 3.9
  TOP w0.102: RH346.2 CH1218.1 83.55,63.44 82.89,62.78 v2(82.89,61.46)
N39696490: length 2.6
  TOP w0.102: US1.15 206.49,44.29 R1118.1 206.86,45.3 v2(207.19,45.63)
N39697285: length 2.4
  TOP w0.102: US1.16 205.99,44.65 R1117.1 206,45.5 v2(205.87,45.63)
N39815594: length 14.2
  IN4 w0.076: v4(58.59,75.99) 55.67,75.99 53.54,78.12 53.54,81.55 52.32,82.77 52.22,82.77 52.22,82.76 51.71,82.76 v1(51.4,83.07)
  GND5 w0.076: v5(59,75.99) v4(58.59,75.99)
  BOTTOM w0.102: UCPU1.H61 59.28,75.71 v5(59,75.99) ; v1(51.4,83.07) 50.98,83.49 T226.1
N39815596: length 4.6
  BOTTOM w0.102: T227.1 55.09,76.44 56.7,76.44 57.75,75.39 58.37,75.39 UCPU1.H62
N39815598: length 16.4
  IN4 w0.076: v4(60.5,74.33) 59.97,74.86 59.51,74.86 58.74,75.63 55.62,75.63 53.23,78.02 53.23,81.06 52.45,81.85 51.68,81.85 v3(51.2,81.37)
  GND5 w0.076: v5(60.37,73.85) 60.37,74.21 v4(60.5,74.33)
  BOTTOM w0.102: UCPU1.K59 60.6,74.08 v5(60.37,73.85) ; v3(51.2,81.37) 50.74,81.83 T228.1
N39815600: length 4.3
  BOTTOM w0.102: T229.1 54.5,77.17 55.02,76.64 56.8,76.64 57.78,75.67 UCPU1.H63
N39815609: length 13.4
  IN4 w0.076: v3(51.2,80.69) 51.2,80.13 52.95,78.37 52.95,77.82 55.91,74.87 58.21,74.87 v4(58.67,74.41)
  GND5 w0.076: v4(58.67,74.41) 58.95,74.41 v5(59.13,74.59)
  BOTTOM w0.102: v3(51.2,80.69) 49.75,80.69 T231.1 ; v5(59.13,74.59) 59.3,74.76 UCPU1.J61
N39815611: length 11.9
  IN4 w0.076: v4(59.63,73.65) 59.23,73.24 56.41,73.24 52.06,77.58 52.06,77.84 v1(52.04,77.86)
  GND5 w0.076: v4(59.63,73.65) 59.84,73.85 v5(60.01,73.85)
  BOTTOM w0.102: v1(52.04,77.86) 51.33,77.86 T230.1 ; v5(60.01,73.85) 59.95,73.92 UCPU1.K60
N39955939:
  vias: v2(126.14,35.14)
N39956017: length 5
  TOP w0.102: v2(121.88,31.85) 121.97,31.76 124.39,31.76 C1212.1 125.51,32.22 125.53,32.2 U664.12
N39956029:
  vias: v2(126.32,30.37)
N39956087: length 4.2
  TOP w0.102: v2(122.87,33.31) 123.12,33.57 124.39,33.57 C1214.1 125.31,33.11 125.33,33.13 126.17,33.13 126.3,33 U664.10
N40621945: length 2.5
  TOP w0.102: R536.2 162.47,85.27 162.25,85.05 Q71.1 161.54,85.44 v2(162.01,85.92)
N41042732: length 1.3
  TOP w0.102: v2(208.96,38.58) 208.9,38.52 R1165.1
N41155497: length 4.7
  TOP w0.102: U653.8 154.09,81.31 R1175.2 153.56,82.61 v2(153.56,84.2)
N41482702: length 2.9
  TOP w0.102: v2(195.82,53.48) R1188.1
  TOP w0.305: R1188.1 194.53,53.78 193.95,53.78 193.61,53.45 U671.8
N41500627: length 1.6
  TOP w0.102: C1242.1 117.08,69.27 117.46,69.65 v2(117.46,70.28)
N41500629: length 3.9
  TOP w0.102: U673.15 116.42,66.26 117.08,65.61 R1190.1 117.08,63.87 v2(117.28,63.67)
N41505847: length 4
  TOP w0.102: v2(119.11,65.77) 118.8,66.08 117.63,66.08 R1191.1 116.95,66.76 U673.16
N41574995: length 3.2
  TOP w0.102: U677.8 186.88,54.16 186.71,54.33 R1204.1 187.7,54.85 v2(187.95,55.11)
N41624107: length 10.6
  TOP w0.102: R1215.2 R1214.2 172.08,59.78 171.39,60.46 171.39,62.69 171.11,62.97 U676.1 169.03,62.97 R1202.1 R1338.1 169.28,64.46 v2(169.28,65.03) 169.52,65.03 170,65.51 U709.4
N41625248: length 20.8
  TOP w0.102: Q347.2 176.3,64.67 176.09,64.47 174.45,64.47 173.88,63.9 173.88,62.84 174.42,62.31 174.42,58.38 173.87,57.84 v2(172.1,57.84) 171.81,57.84 171.38,58.27 171.38,60.12 171.04,60.46 168.35,60.46 167.71,61.1 167.71,62.03 C1246.1 R1202.2
N41869823: length 3.8
  TOP w0.102: U673.17 116.79,67.26 C1244.1 117.61,68.08 v2(118.96,68.08)
N42153648: length 1.6
  TOP w0.102: R1247.2 166.67,45.51 166.67,45.8 166.68,45.8 U716.3
N42233415: length 3.5
  TOP w0.102: v1(193.87,43.04) 193.69,43.22 R1255.1 194.33,44.31 v2(194.8,44.31)
  BOTTOM w0.102: v1(193.87,43.04) 193.49,43.42 JNGFF1.42
N42542298: length 17
  TOP w0.102: v6(141.74,59.45) 141.58,59.6 U34.J6 ; v6(148.91,68.58) 148.85,68.64 R921.1 147.49,69.52 R1297.1
  GND1 w0.076: v4(142.01,59.91) 141.74,59.64 v6(141.74,59.45) ; v4(148.76,68.01) 148.93,68.17 148.93,68.57 v6(148.91,68.58)
  IN3 w0.076: v4(142.01,59.91) 142.15,59.91 143.31,61.07 145.34,61.07 146.01,61.74 146.01,62.66 146.25,62.9 146.25,67.31 147.38,68.44 148.33,68.44 v4(148.76,68.01)
N42546805: length 3.2
  BOTTOM w0.102: R1279.2 181.16,77.67 v2(180.61,78.22) 180.24,78.59 JLVDS2.11
N42775202: length 5.4
  TOP w0.102: Q351.3 93.5,49.58 92.01,48.09 v1(91.19,48.09) 90.76,48.09 v7(90.39,47.73)
  BOTTOM w0.102: v1(91.19,48.09) 90.24,49.05 RH24.1
N42993790: length 3.8
  TOP w0.102: U679.C2 188.41,39.56 R1131.1 190.34,37.63 v2(191.24,37.63)
N43042471: length 5.9
  TOP w0.102: R886.1 8.84,22.4 D81.1 9.53,23.41 v1(9.96,23.84) 10.29,23.84 v2(10.78,23.36)
  BOTTOM w0.102: JFAN1.2 9.8,24 v1(9.96,23.84)
N43467905: length 31.9
  TOP w0.102: v1(228.58,7.18) 229.31,6.45 R920.1 228.96,4.88 228.27,5.56 Q320.6 ; v2(225.58,22.66) 224.89,23.36 222.36,23.36 v1(222.3,23.42) 222.28,23.41 Q358.2
  IN2 w0.076: v1(222.3,23.42) 224.14,21.58 229.15,21.58 229.97,20.76 229.97,15.51 228.57,14.11 228.57,7.19 v1(228.58,7.18)
N43742420: length 5.4
  TOP w0.102: v2(155.65,46.22) 154.93,46.93 C964.2 155.49,48 155.49,48.75 155.49,48.75 155.49,50.47 155.49,50.48 U637.13
N43742429: length 2.9
  TOP w0.102: U637.12 v2(154.69,49.55) 154.93,49.3 C964.1
N44370994: length 1.9
  TOP w0.102: C1257.1 166.68,49.74 U716.12
N44372336: length 3.1
  TOP w0.102: v2(167.67,52.84) 167.67,50.48 167.9,50.25 R1319.1
N44373242: length 1.8
  TOP w0.102: U716.10 167.48,49.84 C1248.1
N44377351: length 2.3
  TOP w0.102: U717.12 139.1,22.84 139.36,23.1 v2(139.73,23.1) 140.22,23.1 C1163.1
N44380707: length 1.4
  TOP w0.102: C1202.1 179.52,37.48 179.48,37.52 U718.12
N44531503: length 1.9
  TOP w0.102: U719.12 122.2,57.22 C355.1
N44535135: length 1.9
  TOP w0.102: C1278.1 121.53,58.95 122.46,58.02 U719.10
N44948988: length 4.3
  TOP w0.102: v1(68.04,32.88) 67.51,33.41 66.97,33.41 v2(66.82,33.26) 65.92,33.26 65.13,32.47 RD7.1
  BOTTOM w0.102: v1(68.04,32.88) 67.65,33.27 UD6.L8
N44951196: length 7.2
  TOP w0.102: v1(75.79,35.44) 75.62,35.28 RD8.1 74.91,34.58 v2(74.61,34.89)
  BOTTOM w0.102: UD7.L8 79.16,33.27 78.79,32.89 77.51,32.89 76.48,33.91 76.48,34.61 75.79,35.3 v1(75.79,35.44)
N44953884: length 5.2
  TOP w0.102: RD11.1 93.2,33.74 92.11,33.74 91.87,33.51 v1(91.87,32.85) 91.75,32.73 v2(91.24,32.73)
  BOTTOM w0.102: UD9.L8 92.27,33.24 91.88,32.85 91.87,32.85 v1(91.87,32.85)
N44956010: length 6
  TOP w0.102: v2(100.03,34.04) 100.03,34.28 v1(100.47,34.72) 100.51,34.77 RD12.1
  BOTTOM w0.102: v1(100.47,34.72) 100.47,34.55 100.86,34.16 100.86,34.05 102,32.91 103.3,32.91 103.66,33.27 UD10.L8
N44984260: length 3.2
  TOP w0.102: v2(19.08,32.47) 19.48,32.87 v1(19.48,32.88) 18.98,33.38 18.98,33.95 RD1.1
  BOTTOM w0.102: v1(19.48,32.88) 19.86,33.27 UD1.L8
N44985933: length 6.3
  TOP w0.102: v2(29.01,34.99) 28.68,34.66 v1(28.17,34.66) 28.06,34.77 28.06,35.77 RD2.1
  BOTTOM w0.102: UD2.L8 31.44,33.31 31.09,33.66 29.37,33.66 28.37,34.66 v1(28.17,34.66)
N44994261: length 2.8
  TOP w0.102: RD5.1 46.59,32.47 46.03,33.03 v2(45.6,33.03) 45.09,33.03 v1(44.91,32.86)
  BOTTOM w0.102: v1(44.91,32.86) 44.91,32.86 44.91,32.86 44.9,32.86 44.9,32.91 44.54,33.27 UD4.L8
N44996448: length 6.4
  TOP w0.102: RD6.1 52.64,35.24 52.97,35.57 v8(52.97,35.65)
  BOTTOM w0.102: UD5.L8 56.08,33.24 55.72,32.88 54.43,32.88 53.11,34.2 53.11,35.51 v8(52.97,35.65)
N45067794: length 2.2
  TOP w0.102: v2(67.62,53.05) 67.44,53.05 67.14,53.35 CD91.2 66.61,53.02 66.48,52.9 RD23.1
N45067802: length 2.1
  TOP w0.102: CD92.2 63.68,51.57 63.76,51.5 RD24.1 63.76,50.3 v2(64.07,50)
N45067875: length 2.1
  TOP w0.102: v2(59.85,50) 59.85,50.46 RD16.1 CD89.2
N45134129: length 2.9
  TOP w0.102: v2(17.46,32.35) 17.63,32.52 18.32,32.52 v1(18.59,32.8) 18.42,32.97 RD79.1
  BOTTOM w0.102: UD1.L9 19.06,33.27 v1(18.59,32.8)
N45134345: length 6.7
  TOP w0.102: v2(28.15,34.02) 27.53,34.65 v1(27.53,35.24) 26.98,35.79 RD80.1
  BOTTOM w0.102: UD2.L9 28.87,33.27 27.6,34.53 27.6,35.22 27.58,35.24 v1(27.53,35.24)
N45134724: length 4.1
  TOP w0.102: v2(43.59,32.65) 43.8,32.86 v1(44.13,32.86) 44.63,33.36 RD81.1
  BOTTOM w0.102: v1(44.13,32.86) 43.73,33.27 UD4.L9
N45134937: length 6.3
  TOP w0.102: RD82.1 53.52,35.46 v1(53.64,35.57) 53.64,35.92 52.89,36.66 v2(52.89,36.97)
  BOTTOM w0.102: UD5.L9 55.2,33.19 54.5,33.19 53.61,34.07 53.61,35.55 v1(53.64,35.57)
N45136338: length 3.3
  TOP w0.102: v2(64.9,34.4) RD83.1 65.37,33.36 v1(65.71,33.7)
  BOTTOM w0.102: UD6.L9 66.15,33.27 65.71,33.71 v1(65.71,33.7)
N45136742: length 5.2
  TOP w0.102: v2(76.21,36.16) 76.43,35.94 v1(76.43,35.45) 76.51,35.36 RD84.1
  BOTTOM w0.102: UD7.L9 77.59,33.27 76.85,34.01 76.85,35.02 v1(76.43,35.45)
N45137119: length 6.5
  TOP w0.102: v1(90.32,32.74) 90.67,33.08 91.14,33.08 91.55,33.49 91.55,33.69 v2(91.78,33.92) 91.88,34.02 93.3,34.02 93.96,33.36 RD85.1
  BOTTOM w0.102: UD9.L9 91.25,33.05 90.61,33.05 90.34,32.78 90.34,32.74 v1(90.32,32.74)
N45137332: length 4.2
  TOP w0.102: v2(101.54,34.19) 101.54,34.19 101.54,34.19 101.1,34.63 v1(101.1,34.65) 101.65,35.19 RD86.1
  BOTTOM w0.102: v1(101.1,34.65) 101.09,34.65 101.37,34.37 101.37,33.95 102.05,33.27 UD10.L9
N45346908:
  vias: v2(135.19,21.35)
N45346942: length 3.3
  TOP w0.102: v2(140.93,21.55) 140.93,22.29 C1281.1 140.23,22.57 139.7,22.04 U717.10
N45347302: length 0.6
  TOP w0.102: 179.2,34.53 v2(179.76,34.53)
N45347364: length 1.4
  TOP w0.102: U718.10 179.41,36.72 179.51,36.61 C1292.1
N45348400: length 0.6
  TOP w0.102: v2(177.34,39.7) 177.95,39.7
N45359755: length 0.9
  TOP w0.102: MC1141.1 MR976.2
N45360524: length 3.2
  BOTTOM w0.102: T246.1 177.48,46.82 JSATA1.49
N45904951: length 0.8
  BOTTOM w0.102: 212.11,68.58 212.36,68.83 v7(212.36,69.3)
N46001630: length 5.2
  TOP w0.102: Q349.3 171,47.3 172.16,48.45 U688.6 173.04,49.89 R1282.2 173.57,50.18 v2(174.07,49.67)
N46001695: length 10.9
  TOP w0.102: v2(175.83,54.57) R1281.2 174.71,54.42 v1(174.25,53.96) ; v1(169.67,51.78) 169.67,49.66 169.7,49.62 Q349.6
  IN2 w0.076: v1(169.67,51.78) 169.84,51.96 169.84,52.49 171.7,54.34 173.87,54.34 v1(174.25,53.96)
N46002340: length 4
  TOP w0.102: v2(162.96,55.13) 162.96,54.85 R1289.2 R1291.2 161.31,53.67 161.55,53.43 161.55,53.19 161.43,53.06 U690.1
N46318274: length 2
  BOTTOM w0.102: v2(209.96,75.6) 209.96,74.33 210.46,73.84
N46339533: length 19.4
  TOP w0.102: 108.15,72.82 108.3,72.67 113.77,72.67 114.22,73.11 v6(115.68,73.11) ; 108.15,72.82 Q360.4 ; 108.15,72.82 107.9,72.57 C1227.1 ; v1(118.7,75.16) 119.4,75.16 v2(120.24,76) 120.24,76.71 R1380.2 R1379.2
  GND1 w0.076: v6(115.68,73.11) v4(116.16,73.11)
  IN3 w0.076: v1(118.7,75.16) 117.1,75.16 116.16,74.22 v4(116.16,73.11)
N46339563: length 3.8
  TOP w0.102: v2(120.62,78.77) 120.3,79.08 118.98,79.08 R1379.1 117.78,78.63 117.74,78.67 Q361.3
N46339565: length 4.9
  TOP w0.102: R1380.1 118.83,77.2 118.83,76.85 v2(118.47,76.49) 118.02,76.49 117.66,76.85 115.63,76.85 115.39,77.08 Q361.6
N46463118: length 17
  TOP w0.076: 162.24,65.46 161.85,65.07 161.44,65.07 161.3,64.92 161.3,64.72 161.15,64.57 160.8,64.57 U636.F6
  TOP w0.102: R537.1 166.24,57.68 D74.1 D94.1 167.92,59.9 167.06,60.76 v2(167.06,60.99) 167.06,64.52 165.92,65.66 164.09,65.66 163.57,66.18 162.96,66.18 162.24,65.46
N47139833: length 10.2
  TOP w0.102: v1(195.43,46.22) 195.9,46.22 v2(196.02,46.1) 196.18,45.94 R1208.1 ; v3(190.43,42.98) 190.43,43.47 R1200.1
  IN1 w0.076: v1(195.43,46.22) 194.41,46.22 191.89,43.7 191.15,43.7 v3(190.43,42.98)
  BOTTOM w0.102: JNGFF1.30 190.49,43.04 v3(190.43,42.98)
N47140041: length 4.1
  TOP w0.254: PR347.2 208.74,32.59 v1(209.15,32.99)
  BOTTOM w0.254: v1(209.15,32.99) 209.52,32.99 v2(209.79,33.26) 210,33.48 PR301.1 209.99,34.52 PQ300.1
N47180160: length 4
  TOP w0.102: v2(197.59,47) 196.93,46.34 v1(196.93,45.71) 197.09,45.55 R1209.1
  BOTTOM w0.102: JNGFF1.58 197.49,45.15 v1(196.93,45.71)
N47181052: length 4.7
  TOP w0.102: v3(191.03,42.98) 191.03,42.6 v2(192.08,41.55) 192.35,41.27 R1210.1
  BOTTOM w0.102: JNGFF1.32 191,43.01 v3(191.03,42.98)
N47181069: length 6.3
  TOP w0.102: v1(191.89,42.99) 191.89,42.42 192.6,41.71 194.01,41.71 R1212.1 v2(194.44,42.51)
  BOTTOM w0.102: v1(191.89,42.99) 191.49,43.39 JNGFF1.34
N47519532: length 1.6
  BOTTOM w0.102: v2(169.54,78.02) 169.64,77.91 R1322.1
N47519599: length 2.9
  TOP w0.102: C1230.1 173.81,75.39 v2(174.09,75.67) v3(174.78,75.67)
  BOTTOM w0.102: U721.4 175.02,75.42 v3(174.78,75.67)
N47890214: length 1.2
  TOP w0.102: U722.6 157.58,74.24 157.64,74.18 C1297.1
N76702116: length 2.6
  TOP w0.102: U637.6 151.49,53.84 151.14,54.19 v2(151.14,54.57) 151.14,55.32 C968.1
N76768428: length 2.3
  TOP w0.102: v2(144.56,81.2) 144.99,81.2 C974.1 145.5,80.39 145.2,80.09 U638.14
N86178716: length 2.5
  TOP w0.102: R910.1 v2(230.18,16.4)
  TOP w0.254: LED1.2 230.72,15.45 230.56,15.3 R910.1
N86209671: length 2.8
  TOP w0.102: R911.1 229.83,12.1 v2(229.83,13.07)
  TOP w0.254: LED2.2 230.76,11.85 230.64,11.74 R911.1
N86209740: length 4.1
  TOP w0.102: v2(228.99,7.96) 228.99,8.6 229.84,9.45 R912.1
  TOP w0.254: R912.1 230.52,9.45 v1(230.86,9.12) 231.5,8.47 LED3.2
N86209815: length 2
  TOP w0.254: R913.1 230.18,6.02 v8(230.7,5.51) 231.5,4.7 LED4.2
N86209896: length 5
  TOP w0.254: LED5.2 231.35,1.05 230.64,1.77 230.64,1.96 230.08,2.51 v2(230.08,2.68) 230.73,3.33 230.73,4.34 R916.1
N88620271: length 2.9
  BOTTOM w0.102: v2(30.6,54.48) 30.6,55.03 31.12,55.55 RTCR1.1
  BOTTOM w0.508: RTCR1.1 31.76,55.58 32.12,55.21 RTCD1.2
N89386241: length 3.5
  BOTTOM w0.102: UD3.1 43.29,49.15 43.16,49.02 43.16,48.7 43.17,48.69 43.17,48.55 43.53,48.2 RD3.2 43.05,47.71 v2(42.56,47.23)
N89389377: length 6
  BOTTOM w0.102: RD4.2 46.35,49.31 45.86,49.8 UD3.2 43.02,49.8 42.7,50.11 42.7,50.24 v2(42.49,50.46)
N89456409: length 3.7
  BOTTOM w0.102: UD8.1 51.64,49.14 51.38,48.88 51.38,48.29 v2(51.76,47.92) 52.25,47.42 52.64,47.42 RD9.2
N89456446: length 5.5
  BOTTOM w0.102: RD10.2 55.62,47.36 54.96,47.36 54.88,47.43 v2(54.88,47.82) 54.88,48.68 53.77,49.79 UD8.2
N90173610: length 1
  BOTTOM w0.102: 213.53,70.56 213.53,70.45 v7(214.13,69.85)
N93297419: length 5.5
  TOP w0.102: Q305.2 170.03,78.56 v2(170.86,79.39) 171.29,79.82 171.29,81.31 171.06,81.53 170.43,81.53 170.23,81.34 U708.4
N93297423:
  vias: v2(166.59,79.59)
N96981838: length 4.9
  TOP w0.102: v8(172.84,26.05) 173.02,25.87 R944.2
  BOTTOM w0.102: v8(172.84,26.05) 172.84,26.07 172.85,26.08 JBL1.3

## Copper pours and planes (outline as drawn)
+0.6VSP on TOP (solid shape): 34.27,25.36 34.71,25.36 34.71,25.89 35.36,25.89 35.77,25.47 35.89,25.47 36.45,24.92 36.75,24.92 36.82,24.92 36.89,24.94 36.92,24.95 37.4,24.47 39.13,24.47 39.41,24.19 39.41,23.5 39.55,23.35 39.55,22.33 39.46,22.24 39.18,22.24 39.04,22.38 39.04,22.57 39.06,22.64 39.06,22.71 38.96,22.98 38.69,23.1 38.41,22.99 38.3,22.71 38.31,22.6 38.35,22.5 38.35,22.2 38.3,22.2 38.1,22.08 38.1,21.85 38.11,21.84 38.11,21.81 38.23,21.68 39.12,21.68 39.17,21.63 39.17,21.53 39.12,21.48 38.01,21.48 37.58,21.9 37.58,22.42 37.23,22.77 34.09,22.77 33.79,23.08 33.79,24.83 33.56,25.06 33.56,25.67 33.78,25.89 34.27,25.89
+0.675VS on TOP (solid shape): outline of 1810 points within 31.3,25.49 93.53,39.67
+1.2V_B+ on TOP (solid shape): outline of 549 points within 51.62,18.86 88.07,25.5
+1.2V_B+ on BOTTOM (solid shape): 86.96,23.68 86.96,22.19 86.78,22.01 84.21,22.01 84.03,22.19 84.03,23.73 84.29,23.98 86.66,23.98
+1.2V_B+ on IN1 (solid shape): 44.9,19.77 44.9,18.76 42.87,18.76 42.74,18.88 42.74,19.52 43,19.77 44.35,19.77
+1.2VP on BOTTOM (solid shape): 62.1,24.02 62.86,24.02 62.86,24.57 63.3,24.57 63.3,24.02 66.82,24.02 68.78,22.06 72.89,22.06 73.12,21.83 73.12,19.28 72.89,19.04 66.92,19.04 66.62,19.34 66.62,21.17 65.73,22.06 62.55,22.06 62.15,21.65 62.15,19.75 61.53,19.13 56.46,19.13 55.32,20.28 55.32,23.76 55.57,24.02 61.65,24.02 61.65,24.57 62.1,24.57
+1.2VP on IN1 (solid shape): 68.78,22.06 72.89,22.06 73.25,21.7 73.25,19.14 72.97,18.86 67.1,18.86 66.62,19.34 66.62,21.17 65.73,22.06 62.55,22.06 62.15,21.65 62.15,19.27 61.61,18.73 56.87,18.73 55.32,20.28 55.32,23.39 55.95,24.02 66.82,24.02
+1.2VP on IN1 (solid shape): outline of 111 points within 36.65,21.88 42.01,24.64
+1.2VS_DVDD on TOP (solid shape): 120.78,50.49 120.78,46.98 120.74,46.98 120.41,46.5 120.93,46.24 120.96,46.26 121.04,46.18 122.35,46.18 122.41,46.11 122.41,45.91 122.38,45.89 120.61,45.89 120.5,45.99 120.15,45.99 119.82,46.32 119.82,47.08 119.82,47.21 119.69,47.33 116.69,47.33 116.54,47.49 116.54,48.25 116.77,48.48 117.16,48.48 118.89,50.21 118.89,50.36 119.27,50.74 120.54,50.74
+1.2VS_DVDD on BOTTOM (solid shape): 120.58,51.17 120.58,50.31 120.44,50.18 118.94,50.18 118.42,49.66 118.42,48.67 118.13,48.38 116.8,48.38 116.66,48.52 116.66,49.71 116.96,50.01 117.06,50.01 117.54,50.49 118.29,51.25 120.5,51.25
+1.2VS_DVDD on IN1 (solid shape): outline of 756 points within 118.18,38.06 134.31,51.9
+1.05VA on TOP (solid shape): outline of 107 points within 106.12,60.24 116.04,72.29
+1.05VA on BOTTOM (solid shape): 124.08,81.58 124.08,80.98 124.12,80.94 124.64,80.94 124.65,80.93 124.65,80.52 124.61,80.48 124.09,80.48 124.09,79.74 124.12,79.71 124.62,79.71 124.64,79.69 124.64,79.35 124.58,79.28 124.1,79.28 124.1,78.02 123.86,77.78 122.76,77.78 122.62,77.92 122.62,78.97 122.51,79.08 122.45,79.15 122.38,79.21 122.35,79.23 122.35,80.47 122.62,80.73 122.62,81.64 122.73,81.75 123.91,81.75
+1.05VA on VCC: 112.56,56.1 112,56.65 111.69,56.98 111.67,56.98 111.44,57.22 111.45,63.74 111.83,64.12 111.83,64.58 111.45,64.96 111.44,70.32 111.44,70.43 110.17,71.7 110.17,72.75 113.7,76.29 120.05,76.29 121.9,78.14 121.9,80.64 122.96,81.7 125.71,81.7 131.63,75.78 131.63,75.25 130.45,74.05 130.36,73.97 130.36,71.87 131.76,70.47 131.76,66.49 130.36,65.09 130.36,61.92 129.87,61.43 127.08,61.43 124.14,58.49 124.14,56.58 123.65,56.1
+1.05VDX_MODPHY on TOP (solid shape): 98.22,76.1 98.23,76.11 102.1,76.11 102.2,76.01 102.42,75.82 102.66,75.64 104.16,74.99 105.8,75 106.82,75.37 107.7,76 110.28,76 110.47,76.19 112.4,76.19 112.55,76.03 112.55,73.36 112.05,72.86 108.69,72.86 108.6,72.95 108.6,73.24 108.6,73.24 108.6,73.67 108.42,73.85 108.42,73.85 108.05,73.97 107.82,73.66 107.82,73.41 107.64,73.24 106.36,73.24 106,73.6 102.75,73.6 102.58,73.6 101.82,74.36 99.46,74.36 99.46,74.36 98.94,74.36 98.6,74.7 98.6,74.7 98.38,74.92 97.19,74.92 96.88,75.23 95.28,75.23 95.01,74.95 95.01,73.82 94.84,73.66 93.45,73.66 93.24,73.88 93.24,76.61 93.34,76.72 97.61,76.72
+1.05VS on TOP (solid shape): 71.2,85.47 71.2,83.02 70.94,82.77 69.76,82.77 69.57,82.96 69.57,85.68 69.67,85.78 70.89,85.78
+1.05VS on TOP (solid shape): 85.13,75.73 85.13,75.13 85.9,74.36 85.9,74.35 87.03,74.35 87.19,74.19 87.19,70.78 87.1,70.69 84.82,70.69 84.58,70.92 84.58,74.27 83.97,74.88 83.97,75.74 84.14,75.91 84.96,75.91
+1.05VS on TOP (solid shape): 92.21,83.76 92.21,81.13 92.43,80.91 93.45,80.91 93.59,80.78 93.59,78.98 90.69,76.09 90.15,76.09 90.08,76.12 90.05,76.19 89.77,76.56 89.36,76.34 89.25,76.23 89.25,75.95 89.18,75.88 88.63,75.88 88.39,76.11 88.39,76.73 88.03,77.09 87.91,77.09 87.68,77.33 87.68,77.64 87.88,77.85 88.5,77.85 88.81,77.55 90.6,77.55 91.21,78.16 91.21,78.17 91.43,78.39 91.43,80.97 91.31,81.09 91.31,83.67 91.49,83.85 92.13,83.85
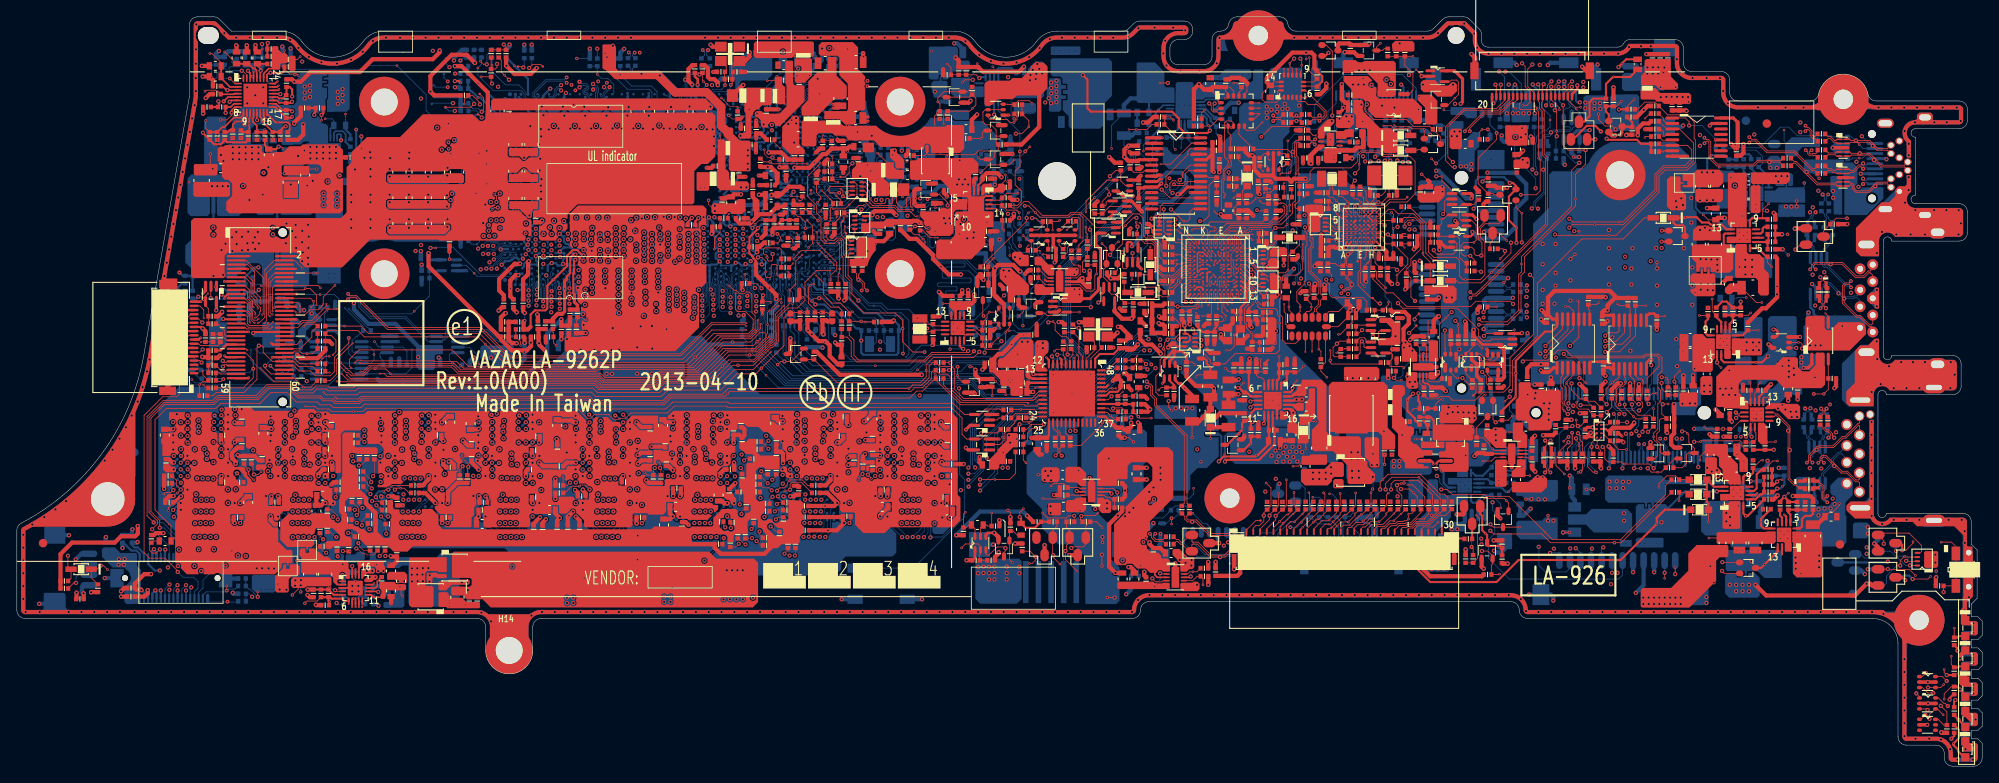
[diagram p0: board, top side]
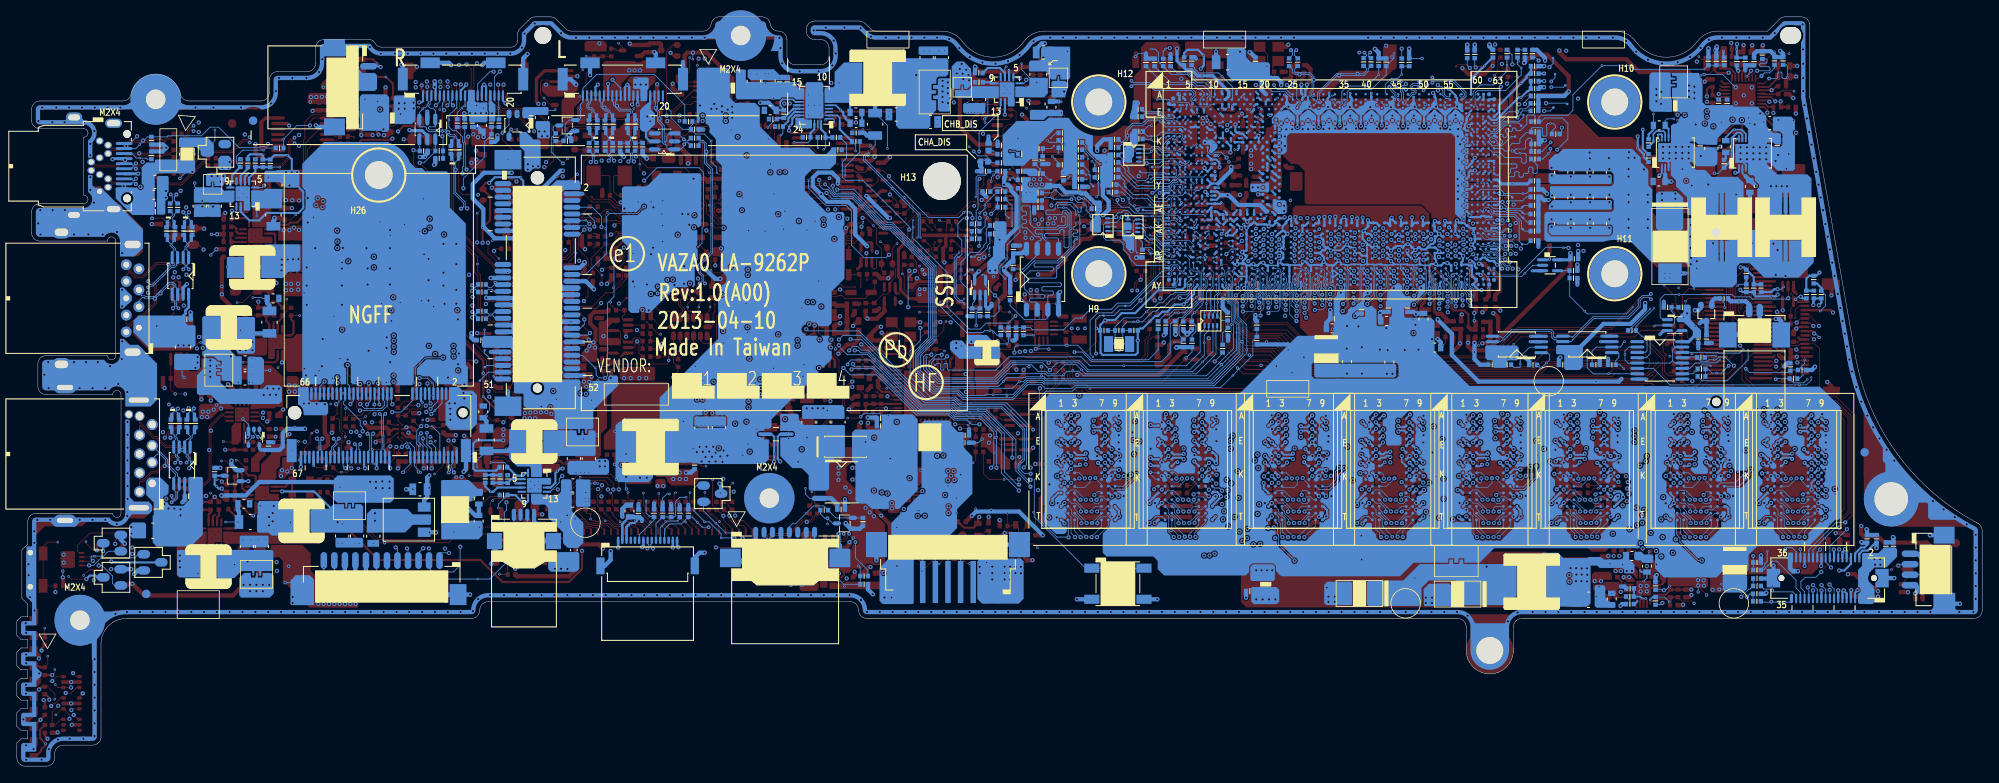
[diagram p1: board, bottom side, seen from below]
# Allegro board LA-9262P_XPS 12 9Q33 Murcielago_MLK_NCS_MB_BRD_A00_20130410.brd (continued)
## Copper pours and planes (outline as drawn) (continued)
+1.05VS on TOP (solid shape): 112.92,67.31 112.92,66.22 112.85,66.14 111.64,66.14 111.3,65.8 111.3,63.44 110.87,63.01 109.56,63.01 109.55,63.02 109.42,63.06 109.29,63.02 109.28,63.01 108.57,63.01 107.98,63.6 108.03,63.7 108.08,63.7 108.1,63.69 108.57,63.88 108.12,64.12 108.08,64.11 108.05,64.12 107.77,64.4 107.77,64.87 107.32,65.32 107.32,65.85 107.41,65.94 109.43,65.94 109.85,66.36 110.32,66.36 110.88,66.39 110.82,66.94 110.82,67.22 110.98,67.39 112.85,67.39
+1.5VS on BOTTOM (solid shape): 109.84,81.45 110.44,81.45 110.58,81.3 110.58,79.58 110.47,79.46 108.94,79.46 108.93,79.51 108.83,80.01 108.66,80.49 108.66,80.5 108.66,81.16 108.94,81.45 109.65,81.45 109.65,82 109.84,82
+1.05VS on IN4 (solid shape): 87.14,71.82 87.14,70.33 87.03,70.22 84.85,70.22 84.77,70.29 84.77,71.8 84.86,71.88 87.08,71.88
+1.05VS on VCC: 99.36,51.27 99.13,51.5 99.13,52.14 96.83,54.42 96.83,57.6 94.27,60.16 93,60.16 91.73,61.43 89.2,61.43 88.72,61.92 88.72,63.31 88.08,63.95 88.08,65.64 88.69,66.26 95.08,66.26 96.22,65.11 105.83,65.11 105.98,65.26 105.98,65.47 105.83,65.62 96.43,65.62 95.29,66.76 88.48,66.76 87.57,65.85 87.57,64.1 86.52,64.1 86.05,64.57 86.05,64.89 86.54,65.39 86.54,66.79 88.05,68.29 101.89,68.29 102.04,68.44 102.04,68.65 101.89,68.8 90.24,68.8 89.89,69.15 89.89,69.17 89.85,69.22 89.85,71.1 90.71,71.97 93.81,71.97 94.16,71.61 94.16,71.48 94.31,71.34 99.48,71.34 99.63,71.48 99.63,71.7 99.48,71.84 94.65,71.84 94.02,72.48 90.5,72.48 89.34,71.31 89.34,69.16 88.98,68.8 87.84,68.8 86.04,67 86.04,65.6 85.69,65.25 84.74,65.25 84.64,65.35 84.64,77.33 85,77.69 100.46,77.69 103.64,74.51 106.63,74.51 110.93,70.21 110.94,64.75 111.32,64.37 111.32,64.33 110.94,63.95 110.94,61.28 110.93,57.22 104.98,51.27 ; 1 cut-out
+1.5VS_3.3VS_AUDIO on TOP (solid shape): 140.52,21.68 140.52,21.04 140.27,20.79 138.49,20.79 138.23,21.04 138.23,21.68 138.36,21.81 139.63,21.81 139.69,21.86 139.77,21.86 139.84,21.93 140.27,21.93
+1.5VS_3.3VS_AUDIO on IN2 (solid shape): outline of 324 points within 81.66,63.72 88.46,68.16
+1.05VS_B+ on BOTTOM (solid shape): 148.08,82.71 148.08,79.46 147.86,79.24 144.3,79.24 144.11,79.29 143.92,79.24 142.85,79.24 142.62,79.46 141.2,79.46 140.97,79.24 140,79.24 139.95,79.29 139.95,80.48 140.05,80.58 140.61,80.58 140.86,80.84 140.86,81.19 140.99,81.32 146.7,81.32 146.88,81.5 146.88,82.66 147.02,82.8 147.99,82.8
+1.05VS_VCCST on TOP (solid shape): 86.58,67.27 86.58,66 86.2,65.62 84.87,65.62 84.87,65.67 84.61,65.9 84.36,65.67 84.36,65.62 82.72,65.62 82.51,65.83 82.51,66.65 82.76,66.89 85.18,66.89 85.69,67.4 86.45,67.4
+1.05VS_VCCST on BOTTOM (solid shape): 84.3,67.27 84.3,66.26 83.67,65.62 82.91,65.62 82.65,65.87 82.65,66.76 83.22,66.76 83.22,66.71 83.23,66.67 83.24,66.62 83.26,66.58 83.29,66.54 83.33,66.51 83.37,66.48 83.41,66.46 83.46,66.45 83.51,66.45 83.56,66.45 83.6,66.46 83.65,66.48 83.69,66.51 83.73,66.54 83.75,66.58 83.78,66.62 83.79,66.67 83.8,66.71 83.8,66.76 83.79,66.81 83.78,66.86 83.75,66.9 83.73,66.94 83.69,66.97 83.65,67 83.6,67.02 83.56,67.03 83.51,67.03 83.46,67.03 83.41,67.02 83.37,67 83.33,66.97 83.29,66.94 83.26,66.9 83.24,66.86 83.23,66.81 83.22,66.76 82.65,66.76 82.65,67.06 82.86,67.26 83.78,67.26 83.92,67.4 84.18,67.4
+1.05VS_VCCST on IN2 (solid shape): 49.67,80.84 49.67,79.74 49.53,79.59 48.54,79.59 48.31,79.82 48.31,80.84 48.46,80.99 49.52,80.99
+1.05VS_VCCST on IN3 (solid shape): 83.82,66.7 83.82,65.87 83.64,65.7 82.78,65.7 82.66,65.82 82.66,66.75 82.81,66.91 83.61,66.91
+1.05VS_VCCST on IN4 (solid shape): 49.85,80.23 49.85,79.46 49.6,79.21 48.79,79.21 48.13,79.87 48.13,80.76 48.36,80.99 49.09,80.99
+1.05VS_VCCST on IN4 (solid shape): outline of 98 points within 54.05,82.42 58.62,84.67
+1.5VSP on BOTTOM (solid shape): 111.82,85.27 111.82,83.98 111.93,83.87 113.02,83.87 113.25,83.64 113.25,82.64 113.18,82.56 111.22,82.56 110.75,82.09 110.75,81.78 110.57,81.6 109.99,81.6 109.99,82.16 109.51,82.16 109.51,81.6 108.55,81.6 108.35,81.8 108.35,85.38 108.48,85.51 111.58,85.51
+1.05VSP on BOTTOM (solid shape): 130.12,83.71 130.12,79.67 129.05,78.6 129.05,76.11 128.68,75.74 125.27,75.74 124.96,76.05 124.96,77.25 124.26,77.95 124.26,79.14 124.81,79.14 124.82,79.13 124.82,79.88 124.8,79.9 124.29,79.9 124.27,79.92 124.27,80.33 124.28,80.34 124.8,80.34 124.81,80.35 124.81,81.08 124.8,81.1 124.25,81.1 124.24,81.11 124.24,81.69 123.99,81.94 123.12,81.94 122.82,82.24 122.82,83.94 123.02,84.14 129.69,84.14
+1.5VSP_LX on BOTTOM (solid shape): 113.19,81.79 113.19,80.98 113.41,80.76 114.79,80.76 114.87,80.68 114.87,79.58 114.78,79.49 111.45,79.49 111,79.93 111,81.71 111.1,81.81 113.17,81.81
+1.5VSP_VIN on BOTTOM (solid shape): 121.25,80.35 121.28,80.35 121.79,80.35 121.79,80.35 122.05,80.35 122.05,79.64 121.8,79.39 116.92,79.39 116.84,79.47 116.84,80.71 116.92,80.79 117.92,80.79 117.94,80.81 119.98,80.81 120.44,80.35 120.54,80.35 121.05,80.35 121.07,80.35 121.07,80.89 121.25,80.89
+1.8VP on TOP (solid shape): 202.75,70.4 202.75,69.33 202.22,68.8 197.9,68.8 197.9,69.05 198.48,69.05 198.48,69.56 197.9,69.56 197.9,70.35 197.95,70.4 199.09,70.4 199.24,70.55 199.3,70.55 199.65,70.9 202.24,70.9
+1.8VP on BOTTOM (solid shape): 202.72,70.76 203.93,70.76 204.06,70.63 204.06,69.42 204.04,69.4 202.24,69.4 201.59,68.75 200.25,68.75 199.92,69.07 199.92,70.69 200.06,70.84 202.65,70.84
+1.8VS on TOP (solid shape): 197.67,69.96 197.67,68.52 198.33,67.86 198.33,66.28 198.1,66.05 196.5,66.05 196.04,66.51 196.04,69.71 196.43,70.09 197.54,70.09
+1.8VS on IN3 (solid shape): outline of 2495 points within 180.88,33.87 199.49,70.35
+1.8VSP_LX on BOTTOM (solid shape): 204.21,68.41 205.58,68.41 205.66,68.34 205.66,67.17 205.63,67.15 205.63,66.51 205.4,66.28 202.08,66.28 201.97,66.39 201.97,68.55 202.01,68.6 204.02,68.6
+1.35V_DDR on TOP (solid shape): 18.4,35.59 18.69,35.59 18.91,35.37 18.91,35.02 18.8,34.91 17.7,34.91 17.38,35.24 17.38,35.79 17.53,35.94 18.05,35.94
+1.35V_DDR on TOP (solid shape): 91.53,35.4 91.61,34.99 92.03,34.91 92.23,34.71 92.23,34.3 92.15,34.22 91.53,34.22 91.31,34.44 91.26,34.88 90.81,34.96 90.71,35.06 90.71,35.26 90.95,35.5 90.95,35.53 90.98,35.6 91.05,35.63 91.11,35.64 91.18,35.66 91.27,35.66
+1.35V_DDR on TOP (solid shape): outline of 5521 points within 65.09,49.24 81.93,66.64
+1.35V_DDR on TOP (solid shape): outline of 18081 points within 17.29,22.8 112.12,42.68
+1.35V_DDR on BOTTOM (solid shape): 55.84,34.73 55.93,34.64 56.04,34.6 56.1,34.56 56.13,34.49 56.23,34.23 56.48,34.12 56.55,34.1 56.58,34.03 56.61,33.94 56.67,33.86 56.7,33.79 56.67,33.71 56.43,33.48 56.43,33.39 56.35,33.39 56.34,33.42 55.98,33.55 55.78,33.22 55.79,33.2 55.65,33.06 55.54,33.06 55.54,33.12 55.54,33.13 55.57,33.33 55.47,33.5 55.44,33.57 55.47,33.65 55.51,33.69 55.72,34.01 55.6,34.37 55.57,34.44 55.6,34.52 55.72,34.63 55.72,34.67 55.78,34.73
+1.35V_DDR on BOTTOM (solid shape): outline of 13936 points within 16.8,22.42 111.51,57.45
+3.3VDX_SSD on TOP (solid shape): 169.65,68.78 169.65,67.74 168.9,66.99 166.76,66.99 166.42,67.34 166.42,68.01 166.57,68.16 168.16,68.16 168.38,68.39 168.38,68.77 168.6,68.99 169.45,68.99
+3.3VDX_SSD on TOP (solid shape): 171.07,56.73 171.07,55.46 170.6,55 169.69,55 169.46,55.24 169.46,55.91 169.23,56.14 168.61,56.14 168.52,56.05 167.33,56.05 167.22,56.16 167.22,57.04 167.31,57.13 170.66,57.13
+3.3VDX_SSD on BOTTOM (solid shape): outline of 878 points within 162.06,39.59 178.25,69.63
+3.3VDX_SSD on VCC: 169.09,45.05 169.09,45.91 167.32,47.69 167.32,52.01 166.43,52.9 166.43,67.42 168.31,69.3 171.34,69.3 171.77,68.87 171.77,60.05 174.99,56.83 175.03,56.77 175.03,51.86 171.72,48.56 171.72,46.9 169.88,45.05
+3.3VDX_SSD_LX on BOTTOM (solid shape): 175,39.97 175,36.56 174.04,35.6 172.56,35.6 172.38,35.42 172.38,34.43 172.31,34.35 171.22,34.35 171.14,34.43 171.14,36.86 172.8,36.86 172.81,36.8 172.82,36.75 172.84,36.69 172.87,36.64 172.9,36.6 172.94,36.56 172.99,36.53 173.03,36.5 173.09,36.49 173.14,36.48 173.2,36.47 173.25,36.48 173.31,36.49 173.36,36.52 173.41,36.54 173.45,36.58 173.49,36.62 173.52,36.67 173.54,36.72 173.56,36.77 173.57,36.83 173.57,36.88 173.56,36.94 173.54,36.99 173.52,37.04 173.49,37.09 173.45,37.13 173.41,37.17 173.36,37.2 173.31,37.22 173.25,37.23 173.2,37.24 173.14,37.24 173.09,37.22 173.03,37.21 172.99,37.18 172.94,37.15 172.9,37.11 172.87,37.07 172.84,37.02 172.82,36.97 172.81,36.91 172.8,36.86 171.14,36.86 171.14,39.76 171.52,40.14 174.82,40.14
+3.3VDX_SSD_VIN on BOTTOM (solid shape): 168.85,33.91 168.85,32.6 169.23,32.22 171.04,32.22 171.21,32.38 172.33,32.38 172.39,32.33 172.39,31.31 172.16,31.08 170.76,31.08 170.38,30.7 170.38,29.55 168.6,27.77 168.6,26.76 168.6,26.76 168.6,26.48 168.05,25.93 166.82,25.93 166.19,26.57 166.19,28.92 167.57,30.3 167.57,33.89 167.76,34.08 168.69,34.08
+3.3VDX_SSDP on BOTTOM (solid shape): 165.6,39.89 165.6,39.36 166.19,39.36 166.19,39.87 166.21,39.89 166.39,39.89 166.39,39.36 166.42,39.33 167,39.33 167,39.92 169.41,39.92 170.83,39.92 170.91,39.84 170.91,36.97 170.81,36.87 164.84,36.87 164.74,36.97 164.74,39.74 164.92,39.92 165.58,39.92
+3V_BATMAN on TOP (solid shape): 113.35,55.2 113.35,54.51 113.04,54.2 111.8,54.2 111.68,54.07 111.68,53.11 111.6,53.04 111.46,53.04 111.38,53.11 111.38,53.98 110.78,54.59 110.78,55.21 110.83,55.26 113.29,55.26
+3V_PCH on TOP (solid shape): 118.89,58.43 119.01,58.43 120.11,57.33 120.16,57.26 120.23,57.2 120.23,56.25 119.95,55.97 118.68,55.97 118.42,55.71 118.42,55.21 118.31,55.1 117.87,55.1 117.7,55.27 117.7,57.03 116.77,57.95 116.77,58.92 117.04,59.19 118.12,59.19
+3V_PCH on TOP (solid shape): 102.04,62.57 102.04,61.28 101.41,60.41 101.04,59.4 98.94,59.4 98.94,60.29 99.5,60.29 99.75,60.54 99.75,62.57 100.01,62.83 101.78,62.83
+3V_PCH on TOP (solid shape): 163.62,52.93 163.62,52.87 164.19,52.87 164.4,52.67 164.4,52.15 164.37,52.13 164.37,50.44 164.4,50.41 164.4,50.25 164.14,50 161.86,50 161.73,50.13 161.73,50.63 161.98,50.89 163.13,50.89 163.38,51.14 163.38,51.7 163.39,51.76 163.38,51.83 163.38,52.03 162.74,52.67 161.98,52.67 161.86,52.79 161.86,53.17 161.98,53.3 163.25,53.3
+3V_PCH on BOTTOM (solid shape): 117.38,64.64 117.38,61.91 117.53,61.76 117.53,60.6 118.21,59.93 118.21,58.74 117.96,58.5 117.02,58.5 116.89,58.64 116.89,59.6 116.1,60.39 116.1,62.12 115.92,62.3 115.92,64.56 116.11,64.76 117.27,64.76
+3V_PCH on BOTTOM (solid shape): 35.27,54.84 35.4,54.84 35.48,54.76 35.48,53.99 36.3,53.16 36.3,52.95 36.11,52.76 35.44,52.76 34.37,51.69 34.37,51.27 34.39,51.26 34.39,50.97 34.28,50.86 33.48,50.86 33.4,50.95 33.4,51.82 34.63,53.05 34.63,54.69 34.79,54.85 35.26,54.85
+3V_PCH on BOTTOM (solid shape): 105.45,67.02 105.45,66.76 105.29,66.6 105.29,65.87 105.46,65.7 105.46,65.58 105.46,65.57 105.43,65.42 105.46,65.27 105.46,65.26 105.46,65.23 105.54,65.15 105.58,65.12 106.02,64.67 106.02,63.72 105.72,63.41 104.81,63.41 104.71,63.52 104.71,65.17 104.75,65.2 104.86,65.55 104.63,65.84 104.62,65.84 104.59,65.87 104.59,67.05 104.77,67.24 105.24,67.24
+3V_PCH on BOTTOM (solid shape): 102.15,64.47 102.15,63.78 102.05,63.56 102.15,63.34 102.15,62.62 101.84,62.31 101.8,62.27 101.77,62.22 101.75,62.19 101.75,61.63 101.29,61.18 100.78,61.18 100.73,61.23 100.73,62.88 101.04,63.18 101.04,63.24 101.07,63.28 101.12,63.28 101.19,63.23 101.28,63.22 101.69,63.22 101.94,63.47 101.69,63.73 101.28,63.73 101.23,63.72 101.18,63.71 101.08,63.72 101.04,63.8 101.04,64.49 101.16,64.61 102,64.61
+3V_PCH on BOTTOM (solid shape): 114.13,69.83 114.13,67.07 114,66.94 112.4,66.94 112.29,67.05 112.29,68.35 112.1,68.54 110.56,68.54 110.46,68.64 110.46,69.22 110.59,69.34 111.26,69.34 111.35,69.25 111.51,68.81 111.97,68.84 112.04,68.87 112.11,68.84 112.37,68.74 112.62,68.85 112.69,68.88 112.76,68.85 113.36,68.95 113.1,69.5 113.03,69.55 113.02,69.63 113.04,69.74 113.02,69.85 113.03,69.94 113.12,69.98 113.98,69.98
+3V_PCH on IN1 (solid shape): 116.91,69.05 116.91,67.53 116.67,67.29 112.91,67.29 112.5,67.7 112.5,68.43 112.71,68.64 113.14,68.64 113.81,69.3 116.66,69.3
+3V_PCH on IN3 (solid shape): outline of 87 points within 101.54,65.75 105.48,68.03
+3V_PCH on IN4 (solid shape): 23.45,54.41 23.83,54.41 23.97,54.27 23.97,53.82 24.12,53.66 24.12,52.97 24.35,52.74 25.1,52.74 25.22,52.63 25.22,52.03 24.69,51.51 21.88,51.51 21.63,51.77 21.63,52.07 21.91,52.36 21.94,52.35 22.23,52.38 22.41,52.6 22.45,52.66 22.52,52.67 22.9,53.2 22.26,53.15 22.21,53.1 22.14,53.09 21.84,53.04 21.67,52.81 21.67,52.79 21.62,52.75 21.35,52.75 21.2,52.9 21.2,55.07 21.48,55.35 22.5,55.35
+3V_PCH_DSW on TOP (solid shape): 106.44,64.86 106.44,64.42 106.36,64.34 104.32,64.34 104.06,64.08 103.23,64.08 103.02,63.87 102.1,63.87 102.01,63.97 101.6,63.97 101.38,63.75 101.38,63.43 101.28,63.33 100.48,63.33 100.32,63.49 100.32,64.37 100.47,64.52 101.12,64.52 101.34,64.73 101.88,64.73 101.89,64.74 102.99,64.74 103.27,65.02 106.28,65.02
+3VALW on TOP (solid shape): 176.97,39.84 176.97,37.87 176.91,37.81 175.7,37.81 174.31,39.19 174.31,39.91 174.46,40.05 175.27,40.05 175.48,40.26 176.55,40.26
+3VALW on TOP (solid shape): 177.02,36.36 177.02,33.39 176.83,33.2 175.75,33.2 175.62,33.33 175.62,36.28 175.77,36.43 176.95,36.43
+3VALW on TOP (solid shape): 179.74,72.18 179.74,71.23 179.51,71.01 177.91,71.01 177.81,71.1 177.81,71.95 177.96,72.1 178.52,72.1 178.81,72.39 179.53,72.39
+3VALW on TOP (solid shape): 126.27,56.93 126.32,56.93 126.68,56.57 126.68,55.34 126.39,55.05 124.21,55.05 124.12,55.14 124.12,55.7 124.49,56.07 124.49,56.85 124.58,56.93 126.26,56.93
+3VALW on TOP (solid shape): 165.3,46.82 165.43,46.82 165.43,46.82 166.26,46.82 166.26,46.82 166.31,46.82 166.38,46.75 166.38,45.69 166.5,45.58 166.5,45.44 166.51,45.42 166.51,45.04 166.31,44.84 165.37,44.84 165.07,45.15 165.07,46.77 165.12,46.82 165.3,46.82
+3VALW on TOP (solid shape): 126.16,59.12 126.16,58.52 125.84,58.2 125.32,58.2 125.31,58.21 125.25,58.24 125.19,58.25 124.62,58.25 124.55,58.28 124.53,58.35 124.53,58.89 124.53,58.9 124.53,59.15 124.64,59.26 126.01,59.26
+3VALW on TOP (solid shape): 156.54,76.83 156.54,76.45 155.38,75.29 155.38,74.68 155.27,74.57 154.68,74.57 154.57,74.68 154.57,74.81 154.62,74.97 154.56,75.12 154.56,75.71 155.75,76.89 156.48,76.89
+3VALW on TOP (solid shape): 169.09,46.95 169.09,46.57 168.99,46.47 168.97,46.47 168.97,46.44 168.46,45.94 167.82,45.94 167.7,46.06 167.7,46.09 167.7,46.14 167.7,46.7 167.82,46.82 168.46,46.82 168.7,47.07 168.79,47.08 168.97,47.08
+3VALW on TOP (solid shape): 126.86,58.12 126.86,57.57 126.98,57.45 127.58,57.45 127.69,57.34 127.69,56.73 127.62,56.66 127.1,56.66 126.35,57.4 125.33,57.4 125.26,57.44 125.19,57.45 124.63,57.45 124.62,57.45 124.55,57.48 124.52,57.55 124.52,57.67 124.59,57.75 125.9,57.75 126.42,58.26 126.72,58.26
+3VALW on BOTTOM (solid shape): 195.83,34.12 195.83,31.69 195.43,31.3 194.49,31.3 194.49,30.75 194.24,30.75 194.24,31.3 193.69,31.3 193.69,30.75 193.44,30.75 193.44,31.3 189.09,31.3 188.71,31.68 188.71,34.17 189.1,34.56 195.39,34.56
+3VALW on BOTTOM (solid shape): 177.38,80.27 177.38,79.06 177.45,78.99 177.45,77.86 177.35,77.64 177.41,77.4 177.41,76.65 177.37,76.61 176.7,76.61 176.64,76.67 176.64,78.6 177.11,79.07 177.11,80.27 177.18,80.34 177.31,80.34
+3VALW on IN1 (solid shape): 126.35,59.08 126.35,58.65 126.84,58.15 126.84,57.77 126.75,57.68 123.98,57.68 123.77,57.9 123.77,58.85 124.14,59.22 126.21,59.22
+3VALW on IN3 (solid shape): 177.64,39.97 177.64,33.57 177.11,33.03 175.1,33.03 174.85,33.29 174.85,34.99 175.25,34.99 175.25,34.94 175.26,34.88 175.28,34.83 175.3,34.78 175.33,34.74 175.37,34.7 175.41,34.67 175.46,34.64 175.5,34.62 175.56,34.61 175.61,34.61 175.66,34.61 175.72,34.62 175.76,34.64 175.81,34.67 175.85,34.7 175.89,34.74 175.92,34.78 175.94,34.83 175.96,34.88 175.97,34.94 175.97,34.99 175.96,35.04 175.94,35.09 175.92,35.14 175.89,35.19 175.85,35.22 175.81,35.26 175.76,35.28 175.72,35.3 175.66,35.32 175.61,35.32 175.56,35.32 175.5,35.3 175.46,35.28 175.41,35.26 175.37,35.22 175.33,35.19 175.3,35.14 175.28,35.09 175.26,35.04 175.25,34.99 174.85,34.99 174.85,37.17 175.33,37.66 175.33,40.09 175.52,40.28 177.32,40.28
+3VALW on IN3 (solid shape): outline of 480 points within 174.59,58.89 192.25,78.04
+3VALW on IN3 (solid shape): outline of 1101 points within 117.1,56.38 130.34,73.15
+3VALW on IN4 (solid shape): outline of 218 points within 224.86,4.41 227.53,10.5
+3VALW on VCC: 127.93,28.41 127.06,29.28 127.06,53.53 124.64,55.95 124.64,58.28 127.29,60.92 130.51,60.92 134.06,57.37 134.69,57.37 134.69,52.18 136.46,50.41 136.63,50.36 150.6,50.36 150.96,50 155.87,50 157.14,51.27 159.21,51.27 162.13,48.35 166.81,48.35 166.81,47.48 168.59,45.7 168.59,41.38 169.69,40.29 169.87,40.22 180.64,40.22 185.87,45.45 185.87,45.46 189.92,49.51 189.92,60.69 190.28,61.05 195,61.05 195.02,46.59 195.93,45.68 200.35,45.68 200.35,38.05 197.45,35.14 192.88,35.14 191.46,33.72 191.46,32.58 190.59,31.71 167.56,31.71 161.27,37.99 154.6,44.67 135.46,44.67 129.98,39.18 129.98,28.9 129.49,28.41
+3VALW_EC on TOP (solid shape): 150.93,61.43 150.93,60.76 150.86,60.68 150.86,60.59 150.15,60.59 150.15,60.54 148.9,60.54 148.88,60.57 148.88,61.29 149.27,61.68 150.68,61.68
+3VALW_EC on TOP (solid shape): 149.66,53.08 149.66,50.13 149.62,50.08 149.34,50.08 149.23,50.1 149.13,50.09 148.35,50.09 148.29,50.16 148.29,50.65 148.52,50.89 148.52,53.17 148.61,53.27 148.67,53.3 148.71,53.34 149.41,53.34
+3VALW_EC on IN1 (solid shape): 148.32,68.24 148.4,68.2 148.42,68.11 148.42,68.1 148.39,68.07 148.35,68.06 147.88,67.69 148.43,67.43 148.53,67.44 148.58,67.35 148.58,66.76 148.22,66.4 147.5,66.4 147.44,66.42 146.96,66.9 146.96,67.08 147,67.16 147.09,67.18 147.57,67.51 147.09,67.85 147,67.86 146.96,67.94 146.96,68.01 147.19,68.24
+3VALW_EC on VCC: 136.73,50.86 135.2,52.39 135.2,64.89 135.8,65.49 148.54,65.49 150.93,63.1 150.93,54.42 150.3,53.79 150.3,51 150.16,50.86
+3VALW_LX on TOP (solid shape): 204.68,31.48 204.76,31.4 204.76,28.34 204.62,28.2 202.79,28.2 202.65,28.35 202.65,31.13 202.75,31.23 203.31,31.23 203.56,31.48 204.63,31.48
+3VALW_LX on BOTTOM (solid shape): 204.91,31.27 204.91,29.9 204.97,29.83 204.97,27.93 204.79,27.75 203.58,27.75 203.23,27.4 200.62,27.4 200.11,27.92 200.11,30.97 200.64,31.51 204.67,31.51
+3VALW_VIN on TOP (solid shape): 203.31,38.11 203.31,37.07 204.48,35.9 204.48,34.84 204.81,34.51 204.81,33.54 204.73,33.46 203.46,33.46 202.65,34.28 202.65,35.24 202.22,35.67 202.22,36.66 201.99,36.89 200.67,36.89 200.54,37.02 200.54,38.16 200.67,38.29 203.13,38.29
+3VALWP on BOTTOM (solid shape): 193.31,30.62 193.81,30.62 193.81,31.14 194.11,31.14 194.11,30.62 194.61,30.62 194.61,31.14 195.86,31.14 196.41,30.59 198.4,30.59 198.61,30.38 198.61,27.95 198.42,27.75 192.41,27.75 192.35,27.81 192.35,30.87 192.62,31.14 193.31,31.14
+3VDX on TOP (solid shape): 129.24,31.74 129.66,31.74 130.01,31.39 130.01,30.25 129.83,30.07 128.91,30.07 128.51,30.48 128.51,30.8 128.34,30.96 128.34,31.84 128.42,31.92 129.06,31.92
+3VDX on TOP (solid shape): 200.31,58.56 200.87,58.56 200.87,59.13 201.12,59.13 201.12,58.61 201.12,58.56 201.63,58.56 201.81,58.38 201.81,56.1 201.56,55.84 199.37,55.84 198.84,56.38 198.84,56.65 198.88,56.73 198.96,56.74 199.45,57.11 198.96,57.48 198.88,57.5 198.84,57.58 198.84,58.28 199.12,58.56 200.07,58.56 200.07,59.13 200.31,59.13
+3VDX on BOTTOM (solid shape): 173.76,75.29 173.76,73.63 173.2,73.08 173.2,70.82 173.01,70.63 172.52,70.63 172.13,71.02 171.42,71.02 171.27,71.17 171.27,74.22 171.51,74.47 172.1,74.47 172.78,75.14 172.89,75.23 172.97,75.36 173.69,75.36
+3VDX on IN1 (solid shape): outline of 1818 points within 171.27,55.79 201.98,74.71
+3VDX on IN3 (solid shape): 131.39,31.59 131.39,30.44 131.19,30.25 129.47,30.25 129.22,30.5 129.22,31.58 129.41,31.76 131.22,31.76
+3VDX on IN3 (solid shape): outline of 2615 points within 167.51,26.48 202.22,58.08
+3VDX_LX on TOP (solid shape): 205.52,61.96 205.52,61.13 205.8,60.85 207.04,60.85 207.6,60.29 207.6,59.09 208.16,58.53 208.16,56.1 207.98,55.92 207.19,55.92 206.86,56.25 206.86,57.72 206.56,58.03 204.32,58.03 204.15,58.2 204.15,61.89 204.32,62.06 205.42,62.06
+3VDX_LX on BOTTOM (solid shape): 208.55,60.39 208.55,58.1 208.48,58.03 205.05,58.03 204.82,58.25 204.82,60.31 205.02,60.52 208.43,60.52
+3VDX_VIN on TOP (solid shape): 205.52,70.45 205.52,64.12 205.44,64.05 204.08,64.05 203.64,64.05 203.28,64.4 203.28,69 203.73,69 203.73,68.94 203.74,68.89 203.76,68.84 203.79,68.79 203.82,68.74 203.86,68.71 203.91,68.67 203.96,68.65 204.01,68.63 204.07,68.62 204.12,68.62 204.18,68.62 204.23,68.64 204.28,68.66 204.33,68.69 204.37,68.72 204.41,68.77 204.44,68.81 204.47,68.86 204.48,68.92 204.49,68.97 204.49,69.03 204.48,69.08 204.47,69.14 204.44,69.19 204.41,69.23 204.37,69.27 204.33,69.31 204.28,69.34 204.23,69.36 204.18,69.37 204.12,69.38 204.07,69.38 204.01,69.37 203.96,69.35 203.91,69.33 203.86,69.29 203.82,69.25 203.79,69.21 203.76,69.16 203.74,69.11 203.73,69.05 203.73,69 203.28,69 203.28,70.37 203.44,70.53 205.44,70.53
+3VDXP on TOP (solid shape): 203.92,61.66 203.92,59.07 203.49,58.64 201.86,58.64 201.76,58.74 201.24,58.74 201.24,59.26 200.74,59.26 200.74,58.74 200.44,58.74 200.44,59.26 199.94,59.26 199.94,58.74 199.57,58.74 199.52,58.79 199.52,59.8 199.02,60.31 199.02,61.81 199.22,62.01 203.56,62.01
+3VDXP on BOTTOM (solid shape): 204.44,61.58 204.44,58.03 204.42,58.01 201.94,58.01 201.19,58.76 200.04,58.76 199.82,58.99 199.82,61.86 199.97,62.01 204.01,62.01
+3VLP on TOP (solid shape): 149.97,60 149.97,59.18 149.81,59.02 148.52,59.02 148.42,59.12 148.39,59.16 148.39,59.46 148.65,59.72 148.65,60.06 148.95,60.36 149.6,60.36
+3VNS_PWR on TOP (solid shape): 154.34,66.76 154.54,66.76 154.54,66.74 155.02,66.74 155.25,66.51 155.25,65.49 154.87,65.11 154.87,63.59 154.74,63.46 153.47,63.46 153.35,63.59 153.35,63.8 153.43,64.03 153.35,64.26 153.35,65.33 153.35,65.34 153.31,65.68 153.01,65.85 152.98,65.87 152.97,65.9 152.97,66.51 153.19,66.74 153.69,66.74 153.69,66.76 154.32,66.76
+3VNS_PWR on BOTTOM (solid shape): outline of 502 points within 152.18,53.86 161.61,70.46
+3VNS_PWR on IN3 (solid shape): 161.96,57.21 163.01,57.21 163.02,57.18 163.3,56.94 163.65,57.04 163.72,57.07 163.79,57.04 164.23,56.98 164.43,57.37 164.43,57.4 165.01,57.98 165.77,57.98 166.02,57.72 166.02,56.07 165.51,55.56 159.8,55.56 159.42,55.94 159.42,57.59 159.8,57.98 161.2,57.98
+3VNS_PWR on IN3 (solid shape): outline of 87 points within 139.9,77.33 144.22,82.82
+3VNS_PWR on IN3 (solid shape): outline of 249 points within 151.96,56.89 155.67,66.26
+3VS on TOP (solid shape): 101.85,74.02 101.85,73.07 101.72,72.95 100.6,72.95 100.49,73.06 100.49,74.03 100.57,74.1 101.77,74.1
+3VS on TOP (solid shape): 117.53,55.03 117.53,52.36 117.39,52.23 117.19,52.23 117.09,52.33 117.09,54.63 116.77,54.95 116.76,54.95 115.96,55.75 115.96,55.98 116.09,56.11 116.45,56.11
+3VS on TOP (solid shape): 165.21,50.51 165.37,50.35 165.59,50.31 165.61,50.31 165.67,50.25 165.67,49.87 166.38,49.15 166.38,48.15 166.29,48.06 164.6,48.06 164.54,48.13 164.54,50.13 164.92,50.51
+3VS on TOP (solid shape): 149.85,58.29 150.04,58.29 150.19,58.13 150.19,57.81 150.01,57.62 150.01,56.82 149.79,56.6 149.04,56.6 148.89,56.76 148.89,57.48 148.89,57.49 148.89,57.64 148.9,57.72 148.89,57.8 148.89,57.88 148.87,57.9 148.87,58.47 148.99,58.59 149.55,58.59
+3VS on BOTTOM (solid shape): 209.56,72.22 209.56,71.03 209.39,70.85 208.17,70.85 208.03,70.99 208.03,72.24 208.33,72.54 209.24,72.54
+3VS on BOTTOM (solid shape): 50.62,49.88 50.62,49.08 50.49,48.96 49.82,48.96 49.65,48.79 49.65,47.26 49.47,47.08 47.82,47.08 47.44,47.46 47.44,49.75 47.75,50.05 50.45,50.05
+3VS on BOTTOM (solid shape): 59.03,49.87 59.03,48.52 58.74,48.23 58.28,48.23 58.11,48.06 58.11,47.46 57.98,47.33 56.59,47.33 56.46,47.46 56.46,48.09 56.33,48.22 55.32,48.22 55.06,48.48 55.06,48.75 55.06,49.75 55.32,50 58.9,50
+3VS on BOTTOM (solid shape): 100.94,79.02 101.01,78.18 101.25,77.38 101.25,76.98 101.13,76.85 100.47,76.85 100.28,77.04 100.28,78.45 100.05,78.68 100.05,78.93 100.24,79.12 100.85,79.12
+3VS on BOTTOM (solid shape): 100.99,75.62 100.99,75.46 101.25,75.2 101.25,74.17 102.05,73.37 102.05,72.35 101.94,72.24 101.94,71.85 101.79,71.71 101.08,71.71 101,71.78 101,72.26 100.78,72.48 100.78,73.43 100.33,73.88 100.33,75.63 100.46,75.76 100.86,75.76
+3VS on BOTTOM (solid shape): outline of 171 points within 103.22,68.57 116.37,77.05
+3VS on IN1 (solid shape): 56.93,48.7 56.93,48.07 56.8,47.94 55.15,47.94 54.9,48.2 54.9,48.7 55.15,48.96 56.67,48.96
+3VS on IN1 (solid shape): 102.55,72.4 102.6,72.4 102.61,72.39 103.41,72.39 103.65,72.14 104.75,72.14 104.84,72.1 104.85,72 104.97,71.58 105.41,71.6 105.47,71.62 105.54,71.6 105.87,71.52 106.12,71.74 106.14,71.87 106.11,72 106.12,72.1 106.2,72.14 106.24,72.14 106.32,72.1 106.33,72 106.66,71.51 106.99,72 107,72.1 107.09,72.14 107.74,72.14 108.96,70.92 108.96,69.96 108.7,69.7 107.49,69.7 107.29,69.9 107.29,69.93 107.29,70.07 107.23,70.2 107.21,70.27 107.24,70.33 107.27,70.37 107.3,70.41 107.35,70.46 107.42,70.46 107.88,70.92 107.23,70.95 107.18,70.91 107.11,70.91 106.71,70.8 106.67,70.39 106.67,70.34 106.63,70.32 106.56,70.32 106.33,70.55 104.84,70.55 104.76,70.6 104.75,70.69 104.78,70.88 104.71,71.05 104.46,71.32 104.11,71.23 102.52,71.23 100.93,72.82 100.93,73.16 101.03,73.26 101.69,73.26
+3VS on IN3 (solid shape): 33.31,81.69 33.31,80.22 33.11,80.03 32.52,80.03 32.05,79.56 31.22,79.56 30.86,79.91 30.86,80.91 31.11,80.91 31.11,80.86 31.12,80.81 31.13,80.76 31.16,80.71 31.19,80.66 31.22,80.62 31.26,80.59 31.31,80.57 31.36,80.55 31.41,80.53 31.47,80.53 31.52,80.53 31.57,80.55 31.62,80.57 31.67,80.59 31.71,80.62 31.74,80.66 31.77,80.71 31.8,80.76 31.81,80.81 31.82,80.86 31.82,80.91 31.81,80.97 31.8,81.02 31.77,81.06 31.74,81.11 31.71,81.15 31.67,81.18 31.62,81.21 31.57,81.23 31.52,81.24 31.47,81.24 31.41,81.24 31.36,81.23 31.31,81.21 31.26,81.18 31.22,81.15 31.19,81.11 31.16,81.06 31.13,81.02 31.12,80.97 31.11,80.91 30.86,80.91 30.86,81.81 31.08,82.03 32.97,82.03
+3VS on IN3 (solid shape): outline of 711 points within 185.87,70.95 209.75,82.13
+3VS on IN3 (solid shape): outline of 1155 points within 87.41,70.17 102.65,80.76
+3VS on VCC: 162.34,48.86 159.42,51.78 156.88,51.78 156.65,52.01 156.65,53.92 156.12,54.44 151.93,54.44 151.44,54.93 151.44,63.31 148.75,66 135.59,66 134.68,65.09 134.68,64.88 134.69,64.87 134.69,57.87 134.28,57.87 130.87,61.28 130.87,64.88 132.26,66.28 132.26,70.68 130.87,72.08 130.87,73.76 131.99,74.89 154.6,74.89 166.15,86.45 166.15,86.84 167.59,86.84 168.16,86.96 168.65,87.28 169.77,88.4 169.93,88.5 170.11,88.54 171.89,88.54 172.07,88.5 172.23,88.4 173.41,87.22 173.47,87.13 173.49,87.02 173.49,86.25 173.87,85.32 174.8,84.94 190.2,84.94 190.89,85.14 191.48,85.8 191.64,85.84 197,85.84 197.35,85.7 197.49,85.35 197.49,83.55 197.6,82.98 197.92,82.49 197.92,81.35 197.56,80.99 192.23,80.99 188.42,77.18 182.07,77.18 181.67,77.58 181.67,79.57 180.38,80.86 170.51,80.86 169.35,79.7 169.35,74.66 170.01,74 173.18,74 173.41,73.77 173.41,70.87 172.36,69.81 168.1,69.81 165.92,67.63 165.92,52.69 166.81,51.8 166.81,48.86
+3VS_AUDIO on TOP (solid shape): 124.04,31.23 124.04,29.94 123.91,29.8 122.68,29.8 122.51,29.97 122.51,31.16 122.64,31.29 123.99,31.29
+3VS_AUDIO on TOP (solid shape): 118.97,39.4 118.97,37.94 118.9,37.88 118.35,37.88 117.47,37 117.47,35.94 117.41,35.89 116.79,35.89 116.72,35.82 116.72,35.46 116.5,35.24 115.61,35.24 115.49,35.37 115.49,36.24 115.51,36.26 115.51,36.4 115.55,36.45 116.54,37.44 116.54,37.65 117.59,38.69 117.59,39.4 117.79,39.6 118.77,39.6
+3VS_AUDIO on IN3 (solid shape): outline of 339 points within 116.66,37.05 121.99,48.22
+3VS_AUDIO on IN4 (solid shape): 121.74,46.76 121.74,46.32 121.36,45.94 120.58,45.94 120.4,46.12 120.4,46.79 120.5,46.9 121.6,46.9
+3VS_AUDIO on IN4 (solid shape): 120.11,38.42 120.11,38.4 120.21,38.19 120.42,38.09 120.44,38.09 121.69,36.84 121.69,33.16 123.26,31.58 123.26,30.04 122.93,29.71 121.08,29.71 118.56,32.22 118.56,37.43 117.42,38.57 117.42,39.21 117.93,39.71 118.82,39.71
+3VS_CAM on TOP (solid shape): 181.8,34.2 181.8,33.17 181.15,32.52 177.76,32.52 177.62,32.66 177.62,33.66 177.74,33.78 179.7,33.78 180.41,34.48 181.51,34.48
+3VS_CAM on TOP (solid shape): 179.51,76.03 179.51,74.92 179.5,74.89 179.5,74.84 179.5,74.79 179.5,74.74 179.51,74.72 179.51,73.88 179.37,73.74 177.16,73.74 176.84,74.06 176.84,74.76 177.67,74.76 177.67,74.71 177.68,74.65 177.7,74.6 177.73,74.55 177.76,74.51 177.8,74.47 177.85,74.44 177.9,74.41 177.95,74.4 178.01,74.39 178.06,74.38 178.12,74.39 178.17,74.4 178.22,74.43 178.27,74.45 178.31,74.49 178.35,74.53 178.38,74.58 178.41,74.63 178.42,74.68 178.43,74.74 178.43,74.79 178.42,74.85 178.41,74.9 178.38,74.95 178.35,75 178.31,75.04 178.27,75.08 178.22,75.1 178.17,75.13 178.12,75.14 178.06,75.15 178.01,75.14 177.95,75.13 177.9,75.12 177.85,75.09 177.8,75.06 177.76,75.02 177.73,74.98 177.7,74.93 177.68,74.87 177.67,74.82 177.67,74.76 176.84,74.76 176.84,76.04 176.96,76.16 179.38,76.16
+3VS_CAM on IN3 (solid shape): outline of 383 points within 178.51,74.26 185.24,81.67
+3VS_CAM on IN3 (solid shape): outline of 498 points within 178.66,33.95 181.94,47.46
+3VS_NGFF on TOP (solid shape): 199.67,44.29 199.67,42.87 199.54,42.74 197.67,42.74 197.52,42.88 197.52,44.25 197.71,44.44 199.52,44.44
+3VS_NGFF on TOP (solid shape): outline of 88 points within 178.07,39.89 183.45,45.63
+3VS_NGFF on BOTTOM (solid shape): 200.1,44.92 200.1,42.98 199.59,42.55 199.44,41.9 199.44,41.81 199.43,41.79 199.34,41.7 196.76,41.7 196.51,41.95 196.51,43.06 196.72,43.27 198.57,43.27 198.83,43.52 198.83,44.92 198.95,45.05 199.97,45.05
+3VS_NGFF on BOTTOM (solid shape): 182.15,44.96 182.15,43.56 182.57,43.14 182.57,40.6 181.93,39.97 179.52,39.97 178.83,40.66 178.83,42 179.69,42 179.7,41.92 179.71,41.84 179.73,41.76 179.76,41.69 179.79,41.62 179.83,41.55 179.88,41.48 179.94,41.43 180,41.37 180.06,41.33 180.13,41.29 180.2,41.25 180.28,41.23 180.36,41.21 180.44,41.2 180.51,41.2 180.59,41.2 180.67,41.22 180.75,41.24 180.82,41.27 180.9,41.31 180.96,41.35 181.03,41.4 181.08,41.45 181.13,41.52 181.18,41.58 181.22,41.65 181.25,41.73 181.27,41.8 181.29,41.88 181.3,41.96 181.3,42.04 181.29,42.12 181.27,42.2 181.25,42.27 181.22,42.35 181.18,42.42 181.13,42.48 181.08,42.54 181.03,42.6 180.96,42.65 180.9,42.69 180.82,42.73 180.75,42.76 180.67,42.78 180.59,42.79 180.51,42.8 180.44,42.8 180.36,42.79 180.28,42.77 180.2,42.75 180.13,42.71 180.06,42.67 180,42.63 179.94,42.57 179.88,42.51 179.83,42.45 179.79,42.38 179.76,42.31 179.73,42.24 179.71,42.16 179.7,42.08 179.69,42 178.83,42 178.83,44.1 179.35,44.62 180.54,44.62 180.97,45.05 182.06,45.05
+3VS_NGFF on IN2 (solid shape): outline of 1968 points within 180.03,37.81 199.7,47.33
+3VS_TOUCH on TOP (solid shape): 119.63,60.79 120.11,60.79 120.22,60.69 120.22,59.51 120.11,59.4 119.18,59.4 118.22,60.36 118.22,60.9 118.47,61.15 119.27,61.15
+3VS_TOUCH on TOP (solid shape): 158.88,77.33 158.88,76.33 158.38,75.83 156.91,75.83 156.73,76.01 156.73,77.03 156.75,77.05 157.32,77.05 157.74,77.47 158.73,77.47
+3VS_TOUCH on BOTTOM (solid shape): 159.46,77.94 159.46,75.71 159.16,75.4 158.57,75.4 157.68,76.29 157.68,77.56 158.18,78.06 158.18,78.59 158.12,78.66 158.12,78.86 158.14,78.89 158.52,78.89
+3VS_TOUCH on IN2 (solid shape): outline of 892 points within 118.15,59.07 141.49,67.4
+3VS_TOUCH on IN3 (solid shape): outline of 584 points within 138.79,65.71 159.49,77.61
+3VS_TPM on TOP (solid shape): 160.28,75.58 160.28,73.48 160.09,73.29 159.42,73.29 159.02,72.89 157.04,72.89 156.86,72.71 156.86,71.87 156.65,71.66 155.47,71.66 155.26,71.87 155.26,73.17 155.56,73.47 158.7,73.47 159.01,73.77 159.68,73.77 159.68,74.57 159.49,74.77 159.49,75.63 159.53,75.68 160.18,75.68
+5V_USB_P0 on TOP (solid shape): 214.77,53.41 214.77,52.08 215.05,51.8 215.46,51.8 216.43,52.77 218.93,52.77 219.7,51.99 219.7,51.33 217.76,49.39 212.73,49.39 212.5,49.61 212.5,53.27 212.71,53.47 212.99,53.47 213.05,53.53 214.65,53.53
+5V_USB_P0 on BOTTOM (solid shape): 219.64,52.94 219.64,51.55 217.83,49.75 212.54,49.75 212.42,49.87 212.38,49.91 212.34,49.95 212.27,50.02 212.27,52.26 212.41,52.41 213.18,52.41 213.43,52.67 213.43,53.43 213.56,53.56 219.02,53.56
+5V_USB_P1 on TOP (solid shape): 210.16,43.06 211.57,43.06 211.88,42.75 211.88,41.39 211.72,41.24 210.45,41.24 209.41,42.28 209.1,42.28 208.9,42.48 208.23,42.48 208.11,42.46 208,42.41 207.99,42.41 207.78,42.41 207.72,42.47 207.72,42.61 208.25,43.14 210.08,43.14
+5V_USB_P1 on BOTTOM (solid shape): 213.1,34.26 213.1,32.53 213.05,32.47 213.05,31.6 213.7,30.95 214.97,30.95 214.98,30.95 215.31,30.98 215.52,31.25 215.52,31.26 215.67,31.41 215.7,31.41 216.12,31.78 215.72,32.17 215.69,32.17 215.46,32.47 215.46,33.36 216.39,34.29 217.76,34.29 218.13,33.92 218.13,32.22 217.24,31.33 217.24,29.88 217.37,29.75 217.37,26.59 216.87,26.1 212.82,26.1 211.4,27.52 211.4,34.25 211.53,34.38 212.99,34.38
+5V_USB_P1 on IN4 (solid shape): outline of 512 points within 207.08,29.3 216.35,42.85
+5VA on TOP (solid shape): 228.28,25.44 228.28,23.77 228.07,23.57 226.75,23.57 226.6,23.71 226.6,25.42 226.74,25.55 228.16,25.55
+5VA on TOP (solid shape): 46.39,22.77 46.39,21.88 46.29,21.78 46.17,21.78 45.27,21.78 44.89,22.16 44.03,22.16 44.01,22.18 44.01,22.88 44.23,23.1 46.06,23.1
+5VA on TOP (solid shape): 155.37,73.82 155.37,73.63 154.94,73.2 154.74,73.2 154.08,72.53 154.08,71.49 153.94,71.35 153.52,71.35 153.32,71.55 153.32,72.58 154.29,73.55 154.46,73.65 154.56,73.82 154.6,73.86 155.32,73.86
+5VA on TOP (solid shape): outline of 255 points within 128.34,22.97 137.4,37.91
+5VA on BOTTOM (solid shape): 204.29,22.44 204.31,22.42 204.9,22.42 204.9,22.97 205.07,22.97 205.1,22.95 205.1,22.42 205.71,22.42 205.71,22.97 206.47,22.97 207.08,22.36 207.08,20.28 206.83,20.03 203.45,20.03 202.97,20.51 202.97,22.64 203.3,22.97 204.29,22.97
+5VA on IN1 (solid shape): outline of 263 points within 218.64,21.04 228.67,27.9
+5VA on IN4 (solid shape): outline of 1777 points within 44.77,18.88 132.91,32.9
+5VA on VCC: 220.65,18.06 220.57,18.06 220.5,18.06 199.55,18.06 199.08,18.53 199.08,23.82 198.3,24.6 160.95,24.6 153.73,31.82 153.73,38.17 153.07,38.82 141.18,38.82 131.4,29.04 130.85,29.04 130.49,29.4 130.49,38.97 135.67,44.16 154.38,44.16 160.84,37.7 160.99,37.55 167.28,31.28 167.35,31.2 190.8,31.2 191.97,32.37 191.97,33.51 193.09,34.63 197.66,34.63 200.7,37.68 200.71,37.68 200.86,37.83 200.86,48.12 201.47,48.73 217.18,48.73 220.98,44.93 220.71,44.58 220.61,44.15 220.61,30.05 220.68,29.69 220.87,29.38 220.87,18.28
+5VA on VCC: 14.15,18.06 14.15,23.22 14.64,23.71 46.43,23.71 47.05,23.1 47.05,18.06
+5VDX_LX on TOP (solid shape): 207.35,50.63 207.35,48.93 207.22,48.81 203.97,48.81 203.75,49.02 203.75,49.34 203.75,49.38 203.74,49.42 203.74,50.74 203.84,50.84 207.14,50.84
+5VDX_LX on BOTTOM (solid shape): 207.41,53.22 207.41,49.26 207.17,49.01 205.43,49.01 205.2,49.24 205.2,53.25 205.33,53.38 207.26,53.38
+5VDX_VIN on TOP (solid shape): 200.79,50.84 201.63,50.84 201.73,50.74 201.73,48.43 201.5,48.19 201.5,47.06 201.32,46.87 199.28,46.87 199.08,47.08 199.08,51.14 199.3,51.36 200.27,51.36
+5VDX_WALKPORT on TOP (solid shape): 214.76,49.07 214.76,47.61 214.84,47.53 214.84,46.48 214.84,45.67 214.84,45.35 214.41,44.92 210.19,44.92 209.99,44.92 209,45.92 205.04,45.92 204.58,45.45 204.58,44.39 205.73,43.23 205.73,42.49 205.65,42.41 205.49,42.41 205.48,42.41 205.37,42.46 205.25,42.48 204.83,42.48 204.78,42.47 204.7,42.46 204.65,42.51 202.9,42.51 202.72,42.68 202.08,42.68 202.01,42.72 201.94,42.75 201.9,42.76 201.9,46.28 203.28,47.66 208.87,47.66 209.82,48.61 211.4,48.61 211.62,48.39 211.62,47.44 212.13,46.93 212.95,46.93 213.72,47.7 213.72,49.04 213.84,49.15 214.69,49.15
+5VDX_WALKPORT on BOTTOM (solid shape): 211.42,48.32 211.42,47.13 212.11,46.44 212.11,44.3 211.93,44.12 210.45,44.12 209.37,43.04 202.32,43.04 202.01,43.36 202.01,44.98 202.3,45.28 203.84,45.28 204.27,44.84 208.55,44.84 209.31,45.6 209.31,46.38 209.81,46.38 209.81,46.4 209.82,46.4 209.82,46.91 209.81,46.91 209.81,46.93 209.31,46.93 209.31,47.18 209.81,47.18 209.81,47.2 209.82,47.2 209.82,47.71 209.81,47.71 209.81,47.73 209.31,47.73 209.31,48.03 209.33,48.05 209.64,48.05 210.05,48.46 211.28,48.46
+5VDXP on BOTTOM (solid shape): outline of 140 points within 206.79,45.37 211.47,53.48
+5VS on TOP (solid shape): 139.08,24.85 139.75,24.85 139.9,24.7 139.9,24.4 139.9,24.4 139.9,23.66 139.64,23.41 139.29,23.41 139.01,23.13 138.32,23.13 138.22,23.23 138.22,24.19 137.31,25.1 137.31,25.67 137.45,25.81 138.13,25.81
+5VS on BOTTOM (solid shape): 180.61,34 180.68,34 180.75,34 181.23,34 181.3,34 181.37,34 182.99,34 183.09,33.91 183.09,31.78 182.77,31.46 179.52,31.46 178.87,32.11 178.23,32.11 178.12,32.22 178.12,32.86 178.22,32.97 178.74,32.97 179.78,34
+5VS on IN2 (solid shape): outline of 4579 points within 2.19,19.11 175.84,30.18
+5VS on IN4 (solid shape): 182.06,31.97 182.06,31.08 179.19,28.21 179.19,27.47 177.72,26 173.75,26 173.55,26.2 173.55,27.38 173.66,27.5 175.29,27.5 175.57,27.78 175.57,29.16 177.02,30.61 179.47,30.61 179.47,30.55 179.49,30.5 179.51,30.44 179.53,30.4 179.57,30.35 179.61,30.31 179.65,30.28 179.7,30.26 179.76,30.24 179.81,30.23 179.87,30.23 179.92,30.23 179.98,30.25 180.03,30.27 180.07,30.3 180.12,30.33 180.15,30.37 180.18,30.42 180.21,30.47 180.22,30.52 180.23,30.58 180.23,30.63 180.22,30.69 180.21,30.74 180.18,30.79 180.15,30.84 180.12,30.88 180.07,30.92 180.03,30.95 179.98,30.97 179.92,30.98 179.87,30.99 179.81,30.99 179.76,30.98 179.7,30.96 179.65,30.93 179.61,30.9 179.57,30.86 179.53,30.82 179.51,30.77 179.49,30.72 179.47,30.66 179.47,30.61 177.02,30.61 178.63,32.22 181.81,32.22
+5VS_AUDIO on TOP (solid shape): 123.88,35.27 123.88,34 123.63,33.74 121.98,33.74 121.72,34 121.72,35.27 121.98,35.52 123.63,35.52
+5VS_AUDIO on BOTTOM (solid shape): 12.31,25.34 14.09,25.34 14.27,25.16 14.27,23.81 14.75,23.34 14.75,21.29 14.42,20.91 14.75,20.54 14.75,19.43 14.6,19.28 13.91,19.28 13.9,19.27 13.02,19.27 12.77,19.52 12.77,21.04 12.91,21.18 12.91,21.41 13.42,21.92 13.56,22.35 13.42,22.78 13.42,22.96 12.77,23.61 11.38,23.61 10.1,24.89 10.1,25.78 10.32,26 11.65,26
+5VS_AUDIO on IN3 (solid shape): outline of 4454 points within 11.46,19.11 125.38,35.5
+5VS_KBL on BOTTOM (solid shape): 172.16,28.66 172.16,28.03 172.03,27.9 170.25,27.9 170.12,28.03 170.12,28.54 170.63,29.04 171.77,29.04
+5VS_KBL on BOTTOM (solid shape): 183.08,29.43 183.08,27.07 182.95,26.95 178.66,26.95 178.17,27.44 178.17,28.96 178.38,29.17 181.17,29.17 181.55,29.55 182.95,29.55
+5VS_KBL on IN4 (solid shape): outline of 173 points within 168.85,22.69 182.95,29.74
+V1.05A_AOSCSUS on TOP (solid shape): 103.05,71.59 103.05,69.81 103.65,69.22 103.65,67.84 103.58,67.77 101.81,67.77 101.62,67.96 101.62,69.13 100.96,69.79 99.38,69.79 99.22,69.96 99.22,70.41 99.22,70.41 99.22,70.89 99.68,71.36 99.68,71.64 99.81,71.76 102.88,71.76
+V1.05A_AOSCSUS_L on TOP (solid shape): 104.2,71.68 104.2,71.21 104.52,70.89 105.28,70.89 105.4,70.76 105.4,69.88 105.34,69.81 103.44,69.81 103.25,70 103.25,71.66 103.34,71.75 104.12,71.75
+V1.05A_DCPSUS on TOP (solid shape): 104.55,73.27 104.55,72.93 105.44,72.05 105.44,71.07 105.39,71.03 104.57,71.03 104.36,71.24 104.36,71.72 103.74,72.34 103.74,72.72 103.74,72.72 103.74,73.26 103.9,73.42 104.4,73.42
+V1.05S_APLLOPI on TOP (solid shape): 84.2,74.26 84.2,71.66 84.2,71.65 84.2,70.99 84.64,70.55 84.64,69.79 84.92,69.51 86.74,69.51 86.97,69.28 86.97,68.63 86.78,68.44 83.57,68.44 83.2,68.81 83.2,70.85 83.27,70.92 83.27,74.43 83.34,74.5 83.96,74.5
+V1.05S_APLLOPI on BOTTOM (solid shape): 85.22,69.23 86.83,69.23 86.96,69.1 86.96,68.34 86.84,68.22 86.28,68.22 86.26,68.23 86.21,68.27 86.16,68.29 86.11,68.31 86.06,68.31 86,68.31 85.95,68.3 85.9,68.29 85.85,68.26 85.81,68.24 85.77,68.24 85.76,68.25 85.08,68.25 84.99,68.16 84.86,68.16 84.72,68.3 84.72,68.8 85.15,68.8 85.15,68.75 85.16,68.7 85.18,68.65 85.2,68.61 85.23,68.57 85.26,68.54 85.31,68.51 85.35,68.49 85.4,68.48 85.44,68.48 85.49,68.48 85.54,68.49 85.58,68.51 85.62,68.54 85.66,68.57 85.69,68.61 85.71,68.65 85.73,68.7 85.74,68.75 85.74,68.8 85.73,68.84 85.71,68.89 85.69,68.93 85.66,68.97 85.62,69 85.58,69.03 85.54,69.05 85.49,69.06 85.44,69.06 85.4,69.06 85.35,69.05 85.31,69.03 85.26,69 85.23,68.97 85.2,68.93 85.18,68.89 85.16,68.84 85.15,68.8 84.72,68.8 84.72,69.29 84.81,69.38 85.07,69.38
+V1.05S_ASATA3PLL on TOP (solid shape): outline of 96 points within 95.26,76.24 100.81,86.05
+V1.05S_AUSB3PLL on TOP (solid shape): 97.38,84.21 97.38,82.08 98.6,80.86 98.6,79.5 98.36,79.26 97.12,79.26 95.17,77.3 93.31,77.3 93.25,77.37 93.25,78.41 94.03,79.18 94.03,81.39 95.14,82.51 95.95,82.51 96.31,82.87 96.31,84.19 96.4,84.29 97.3,84.29
+V1.05S_AXCK_DCB on TOP (solid shape): 89.76,80.51 89.76,78.8 89.52,78.55 88.57,78.55 88.04,78.02 87.84,78.02 87.51,77.69 87.51,77.49 87.28,77.25 87.28,74.74 87.11,74.57 85.9,74.57 85.74,74.74 85.74,75.08 85.89,75.23 86.39,75.23 86.56,75.41 86.56,77.62 86.43,77.76 86.43,80.4 86.68,80.64 89.63,80.64
+V1.05S_AXCK_DCB_L on TOP (solid shape): 90.93,81.86 90.93,81.02 91.22,80.73 91.22,80.71 91.29,80.64 91.29,78.7 91.24,78.65 90.3,78.65 90.05,78.9 90.05,81.88 90.12,81.95 90.84,81.95
+V1.05S_AXCK_LCPLL on TOP (solid shape): 94.71,85.96 94.71,84.49 94.52,84.3 92.24,84.3 92.09,84.15 87.81,84.15 87.56,84.4 87.56,84.91 90.63,84.91 90.64,84.86 90.65,84.8 90.67,84.75 90.7,84.7 90.73,84.66 90.77,84.62 90.82,84.59 90.87,84.56 90.92,84.54 90.97,84.53 91.03,84.53 91.08,84.54 91.14,84.55 91.19,84.57 91.24,84.6 91.28,84.64 91.32,84.68 91.35,84.73 91.37,84.78 91.39,84.83 91.4,84.88 91.4,84.94 91.39,85 91.37,85.05 91.35,85.1 91.32,85.15 91.28,85.19 91.24,85.22 91.19,85.25 91.14,85.27 91.08,85.29 91.03,85.29 90.97,85.29 90.92,85.28 90.87,85.26 90.82,85.24 90.77,85.21 90.73,85.17 90.7,85.12 90.67,85.07 90.65,85.02 90.64,84.97 90.63,84.91 87.56,84.91 87.56,85.89 87.81,86.14 94.53,86.14
+V1.05S_AXCK_LCPLL on BOTTOM (solid shape): 89.75,85.12 89.75,82.17 89.05,81.47 85.06,81.47 85.02,81.49 84.96,81.51 84.61,81.85 84.61,83.43 84.83,83.65 86.83,83.65 87.44,84.26 87.44,85.05 87.71,85.33 89.53,85.33
+V1.05S_AXCK_LCPLL_L on TOP (solid shape): 94.47,84.01 94.47,82.09 93.59,81.21 92.62,81.21 92.42,81.41 92.42,82.89 92.46,82.89 92.47,82.84 92.48,82.78 92.5,82.73 92.53,82.68 92.56,82.64 92.6,82.6 92.64,82.57 92.69,82.54 92.75,82.52 92.8,82.51 92.86,82.51 92.91,82.52 92.97,82.53 93.02,82.55 93.07,82.58 93.11,82.62 93.15,82.66 93.18,82.71 93.2,82.76 93.22,82.81 93.23,82.86 93.23,82.92 93.22,82.98 93.2,83.03 93.18,83.08 93.15,83.13 93.11,83.17 93.07,83.2 93.02,83.23 92.97,83.25 92.91,83.27 92.86,83.27 92.8,83.27 92.75,83.26 92.69,83.24 92.64,83.22 92.6,83.19 92.56,83.15 92.53,83.1 92.5,83.06 92.48,83 92.47,82.95 92.46,82.89 92.42,82.89 92.42,84.05 92.48,84.11 94.36,84.11
+V1.05VS_VCCHSIO on TOP (solid shape): 92.96,77.11 92.96,73.87 93.62,73.22 93.62,72.83 93.49,72.71 91.92,72.71 90.93,73.7 90.93,75.98 92.26,77.32 92.75,77.32
+V1.05VS_VCCHSIO on BOTTOM (solid shape): 91.91,74.49 92.12,74.38 92.32,74.49 92.49,74.49 92.62,74.36 92.62,73.98 92.49,73.85 91.85,73.85 91.73,73.72 91.73,73.34 91.85,73.22 91.85,73.03 91.68,72.85 91.5,72.85 91.26,73.1 91.21,73.1 90.84,73.47 90.84,73.85 91.47,74.49
+V1.05VS_VCCHSIO on IN4 (solid shape): 93.34,77.04 93.34,75.74 93.33,75.71 93.29,75.65 93.23,75.63 92.87,75.29 93.24,74.97 93.28,74.97 93.32,74.95 93.32,74.56 93.27,74.47 93.18,74.46 92.94,74.49 92.75,74.37 92.67,74.16 92.73,73.94 92.73,73.84 92.64,73.78 91.62,73.78 91.47,73.93 91.47,73.93 91.37,74.04 91.37,77.02 91.72,77.38 93,77.38
+V5A_LX on TOP (solid shape): 214.51,27.74 214.51,22.62 214.34,22.44 211.46,22.44 211.04,22.86 211.04,26.54 210.94,26.64 210.94,27.8 211,27.86 214.39,27.86
+V5A_LX on BOTTOM (solid shape): 214.47,25.57 214.47,22.75 214.15,22.43 211.46,22.43 210.99,22.9 210.99,25.51 211.17,25.69 214.35,25.69
+V5A_VIN on TOP (solid shape): 208.98,27.8 208.98,26.68 208.73,26.43 202.04,26.43 201.94,26.53 201.94,27.66 202.11,27.83 207.8,27.83 207.85,27.88 208.89,27.88
+V5AP on BOTTOM (solid shape): 209.7,25.44 209.7,22.48 209.59,22.36 207.64,22.36 206.83,23.18 205.51,23.18 205.51,22.64 205.3,22.64 205.3,23.18 204.72,23.18 204.72,22.64 204.52,22.64 204.52,23.18 203.22,23.18 203.02,23.38 203.02,25.51 203.21,25.7 209.44,25.7
+VCC_CORE on TOP (solid shape): outline of 1884 points within 20.69,58 82.99,77.69
+VCC_CORE on BOTTOM (solid shape): outline of 114 points within 20.01,56.9 52.01,73.36
+VCC_CORE on BOTTOM (solid shape): outline of 2061 points within 61.03,64.81 84.4,78.01
+VCC_CORE on IN1 (solid shape): outline of 175 points within 22.93,56.1 36.5,64.73
+VCC_CORE on IN3 (solid shape): outline of 4211 points within 21.62,53.68 83.17,77.81
+VCC_CORE on IN4 (solid shape): outline of 3364 points within 22.11,53.68 84,77.69
+VCC_CORE on VCC: 15.21,46.95 15.41,47.83 15.58,48.71 18.09,62.95 22.53,62.95 29.64,70.07 30.15,70.07 30.8,70.72 30.8,71.1 34.85,75.15 57.06,75.15 59.6,77.69 83.77,77.69 84.13,77.33 84.13,66.36 83.77,66 63.71,66 63.2,65.49 57.36,65.49 55.58,63.72 52.53,63.72 45.67,56.86 35.26,56.86 29.16,50.76 25.86,50.76 22.04,46.95
DVDD-12-SWR on TOP (solid shape): 122.55,50.41 122.55,49.21 122.04,48.7 122.04,47.52 122.42,47.14 122.42,46.95 122.36,46.89 121.15,46.89 120.99,47.05 120.99,49.33 121,49.34 121,50.39 121.22,50.6 122.36,50.6
DVDD-12-SWR on BOTTOM (solid shape): 122.65,50.29 122.65,49.53 121.53,48.42 118.98,48.42 118.87,48.52 118.87,49.8 119.01,49.94 120.58,49.94 121.23,50.6 122.34,50.6
GND on TOP (solid shape): 51.49,64.22 51.49,63.84 50.86,63.21 44.25,63.21 44,63.46 44,64.1 44.25,64.35 51.37,64.35
GND on TOP (solid shape): 82.25,70.48 82.25,68.5 82.12,68.38 80.9,68.38 80.75,68.53 80.75,70.5 80.83,70.58 82.15,70.58
GND on TOP (solid shape): 161.88,47.18 161.88,46.06 161.63,45.81 157.79,45.81 157.66,45.94 157.66,47.33 157.79,47.46 161.6,47.46
GND on TOP (solid shape): 201.15,64.07 202.19,64.07 202.42,63.84 202.42,62.5 199.14,62.5 199.14,63.69 199.7,64.25 200.97,64.25
GND on TOP (solid shape): 202.7,68.47 202.7,67.3 202.42,67.02 199.68,67.02 199.42,67.27 199.42,68.54 199.47,68.59 202.57,68.59
GND on TOP (solid shape): 207.17,68.95 207.17,65.85 207.07,65.75 206.05,65.75 205.98,65.82 205.98,68.87 206.13,69.02 207.09,69.02
GND on TOP (solid shape): 53.14,70.16 53.14,69.43 53.02,69.3 44.25,69.3 44,69.56 44,70.19 44.13,70.32 50.72,70.32 50.86,70.46 52.84,70.46
GND on TOP (solid shape): 232.99,13.34 232.99,12.16 232.79,11.96 232.14,11.96 232.14,12.47 232.48,12.47 232.48,13.03 232.13,13.03 232.13,13.54 232.79,13.54
GND on TOP (solid shape): 198.61,51.22 198.61,48.16 198.55,48.1 197.59,48.1 197.53,48.17 197.53,49.59 197.57,49.63 197.57,51.3 197.62,51.35 198.48,51.35
GND on TOP (solid shape): 231.69,6.34 232.79,6.34 232.99,6.14 232.99,4.96 232.79,4.76 232.16,4.76 232.16,5.17 231.5,5.83 231.18,5.83 231.18,7.05 231.69,7.05
GND on TOP (solid shape): 61.05,70.38 61.81,70.38 61.94,70.26 61.94,69.49 61.88,69.43 58.51,69.43 58.45,69.49 58.45,70.32 58.51,70.38 59.46,70.38 60.1,71.02 60.41,71.02
GND on TOP (solid shape): 221.24,54.39 220.73,54.39 220.73,54.8 220.61,54.93 220.23,54.93 219.84,55.31 219.84,55.87 220.3,56.32 220.68,56.32 220.73,56.38 220.73,56.86 221.24,56.86
GND on TOP (solid shape): 82.71,78.46 82.71,78.16 82.49,77.94 56.48,77.94 56.35,78.07 56.35,79.08 56.62,79.35 81.82,79.35
GND on TOP (solid shape): 231.69,9.94 232.79,9.94 232.99,9.74 232.99,8.56 232.79,8.36 232.16,8.36 232.16,8.87 232.48,8.87 232.48,9.43 231.12,9.43 230.64,9.92 230.64,11.06 231.69,11.06
GND on TOP (solid shape): 61.94,67.08 61.94,66.26 61.88,66.19 61.43,66.19 61.18,65.94 61.18,65.24 61.05,65.11 60.8,65.11 59.72,66.19 58.57,66.19 58.51,66.26 58.51,67.08 58.57,67.14 61.88,67.14
GND on TOP (solid shape): 157.66,35.9 157.66,34.51 157.54,34.38 156.51,34.38 156.24,34.11 156.24,33.86 155.74,33.36 153.04,33.36 152.56,33.85 152.56,35.16 152.72,35.33 155.37,35.33 156.2,36.16 157.41,36.16
GND on TOP (solid shape): 169.14,80.88 170.06,80.88 170.45,81.26 170.84,81.26 171.1,81.01 171.1,80.21 170.45,79.57 168.77,79.57 168.26,80.07 167.15,80.07 166.8,80.43 166.8,81.24 167.08,81.53 168.49,81.53
GND on TOP (solid shape): 205.21,33.24 205.21,31.66 205.16,31.61 203.38,31.61 203.35,31.57 202.43,31.57 202.37,31.64 202.37,32.27 202.46,32.36 203.5,32.36 203.54,32.4 203.54,33.29 203.56,33.31 205.14,33.31
GND on TOP (solid shape): 61.94,73.37 61.94,72.61 61.81,72.48 60.79,72.48 60.37,72.05 60.14,72.05 59.72,72.48 58.57,72.48 58.45,72.61 58.45,73.38 58.54,73.48 61.83,73.48
GND on TOP (solid shape): 37.4,22.31 37.4,21.55 37.22,21.37 34.55,21.37 34.35,21.32 34.21,21.17 32.82,21.17 32.57,21.42 32.57,22.21 32.82,22.47 37.24,22.47
GND on TOP (solid shape): 51.3,20.53 51.3,20.35 51.62,20.03 52.89,20.03 53.4,19.52 54.9,19.52 55.04,19.39 55.04,18.88 54.91,18.76 51.17,18.76 51,18.92 50.21,18.92 50.1,19.03 50.1,20.53 50.23,20.66 51.16,20.66
GND on TOP (solid shape): 206,63.82 206,62.27 205.93,62.19 205.89,62.19 205.47,62.19 204.27,62.19 203.21,62.19 203.14,62.26 203.14,62.83 203.24,62.93 204.22,62.93 204.32,63.03 204.32,63.89 205.92,63.89
GND on TOP (solid shape): 51.15,67.23 51.25,67.01 51.45,66.9 51.49,66.89 51.49,66.51 51.24,66.26 44.25,66.26 44,66.51 44,67.14 44.13,67.27 51.15,67.27
GND on TOP (solid shape): 203.6,51.22 203.6,51.18 203.6,48.5 203.5,48.4 202.94,48.4 202.87,48.48 202.87,49.52 202.76,49.62 201.9,49.62 201.9,51.22 201.98,51.29 203.53,51.29
GND on TOP (solid shape): 204.76,38.27 204.76,38.04 204.73,38.01 204.73,37.48 205.67,36.54 205.67,35.02 205.63,34.97 204.72,34.97 204.65,35.04 204.65,36.26 203.97,36.94 203.94,36.94 203.94,38.27 204.02,38.34 204.68,38.34
GND on TOP (solid shape): 231.69,3.44 231.69,2.74 232.79,2.74 232.99,2.54 232.99,1 232.85,0.65 232.5,0.51 232.14,0.51 232.14,1.02 232.48,1.02 232.48,1.77 231.18,1.77 231.18,3.45 231.68,3.45
GND on TOP (solid shape): 150.18,44.48 150.22,44.46 150.24,44.42 150.24,43.58 150.23,43.58 150.23,43.28 150.24,43.28 150.24,42.49 150.22,42.46 150.18,42.44 150.03,42.44 149.85,42.27 149.85,41.26 149.78,41.19 149.65,41.19 149.58,41.26 149.58,42.31 149.44,42.44 148.25,42.44 148.22,42.46 148.2,42.49 148.2,44.42 148.22,44.46 148.25,44.48
